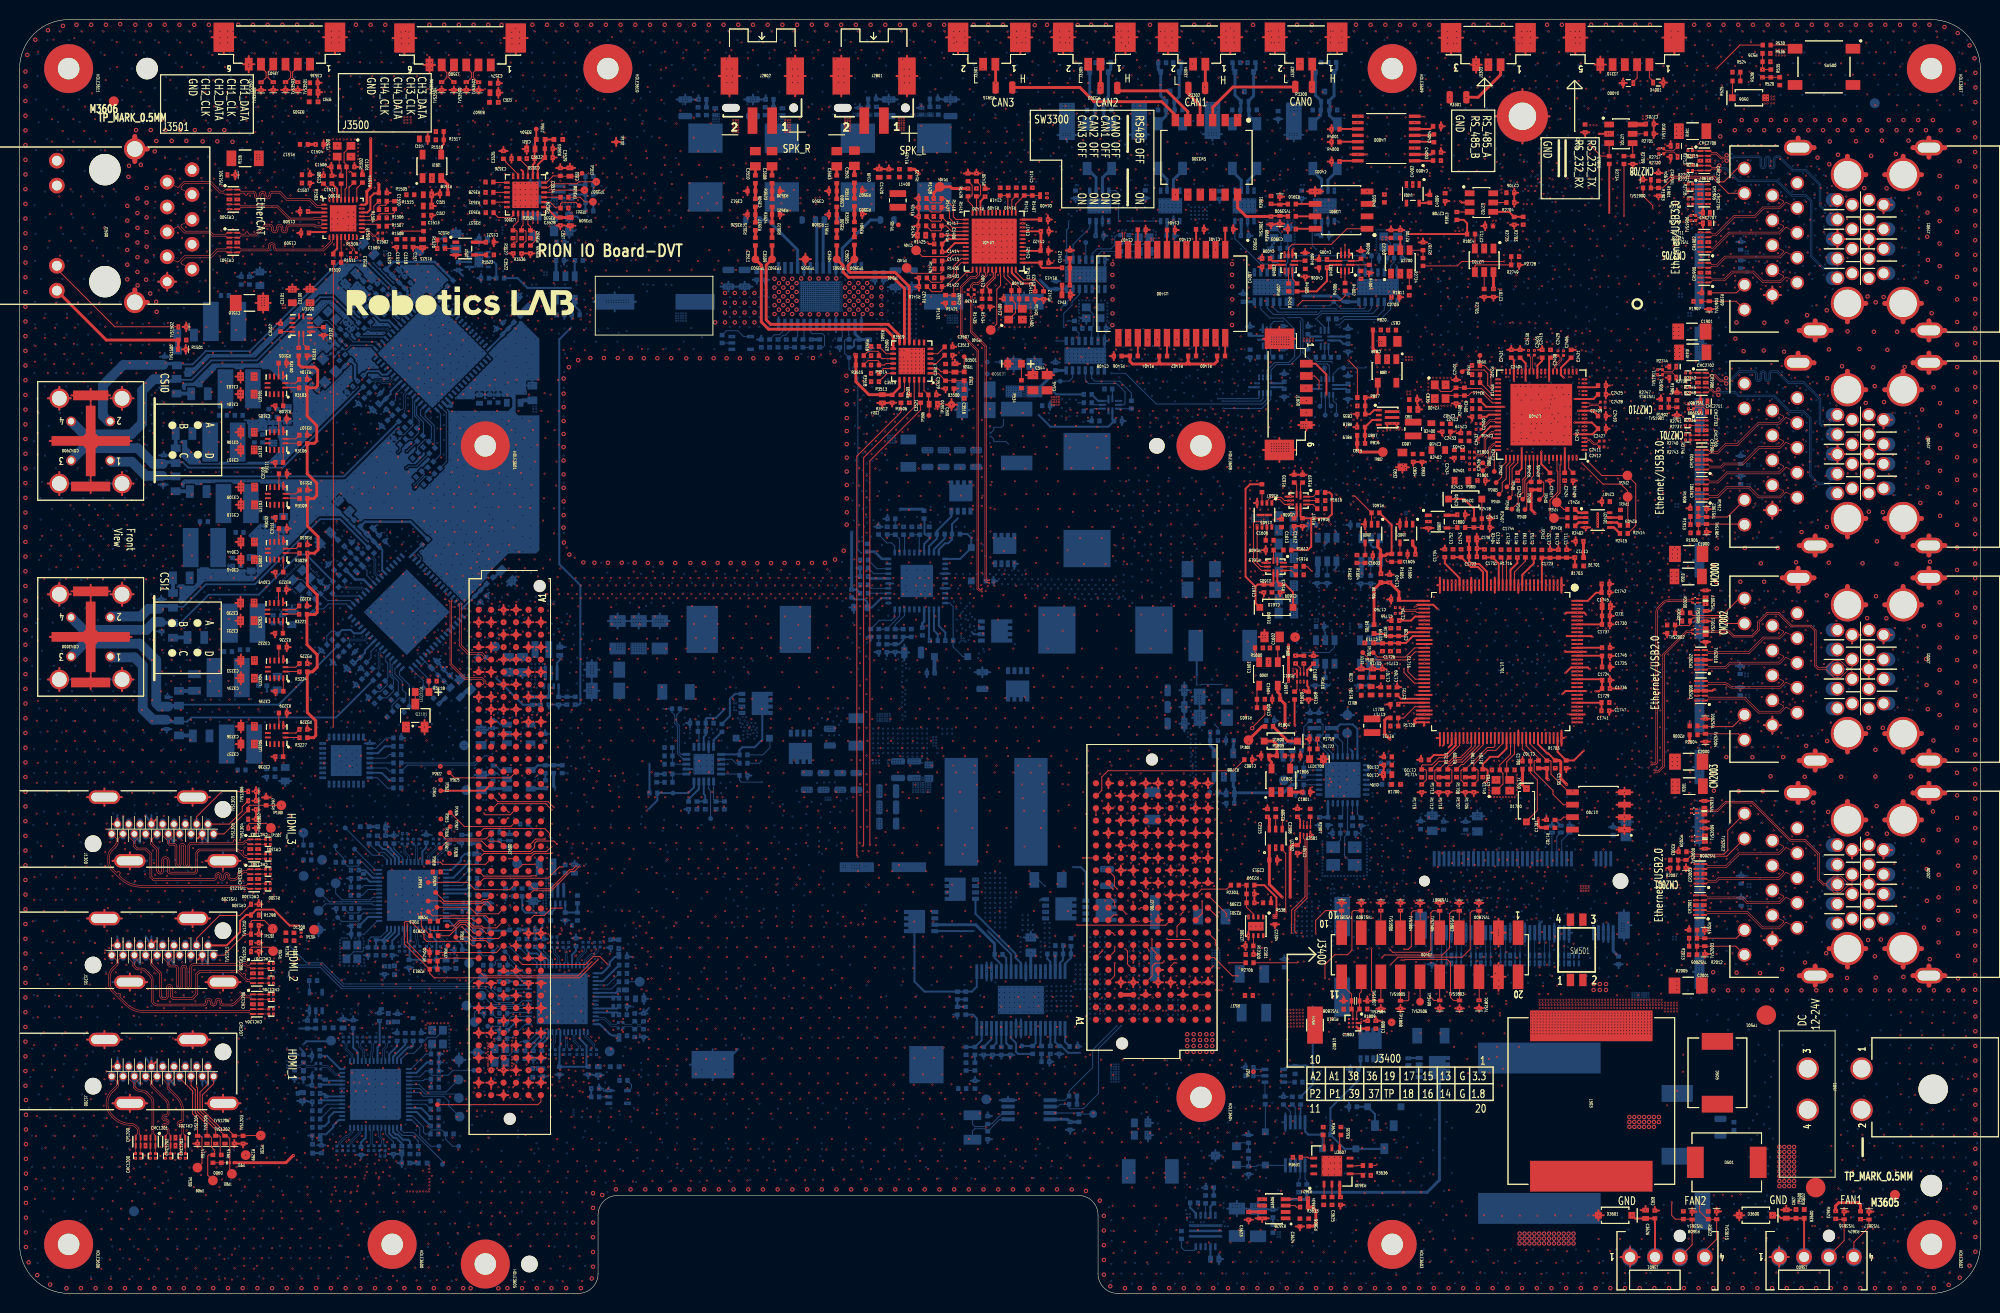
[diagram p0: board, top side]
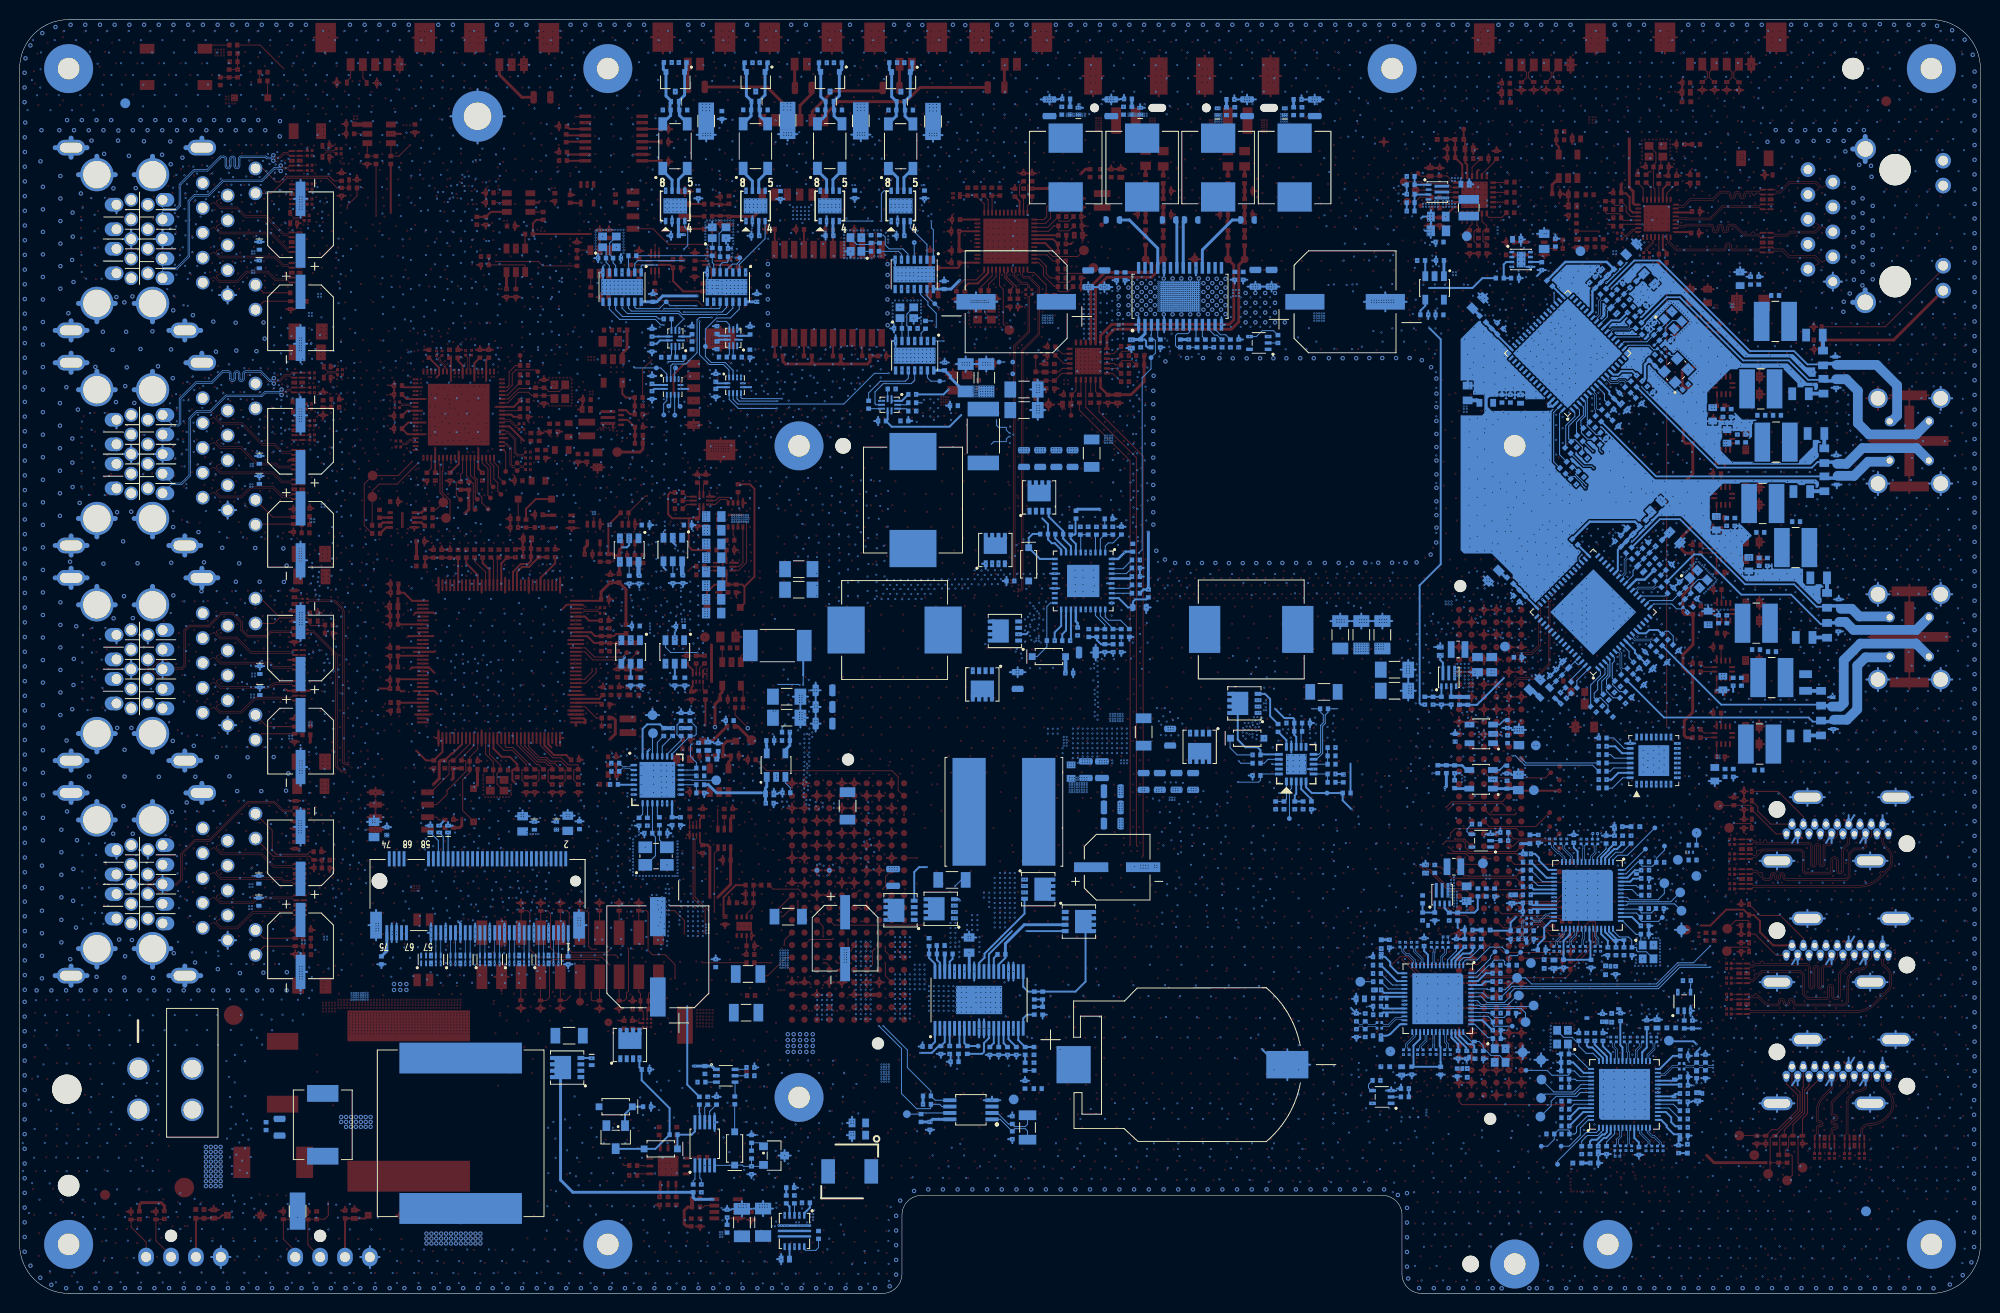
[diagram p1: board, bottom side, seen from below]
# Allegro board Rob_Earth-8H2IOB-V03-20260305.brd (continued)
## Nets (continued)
GND: C501.2 C503.1 C504.1 C505.1 C507.1 C509.1 C510.2 C511.2 C512.2 C513.2 C514.2 C515.2 C516.2 C517.2 C518.1 C519.1 C520.1 C521.1 C522.1 C523.1 C524.2 C525.2 C526.2 C527.2 C528.2 C529.2 C530.2 C531.2 C532.2 C533.2 C534.2 C535.2 C536.2 C537.2 C538.2 C539.2 C540.2 C541.1 C542.1 C543.2 C544.2 C545.2 C546.2 C547.1 C548.2 C549.1 C550.1 C551.1 C608.2 C609.2 C610.2 C611.2 C612.2 C614.2 C616.2 C617.2 C618.2 C619.2 C620.2 C622.2 C623.2 C700.2 C702.2 C703.2 C704.2 C705.2 C706.2 C711.2 C712.2 C713.2 C801.2 C802.2 C803.2 C804.2 C805.1 C806.1 C808.2 C809.2 C810.2 C811.2 C813.2 C814.2 C820.2 C821.2 C822.2 C823.2 C824.2 C825.2 C826.2 C827.2 C828.2 C829.2 C830.2 C831.2 C832.2 C833.2 C834.2 C835.2 C836.2 C837.2 C838.2 C840.2 C902.2 C903.2 C905.2 C906.2 C907.2 C908.2 C909.2 C910.2 C911.2 C912.2 C913.2 C914.2 C915.2 C916.2 C917.2 C918.2 C919.2 C920.2 C921.2 C922.2 C923.2 C924.2 C925.2 C926.2 C927.2 C928.2 C1003.2 C1004.2 C1005.2 C1006.2 C1007.2 C1008.2 C1009.2 C1010.2 C1011.2 C1012.2 C1013.2 C1014.2 C1015.2 C1016.2 C1017.2 C1018.2 C1019.2 C1020.2 C1021.2 C1022.2 C1023.2 C1024.2 C1025.2 C1026.2 C1027.2 C1028.2 C1103.2 C1104.2 C1105.2 C1106.2 C1107.2 C1108.2 C1109.2 C1110.2 C1111.2 C1112.2 C1113.2 C1114.2 C1115.2 C1116.2 C1117.2 C1118.2 C1119.2 C1120.2 C1121.2 C1122.2 C1123.2 C1124.2 C1125.2 C1126.2 C1127.2 C1128.2 C1401.1 C1403.1 C1404.1 C1405.2 C1406.1 C1407.1 C1408.2 C1409.2 C1410.2 C1411.2 C1412.2 C1413.2 C1414.1 C1415.1 C1416.1 C1417.1 C1418.1 C1419.2 C1420.1 C1421.1 C1422.1 C1423.1 C1500.2 C1501.2 C1504.2 C1506.2 C1507.2 C1508.2 C1509.2 C1510.2 C1511.2 C1512.2 C1513.2 C1514.2 C1515.2 C1516.1 C1517.2 C1518.2 C1519.2 C1520.2 C1521.1 C1600.2 C1601.2 C1602.2 C1603.1 C1604.2 C1605.1 C1606.2 C1607.1 C1608.1 C1609.2 C1610.2 C1611.1 C1612.2 C1613.2 C1700.2 C1701.2 C1702.2 C1703.2 C1704.2 C1705.2 C1706.2 C1707.2 C1708.2 C1709.2 C1710.2 C1711.2 C1712.2 C1713.2 C1714.2 C1715.2 C1716.2 C1717.2 C1718.2 C1719.2 C1720.2 C1721.2 C1722.2 C1723.2 C1724.2 C1725.2 C1726.2 C1727.2 C1728.2 C1729.2 C1730.2 C1731.2 C1732.2 C1733.2 C1734.2 C1735.2 C1736.2 C1737.2 C1738.2 C1739.2 C1740.2 C1741.2 C1742.2 C1743.2 C1744.2 C1745.2 C1746.2 C1747.2 C1748.2 C1749.2 C1750.2 C1751.2 C1752.2 C1753.2 C1800.2 C1801.2 C1802.2 C1803.2 C1808.2 C1900.1 C1901.1 C2000.1 C2001.1 C2300.1 C2301.1 C2302.1 C2303.1 C2304.2 C2305.2 C2306.1 C2307.1 C2308.1 C2309.2 C2313.1 C2314.1 C2315.1 C2399.1 C2401.2 C2402.2 C2407.2 C2413.2 C2414.1 C2415.2 C2416.2 C2417.2 C2418.2 C2419.2 C2420.1 C2421.2 C2422.2 C2423.2 C2424.2 C2425.2 C2426.1 C2427.2 C2428.2 C2429.2 C2430.2 C2431.2 C2432.2 C2433.2 C2434.2 C2500.1 C2501.1 C2502.2 C2503.1 C2505.2 C2506.2 C2507.2 C2508.2 C2509.1 C2511.2 C2512.2 C2513.1 C2515.2 C2516.2 C2517.2 C2518.2 C2519.1 C2521.2 C2522.2 C2696.2 C2697.2 C2698.2 C2699.2 C2700.1 C2701.1 C2703.2 C2705.2 C2706.1 C2707.1 C2708.2 C2711.2 C2800.2 C2801.2 C2802.2 C2803.2 C2804.2 C2805.2 C2806.1 C2807.2 C2808.2 C2809.2 C2810.2 C2812.2 C2813.2 C2814.2 C2815.2 C2818.1 C2819.1 C2821.2 C2822.2 C2823.2 C2824.2 C2825.2 C2826.2 C2827.2 C2828.2 C2829.1 C2830.1 C2831.1 C2838.2 C2900.2 C2901.2 C2902.2 C2903.2 C2904.2 C2905.2 C2906.2 C2907.2 C2910.2 C2911.2 C2912.2 C2913.2 C2914.2 C2915.2 C2916.2 C2917.2 C2918.2 C2919.2 C2920.2 C2921.2 C2922.2 C2923.2 C2924.2 C2927.2 C2928.2 C2929.2 C2932.2 C2933.2 C2934.2 C2935.2 C2936.2 C2939.2 C2940.2 C2941.2 C2942.2 C3000.2 C3001.2 C3002.2 C3003.2 C3004.2 C3005.2 C3006.2 C3007.2 C3010.2 C3011.2 C3012.2 C3013.2 C3014.2 C3015.2 C3016.2 C3017.2 C3018.2 C3019.2 C3020.2 C3021.2 C3024.2 C3025.2 C3026.2 C3027.2 C3028.2 C3029.2 C3032.2 C3033.2 C3034.2 C3035.2 C3036.2 C3039.2 C3040.2 C3044.2 C3045.2 C3049.2 C3100.2 C3101.2 C3102.2 C3103.2 C3104.2 C3105.2 C3106.2 C3107.2 C3108.2 C3109.2 C3110.2 C3111.2 C3112.2 C3113.2 C3200.2 C3201.2 C3202.2 C3203.2 C3204.2 C3205.1 C3206.2 C3207.2 C3208.2 C3209.2 C3221.2 C3229.2 C3230.2 C3231.2 C3232.2 C3233.2 C3234.2 C3235.2 C3236.2 C3237.2 C3238.2 C3400.1 C3401.1 C3406.1 C3407.1 C3408.1 C3413.1 C3414.1 C3415.1 C3418.1 C3419.1 C3420.1 C3423.1 C3424.1 C3425.2 C3426.2 C3427.2 C3428.2 C3429.2 C3430.2 C3431.1 C3432.2 C3433.2 C3434.1 C3435.2 C3436.2 C3437.1 C3438.2 C3439.2 C3498.2 C3499.2 C3500.1 C3505.2 C3506.1 C3507.2 C3512.2 C3513.2 C3514.2 C3515.1 C3516.2 C3517.1 C3518.2 C3519.1 C3520.2 C3521.1 C3522.2 C3523.2 C3524.1 C3525.2 C3526.2 C3527.2 C3528.1 C3529.2 C3530.1 C3531.2 C3532.1 C3533.2 C3534.1 C3535.2 C3536.1 C3623.2 C3624.2 C3625.2 C3626.1 C3627.2 C3628.2 C3903.2 C4001.2 C4002.1 C4004.1 C4005.2 C4006.2 C4007.2 C4008.2 C4009.2 CN2300.3 CN2300.9 CN2300.15 CN2300.21 CN2300.27 CN2300.33 CN2300.39 CN2300.45 CN2300.51 CN2300.57 CN2300.71 CN2300.73 CN2300.G1 CN2300.G2 CON2900.5 CON2900.6 CON2900.7 CON2900.8 CON2900.G1 CON2900.G2 CON2900.G3(\G3\) CON3000.5 CON3000.6 CON3000.7 CON3000.8 CON3000.G1 CON3000.G2 CON3000.G3(\G3\) CR1200.3 CR1200.8 CR1201.3 CR1201.8 CR1207.3 CR1207.8 CR1208.3 CR1208.8 CR1300.3 CR1300.8 CR1301.3 CR1301.8 CR1500.3 CR1500.8 CR1501.3 CR1501.8 CR1900.3 CR1900.8 CR1901.3 CR1901.8 CR1902.3 CR1902.8 CR1903.3 CR1903.8 CR1904.3 CR1904.8 CR1905.3 CR1905.8 CR1906.3 CR1906.8 CR1907.3 CR1907.8 CR2000.3 CR2000.8 CR2001.3 CR2001.8 CR2002.3 CR2002.8 CR2003.3 CR2003.8 CR2300.3 CR2300.8 CR2304.3 CR2304.8 CR2305.3 CR2305.8 CR2307.3 CR2307.8 CR2308.3 CR2308.8 CT501.2 CT700.2 CT701.2 CT1900.2 CT1901.2 CT1902.2 CT1903.2 CT2500.2 CT2501.2 CT2502.2 CT2503.2 CT2700.2 CT2701.2 D2800.1 D2801.1 D2802.1 D2803.1 D2900.2 D2901.2 D2902.2 D2903.2 D3000.2 D3001.2 D3002.2 D3003.2 D3600.1 D3601.1 D4000.2 D4001.2 HOLE3600.1(\TP\) HOLE3601.1(\TP\) HOLE3602.1(\TP\) HOLE3603.1(\TP\) HOLE3604.1(\TP\) HOLE3605.1(\TP\) HOLE3606.1(\TP\) HOLE3607.1(\TP\) HOLE3608.1(\TP\) HOLE3609.1(\TP\) HOLE3610.1(\TP\) HOLE3611.1(\TP\) J1200.2 J1200.5 J1200.8 J1200.11 J1200.17 J1200.G1 J1200.G2 J1200.G3 J1200.G4(\G4\) J1201.2 J1201.5 J1201.8 J1201.11 J1201.17 J1201.G1 J1201.G2 J1201.G3 J1201.G4(\G4\) J1300.2 J1300.5 J1300.8 J1300.11 J1300.17 J1300.G1 J1300.G2 J1300.G3 J1300.G4(\G4\) J1500.10 J1600.6 J1600.G1 J1600.G2(\G2\) J1900.10 J1900.U4 J1900.U7 J1900.U13 J1900.U16 J1901.10 J1901.U4 J1901.U7 J1901.U13 J1901.U16 J2000.10 J2000.U4 J2000.U7 J2000.U13 J2000.U16 J2001.10 J2001.U4 J2001.U7 J2001.U13 J2001.U16 J2600.A2 J2600.A4 J2600.A6 J2600.A8 J2600.A10 J2600.A27 J2600.A29 J2600.A31 J2600.A33 J2600.A35 J2600.A37 J2600.A39 J2600.B2 J2600.B4 J2600.B6 J2600.B8 J2600.B10 J2600.B27 J2600.B29 J2600.B31 J2600.B33 J2600.B35 J2600.B37 J2600.B39 J2600.C1 J2600.C3 J2600.C5 J2600.C7 J2600.C9 J2600.C11 J2600.C28 J2600.C30 J2600.C32 J2600.C34 J2600.C36 J2600.C38 J2600.D1 J2600.D3 J2600.D5 J2600.D7 J2600.D9 J2600.D11 J2600.D30 J2600.D32 J2600.D34 J2600.D36 J2600.D38 J2600.D40 J2600.E2 J2600.E4 J2600.E6 J2600.E8 J2600.E9 J2600.E10 J2600.E31 J2600.E33 J2600.E35 J2600.E37 J2600.E39 J2600.F2 J2600.F4 J2600.F6 J2600.F8 J2600.F31 J2600.F33 J2600.F35 J2600.F37 J2600.F39 J2700.B14 J2700.B16 J2700.B18 J2700.B20 J2700.C4 J2700.C13 J2700.C15 J2700.C17 J2700.C19 J2700.D4 J2700.D13 J2700.D15 J2700.D17 J2700.D19 J2700.E3 J2700.E12 J2700.E14 J2700.E16 J2700.E18 J2700.E20 J2700.F4 J2700.F5 J2700.F9 J2700.F12 J2700.F14 J2700.F16 J2700.F18 J2700.F20 J2700.G4 J2700.G11 J2700.G13 J2700.G15 J2700.G17 J2700.G19 J2700.H3 J2700.H11 J2700.H13 J2700.H15 J2700.H17 J2700.H19 J2700.I4 J2700.I12 J2700.I14 J2700.I16 J2700.I18 J2700.I20 J2700.J4 J2700.J12 J2700.J14 J2700.J16 J2700.J18 J2700.J20 J2800.2(-) J2801.G1 J2801.G2(\G2\) J2802.G1 J2802.G2(\G2\) J3301.G1 J3301.G2(\G2\) J3302.G1 J3302.G2(\G2\) J3303.3 J3303.G1 J3303.G2(\G2\) J3304.G1 J3304.G2(\G2\) J3305.G1 J3305.G2(\G2\) J3310.5 J3310.G1 J3310.G2(\G2\) J3400.2 J3400.19 J3500.6 J3500.G1 J3500.G2(\G2\) J3501.6 J3501.G1 J3501.G2(\G2\) J3600.1 J3601.1 LED500.2(\C\) LED1700.2(\C\) NUT2301.1 Q502.1 Q502.2 Q502.3(\S3\) Q503.1 Q503.2 Q503.3(\S3\) Q601.1 Q601.2 Q601.3(\S3\) Q701.1 Q701.2 Q701.3(\S3\) Q703.1 Q703.2 Q703.3(\S3\) Q3101.2(\SOURCE\) R507.1 R510.1 R513.2 R516.2 R530.2 R531.2 R536.2 R543.2 R544.2 R600.2 R608.2 R610.2 R611.2 R612.2 R613.2 R704.2 R709.2 R710.2 R711.2 R712.2 R714.2 R801.2 R802.2 R804.2 R808.2 R810.2 R811.2 R815.2 R818.2 R819.2 R820.2 R911.1 R922.2 R926.2 R927.1 R931.1 R934.1 R1018.2 R1021.2 R1022.1 R1027.1 R1030.1 R1032.1 R1120.2 R1123.2 R1124.1 R1129.1 R1132.1 R1134.1 R1297.2 R1298.2 R1299.2 R1401.2 R1424.1 R1425.1 R1426.1 R1427.1 R1428.1 R1429.1 R1430.2 R1431.2 R1432.2 R1434.2 R1435.2 R1503.1 R1516.1 R1518.2 R1519.1 R1600.2 R1615.2 R1619.2 R1620.2 R1705.2 R1707.2 R1708.2 R1710.2 R1712.2 R1713.2 R1715.2 R1716.2 R1717.2 R1718.2 R1721.2 R1722.1 R1806.2 R1900.1 R1901.1 R1904.1 R1905.1 R1909.1 R1910.2 R1911.2 R1913.1 R2000.1 R2001.1 R2007.1 R2009.1 R2010.2 R2011.2 R2015.1 R2300.1 R2301.1 R2308.1 R2407.2 R2408.2 R2409.2 R2411.2 R2419.2 R2501.2 R2502.2 R2503.2 R2504.2 R2507.2 R2509.2 R2510.2 R2518.2 R2519.2 R2700.2 R2701.2 R2704.2 R2705.2 R2707.2 R2708.1 R2709.2 R2725.2 R2749.2 R2902.1 R2905.1 R2908.1 R2912.2 R2914.1 R2921.1 R2922.1 R3002.1 R3006.1 R3007.1 R3011.1 R3016.1 R3017.1 R3018.2 R3023.1 R3030.1 R3032.1 R3101.1 R3102.1 R3104.1 R3105.1 R3107.1 R3108.1 R3110.1 R3111.1 R3116.1 R3202.2 R3203.2 R3205.1 R3222.1 R3223.1 R3225.1 R3226.1 R3228.1 R3229.1 R3403.2 R3411.2 R3414.2 R3415.1 R3416.2 R3500.1 R3508.2 R3517.1 R3518.1 R3519.1 R3526.2 R3535.1 R3536.1 R3903.2 R4000.1 R4001.1 R4004.2 R4005.2 R4008.2 R4009.2 RT2300.2 RT2400.2 TP907.1(\TP\) TP1006.1(\TP\) TP1107.1(\TP\) TP2500.1(\TP\) TP2702.1(\TP\) TP3505.1(\TP\) TP3510.1(\TP\) TVS1202.1 TVS1203.1 TVS1204.1 TVS1205.1 TVS1206.1 TVS1209.1 TVS1210.1 TVS1211.1 TVS1212.1 TVS1213.1 TVS1302.1 TVS1303.1 TVS1304.1 TVS1305.1 TVS1306.1 TVS1500.1 TVS1501.1 TVS1502.1 TVS1800.1 TVS1801.1 TVS1802.1 TVS1803.1 TVS1804.1 TVS1805.1 TVS1806.1 TVS1807.2 TVS1808.2 TVS1809.1 TVS1810.1 TVS1900.1 TVS1901.1 TVS1902.1 TVS1903.1 TVS1904.1 TVS1906.2 TVS1907.2 TVS1908.2 TVS1909.2 TVS1910.2 TVS1911.2 TVS1912.2 TVS1913.2 TVS1914.1 TVS1915.1 TVS1916.1 TVS1917.1 TVS2000.1 TVS2001.1 TVS2002.1 TVS2003.1 TVS2004.1 TVS2005.1 TVS2006.2 TVS2007.2 TVS2008.2 TVS2009.2 TVS2010.2 TVS2011.2 TVS2012.2 TVS2013.2 TVS2301.2 TVS2302.2 TVS2303.2 TVS2306.1 TVS2309.1 TVS2500.1 TVS2501.1 TVS2502.1 TVS2503.1 TVS2504.1 TVS2505.1 TVS2506.1 TVS2507.1 TVS3500.1 TVS3501.1 TVS3502.1 TVS3503.1 TVS3504.1 TVS3505.1 TVS3506.1 TVS3507.1 TVS3614.1 TVS3615.1 TVS3616.1 TVS3617.1 TVS3900.1 TVS3901.1 U500.14 U500.17 U500.35 U500.41 U501.6 U504.2 U506.3 U600.7 U600.14 U600.21 U700.10 U700.11(\SYNC\) U700.17 U700.22 U700.23 U700.30 U700.39 U800.2 U800.6 U802.5 U804.2 U805.2 U806.5 U807.5 U808.2 U900.57 U902.3 U1000.57 U1001.3 U1100.57 U1101.3 U1401.49 U1500.33 U1501.2 U1502.3 U1600.2 U1601.3 U1602.3 U1603.4 U1603.9 U1604.4 U1605.3 U1606.3 U1700.1 U1700.2 U1700.3 U1700.4 U1701.1 U1701.12 U1701.18 U1701.24 U1701.32 U1701.34 U1701.40 U1701.43 U1701.44 U1701.57 U1701.61 U1701.62 U1701.68 U1701.85 U1701.89 U1701.96 U1701.99 U1701.105 U1701.111 U1701.115 U1701.119 U1701.125 U1800.3 U1801.2 U1802.A2 U2300.5 U2300.9 U2301.4 U2302.2 U2400.77 U2401.4 U2401.9 U2500.2 U2501.2 U2502.2 U2503.29 U2504.2 U2505.2 U2700.2 U2701.2 U2702.2 U2703.2 U2800.1 U2800.5 U2800.14 U2800.19 U2800.24 U2800.29 U2803.4 U2805.3 U2900.65 U3000.65 U3002.3 U3100.3 U3101.3 U3102.3 U3103.3 U3104.25 U3104.33 U3200.5 U3201.5 U3201.9 U3202.2 U3203.3 U3204.3 U3205.3 U3400.2 U3400.9(\VSS_EP\) U3402.2 U3402.9(\VSS_EP\) U3404.2 U3404.9(\VSS_EP\) U3405.2 U3405.9(\VSS_EP\) U3406.3 U3407.7 U3407.15 U3408.3 U3409.7 U3409.15 U3410.3 U3411.7 U3411.15 U3412.7 U3413.7 U3413.15 U3414.7 U3500.4 U3500.25 U3501.4 U3501.25 U3606.8 U3607.13 U3901.5 U4000.15 U4001.3 U4002.3 U4003.3 Y900.2 Y900.4(\GND2\) Y1000.2 Y1000.4(\GND2\) Y1100.2 Y1100.4(\GND2\) Y1400.2 Y1400.4(\GND2\) Y1500.2 Y1500.4(\GND2\) Y1700.2 Y1700.4(\GND2\) Y2300.2 Y2300.4(\GND2\) Y2400.2 Y2400.4(\GND2\) Y2500.2 Y2500.4(\GND2\) Y2900.2 Y2900.4(\GND2\) Y2901.2 Y3000.2 Y3000.4(\GND2\) Y3400.2 Y3400.4(\GND2\) Y3401.2 Y3401.4(\GND2\) Y3402.2 Y3402.4(\GND2\)
GND_EARTH: C1900.2 C1901.2 C2000.2 C2001.2 J1900.G1 J1900.G2 J1900.G3 J1900.G4 J1900.G5 J1900.G6 J1900.G7 J1900.G8 J1901.G1 J1901.G2 J1901.G3 J1901.G4 J1901.G5 J1901.G6 J1901.G7 J1901.G8 J2000.G1 J2000.G2 J2000.G3 J2000.G4 J2000.G5 J2000.G6 J2000.G7 J2000.G8 J2001.G1 J2001.G2 J2001.G3 J2001.G4 J2001.G5 J2001.G6 J2001.G7 J2001.G8 R1910.1 R1911.1 R2010.1 R2011.1
GND_EARTH1: C3404.2 C3405.2 C3406.2 C3411.2 C3412.2 C3413.2 C3416.2 C3417.2 C3418.2 C3421.2 C3422.2 C3423.2 D3400.3 D3401.3 D3402.3 D3403.3 R3403.1
GND_EARTH2: C1516.2 J1500.G1 J1500.G2 R1516.2
GND_TOP: J2700.A2 J2700.B2 J2700.C2 J2700.D2 J2700.E2 J2700.F2 J2700.G2 J2700.H2 J2700.I2 J2700.J2 R514.2
VBUSDET: R2410.2 R2411.1 U2400.43
VCC_+6V7_GMSL_1: C2900.1 C2901.1 C2902.1 C3101.1 L2900.2 R2901.1 U3100.8 U3100.9 U3100.10
VCC_+6V7_GMSL_2: C2919.1 C2920.1 C2921.1 C3104.1 L2902.2 R2904.1 U3101.8 U3101.9 U3101.10
VCC_+6V7_GMSL_3: C2927.1 C2928.1 C2929.1 C3107.1 L2904.2 R2907.1 U3102.8 U3102.9 U3102.10
VCC_+6V7_GMSL_4: C2932.1 C2933.1 C2936.1 C3110.1 L2906.2 R2910.1 U3103.8 U3103.9 U3103.10
VCC_+6V7_GMSL_5: C3000.1 C3001.1 C3002.1 C3045.1 L3000.2 R3001.1 U3002.8 U3002.9 U3002.10
VCC_+6V7_GMSL_6: C3013.1 C3014.1 C3021.1 C3231.1 L3002.2 R3004.1 U3203.8 U3203.9 U3203.10
VCC_+6V7_GMSL_7: C3027.1 C3028.1 C3029.1 C3234.1 L3004.2 R3010.1 U3204.8 U3204.9 U3204.10
VCC_+6V7_GMSL_8: C3034.1 C3035.1 C3036.1 C3237.1 L3006.2 R3020.1 U3205.8 U3205.9 U3205.10
VCC_CAM_GMSL1_EN: R3101.2 U3100.2 U3104.1
VCC_CAM_GMSL1_FLAG: R3100.1 U3100.1 U3104.9
VCC_CAM_GMSL2_EN: R3104.2 U3101.2 U3104.2
VCC_CAM_GMSL2_FLAG: R3103.1 U3101.1 U3104.10
VCC_CAM_GMSL3_EN: R3107.2 U3102.2 U3104.3
VCC_CAM_GMSL3_FLAG: R3106.1 U3102.1 U3104.11
VCC_CAM_GMSL4_EN: R3110.2 U3103.2 U3104.4
VCC_CAM_GMSL4_FLAG: R3109.1 U3103.1 U3104.12
VCC_CAM_GMSL5_EN: R3030.2 U3002.2 U3104.5
VCC_CAM_GMSL5_FLAG: R3029.1 U3002.1 U3104.13
VCC_CAM_GMSL6_EN: R3222.2 U3104.6 U3203.2
VCC_CAM_GMSL6_FLAG: R3221.1 U3104.14 U3203.1
VCC_CAM_GMSL7_EN: R3225.2 U3104.7 U3204.2
VCC_CAM_GMSL7_FLAG: R3224.1 U3104.15 U3204.1
VCC_CAM_GMSL8_EN: R3228.2 U3104.8 U3205.2
VCC_CAM_GMSL8_FLAG: R3227.1 U3104.16 U3205.1
VDD10: C1506.1 C1507.1 C1508.1 C1509.1 C1510.1 C1511.1 R1512.2 U1500.3 U1500.8 U1500.22 U1500.30
VDD33: C1517.1 C1518.1 C1519.1 C1520.1 R1509.1 R1520.2 U1500.11 U1500.32
VDD33_USB: B2500.1 C2506.1 C2512.1 R2512.1 R2513.1 R2514.1 R2515.1 R2516.1 R2517.1 U2503.21 U2503.28
VDDREG_VDD33: C1512.1 C1513.1 C1515.1 R1501.2 R1515.2 R1520.1 U1500.23(\VDDREG_DVDD33\) U1501.1(\VOUT\)
VIN+: D501.2 J501.3 J501.4 L500.1 TP500.1(\TP\)
VIN-: D505.1 J501.1 J501.2(\COM#2\) L503.1 TP501.1(\TP\)
VIN_HOLD_A: R501.2 R2706.2
VIN_HOLD_A_1P8: J2600.C21 R2706.1
VIN_HOLD_B: R500.1 TP502.1(\TP\) U504.5
VIN_HV: C500.1 C502.1 D500.2 D506.1 L500.2 Q505.5 Q505.6 Q505.7 Q505.8 R519.1 R520.1 R521.1 R522.1 SW500.3 SW500.4 SW501.1 SW501.2
VIN_P5V: C533.1 C534.1 C535.1 C536.1 Q501.5 Q501.6 Q501.7 Q501.8 R518.1
VIN_SUB_9TO30V: F500.2 R517.1 R518.2 R609.1 R700.1
3P3_PER_COMP1: C519.2 R512.1 U500.29
3P3_PER_COMP2: C549.2 R540.1 U500.2
3P3_PER_FB2: R508.2 U500.3
3P3_PER_SS1: C520.2 U500.30
3P3_PER_SS2: C550.2 U500.1
5P0_FB1: R507.2 R542.2 U500.28
5P0_PWM1_L: Q502.4 U500.18 U500.19
7P0_POC_BST: C613.2 D600.2(\C\) U600.18
7P0_POC_COMP: C623.1 R614.1 U600.6
7P0_POC_CS: C621.1 JP600.2 U600.10
7P0_POC_ENBK: R602.2 R608.1 U600.12
7P0_POC_FB: C615.1 R607.2 R612.1 U600.8
7P0_POC_FOSC: R613.1 U600.4
7P0_POC_FSYNC: R604.2 R611.1 U600.3
7P0_POC_OUT: C621.2 JP601.2 U600.9
7P0_POC_SPS: R603.2 R610.1 U600.1
8211_1_AVCC_+1V: C1421.2 C1422.2 C1423.2 R1433.2 U1401.4 U1401.9 U1401.47
8211_1_AVCC_+3V3: C1416.2 C1417.2 R1413.2 U1401.1 U1401.12
8211_1_DVCC_+1V: C1418.2 R1423.2 U1401.22
8211_1_DVDDRG: C1405.1 C1406.2 R1403.1 R1409.1 R1414.2 R1415.2 R1417.1 R1418.1 R1419.1 R1420.1 TP1404.1(\TP\) U1401.29
8211_1_LED0_PHYAD0: R1416.1 R1426.2 U1401.35
8211_1_LED1_CFGL0: R1422.2 R1432.1 U1401.36
8211_1_LED2_CFGL1: R1421.2 R1431.1 U1401.37
8211_1_REGOUT: L1400.1 TP1403.1(\TP\) U1401.32
8211_1_RST_N: C1410.1 Q1400.3 R1407.2 U1401.13
8211_1_RXC_PHYAD1: R1415.1 R1425.2 U1401.28
8211_1_RXCTL_PHYAD2: R1414.1 R1424.2 U1401.27
8211_1_RXD0_RXDLY: R1417.2 R1427.2 U1401.26
8211_1_RXD1_CFG_MODE0: R1418.2 R1428.2 U1401.25
8211_1_RXD2_CFG_MODE1: R1419.2 R1429.2 U1401.24
8211_1_RXD3_CFG_MODE2: R1420.2 R1430.1 U1401.23
8211_1_SGMII_CLK_M: R1434.1 R1436.1 U1401.43
8211_1_SGMII_CLK_P: R1435.1 R1436.2 U1401.42
8211_DVCC_+3V3: C1413.1 C1414.2 C1415.2 R1407.1 R1412.2 R1416.2 R1421.1 R1422.1 U1401.30 U1401.31
8211_TRXN0: U1400.3 U1401.3
8211_TRXN1: U1400.6 U1401.6
8211_TRXN2: U1400.9 U1401.8
8211_TRXN3: U1400.12(\TD4-\) U1401.11
8211_TRXP0: U1400.2 U1401.2
8211_TRXP1: U1400.5 U1401.5
8211_TRXP2: U1400.8 U1401.7
8211_TRXP3: U1400.11 U1401.10
8211_XTAL_IN: C1409.1 R1408.2 U1401.45 Y1400.1
8211_XTAL_OUT: C1411.1 R1408.1 U1401.46(\XTAL_OUT/EXT_CLK\) Y1400.3
AMP_FAULT_1P8: J2700.B5 R2818.1 TP2800.1(\TP\) U2800.3
AMP_I2C_SCL_1P8: J2600.B18 R2809.1 R2817.2 R3514.1
AMP_I2C_SDA_1P8: J2600.B19 R2806.1 R2816.2 R3513.1
AMP_I2S_LPCLK_1P8: J2600.F26 R2810.1
AMP_I2S_SCLK_1P8: J2600.F27 R2811.1
AMP_I2S_SDIN_1P8: J2600.F29 R2812.1 R2813.1
AMP_I2S_SDOUT_1P8: J2600.F28 R2800.1 R2812.2 U2800.9
AMP_PA_PDN: J2600.C22 R2820.1 U2805.2
CAN0_H: J3302.1 R3300.2 R3401.2
CAN0_H_R: R3300.1 SW3300.3
CAN0_L: J3302.2 R3402.2 SW3300.10
CAN1_H: J3304.1 R3302.2 R3404.2
CAN1_H_R: R3302.1 SW3300.4
CAN1_L: J3304.2 R3405.2 SW3300.9
CAN2_H: J3305.1 R3303.2 R3406.2
CAN2_H_R: R3303.1 SW3300.5
CAN2_L: J3305.2 R3407.2 SW3300.8
CAN3_H: J3301.1 R3408.2 R3915.2
CAN3_H_R: R3915.1 SW3300.6
CAN3_L: J3301.2 R3409.2 SW3300.7(\B6\)
CAN_INT0_1P8: J2600.E22 TP2619.1(\TP\) U3412.3
CAN_INT1_1P8: J2600.E16 TP2613.1(\TP\) U3412.4
CAN_INT2_1P8: J2600.E23 TP2620.1(\TP\) U3412.5
CAN_INT3_1P8: J2600.E17 TP2614.1(\TP\) U3412.6
CAN_INT_0: TP3403.1(\TP\) U3407.4 U3412.12
CAN_INT_1: TP3402.1(\TP\) U3409.4 U3412.11
CAN_INT_2: TP3401.1(\TP\) U3411.4 U3412.10
CAN_INT_3: TP3400.1(\TP\) U3412.9 U3413.4
CAN_MCLK1: R3412.1 R3498.1 U3409.6
CAN_MCLK2: R2302.1 R3496.1 U3413.6
CAN_MCLKO: R3412.2 U3407.3
CAN_SPI1_CLK: R3425.2 U3407.10 U3409.10
CAN_SPI1_CLK_1P8: J2700.D8 R3417.1
CAN_SPI1_CS0: TP3407.1(\TP\) U3407.13 U3414.12
CAN_SPI1_CS0_1P8: J2700.D9 U3414.3
CAN_SPI1_CS1: TP3406.1(\TP\) U3409.13 U3414.11
CAN_SPI1_CS1_1P8: J2600.B14 U3414.4
CAN_SPI1_MISO: U3407.12 U3409.12 U3410.5
CAN_SPI1_MISO_1P8: J2700.D6 R3421.1
CAN_SPI1_MOSI: U3406.4 U3407.11 U3409.11
CAN_SPI1_MOSI_1P8: J2700.D7 R3418.1
CAN_SPI2_CLK: R3426.2 U3411.10 U3413.10
CAN_SPI2_CLK_1P8: J2600.F30 R3419.1
CAN_SPI2_CS0: TP3405.1(\TP\) U3411.13 U3414.10
CAN_SPI2_CS0_1P8: J2700.B12 U3414.5
CAN_SPI2_CS1: TP3404.1(\TP\) U3413.13 U3414.9
CAN_SPI2_CS1_1P8: J2700.B13 U3414.6
CAN_SPI2_MISO: U3410.4 U3411.12 U3413.12
CAN_SPI2_MISO_1P8: J2600.B26 R3422.1
CAN_SPI2_MOSI: U3408.4 U3411.11 U3413.11
CAN_SPI2_MOSI_1P8: J2600.F25 R3420.1
CAN_STB_0: U3400.8 U3407.9
CAN_STB_1: U3402.8 U3409.9
CAN_STB_2: U3404.8 U3411.9
CAN_STB_3: U3405.8 U3413.9
CH334_XI: C2517.1 U2503.10 Y2500.1
CH334_XO: R2505.2 U2503.11(\XO\)
CHANNEL1_INM: J3501.3 R3528.2 TVS3503.2
CHANNEL1_INP: J3501.2 TVS3501.2 U3501.6
CHANNEL2_INM: J3501.5 R3531.2 TVS3507.2
CHANNEL2_INP: J3501.4 TVS3505.2 U3501.8
CHANNEL3_INM: J3500.3 R3533.2 TVS3502.2
CHANNEL3_INP: J3500.2 TVS3500.2 U3501.10
CHANNEL4_INM: J3500.5 R3537.2 TVS3506.2
CHANNEL4_INP: J3500.4 TVS3504.2 U3501.12
CHANNEL7_INM: C3504.2 TP3501.1(\TP\) U3500.11
CHANNEL7_INP: C3502.2 TP3500.1(\TP\) U3500.10
CHANNEL8_INM: C3511.2 TP3503.1(\TP\) U3500.13
CHANNEL8_INP: C3509.2 TP3502.1(\TP\) U3500.12
CLKREQ: R1509.2 R1510.2 U1500.12
CSI0_A0_CLK_M: J2600.D10 U2900.45
CSI0_A1_LN1_P: J2600.C6 U2900.40
CSI0_A2_LN2_M: J2600.D4 U2900.43
CSI0_B0_LN0_P: J2600.C8 U2900.36
CSI0_B1_LN1_M: J2600.D6 U2900.41
CSI0_B2_LN3_P: J2600.C2 U2900.46
CSI0_C0_LN0_M: J2600.D8 U2900.37
CSI0_C1_LN2_P: J2600.C4 U2900.42
CSI0_C2_LN3_M: J2600.D2 U2900.47
CSI0_NC_CLK_P: J2600.C10 U2900.44
CSI1_A0_CLK_M: J2600.B9 U3000.45
CSI1_A1_LN1_P: J2600.A5 U3000.40
CSI1_A2_LN2_M: J2600.B3 U3000.43
CSI1_B0_LN0_P: J2600.A7 U3000.36
CSI1_B1_LN1_M: J2600.B5 U3000.41
CSI1_B2_LN3_P: J2600.A1 U3000.46
CSI1_C0_LN0_M: J2600.B7 U3000.37
CSI1_C1_LN2_P: J2600.A3 U3000.42
CSI1_C2_LN3_M: J2600.B1 U3000.47
CSI1_NC_CLK_P: J2600.A9 U3000.44
DES0_CAP_VDD_1P0: C2916.1 C2917.1 C2918.1 U2900.9 U2900.23
DES0_CCI_SCL_1P8: J2700.A18 R2913.1 R2931.1
DES0_CCI_SDA_1P8: J2700.A17 R2911.1 R2918.1
DES0_CFG0_1P8: R2917.1 R2922.2 U2900.5
DES0_CFG1_1P8: R2916.1 R2921.2 U2900.12
DES0_ENABLE_1P8: J2700.A6 U2900.35
DES0_ERRB_1P8: J2600.D22 R2927.2
DES0_FRAME_SYNC_1P8: J2600.D23 R2928.2
DES0_I2CSEL_1P8: R2929.1 U2900.33
DES0_LOCK_1P8: J2600.D21 R2926.2
DES0_SIOA: C2908.2 CON2900.2 D2900.1 R2900.2
DES0_SIOA_M: C2909.1 U2900.25
DES0_SIOA_P: C2908.1 U2900.26
DES0_SIOB: C2925.2 CON2900.4 D2901.1 R2903.2
DES0_SIOB_M: C2926.1 U2900.22
DES0_SIOB_P: C2925.1 U2900.21
DES0_SIOC: C2930.2 CON2900.3 D2902.1 R2906.2
DES0_SIOC_M: C2931.1 U2900.10
DES0_SIOC_P: C2930.1 U2900.11
DES0_SIOD: C2937.2 CON2900.1 D2903.1 R2909.2
DES0_SIOD_M: C2938.1 U2900.7
DES0_SIOD_P: C2937.1 U2900.6
DES0_SPARE_GPIO_1P8: J2600.D24 R2930.2
DES0_VDDIO_1P8: B2901.1 C2910.1 C2911.1 C2934.1 C2935.1 C2942.1 R2916.2 R2917.2 R2918.2 R2923.2 R2925.2 R2929.2 R2931.2 R2932.1 U2900.27 Y2901.4(\VDD\)
DES0_X1: R2919.1 R2920.2 R2924.2 U2900.17
DES0_X2: C2940.1 R2915.1 U2900.18 Y2900.1
DES1_CAP_VDD_1P0: C3018.1 C3019.1 C3020.1 U3000.9 U3000.23
DES1_CFG0_1P8: R3013.1 R3016.2 U3000.5
DES1_CFG1_1P8: R3012.1 R3017.2 U3000.12
DES1_CLK_25MHZ_1P8: R2919.2 R3005.2 R3007.2 U3000.17
DES1_ENABLE_1P8: J2600.D20 U3000.35
DES1_ERRB_1P8: J2600.D17 R3027.2
DES1_FRAME_SYNC_1P8: J2600.D19 R3028.2
DES1_I2C_SCL_1P8: J2600.C40 R3021.2 R3031.1
DES1_I2C_SDA_1P8: J2600.C39 R3014.1 R3019.2
DES1_I2CSEL_1P8: R3008.1 U3000.33
DES1_LOCK_1P8: J2600.D16 R3026.2
DES1_SIOA: C3008.2 CON3000.2 D3000.1 R3000.2
DES1_SIOA_M: C3009.1 U3000.25
DES1_SIOA_P: C3008.1 U3000.26
DES1_SIOB: C3022.2 CON3000.4 D3001.1 R3003.2
DES1_SIOB_M: C3023.1 U3000.22
DES1_SIOB_P: C3022.1 U3000.21
DES1_SIOC: C3030.2 CON3000.3 D3002.1 R3009.2
DES1_SIOC_M: C3031.1 U3000.10
DES1_SIOC_P: C3030.1 U3000.11
DES1_SIOD: C3037.2 CON3000.1 D3003.1 R3022.2
DES1_SIOD_M: C3038.1 U3000.7
DES1_SIOD_P: C3037.1 U3000.6
DES1_SPARE_GPIO_1P8: J2600.D18 R3033.2
DES1_VDDIO_1P8: B3002.1 C3016.1 C3017.1 C3040.1 R3008.2 R3012.2 R3013.2 R3014.2 R3024.2 R3025.2 R3031.2 U3000.27
DES1_X2: C3032.1 R3015.1 U3000.18 Y3000.1
DES_EN_1P8: J2600.E15 R3200.1 R3204.1 TP2612.1(\TP\)
DISAUTOLOAD/GPO45: R1708.1 U1701.76
EDP1_AUX_M: C900.1 J2600.E32 R931.2 R933.1
EDP1_AUX_P: C901.1 J2600.F32 R932.1 R934.2
EDP1_HPD_1P8: J2600.C17 R925.2 U902.4(\Y\)
EDP1_HPD_3P3: R910.2 R911.2 U900.22
EDP1_LN0_M: J2600.E40 R904.1
EDP1_LN0_P: J2600.F40 R902.1
EDP1_LN1_M: J2600.E38 R909.1
EDP1_LN1_P: J2600.F38 R907.1
EDP1_LN2_M: J2600.E36 R916.1
EDP1_LN2_P: J2600.F36 R912.1
EDP1_LN3_M: J2600.E34 R921.1
EDP1_LN3_P: J2600.F34 R919.1
EDP2_AUX_M: C1000.1 J2600.A34 R1030.2 R1031.1
EDP2_AUX_P: C1001.1 J2600.B34 R1029.1 R1032.2
EDP2_HPD_1P8: J2600.C15 R1028.2 U1001.4(\Y\)
EDP2_HPD_3P3: R1026.2 R1027.2 U1000.22
EDP2_LN0_M: J2600.A38 R1003.1
EDP2_LN0_P: J2600.B38 R1002.1
EDP2_LN1_M: J2600.C37 R1009.1
EDP2_LN1_P: J2600.D37 R1007.1
EDP2_LN2_M: J2600.A36 R1012.1
EDP2_LN2_P: J2600.B36 R1010.1
EDP2_LN3_M: J2600.C35 R1017.1
EDP2_LN3_P: J2600.D35 R1015.1
EDP3_AUX_M: C1100.1 J2600.A28 R1132.2 R1133.1
EDP3_AUX_P: C1101.1 J2600.B28 R1131.1 R1134.2
EDP3_HPD_1P8: J2600.C16 R1130.2 U1101.4(\Y\)
EDP3_HPD_3P3: R1128.2 R1129.2 U1100.22
EDP3_LN0_M: J2600.A32 R1104.1
EDP3_LN0_P: J2600.B32 R1102.1
EDP3_LN1_M: J2600.C33 R1109.1
EDP3_LN1_P: J2600.D33 R1106.1
EDP3_LN2_M: J2600.A30 R1112.1
EDP3_LN2_P: J2600.B30 R1110.1
EDP3_LN3_M: J2600.C31 R1119.1
EDP3_LN3_P: J2600.D31 R1117.1
EDP_HDMI_PON: C814.1 R806.2 R896.2 U802.1
EDP_PWR_EN: J2700.D5 R806.1 R821.1
EN_PWRLIGHT/GPO42: R1713.1 U1701.73
EN_VREG_3P3: R533.2 R538.2 U500.40
EN_VREG_5P0: R539.1 U500.31
ENSWR: R1720.2 R1721.1 U1701.60
ETHCAT_WAKE_N: R1504.1 R1523.1 U1500.21 U1502.2
EXPANDER_INT_N_1P8: J2700.A14 R3114.1
EXT_ADC1: J2600.D27 J3400.9 TVS1809.2
EXT_ADC2: J2700.C10 J3400.10 TVS1810.2
EXT_PWM1: J3400.12 R1809.1 TVS1807.1 U1802.A1
EXT_PWM2: J3400.11 R1810.1 TVS1808.1 U1802.B1
EXTPWRON: TP2407.1(\TP\) U2400.63
FAN_ALERT_1P8_N: J2600.C24 R3631.2 U3607.10
FAN_I2C_CLK1_3V3: R3628.2 R3633.1 U3606.3
FAN_I2C_DAT1_3V3: R3627.2 R3634.1 U3606.4
FAN_PWM1: J3600.4 R3624.2 R3636.2 TVS3617.2
FAN_PWM2: J3601.4 R3622.2 R3635.2 TVS3615.2
FAN_PWR_SW: B3600.1 B3602.1 C3626.2 C3627.1 C3628.1 D3600.2(\C\) D3601.2(\C\) J3600.2 J3601.2
FAN_TACH1: J3600.3 R3623.2 TVS3616.2 U3607.6
FAN_TACH2: J3601.3 R3608.2 TVS3614.2 U3607.8
FPGA_DES0_ERRB_1P8: R2925.1 R2927.1 U2900.4
FPGA_DES0_FRAME_SYNC_1P8: R2928.1 U2900.3
FPGA_DES0_LOCK_1P8: R2923.1 R2926.1 U2900.2
FPGA_DES0_SPARE_GPIO_1P8: R2930.1 U2900.1
FPGA_DES1_ERRB_1P8: R3025.1 R3027.1 U3000.4
FPGA_DES1_FRAME_SYNC_1P8: R3028.1 U3000.3
FPGA_DES1_LOCK_1P8: R3024.1 R3026.1 U3000.2
FPGA_DES1_SPARE_GPIO_1P8: R3033.1 U3000.1
GPIO0: TP2402.1(\TP\) U2400.57
GPIO1: TP2403.1(\TP\) U2400.58
GPIO2: TP2404.1(\TP\) U2400.59
GPIO3: TP2405.1(\TP\) U2400.60
GPIO4: TP2406.1(\TP\) U2400.61
GPIO_107_1P8: J2600.C23 TP2629.1(\TP\)
HDMI1_5V_CONN: D900.2(-) J1200.18 R914.1 R915.1 TP901.1(\TP\) TVS1202.2
HDMI1_CEC: J1200.13 TP1200.1(\TP\) TVS1204.2
HDMI1_CLK_N: C904.2 CMC1203.4 R920.2 R1216.1
HDMI1_CLK_N_CONN: CMC1203.3 CR1201.1 CR1201.10 J1200.12 R1216.2
HDMI1_CLK_P: C904.1 CMC1203.1 R918.2 R1215.1
HDMI1_CLK_P_CONN: CMC1203.2 CR1201.2 CR1201.9 J1200.10 R1215.2
HDMI1_HPD: J1200.19 R1299.1 TP1201.1(\TP\) TVS1203.2 U900.50
HDMI1_SCL_CONN: J1200.15 R901.2 R914.2 R928.2 TP909.1(\TP\) TVS1205.2
HDMI1_SDA_CONN: J1200.16 R900.2 R915.2 R929.2 TP911.1(\TP\) TVS1206.2
HDMI1_TX0_N: CMC1202.4 R917.2 R1214.1
HDMI1_TX0_N_CONN: CMC1202.3 CR1201.4 CR1201.7 J1200.9 R1214.2
HDMI1_TX0_P: CMC1202.1 R913.2 R1212.1
HDMI1_TX0_P_CONN: CMC1202.2 CR1201.5 CR1201.6 J1200.7 R1212.2
HDMI1_TX1_N: CMC1201.4 R908.2 R1211.1
HDMI1_TX1_N_CONN: CMC1201.3 CR1200.1 CR1200.10 J1200.6 R1211.2
HDMI1_TX1_P: CMC1201.1 R906.2 R1210.1
HDMI1_TX1_P_CONN: CMC1201.2 CR1200.2 CR1200.9 J1200.4 R1210.2
HDMI1_TX2_N: CMC1200.4 R905.2 R1209.1
HDMI1_TX2_N_CONN: CMC1200.3 CR1200.4 CR1200.7 J1200.3 R1209.2
HDMI1_TX2_P: CMC1200.1 R903.2 R1200.1
HDMI1_TX2_P_CONN: CMC1200.2 CR1200.5 CR1200.6 J1200.1 R1200.2
HDMI2_5V_CONN: D1200.2(-) J1201.18 R1201.1 R1202.1 TP1204.1(\TP\) TVS1209.2
HDMI2_CEC: J1201.13 TP1203.1(\TP\) TVS1211.2
HDMI2_CLK_N: C1002.2 CMC1207.4 R1016.2 R1233.1
HDMI2_CLK_N_CONN: CMC1207.3 CR1208.1 CR1208.10 J1201.12 R1233.2
HDMI2_CLK_P: C1002.1 CMC1207.1 R1014.2 R1232.1
HDMI2_CLK_P_CONN: CMC1207.2 CR1208.2 CR1208.9 J1201.10 R1232.2
HDMI2_HPD: J1201.19 R1298.1 TP1202.1(\TP\) TVS1210.2 U1000.50
HDMI2_SCL_CONN: J1201.15 R1001.2 R1023.2 R1201.2 TP1205.1(\TP\) TVS1212.2
HDMI2_SDA_CONN: J1201.16 R1000.2 R1024.2 R1202.2 TP1206.1(\TP\) TVS1213.2
HDMI2_TX0_N: CMC1206.4 R1013.2 R1231.1
HDMI2_TX0_N_CONN: CMC1206.3 CR1208.4 CR1208.7 J1201.9 R1231.2
HDMI2_TX0_P: CMC1206.1 R1011.2 R1229.1
HDMI2_TX0_P_CONN: CMC1206.2 CR1208.5 CR1208.6 J1201.7 R1229.2
HDMI2_TX1_N: CMC1205.4 R1008.2 R1228.1
HDMI2_TX1_N_CONN: CMC1205.3 CR1207.1 CR1207.10 J1201.6 R1228.2
HDMI2_TX1_P: CMC1205.1 R1006.2 R1227.1
HDMI2_TX1_P_CONN: CMC1205.2 CR1207.2 CR1207.9 J1201.4 R1227.2
HDMI2_TX2_N: CMC1204.4 R1005.2 R1226.1
HDMI2_TX2_N_CONN: CMC1204.3 CR1207.4 CR1207.7 J1201.3 R1226.2
HDMI2_TX2_P: CMC1204.1 R1004.2 R1217.1
HDMI2_TX2_P_CONN: CMC1204.2 CR1207.5 CR1207.6 J1201.1 R1217.2
HDMI3_5V_CONN: D1100.2(-) J1300.18 R1114.1 R1115.1 TP1101.1(\TP\) TVS1302.2
HDMI3_CEC: J1300.13 TP1301.1(\TP\) TVS1304.2
HDMI3_CLK_N: C1102.2 CMC1303.4 R1118.2 R1316.1
HDMI3_CLK_N_CONN: CMC1303.3 CR1301.1 CR1301.10 J1300.12 R1316.2
HDMI3_CLK_P: C1102.1 CMC1303.1 R1116.2 R1315.1
HDMI3_CLK_P_CONN: CMC1303.2 CR1301.2 CR1301.9 J1300.10 R1315.2
HDMI3_HPD: J1300.19 R1297.1 TP1300.1(\TP\) TVS1303.2 U1100.50
HDMI3_SCL_CONN: J1300.15 R1101.2 R1114.2 R1125.2 TP1108.1(\TP\) TVS1305.2
HDMI3_SDA_CONN: J1300.16 R1100.2 R1115.2 R1126.2 TP1111.1(\TP\) TVS1306.2
HDMI3_TX0_N: CMC1302.4 R1113.2 R1314.1
HDMI3_TX0_N_CONN: CMC1302.3 CR1301.4 CR1301.7 J1300.9 R1314.2
HDMI3_TX0_P: CMC1302.1 R1111.2 R1312.1
HDMI3_TX0_P_CONN: CMC1302.2 CR1301.5 CR1301.6 J1300.7 R1312.2
HDMI3_TX1_N: CMC1301.4 R1108.2 R1311.1
HDMI3_TX1_N_CONN: CMC1301.3 CR1300.1 CR1300.10 J1300.6 R1311.2
HDMI3_TX1_P: CMC1301.1 R1107.2 R1310.1
HDMI3_TX1_P_CONN: CMC1301.2 CR1300.2 CR1300.9 J1300.4 R1310.2
HDMI3_TX2_N: CMC1300.4 R1105.2 R1309.1
HDMI3_TX2_N_CONN: CMC1300.3 CR1300.4 CR1300.7 J1300.3 R1309.2
HDMI3_TX2_P: CMC1300.1 R1103.2 R1300.1
HDMI3_TX2_P_CONN: CMC1300.2 CR1300.5 CR1300.6 J1300.1 R1300.2
HDMI_5V: C821.1 C822.1 D900.1 D1100.1 D1200.1 TP804.1(\TP\) U804.1(\VOUT\)
HDRV1: Q700.4 U700.34
HDRV2: Q702.4 U700.27
HSIN_C: R1513.2 U1500.14
HSIP_C: R1511.2 U1500.13
HSON_C: C1502.1 U1500.18
HSOP_C: C1503.1 U1500.17
HSPK_PA_PDN_3V3: R2805.1 R2820.2 U2800.12 U2805.4(\Y\)
HUB1_AVDD: B2500.2 C2507.1 C2508.1 C2516.1 R2506.1 R2508.2 U2503.14
HUB_USB1_DM: CM2701.1 R2741.1 U2400.10
HUB_USB1_DM_CON: CM2701.4 J1900.U2 R2741.2 TVS1907.1
HUB_USB1_DP: CM2701.2 R2737.1 U2400.9
HUB_USB1_DP_CON: CM2701.3 J1900.U3 R2737.2 TVS1909.1
HUB_USB1_RX_M: CMC2700.1 R2736.1 U2400.7
HUB_USB1_RX_M_CON: CMC2700.2 CR1904.1 CR1904.10 J1900.U5 R2736.2
HUB_USB1_RX_P: CMC2700.4 R2740.1 U2400.6
HUB_USB1_RX_P_CON: CMC2700.3 CR1904.2 CR1904.9 J1900.U6 R2740.2
HUB_USB1_TX_M: C2411.2 CMC2703.1 R2743.1
HUB_USB1_TX_M_CON: CMC2703.2 CR1904.4 CR1904.7 J1900.U8 R2743.2
HUB_USB1_TX_P: C2412.2 CMC2703.4 R2746.1
HUB_USB1_TX_P_CON: CMC2703.3 CR1904.5 CR1904.6 J1900.U9 R2746.2
HUB_USB2_DM: CM2710.1 R2744.1 U2400.19
HUB_USB2_DM_CON: CM2710.4 J1900.U11 R2744.2 TVS1911.1
HUB_USB2_DP: CM2710.2 R2747.1 U2400.18
HUB_USB2_DP_CON: CM2710.3 J1900.U12 R2747.2 TVS1913.1
HUB_USB2_RX_M: CMC2702.1 R2738.1 U2400.16
HUB_USB2_RX_M_CON: CMC2702.2 CR1906.1 CR1906.10 J1900.U14 R2738.2
HUB_USB2_RX_P: CMC2702.4 R2742.1 U2400.15
HUB_USB2_RX_P_CON: CMC2702.3 CR1906.2 CR1906.9 J1900.U15 R2742.2
HUB_USB2_TX_M: C2409.2 CMC2711.1 R2745.1
HUB_USB2_TX_M_CON: CMC2711.2 CR1906.4 CR1906.7 J1900.U17 R2745.2
HUB_USB2_TX_P: C2410.2 CMC2711.4 R2748.1
HUB_USB2_TX_P_CON: CMC2711.3 CR1906.5 CR1906.6 J1900.U18 R2748.2
HUB_USB3_DM: CM2705.1 R2711.1 U2400.23
HUB_USB3_DM_CON: CM2705.4 J1901.U2 R2711.2 TVS1906.1
HUB_USB3_DP: CM2705.2 R2714.1 U2400.22
HUB_USB3_DP_CON: CM2705.3 J1901.U3 R2714.2 TVS1908.1
HUB_USB3_RX_M: CMC2704.1 R2710.1 U2400.29
HUB_USB3_RX_M_CON: CMC2704.2 CR1905.1 CR1905.10 J1901.U5 R2710.2
HUB_USB3_RX_P: CMC2704.4 R2713.1 U2400.28
HUB_USB3_RX_P_CON: CMC2704.3 CR1905.2 CR1905.9 J1901.U6 R2713.2
HUB_USB3_TX_M: C2406.2 CMC2707.1 R2716.1
HUB_USB3_TX_M_CON: CMC2707.2 CR1905.4 CR1905.7 J1901.U8 R2716.2
HUB_USB3_TX_P: C2408.2 CMC2707.4 R2719.1
HUB_USB3_TX_P_CON: CMC2707.3 CR1905.5 CR1905.6 J1901.U9 R2719.2
HUB_USB4_DM: CM2708.1 R2717.1 U2400.38
HUB_USB4_DM_CON: CM2708.4 J1901.U11 R2717.2 TVS1910.1
HUB_USB4_DP: CM2708.2 R2720.1 U2400.37
HUB_USB4_DP_CON: CM2708.3 J1901.U12 R2720.2 TVS1912.1
HUB_USB4_RX_M: CMC2706.1 R2712.1 U2400.35
HUB_USB4_RX_M_CON: CMC2706.2 CR1907.1 CR1907.10 J1901.U14 R2712.2
HUB_USB4_RX_P: CMC2706.4 R2715.1 U2400.34
HUB_USB4_RX_P_CON: CMC2706.3 CR1907.2 CR1907.9 J1901.U15 R2715.2
HUB_USB4_TX_M: C2405.2 CMC2709.1 R2718.1
HUB_USB4_TX_M_CON: CMC2709.2 CR1907.4 CR1907.7 J1901.U17 R2718.2
HUB_USB4_TX_P: C2404.2 CMC2709.4 R2721.1
HUB_USB4_TX_P_CON: CMC2709.3 CR1907.5 CR1907.6 J1901.U18 R2721.2
HUBPCIE14_CLKEQN: J2700.F6 R1510.1
HUBPCIE14_REFCLKN: J2700.F15 U1500.16
HUBPCIE14_REFCLKP: J2700.E15 U1500.15
HUBPCIE14_RX_N: C1502.2 J2700.F17
HUBPCIE14_RX_P: C1503.2 J2700.E17
HUBPCIE14_TX_N: J2700.F19 R1513.1
HUBPCIE14_TX_P: J2700.E19 R1511.1
HV_POWEREN: R533.1
HWTRAPN: TP1104.1(\TP\) U1100.49
HWTRAPN_30751790: TP904.1(\TP\) U900.49
HWTRAPN_30794186: TP1003.1(\TP\) U1000.49
I2C18_SCL_1P8: J2700.G7 R1803.1 R3113.1 U1802.B3 U2803.6 U3606.6
I2C18_SDA_1P8: J2700.A13 R1802.1 R3112.1 U1802.C3 U2803.5 U3606.5
IO_EXP_LED0: Q3101.1 U3104.17
IO_EXT_13_1P8: J2700.J5 J3400.3 TVS1800.2
IO_EXT_14_1P8: J2700.J6 J3400.18 TVS1801.2
IO_EXT_15_1P8: J2700.J7 J3400.4 TVS1802.2
IO_EXT_16_1P8: J2700.J8 J3400.17 TVS1803.2
IO_EXT_17_1P8: J2700.J9(\J9\) J3400.5 TVS2505.2
IO_EXT_18_1P8: J2700.J10 J3400.16 TVS2506.2
IO_EXT_19_1P8: J2700.J11 J3400.6 TVS2507.2
IO_EXT_36_1P8: J2700.G10 J3400.7 TVS1804.2
IO_EXT_37_1P8: J2700.E7 J3400.14 TVS1805.2
IO_EXT_38_1P8: J2700.D10 J3400.8 TVS1806.2
IO_EXT_39_1P8: J2700.G8 J3400.13 TVS2504.2
IPC_EC_ADDR_SEL: R3630.2 U3607.4
ISOLATEB: R1505.1 R1507.1 U1500.20
IT6563_ASPVCC10_1: C909.1 JP900.2 U900.41
IT6563_ASPVCC10_2: C1009.1 JP1000.2 U1000.41
IT6563_ASPVCC10_3: C1109.1 JP1100.2 U1100.41
IT6563_ASPVCC33_1: C924.1 JP907.2 U900.40
IT6563_ASPVCC33_2: C1024.1 JP1007.2 U1000.40
IT6563_ASPVCC33_3: C1124.1 JP1107.2 U1100.40
IT6563_DDI2C_CLK: R1125.1 U1100.52
IT6563_DDI2C_CLK_30751790: R928.1 U900.52
IT6563_DDI2C_CLK_30794192: R1023.1 U1000.52
IT6563_DDI2C_SDA: R1126.1 U1100.51
IT6563_DDI2C_SDA_30751790: R929.1 U900.51
IT6563_DDI2C_SDA_30794190: R1024.1 U1000.51
IT6563_I2S_DATA0: R1122.2 R1123.1 TP1103.1(\TP\) U1100.55
IT6563_I2S_DATA0_30751790: R924.2 R926.1 TP903.1(\TP\) U900.55
IT6563_I2S_DATA0_30794157: R1020.2 R1021.1 TP1002.1(\TP\) U1000.55
IT6563_I2S_SCK: TP1100.1(\TP\) U1100.1
IT6563_I2S_SCK_30751790: TP900.1(\TP\) U900.1
IT6563_I2S_SCK_30794096: TP1000.1(\TP\) U1000.1
IT6563_I2S_WS: TP1102.1(\TP\) U1100.56
IT6563_I2S_WS_30751790: TP902.1(\TP\) U900.56
IT6563_I2S_WS_30794200: TP1001.1(\TP\) U1000.56
IT6563_IVDD10_1: C913.1 C914.1 C915.1 C916.1 C917.1 JP902.2 U900.17 U900.21 U900.44 U900.54
IT6563_IVDD10_2: C1013.1 C1014.1 C1015.1 C1016.1 C1017.1 JP1002.2 U1000.17 U1000.21 U1000.44 U1000.54
IT6563_IVDD10_3: C1113.1 C1114.1 C1115.1 C1116.1 C1117.1 JP1102.2 U1100.17 U1100.21 U1100.44 U1100.54
IT6563_OVDD33_1: C918.1 C919.1 JP903.2 R923.2 R924.1 R930.2 U900.20 U900.23 U900.53
IT6563_OVDD33_2: C1018.1 C1019.1 JP1003.2 R1019.2 R1020.1 R1025.2 U1000.20 U1000.23 U1000.53
IT6563_OVDD33_3: C1118.1 C1119.1 JP1103.2 R1121.2 R1122.1 R1127.2 U1100.20 U1100.23 U1100.53
IT6563_PCI2C_SCL: TP1105.1(\TP\) U1100.48
IT6563_PCI2C_SCL_30751790: TP905.1(\TP\) U900.48
IT6563_PCI2C_SCL_30794184: TP1004.1(\TP\) U1000.48
IT6563_PCI2C_SDA: TP1106.1(\TP\) U1100.47
IT6563_PCI2C_SDA_30751790: TP906.1(\TP\) U900.47
IT6563_PCI2C_SDA_30794182: TP1005.1(\TP\) U1000.47
IT6563_REXT: R1120.1 U1100.5
IT6563_REXT_30751790: R922.1 U900.5
IT6563_REXT_30794050: R1018.1 U1000.5
IT6563_RXAVDD10_1: B900.2 C906.1 C907.1 C908.1 JP900.1 JP901.1 TP908.1(\TP\) U900.31 U900.36
IT6563_RXAVDD10_2: B1000.2 C1006.1 C1007.1 C1008.1 JP1000.1 JP1001.1 TP1007.1(\TP\) U1000.31 U1000.36
IT6563_RXAVDD10_3: B1100.2 C1106.1 C1107.1 C1108.1 JP1100.1 JP1101.1 TP1109.1(\TP\) U1100.31 U1100.36
IT6563_RXAVDD33_1: C922.1 C923.1 JP906.2 U900.39
IT6563_RXAVDD33_2: C1022.1 C1023.1 JP1006.2 U1000.39
IT6563_RXAVDD33_3: C1122.1 C1123.1 JP1106.2 U1100.39
IT6563_RXDVDD10_1: C920.1 JP905.2 U900.28
IT6563_RXDVDD10_2: C1020.1 JP1005.2 U1000.28
IT6563_RXDVDD10_3: C1120.1 JP1105.2 U1100.28
IT6563_RXPVCC10_1: C910.1 JP901.2 U900.25
IT6563_RXPVCC10_2: C1010.1 JP1001.2 U1000.25
IT6563_RXPVCC10_3: C1110.1 JP1101.2 U1100.25
IT6563_RXPVCC33_1: C925.1 JP908.2 U900.24
IT6563_RXPVCC33_2: C1025.1 JP1008.2 U1000.24
IT6563_RXPVCC33_3: C1125.1 JP1108.2 U1100.24
IT6563_TAVCC10_1: B903.2 C926.1 C927.1 JP909.1 U900.10
IT6563_TAVCC10_2: B1003.2 C1026.1 C1027.1 JP1009.1 U1000.10
IT6563_TAVCC10_3: B1103.2 C1126.1 C1127.1 JP1109.1 U1100.10
IT6563_TDVDD10_1: C921.1 JP904.2 U900.15
IT6563_TDVDD10_2: C1021.1 JP1004.2 U1000.15
IT6563_TDVDD10_3: C1121.1 JP1104.2 U1100.15
IT6563_TPVCC10_1: C928.1 JP909.2 U900.4
IT6563_TPVCC10_2: C1028.1 JP1009.2 U1000.4
IT6563_TPVCC10_3: C1128.1 JP1109.2 U1100.4
IT6563_TPVCC33_1: B901.2 C911.1 C912.1 U900.3
IT6563_TPVCC33_2: B1001.2 C1011.1 C1012.1 U1000.3
IT6563_TPVCC33_3: B1101.2 C1111.1 C1112.1 U1100.3
IT6563_XI_1: C902.1 U900.43 Y900.1
IT6563_XI_2: C1003.1 U1000.43 Y1000.1
IT6563_XI_3: C1103.1 U1100.43 Y1100.1
IT6563_XO_1: C903.1 U900.42(\XTALOUT\) Y900.3
IT6563_XO_2: C1004.1 U1000.42(\XTALOUT\) Y1000.3
IT6563_XO_3: C1104.1 U1100.42(\XTALOUT\) Y1100.3
LAN0_MDI0+: CR1500.1 CR1500.10 J1500.2 U1500.1
LAN0_MDI0-: CR1500.2 CR1500.9 J1500.3 U1500.2
LAN0_MDI1+: CR1500.4 CR1500.7 J1500.4 U1500.4
LAN0_MDI1-: CR1500.5 CR1500.6 J1500.7 U1500.5
LAN0_MDI2+: CR1501.1 CR1501.10 J1500.5 U1500.6
LAN0_MDI2-: CR1501.2 CR1501.9 J1500.6 U1500.7
LAN0_MDI3+: CR1501.4 CR1501.7 J1500.8 U1500.9
LAN0_MDI3-: CR1501.5 CR1501.6 J1500.9 U1500.10
LAN0LED0: R1704.2 R1705.1 U1701.81
LAN0LED1: R1719.2 R1722.2 U1701.80
LAN1LED0: R1706.2 R1707.1 R2012.1 R2013.1 U1701.79
LAN1LED1: R2003.1 U1701.78
LAN1LED_G+: J2000.D3 R2003.2 R2007.2 TVS2000.2
LAN1LED_Y+: J2000.D1 R2005.2 R2012.2 TVS2003.2
LAN1LED_Y-: J2000.D2(\Y_LED2-\) R2013.2 R2015.2 TVS2005.2
LAN2LED0: R1709.2 R1710.1 R2006.2 U1701.75
LAN2LED1: R2002.1 U1701.77
LAN2LED_G+: J2001.D3 R2001.2 R2002.2 TVS2002.2
LAN2LED_Y+: J2001.D1 R2004.2 TVS2001.2
LAN2LED_Y-: J2001.D2(\Y_LED2-\) R2006.1 TVS2004.2
LAN3LED0: R1711.2 R1712.1 R1908.1 R1912.1 U1701.74
LAN3LED1: R1902.1 U1701.72
LAN4LED0: R1714.2 R1715.1 R1907.1 U1701.70
LAN4LED1: R1903.1 U1701.71
LDRV1: Q701.4 U700.32
LDRV2: Q703.4 U700.29
LM5177_VCC: C705.1 R705.1 U700.12 U700.31
LM5177_VIN: C700.1 C703.1 CT700.1 Q700.5 Q700.6 Q700.7 Q700.8 R700.2 U700.3
LNE3LED_G+: J1900.D3 R1902.2 R1905.2 TVS1901.2
LNE3LED_Y+: J1900.D1 R1906.2 R1912.2 TVS1902.2
LNE3LED_Y-: J1900.D2(\Y_LED2-\) R1908.2 R1913.2 TVS1904.2
LNE4LED_G+: J1901.D3 R1903.2 R1904.2 TVS1900.2
LNE4LED_Y+: J1901.D1 R1907.2 TVS1903.2
LX: L1700.1 U1701.63 U1701.64
M25207_BIAS_5VOUT: C614.1 D600.1 R602.1 R603.1 R604.1 U600.13
MCU_BOOT1: J2600.A14 TP2622.1(\TP\)
MCU_RESERVED_BUTTON: J2600.A15 TP2623.1(\TP\)
MD_GPIO_51_1P8: J2600.C14 TP2625.1(\TP\)
MD_GPIO_64_1P8: J2600.E29
MD_GPIO_65_1P8: J2600.E30
MD_GPIO_66_1P8: J2600.A12
MD_GPIO_67_1P8: J2600.A13
MD_GPIO_111_1P8: J2600.E28 TP2631.1(\TP\)
MD_GPIO_115_1P8: J2700.B15
MD_GPIO_116_1P8: J2700.B17
MD_GPIO_117_1P8: J2700.B19
MD_GPIO_123_1P8: J2600.B15 TP2603.1(\TP\)
MD_GPIO_124_1P8: J2600.B16 TP2604.1(\TP\)
MD_GPIO_125_1P8: J2600.B17 TP2605.1(\TP\)
MD_GPIO_128_1P8: J2600.C20 TP2628.1(\TP\)
MD_GPIO_130_1P8: J2600.C19 TP2627.1(\TP\)
MD_GPIO_132_1P8: J2600.E24 TP2608.1(\TP\)
MD_GPIO_133_1P8: J2600.E25 TP2609.1(\TP\)
MD_GPIO_134_1P8: J2600.E20 TP2617.1(\TP\)
MD_GPIO_135_1P8: J2600.E21 TP2618.1(\TP\)
MD_GPIO_136_1P8: J2600.C18 TP2626.1(\TP\)
MD_GPIO_138_1P8: J2600.E26 TP2610.1(\TP\)
MD_GPIO_139_1P8: J2600.E18 TP2615.1(\TP\)
MD_GPIO_140_1P8: J2600.E19 TP2616.1(\TP\)
MD_GPIO_144_1P8: TP2632.1(\TP\)
MD_GPIO_146_1P8: J2700.H4
MD_GPIO_147_1P8: J2700.H5
MD_GPIO_148_1P8: J2700.H6
MD_RESOUT_1P8: J2700.G9 R3115.1
MDIREF: R1716.1 U1701.13
MIC_I2C_SCL_1P8: R3514.2 U3500.17 U3501.17
MIC_I2C_SDA_1P8: R3513.2 U3500.18 U3501.18
MIC_MI2S_MCLK_1P8: J2600.B24 R3512.1
MIC_MI2S_MCLK_1P8_1: R3512.2 R3530.1 U3500.20
MIC_MI2S_SCK_1P8: J2600.B22 R3507.1
MIC_MI2S_SCK_1P8_1: R3507.2 TP3508.1(\TP\) U3500.22 U3501.22
MIC_MI2S_SDOUT_1P8: J2600.B23 R3509.1 R3529.1 TP3509.1(\TP\)
MIC_MI2S_WS_1P8: J2600.B21 R3506.1
MIC_MI2S_WS_1P8_1: R3506.2 TP3507.1(\TP\) U3500.23 U3501.23
MIC_RST_1P8_N: J2600.B20 R3501.1
MICBIAS1: C3507.1 U3500.5
MICBIAS3: C3525.1 U3501.5
NVME_PCIE1_CLKREQ_1P8: J2700.B10 U2301.3
NVME_PCIE1_RST_1P8: J2700.B11 U2302.3
NVME_PCIE1_WAKE_1P8: J2700.B9 U2301.2
NVME_PWR_EN_1P8: J2700.I11 R2303.1
NVME_THERM: J2700.B8 RT2300.1
OVCUR0: R2401.2 TP2401.1(\TP\) U2400.41
OVCUR1: R1811.2 U2400.1 U2700.3
OVCUR2: R1812.2 U2400.75 U2701.3
OVCUR3: R1813.2 U2400.20 U2702.3
OVCUR4: R1814.2 U2400.40 U2703.3
P0MDIAN: U1400.22 U1701.92
P0MDIAP: U1400.23 U1701.91
P0MDIBN: U1400.19 U1701.94
P0MDIBP: U1400.20 U1701.93
P0MDICN: U1400.16 U1701.98
P0MDICP: U1400.17 U1701.97
P0MDIDN: U1400.13 U1701.101
P0MDIDP: U1400.14 U1701.100
P1_MDI_AN: CR2003.4 CR2003.7 J2000.3 U1701.104
P1_MDI_AP: CR2003.5 CR2003.6 J2000.2 U1701.103
P1_MDI_BN: CR2003.1 CR2003.10 J2000.5 U1701.107
P1_MDI_BP: CR2003.2 CR2003.9 J2000.4 U1701.106
P1_MDI_CN: CR2001.4 CR2001.7 J2000.7 U1701.110
P1_MDI_CP: CR2001.5 CR2001.6 J2000.6 U1701.109
P1_MDI_DN: CR2001.1 CR2001.10 J2000.9 U1701.113
P1_MDI_DP: CR2001.2 CR2001.9 J2000.8 U1701.112
P2_MDI_AN: CR2002.4 CR2002.7 J2001.3 U1701.118
P2_MDI_AP: CR2002.5 CR2002.6 J2001.2 U1701.117
P2_MDI_BN: CR2002.1 CR2002.10 J2001.5 U1701.121
P2_MDI_BP: CR2002.2 CR2002.9 J2001.4 U1701.120
P2_MDI_CN: CR2000.4 CR2000.7 J2001.7 U1701.124
P2_MDI_CP: CR2000.5 CR2000.6 J2001.6 U1701.123
P2_MDI_DN: CR2000.1 CR2000.10 J2001.9 U1701.127
P2_MDI_DP: CR2000.2 CR2000.9 J2001.8 U1701.126
P3_MDI_AN: CR1903.4 CR1903.7 J1900.3 U1701.3
P3_MDI_AP: CR1903.5 CR1903.6 J1900.2 U1701.2
P3_MDI_BN: CR1903.1 CR1903.10 J1900.5 U1701.5
P3_MDI_BP: CR1903.2 CR1903.9 J1900.4 U1701.4
P3_MDI_CN: CR1901.4 CR1901.7 J1900.7 U1701.8
P3_MDI_CP: CR1901.5 CR1901.6 J1900.6 U1701.7
P3_MDI_DN: CR1901.1 CR1901.10 J1900.9 U1701.10
P3_MDI_DP: CR1901.2 CR1901.9 J1900.8 U1701.9
P4_MDI_AN: CR1902.4 CR1902.7 J1901.3 U1701.23
P4_MDI_AP: CR1902.5 CR1902.6 J1901.2 U1701.22
P4_MDI_BN: CR1902.1 CR1902.10 J1901.5 U1701.26
P4_MDI_BP: CR1902.2 CR1902.9 J1901.4 U1701.25
P4_MDI_CN: CR1900.4 CR1900.7 J1901.7 U1701.29
P4_MDI_CP: CR1900.5 CR1900.6 J1901.6 U1701.28
P4_MDI_DN: CR1900.1 CR1900.10 J1901.9 U1701.31
P4_MDI_DP: CR1900.2 CR1900.9 J1901.8 U1701.30
PCIE1_CLK_REQ_N_3P3: CN2300.52 TVS2302.1 U2301.6
PCIE1_REFCLK_M: CN2300.53 CR2304.5 CR2304.6 J2700.E13
PCIE1_REFCLK_P: CN2300.55 CR2304.4 CR2304.7 J2700.F13
PCIE1_RESET_N_3P3: CN2300.50 TVS2301.1 U2302.4
PCIE1_RX0_M: CN2300.41 CR2305.5 CR2305.6 J2700.G20
PCIE1_RX0_P: CN2300.43 CR2305.4 CR2305.7 J2700.H20
PCIE1_RX1_M: CN2300.29 CR2300.5 CR2300.6 J2700.G18
PCIE1_RX1_P: CN2300.31 CR2300.4 CR2300.7 J2700.H18
PCIE1_RX2_M: CN2300.17 CR2308.5 CR2308.6 J2700.G16
PCIE1_RX2_P: CN2300.19 CR2308.4 CR2308.7 J2700.H16
PCIE1_RX3_M: CN2300.5 CR2307.5 CR2307.6 J2700.G14
PCIE1_RX3_P: CN2300.7 CR2307.4 CR2307.7 J2700.H14
PCIE1_TX0_M: CN2300.47 CR2305.2 CR2305.9 J2700.I13
PCIE1_TX0_P: CN2300.49 CR2305.1 CR2305.10 J2700.J13
PCIE1_TX1_M: CN2300.35 CR2300.2 CR2300.9 J2700.I15
PCIE1_TX1_P: CN2300.37 CR2300.1 CR2300.10 J2700.J15
PCIE1_TX2_M: CN2300.23 CR2308.2 CR2308.9 J2700.I17
PCIE1_TX2_P: CN2300.25 CR2308.1 CR2308.10 J2700.J17
PCIE1_TX3_M: CN2300.11 CR2307.2 CR2307.9 J2700.I19
PCIE1_TX3_P: CN2300.13 CR2307.1 CR2307.10 J2700.J19
PCIE1_WAKE_N_3P3: CN2300.54 TVS2303.1 U2301.7
PCIE_ETH_LEDG: J1500.12 R1502.2 TVS1501.2
PCIE_ETH_LEDY: J1500.13 R1514.2 TVS1502.2
PG_VREG_3P3: R515.2 R539.2 U500.7
PG_VREG_3P3_SIP: J2700.F8
PG_VREG_5P0: R532.2 R704.1 R813.1 U500.24 U700.4
PG_VREG_CAM_6P7: R899.2 TP602.1(\TP\) U600.5 U800.11
PMA_GPIO_9_MV: J2700.A3
PMA_GPIO_10_MV: J2700.A16
PMA_GPIO_11_MV: J2700.B3
PMC_GPIO_6_MV: J2700.A7
PMC_GPIO_10_MV: J2700.A8
PME_GPIO_6_MV: J2700.I8
PME_GPIO_11_MV: J2700.I10
PMG_AMUX_6: J2600.D29
PMG_GPIO_3_MV: J2700.C7
PMG_GPIO_4_MV: J2700.C8
PMG_GPIO_5_MV: J2700.C9
PMS_GPIO_8_MV: J2700.A15
POWER_DISABLE_TO_IOB: J2700.A19 R2708.2
POWER_EN_1P8: J2700.I9 R538.1
PWREN0: TP2400.1(\TP\) U2400.42
PWREN1: R2724.2 U2400.2
PWREN2: R2734.2 U2400.76
PWREN3: R2703.2 U2400.21
PWREN4: R2728.2 U2400.39
REGOUT: C1504.1 R1512.1 U1500.24
RS232_RX: U4000.9 U4001.4
RS232_RX_1P8: J2700.G6 R4006.1
RS232_RX_RIN: D4000.1 J3310.2 U4000.8
RS232_TX: U4000.10 U4001.5
RS232_TX_1P8: J2700.G5 U4001.8
RS232_TX_DOUT: D4001.1 J3310.1 U4000.7
RS485_A0: J3303.1 R3301.2 R3901.1 R3910.2 TVS3900.2
RS485_A0_R: R3301.1 SW3300.1
RS485_B0: J3303.2 R3903.1 R3909.2 SW3300.12 TVS3901.2
RS485_RTS_1P8: J2700.B6 U4003.2
RS485_RX: U3901.1 U4002.4
RS485_RX_1P8: J2700.E9 R4007.1
RS485_TX: U3901.4 U4002.5
RS485_TX_1P8: J2700.B7 U4002.8
RST_OUT: C2413.1 D2400.1 R2404.2 R2407.1 R2418.2 U2400.68
RTL8111_ISOLATEB_1P8: J2600.E27 R1507.2
RTL8111_PWR_EN_1P8: J2700.I7 R1517.1
RTL8111_RSTN: J2700.E10 R1508.2
RTL8111_WAKE_1P8: J2700.E11 R1521.2 R1522.2 R1523.2
RTL8211_INT_1P8: J2600.F19 R1405.1
RTL8211_MDC_1P8: J2700.H9 R1411.1
RTL8211_MDIO_1P8: J2700.H10 R1410.1
RTL8211_RST_1P8: J2600.F24 Q1400.2(\SOURCE\)
RTL8367_AVDDH: B1705.1 B1706.2 C1740.1 C1741.1 C1742.1 C1743.1 C1744.1 C1745.1 C1746.1 C1747.1 C1748.1 C1749.1 C1750.1 C1751.1 C1752.1 C1753.1 U1701.11 U1701.17 U1701.21 U1701.33 U1701.82 U1701.90 U1701.102 U1701.116 U1701.128
RTL8367_AVDDL: B1701.1 B1703.1 B1704.2 C1710.1 C1711.1 C1723.1 C1726.1 C1727.1 C1728.1 C1729.1 C1730.1 C1731.1 C1732.1 C1733.1 C1734.1 C1735.1 C1736.1 C1737.1 U1701.6 U1701.14 U1701.27 U1701.95 U1701.108 U1701.122
RTL8367_DVDDIO: B1700.2 B1702.1 B1706.1 C1412.1 C1601.1 C1602.1 C1603.2 C1608.2 C1609.1 C1612.1 C1701.1 D1600.1 D1700.2(\C\) R1412.1 R1413.1 R1601.1 R1605.1 R1612.2 R1616.2 R1700.1 R1701.1 R1702.2 R1703.1 R1704.1 R1706.1 R1709.1 R1711.1 R1714.1 R1720.1 R1906.1 R2004.1 R2005.1 TP1600.1(\TP\) U1600.1(\VOUT\) U1601.5 U1604.8(\VCCB\) U1605.7 U1606.7 U1700.8 U1701.67
RTL8367_DVDDIO2: B1702.2 C1714.1 C1715.1 C1716.1 C1717.1 U1701.42 U1701.59
RTL8367_DVDDIO_F: C1606.1 C1610.1 C1611.2 C1613.1 D1600.2(\C\) J1600.1 R1607.1 R1608.1 U1603.8 U1605.6(\VCCB\) U1606.6(\VCCB\)
RTL8367_DVDDL: B1704.1 C1707.1 C1708.1 C1709.1 C1718.1 C1719.1 C1720.1 C1721.1 C1722.1 L1700.2 U1701.20 U1701.58 U1701.69
RTL8367_INT: R1601.2 U1601.2 U1701.19
RTL8367_INT_1P8: J2600.F20 R1602.2 R1604.2
RTL8367_PLLVDDL0: B1703.2 C1724.1 C1725.1 U1701.114
RTL8367_PWR_EN_1P8: J2700.E4 R1603.1
RTL8367_RST: C1702.1 D1700.1 R1605.2 R1606.2 R1700.2 U1701.86
RTL8367_RST_1P8: J2600.F23 U1602.2
RTL8367_SCK: R1701.2 U1604.7 U1700.6 U1701.87
RTL8367_SCK_1P8: J2600.F21 R1610.2 U1604.2
RTL8367_SDA: R1703.2 U1604.6 U1700.5 U1701.88
RTL8367_SDA_1P8: J2600.F22 R1611.2 U1604.3
RTL8367_SVDDH: B1705.2 C1738.1 C1739.1 U1701.41
RTL8367_SVDDL: B1701.2 C1712.1 C1713.1 U1701.37
RTL_SPI_CK: R1613.1 U1701.48
RTL_SPI_CK_S: J1600.4 U1603.6 U1605.5
RTL_SPI_CZ: R1617.1 U1701.54
RTL_SPI_CZ_S: J1600.2 U1603.1 U1606.5
RTL_SPI_DI: R1614.1 U1701.53
RTL_SPI_DI_S: J1600.5 U1603.5 U1605.4
RTL_SPI_DO: R1618.1 U1701.49
RTL_SPI_DO_S: J1600.3 U1603.2 U1606.4
RTL_XTAL1: C1501.1 U1500.28 Y1500.1
RTL_XTAL2: R1500.2 U1500.29
RTL_XTALI: C1700.1 U1701.84 Y1700.3
RTL_XTALO: C1703.1 U1701.83(\XTALO\) Y1700.1
RTT1: R1718.1 U1701.15
RTT2: R1717.1 U1701.16
RXCAN0: U3400.4 U3407.2
RXCAN1: U3402.4 U3409.2
RXCAN2: U3404.4 U3411.2
RXCAN3: U3405.4 U3413.2
SAIL_CAN_0_M: CM3400.2 U3400.6
SAIL_CAN_0_P: CM3400.1 U3400.7
SAIL_CAN_1_M: CM3401.2 U3402.6
SAIL_CAN_1_P: CM3401.1 U3402.7
SAIL_IO_0_1P8: J2700.C11
SAIL_IO_1_1P8: J2700.C12
SAIL_IO_2_1P8: J2700.A4
SAIL_IO_3_1P8: J2700.A5
SAIL_IO_4_1P8: J2700.D12
SAIL_IO_8_1P8: J2600.D25 TP2600.1(\TP\)
SAIL_IO_9_1P8: J2600.D26 TP2601.1(\TP\)
SAIL_IO_10_1P8: J2600.D15
SAIL_IO_11_1P8: J2600.A17
SAIL_IO_12_1P8: J2600.A18
SAIL_IO_13_1P8: J2600.A16
SAIL_IO_14_1P8: J2600.B11
SAIL_IO_19_1P8: J2600.C26
SAIL_IO_20_1P8: J2600.C27
SAIL_IO_21_1P8: J2600.F15
SAIL_IO_22_1P8: J2600.F16
SAIL_IO_23_1P8: J2600.F17
SAIL_IO_24_1P8: J2600.F18
SAIL_IO_25_1P8: J2600.D12
SAIL_IO_26_1P8: J2600.E11
SAIL_IO_27_1P8: J2600.E12
SAIL_IO_28_1P8: J2600.E13
SAIL_IO_29_1P8: J2600.E14
SAIL_IO_30_1P8: J2600.D13
SAIL_IO_31_1P8: J2600.C13
SAIL_IO_32_1P8: J2600.F11
SAIL_IO_33_1P8: J2600.F12
SAIL_IO_34_1P8: J2600.F13
SAIL_IO_35_1P8: J2600.F14
SAIL_IO_36_1P8: J2600.C12
SAIL_IO_37_1P8: J2600.A20
SAIL_IO_38_1P8: J2600.A19
SAIL_IO_39_1P8: J2600.A24
SAIL_IO_40_1P8: J2600.A23
SAIL_IO_41_1P8: J2600.A25
SAIL_IO_42_1P8: J2600.A21
SAIL_IO_43_1P8: J2600.A26
SAIL_IO_44_1P8: J2600.A22
SAIL_IO_45_1P8: J2700.C6
SAIL_IO_46_1P8: J2700.C5
SAIL_IO_47_1P8: J2600.A11
SAIL_IO_48_1P8: J2700.E8
SAIL_IO_49_1P8: J2600.D39
SAIL_IO_50_1P8: J2700.A9
SAIL_IO_51_1P8: J2600.F9(\F9\)
SAIL_IO_52_1P8: J2600.B25
SAIL_IO_53_1P8: J2600.C25
SAIL_IO_54_1P8: J2600.D14
SAIL_IO_55_1P8: J2600.B12
SAIL_IO_56_1P8: J2600.B13
SAIL_IO_57_1P8: J2700.A10
SAIL_IO_58_1P8: J2700.A11
SAIL_IO_59_1P8: J2700.E5
SAIL_IO_60_1P8: J2700.I5
SAIL_IO_61_1P8: J2700.I6
SAIL_IO_64_1P8: J2700.A12
SAIL_IO_66_1P8: J2600.F10
SAIL_IO_69_1P8: J2700.D11
SENSOR_I2C_SCL_1P8: J2700.F10
SENSOR_I2C_SDA_1P8: J2700.F11
SENSOR_INT_1P8: J2700.H7
SENSOR_SLP_CLK_1P8: J2700.H8
SGMII0_RX_M: C1755.2 J2600.F3
SGMII0_RX_P: C1754.2 J2600.E3
SGMII0_TX_M: J2600.F1 U1701.39
SGMII0_TX_P: J2600.E1 U1701.38
SGMII1_RX_M: C1400.1 J2600.F7
SGMII1_RX_P: C1402.1 J2600.E7
SGMII1_TX_M: J2600.F5 U1401.39
SGMII1_TX_P: J2600.E5 U1401.38
SHDNZ_ADC3: C3522.1 R3501.2 R3527.1 U3500.14 U3501.14
SMCLK: R2406.2 TP2410.1(\TP\) U2400.66
SMDAT: R2405.2 TP2409.1(\TP\) U2400.65
SPI_CS: R2417.2 TP2414.1(\TP\) U2400.72
SPICLK: R2414.2 TP2411.1(\TP\) U2400.70
SPISI: R2415.2 TP2412.1(\TP\) U2400.69
SPISO: R2416.2 TP2413.1(\TP\) U2400.71
SPK_L_N: C2812.1 C2814.1 C3503.1 D2801.2 J2801.2 L2801.2 R2801.1
SPK_L_P: C2813.1 C2815.1 C3501.1 D2800.2 J2801.1 L2800.2 R2802.1
SPK_R_N: C2821.1 C2823.1 C3510.1 D2803.2 J2802.2 L2803.2 R2803.1
SPK_R_P: C2822.1 C2824.1 C3508.1 D2802.2 J2802.1 L2802.2 R2804.1
SSREXT: R2408.1 U2400.47
SSRX0+: R1801.2 U2400.53
SSRX0-: R1800.2 U2400.52
SSTX0+: C2403.1 U2400.50
SSTX0-: C2400.1 U2400.49
SSTX1+: C2412.1 U2400.3
SSTX1-: C2411.1 U2400.4
SSTX2+: C2410.1 U2400.12
SSTX2-: C2409.1 U2400.13
SSTX3+: C2408.1 U2400.25
SSTX3-: C2406.1 U2400.26
SSTX4+: C2404.1 U2400.31
SSTX4-: C2405.1 U2400.32
SSXI: C2402.1 R2400.2 U2400.45 Y2400.3
SSXO: C2401.1 R2400.1 U2400.44 Y2400.1
SW1: C707.1 Q700.1 Q700.2 Q700.3(\S3\) Q701.5 Q701.6 Q701.7 Q701.8 R701.2 R703.1 U700.36
SW2: C708.1 L700.2 Q702.1 Q702.2 Q702.3(\S3\) Q703.5 Q703.6 Q703.7 Q703.8 U700.25
TESTEN: R2409.1 U2400.74
TXCAN0: U3400.1 U3407.1
TXCAN1: U3402.1 U3409.1
TXCAN2: U3404.1 U3411.1
TXCAN3: U3405.1 U3413.1
USB1_HS_D_M: J2700.C20 R2413.1
USB1_HS_D_P: J2700.D20 R2412.1
USB1_SS_RX_M: C2400.2 J2700.D16
USB1_SS_RX_P: C2403.2 J2700.C16
USB1_SS_TX_M: J2700.D18 R1800.1
USB1_SS_TX_P: J2700.C18 R1801.1
USB2_EN: R2500.2 R2501.1 U2500.4 U2501.4 U2502.4 U2504.4 U2505.4
USB2_HUB2_DM1: CM2000.4 U2503.3
USB2_HUB2_DM2: CM2002.4 U2503.6
USB2_HUB2_DM3: CM2001.2 U2503.12
USB2_HUB2_DM4: CM2003.4 U2503.15
USB2_HUB2_DP1: CM2000.3 U2503.4
USB2_HUB2_DP2: CM2002.3 U2503.7
USB2_HUB2_DP3: CM2001.1 U2503.13
USB2_HUB2_DP4: CM2003.3 U2503.16
USB2_HUB_DM1: J2700.D14 R2520.1
USB2_HUB_DM4: J2700.H12 TP2700.1(\TP\)
USB2_HUB_DP1: J2700.C14 R2521.1
USB2_HUB_DP4: J2700.G12 TP2701.1(\TP\)
USB2_HUB_PGANG: R2517.2 R2519.1 U2503.23
USB2_HUB_PSELF: R2516.2 R2518.1 U2503.22
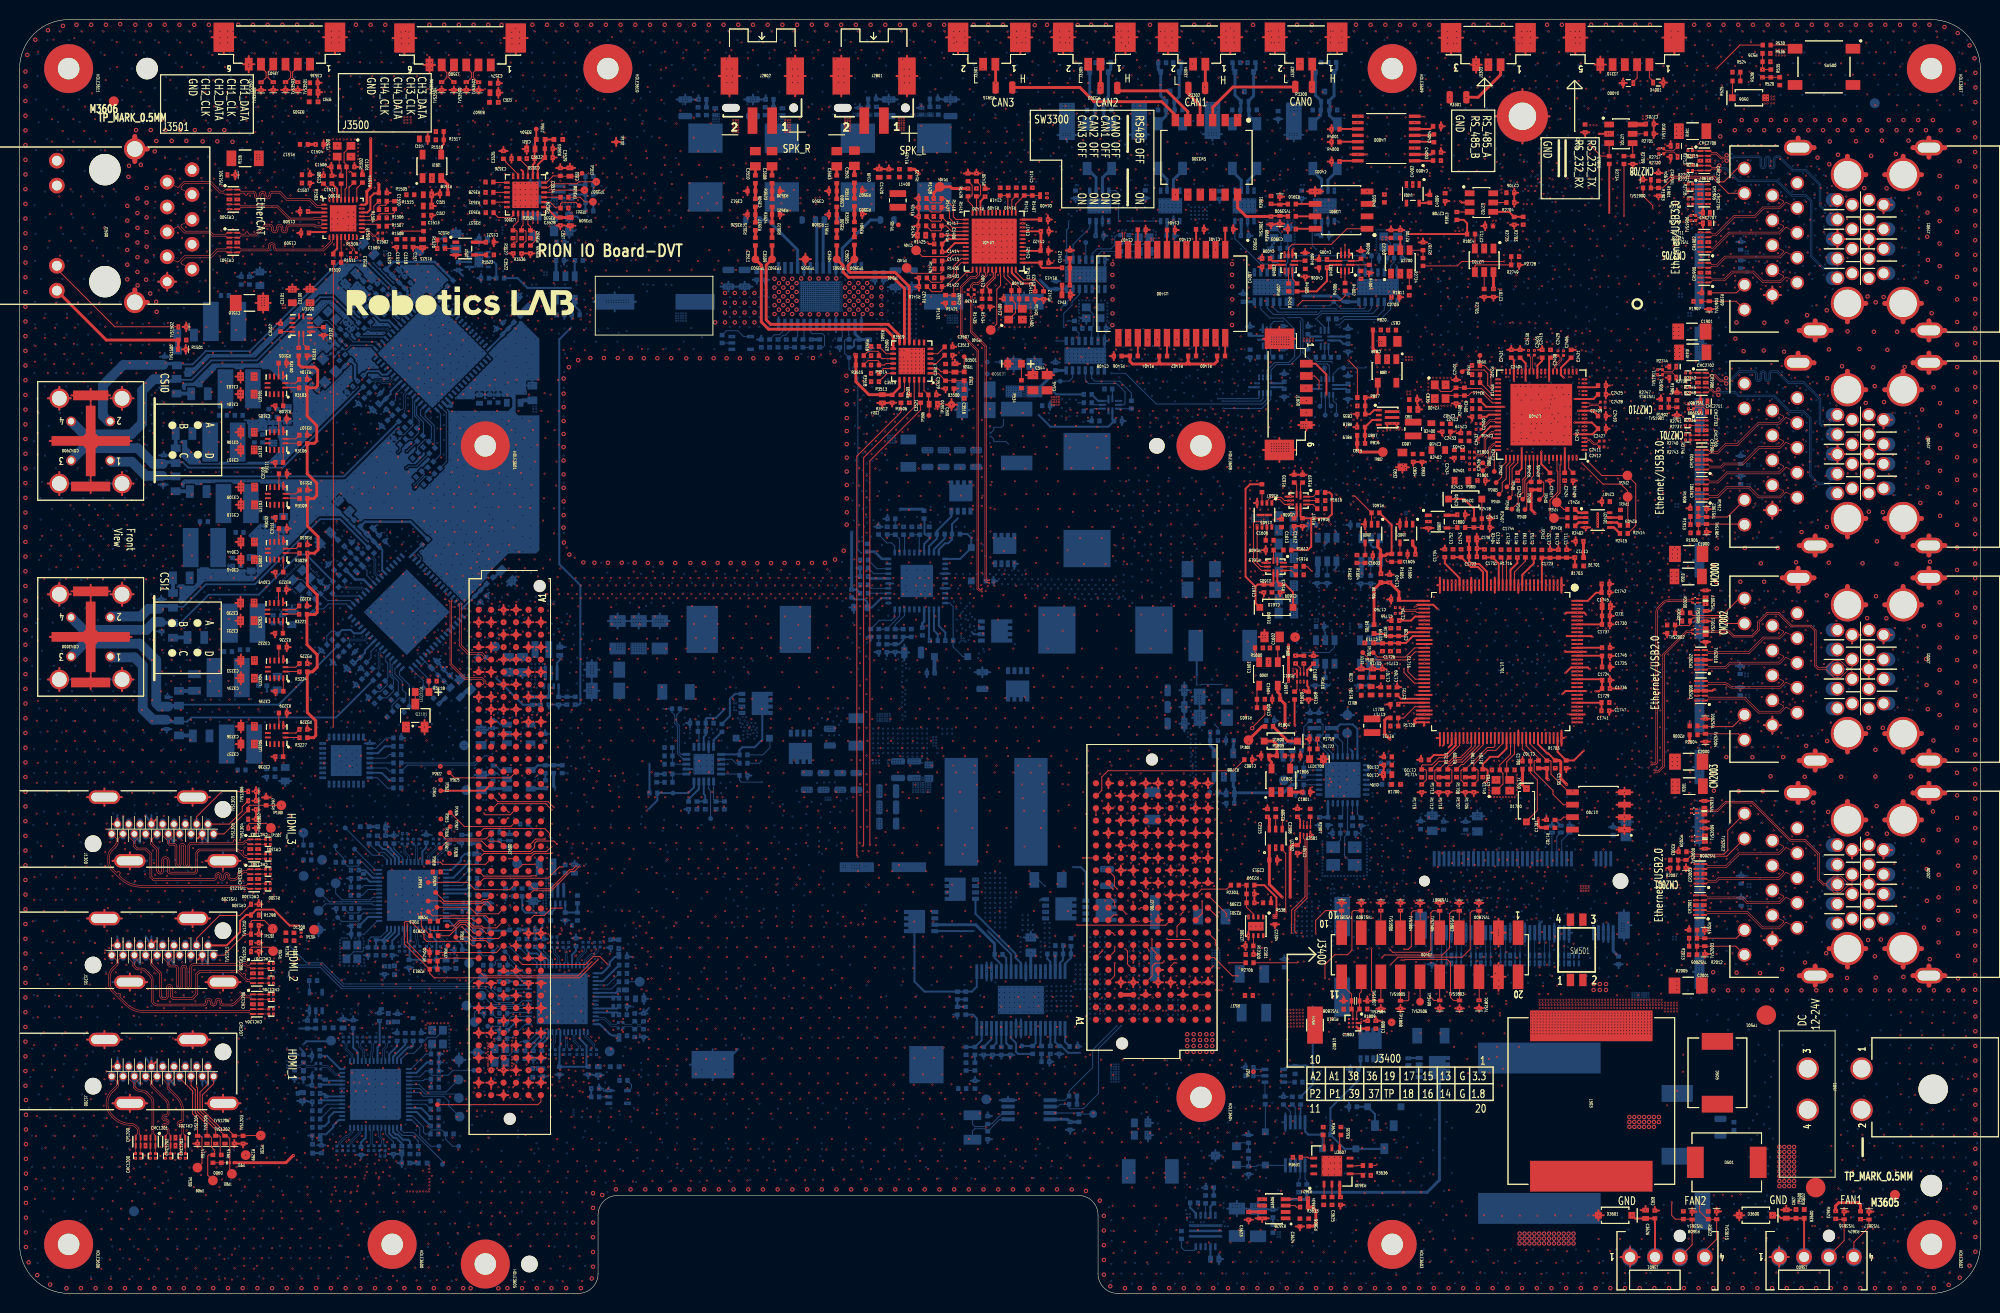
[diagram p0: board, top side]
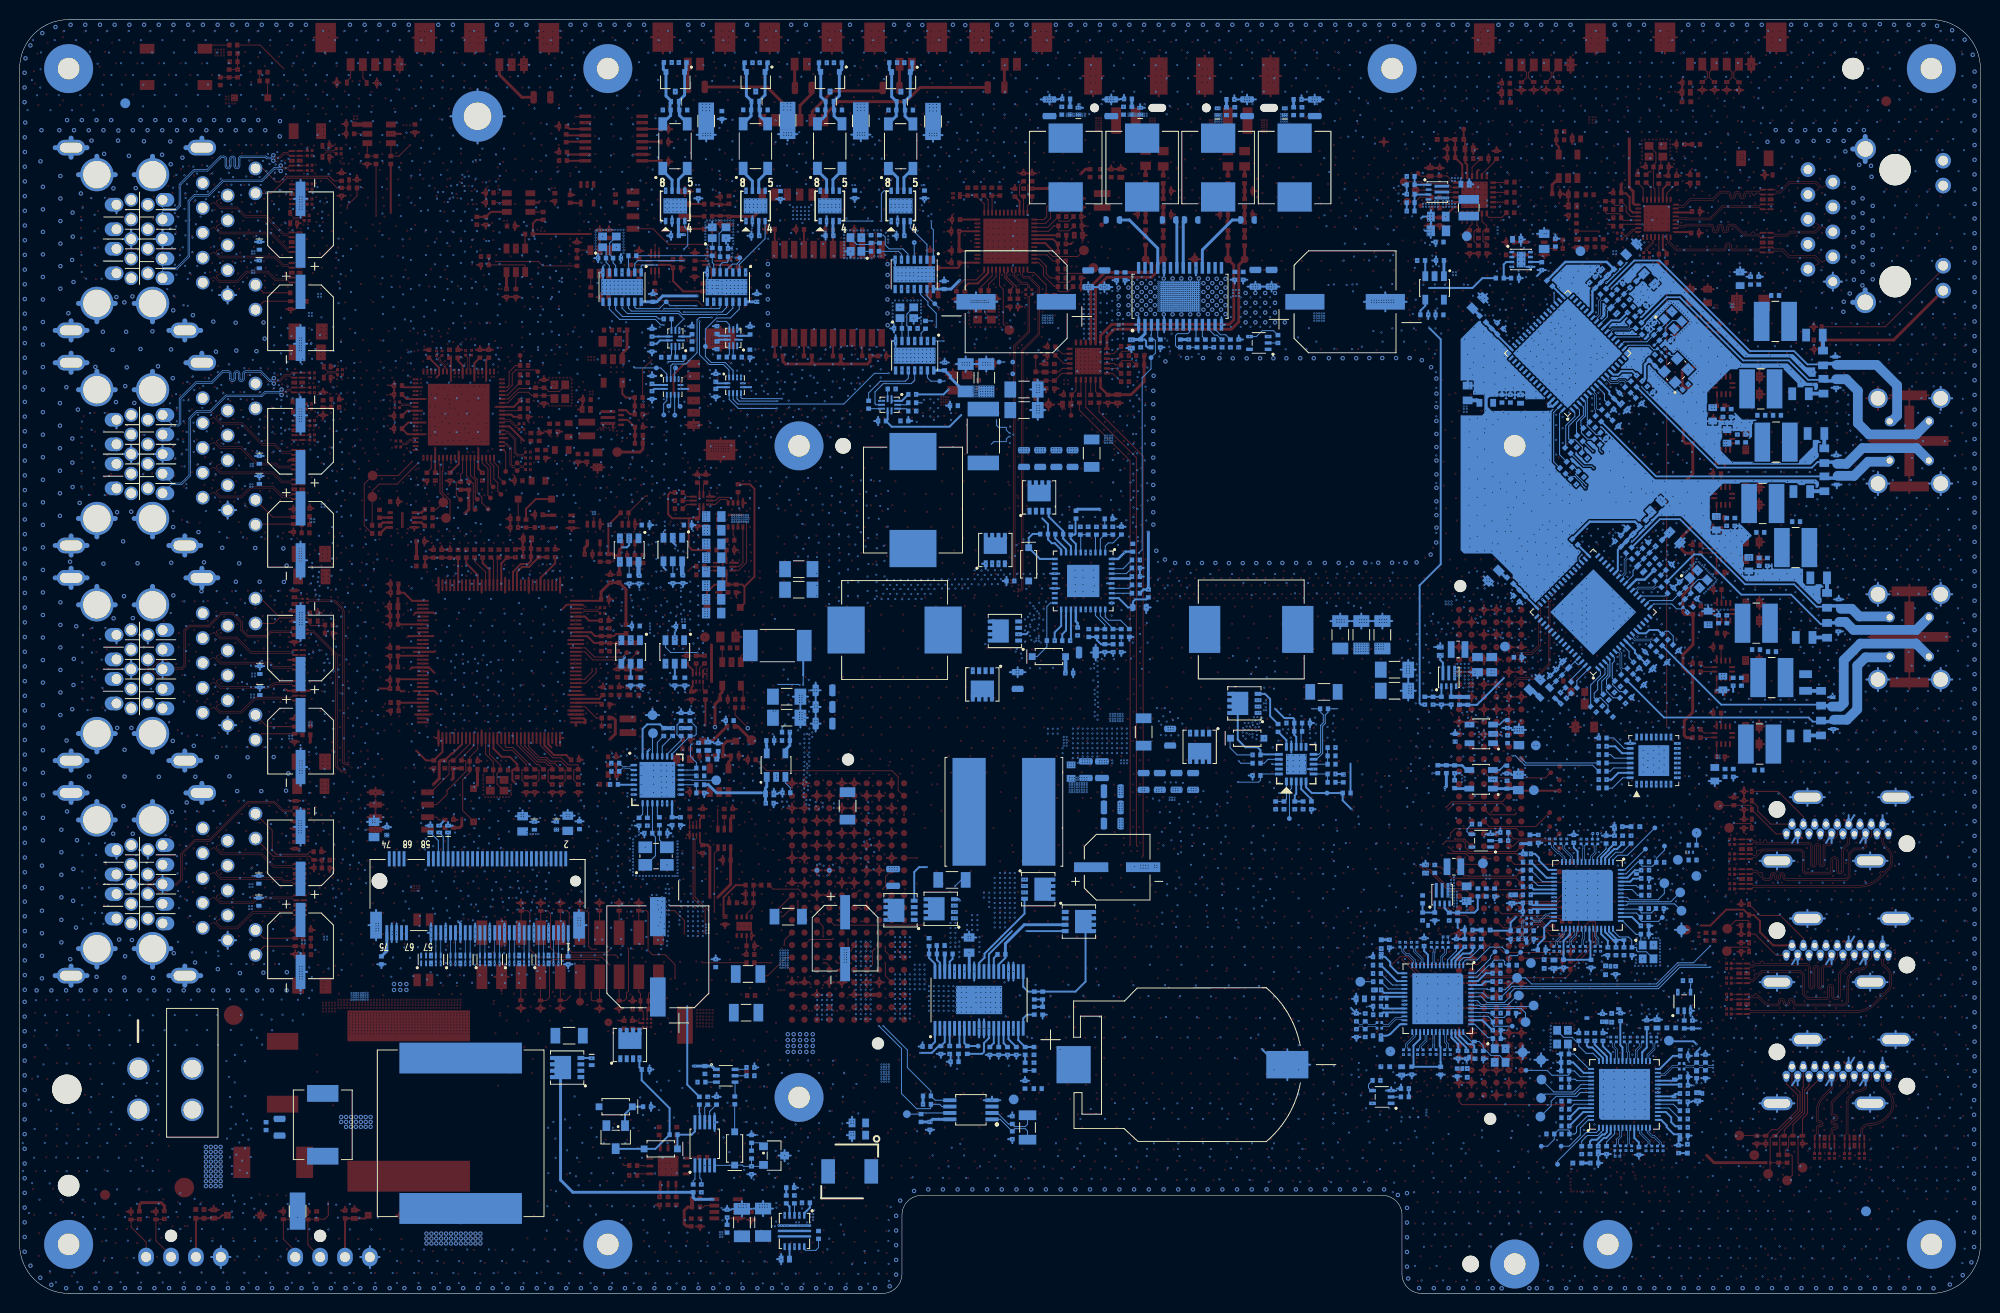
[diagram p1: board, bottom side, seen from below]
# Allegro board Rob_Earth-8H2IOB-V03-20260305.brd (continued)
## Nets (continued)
USB2_HUB_RESET: C2522.1 R2511.2 U2503.17
USB2_HUB_SCL: TP2502.1(\TP\) U2503.18
USB2_HUB_SDA: TP2501.1(\TP\) U2503.26
USB2_HUB_V5: C2501.2 C2502.1 R2511.1 U2500.1(\VOUT\) U2503.27
USB2_OVCUR1#: R2515.2 U2501.3 U2503.25
USB2_OVCUR2#: R2514.2 U2502.3 U2503.24
USB2_OVCUR3#: R2513.2 U2503.20 U2504.3
USB2_OVCUR4#: R2512.2 U2503.19 U2505.3
USB2_PWR_EN_1P8: J2600.B40 R2500.1
USB2_VBUS1: C2505.1 CT2500.1 J2001.U1 TVS2500.2 U2501.1(\OUT\)
USB2_VBUS2: C2511.1 CT2501.1 J2001.U10 TVS2501.2 U2502.1(\OUT\)
USB2_VBUS3: C2515.1 CT2502.1 J2000.U1 TVS2502.2 U2504.1(\OUT\)
USB2_VBUS4: C2521.1 CT2503.1 J2000.U10 TVS2503.2 U2505.1(\OUT\)
USB3_HUB_EN_1P8: J2700.B4 R817.1
USB3_PON: C835.1 R817.2 R818.1 U807.1 U808.4
USB3_VBUS1: C2703.1 CT1901.1 J1900.U1 TVS1914.2 U2700.1(\OUT\)
USB3_VBUS2: C2705.1 CT1903.1 J1900.U10 TVS1917.2 U2701.1(\OUT\)
USB3_VBUS3: C2708.1 CT1900.1 J1901.U1 TVS1915.2 U2702.1(\OUT\)
USB3_VBUS4: C2711.1 CT1902.1 J1901.U10 TVS1916.2 U2703.1(\OUT\)
USB_3_PORT1_EN: R2707.1 R2724.1 U2700.4
USB_3_PORT2_EN: R2709.1 R2734.1 U2701.4
USB_3_PORT3_EN: R2703.1 R2725.1 U2702.4
USB_3_PORT4_EN: R2728.1 R2749.1 U2703.4
USB_HUB_THERM: J2600.D28 RT2400.1
USB_RESET_1P8: J2600.C29 U1800.2
USBDP0+: R2412.2 TP1802.1(\TP\) U2400.55
USBDP0-: R2413.2 TP1803.1(\TP\) U2400.56
USBSUS: TP2408.1(\TP\) U2400.64
V_3P3_PER_VCC: C505.2 C507.2 D503.1 D504.1 U500.15 U500.16
V_3P3_PER_VDDA: C503.2 R508.1 R509.1 R511.1 U500.36
V_5P0_SW1: C508.2 L501.2 Q502.5 Q502.6 Q502.7 Q502.8 Q504.1 Q504.2 Q504.3(\S3\) U500.21
V_SW_CAM_7P0: C613.1 L600.1 Q600.1 Q600.2 Q600.3(\S3\) Q601.5 Q601.6 Q601.7 Q601.8 U600.16
VDCIN_9_30V: F501.2 J2700.A1 J2700.B1 J2700.C1 J2700.D1 J2700.E1 J2700.F1 J2700.G1 J2700.H1 J2700.I1 J2700.J1
VL_VCC10I: B2400.1 B2402.1 C815.1 C832.1 C833.1 C834.1 L803.2 R816.1 TP802.1(\TP\)
VL_VCC10I_F: B2402.2 C2426.2 C2427.1 C2428.1 C2429.1 C2430.1 C2431.1 C2432.1 C2433.1 C2434.1 U2400.5 U2400.8 U2400.14 U2400.27 U2400.33 U2400.36 U2400.51 U2400.54
VL_VCC33I: B2401.1 C837.1 C838.1 C2407.1 D2400.2(\C\) R1811.1 R1812.1 R1813.1 R1814.1 R2401.1 R2402.1 R2403.1 R2404.1 R2405.1 R2406.1 R2410.1 U808.1(\VOUT\) U2401.8
VL_VCC33I_F: B2401.2 C2420.2 C2421.1 C2422.1 C2423.1 C2424.1 C2425.1 U2400.17 U2400.24 U2400.46 U2400.62 U2400.73
VL_VDD: B2400.2 C2414.2 C2415.1 C2416.1 C2417.1 C2418.1 C2419.1 U2400.11 U2400.30 U2400.48(\VDD_C\) U2400.67
VREG_1P0: B2902.2 B3001.2 C2915.1 C3010.1 C3201.1 C3202.1 C3203.1 C3210.1 L3200.2 R3201.1 TP3200.1(\TP\)
VREG_1P2: B2903.1 B3003.1 C2924.1 C3024.1 C3209.1 U3202.5(\OUT\)
VREG_5P0_EN_9_30V: J2600.A40 TP2630.1(\TP\)
VREG_5P0_PGOOD: J2700.F7
VREG_AMP_24P0: C702.1 C704.1 C710.2 C2696.1 C2697.1 C2698.1 C2699.1 C2802.1 C2803.1 C2804.1 C2805.1 C2825.1 C2826.1 C2827.1 C2828.1 CT701.1 CT2700.1 CT2701.1 Q702.5 Q702.6 Q702.7 Q702.8 R707.1 U700.20 U2800.15 U2800.16 U2800.27 U2800.28
VREG_CAM_EN: R600.1 U600.20 U3104.20
VREG_CAM_POC_6P7: C615.2 C616.1 C617.1 C618.1 C619.1 C620.1 C801.1 C802.1 C3044.1 C3100.1 C3103.1 C3106.1 C3109.1 C3230.1 C3233.1 C3236.1 JP601.1 L800.1 R605.2 R607.1 R899.1 U800.12 U3002.5 U3002.6 U3002.7 U3100.5 U3100.6 U3100.7 U3101.5 U3101.6 U3101.7 U3102.5 U3102.6 U3102.7 U3103.5 U3103.6 U3103.7 U3203.5 U3203.6 U3203.7 U3204.5 U3204.6 U3204.7 U3205.5 U3205.6 U3205.7
VREG_EDP_1P0: B900.1 B903.1 B1000.1 B1003.1 B1100.1 B1103.1 C810.1 C811.1 C812.1 C813.1 JP902.1 JP904.1 JP905.1 JP1002.1 JP1004.1 JP1005.1 JP1102.1 JP1104.1 JP1105.1 L801.2 R805.1 TP805.1(\TP\)
VREG_EDP_3P3: B901.1 B902.1 B1001.1 B1002.1 B1101.1 B1102.1 C824.1 C825.1 JP903.1 JP1003.1 JP1103.1 R932.2 R933.2 R1029.2 R1031.2 R1131.2 R1133.2 TP806.1(\TP\) U804.4 U805.1(\VOUT\) U902.5 U1001.5 U1101.5
VREG_FAN_12V: B3600.2 C803.1 C804.1 R800.1 U800.8(\VOUT\)
VREG_MDPX3_1P8: C546.1 C1521.2 C1605.2 C1607.2 C1800.1 C2307.2 C2313.2 C2808.1 C3112.1 C3113.1 C3425.1 C3429.1 C3432.1 C3435.1 C3438.1 C3623.1 C4006.1 C4007.1 C4009.1 J2700.I3 J2700.J3 J3400.20 Q1400.1 R500.2 R925.1 R1028.1 R1130.1 R1506.2 R1521.1 R1602.1 R1609.1 R1610.1 R1611.1 R1802.2 R1803.2 R2307.1 R2309.2 R2807.1 R3410.2 R3413.2 R3631.1 R4002.2 R4010.2 U504.1 U1502.5 U1602.5 U1604.1 U1800.5 U2301.1 U2302.1 U2803.8 U3104.27(\VCCP\) U3104.31 U3406.7 U3408.7 U3410.7 U3412.2 U3412.8 U3414.2 U3414.8 U3606.7 U4001.7 U4002.7 U4003.5
VREG_NVME_3P3: C2300.2 C2302.2 C2303.2 C2306.2 C2308.2 C2314.2 C2315.2 CN2300.2 CN2300.4 CN2300.12 CN2300.14 CN2300.16 CN2300.18 CN2300.70 CN2300.72 CN2300.74 TVS2306.2 TVS2309.2 U2300.7(\VOUT_2\) U2300.8 U2301.8(\VCCB\) U2302.6(\VCCB\)
VREG_SIP_3P3: J2700.F3 J2700.G3 R537.2
VREG_SPX3_1P8: J2700.C3 J2700.D3
VREG_SUB_1P8: B3502.1 B3505.1 C807.1 C827.1 C828.1 C829.1 C2800.1 C2801.1 C2838.1 C3204.1 C3208.1 C3514.1 C3515.2 C3527.1 C3528.2 L802.2 R812.1 R2800.2 R2805.2 R2816.1 R2817.1 R2818.2 R3515.1 R3516.1 R3527.2 R3532.1 R3534.1 TP801.1(\TP\) U2800.2 U2805.5 U3201.1 U3201.2 U3202.1 U3500.19 U3501.19
VREG_SUB_3P3: B3500.1 B3503.1 C509.2 C510.1 C511.1 C512.1 C513.1 C544.1 C545.1 C808.1 C809.1 C823.1 C826.1 C831.1 C836.1 C1514.1 C1600.1 C1803.1 C1808.1 C2304.1 C3200.1 C3400.2 C3407.2 C3414.2 C3419.2 C3424.2 C3426.1 C3430.1 C3431.2 C3433.1 C3434.2 C3436.1 C3437.2 C3439.1 C3625.1 C3903.1 C4001.1 C4005.1 C4008.1 J3400.1 JP505.1 R506.2 R515.1 R532.1 R534.2 R896.1 R898.1 R1515.1 R1809.2 R1810.2 R2399.1 R3606.1 R3608.1 R3622.1 R3623.1 R3624.1 R3627.1 R3628.1 R3629.1 R3630.1 R3901.2 R4003.2 U802.7(\VIN\) U805.5 U806.7(\VIN\) U807.7(\VIN\) U808.5 U1501.5 U1600.5 U1802.A3(\VCC\) U2300.1 U2300.2 U2300.4 U3200.7(\VIN\) U3201.4 U3400.5 U3402.5 U3404.5 U3405.5 U3406.6(\VCCB\) U3407.14 U3408.6(\VCCB\) U3409.14 U3410.6(\VCCB\) U3411.14 U3412.1(\VCCB\) U3413.14 U3414.1(\VCCB\) U3607.3(\VDD\) U3901.8(\VCC\) U4000.16(\VCC\) U4001.6(\VCCB\) U4002.6(\VCCB\)
VREG_SUB_5P0: B3602.2 C514.1 C515.1 C516.1 C517.1 C518.2 C524.1 C525.1 C526.1 C527.1 C537.1 C538.1 C539.1 C540.1 C820.1 C1801.1 C2500.2 C2503.2 C2509.2 C2513.2 C2519.2 C2700.2 C2701.2 C2706.2 C2707.2 C3401.2 C3408.2 C3415.2 C3420.2 JP502.1 R502.2 R504.1 R541.1 R3118.2 U804.5 U1801.1 U1801.3 U2500.5 U2501.6 U2502.6 U2504.6 U2505.6 U2700.6 U2701.6 U2702.6 U2703.6 U3400.3 U3402.3 U3404.3 U3405.3
VREG_SW_A_1P8: B2900.1 B2901.2 B3000.1 B3002.2 C2903.1 C2912.1 C3003.1 C3015.1 C3206.1 C3207.1 R3029.2 R3100.2 R3103.2 R3106.2 R3109.2 R3208.1 R3221.2 R3224.2 R3227.2 TP3201.1(\TP\) U3201.7(\VOUT_2\) U3201.8
N3044471: R2506.2 U2503.5
N3044743: R2509.1 U2503.8
N3044747: R2508.1 U2503.9
N3044805: C2518.1 R2505.1 Y2500.3
N22882278: B3000.2 C3004.1 C3005.1 C3006.1 C3007.1 U3000.8 U3000.24
N22883057: B3003.2 C3025.1 C3026.1 U3000.48
N22883753: L3006.1 L3007.2 R3020.2
N22883763: R3019.1 U3000.63
N22883931: C3038.2 R3023.2
N23918883: C501.1 CT501.1 F500.1 F501.1 Q506.5 Q506.6 Q506.7 Q506.8 R519.2 R523.1
N23919030: C500.2 C502.2 D500.1 L503.2 R514.1 R516.1
N23919032: D501.1 D505.2
N23963220: CN2300.1 R2300.2
N23963553: R2307.2 U2301.5
N23964057: CN2300.75 R2308.2
N23964138: R2309.1 U2302.5
N25168509: R3018.1 U3000.20(\XRES\)
N25169488: R3021.1 U3000.64
N25172249: L3007.1 R3022.1
N25173690: L3004.1 L3005.2 R3010.2
N25173784: C3031.2 R3011.2
N25174282: L3000.1 L3001.2 R3001.2
N25174288: L3001.1 R3000.1
N25174376: C3009.2 R3002.2
N25174453: L3002.1 L3003.2 R3004.2
N25174459: L3003.1 R3003.1
N25174547: C3023.2 R3006.2
N25176689: B3001.1 C3011.1 C3012.1 C3039.1 U3000.61 U3000.62
N25187975: L3200.1 U3200.6
N25188010: C3229.1 R3200.2 R3202.1 U3200.1
N25188016: C3210.2 R3201.2 R3203.1 U3200.3
N25188197: R3204.2 R3205.2 U3201.3
N25190337: C3033.1 R3005.1 R3015.2 Y3000.3
N25191057: R3208.2 U3202.3
N25264597: L2900.1 L2901.2 R2901.2
N25264603: L2901.1 R2900.1
N25264626: B2900.2 C2904.1 C2905.1 C2906.1 C2907.1 U2900.8 U2900.24
N25264845: C2909.2 R2902.2
N25264985: B2902.1 C2913.1 C2914.1 C2939.1 U2900.61 U2900.62
N25265127: L2902.1 L2903.2 R2904.2
N25265133: L2903.1 R2903.1
N25265238: B2903.2 C2922.1 C2923.1 U2900.48
N25265360: C2926.2 R2905.2
N25265700: C2931.2 R2908.2
N25265806: L2906.1 L2907.2 R2910.2
N25265812: L2907.1 R2909.1
N25265948: R2911.2 U2900.63
N25265950: R2912.1 U2900.20(\XRES\)
N25265958: C2938.2 R2914.2
N25265985: R2913.2 U2900.64
N25266143: C2941.1 R2915.2 R2920.1 Y2900.3
N25532487: C504.2 R502.1 U500.6
N25532507: C528.1 C529.1 C530.1 C531.1 C532.1 Q504.5 Q504.6 Q504.7 Q504.8 R517.2 U500.25
N25532654: C508.1 D503.2(\C\) U500.20
N25532696: C506.2 D504.2(\C\) U500.11
N25532700: C506.1 L502.1 Q501.1 Q501.2 Q501.3(\S3\) Q503.5 Q503.6 Q503.7 Q503.8 U500.10
N25532746: Q504.4 R503.2 U500.23
N25532752: R503.1 U500.22
N25532754: R505.1 U500.9
N25532756: Q501.4 R505.2 U500.8
N25532835: JP503.1 L501.1 R504.2
N25532881: JP504.1 L502.2 R506.1
N25533068: Q503.4 U500.12 U500.13
N25533142: JP503.2 U500.27
N25533144: JP504.2 U500.4
N25533146: JP502.2 U500.26
N25533148: JP505.2 U500.5(\VOUT2\)
N25533161: R509.2 U500.33
N25533188: R510.2 U500.34
N25533212: C522.2 R511.2 U500.32
N25533238: C523.2 U500.38
N25533248: R513.1 U500.37
N25533252: C521.2 R512.2
N25562945: C2399.2 R2301.2 R2303.2 R2399.2 U2300.3
N25563127: C2301.2 U2300.6
N25637659: C2811.2 L2800.1 U2800.26
N25637707: C2810.1 U2800.4(\VR_DIG\)
N25637709: C2811.1 U2800.25
N25637825: C2816.2 L2801.1 U2800.23
N25637856: C2816.1 U2800.22
N25637860: C2818.2 R2801.2
N25637862: C2819.2 R2802.2
N25637887: C2817.1 U2800.21
N25637889: C2817.2 L2802.1 U2800.20
N25638044: C2829.2 U2800.13
N25640522: C3405.1 CM3400.4 D3400.2 R3401.1 TVS3400.2
N25640641: C3404.1 CM3400.3 D3400.1 R3402.1 TVS3400.1
N25640986: C3412.1 CM3401.4 D3401.2 R3404.1 TVS3401.2
N25641163: C3411.1 CM3401.3 D3401.1 R3405.1 TVS3401.1
N25641540: C3417.1 CM3402.4 D3402.2 R3406.1 TVS3402.2
N25641678: C3416.1 CM3402.3 D3402.1 R3407.1 TVS3402.1
N25641706: CM3402.1 U3404.7
N25641715: CM3402.2 U3404.6
N25641918: C3422.1 CM3403.4 D3403.2 R3408.1 TVS3403.2
N25642005: C3421.1 CM3403.3 D3403.1 R3409.1 TVS3403.1
N25650762: R2502.1 U2500.3
N25684206: R3102.2 U3100.4
N25684210: C3102.1 U3100.12(\SST\)
N25684394: R3105.2 U3101.4
N25684398: C3105.1 U3101.12(\SST\)
N25684585: R3108.2 U3102.4
N25684589: C3108.1 U3102.12(\SST\)
N25684764: R3111.2 U3103.4
N25684768: C3111.1 U3103.12(\SST\)
N26057360: R4003.1 U3901.2 U3901.3 U4003.4(\Y\)
N26057362: R3909.1 U3901.7
N26057367: R3910.1 U3901.6
N26072794: L3005.1 R3009.1
N26101041: C608.1 C609.1 C610.1 C611.1 C612.1 Q600.5 Q600.6 Q600.7 Q600.8 R609.2 U600.19
N26101223: R601.1 U600.17
N26101225: Q600.4 R601.2
N26101344: JP600.1 L600.2 R605.1
N26101394: R606.1 U600.15
N26101396: Q601.4 R606.2
N26222143: R3509.2 U3500.21
N26222279: R3515.2 R3518.2 U3500.16
N26222312: R3516.2 R3519.2 U3500.15
N26222402: B3500.2 B3501.1 C3516.1 C3517.2 U3500.1
N26222404: B3501.2 C3518.1 C3519.2 TP3504.1(\TP\) U3500.2
N26222408: C3520.1 C3521.2 TP3506.1(\TP\) U3500.24
N26226644: C3513.1 U3500.3(\VREF\)
N26230034: R3528.1 U3501.7
N26230040: R3529.2 U3501.21
N26230064: R3530.2 TP3511.1(\TP\) U3501.20
N26230092: R3531.1 U3501.9
N26230149: R3532.2 R3535.2 U3501.16
N26230155: R3533.1 U3501.11
N26230181: R3534.2 R3536.2 U3501.15
N26230210: R3537.1 U3501.13
N26230251: B3503.2 B3504.1 C3529.1 C3530.2 U3501.1
N26230253: B3504.2 C3531.1 C3532.2 TP3512.1(\TP\) U3501.2
N26230259: C3533.1 C3534.2 TP3513.1(\TP\) U3501.24
N26233322: R3633.2 U3607.2
N26233345: R3634.2 U3607.1
N26766233: C3526.1 U3501.3(\VREF\)
N26865506: C3624.1 R3606.2 U3606.1 U3606.2(\VREF2\)
N26877401: B3505.2 C3535.1 C3536.2 J3501.1
N26878490: B3502.2 C3523.1 C3524.2 J3500.1
N26905827: C4000.2 U4000.1
N26905839: C4000.1 U4000.3
N26905984: C4002.2 U4000.2
N26906021: C4003.1 U4000.5
N26906023: C4003.2 U4000.4
N26906050: C4004.2 U4000.6
N26907161: R4002.1 U4001.10
N26907165: R4005.1 U4002.1
N26907248: R4007.2 U4002.9
N26907250: R4008.1 U4001.2
N26907266: R4009.1 U4002.2
N26908132: R4000.2 U4000.13
N26908161: R4001.2 U4000.11
N26911241: R2924.1 Y2901.3
N26968575: TP603.1(\TP\) U600.2(\SYNCOUT\)
N26969087: C622.1 R614.2
N27485617: C3221.1 U3202.4
N27611972: C3500.2 R3502.2 R3503.1
N27612003: R3500.2 R3503.2 R3504.2
N27612020: C3501.2 R3502.1
N27612030: C3502.1 R3504.1
N27612076: C3503.2 R3510.1
N27612078: C3505.1 R3505.1 R3510.2
N27612084: R3505.2 R3508.1 R3511.2
N27612090: C3504.1 R3511.1
N27617228: C3506.2 R3520.2 R3521.1
N27617259: R3517.2 R3521.2 R3522.2
N27617284: C3508.2 R3520.1
N27617294: C3509.1 R3522.1
N27617350: C3510.2 R3523.1
N27617352: C3512.1 R3523.2 R3524.1
N27617358: R3524.2 R3525.2 R3526.1
N27617364: C3511.1 R3525.1
N28164996: R3635.1 U3607.7
N28165018: R3636.1 U3607.5
N28259089: R3629.2 U3607.9
N28338469: L2904.1 L2905.2 R2907.2
N28338475: L2905.1 R2906.1
N28382907: C3205.2 U3201.6
N28694569: L801.1 U802.6
N28694641: C812.2 R805.2 R808.1 U802.3
N28935623: C1500.1 R1500.1 Y1500.3
N28935651: R1502.1 U1500.27
N28935686: R1514.1 U1500.25
N28935712: R1503.2 U1500.31
N28935736: R1504.2 R1505.2 R1506.1
N28935906: R1508.1 U1500.19
N28936678: R1517.2 R1519.2 U1501.4
N29048756: R810.1 U804.3
N29049508: C840.1 R821.2 R898.2 U805.4
N29049512: R811.1 U805.3
N29090177: R1518.1 U1501.3
N29092622: J1500.11 J1500.14 R1501.1 TVS1500.2
N29156376: D507.2 D509.1 Q505.1 Q505.2 Q505.3(\S3\) Q506.1 Q506.2 Q506.3(\S3\) Q507.2(\E\)
N29156483: R520.2 R528.1 R535.1 U501.4
N29156485: D506.2(\C\) R525.2
N29156487: R521.2 U501.8
N29156489: R522.2 U501.1
N29156491: R523.2 U501.9
N29156499: C548.1 D507.1 D508.1 Q505.4 Q506.4 Q507.3 R527.1
N29156545: D508.2(\C\) R527.2 U501.10
N29156638: C547.2 D502.2(\C\) R526.2 R713.1 U501.5 U506.2
N29156646: R528.2 R530.1 R535.2 R536.1 U501.3
N29156650: C541.2 U501.7
N29156654: D509.2(\C\) Q507.1 R531.1
N29299108: J1901.D2(\Y_LED2-\) R1909.2
N29318380: J2000.D4 R2009.2
N29318624: CM2001.4 J2000.U3 TVS2009.1
N29318627: CM2000.2 J2001.U3 TVS2007.1
N29318651: CM2001.3 J2000.U2 TVS2008.1
N29318675: CM2000.1 J2001.U2 TVS2006.1
N29318885: CM2002.2 J2001.U12 TVS2011.1
N29318891: CM2002.1 J2001.U11 TVS2010.1
N29328245: CM2003.2 J2000.U12 TVS2013.1
N29328252: CM2003.1 J2000.U11 TVS2012.1
N29438820: R526.1 SW500.1 SW500.2 SW501.3(\OUT2\) SW501.4
N29439271: D502.1 R529.1
N29439293: C543.1 R537.1 U504.6(\VCCB\)
N29453895: L802.1 U806.6
N29453921: C830.1 R813.2 U806.1
N29453925: C807.2 R812.2 R815.1 U806.3
N29475764: R529.2 U504.4
N29476525: R501.1 U504.3
N29490921: R2503.1 U2501.5
N29491037: R2504.1 U2502.5
N29491543: R2507.1 U2504.5
N29491659: R2510.1 U2505.5
N29503648: C2806.2 U2803.2(\XO\) Y2800.1
N29503654: C2807.1 U2803.1 Y2800.2
N29503692: R2807.2 TP2804.1(\TP\) U2803.7
N29503777: C2809.1 R2808.2 TP1801.1(\TP\) U2803.3
N29658683: LED500.1 R534.1
N29666807: R910.1 U902.2
N29726494: R2700.1 U2700.5
N29726501: R2701.1 U2701.5
N29727370: R2704.1 U2702.5
N29727381: R2705.1 U2703.5
N29750648: C542.2 R524.1 U501.2(\VIN\)
N29750654: R524.2 R525.1
N29949460: J2800.1 R1804.1 R2808.1 TP1800.1(\TP\)
N30025351: C1802.1 D1800.1 R1805.1 U1801.5(\OUT\)
N30026226: D1800.2(\C\) R1804.2
N30026266: R1805.2 R1806.1 U1801.4
N30153252: C551.2 R540.2
N30232657: C2820.2 L2803.1 U2800.17
N30232771: C2830.2 R2803.2
N30232773: C2831.2 R2804.2
N30232946: C2820.1 U2800.18
N30298891: R2811.2 U2800.7
N30298894: R2810.2 U2800.6
N30298956: R2813.2 U2800.8
N30299980: R2806.2 U2800.10
N30300002: R2809.2 U2800.11
N30393381: R1604.1 U1601.4(\Y\)
N30393629: R1606.1 U1602.4(\Y\)
N30452220: R1522.1 U1502.4(\Y\)
N30564062: R1702.1 U1700.7(\WP\)
N30564201: B1700.1 C1704.1 C1705.1 C1706.1 U1701.65 U1701.66
N30564853: C1754.1 U1701.36
N30564873: C1755.1 U1701.35
N30636806: R1609.2 U1604.5
N30639808: C1604.1 R1603.2 U1600.4
N30639812: R1600.1 U1600.3
N30640189: R1607.2 U1603.3(\WP#(IO2)\)
N30640191: R1608.2 U1603.7
N30676950: R1612.1 U1605.1 U1605.10
N30676977: R1613.2 U1605.8
N30676990: R1614.2 U1605.9
N30676992: R1615.1 U1605.2
N30678249: R1619.1 U1606.1
N30678261: R1616.1 U1606.10
N30678276: R1617.2 U1606.8
N30678289: R1618.2 U1606.9
N30678291: R1620.1 U1606.2
N30707263: R2402.2 U2401.3(\WP#(IO2)\)
N30707265: R2403.2 U2401.7
N30707303: R2415.1 U2401.5
N30717755: TP1700.1(\TP\) U1701.46
N30717758: TP1701.1(\TP\) U1701.45
N30726073: J1901.D4 R1901.2
N30726377: J1900.D4 R1900.2
N30729205: J2001.D4 R2000.2
N30751641: R900.1 U900.19
N30751669: R901.1 U900.18
N30751690: C900.2 U900.26
N30751718: C901.2 U900.27
N30751823: R902.2 U900.29
N30751825: R903.1 U900.14
N30751857: R904.2 U900.30
N30751859: R905.1 U900.13
N30751883: R906.1 U900.12
N30751915: R907.2 U900.32
N30751917: R908.1 U900.11
N30751941: R909.2 U900.33
N30751973: R912.2 U900.34
N30751975: R913.1 U900.9
N30752007: R916.2 U900.35
N30752009: R917.1 U900.8
N30752033: R918.1 U900.7
N30752065: R919.2 U900.37
N30752067: R920.1 U900.6
N30752096: R921.2 U900.38
N30752151: R923.1 U900.2
N30752212: R927.2 TP910.1(\TP\) U900.45
N30752214: C905.1 R930.1 U900.46
N30754322: B902.2 JP906.1 JP907.1 JP908.1
N30793598: R1000.1 U1000.19
N30793622: R1001.1 U1000.18
N30793642: C1000.2 U1000.26
N30793665: C1001.2 U1000.27
N30793799: R1002.2 U1000.29
N30793801: R1004.1 U1000.14
N30793832: R1003.2 U1000.30
N30793834: R1005.1 U1000.13
N30793858: R1006.1 U1000.12
N30793890: R1007.2 U1000.32
N30793892: R1008.1 U1000.11
N30793910: R1009.2 U1000.33
N30793943: R1010.2 U1000.34
N30793945: R1011.1 U1000.9
N30793976: R1012.2 U1000.35
N30793978: R1013.1 U1000.8
N30793996: R1014.1 U1000.7
N30794028: R1015.2 U1000.37
N30794030: R1016.1 U1000.6
N30794058: R1017.2 U1000.38
N30794088: R1019.1 U1000.2
N30794178: R1022.2 TP1008.1(\TP\) U1000.45
N30794180: C1005.1 R1025.1 U1000.46
N30794558: R1026.1 U1001.2
N30794934: B1002.2 JP1006.1 JP1007.1 JP1008.1
N30797093: R1100.1 U1100.19
N30797117: R1101.1 U1100.18
N30797137: C1100.2 U1100.26
N30797160: C1101.2 U1100.27
N30797294: R1102.2 U1100.29
N30797296: R1103.1 U1100.14
N30797327: R1104.2 U1100.30
N30797329: R1105.1 U1100.13
N30797353: R1107.1 U1100.12
N30797385: R1106.2 U1100.32
N30797387: R1108.1 U1100.11
N30797405: R1109.2 U1100.33
N30797438: R1110.2 U1100.34
N30797440: R1111.1 U1100.9
N30797471: R1112.2 U1100.35
N30797473: R1113.1 U1100.8
N30797491: R1116.1 U1100.7
N30797523: R1117.2 U1100.37
N30797525: R1118.1 U1100.6
N30797553: R1119.2 U1100.38
N30797583: R1121.1 U1100.2
N30797673: R1124.2 TP1110.1(\TP\) U1100.45
N30797675: C1105.1 R1127.1 U1100.46
N30798053: R1128.1 U1101.2
N30798429: B1102.2 JP1106.1 JP1107.1 JP1108.1
N30852150: C1400.2 U1401.41
N30852159: TP1400.1(\TP\) U1401.44
N30852169: C1402.2 U1401.40
N30852210: R1401.1 U1401.48
N30852304: R1403.2 R1405.2 TP1401.1(\TP\) U1401.34
N30852386: TP1402.1(\TP\) U1401.33
N30852519: R1409.2 R1410.2 U1401.15
N30852521: R1411.2 U1401.14
N30853432: C1419.1 C1420.2 L1400.2 R1423.1 R1433.1
N30857169: C1401.2 U1400.1
N30857171: R1400.1 U1400.24
N30857173: C1408.1 R1400.2 R1402.2 R1404.2 R1406.2
N30857225: C1403.2 U1400.4
N30857227: R1402.1 U1400.21
N30857281: C1404.2 U1400.7
N30857283: R1404.1 U1400.18
N30857337: C1407.2 U1400.10
N30857339: R1406.1 U1400.15
N31095396: R2932.2 Y2901.1
N31099799: TP1808.1(\TP\) U1802.B2
N31105694: R2520.2 U2503.1
N31105696: R2521.2 U2503.2
N31106810: R2414.1 U2401.6
N31107614: R2416.1 U2401.2
N31107623: R2417.1 U2401.1
N31159283: R541.2 R542.1 R543.1 R544.1
N31296332: C3428.1 U3407.5 Y3400.3
N31296338: C3427.1 U3407.6 Y3400.1
N31297683: R3410.1 U3406.1 U3406.10
N31297702: R3425.1 U3406.5
N31297725: R3411.1 U3406.2
N31298259: R3413.1 U3408.1 U3408.10
N31298276: R3426.1 U3408.5
N31298299: R3414.1 U3408.2
N31300206: R3415.2 U3410.1 U3410.10
N31300246: R3416.1 U3410.2
N31358356: C2305.1 U3411.6 Y2300.1
N31395223: CM3403.1 U3405.7
N31395227: CM3403.2 U3405.6
N31485203: R3417.2 U3406.8
N31485229: R3418.2 U3406.9
N31485280: R3419.2 U3408.8
N31485283: R3420.2 U3408.9
N31485344: R3421.2 U3410.8
N31485347: R3422.2 U3410.9
N31548918: LED1700.1 R1719.1
N31982573: C707.2 U700.35
N31982835: L700.1 R702.2 R703.2
N31984442: C708.2 U700.26
N31997478: C701.1 R701.1 U700.37
N31997490: C701.2 R702.1 U700.38
N32076436: C706.1 U700.1
N32076870: R706.1 U700.6
N32076881: C711.1 R706.2
N32077864: C709.1 C712.1 U700.18
N32077889: C709.2 R708.1
N32077903: R708.2 R2419.1
N32079044: C713.1 U700.16
N32079330: R709.1 U700.13
N32079511: R710.1 U700.14
N32079780: R711.1 U700.15
N32084044: C710.1 R707.2 R712.1 R2420.2
N32084048: R2420.1 U700.19
N32108396: R705.2 TP700.1(\TP\) U700.7
N32127800: C2309.1 U3411.5 Y2300.3
N32128039: R2302.2 U3411.3
N32228912: R2418.1 U1800.4(\Y\)
N32250526: C800.1 L800.2 U800.7
N32250530: C800.2 U800.13
N32250665: R800.2 R801.1 U800.5
N32250673: C805.2 U800.10
N32250693: R802.1 U800.1
N32250715: R804.1 U800.3
N32250719: R803.1 U800.4
N32250721: C806.2 R803.2
N32254929: L803.1 U807.6
N32254961: C815.2 R816.2 R819.1 U807.3
N32255823: R820.1 U808.3
N32292952: R3112.2 U3104.30
N32292976: R3113.2 U3104.29
N32293000: R3114.2 U3104.32
N32293024: R3115.2 U3104.28
N32293045: R3116.2 U3104.26
N32293152: LED3101.1 R3118.1
N32293162: LED3101.2(\C\) Q3101.3
N32294356: R3032.2 U3002.4
N32294360: C3049.1 U3002.12(\SST\)
N32294535: R3223.2 U3203.4
N32294539: C3232.1 U3203.12(\SST\)
N32294714: R3226.2 U3204.4
N32294718: C3235.1 U3204.12(\SST\)
N32294893: R3229.2 U3205.4
N32294897: C3238.1 U3205.12(\SST\)
N32410234: R713.2 R714.1 U506.1(\REF\)
N32517931: R4006.2 U4001.9
N32518810: R4004.1 U4001.1
N32518952: R4010.1 U4002.10
N32565853: J3400.15 TP3499.1(\TP\)
N33124736: C3498.1 R3499.2 Y3401.3
N33124752: R3498.2 Y3401.1
N33124868: R3499.1 U3409.5
N33124937: C3499.1 R3497.2 Y3402.3
N33124961: R3496.2 Y3402.1
N33125058: R3497.1 U3413.5

Pads without a net: CN2300 6 8 10 20 22 24 26 28 30 32 34 36 38 40 42 44 46 48 56 58 67 68 69; CR2304 1 2 9 10; J1200 14; J1201 14; J1300 14; J1500 1; J1900 1; J1901 1; J2000 1 U5 U6 U8 U9 U14 U15 U17 U18; J2001 1 U5 U6 U8 U9 U14 U15 U17 U18; J2700 A20 E6; J3310 3 4; M3602 1; M3603 1; M3605 1; M3606 1; SW3300 2 11; U500 39; U600 11; U700 2 5 8 9 21 24 28 33; U800 9; U802 2 4; U806 2 4; U807 2 4; U900 16; U902 1; U1000 16; U1001 1; U1100 16; U1101 1; U1401 16 17 18 19 20 21; U1500 26; U1502 1; U1601 1; U1602 1; U1701 47 50 51 52 55 56; U1800 1; U1802 C1 C2; U2805 1; U2900 13 14 15 16 19 28 29 30 31 32 34 38 39 49 50 51 52 53 54 55 56 57 58 59 60; U3000 13 14 15 16 19 28 29 30 31 32 34 38 39 49 50 51 52 53 54 55 56 57 58 59 60; U3002 11; U3100 11; U3101 11; U3102 11; U3103 11; U3104 18 19 21 22 23 24; U3200 2 4; U3203 11; U3204 11; U3205 11; U3407 8; U3409 3 8; U3411 8; U3413 3 8; U3500 6 7 8 9; U3607 11 12; U4000 12 14; U4003 1

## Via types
v1: diameter 0.2, hole 0.1, TOP to L3, 10075 vias
v2: diameter 0.4, hole 0.2, L3 to L6, 6783 vias
v3: diameter 0.2, hole 0.1, L6 to BOTTOM, 8825 vias
v4: diameter 0.2, hole 0.1, TOP to L2, 1068 vias
v5: diameter 0.2, hole 0.1, L2 to L3, 17 vias
v6: diameter 0.45, hole 0.25, TOP to BOTTOM, 976 vias
v7: diameter 0.2, hole 0.1, L7 to BOTTOM, 1684 vias
v8: diameter 0.2, hole 0.1, L6 to L7, 53 vias

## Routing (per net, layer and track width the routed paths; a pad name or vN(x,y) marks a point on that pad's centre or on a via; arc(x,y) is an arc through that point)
GND: length 3022.9
  TOP w0.072: 164.16,101.4 164.16,101.35
  TOP w0.1: 171.17,56.23 171.17,56.24 ; v1(105.84,100.38) 105.83,100.38
  TOP w0.2: 48.87,20.24 J2600.D40 ; J2600.D40 49.36,19.74 ; J2600.D40 49.86,20.24 ; J2600.D40 49.36,20.73 ; 114.37,44.44 J2700.E14 ; J2700.E14 115.36,44.44 ; J2700.E14 114.86,44.94 ; J2700.E14 114.86,43.95 ; 46.33,26.59 J2600.F35 ; J2600.F35 46.82,26.09 ; J2600.F35 46.82,27.08 ; J2600.F35 47.32,26.59 ; 48.87,59.61 J2600.D9 ; J2600.D9 49.86,59.61 ; J2600.D9 49.36,59.11 ; J2600.D9 49.36,60.1 ; 131.04,60.62 C1608.1 ; C1608.1 131.89,60.62 ; C1608.1 131.47,60.22 ; 153.29,117.35 NUT2301.1 ; NUT2301.1 150.51,120.13 ; NUT2301.1 153.29,122.91 ; NUT2301.1 156.07,120.13 ; 30,114.17 v4(29.6,114.17) 29.6,114.59 ; 187.74,85.66 J1900.U7 ; J1900.U7 189.5,85.66 ; J1900.U7 188.62,86.53 ; J1900.U7 188.62,84.78 ; 48.87,67.23 J2600.D3 ; J2600.D3 49.86,67.23 ; J2600.D3 49.36,67.72 ; J2600.D3 49.36,66.73 ; 6.87,38.27 J1201.G2 ; J1201.G2 10.42,38.27 ; J1201.G2 8.65,37.39 ; J1201.G2 8.65,39.14 ; J2700.I20 120.44,52.06 ; J2700.I20 119.94,51.57 ; J2700.I20 119.45,52.06 ; J2700.I20 119.94,52.56 ; 162.2,67.85 v1(162.2,68.28) ; v1(162.2,68.28) 162.6,68.28 ; v1(162.2,68.28) 162.2,68.7 ; 144.4,29.1 v4(144.85,29.1) ; v4(144.85,29.1) 144.85,28.72 ; v4(144.85,29.1) 145.3,29.1 ; v4(144.85,29.1) 144.85,29.48 ; 113.59,31.25 v1(113.59,31.74) ; v1(113.59,31.74) 113.1,31.74 ; v1(113.59,31.74) 114.09,31.74 ; v1(113.59,31.74) 113.59,32.24 ; 128.5,96.2 J1600.G1 ; J1600.G1 130.17,97.43 ; J1600.G1 126.82,97.43 ; J1600.G1 128.5,98.66 ; 142.55,90.79 v1(142.55,91.22) ; v1(142.55,91.22) 142.95,91.22 ; v1(142.55,91.22) 142.55,91.64 ; J2600.E8 48.09,61.37 ; J2600.E8 48.09,60.38 ; J2600.E8 47.6,60.88 ; J2600.E8 48.59,60.88 ; 143.84,112.57 143.84,112.12 C4009.2 ; 115.64,44.44 J2700.F14 ; J2700.F14 116.13,43.95 ; J2700.F14 116.63,44.44 ; J2700.F14 116.13,44.94 ; 118.18,45.71 J2700.H15 ; J2700.H15 118.67,46.21 ; J2700.H15 118.67,45.22 ; J2700.H15 119.17,45.71 ; 40.57,106.73 v1(41.1,106.73) ; v1(41.1,106.73) 41.1,106.31 ; v1(41.1,106.73) 41.62,106.73 ; 153.29,54.75 C1702.2 152.89,54.33 ; C1406.1 93.24,107.58 93.29,107.52 ; 128.29,79.01 v4(128.72,79.01) 128.72,79.41 ; J2700.C15 112.82,45.71 ; J2700.C15 111.83,45.71 ; J2700.C15 112.32,45.22 ; J2700.C15 112.32,46.21 ; 119.45,31.74 J2700.I4 ; J2700.I4 119.94,32.24 ; J2700.I4 120.44,31.74 ; 130.44,83.55 R1619.2 ; R1619.2 130.86,83.95 ; R1619.2 131.29,83.55 ; 161.8,89.12 v1(161.8,89.55) ; v1(161.8,89.55) 161.8,89.98 ; v1(161.8,89.55) 162.2,89.55 ; 27.25,58.81 v1(27.25,59.24) ; v1(27.25,59.24) 27.25,59.66 ; v1(27.25,59.24) 27.65,59.24 ; J2700.D19 114.09,50.79 ; J2700.D19 113.59,50.3 ; J2700.D19 113.59,51.29 ; J2700.D19 113.1,50.79 ; v1(167.66,123.57) 168.03,123.57 ; v1(167.66,123.57) 167.66,123.1 ; v1(167.66,123.57) 167.66,124.05 ; v1(167.66,123.57) 167.28,123.57 ; v1(27.12,122.82) 27.57,122.82 ; v1(27.12,122.82) 27.12,122.45 ; v1(27.12,122.82) 26.67,122.82 ; v1(27.12,122.82) 27.12,123.2 ; 142.5,66.28 U1701.44 144.05,66.28 ; 123.78,108.18 v1(123.78,108.61) ; v1(123.78,108.61) 124.18,108.61 ; v1(123.78,108.61) 123.78,109.03 ; 82.55,112.07 v1(82.55,112.5) ; v1(82.55,112.5) 82.15,112.5 ; v1(82.55,112.5) 82.55,112.93 ; C3512.2 74.25,112.93 ; C3512.2 74.25,112.07 ; C3512.2 73.85,112.5 ; 178.5,3.71 J3600.1 ; J3600.1 179.48,4.69 ; J3600.1 179.48,2.74 ; J3600.1 180.45,3.71 ; J2700.E3 114.86,30.97 ; J2700.E3 114.37,30.47 ; J2700.E3 115.36,30.47 ; 22.03,87.89 C3106.2 ; C3106.2 22.56,87.26 ; C3106.2 22.56,88.51 ; 53.17,36.25 J2600.A27 ; J2600.A27 53.17,37.24 ; J2600.A27 53.67,36.75 ; J2600.A27 52.68,36.75 ; 172.07,79.66 v1(172.07,80.04) ; v1(172.07,80.04) 172.52,80.04 ; v1(172.07,80.04) 172.07,80.41 ; v1(91.74,102.75) 91.74,103.18 ; v1(91.74,102.75) 91.74,102.32 ; v1(91.74,102.75) 91.34,102.75 ; 114.37,49.52 J2700.E18 ; J2700.E18 115.36,49.52 ; J2700.E18 114.86,49.03 ; J2700.E18 114.86,50.02 ; J3304.G2 118.37,128.2 ; J3304.G2 115.92,128.2 ; J3304.G2 117.14,126.53 ; CON2900.5 11.63,82.65 ; CON2900.5 10.45,81.47 ; CON2900.5 10.45,83.83 ; 42.45,110.98 v1(42.03,110.98) 42.03,111.5 ; 132.15,104.68 C4006.2 132.55,104.25 ; 51.9,36.25 J2600.B27 ; J2600.B27 51.41,36.75 ; J2600.B27 52.4,36.75 ; J2600.B27 51.9,37.24 ; 125.05,35.04 v4(125.05,35.47) ; v4(125.05,35.47) 124.65,35.47 ; v4(125.05,35.47) 125.05,35.89 ; 190.12,88.28 J1900.U4 191,89.16 ; TVS3501.1 28.37,123.2 ; TVS3501.1 27.92,122.82 ; TVS3501.1 28.82,122.82 ; TVS3501.1 28.37,122.45 ; v4(146.85,39.85) 147.3,39.85 ; v4(146.85,39.85) 146.85,39.47 ; v4(146.85,39.85) 146.85,40.23 ; v4(146.85,39.85) 146.4,39.85 ; v1(160.43,66.99) 160.34,67.08 U1701.119 157.82,67.08 157.8,67.1 ; 48.87,62.15 v1(49.36,62.15) ; v1(49.36,62.15) 49.36,62.64 ; v1(49.36,62.15) 49.36,61.65 ; v1(49.36,62.15) 49.86,62.15 ; 143.01,50.75 R1715.2 ; R1715.2 142.59,51.15 ; R1715.2 143.44,51.15 ; v1(23.37,125.45) 23.95,125.45 ; v1(23.37,125.45) 22.8,125.45 ; v1(23.37,125.45) 23.37,126.27 ; v1(23.37,125.45) 23.37,124.62 ; 9.27,91.35 CON2900.7 ; CON2900.7 10.45,90.17 ; CON2900.7 11.63,91.35 ; CON2900.7 10.45,92.53 ; 136.85,39.49 v4(136.85,39.87) ; v4(136.85,39.87) 136.4,39.87 ; v4(136.85,39.87) 136.85,40.24 ; v4(136.85,39.87) 137.3,39.87 ; TVS2004.1 171.95,59.02 ; TVS2004.1 171.5,58.64 ; TVS2004.1 172.4,58.64 ; R4009.2 131.54,106.19 ; R4009.2 130.69,106.19 ; R4009.2 131.12,106.59 ; R2701.2 166.68,118.77 ; R2701.2 166.68,117.92 ; R2701.2 167.08,118.34 ; 131.32,112.46 U3901.5 ; U3901.5 132.97,112.46 ; U3901.5 132.14,111.99 ; U3901.5 132.14,112.94 ; 52.68,58.34 J2600.A10 ; J2600.A10 53.67,58.34 ; J2600.A10 53.17,58.83 ; J2600.A10 53.17,57.84 ; J1300.G3 17.65,51.52 ; J1300.G3 15.87,50.65 ; J1300.G3 17.65,49.77 ; J1300.G3 19.42,50.65 ; 168.28,92.99 TVS1913.2 167.9,93.46 ; 25.42,122.82 v1(25.87,122.82) ; v1(25.87,122.82) 25.87,123.2 ; v1(25.87,122.82) 25.87,122.45 ; v1(25.87,122.82) 26.32,122.82 ; 26.88,88.36 v4(26.88,87.89) 27.16,87.89 ; v4(27.23,89.26) 27.63,89.26 ; v4(27.23,89.26) 27.23,88.83 ; v4(27.23,89.26) 27.23,89.68 ; 152.95,104.54 v1(152.95,104.97) 153.35,104.97 ; 51.9,60.38 J2600.B8 ; J2600.B8 51.41,60.88 ; J2600.B8 51.9,61.37 ; J2600.B8 52.4,60.88 ; 136.32,63.73 C1728.2 ; C1728.2 137.38,63.73 ; C1728.2 136.85,64.15 ; 128.5,84.86 J1600.G2 ; J1600.G2 128.5,87.31 ; J1600.G2 126.82,86.08 ; J1600.G2 130.17,86.08 ; 50.63,34.98 J2600.C28 ; J2600.C28 50.14,35.48 ; J2600.C28 50.63,35.97 ; J2600.C28 51.13,35.48 ; C1408.2 111.6,96.09 ; C1408.2 111.6,95.24 ; C1408.2 111.2,95.66 ; 27.25,65.53 v4(27.25,65.96) ; v4(27.25,65.96) 27.25,66.38 ; v4(27.25,65.96) 27.65,65.96 ; 22.01,93.57 C3103.2 ; C3103.2 22.54,92.95 ; C3103.2 22.54,94.2 ; LED500.2 101.31,94.88 ; LED500.2 100.78,95.46 ; LED500.2 100.26,94.88 ; LED500.2 100.78,94.31 ; v4(27.26,83.65) 27.66,83.65 ; v4(27.26,83.65) 27.26,84.08 ; v4(27.26,83.65) 27.26,83.23 ; J2600.D34 49.36,28.35 ; J2600.D34 49.36,27.36 ; J2600.D34 48.87,27.86 ; J2600.D34 49.86,27.86 ; 24.63,122.43 v1(24.63,122.8) ; v1(24.63,122.8) 24.17,122.8 ; v1(24.63,122.8) 24.63,123.18 ; v1(24.63,122.8) 25.08,122.8 ; v4(162.16,72.4) 162.56,72.4 ; v4(162.16,72.4) 162.16,72.83 ; v4(162.16,72.4) 162.16,71.98 ; 171.43,47.45 TVS2009.2 172.38,47.45 ; J1200.G1 11.25,20.28 ; J1200.G1 9.47,19.4 ; J1200.G1 13.03,19.4 ; J1200.G1 11.25,18.52 ; v1(97.6,114.3) 97.6,114.7 ; v1(97.6,114.3) 98.03,114.3 ; v1(97.6,114.3) 97.17,114.3 ; 13.9,23.61 J1200.8 13.44,23.73 ; 117.4,47.76 J2700.G17 ; J2700.G17 117.9,48.25 ; J2700.G17 117.4,48.75 ; J2700.G17 116.91,48.25 ; C2711.2 149.49,109.36 ; C2711.2 149.49,108.51 ; C2711.2 149.08,108.94 ; 49.92,106.14 v1(50.35,106.14) 50.35,105.74 ; J2700.F18 116.63,49.52 ; J2700.F18 116.13,50.02 ; J2700.F18 115.64,49.52 ; J2700.F18 116.13,49.03 ; 115.64,41.9 v1(116.13,41.9) ; v1(116.13,41.9) 116.13,42.4 ; v1(116.13,41.9) 116.63,41.9 ; v1(116.13,41.9) 116.13,41.41 ; 169.22,45.5 R2009.1 168.81,45.07 ; 78.03,124.24 J2802.G1 ; J2802.G1 79.11,126.32 ; J2802.G1 80.18,124.24 ; J2802.G1 79.11,122.17 ; 155.75,48.73 v4(155.75,48.33) 155.32,48.33 ; C4009.2 143.84,112.51 ; C4009.2 143.42,112.11 ; J2600.F2 46.82,68.99 ; J2600.F2 46.82,68 ; J2600.F2 46.33,68.5 ; J2600.F2 47.32,68.5 ; 49.36,69.27 J2600.D1 ; J2600.D1 49.86,69.77 ; J2600.D1 49.36,70.26 ; J2600.D1 48.87,69.77 ; J3310.G2 159.91,128.16 ; J3310.G2 157.46,128.16 ; J3310.G2 158.68,126.49 ; 126.82,128.21 J3302.G2 ; J3302.G2 128.04,126.53 ; J3302.G2 129.27,128.21 ; 119.45,49.52 J2700.I18 ; J2700.I18 119.94,50.02 ; J2700.I18 120.44,49.52 ; J2700.I18 119.94,49.03 ; 48.87,25.32 J2600.D36 ; J2600.D36 49.36,25.81 ; J2600.D36 49.36,24.82 ; J2600.D36 49.86,25.32 ; 7.25,90.97 CON2900.G2 ; CON2900.G2 5.27,91.65 ; CON2900.G2 9.23,91.65 ; CON2900.G2 7.25,92.33 ; v1(172.93,61.64) 172.87,61.64 arc(172.79,61.62) 172.73,61.58 172.65,61.5 CR2000.3 CR2000.8 ; v1(46.82,122.81) 47.27,122.81 ; v1(46.82,122.81) 46.82,122.43 ; v1(46.82,122.81) 46.82,123.18 ; v1(46.82,122.81) 46.37,122.81 ; 158.71,76.33 v1(158.71,76.76) ; v1(158.71,76.76) 158.71,77.18 ; v1(158.71,76.76) 158.31,76.76 ; v1(144.65,69.83) 144.2,70.28 U1701.34 142.58,70.28 v1(142.5,70.2) ; 18.64,46.32 J1300.17 18.18,46.44 ; 7.25,70.97 CON3000.G2 ; CON3000.G2 5.27,71.65 ; CON3000.G2 9.23,71.65 ; CON3000.G2 7.25,72.33 ; v4(117.4,31.74) 117.4,32.24 ; v4(117.4,31.74) 116.91,31.74 ; v4(117.4,31.74) 117.9,31.74 ; v4(117.4,31.74) 117.4,31.25 ; 139.49,70.83 C1750.2 ; C1750.2 139.89,71.25 ; C1750.2 139.89,70.4 ; 161.23,124.59 J3310.5 ; J3310.5 161.23,126.24 ; J3310.5 160.66,125.41 ; J3310.5 161.81,125.41 ; 51.9,68 J2600.B2 ; J2600.B2 52.4,68.5 ; J2600.B2 51.9,68.99 ; J2600.B2 51.41,68.5 ; J3601.1 165.25,3.71 ; J3601.1 164.27,2.73 ; J3601.1 163.29,3.71 ; J3601.1 164.27,4.68 ; v1(139.88,108.52) 140.31,108.52 ; v1(139.88,108.52) 139.45,108.52 ; v1(139.88,108.52) 139.88,108.92 ; J2600.B6 51.9,63.91 ; J2600.B6 51.9,62.92 ; J2600.B6 52.4,63.42 ; J2600.B6 51.41,63.42 ; 118.18,30.47 J2700.H3 ; J2700.H3 119.17,30.47 ; J2700.H3 118.67,30.97 ; 117.4,45.22 J2700.G15 ; J2700.G15 116.91,45.71 ; J2700.G15 117.4,46.21 ; J2700.G15 117.9,45.71 ; 172.44,71.75 TVS2007.2 171.49,71.75 ; 149.95,77.74 v4(149.95,78.17) ; v4(149.95,78.17) 149.95,78.59 ; v4(149.95,78.17) 150.35,78.17 ; D4000.2 163.56,124 ; D4000.2 163.18,123.52 ; D4000.2 163.93,123.52 ; D4000.2 163.56,123.05 ; 170.01,80.12 v1(170.41,80.12) 170.41,80.55 ; 133.83,117.09 v4(133.83,117.51) ; v4(133.83,117.51) 133.83,117.94 ; v4(133.83,117.51) 133.43,117.51 ; 171.37,50.27 TVS2013.2 172.32,50.27 ; 121.21,43.95 v1(121.21,44.44) ; v1(121.21,44.44) 121.22,44.25 121.22,43.93 ; v1(121.21,44.44) 121.71,44.44 ; v1(121.21,44.44) 120.72,44.44 ; v1(121.21,44.44) 121.21,44.94 ; J1200.G3 17.65,26.78 ; J1200.G3 19.43,25.9 ; J1200.G3 15.87,25.9 ; J1200.G3 17.65,25.02 ; 126.74,106.04 v1(126.74,105.62) 126.34,105.62 ; C1730.2 162.21,69.56 ; C1730.2 162.21,68.71 ; C1730.2 162.61,69.14 ; 87.47,90.88 v1(88,90.88) ; v1(88,90.88) 88,90.45 ; v1(88,90.88) 88.53,90.88 ; 148.07,73.06 U1701.24 148.07,71.51 ; v1(117.4,43.17) 117.4,43.67 ; v1(117.4,43.17) 117.4,42.68 ; v1(117.4,43.17) 116.91,43.17 ; v1(117.4,43.17) 117.9,43.17 ; v4(54.38,116.82) 54.78,116.82 ; v4(54.38,116.82) 54.38,117.24 ; v4(54.38,116.82) 54.38,116.39 ; 171.89,100.46 v1(172.34,100.46) ; v1(172.34,100.46) 172.34,100.08 ; v1(172.34,100.46) 172.79,100.46 ; v1(131.65,51.17) 132.05,51.17 ; v1(131.65,51.17) 131.65,51.59 ; v1(131.65,51.17) 131.65,50.74 ; 51.41,65.96 J2600.B4 ; J2600.B4 52.4,65.96 ; J2600.B4 51.9,66.45 ; J2600.B4 51.9,65.46 ; TVS1213.1 24.77,39.72 ; TVS1213.1 24.02,39.72 ; TVS1213.1 24.4,40.17 ; 54.37,115.49 v1(54.37,115.92) ; v1(54.37,115.92) 54.77,115.92 ; v1(54.37,115.92) 54.37,116.34 ; CON3000.7 10.45,72.53 ; CON3000.7 10.45,70.17 ; CON3000.7 9.27,71.35 ; CON3000.7 11.63,71.35 ; R1427.1 91.7,111.26 ; R1427.1 91.7,110.41 ; R1427.1 91.3,110.83 ; 118.67,50.3 J2700.H19 ; J2700.H19 118.18,50.79 ; J2700.H19 119.17,50.79 ; J2700.H19 118.67,51.29 ; 142.57,84.87 v4(142.15,84.87) 142.15,84.47 ; 29.35,64.71 v4(29.35,64.29) 29.75,64.29 ; 167.97,43.41 v4(168.37,43.41) 168.37,42.98 ; v1(24.4,36.67) 24.77,36.67 ; v1(24.4,36.67) 24.02,36.67 ; v1(24.4,36.67) 24.4,37.12 ; 50.63,69.27 J2600.C1 ; J2600.C1 50.14,69.77 ; J2600.C1 51.13,69.77 ; J2600.C1 50.63,70.26 ; v4(131.58,56.57) 131.58,57 ; v4(131.58,56.57) 131.58,56.14 ; v4(131.58,56.57) 131.18,56.57 ; v4(42.88,112.23) 42.88,112.65 ; v4(42.88,112.23) 42.88,111.8 ; v4(42.88,112.23) 42.48,112.23 ; 179.67,8.53 v4(180.2,8.53) ; v4(180.2,8.53) 180.2,8.95 ; v4(180.2,8.53) 180.73,8.53 ; 25.7,79.2 C3111.2 26.1,78.77 ; 110.56,46.98 J2700.B16 ; J2700.B16 111.55,46.98 ; J2700.B16 111.05,47.48 ; J2700.B16 111.05,46.49 ; 43.05,122.45 v1(43.05,122.82) ; v1(43.05,122.82) 42.6,122.82 ; v1(43.05,122.82) 43.05,123.2 ; v1(43.05,122.82) 43.5,122.82 ; 95.55,96.6 v1(95.15,96.6) 95.15,97.03 ; v1(121.21,49.52) 121.71,49.52 ; v1(121.21,49.52) 121.21,49.03 ; v1(121.21,49.52) 121.21,50.02 ; v1(121.21,49.52) 120.72,49.52 ; C3101.2 27.82,103 ; C3101.2 27.2,102.48 ; C3101.2 28.45,102.48 ; 94.5,128.19 J3301.G2 ; J3301.G2 95.72,126.52 ; J3301.G2 96.95,128.19 ; 20.75,30.89 J1201.G4 ; J1201.G4 18.97,31.77 ; J1201.G4 22.52,31.77 ; v1(112.32,31.74) 112.82,31.74 ; v1(112.32,31.74) 112.32,31.25 ; v1(112.32,31.74) 112.32,32.24 ; v1(112.32,31.74) 111.83,31.74 ; 51.41,58.34 J2600.B10 ; J2600.B10 52.4,58.34 ; J2600.B10 51.9,57.84 ; J2600.B10 51.9,58.83 ; 30.4,123.12 C3536.1 ; C3536.1 30.4,123.98 ; C3536.1 30.8,123.55 ; 28.62,109.99 C1508.2 ; C1508.2 28.22,110.42 ; C1508.2 28.62,110.84 ; 118.67,47.76 J2700.H17 ; J2700.H17 119.17,48.25 ; J2700.H17 118.18,48.25 ; J2700.H17 118.67,48.75 ; 51.41,21.51 J2600.B39 ; J2600.B39 51.9,21.01 ; J2600.B39 52.4,21.51 ; J2600.B39 51.9,22 ; 139.16,55.18 v4(139.16,54.76) 138.76,54.76 ; 139.43,60.12 C1717.2 139.83,59.69 ; v4(125.35,36.52) 125.35,36.94 ; v4(125.35,36.52) 125.35,36.09 ; v4(125.35,36.52) 125.05,36.52 ; J2600.C9 51.13,59.61 ; J2600.C9 50.63,60.1 ; J2600.C9 50.63,59.11 ; J2600.C9 50.14,59.61 ; C2425.2 161.8,93.08 ; C2425.2 162.2,92.65 ; C2425.2 161.8,92.22 ; 17.65,37.39 J1201.G3 ; J1201.G3 17.65,39.14 ; J1201.G3 15.87,38.27 ; J1201.G3 19.42,38.27 ; 138.03,74.87 C1603.1 138.03,75.72 ; 100.85,128.19 J3301.G1 ; J3301.G1 102.07,126.52 ; J3301.G1 103.3,128.19 ; 91.15,107.99 C1405.2 ; C1405.2 91.57,108.52 ; C1405.2 91.57,107.47 ; 53.17,28.63 J2600.A33 ; J2600.A33 53.67,29.13 ; J2600.A33 53.17,29.62 ; J2600.A33 52.68,29.13 ; 22.58,79.86 C3110.2 ; C3110.2 22.06,80.48 ; C3110.2 22.58,81.11 ; v4(175.4,7.97) 175.4,8.5 ; v4(175.4,7.97) 175.4,7.45 ; v4(175.4,7.97) 174.87,7.97 ; v4(175.4,7.97) 175.92,7.97 ; 148.4,39.85 v4(148.85,39.85) ; v4(148.85,39.85) 148.85,39.47 ; v4(148.85,39.85) 148.85,40.23 ; v4(148.85,39.85) 149.3,39.85 ; 130.72,103.77 v1(131.15,103.77) ; v1(131.15,103.77) 131.15,103.37 ; v1(131.15,103.77) 131.57,103.77 ; 138.4,39.87 TVS1806.1 ; TVS1806.1 139.3,39.87 ; TVS1806.1 138.85,40.24 ; TVS1806.1 138.85,39.49 ; 190.12,110.23 J1901.U4 191,111.11 ; 153.61,126.48 J3303.G1 ; J3303.G1 154.84,128.15 ; J3303.G1 152.39,128.15 ; 50.17,116.24 v1(50.17,115.82) 50.17,115.39 ; J2000.U7 188.62,42.63 ; J2000.U7 189.5,41.76 ; J2000.U7 188.62,40.88 ; J2000.U7 187.74,41.76 ; 168.05,66.95 R2001.1 167.65,67.38 ; J2600.C32 50.63,30.89 ; J2600.C32 50.14,30.4 ; J2600.C32 51.13,30.4 ; J2600.C32 50.63,29.9 ; v1(30.44,122.59) 30.86,122.59 ; v1(30.44,122.59) 30.44,122.06 ; v1(30.44,122.59) 30.44,123.11 ; 162.55,59.46 v4(162.15,59.46) 162.15,59.04 ; 132.14,105.52 C4005.2 132.54,105.94 ; 22.05,64.59 C3233.2 ; C3233.2 22.57,65.21 ; C3233.2 22.57,63.96 ; v1(87.68,114.75) 87.68,115.18 ; v1(87.68,114.75) 87.16,114.75 ; v1(87.68,114.75) 88.21,114.75 ; J2700.E20 115.36,52.06 ; J2700.E20 114.86,51.57 ; J2700.E20 114.86,52.56 ; J2700.E20 114.37,52.06 ; 52.68,65.96 J2600.A4 ; J2600.A4 53.17,66.45 ; J2600.A4 53.67,65.96 ; J2600.A4 53.17,65.46 ; CON2900.8 5.23,91.35 ; CON2900.8 4.05,90.17 ; CON2900.8 4.05,92.53 ; CON2900.8 2.87,91.35 ; v4(133.83,118.81) 133.83,119.24 ; v4(133.83,118.81) 133.43,118.81 ; v4(133.83,118.81) 133.83,118.39 ; 128.54,108.8 v1(128.54,109.17) ; v1(128.54,109.17) 128.09,109.17 ; v1(128.54,109.17) 128.54,109.55 ; v1(128.54,109.17) 128.99,109.17 ; 130.65,54.44 R1806.2 130.65,55.29 ; 47.6,29.13 J2600.E33 ; J2600.E33 48.09,28.63 ; J2600.E33 48.09,29.62 ; J2600.E33 48.59,29.13 ; 52.68,26.59 J2600.A35 ; J2600.A35 53.17,27.08 ; J2600.A35 53.17,26.09 ; J2600.A35 53.67,26.59 ; 158.18,53.59 C1735.2 157.75,53.19 ; J2700.B20 111.05,52.56 ; J2700.B20 111.55,52.06 ; J2700.B20 111.05,51.57 ; J1200.G2 10.43,25.9 ; J1200.G2 8.65,25.02 ; J1200.G2 8.65,26.78 ; J1200.G2 6.87,25.9 ; 98.98,100.3 R1434.2 99.4,100.7 ; J2600.B35 51.9,27.08 ; J2600.B35 52.4,26.59 ; J2600.B35 51.9,26.09 ; J2600.B35 51.41,26.59 ; 171.88,36.67 v1(171.88,37.05) ; v1(171.88,37.05) 171.88,37.42 ; v1(171.88,37.05) 172.33,37.05 ; J2700.I14 119.94,44.94 ; J2700.I14 119.94,43.95 ; J2700.I14 119.45,44.44 ; J2700.I14 120.44,44.44 ; 148.56,124.58 v1(148.56,125.4) ; v1(148.56,125.4) 148.56,126.23 ; v1(148.56,125.4) 149.14,125.4 ; v1(148.56,125.4) 147.99,125.4 ; 29.76,81.98 R3110.1 29.36,82.41 ; 144.76,50.74 v1(144.76,51.14) ; v1(144.76,51.14) 145.19,51.14 ; v1(144.76,51.14) 144.34,51.14 ; 10.45,61.47 CON3000.5 ; CON3000.5 11.63,62.65 ; CON3000.5 10.45,63.83 ; C2401.2 146.94,93.23 ; C2401.2 146.52,93.63 ; C2401.2 146.09,93.23 ; 29.32,95.3 R3101.1 29.75,95.7 ; TVS1306.1 24.11,51.68 ; TVS1306.1 23.74,51.23 ; TVS1306.1 24.49,51.23 ; TVS1306.1 24.11,50.78 ; v1(140.83,108.52) 140.83,108.92 ; v1(140.83,108.52) 140.4,108.52 ; v1(140.83,108.52) 141.26,108.52 ; U1802.A2 136.77,27.59 v1(136.85,27.67) ; 142.62,84.87 C834.2 ; C834.2 143.47,84.87 ; C834.2 143.05,84.47 ; v1(48.81,123.49) 48.8,123.5 C3524.1 ; J2700.C17 112.32,48.75 ; J2700.C17 112.32,47.76 ; J2700.C17 112.82,48.25 ; J2700.C17 111.83,48.25 ; 149.51,82.52 C2420.1 ; C2420.1 149.91,82.94 ; C2420.1 149.51,83.37 ; C3100.2 29.62,103 ; C3100.2 29,102.48 ; C3100.2 30.25,102.48 ; TVS1900.1 165.97,113.65 ; TVS1900.1 165.22,113.65 ; TVS1900.1 165.59,114.1 ; v1(163.7,48.61) 164.52,48.61 ; v1(163.7,48.61) 162.87,48.61 ; v1(163.7,48.61) 163.7,49.08 ; v1(163.7,48.61) 163.7,48.13 ; 111.83,43.17 J2700.C13 ; J2700.C13 112.32,43.67 ; J2700.C13 112.32,42.68 ; J2700.C13 112.82,43.17 ; 126.74,104.34 v1(126.74,104.77) 126.34,104.77 ; 191,67.2 J2001.U4 190.12,66.33 ; 142.85,39.47 v4(142.85,39.85) ; v4(142.85,39.85) 142.4,39.85 ; v4(142.85,39.85) 142.85,40.23 ; v4(142.85,39.85) 143.3,39.85 ; U1700.4 164.52,51.15 ; U1700.4 162.87,51.15 ; U1700.4 163.7,51.62 ; U1700.4 163.7,50.67 ; v4(128.27,44.23) 128.67,44.23 ; v4(128.27,44.23) 128.27,44.66 ; v4(128.27,44.23) 128.27,43.81 ; R1620.2 130.44,83.55 ; R1620.2 129.58,83.55 ; R1620.2 130.01,83.95 ; 166.74,114.34 R1901.1 ; R1901.1 167.59,114.34 ; R1901.1 167.17,114.74 ; J2600.B31 52.4,31.67 ; J2600.B31 51.41,31.67 ; J2600.B31 51.9,31.17 ; 52.68,34.21 J2600.A29 ; J2600.A29 53.17,34.7 ; J2600.A29 53.67,34.21 ; 22.01,68.66 C3231.2 ; C3231.2 22.54,68.03 ; C3231.2 22.54,69.28 ; v1(55.15,114.85) 55.58,114.85 ; v1(55.15,114.85) 54.72,114.85 ; v1(55.15,114.85) 55.15,115.25 ; v1(157.27,72.28) 157.27,73.06 ; v1(157.27,72.28) 157.55,72.28 ; v1(157.27,72.28) 157.27,71.51 ; 130.29,62.86 v1(130.29,63.23) ; v1(130.29,63.23) 130.29,63.61 ; v1(130.29,63.23) 130.02,63.23 ; 156.53,75.88 v4(156.1,75.88) 156.1,76.28 ; 159.25,118.49 C2705.2 ; C2705.2 160.11,118.49 ; C2705.2 159.68,118.09 ; J1500.10 15.98,103.25 ; J1500.10 15.05,104.18 ; J1500.10 15.05,102.33 ; J1500.10 14.12,103.25 ; v1(24.4,34.88) 24.77,34.88 ; v1(24.4,34.88) 24.02,34.88 ; v1(24.4,34.88) 24.4,34.43 ; v1(140.8,78.5) 140.8,79.03 ; v1(140.8,78.5) 140.45,78.5 ; v1(140.8,78.5) 140.8,77.98 ; v1(18.15,15.29) 18.15,15.66 ; v1(18.15,15.29) 18.15,14.91 ; v1(18.15,15.29) 17.7,15.29 ; 138.69,52.95 v1(139.11,52.95) ; v1(139.11,52.95) 139.11,53.48 ; v1(139.11,52.95) 139.11,52.42 ; J2600.C7 50.63,62.64 ; J2600.C7 50.63,61.65 ; J2600.C7 51.13,62.15 ; J2600.C7 50.14,62.15 ; 20.75,43.27 J1300.G4 ; J1300.G4 18.97,44.15 ; J1300.G4 22.52,44.15 ; 127.64,108.7 v1(127.64,109.1) ; v1(127.64,109.1) 128.07,109.1 ; v1(127.64,109.1) 127.22,109.1 ; 143.7,77.77 v1(143.7,78.12) ; v1(143.7,78.12) 144.22,78.12 ; v1(143.7,78.12) 143.17,78.12 ; 152.02,109.07 v4(152.45,109.07) ; v4(152.45,109.07) 152.87,109.07 ; v4(152.45,109.07) 152.45,108.67 ; v4(169.04,89.63) 169.04,90 ; v4(169.04,89.63) 168.59,89.63 ; v4(169.04,89.63) 169.49,89.63 ; v4(169.04,89.63) 169.04,89.25 ; J2600.E37 48.09,24.54 ; J2600.E37 48.09,23.55 ; J2600.E37 47.6,24.05 ; J2600.E37 48.59,24.05 ; J2600.E37 v1(48.09,24.64) ; 120.72,41.9 J2700.J12 ; J2700.J12 121.21,42.4 ; J2700.J12 121.71,41.9 ; 125.95,40.29 v4(125.95,39.87) 126.35,39.87 ; J2700.D13 113.59,43.67 ; J2700.D13 113.59,42.68 ; J2700.D13 113.1,43.17 ; J2700.D13 114.09,43.17 ; 154.87,96.3 v1(155.3,96.3) 155.3,96.7 ; 161.1,118.35 161.11,118.34 U2701.2 ; 177.9,101.89 J1901.10 ; J1901.10 179.66,101.89 ; J1901.10 178.78,102.77 ; J1901.10 178.78,101.01 ; 48.87,64.69 J2600.D5 ; J2600.D5 49.86,64.69 ; J2600.D5 49.36,65.18 ; J2600.D5 49.36,64.19 ; 191,45.26 J2000.U4 190.12,44.38 ; 41.63,118.35 v4(41.63,117.83) 41.63,117.3 ; 47.6,26.59 J2600.E35 ; J2600.E35 48.59,26.59 ; J2600.E35 48.09,27.08 ; J2600.E35 48.09,26.09 ; 117.83,108.1 v1(117.83,108.52) ; v1(117.83,108.52) 118.23,108.52 ; v1(117.83,108.52) 117.83,108.95 ; v1(95.05,90.7) 95.63,90.7 ; v1(95.05,90.7) 94.47,90.7 ; v1(95.05,90.7) 95.05,90.12 ; v1(95.05,90.7) 95.05,91.28 ; J2700.B18 111.55,49.52 ; J2700.B18 111.05,49.03 ; J2700.B18 110.56,49.52 ; J2700.B18 111.05,50.02 ; R2704.2 152.85,111.33 ; R2704.2 152.45,111.75 ; R2704.2 152.45,110.9 ; 158.88,82.95 v4(158.45,82.95) 158.45,82.55 ; 30.95,128.2 J3501.G1 ; J3501.G1 33.4,128.2 ; J3501.G1 32.17,126.52 ; 23.74,48.39 TVS1305.1 ; TVS1305.1 24.49,48.39 ; TVS1305.1 24.12,48.84 ; 141.57,75 C1605.1 141.57,75.85 ; 77.55,112.07 C3506.1 ; C3506.1 77.55,112.93 ; C3506.1 77.95,112.5 ; 165.85,8.92 v4(165.85,8.5) 165.32,8.5 ; 139.92,69.09 C1713.2 139.52,68.67 ; 131.66,46.43 v4(131.66,46.8) ; v4(131.66,46.8) 131.93,46.8 ; v4(131.66,46.8) 131.66,47.18 ; J2600.F4 47.32,65.96 ; J2600.F4 46.33,65.96 ; J2600.F4 46.82,66.45 ; C1414.1 92.76,107.1 v1(92.6,107.26) ; v4(27.25,78.06) 27.25,78.49 ; v4(27.25,78.06) 27.65,78.06 ; v4(27.25,78.06) 27.25,77.64 ; 116.91,40.63 J2700.G11 ; J2700.G11 117.4,40.14 ; J2700.G11 117.9,40.63 ; J2700.G11 117.4,41.13 ; 50.63,27.36 J2600.C34 ; J2600.C34 50.63,28.35 ; J2600.C34 51.13,27.86 ; J2600.C34 50.14,27.86 ; 13.9,48.35 J1300.8 13.44,48.47 ; 162.87,49.88 U1700.3 ; U1700.3 164.52,49.88 ; U1700.3 163.7,50.35 ; U1700.3 163.7,49.4 ; 9.4,35.52 J1201.2 9.97,36.09 ; 9.98,23.73 J1200.2 9.4,23.15 ; J2700.E12 115.36,41.9 ; J2700.E12 114.86,41.41 ; J2700.E12 114.86,42.4 ; J2700.E12 114.37,41.9 ; 26.06,66.95 v1(26.06,67.38) 25.66,67.38 ; v1(150.85,36.82) 151.57,36.82 ; v1(150.85,36.82) 150.85,38.24 ; v1(150.85,36.82) 150.85,35.39 ; v1(150.85,36.82) 150.12,36.82 ; J2700.J16 121.71,46.98 ; J2700.J16 120.72,46.98 ; J2700.J16 121.21,46.49 ; J2700.J16 121.21,47.48 ; 147.45,79.04 v1(147.45,79.47) ; v1(147.45,79.47) 147.45,79.89 ; v1(147.45,79.47) 147.85,79.47 ; 131.55,65.07 v1(131.97,65.07) ; v1(131.97,65.07) 131.97,65.47 ; v1(131.97,65.07) 132.4,65.07 ; 113.1,48.25 J2700.D17 ; J2700.D17 113.59,48.75 ; J2700.D17 113.59,47.76 ; J2700.D17 114.09,48.25 ; 93.5,92.13 v1(93.5,91.7) 93.9,91.7 ; 187.74,107.61 J1901.U7 ; J1901.U7 188.62,108.48 ; J1901.U7 189.5,107.61 ; J1901.U7 188.62,106.73 ; U1701.32 144.87,73.06 ; U1701.32 144.6,72.28 ; U1701.32 144.87,71.51 ; J2700.I16 120.44,46.98 ; J2700.I16 119.94,46.49 ; J2700.I16 119.94,47.48 ; J2700.I16 119.45,46.98 ; 172.12,69.65 v1(172.12,69.65) ; 142.5,66.68 U1701.43 144.05,66.68 ; 136.39,106.39 v1(136.82,106.39) ; v1(136.82,106.39) 136.82,106.79 ; v1(136.82,106.39) 137.24,106.39 ; 48.09,57.84 J2600.E10 ; J2600.E10 47.6,58.34 ; J2600.E10 48.59,58.34 ; J2600.E10 48.09,58.83 ; 29.62,97.88 v4(29.62,98.15) 30.1,98.15 ; 51.41,29.13 J2600.B33 ; J2600.B33 52.4,29.13 ; J2600.B33 51.9,29.62 ; J2600.B33 51.9,28.63 ; J2600.A2 53.17,68.99 ; J2600.A2 53.67,68.5 ; J2600.A2 53.17,68 ; J2600.A2 52.68,68.5 ; 83.81,122.17 J2801.G2 ; J2801.G2 82.73,124.24 ; J2801.G2 84.88,124.24 ; J2801.G2 83.81,126.32 ; 104.93,105.99 C1421.1 ; C1421.1 105.33,106.42 ; C1421.1 104.93,106.84 ; 129.1,81.31 v1(129.63,81.31) 129.63,81.59 ; 44.3,122.45 v1(44.3,122.82) ; v1(44.3,122.82) 43.85,122.82 ; v1(44.3,122.82) 44.3,123.2 ; v1(44.3,122.82) 44.75,122.82 ; v1(135.06,29.85) 135.06,30.3 ; v1(135.06,29.85) 134.68,29.85 ; v1(135.06,29.85) 135.43,29.85 ; 104.97,107.97 v4(104.97,108.39) ; v4(104.97,108.39) 104.97,108.82 ; v4(104.97,108.39) 105.37,108.39 ; 94.45,91.95 v1(94.45,92.35) 94.02,92.35 ; 100.37,101.93 C1409.2 99.97,101.5 ; v4(27.21,71.83) 27.21,72.25 ; v4(27.21,71.83) 27.61,71.83 ; v4(27.21,71.83) 27.21,71.4 ; 119.45,41.9 J2700.I12 ; J2700.I12 120.44,41.9 ; J2700.I12 119.94,42.4 ; J2700.I12 119.94,41.41 ; v4(173.1,8.37) 173.1,8.75 ; v4(173.1,8.37) 173.1,7.99 ; v4(173.1,8.37) 173.55,8.37 ; v4(138.85,29.07) 138.85,29.44 ; v4(138.85,29.07) 138.4,29.07 ; v4(138.85,29.07) 138.85,28.69 ; v4(138.85,29.07) 139.3,29.07 ; J2000.10 178.78,36.92 ; J2000.10 177.9,36.04 ; J2000.10 178.78,35.16 ; J2000.10 179.66,36.04 ; C1521.1 48.77,107.29 ; C1521.1 48.37,107.71 ; C1521.1 48.37,106.86 ; 7.25,81.67 CON2900.G1 7.25,83.03 ; 116.13,51.57 J2700.F20 ; J2700.F20 115.64,52.06 ; J2700.F20 116.63,52.06 ; J2700.F20 116.13,52.56 ; 126.74,7.29 v1(126.74,7.66) ; v1(126.74,7.66) 126.06,7.66 ; v1(126.74,7.66) 127.41,7.66 ; 116.13,46.49 J2700.F16 ; J2700.F16 116.63,46.98 ; J2700.F16 115.64,46.98 ; J2700.F16 116.13,47.48 ; U1601.3 137.24,79.02 ; U1601.3 136.89,78.5 ; U1601.3 137.24,77.97 ; 128.05,37.27 C2304.2 ; C2304.2 128.47,37.67 ; C2304.2 127.62,37.67 ; 136.05,89.73 v1(136.45,89.73) 136.45,89.3 ; 22.57,57.24 C3236.2 ; C3236.2 22.05,57.86 ; C3236.2 22.57,58.49 ; 107.17,101.37 v1(107.17,101.9) ; v1(107.17,101.9) 107.59,101.9 ; v1(107.17,101.9) 107.17,102.42 ; v1(159.81,65.45) 159.77,65.48 U1701.115 157.67,65.48 v1(157.6,65.55) ; 27.17,64.59 v4(26.9,64.59) 26.9,65.06 ; 22.01,91.77 C3104.2 ; C3104.2 22.54,92.4 ; C3104.2 22.54,91.15 ; 162.61,65.9 v1(162.21,65.9) 162.21,66.32 ; 135.86,106 v1(135.59,106) 135.59,106.53 ; v1(56.13,114.87) 56.66,114.87 ; v1(56.13,114.87) 55.6,114.87 ; v1(56.13,114.87) 56.13,115.29 ; 60.85,117.09 TP2702.1 ; TP2702.1 60.85,117.94 ; TP2702.1 61.27,117.52 ; TP2702.1 60.42,117.52 ; J3303.G2 147.24,128.15 ; J3303.G2 144.79,128.15 ; J3303.G2 146.01,126.48 ; v4(162.26,70.1) 162.69,70.1 ; v4(162.26,70.1) 162.26,70.62 ; v4(162.26,70.1) 162.26,69.57 ; v1(22,114.15) 22.38,114.15 ; v1(22,114.15) 22,114.6 ; v1(22,114.15) 21.62,114.15 ; v1(22,114.15) 22,113.7 ; 158.1,59.08 U1701.99 159.65,59.08 ; 20.82,126.52 J3501.G2 ; J3501.G2 22.05,128.2 ; J3501.G2 19.6,128.2 ; 138.76,53.93 v4(139.16,53.93) 139.16,53.5 ; 46.82,23.55 J2600.F37 ; J2600.F37 47.32,24.05 ; J2600.F37 46.33,24.05 ; J2600.F37 46.82,24.54 ; 30.57,97.8 v4(30.99,97.8) ; v4(30.99,97.8) 30.99,97.4 ; v4(30.99,97.8) 31.42,97.8 ; 91.71,109.47 R1424.1 ; R1424.1 91.31,109.9 ; R1424.1 91.71,110.32 ; 94.44,100.68 v1(94.44,101.08) 94.02,101.08 ; 167.22,8.45 v4(166.79,8.45) 166.79,8.85 ; CON3000.G3 11.43,67 ; CON3000.G3 7.25,70.78 ; CON3000.G3 7.25,63.22 ; CON3000.G3 3.07,67 ; 56.17,108.54 v1(56.17,108.97) ; v1(56.17,108.97) 55.64,108.97 ; v1(56.17,108.97) 56.7,108.97 ; 95.73,92.35 C3516.2 95.3,91.95 ; 22.05,56.06 C3237.2 ; C3237.2 22.57,56.69 ; C3237.2 22.57,55.44 ; 162.21,63.51 C1724.2 ; C1724.2 162.21,64.36 ; C1724.2 162.61,63.93 ; 127.77,61.06 C1600.2 127.77,60.21 ; 22.05,62.79 C3234.2 ; C3234.2 22.57,63.41 ; C3234.2 22.57,62.16 ; J2802.G2 72.41,126.32 ; J2802.G2 72.41,122.17 ; J2802.G2 71.33,124.24 ; J2802.G2 73.48,124.24 ; 140.5,62.27 C1721.2 140.93,61.87 ; 120.72,31.74 J2700.J4 ; J2700.J4 121.71,31.74 ; J2700.J4 121.21,32.24 ; 29.73,87.59 v4(29.33,87.59) 29.33,88.01 ; v4(128.54,111.92) 128.54,112.3 ; v4(128.54,111.92) 128.54,111.55 ; v4(128.54,111.92) 128.99,111.92 ; v1(82.55,110.1) 82.55,110.53 ; v1(82.55,110.1) 82.55,109.67 ; v1(82.55,110.1) 82.15,110.1 ; 26.86,94.05 v4(26.86,93.57) 27.14,93.57 ; J2600.A31 53.67,31.67 ; J2600.A31 52.68,31.67 ; J2600.A31 53.17,31.17 ; 145.95,87.55 C2419.2 146.38,87.95 ; 148.16,89.04 v4(148.16,89.47) 147.76,89.47 ; 48.87,32.94 J2600.D30 ; J2600.D30 49.86,32.94 ; J2600.D30 49.36,33.43 ; 137.27,116.24 v1(136.5,116.24) 135.72,116.24 ; 168.62,91.95 R1900.1 ; R1900.1 169.47,91.95 ; R1900.1 169.04,92.35 ; 105.22,128.2 J3305.G2 ; J3305.G2 106.44,126.52 ; J3305.G2 107.67,128.2 ; 27.14,70.46 v4(26.86,70.46) 26.86,70.93 ; 148.87,28.74 v4(148.87,29.11) ; v4(148.87,29.11) 148.87,29.49 ; v4(148.87,29.11) 148.42,29.11 ; v4(148.87,29.11) 149.32,29.11 ; J1300.G2 10.42,50.65 ; J1300.G2 6.87,50.65 ; J1300.G2 8.65,51.52 ; J1300.G2 8.65,49.77 ; 129.37,108.2 v1(129.37,108.62) ; v1(129.37,108.62) 129.37,109.05 ; v1(129.37,108.62) 128.97,108.62 ; 152.87,71.51 U1701.12 ; 171.59,102.54 v1(171.59,102.11) 171.19,102.11 ; v1(157.35,61.15) 157.68,61.48 v1(158.87,61.48) 159.77,61.48 v1(159.8,61.45) ; v1(171.89,34.63) 171.89,35.01 ; v1(171.89,34.63) 172.34,34.63 ; v1(171.89,34.63) 171.89,34.26 ; 125.86,35.01 v4(125.86,34.59) 126.26,34.59 ; 130.34,44.55 v4(130.34,44.95) 130.76,44.95 ; 25.68,90.59 C3105.2 26.08,90.16 ; 148.96,101.7 v4(149.39,101.7) ; v4(149.39,101.7) 149.81,101.7 ; v4(149.39,101.7) 149.39,101.3 ; 111.05,43.95 v1(111.05,44.44) ; v1(111.05,44.44) 110.56,44.44 ; v1(111.05,44.44) 111.05,44.94 ; v1(111.05,44.44) 111.55,44.44 ; 45.11,122.82 v1(45.56,122.82) ; v1(45.56,122.82) 45.56,122.45 ; v1(45.56,122.82) 46.01,122.82 ; v1(45.56,122.82) 45.56,123.2 ; 142.72,107.27 v1(143.15,107.27) ; v1(143.15,107.27) 143.57,107.27 ; v1(143.15,107.27) 143.15,107.67 ; J1201.G1 11.25,32.64 ; J1201.G1 11.25,30.89 ; J1201.G1 13.02,31.77 ; v4(42.03,112.13) 42.03,112.65 ; v4(42.03,112.13) 42.45,112.13 ; v4(42.03,112.13) 42.03,111.6 ; J2801.G1 90.51,126.32 ; J2801.G1 91.58,124.24 ; J2801.G1 90.51,122.17 ; J2801.G1 89.43,124.24 ; J2600.A37 53.67,24.05 ; J2600.A37 52.68,24.05 ; J2600.A37 53.17,24.54 ; J2600.A37 53.17,23.55 ; R1425.1 91.67,109.38 ; R1425.1 91.27,108.95 ; R1425.1 91.67,108.53 ; 140.85,39.49 v4(140.85,39.87) ; v4(140.85,39.87) 140.85,40.24 ; v4(140.85,39.87) 140.4,39.87 ; v4(140.85,39.87) 141.3,39.87 ; C2701.1 167.08,119.34 ; C2701.1 166.68,119.77 ; C2701.1 166.68,118.92 ; 156.96,76.29 v4(156.96,75.89) 156.53,75.89 ; C1412.2 107.13,106.84 ; C1412.2 106.71,106.44 ; C1412.2 107.56,106.44 ; 50.14,32.94 J2600.C30 ; J2600.C30 50.63,33.43 ; J2600.C30 51.13,32.94 ; v1(21.9,15.29) 22.35,15.29 ; v1(21.9,15.29) 21.9,14.91 ; v1(21.9,15.29) 21.9,15.66 ; 22.37,15.29 v1(22.8,15.29) ; v1(22.8,15.29) 23.22,15.29 ; v1(22.8,15.29) 22.8,14.88 ; J3500.G2 40.48,128.12 ; J3500.G2 39.26,126.45 ; J3500.G2 38.03,128.12 ; 140.4,29.07 v4(140.85,29.07) ; v4(140.85,29.07) 141.3,29.07 ; v4(140.85,29.07) 140.85,28.69 ; v4(140.85,29.07) 140.85,29.44 ; CON3000.8 5.23,71.35 ; CON3000.8 4.05,72.53 ; CON3000.8 4.05,70.17 ; CON3000.8 2.87,71.35 ; 161.8,87.82 v1(161.8,88.25) ; v1(161.8,88.25) 162.2,88.25 ; v1(161.8,88.25) 161.8,88.68 ; 144.95,75.94 v4(145.37,75.94) 145.37,76.34 ; v1(159.8,69.27) 159.58,69.48 v1(158.87,69.48) 157.78,69.48 157.65,69.35 ; J2600.D11 49.86,57.07 ; J2600.D11 49.36,56.57 ; J2600.D11 49.36,57.56 ; J2600.D11 48.87,57.07 ; C1612.2 131.28,78.3 ; C1612.2 130.43,78.3 ; C1612.2 130.86,77.9 ; v1(104.45,101.47) 104.87,101.47 ; v1(104.45,101.47) 104.02,101.47 ; v1(104.45,101.47) 104.45,101.07 ; 177.9,57.99 J2001.10 ; J2001.10 179.66,57.99 ; J2001.10 178.78,58.87 ; J2001.10 178.78,57.11 ; v4(149.42,75.92) 149.33,76.02 C1719.2 ; J2700.H13 119.17,43.17 ; J2700.H13 118.67,42.68 ; J2700.H13 118.67,43.67 ; J2700.H13 118.18,43.17 ; 22.05,74.89 C3045.2 ; C3045.2 22.57,75.52 ; C3045.2 22.57,74.27 ; CR1903.3 172.44,85.08 v1(172.6,84.92) ; 168.04,117.12 TVS1910.2 168.41,117.6 ; 118.18,40.63 J2700.H11 ; J2700.H11 118.67,41.13 ; J2700.H11 118.67,40.14 ; J2700.H11 119.17,40.63 ; J2600.E2 48.59,68.5 ; J2600.E2 48.09,68 ; J2600.E2 48.09,68.99 ; J2600.E2 47.6,68.5 ; 157.27,55.91 v1(157.27,56.68) ; v1(157.27,56.68) 157.55,56.68 ; v1(157.27,56.68) 157.27,57.46 ; v1(27.22,94.94) 27.22,95.37 ; v1(27.22,94.94) 27.62,94.94 ; v1(27.22,94.94) 27.22,94.52 ; v1(140.45,88.82) 140.45,88.42 v1(140.5,88.37) ; J1600.6 131.25,89.21 ; J1600.6 132.07,88.63 ; J1600.6 131.25,88.06 ; J1600.6 130.42,88.63 ; 161.04,7.44 v1(161.04,7.97) ; v1(161.04,7.97) 160.52,7.97 ; v1(161.04,7.97) 161.04,8.5 ; v1(161.04,7.97) 161.57,7.97 ; 125.95,40.34 C2399.1 ; C2399.1 125.95,41.19 ; C2399.1 126.35,40.77 ; 46.33,63.42 J2600.F6 ; J2600.F6 46.82,63.91 ; J2600.F6 47.32,63.42 ; 150.47,71.51 U1701.18 150.47,73.06 ; J2600.A6 53.67,63.42 ; J2600.A6 53.17,63.91 ; J2600.A6 53.17,62.92 ; J2600.A6 52.68,63.42 ; v1(85.95,110.15) 85.95,110.58 ; v1(85.95,110.15) 86.35,110.15 ; v1(85.95,110.15) 85.95,109.72 ; 46.33,21.51 J2600.F39 ; J2600.F39 47.32,21.51 ; J2600.F39 46.82,22 ; J2600.F39 46.82,21.01 ; 124.94,7.52 v1(125.36,7.52) ; v1(125.36,7.52) 125.36,7.12 ; v1(125.36,7.52) 125.79,7.52 ; U2702.2 147.08,111.33 v1(146.95,111.47) ; U1701.68 146.07,56.04 145.75,55.72 ; 40.56,106.78 v1(40.14,106.78) 40.14,106.38 ; 42,109.6 v1(42,110.03) 42.4,110.03 ; 49.36,29.9 J2600.D32 ; J2600.D32 49.36,30.89 ; J2600.D32 49.86,30.4 ; J2600.D32 48.87,30.4 ; 112.79,126.52 J3305.G1 ; J3305.G1 114.02,128.2 ; J3305.G1 111.57,128.2 ; 170.3,37.51 R2015.1 169.9,37.09 ; 133.42,115.51 v4(133.82,115.51) ; v4(133.82,115.51) 133.82,115.09 ; v4(133.82,115.51) 133.82,115.94 ; J3400.19 150.85,33.74 ; J3400.19 151.57,32.32 ; J3400.19 150.12,32.32 ; J3400.19 150.85,30.89 ; J2700.C19 112.82,50.79 ; J2700.C19 112.32,50.3 ; J2700.C19 112.32,51.29 ; J2700.C19 111.83,50.79 ; 136.03,88.41 R819.2 136.43,88.83 ; 149.91,101.7 v4(150.34,101.7) ; v4(150.34,101.7) 150.76,101.7 ; v4(150.34,101.7) 150.34,101.3 ; 126.74,74.57 v1(127.27,74.57) 127.27,74.85 ; 95.55,95.75 v1(95.15,95.75) 95.15,95.32 ; C1516.1 25.62,101.09 ; C1516.1 24.84,102.09 ; C1516.1 24.84,100.09 ; C1516.1 24.07,101.09 ; 167.41,91.68 R1905.1 167,91.25 ; 146.52,90.43 C2402.2 ; C2402.2 146.09,90.83 ; C2402.2 146.94,90.83 ; J2700.D15 114.09,45.71 ; J2700.D15 113.59,45.22 ; J2700.D15 113.59,46.21 ; J2700.D15 113.1,45.71 ; 24.4,37.14 v1(24.4,37.57) 24.8,37.57 ; 11.25,43.27 J1300.G1 ; J1300.G1 11.25,45.02 ; J1300.G1 9.47,44.15 ; v1(153.05,96.3) 153.05,96.7 ; v1(153.05,96.3) 153.48,96.3 ; v1(153.05,96.3) 152.62,96.3 ; J2600.A8 53.67,60.88 ; J2600.A8 52.68,60.88 ; J2600.A8 53.17,60.38 ; J2600.A8 53.17,61.37 ; v4(31.8,114.97) 31.8,115.39 ; v4(31.8,114.97) 31.8,114.54 ; v4(31.8,114.97) 31.4,114.97 ; C1504.2 31.4,117.27 ; C1504.2 31,117.69 ; C1504.2 31,116.84 ; J2600.E39 48.09,22 ; J2600.E39 47.6,21.51 ; J2600.E39 48.09,21.01 ; J2600.E39 48.59,21.51 ; R3517.1 77.95,110.1 ; R3517.1 77.55,109.67 ; R3517.1 77.55,110.53 ; 16.95,95.9 v1(16.95,96.35) ; v1(16.95,96.35) 17.33,96.35 ; v1(16.95,96.35) 16.57,96.35 ; v1(16.95,96.35) 16.95,96.8 ; J3500.G1 51.83,128.12 ; J3500.G1 50.61,126.45 ; J3500.G1 49.38,128.12 ; 41.81,124.55 J3500.6 ; J3500.6 42.38,125.37 ; J3500.6 41.23,125.37 ; J3500.6 41.81,126.2 ; 169.97,43.06 v4(169.97,43.44) ; v4(169.97,43.44) 170.42,43.44 ; v4(169.97,43.44) 169.97,43.81 ; 104,101.46 v1(103.58,101.46) 103.58,101.06 ; 94.05,90.75 v1(93.62,90.75) 93.62,90.22 ; v1(145.66,51.14) 146.09,51.14 ; v1(145.66,51.14) 145.24,51.14 ; v1(145.66,51.14) 145.66,50.74 ; 34.15,115.39 v4(34.15,114.97) 34.55,114.97 ; 130.16,6.84 C3624.2 ; C3624.2 130.59,6.44 ; C3624.2 131.01,6.84 ; C3230.2 22.54,71.08 ; C3230.2 22.54,69.83 ; C3230.2 22.01,70.46 ; 26.19,98.97 v1(26.62,98.97) 26.62,99.37 ; 162.21,64.63 C1725.2 162.61,65.06 ; 155.67,82.95 C2417.2 ; C2417.2 156.53,82.95 ; C2417.2 156.1,82.55 ; 51.9,23.55 J2600.B37 ; J2600.B37 51.9,24.54 ; J2600.B37 51.41,24.05 ; J2600.B37 52.4,24.05 ; v1(16.99,98.64) 17.37,98.64 ; v1(16.99,98.64) 16.99,99.09 ; v1(16.99,98.64) 16.62,98.64 ; v1(16.99,98.64) 16.99,98.19 ; 164.12,115.27 v4(164.55,115.27) ; v4(164.55,115.27) 164.97,115.27 ; v4(164.55,115.27) 164.55,114.87 ; J2700.E16 114.86,47.48 ; J2700.E16 115.36,46.98 ; J2700.E16 114.37,46.98 ; J2700.E16 114.86,46.49 ; 25.7,61.45 v1(26.1,61.45) 26.1,61.03 ; J2600.F8 46.82,61.37 ; J2600.F8 47.32,60.88 ; J2600.F8 46.82,60.38 ; J2600.F8 46.33,60.88 ; 142.5,67.88 U1701.40 144.05,67.88 ; J2600.B29 51.9,34.7 ; J2600.B29 51.41,34.21 ; J2600.B29 52.4,34.21 ; 125.9,80.67 v4(126.23,80.67) ; v4(126.23,80.67) 126.23,81.12 ; v4(126.23,80.67) 126.23,80.22 ; 116.13,32.52 J2700.F5 116.63,33.01 ; 172.06,77.34 v1(172.06,77.71) ; v1(172.06,77.71) 172.06,78.09 ; v1(172.06,77.71) 172.51,77.71 ; 120.72,52.06 J2700.J20 ; J2700.J20 121.21,51.57 ; J2700.J20 121.21,52.56 ; J2700.J20 121.71,52.06 ; 146.42,29.09 v4(146.87,29.09) ; v4(146.87,29.09) 146.87,29.47 ; v4(146.87,29.09) 147.32,29.09 ; v4(146.87,29.09) 146.87,28.72 ; TP3505.1 80.73,105.55 ; TP3505.1 80.15,106.13 ; TP3505.1 79.57,105.55 ; TP3505.1 80.15,104.97 ; 96.31,114.3 v1(96.74,114.3) ; v1(96.74,114.3) 96.74,114.7 ; v1(96.74,114.3) 97.16,114.3 ; 9.97,48.47 J1300.2 9.4,47.9 ; v1(41.31,57.8) 41.88,57.8 ; v1(41.31,57.8) 41.31,57.08 ; v1(41.31,57.8) 41.31,58.53 ; v1(41.31,57.8) 40.73,57.8 ; TVS2505.1 144.85,40.23 ; TVS2505.1 144.85,39.47 ; TVS2505.1 145.3,39.85 ; TVS2505.1 144.4,39.85 ; 171.97,66.12 171.97,66.49 ; 171.97,66.49 172.45,66.49 ; 171.97,66.49 171.5,66.49 ; v1(144.97,119.11) 145.37,119.11 ; v1(144.97,119.11) 144.97,119.54 ; v1(144.97,119.11) 144.97,118.69 ; TVS3614.1 171.05,8.35 ; TVS3614.1 170.6,7.97 ; TVS3614.1 170.6,8.72 ; J2600.A39 53.17,22 ; J2600.A39 52.68,21.51 ; J2600.A39 53.17,21.01 ; J2600.A39 53.67,21.51 ; 31.85,114.47 v4(31.85,114.07) 32.27,114.07 ; R1297.2 25.57,50.62 ; R1297.2 24.72,50.62 ; R1297.2 25.15,51.02 ; 46.33,31.67 J2600.F31 ; J2600.F31 46.82,31.17 ; J2600.F31 47.32,31.67 ; TVS1807.2 137.85,29.85 ; TVS1807.2 137.47,30.3 ; TVS1807.2 137.09,29.85 ; J2600.C36 51.13,25.32 ; J2600.C36 50.14,25.32 ; J2600.C36 50.63,24.82 ; J2600.C36 50.63,25.81 ; v1(114.86,108.55) 114.86,108.97 ; v1(114.86,108.55) 114.86,108.12 ; v1(114.86,108.55) 115.26,108.55 ; C1727.2 138.53,63.73 ; C1727.2 138,64.15 ; C1727.2 137.47,63.73 ; 125.72,54.05 v1(125.72,54.47) ; v1(125.72,54.47) 126.12,54.47 ; v1(125.72,54.47) 125.72,54.9 ; v1(51.35,114.02) 51.35,114.49 51.17,114.67 ; 129.91,49.45 v4(130.34,49.45) ; v4(130.34,49.45) 130.34,49.85 ; v4(130.34,49.45) 130.76,49.45 ; C1802.2 126.65,55.29 ; C1802.2 126.65,54.44 ; C1802.2 126.25,54.87 ; CON2900.G3 11.43,87 ; CON2900.G3 7.25,83.22 ; CON2900.G3 3.07,87 ; CON2900.G3 7.25,90.78 ; 50.63,64.19 J2600.C5 ; J2600.C5 51.13,64.69 ; J2600.C5 50.14,64.69 ; J2600.C5 50.63,65.18 ; 48.09,65.46 J2600.E4 ; J2600.E4 48.59,65.96 ; J2600.E4 48.09,66.45 ; J2600.E4 47.6,65.96 ; 187.74,63.7 J2001.U7 ; J2001.U7 188.62,62.83 ; J2001.U7 189.5,63.7 ; J2001.U7 188.62,64.58 ; 161,80.8 C2407.2 ; C2407.2 161.4,80.38 ; C2407.2 161.4,81.23 ; 13.44,36.09 J1201.8 13.9,35.97 ; 171.37,48.17 TVS2012.2 172.32,48.17 ; 146.57,87.8 C2433.2 147,88.2 ; C1719.2 v4(148.64,75.18) ; C1719.2 v4(148.69,76.07) v1(148.69,76.94) ; 126.49,71.55 v1(126.91,71.55) 126.91,71.15 ; v1(163.7,47.34) 163.7,47.81 ; v1(163.7,47.34) 164.52,47.34 ; v1(163.7,47.34) 162.87,47.34 ; v1(163.7,47.34) 163.7,46.86 ; 48.92,116.59 C3525.2 ; C3525.2 49.35,116.99 ; C3525.2 49.78,116.59 ; v1(147.46,51.16) 147.88,51.16 ; v1(147.46,51.16) 147.03,51.16 ; v1(147.46,51.16) 147.46,50.76 ; 188.64,7.97 v1(188.64,8.34) ; v1(188.64,8.34) 188.64,8.72 ; v1(188.64,8.34) 189.09,8.34 ; C2706.1 152.85,112.33 ; C2706.1 152.45,111.9 ; C2706.1 152.45,112.75 ; 144.05,59.48 U1701.61 142.5,59.48 ; 91.71,111.32 v1(91.71,111.74) ; v1(91.71,111.74) 91.31,111.74 ; v1(91.71,111.74) 91.71,112.17 ; 29.71,70.16 v1(29.31,70.16) 29.31,70.58 ; 26.08,84.38 C3108.2 25.68,84.8 ; C3524.1 49.2,123.51 ; C3524.1 48.8,123.93 ; 138.76,27.82 v1(138.33,27.82) 138.33,28.22 ; C2421.2 158.68,96.3 ; 25.69,73.61 v1(26.09,73.61) 26.09,73.18 ; 43.97,105.98 U1502.3 ; U1502.3 44.49,105.63 ; U1502.3 45.02,105.98 ; 138.57,63.7 v1(139,63.7) ; v1(139,63.7) 139.43,63.7 ; v1(139,63.7) 139,64.1 ; CON3000.6 4.05,63.83 ; CON3000.6 2.87,62.65 ; CON3000.6 4.05,61.47 ; 38.04,106.78 v1(38.47,106.78) 38.47,106.38 ; 28.71,107.8 C1509.2 ; C1509.2 28.31,108.22 ; C1509.2 28.71,108.65 ; J2600.E9 48.09,60.1 ; J2600.E9 47.6,59.61 ; J2600.E9 48.59,59.61 ; J2600.E9 48.09,59.11 ; TVS1302.1 24.11,50.73 ; TVS1302.1 23.74,50.28 ; TVS1302.1 24.49,50.28 ; 47.6,31.67 J2600.E31 ; J2600.E31 48.09,31.17 ; J2600.E31 48.59,31.67 ; 104.8,94.32 C545.2 105.53,93.72 ; 144.05,59.08 U1701.62 142.5,59.08 ; 137.08,27.82 v1(137.5,27.82) 137.5,28.22 ; 48.87,22.78 J2600.D38 ; J2600.D38 49.36,23.27 ; J2600.D38 49.86,22.78 ; J2600.D38 49.36,22.28 ; C3107.2 22.56,86.71 ; C3107.2 22.03,86.09 ; C3107.2 22.56,85.46 ; v4(104.89,109.59) 104.89,110.02 ; v4(104.89,109.59) 104.89,109.17 ; v4(104.89,109.59) 105.29,109.59 ; RT2400.2 41.82,35.21 ; RT2400.2 41.78,34.79 v1(41.33,35.25) ; RT2400.2 41.82,34.36 ; v4(159.74,78.18) 160.19,78.18 ; v4(159.74,78.18) 159.29,78.18 ; v4(159.74,78.18) 159.74,77.85 ; 24.77,35.79 TVS1212.1 24.02,35.79 ; J1200.G4 22.53,19.4 ; J1200.G4 20.75,20.28 ; J1200.G4 20.75,18.52 ; J1200.G4 18.97,19.4 ; 134.85,39.49 v4(134.85,39.87) ; v4(134.85,39.87) 134.85,40.24 ; v4(134.85,39.87) 135.3,39.87 ; v4(134.85,39.87) 134.4,39.87 ; 37.45,112.74 C1510.2 37.85,112.32 ; 186.92,44.38 J2000.U13 187.8,45.26 ; C1736.2 162.21,63.01 ; C1736.2 v1(162.21,62.58) v1(162.21,61.73) v1(163.35,61.73) ; C1736.2 162.61,62.58 ; 25.68,54.78 v1(26.08,54.78) 26.08,54.35 ; 168.04,116 v1(168.41,116) 168.41,115.52 ; 46.33,29.13 J2600.F33 ; J2600.F33 46.82,29.62 ; J2600.F33 47.32,29.13 ; J2600.F33 46.82,28.63 ; 148.33,50.75 v1(148.33,51.15) ; v1(148.33,51.15) 147.9,51.15 ; v1(148.33,51.15) 148.75,51.15 ; J3310.G1 170.01,128.16 ; J3310.G1 168.78,126.49 ; J3310.G1 167.56,128.16 ; 146.34,84.87 C2434.2 145.92,85.27 ; 29.75,57.57 v1(29.35,57.57) 29.35,57.99 ; v4(127.1,75.86) 127.1,76.29 ; v4(127.1,75.86) 127.1,75.44 ; v4(127.1,75.86) 126.7,75.86 ; 29.72,93.27 R3104.1 29.32,93.7 ; 116.13,38.59 v4(116.13,38.09) 116.63,38.09 ; v1(167.95,94.55) 167.98,94.58 TVS1911.2 ; 95.4,95.3 v1(95.4,94.88) 95.93,94.88 ; 171.43,45.39 TVS2008.2 172.38,45.39 ; v4(48.83,122.54) 49.25,122.54 ; v4(48.83,122.54) 48.83,122.01 ; v4(48.83,122.54) 48.83,123.06 ; 130.11,106 U4002.3 129.83,106.53 ; 141.05,83.74 C832.2 ; C832.2 140.37,84.31 ; C832.2 141.72,84.31 ; 104.95,105.6 C1416.1 105.35,105.18 ; 140.73,101.24 C2703.2 ; C2703.2 141.13,101.67 ; C2703.2 140.73,102.09 ; 22.57,76.07 C3044.2 ; C3044.2 22.57,77.32 ; C3044.2 22.05,76.69 ; 31,114.47 v4(31,114.07) 30.57,114.07 ; 123.49,126.53 J3304.G1 ; J3304.G1 124.72,128.2 ; J3304.G1 122.27,128.2 ; 117.4,50.3 J2700.G19 ; J2700.G19 117.4,51.29 ; J2700.G19 116.91,50.79 ; J2700.G19 117.9,50.79 ; 134.39,126.53 J3302.G1 ; J3302.G1 133.17,128.21 ; J3302.G1 135.62,128.21 ; 98.91,112.73 C1418.1 98.48,113.13 ; 18.18,34.06 J1201.17 18.64,33.94 ; 115.64,31.74 v4(116.13,31.74) ; v4(116.13,31.74) 116.13,32.24 ; v4(116.13,31.74) 116.63,31.74 ; v4(116.13,31.74) 116.13,31.25 ; 186.92,66.33 J2001.U13 187.8,67.2 ; v1(152.15,96.3) 152.58,96.3 ; v1(152.15,96.3) 152.15,96.7 ; v1(152.15,96.3) 151.72,96.3 ; 126.38,67 C1602.2 126.98,67.72 ; 178.78,79.06 J1900.10 ; J1900.10 179.66,79.94 ; J1900.10 177.9,79.94 ; J1900.10 178.78,80.82 ; 157.79,76.29 v4(157.79,75.89) 158.22,75.89 ; 50.14,22.78 J2600.C38 ; J2600.C38 50.63,22.28 ; J2600.C38 51.13,22.78 ; J2600.C38 50.63,23.27 ; 29.75,76.39 v4(29.35,76.39) 29.35,76.82 ; 73.85,110.1 R3526.2 ; R3526.2 74.25,109.67 ; R3526.2 74.25,110.53 ; v1(170.39,61.57) 170.46,61.5 v1(171.07,61.5) 171.07,61.5 ; 145.4,111.08 v1(145.4,111.48) 145.83,111.48 ; 54.72,109 v1(55.15,109) ; v1(55.15,109) 55.58,109 ; v1(55.15,109) 55.15,108.6 ; 171.96,55.94 TVS2001.1 ; TVS2001.1 172.41,56.31 ; TVS2001.1 171.51,56.31 ; CON2900.6 4.05,83.83 ; CON2900.6 2.87,82.65 ; CON2900.6 4.05,81.47 ; 138.41,61.87 C1707.2 138.84,62.27 ; 89,90.5 v1(89,90.9) ; v1(89,90.9) 89.43,90.9 ; v1(89,90.9) 88.57,90.9 ; v1(172.59,64.65) CR2002.3 CR2002.8 ; 171.7,110.76 v1(171.7,110.28) 171.33,110.28 ; 48.09,62.92 J2600.E6 ; J2600.E6 48.59,63.42 ; J2600.E6 48.09,63.91 ; J2600.E6 47.6,63.42 ; 103.35,94.32 C544.2 102.63,93.72 ; 145.37,116.46 v1(144.97,116.46) 144.97,116.89 ; J1900.U16 186.3,85.66 ; J1900.U16 185.42,86.53 ; J1900.U16 185.42,84.78 ; J1900.U16 184.54,85.66 ; v4(162.15,71.53) 162.55,71.53 ; v4(162.15,71.53) 162.15,71.11 ; v4(162.15,71.53) 162.15,71.96 ; 152.87,55.91 v1(152.87,56.68) 152.87,57.46 ; v1(186.1,8.36) 186.55,8.36 ; v1(186.1,8.36) 186.1,7.98 ; v1(186.1,8.36) 186.1,8.73 ; v1(139.75,73.35) 139.75,73.75 ; v1(139.75,73.35) 139.32,73.35 ; v1(139.75,73.35) 140.18,73.35 ; 120.79,108.16 v1(120.79,108.59) ; v1(120.79,108.59) 120.79,109.01 ; v1(120.79,108.59) 121.19,108.59 ; 171.5,68.59 TVS2011.2 172.45,68.59 ; J2600.C11 50.63,57.56 ; J2600.C11 50.14,57.07 ; J2600.C11 50.63,56.57 ; J2600.C11 51.13,57.07 ; 52.1,105.74 v1(52.1,106.14) ; v1(52.1,106.14) 52.53,106.14 ; v1(52.1,106.14) 51.67,106.14 ; v1(88.66,114.72) 89.09,114.72 ; v1(88.66,114.72) 88.66,115.12 ; v1(88.66,114.72) 88.24,114.72 ; 85.95,112.12 v1(85.95,112.55) ; v1(85.95,112.55) 86.35,112.55 ; v1(85.95,112.55) 85.95,112.98 ; 184.54,107.61 J1901.U16 ; J1901.U16 185.42,108.48 ; J1901.U16 185.42,106.73 ; J1901.U16 186.3,107.61 ; LED1700.2 132.98,55.11 ; LED1700.2 132.98,53.96 ; LED1700.2 133.51,54.53 ; LED1700.2 132.46,54.53 ; 27.18,82.28 v4(26.91,82.28) 26.91,82.76 ; 22.06,82.28 C3109.2 ; C3109.2 22.58,81.66 ; C3109.2 22.58,82.91 ; v1(157.67,63.31) 158.24,63.88 v1(158.87,63.88) 159.97,63.88 v1(160.15,63.7) ; 51.73,116.27 C3531.2 ; C3531.2 51.73,117.33 ; C3531.2 51.3,116.8 ; 169.59,69.88 R2000.1 169.19,69.45 ; 142.5,61.08 U1701.57 144.05,61.08 ; 7.25,63.03 CON3000.G1 7.25,61.67 ; 148.62,76.47 C1718.2 ; C1718.2 149.05,77 ; C1718.2 148.62,77.53 ; 171.08,91.04 TVS1907.2 171.46,91.52 ; 166.74,112.02 R1904.1 ; R1904.1 167.17,111.62 ; R1904.1 167.59,112.02 ; 142.62,90.74 v1(142.62,90.22) 143.05,90.22 ; 23.74,49.36 TVS1303.1 ; TVS1303.1 24.49,49.36 ; TVS1303.1 24.11,48.91 ; 127.27,49.83 v4(127.27,49.43) 126.85,49.43 ; v1(24.13,47.49) 24.5,47.49 ; v1(24.13,47.49) 24.13,47.04 ; v1(24.13,47.49) 23.75,47.49 ; 26.9,58.34 v4(26.9,57.87) 27.17,57.87 ; 50.14,67.23 J2600.C3 ; J2600.C3 50.63,67.72 ; J2600.C3 51.13,67.23 ; J2600.C3 50.63,66.73 ; 91.34,103.64 v1(91.74,103.64) 91.74,103.21 ; 128.99,71.55 v1(128.57,71.55) 128.57,71.15 ; 137.65,103.77 R4004.2 138.07,104.17 ; 149.95,78.64 v4(149.95,79.07) ; v4(149.95,79.07) 150.35,79.07 ; v4(149.95,79.07) 149.95,79.49 ; 171.33,109.22 v1(171.7,109.22) 171.7,108.74 ; 135.14,9.04 v1(134.72,9.04) 134.72,8.64 ; v1(139.5,88.82) v1(139.5,88.27) ; 29.6,112.89 v4(29.6,113.32) 30,113.32 ; 130.41,78.3 C1613.2 129.99,77.9 ; C2428.2 161.8,92.18 ; C2428.2 161.8,91.32 ; C2428.2 162.2,91.75 ; 142.95,54.88 v1(142.95,54.45) 142.55,54.45 ; 27.17,76.69 v4(26.9,76.69) 26.9,77.17 ; 98.17,100.3 R1435.2 97.75,100.7 ; 145.1,87.55 v1(145.1,87.95) 144.67,87.95 ; 51.63,106.14 v1(51.2,106.14) 51.2,105.74
  TOP w0.25: 172.47,69.65 172.12,69.65 ; 171.07,61.5 CR2000.8
  L2 w0.2: J1901.10 178.78,102.77 ; J1901.10 178.78,101.01 ; J1901.10 179.66,101.89 ; J1901.10 177.9,101.89 ; 190.12,44.38 J2000.U4 191,45.26 ; 18.18,46.44 J1300.17 18.64,46.32 ; 177.9,57.99 J2001.10 ; J2001.10 178.78,58.87 ; J2001.10 179.66,57.99 ; J2001.10 178.78,57.11 ; 10.45,90.17 CON2900.7 ; CON2900.7 9.27,91.35 ; CON2900.7 10.45,92.53 ; CON2900.7 11.63,91.35 ; 20.75,30.89 J1201.G4 ; J1201.G4 22.52,31.77 ; J1201.G4 18.97,31.77 ; J1201.G4 20.75,32.64 ; 9.97,48.47 J1300.2 9.4,47.9 ; 17.65,25.02 J1200.G3 ; J1200.G3 17.65,26.78 ; J1200.G3 19.43,25.9 ; J1200.G3 15.87,25.9 ; 188.62,106.73 J1901.U7 ; J1901.U7 188.62,108.48 ; J1901.U7 187.74,107.61 ; J1901.U7 189.5,107.61 ; 11.25,43.27 J1300.G1 ; J1300.G1 9.47,44.15 ; J1300.G1 11.25,45.02 ; J1300.G1 13.02,44.15 ; 186.92,66.33 J2001.U13 187.8,67.2 ; 18.97,44.15 J1300.G4 ; J1300.G4 22.52,44.15 ; J1300.G4 20.75,45.02 ; J1300.G4 20.75,43.27 ; 191,111.11 J1901.U4 190.12,110.23 ; J2001.U7 188.62,64.58 ; J2001.U7 189.5,63.7 ; J2001.U7 188.62,62.83 ; J2001.U7 187.74,63.7 ; 188.62,40.88 J2000.U7 ; J2000.U7 189.5,41.76 ; J2000.U7 188.62,42.63 ; J2000.U7 187.74,41.76 ; 9.27,82.65 CON2900.5 ; CON2900.5 11.63,82.65 ; CON2900.5 10.45,83.83 ; CON2900.5 10.45,81.47 ; J2000.U16 185.42,42.63 ; J2000.U16 185.42,40.88 ; J2000.U16 186.3,41.76 ; J2000.U16 184.54,41.76 ; 163.29,3.71 J3601.1 ; J3601.1 164.27,4.68 ; J3601.1 165.25,3.71 ; J3601.1 164.27,2.73 ; 9.4,23.15 J1200.2 9.98,23.73 ; J1201.G2 10.42,38.27 ; J1201.G2 6.87,38.27 ; J1201.G2 8.65,39.14 ; J1201.G2 8.65,37.39 ; 11.25,30.89 J1201.G1 ; J1201.G1 13.02,31.77 ; J1201.G1 11.25,32.64 ; J1201.G1 9.47,31.77 ; 9.4,35.52 J1201.2 9.97,36.09 ; 18.64,21.57 J1200.17 18.18,21.69 ; 18.97,19.4 J1200.G4 ; J1200.G4 22.53,19.4 ; J1200.G4 20.75,18.52 ; J1200.G4 20.75,20.28 ; CON2900.6 4.05,83.83 ; CON2900.6 5.23,82.65 ; CON2900.6 2.87,82.65 ; CON2900.6 4.05,81.47 ; 187.8,45.26 J2000.U13 186.92,44.38 ; 15.87,38.27 J1201.G3 ; J1201.G3 17.65,37.39 ; J1201.G3 17.65,39.14 ; J1201.G3 19.42,38.27 ; 14.12,103.25 J1500.10 ; J1500.10 15.98,103.25 ; J1500.10 15.05,104.18 ; J1500.10 15.05,102.33 ; 188.62,84.78 J1900.U7 ; J1900.U7 188.62,86.53 ; J1900.U7 189.5,85.66 ; J1900.U7 187.74,85.66 ; 178.5,3.71 J3600.1 ; J3600.1 179.48,2.74 ; J3600.1 179.48,4.69 ; J3600.1 180.45,3.71 ; CON3000.6 4.05,63.83 ; CON3000.6 5.23,62.65 ; CON3000.6 2.87,62.65 ; CON3000.6 4.05,61.47 ; 178.78,35.16 J2000.10 ; J2000.10 178.78,36.92 ; J2000.10 179.66,36.04 ; J2000.10 177.9,36.04 ; J2001.U16 186.3,63.7 ; J2001.U16 184.54,63.7 ; J2001.U16 185.42,64.58 ; J2001.U16 185.42,62.83 ; 190.12,88.28 J1900.U4 191,89.16 ; 185.42,84.78 J1900.U16 ; J1900.U16 186.3,85.66 ; J1900.U16 184.54,85.66 ; J1900.U16 185.42,86.53 ; CON2900.8 4.05,92.53 ; CON2900.8 2.87,91.35 ; CON2900.8 5.23,91.35 ; CON2900.8 4.05,90.17 ; CON3000.8 5.23,71.35 ; CON3000.8 4.05,72.53 ; CON3000.8 4.05,70.17 ; CON3000.8 2.87,71.35 ; J1300.G2 10.42,50.65 ; J1300.G2 8.65,51.52 ; J1300.G2 8.65,49.77 ; J1300.G2 6.87,50.65 ; 153.29,118.25 NUT2301.1 ; NUT2301.1 151.41,120.13 ; NUT2301.1 153.29,122.01 ; NUT2301.1 155.17,120.13 ; 6.87,25.9 J1200.G2 ; J1200.G2 10.43,25.9 ; J1200.G2 8.65,26.78 ; J1200.G2 8.65,25.02 ; J1900.10 179.66,79.94 ; J1900.10 178.78,80.82 ; J1900.10 177.9,79.94 ; J1900.10 178.78,79.06 ; 9.47,19.4 J1200.G1 ; J1200.G1 11.25,20.28 ; J1200.G1 11.25,18.52 ; J1200.G1 13.03,19.4 ; 17.65,49.77 J1300.G3 ; J1300.G3 19.42,50.65 ; J1300.G3 17.65,51.52 ; J1300.G3 15.87,50.65 ; J1901.U16 186.3,107.61 ; J1901.U16 185.42,106.73 ; J1901.U16 185.42,108.48 ; J1901.U16 184.54,107.61 ; 191,67.2 J2001.U4 190.12,66.33 ; 9.27,62.65 CON3000.5 ; CON3000.5 10.45,63.83 ; CON3000.5 11.63,62.65 ; CON3000.5 10.45,61.47 ; 18.18,34.06 J1201.17 18.64,33.94 ; CON3000.7 10.45,72.53 ; CON3000.7 11.63,71.35 ; CON3000.7 10.45,70.17 ; CON3000.7 9.27,71.35
  L2 w0.3: 92.88,113.86 92.9,113.84 92.9,112.07
  L3 w0.075: 49.29,30.53 48.59,31.23 v1(48.51,31.23) ; 146.09,72.21 145.83,72.47 145.83,72.83 ; v1(155.58,57.53) 155.81,57.3 155.81,56.88 156.13,56.56 ; v2(35.77,25.02) 35.77,25.73 v1(35.39,26.11) ; 102.05,107.17 102.33,107.45 102.91,107.45 v1(102.96,107.4) ; v1(166.98,53.71) 166.62,53.71 166.52,53.61 166.2,53.61 v1(166.15,53.67) ; v1(43,30.14) 43.13,30.02 44.07,30.02 ; v1(43.28,47.35) 42.88,46.78 ; v1(50.57,101.25) 50.57,100.69 51,100.26 ; v1(37.23,107.25) 37.11,107.36 36.36,107.36 ; v1(53.93,23.09) 53.92,23.07 v1(52.53,23.07) ; v2(168.48,93.48) 168.79,93.17 169.17,93.17 169.26,93.26 169.26,94.18 v2(169.48,94.39) ; 46.69,28.19 46.57,28.31 v1(45.79,28.31) ; v1(118.61,58.84) 118.67,58.9 119.52,58.9 v1(119.69,59.08) ; v1(119.66,43.92) 119.66,43.11 119.9,42.87 121.76,42.87 v1(121.91,43.02) ; 161.2,87.24 162.01,87.24 v1(162.15,87.1) ; v1(156.18,84.32) 156.41,84.55 v2(157.62,84.55) ; 170.28,91.71 169.58,91.71 v1(169.55,91.74) ; 46.83,26.8 46.68,26.95 v1(45.68,26.95) 44.03,26.95 v1(44,26.92) ; v1(49.46,100.75) 49.46,100.15 49.82,99.79 ; 147.64,32.76 147.83,32.57 150.48,32.57 v1(150.56,32.65) 150.61,32.6 152,32.6 ; v2(53.61,35.57) 53.46,35.42 52.58,35.42 v1(52.53,35.47) 52.46,35.4 50.73,35.4 v1(50.64,35.49) ; 46.6,27.72 46.46,27.58 45.91,27.58 ; v1(160.31,61.37) 160.54,61.14 162.89,61.14 163.02,61.01
  L3 w0.1: v2(42.2,21.16) 42.13,21.09 42.05,21.09 42.05,21.09 v1(41.8,21.09) ; 58.15,61.04 58.14,61.04 ; 57.96,61.5 57.94,61.5
  L3 w0.2: v2(170.81,102.91) v1(170.35,103) ; 190.12,44.38 J2000.U4 191,45.26 ; 13.9,23.61 J1200.8 13.44,23.73 ; v2(122.5,27.61) v1(122.85,27.61) ; 18.64,21.57 J1200.17 18.18,21.69 ; v2(70.42,11.31) v1(70.1,11.51) ; 15.17,46.32 J1300.11 14.71,46.44 ; CON2900.7 10.45,92.53 ; CON2900.7 11.63,91.35 ; CON2900.7 9.27,91.35 ; CON2900.7 10.45,90.17 ; v2(4.44,99.55) v1(4.83,99.54) ; v1(171.7,110.28) v2(171.4,110.25) ; 18.97,31.77 J1201.G4 ; J1201.G4 20.75,30.89 ; J1201.G4 22.52,31.77 ; J1201.G4 20.75,32.64 ; CON3000.8 4.05,72.53 ; CON3000.8 5.23,71.35 ; CON3000.8 2.87,71.35 ; CON3000.8 4.05,70.17 ; 11.25,30.89 J1201.G1 ; J1201.G1 11.25,32.64 ; J1201.G1 9.47,31.77 ; J1201.G1 13.02,31.77 ; 11.25,43.27 J1300.G1 ; J1300.G1 13.02,44.15 ; J1300.G1 11.25,45.02 ; J1300.G1 9.47,44.15 ; 191,111.11 J1901.U4 190.12,110.23 ; NUT2301.1 155.17,120.13 ; NUT2301.1 153.29,122.01 ; NUT2301.1 151.41,120.13 ; NUT2301.1 153.29,118.25 ; 177.9,101.89 J1901.10 178.78,101.01 ; 9.97,48.47 J1300.2 9.4,47.9 ; v2(110.97,53.87) v1(111.37,53.88) ; 13.44,36.09 J1201.8 13.9,35.97 ; J1201.G3 17.65,39.14 ; J1201.G3 15.87,38.27 ; J1201.G3 17.65,37.39 ; J1201.G3 19.42,38.27 ; 186.92,44.38 J2000.U13 187.8,45.26 ; v1(71.92,42.85) 72.05,42.85 72.25,42.93 v2(72.25,42.95) ; 11.71,46.32 J1300.5 11.25,46.44 ; 11.25,21.69 J1200.5 11.71,21.57 ; 9.27,62.65 CON3000.5 ; CON3000.5 10.45,63.83 ; CON3000.5 11.63,62.65 ; CON3000.5 10.45,61.47 ; CON3000.6 5.23,62.65 ; CON3000.6 4.05,63.83 ; CON3000.6 2.87,62.65 ; CON3000.6 4.05,61.47 ; v2(12.22,8.82) v1(12.51,8.63) ; 14.71,34.06 J1201.11 15.17,33.94 ; 17.65,25.02 J1200.G3 ; J1200.G3 17.65,26.78 ; J1200.G3 15.87,25.9 ; J1200.G3 19.43,25.9 ; 191,89.16 J1900.U4 190.12,88.28 ; J1200.G2 10.43,25.9 ; J1200.G2 8.65,25.02 ; J1200.G2 6.87,25.9 ; J1200.G2 8.65,26.78 ; v2(147.9,88.05) 147.87,87.82 147.86,87.81 v1(147.85,87.7) ; v1(136.37,88.41) v2(136.4,88.87) ; 178.5,3.71 J3600.1 ; J3600.1 179.48,2.74 ; J3600.1 180.45,3.71 ; J3600.1 179.48,4.69 ; 2.87,82.65 CON2900.6 ; CON2900.6 5.23,82.65 ; CON2900.6 4.05,81.47 ; CON2900.6 4.05,83.83 ; v2(41.61,12.07) v1(42.05,12) ; 8.65,49.77 J1300.G2 ; J1300.G2 8.65,51.52 ; J1300.G2 6.87,50.65 ; J1300.G2 10.42,50.65 ; v1(171.7,109.22) v2(171.4,109.2) ; v2(18.97,7.77) v1(19.27,7.56) ; CON2900.8 4.05,92.53 ; CON2900.8 2.87,91.35 ; CON2900.8 4.05,90.17 ; CON2900.8 5.23,91.35 ; 18.97,19.4 J1200.G4 ; J1200.G4 20.75,18.52 ; J1200.G4 22.53,19.4 ; J1200.G4 20.75,20.28 ; 9.4,23.15 J1200.2 9.98,23.73 ; 190.12,66.33 J2001.U4 191,67.2 ; 178.78,57.11 J2001.10 177.9,57.99 ; J1300.G3 19.42,50.65 ; J1300.G3 17.65,49.77 ; J1300.G3 15.87,50.65 ; J1300.G3 17.65,51.52 ; J3601.1 165.25,3.71 ; J3601.1 163.29,3.71 ; J3601.1 164.27,4.68 ; J3601.1 164.27,2.73 ; J1300.G4 20.75,45.02 ; J1300.G4 20.75,43.27 ; J1300.G4 18.97,44.15 ; J1300.G4 22.52,44.15 ; v2(153.58,44.17) 153.58,44.21 153.86,43.93 v1(154.24,43.93) ; CON3000.7 11.63,71.35 ; CON3000.7 10.45,70.17 ; CON3000.7 10.45,72.53 ; CON3000.7 9.27,71.35 ; 11.71,33.94 J1201.5 11.25,34.06 ; 11.25,18.52 J1200.G1 ; J1200.G1 13.03,19.4 ; J1200.G1 11.25,20.28 ; J1200.G1 9.47,19.4 ; J1901.U7 188.62,108.48 ; J1901.U7 188.62,106.73 ; J1901.U7 187.74,107.61 ; J1901.U7 189.5,107.61 ; 178.78,79.06 J1900.10 177.9,79.94 ; 6.87,38.27 J1201.G2 ; J1201.G2 10.42,38.27 ; J1201.G2 8.65,39.14 ; J1201.G2 8.65,37.39 ; 186.92,66.33 J2001.U13 187.8,67.2 ; 9.97,36.09 J1201.2 9.4,35.52 ; 15.18,21.57 J1200.11 14.72,21.69 ; v2(83.88,71.01) 83.88,71.07 ; 9.27,82.65 CON2900.5 ; CON2900.5 10.45,81.47 ; CON2900.5 10.45,83.83 ; CON2900.5 11.63,82.65 ; v2(116.55,110.6) v1(116.1,110.6) ; J1500.10 15.05,104.18 ; J1500.10 14.12,103.25 ; J1500.10 15.05,102.33 ; J1500.10 15.98,103.25 ; v2(22.41,59.4) v1(22.4,59.79) ; 13.44,48.47 J1300.8 13.9,48.35 ; J1900.U7 189.5,85.66 ; J1900.U7 187.74,85.66 ; J1900.U7 188.62,84.78 ; J1900.U7 188.62,86.53 ; v1(139.33,17.33) 139.17,17.33 v2(138.96,17.53) ; 177.9,36.04 J2000.10 178.78,35.16 ; v1(3.61,98.54) v2(3.96,98.55) ; v1(25.92,40.69) v2(25.94,40.01) ; v2(113.09,13.93) v1(112.74,13.8) ; v1(24.35,59.6) v2(24.12,59.37) ; v2(24.97,7.77) v1(24.67,7.66) ; v1(4.56,97.53) v2(4.93,97.54) ; v2(133.31,13.31) v1(133.7,13.3) ; v2(70.24,13.41) v1(70.57,13.54)
  L4 w0.2: 18.18,21.69 J1200.17 18.64,21.57 ; 13.44,23.73 J1200.8 13.9,23.61 ; 187.8,67.2 J2001.U13 186.92,66.33 ; 184.54,85.66 J1900.U16 ; J1900.U16 185.42,86.53 ; J1900.U16 186.3,85.66 ; J1900.U16 185.42,84.78 ; 9.98,23.73 J1200.2 9.4,23.15 ; 4.05,81.47 CON2900.6 ; CON2900.6 4.05,83.83 ; CON2900.6 2.87,82.65 ; CON2900.6 5.23,82.65 ; CON3000.5 11.63,62.65 ; CON3000.5 9.27,62.65 ; CON3000.5 10.45,61.47 ; CON3000.5 10.45,63.83 ; J1201.G4 22.52,31.77 ; J1201.G4 18.97,31.77 ; J1201.G4 20.75,32.64 ; J1201.G4 20.75,30.89 ; J1500.10 15.05,104.18 ; J1500.10 15.05,102.33 ; J1500.10 15.98,103.25 ; J1500.10 14.12,103.25 ; 178.78,35.16 J2000.10 ; J2000.10 178.78,36.92 ; J2000.10 179.66,36.04 ; J2000.10 177.9,36.04 ; 9.27,71.35 CON3000.7 ; CON3000.7 10.45,72.53 ; CON3000.7 10.45,70.17 ; CON3000.7 11.63,71.35 ; 14.72,21.69 J1200.11 15.18,21.57 ; J1200.G1 13.03,19.4 ; J1200.G1 11.25,20.28 ; J1200.G1 11.25,18.52 ; J1200.G1 9.47,19.4 ; 17.65,25.02 J1200.G3 ; J1200.G3 17.65,26.78 ; J1200.G3 19.43,25.9 ; J1200.G3 15.87,25.9 ; 191,67.2 J2001.U4 190.12,66.33 ; 18.97,19.4 J1200.G4 ; J1200.G4 22.53,19.4 ; J1200.G4 20.75,18.52 ; J1200.G4 20.75,20.28 ; 18.18,34.06 J1201.17 18.64,33.94 ; 9.97,48.47 J1300.2 9.4,47.9 ; J2001.U16 186.3,63.7 ; J2001.U16 185.42,64.58 ; J2001.U16 184.54,63.7 ; J2001.U16 185.42,62.83 ; J2001.10 178.78,58.87 ; J2001.10 178.78,57.11 ; J2001.10 177.9,57.99 ; J2001.10 179.66,57.99 ; J1300.G2 8.65,51.52 ; J1300.G2 10.42,50.65 ; J1300.G2 8.65,49.77 ; J1300.G2 6.87,50.65 ; 191,89.16 J1900.U4 190.12,88.28 ; J3601.1 165.25,3.71 ; J3601.1 164.27,4.68 ; J3601.1 163.29,3.71 ; J3601.1 164.27,2.73 ; 187.74,41.76 J2000.U7 ; J2000.U7 188.62,40.88 ; J2000.U7 188.62,42.63 ; J2000.U7 189.5,41.76 ; 13.44,48.47 J1300.8 13.9,48.35 ; J1201.G3 17.65,39.14 ; J1201.G3 19.42,38.27 ; J1201.G3 17.65,37.39 ; J1201.G3 15.87,38.27 ; 2.87,71.35 CON3000.8 ; CON3000.8 4.05,70.17 ; CON3000.8 4.05,72.53 ; CON3000.8 5.23,71.35 ; J3600.1 179.48,4.69 ; J3600.1 179.48,2.74 ; J3600.1 180.45,3.71 ; J3600.1 178.5,3.71 ; J2000.U16 185.42,42.63 ; J2000.U16 184.54,41.76 ; J2000.U16 186.3,41.76 ; J2000.U16 185.42,40.88 ; 13.9,35.97 J1201.8 13.44,36.09 ; J1200.G2 10.43,25.9 ; J1200.G2 6.87,25.9 ; J1200.G2 8.65,25.02 ; J1200.G2 8.65,26.78 ; J1300.G3 19.42,50.65 ; J1300.G3 15.87,50.65 ; J1300.G3 17.65,49.77 ; J1300.G3 17.65,51.52 ; J1900.U7 189.5,85.66 ; J1900.U7 187.74,85.66 ; J1900.U7 188.62,86.53 ; J1900.U7 188.62,84.78 ; CON3000.6 4.05,63.83 ; CON3000.6 4.05,61.47 ; CON3000.6 5.23,62.65 ; CON3000.6 2.87,62.65 ; J1901.U7 189.5,107.61 ; J1901.U7 187.74,107.61 ; J1901.U7 188.62,108.48 ; J1901.U7 188.62,106.73 ; 8.65,37.39 J1201.G2 ; J1201.G2 8.65,39.14 ; J1201.G2 6.87,38.27 ; J1201.G2 10.42,38.27 ; J1300.G4 22.52,44.15 ; J1300.G4 20.75,45.02 ; J1300.G4 20.75,43.27 ; J1300.G4 18.97,44.15 ; 177.9,101.89 J1901.10 178.78,101.01 ; 9.47,44.15 J1300.G1 ; J1300.G1 11.25,43.27 ; J1300.G1 13.02,44.15 ; J1300.G1 11.25,45.02 ; 11.71,21.57 J1200.5 11.25,21.69 ; 188.62,62.83 J2001.U7 ; J2001.U7 187.74,63.7 ; J2001.U7 189.5,63.7 ; J2001.U7 188.62,64.58 ; 15.17,33.94 J1201.11 14.71,34.06 ; CON2900.5 11.63,82.65 ; CON2900.5 10.45,83.83 ; CON2900.5 10.45,81.47 ; CON2900.5 9.27,82.65 ; 9.97,36.09 J1201.2 9.4,35.52 ; 190.12,44.38 J2000.U4 191,45.26 ; 151.41,120.13 NUT2301.1 ; NUT2301.1 153.29,118.25 ; NUT2301.1 153.29,122.01 ; NUT2301.1 155.17,120.13 ; CON2900.8 4.05,92.53 ; CON2900.8 2.87,91.35 ; CON2900.8 5.23,91.35 ; CON2900.8 4.05,90.17 ; 18.18,46.44 J1300.17 18.64,46.32 ; 14.71,46.44 J1300.11 15.17,46.32 ; 186.92,44.38 J2000.U13 187.8,45.26 ; 10.45,90.17 CON2900.7 ; CON2900.7 11.63,91.35 ; CON2900.7 9.27,91.35 ; CON2900.7 10.45,92.53 ; 11.71,33.94 J1201.5 11.25,34.06 ; 191,111.11 J1901.U4 190.12,110.23 ; 185.42,106.73 J1901.U16 ; J1901.U16 186.3,107.61 ; J1901.U16 184.54,107.61 ; J1901.U16 185.42,108.48 ; 11.25,46.44 J1300.5 11.71,46.32 ; J1201.G1 11.25,32.64 ; J1201.G1 9.47,31.77 ; J1201.G1 13.02,31.77 ; J1201.G1 11.25,30.89 ; 178.78,79.06 J1900.10 177.9,79.94
  L5 w0.2: 6.87,50.65 J1300.G2 ; J1300.G2 10.42,50.65 ; J1300.G2 8.65,49.77 ; J1300.G2 8.65,51.52 ; 177.9,57.99 J2001.10 ; J2001.10 179.66,57.99 ; J2001.10 178.78,57.11 ; J2001.10 178.78,58.87 ; J1901.U16 186.3,107.61 ; J1901.U16 184.54,107.61 ; J1901.U16 185.42,106.73 ; J1901.U16 185.42,108.48 ; 9.27,71.35 CON3000.7 ; CON3000.7 10.45,72.53 ; CON3000.7 10.45,70.17 ; CON3000.7 11.63,71.35 ; 188.62,62.83 J2001.U7 ; J2001.U7 189.5,63.7 ; J2001.U7 188.62,64.58 ; J2001.U7 187.74,63.7 ; 4.05,61.47 CON3000.6 ; CON3000.6 2.87,62.65 ; CON3000.6 5.23,62.65 ; CON3000.6 4.05,63.83 ; J1201.G3 17.65,39.14 ; J1201.G3 19.42,38.27 ; J1201.G3 17.65,37.39 ; J1201.G3 15.87,38.27 ; J1900.10 178.78,80.82 ; J1900.10 178.78,79.06 ; J1900.10 179.66,79.94 ; J1900.10 177.9,79.94 ; 153.29,118.25 NUT2301.1 ; NUT2301.1 151.41,120.13 ; NUT2301.1 155.17,120.13 ; NUT2301.1 153.29,122.01 ; 9.27,82.65 CON2900.5 ; CON2900.5 10.45,81.47 ; CON2900.5 10.45,83.83 ; CON2900.5 11.63,82.65 ; J3601.1 164.27,4.68 ; J3601.1 164.27,2.73 ; J3601.1 165.25,3.71 ; J3601.1 163.29,3.71 ; 177.9,36.04 J2000.10 ; J2000.10 178.78,35.16 ; J2000.10 178.78,36.92 ; J2000.10 179.66,36.04 ; J1201.G1 11.25,32.64 ; J1201.G1 9.47,31.77 ; J1201.G1 11.25,30.89 ; J1201.G1 13.02,31.77 ; J1300.G4 20.75,45.02 ; J1300.G4 18.97,44.15 ; J1300.G4 20.75,43.27 ; J1300.G4 22.52,44.15 ; 186.92,66.33 J2001.U13 187.8,67.2 ; 13.9,35.97 J1201.8 13.44,36.09 ; 186.92,44.38 J2000.U13 187.8,45.26 ; J1901.U7 188.62,108.48 ; J1901.U7 188.62,106.73 ; J1901.U7 187.74,107.61 ; J1901.U7 189.5,107.61 ; J1201.G4 20.75,32.64 ; J1201.G4 22.52,31.77 ; J1201.G4 20.75,30.89 ; J1201.G4 18.97,31.77 ; J1500.10 15.98,103.25 ; J1500.10 15.05,104.18 ; J1500.10 14.12,103.25 ; J1500.10 15.05,102.33 ; J1200.G3 17.65,26.78 ; J1200.G3 17.65,25.02 ; J1200.G3 19.43,25.9 ; J1200.G3 15.87,25.9 ; 2.87,82.65 CON2900.6 ; CON2900.6 4.05,83.83 ; CON2900.6 4.05,81.47 ; CON2900.6 5.23,82.65 ; J1200.G2 10.43,25.9 ; J1200.G2 6.87,25.9 ; J1200.G2 8.65,25.02 ; J1200.G2 8.65,26.78 ; J1300.G1 11.25,45.02 ; J1300.G1 11.25,43.27 ; J1300.G1 9.47,44.15 ; J1300.G1 13.02,44.15 ; 11.25,46.44 J1300.5 11.71,46.32 ; 178.78,101.01 J1901.10 ; J1901.10 177.9,101.89 ; J1901.10 178.78,102.77 ; J1901.10 179.66,101.89 ; J1300.G3 19.42,50.65 ; J1300.G3 17.65,49.77 ; J1300.G3 15.87,50.65 ; J1300.G3 17.65,51.52 ; 18.18,21.69 J1200.17 18.64,21.57 ; 191,67.2 J2001.U4 190.12,66.33 ; 18.97,19.4 J1200.G4 ; J1200.G4 20.75,18.52 ; J1200.G4 20.75,20.28 ; J1200.G4 22.53,19.4 ; J2000.U16 186.3,41.76 ; J2000.U16 184.54,41.76 ; J2000.U16 185.42,42.63 ; J2000.U16 185.42,40.88 ; 10.45,61.47 CON3000.5 ; CON3000.5 11.63,62.65 ; CON3000.5 10.45,63.83 ; CON3000.5 9.27,62.65 ; 15.18,21.57 J1200.11 14.72,21.69 ; 6.87,38.27 J1201.G2 ; J1201.G2 8.65,37.39 ; J1201.G2 10.42,38.27 ; J1201.G2 8.65,39.14 ; 18.64,46.32 J1300.17 18.18,46.44 ; J3600.1 180.45,3.71 ; J3600.1 178.5,3.71 ; J3600.1 179.48,2.74 ; J3600.1 179.48,4.69 ; 18.64,33.94 J1201.17 18.18,34.06 ; 9.4,47.9 J1300.2 9.97,48.47 ; J2000.U7 188.62,42.63 ; J2000.U7 189.5,41.76 ; J2000.U7 187.74,41.76 ; J2000.U7 188.62,40.88 ; 4.05,90.17 CON2900.8 ; CON2900.8 4.05,92.53 ; CON2900.8 2.87,91.35 ; CON2900.8 5.23,91.35 ; 9.98,23.73 J1200.2 9.4,23.15 ; 188.62,84.78 J1900.U7 ; J1900.U7 189.5,85.66 ; J1900.U7 187.74,85.66 ; J1900.U7 188.62,86.53 ; 190.12,44.38 J2000.U4 191,45.26 ; 190.12,110.23 J1901.U4 191,111.11 ; 11.25,34.06 J1201.5 11.71,33.94 ; 15.17,33.94 J1201.11 14.71,34.06 ; 9.97,36.09 J1201.2 9.4,35.52 ; 11.25,21.69 J1200.5 11.71,21.57 ; 13.44,48.47 J1300.8 13.9,48.35 ; 11.25,18.52 J1200.G1 ; J1200.G1 9.47,19.4 ; J1200.G1 13.03,19.4 ; J1200.G1 11.25,20.28 ; 2.87,71.35 CON3000.8 ; CON3000.8 4.05,70.17 ; CON3000.8 5.23,71.35 ; CON3000.8 4.05,72.53 ; 184.54,85.66 J1900.U16 ; J1900.U16 186.3,85.66 ; J1900.U16 185.42,84.78 ; J1900.U16 185.42,86.53 ; 185.42,62.83 J2001.U16 ; J2001.U16 186.3,63.7 ; J2001.U16 184.54,63.7 ; J2001.U16 185.42,64.58 ; 191,89.16 J1900.U4 190.12,88.28 ; 13.44,23.73 J1200.8 13.9,23.61 ; 14.71,46.44 J1300.11 15.17,46.32
  L6 w0.075: 42.48,66.84 42.48,67.53 v3(42.68,67.73) ; v1(33.35,15.5) 33.21,15.36 v1(33.21,14.1) ; v2(46.52,98.2) 46.48,98.2 v2(45.99,97.71) ; v3(47.68,97.52) 47.23,97.52 v2(46.68,96.97) ; 43.44,71.51 43.53,71.6 v3(44.5,71.6) ; v2(43.05,72.69) 43.05,72.49 42.92,72.18 v2(42.66,71.92) ; v2(55,35.95) 55.08,36.03 55.08,36.61 v1(55.16,36.7) ; v1(58.42,36.75) 58.34,36.67 58.17,36.25 v1(58.15,36.24) ; v3(49.01,100.4) 49.22,100.4 49.72,99.9 v3(49.72,99.81) ; v1(59.15,24.09) 59.15,23.12 v2(59.02,22.98) ; v3(46.14,98.97) 45.83,98.97 v2(45.32,98.46) ; v3(38.61,34.45) 38.46,34.6 38.46,35.06 38.62,35.22 v3(38.62,35.84) ; 44.38,70.65 44.38,71 44.61,71.23 v3(44.79,71.23) ; v3(50.12,100.87) 50.18,100.93 50.38,100.93 50.86,100.45 v3(50.86,100.39)
  L6 w0.1: v3(129.6,91.77) 129.65,91.82 129.65,93.37 v3(129.6,93.42) ; v3(147.98,73.37) 148.19,73.01 v2(148.15,72.69) ; v3(144.68,103.62) 144.65,103.65 144.65,104.28 v2(144.81,104.45) ; 112.59,54.37 112.74,54.22 112.74,53.26 ; 148.09,106.53 148.09,107.49 v3(148.02,107.56) ; 112.72,75.23 112.72,75.89 v3(112.56,76.05) ; v3(156.34,73.26) 156.34,73.26 156.34,73.73 156.42,73.81 v3(156.42,74.14) ; v3(156.56,83.68) 156.65,83.58 156.65,82.77
  L6 w0.2: CON3000.6 5.23,62.65 ; CON3000.6 4.05,63.83 ; CON3000.6 2.87,62.65 ; CON3000.6 4.05,61.47 ; 9.97,48.47 J1300.2 9.4,47.9 ; 191,89.16 J1900.U4 190.12,88.28 ; J1300.G1 11.25,45.02 ; J1300.G1 9.47,44.15 ; J1300.G1 11.25,43.27 ; J1300.G1 13.02,44.15 ; J1901.10 178.78,102.77 ; J1901.10 177.9,101.89 ; J1901.10 179.66,101.89 ; J1901.10 178.78,101.01 ; v2(57.19,16.71) v3(57.7,16.57) ; 179.48,2.74 J3600.1 ; J3600.1 180.45,3.71 ; J3600.1 179.48,4.69 ; J3600.1 178.5,3.71 ; 17.65,25.02 J1200.G3 ; J1200.G3 19.43,25.9 ; J1200.G3 15.87,25.9 ; J1200.G3 17.65,26.78 ; J1300.G3 19.42,50.65 ; J1300.G3 17.65,51.52 ; J1300.G3 17.65,49.77 ; J1300.G3 15.87,50.65 ; J2000.U7 188.62,42.63 ; J2000.U7 189.5,41.76 ; J2000.U7 188.62,40.88 ; J2000.U7 187.74,41.76 ; v2(54.19,16.71) v3(54.25,16.27) ; v2(147.17,40.83) 147.19,40.83 147.19,40.85 v3(147.49,40.54) ; J1200.G2 10.43,25.9 ; J1200.G2 6.87,25.9 ; J1200.G2 8.65,25.02 ; J1200.G2 8.65,26.78 ; 178.78,35.16 J2000.10 177.9,36.04 ; 10.45,61.47 CON3000.5 ; CON3000.5 11.63,62.65 ; CON3000.5 9.27,62.65 ; CON3000.5 10.45,63.83 ; 6.87,38.27 J1201.G2 ; J1201.G2 8.65,39.14 ; J1201.G2 10.42,38.27 ; J1201.G2 8.65,37.39 ; 18.64,33.94 J1201.17 18.18,34.06 ; 11.71,33.94 J1201.5 11.25,34.06 ; CON2900.6 5.23,82.65 ; CON2900.6 4.05,83.83 ; CON2900.6 2.87,82.65 ; CON2900.6 4.05,81.47 ; 15.17,33.94 J1201.11 14.71,34.06 ; 163.29,3.71 J3601.1 ; J3601.1 164.27,2.73 ; J3601.1 164.27,4.68 ; J3601.1 165.25,3.71 ; CON3000.8 4.05,72.53 ; CON3000.8 5.23,71.35 ; CON3000.8 4.05,70.17 ; CON3000.8 2.87,71.35 ; 187.8,67.2 J2001.U13 186.92,66.33 ; 13.9,35.97 J1201.8 13.44,36.09 ; 178.78,57.11 J2001.10 177.9,57.99 ; v2(44.51,72.54) 44.51,72.54 44.51,72.53 v3(43.95,72.07) ; 9.4,35.52 J1201.2 9.97,36.09 ; 18.97,19.4 J1200.G4 ; J1200.G4 20.75,18.52 ; J1200.G4 20.75,20.28 ; J1200.G4 22.53,19.4 ; 11.25,21.69 J1200.5 11.71,21.57 ; 15.17,46.32 J1300.11 14.71,46.44 ; 97.24,107.04 v2(96.92,107.04) ; v2(25.94,40.01) v3(26,40.5) ; J1201.G1 11.25,32.64 ; J1201.G1 9.47,31.77 ; J1201.G1 11.25,30.89 ; J1201.G1 13.02,31.77 ; v2(6.66,105.4) v3(7.05,105.38) ; J1200.G1 13.03,19.4 ; J1200.G1 9.47,19.4 ; J1200.G1 11.25,20.28 ; J1200.G1 11.25,18.52 ; 18.64,21.57 J1200.17 18.18,21.69 ; 2.87,91.35 CON2900.8 ; CON2900.8 5.23,91.35 ; CON2900.8 4.05,92.53 ; CON2900.8 4.05,90.17 ; 11.25,46.44 J1300.5 11.71,46.32 ; 190.12,44.38 J2000.U4 191,45.26 ; v2(177.25,114.01) v3(176.88,113.99) ; 188.62,62.83 J2001.U7 ; J2001.U7 189.5,63.7 ; J2001.U7 188.62,64.58 ; J2001.U7 187.74,63.7 ; v3(106.03,24.45) v2(105.75,24.6) ; v2(126.1,102.3) 126.1,102.25 v3(125.9,102.05) ; J1500.10 15.98,103.25 ; J1500.10 15.05,104.18 ; J1500.10 15.05,102.33 ; J1500.10 14.12,103.25 ; 20.75,43.27 J1300.G4 ; J1300.G4 22.52,44.15 ; J1300.G4 20.75,45.02 ; J1300.G4 18.97,44.15 ; J1300.G2 8.65,51.52 ; J1300.G2 10.42,50.65 ; J1300.G2 8.65,49.77 ; J1300.G2 6.87,50.65 ; v3(24.47,59.37) v2(24.12,59.37) ; CON2900.5 10.45,83.83 ; CON2900.5 10.45,81.47 ; CON2900.5 9.27,82.65 ; CON2900.5 11.63,82.65 ; v3(147.95,97.9) 147.95,97.71 147.95,97.16 147.94,97.16 v2(147.92,97.14) ; 185.42,40.88 J2000.U16 ; J2000.U16 184.54,41.76 ; J2000.U16 186.3,41.76 ; J2000.U16 185.42,42.63 ; NUT2301.1 153.29,122.01 ; NUT2301.1 153.29,118.25 ; NUT2301.1 155.17,120.13 ; NUT2301.1 151.41,120.13 ; J1900.10 179.66,79.94 ; J1900.10 178.78,79.06 ; J1900.10 178.78,80.82 ; J1900.10 177.9,79.94 ; v3(125.9,103.35) 126.1,103.15 v2(126.1,103.1) ; v2(144.58,38.51) v3(144.58,38.88) ; v3(132.6,47.65) 132.59,47.66 v2(132.6,47.95) ; 13.9,23.61 J1200.8 13.44,23.73 ; 13.44,48.47 J1300.8 13.9,48.35 ; 18.97,31.77 J1201.G4 ; J1201.G4 22.52,31.77 ; J1201.G4 20.75,30.89 ; J1201.G4 20.75,32.64 ; J2001.U16 186.3,63.7 ; J2001.U16 185.42,62.83 ; J2001.U16 185.42,64.58 ; J2001.U16 184.54,63.7 ; 10.45,70.17 CON3000.7 ; CON3000.7 10.45,72.53 ; CON3000.7 9.27,71.35 ; CON3000.7 11.63,71.35 ; 18.18,46.44 J1300.17 18.64,46.32 ; 191,67.2 J2001.U4 190.12,66.33 ; v3(121.97,14.07) v2(121.6,14) ; 191,111.11 J1901.U4 190.12,110.23 ; 64.85,112.75 v3(64.85,112.69) ; 9.4,23.15 J1200.2 9.98,23.73 ; 186.92,44.38 J2000.U13 187.8,45.26 ; J1201.G3 17.65,39.14 ; J1201.G3 17.65,37.39 ; J1201.G3 15.87,38.27 ; J1201.G3 19.42,38.27 ; v3(61.94,28.44) v2(61.95,28.05) ; v3(101.45,28.7) v2(101.2,28.95) ; v3(100.45,29.7) v2(100.2,29.95) ; v2(23.2,28.18) v3(23.68,28.16) ; 14.72,21.69 J1200.11 15.18,21.57 ; v3(99.95,28.7) v2(100.2,28.95)
  L6 w0.25: 138.42,115.05 138.43,115.06
  L6 w0.3: 123.78,124.7 123.75,124.73
  L6 w0.4: v3(45.77,79.84) v2(46.25,79.84)
  L7 w0.2: J1901.U7 189.5,107.61 ; J1901.U7 188.62,108.48 ; J1901.U7 187.74,107.61 ; J1901.U7 188.62,106.73 ; J1300.G4 20.75,45.02 ; J1300.G4 20.75,43.27 ; J1300.G4 22.52,44.15 ; J1300.G4 18.97,44.15 ; 190.12,110.23 J1901.U4 191,111.11 ; 188.62,84.78 J1900.U7 ; J1900.U7 189.5,85.66 ; J1900.U7 188.62,86.53 ; J1900.U7 187.74,85.66 ; J1201.G3 19.42,38.27 ; J1201.G3 17.65,37.39 ; J1201.G3 17.65,39.14 ; J1201.G3 15.87,38.27 ; 4.05,90.17 CON2900.8 ; CON2900.8 2.87,91.35 ; CON2900.8 5.23,91.35 ; CON2900.8 4.05,92.53 ; 10.45,81.47 CON2900.5 ; CON2900.5 9.27,82.65 ; CON2900.5 11.63,82.65 ; CON2900.5 10.45,83.83 ; 184.54,63.7 J2001.U16 ; J2001.U16 186.3,63.7 ; J2001.U16 185.42,62.83 ; J2001.U16 185.42,64.58 ; J1900.10 179.66,79.94 ; J1900.10 178.78,79.06 ; J1900.10 177.9,79.94 ; J1900.10 178.78,80.82 ; 14.72,21.69 J1200.11 15.18,21.57 ; 2.87,82.65 CON2900.6 ; CON2900.6 4.05,81.47 ; CON2900.6 5.23,82.65 ; CON2900.6 4.05,83.83 ; 6.87,25.9 J1200.G2 ; J1200.G2 10.43,25.9 ; J1200.G2 8.65,26.78 ; J1200.G2 8.65,25.02 ; J1200.G1 13.03,19.4 ; J1200.G1 11.25,20.28 ; J1200.G1 11.25,18.52 ; J1200.G1 9.47,19.4 ; 184.54,85.66 J1900.U16 ; J1900.U16 185.42,84.78 ; J1900.U16 185.42,86.53 ; J1900.U16 186.3,85.66 ; J1201.G1 11.25,32.64 ; J1201.G1 9.47,31.77 ; J1201.G1 11.25,30.89 ; J1201.G1 13.02,31.77 ; 2.87,62.65 CON3000.6 ; CON3000.6 5.23,62.65 ; CON3000.6 4.05,61.47 ; CON3000.6 4.05,63.83 ; J1201.G2 10.42,38.27 ; J1201.G2 6.87,38.27 ; J1201.G2 8.65,37.39 ; J1201.G2 8.65,39.14 ; J1901.10 178.78,102.77 ; J1901.10 177.9,101.89 ; J1901.10 179.66,101.89 ; J1901.10 178.78,101.01 ; 15.17,33.94 J1201.11 14.71,34.06 ; 18.18,21.69 J1200.17 18.64,21.57 ; J1500.10 15.98,103.25 ; J1500.10 15.05,104.18 ; J1500.10 15.05,102.33 ; J1500.10 14.12,103.25 ; 11.71,46.32 J1300.5 11.25,46.44 ; 6.87,50.65 J1300.G2 ; J1300.G2 8.65,49.77 ; J1300.G2 8.65,51.52 ; J1300.G2 10.42,50.65 ; 14.71,46.44 J1300.11 15.17,46.32 ; J1901.U16 185.42,108.48 ; J1901.U16 186.3,107.61 ; J1901.U16 184.54,107.61 ; J1901.U16 185.42,106.73 ; 178.5,3.71 J3600.1 ; J3600.1 179.48,2.74 ; J3600.1 180.45,3.71 ; J3600.1 179.48,4.69 ; 184.54,41.76 J2000.U16 ; J2000.U16 186.3,41.76 ; J2000.U16 185.42,40.88 ; J2000.U16 185.42,42.63 ; 11.25,34.06 J1201.5 11.71,33.94 ; CON3000.8 4.05,72.53 ; CON3000.8 2.87,71.35 ; CON3000.8 5.23,71.35 ; CON3000.8 4.05,70.17 ; 11.25,43.27 J1300.G1 ; J1300.G1 13.02,44.15 ; J1300.G1 11.25,45.02 ; J1300.G1 9.47,44.15 ; 13.44,36.09 J1201.8 13.9,35.97 ; CON3000.5 11.63,62.65 ; CON3000.5 10.45,61.47 ; CON3000.5 10.45,63.83 ; CON3000.5 9.27,62.65 ; 11.71,21.57 J1200.5 11.25,21.69 ; J1300.G3 19.42,50.65 ; J1300.G3 17.65,51.52 ; J1300.G3 15.87,50.65 ; J1300.G3 17.65,49.77 ; 191,89.16 J1900.U4 190.12,88.28 ; J2001.10 178.78,58.87 ; J2001.10 178.78,57.11 ; J2001.10 179.66,57.99 ; J2001.10 177.9,57.99 ; J1200.G3 19.43,25.9 ; J1200.G3 15.87,25.9 ; J1200.G3 17.65,25.02 ; J1200.G3 17.65,26.78 ; NUT2301.1 153.29,122.01 ; NUT2301.1 153.29,118.25 ; NUT2301.1 155.17,120.13 ; NUT2301.1 151.41,120.13 ; 163.29,3.71 J3601.1 ; J3601.1 164.27,4.68 ; J3601.1 165.25,3.71 ; J3601.1 164.27,2.73 ; J2000.U7 188.62,42.63 ; J2000.U7 187.74,41.76 ; J2000.U7 189.5,41.76 ; J2000.U7 188.62,40.88 ; J2001.U7 189.5,63.7 ; J2001.U7 188.62,62.83 ; J2001.U7 188.62,64.58 ; J2001.U7 187.74,63.7 ; 18.18,34.06 J1201.17 18.64,33.94 ; 9.97,36.09 J1201.2 9.4,35.52 ; 187.8,45.26 J2000.U13 186.92,44.38 ; 190.12,44.38 J2000.U4 191,45.26 ; 9.98,23.73 J1200.2 9.4,23.15 ; J2000.10 178.78,36.92 ; J2000.10 179.66,36.04 ; J2000.10 178.78,35.16 ; J2000.10 177.9,36.04 ; J1201.G4 22.52,31.77 ; J1201.G4 20.75,32.64 ; J1201.G4 18.97,31.77 ; J1201.G4 20.75,30.89 ; 18.64,46.32 J1300.17 18.18,46.44 ; 13.44,23.73 J1200.8 13.9,23.61 ; 186.92,66.33 J2001.U13 187.8,67.2 ; 13.44,48.47 J1300.8 13.9,48.35 ; 191,67.2 J2001.U4 190.12,66.33 ; 9.27,71.35 CON3000.7 ; CON3000.7 11.63,71.35 ; CON3000.7 10.45,70.17 ; CON3000.7 10.45,72.53 ; J1200.G4 22.53,19.4 ; J1200.G4 20.75,18.52 ; J1200.G4 20.75,20.28 ; J1200.G4 18.97,19.4 ; 9.4,47.9 J1300.2 9.97,48.47
  BOTTOM w0.1: 60.87,70.32 60.85,70.34
  BOTTOM w0.2: 33.12,63.48 v3(33.42,63.78) ; v3(33.42,63.78) 33.05,64.15 ; v3(33.42,63.78) 33.8,63.41 ; 42.23,64.82 C3039.2 ; C3039.2 42.97,64.08 ; C3039.2 42.9,64.75 ; 114.2,117.58 C3418.1 ; C3418.1 113.22,118.26 ; C3418.1 115.17,118.26 ; 177.9,57.99 J2001.10 ; J2001.10 178.78,57.11 ; J2001.10 178.78,58.87 ; J2001.10 179.66,57.99 ; 32.77,103.48 C2903.2 ; C2903.2 33.73,102.52 ; C2903.2 32.85,102.6 ; 30.36,72.89 v7(30.66,72.58) ; v7(30.66,72.58) 30.96,72.28 ; v7(30.66,72.58) 30.95,72.87 ; 132.6,47.39 C2508.2 132.17,47.79 ; C2306.1 148.69,49.3 ; C2306.1 147.97,48.7 ; C2306.1 149.42,48.7 ; 115.09,18.03 C802.2 115.62,17.4 ; 67,121.85 C2821.2 ; C2821.2 68.8,121.85 ; C2821.2 67.9,122.35 ; C2821.2 67.9,121.35 ; 118.8,59.05 C531.2 ; C531.2 119.3,59.85 ; C531.2 118.8,60.65 ; C531.2 118.3,59.85 ; 18.97,31.77 J1201.G4 ; J1201.G4 20.75,30.89 ; J1201.G4 20.75,32.64 ; J1201.G4 22.52,31.77 ; 70.29,55.2 U600.14 70.29,56.35 ; J1201.G3 19.42,38.27 ; J1201.G3 17.65,37.39 ; J1201.G3 15.87,38.27 ; J1201.G3 17.65,39.14 ; 37.89,87.59 v3(38.19,87.29) ; v3(38.19,87.29) 37.91,87.01 ; v3(38.19,87.29) 38.49,86.99 ; R2308.1 163.52,33.59 ; R2308.1 162.67,33.59 ; R2308.1 163.1,33.19 ; 52.6,36.66 v1(52.6,37.09) ; v1(52.6,37.09) 52.6,37.51 ; v1(52.6,37.09) 53,37.09 ; 156.54,37.76 CN2300.51 156.54,35.86 ; v3(63.67,30.07) 64.1,30.07 ; v3(63.67,30.07) 63.67,29.54 ; v3(63.67,30.07) 63.67,30.59 ; 36.78,32.58 C1122.2 ; C1122.2 37.2,32.18 ; C1122.2 37.63,32.58 ; 4.05,70.17 CON3000.8 ; CON3000.8 2.87,71.35 ; CON3000.8 4.05,72.53 ; CON3000.8 5.23,71.35 ; C3427.2 140.99,106.09 ; C3427.2 140.99,105.23 ; C3427.2 141.39,105.66 ; 191,45.26 J2000.U4 190.12,44.38 ; v7(129,34.1) 129,34.5 ; v7(129,34.1) 128.57,34.1 ; v7(129,34.1) 129.43,34.1 ; 64.3,68.62 C618.2 ; C618.2 65.3,67.84 ; C618.2 66.3,68.62 ; C618.2 65.3,69.39 ; 129.85,103.6 v3(129.85,104.2) ; v3(129.85,104.2) 130.2,104.2 ; v3(129.85,104.2) 129.85,104.8 ; 48.93,26.44 C1016.2 48.53,26.86 ; 140.5,103.6 v3(140.5,104.2) ; v3(140.5,104.2) 140.5,104.8 ; v3(140.5,104.2) 140.85,104.2 ; 136.22,62.04 v3(136.65,62.04) ; v3(136.65,62.04) 137.07,62.04 ; v3(136.65,62.04) 136.65,61.64 ; v3(46.91,91.7) 46.91,92.12 ; v3(46.91,91.7) 46.38,91.7 ; v3(46.91,91.7) 47.43,91.7 ; C2303.1 142.89,48.58 ; C2303.1 143.32,48.18 ; C2303.1 142.47,48.18 ; 25.64,61.6 v3(26.27,61.6) ; v3(26.27,61.6) 26.89,61.6 ; v3(26.27,61.6) 26.27,61.07 ; J1900.U7 188.62,86.53 ; J1900.U7 189.5,85.66 ; J1900.U7 187.74,85.66 ; J1900.U7 188.62,84.78 ; 15.01,57.22 v3(15.01,57.6) ; v3(15.01,57.6) 15.48,57.6 ; v3(15.01,57.6) 14.53,57.6 ; v7(133.56,107.95) 133.96,107.95 ; v7(133.56,107.95) 133.56,108.37 ; v7(133.56,107.95) 133.56,107.52 ; v3(14.45,70.83) 14.92,70.83 ; v3(14.45,70.83) 13.97,70.83 ; v3(14.45,70.83) 14.45,71.2 ; 144.05,33.19 v3(144.05,33.59) ; v3(144.05,33.59) 143.62,33.59 ; v3(144.05,33.59) 144.47,33.59 ; 47.92,35.74 v7(47.92,36.17) 48.32,36.17 ; 22.61,104.16 v3(22.61,103.76) 22.18,103.76 ; CT2503.2 171.35,34.74 ; CT2503.2 171.35,30.89 ; CT2503.2 170.67,32.82 ; v1(55.65,38.07) 56.08,38.07 ; v1(55.65,38.07) 55.23,38.07 ; v1(55.65,38.07) 55.65,37.67 ; 8.65,25.02 J1200.G2 ; J1200.G2 6.87,25.9 ; J1200.G2 10.43,25.9 ; J1200.G2 8.65,26.78 ; 2.87,82.65 CON2900.6 ; CON2900.6 5.23,82.65 ; CON2900.6 4.05,81.47 ; CON2900.6 4.05,83.83 ; v3(110.65,97.2) 111,97.2 ; v3(110.65,97.2) 110.65,97.8 ; v3(110.65,97.2) 110.65,96.6 ; 185.42,62.83 J2001.U16 ; J2001.U16 184.54,63.7 ; J2001.U16 186.3,63.7 ; J2001.U16 185.42,64.58 ; 38.98,104.04 v3(39.28,103.74) 39.56,104.02 ; 121.97,111.69 v3(122.4,111.69) ; v3(122.4,111.69) 122.82,111.69 ; v3(122.4,111.69) 122.4,111.29 ; 171.35,87.69 CT1903.2 ; CT1903.2 172.02,89.62 ; CT1903.2 170.67,89.62 ; CT1903.2 171.35,91.54 ; 18.64,45.97 J1300.17 19.21,45.97 ; 114.82,111.37 v3(114.82,111.77) ; v3(114.82,111.77) 115.24,111.77 ; v3(114.82,111.77) 114.39,111.77 ; v7(147.49,48.12) 147.49,48.5 ; v7(147.49,48.12) 147.04,48.12 ; v7(147.49,48.12) 147.94,48.12 ; 87.25,103 v7(87.25,103.4) 86.82,103.4 ; v3(127.83,8.55) 128.26,8.55 ; v3(127.83,8.55) 127.83,8.95 ; v3(127.83,8.55) 127.41,8.55 ; 153.29,117.35 NUT2301.1 ; NUT2301.1 150.51,120.13 ; NUT2301.1 156.07,120.13 ; NUT2301.1 153.29,122.91 ; 96.15,89.15 C510.2 ; C510.2 96.93,90.15 ; C510.2 95.37,90.15 ; C510.2 96.15,91.15 ; C3419.1 108.13,111.75 ; C3419.1 107.71,111.35 ; C3419.1 107.28,111.75 ; v3(112.43,89.04) 112.43,89.46 ; v3(112.43,89.04) 112.43,88.61 ; v3(112.43,89.04) 112.83,89.04 ; 46.67,39.43 C1125.2 47.07,39.85 ; 102.42,36.33 C705.2 ; C705.2 103.15,36.93 ; C705.2 103.88,36.33 ; 33.84,101.08 v3(34.12,100.8) ; v3(34.12,100.8) 33.82,100.5 ; v3(34.12,100.8) 34.42,101.1 ; v3(46.87,107.57) 46.87,108.09 ; v3(46.87,107.57) 46.87,107.04 ; v3(46.87,107.57) 46.45,107.57 ; R3403.2 128.79,119.86 ; R3403.2 128.37,119.46 ; R3403.2 127.94,119.86 ; C2827.2 74.75,102.75 ; C2827.2 73.15,102.75 ; C2827.2 73.95,102.25 ; C2827.2 73.95,103.25 ; 54.55,60.09 R3202.2 54.98,59.69 ; v7(105.03,23.65) 105.03,24.3 v3(105.13,24.4) ; v7(105.03,23.65) 105.43,23.65 ; v7(105.03,23.65) 105.03,23.22 ; 9.4,23.15 J1200.2 9.98,24.07 ; 132.1,59.24 v7(132.53,59.24) ; v7(132.53,59.24) 132.53,59.64 ; v7(132.53,59.24) 132.95,59.24 ; 117.69,108.93 v3(117.69,109.44) 117.69,109.94 ; 15.05,102.33 J1500.10 ; J1500.10 15.05,104.18 ; J1500.10 15.98,103.25 ; J1500.10 14.12,103.25 ; 36.21,103.31 v3(36.49,103.02) 36.79,103.32 ; v3(175.55,85.47) 176,85.47 ; v3(175.55,85.47) 175.1,85.47 ; v3(175.55,85.47) 175.55,85.84 ; J1200.G1 13.03,19.4 ; J1200.G1 9.47,19.4 ; J1200.G1 11.25,18.52 ; J1200.G1 11.25,20.28 ; U500.35 89.09,72.46 ; CON3000.7 11.63,71.35 ; CON3000.7 10.45,72.53 ; CON3000.7 9.27,71.35 ; CON3000.7 10.45,70.17 ; 123.07,51.51 v7(123.07,50.98) 122.64,50.98 ; v7(128.99,93.84) 128.99,94.24 ; v7(128.99,93.84) 129.41,93.84 ; v7(128.99,93.84) 128.56,93.84 ; 55.56,106.87 v3(55.56,107.3) 55.96,107.3 ; v1(53.3,37.3) 53.32,37.32 R808.2 ; 170.67,68.52 CT2500.2 ; CT2500.2 171.35,66.59 ; CT2500.2 172.02,68.52 ; CT2500.2 171.35,70.44 ; 38.5,26.97 v7(38.5,26.57) 38.08,26.57 ; 136.82,47.34 v3(136.82,47.74) 137.24,47.74 ; D2900.2 14.8,95.97 ; D2900.2 15.27,95.59 ; D2900.2 14.32,95.59 ; 106.83,117.53 C3423.1 ; C3423.1 107.81,118.21 ; C3423.1 105.86,118.21 ; 41.39,26.57 v7(40.96,26.57) 40.96,26.98 ; 115.25,105.72 v3(115.25,106.35) 115.83,106.35 ; 15.75,21.23 J1200.11 15.18,21.23 ; v3(43.25,63.66) 43.55,63.35 ; v3(43.25,63.66) 43.53,63.94 ; v3(43.25,63.66) 42.95,63.96 ; 58.91,112.18 R815.2 58.51,112.6 ; 87.35,122.33 v3(87.35,121.9) 87.75,121.9 ; 21.73,73.86 v3(21.73,74.26) 21.3,74.26 ; 35.12,34.51 C1104.2 35.54,34.11 ; C927.2 35.26,14.15 ; C927.2 34.83,13.75 ; C927.2 34.41,14.15 ; C617.2 58.36,62.5 ; C617.2 58.36,60.5 ; C617.2 59.13,61.5 ; C617.2 57.58,61.5 ; 86.6,96.05 v3(86.6,96.47) 87.13,96.47 ; 42.52,32.86 C1107.2 ; C1107.2 42.94,33.26 ; C1107.2 42.09,33.26 ; C910.2 29.83,22.52 ; C910.2 29.83,21.67 ; C910.2 29.43,22.1 ; 14.24,92.43 D2901.2 ; D2901.2 15.19,92.43 ; D2901.2 14.72,92.05 ; 35.35,60.54 v3(35.63,60.83) 35.33,61.13 ; 80.01,103.89 v3(80.01,104.66) ; CN2300.G2 163.64,39.13 ; CN2300.G2 163.64,36.03 ; CN2300.G2 164.42,37.58 ; 43.5,32.75 C1106.2 ; C1106.2 42.97,33.17 ; C1106.2 44.03,33.17 ; v3(175.55,105.42) 176,105.42 ; C3003.2 33.02,81.36 ; C3003.2 32.11,81.32 v3(31.36,81.32) ; C3003.2 32.07,80.4 ; J1300.G1 13.02,44.15 ; J1300.G1 11.25,45.02 ; J1300.G1 11.25,43.27 ; J1300.G1 9.47,44.15 ; J2001.U7 188.62,64.58 ; J2001.U7 187.74,63.7 ; J2001.U7 188.62,62.83 ; J2001.U7 189.5,63.7 ; 136.67,46.97 v3(136.27,46.97) 136.27,46.54 ; J2000.U7 189.5,41.76 ; J2000.U7 187.74,41.76 ; J2000.U7 188.62,40.88 ; J2000.U7 188.62,42.63 ; 136.37,72.44 v3(136.8,72.44) ; v3(136.8,72.44) 136.8,72.04 ; v3(136.8,72.44) 137.22,72.44 ; 29.83,21.66 C925.2 29.43,21.23 ; 52.84,23.97 v7(53.27,23.97) ; v7(53.27,23.97) 53.69,23.97 ; v7(53.27,23.97) 53.27,23.57 ; 83.26,103.89 v3(83.26,104.66) ; C827.2 56.04,110.57 ; C827.2 56.86,109.9 v3(57.05,109.72) ; C827.2 56.04,109.22 ; 95.65,28.05 R712.2 95.22,28.45 ; 11.71,45.97 J1300.5 12.28,45.97 ; C512.2 102.4,94.85 ; C512.2 101.4,94.07 ; C512.2 101.4,95.63 ; 144.54,35.86 CN2300.3 144.54,37.76 ; 187.8,45.26 J2000.U13 186.92,44.38 ; C2812.2 88.65,122.35 ; C2812.2 87.75,121.85 ; C2812.2 88.65,121.35 ; C2812.2 89.55,121.85 ; 39.85,103.16 v3(39.85,103.16) ; 39.85,103.16 40.17,102.85 ; 39.85,103.16 C2910.2 ; CON3000.6 4.05,63.83 ; CON3000.6 2.87,62.65 ; CON3000.6 5.23,62.65 ; CON3000.6 4.05,61.47 ; v3(175.6,40.37) 176.05,40.37 ; v3(175.6,40.37) 175.6,40.74 ; v3(175.6,40.37) 175.15,40.37 ; 71.5,102.75 C2828.2 ; C2828.2 72.3,102.25 ; C2828.2 73.1,102.75 ; C2828.2 72.3,103.25 ; 39.02,104.09 C2942.2 38.95,104.77 ; 110.7,104.9 v3(110.7,105.5) 111.05,105.5 ; v3(64.9,53.1) v3(64.9,52.85) ; 102.13,26.12 v3(102.13,27.05) 102.13,27.97 ; C3437.1 106.13,103.3 ; C3437.1 105.7,103.7 ; C3437.1 105.27,103.3 ; 43.17,24.43 C902.2 42.77,24 ; 55.57,99.44 v3(55.57,99.87) 55.57,100.29 ; v3(53.63,52.37) 53.63,52.37 v3(53.63,53.09) 53.08,53.09 53.07,53.1 ; 171.35,55.95 171.35,55.95 ; 90.24,64.61 C528.2 ; C528.2 89.74,65.41 ; C528.2 90.74,65.41 ; C528.2 90.24,66.21 ; 100.27,101.2 CT2700.2 ; CT2700.2 102.45,102.18 ; CT2700.2 102.45,100.22 ; CT2700.2 104.63,101.2 ; C2505.2 135.75,78.84 ; C2505.2 135.75,77.99 ; C2505.2 135.35,78.42 ; 38.93,57.11 v7(38.93,56.69) 39.33,56.69 ; TP1006.1 46.69,25.28 ; TP1006.1 47.36,24.6 ; TP1006.1 46.69,23.93 ; TP1006.1 46.01,24.6 ; C2822.2 75.7,121.85 v3(76.1,121.85) 76.1,122.28 ; C2822.2 74.8,122.35 ; C2822.2 73.9,121.85 ; C2822.2 74.8,121.35 ; 138.67,105.23 C3428.2 138.67,106.08 ; 49.01,99.31 C2923.2 49.59,99.33 ; 120.36,57.75 C516.2 ; C516.2 119.58,58.75 ; C516.2 120.36,59.75 ; C516.2 121.13,58.75 ; 179.48,2.59 J3600.1 ; J3600.1 180.45,3.71 ; J3600.1 178.5,3.71 ; J3600.1 179.48,4.84 ; 47.26,39.82 v7(47.79,39.82) ; v7(47.79,39.82) 48.31,39.82 ; v7(47.79,39.82) 47.79,39.4 ; 52.94,22.15 v1(53.36,22.15) ; v1(53.36,22.15) 53.79,22.15 ; v1(53.36,22.15) 53.36,21.75 ; v7(122.19,51.1) 122.59,51.1 ; v7(122.19,51.1) 122.19,51.53 ; v7(122.19,51.1) 122.19,50.68 ; 30.35,15.12 v7(30.78,15.12) ; v7(30.78,15.12) 30.78,15.52 ; v7(30.78,15.12) 31.21,15.12 ; 51.62,92.65 C2915.2 52.3,93.22 ; v3(98.33,24.35) 98.76,24.35 ; v3(98.33,24.35) 98.33,23.95 ; v3(98.33,24.35) 97.91,24.35 ; 12.29,21.23 J1200.5 11.71,21.23 ; 156.3,48.11 v7(156.3,47.74) 155.82,47.74 ; 63.15,67.84 C619.2 ; C619.2 62.15,68.62 ; C619.2 64.15,68.62 ; C619.2 63.15,69.39 ; 88.88,65.46 v7(89.31,65.46) ; v7(89.31,65.46) 89.74,65.46 ; v7(89.31,65.46) 89.31,65.06 ; v7(38.13,14.22) 38.55,14.22 ; v7(38.13,14.22) 37.7,14.22 ; v7(38.13,14.22) 38.13,13.82 ; J1901.10 179.66,101.89 ; J1901.10 178.78,102.77 ; J1901.10 178.78,101.01 ; J1901.10 177.9,101.89 ; 48.41,98.73 48.7,98.44 48.39,98.14 ; 44.14,23.83 TP907.1 ; TP907.1 44.81,24.51 ; TP907.1 44.81,23.16 ; TP907.1 45.49,23.83 ; 147.54,35.86 CN2300.15 147.54,37.76 ; v7(135.5,91.28) 135.92,91.28 ; v7(135.5,91.28) 135.5,90.88 ; v7(135.5,91.28) 135.07,91.28 ; 131.41,99.09 v7(131.41,98.69) 131.84,98.69 ; 58,21.94 v3(58,22.34) ; v3(58,22.34) 58.43,22.34 ; v3(58,22.34) 57.58,22.34 ; 98.63,33.77 v3(98.63,32.85) 98.63,31.92 ; v3(35.72,56.13) 35.72,56.44 ; v3(35.72,56.13) 36.25,56.13 ; v3(35.72,56.13) 35.2,56.13 ; 93.94,73.46 v7(94.41,73.46) 94.89,73.46 ; C2804.2 90.15,102.7 ; C2804.2 89.35,102.2 ; C2804.2 89.35,103.2 ; C2804.2 88.55,102.7 ; 47.82,57.7 v3(48.25,57.7) 48.67,57.7 ; v3(32.99,27.93) 32.99,28.36 ; v3(32.99,27.93) 33.52,27.93 ; v3(32.99,27.93) 32.47,27.93 ; 175.15,42.62 v3(175.6,42.62) ; v3(175.6,42.62) 176.05,42.62 ; v3(175.6,42.62) 175.6,42.99 ; v7(157.2,47.74) v3(156.76,48.19) ; R3011.1 32.27,64.12 ; R3011.1 31.97,64.58 v3(31.95,64.6) ; R3011.1 31.67,64.72 ; R3011.1 31.69,64.13 ; v3(63.65,26.17) 64.07,26.17 ; v3(63.65,26.17) 63.22,26.17 ; v3(63.65,26.17) 63.65,25.77 ; v3(132.35,72.49) 132.77,72.49 ; v3(132.35,72.49) 132.35,72.09 ; v3(132.35,72.49) 131.92,72.49 ; v7(130.77,111.76) 131.2,111.76 ; v7(130.77,111.76) 130.35,111.76 ; v7(130.77,111.76) 130.77,111.36 ; 122.32,2.97 C805.1 ; C805.1 122.32,4.02 ; C805.1 122.75,3.5 ; C3000.2 24.24,73.73 ; C3000.2 22.99,73.73 ; C3000.2 23.62,73.21 ; C517.2 121.13,60.9 ; C517.2 120.36,59.9 ; C517.2 119.58,60.9 ; 60.7,100.22 CT2701.2 ; CT2701.2 62.88,101.2 ; CT2701.2 60.7,102.18 ; CT2701.2 58.52,101.2 ; C2913.2 49.22,91.72 ; C2913.2 48.8,92.12 ; C2913.2 48.37,91.72 ; 54.63,22.33 C1008.2 ; C1008.2 55.48,22.33 ; C1008.2 55.05,21.93 ; 118.3,61.55 C532.2 ; C532.2 118.8,60.75 ; C532.2 119.3,61.55 ; C532.2 118.8,62.35 ; 25.21,88.16 C2927.2 ; C2927.2 26.46,88.16 ; C2927.2 25.84,88.68 ; 27.31,88.5 C2919.2 ; C2919.2 26.69,89.02 ; C2919.2 27.94,89.02 ; 186.92,66.33 J2001.U13 187.8,67.2 ; C3434.1 106.08,95 ; C3434.1 105.22,95 ; C3434.1 105.65,95.4 ; 88.46,65.05 v7(88.46,65.45) 88.88,65.45 ; C917.2 43.16,23.58 ; C917.2 42.76,23.15 ; C917.2 42.76,24 ; 23.88,104.23 v3(24.51,104.23) ; v3(24.51,104.23) 24.51,104.76 ; v3(24.51,104.23) 25.13,104.23 ; 93.94,71.96 v7(94.41,71.96) 94.89,71.96 ; 125.51,95.11 v7(125.51,95.51) 125.09,95.51 ; 39.72,32.85 C1108.2 ; C1108.2 40.14,33.25 ; C1108.2 39.29,33.25 ; 83.65,96.15 v7(83.65,96.55) 83.22,96.55 ; 60,68.62 C616.2 ; C616.2 61,69.39 ; C616.2 61,67.84 ; C616.2 62,68.62 ; 28.32,19.64 v7(28.85,19.64) ; v7(28.85,19.64) 28.85,19.22 ; v7(28.85,19.64) 29.37,19.64 ; C3013.2 27.77,70.15 ; C3013.2 27.14,69.63 ; C3013.2 28.39,69.63 ; 149.04,35.86 CN2300.21 149.04,37.76 ; v3(175.5,64.02) 175.95,64.02 ; v3(175.5,64.02) 175.5,64.39 ; v3(175.5,64.02) 175.05,64.02 ; v3(175.5,64.02) 175.5,63.64 ; C2521.2 133.45,68.07 ; C2521.2 133.05,67.64 ; C2521.2 133.05,68.49 ; 99.13,31.92 v3(99.13,32.85) 99.13,33.77 ; 29.45,19.55 C918.2 29.85,19.12 ; v7(68.02,53.51) 68.6,53.51 ; 110.55,107.52 C3420.1 ; C3420.1 110.55,108.37 ; C3420.1 110.95,107.94 ; 98.74,15.34 v3(98.74,15.74) 99.17,15.74 ; 29.56,28.32 v3(29.56,28.84) ; v3(29.56,28.84) 29.56,29.37 ; v3(29.56,28.84) 29.21,28.84 ; CT1901.2 171.35,76.74 ; CT1901.2 170.67,74.82 ; CT1901.2 171.35,72.89 ; 11.25,30.89 J1201.G1 ; J1201.G1 9.47,31.77 ; J1201.G1 13.02,31.77 ; J1201.G1 11.25,32.64 ; 34.04,62.42 v3(34.34,62.12) ; v3(34.34,62.12) 34.64,61.82 ; v3(34.34,62.12) 34.06,61.84 ; 178.78,79.06 J1900.10 ; J1900.10 178.78,80.82 ; J1900.10 179.66,79.94 ; J1900.10 177.9,79.94 ; v7(97.1,67.5) 97.33,67.28 98.1,67.28 ; 45.57,35.74 R1134.1 45.17,36.17 ; 100.13,23.95 v3(100.13,24.35) ; v3(100.13,24.35) 99.71,24.35 ; v3(100.13,24.35) 100.56,24.35 ; 24.78,52.72 v3(25.2,52.72) 25.2,52.32 ; 124.17,7.88 C803.2 ; C803.2 123.17,8.66 ; C803.2 124.17,9.43 ; C803.2 125.17,8.66 ; 38.18,46.72 38.6,46.72 ; 38.18,46.72 38.18,47.12 ; 38.18,46.72 37.75,46.72 ; 23.45,104.16 v3(23.45,103.76) 23.87,103.76 ; v7(36.7,28.6) 36.7,29 ; v7(36.7,28.6) 36.27,28.6 ; v7(36.7,28.6) 37.13,28.6 ; 46.65,45.28 v7(46.65,44.86) 47.05,44.86 ; 185.42,84.78 J1900.U16 ; J1900.U16 184.54,85.66 ; J1900.U16 186.3,85.66 ; J1900.U16 185.42,86.53 ; 145.69,48.13 v7(145.24,48.13) 145.24,48.51 ; 129.97,117.57 C3406.1 ; C3406.1 128.99,118.24 ; C3406.1 130.94,118.24 ; 33.83,36.24 C1103.2 ; C1103.2 33.43,36.66 ; C1103.2 33.83,37.09 ; CT2502.2 171.35,49.54 ; CT2502.2 172.02,47.62 ; CT2502.2 171.35,45.69 ; CT2502.2 170.67,47.62 ; 34.66,107.5 C2912.2 ; C2912.2 34.58,106.62 ; C2912.2 35.54,107.58 ; 28.67,71.19 v3(28.97,70.89) 28.68,70.6 ; 37.54,76.46 37.24,76.76 37.52,77.04 ; 108.95,89.04 C3429.2 109.35,89.47 ; 44.68,45.99 C1126.2 45.1,45.59 ; 150.54,35.86 CN2300.27 150.54,37.76 ; 142.94,36.03 CN2300.G1 ; CN2300.G1 142.17,37.58 ; CN2300.G1 142.94,39.13 ; 124.37,102 v7(124.8,102) ; v7(124.8,102) 125.23,102 ; v7(124.8,102) 124.8,102.4 ; 133.92,46.54 v3(133.92,46.97) ; v3(133.92,46.97) 133.92,47.39 ; v3(133.92,46.97) 133.52,46.97 ; 83.26,98.09 v3(83.26,98.86) 83.26,99.64 ; v7(125.49,98.67) 125.49,99.07 ; v7(125.49,98.67) 125.92,98.67 ; v7(125.49,98.67) 125.07,98.67 ; 26.31,77.91 C2932.2 ; C2932.2 26.93,77.39 ; C2932.2 27.56,77.91 ; 44.32,104.44 v3(44.75,104.44) ; v3(44.75,104.44) 44.75,104.32 v3(45.25,103.82) ; v3(44.75,104.44) 45.17,104.44 ; C1111.2 37.73,47.63 ; C1111.2 37.33,47.21 ; C1111.2 37.33,48.06 ; 175.05,61.87 v3(175.5,61.87) ; v3(175.5,61.87) 175.5,61.49 ; v3(175.5,61.87) 175.95,61.87 ; 23.52,87.65 v3(23.95,87.65) 23.95,88.05 ; C3035.2 26.18,52.72 v3(26.18,52.72) ; CON2900.5 11.63,82.65 ; CON2900.5 9.27,82.65 ; CON2900.5 10.45,81.47 ; CON2900.5 10.45,83.83 ; 170.67,53.72 CT2501.2 ; CT2501.2 171.35,55.64 ; CT2501.2 171.35,51.79 ; 164.27,2.58 J3601.1 ; J3601.1 164.27,4.83 ; J3601.1 165.25,3.71 ; J3601.1 163.29,3.71 ; 52.83,23.95 v7(52.4,23.95) 52.4,23.55 ; C1120.2 44.35,35.49 ; C1120.2 43.95,35.07 ; C1120.2 44.35,34.64 ; 129.35,109.38 v3(129.35,108.8) 129.98,108.8 ; 47.07,103.19 v7(47.07,103.62) ; v7(47.07,103.62) 46.67,103.62 ; v7(47.07,103.62) 47.07,104.04 ; 137.39,72.44 v7(137.82,72.44) ; v7(137.82,72.44) 137.82,72.04 ; v7(137.82,72.44) 138.24,72.44 ; 191,89.16 J1900.U4 190.12,88.28 ; 9.4,35.52 J1201.2 9.97,36.44 ; TP1107.1 31.16,37.1 ; TP1107.1 29.81,37.1 ; TP1107.1 30.49,36.43 ; TP1107.1 30.49,37.78 ; 76.05,103.05 v3(76.05,103.45) 76.48,103.45 ; 68.24,49.01 v7(68.24,49.41) 67.81,49.41 ; 161.54,37.76 CN2300.71 161.54,35.86 ; 29.85,15.67 v1(29.85,16.1) 29.45,16.1 ; 127.75,107.08 v3(127.75,106.65) 127.35,106.65 ; 58.36,62.65 C620.2 ; C620.2 58.36,64.65 ; C620.2 57.58,63.65 ; C620.2 59.13,63.65 ; 31.03,71.72 v7(31.34,72.02) ; v7(31.34,72.02) 31.64,72.32 ; v7(31.34,72.02) 31.05,72.3 ; 9.97,48.82 J1300.2 9.4,47.9 ; 129.8,56.69 v7(129.8,56.27) 129.27,56.27 ; 34.52,63.56 v3(34.81,63.84) 35.11,63.54 ; C822.2 47.8,57.5 ; C822.2 47.08,58.1 ; C822.2 46.35,57.5 ; 45.4,63.13 v3(44.92,62.65) 44.52,63.06 ; 105.1,90.17 C509.1 ; C509.1 105.5,90.6 ; C509.1 105.1,91.03 ; 125.35,11.77 v3(125.35,12.17) ; v3(125.35,12.17) 124.92,12.17 ; v3(125.35,12.17) 125.77,12.17 ; 31.28,97.6 C2941.2 ; C2941.2 31.29,97.01 ; C2941.2 31.88,96.99 ; C3415.1 117.79,108.37 ; C3415.1 117.79,107.52 ; C3415.1 118.19,107.95 ; 85.34,74.04 R513.2 85.74,73.61 ; 26.71,69.6 v3(26.71,69.2) 27.13,69.2 ; 47.87,53.07 v3(48.3,53.07) 48.73,53.07 ; 118.8,57.35 C530.2 ; C530.2 118.8,58.95 ; C530.2 119.3,58.15 ; C530.2 118.3,58.15 ; v7(28.05,24.37) 28.05,24.77 ; v7(28.05,24.37) 28.47,24.37 ; v7(28.05,24.37) 27.62,24.37 ; 36.95,77.61 v3(36.67,77.33) 36.37,77.63 ; 178.78,35.16 J2000.10 ; J2000.10 178.78,36.92 ; J2000.10 177.9,36.04 ; J2000.10 179.66,36.04 ; 87.21,65.45 v7(87.63,65.45) 87.63,65.05 ; 110.45,108.93 v3(110.45,109.43) 110.45,109.94 ; 33.44,37.52 C1117.2 33.84,37.09 ; 53.98,59.69 v3(53.98,60.09) 54.4,60.09 ; 171.35,94.99 CT1900.2 ; CT1900.2 172.02,96.92 ; CT1900.2 170.67,96.92 ; CT1900.2 171.35,98.84 ; 49.44,46.85 v3(49.96,46.85) ; v3(49.96,46.85) 49.96,47.2 ; v3(49.96,46.85) 50.49,46.85 ; 14.64,82.17 D2903.2 ; D2903.2 14.17,82.54 ; D2903.2 15.12,82.54 ; 47.28,70.33 C3026.2 46.7,70.31 ; 135.6,18.62 v3(135.6,19.05) ; v3(135.6,19.05) 135.6,19.48 ; v3(135.6,19.05) 135.2,19.05 ; CON2900.8 4.05,92.53 ; CON2900.8 5.23,91.35 ; CON2900.8 4.05,90.17 ; CON2900.8 2.87,91.35 ; 25,89.45 v3(25.42,89.45) 25.42,89.05 ; 121.35,14.07 v3(121.97,14.07) ; v3(121.97,14.07) 121.97,13.49 ; v3(121.97,14.07) 121.97,14.64 ; v3(121.97,14.07) 122.6,14.07 ; C507.1 99.34,73.13 ; C507.1 99.34,72.28 ; C507.1 99.74,72.71 ; 155.04,35.86 CN2300.45 ; CN2300.45 155.04,37.76 ; CN2300.45 155.02,37.14 155.02,37.71 v3(155.27,37.96) ; 15.17,33.59 J1201.11 15.75,33.59 ; C825.2 47.86,52.92 ; C825.2 46.4,52.92 ; C825.2 47.13,53.52 ; 86.81,66.6 C520.1 86.38,67 ; C513.2 104.5,94.85 ; C513.2 103.5,95.63 ; C513.2 103.5,94.07 ; C513.2 102.5,94.85 ; 12.86,36.44 J1201.8 13.44,36.44 ; 95.37,92.25 C511.2 ; C511.2 96.15,93.25 ; C511.2 96.93,92.25 ; C511.2 96.15,91.25 ; 152.04,37.76 CN2300.33 152.04,35.86 ; v7(128.92,20.07) 129.34,20.07 ; v7(128.92,20.07) 128.49,20.07 ; v7(128.92,20.07) 128.92,20.47 ; v7(56.74,36.25) 56.74,36.65 ; v7(56.74,36.25) 57.17,36.25 ; v7(56.74,36.25) 56.32,36.25 ; 120.6,10.79 C806.1 121,11.22 ; 171.35,30.6 171.35,30.6 ; v3(36.03,90.19) 36.41,89.81 ; v3(36.03,90.19) 35.66,90.56 ; v3(36.03,90.19) 35.73,89.88 ; 6.87,50.65 J1300.G2 ; J1300.G2 8.65,51.52 ; J1300.G2 10.42,50.65 ; J1300.G2 8.65,49.77 ; v3(133.17,62.04) 133.59,62.04 ; v3(133.17,62.04) 132.74,62.04 ; v3(133.17,62.04) 133.17,61.64 ; C2813.2 94.95,122.35 ; C2813.2 94.95,121.35 ; C2813.2 94.05,121.85 ; C2813.2 95.85,121.85 ; 34.18,76.92 R3002.1 33.6,76.9 ; 53.15,57.11 C820.2 ; C820.2 53.58,57.51 ; C820.2 54,57.11 ; 135.07,93.63 v7(135.5,93.63) ; v7(135.5,93.63) 135.92,93.63 ; v7(135.5,93.63) 135.5,94.03 ; C828.2 56.06,109.17 ; C828.2 56.06,107.72 ; C828.2 56.66,108.45 ; 28.05,21.57 R931.1 ; R931.1 27.62,21.97 ; R931.1 28.47,21.97 ; 97.4,63.4 C529.2 ; C529.2 98.2,62.9 ; C529.2 98.2,63.9 ; C529.2 99,63.4 ; v3(110.8,98.48) 110.8,98.91 ; v3(110.8,98.48) 110.8,98.06 ; v3(110.8,98.48) 111.2,98.48 ; 99.97,19.72 v3(100.82,19.72) ; v3(100.82,19.72) 101.67,19.72 ; v3(100.82,19.72) 100.82,20.09 ; 102.63,33.77 v3(102.63,32.85) 102.63,31.92 ; 36.35,78.37 C3040.2 36.42,77.69 ; 123.09,49.61 v7(123.09,50.03) 122.69,50.03 ; 46.8,64.49 v7(46.8,64.92) ; v7(46.8,64.92) 46.4,64.92 ; v7(46.8,64.92) 46.8,65.34 ; v7(137.67,62.04) 138.09,62.04 ; v7(137.67,62.04) 137.24,62.04 ; v7(137.67,62.04) 137.67,61.64 ; U2501.2 137.82,76.37 138.05,76.14 v3(138.54,76.14) ; 98.81,24.35 v3(99.23,24.35) ; v3(99.23,24.35) 99.23,23.95 ; v3(99.23,24.35) 99.66,24.35 ; 74.77,103.45 v3(75.2,103.45) 75.2,103.05 ; 75.22,97.35 v3(75.65,97.35) 75.65,97.75 ; 8.65,37.39 J1201.G2 ; J1201.G2 6.87,38.27 ; J1201.G2 10.42,38.27 ; J1201.G2 8.65,39.14 ; 108.8,98.96 v3(108.8,99.53) 108.18,99.53 ; 128.56,91.51 v7(128.99,91.51) ; v7(128.99,91.51) 128.99,91.11 ; v7(128.99,91.51) 129.41,91.51 ; 29.82,23.81 v3(29.82,24.24) ; v3(29.82,24.24) 29.42,24.24 ; v3(29.82,24.24) 29.82,24.66 ; v3(38.55,28.52) 38.55,28.92 ; v3(38.55,28.52) 38.97,28.52 ; v3(38.55,28.52) 38.12,28.52 ; 106.72,16.7 v3(107.15,16.7) ; v3(107.15,16.7) 107.15,16.3 ; v3(107.15,16.7) 107.58,16.7 ; 32.3,38.85 v3(32.3,39.28) 31.9,39.28 ; 50.33,102 C2924.2 ; C2924.2 51.21,102.08 ; C2924.2 50.26,101.12 ; C2511.2 131.45,78.84 ; C2511.2 131.05,78.42 ; C2511.2 131.45,77.99 ; 20.75,18.52 J1200.G4 ; J1200.G4 18.97,19.4 ; J1200.G4 22.53,19.4 ; J1200.G4 20.75,20.28 ; 59.58,20.7 U1001.3 ; U1001.3 60.1,21.05 ; U1001.3 60.63,20.7 ; 99.17,18.09 v3(98.74,18.09) 98.74,18.49 ; 101.63,27.97 v3(101.63,27.05) 101.63,26.12 ; 191,67.2 J2001.U4 190.12,66.33 ; 49.72,72.23 C3024.2 ; C3024.2 50.67,73.18 ; C3024.2 50.6,72.3 ; 38.58,13.3 38.98,13.3 ; 38.98,13.3 38.98,13.73 ; 38.98,13.3 38.98,12.88 ; 69.25,122.28 v3(69.25,121.85) 68.85,121.85 ; TP2500.1 136.12,59.02 ; TP2500.1 134.77,59.02 ; TP2500.1 135.45,59.69 ; 59.03,21.86 v7(59.03,22.28) ; v7(59.03,22.28) 58.51,22.28 ; v7(59.03,22.28) 59.56,22.28 ; 85.09,69.43 C522.1 84.64,70.01 ; 9.27,62.65 CON3000.5 ; CON3000.5 10.45,63.83 ; CON3000.5 11.63,62.65 ; CON3000.5 10.45,61.47 ; 77.06,98.86 v3(77.41,98.86) 77.41,99.64 ; 101.03,23.95 v3(101.03,24.35) ; v3(101.03,24.35) 100.61,24.35 ; v3(101.03,24.35) 101.46,24.35 ; 47.88,70.92 C3025.2 47.89,71.51 ; v3(30.79,65.62) 31.09,65.32 ; v3(30.79,65.62) 30.51,65.34 ; v3(30.79,65.62) 30.49,65.92 ; D2902.2 15.18,85.52 ; D2902.2 14.7,85.9 ; D2902.2 14.23,85.52 ; 52.6,36.57 C1028.2 53.02,36.17 ; v7(97.45,21.7) 97.45,22.1 ; v7(97.45,21.7) 97.88,21.7 ; v7(97.45,21.7) 97.02,21.7 ; C1110.2 47.07,38.99 ; C1110.2 46.67,38.56 ; C1110.2 46.67,39.42 ; 34.96,101.15 v3(34.95,101.15) ; 62.35,34.35 v3(61.95,34.35) 61.95,34.78 ; C804.2 126.32,9.4 ; C804.2 127.32,8.63 ; C804.2 126.32,7.85 ; C804.2 125.32,8.63 ; 64.99,52.96 65.04,53.01 v7(65.79,53.01) ; 88.1,103 C2803.2 88.53,103.4 ; 91,102.2 C2805.2 ; C2805.2 90.2,102.7 ; C2805.2 91,103.2 ; J1901.U7 189.5,107.61 ; J1901.U7 188.62,108.48 ; J1901.U7 187.74,107.61 ; J1901.U7 188.62,106.73 ; 175.55,83.04 v3(175.55,83.42) ; v3(175.55,83.42) 176,83.42 ; v3(175.55,83.42) 175.1,83.42 ; 38,34.12 v7(38,34.52) 38.42,34.52 ; 55.1,66.39 C3200.2 55.62,65.97 ; 125.4,92.5 125.42,92.48 v7(126.22,92.48) ; 101.45,73.94 v7(101.45,74.47) 101.84,74.47 ; v7(132.15,62.04) 132.57,62.04 ; v7(132.15,62.04) 131.72,62.04 ; v7(132.15,62.04) 132.15,61.64 ; v3(31.51,74.39) 31.81,74.69 ; v3(31.51,74.39) 31.23,74.67 ; v3(31.51,74.39) 31.21,74.09 ; J1901.U16 185.42,108.48 ; J1901.U16 185.42,106.73 ; J1901.U16 184.54,107.61 ; J1901.U16 186.3,107.61 ; 37.75,46.72 v7(37.33,46.72) 37.33,47.12 ; 46.97,28.6 v1(47.37,28.6) 47.37,28.17 ; 13.44,48.82 J1300.8 12.86,48.82 ; 41.05,46.79 v7(41.47,46.79) ; v7(41.47,46.79) 41.9,46.79 ; v7(41.47,46.79) 41.47,47.19 ; 127.95,107.12 v3(127.95,107.7) 127.32,107.7 ; 123.04,56.85 C2500.1 123.04,56 ; 191,111.11 J1901.U4 190.12,110.23 ; v3(63.65,28.57) 63.65,28.97 ; v3(63.65,28.57) 64.07,28.57 ; v3(63.65,28.57) v7(64.2,29.12) ; v3(63.65,28.57) 63.22,28.57 ; CT1902.2 171.35,113.64 ; CT1902.2 170.67,111.72 ; CT1902.2 172.02,111.72 ; CT1902.2 171.35,109.79 ; C3015.2 31.12,76.12 ; C3015.2 30.16,77.07 ; C3015.2 30.24,76.19 ; 42.92,107.64 v3(43.35,107.64) 43.35,108.04 ; 88.52,79.47 C551.1 88.12,79.05 ; 129.77,51.07 v7(130.17,51.07) 130.17,50.64 ; 158.57,47.74 v7(158.1,47.74) 158.1,48.11 ; v3(55.83,60.09) 55.01,60.09 v7(55,60.1) ; 129.12,16.57 v7(129.12,17.47) ; v7(129.12,17.47) 128.79,17.47 ; v7(129.12,17.47) 129.12,18.37 ; 33.11,92.29 R2921.1 ; R2921.1 33.72,91.69 ; R2921.1 33.13,91.71 ; 85.22,121 D2801.1 85.7,121.38 ; C3034.2 27.72,52.29 ; C3034.2 27.09,51.77 ; C3034.2 26.47,52.29 ; J2000.U16 186.3,41.76 ; J2000.U16 184.54,41.76 ; J2000.U16 185.42,42.63 ; J2000.U16 185.42,40.88 ; v7(128.75,56.14) 128.75,56.54 ; v7(128.75,56.14) 128.32,56.14 ; v7(128.75,56.14) 129.17,56.14 ; C3424.1 135.4,102.4 ; C3424.1 134.97,102 ; C3424.1 135.83,102 ; 126.81,98.88 v7(126.81,98.35) 126.53,98.35 ; C2515.2 137.95,68.12 ; C2515.2 137.55,68.54 ; C2515.2 137.55,67.69 ; v3(34.03,27.88) 34.45,27.88 ; v3(34.03,27.88) 34.03,28.28 ; v3(34.03,27.88) 33.6,27.88 ; 25.04,77.94 v3(25.04,78.34) 24.62,78.34 ; v3(43.85,63.05) 44.14,63.33 ; v3(43.85,63.05) 44.16,62.75 ; v3(43.85,63.05) 43.55,63.35 ; 135.07,98.45 v3(135.5,98.45) ; v3(135.5,98.45) 135.92,98.45 ; v3(135.5,98.45) 135.5,98.85 ; v7(128.86,96.36) 129.29,96.36 ; 125.05,23.49 v7(125.05,23.06) 124.65,23.06 ; 125.26,109.94 v3(125.26,109.43) 125.26,108.93 ; 91.52,121 D2800.1 92,121.38 ; 45.47,104.77 v7(45.9,104.77) ; v7(45.9,104.77) 46.32,104.77 ; v7(45.9,104.77) 45.9,104.47 ; 48.52,26.01 C1003.2 48.92,26.44 ; 133.37,72.09 v7(133.37,72.49) ; v7(133.37,72.49) 133.79,72.49 ; v7(133.37,72.49) 132.94,72.49 ; v7(127.97,58.46) 128.37,58.46 ; v7(127.97,58.46) 127.97,58.03 ; v7(127.97,58.46) 127.97,58.88 ; C550.1 88.04,78.24 ; C550.1 87.19,78.24 ; C550.1 87.61,78.64 ; 25.2,61.4 25.22,61.42 v7(25.22,62.02) ; 15.55,60.85 D3002.2 15.07,61.22 ; 49.36,47.05 v7(48.96,47.05) 48.96,47.48 ; 135.5,95.72 v3(135.5,96.12) ; v3(135.5,96.12) 135.93,96.12 ; v3(135.5,96.12) 135.08,96.12 ; 33.64,98.13 R2912.2 ; R2912.2 33.66,98.71 ; R2912.2 34.25,98.73 ; 19.22,21.23 J1200.17 18.64,21.23 ; 133.45,109.94 v7(133.45,109.44) 133.45,108.93 ; 60.29,34.89 C1026.2 59.86,35.29 ; C3433.2 129.29,98.71 ; 94.05,121.9 v3(93.65,121.9) 93.65,122.33 ; 38.56,14.22 C928.2 38.98,13.82 ; 133.45,47.39 v7(133.45,47.79) 133.87,47.79 ; 107.9,25.63 v3(107.9,25.2) 108.3,25.2 ; 92.54,63.73 v7(92.54,63.31) 92.54,62.88 ; 17.65,25.02 J1200.G3 ; J1200.G3 15.87,25.9 ; J1200.G3 19.43,25.9 ; J1200.G3 17.65,26.78 ; v3(85.86,98.86) 85.86,99.64 ; v3(85.86,98.86) 86.21,98.86 ; v3(85.86,98.86) 85.86,98.09 ; C2314.1 144.09,49.36 ; C2314.1 143.37,48.76 ; C2314.1 144.82,48.76 ; 115.62,16.15 C801.2 115.09,15.52 ; 18.64,33.59 J1201.17 19.21,33.59 ; v3(133.05,76.32) 133.37,76.64 U2502.2 ; v7(162.54,47.58) 162.54,47.98 ; v7(162.54,47.58) 162.12,47.58 ; v7(162.54,47.58) 162.97,47.58 ; 135.35,22.85 v3(135.75,22.85) ; v3(135.75,22.85) v2(135.75,23.28) ; v3(135.75,22.85) 135.75,22.42 ; v3(73.3,24.95) 71.69,23.34 J2800.2 ; 29.36,28.24 v3(29.36,27.84) 28.94,27.84 ; v3(34.58,90.83) 34.88,90.53 ; v3(34.58,90.83) 34.28,91.13 ; v3(34.58,90.83) 34.3,90.54 ; 43.16,22.71 R927.1 42.76,23.13 ; C2302.1 163.85,48.73 ; C2302.1 164.58,48.12 ; C2302.1 163.12,48.12 ; 146.04,35.86 CN2300.9 146.04,37.76 ; 85.34,73.16 C503.1 85.74,73.58 ; J1300.G4 22.52,44.15 ; J1300.G4 20.75,45.02 ; J1300.G4 18.97,44.15 ; J1300.G4 20.75,43.27 ; 52.02,63.39 C3201.2 51.3,62.79 ; 13.44,24.07 J1200.8 12.87,24.07 ; 33.27,98.99 33.56,99.28 ; 33.27,98.99 32.97,99.29 ; 33.27,98.99 33.57,98.69 ; 14.02,67.57 D3001.2 14.5,67.19 ; 51.71,113.2 v3(52.14,113.2) 52.14,113.72 ; 120.69,118.31 C3413.1 ; C3413.1 122.64,118.31 ; C3413.1 121.66,117.64 ; 15.17,45.97 J1300.11 15.75,45.97 ; 56.6,44.17 v7(56.6,43.74) 57.13,43.74 ; C3408.1 125.76,107.94 ; C3408.1 125.36,107.52 ; C3408.1 125.36,108.37 ; v3(36.95,88.53) 37.25,88.23 ; v3(36.95,88.53) 36.67,88.24 ; v3(36.95,88.53) 36.65,88.83 ; C813.2 53.08,40.04 ; C813.2 51.73,40.04 ; C813.2 52.4,39.47 ; 33.4,42.35 C1118.2 33.8,41.92 ; 37.13,89.97 v3(37.42,90.25) 37.72,89.95 ; 58.91,113.15 C830.2 58.51,112.72 ; C3208.2 55.92,105.42 ; C3208.2 55.52,104.99 ; C3208.2 55.52,105.84 ; 106.03,24.05 v3(106.03,24.45) ; v3(106.03,24.45) 106.46,24.45 ; v3(106.03,24.45) 105.61,24.45 ; v7(131.63,59.24) 132.05,59.24 ; v7(131.63,59.24) 131.63,59.64 ; v7(131.63,59.24) 131.2,59.24 ; 68.39,57.78 v7(68.39,58.21) ; v7(68.39,58.21) 68.39,58.63 ; v7(68.39,58.21) 67.98,58.21 ; 70.69,21.77 J2800.2 ; J2800.2 68.37,23.34 ; J2800.2 70.69,24.92 ; R1018.2 53.45,36.57 ; R1018.2 53.87,36.17 ; R1018.2 53.02,36.17 ; 162.04,37.76 CN2300.73 162.04,35.86 ; 59.1,21.32 v1(59.1,20.9) 59.5,20.9 ; 50.73,20.13 50.73,20.13 ; C2914.2 48.36,91.72 ; C2914.2 47.94,92.12 ; C2914.2 47.51,91.72 ; 57.33,17.98 57.34,17.99 ; 12.28,33.59 J1201.5 11.71,33.59 ; 124.92,16.17 R714.2 ; R714.2 125.35,16.57 ; R714.2 125.77,16.17 ; 37.11,92.19 v7(36.81,91.89) 36.51,91.59 ; 56.32,99.44 C3221.2 56.32,100.29 ; U2505.2 v7(133.17,67.54) ; 45.22,108.14 v3(44.5,108.14) 44.5,108.74 ; 158.04,35.86 CN2300.57 ; CN2300.57 158.37,36.81 ; CN2300.57 158.04,37.76 ; 170.28,96.92 v3(170.25,96.95) ; v3(175.55,107.32) 176,107.32 ; v3(175.55,107.32) 175.1,107.32 ; v3(175.55,107.32) 175.55,107.69 ; 50.7,23.55 v3(50.7,23.95) 50.27,23.95 ; 153.54,37.76 CN2300.39 153.54,35.86 ; 74.24,52.43 v3(74.24,52.86) 74.64,52.86 ; 34.5,65.78 v3(34.2,65.48) 33.9,65.18 ; 49.13,40.52 v7(49.55,40.52) 49.55,40.12 ; v3(132.58,92.31) 131.81,92.31 131.8,92.3 ; J1300.G3 17.65,51.52 ; J1300.G3 17.65,49.77 ; J1300.G3 15.87,50.65 ; J1300.G3 19.42,50.65 ; 62.34,29.3 v3(61.94,29.3) 61.94,28.88
  BOTTOM w0.25: 45.85,78.69 45.87,78.72
  vias: v1(1.35,37.97) v1(1.41,22.79) v1(1.51,42.47) v1(1.48,40.16) v1(1.47,25.33) v1(1.62,98.49) v1(1.62,96.68) v1(1.56,95.08) v1(1.55,9.66) v1(1.74,48.96) v1(1.66,16.06) v1(1.66,11.7) v1(1.84,90.01) v1(1.84,87.81) v1(1.84,85.61) v1(1.76,58.44) v1(1.76,52.12) v1(1.83,32.51) v1(1.83,30.36) v1(1.76,18.1) v1(1.9,126.73) v1(1.87,71.02) v1(1.87,68.82) v1(1.87,66.62) v1(1.86,60.48) v1(1.86,54.16) v1(1.86,28.18) v1(2.2,75.28) v1(2.21,45.67) v1(2.15,34.75) v1(2.23,21.13) v1(2.3,77.32) v1(2.36,36.97) v1(2.45,24.27) v1(2.54,99.55) v1(2.53,72.92) v1(2.46,39.05) v1(2.46,26.65) v1(2.54,12.83) v1(2.57,97.51) v1(2.57,95.83) v1(2.64,14.87) v1(2.59,10.69) v1(2.74,55.32) v1(2.74,41.25) v1(2.69,17.09) v1(2.79,59.48) v1(2.85,57.36) v1(2.79,53.15) v1(2.84,51.22) v1(2.81,47.95) v1(2.88,93.92) v1(2.86,31.56) v1(2.85,19.81) v1(3.04,107.42) v1(3,29.27) v1(3.09,110.15) v1(3.05,33.73) v1(3.23,76.31) v1(3.29,119.83) v1(3.29,117.55) v1(3.32,44.62) v1(3.36,35.82) v1(3.46,127.96) v1(3.53,94.85) v1(3.55,37.97) v1(3.54,9.68) v1(3.63,96.89) v1(3.61,22.79) v1(3.65,16.08) v1(3.57,13.86) v1(3.57,11.72) v1(3.73,101.08) v1(3.75,74.11) v1(3.75,58.47) v1(3.75,52.14) v1(3.71,42.47) v1(3.68,40.16) v1(3.67,25.33) v1(3.67,18.12) v1(3.77,60.51) v1(3.77,56.35) v1(3.77,54.18) v1(3.94,48.96) v1(3.85,46.81) v1(4.03,32.51) v1(4.03,30.36) v1(4.06,111.94) v1(4.12,105.91) v1(4.06,28.18) v1(4.16,128.78) v1(4.2,108.76) v1(4.21,77.34) v1(4.19,75.3) v1(4.31,116.65) v1(4.4,118.63) v1(4.41,45.67) v1(4.35,34.75) v1(4.43,21.13) v1(4.45,10.71) v1(4.48,121.11) v1(4.55,17.12) v1(4.55,14.9) v1(4.52,12.86) v1(4.56,95.88) v1(4.62,43.56) v1(4.56,36.97) v1(4.65,24.27) v1(4.73,72.92) v1(4.65,59.5) v1(4.73,55.34) v1(4.65,53.18) v1(4.66,39.05) v1(4.66,26.65) v1(4.76,57.38) v1(4.87,93.94) v1(4.94,41.25) v1(5.04,51.22) v1(5.01,47.95) v1(5.09,78.38) v1(5.09,76.34) v1(5.06,31.56) v1(5.05,19.81) v1(5.21,112.68) v1(5.24,107.42) v1(5.19,80.41) v1(5.2,29.27) v1(5.29,110.15) v1(5.25,33.73) v1(5.42,48.89) v1(5.43,13.89) v1(5.49,119.83) v1(5.49,117.55) v1(5.54,96.91) v1(5.52,94.87) v1(5.52,44.62) v1(5.48,11.72) v1(5.45,9.63) v1(5.59,128.1) v1(5.64,98.57) v1(5.63,56.38) v1(5.56,35.82) v1(5.58,18.12) v1(5.56,16.03) v1(5.69,60.51) v1(5.66,58.42) v1(5.69,54.18) v1(5.68,52.11) v1(5.65,42.44) v1(5.72,40.19) v1(5.81,22.79) v1(5.93,101.08) v1(5.95,74.11) v1(5.87,25.33) v1(6.12,79.41) v1(6.12,77.34) v1(6.1,75.25) v1(6.05,46.81) v1(6.23,30.36) v1(6.26,111.94) v1(6.32,105.91) v1(6.26,28.18) v1(6.36,128.78) v1(6.4,108.76) v1(6.42,95.91) v1(6.43,12.81) v1(6.51,116.65) v1(6.47,93.89) v1(6.53,92.98) v1(6.5,34.76) v1(6.46,14.9) v1(6.51,10.69) v1(6.6,118.63) v1(6.64,55.29) v1(6.62,17.09) v1(6.68,121.11) v1(6.72,59.48) v1(6.67,57.38) v1(6.72,53.15) v1(6.68,47.96) v1(6.73,37.02) v1(6.82,43.56) v1(6.85,24.27) v1(6.93,72.92) v1(6.87,41.26) v1(6.86,26.65) v1(7.11,80.44) v1(7.08,78.4) v1(7.14,31.52) v1(7.16,76.31) v1(7.3,100.11) v1(7.25,19.81) v1(7.31,1.47) v1(7.38,122.48) v1(7.41,112.68) v1(7.44,107.42) v1(7.36,96.85) v1(7.38,94.9) v1(7.4,29.27) v1(7.44,9.68) v1(7.49,110.15) v1(7.54,16.09) v1(7.49,13.86) v1(7.47,11.75) v1(7.58,127.67) v1(7.65,58.47) v1(7.65,52.14) v1(7.62,48.89) v1(7.57,18.15) v1(7.69,119.83) v1(7.69,117.55) v1(7.67,60.53) v1(7.7,56.35) v1(7.67,54.21) v1(7.69,35.76) v1(7.85,42.44) v1(7.92,40.19) v1(7.98,79.43) v1(8.13,101.08) v1(8.09,75.3) v1(8.15,74.11) v1(8.33,93.92) v1(8.29,77.28) v1(8.34,6.58) v1(8.34,2.5) v1(8.44,95.96) v1(8.45,14.92) v1(8.42,12.86) v1(8.42,10.71) v1(8.45,8.62) v1(8.46,111.94) v1(8.52,105.91) v1(8.5,72.9) v1(8.53,17.12) v1(8.56,128.78) v1(8.6,108.76) v1(8.63,59.5) v1(8.63,55.34) v1(8.63,53.18) v1(8.59,19.16) v1(8.66,126.4) v1(8.71,116.65) v1(8.74,98.65) v1(8.73,92.98) v1(8.65,57.41) v1(8.74,45.03) v1(8.73,43.63) v1(8.73,35.03) v1(8.7,34.76) v1(8.72,34.11) v1(8.65,21.86) v1(8.78,123.82) v1(8.8,118.63) v1(8.79,47.38) v1(8.84,32.62) v1(8.83,31.15) v1(8.78,20.37) v1(8.88,47.96) v1(8.93,37.02) v1(8.87,22.66) v1(8.89,17.91) v1(8.99,78.35) v1(9.01,39.32) v1(9.07,76.34) v1(9.07,41.26) v1(9.19,80.42) v1(9.24,46.04) v1(9.15,35.25) v1(9.22,3.46) v1(9.27,96.88) v1(9.31,21.37) v1(9.33,5.5) v1(9.3,1.5) v1(9.36,94.95) v1(9.43,33.73) v1(9.4,13.89) v1(9.42,11.83) v1(9.38,7.62) v1(9.53,52.17) v1(9.47,42.58) v1(9.49,9.44) v1(9.61,112.68) v1(9.58,58.47) v1(9.61,56.38) v1(9.64,54.21) v1(9.6,30.09) v1(9.69,60.51) v1(9.83,32.76) v1(9.91,127.71) v1(9.94,125.16) v1(9.92,99.07) v1(9.93,16.99) v1(10.05,79.41) v1(10.02,40.19) v1(10.12,27.45) v1(10.11,24.72) v1(10.2,119.7) v1(10.23,41.8) v1(10.21,12.94) v1(10.2,2.53) v1(10.35,95.98) v1(10.32,93.94) v1(10.3,10.75) v1(10.33,6.61) v1(10.26,4.49) v1(10.45,29.2) v1(10.36,8.65) v1(10.47,97.99) v1(10.54,35.9) v1(10.5,18.09) v1(10.62,59.5) v1(10.57,55.42) v1(10.57,53.2) v1(10.58,48.74) v1(10.72,74.24) v1(10.7,72.9) v1(10.67,57.46) v1(10.75,45.96) v1(10.74,45.35) v1(10.66,30.25) v1(10.82,76.28) v1(10.93,92.98) v1(10.9,33.54) v1(10.98,123.82) v1(11,80.47) v1(10.98,78.4) v1(11,37.02) v1(11.08,42.8) v1(11.22,94.98) v1(11.21,39.32) v1(11.23,26.02) v1(11.21,16.89) v1(11.21,13.6) v1(11.15,12.63) v1(11.15,7.62) v1(11.24,5.52) v1(11.21,3.48) v1(11.21,1.45) v1(11.3,96.82) v1(11.29,15.68) v1(11.26,14.67) v1(11.28,11.84) v1(11.45,121.14) v1(11.37,41.1) v1(11.51,99.02) v1(11.55,54.23) v1(11.52,52.19) v1(11.47,51.08) v1(11.48,9.44) v1(11.6,60.53) v1(11.57,58.49) v1(11.6,56.45) v1(11.65,28.32) v1(11.65,12.75) v1(11.7,29.83) v1(11.79,128.79) v1(11.75,75.28) v1(11.78,42.08) v1(11.75,36) v1(11.78,30.52) v1(11.78,11.17) v1(11.88,126.4) v1(11.92,93.89) v1(11.96,79.43) v1(11.98,17.96) v1(12.11,4.52) v1(12.22,40.19) v1(12.24,6.56) v1(12.28,127.67) v1(12.34,122.62) v1(12.32,27.45) v1(12.31,24.72) v1(12.27,2.5) v1(12.4,119.7) v1(12.39,98.01) v1(12.39,95.98) v1(12.42,53.23) v1(12.37,38.47) v1(12.4,32.78) v1(12.45,21.42) v1(12.48,59.53) v1(12.54,33.73) v1(12.62,80.51) v1(12.59,69.61) v1(12.59,67.41) v1(12.59,65.21) v1(12.58,57.49) v1(12.55,55.45) v1(12.75,90.87) v1(12.72,82.55) v1(12.73,76.31) v1(12.71,74.27) v1(12.66,46) v1(12.73,11.86) v1(12.73,10.2) v1(12.75,88.88) v1(12.75,86.68) v1(12.75,84.48) v1(12.78,48.74) v1(12.8,42.78) v1(12.85,35.9) v1(12.82,15.9) v1(12.84,15.11) v1(12.8,14.08) v1(12.88,92.91) v1(12.9,72.9) v1(12.92,49.92) v1(12.92,17.87) v1(12.91,16.63) v1(12.87,13.22) v1(12.96,128.78) v1(12.98,94.95) v1(13.04,41.08) v1(13.05,29.21) v1(13.09,31.05) v1(13.15,5.52) v1(13.12,3.43) v1(13.25,121.14) v1(13.21,99.02) v1(13.21,96.85) v1(13.2,37.02) v1(13.2,1.5) v1(13.3,7.62) v1(13.43,77.39) v1(13.43,52.14) v1(13.43,26.02) v1(13.53,79.43) v1(13.51,64.64) v1(13.51,60.53) v1(13.48,58.44) v1(13.46,56.48) v1(13.46,54.23) v1(13.52,20.5) v1(13.64,87.8) v1(13.61,75.3) v1(13.59,70.97) v1(13.61,66.68) v1(13.58,45.2) v1(13.7,89.89) v1(13.65,81.54) v1(13.69,73) v1(13.67,51.08) v1(13.72,43.93) v1(13.81,91.93) v1(13.84,42.73) v1(13.77,32.67) v1(13.8,10.75) v1(13.77,9.16) v1(13.91,93.94) v1(13.86,28.33) v1(14.02,35.9) v1(13.96,31.04) v1(14.01,4.48) v1(14.1,33.69) v1(14.12,29.84) v1(14.15,17.55) v1(14.18,127.67) v1(14.24,98.01) v1(14.17,39.92) v1(14.23,19.04) v1(14.23,6.61) v1(14.18,2.53) v1(14.3,96.01) v1(14.29,46.1) v1(14.32,21.21) v1(14.44,61.44) v1(14.39,16.11) v1(14.37,14.92) v1(14.36,14.03) v1(14.52,84.77) v1(14.46,78.43) v1(14.52,67.76) v1(14.54,65.67) v1(14.54,63.48) v1(14.54,59.5) v1(14.49,57.49) v1(14.46,55.4) v1(14.49,53.2) v1(14.52,27.45) v1(14.51,24.72) v1(14.6,119.7) v1(14.59,86.82) v1(14.63,82.57) v1(14.61,80.53) v1(14.64,76.31) v1(14.62,74.22) v1(14.62,72) v1(14.62,69.8) v1(14.57,38.47) v1(14.59,11.25) v1(14.74,90.92) v1(14.7,88.86) v1(14.7,48.73) v1(14.72,29.1) v1(14.84,41.06) v1(14.82,32) v1(14.89,94.98) v1(14.86,92.94) v1(14.91,12.42) v1(15.05,45.24) v1(15.05,42.61) v1(15.12,99.04) v1(15.12,49.92) v1(15.06,41.88) v1(15.07,33) v1(15.14,5.55) v1(15.11,3.48) v1(15.06,1.5) v1(15.16,128.78) v1(15.2,36) v1(15.21,7.64) v1(15.26,126.4) v1(15.33,96.84) v1(15.32,29.77) v1(15.38,123.82) v1(15.44,109.5) v1(15.45,79.46) v1(15.42,77.42) v1(15.45,54.26) v1(15.42,52.19) v1(15.4,9.74) v1(15.47,83.78) v1(15.51,81.56) v1(15.55,68.8) v1(15.52,66.7) v1(15.5,64.66) v1(15.47,62.47) v1(15.5,60.56) v1(15.47,58.49) v1(15.52,56.45) v1(15.51,37.02) v1(15.63,87.85) v1(15.57,85.82) v1(15.6,73.03) v1(15.57,70.99) v1(15.62,43.34) v1(15.58,32.02) v1(15.63,26.02) v1(15.65,19.75) v1(15.57,8.3) v1(15.72,91.96) v1(15.69,89.92) v1(15.68,75.28) v1(15.72,33.82) v1(15.77,93.97) v1(15.82,21.27) v1(15.75,17.81) v1(15.89,110.17) v1(15.94,46.25) v1(15.9,30.72) v1(15.93,28.33) v1(15.94,18.86) v1(15.92,16.67) v1(15.9,15.88) v1(15.9,15.1) v1(15.87,14.29) v1(15.88,13.63) v1(16.01,6.56) v1(16.14,112.29) v1(16.11,104.78) v1(16.09,4.52) v1(16.09,2.53) v1(16.16,108.23) v1(16.16,98.04) v1(16.38,127.67) v1(16.36,113.76) v1(16.45,106.22) v1(16.4,78.35) v1(16.4,65.7) v1(16.43,61.46) v1(16.4,53.23) v1(16.37,39.92) v1(16.54,125.16) v1(16.5,84.82) v1(16.54,82.57) v1(16.52,80.48) v1(16.48,72.02) v1(16.53,69.83) v1(16.5,67.79) v1(16.45,63.5) v1(16.45,59.53) v1(16.48,57.51) v1(16.45,55.45) v1(16.53,46.24) v1(16.52,12.14) v1(16.58,107.71) v1(16.59,90.95) v1(16.61,88.88) v1(16.58,86.84) v1(16.63,76.34) v1(16.61,74.27) v1(16.62,41.1) v1(16.59,33.78) v1(16.67,111.21) v1(16.67,94.96) v1(16.67,92.94) v1(16.73,30.47) v1(16.75,24.67) v1(16.8,119.7) v1(16.79,29.09) v1(16.82,9.58) v1(16.9,48.73) v1(16.93,19.81) v1(16.96,108.81) v1(17.03,16.64) v1(17.05,7.59) v1(16.99,3.54) v1(17.05,1.52) v1(17.1,18.05) v1(17.1,5.58) v1(17.23,52.22) v1(17.33,77.37) v1(17.33,62.5) v1(17.33,54.26) v1(17.26,41.88) v1(17.3,36.25) v1(17.33,12.85) v1(17.36,128.78) v1(17.36,79.46) v1(17.41,68.82) v1(17.43,66.7) v1(17.41,64.61) v1(17.43,56.48) v1(17.42,33.87) v1(17.46,126.4) v1(17.49,87.88) v1(17.49,85.85) v1(17.46,83.81) v1(17.51,73.03) v1(17.49,70.94) v1(17.49,58.55) v1(17.58,123.82) v1(17.63,91.96) v1(17.6,89.86) v1(17.58,81.54) v1(17.59,75.3) v1(17.59,60.59) v1(17.56,43.32) v1(17.63,30.78) v1(17.58,14.57) v1(17.56,8.33) v1(17.74,95.93) v1(17.73,94) v1(17.7,45.45) v1(17.71,37.02) v1(17.84,33.03) v1(17.76,10.86) v1(17.94,29.8) v1(17.95,2.56) v1(18.02,28.34) v1(18,6.58) v1(18.03,4.57) v1(18.31,98.16) v1(18.31,86.83) v1(18.34,61.41) v1(18.26,53.25) v1(18.34,41.08) v1(18.36,84.84) v1(18.39,78.43) v1(18.45,72.06) v1(18.44,69.83) v1(18.41,67.74) v1(18.36,63.5) v1(18.41,59.63) v1(18.44,42.62) v1(18.54,113.82) v1(18.53,82.6) v1(18.51,80.53) v1(18.47,65.67) v1(18.48,12.08) v1(18.58,127.67) v1(18.64,112.84) v1(18.59,105.31) v1(18.56,88.88) v1(18.63,44.01) v1(18.63,32.31) v1(18.74,125.16) v1(18.7,94.95) v1(18.66,92.99) v1(18.66,90.92) v1(18.74,39.98) v1(18.75,107.89) v1(18.8,96.99) v1(18.77,30.72) v1(18.94,122.62) v1(18.86,111.28) v1(18.86,110.49) v1(19,119.7) v1(19.03,29.12) v1(18.99,14.47) v1(18.99,10.02) v1(19.01,5.6) v1(18.98,3.56) v1(18.96,1.47) v1(19.07,108.73) v1(19.12,106.33) v1(19.05,98.6) v1(19.12,24.66) v1(19.12,15.29) v1(19.14,8.38) v1(19.2,75.17) v1(19.24,54.29) v1(19.22,52.25) v1(19.24,34.02) v1(19.27,85.85) v1(19.34,79.49) v1(19.32,77.42) v1(19.3,36.35) v1(19.37,87.89) v1(19.42,66.73) v1(19.4,64.67) v1(19.4,62.47) v1(19.49,128.79) v1(19.55,112.56) v1(19.49,81.56) v1(19.5,73.06) v1(19.47,70.99) v1(19.47,68.8) v1(19.5,60.61) v1(19.47,58.57) v1(19.64,94.02) v1(19.62,91.98) v1(19.59,89.92) v1(19.66,126.4) v1(19.73,95.98) v1(19.78,123.82) v1(19.85,121.14) v1(19.8,113.77) v1(19.91,6.53) v1(19.89,4.59) v1(20.03,83.8) v1(19.96,41.13) v1(20.03,28.38) v1(20.01,15.33) v1(20.02,2.53) v1(20.07,111.88) v1(20.12,53.28) v1(20.09,12.85) v1(20.15,12.12) v1(20.11,9.35) v1(20.34,110.47) v1(20.3,86.88) v1(20.3,78.45) v1(20.33,61.46) v1(20.26,41.92) v1(20.42,128.81) v1(20.44,128.18) v1(20.41,107.17) v1(20.41,105.84) v1(20.41,98.13) v1(20.43,69.85) v1(20.4,67.79) v1(20.38,65.7) v1(20.35,63.53) v1(20.38,59.6) v1(20.43,34) v1(20.45,29.13) v1(20.38,10.86) v1(20.38,3.95) v1(20.38,1.41) v1(20.45,127.61) v1(20.52,93.01) v1(20.55,88.91) v1(20.45,72.02) v1(20.46,30.7) v1(20.6,113) v1(20.58,108.47) v1(20.57,90.95) v1(20.71,97.02) v1(20.69,94.98) v1(20.72,43.06) v1(20.65,11.63) v1(20.77,20.89) v1(20.94,125.16) v1(20.94,39.98) v1(20.95,15.34) v1(20.92,5.6) v1(20.89,3.51) v1(20.95,1.52) v1(20.99,22.54) v1(20.97,7.59) v1(21.14,122.62) v1(21.13,52.19) v1(21.14,41.92) v1(21.07,27) v1(21.12,8.4) v1(21.22,128.82) v1(21.21,128.2) v1(21.22,127.64) v1(21.2,119.7) v1(21.15,54.29) v1(21.27,99) v1(21.28,87.92) v1(21.25,85.88) v1(21.31,62.5) v1(21.29,34.04) v1(21.38,111.65) v1(21.42,107.24) v1(21.45,89.94) v1(21.4,75.17) v1(21.38,68.82) v1(21.41,60.61) v1(21.38,58.52) v1(21.46,17.83) v1(21.59,96.01) v1(21.62,41.08) v1(21.61,30.67) v1(21.61,29.91) v1(21.57,10) v1(21.73,105.78) v1(21.66,3.95) v1(21.66,1.41) v1(21.76,128.78) v1(21.82,110.27) v1(21.76,108.64) v1(21.84,73.01) v1(21.86,126.4) v1(21.9,6.58) v1(21.93,2.56) v1(21.98,123.82) v1(22.04,98.33) v1(21.95,4.57) v1(22.09,28.37) v1(22.13,12.87) v1(22.09,9.37) v1(22.15,121.11) v1(22.18,111.66) v1(22.21,107.23) v1(22.16,86.91) v1(22.23,83.8) v1(22.18,53.25) v1(22.28,34.96) v1(22.28,23.59) v1(22.39,93.69) v1(22.39,93.42) v1(22.4,91.93) v1(22.4,91.66) v1(22.4,88.08) v1(22.4,87.81) v1(22.4,86.23) v1(22.4,85.96) v1(22.4,76.88) v1(22.4,76.61) v1(22.4,70.63) v1(22.4,70.36) v1(22.4,68.78) v1(22.4,68.51) v1(22.4,64.93) v1(22.4,64.66) v1(22.36,26) v1(22.44,11.63) v1(22.45,82.43) v1(22.45,82.16) v1(22.45,80.63) v1(22.45,80.36) v1(22.45,75.03) v1(22.45,74.76) v1(22.45,62.93) v1(22.45,62.66) v1(22.47,61.3) v1(22.47,46.29) v1(22.53,30.71) v1(22.52,16.86) v1(22.71,95.03) v1(22.65,93.69) v1(22.65,93.42) v1(22.66,91.93) v1(22.66,91.66) v1(22.66,88.08) v1(22.66,87.81) v1(22.66,86.23) v1(22.66,85.96) v1(22.71,82.43) v1(22.71,82.16) v1(22.71,80.63) v1(22.71,80.36) v1(22.66,76.88) v1(22.66,76.61) v1(22.71,75.03) v1(22.71,74.76) v1(22.66,70.63) v1(22.66,70.36) v1(22.66,68.78) v1(22.66,68.51) v1(22.66,64.93) v1(22.66,64.66) v1(22.71,62.93) v1(22.71,62.66) v1(22.82,108.54) v1(22.79,105.83) v1(22.82,42.11) v1(22.76,20.91) v1(22.95,127.67) v1(22.87,43.84) v1(22.95,41.03) v1(22.95,40.12) v1(22.93,29.49) v1(22.89,8.42) v1(22.88,7.62) v1(22.91,5.63) v1(22.88,3.56) v1(22.92,2.81) v1(22.88,1.5) v1(22.98,111.24) v1(23,97.35) v1(22.97,72.11) v1(23.03,46.71) v1(22.96,45.51) v1(23.01,35.88) v1(22.98,27.03) v1(22.98,10.89) v1(23.05,112.86) v1(23.06,110.27) v1(23.1,99.39) v1(23.14,54.31) v1(23.11,52.25) v1(23.11,32.95) v1(23.21,107.57) v1(23.18,33.87) v1(23.22,19.85) v1(23.3,90.25) v1(23.28,22.25) v1(23.35,125.2) v1(23.4,60.64) v1(23.37,58.57) v1(23.43,31.07) v1(23.45,17.85) v1(23.49,112.02) v1(23.51,96.04) v1(23.54,45.35) v1(23.52,42.29) v1(23.47,24.87) v1(23.59,78.5) v1(23.59,28.08) v1(23.66,109.29) v1(23.71,106.03) v1(23.75,89.26) v1(23.83,43.81) v1(23.84,40.85) v1(23.82,32.68) v1(23.82,29.51) v1(23.83,9.36) v1(23.94,108.34) v1(23.89,46.88) v1(23.9,12.87) v1(23.89,6.61) v1(23.86,4.6) v1(23.91,2.53) v1(23.96,128.78) v1(23.96,126.55) v1(23.95,106.86) v1(24.03,98.39) v1(24,97.32) v1(24.04,73.01) v1(24.1,53.28) v1(24.06,49.36) v1(24.2,116.2) v1(24.2,115.95) v1(24.2,115.7) v1(24.22,34.1) v1(24.19,23.61) v1(24.2,2.81) v1(24.32,111.31) v1(24.34,45.34) v1(24.28,42.29) v1(24.28,26.03) v1(24.27,9.99) v1(24.35,121.11) v1(24.42,112.83) v1(24.43,110.27) v1(24.4,39.77) v1(24.39,38.52) v1(24.39,35.73) v1(24.38,20.95) v1(24.5,116.2) v1(24.5,115.95) v1(24.5,115.7) v1(24.52,84.21) v1(24.51,31.1) v1(24.51,16.88) v1(24.46,11.94) v1(24.61,32.68) v1(24.6,29.52) v1(24.7,101.64) v1(24.7,101.37) v1(24.7,101.09) v1(24.7,100.82) v1(24.7,95.08) v1(24.67,61.3) v1(24.71,54.16) v1(24.71,3.59) v1(24.8,46.93) v1(24.82,5.63) v1(24.86,106.86) v1(24.89,43.8) v1(24.94,40.83) v1(24.89,27.03) v1(24.88,8.45) v1(24.87,1.52) v1(24.96,101.64) v1(24.96,101.37) v1(24.96,101.09) v1(24.96,100.82) v1(25.01,99.42) v1(24.99,97.38) v1(25,28.06) v1(25.15,127.67) v1(25.11,107.54) v1(25.1,98.82) v1(25.09,42.29) v1(25.12,34.1) v1(25.13,19.87) v1(25.17,72.11) v1(25.19,22.27) v1(25.21,13.84) v1(25.28,108.63) v1(25.41,48.71) v1(25.35,45.35) v1(25.4,40) v1(25.38,24.89) v1(25.5,96.09) v1(25.46,46.77) v1(25.71,109.35) v1(25.75,97.02) v1(25.69,50.71) v1(25.66,43.84) v1(25.72,42.3) v1(25.66,32.68) v1(25.66,31.1) v1(25.75,4.62) v1(25.79,89.87) v1(25.79,78.5) v1(25.82,9.39) v1(25.77,2.56) v1(25.89,98.41) v1(25.88,10.89) v1(25.88,6.63) v1(25.97,34.19) v1(26.08,110.27) v1(26.07,90.59) v1(26.08,84.81) v1(26.11,79.16) v1(26.1,23.61) v1(26.16,128.78) v1(26.16,126.55) v1(26.16,72.98) v1(26.2,49.12) v1(26.19,26.03) v1(26.28,27.87) v1(26.29,20.98) v1(26.43,47.62) v1(26.51,31.37) v1(26.46,29.21) v1(26.45,12.86) v1(26.58,97.27) v1(26.64,33.86) v1(26.63,18.58) v1(26.75,111.45) v1(26.75,96.47) v1(26.71,84.21) v1(26.67,46.99) v1(26.69,8.36) v1(26.73,5.65) v1(26.7,3.61) v1(26.83,41.1) v1(26.77,32.75) v1(26.78,7.67) v1(26.78,1.47) v1(26.91,54.16) v1(26.88,51.57) v1(26.88,27.05) v1(26.88,10.06) v1(27.05,106.87) v1(27.04,19.87) v1(27.1,22.27) v1(27.09,14.34) v1(27.21,45.64) v1(27.35,127.67) v1(27.26,43.46) v1(27.34,38.88) v1(27.3,34.62) v1(27.29,24.89) v1(27.36,96.11) v1(27.41,28.08) v1(27.5,60.58) v1(27.47,30.09) v1(27.63,112.05) v1(27.58,80.24) v1(27.61,48.71) v1(27.56,47.92) v1(27.61,4.65) v1(27.7,102.59) v1(27.7,102.32) v1(27.71,92.02) v1(27.71,89.82) v1(27.67,55.69) v1(27.7,9.29) v1(27.79,110.26) v1(27.79,39.98) v1(27.8,27.61) v1(27.75,11.89) v1(27.79,6.58) v1(27.84,2.53) v1(27.9,108.48) v1(27.9,106.84) v1(27.94,52.82) v1(27.89,50.71) v1(27.87,44.84) v1(27.95,32.28) v1(27.93,29.14) v1(27.96,102.59) v1(27.96,102.32) v1(28.05,78.76) v1(28.04,33.77) v1(28.04,24.08) v1(28.17,85.04) v1(28.2,61.87) v1(28.21,43.22) v1(28.17,26.05) v1(28.2,20.98) v1(28.28,59.38) v1(28.35,31.11) v1(28.27,13.63) v1(28.36,128.78) v1(28.36,126.55) v1(28.37,122.87) v1(28.36,72.98) v1(28.42,45.63) v1(28.53,34.07) v1(28.62,110.42) v1(28.63,91.42) v1(28.63,89.22) v1(28.59,82.94) v1(28.57,35.65) v1(28.6,21.94) v1(28.62,18.6) v1(28.64,5.65) v1(28.61,3.56) v1(28.72,108.32) v1(28.75,93.98) v1(28.67,47.17) v1(28.68,8.39) v1(28.83,66.9) v1(28.81,54.1) v1(28.85,7.64) v1(28.77,1.52) v1(28.86,64.99) v1(28.92,49.4) v1(28.88,44.05) v1(28.93,28.41) v1(29.03,41.1) v1(29.01,38.7) v1(28.97,23.54) v1(29.03,19.9) v1(29.08,51.57) v1(29.1,14.34) v1(29.14,12.86) v1(29.22,112.07) v1(29.15,58.31) v1(29.33,95.69) v1(29.33,93.27) v1(29.34,29.41) v1(29.28,24.92) v1(29.38,81.89) v1(29.4,35.17) v1(29.36,10.88) v1(29.37,10.09) v1(29.55,127.67) v1(29.48,102.62) v1(29.48,102.35) v1(29.52,35.95) v1(29.55,33.68) v1(29.57,106.86) v1(29.74,102.62) v1(29.74,102.35) v1(29.7,97.27) v1(29.7,60.58) v1(29.69,32.42) v1(29.69,9.31) v1(29.67,4.62) v1(29.75,2.56) v1(29.78,80.24) v1(29.76,47.92) v1(29.83,44.82) v1(29.79,30.62) v1(29.78,6.63) v1(29.86,93.96) v1(29.9,92.89) v1(29.87,55.69) v1(30,104.27) v1(30.02,94.97) v1(29.98,43.24) v1(29.99,39.98) v1(30.1,96.92) v1(30.14,52.82) v1(30.25,78.76) v1(30.19,21) v1(30.26,68.36) v1(30.41,123.51) v1(30.37,85.04) v1(30.4,61.87) v1(30.41,13.61) v1(30.51,109.27) v1(30.55,91.97) v1(30.48,59.38) v1(30.47,42.41) v1(30.46,30.17) v1(30.54,28.45) v1(30.5,26.03) v1(30.51,8.38) v1(30.47,1.52) v1(30.56,128.78) v1(30.56,126.55) v1(30.57,22.26) v1(30.63,5.68) v1(30.6,3.61) v1(30.7,111.57) v1(30.69,47.17) v1(30.67,7.63) v1(30.78,95.61) v1(30.79,82.94) v1(30.78,33.6) v1(30.75,19.89) v1(30.8,11.86) v1(30.92,106.89) v1(30.93,80.15) v1(31.02,74.86) v1(31.03,66.9) v1(31.01,54.1) v1(30.97,14.63) v1(31.12,122.64) v1(31.14,94.01) v1(31.13,92.65) v1(31.14,72.07) v1(31.08,69.58) v1(31.06,64.99) v1(31.07,45.6) v1(31.1,44.07) v1(31.13,35.23) v1(31.1,27.69) v1(31.13,24.1) v1(31.17,91.35) v1(31.18,77.73) v1(31.21,38.7) v1(31.16,25.11) v1(31.27,115.65) v1(31.26,115.27) v1(31.3,97.27) v1(31.3,90.21) v1(31.3,88.01) v1(31.33,60.62) v1(31.33,56.43) v1(31.37,85.9) v1(31.37,83.7) v1(31.35,58.31) v1(31.37,41.09) v1(31.39,29.39) v1(31.45,15.05) v1(31.42,12.86) v1(31.51,2.56) v1(31.57,124.22) v1(31.64,117.29) v1(31.64,116.93) v1(31.62,116.55) v1(31.62,116.17) v1(31.61,115.79) v1(31.55,94.88) v1(31.62,93.32) v1(31.58,21.54) v1(31.65,15.7) v1(31.58,4.65) v1(31.66,117.67) v1(31.71,91.98) v1(31.69,49.61) v1(31.73,27.8) v1(31.79,128.82) v1(31.82,128.19) v1(31.82,127.62) v1(31.78,122.62) v1(31.84,109.67) v1(31.85,109.12) v1(31.79,47.93) v1(31.84,23.17) v1(31.77,9.38) v1(31.85,108.63) v1(31.87,32.8) v1(31.91,30.38) v1(31.94,20.65) v1(31.88,10.09) v1(31.97,117.79) v1(32.05,37.64) v1(31.97,14.79) v1(32.06,107.05) v1(32.1,39.94) v1(32.15,10.85) v1(32.19,43.24) v1(32.25,10.48) v1(32.33,78.79) v1(32.32,73.42) v1(32.32,70.8) v1(32.31,44.82) v1(32.28,15.45) v1(32.29,14.14) v1(32.28,12.84) v1(32.28,11.76) v1(32.36,117.77) v1(32.4,117.12) v1(32.44,109.68) v1(32.44,109.15) v1(32.42,91.78) v1(32.44,61.92) v1(32.36,47.2) v1(32.35,28.68) v1(32.53,125.65) v1(32.45,110.31) v1(32.46,68.36) v1(32.52,64.99) v1(32.54,59.38) v1(32.49,26.05) v1(32.45,24.48) v1(32.47,13.6) v1(32.5,8.4) v1(32.46,1.55) v1(32.59,128.83) v1(32.58,128.21) v1(32.59,127.64) v1(32.59,95.71) v1(32.64,54.88) v1(32.62,33.55) v1(32.56,22.28) v1(32.65,4.89) v1(32.68,122.94) v1(32.68,117.77) v1(32.74,81.62) v1(32.67,42.41) v1(32.67,26.53) v1(32.72,16.03) v1(32.7,9.46) v1(32.67,9.43) v1(32.81,25.31) v1(32.8,23.73) v1(32.9,97.17) v1(32.85,35.24) v1(32.85,32.01) v1(32.86,20.66) v1(32.87,7.11) v1(33,109.69) v1(32.96,83.74) v1(33.05,34.51) v1(32.96,14.66) v1(33.06,117.76) v1(33.09,107) v1(33.13,80.15) v1(33.06,27.77) v1(33.12,24.12) v1(33.24,86.77) v1(33.22,74.86) v1(33.25,44.05) v1(33.21,38.78) v1(33.15,23.08) v1(33.24,11.89) v1(33.16,10.41) v1(33.34,89.91) v1(33.34,72.07) v1(33.28,69.58) v1(33.26,46.42) v1(33.29,16.45) v1(33.28,13.03) v1(33.29,11.89) v1(33.41,117.77) v1(33.36,106.59) v1(33.41,105.22) v1(33.39,96.72) v1(33.38,77.73) v1(33.38,49.7) v1(33.37,30.36) v1(33.4,20.65) v1(33.36,2.58) v1(33.51,110.32) v1(33.52,109.88) v1(33.54,109.01) v1(33.52,108.55) v1(33.53,94.82) v1(33.53,92.62) v1(33.49,66.88) v1(33.53,60.62) v1(33.51,58.28) v1(33.53,56.43) v1(33.48,32.75) v1(33.51,21.53) v1(33.53,5.98) v1(33.52,3.71) v1(33.58,128.77) v1(33.57,41.09) v1(33.59,27.39) v1(33.75,93.52) v1(33.69,63.42) v1(33.67,53.81) v1(33.74,12.87) v1(33.77,124.22) v1(33.79,117.76) v1(33.8,116.02) v1(33.84,10.35) v1(33.76,10.25) v1(33.75,9.4) v1(33.85,107.29) v1(33.95,82.25) v1(33.93,26.49) v1(33.85,23.42) v1(33.91,22.54) v1(34.05,96.52) v1(33.99,47.93) v1(34.02,44.82) v1(34,40.76) v1(34.06,110.35) v1(34.07,109.87) v1(34.08,109.01) v1(34.08,108.55) v1(34.12,47.2) v1(34.09,21.53) v1(34.2,117.77) v1(34.24,88.25) v1(34.21,85.35) v1(34.2,43.27) v1(34.25,37.64) v1(34.2,28.68) v1(34.23,14.14) v1(34.22,13.21) v1(34.22,11.87) v1(34.35,95.74) v1(34.3,39.94) v1(34.29,20.64) v1(34.41,24.52) v1(34.42,10.43) v1(34.45,8.32) v1(34.37,1.5) v1(34.54,117.67) v1(34.53,117.28) v1(34.53,116.92) v1(34.52,116.53) v1(34.52,116.12) v1(34.51,115.74) v1(34.54,104.38) v1(34.53,78.79) v1(34.52,73.42) v1(34.52,70.8) v1(34.51,35.24) v1(34.45,15.48) v1(34.53,10.95) v1(34.6,97.27) v1(34.62,91.78) v1(34.58,76.45) v1(34.64,68.37) v1(34.64,61.92) v1(34.6,33.63) v1(34.57,29.58) v1(34.64,4.91) v1(34.73,125.65) v1(34.67,115.39) v1(34.66,115.01) v1(34.74,107.21) v1(34.72,64.99) v1(34.74,59.38) v1(34.67,21.53) v1(34.73,13.59) v1(34.78,106.02) v1(34.75,105.38) v1(34.84,54.88) v1(34.8,44.03) v1(34.84,31.94) v1(34.88,122.94) v1(34.87,107.9) v1(34.93,93.27) v1(34.94,81.62) v1(34.86,42.43) v1(34.94,27.08) v1(34.92,16.05) v1(34.93,14.63) v1(34.86,7.14) v1(34.96,128.78) v1(35,46.44) v1(35.01,22.25) v1(35.12,6.28) v1(35.14,3.55) v1(35.16,83.74) v1(35.17,11.72) v1(35.28,56.45) v1(35.31,44.84) v1(35.26,12.04) v1(35.34,9.11) v1(35.38,96.77) v1(35.44,86.77) v1(35.36,47.95) v1(35.41,38.78) v1(35.39,24.87) v1(35.45,21.92) v1(35.36,20.67) v1(35.4,15.46) v1(35.4,12.95) v1(35.41,12.39) v1(35.43,2.56) v1(35.49,107.88) v1(35.52,103.35) v1(35.54,89.91) v1(35.48,34.53) v1(35.53,23.3) v1(35.47,14.14) v1(35.58,77.67) v1(35.64,75.07) v1(35.64,60.5) v1(35.56,52.32) v1(35.62,45.59) v1(35.6,32.75) v1(35.67,105.1) v1(35.69,66.88) v1(35.71,58.28) v1(35.66,30.39) v1(35.66,21.4) v1(35.79,106.14) v1(35.81,104.19) v1(35.79,80.16) v1(35.82,72.1) v1(35.82,69.5) v1(35.76,35.97) v1(35.95,97.12) v1(35.89,63.42) v1(35.87,53.81) v1(35.86,47.17) v1(35.9,28.68) v1(35.97,124.22) v1(36.12,107.48) v1(36.15,82.25) v1(36.09,10.2) v1(36.24,113.63) v1(36.22,112.85) v1(36.2,57.43) v1(36.18,43.22) v1(36.2,40.76) v1(36.22,37.45) v1(36.22,13.24) v1(36.33,114.36) v1(36.33,95.77) v1(36.31,91.84) v1(36.26,33.81) v1(36.33,27.53) v1(36.31,16.19) v1(36.33,14.17) v1(36.44,88.25) v1(36.41,85.35) v1(36.42,15.46) v1(36.35,12.26) v1(36.36,1.55) v1(36.53,35.24) v1(36.49,9.32) v1(36.64,103.47) v1(36.6,44.04) v1(36.65,13.59) v1(36.62,11.71) v1(36.7,96.92) v1(36.69,44.82) v1(36.69,25.37) v1(36.67,11.86) v1(36.68,11.07) v1(36.79,78.79) v1(36.78,76.45) v1(36.84,68.37) v1(36.81,46.43) v1(36.79,24.52) v1(36.93,125.65) v1(36.91,73.41) v1(36.88,70.83) v1(36.9,65.09) v1(36.87,62.11) v1(36.93,32.02) v1(36.92,14.66) v1(37.01,104.93) v1(37.04,33.35) v1(37.01,31.51) v1(36.98,29.62) v1(37.04,27.06) v1(36.98,21.41) v1(37.04,16.28) v1(37.08,122.94) v1(37.13,93.27) v1(37.06,42.43) v1(37.07,22.98) v1(37.08,12.38) v1(37.16,128.78) v1(37.21,105.92) v1(37.24,96.8) v1(37.15,8.33) v1(37.3,95.57) v1(37.33,40) v1(37.42,113.58) v1(37.43,108.29) v1(37.36,83.74) v1(37.37,58.77) v1(37.43,13.57) v1(37.55,112.3) v1(37.48,56.45) v1(37.52,47.14) v1(37.45,34.55) v1(37.49,15.44) v1(37.65,102.67) v1(37.64,86.77) v1(37.59,81.59) v1(37.56,47.95) v1(37.56,45.55) v1(37.62,38.94) v1(37.56,35.97) v1(37.61,14.24) v1(37.74,89.91) v1(37.65,14.73) v1(37.73,12) v1(37.8,92.77) v1(37.78,77.67) v1(37.84,75.07) v1(37.79,63.46) v1(37.84,60.5) v1(37.76,52.32) v1(37.8,27.63) v1(37.83,26.18) v1(37.79,12.86) v1(37.94,114.36) v1(37.91,112.9) v1(37.99,107.23) v1(38.01,105.64) v1(38.05,96.47) v1(37.99,80.16) v1(38.02,72.1) v1(38.02,69.5) v1(38,66.93) v1(37.96,43.26) v1(38.1,95.75) v1(38.08,10.23) v1(38.07,1.79) v1(38.17,124.22) v1(38.24,104.29) v1(38.23,46.42) v1(38.16,44.82) v1(38.3,94.92) v1(38.35,82.25) v1(38.26,30.34) v1(38.3,24.55) v1(38.4,57.43) v1(38.42,40.7) v1(38.39,33.05) v1(38.42,32.41) v1(38.39,31.58) v1(38.43,13.47) v1(38.51,103.47) v1(38.49,91.78) v1(38.53,33.83) v1(38.5,25.24) v1(38.48,9.34) v1(38.51,1.3) v1(38.6,121.22) v1(38.64,88.25) v1(38.61,85.35) v1(38.62,21.46) v1(38.71,105.04) v1(38.67,47.16) v1(38.67,22.95) v1(38.67,11.1) v1(38.79,53.78) v1(38.76,45.54) v1(38.76,14.63) v1(38.9,128.72) v1(38.92,128.1) v1(38.93,127.53) v1(38.89,96.75) v1(38.92,44.04) v1(38.99,78.79) v1(38.99,76.44) v1(39.02,51.32) v1(38.99,13.29) v1(39.13,125.65) v1(39.11,73.41) v1(39.08,70.83) v1(39.13,68.37) v1(39.1,65.09) v1(39.07,62.11) v1(39.14,32.53) v1(39.14,8.36) v1(39.24,42.41) v1(39.22,28.74) v1(39.28,122.94) v1(39.31,106.79) v1(39.33,93.27) v1(39.31,56.43) v1(39.27,47.87) v1(39.36,128.78) v1(39.49,104.26) v1(39.55,45.6) v1(39.53,40) v1(39.53,29.61) v1(39.49,24.47) v1(39.5,10.41) v1(39.56,102.68) v1(39.57,58.77) v1(39.57,34.55) v1(39.65,28.22) v1(39.7,128.74) v1(39.69,128.11) v1(39.7,127.55) v1(39.7,112.93) v1(39.7,90.03) v1(39.67,83.8) v1(39.72,46.85) v1(39.72,12.02) v1(39.85,114.37) v1(39.85,95.77) v1(39.79,81.59) v1(39.83,43.26) v1(39.82,38.94) v1(39.84,31.18) v1(39.8,10.41) v1(39.94,86.7) v1(39.9,35.95) v1(39.86,33.08) v1(39.99,63.46) v1(40,46.08) v1(40.05,44.82) v1(39.96,25.24) v1(40.03,11.12) v1(40.1,105.62) v1(40.09,80.18) v1(40.12,69.64) v1(40.14,10.4) v1(40.25,96.72) v1(40.19,77.72) v1(40.2,66.93) v1(40.23,20.66) v1(40.23,9.35) v1(40.28,75.3) v1(40.3,72.23) v1(40.27,52.27) v1(40.36,103.45) v1(40.44,82.28) v1(40.38,66.47) v1(40.39,63.2) v1(40.44,47.3) v1(40.36,22.93) v1(40.44,21.4) v1(40.42,13.5) v1(40.36,2.63) v1(40.51,124.21) v1(40.5,33.85) v1(40.49,23.78) v1(40.5,10.4) v1(40.5,1.32) v1(40.59,105.02) v1(40.6,94.92) v1(40.6,92.47) v1(40.6,65.65) v1(40.62,40.7) v1(40.63,38.71) v1(40.75,121.22) v1(40.7,93.37) v1(40.69,91.78) v1(40.75,88.22) v1(40.66,30.39) v1(40.75,14.66) v1(40.81,85.32) v1(40.85,44.4) v1(40.83,10.4) v1(40.88,96.8) v1(40.95,46.3) v1(40.91,20.44) v1(40.98,64.05) v1(40.99,53.78) v1(40.98,23.79) v1(41.11,62.86) v1(41.06,39.23) v1(41.08,31.93) v1(41.1,27.77) v1(41.13,12.52) v1(41.19,76.44) v1(41.21,70.84) v1(41.22,51.32) v1(41.23,43.57) v1(41.17,10.4) v1(41.27,78.82) v1(41.33,68.37) v1(41.34,38.56) v1(41.32,33.06) v1(41.35,8.33) v1(41.45,96.37) v1(41.37,73.43) v1(41.37,66.91) v1(41.44,42.41) v1(41.42,28.69) v1(41.42,27.37) v1(41.41,27.04) v1(41.4,25.4) v1(41.4,25.3) v1(41.41,25.01) v1(41.52,102.67) v1(41.46,65.26) v1(41.51,56.43) v1(41.51,24.74) v1(41.49,10.4) v1(41.56,128.78) v1(41.57,126.4) v1(41.57,125.62) v1(41.58,125.05) v1(41.65,122.93) v1(41.62,27.57) v1(41.68,104.26) v1(41.7,45.29) v1(41.74,10.4) v1(41.7,5.08) v1(41.72,2.65) v1(41.83,95.79) v1(41.76,64.54) v1(41.8,31.11) v1(41.77,29.61) v1(41.83,26.63) v1(41.79,13.03) v1(41.8,12.73) v1(41.79,12.38) v1(41.79,11.7) v1(41.8,11.37) v1(41.8,11.03) v1(41.81,10.68) v1(41.88,112.92) v1(41.9,90.03) v1(41.87,83.8) v1(41.89,64.08) v1(41.91,63.05) v1(41.93,27.58) v1(41.86,27.53) v1(41.94,23.8) v1(42.02,125.63) v1(42.03,125.06) v1(42.01,93.25) v1(42.03,65.49) v1(41.95,30.69) v1(42.04,22.92) v1(42.01,21.47) v1(42.14,86.7) v1(42.14,81.59) v1(42.09,18.6) v1(42.17,39.13) v1(42.22,9.37) v1(42.29,80.18) v1(42.32,69.64) v1(42.32,67.45) v1(42.26,27.57) v1(42.39,77.72) v1(42.36,26.93) v1(42.37,25.32) v1(42.42,7.11) v1(42.48,75.3) v1(42.5,72.23) v1(42.52,66.88) v1(42.54,63.94) v1(42.47,52.27) v1(42.46,28.99) v1(42.64,82.28) v1(42.59,27.57) v1(42.56,1.38) v1(42.73,127.62) v1(42.71,105.03) v1(42.66,103.49) v1(42.71,65.46) v1(42.68,63) v1(42.65,44.88) v1(42.74,23.58) v1(42.74,21.87) v1(42.72,17.82) v1(42.74,17.08) v1(42.69,6.15) v1(42.69,3.9) v1(42.78,46.31) v1(42.76,42.41) v1(42.83,24.53) v1(42.79,24.41) v1(42.77,22.7) v1(42.77,16.38) v1(42.76,14.65) v1(42.9,121.17) v1(42.95,88.22) v1(43,124.3) v1(43.03,112.93) v1(43.01,85.32) v1(43.05,35.25) v1(42.96,27.57) v1(43.07,94.74) v1(43.06,91.76) v1(43.12,67.63) v1(43.08,22.15) v1(43.2,92.77) v1(43.19,63.94) v1(43.22,62.42) v1(43.17,44.13) v1(43.22,39.08) v1(43.19,34.53) v1(43.2,11.35) v1(43.29,40.75) v1(43.31,32.83) v1(43.33,31.93) v1(43.32,27.58) v1(43.29,24.71) v1(43.27,23.77) v1(43.31,13.39) v1(43.34,8.36) v1(43.41,70.84) v1(43.45,65.29) v1(43.47,78.82) v1(43.49,71.41) v1(43.51,69.07) v1(43.52,68.3) v1(43.46,66.4) v1(43.64,104.26) v1(43.57,73.43) v1(43.55,70.25) v1(43.56,67.65) v1(43.59,63.94) v1(43.61,24.72) v1(43.74,102.69) v1(43.68,51.83) v1(43.72,27.57) v1(43.69,5.1) v1(43.71,2.68) v1(43.76,128.78) v1(43.77,126.4) v1(43.75,76.42) v1(43.82,45.83) v1(43.9,63.01) v1(43.94,43.25) v1(44.05,114.36) v1(43.97,22.95) v1(44.1,90.03) v1(44.07,83.8) v1(44.13,72.17) v1(44.09,28.31) v1(44.21,93.25) v1(44.2,90.92) v1(44.24,80.25) v1(44.23,12.38) v1(44.34,86.7) v1(44.34,81.59) v1(44.34,47.12) v1(44.3,35.25) v1(44.28,33.76) v1(44.33,23.75) v1(44.36,110.97) v1(44.36,77.7) v1(44.37,70.06) v1(44.41,69.05) v1(44.38,67.35) v1(44.39,66.39) v1(44.37,22.2) v1(44.37,21.69) v1(44.41,7.14) v1(44.5,45) v1(44.51,4.07) v1(44.54,1.41) v1(44.63,112.91) v1(44.62,75.45) v1(44.56,70.68) v1(44.6,34.49) v1(44.58,31.28) v1(44.65,18.02) v1(44.71,85.07) v1(44.73,62.32) v1(44.68,6.18) v1(44.78,111.75) v1(44.84,82.28) v1(44.75,65.64) v1(44.75,14.67) v1(44.93,127.62) v1(44.87,124.3) v1(44.94,123) v1(44.9,105.01) v1(44.94,103.47) v1(44.9,88.29) v1(44.9,71.57) v1(44.94,63.73) v1(44.9,31.95) v1(44.95,30.12) v1(44.94,25.57) v1(45.15,121.17) v1(45.11,64.49) v1(45.14,39.13) v1(45.14,29.02) v1(45.14,24.47) v1(45.21,73.24) v1(45.16,65.31) v1(45.22,13.41) v1(45.19,11.37) v1(45.26,91.76) v1(45.29,78.82) v1(45.33,42.77) v1(45.32,32.83) v1(45.36,111.04) v1(45.39,70.77) v1(45.44,69.89) v1(45.45,69.07) v1(45.39,67.82) v1(45.37,44.13) v1(45.4,21.69) v1(45.49,40.75) v1(45.51,31.93) v1(45.62,38.85) v1(45.56,19.82) v1(45.62,18.62) v1(45.68,114.37) v1(45.69,110.15) v1(45.68,30.57) v1(45.72,25.55) v1(45.66,9.29) v1(45.8,72.47) v1(45.78,63.14) v1(45.77,51.85) v1(45.79,22.91) v1(45.8,6.79) v1(45.88,111.57) v1(45.94,68.47) v1(45.9,23.88) v1(45.96,128.78) v1(45.97,126.4) v1(46.02,102.65) v1(46,92.42) v1(45.95,76.42) v1(46.04,74.01) v1(45.97,69.62) v1(46,63.71) v1(46.04,62.2) v1(46.11,112.92) v1(46.08,81.59) v1(46.14,70.73) v1(46.07,67.01) v1(46.14,43.25) v1(46.09,12.41) v1(46.21,104.27) v1(46.21,71.59) v1(46.16,65.65) v1(46.21,64.5) v1(46.33,63.08) v1(46.29,31.28) v1(46.31,20.5) v1(46.37,109.56) v1(46.41,93.25) v1(46.44,80.25) v1(46.5,101.87) v1(46.49,90.07) v1(46.46,24.59) v1(46.45,20.96) v1(46.56,77.7) v1(46.62,74.65) v1(46.63,18.04) v1(46.72,83.43) v1(46.7,45) v1(46.66,18.62) v1(46.81,124.31) v1(46.82,75.45) v1(46.82,73.46) v1(46.83,68.5) v1(46.83,63.42) v1(46.82,60.88) v1(46.83,26.59) v1(46.78,14.69) v1(46.76,6.94) v1(46.89,112.04) v1(46.94,111.04) v1(46.92,110.18) v1(46.95,9.29) v1(46.87,6.12) v1(46.98,113.59) v1(47.02,103.44) v1(46.98,72.31) v1(46.96,70.55) v1(47.03,8.2) v1(47.13,127.62) v1(47.13,13.41) v1(47.1,11.32) v1(47.27,120.92) v1(47.44,64.54) v1(47.44,63.76) v1(47.45,62.96) v1(47.43,32.95) v1(47.44,20.24) v1(47.44,18.62) v1(47.47,122.9) v1(47.53,105.04) v1(47.5,101.56) v1(47.46,91.76) v1(47.49,78.82) v1(47.46,69.1) v1(47.46,66.96) v1(47.5,61.89) v1(47.54,49.33) v1(47.46,35.46) v1(47.54,31.28) v1(47.48,26.61) v1(47.46,25.03) v1(47.51,22.51) v1(47.6,71.2) v1(47.58,65.42) v1(47.61,56.44) v1(47.56,24.52) v1(47.74,76.41) v1(47.66,26.15) v1(47.73,25.57) v1(47.74,25.27) v1(47.8,100.57) v1(47.81,82.52) v1(47.82,73.03) v1(47.76,24.98) v1(47.76,24.67) v1(47.78,24.35) v1(47.78,24.06) v1(47.78,23.77) v1(47.78,23.47) v1(47.82,23.38) v1(47.77,23.18) v1(47.79,22.88) v1(47.95,92.67) v1(47.87,74.96) v1(47.99,109.77) v1(48.09,114.2) v1(48.08,63.42) v1(48.1,60.86) v1(48.1,59.61) v1(48.1,26.59) v1(48.12,22.86) v1(48.1,21.5) v1(48.1,20.84) v1(48.11,9.24) v1(48.06,7.04) v1(48.16,128.78) v1(48.17,126.4) v1(48.22,99.6) v1(48.17,78.16) v1(48.17,73.99) v1(48.23,71.37) v1(48.16,70.37) v1(48.25,68.35) v1(48.25,27.23) v1(48.19,25.69) v1(48.2,18.49) v1(48.16,12.38) v1(48.2,10.43) v1(48.2,7.89) v1(48.3,102.14) v1(48.28,81.59) v1(48.38,59.02) v1(48.39,25.98) v1(48.44,25.76) v1(48.41,22.86) v1(48.5,107.15) v1(48.45,103.47) v1(48.46,100.4) v1(48.5,93.26) v1(48.48,66.42) v1(48.52,37.62) v1(48.5,24.88) v1(48.57,65.44) v1(48.63,55.35) v1(48.6,53.92) v1(48.63,22.34) v1(48.69,90.07) v1(48.69,64.52) v1(48.73,62.96) v1(48.71,62.2) v1(48.72,40.68) v1(48.67,39.61) v1(48.74,35.48) v1(48.74,31.87) v1(48.71,23) v1(48.71,20.26) v1(48.76,75.67) v1(48.79,72.25) v1(48.77,67.85) v1(48.78,61.25) v1(48.78,60.42) v1(48.77,24.03) v1(48.76,22.86) v1(48.84,21.04) v1(48.93,110.36) v1(48.92,109.52) v1(48.92,83.73) v1(48.86,80.27) v1(48.89,66.83) v1(48.86,58.71) v1(48.93,29.57) v1(48.92,27.7) v1(48.94,26.86) v1(48.94,26.02) v1(48.89,6) v1(48.98,113.09) v1(48.98,111.98) v1(48.95,111.04) v1(49.01,106.05) v1(49,99.32) v1(49,70.59) v1(49,27.12) v1(49.02,8.22) v1(49.07,127.63) v1(49.14,124.31) v1(49.08,73.11) v1(49.14,22.86) v1(49.11,13.44) v1(49.09,11.37) v1(49.36,69.76) v1(49.37,64.56) v1(49.37,59.62) v1(49.37,27.87) v1(49.37,25.31) v1(49.37,24.65) v1(49.37,22.78) v1(49.47,120.92) v1(49.52,114.25) v1(49.49,103.79) v1(49.49,74.9) v1(49.49,22.86) v1(49.49,10.43) v1(49.49,7.89) v1(49.59,32.96) v1(49.57,26.01) v1(49.65,23.29) v1(49.78,110.36) v1(49.77,102.17) v1(49.8,92.97) v1(49.76,91.73) v1(49.75,71.34) v1(49.8,52.91) v1(49.87,109.52) v1(49.88,89.03) v1(49.94,76.41) v1(49.88,73.98) v1(49.86,22.85) v1(49.89,21.04) v1(50.01,82.52) v1(49.98,69.19) v1(49.98,67.9) v1(50,66.31) v1(49.99,65.52) v1(50,64.52) v1(50.01,63.76) v1(49.97,63.01) v1(50.01,62.13) v1(50.01,61.29) v1(49.97,60.4) v1(49.99,58.73) v1(49.98,57.8) v1(50,40.55) v1(49.99,39.61) v1(49.96,37.54) v1(50,35.67) v1(49.97,31.9) v1(49.96,26.9) v1(50.01,19.99) v1(50.05,7.06) v1(50.09,125.62) v1(50.09,99.79) v1(50.11,53.93) v1(50.11,22.15) v1(50.07,12.41) v1(50.09,9.27) v1(50.12,4.83) v1(50.19,128.72) v1(50.21,128.09) v1(50.22,127.52) v1(50.17,105.28) v1(50.17,88.1) v1(50.24,25.79) v1(50.24,25.49) v1(50.24,25.17) v1(50.21,24.93) v1(50.19,24.71) v1(50.22,24.16) v1(50.22,23.84) v1(50.24,23.49) v1(50.22,23.18) v1(50.2,22.86) v1(50.26,122.75) v1(50.3,103.87) v1(50.35,26.09) v1(50.36,84.89) v1(50.37,78.16) v1(50.36,31.1) v1(50.37,29.65) v1(50.35,28.5) v1(50.42,23.41) v1(50.54,112.67) v1(50.54,112.12) v1(50.55,111.55) v1(50.55,110.96) v1(50.48,81.59) v1(50.6,129.11) v1(50.64,121.7) v1(50.55,113.28) v1(50.61,86.61) v1(50.64,69.77) v1(50.64,64.57) v1(50.64,62.15) v1(50.63,59.62) v1(50.64,58.95) v1(50.64,27.16) v1(50.61,26.08) v1(50.7,93.26) v1(50.69,70.58) v1(50.66,32.94) v1(50.76,72.22) v1(50.76,8.21) v1(50.83,5.99) v1(50.89,90.07) v1(50.88,73.13) v1(50.99,128.73) v1(50.98,128.11) v1(50.99,127.54) v1(50.95,102.36) v1(50.96,75.67) v1(50.97,74.91) v1(51.04,28.49) v1(50.98,22.3) v1(50.97,11.4) v1(51.08,113.29) v1(51.06,112.68) v1(51.07,112.13) v1(51.07,111.56) v1(51.07,110.97) v1(51.12,83.73) v1(51.06,80.27) v1(51.13,62.98) v1(51.13,56.37) v1(51.1,53.93) v1(51.09,19.82) v1(51.08,13.44) v1(51.22,60.4) v1(51.19,58.69) v1(51.25,58.28) v1(51.24,32.99) v1(51.24,31.88) v1(51.24,18.55) v1(51.34,124.31) v1(51.29,100.31) v1(51.33,69.22) v1(51.33,67.55) v1(51.26,64.48) v1(51.31,61.7) v1(51.26,52.84) v1(51.33,39.61) v1(51.27,37.55) v1(51.3,37.12) v1(51.35,29.55) v1(51.33,24.88) v1(51.35,20.9) v1(51.26,9.26) v1(51.4,64.98) v1(51.43,30.75) v1(51.38,26.94) v1(51.49,104.43) v1(51.48,103.15) v1(51.49,87.29) v1(51.54,74) v1(51.51,1.18) v1(51.61,113.28) v1(51.6,112.67) v1(51.6,112.12) v1(51.61,111.55) v1(51.61,110.96) v1(51.67,120.92) v1(51.73,115.82) v1(51.69,71.35) v1(51.71,23.36) v1(51.88,60.88) v1(51.91,58.34) v1(51.93,36.75) v1(51.89,31.69) v1(51.9,29.32) v1(51.92,26.02) v1(51.92,7.1) v1(52.03,101.19) v1(51.95,91.73) v1(52.02,89.06) v1(52.01,12.43) v1(52.09,80.18) v1(52.13,24.62) v1(52.08,10.3) v1(52.11,4.85) v1(52.18,113.29) v1(52.17,112.68) v1(52.17,112.13) v1(52.18,111.56) v1(52.18,110.97) v1(52.21,82.52) v1(52.16,69.2) v1(52.2,17.99) v1(52.18,14.69) v1(52.29,125.62) v1(52.28,59.05) v1(52.25,27.25) v1(52.45,105.33) v1(52.37,88.1) v1(52.43,39.04) v1(52.35,20.95) v1(52.46,122.75) v1(52.52,74.91) v1(52.53,67.56) v1(52.53,64.95) v1(52.5,61.86) v1(52.51,55.72) v1(52.5,37.41) v1(52.52,32.98) v1(52.51,30.76) v1(52.5,28.18) v1(52.54,25.52) v1(52.5,22.01) v1(52.56,128.78) v1(52.56,84.89) v1(52.58,70.58) v1(52.61,62.92) v1(52.58,57.73) v1(52.55,44.48) v1(52.65,36.2) v1(52.72,113.28) v1(52.7,112.67) v1(52.7,112.12) v1(52.71,111.55) v1(52.71,110.96) v1(52.66,65.69) v1(52.65,60.11) v1(52.72,47.69) v1(52.7,38.83) v1(52.74,8.24) v1(52.84,121.7) v1(52.81,102.35) v1(52.8,100.27) v1(52.81,86.61) v1(52.76,59.03) v1(52.76,52.83) v1(52.78,43.49) v1(52.82,6.02) v1(52.9,99.27) v1(52.9,93.26) v1(52.87,73.18) v1(52.91,29.84) v1(52.97,108.08) v1(53.03,31.79) v1(52.98,28.46) v1(52.99,13.46) v1(52.96,11.42) v1(53.23,104.4) v1(53.22,100.74) v1(53.21,90.08) v1(53.17,63.37) v1(53.22,60.75) v1(53.2,60.18) v1(53.18,36.75) v1(53.23,18.57) v1(53.24,9.29) v1(53.3,106.2) v1(53.38,78.87) v1(53.39,73.99) v1(53.54,124.31) v1(53.52,114.13) v1(53.49,110.35) v1(53.55,91.87) v1(53.55,83.66) v1(53.49,81.14) v1(53.46,22.06) v1(53.49,1.2) v1(53.63,87.29) v1(53.57,64.23) v1(53.56,62.68) v1(53.61,30.82) v1(53.74,127.65) v1(53.71,56.42) v1(53.73,28.13) v1(53.74,25.23) v1(53.71,24.41) v1(53.82,71.37) v1(53.82,65.53) v1(53.82,59.04) v1(53.83,45.52) v1(53.81,44.43) v1(53.82,43.3) v1(53.76,39.24) v1(53.83,37.35) v1(53.8,28.25) v1(53.81,26.98) v1(53.8,26.05) v1(53.87,120.92) v1(53.89,88.97) v1(53.9,69.68) v1(53.86,51.7) v1(53.94,36.66) v1(53.88,35.76) v1(53.95,22.23) v1(53.92,20.94) v1(53.87,12.46) v1(53.91,7.12) v1(54.03,108.9) v1(54.03,72.67) v1(53.97,67.41) v1(53.97,59.23) v1(54.05,54.71) v1(54.03,34.92) v1(53.97,23.94) v1(53.95,23.17) v1(53.99,4.83) v1(54.08,112.64) v1(54.1,111) v1(54.09,74.89) v1(54.09,36.5) v1(54.07,35.83) v1(54.12,31.76) v1(54.07,10.33) v1(54.23,113.48) v1(54.16,91.73) v1(54.2,34.87) v1(54.2,25.89) v1(54.22,20.2) v1(54.19,18.01) v1(54.16,2.53) v1(54.33,112.15) v1(54.27,99.48) v1(54.35,64.64) v1(54.31,61.81) v1(54.32,61.23) v1(54.33,47.94) v1(54.31,43.88) v1(54.32,21.31) v1(54.4,114.35) v1(54.43,105.33) v1(54.44,70.38) v1(54.36,63.29) v1(54.35,60.11) v1(54.36,22.09) v1(54.49,125.62) v1(54.47,103.14) v1(54.54,101.51) v1(54.52,80.11) v1(54.5,77.56) v1(54.45,28.67) v1(54.45,14.69) v1(54.57,88.1) v1(54.55,37.42) v1(54.6,34.11) v1(54.6,20.17) v1(54.55,8.23) v1(54.66,122.75) v1(54.72,107.38) v1(54.74,82.45) v1(54.73,23.98) v1(54.76,128.78) v1(54.83,110.33) v1(54.76,84.89) v1(54.8,68.92) v1(54.78,57.73) v1(54.79,50.77) v1(54.85,35.25) v1(54.79,30.3) v1(54.82,6.02) v1(54.95,99.82) v1(54.92,93.21) v1(54.88,73.1) v1(54.88,71.85) v1(54.91,55.74) v1(54.91,27.75) v1(54.9,13.46) v1(54.87,11.37) v1(55.04,121.7) v1(54.99,90.06) v1(55.01,86.61) v1(55.03,71.36) v1(54.95,53.55) v1(54.96,44.71) v1(55.05,36.63) v1(54.99,26.97) v1(55.05,67.54) v1(55.11,46.81) v1(55.09,34.95) v1(55.07,32.96) v1(55.13,22.82) v1(55.08,22.35) v1(55.07,21.63) v1(55.11,3.77) v1(55.17,113.57) v1(55.15,73.98) v1(55.25,37.26) v1(55.23,25.49) v1(55.23,18.56) v1(55.3,107.4) v1(55.28,64.72) v1(55.28,58.52) v1(55.31,37.05) v1(55.34,34.02) v1(55.38,66.76) v1(55.38,60.56) v1(55.36,24.36) v1(55.37,21.01) v1(55.42,9.29) v1(55.39,1.24) v1(55.54,112.89) v1(55.52,106.2) v1(55.48,96.28) v1(55.63,104.36) v1(55.6,43.95) v1(55.74,124.31) v1(55.67,108.11) v1(55.7,102.23) v1(55.69,100.36) v1(55.66,7.11) v1(55.85,95.47) v1(55.8,76.11) v1(55.79,52.43) v1(55.8,49.71) v1(55.81,46.09) v1(55.78,34.86) v1(55.79,26.07) v1(55.77,23.47) v1(55.82,10.26) v1(55.94,127.65) v1(55.93,71.36) v1(55.86,68.31) v1(55.91,56.42) v1(55.86,54.7) v1(55.86,20.22) v1(55.93,12.43) v1(55.95,47.45) v1(56,22.82) v1(56.04,21.97) v1(55.98,4.85) v1(56.14,43.81) v1(56.12,34.94) v1(56.06,32.95) v1(56.14,25.98) v1(56.14,2.56) v1(56.25,96.42) v1(56.16,69.09) v1(56.17,36.76) v1(56.3,110.3) v1(56.35,72.25) v1(56.31,65.75) v1(56.31,59.55) v1(56.26,36.7) v1(56.3,25.29) v1(56.34,25) v1(56.29,18) v1(56.38,120.94) v1(56.39,70.94) v1(56.36,44.89) v1(56.44,36.23) v1(56.45,21.25) v1(56.4,20.07) v1(56.44,14.72) v1(56.5,105.36) v1(56.45,99.48) v1(56.53,24.09) v1(56.5,23.71) v1(56.53,23.47) v1(56.54,8.25) v1(56.58,112.26) v1(56.63,75.08) v1(56.69,125.62) v1(56.72,73.02) v1(56.73,53.57) v1(56.66,35.62) v1(56.7,34.45) v1(56.72,30.29) v1(56.69,27.78) v1(56.7,22.68) v1(56.71,21.64) v1(56.76,113.58) v1(56.78,112.9) v1(56.78,103.25) v1(56.78,101.5) v1(56.83,71.36) v1(56.78,34.49) v1(56.81,6.05) v1(56.86,122.75) v1(56.95,111.56) v1(56.89,13.49) v1(56.86,11.42) v1(56.96,128.78) v1(57.02,107.47) v1(57,70.12) v1(56.98,57.73) v1(56.96,44.47) v1(57.09,37.02) v1(57.1,34.86) v1(57.1,26.06) v1(57.12,20.66) v1(57.1,3.79) v1(57.24,121.7) v1(57.23,99.4) v1(57.25,72.25) v1(57.18,36.28) v1(57.29,70.94) v1(57.29,66.78) v1(57.27,64.74) v1(57.29,60.59) v1(57.27,58.55) v1(57.3,36.25) v1(57.29,28.78) v1(57.39,55.7) v1(57.39,34.97) v1(57.35,33.99) v1(57.43,20.56) v1(57.42,18.58) v1(57.41,9.31) v1(57.38,1.26) v1(57.49,68.34) v1(57.47,45.94) v1(57.48,24) v1(57.49,23.59) v1(57.51,22.74) v1(57.53,21.57) v1(57.65,96.26) v1(57.62,73.02) v1(57.6,54.72) v1(57.56,52.51) v1(57.61,50.9) v1(57.58,43.65) v1(57.55,26.95) v1(57.65,7.14) v1(57.73,107.25) v1(57.74,105.5) v1(57.7,103.07) v1(57.72,100.64) v1(57.73,71.36) v1(57.67,37.22) v1(57.75,108.8) v1(57.78,104.38) v1(57.84,45.33) v1(57.84,12.46) v1(57.81,10.29) v1(57.85,110.45) v1(58.02,114.3) v1(57.95,111.99) v1(57.96,24.17) v1(58,20.07) v1(58.14,127.65) v1(58.14,99.17) v1(58.15,72.25) v1(58.11,56.42) v1(58.05,32.38) v1(58.13,23.29) v1(58.06,21.45) v1(58.2,102.32) v1(58.23,100.39) v1(58.19,99.84) v1(58.19,70.94) v1(58.17,65.78) v1(58.17,59.58) v1(58.18,36.2) v1(58.16,22.38) v1(58.33,34.99) v1(58.33,26.2) v1(58.32,25.03) v1(58.28,18.03) v1(58.36,105.33) v1(58.36,53.62) v1(58.41,49.68) v1(58.44,36.86) v1(58.45,101.55) v1(58.52,73.02) v1(58.53,51.58) v1(58.54,30.33) v1(58.53,27.78) v1(58.58,120.94) v1(58.58,112.84) v1(58.63,71.36) v1(58.6,34.67) v1(58.73,109.77) v1(58.75,25.78) v1(58.67,11.45) v1(58.76,35.11) v1(58.77,13.49) v1(58.94,107.45) v1(58.85,52.25) v1(58.94,44.32) v1(59.05,72.25) v1(59.01,23.32) v1(59.15,112.6) v1(59.06,111.15) v1(59.09,70.94) v1(59.1,53.31) v1(59.11,45.98) v1(59.09,26.09) v1(59.08,14.64) v1(59.16,128.78) v1(59.2,66.78) v1(59.18,64.69) v1(59.2,60.59) v1(59.18,58.49) v1(59.18,57.73) v1(59.24,55.73) v1(59.18,18.56) v1(59.25,22.18) v1(59.42,73.02) v1(59.47,114.3) v1(59.55,108.85) v1(59.53,71.36) v1(59.47,36.86) v1(59.55,35.97) v1(59.64,121.86) v1(59.64,112.6) v1(59.57,54.52) v1(59.62,36.38) v1(59.61,35.82) v1(59.63,35.23) v1(59.65,23.25) v1(59.69,96.26) v1(59.7,45.36) v1(59.73,26.93) v1(59.7,12.48) v1(59.77,106.22) v1(59.79,104.4) v1(59.85,20.12) v1(59.95,72.25) v1(59.91,28.83) v1(59.95,113.9) v1(59.99,70.94) v1(60.02,20.91) v1(60.11,110.55) v1(60.08,54.48) v1(60.12,51.89) v1(60.24,65.75) v1(60.24,59.55) v1(60.25,51.29) v1(60.2,34.67) v1(60.32,73.02) v1(60.34,70.03) v1(60.31,56.42) v1(60.29,47.55) v1(60.34,24.96) v1(60.3,18) v1(60.42,128.2) v1(60.39,111.86) v1(60.43,71.36) v1(60.4,68.32) v1(60.42,43.35) v1(60.5,36.97) v1(60.6,36.3) v1(60.63,32.38) v1(60.59,27.82) v1(60.56,26.9) v1(60.74,52.82) v1(60.68,13.52) v1(60.66,11.48) v1(60.78,120.94) v1(60.85,72.25) v1(60.79,69.04) v1(60.92,114.3) v1(60.89,70.94) v1(60.95,66.82) v1(60.88,26.06) v1(60.95,111.2) v1(60.98,109.78) v1(60.95,105.45) v1(61.04,30.56) v1(61.13,112.59) v1(61.14,49.68) v1(61.07,14.66) v1(61.22,73.02) v1(61.17,64.74) v1(61.19,60.61) v1(61.17,58.55) v1(61.15,50.64) v1(61.24,22.2) v1(61.17,18.59) v1(61.33,71.36) v1(61.36,128.78) v1(61.38,57.73) v1(61.39,27.73) v1(61.43,26.87) v1(61.45,113.9) v1(61.54,53.08) v1(61.52,45.97) v1(61.6,96.28) v1(61.59,35.22) v1(61.56,28.01) v1(61.55,26.69) v1(61.64,23.28) v1(61.56,12.51) v1(61.7,108.8) v1(61.75,72.25) v1(61.67,52.33) v1(61.84,111.84) v1(61.83,106.22) v1(61.79,70.94) v1(61.93,104.36) v1(62,20.94) v1(62.03,19.82) v1(62.12,110.52) v1(62.12,73.02) v1(62.15,65.78) v1(62.15,59.58) v1(62.23,71.36) v1(62.22,44.32) v1(62.2,39.01) v1(62.33,24.99) v1(62.29,18.02) v1(62.46,114.28) v1(62.51,56.42) v1(62.52,34.33) v1(62.46,32.12) v1(62.64,121.74) v1(62.57,112.57) v1(62.63,73.67) v1(62.65,72.25) v1(62.64,69.07) v1(62.62,45.38) v1(62.62,37.84) v1(62.59,36.33) v1(62.59,13.52) v1(62.57,11.42) v1(62.65,127.65) v1(62.69,70.94) v1(62.9,113.9) v1(62.85,105.5) v1(62.87,26.09) v1(63.02,73.02) v1(63.02,51.87) v1(63.03,18.72) v1(62.98,14.61) v1(63.1,111.25) v1(63.13,71.36) v1(63.05,64.77) v1(63.05,58.57) v1(63.15,25.62) v1(63.06,20.48) v1(63.2,70.03) v1(63.25,68.28) v1(63.15,60.61) v1(63.17,50.64) v1(63.25,26.42) v1(63.16,22.32) v1(63.26,109.78) v1(63.32,29.01) v1(63.4,111.83) v1(63.44,31.03) v1(63.48,96.38) v1(63.55,72.25) v1(63.52,54.31) v1(63.5,35.24) v1(63.56,128.78) v1(63.61,126.74) v1(63.59,70.94) v1(63.58,57.73) v1(63.57,38.45) v1(63.63,12.48) v1(63.68,114.28) v1(63.7,112.55) v1(63.83,47.55) v1(63.9,108.8) v1(63.92,73.02) v1(63.92,49.66) v1(63.92,36.8) v1(63.94,30.89) v1(64.03,71.36) v1(64,66.82) v1(64,43.29) v1(63.98,33.57) v1(64.06,123.12) v1(64.08,65.8) v1(64.08,59.6) v1(64.15,50.64) v1(64.07,34.89) v1(64.09,32.09) v1(64.11,27.78) v1(64.12,26.92) v1(64.12,23.9) v1(64.09,21.31) v1(64.18,110.48) v1(64.18,104.41) v1(64.15,51.16) v1(64.19,37.85) v1(64.25,28) v1(64.22,25.93) v1(64.2,25.07) v1(64.31,45.99) v1(64.45,72.25) v1(64.37,34.33) v1(64.37,30.03) v1(64.49,70.94) v1(64.45,53.18) v1(64.5,36.28) v1(64.45,32.15) v1(64.59,73.68) v1(64.58,13.54) v1(64.56,11.48) v1(64.71,56.42) v1(64.82,73.02) v1(64.81,69.09) v1(64.8,50.64) v1(64.85,127.65) v1(64.93,71.36) v1(65.04,64.79) v1(65.04,58.6) v1(65.05,20.48) v1(65.02,18.74) v1(64.99,18.32) v1(64.97,14.66) v1(65.07,105.36) v1(65.06,66.83) v1(65.07,60.64) v1(65.15,24.93) v1(65.11,23.22) v1(65.07,22.35) v1(65.15,111.25) v1(65.23,29.03) v1(65.2,26.99) v1(65.35,72.25) v1(65.38,111.83) v1(65.38,109.8) v1(65.39,70.94) v1(65.43,54.34) v1(65.36,45.35) v1(65.41,35.24) v1(65.36,31.06) v1(65.48,51.16) v1(65.54,12.51) v1(65.65,96.36) v1(65.72,73.02) v1(65.69,70.13) v1(65.67,38.44) v1(65.76,128.78) v1(65.81,126.74) v1(65.85,108.85) v1(65.83,71.36) v1(65.78,57.73) v1(65.93,125.09) v1(65.94,65.83) v1(65.94,59.63) v1(65.85,50.64) v1(65.95,21.34) v1(65.98,19.79) v1(66.08,68.32) v1(66.08,44.29) v1(66.1,28.03) v1(66.13,25.96) v1(66.1,23.92) v1(66.25,72.25) v1(66.23,30.05) v1(66.26,110.52) v1(66.32,104.45) v1(66.29,70.94) v1(66.31,53.18) v1(66.44,34.33) v1(66.36,32.09) v1(66.49,36.33) v1(66.47,11.48) v1(66.62,73.02) v1(66.73,71.36) v1(66.67,49.69) v1(66.77,73.67) v1(66.91,56.42) v1(66.91,37.85) v1(66.85,14.69) v1(66.98,66.83) v1(66.95,64.74) v1(66.98,60.64) v1(66.95,58.55) v1(66.98,45.98) v1(66.98,22.35) v1(66.96,20.48) v1(66.98,18.34) v1(67.05,127.65) v1(67.15,72.25) v1(67.14,29.03) v1(67.11,26.94) v1(67.14,24.92) v1(67.1,23.25) v1(67.1,13.22) v1(67.21,105.38) v1(67.19,70.94) v1(67.3,111.25) v1(67.3,96.35) v1(67.34,54.34) v1(67.34,43.39) v1(67.27,31.06) v1(67.39,35.27) v1(67.47,109.78) v1(67.52,73.02) v1(67.47,47.55) v1(67.5,12.51) v1(67.63,71.36) v1(67.56,69.1) v1(67.6,19.82) v1(67.69,126.06) v1(67.96,128.78) v1(68.01,126.88) v1(68.05,72.25) v1(68.01,65.8) v1(68.01,59.6) v1(67.98,57.73) v1(68.04,25.96) v1(68.02,23.87) v1(68.02,21.31) v1(68.09,70.94) v1(68.22,110.51) v1(68.22,51.16) v1(68.22,50.64) v1(68.25,44.32) v1(68.22,42.85) v1(68.17,38.45) v1(68.17,28) v1(68.33,45.39) v1(68.27,36.28) v1(68.3,30.03) v1(68.42,73.02) v1(68.38,53.18) v1(68.35,34.33) v1(68.35,32.15) v1(68.54,104.48) v1(68.53,71.36) v1(68.48,13.54) v1(68.45,11.5) v1(68.58,70.15) v1(68.78,68.32) v1(68.84,14.72) v1(68.95,72.25) v1(68.94,64.79) v1(68.94,58.6) v1(68.95,42.32) v1(68.94,20.48) v1(68.89,18.29) v1(68.95,73.7) v1(68.99,70.94) v1(68.96,66.86) v1(68.96,60.66) v1(68.97,22.37) v1(69.11,56.42) v1(69.13,29.06) v1(69.1,26.99) v1(69.07,24.93) v1(69.2,111.25) v1(69.2,105.36) v1(69.2,49.69) v1(69.25,127.65) v1(69.32,73.02) v1(69.33,54.36) v1(69.25,43.39) v1(69.25,31.09) v1(69.42,109.8) v1(69.43,71.36) v1(69.36,35.29) v1(69.36,12.53) v1(69.47,45.99) v1(69.55,50.64) v1(69.63,37.83) v1(69.7,108.85) v1(69.85,72.25) v1(69.88,126.08) v1(69.89,70.94) v1(69.92,69.1) v1(69.92,65.83) v1(69.92,59.63) v1(69.93,21.34) v1(70.03,25.99) v1(70,23.92) v1(70.13,32.09) v1(70.08,28.03) v1(70.16,128.78) v1(70.21,126.88) v1(70.17,110.53) v1(70.22,73.02) v1(70.18,57.73) v1(70.24,44.35) v1(70.21,30.05) v1(70.35,106.47) v1(70.33,71.36) v1(70.29,53.18) v1(70.29,42.85) v1(70.26,36.3) v1(70.29,34.33) v1(70.45,19.82) v1(70.75,72.25) v1(70.75,64.82) v1(70.75,58.62) v1(70.66,51.16) v1(70.69,45.38) v1(70.79,70.94) v1(70.85,66.86) v1(70.85,60.66) v1(70.81,47.55) v1(70.83,20.48) v1(70.75,14.66) v1(70.87,104.48) v1(70.93,22.37) v1(70.88,18.34) v1(71,42.32) v1(70.98,38.46) v1(70.98,27.02) v1(70.98,24.95) v1(71.1,111.25) v1(71.07,73.72) v1(71.12,73.02) v1(71.08,70.07) v1(71.09,29.06) v1(71.24,109.78) v1(71.23,71.36) v1(71.21,68.32) v1(71.16,50.64) v1(71.24,43.42) v1(71.22,31.11) v1(71.28,105.38) v1(71.31,56.42) v1(71.29,54.36) v1(71.27,35.32) v1(71.44,127.67) v1(71.42,12.51) v1(71.65,72.25) v1(71.65,108.85) v1(71.69,70.94) v1(71.69,50.64) v1(71.78,65.85) v1(71.78,59.66) v1(71.85,49.7) v1(71.88,45.98) v1(71.89,23.95) v1(71.86,21.37) v1(71.86,19.81) v1(72.02,73.02) v1(72.02,28.05) v1(71.99,25.99) v1(72.1,125.96) v1(72.13,71.36) v1(72.15,34.33) v1(72.12,32.12) v1(72.15,30.11) v1(72.21,57.73) v1(72.22,53.18) v1(72.22,44.35) v1(72.17,36.25) v1(72.35,106.47) v1(72.36,128.78) v1(72.44,110.53) v1(72.43,69.1) v1(72.38,13.57) v1(72.35,11.5) v1(72.55,72.25) v1(72.6,126.88) v1(72.59,70.94) v1(72.73,64.85) v1(72.73,58.65) v1(72.66,37.85) v1(72.74,14.72) v1(72.76,66.89) v1(72.76,60.69) v1(72.84,22.4) v1(72.82,20.48) v1(72.77,18.37) v1(72.92,73.02) v1(73.05,108.85) v1(73.03,71.36) v1(73,29.09) v1(72.97,27.05) v1(73.08,104.45) v1(73.13,45.37) v1(73.13,31.14) v1(73.08,24.95) v1(73.15,111.25) v1(73.23,109.8) v1(73.19,73.77) v1(73.2,54.39) v1(73.18,51.78) v1(73.18,50.64) v1(73.15,43.42) v1(73.18,35.32) v1(73.27,105.41) v1(73.3,42.32) v1(73.33,12.53) v1(73.45,72.25) v1(73.49,70.94) v1(73.49,56.39) v1(73.64,127.67) v1(73.64,65.88) v1(73.64,59.68) v1(73.72,21.39) v1(73.75,19.84) v1(73.82,73.02) v1(73.93,71.36) v1(73.89,32.11) v1(73.88,28.08) v1(73.9,26.01) v1(73.88,23.97) v1(74.01,30.13) v1(74.12,68.35) v1(74.08,53.18) v1(74.08,42.85) v1(74.25,109.95) v1(74.17,106.44) v1(74.21,44.35) v1(74.17,38.45) v1(74.16,36.3) v1(74.21,34.33) v1(74.24,11.53) v1(74.3,126.04) v1(74.35,72.25) v1(74.28,70.1) v1(74.28,47.55) v1(74.32,45.98) v1(74.34,13.57) v1(74.39,70.94) v1(74.41,57.73) v1(74.45,108.85) v1(74.55,14.74) v1(74.56,128.78) v1(74.64,64.79) v1(74.64,58.6) v1(74.56,49.69) v1(74.72,73.02) v1(74.67,66.89) v1(74.67,60.69) v1(74.73,20.48) v1(74.8,126.88) v1(74.83,71.36) v1(74.79,50.64) v1(74.78,25.01) v1(74.75,22.4) v1(74.75,18.4) v1(74.91,29.09) v1(74.88,26.99) v1(75.04,31.14) v1(75.12,69.1) v1(75.12,54.39) v1(75.06,43.44) v1(75.25,72.25) v1(75.22,45.37) v1(75.25,42.32) v1(75.17,35.35) v1(75.25,19.87) v1(75.3,73.77) v1(75.29,70.94) v1(75.27,12.56) v1(75.62,73.02) v1(75.73,71.36) v1(75.7,65.85) v1(75.7,59.66) v1(75.69,56.39) v1(75.68,37.83) v1(75.84,127.67) v1(75.81,26.01) v1(75.79,23.92) v1(75.79,21.37) v1(75.94,42.85) v1(75.94,28.05) v1(76.04,70.11) v1(76.02,32.12) v1(76.15,72.25) v1(76.12,44.35) v1(76.12,34.33) v1(76.07,30.11) v1(76.19,70.94) v1(76.23,11.55) v1(76.33,68.34) v1(76.34,36.3) v1(76.36,53.14) v1(76.44,51.78) v1(76.5,126.04) v1(76.52,73.02) v1(76.45,50.64) v1(76.47,14.69) v1(76.63,71.36) v1(76.63,64.85) v1(76.63,58.65) v1(76.61,57.73) v1(76.66,66.91) v1(76.66,60.71) v1(76.68,45.98) v1(76.74,22.42) v1(76.72,20.48) v1(76.66,18.34) v1(76.76,128.78) v1(76.85,24.98) v1(76.9,32.92) v1(76.9,29.11) v1(76.87,27.05) v1(76.9,13.47) v1(77,126.88) v1(77.05,72.25) v1(76.97,43.44) v1(77.03,31.16) v1(77.09,70.94) v1(77.1,54.41) v1(77.13,38.47) v1(77.08,35.35) v1(77.07,12.62) v1(77.2,41.72) v1(77.3,42.32) v1(77.42,73.02) v1(77.52,115.75) v1(77.53,113.83) v1(77.55,109.95) v1(77.53,71.36) v1(77.55,49.7) v1(77.56,110.53) v1(77.61,65.88) v1(77.61,59.68) v1(77.65,19.81) v1(77.7,111.25) v1(77.68,73.84) v1(77.7,21.39) v1(77.75,47.54) v1(77.8,26.04) v1(77.78,23.97) v1(77.95,72.25) v1(77.89,56.39) v1(77.92,53.13) v1(77.85,28.08) v1(78.04,127.67) v1(77.99,70.94) v1(78.01,32.15) v1(77.98,30.13) v1(78.06,69.1) v1(78.11,44.35) v1(78.19,36.23) v1(78.18,13.55) v1(78.23,11.53) v1(78.32,73.02) v1(78.31,34.37) v1(78.41,114.8) v1(78.43,71.36) v1(78.4,45.37) v1(78.45,14.72) v1(78.45,108.85) v1(78.54,64.85) v1(78.54,58.65) v1(78.52,20.48) v1(78.6,110.5) v1(78.65,66.89) v1(78.65,60.69) v1(78.63,22.42) v1(78.7,125.96) v1(78.68,27.07) v1(78.65,18.4) v1(78.85,72.25) v1(78.81,57.73) v1(78.79,37.85) v1(78.78,29.11) v1(78.76,25.01) v1(78.89,70.94) v1(78.9,32.92) v1(78.94,31.16) v1(78.96,128.78) v1(79.04,54.39) v1(78.96,43.47) v1(78.99,35.37) v1(79.2,126.88) v1(79.22,73.02) v1(79.25,41.72) v1(79.2,12.56) v1(79.26,115.74) v1(79.27,113.83) v1(79.33,71.36) v1(79.42,68.22) v1(79.63,70.07) v1(79.58,65.88) v1(79.58,59.68) v1(79.6,42.32) v1(79.58,24) v1(79.56,21.42) v1(79.63,19.86) v1(79.65,111.25) v1(79.75,72.25) v1(79.71,28.1) v1(79.69,26.04) v1(79.79,70.94) v1(79.77,34.38) v1(79.87,30.16) v1(80.01,110.5) v1(79.97,73.87) v1(79.97,53.18) v1(79.99,51.16) v1(80.04,50.64) v1(80.05,36.3) v1(80,32.17) v1(80.12,114.83) v1(80.12,73.02) v1(80.09,56.39) v1(80.12,11.55) v1(80.23,71.36) v1(80.24,45.98) v1(80.16,13.58) v1(80.37,127.72) v1(80.36,49.68) v1(80.44,14.69) v1(80.47,121.06) v1(80.47,119.56) v1(80.47,118.18) v1(80.49,116.77) v1(80.53,64.87) v1(80.53,58.67) v1(80.54,22.45) v1(80.51,20.48) v1(80.46,18.42) v1(80.65,72.25) v1(80.63,69.1) v1(80.56,66.91) v1(80.56,60.71) v1(80.61,25.03) v1(80.69,70.94) v1(80.65,38.46) v1(80.69,29.14) v1(80.67,27.1) v1(80.85,31.19) v1(80.9,35.37) v1(81,126.05) v1(81.05,113.82) v1(81.05,109.9) v1(81.02,73.02) v1(81.01,57.73) v1(80.95,54.41) v1(81.14,115.73) v1(81.13,71.36) v1(81.11,12.59) v1(81.16,128.78) v1(81.25,111.15) v1(81.43,65.9) v1(81.44,59.71) v1(81.43,47.55) v1(81.42,21.44) v1(81.44,19.89) v1(81.46,126.88) v1(81.55,72.25) v1(81.55,41.72) v1(81.6,111.85) v1(81.6,108.8) v1(81.59,70.94) v1(81.57,28.13) v1(81.6,26.06) v1(81.57,24.02) v1(81.73,30.18) v1(81.75,95.81) v1(81.83,53.18) v1(81.92,73.02) v1(81.93,34.34) v1(81.91,32.12) v1(81.93,13.53) v1(81.93,11.58) v1(81.98,114.81) v1(82.03,71.36) v1(82.04,36.35) v1(82.23,45.38) v1(82.32,70.1) v1(82.32,68.18) v1(82.29,56.39) v1(82.29,37.83) v1(82.28,14.69) v1(82.4,73.88) v1(82.45,72.25) v1(82.44,64.82) v1(82.44,58.62) v1(82.45,22.45) v1(82.42,20.48) v1(82.45,18.45) v1(82.55,115.45) v1(82.49,70.94) v1(82.47,66.91) v1(82.47,60.71) v1(82.47,25.06) v1(82.57,127.72) v1(82.6,29.14) v1(82.58,27.05) v1(82.65,111.2) v1(82.71,95.9) v1(82.84,113.82) v1(82.82,73.02) v1(82.76,31.19) v1(82.93,71.36) v1(82.86,54.41) v1(82.89,35.4) v1(82.9,33.02) v1(82.96,12.61) v1(83.09,49.67) v1(83.21,125.94) v1(83.21,57.73) v1(83.35,72.25) v1(83.27,51.16) v1(83.36,128.78) v1(83.39,70.94) v1(83.37,50.64) v1(83.5,65.88) v1(83.5,59.68) v1(83.51,26.06) v1(83.48,23.97) v1(83.48,21.42) v1(83.64,28.1) v1(83.66,126.88) v1(83.72,73.02) v1(83.8,71.4) v1(83.84,69.11) v1(83.84,45.96) v1(83.84,34.37) v1(83.79,30.16) v1(83.8,19.82) v1(83.89,53.18) v1(83.87,45.36) v1(83.89,32.17) v1(83.95,13.64) v1(84,38.43) v1(84.05,11.61) v1(84.13,36.42) v1(84.25,72.25) v1(84.16,47.55) v1(84.25,14.69) v1(84.29,70.94) v1(84.43,64.87) v1(84.43,58.67) v1(84.44,22.48) v1(84.41,20.48) v1(84.36,18.4) v1(84.46,66.94) v1(84.46,60.74) v1(84.49,56.39) v1(84.55,41.72) v1(84.54,25.03) v1(84.62,73.02) v1(84.59,29.16) v1(84.57,27.1) v1(84.73,71.36) v1(84.75,31.22) v1(84.77,127.72) v1(84.85,54.44) v1(84.79,37.83) v1(84.82,12.64) v1(85.03,50.64) v1(85.1,92.2) v1(85.15,90.87) v1(85.15,74.91) v1(85.15,72.25) v1(85.15,70.94) v1(85.15,70.05) v1(85.15,68.2) v1(85.06,35.41) v1(85.34,19.86) v1(85.39,21.44) v1(85.51,126.04) v1(85.55,28.13) v1(85.49,26.09) v1(85.47,24.02) v1(85.56,128.78) v1(85.65,88.36) v1(85.65,86.28) v1(85.65,84.22) v1(85.65,82.45) v1(85.65,80.42) v1(85.65,78.45) v1(85.65,76.74) v1(85.65,73.02) v1(85.65,71.36) v1(85.65,65.9) v1(85.65,59.71) v1(85.65,57.73) v1(85.55,37.64) v1(85.72,91.19) v1(85.74,74.61) v1(85.74,72.19) v1(85.74,70.12) v1(85.73,64.31) v1(85.74,62.05) v1(85.74,54.42) v1(85.74,52.99) v1(85.73,51.97) v1(85.68,45.99) v1(85.7,30.18) v1(85.76,67.89) v1(85.75,56.36) v1(85.76,50.85) v1(85.78,47.61) v1(85.8,11.66) v1(85.86,126.88) v1(85.9,13.47) v1(86,108.85) v1(86,93.1) v1(85.99,45.15) v1(86.05,37.68) v1(86.25,85.9) v1(86.24,38.3) v1(86.24,34.33) v1(86.24,20.48) v1(86.16,14.68) v1(86.3,86.9) v1(86.35,79.49) v1(86.35,36.37) v1(86.35,22.29) v1(86.35,18.45) v1(86.39,89.63) v1(86.41,87.74) v1(86.39,83.46) v1(86.39,81.25) v1(86.39,77.64) v1(86.42,75.65) v1(86.37,73.71) v1(86.38,72.19) v1(86.39,70.97) v1(86.38,70.12) v1(86.39,69.15) v1(86.39,66.78) v1(86.37,65.01) v1(86.39,62.67) v1(86.38,61.15) v1(86.37,59.36) v1(86.38,57.74) v1(86.38,54.89) v1(86.38,52.99) v1(86.41,51.94) v1(86.39,49.31) v1(86.47,56.39) v1(86.47,51.16) v1(86.45,27.12) v1(86.45,25.06) v1(86.6,45.15) v1(86.6,41.72) v1(86.55,29.16) v1(86.85,95.7) v1(86.85,94.75) v1(86.84,12.69) v1(86.9,111.2) v1(86.9,108.8) v1(86.9,106.57) v1(86.9,85.65) v1(86.97,127.72) v1(87.01,89.58) v1(86.97,72.25) v1(86.99,70.94) v1(87.02,69.1) v1(87.01,67.04) v1(86.97,60.66) v1(86.97,58.62) v1(86.97,54.44) v1(87.18,64.61) v1(87.35,87) v1(87.29,84.19) v1(87.32,73.02) v1(87.35,37.92) v1(87.28,35.36) v1(87.25,33.22) v1(87.28,21.29) v1(87.33,19.92) v1(87.4,85.15) v1(87.43,71.36) v1(87.35,45.74) v1(87.38,24.02) v1(87.5,88.05) v1(87.5,81.38) v1(87.53,78.48) v1(87.5,75.78) v1(87.48,28.16) v1(87.48,26.06) v1(87.55,13.47) v1(87.61,57.73) v1(87.63,54.83) v1(87.65,43.72) v1(87.65,42.42) v1(87.71,126.04) v1(87.74,53.18) v1(87.76,128.78) v1(87.85,72.25) v1(87.81,55.67) v1(87.79,11.68) v1(87.9,111.85) v1(87.89,70.94) v1(87.94,61.84) v1(87.89,59.66) v1(88,70.15) v1(88.06,126.88) v1(88.06,68.29) v1(88.06,65.77) v1(88.25,108.85) v1(88.25,86.95) v1(88.22,73.02) v1(88.23,38.25) v1(88.23,34.35) v1(88.23,20.48) v1(88.18,18.29) v1(88.15,14.64) v1(88.3,87.95) v1(88.35,86.2) v1(88.28,85.59) v1(88.33,71.36) v1(88.29,50.9) v1(88.26,36.39) v1(88.26,22.32) v1(88.4,88.95) v1(88.43,82.76) v1(88.39,51.93) v1(88.44,27.15) v1(88.41,25.06) v1(88.51,79.96) v1(88.49,77.11) v1(88.5,74.59) v1(88.55,41.72) v1(88.46,29.19) v1(88.64,53.87) v1(88.6,19.82) v1(88.75,72.25) v1(88.72,54.47) v1(88.7,12.72) v1(88.77,106.57) v1(88.79,70.94) v1(88.85,58.65) v1(88.87,60.69) v1(88.89,56.39) v1(88.99,127.74) v1(89.02,105.7) v1(89.12,73.02) v1(89.14,35.39) v1(89.14,21.31) v1(89.2,89.75) v1(89.23,71.36) v1(89.23,69.11) v1(89.21,67.04) v1(89.22,45.75) v1(89.24,33.24) v1(89.3,88.95) v1(89.26,37.92) v1(89.34,28.18) v1(89.4,88.15) v1(89.43,86.93) v1(89.38,64.61) v1(89.39,26.09) v1(89.37,24.05) v1(89.49,84.19) v1(89.65,72.25) v1(89.6,53.18) v1(89.7,81.38) v1(89.73,78.48) v1(89.7,75.78) v1(89.69,70.94) v1(89.75,59.68) v1(89.7,43.72) v1(89.7,42.42) v1(89.7,11.63) v1(89.8,96.25) v1(89.8,95.55) v1(89.8,95.15) v1(89.8,94.75) v1(89.8,94.35) v1(89.8,93.95) v1(89.81,57.73) v1(89.83,54.83) v1(89.96,128.78) v1(90.05,125.96) v1(90.05,87.9) v1(90.02,73.02) v1(90.01,55.67) v1(90.04,14.66) v1(90.13,71.36) v1(90.14,61.84) v1(90.06,51.16) v1(90.14,34.3) v1(90.14,20.48) v1(90.1,19.87) v1(90.2,96.25) v1(90.15,95.55) v1(90.2,95.15) v1(90.2,94.75) v1(90.2,94.35) v1(90.2,93.95) v1(90.2,70.1) v1(90.2,68.24) v1(90.17,36.39) v1(90.17,22.32) v1(90.17,18.32) v1(90.27,105.71) v1(90.26,65.77) v1(90.35,27.1) v1(90.27,25.08) v1(90.35,13.47) v1(90.37,29.19) v1(90.55,89.3) v1(90.48,85.59) v1(90.6,95.15) v1(90.6,94.75) v1(90.6,94.35) v1(90.6,93.95) v1(90.61,88.17) v1(90.63,82.76) v1(90.6,41.72) v1(90.71,79.96) v1(90.69,77.11) v1(90.7,74.59) v1(90.72,50.56) v1(90.85,110.2) v1(90.84,53.87) v1(90.76,12.69) v1(91.05,108.9) v1(91,107.3) v1(91,96.35) v1(91,95.95) v1(91,95.55) v1(91,95.15) v1(91,94.75) v1(91,94.35) v1(91,93.95) v1(91.09,56.39) v1(91.15,33.19) v1(91.19,127.74) v1(91.25,37.95) v1(91.2,35.36) v1(91.2,21.29) v1(91.3,26.09) v1(91.28,24) v1(91.4,96.35) v1(91.4,95.95) v1(91.4,95.55) v1(91.4,95.15) v1(91.4,94.75) v1(91.4,94.35) v1(91.4,93.95) v1(91.45,72.25) v1(91.45,68.77) v1(91.41,67.04) v1(91.41,58.68) v1(91.36,51.93) v1(91.41,28.16) v1(91.49,70.98) v1(91.52,45.74) v1(91.58,107.99) v1(91.61,107.26) v1(91.58,64.61) v1(91.57,50.56) v1(91.7,110.83) v1(91.72,109.91) v1(91.65,108.9) v1(91.71,89.57) v1(91.69,84.19) v1(91.67,53.18) v1(91.69,11.68) v1(91.8,96.35) v1(91.8,95.95) v1(91.8,95.55) v1(91.8,95.15) v1(91.8,94.75) v1(91.8,94.35) v1(91.8,93.95) v1(91.82,73.02) v1(91.81,59.66) v1(91.85,13.52) v1(91.9,100.95) v1(91.9,81.38) v1(91.93,78.48) v1(91.9,75.78) v1(91.93,71.36) v1(91.93,57.78) v1(92.03,54.83) v1(92.03,14.69) v1(92.13,34.35) v1(92.13,20.48) v1(92.08,18.27) v1(92.16,128.78) v1(92.2,104.8) v1(92.2,96.35) v1(92.2,95.95) v1(92.2,95.55) v1(92.2,95.15) v1(92.2,94.75) v1(92.2,94.35) v1(92.2,93.95) v1(92.21,55.67) v1(92.16,36.42) v1(92.16,22.35) v1(92.34,126.08) v1(92.3,106.42) v1(92.35,72.25) v1(92.34,61.84) v1(92.34,27.15) v1(92.34,25.06) v1(92.39,70.94) v1(92.36,29.21) v1(92.47,70.09) v1(92.51,68.15) v1(92.46,65.77) v1(92.62,54.49) v1(92.64,51.16) v1(92.7,104.8) v1(92.68,85.59) v1(92.72,73.02) v1(92.74,58.65) v1(92.67,12.72) v1(92.81,88.17) v1(92.83,82.76) v1(92.83,71.36) v1(92.77,60.71) v1(92.85,19.87) v1(92.9,95.4) v1(92.91,79.96) v1(92.89,77.11) v1(92.9,74.59) v1(93.05,93.2) v1(93.05,92.8) v1(92.98,66.57) v1(92.98,56.39) v1(93.04,53.87) v1(93.05,41.72) v1(93.11,35.39) v1(93.14,33.24) v1(93.11,21.31) v1(93.25,72.25) v1(93.21,37.95) v1(93.3,107.2) v1(93.29,106.3) v1(93.29,70.94) v1(93.32,28.18) v1(93.29,26.12) v1(93.27,24.05) v1(93.39,127.74) v1(93.37,90.28) v1(93.41,69.1) v1(93.45,93.2) v1(93.45,92.8) v1(93.58,116.39) v1(93.62,73.02) v1(93.62,64.58) v1(93.61,58.68) v1(93.58,53.18) v1(93.65,13.52) v1(93.58,11.71) v1(93.73,71.36) v1(93.73,59.68) v1(93.7,57.76) v1(93.77,84.2) v1(93.81,81.42) v1(93.91,89.57) v1(93.88,87.47) v1(93.86,67.35) v1(93.94,14.64) v1(94.05,51.93) v1(94.03,45.74) v1(94.02,34.38) v1(94.02,20.48) v1(94.15,72.25) v1(94.13,70.09) v1(94.1,55.67) v1(94.12,36.42) v1(94.12,22.35) v1(94.07,18.32) v1(94.19,70.94) v1(94.23,54.83) v1(94.17,50.55) v1(94.22,27.17) v1(94.25,25.08) v1(94.29,126.06) v1(94.31,61.81) v1(94.33,29.21) v1(94.36,128.78) v1(94.39,68.09) v1(94.4,19.84) v1(94.51,115.45) v1(94.45,94.85) v1(94.52,73.02) v1(94.52,65.73) v1(94.57,117.39) v1(94.63,71.36) v1(94.63,58.67) v1(94.61,12.74) v1(94.73,60.71) v1(94.76,82.82) v1(94.9,85.62) v1(94.92,77.12) v1(94.86,74.52) v1(95.01,88.17) v1(95.05,72.25) v1(95.05,35.41) v1(95.02,33.27) v1(95.05,21.34) v1(95.05,80.02) v1(95.09,70.94) v1(95.1,41.72) v1(95.12,37.97) v1(95.18,66.57) v1(95.18,56.39) v1(95.24,53.87) v1(95.15,24.08) v1(95.28,128.79) v1(95.3,128.17) v1(95.31,127.6) v1(95.25,28.21) v1(95.25,26.12) v1(95.42,73.02) v1(95.52,116.42) v1(95.5,57.77) v1(95.53,53.16) v1(95.59,127.74) v1(95.57,90.28) v1(95.55,70.1) v1(95.56,11.73) v1(95.65,102.5) v1(95.68,100.19) v1(95.66,98.66) v1(95.75,97.64) v1(95.66,59.71) v1(95.78,71.38) v1(95.82,64.58) v1(95.86,128.78) v1(95.95,72.25) v1(95.93,69.16) v1(95.93,51.16) v1(95.93,14.69) v1(96.01,114.4) v1(95.97,84.2) v1(96.01,81.42) v1(95.98,75.8) v1(95.99,70.94) v1(96.03,36.44) v1(96,34.4) v1(96.03,22.37) v1(96,20.48) v1(95.95,18.34) v1(96.1,89.25) v1(96.06,67.35) v1(96.16,87.48) v1(96.24,29.24) v1(96.21,27.2) v1(96.18,25.11) v1(96.32,73.02) v1(96.3,55.67) v1(96.28,19.86) v1(96.39,128.83) v1(96.42,128.2) v1(96.42,127.63) v1(96.44,115.47) v1(96.39,102.19) v1(96.44,101.15) v1(96.44,99.44) v1(96.43,54.83) v1(96.42,45.74) v1(96.45,13.52) v1(96.5,117.42) v1(96.51,61.81) v1(96.47,12.77) v1(96.65,125.96) v1(96.64,103.89) v1(96.64,60.74) v1(96.62,58.7) v1(96.72,65.73) v1(96.88,118.55) v1(96.91,35.44) v1(96.91,21.36) v1(96.96,82.82) v1(97.01,72.14) v1(96.96,71.38) v1(97.03,37.97) v1(97.01,33.29) v1(97.1,85.62) v1(97.12,77.12) v1(97.06,74.52) v1(97.11,28.23) v1(97.14,24.1) v1(97.24,93.37) v1(97.23,80.38) v1(97.2,75.15) v1(97.18,26.1) v1(97.27,95.82) v1(97.29,90.29) v1(97.29,88.34) v1(97.26,86.34) v1(97.27,84.49) v1(97.29,82.47) v1(97.25,80.02) v1(97.31,77.8) v1(97.27,73.04) v1(97.32,70.98) v1(97.28,70.11) v1(97.4,116.42) v1(97.43,101.58) v1(97.38,66.57) v1(97.38,56.39) v1(97.44,53.87) v1(97.39,53.16) v1(97.55,107.4) v1(97.48,100.64) v1(97.49,98.99) v1(97.52,59.73) v1(97.51,57.79) v1(97.55,19.87) v1(97.48,11.68) v1(97.56,109.32) v1(97.56,108.7) v1(97.57,108.05) v1(97.56,106.79) v1(97.56,106.22) v1(97.73,102.17) v1(97.66,51.93) v1(97.73,14.72) v1(97.85,127.65) v1(97.76,96.8) v1(97.83,68.18) v1(97.77,44.1) v1(97.8,41.87) v1(97.85,13.47) v1(97.94,36.44) v1(97.91,34.35) v1(97.94,22.37) v1(97.91,20.48) v1(97.94,18.37) v1(98.05,97.73) v1(98.02,64.58) v1(98.04,25.13) v1(98.1,102.87) v1(98.15,96.5) v1(98.14,94.68) v1(98.15,83.31) v1(98.14,81.19) v1(98.15,80.37) v1(98.1,76.52) v1(98.15,73.54) v1(98.1,72.29) v1(98.15,29.24) v1(98.12,27.15) v1(98.21,114.4) v1(98.24,109.33) v1(98.24,108.71) v1(98.25,108.06) v1(98.23,107.41) v1(98.24,106.79) v1(98.24,106.23) v1(98.24,105.58) v1(98.2,103.96) v1(98.17,100.72) v1(98.16,89.15) v1(98.16,85.41) v1(98.17,84.2) v1(98.21,81.42) v1(98.18,75.8) v1(98.16,71.19) v1(98.33,115.47) v1(98.26,67.35) v1(98.39,117.42) v1(98.45,99.75) v1(98.39,50.58) v1(98.54,71.68) v1(98.53,58.65) v1(98.5,55.67) v1(98.53,12.74) v1(98.55,60.74) v1(98.63,54.83) v1(98.75,72.18) v1(98.71,61.81) v1(98.76,128.78) v1(98.81,118.58) v1(98.78,45.73) v1(98.91,124.37) v1(98.9,109.33) v1(98.9,108.71) v1(98.91,108.06) v1(98.9,107.41) v1(98.9,106.79) v1(98.91,106.23) v1(98.91,105.58) v1(98.92,65.73) v1(98.92,33.24) v1(99.02,103.96) v1(98.99,100.69) v1(98.98,95.82) v1(99.03,93.37) v1(98.98,90.27) v1(99,88.5) v1(99.03,84.45) v1(99.04,82.52) v1(99.03,80.18) v1(99.03,77.76) v1(99.02,75.12) v1(99.02,38) v1(98.97,35.41) v1(98.97,21.34) v1(99.05,19.82) v1(99.08,116.41) v1(99.09,86.37) v1(99.09,26.1) v1(99.05,24.05) v1(99.16,93.84) v1(99.16,82.82) v1(99.18,28.21) v1(99.33,99.02) v1(99.3,85.62) v1(99.32,77.12) v1(99.26,74.52) v1(99.35,72.56) v1(99.44,72.22) v1(99.45,13.52) v1(99.52,109.32) v1(99.52,108.7) v1(99.53,108.05) v1(99.51,107.4) v1(99.52,106.79) v1(99.53,106.2) v1(99.55,105.61) v1(99.45,80.02) v1(99.45,53.16) v1(99.46,11.73) v1(99.55,102.87) v1(99.59,59.71) v1(99.58,56.39) v1(99.64,53.87) v1(99.7,113.72) v1(99.67,57.75) v1(99.72,14.74) v1(99.79,103.93) v1(99.82,68.77) v1(99.93,98.58) v1(99.85,70.13) v1(99.94,51.16) v1(99.93,36.47) v1(99.9,34.4) v1(99.93,22.4) v1(99.9,20.48) v1(99.85,18.32) v1(100.05,127.65) v1(99.97,87.53) v1(99.97,44.1) v1(100.15,107.39) v1(100.11,100.76) v1(100.13,100.45) v1(100.11,100.13) v1(100.1,99.8) v1(100.1,99.37) v1(100.09,98.96) v1(100.08,89.87) v1(100.13,29.27) v1(100.11,27.2) v1(100.11,25.11) v1(100.18,115.46) v1(100.15,109.31) v1(100.15,108.69) v1(100.16,108.05) v1(100.15,106.78) v1(100.17,106.19) v1(100.19,105.6) v1(100.35,96.5) v1(100.41,114.4) v1(100.42,102.67) v1(100.38,101.51) v1(100.39,84.19) v1(100.38,75.8) v1(100.44,73.43) v1(100.35,71.28) v1(100.44,12.77) v1(100.47,98.63) v1(100.5,81.57) v1(100.54,60.77) v1(100.52,58.7) v1(100.64,103) v1(100.6,94.9) v1(100.7,118.58) v1(100.72,109.33) v1(100.72,108.71) v1(100.72,108.06) v1(100.71,107.41) v1(100.72,106.79) v1(100.73,106.21) v1(100.75,105.62) v1(100.7,55.67) v1(100.76,128.75) v1(100.83,54.83) v1(100.89,100.48) v1(100.88,35.44) v1(100.88,21.37) v1(101.01,116.44) v1(100.97,98.62) v1(101,94.9) v1(101.04,24.1) v1(101.12,125.72) v1(101.11,124.37) v1(101.12,70.12) v1(101.09,28.23) v1(101.08,26.13) v1(101.1,13.42) v1(101.2,88.59) v1(101.26,109.33) v1(101.26,108.71) v1(101.27,108.06) v1(101.25,107.41) v1(101.26,106.79) v1(101.28,106.21) v1(101.29,105.62) v1(101.27,11.76) v1(101.39,97.53) v1(101.35,95.41) v1(101.36,93.84) v1(101.4,85.65) v1(101.36,53.16) v1(101.48,98.62) v1(101.51,82.88) v1(101.47,74.56) v1(101.5,59.73) v1(101.63,113.74) v1(101.56,77.12) v1(101.64,72.22) v1(101.63,57.76) v1(101.63,14.69) v1(101.68,128.81) v1(101.71,128.18) v1(101.71,127.61) v1(101.69,80.07) v1(101.71,34.43) v1(101.71,20.48) v1(101.78,56.39) v1(101.84,53.87) v1(101.81,36.47) v1(101.81,22.4) v1(101.84,18.37) v1(101.92,27.23) v1(101.95,19.87) v1(102,98.61) v1(102.02,29.27) v1(102.02,25.13) v1(102.12,115.48) v1(102.25,127.65) v1(102.25,104.37) v1(102.29,99.38) v1(102.32,89.86) v1(102.32,87.49) v1(102.27,51.93) v1(102.31,50.52) v1(102.3,12.79) v1(102.43,86.38) v1(102.45,112.85) v1(102.53,98.61) v1(102.55,96.5) v1(102.48,75.83) v1(102.61,128.82) v1(102.64,128.2) v1(102.64,127.63) v1(102.61,114.4) v1(102.59,84.19) v1(102.6,78.24) v1(102.64,73.43) v1(102.55,71.28) v1(102.64,70.97) v1(102.62,69.28) v1(102.57,60.82) v1(102.6,58.75) v1(102.6,13.47) v1(102.7,81.57) v1(102.74,35.46) v1(102.74,21.39) v1(102.77,101.52) v1(102.85,24.13) v1(102.9,116.44) v1(102.9,55.67) v1(102.95,28.26) v1(102.98,98.61) v1(103.03,54.83) v1(103.03,41.75) v1(102.96,26.13) v1(103.08,123.5) v1(103.11,100.94) v1(103.12,100.63) v1(103.13,100.31) v1(103.12,100.02) v1(103.11,99.72) v1(103.12,99.31) v1(103.13,98.93) v1(103.12,53.15) v1(103.32,125.72) v1(103.31,124.37) v1(103.29,108.75) v1(103.26,104.8) v1(103.26,11.79) v1(103.41,128.81) v1(103.4,88.59) v1(103.36,59.76) v1(103.36,57.84) v1(103.52,113.74) v1(103.49,61.89) v1(103.61,108.03) v1(103.63,99.92) v1(103.63,99.1) v1(103.59,97.53) v1(103.55,95.41) v1(103.6,85.65) v1(103.59,70.14) v1(103.65,18.4) v1(103.62,14.74) v1(103.71,82.88) v1(103.67,74.56) v1(103.72,36.5) v1(103.7,34.46) v1(103.72,22.42) v1(103.7,20.48) v1(103.76,77.12) v1(103.84,72.22) v1(103.89,80.07) v1(103.93,29.29) v1(103.9,27.25) v1(103.88,25.16) v1(104,115.48) v1(103.98,56.39) v1(104.04,53.87) v1(104.03,20.21) v1(104.1,103.9) v1(104.14,99.69) v1(104.16,12.82) v1(104.34,60.79) v1(104.31,58.75) v1(104.33,51.98) v1(104.45,127.65) v1(104.39,63.04) v1(104.52,89.86) v1(104.52,87.49) v1(104.53,70.99) v1(104.45,69.26) v1(104.52,51.16) v1(104.45,49.26) v1(104.6,35.49) v1(104.6,21.42) v1(104.73,100.66) v1(104.67,96.5) v1(104.65,94.75) v1(104.74,86.38) v1(104.68,75.83) v1(104.79,84.19) v1(104.8,78.24) v1(104.84,73.43) v1(104.75,71.28) v1(104.81,28.28) v1(104.83,24.15) v1(104.91,98.77) v1(104.9,81.57) v1(104.86,26.19) v1(105.02,123.53) v1(104.99,107.27) v1(104.96,105.17) v1(104.98,53.15) v1(105.11,128.76) v1(105.23,54.83) v1(105.17,11.73) v1(105.28,111.39) v1(105.29,101.2) v1(105.3,13.52) v1(105.39,113.78) v1(105.52,125.72) v1(105.51,122.56) v1(105.49,105.39) v1(105.46,96.1) v1(105.47,61.89) v1(105.55,57.78) v1(105.49,23.29) v1(105.63,109.35) v1(105.62,88.62) v1(105.63,36.5) v1(105.61,34.4) v1(105.63,22.42) v1(105.61,20.48) v1(105.63,18.42) v1(105.71,108.34) v1(105.69,106.25) v1(105.7,89.55) v1(105.74,25.19) v1(105.81,124.79) v1(105.79,99.75) v1(105.79,97.53) v1(105.8,85.65) v1(105.84,29.29) v1(105.82,27.2) v1(105.86,96.1) v1(105.91,82.88) v1(105.87,74.56) v1(105.85,41.79) v1(105.96,77.12) v1(106.03,70.97) v1(105.95,69.23) v1(106.08,128.83) v1(106.1,128.21) v1(106.11,127.64) v1(106.12,110.59) v1(106.09,95.4) v1(106.09,80.07) v1(106.23,100.38) v1(106.25,60.79) v1(106.22,58.7) v1(106.24,53.87) v1(106.25,17.85) v1(106.23,12.79) v1(106.28,114.66) v1(106.26,112.73) v1(106.43,103.88) v1(106.43,62.95) v1(106.38,51.98) v1(106.52,107.38) v1(106.52,105.42) v1(106.55,70.15) v1(106.62,19.39) v1(106.64,15.35) v1(106.7,127.65) v1(106.69,121.19) v1(106.72,98.82) v1(106.73,87.48) v1(106.67,35.46) v1(106.74,24.1) v1(106.67,21.39) v1(106.77,89.38) v1(106.8,55.39) v1(106.77,26.19) v1(106.9,123.53) v1(106.87,96.5) v1(106.88,75.83) v1(106.87,28.26) v1(107.05,94.9) v1(107,78.24) v1(107.05,53.15) v1(106.96,51.93) v1(107.01,49.82) v1(107.05,128.81) v1(107.07,128.18) v1(107.08,127.61) v1(107.14,106.44) v1(107.1,86.32) v1(107.22,111.41) v1(107.2,90.17) v1(107.18,13.85) v1(107.16,11.79) v1(107.33,113.8) v1(107.31,108.35) v1(107.34,99.72) v1(107.29,84.25) v1(107.28,59.76) v1(107.27,57.75) v1(107.45,122.58) v1(107.45,79.77) v1(107.38,61.92) v1(107.54,124.78) v1(107.5,93.05) v1(107.55,81.6) v1(107.55,18.37) v1(107.64,71.03) v1(107.58,69.27) v1(107.62,36.52) v1(107.6,34.46) v1(107.63,27.23) v1(107.62,22.45) v1(107.6,20.48) v1(107.62,16.32) v1(107.72,125.72) v1(107.75,88.53) v1(107.69,23.29) v1(107.76,128.78) v1(107.82,120.41) v1(107.77,100.72) v1(107.82,97.56) v1(107.82,54.55) v1(107.83,29.32) v1(107.8,25.16) v1(107.89,89.86) v1(108.15,107.41) v1(108.21,114.69) v1(108.2,112.76) v1(108.18,110.59) v1(108.25,105.41) v1(108.15,103.65) v1(108.18,77.08) v1(108.24,60.82) v1(108.21,58.75) v1(108.25,27.67) v1(108.29,98.78) v1(108.3,95.55) v1(108.42,62.92) v1(108.4,18.5) v1(108.49,51.16) v1(108.47,41.83) v1(108.53,19.34) v1(108.55,13.07) v1(108.63,121.21) v1(108.55,106.13) v1(108.56,74.43) v1(108.58,35.49) v1(108.58,21.42) v1(108.63,15.4) v1(108.68,70.15) v1(108.73,24.15) v1(108.7,16.75) v1(108.8,99.67) v1(108.8,93.05) v1(108.85,90.27) v1(108.8,48.93) v1(108.78,28.28) v1(108.9,127.65) v1(108.87,108.34) v1(108.9,101.61) v1(108.93,87.48) v1(108.94,53.85) v1(108.98,123.53) v1(108.95,94.85) v1(108.97,89.38) v1(109,55.39) v1(108.96,53.15) v1(109.07,96.5) v1(109.07,11.79) v1(109.21,113.8) v1(109.19,59.79) v1(109.2,24.35) v1(109.17,13.83) v1(109.33,122.58) v1(109.35,61.92) v1(109.26,57.8) v1(109.42,105.36) v1(109.42,78.23) v1(109.49,84.25) v1(109.53,18.42) v1(109.64,102.57) v1(109.61,99.65) v1(109.61,16.37) v1(109.7,111.65) v1(109.65,101.57) v1(109.65,100.62) v1(109.75,81.6) v1(109.7,79.87) v1(109.68,41.26) v1(109.76,128.78) v1(109.76,120.43) v1(109.8,104.6) v1(109.8,103.4) v1(109.85,90.27) v1(109.93,88.41) v1(109.91,86.32) v1(109.88,69.28) v1(109.87,62.94) v1(109.99,97.34) v1(109.96,71.02) v1(110.02,54.55) v1(110.1,114.69) v1(110.08,112.76) v1(110.1,106.87) v1(110.09,89.86) v1(110.12,58.75) v1(110.05,13.02) v1(110.22,60.79) v1(110.22,53.04) v1(110.35,93.07) v1(110.32,23.85) v1(110.38,77.08) v1(110.42,50.28) v1(110.44,15.43) v1(110.51,121.21) v1(110.5,111.65) v1(110.5,110.35) v1(110.53,48.99) v1(110.54,20.99) v1(110.51,19.39) v1(110.61,106.16) v1(110.65,108.05) v1(110.67,82.88) v1(110.7,40.09) v1(110.65,18.45) v1(110.84,87.49) v1(110.76,74.43) v1(110.88,85.29) v1(111.02,113.78) v1(111.04,109.44) v1(111.05,90.22) v1(110.98,80.43) v1(111.01,52.06) v1(111.1,127.65) v1(111.12,97.34) v1(111.08,70.15) v1(111.06,46.99) v1(111.1,16.8) v1(111.06,11.81) v1(111.19,108.62) v1(111.21,61.94) v1(111.15,59.79) v1(111.17,57.8) v1(111.2,55.39) v1(111.2,54.25) v1(111.17,49.62) v1(111.32,52.93) v1(111.32,23.29) v1(111.42,16.39) v1(111.47,124.28) v1(111.48,107.57) v1(111.52,105.42) v1(111.52,75.23) v1(111.53,22.31) v1(111.49,8.94) v1(111.55,2.01) v1(111.64,120.43) v1(111.6,95.65) v1(111.62,78.23) v1(111.59,6.35) v1(111.58,4.13) v1(111.67,92.9) v1(111.68,76.37) v1(111.71,51.06) v1(111.69,49.69) v1(111.68,46.97) v1(111.7,40.62) v1(111.76,125.88) v1(111.83,96.35) v1(111.78,44.81) v1(111.76,43.86) v1(111.9,114.68) v1(111.93,112.81) v1(111.86,110.63) v1(111.85,89.36) v1(111.92,48.98) v1(111.91,13.04) v1(111.96,128.78) v1(112.04,88.42) v1(112,79.87) v1(112.07,108.42) v1(112.11,86.32) v1(112.06,84.21) v1(112.11,81.6) v1(112.11,69.27) v1(112.13,60.82) v1(112.11,58.78) v1(112.23,109.44) v1(112.18,71.03) v1(112.24,62.95) v1(112.22,54.55) v1(112.34,128.83) v1(112.33,121.2) v1(112.3,90.17) v1(112.3,48.19) v1(112.33,45.7) v1(112.34,43.18) v1(112.36,128.21) v1(112.37,127.64) v1(112.43,15.45) v1(112.51,125.06) v1(112.47,92.71) v1(112.51,43.83) v1(112.52,23.85) v1(112.53,7.68) v1(112.58,77.08) v1(112.57,76.04) v1(112.63,74.69) v1(112.64,5.25) v1(112.74,20.99) v1(112.8,127.28) v1(112.78,3.16) v1(112.93,94.65) v1(112.87,82.88) v1(112.92,53.04) v1(112.92,46.49) v1(112.9,18.55) v1(112.96,122.06) v1(112.95,113.8) v1(113.01,111.44) v1(113.04,87.49) v1(112.96,74.43) v1(113.01,59.81) v1(112.96,51.8) v1(113.05,50.18) v1(113,48.98) v1(112.96,44.64) v1(112.97,11.76) v1(113.07,128.82) v1(113.1,128.19) v1(113.1,127.62) v1(113.08,85.29) v1(113.08,61.88) v1(113.09,55.39) v1(113.18,80.43) v1(113.22,70.15) v1(113.15,57.82) v1(113.33,120.39) v1(113.34,53.85) v1(113.33,52.62) v1(113.41,124.31) v1(113.41,96.32) v1(113.35,43.94) v1(113.41,16.42) v1(113.54,109.43) v1(113.52,108.1) v1(113.5,90.32) v1(113.47,48.11) v1(113.52,23.29) v1(113.48,10.81) v1(113.6,45.7) v1(113.74,76.83) v1(113.73,42.48) v1(113.73,22.31) v1(113.69,12.29) v1(113.69,8.94) v1(113.75,2.01) v1(113.84,114.71) v1(113.82,84.21) v1(113.82,78.23) v1(113.83,19.54) v1(113.79,6.35) v1(113.78,4.13) v1(113.87,112.83) v1(113.96,125.88) v1(113.97,110.61) v1(114,93.05) v1(114.03,62.94) v1(114.05,60.82) v1(114.02,58.73) v1(114.05,89.36) v1(114.13,75.57) v1(114.11,54.55) v1(114.15,48.96) v1(114.1,16.8) v1(114.16,128.78) v1(114.23,125.11) v1(114.2,90.06) v1(114.24,88.42) v1(114.25,77.69) v1(114.24,51.93) v1(114.23,51.01) v1(114.22,49.54) v1(114.23,46.97) v1(114.18,45) v1(114.2,43.81) v1(114.26,121.23) v1(114.31,81.6) v1(114.34,53.06) v1(114.34,15.4) v1(114.43,123.31) v1(114.42,69.28) v1(114.49,71.02) v1(114.6,92.92) v1(114.6,79.87) v1(114.59,23.8) v1(114.75,107.87) v1(114.73,7.68) v1(114.84,113.8) v1(114.79,109.43) v1(114.75,96.4) v1(114.8,95.82) v1(114.76,46.84) v1(114.84,5.25) v1(114.9,122.08) v1(114.89,111.44) v1(114.87,52.08) v1(114.86,44.44) v1(114.94,20.99) v1(114.98,82.88) v1(115.03,80.43) v1(114.99,61.9) v1(114.95,18.5) v1(114.98,13.88) v1(114.96,11.81) v1(114.98,3.16) v1(115.06,85.3) v1(115.09,74.8) v1(115.08,59.79) v1(115.07,57.77) v1(115.06,41.27) v1(115.22,55.42) v1(115.16,47.67) v1(115.31,127.58) v1(115.29,124.31) v1(115.26,120.42) v1(115.35,88.87) v1(115.33,78.49) v1(115.32,16.37) v1(115.39,87.55) v1(115.36,76.43) v1(115.36,42.43) v1(115.55,60.83) v1(115.5,51.67) v1(115.5,50.45) v1(115.5,45.34) v1(115.58,90.06) v1(115.6,70.15) v1(115.59,43.88) v1(115.6,12.32) v1(115.72,114.71) v1(115.68,10.81) v1(115.75,112.83) v1(115.9,109.42) v1(115.89,89.36) v1(115.87,59.93) v1(115.86,22.43) v1(115.89,8.94) v1(115.95,2.01) v1(116.02,62.91) v1(116.01,58.78) v1(116.03,19.54) v1(115.99,6.35) v1(115.98,4.13) v1(116.15,121.23) v1(116.14,84.25) v1(116.08,52.05) v1(116.13,46.99) v1(116.11,44.45) v1(116.16,125.88) v1(116.19,107.7) v1(116.16,81.61) v1(116.2,79.87) v1(116.18,49.51) v1(116.25,16.75) v1(116.34,75.59) v1(116.36,128.78) v1(116.37,123.33) v1(116.45,113.68) v1(116.37,96.4) v1(116.45,88.44) v1(116.4,77.35) v1(116.45,61.33) v1(116.43,15.35) v1(116.5,54.53) v1(116.54,53.06) v1(116.65,93.07) v1(116.63,69.27) v1(116.63,60.51) v1(116.69,71.03) v1(116.82,128.83) v1(116.84,128.2) v1(116.85,127.63) v1(116.78,122.08) v1(116.82,59.04) v1(116.82,51.42) v1(116.79,48.86) v1(116.75,43.89) v1(116.75,42.55) v1(116.81,41.52) v1(116.76,40.74) v1(116.79,23.8) v1(116.79,12.29) v1(116.84,11.84) v1(116.94,13.88) v1(116.93,7.68) v1(117.03,90.12) v1(116.95,61.9) v1(116.97,57.76) v1(117.04,5.25) v1(117.15,120.42) v1(117.06,23.29) v1(117.15,127.3) v1(117.2,88.87) v1(117.18,82.88) v1(117.23,80.43) v1(117.22,20.92) v1(117.15,18.65) v1(117.18,3.16) v1(117.32,124.39) v1(117.27,114.76) v1(117.26,85.3) v1(117.35,45.7) v1(117.44,76.47) v1(117.41,74.78) v1(117.43,53.86) v1(117.41,50.79) v1(117.41,48.24) v1(117.41,16.32) v1(117.53,128.82) v1(117.45,78.49) v1(117.46,59.77) v1(117.49,55.39) v1(117.56,128.2) v1(117.56,127.63) v1(117.59,87.55) v1(117.64,51.53) v1(117.65,46.41) v1(117.69,109.55) v1(117.68,107.62) v1(117.73,70.15) v1(117.76,96.38) v1(117.87,95.82) v1(117.93,62.94) v1(117.91,60.55) v1(117.94,58.35) v1(117.88,10.81) v1(118.05,113.63) v1(118.03,52.37) v1(118.02,49.77) v1(118,42.57) v1(118.03,40.74) v1(118.05,31.45) v1(118.04,22.44) v1(118,6.45) v1(118.09,89.36) v1(118.1,79.92) v1(118.05,48.43) v1(118.08,8.99) v1(118.05,4.19) v1(118.2,90.12) v1(118.16,88.81) v1(118.25,43.77) v1(118.25,123.33) v1(118.34,84.25) v1(118.27,50.17) v1(118.29,2.04) v1(118.36,125.88) v1(118.36,81.61) v1(118.45,23.82) v1(118.42,15.4) v1(118.52,107.62) v1(118.51,95.29) v1(118.54,57.76) v1(118.51,54.55) v1(118.45,16.75) v1(118.56,128.78) v1(118.65,75.6) v1(118.65,45.68) v1(118.72,77.34) v1(118.74,53.06) v1(118.69,48.26) v1(118.81,61.93) v1(118.75,43.21) v1(118.83,12.26) v1(118.83,11.86) v1(118.93,69.28) v1(118.87,13.86) v1(119.05,124.43) v1(118.96,110.59) v1(119.01,71.02) v1(118.98,59.79) v1(119.13,90.1) v1(119.12,80.43) v1(119.07,7.68) v1(119.11,5.19) v1(119.17,121.56) v1(119.2,114.78) v1(119.32,96.4) v1(119.31,51.73) v1(119.3,46.95) v1(119.32,45.73) v1(119.35,42.62) v1(119.26,41.5) v1(119.29,40.74) v1(119.3,31.55) v1(119.26,23.29) v1(119.35,3.19) v1(119.45,61.33) v1(119.4,16.37) v1(119.39,10.83) v1(119.64,107.62) v1(119.63,74.8) v1(119.56,60.55) v1(119.63,53.86) v1(119.71,127.58) v1(119.72,57.9) v1(119.69,55.39) v1(119.83,113.63) v1(119.85,76.47) v1(119.84,62.9) v1(119.95,109.57) v1(119.92,78.46) v1(119.9,70.14) v1(120,82.86) v1(119.96,52.05) v1(119.96,50.19) v1(119.96,49.52) v1(119.98,47.63) v1(119.96,44.42) v1(120.18,89.64) v1(120.22,51.33) v1(120.22,15.43) v1(120.2,6.45) v1(120.3,90.22) v1(120.3,79.87) v1(120.27,72.94) v1(120.29,16.82) v1(120.28,8.99) v1(120.25,4.19) v1(120.39,107.62) v1(120.42,44.07) v1(120.53,81.6) v1(120.49,2.04) v1(120.55,59.79) v1(120.62,51.73) v1(120.57,48.45) v1(120.57,45.1) v1(120.59,41.56) v1(120.57,40.74) v1(120.6,31.57) v1(120.65,23.82) v1(120.73,96.35) v1(120.71,95.29) v1(120.71,54.55) v1(120.74,11.81) v1(120.76,128.78) v1(120.81,95.85) v1(120.84,61.36) v1(120.85,53.02) v1(120.78,13.86) v1(120.9,110.62) v1(120.9,92.92) v1(120.89,90.12) v1(120.94,77.35) v1(120.88,75.59) v1(120.93,69.26) v1(120.87,58.23) v1(120.99,71.02) v1(120.99,50.2) v1(121.11,121.58) v1(121.09,114.78) v1(121.21,62.01) v1(121.23,52.03) v1(121.24,45.16) v1(121.2,16.39) v1(121.32,80.43) v1(121.32,60.55) v1(121.27,7.68) v1(121.31,5.19) v1(121.42,23.29) v1(121.49,107.62) v1(121.54,59.04) v1(121.46,12.74) v1(121.55,3.19) v1(121.59,10.83) v1(121.7,90.27) v1(121.83,53.86) v1(121.83,50.91) v1(121.83,41.58) v1(121.8,31.62) v1(121.91,127.58) v1(121.95,109.57) v1(121.9,79.92) v1(121.94,74.78) v1(121.89,55.39) v1(121.9,48.36) v1(121.98,89.72) v1(121.98,76.47) v1(122.03,70.14) v1(122.07,46.33) v1(122.15,40.74) v1(122.2,82.86) v1(122.18,71.76) v1(122.17,63.06) v1(122.2,61.34) v1(122.22,54.55) v1(122.19,50.19) v1(122.25,49.42) v1(122.2,16.85) v1(122.21,15.45) v1(122.29,124.07) v1(122.32,96.36) v1(122.35,93.15) v1(122.32,59.79) v1(122.43,42.29) v1(122.45,23.82) v1(122.4,6.45) v1(122.55,125.68) v1(122.5,89.33) v1(122.54,58.23) v1(122.45,51.31) v1(122.53,44.23) v1(122.48,8.99) v1(122.45,4.19) v1(122.56,107.62) v1(122.62,94.7) v1(122.63,77.24) v1(122.58,48.03) v1(122.6,46.91) v1(122.73,81.6) v1(122.74,75.59) v1(122.73,11.86) v1(122.69,2.04) v1(122.78,110.62) v1(122.85,90.07) v1(122.77,80.44) v1(122.76,73.69) v1(122.77,13.89) v1(122.91,54.55) v1(122.86,25.81) v1(123.04,128.83) v1(122.99,121.58) v1(123.05,53.02) v1(123.06,128.21) v1(123.07,127.64) v1(123.07,114.71) v1(123.14,88.41) v1(123.12,62.03) v1(123.14,45.25) v1(123.15,84.34) v1(123.23,69.27) v1(123.23,60.52) v1(123.19,16.42) v1(123.3,89.62) v1(123.31,71) v1(123.37,59.04) v1(123.43,49.35) v1(123.52,129.14) v1(123.46,85.3) v1(123.51,51.07) v1(123.53,22.44) v1(123.47,7.68) v1(123.51,5.19) v1(123.55,48.24) v1(123.64,43.08) v1(123.62,23.29) v1(123.72,105.48) v1(123.75,3.19) v1(123.84,95.3) v1(123.85,53.91) v1(123.79,46.81) v1(123.79,26.71) v1(123.76,21.06) v1(123.81,12.94) v1(123.79,10.83) v1(123.86,128.83) v1(123.89,128.21) v1(123.89,127.64) v1(123.93,92.89) v1(123.9,90.37) v1(123.93,49.84) v1(124,87.58) v1(123.99,45.41) v1(123.98,24.77) v1(124.15,70.12) v1(124.14,68.27) v1(124.11,61.35) v1(124.12,15.4) v1(124.23,124.1) v1(124.15,63.04) v1(124.22,59.78) v1(124.17,17.41) v1(124.3,109.58) v1(124.31,84.27) v1(124.32,71.55) v1(124.28,58.2) v1(124.26,57.31) v1(124.31,40.77) v1(124.37,6.45) v1(124.44,4.19) v1(124.54,97.66) v1(124.51,73.68) v1(124.5,73.02) v1(124.45,21.1) v1(124.63,96.38) v1(124.65,89.48) v1(124.61,43.81) v1(124.75,125.68) v1(124.71,88.23) v1(124.73,45.89) v1(124.7,23.82) v1(124.65,13.89) v1(124.78,122.57) v1(124.83,86.67) v1(124.77,11.98) v1(124.83,2.04) v1(124.87,105.47) v1(124.91,84.24) v1(124.93,82.89) v1(124.94,47.87) v1(125,114.74) v1(125.03,85.58) v1(125.02,60.53) v1(125,46.65) v1(125.08,106.3) v1(125.13,70.99) v1(125.07,69.23) v1(125.08,62.03) v1(125.08,59.01) v1(125.06,25.81) v1(125.1,18.85) v1(125.1,16.37) v1(125.16,128.78) v1(125.16,125.02) v1(125.25,53.02) v1(125.2,42.29) v1(125.29,108.4) v1(125.35,90.32) v1(125.34,48.42) v1(125.4,104.98) v1(125.4,103.84) v1(125.39,102.66) v1(125.39,101.56) v1(125.4,75.62) v1(125.4,74.77) v1(125.44,5.23) v1(125.52,85.33) v1(125.55,82.92) v1(125.5,76.42) v1(125.63,92.9) v1(125.6,73.67) v1(125.57,21.08) v1(125.57,12.92) v1(125.56,3.22) v1(125.69,59.79) v1(125.71,51.07) v1(125.7,19.09) v1(125.76,89.5) v1(125.77,61.32) v1(125.76,58.22) v1(125.89,86.85) v1(125.91,84.6) v1(125.87,40.75) v1(125.97,113.61) v1(126.05,100.65) v1(126.04,95.3) v1(126,73.7) v1(126.04,48.08) v1(126.01,15.3) v1(126.11,124.1) v1(126.08,88.04) v1(126.06,63.06) v1(126.07,17.49) v1(126.17,110.52) v1(126.17,97.91) v1(126.23,82.94) v1(126.2,56.07) v1(126.18,24.77) v1(126.34,68.27) v1(126.3,42.99) v1(126.39,109.37) v1(126.44,90.06) v1(126.41,45.16) v1(126.41,21.72) v1(126.53,18.86) v1(126.55,13.95) v1(126.52,11.91) v1(126.46,10.47) v1(126.6,75.62) v1(126.6,74.82) v1(126.62,54.74) v1(126.58,47.83) v1(126.59,43.79) v1(126.6,42.27) v1(126.6,22.65) v1(126.57,6.45) v1(126.64,4.19) v1(126.72,122.6) v1(126.82,111.51) v1(126.85,70.97) v1(126.95,125.68) v1(126.89,114.74) v1(126.87,73.32) v1(127.03,101.3) v1(127.01,60.55) v1(126.99,16.27) v1(127.03,2.04) v1(127.1,125.04) v1(127.06,112.5) v1(127.15,90.22) v1(127.1,25.89) v1(127.3,103.45) v1(127.31,84.24) v1(127.33,40.72) v1(127.29,12.93) v1(127.36,128.78) v1(127.43,108.34) v1(127.44,88.42) v1(127.45,70.98) v1(127.37,69.24) v1(127.39,61.33) v1(127.35,23.78) v1(127.5,19.12) v1(127.61,95.04) v1(127.64,76.4) v1(127.62,59.79) v1(127.65,58.97) v1(127.65,52.37) v1(127.56,21.11) v1(127.64,5.23) v1(127.65,128.83) v1(127.67,128.21) v1(127.68,127.64) v1(127.7,124.08) v1(127.7,97.6) v1(127.7,97.35) v1(127.7,97.1) v1(127.7,96.85) v1(127.7,92.98) v1(127.67,89.29) v1(127.7,86.7) v1(127.7,86.45) v1(127.7,86.2) v1(127.7,85.95) v1(127.81,106.34) v1(127.77,100.69) v1(127.75,71.6) v1(127.77,60.56) v1(127.76,3.22) v1(127.9,113.63) v1(127.86,42.29) v1(127.98,127.62) v1(128,101.87) v1(127.95,97.6) v1(127.95,97.35) v1(127.95,97.1) v1(127.95,96.85) v1(127.95,86.7) v1(127.95,86.45) v1(127.95,86.2) v1(127.95,85.95) v1(127.98,63.06) v1(127.96,31.96) v1(127.99,15.35) v1(128.11,110.54) v1(128.15,71.02) v1(128.1,69.22) v1(128.06,17.54) v1(128.09,6.48) v1(128.2,97.6) v1(128.2,97.35) v1(128.2,97.1) v1(128.2,96.85) v1(128.2,86.7) v1(128.2,86.45) v1(128.2,86.2) v1(128.2,85.95) v1(128.35,90.27) v1(128.27,43.73) v1(128.34,18.89) v1(128.42,128.85) v1(128.44,128.22) v1(128.45,127.65) v1(128.45,97.6) v1(128.45,97.35) v1(128.45,97.1) v1(128.45,96.85) v1(128.45,86.7) v1(128.45,86.45) v1(128.45,86.2) v1(128.45,85.95) v1(128.42,43.04) v1(128.5,70.1) v1(128.54,68.27) v1(128.53,59.76) v1(128.47,24.73) v1(128.6,122.6) v1(128.55,114.15) v1(128.55,58.24) v1(128.65,51.97) v1(128.65,51.17) v1(128.61,21.72) v1(128.7,97.6) v1(128.7,97.35) v1(128.7,97.1) v1(128.7,96.85) v1(128.7,86.7) v1(128.7,86.45) v1(128.7,86.2) v1(128.7,85.95) v1(128.69,22.62) v1(128.66,10.47) v1(128.76,108.35) v1(128.76,93.46) v1(128.85,82.22) v1(128.85,81.67) v1(128.85,56.12) v1(128.79,49.72) v1(128.81,41.46) v1(128.84,4.19) v1(128.95,97.6) v1(128.95,97.35) v1(128.95,97.1) v1(128.95,96.85) v1(128.95,86.7) v1(128.95,86.45) v1(128.95,86.2) v1(128.95,85.95) v1(128.93,84.24) v1(128.95,79.57) v1(128.9,70.97) v1(128.98,125.04) v1(128.99,112.53) v1(128.98,16.32) v1(129.15,125.68) v1(129.12,124.24) v1(129.2,97.6) v1(129.2,97.35) v1(129.2,97.1) v1(129.2,96.85) v1(129.2,86.7) v1(129.2,86.45) v1(129.2,86.2) v1(129.2,85.95) v1(129.22,45.8) v1(129.23,2.04) v1(129.29,61.33) v1(129.3,25.89) v1(129.45,97.6) v1(129.45,97.35) v1(129.45,97.1) v1(129.45,96.85) v1(129.45,86.7) v1(129.45,86.45) v1(129.45,86.2) v1(129.45,85.95) v1(129.41,31.97) v1(129.46,100.68) v1(129.47,21.06) v1(129.49,19.14) v1(129.56,128.78) v1(129.64,88.42) v1(129.56,59) v1(129.59,58.21) v1(129.65,52.17) v1(129.55,23.78) v1(129.74,109.25) v1(129.7,89.05) v1(129.7,79.67) v1(129.85,94.87) v1(129.76,90.57) v1(129.8,15.37) v1(129.84,5.23) v1(129.9,77.42) v1(129.9,63.5) v1(129.9,63.25) v1(129.9,63) v1(129.87,17.57) v1(129.99,110.54) v1(129.99,106.63) v1(130,78.35) v1(130.03,42.29) v1(129.96,3.22) v1(130.15,91.47) v1(130.1,84.42) v1(130.12,43.02) v1(130.18,127.62) v1(130.15,63.75) v1(130.3,77.67) v1(130.32,40.76) v1(130.44,43.74) v1(130.42,38.51) v1(130.5,18.85) v1(130.71,109.23) v1(130.7,88.65) v1(130.7,88.4) v1(130.71,84.25) v1(130.74,77.19) v1(130.68,65.9) v1(130.65,54.75) v1(130.75,53.37) v1(130.75,36.77) v1(130.85,78.35) v1(130.78,16.34) v1(130.8,4.19) v1(130.88,112.53) v1(130.95,88.65) v1(130.95,88.4) v1(130.86,45.16) v1(130.9,36.42) v1(130.93,31.97) v1(130.86,10.47) v1(131,97.45) v1(131,97.2) v1(130.96,59.79) v1(131.04,59.01) v1(131.05,124.26) v1(131.15,102.62) v1(131.1,56.07) v1(131.18,100.72) v1(131.2,88.65) v1(131.2,88.4) v1(131.23,2.07) v1(131.29,114.62) v1(131.3,97.45) v1(131.3,97.2) v1(131.35,77.37) v1(131.39,78.59) v1(131.45,60.55) v1(131.4,19.09) v1(131.6,97.45) v1(131.6,97.2) v1(131.65,84.22) v1(131.65,65.62) v1(131.56,43.08) v1(131.56,41.55) v1(131.69,113.61) v1(131.71,106.67) v1(131.7,67.34) v1(131.76,128.78) v1(131.85,112.47) v1(131.83,84.81) v1(131.85,79.52) v1(131.84,69.23) v1(131.85,51.67) v1(131.79,15.4) v1(131.93,103.21) v1(131.9,97.45) v1(131.9,97.2) v1(131.93,53.37) v1(131.85,17.6) v1(131.92,5.32) v1(131.86,3.19) v1(131.99,101.67) v1(132.04,96.08) v1(132,75.59) v1(132.04,61.28) v1(132.03,46.48) v1(132.12,60.53) v1(132.22,110.53) v1(132.25,78.23) v1(132.2,77.57) v1(132.17,65.93) v1(132.23,62.66) v1(132.24,61.79) v1(132.15,58.2) v1(132.19,40.76) v1(132.16,31.61) v1(132.35,85.22) v1(132.32,43.81) v1(132.3,42.29) v1(132.38,127.62) v1(132.39,112.47) v1(132.39,45.16) v1(132.55,78.67) v1(132.51,64.09) v1(132.6,78.02) v1(132.75,66.07) v1(132.68,59.78) v1(132.78,68.31) v1(132.85,49.6) v1(132.78,47.15) v1(132.94,124.26) v1(132.89,122.63) v1(132.9,78.47) v1(132.95,69.27) v1(132.89,45.81) v1(132.9,13.9) v1(132.9,13.3) v1(132.9,12.7) v1(132.9,12.1) v1(133.01,100.72) v1(133,70.12) v1(132.99,54.53) v1(132.97,44.49) v1(132.97,31.07) v1(133,4.19) v1(133.1,102.42) v1(133.1,79.52) v1(133.09,76.62) v1(133.08,71.79) v1(133.05,52.44) v1(133.15,50.27) v1(133.16,106.63) v1(133.21,97.02) v1(133.39,109.77) v1(133.39,61.29) v1(133.38,60.54) v1(133.52,111.6) v1(133.45,59.01) v1(133.55,51.87) v1(133.5,13.9) v1(133.5,12.7) v1(133.5,12.1) v1(133.6,78.77) v1(133.55,58.19) v1(133.65,52.52) v1(133.59,32.07) v1(133.61,27.65) v1(133.55,26.71) v1(133.57,2.02) v1(133.69,128.83) v1(133.71,128.21) v1(133.72,127.64) v1(133.7,103.26) v1(133.73,78.48) v1(133.68,15.64) v1(133.76,101.71) v1(133.8,52.22) v1(133.81,45.16) v1(133.83,28.06) v1(133.9,67.34) v1(133.92,53.37) v1(133.95,50.77) v1(133.94,43.08) v1(133.88,17.62) v1(133.96,128.78) v1(134.02,62.63) v1(134.04,46.47) v1(133.96,30.12) v1(134.15,109.11) v1(134.1,64.11) v1(134.08,59.79) v1(134.1,13.9) v1(134.1,13.3) v1(134.1,12.7) v1(134.1,12.1) v1(134.12,5.32) v1(134.06,3.19) v1(134.15,113.28) v1(134.16,110.56) v1(134.24,96.08) v1(134.25,87.62) v1(134.2,77.74) v1(134.17,76.52) v1(134.24,73.69) v1(134.19,70.97) v1(134.18,69.2) v1(134.33,81.5) v1(134.3,71.79) v1(134.35,68.31) v1(134.42,75.33) v1(134.44,61.79) v1(134.44,57.36) v1(134.58,127.62) v1(134.57,102.49) v1(134.62,27.5) v1(134.73,100.77) v1(134.7,81.22) v1(134.71,61.28) v1(134.7,51.72) v1(134.7,13.9) v1(134.7,13.3) v1(134.7,12.7) v1(134.82,122.66) v1(134.84,79.63) v1(134.79,60.49) v1(134.8,12.1) v1(134.86,128.83) v1(134.89,128.21) v1(134.89,127.64) v1(134.92,111.63) v1(134.9,67.37) v1(134.9,43.81) v1(134.93,30.49) v1(134.98,68.31) v1(135.11,70.14) v1(135.1,50.77) v1(135.14,47.15) v1(135.17,45.81) v1(135.24,44.47) v1(135.23,42.25) v1(135.18,26.49) v1(135.2,4.19) v1(135.26,109.71) v1(135.27,88.44) v1(135.34,78.91) v1(135.35,75.32) v1(135.44,82.58) v1(135.4,77.62) v1(135.44,58.62) v1(135.43,54.61) v1(135.42,52.44) v1(135.49,76.47) v1(135.51,73.23) v1(135.46,59.85) v1(135.46,57.66) v1(135.47,56.88) v1(135.52,38.37) v1(135.59,101.72) v1(135.65,64.24) v1(135.63,62.66) v1(135.6,61.6) v1(135.73,60.82) v1(135.73,40.47) v1(135.85,103.12) v1(135.8,90.62) v1(135.85,89.82) v1(135.78,80.5) v1(135.77,2.02) v1(135.93,114.9) v1(135.95,109.06) v1(135.95,85.52) v1(135.95,70.99) v1(135.94,49.02) v1(135.87,17.67) v1(135.86,15.64) v1(136.04,110.56) v1(136.05,89.17) v1(136.05,80.8) v1(136.09,113.31) v1(136.08,83.9) v1(136.12,69.22) v1(136.1,67.34) v1(136.12,53.37) v1(136.16,128.78) v1(136.25,71.83) v1(136.25,8.99) v1(136.29,111.6) v1(136.35,61.75) v1(136.3,60.25) v1(136.35,59.22) v1(136.31,6.46) v1(136.32,5.32) v1(136.26,3.19) v1(136.39,102.5) v1(136.37,43.08) v1(136.44,11.45) v1(136.45,90.58) v1(136.53,80.03) v1(136.5,73.92) v1(136.55,68.31) v1(136.53,46.48) v1(136.5,45.16) v1(136.53,35.21) v1(136.5,34.27) v1(136.64,82.49) v1(136.63,58.44) v1(136.63,41.5) v1(136.71,122.66) v1(136.72,100.71) v1(136.71,78.94) v1(136.75,77.73) v1(136.7,63.75) v1(136.67,57.66) v1(136.73,56.84) v1(136.67,47.79) v1(136.69,26.54) v1(136.85,89.12) v1(136.85,27.97) v1(136.9,73.47) v1(136.88,70.13) v1(136.9,63.75) v1(136.86,16.6) v1(136.94,14.87) v1(137,81.81) v1(137.25,78.3) v1(137.16,42.27) v1(137.19,10.23) v1(137.25,83.15) v1(137.35,77.72) v1(137.35,73.92) v1(137.43,127.58) v1(137.45,116.26) v1(137.44,105.7) v1(137.36,64.25) v1(137.45,50.27) v1(137.45,38.52) v1(137.45,35.17) v1(137.4,34.27) v1(137.47,121.28) v1(137.48,118.07) v1(137.5,104.15) v1(137.47,85.12) v1(137.5,80.99) v1(137.46,38.98) v1(137.55,120) v1(137.64,41.53) v1(137.56,29.9) v1(137.75,73.47) v1(137.7,72.05) v1(137.7,70.97) v1(137.69,69.25) v1(137.71,30.5) v1(137.68,17.7) v1(137.85,84.27) v1(137.8,74.65) v1(137.8,63.75) v1(137.75,7.15) v1(137.87,114.93) v1(137.9,62) v1(137.93,47.15) v1(137.88,44.49) v1(137.97,113.31) v1(137.98,102.53) v1(138.05,87.32) v1(138,75.25) v1(138.05,38.97) v1(138.04,38.31) v1(138.01,15.68) v1(137.97,2.02) v1(138.05,63.75) v1(138.05,9.02) v1(138.25,106.49) v1(138.21,83.03) v1(138.2,79.18) v1(138.22,77.56) v1(138.25,11.48) v1(138.31,104.93) v1(138.35,103.44) v1(138.32,53.37) v1(138.28,45.81) v1(138.27,13.81) v1(138.36,128.78) v1(138.36,101.78) v1(138.44,100.75) v1(138.5,94.52) v1(138.5,94.02) v1(138.55,88.02) v1(138.55,86.97) v1(138.49,51.08) v1(138.55,43.81) v1(138.6,70.15) v1(138.6,64.2) v1(138.7,97.15) v1(138.7,96.9) v1(138.75,68.31) v1(138.69,35.21) v1(138.83,109.07) v1(138.85,96.32) v1(138.85,62) v1(138.81,16.66) v1(138.95,97.15) v1(138.95,96.9) v1(138.88,82.54) v1(138.89,39.92) v1(139.05,87.62) v1(139.02,65.54) v1(139,27.87) v1(139,10.25) v1(139.1,94.52) v1(139.1,94.02) v1(139.1,88) v1(139.11,81.29) v1(139.14,69.26) v1(139.1,45.16) v1(139.07,43.06) v1(139.25,88.37) v1(139.24,80.28) v1(139.18,70.95) v1(139.21,59.15) v1(139.2,14.85) v1(139.3,96.32) v1(139.3,77.72) v1(139.29,64.25) v1(139.34,47.82) v1(139.41,121.3) v1(139.41,118.09) v1(139.39,116.28) v1(139.45,112.74) v1(139.45,95.5) v1(139.45,95.25) v1(139.45,88.05) v1(139.4,50.22) v1(139.43,41.91) v1(139.43,40.52) v1(139.52,128.16) v1(139.49,120.02) v1(139.53,46.47) v1(139.46,26.54) v1(139.61,44.51) v1(139.75,96.32) v1(139.7,94.52) v1(139.7,94.02) v1(139.65,62) v1(139.75,114.93) v1(139.8,88.1) v1(139.81,70.12) v1(139.85,67.92) v1(139.84,65.53) v1(139.86,109.42) v1(139.9,105.32) v1(139.9,88.37) v1(139.85,83.52) v1(139.89,70.93) v1(139.95,26.77) v1(139.99,88.79) v1(140,63.34) v1(140.03,43.22) v1(140.02,35.39) v1(140.06,82.25) v1(140.06,11.45) v1(140.06,9.04) v1(140.15,88.35) v1(140.21,81.17) v1(140.24,41.1) v1(140.22,15.71) v1(140.3,110.16) v1(140.28,100.77) v1(140.45,88.15) v1(140.44,1.86) v1(140.45,77.78) v1(140.5,62) v1(140.49,41.82) v1(140.54,13.86) v1(140.56,128.78) v1(140.7,88.15) v1(140.65,72.7) v1(140.66,67.91) v1(140.67,65.56) v1(140.7,63.8) v1(140.8,112.15) v1(140.83,104.07) v1(140.8,88.35) v1(140.81,64.21) v1(140.85,62.5) v1(140.76,47.15) v1(140.95,84.4) v1(140.95,79.52) v1(140.9,51.09) v1(140.9,50.22) v1(141.02,45.81) v1(141.1,109.44) v1(141.05,88.15) v1(141.15,83.37) v1(141.11,59.14) v1(141.15,10.32) v1(141.15,84.6) v1(141.23,82.22) v1(141.25,77.72) v1(141.19,70.07) v1(141.21,59.97) v1(141.18,43.2) v1(141.29,121.3) v1(141.3,118.09) v1(141.27,116.28) v1(141.34,114.92) v1(141.26,69.19) v1(141.37,120.02) v1(141.45,112.95) v1(141.38,65.73) v1(141.37,57.66) v1(141.46,105.32) v1(141.47,41.79) v1(141.51,14.91) v1(141.55,75.35) v1(141.58,71.12) v1(141.65,58.42) v1(141.6,44.51) v1(141.75,79.82) v1(141.72,71.82) v1(141.83,127.58) v1(141.77,110.16) v1(141.82,108.64) v1(141.81,45.16) v1(141.87,11.48) v1(141.87,9.06) v1(142,100.81) v1(142,77.77) v1(141.95,68.02) v1(142,39.3) v1(142.09,122.79) v1(142.15,79.42) v1(142.07,69.32) v1(142.08,66.35) v1(142.07,46.48) v1(142.11,29.45) v1(142.24,112.13) v1(142.21,64.69) v1(142.35,92.22) v1(142.34,83.34) v1(142.28,70.07) v1(142.35,41.91) v1(142.27,40.04) v1(142.29,30.59) v1(142.42,109.4) v1(142.41,49.54) v1(142.45,33.82) v1(142.54,93.03) v1(142.65,107.72) v1(142.65,106.02) v1(142.63,73.12) v1(142.6,47.82) v1(142.6,2.02) v1(142.71,7.15) v1(142.76,128.78) v1(142.8,104.22) v1(142.85,102.77) v1(142.81,82.53) v1(142.8,43.43) v1(142.89,110.23) v1(142.91,108.48) v1(142.9,97.64) v1(142.95,92.52) v1(142.89,80.18) v1(142.95,78.12) v1(142.89,26.55) v1(142.9,13.41) v1(143.05,121.29) v1(143.05,91.02) v1(143.02,51.15) v1(142.97,50.22) v1(142.96,10.34) v1(143.05,84.95) v1(143.25,90.62) v1(143.22,84.22) v1(143.21,5.44) v1(143.27,114.94) v1(143.27,103.54) v1(143.33,101.99) v1(143.28,59.09) v1(143.43,123.91) v1(143.46,119.38) v1(143.49,47.15) v1(143.47,45.59) v1(143.6,71.17) v1(143.6,46.44) v1(143.66,126.07) v1(143.67,93.24) v1(143.69,92.88) v1(143.69,92.51) v1(143.69,92.16) v1(143.68,91.81) v1(143.69,91.49) v1(143.69,91.18) v1(143.68,90.86) v1(143.75,74.17) v1(143.66,71.82) v1(143.72,41.15) v1(143.69,39.47) v1(143.69,38.39) v1(143.72,27.84) v1(143.84,122.78) v1(143.85,106.92) v1(143.82,93.45) v1(143.78,90.58) v1(143.85,6.3) v1(143.82,3.2) v1(143.86,107.64) v1(143.95,106.07) v1(143.9,105.12) v1(143.9,84.97) v1(143.95,33.77) v1(144.03,127.58) v1(144.01,104.52) v1(144.14,95.91) v1(144.06,90.58) v1(144.07,40.78) v1(144.16,93.46) v1(144.18,82.53) v1(144.2,12.15) v1(144.24,9.26) v1(144.19,5.59) v1(144.26,96.83) v1(144.27,71.07) v1(144.36,91.33) v1(144.37,90.59) v1(144.42,58.4) v1(144.53,93.45) v1(144.48,73.06) v1(144.54,59.93) v1(144.52,30.59) v1(144.57,125.03) v1(144.65,84.97) v1(144.65,84.17) v1(144.64,67.46) v1(144.7,128.8) v1(144.71,103.54) v1(144.7,90.58) v1(144.7,79.27) v1(144.65,75.19) v1(144.69,62.11) v1(144.73,47.4) v1(144.79,105.3) v1(144.85,50.22) v1(144.8,2.02) v1(144.95,106.82) v1(144.9,93.45) v1(144.88,74.43) v1(144.87,72.28) v1(144.86,39.84) v1(144.87,26.53) v1(144.99,121.32) v1(145.02,117.2) v1(145.02,114.55) v1(145.02,90.59) v1(145.11,44.92) v1(145.18,123.9) v1(145.16,114.94) v1(145.24,104.36) v1(145.17,96.83) v1(145.2,87.47) v1(145.25,60.5) v1(145.19,49.54) v1(145.26,93.44) v1(145.33,90.59) v1(145.3,77) v1(145.42,126.06) v1(145.35,105.73) v1(145.41,95.85) v1(145.4,84.97) v1(145.37,45.63) v1(145.4,30.32) v1(145.38,4.41) v1(145.48,92.74) v1(145.5,73.8) v1(145.47,59.16) v1(145.54,8) v1(145.62,128.76) v1(145.64,128.14) v1(145.65,127.57) v1(145.64,102.59) v1(145.64,93.44) v1(145.65,90.6) v1(145.58,82.52) v1(145.59,68.68) v1(145.63,61.1) v1(145.61,57.64) v1(145.58,40.8) v1(145.55,39.23) v1(145.65,33.67) v1(145.6,30.77) v1(145.69,66.09) v1(145.76,118.38) v1(145.83,113.74) v1(145.79,107.63) v1(145.84,103.55) v1(145.75,87.45) v1(145.76,63.26) v1(145.8,10.55) v1(145.94,39.96) v1(145.92,27.84) v1(145.97,93.44) v1(145.98,90.61) v1(146.02,3.2) v1(146.07,56.68) v1(146.11,43.92) v1(146.22,74.37) v1(146.21,38.39) v1(146.27,127.58) v1(146.33,125.02) v1(146.28,105.82) v1(146.32,95.73) v1(146.35,85.15) v1(146.26,59.9) v1(146.33,58.37) v1(146.29,45.68) v1(146.32,25.16) v1(146.36,111.46) v1(146.45,108.42) v1(146.39,5.59) v1(146.51,93.24) v1(146.52,90.84) v1(146.5,88.05) v1(146.51,51.11) v1(146.57,128.78) v1(146.6,128.15) v1(146.6,127.58) v1(146.55,52.79) v1(146.75,108.77) v1(146.73,107.17) v1(146.69,69.81) v1(146.68,67.43) v1(146.73,62.14) v1(146.84,119.45) v1(146.77,117.19) v1(146.85,115.59) v1(146.77,114.54) v1(146.85,108.42) v1(146.85,77.01) v1(146.82,64.63) v1(146.8,50.22) v1(146.79,2.14) v1(146.94,123.08) v1(146.9,73.5) v1(147.01,74.28) v1(147.01,42.97) v1(147.09,104.7) v1(147.09,96.45) v1(147.07,92.96) v1(147.11,90.53) v1(147.05,87.8) v1(147.1,60.5) v1(147.08,44.89) v1(147.1,43.91) v1(147.07,26.53) v1(147.1,9.38) v1(147.2,108.57) v1(147.15,91.07) v1(147.2,85.15) v1(147.17,59.16) v1(147.3,106.37) v1(147.26,57.64) v1(147.35,128.77) v1(147.42,92.96) v1(147.45,78.97) v1(147.55,91.08) v1(147.54,88.87) v1(147.5,84.82) v1(147.48,30.53) v1(147.63,68.66) v1(147.6,63.3) v1(147.64,40.17) v1(147.55,7.95) v1(147.58,4.41) v1(147.68,115.8) v1(147.73,66.06) v1(147.67,61.13) v1(147.67,23.94) v1(147.73,22.47) v1(147.8,118.37) v1(147.79,113.75) v1(147.78,103.54) v1(147.75,102.72) v1(147.77,44.31) v1(147.89,73.74) v1(147.92,42.12) v1(147.88,34.4) v1(148.05,121.28) v1(148.03,88.88) v1(148.02,59.93) v1(148.03,49.54) v1(148.1,107.62) v1(148.15,92.95) v1(148.05,91.1) v1(148.05,90.25) v1(148.07,72.28) v1(148.09,58.4) v1(148.12,27.84) v1(148.2,5.62) v1(148.22,3.2) v1(148.4,87.75) v1(148.38,45.29) v1(148.43,43.74) v1(148.42,30.53) v1(148.47,127.58) v1(148.5,86.25) v1(148.54,42.57) v1(148.52,25.16) v1(148.55,125.8) v1(148.6,119.44) v1(148.58,117.14) v1(148.62,114.59) v1(148.58,96.14) v1(148.6,69.83) v1(148.59,67.46) v1(148.64,62.11) v1(148.6,50.22) v1(148.62,41.38) v1(148.7,123.07) v1(148.73,105.83) v1(148.73,64.65) v1(148.7,35.28) v1(148.7,33.95) v1(148.92,59.15) v1(148.86,57.64) v1(149,60.5) v1(148.99,2.14) v1(149.18,42.99) v1(149.32,52.69) v1(149.32,34.34) v1(149.27,26.53) v1(149.36,128.78) v1(149.44,115.79) v1(149.45,111.17) v1(149.39,106.79) v1(149.36,7.98) v1(149.51,113.61) v1(149.49,108.88) v1(149.54,85.37) v1(149.54,68.68) v1(149.56,118.36) v1(149.64,83.56) v1(149.64,74.27) v1(149.64,66.09) v1(149.58,61.1) v1(149.58,59.93) v1(149.57,45.3) v1(149.57,30.6) v1(149.67,76.61) v1(149.71,63.26) v1(149.65,58.4) v1(149.72,41.41) v1(149.71,40.36) v1(149.77,126.43) v1(149.85,50.87) v1(149.78,4.41) v1(149.93,105.83) v1(149.88,51.91) v1(149.88,51.64) v1(149.88,51.37) v1(149.88,51.1) v1(149.87,23.94) v1(149.93,22.47) v1(149.95,124.15) v1(150.03,77.36) v1(150.08,73.58) v1(150.12,34.34) v1(150.15,95.55) v1(150.32,27.84) v1(150.38,114.58) v1(150.37,81.95) v1(150.41,59.15) v1(150.4,54.37) v1(150.35,3.11) v1(150.5,74.35) v1(150.47,72.29) v1(150.54,57.65) v1(150.55,50.22) v1(150.49,43.57) v1(150.5,38.39) v1(150.53,35.18) v1(150.61,69.86) v1(150.6,67.48) v1(150.59,52.4) v1(150.65,39.41) v1(150.67,127.58) v1(150.67,115.48) v1(150.67,76.61) v1(150.74,64.68) v1(150.65,62.14) v1(150.7,60.5) v1(150.66,45.3) v1(150.72,25.16) v1(150.68,24.15) v1(150.83,40.34) v1(150.84,37.09) v1(150.84,36.57) v1(150.83,30.6) v1(150.91,96.5) v1(150.95,84.7) v1(150.9,54.37) v1(150.93,49.54) v1(150.92,44.27) v1(150.89,34.47) v1(150.88,33.44) v1(150.88,31.94) v1(150.87,31.3) v1(150.98,95.24) v1(150.98,41.34) v1(151.24,114.91) v1(151.16,113.75) v1(151.18,94.59) v1(151.21,93.99) v1(151.22,77.33) v1(151.17,59.9) v1(151.2,21.2) v1(151.22,7.91) v1(151.19,2.14) v1(151.28,58.4) v1(151.31,22.94) v1(151.38,116.21) v1(151.38,105.97) v1(151.5,97.2) v1(151.53,38.49) v1(151.47,26.53) v1(151.47,4.44) v1(151.56,128.78) v1(151.62,93.54) v1(151.65,76.61) v1(151.56,68.71) v1(151.59,61.12) v1(151.67,108.42) v1(151.68,107.5) v1(151.66,66.11) v1(151.72,63.29) v1(151.74,44.27) v1(151.71,39.45) v1(151.66,34.85) v1(151.8,109.27) v1(151.77,86.17) v1(151.82,81.74) v1(151.87,93.54) v1(152.04,126.45) v1(152.03,99.04) v1(151.96,59.16) v1(152.02,57.65) v1(151.98,51.3) v1(152.05,50.22) v1(152.08,113.54) v1(152.23,122.91) v1(152.2,85.99) v1(152.27,112.96) v1(152.3,54.37) v1(152.32,42.26) v1(152.42,123.75) v1(152.45,112.45) v1(152.43,88.78) v1(152.43,88.36) v1(152.5,111.3) v1(152.64,125.53) v1(152.63,107.59) v1(152.58,102.77) v1(152.59,81.46) v1(152.59,76.6) v1(152.56,58.4) v1(152.55,3.11) v1(152.67,103.91) v1(152.7,69.84) v1(152.69,67.47) v1(152.74,62.12) v1(152.68,59.93) v1(152.71,52.92) v1(152.7,52.65) v1(152.71,52.36) v1(152.7,52.02) v1(152.7,51.68) v1(152.7,51.36) v1(152.72,45.3) v1(152.7,44.2) v1(152.71,38.44) v1(152.76,113.41) v1(152.79,91.7) v1(152.85,82.05) v1(152.83,64.67) v1(152.87,127.58) v1(152.89,72.29) v1(152.92,25.16) v1(153,106.47) v1(152.97,77.77) v1(152.96,43.49) v1(153.03,7.93) v1(153.03,1.99) v1(153.09,116.18) v1(153.08,99) v1(153.14,87.83) v1(153.05,60.5) v1(153.22,128.79) v1(153.24,128.16) v1(153.25,127.59) v1(153.16,91.16) v1(153.22,89.71) v1(153.19,88.73) v1(153.25,54.37) v1(153.18,41.34) v1(153.32,108.38) v1(153.34,42.56) v1(153.44,115.49) v1(153.41,111.17) v1(153.38,76.59) v1(153.43,57.65) v1(153.54,113.6) v1(153.54,77.32) v1(153.47,59.17) v1(153.57,112.69) v1(153.56,97.44) v1(153.62,91.69) v1(153.65,68.7) v1(153.75,111.17) v1(153.7,107.62) v1(153.72,85.86) v1(153.68,61.11) v1(153.67,4.44) v1(153.76,128.78) v1(153.85,105.02) v1(153.85,65.95) v1(153.81,63.27) v1(153.82,49.54) v1(153.9,112.51) v1(153.91,103.56) v1(153.93,97.37) v1(153.95,50.22) v1(154.02,122.97) v1(153.96,106.8) v1(154,77.77) v1(153.97,73.53) v1(154.09,128.79) v1(154.12,128.16) v1(154.12,127.59) v1(154.13,89.67) v1(154.09,43.49) v1(154.2,113.02) v1(154.19,91.17) v1(154.21,88.74) v1(154.16,87.84) v1(154.24,76.6) v1(154.15,58.4) v1(154.22,38.17) v1(154.32,114.52) v1(154.26,111.17) v1(154.3,85.87) v1(154.25,59.95) v1(154.39,90.06) v1(154.42,73.24) v1(154.49,97.37) v1(154.47,56.68) v1(154.62,123.75) v1(154.56,112.51) v1(154.62,99.01) v1(154.56,94.89) v1(154.63,88.27) v1(154.61,77.32) v1(154.73,113) v1(154.71,88.75) v1(154.71,69.87) v1(154.74,62.15) v1(154.71,38.27) v1(154.84,125.53) v1(154.85,95.47) v1(154.83,64.69) v1(154.8,57.67) v1(154.83,44.13) v1(154.84,43.05) v1(154.82,7.94) v1(154.75,3.11) v1(154.86,113.75) v1(154.86,97.06) v1(154.94,91.76) v1(154.88,74.22) v1(154.92,45.3) v1(154.98,116.32) v1(154.98,115.39) v1(155.01,107.65) v1(155.01,59.12) v1(155.01,35.76) v1(155.03,34.67) v1(155.04,33.28) v1(155.01,30.55) v1(155.08,113.4) v1(155.06,77.77) v1(155.13,76.62) v1(155.05,67.15) v1(155.07,50.89) v1(155.07,32.48) v1(155.2,91.19) v1(155.23,89.68) v1(155.22,88.77) v1(155.17,87.86) v1(155.17,44.18) v1(155.23,1.99) v1(155.33,111.78) v1(155.3,102.81) v1(155.34,83.67) v1(155.29,36.88) v1(155.42,126.61) v1(155.44,112.21) v1(155.4,68.85) v1(155.38,41.34) v1(155.4,31.36) v1(155.54,42.56) v1(155.6,90.35) v1(155.58,43.02) v1(155.73,77.29) v1(155.66,74.34) v1(155.7,73.22) v1(155.73,58.41) v1(155.68,35.81) v1(155.81,99.02) v1(155.78,97.09) v1(155.75,66.13) v1(155.81,33.56) v1(155.94,108.43) v1(155.9,61.05) v1(155.93,59.95) v1(155.88,43.49) v1(155.9,30.56) v1(155.87,4.44) v1(155.96,128.78) v1(155.97,122.93) v1(156.03,90.36) v1(155.97,63.27) v1(156.06,118.97) v1(156.06,113.81) v1(156.09,111.8) v1(156.15,106.88) v1(156.15,77.77) v1(156.06,76.6) v1(156.2,120.91) v1(156.2,98.45) v1(156.15,96.3) v1(156.2,91.19) v1(156.15,90.76) v1(156.22,88.77) v1(156.17,87.86) v1(156.2,82.45) v1(156.35,98) v1(156.35,96.89) v1(156.33,91.68) v1(156.31,89.7) v1(156.29,81.57) v1(156.32,32.39) v1(156.35,114.65) v1(156.35,113.69) v1(156.44,112.95) v1(156.38,103.55) v1(156.36,94.88) v1(156.45,73.15) v1(156.41,44.17) v1(156.36,35.49) v1(156.51,57.79) v1(156.52,49.54) v1(156.6,104.48) v1(156.6,95.15) v1(156.6,91.32) v1(156.55,89.3) v1(156.56,69.88) v1(156.55,67.51) v1(156.56,60.61) v1(156.61,59.15) v1(156.62,53.67) v1(156.61,36.42) v1(156.57,33.33) v1(156.63,7.96) v1(156.66,111.37) v1(156.68,110.39) v1(156.69,64.71) v1(156.73,3.13) v1(156.82,123.75) v1(156.78,115.36) v1(156.77,62.56) v1(156.83,31.41) v1(156.93,121.94) v1(156.94,89.81) v1(156.91,88.93) v1(156.87,77.31) v1(156.9,74.32) v1(157.01,126.68) v1(157.04,125.53) v1(157.05,97.65) v1(157.02,45.3) v1(157.1,76.6) v1(157.16,119.88) v1(157.23,98.22) v1(157.21,30.53) v1(157.27,77.77) v1(157.26,36.71) v1(157.39,58.2) v1(157.43,1.99) v1(157.47,112) v1(157.46,107.65) v1(157.51,68.73) v1(157.52,60.06) v1(157.61,66.14) v1(157.55,35.43) v1(157.66,112.77) v1(157.65,82.5) v1(157.7,56.78) v1(157.74,53.66) v1(157.74,42.56) v1(157.75,116.32) v1(157.83,4.3) v1(157.91,122.95) v1(157.88,113.81) v1(157.87,97.11) v1(157.88,72.73) v1(157.9,59.12) v1(157.94,44.21) v1(158.05,104.52) v1(157.95,97.68) v1(158.02,93.52) v1(158.04,77.25) v1(157.97,76.6) v1(158.13,120.94) v1(158.16,128.78) v1(158.22,102.77) v1(158.25,96.4) v1(158.22,80.84) v1(158.21,7.94) v1(158.32,106.88) v1(158.27,93.52) v1(158.38,94.58) v1(158.42,73.65) v1(158.45,81.56) v1(158.51,57.88) v1(158.51,35.68) v1(158.63,108.38) v1(158.66,128.8) v1(158.69,128.17) v1(158.69,127.6) v1(158.7,115.36) v1(158.73,98.22) v1(158.72,96.62) v1(158.68,53.67) v1(158.82,113.75) v1(158.79,96.25) v1(158.75,82.45) v1(158.87,121.97) v1(158.87,117.65) v1(158.86,95.11) v1(158.87,67.09) v1(158.95,65.5) v1(158.87,59.08) v1(158.93,3.13) v1(159.02,123.75) v1(159.12,128.8) v1(159.14,128.17) v1(159.15,127.6) v1(159.06,93.3) v1(159.06,92.91) v1(159.09,92.08) v1(159.09,91.75) v1(159.1,77.5) v1(159.24,125.53) v1(159.17,114.65) v1(159.22,45.3) v1(159.34,96.25) v1(159.3,84.2) v1(159.33,2.08) v1(159.38,98) v1(159.38,49.36) v1(159.4,43.72) v1(159.5,96.94) v1(159.51,83.26) v1(159.54,82.46) v1(159.56,84.08) v1(159.58,80.82) v1(159.68,118.49) v1(159.7,111.05) v1(159.65,109.05) v1(159.68,57.43) v1(159.72,53.64) v1(159.67,51.15) v1(159.8,122.95) v1(159.75,96.15) v1(159.78,94.3) v1(159.87,48.64) v1(160.02,120.94) v1(160.04,112.8) v1(160,59.9) v1(160.02,7.96) v1(160.03,4.3) v1(160.11,113.81) v1(160.18,116.32) v1(160.22,107.64) v1(160.17,98.22) v1(160.15,93.55) v1(160.23,85.93) v1(160.25,83.4) v1(160.17,81.63) v1(160.35,103.59) v1(160.3,72.19) v1(160.36,128.78) v1(160.35,111.85) v1(160.44,96.31) v1(160.4,94.96) v1(160.4,78) v1(160.37,76.37) v1(160.36,69.7) v1(160.46,108.47) v1(160.5,86.25) v1(160.5,80.6) v1(160.5,77.6) v1(160.47,70.41) v1(160.45,58.1) v1(160.52,44.26) v1(160.64,104.46) v1(160.62,74.86) v1(160.62,53.64) v1(160.75,117.97) v1(160.68,49.54) v1(160.71,35.68) v1(160.75,121.97) v1(160.77,85.61) v1(160.77,84.95) v1(160.85,69.28) v1(160.84,65.47) v1(160.81,63.84) v1(160.8,59.8) v1(160.76,36.65) v1(160.87,106.89) v1(160.87,94.21) v1(160.9,82.75) v1(161.01,97.25) v1(160.98,77.16) v1(160.95,67.94) v1(161,50.22) v1(161.05,125.15) v1(161.1,115.36) v1(161.15,114.65) v1(161.12,95.5) v1(161.05,5.56) v1(161.13,3.13) v1(161.25,111.05) v1(161.21,102.74) v1(161.28,58.88) v1(161.27,57.43) v1(161.4,125.15) v1(161.37,113.69) v1(161.44,105.89) v1(161.41,80.8) v1(161.4,77.6) v1(161.5,123.78) v1(161.53,81.86) v1(161.5,78) v1(161.53,2.08) v1(161.55,122.94) v1(161.56,116.4) v1(161.62,108.91) v1(161.62,94.48) v1(161.55,45.31) v1(161.71,84.13) v1(161.75,43.49) v1(161.7,41.8) v1(161.77,120.92) v1(161.8,92.7) v1(161.85,91.75) v1(161.8,83.15) v1(161.79,67.86) v1(161.79,39.82) v1(161.86,37.86) v1(161.99,93.46) v1(162.01,86.3) v1(162.04,76.4) v1(161.99,74.77) v1(162.01,51.13) v1(162.08,103.82) v1(162.1,77.3) v1(162.08,58.07) v1(162.07,48.64) v1(162.17,94.19) v1(162.2,91.1) v1(162.25,90.3) v1(162.18,73.3) v1(162.21,69.23) v1(162.17,65.03) v1(162.15,60.3) v1(162.23,4.3) v1(162.29,107.65) v1(162.3,89.6) v1(162.28,66.97) v1(162.37,98.22) v1(162.36,96.16) v1(162.45,92.7) v1(162.44,84.96) v1(162.55,113.77) v1(162.52,112.68) v1(162.5,91.7) v1(162.48,88.56) v1(162.51,49.46) v1(162.56,128.78) v1(162.55,75) v1(162.72,60.18) v1(162.85,111) v1(162.77,109.9) v1(162.85,89.26) v1(162.78,57.45) v1(162.84,34.61) v1(162.95,115.37) v1(162.95,111.83) v1(162.87,93.43) v1(162.89,70.42) v1(162.94,59.86) v1(162.85,58.9) v1(162.91,52.87) v1(162.92,40.85) v1(162.91,38.83) v1(162.9,32.41) v1(162.91,30.43) v1(163,116.27) v1(162.96,68.49) v1(163.02,54.55) v1(162.99,44.27) v1(162.96,36.65) v1(163.05,83.15) v1(163.24,109.2) v1(163.16,103.05) v1(163.21,97.25) v1(163.19,95.06) v1(163.17,91.11) v1(163.19,62.87) v1(163.27,117.49) v1(163.27,114.65) v1(163.3,108.4) v1(163.26,81.13) v1(163.3,76.97) v1(163.25,5.56) v1(163.37,94.19) v1(163.44,85.64) v1(163.39,81.88) v1(163.5,92.7) v1(163.53,87.93) v1(163.51,84.1) v1(163.54,75.43) v1(163.46,69.7) v1(163.55,123.7) v1(163.73,106.93) v1(163.68,90.33) v1(163.7,86.25) v1(163.74,66.83) v1(163.7,51.14) v1(163.72,49.28) v1(163.73,2.08) v1(163.78,103.78) v1(163.75,91.98) v1(163.85,87.15) v1(163.75,70.5) v1(163.79,53.71) v1(163.75,45.31) v1(163.93,93.39) v1(163.91,89.27) v1(163.9,74.59) v1(163.89,73.7) v1(163.92,72.11) v1(163.92,67.9) v1(163.92,63.65) v1(163.88,35.7) v1(164,109.07) v1(164.05,59.45) v1(163.97,57.54) v1(164.02,43.49) v1(163.99,39.82) v1(163.96,33.56) v1(163.97,31.35) v1(164.08,98.42) v1(164.06,37.86) v1(164.34,96.24) v1(164.3,82.3) v1(164.32,65.11) v1(164.35,91.05) v1(164.36,84.95) v1(164.43,75.42) v1(164.48,111.84) v1(164.48,72.92) v1(164.5,55.4) v1(164.47,54.55) v1(164.52,46.17) v1(164.52,44.18) v1(164.58,107.64) v1(164.61,94.18) v1(164.55,88.2) v1(164.7,111.05) v1(164.74,85.78) v1(164.68,77.85) v1(164.72,52.88) v1(164.76,128.78) v1(164.76,77.17) v1(164.94,76.13) v1(164.92,68.5) v1(164.92,64.09) v1(164.99,112.82) v1(164.98,97.33) v1(165,86.25) v1(164.99,72.25) v1(164.97,62.47) v1(164.99,61.72) v1(165.04,34.61) v1(165.1,92.7) v1(165.07,89.29) v1(165.1,80.92) v1(165.11,74.6) v1(165.05,70.45) v1(165.06,59.4) v1(165.14,57.79) v1(165.13,43.75) v1(165.11,38.83) v1(165.1,32.41) v1(165.11,30.43) v1(165.25,115.37) v1(165.17,103.02) v1(165.25,95.05) v1(165.21,93.4) v1(165.25,87.1) v1(165.17,69.72) v1(165.23,66.86) v1(165.2,55.32) v1(165.23,53.72) v1(165.21,50.86) v1(165.24,49.51) v1(165.2,48.14) v1(165.16,36.65) v1(165.32,123.71) v1(165.26,90.34) v1(165.26,78) v1(165.27,73.73) v1(165.33,42.32) v1(165.39,116.32) v1(165.37,84.16) v1(165.5,43.3) v1(165.45,5.56) v1(165.6,113.7) v1(165.63,106.93) v1(165.55,88.25) v1(165.75,108.43) v1(165.73,91.12) v1(165.76,116.99) v1(165.8,65.1) v1(165.86,94.16) v1(165.89,70.47) v1(165.9,56.87) v1(165.93,2.07) v1(166.04,123.71) v1(165.98,96.28) v1(166.03,86.37) v1(165.99,85) v1(165.98,44.67) v1(166.06,115.74) v1(166.15,50.22) v1(166.08,35.7) v1(166.24,112.06) v1(166.24,83.24) v1(166.19,39.82) v1(166.16,33.56) v1(166.17,31.35) v1(166.28,98.42) v1(166.3,81.71) v1(166.3,74.7) v1(166.35,52.77) v1(166.26,46.87) v1(166.3,43.35) v1(166.26,37.86) v1(166.43,115.3) v1(166.37,85.71) v1(166.37,72.96) v1(166.41,69.57) v1(166.38,64.22) v1(166.43,61.73) v1(166.45,55.32) v1(166.44,54.67) v1(166.4,41.23) v1(166.53,93.42) v1(166.51,71.52) v1(166.5,67.95) v1(166.53,62.47) v1(166.53,59.71) v1(166.5,58.72) v1(166.48,42.31) v1(166.58,91.94) v1(166.59,88.22) v1(166.56,72.11) v1(166.57,66.87) v1(166.58,51.11) v1(166.68,119.34) v1(166.69,118.33) v1(166.72,117.24) v1(166.73,109.27) v1(166.74,103.81) v1(166.68,94.42) v1(166.7,90.82) v1(166.69,76.1) v1(166.81,90.2) v1(166.82,80.96) v1(166.81,45.38) v1(166.91,115.31) v1(166.96,128.78) v1(166.99,107.63) v1(167,34.61) v1(167.08,115.85) v1(167.13,93.29) v1(167.1,87.19) v1(167.08,84.59) v1(167.06,70.49) v1(167.14,42.1) v1(167.1,36.67) v1(167.15,120.33) v1(167.16,115.32) v1(167.15,114.45) v1(167.15,111.95) v1(167.18,97.33) v1(167.21,75.59) v1(167.18,43.93) v1(167.3,115.54) v1(167.26,111.02) v1(167.31,103.02) v1(167.3,89.26) v1(167.32,77.61) v1(167.33,73.8) v1(167.32,72.86) v1(167.33,64.17) v1(167.33,61.3) v1(167.31,57.78) v1(167.33,55.71) v1(167.31,54.42) v1(167.26,49.48) v1(167.26,38.86) v1(167.36,65.12) v1(167.35,59.49) v1(167.4,50.22) v1(167.4,48.14) v1(167.44,41.29) v1(167.4,5.59) v1(167.5,106.73) v1(167.5,95.02) v1(167.54,94.67) v1(167.46,69.7) v1(167.61,93.3) v1(167.61,92.57) v1(167.64,83.89) v1(167.62,81.71) v1(167.57,76.32) v1(167.55,71.04) v1(167.57,68.07) v1(167.67,125.26) v1(167.74,104.64) v1(167.68,91.8) v1(167.68,75.02) v1(167.82,118.8) v1(167.83,117.27) v1(167.82,66.81) v1(167.88,77.22) v1(167.88,68.73) v1(167.87,53.03) v1(167.86,45.72) v1(167.88,44.33) v1(167.91,43.19) v1(167.99,87.95) v1(168.04,42.43) v1(168.01,40.34) v1(168.14,92.54) v1(168.11,74.46) v1(168.11,62.24) v1(168.06,60.47) v1(168.15,58.77) v1(168.11,56.26) v1(168.11,41.7) v1(168.15,37.87) v1(168.05,19.19) v1(168.13,2.07) v1(168.2,114.59) v1(168.17,108.42) v1(168.15,103.82) v1(168.15,93.45) v1(168.25,89.85) v1(168.22,71.78) v1(168.24,71.07) v1(168.22,69.48) v1(168.16,65.22) v1(168.15,55.41) v1(168.35,117.1) v1(168.31,115.36) v1(168.29,96.19) v1(168.33,91.79) v1(168.33,85.73) v1(168.28,62.84) v1(168.25,48.72) v1(168.36,88.26) v1(168.37,86.37) v1(168.43,77.59) v1(168.39,46.84) v1(168.45,128.83) v1(168.47,128.2) v1(168.49,110.05) v1(168.5,80.92) v1(168.51,73.58) v1(168.52,73.17) v1(168.52,72.74) v1(168.64,83.23) v1(168.57,75.89) v1(168.58,75.47) v1(168.58,75.05) v1(168.56,54.68) v1(168.57,54.27) v1(168.57,53.84) v1(168.62,52.18) v1(168.63,51.76) v1(168.63,51.34) v1(168.74,120.36) v1(168.68,106.92) v1(168.72,98.58) v1(168.72,98.16) v1(168.72,97.74) v1(168.83,123.71) v1(168.76,111.77) v1(168.8,96.45) v1(168.81,96.03) v1(168.81,95.61) v1(168.78,76.13) v1(168.79,50.6) v1(168.84,41.38) v1(168.81,39.71) v1(168.9,111.23) v1(168.85,87.47) v1(168.89,63.48) v1(168.89,42.64) v1(168.99,119.03) v1(169,118.61) v1(169,118.19) v1(169.04,73.58) v1(169.03,73.17) v1(169.03,72.75) v1(168.98,69.68) v1(169.01,68.72) v1(169.01,64.34) v1(168.99,32.82) v1(169.04,31.84) v1(169.03,31.42) v1(169.03,31) v1(169.05,91.85) v1(169.14,89.1) v1(169.1,75.89) v1(169.1,75.48) v1(169.1,75.05) v1(169.09,54.68) v1(169.08,54.27) v1(169.08,53.85) v1(169.15,52.18) v1(169.14,51.77) v1(169.14,51.34) v1(169.07,47.97) v1(169.11,38.65) v1(169.07,36.69) v1(169.07,20.67) v1(169.16,128.78) v1(169.18,104.69) v1(169.24,98.58) v1(169.24,98.17) v1(169.24,97.74) v1(169.18,84.76) v1(169.22,74.28) v1(169.19,65.65) v1(169.15,61.46) v1(169.21,48.85) v1(169.22,45.07) v1(169.22,41.7) v1(169.24,40.75) v1(169.28,113.51) v1(169.26,102.56) v1(169.33,96.45) v1(169.32,96.04) v1(169.32,95.61) v1(169.33,59.45) v1(169.36,106.13) v1(169.44,81.7) v1(169.39,41.38) v1(169.52,119.03) v1(169.52,118.62) v1(169.52,118.2) v1(169.52,92.55) v1(169.49,88.36) v1(169.5,86.94) v1(169.48,42.82) v1(169.52,34.82) v1(169.53,33.51) v1(169.56,110.19) v1(169.6,69.45) v1(169.59,68.63) v1(169.57,66.15) v1(169.57,46.76) v1(169.65,22.62) v1(169.75,123.27) v1(169.74,111.88) v1(169.72,109.35) v1(169.68,89.46) v1(169.66,63.53) v1(169.69,24.37) v1(169.8,115.2) v1(169.84,114.3) v1(169.79,113.32) v1(169.83,90.9) v1(169.81,71.74) v1(169.78,49.62) v1(169.76,39.94) v1(169.86,89.97) v1(169.88,86.55) v1(169.89,75.84) v1(169.86,71.12) v1(169.99,117.14) v1(169.99,108.43) v1(169.96,106.93) v1(170.03,92.89) v1(170.01,88.11) v1(169.98,48.15) v1(170.01,38.07) v1(170.1,125.27) v1(170.1,104.13) v1(170.1,73.18) v1(170.07,65.6) v1(170.16,112.29) v1(170.15,110.62) v1(170.23,83.3) v1(170.2,74.21) v1(170.21,64.87) v1(170.2,60.66) v1(170.24,5.59) v1(170.3,51.09) v1(170.32,48.53) v1(170.3,37.09) v1(170.33,2.07) v1(170.43,86.66) v1(170.36,76.46) v1(170.38,75.41) v1(170.43,72.37) v1(170.41,62.36) v1(170.45,54.92) v1(170.45,54.27) v1(170.38,53.19) v1(170.37,52.21) v1(170.36,42.85) v1(170.45,41.6) v1(170.54,120.36) v1(170.45,98.5) v1(170.45,97.29) v1(170.46,95.89) v1(170.48,92.89) v1(170.45,89.88) v1(170.47,88.1) v1(170.46,66.89) v1(170.52,49.97) v1(170.53,47.24) v1(170.48,43.92) v1(170.46,40.86) v1(170.59,117) v1(170.59,109.1) v1(170.6,105.69) v1(170.61,81.7) v1(170.63,63.35) v1(170.64,44.31) v1(170.75,123.71) v1(170.67,110.44) v1(170.67,107.61) v1(170.7,89.46) v1(170.7,71.39) v1(170.74,68.12) v1(170.76,112.17) v1(170.89,106.99) v1(170.9,89.84) v1(170.9,68.59) v1(170.93,66.92) v1(170.85,66.14) v1(170.94,60.12) v1(170.86,50.31) v1(170.9,45.75) v1(171,114.3) v1(171.05,109.07) v1(170.96,95.08) v1(170.98,69.55) v1(171.03,42.8) v1(170.99,39.62) v1(171.1,86.69) v1(171.11,64.63) v1(171.09,63.07) v1(171.11,48.5) v1(171.14,38.17) v1(171.2,92.95) v1(171.17,88.09) v1(171.19,85.07) v1(171.19,83.65) v1(171.19,82.06) v1(171.18,55.7) v1(171.24,47.17) v1(171.25,117.28) v1(171.26,113.56) v1(171.35,110.83) v1(171.34,108.66) v1(171.31,71.25) v1(171.36,128.78) v1(171.44,115.6) v1(171.4,91.05) v1(171.39,68.12) v1(171.39,59.48) v1(171.36,44.33) v1(171.41,41.21) v1(171.45,112.17) v1(171.46,107.28) v1(171.52,105.76) v1(171.51,104.16) v1(171.47,90.07) v1(171.63,102.69) v1(171.62,86.61) v1(171.68,123.27) v1(171.67,77.05) v1(171.74,33.62) v1(171.8,50.24) v1(171.83,42.8) v1(171.79,39.62) v1(171.8,5.59) v1(171.94,117.19) v1(171.89,94.34) v1(171.9,89.48) v1(171.88,83.65) v1(171.93,71.8) v1(171.87,60.13) v1(171.93,58.6) v1(171.9,47.48) v1(171.91,45.39) v1(171.99,92.95) v1(171.95,88.06) v1(171.97,85.08) v1(171.98,82.06) v1(171.98,68.59) v1(171.98,56.3) v1(172.21,125.27) v1(172.23,113.55) v1(172.2,112.2) v1(172.24,107.29) v1(172.19,104.15) v1(172.24,86.7) v1(172.15,38.2) v1(172.27,115.62) v1(172.3,105.76) v1(172.43,110.83) v1(172.4,39.36) v1(172.52,55.72) v1(172.47,46) v1(172.54,39.84) v1(172.58,108.69) v1(172.64,94.11) v1(172.64,83.54) v1(172.55,66.99) v1(172.64,65.96) v1(172.62,63.49) v1(172.57,50.34) v1(172.56,49.65) v1(172.64,2.07) v1(172.68,123.74) v1(172.67,102.69) v1(172.68,92.66) v1(172.71,91.64) v1(172.71,86.35) v1(172.73,71.17) v1(172.71,48.76) v1(172.68,40.84) v1(172.73,4.51) v1(172.81,93.3) v1(172.8,88.19) v1(172.84,70.32) v1(172.8,58.21) v1(172.75,42.59) v1(172.8,10) v1(172.86,112.09) v1(172.88,104.16) v1(172.88,82.08) v1(172.85,67.97) v1(172.88,43.99) v1(172.96,115.61) v1(172.97,109.34) v1(173.05,107.36) v1(173.1,77.61) v1(173.06,59.38) v1(173.1,37.45) v1(173.21,105.97) v1(173.23,92.78) v1(173.25,89.21) v1(173.23,86.98) v1(173.22,77.04) v1(173.23,69.52) v1(173.21,62.67) v1(173.22,42.97) v1(173.29,112.56) v1(173.28,109.04) v1(173.34,68.55) v1(173.25,46.92) v1(173.31,41.42) v1(173.3,38.48) v1(173.39,94.38) v1(173.42,80.97) v1(173.43,71.73) v1(173.44,67.21) v1(173.4,60.35) v1(173.51,111.98) v1(173.53,107.91) v1(173.48,85.08) v1(173.45,65.93) v1(173.5,64.35) v1(173.51,39.98) v1(173.56,128.78) v1(173.62,123.28) v1(173.6,46.03) v1(173.74,117.21) v1(173.71,115.51) v1(173.7,104.84) v1(173.7,93.71) v1(173.66,50.32) v1(173.73,10.07) v1(173.65,3.42) v1(173.81,83.98) v1(173.78,49.12) v1(173.82,5.63) v1(173.85,55.72) v1(173.93,37.98) v1(173.94,33.62) v1(173.99,114.28) v1(173.96,87.71) v1(174.01,70.24) v1(174.15,109.78) v1(174.09,102.97) v1(174.13,92.28) v1(174.12,88.46) v1(174.07,61.84) v1(174.13,61.21) v1(174.12,44.34) v1(174.15,107.27) v1(174.23,85.78) v1(174.2,82.68) v1(174.2,42) v1(174.26,111.49) v1(174.31,108.62) v1(174.26,90.46) v1(174.26,68.89) v1(174.33,66.4) v1(174.27,63.43) v1(174.26,40.84) v1(174.4,81.22) v1(174.41,71.16) v1(174.36,58.25) v1(174.54,106.09) v1(174.5,81.87) v1(174.49,62.68) v1(174.55,59.37) v1(174.52,49.75) v1(174.51,48.24) v1(174.45,39.28) v1(174.61,83.19) v1(174.61,64.78) v1(174.74,113.87) v1(174.67,94.38) v1(174.7,93.12) v1(174.71,47.04) v1(174.65,9.95) v1(174.85,109.23) v1(174.79,107.89) v1(174.84,2.07) v1(174.93,89.49) v1(174.94,87.05) v1(174.91,85.06) v1(174.85,67.76) v1(174.86,42.98) v1(174.93,4.51) v1(174.99,125.26) v1(175.03,112.53) v1(175.04,111.72) v1(174.98,103.83) v1(175,103.35) v1(174.97,102.66) v1(175.03,88.34) v1(174.96,77.65) v1(174.99,77.03) v1(174.97,41.43) v1(175.01,38.48) v1(175.08,71.72) v1(175.11,65.83) v1(175.07,60.3) v1(175.13,55.73) v1(175.14,39.96) v1(175.2,69.14) v1(175.22,45.31) v1(175.23,37.96) v1(175.28,117.2) v1(175.3,84.17) v1(175.35,83.22) v1(175.41,110.4) v1(175.39,107.3) v1(175.41,93.69) v1(175.45,81.92) v1(175.46,82.66) v1(175.55,61.52) v1(175.51,58.18) v1(175.53,48.03) v1(175.53,10.1) v1(175.58,91.95) v1(175.61,87.78) v1(175.64,39.29) v1(175.69,66.61) v1(175.76,128.78) v1(175.81,116.37) v1(175.77,62.26) v1(175.78,41.97) v1(175.87,63.86) v1(175.85,3.42) v1(175.99,111.29) v1(175.95,69.95) v1(176.02,5.63) v1(176.1,107.85) v1(176.1,106.8) v1(176.2,40.55) v1(176.2,33.59) v1(176.28,115.67) v1(176.34,113.98) v1(176.27,85.99) v1(176.26,43.52) v1(176.36,123.64) v1(176.39,117.18) v1(176.39,88.44) v1(176.45,38.07) v1(176.53,110.36) v1(176.48,86.93) v1(176.46,39.22) v1(176.61,108.54) v1(176.61,94.38) v1(176.58,49.75) v1(176.74,93.73) v1(176.67,89.24) v1(176.73,71.73) v1(176.66,55.72) v1(176.81,91.16) v1(176.85,80.22) v1(176.82,77.05) v1(176.76,67.66) v1(176.85,107.59) v1(176.93,85.24) v1(176.89,47.21) v1(177.05,80.62) v1(176.98,66.65) v1(176.98,64.76) v1(176.97,45.3) v1(177.04,2.07) v1(177.07,113.12) v1(177.08,87.61) v1(177.11,42.86) v1(177.13,4.51) v1(177.15,125.24) v1(177.2,109.48) v1(177.23,69.05) v1(177.22,44.41) v1(177.3,116.36) v1(177.33,111.38) v1(177.35,58.37) v1(177.4,105.32) v1(177.38,90.16) v1(177.42,77.66) v1(177.35,48.93) v1(177.53,123.36) v1(177.54,108.66) v1(177.5,106.22) v1(177.47,91.99) v1(177.46,70.81) v1(177.65,117.18) v1(177.64,107.7) v1(177.6,102.52) v1(177.65,78.72) v1(177.65,36.47) v1(177.7,88.34) v1(177.75,62.27) v1(177.7,60.87) v1(177.65,57.39) v1(177.66,50.23) v1(177.78,68.3) v1(177.77,48.04) v1(177.9,84.17) v1(177.9,82.87) v1(177.96,128.78) v1(177.98,86.77) v1(177.99,70) v1(177.98,66.39) v1(177.97,63.89) v1(177.96,55.74) v1(178.12,85.89) v1(178.05,3.42) v1(178.21,113.91) v1(178.25,105.32) v1(178.19,89.24) v1(178.25,40.27) v1(178.25,39.42) v1(178.22,5.63) v1(178.3,110.38) v1(178.31,83.32) v1(178.33,71.66) v1(178.37,92.87) v1(178.4,33.59) v1(178.52,116.66) v1(178.52,91.1) v1(178.58,115.07) v1(178.68,115.54) v1(178.7,94.85) v1(178.69,77.07) v1(178.73,48.82) v1(178.87,113.15) v1(178.91,47.26) v1(178.97,49.81) v1(179.09,117.19) v1(179.12,70.84) v1(179.13,69.09) v1(179.06,50.27) v1(179.19,2.13) v1(179.3,105.37) v1(179.27,91.97) v1(179.26,45.29) v1(179.43,108.7) v1(179.37,106.18) v1(179.41,86.78) v1(179.43,84.24) v1(179.44,64.88) v1(179.41,62.32) v1(179.36,55.76) v1(179.47,111.28) v1(179.46,89.38) v1(179.45,88.34) v1(179.45,85.85) v1(179.46,67.41) v1(179.48,42.85) v1(179.49,40.37) v1(179.56,115.77) v1(179.57,107.68) v1(179.75,94.66) v1(179.72,93.7) v1(179.7,57.22) v1(179.68,46.6) v1(179.78,112.01) v1(179.8,61.42) v1(179.88,109.42) v1(179.9,104.25) v1(179.94,71.63) v1(179.92,69.58) v1(179.9,60.37) v1(179.9,47.53) v1(179.95,38.42) v1(180.01,83.47) v1(180.13,113.16) v1(180.1,110.58) v1(180.1,92.5) v1(180.15,86.27) v1(180.1,66.62) v1(180.13,64.13) v1(180.13,41.54) v1(180.16,128.78) v1(180.25,103.35) v1(180.25,83.02) v1(180.21,68) v1(180.22,62.72) v1(180.25,61.17) v1(180.24,49.24) v1(180.34,115.9) v1(180.35,105.17) v1(180.31,89.82) v1(180.27,88.82) v1(180.34,56.65) v1(180.31,5.63) v1(180.39,124.37) v1(180.37,87.24) v1(180.42,84.81) v1(180.38,82.21) v1(180.36,65.4) v1(180.49,106.76) v1(180.49,93.74) v1(180.49,90.87) v1(180.55,60.12) v1(180.58,114.21) v1(180.58,104.21) v1(180.62,38.54) v1(180.81,70.68) v1(180.82,68.61) v1(180.85,60.65) v1(180.77,46.64) v1(180.87,45.84) v1(181.1,93.45) v1(181.09,85.34) v1(181.15,82.52) v1(181.1,60.32) v1(181.06,41.37) v1(181.39,125.53) v1(181.38,115.14) v1(181.37,56.88) v1(181.45,9.3) v1(181.39,2.13) v1(181.62,92.37) v1(181.65,78.67) v1(181.68,49.14) v1(181.93,87.14) v1(181.89,84.52) v1(181.91,60.44) v1(182.03,65.5) v1(182.15,70.63) v1(182.21,114.07) v1(182.24,111.4) v1(182.18,67.68) v1(182.21,62.92) v1(182.22,45.41) v1(182.25,37.92) v1(182.29,88.08) v1(182.33,40.94) v1(182.36,128.78) v1(182.44,107.94) v1(182.38,106.22) v1(182.44,93.51) v1(182.43,90.21) v1(182.4,83.81) v1(182.37,68.64) v1(182.37,46.64) v1(182.51,5.63) v1(182.59,124.37) v1(182.63,109.58) v1(182.62,92.85) v1(182.58,84.9) v1(182.75,115.03) v1(182.74,91.27) v1(182.74,66.22) v1(182.73,64.57) v1(182.7,61.02) v1(182.76,78.67) v1(182.79,56.88) v1(182.77,41.48) v1(182.8,38.37) v1(183.09,112.11) v1(183.12,88.79) v1(183.12,83) v1(183.05,49.16) v1(183.07,48.43) v1(183.09,47.12) v1(183.14,44.71) v1(183.14,40.24) v1(183.25,82.37) v1(183.25,61.36) v1(183.15,43.36) v1(183.28,100.85) v1(183.33,92.87) v1(183.34,87.99) v1(183.33,87.16) v1(183.41,85.76) v1(183.42,78.93) v1(183.42,70.62) v1(183.4,63.11) v1(183.54,114.74) v1(183.48,84.4) v1(183.59,125.53) v1(183.63,106.53) v1(183.62,104.87) v1(183.62,91.69) v1(183.59,2.13) v1(183.71,112.82) v1(183.71,111.23) v1(183.74,67.38) v1(183.68,45.74) v1(183.78,65.93) v1(183.85,9.3) v1(183.87,57.48) v1(183.87,7.79) v1(183.98,109.94) v1(184.02,108.32) v1(183.96,90.13) v1(184.04,64.24) v1(183.99,47.67) v1(184.22,114.03) v1(184.16,101.68) v1(184.16,88.54) v1(184.16,85.13) v1(184.2,83.42) v1(184.26,105.72) v1(184.4,112.32) v1(184.45,91.61) v1(184.43,87.7) v1(184.4,86.4) v1(184.36,79.83) v1(184.43,47.8) v1(184.4,6.85) v1(184.56,128.78) v1(184.62,89.17) v1(184.58,69.45) v1(184.59,46.57) v1(184.72,110.99) v1(184.7,110.25) v1(184.75,58.22) v1(184.79,124.37) v1(184.84,113.02) v1(184.8,15.05) v1(184.78,12.52) v1(185.33,90.62) v1(185.31,68.63) v1(185.33,9.6) v1(185.52,10.71) v1(185.53,5.69) v1(185.65,7.13) v1(185.79,125.53) v1(185.77,16.2) v1(185.84,2.13) v1(185.92,13.62) v1(185.97,108.66) v1(185.99,3.72) v1(186.32,111.94) v1(186.39,109.63) v1(186.45,105.7) v1(186.47,83.69) v1(186.65,5.53) v1(186.76,128.78) v1(186.79,7.75) v1(186.99,124.37) v1(187,15.05) v1(186.98,12.52) v1(187.05,10.4) v1(187.31,83.68) v1(187.5,87.59) v1(187.66,109.67) v1(187.72,10.71) v1(187.99,125.53) v1(187.95,106.52) v1(187.96,84.5) v1(187.97,16.2) v1(187.97,6.81) v1(188.01,5.16) v1(188.04,2.13) v1(188.12,13.62) v1(188.36,127.65) v1(188.46,122.37) v1(188.96,128.78) v1(189.13,106.49) v1(189.12,88.57) v1(189.05,6.59) v1(189.08,3.63) v1(189.19,124.37) v1(189.15,110.61) v1(189.2,15.05) v1(189.28,121.26) v1(189.36,126.67) v1(189.94,8.01) v1(190.19,125.53) v1(190.17,16.2) v1(190.21,5.16) v1(190.24,2.13) v1(190.56,127.65) v1(190.66,122.37) v1(190.66,83.63) v1(190.69,29.96) v1(190.81,109.81) v1(190.78,105.42) v1(190.9,111.81) v1(190.89,87.93) v1(190.95,63.69) v1(190.98,107.6) v1(191.03,89.87) v1(190.96,41.77) v1(191.08,85.56) v1(191.13,81.46) v1(191.1,65.72) v1(191.16,128.78) v1(191.22,43.8) v1(191.27,126.7) v1(191.33,83.32) v1(191.3,67.91) v1(191.33,12.6) v1(191.25,6.59) v1(191.28,3.63) v1(191.39,124.37) v1(191.39,39.61) v1(191.48,121.26) v1(191.46,61.66) v1(191.55,59.8) v1(191.57,5.3) v1(191.84,125.21) v1(191.83,26.34) v1(191.78,23.49) v1(191.82,17.26) v1(191.81,15.02) v1(191.89,28.7) v1(191.88,20.32) v1(192.01,110.47) v1(192,108.67) v1(192.02,106.74) v1(192.11,104.86) v1(192.15,65.47) v1(192.11,63.7) v1(192.08,41.78) v1(192.14,8.01) v1(192.22,103.5) v1(192.23,40.45) v1(192.33,87.94) v1(192.32,86.11) v1(192.25,43.2) v1(192.35,89.87) v1(192.37,84.25) v1(192.38,82.56) v1(192.4,66.66) v1(192.36,62.62) v1(192.43,60.76) v1(192.47,2.08) v1(192.69,111.79) v1(192.75,59.56) v1(192.75,25.02) v1(192.76,127.65) v1(192.75,81.48) v1(192.8,67.81) v1(192.78,21.9) v1(192.86,122.37) v1(192.89,29.96) v1(192.86,27.61) v1(192.92,18.76) v1(192.91,16.11) v1(192.88,13.89) v1(193.34,20.27) v1(193.36,128.78) v1(193.41,103.68) v1(193.37,9.32) v1(193.47,89.53) v1(193.52,60.51) v1(193.57,110.95) v1(193.63,82.1) v1(193.57,67.11) v1(193.62,65.93) v1(193.62,64.47) v1(193.61,63.06) v1(193.59,61.75) v1(193.68,121.26) v1(193.74,109.88) v1(193.73,108.75) v1(193.74,107.61) v1(193.72,106.26) v1(193.74,104.91) v1(193.72,88.29) v1(193.69,86.78) v1(193.67,85.24) v1(193.67,83.67) v1(193.94,12.46) v1(194.03,26.34) v1(193.98,23.49) v1(194.02,17.26) v1(194.01,15.02) v1(194.09,28.7) v1(194.34,8.01) v1(194.68,1.76) v1(194.95,25.02) v1(195.09,29.96) v1(195.06,27.61) v1(195.12,18.76) v1(195.11,16.11) v1(195.08,13.89) v1(195.56,128.78) v1(195.6,128.21) v1(195.55,121.75) v1(195.57,9.32) v1(195.88,121.26) v1(196.14,12.46) v1(196.23,26.34) v1(196.18,23.49) v1(196.22,17.26) v1(196.21,15.02) v1(196.29,28.7) v1(196.31,8.03) v1(196.59,10.69) v1(196.87,2.08) v1(197.15,25.02) v1(197.16,127.65) v1(197.18,21.9) v1(197.26,122.37) v1(197.32,29.95) v1(197.26,27.61) v1(197.32,18.76) v1(197.31,16.11) v1(197.28,13.89) v1(198.04,6.13) v1(198.04,3.82) v1(198.08,121.26) v1(198.17,126.54) v1(198.26,20.27) v1(198.34,12.46) v1(198.42,123.46) v1(198.4,28.65) v1(198.45,24.1) v1(198.53,124.74) v1(198.52,26.24) v1(198.51,8.03) v1(198.63,10.65) v1(198.73,21.91) v2(1.24,49.62) v2(1.43,80.71) v2(1.38,74.59) v2(1.46,43.08) v2(1.58,95.56) v2(1.55,93.21) v2(1.55,36.54) v2(1.58,29.99) v2(1.6,27.79) v2(1.62,23.87) v2(1.61,5.23) v2(1.74,56.89) v2(1.67,21.67) v2(1.68,19.57) v2(1.72,8.82) v2(1.69,6.99) v2(1.78,54.97) v2(1.77,52.66) v2(1.75,17.5) v2(1.8,13.44) v2(1.75,11.16) v2(1.86,122.47) v2(1.91,120.38) v2(1.91,61.11) v2(1.85,15.42) v2(1.96,118.18) v2(1.98,59.05) v2(2.01,50.69) v2(2.08,77.61) v2(2.13,75.61) v2(2.07,48.5) v2(2.1,46.34) v2(2.18,116.12) v2(2.24,100.54) v2(2.19,98.52) v2(2.18,81.73) v2(2.21,79.69) v2(2.16,73.57) v2(2.23,44.15) v2(2.24,39.77) v2(2.3,94.4) v2(2.29,41.95) v2(2.32,37.61) v2(2.28,33.3) v2(2.34,31.06) v2(2.37,96.5) v2(2.38,35.42) v2(2.41,28.87) v2(2.38,24.95) v2(2.44,22.75) v2(2.54,55.94) v2(2.46,27.11) v2(2.47,20.67) v2(2.5,18.58) v2(2.51,16.53) v2(2.53,12.2) v2(2.46,10.04) v2(2.47,7.77) v2(2.51,6.11) v2(2.63,53.78) v2(2.55,51.82) v2(2.59,14.4) v2(2.69,121.44) v2(2.74,119.34) v2(2.72,60.07) v2(2.74,49.62) v2(2.79,117.15) v2(2.83,78.63) v2(2.75,58.03) v2(2.94,127.31) v2(2.94,99.55) v2(2.93,80.71) v2(2.85,76.59) v2(2.88,74.59) v2(2.86,47.42) v2(2.92,45.22) v2(2.98,110.95) v2(2.96,43.08) v2(3,40.84) v2(3.04,34.37) v2(3.05,108.11) v2(3.07,97.53) v2(3.08,95.56) v2(3.05,93.21) v2(3.06,38.65) v2(3.05,36.54) v2(3.1,32.17) v2(3.08,29.99) v2(3.1,27.79) v2(3.12,23.87) v2(3.11,5.23) v2(3.1,3.13) v2(3.24,56.89) v2(3.17,21.67) v2(3.18,19.57) v2(3.22,8.82) v2(3.19,6.99) v2(3.28,54.97) v2(3.27,52.66) v2(3.25,17.5) v2(3.3,13.44) v2(3.25,11.16) v2(3.36,122.47) v2(3.41,120.38) v2(3.44,103.67) v2(3.41,61.11) v2(3.35,15.42) v2(3.46,118.18) v2(3.48,59.05) v2(3.51,50.69) v2(3.58,77.61) v2(3.63,75.61) v2(3.57,48.5) v2(3.6,46.34) v2(3.74,100.54) v2(3.71,79.69) v2(3.66,73.57) v2(3.73,44.15) v2(3.74,39.77) v2(3.8,94.4) v2(3.79,41.95) v2(3.82,37.61) v2(3.78,33.3) v2(3.84,31.06) v2(3.84,2.11) v2(3.87,96.5) v2(3.88,35.42) v2(3.91,28.87) v2(3.88,24.95) v2(3.94,22.75) v2(4.04,55.94) v2(3.96,27.11) v2(3.97,20.67) v2(4,18.58) v2(4.01,16.53) v2(4.03,12.2) v2(3.96,10.04) v2(3.97,7.77) v2(4.13,53.78) v2(4.05,51.82) v2(4.09,14.4) v2(4.19,121.44) v2(4.24,119.34) v2(4.22,60.07) v2(4.24,49.62) v2(4.29,117.15) v2(4.27,106.51) v2(4.33,78.63) v2(4.25,58.03) v2(4.44,127.31) v2(4.42,109.28) v2(4.43,80.71) v2(4.35,76.59) v2(4.38,74.59) v2(4.36,47.42) v2(4.42,45.22) v2(4.46,43.08) v2(4.5,40.84) v2(4.54,34.37) v2(4.58,95.56) v2(4.55,93.21) v2(4.56,38.65) v2(4.55,36.54) v2(4.6,32.17) v2(4.58,29.99) v2(4.6,27.79) v2(4.62,23.87) v2(4.6,3.13) v2(4.65,111.83) v2(4.74,56.89) v2(4.67,21.67) v2(4.68,19.57) v2(4.72,8.82) v2(4.69,6.99) v2(4.84,114.13) v2(4.78,54.97) v2(4.77,52.66) v2(4.75,17.5) v2(4.8,13.44) v2(4.75,11.16) v2(4.86,122.47) v2(4.91,120.38) v2(4.91,61.11) v2(4.85,15.42) v2(4.96,118.18) v2(4.98,59.05) v2(5.01,50.69) v2(5.11,128.35) v2(5.08,77.61) v2(5.13,75.61) v2(5.07,48.5) v2(5.1,46.34) v2(5.24,100.54) v2(5.19,98.52) v2(5.18,81.73) v2(5.21,79.69) v2(5.16,73.57) v2(5.23,44.15) v2(5.24,39.77) v2(5.3,94.4) v2(5.29,41.95) v2(5.32,37.61) v2(5.28,33.3) v2(5.34,31.06) v2(5.34,2.11) v2(5.37,96.5) v2(5.38,35.42) v2(5.41,28.87) v2(5.38,24.95) v2(5.44,22.75) v2(5.54,55.94) v2(5.46,27.11) v2(5.47,20.67) v2(5.5,18.58) v2(5.51,16.53) v2(5.53,12.2) v2(5.46,10.04) v2(5.47,7.77) v2(5.63,53.78) v2(5.55,51.82) v2(5.59,14.4) v2(5.69,121.44) v2(5.74,119.34) v2(5.72,60.07) v2(5.74,49.62) v2(5.79,117.15) v2(5.82,104.06) v2(5.84,102.18) v2(5.83,78.63) v2(5.75,58.03) v2(5.94,127.31) v2(5.86,106.43) v2(5.94,99.55) v2(5.93,80.71) v2(5.85,76.59) v2(5.88,74.59) v2(5.86,47.42) v2(5.92,45.22) v2(6.01,110.61) v2(5.96,108.55) v2(5.96,43.08) v2(6,40.84) v2(6.04,34.37) v2(6.07,97.53) v2(6.08,95.56) v2(6.05,93.21) v2(6.06,38.65) v2(6.05,36.54) v2(6.1,32.17) v2(6.08,29.99) v2(6.1,27.79) v2(6.12,23.87) v2(6.1,3.13) v2(6.24,56.89) v2(6.17,21.67) v2(6.18,19.57) v2(6.22,8.82) v2(6.19,6.99) v2(6.28,54.97) v2(6.27,52.66) v2(6.25,17.5) v2(6.3,13.44) v2(6.25,11.16) v2(6.36,122.47) v2(6.41,120.38) v2(6.38,115.5) v2(6.41,61.11) v2(6.35,15.42) v2(6.46,118.18) v2(6.48,59.05) v2(6.51,50.69) v2(6.61,128.35) v2(6.65,109.57) v2(6.65,107.54) v2(6.61,98.5) v2(6.58,77.61) v2(6.63,75.61) v2(6.57,48.5) v2(6.67,111.66) v2(6.74,100.54) v2(6.68,81.73) v2(6.71,79.69) v2(6.66,73.57) v2(6.73,44.15) v2(6.74,39.77) v2(6.79,96.49) v2(6.8,94.4) v2(6.79,41.95) v2(6.82,37.61) v2(6.84,31.06) v2(6.84,2.11) v2(6.93,113.02) v2(6.88,35.42) v2(6.91,28.87) v2(6.88,24.95) v2(6.94,22.75) v2(6.85,4.26) v2(7.04,55.94) v2(6.96,27.11) v2(7,18.58) v2(7.01,16.53) v2(7.03,12.2) v2(6.96,10.04) v2(6.97,7.77) v2(7.01,6.11) v2(7.13,53.78) v2(7.05,51.82) v2(7.09,14.4) v2(7.19,121.44) v2(7.24,119.34) v2(7.22,60.07) v2(7.29,117.15) v2(7.28,106.42) v2(7.33,78.63) v2(7.25,58.03) v2(7.44,127.31) v2(7.42,125.68) v2(7.38,108.53) v2(7.44,99.55) v2(7.43,80.71) v2(7.35,76.59) v2(7.38,74.59) v2(7.36,47.42) v2(7.51,110.61) v2(7.49,97.52) v2(7.5,95.55) v2(7.47,93.2) v2(7.5,40.84) v2(7.63,49.3) v2(7.6,32.17) v2(7.6,27.79) v2(7.62,23.87) v2(7.61,5.23) v2(7.6,3.13) v2(7.74,56.89) v2(7.67,36.55) v2(7.68,19.57) v2(7.72,8.82) v2(7.69,6.99) v2(7.78,54.97) v2(7.77,52.66) v2(7.78,30) v2(7.75,17.5) v2(7.8,13.44) v2(7.75,11.16) v2(7.86,122.47) v2(7.91,120.38) v2(7.91,61.11) v2(7.92,43.08) v2(7.85,15.42) v2(7.96,118.18) v2(7.98,59.05) v2(8.11,128.35) v2(8.12,124.21) v2(8.09,111.64) v2(8.07,109.55) v2(8.07,107.53) v2(8.08,105.38) v2(8.06,98.5) v2(8.08,77.61) v2(8.13,75.61) v2(8.16,100.53) v2(8.24,96.49) v2(8.22,94.38) v2(8.18,81.73) v2(8.21,79.69) v2(8.16,73.57) v2(8.34,2.11) v2(8.41,48.45) v2(8.44,42.02) v2(8.38,39.72) v2(8.41,24.78) v2(8.44,22.75) v2(8.35,4.26) v2(8.54,55.94) v2(8.46,35.38) v2(8.46,27.11) v2(8.51,16.53) v2(8.53,12.2) v2(8.46,10.04) v2(8.47,7.77) v2(8.51,6.11) v2(8.63,53.78) v2(8.55,51.82) v2(8.58,44.28) v2(8.59,31.62) v2(8.64,28.98) v2(8.56,19.91) v2(8.56,18.62) v2(8.59,14.4) v2(8.72,60.07) v2(8.8,106.4) v2(8.83,78.63) v2(8.75,58.03) v2(8.94,127.31) v2(8.93,110.6) v2(8.91,108.52) v2(8.86,99.54) v2(8.94,97.52) v2(8.93,80.71) v2(8.85,76.59) v2(8.88,74.59) v2(8.89,45.9) v2(9.15,95.67) v2(9.13,49.3) v2(9.14,40.79) v2(9.06,33.39) v2(9.1,27.79) v2(9.07,21.05) v2(9.11,5.23) v2(9.1,3.13) v2(9.24,56.89) v2(9.17,36.55) v2(9.19,30.4) v2(9.21,24.22) v2(9.22,8.82) v2(9.19,6.99) v2(9.25,125.68) v2(9.28,121.42) v2(9.28,119.15) v2(9.3,116.98) v2(9.28,54.97) v2(9.27,52.66) v2(9.25,17.5) v2(9.3,13.44) v2(9.25,11.16) v2(9.41,61.11) v2(9.35,15.42) v2(9.48,59.05) v2(9.61,128.35) v2(9.62,111.63) v2(9.59,109.54) v2(9.59,107.51) v2(9.6,105.37) v2(9.56,98.5) v2(9.58,77.61) v2(9.63,75.61) v2(9.69,100.55) v2(9.74,96.49) v2(9.71,79.69) v2(9.66,73.57) v2(9.84,2.11) v2(9.88,42.02) v2(9.88,39.72) v2(9.85,4.26) v2(10.04,55.94) v2(10.03,29.61) v2(9.96,27.11) v2(9.95,20.42) v2(10.04,18.3) v2(10.01,16.53) v2(10.03,12.2) v2(9.96,10.04) v2(9.97,7.77) v2(10.01,6.11) v2(10.13,53.78) v2(10.05,51.82) v2(10.05,45.19) v2(10.09,14.4) v2(10.15,124.32) v2(10.22,60.07) v2(10.33,78.63) v2(10.25,58.03) v2(10.33,33.11) v2(10.44,127.31) v2(10.44,97.52) v2(10.43,80.71) v2(10.35,76.59) v2(10.38,74.59) v2(10.65,95.67) v2(10.63,49.3) v2(10.64,40.79) v2(10.6,27.79) v2(10.61,5.23) v2(10.6,3.13) v2(10.74,56.89) v2(10.7,42.76) v2(10.67,36.55) v2(10.71,28.83) v2(10.71,24.22) v2(10.72,8.82) v2(10.69,6.99) v2(10.78,54.97) v2(10.77,52.66) v2(10.75,15.44) v2(10.91,61.11) v2(10.98,59.05) v2(11,20.99) v2(11.11,128.35) v2(11.06,98.5) v2(11.08,77.61) v2(11.05,75.6) v2(11.14,29.96) v2(11.19,125.68) v2(11.24,96.49) v2(11.21,79.69) v2(11.16,73.57) v2(11.27,45.4) v2(11.34,33) v2(11.34,2.11) v2(11.38,39.72) v2(11.45,16.47) v2(11.35,4.26) v2(11.54,55.94) v2(11.46,27.11) v2(11.46,25.66) v2(11.46,10.04) v2(11.47,7.77) v2(11.51,6.11) v2(11.64,60.06) v2(11.63,53.78) v2(11.55,51.82) v2(11.59,13.35) v2(11.75,78.62) v2(11.75,58.03) v2(11.94,127.31) v2(11.94,97.52) v2(11.86,80.87) v2(11.85,76.59) v2(11.86,74.62) v2(11.94,50.45) v2(11.85,38) v2(12.15,95.67) v2(12.13,49.3) v2(12.14,40.79) v2(12.1,27.79) v2(12.11,5.23) v2(12.1,3.13) v2(12.24,56.89) v2(12.17,36.55) v2(12.22,33.61) v2(12.21,24.22) v2(12.21,21.2) v2(12.19,6.99) v2(12.28,54.97) v2(12.27,52.66) v2(12.26,45.89) v2(12.26,29.32) v2(12.28,17.4) v2(12.32,10.62) v2(12.38,12.17) v2(12.61,128.35) v2(12.56,98.5) v2(12.61,81.89) v2(12.64,79.85) v2(12.61,75.64) v2(12.64,73.6) v2(12.6,41.03) v2(12.63,28.27) v2(12.74,96.49) v2(12.69,77.67) v2(12.72,71.82) v2(12.84,14.48) v2(12.84,2.11) v2(12.88,39.72) v2(12.94,30.76) v2(12.88,13.64) v2(12.85,4.26) v2(13.04,55.94) v2(12.96,27.11) v2(12.96,25.66) v2(12.97,7.77) v2(13.01,6.11) v2(13.13,53.78) v2(13.05,51.82) v2(13.14,42.03) v2(13.06,29.7) v2(13.05,18.58) v2(13.33,11.12) v2(13.31,9.6) v2(13.44,127.31) v2(13.44,97.52) v2(13.36,80.87) v2(13.44,78.69) v2(13.36,74.62) v2(13.44,72.7) v2(13.47,76.65) v2(13.54,12.42) v2(13.65,95.67) v2(13.57,88.41) v2(13.64,40.79) v2(13.6,27.79) v2(13.61,5.23) v2(13.6,3.13) v2(13.68,86.35) v2(13.74,56.89) v2(13.71,24.22) v2(13.72,8.82) v2(13.69,6.99) v2(13.81,90.51) v2(13.78,54.97) v2(13.77,52.66) v2(13.78,49.25) v2(13.75,36.52) v2(13.91,32.36) v2(13.98,98.49) v2(13.98,30.13) v2(14.11,128.35) v2(14.05,112.07) v2(14.08,109.66) v2(14.11,81.89) v2(14.14,79.85) v2(14.11,75.64) v2(14.14,73.6) v2(14.11,37.99) v2(14.23,114.88) v2(14.16,96.48) v2(14.19,77.67) v2(14.22,71.82) v2(14.16,19.73) v2(14.26,107.08) v2(14.34,50.42) v2(14.34,18.23) v2(14.34,16.83) v2(14.34,2.11) v2(14.36,91.54) v2(14.36,89.52) v2(14.37,87.37) v2(14.37,14.51) v2(14.37,13.28) v2(14.35,4.26) v2(14.54,55.94) v2(14.5,42.83) v2(14.5,39.72) v2(14.54,33.31) v2(14.46,27.11) v2(14.46,25.66) v2(14.47,7.77) v2(14.51,6.11) v2(14.63,53.78) v2(14.55,51.82) v2(14.65,45.9) v2(14.6,44.96) v2(14.62,20.93) v2(14.65,9.97) v2(14.94,127.31) v2(14.86,97.51) v2(14.86,80.87) v2(14.94,78.69) v2(14.86,74.62) v2(14.94,72.7) v2(14.97,76.65) v2(15.03,28.23) v2(15.07,95.66) v2(15.07,88.41) v2(15.1,27.79) v2(15.11,5.23) v2(15.1,3.13) v2(15.18,90.52) v2(15.18,86.35) v2(15.24,56.89) v2(15.2,31.93) v2(15.21,24.22) v2(15.22,8.82) v2(15.19,6.99) v2(15.28,54.97) v2(15.27,52.66) v2(15.28,49.25) v2(15.26,40.79) v2(15.48,44.71) v2(15.61,128.35) v2(15.61,81.89) v2(15.64,79.85) v2(15.61,75.64) v2(15.64,73.6) v2(15.61,32.87) v2(15.69,77.67) v2(15.72,71.82) v2(15.8,29.31) v2(15.75,18.33) v2(15.77,17.12) v2(15.81,11.8) v2(15.84,2.11) v2(15.86,91.54) v2(15.86,89.52) v2(15.87,87.37) v2(15.85,4.26) v2(16.04,64.35) v2(16.01,61.74) v2(16.04,55.94) v2(16,39.72) v2(15.96,36.49) v2(15.96,27.11) v2(15.97,7.77) v2(16.01,6.11) v2(16.09,115.55) v2(16.05,107.16) v2(16.12,101.53) v2(16.14,99.49) v2(16.14,67.04) v2(16.13,53.78) v2(16.05,51.82) v2(16.17,41.03) v2(16.17,13.26) v2(16.3,110.83) v2(16.3,20.53) v2(16.44,127.31) v2(16.36,80.87) v2(16.44,78.69) v2(16.36,74.62) v2(16.44,72.7) v2(16.47,105.44) v2(16.47,76.65) v2(16.57,88.41) v2(16.6,27.79) v2(16.57,9.95) v2(16.61,5.23) v2(16.6,3.13) v2(16.74,103.26) v2(16.68,90.52) v2(16.68,86.35) v2(16.74,56.89) v2(16.72,8.82) v2(16.69,6.99) v2(16.78,54.97) v2(16.77,52.66) v2(16.78,49.25) v2(16.76,40.79) v2(16.9,32.14) v2(17,45.51) v2(17.11,128.35) v2(17.14,121.34) v2(17.11,81.89) v2(17.14,79.85) v2(17.11,75.64) v2(17.14,73.6) v2(17.07,65.77) v2(17.07,62.98) v2(17.13,42.73) v2(17.19,77.67) v2(17.22,71.82) v2(17.2,18.97) v2(17.24,17.25) v2(17.34,85.37) v2(17.25,30.59) v2(17.29,28.3) v2(17.34,2.11) v2(17.37,95.56) v2(17.39,93.64) v2(17.36,91.54) v2(17.36,89.52) v2(17.37,87.37) v2(17.35,4.26) v2(17.54,55.94) v2(17.5,39.72) v2(17.46,27.11) v2(17.47,7.77) v2(17.51,6.11) v2(17.63,53.78) v2(17.55,51.82) v2(17.68,12.93) v2(17.8,68.08) v2(17.86,80.87) v2(17.94,78.69) v2(17.86,74.62) v2(17.94,72.7) v2(17.97,120.31) v2(17.98,94.4) v2(17.97,76.65) v2(18.05,127.31) v2(18.07,88.41) v2(18.1,27.79) v2(18.06,14.55) v2(18.11,5.23) v2(18.1,3.13) v2(18.18,102.92) v2(18.23,92.59) v2(18.18,90.52) v2(18.18,86.35) v2(18.24,64.35) v2(18.21,61.74) v2(18.24,56.89) v2(18.21,40.74) v2(18.22,9.95) v2(18.22,8.82) v2(18.19,6.99) v2(18.28,110.45) v2(18.34,67.04) v2(18.28,54.97) v2(18.27,52.66) v2(18.28,49.25) v2(18.4,111.37) v2(18.38,83.83) v2(18.42,60.66) v2(18.38,36.49) v2(18.36,29.95) v2(18.61,128.35) v2(18.64,121.34) v2(18.61,81.89) v2(18.64,79.85) v2(18.61,75.64) v2(18.64,73.6) v2(18.64,69.28) v2(18.64,59.37) v2(18.58,44.72) v2(18.61,31.86) v2(18.69,77.67) v2(18.72,16.36) v2(18.84,85.37) v2(18.84,2.11) v2(18.91,115.29) v2(18.89,93.64) v2(18.86,91.54) v2(18.86,89.52) v2(18.87,87.37) v2(18.93,11.75) v2(18.85,4.26) v2(19.05,105.98) v2(19.01,95.45) v2(19.04,55.94) v2(19,39.72) v2(18.96,27.11) v2(18.99,20.77) v2(19.01,6.11) v2(19.1,108.13) v2(19.06,104.09) v2(19.13,53.78) v2(19.05,51.82) v2(19.27,65.77) v2(19.27,62.98) v2(19.25,58.03) v2(19.32,41) v2(19.32,12.94) v2(19.36,80.87) v2(19.44,78.69) v2(19.36,74.62) v2(19.42,29.36) v2(19.42,28.3) v2(19.47,120.31) v2(19.49,88.39) v2(19.47,76.65) v2(19.55,42.74) v2(19.64,127.31) v2(19.6,90.51) v2(19.6,86.34) v2(19.6,27.79) v2(19.61,5.23) v2(19.6,3.13) v2(19.75,94.59) v2(19.73,92.59) v2(19.74,56.89) v2(19.72,8.82) v2(19.69,6.99) v2(19.79,110.42) v2(19.85,70.48) v2(19.78,54.97) v2(19.77,52.66) v2(19.76,40.79) v2(19.78,30.44) v2(19.89,32.93) v2(19.86,17.87) v2(20.02,114) v2(19.99,13.74) v2(20.13,128.39) v2(20.14,121.34) v2(20.06,111.39) v2(20.11,109.02) v2(20.09,107.06) v2(20.09,105.22) v2(20.09,103.11) v2(20.11,81.89) v2(20.14,79.85) v2(20.11,75.64) v2(20.14,73.6) v2(20.19,77.67) v2(20.25,76.95) v2(20.22,71.82) v2(20.23,45.44) v2(20.31,93.62) v2(20.28,91.53) v2(20.28,89.5) v2(20.29,87.36) v2(20.34,85.37) v2(20.34,2.11) v2(20.44,64.35) v2(20.4,9.88) v2(20.35,4.26) v2(20.54,67.04) v2(20.53,61.79) v2(20.54,55.94) v2(20.47,39.62) v2(20.46,27.11) v2(20.47,7.77) v2(20.51,6.11) v2(20.63,95.68) v2(20.63,59.4) v2(20.63,53.78) v2(20.55,51.82) v2(20.74,60.66) v2(20.75,58.03) v2(20.84,35.43) v2(20.87,83.83) v2(20.86,80.87) v2(20.94,78.69) v2(20.86,74.62) v2(20.93,47.19) v2(20.87,34.1) v2(20.97,120.31) v2(20.97,94.69) v2(21.02,88.38) v2(20.97,76.65) v2(21.02,16.65) v2(21.14,127.31) v2(21.15,92.58) v2(21.12,90.5) v2(21.12,86.33) v2(21.1,27.79) v2(21.08,22) v2(21.11,5.23) v2(21.1,3.13) v2(21.24,56.89) v2(21.23,40.69) v2(21.17,29.96) v2(21.22,8.82) v2(21.19,6.99) v2(21.33,113.67) v2(21.28,54.97) v2(21.27,52.66) v2(21.53,81.87) v2(21.53,75.63) v2(21.48,70.75) v2(21.47,65.77) v2(21.47,62.98) v2(21.55,50.81) v2(21.46,28.28) v2(21.64,121.34) v2(21.64,79.85) v2(21.64,73.6) v2(21.61,13.72) v2(21.57,12.81) v2(21.69,77.67) v2(21.72,71.82) v2(21.81,128.35) v2(21.8,111.68) v2(21.77,109.24) v2(21.84,107.26) v2(21.79,105.33) v2(21.78,103.61) v2(21.83,93.61) v2(21.8,91.52) v2(21.8,89.49) v2(21.82,87.35) v2(21.84,85.37) v2(21.83,42.78) v2(21.84,2.11) v2(21.85,4.26) v2(22.04,55.94) v2(21.97,39.62) v2(21.96,27.11) v2(21.98,11.72) v2(21.97,7.77) v2(22.01,6.11) v2(22.13,53.78) v2(22.05,51.82) v2(22.24,38.61) v2(22.25,58.03) v2(22.32,46.58) v2(22.34,23.12) v2(22.3,20.97) v2(22.36,78.67) v2(22.4,48.69) v2(22.38,41.03) v2(22.4,29.24) v2(22.39,17.8) v2(22.36,15.65) v2(22.47,120.31) v2(22.5,64.37) v2(22.48,61.76) v2(22.5,42.02) v2(22.49,35.31) v2(22.64,127.31) v2(22.56,118.86) v2(22.62,113.56) v2(22.61,67.05) v2(22.6,27.79) v2(22.61,5.23) v2(22.6,3.13) v2(22.68,95.69) v2(22.74,56.89) v2(22.72,43.55) v2(22.73,40.69) v2(22.75,39.62) v2(22.72,8.82) v2(22.69,6.99) v2(22.78,54.97) v2(22.77,52.66) v2(22.84,37.15) v2(22.76,33.06) v2(22.94,60.66) v2(22.9,34.12) v2(22.89,9.96) v2(22.99,70.78) v2(22.98,31.37) v2(23.14,121.34) v2(23.31,128.35) v2(23.26,85.36) v2(23.26,83.82) v2(23.35,63.43) v2(23.34,2.11) v2(23.35,4.26) v2(23.54,65.79) v2(23.51,46.79) v2(23.46,27.11) v2(23.47,7.77) v2(23.51,6.11) v2(23.64,108.17) v2(23.63,53.78) v2(23.55,51.82) v2(23.95,100.62) v2(23.94,26.07) v2(23.91,23.91) v2(23.91,21.65) v2(23.88,19.5) v2(23.86,16.87) v2(24.09,127.26) v2(24.1,15.67) v2(24.11,5.23) v2(24.1,3.13) v2(24.23,40.69) v2(24.15,13.71) v2(24.22,8.82) v2(24.19,6.99) v2(24.27,52.66) v2(24.34,43.79) v2(24.43,114.21) v2(24.39,102.13) v2(24.51,116.87) v2(24.47,115.36) v2(24.5,112.35) v2(24.54,110.73) v2(24.56,27.95) v2(24.66,109.25) v2(24.75,81.37) v2(24.81,128.35) v2(24.8,35.42) v2(24.84,2.11) v2(24.91,11.77) v2(24.85,4.26) v2(24.96,48.9) v2(24.97,39.62) v2(24.99,37.2) v2(25.01,6.11) v2(25.05,60.63) v2(25.13,53.78) v2(25.05,51.82) v2(25.44,111.59) v2(25.43,66.42) v2(25.4,42.3) v2(25.36,31.6) v2(25.44,27.44) v2(25.4,25.28) v2(25.44,22.71) v2(25.4,20.55) v2(25.36,18.08) v2(25.59,127.26) v2(25.63,63.81) v2(25.58,34.22) v2(25.58,29.48) v2(25.61,5.23) v2(25.6,3.13) v2(25.67,99.53) v2(25.69,95.24) v2(25.68,47.86) v2(25.69,9.96) v2(25.72,8.82) v2(25.69,6.99) v2(25.77,52.66) v2(25.91,116.94) v2(25.91,107.61) v2(25.94,102.99) v2(25.88,38.99) v2(25.96,105.42) v2(26.02,45.32) v2(25.99,44.01) v2(26,42.52) v2(26,41) v2(26.1,81.37) v2(26.1,46.63) v2(26.2,114.21) v2(26.26,128.3) v2(26.3,98.13) v2(26.29,56.33) v2(26.34,2.11) v2(26.4,115.51) v2(26.35,4.26) v2(26.47,7.77) v2(26.51,6.11) v2(26.63,53.78) v2(26.55,51.82) v2(26.67,59.35) v2(26.68,48.9) v2(27.09,127.26) v2(27.08,111.59) v2(27.1,107.25) v2(27.11,5.23) v2(27.1,3.13) v2(27.17,116.85) v2(27.18,113.12) v2(27.2,104.2) v2(27.22,8.82) v2(27.19,6.99) v2(27.45,13.74) v2(27.47,109.22) v2(27.75,28.37) v2(27.76,128.3) v2(27.85,99.59) v2(27.84,2.11) v2(27.85,4.26) v2(27.97,7.77) v2(28.01,6.11) v2(28.25,116.26) v2(28.31,9.93) v2(28.42,105.39) v2(28.44,103.27) v2(28.59,127.26) v2(28.61,5.23) v2(28.6,3.13) v2(28.75,11.86) v2(28.72,8.82) v2(28.69,6.99) v2(28.82,107.24) v2(28.92,34.57) v2(28.97,110.37) v2(29.1,29.77) v2(29.22,95.39) v2(29.2,27.37) v2(29.26,128.3) v2(29.33,109.2) v2(29.32,25.88) v2(29.34,24.22) v2(29.29,13.73) v2(29.34,2.11) v2(29.36,91.09) v2(29.35,4.26) v2(29.52,111.55) v2(29.5,20.57) v2(29.54,14.11) v2(29.47,7.77) v2(29.51,6.11) v2(29.6,22.78) v2(29.94,3.18) v2(30.09,127.26) v2(30.14,116.57) v2(30.09,34.36) v2(30.09,32.73) v2(30.13,31.37) v2(30.11,5.23) v2(30.22,94.21) v2(30.22,8.82) v2(30.19,6.99) v2(30.3,29.37) v2(30.27,27.4) v2(30.4,86.19) v2(30.42,83.93) v2(30.41,45.66) v2(30.45,43.04) v2(30.36,41.11) v2(30.41,38.13) v2(30.4,36.09) v2(30.54,111.9) v2(30.53,100.77) v2(30.51,89.81) v2(30.53,55.38) v2(30.54,52.85) v2(30.51,48.15) v2(30.49,4.32) v2(30.64,106.71) v2(30.6,104.34) v2(30.7,9.94) v2(30.7,2.11) v2(30.76,128.3) v2(30.76,115.37) v2(30.78,97.22) v2(30.84,56.55) v2(30.77,23.07) v2(30.88,108.19) v2(30.89,51.23) v2(30.99,49.57) v2(31.02,20.81) v2(30.97,7.77) v2(31.01,6.11) v2(31.2,13.75) v2(31.28,116.62) v2(31.32,99.89) v2(31.45,47.23) v2(31.42,31.9) v2(31.44,3.18) v2(31.59,127.26) v2(31.59,105.51) v2(31.58,98.43) v2(31.64,42.25) v2(31.57,39.63) v2(31.61,5.23) v2(31.66,103.09) v2(31.71,45.68) v2(31.72,8.82) v2(31.69,6.99) v2(31.84,110.08) v2(31.83,11.99) v2(31.95,36.69) v2(32.04,33.7) v2(31.99,4.32) v2(32.21,92.39) v2(32.2,2.11) v2(32.26,128.3) v2(32.28,48.19) v2(32.38,35.27) v2(32.49,30.51) v2(32.55,27.03) v2(32.47,7.77) v2(32.51,6.11) v2(32.58,51.23) v2(32.6,24.85) v2(32.64,21.29) v2(32.65,106.75) v2(32.75,44.9) v2(32.84,104.33) v2(32.8,89.23) v2(32.77,86.68) v2(32.78,84.45) v2(32.76,41.46) v2(32.8,38.08) v2(32.88,105.94) v2(32.94,3.18) v2(32.96,110.1) v2(33,102.72) v2(32.96,22.63) v2(33.09,127.26) v2(33.11,111.82) v2(33.22,8.82) v2(33.27,47.26) v2(33.29,42.7) v2(33.34,29.53) v2(33.29,21.94) v2(33.39,10.19) v2(33.53,107.62) v2(33.51,40.47) v2(33.5,34.4) v2(33.49,4.32) v2(33.6,23.71) v2(33.74,69.56) v2(33.71,36.66) v2(33.7,2.11) v2(33.76,128.3) v2(33.84,65.6) v2(33.83,48.23) v2(33.8,25.72) v2(33.93,62.1) v2(33.9,32.85) v2(33.96,59.79) v2(34.03,7.77) v2(34.1,106.55) v2(34.08,49.57) v2(34.06,31.96) v2(34.12,27.04) v2(34.09,9.85) v2(34.24,5.57) v2(34.33,11.31) v2(34.39,110.1) v2(34.44,47.26) v2(34.43,30.48) v2(34.44,3.18) v2(34.45,44.89) v2(34.59,127.26) v2(34.55,46.37) v2(34.63,24.23) v2(34.7,104.1) v2(34.66,64.58) v2(34.71,22.55) v2(34.71,11.98) v2(34.78,20.7) v2(34.76,8.84) v2(34.92,107.55) v2(34.92,102.77) v2(34.9,96.92) v2(34.86,94.82) v2(34.86,85.99) v2(34.91,80.03) v2(34.9,63.32) v2(34.86,58.48) v2(34.93,56.06) v2(35.02,117.51) v2(34.95,111.78) v2(35,100.82) v2(35,96.16) v2(35.01,54.02) v2(34.97,6.64) v2(34.99,4.32) v2(35.06,115.25) v2(35.15,104.87) v2(35.1,90.06) v2(35.1,87.76) v2(35.1,83.16) v2(35.07,60.84) v2(35.05,10.82) v2(35.15,106.91) v2(35.2,2.11) v2(35.26,128.3) v2(35.3,40.4) v2(35.32,38.21) v2(35.28,27.09) v2(35.51,57.42) v2(35.5,36.44) v2(35.53,7.77) v2(35.56,92.35) v2(35.6,78.33) v2(35.6,76.03) v2(35.59,73.89) v2(35.6,71.43) v2(35.6,69.13) v2(35.58,33.69) v2(35.6,29.55) v2(35.59,9.85) v2(35.7,116.47) v2(35.65,59.68) v2(35.73,46.37) v2(35.74,5.57) v2(35.76,21.77) v2(35.88,108.22) v2(35.93,97.94) v2(35.91,47.96) v2(35.92,44.12) v2(35.9,23.05) v2(35.94,3.18) v2(35.96,66.71) v2(36.02,64.65) v2(35.97,34.41) v2(36.09,127.26) v2(36.11,103.9) v2(36.12,95.2) v2(36.12,61.95) v2(36.13,42.51) v2(36.2,107.14) v2(36.24,93.81) v2(36.24,51.42) v2(36.17,31.95) v2(36.31,117.46) v2(36.28,91.49) v2(36.35,54.75) v2(36.32,53.09) v2(36.31,12.57) v2(36.3,10.87) v2(36.26,8.84) v2(36.36,102.67) v2(36.41,32.84) v2(36.42,30.48) v2(36.5,24.01) v2(36.47,6.64) v2(36.62,56.23) v2(36.66,60.76) v2(36.75,27.41) v2(36.72,26.33) v2(36.76,128.3) v2(36.75,58.95) v2(36.77,57.41) v2(36.9,77) v2(36.89,74.84) v2(36.89,72.54) v2(36.89,70.24) v2(36.89,67.94) v2(36.92,66.71) v2(36.97,63.07) v2(37,20.64) v2(37.03,7.77) v2(37.12,39.25) v2(37.09,9.85) v2(37.17,89.03) v2(37.17,86.73) v2(37.17,84.43) v2(37.17,82.13) v2(37.17,79.83) v2(37.28,45.17) v2(37.26,40.7) v2(37.32,25.39) v2(37.29,12.04) v2(37.51,22.97) v2(37.47,3.13) v2(37.47,1.63) v2(37.59,127.26) v2(37.65,13.28) v2(37.8,21.26) v2(37.8,10.87) v2(37.76,8.84) v2(38.03,51.89) v2(38.03,38.46) v2(37.97,6.64) v2(38.14,106.06) v2(38.1,31.89) v2(38.18,110.27) v2(38.26,128.3) v2(38.3,107.25) v2(38.41,53.74) v2(38.53,7.77) v2(38.57,45.21) v2(38.65,42.54) v2(38.61,12.07) v2(38.59,9.85) v2(38.68,39.48) v2(38.76,112.76) v2(38.79,47.95) v2(38.78,30.49) v2(38.93,102.67) v2(39.05,97.17) v2(39.14,88.79) v2(39.1,37.74) v2(39.08,3.24) v2(39.2,127.25) v2(39.21,99.64) v2(39.21,95.04) v2(39.21,92.74) v2(39.18,90.37) v2(39.2,52.8) v2(39.2,20.81) v2(39.3,31.08) v2(39.3,10.87) v2(39.26,8.84) v2(39.36,13.09) v2(39.55,105.34) v2(39.48,32.64) v2(39.5,21.29) v2(39.47,6.64) v2(39.58,106.28) v2(39.6,45.97) v2(39.58,40.78) v2(39.64,4.38) v2(39.77,108.37) v2(39.83,87.19) v2(39.85,2.17) v2(39.91,83.37) v2(39.91,22.96) v2(40.04,128.31) v2(39.98,110.23) v2(40.03,7.77) v2(40.13,51.6) v2(40.11,12.07) v2(40.09,9.85) v2(40.24,5.57) v2(40.37,24.46) v2(40.38,14.15) v2(40.54,44.15) v2(40.62,73.92) v2(40.64,72.92) v2(40.65,63.83) v2(40.61,39.5) v2(40.58,3.24) v2(40.69,67.36) v2(40.66,64.95) v2(40.74,47.51) v2(40.78,127.26) v2(40.79,42.51) v2(40.8,10.87) v2(40.76,8.84) v2(40.94,52.82) v2(40.86,13.09) v2(40.98,45.93) v2(40.99,31.13) v2(40.97,29.43) v2(40.97,6.64) v2(41.07,109.59) v2(41.1,37.7) v2(41.08,30.49) v2(41.14,4.38) v2(41.33,32.72) v2(41.35,2.17) v2(41.37,128.29) v2(41.39,106.66) v2(41.4,61.2) v2(41.38,55.9) v2(41.48,105.1) v2(41.48,74.37) v2(41.46,58.1) v2(41.53,7.77) v2(41.64,71.88) v2(41.59,9.85) v2(41.68,72.93) v2(41.68,70.86) v2(41.66,69.92) v2(41.68,69.02) v2(41.67,68.13) v2(41.71,67.05) v2(41.69,65.52) v2(41.68,62.82) v2(41.75,14.19) v2(41.74,5.57) v2(41.81,98.04) v2(41.81,95) v2(41.8,93.01) v2(41.82,90.94) v2(41.84,88.75) v2(41.82,86.46) v2(41.83,84.37) v2(41.81,82.15) v2(41.81,80.14) v2(41.81,78.71) v2(41.8,76.8) v2(41.85,75.5) v2(41.76,40.67) v2(41.9,73.66) v2(41.95,53.61) v2(42.1,110.65) v2(42.15,51.68) v2(42.08,3.24) v2(42.18,108.36) v2(42.19,63.95) v2(42.21,44.26) v2(42.28,127.26) v2(42.28,45.84) v2(42.3,32.75) v2(42.3,10.87) v2(42.26,8.84) v2(42.41,105.92) v2(42.38,47.76) v2(42.36,13.09) v2(42.53,102.67) v2(42.55,29.38) v2(42.5,24.15) v2(42.48,22.91) v2(42.47,6.64) v2(42.65,70.82) v2(42.65,69.81) v2(42.65,68.93) v2(42.65,68.12) v2(42.59,31.15) v2(42.64,4.38) v2(42.7,39.42) v2(42.77,98.08) v2(42.85,2.17) v2(42.87,62.72) v2(42.88,52.81) v2(42.95,128.3) v2(43.04,14.11) v2(43.03,7.77) v2(43.09,100.74) v2(43.07,65.51) v2(43.13,60.76) v2(43.13,42.5) v2(43.11,12.07) v2(43.09,9.85) v2(43.24,108.89) v2(43.24,21.66) v2(43.24,5.57) v2(43.27,20.91) v2(43.3,18.12) v2(43.45,105.1) v2(43.38,73.97) v2(43.44,45.25) v2(43.45,64.84) v2(43.53,63.42) v2(43.63,66.75) v2(43.58,3.24) v2(43.69,47.5) v2(43.78,127.26) v2(43.79,73.11) v2(43.8,53.58) v2(43.84,32.73) v2(43.78,18.52) v2(43.8,10.87) v2(43.76,8.84) v2(43.87,76.95) v2(43.87,55.91) v2(43.88,31.14) v2(43.86,13.09) v2(43.97,6.64) v2(44.08,51.61) v2(44.15,40.69) v2(44.14,4.38) v2(44.21,68.63) v2(44.24,58.19) v2(44.23,30.17) v2(44.33,96.06) v2(44.32,22.97) v2(44.35,2.17) v2(44.43,100.13) v2(44.45,128.3) v2(44.5,99.04) v2(44.49,97.65) v2(44.49,63.66) v2(44.52,29.13) v2(44.54,14.11) v2(44.53,7.77) v2(44.64,61.14) v2(44.6,52.84) v2(44.65,46.89) v2(44.65,43.76) v2(44.57,26.5) v2(44.62,21.97) v2(44.61,12.07) v2(44.59,9.85) v2(44.71,74.85) v2(44.74,5.57) v2(44.78,108.42) v2(44.78,45.77) v2(44.84,23.91) v2(44.99,95.28) v2(45.07,102.64) v2(45.11,18.52) v2(45.08,3.24) v2(45.19,71.77) v2(45.24,15.01) v2(45.34,68.73) v2(45.27,63.19) v2(45.33,62.15) v2(45.27,36.55) v2(45.28,30.48) v2(45.3,10.87) v2(45.26,8.84) v2(45.45,127.25) v2(45.42,90.86) v2(45.41,88.58) v2(45.42,86.26) v2(45.39,84.05) v2(45.44,83.09) v2(45.42,79.27) v2(45.43,67.48) v2(45.4,16.82) v2(45.36,13.09) v2(45.48,99.26) v2(45.45,93.08) v2(45.47,69.52) v2(45.48,65.48) v2(45.47,6.64) v2(45.59,109.81) v2(45.58,76.34) v2(45.58,70.5) v2(45.62,68.2) v2(45.62,58.4) v2(45.74,18.09) v2(45.88,56.76) v2(45.95,128.3) v2(46.05,94.86) v2(46.03,23.36) v2(45.95,21) v2(45.99,15.86) v2(46.04,14.11) v2(46.03,7.77) v2(46.15,105.08) v2(46.05,77.06) v2(46.1,37.32) v2(46.11,12.07) v2(46.09,9.85) v2(46.21,41.16) v2(46.22,25.57) v2(46.24,5.57) v2(46.26,61.24) v2(46.3,18.52) v2(46.43,102.6) v2(46.38,32.75) v2(46.45,22.59) v2(46.51,73.14) v2(46.51,61.68) v2(46.69,16.71) v2(46.74,15.01) v2(46.85,93.12) v2(46.85,75.07) v2(46.82,63.1) v2(46.8,10.87) v2(46.76,8.84) v2(46.94,127.26) v2(46.86,13.09) v2(46.98,108.42) v2(46.97,6.64) v2(47.06,92.05) v2(47.19,89.59) v2(47.21,65.52) v2(47.22,56.9) v2(47.2,37.42) v2(47.2,29.12) v2(47.41,60.78) v2(47.37,60.14) v2(47.4,55.25) v2(47.45,30.49) v2(47.42,28.14) v2(47.48,18.12) v2(47.49,15.86) v2(47.54,14.11) v2(47.53,7.77) v2(47.61,128.3) v2(47.58,109.82) v2(47.57,97.2) v2(47.59,84.11) v2(47.59,81.94) v2(47.61,75.49) v2(47.61,12.07) v2(47.59,9.85) v2(47.72,104.14) v2(47.68,96.27) v2(47.67,63.54) v2(47.74,5.57) v2(47.76,102.7) v2(47.75,101.27) v2(47.95,93.12) v2(47.89,78.93) v2(47.92,67.84) v2(47.91,27.24) v2(47.92,25.91) v2(47.91,21.14) v2(47.99,62.15) v2(47.98,22.27) v2(48.1,99.99) v2(48.08,77.39) v2(48.19,16.71) v2(48.24,15.01) v2(48.3,10.87) v2(48.26,8.84) v2(48.44,127.26) v2(48.36,67.46) v2(48.39,24.21) v2(48.36,23.2) v2(48.36,13.09) v2(48.5,104.91) v2(48.49,97.35) v2(48.53,91.18) v2(48.51,30) v2(48.47,6.64) v2(48.62,70.28) v2(48.57,20.63) v2(48.74,18.52) v2(48.76,63.62) v2(48.83,59.9) v2(48.91,102.9) v2(48.89,89.44) v2(49.01,55.07) v2(48.96,24.72) v2(48.99,15.86) v2(49.04,14.11) v2(49.03,7.77) v2(49.11,128.3) v2(49.15,81.57) v2(49.14,75.23) v2(49.11,12.07) v2(49.09,9.85) v2(49.2,80.47) v2(49.17,23.62) v2(49.24,5.57) v2(49.32,101.1) v2(49.31,59.18) v2(49.44,68.04) v2(49.4,21.42) v2(49.44,3.22) v2(49.55,97.22) v2(49.55,95.52) v2(49.55,93.47) v2(49.53,90.38) v2(49.49,69) v2(49.6,99.38) v2(49.56,92.32) v2(49.7,87.6) v2(49.7,85.8) v2(49.71,83.75) v2(49.71,82.13) v2(49.74,79.3) v2(49.7,78.33) v2(49.67,76.88) v2(49.72,61.43) v2(49.68,22.4) v2(49.69,16.71) v2(49.74,15.01) v2(49.78,112.34) v2(49.81,111.31) v2(49.78,108.47) v2(49.77,105.73) v2(49.79,59.05) v2(49.8,10.87) v2(49.76,8.84) v2(49.94,127.26) v2(49.86,13.09) v2(50,115.32) v2(49.97,6.64) v2(50,4.35) v2(50.17,103.17) v2(50.21,101.63) v2(50.21,2.14) v2(50.32,62.14) v2(50.26,56.34) v2(50.3,30.49) v2(50.35,110.35) v2(50.44,65.43) v2(50.35,60.13) v2(50.49,24.57) v2(50.49,15.86) v2(50.54,14.11) v2(50.53,7.77) v2(50.61,128.3) v2(50.64,99.22) v2(50.65,95.27) v2(50.62,23) v2(50.61,12.07) v2(50.59,9.85) v2(50.65,3.18) v2(50.67,97.33) v2(50.7,93.62) v2(50.72,92.37) v2(50.67,90.51) v2(50.74,5.57) v2(50.8,113.63) v2(50.8,112.42) v2(50.82,111.27) v2(50.83,104.41) v2(51.02,67.19) v2(51.01,21.05) v2(51.25,115.22) v2(51.19,16.71) v2(51.24,15.01) v2(51.25,109.2) v2(51.3,10.87) v2(51.26,8.84) v2(51.44,127.26) v2(51.45,110.38) v2(51.38,101.97) v2(51.36,13.09) v2(51.51,61.11) v2(51.51,58.65) v2(51.49,56.35) v2(51.53,53.89) v2(51.47,6.64) v2(51.5,4.35) v2(51.56,19.89) v2(51.71,100.28) v2(51.74,99.24) v2(51.73,97.13) v2(51.75,95.52) v2(51.72,92.63) v2(51.71,90.55) v2(51.85,17.37) v2(51.9,112.43) v2(51.89,111.28) v2(51.98,108.47) v2(51.97,105.73) v2(51.99,15.86) v2(52.04,14.11) v2(52.03,7.77) v2(52.11,128.3) v2(52.11,103.27) v2(52.11,88.46) v2(52.15,85.95) v2(52.15,83.7) v2(52.15,81.69) v2(52.15,76.57) v2(52.13,73.11) v2(52.13,71.69) v2(52.11,12.07) v2(52.09,9.85) v2(52.2,101.82) v2(52.16,79.69) v2(52.19,74) v2(52.24,5.57) v2(52.4,18.29) v2(52.65,60.55) v2(52.74,26.92) v2(52.69,16.71) v2(52.74,15.01) v2(52.83,104.43) v2(52.8,10.87) v2(52.76,8.84) v2(52.94,127.26) v2(52.93,110.37) v2(52.89,58.12) v2(52.91,20.14) v2(52.86,13.09) v2(53.03,21.73) v2(52.97,6.64) v2(53,4.35) v2(53.09,62.65) v2(53.19,108.86) v2(53.21,2.14) v2(53.25,45.95) v2(53.4,66.64) v2(53.38,61.63) v2(53.36,58.85) v2(53.48,43.88) v2(53.49,15.86) v2(53.54,14.11) v2(53.53,7.77) v2(53.61,128.3) v2(53.59,97.36) v2(53.55,25.71) v2(53.65,17.42) v2(53.61,12.07) v2(53.59,9.85) v2(53.66,73.08) v2(53.72,37.01) v2(53.74,30.34) v2(53.74,5.57) v2(53.78,55.74) v2(53.78,32.85) v2(53.94,3.22) v2(54.09,65.31) v2(54.2,107.4) v2(54.17,105.73) v2(54.16,58.97) v2(54.24,15.01) v2(54.29,110.34) v2(54.3,10.87) v2(54.26,8.84) v2(54.44,127.26) v2(54.4,100.47) v2(54.36,13.09) v2(54.53,35.02) v2(54.54,26.91) v2(54.47,6.64) v2(54.5,4.35) v2(54.62,28.01) v2(54.71,69.24) v2(54.71,2.14) v2(54.8,70.22) v2(54.83,22.98) v2(54.8,21.17) v2(54.85,108.85) v2(54.89,102.28) v2(54.86,18.29) v2(54.97,126.01) v2(55.05,31.91) v2(55.04,20.12) v2(54.99,15.86) v2(55.04,14.11) v2(55.03,7.77) v2(55.11,128.3) v2(55.07,111.35) v2(55.11,12.07) v2(55.09,9.85) v2(55.23,104.41) v2(55.16,25.83) v2(55.24,5.57) v2(55.35,99.26) v2(55.33,34.45) v2(55.44,3.22) v2(55.46,71.34) v2(55.48,24.95) v2(55.73,36.81) v2(55.69,16.71) v2(55.74,15.01) v2(55.77,30.36) v2(55.8,10.87) v2(55.76,8.84) v2(55.94,127.26) v2(55.92,64.64) v2(55.91,62.6) v2(55.91,59.18) v2(55.86,13.09) v2(56,107.45) v2(55.96,28.66) v2(55.97,6.64) v2(56,4.35) v2(56.14,103.45) v2(56.19,67.69) v2(56.21,58.45) v2(56.24,26.91) v2(56.2,17.42) v2(56.21,2.14) v2(56.31,61.69) v2(56.26,35.44) v2(56.29,34.01) v2(56.44,124.46) v2(56.37,105.73) v2(56.36,47.26) v2(56.55,108.85) v2(56.54,60.86) v2(56.52,32.91) v2(56.49,24.66) v2(56.5,21.96) v2(56.49,15.86) v2(56.54,14.11) v2(56.53,7.77) v2(56.61,128.3) v2(56.59,62.59) v2(56.61,12.07) v2(56.59,9.85) v2(56.7,100.52) v2(56.73,95.87) v2(56.74,5.57) v2(56.94,3.22) v2(57.05,96.62) v2(56.98,50.74) v2(57.06,104.43) v2(57.09,102.28) v2(57.1,68.37) v2(57.14,56.02) v2(57.11,53.41) v2(57.15,27.85) v2(57.16,31.9) v2(57.16,20.13) v2(57.24,18.29) v2(57.24,15.01) v2(57.26,51.96) v2(57.3,10.87) v2(57.26,8.84) v2(57.44,127.26) v2(57.38,59.57) v2(57.36,13.09) v2(57.45,109.9) v2(57.46,70.13) v2(57.55,66.57) v2(57.46,25.94) v2(57.47,6.64) v2(57.6,61.83) v2(57.68,125.93) v2(57.7,72.22) v2(57.72,35.41) v2(57.78,30.42) v2(57.83,24.57) v2(57.77,23.84) v2(57.83,20.8) v2(57.89,96.85) v2(57.95,34.21) v2(58.04,37.29) v2(58.05,17.37) v2(57.99,15.86) v2(58.04,14.11) v2(58.11,128.3) v2(58.11,59.18) v2(58.11,12.07) v2(58.28,58.48) v2(58.32,28.64) v2(58.45,43.52) v2(58.36,26.92) v2(58.48,54.74) v2(58.48,52.31) v2(58.48,33.06) v2(58.65,103.17) v2(58.65,71.02) v2(58.64,61.18) v2(58.68,123.48) v2(58.69,16.71) v2(58.74,15.01) v2(58.8,20.17) v2(58.8,10.87) v2(58.94,127.26) v2(58.93,95.87) v2(58.95,36.92) v2(58.86,13.09) v2(59.1,54.78) v2(59.08,35.38) v2(59.17,61.12) v2(59.17,59.25) v2(59.16,56.12) v2(59.19,31.96) v2(59.16,21.55) v2(59.3,100.17) v2(59.27,99.3) v2(59.26,68.29) v2(59.3,65.44) v2(59.25,30.39) v2(59.4,110.45) v2(59.5,72.22) v2(59.5,51.08) v2(59.49,18.26) v2(59.49,15.86) v2(59.54,14.11) v2(59.61,128.3) v2(59.61,12.07) v2(59.66,66.76) v2(59.95,107.47) v2(59.88,44.25) v2(59.95,113.35) v2(60.05,112.5) v2(60.01,23.58) v2(60.09,96.85) v2(60.14,60.99) v2(60.1,54.79) v2(60.19,64.46) v2(60.17,56.12) v2(60.19,16.71) v2(60.29,102.54) v2(60.31,59.18) v2(60.42,113.9) v2(60.4,108.85) v2(60.4,100.15) v2(60.36,13.09) v2(60.55,65.22) v2(60.49,20.16) v2(60.55,127.25) v2(60.6,105.67) v2(60.6,35.5) v2(60.61,32.98) v2(60.6,22.1) v2(60.65,51.06) v2(60.9,74.02) v2(60.9,71.3) v2(61.04,14.11) v2(61.11,128.3) v2(61.11,12.07) v2(61.22,43.52) v2(61.2,37.12) v2(61.23,23.9) v2(61.33,95.92) v2(61.35,17.42) v2(61.4,110.45) v2(61.36,99.3) v2(61.38,60.91) v2(61.38,59.17) v2(61.37,54.33) v2(61.45,113.35) v2(61.55,112.5) v2(61.69,123.84) v2(61.71,62.14) v2(61.72,31.86) v2(61.8,73.57) v2(61.78,18.28) v2(61.92,113.9) v2(61.91,25.75) v2(61.86,13.09) v2(61.96,51.93) v2(62.14,127.26) v2(62.24,72.21) v2(62.22,70.12) v2(62.2,29) v2(62.31,126.07) v2(62.27,103.7) v2(62.29,96.85) v2(62.43,99.9) v2(62.44,54.45) v2(62.52,60.55) v2(62.51,59.18) v2(62.46,58.59) v2(62.54,14.11) v2(62.6,73.13) v2(62.64,15.81) v2(62.61,12.07) v2(62.72,128.29) v2(62.75,55.88) v2(62.73,35.22) v2(62.73,23.41) v2(62.75,108.85) v2(62.84,44.25) v2(62.77,32.56) v2(62.88,62.6) v2(62.9,53.9) v2(62.95,113.35) v2(63,112.5) v2(63.11,71.03) v2(63.12,21.13) v2(63.12,19.73) v2(63.23,125) v2(63.33,103.36) v2(63.33,95.87) v2(63.42,113.9) v2(63.44,14.96) v2(63.36,13.09) v2(63.48,100.5) v2(63.48,99.3) v2(63.55,73.89) v2(63.54,69.21) v2(63.5,51) v2(63.47,28.3) v2(63.5,24.25) v2(63.54,16.56) v2(63.64,127.26) v2(63.67,105.5) v2(63.7,26.52) v2(63.9,68.28) v2(63.95,61.52) v2(64.04,72.2) v2(64.04,14.11) v2(64.1,58.37) v2(64.08,18.08) v2(64.11,12.07) v2(64.25,126.1) v2(64.18,101.4) v2(64.25,52.05) v2(64.31,128.3) v2(64.35,112.5) v2(64.34,73.16) v2(64.34,15.71) v2(64.41,102.19) v2(64.45,54.42) v2(64.45,113.35) v2(64.47,103.7) v2(64.5,99.87) v2(64.49,96.85) v2(64.56,71.31) v2(64.7,108.85) v2(64.73,106.7) v2(64.9,70.12) v2(64.9,59.57) v2(64.86,13.09) v2(65.14,127.26) v2(65.55,100.47) v2(65.55,99.27) v2(65.53,95.87) v2(65.54,14.11) v2(65.56,124.82) v2(65.65,68.02) v2(65.65,33.02) v2(65.61,12.07) v2(65.65,110.5) v2(65.75,73.89) v2(65.81,128.3) v2(65.82,72.2) v2(66.05,112.5) v2(66.02,67.11) v2(65.98,35.92) v2(65.99,30.36) v2(65.98,27.3) v2(65.98,24.28) v2(65.98,20.58) v2(66.06,69.22) v2(66.25,101.37) v2(66.17,73.13) v2(66.17,64.48) v2(66.35,108.85) v2(66.34,54.03) v2(66.33,50.74) v2(66.4,66.42) v2(66.36,61.16) v2(66.36,13.09) v2(66.54,59.07) v2(66.59,127.21) v2(66.58,125.81) v2(66.61,102.19) v2(66.6,55.84) v2(66.6,52.97) v2(66.67,103.7) v2(66.69,96.85) v2(66.72,71.03) v2(66.67,70.12) v2(66.71,68.29) v2(66.79,43.88) v2(66.79,32.98) v2(66.83,28.77) v2(66.78,19.85) v2(66.92,34.43) v2(66.89,26.71) v2(66.86,24.69) v2(66.89,21.96) v2(67.04,118.54) v2(66.96,116.76) v2(66.98,65.64) v2(67.11,12.07) v2(67.31,128.3) v2(67.26,106.69) v2(67.3,67.52) v2(67.26,36.58) v2(67.45,60.2) v2(67.55,104.45) v2(67.53,31.84) v2(67.58,29.78) v2(67.61,27.61) v2(67.56,25.65) v2(67.61,23.48) v2(67.61,21) v2(67.61,18.88) v2(67.66,102.8) v2(67.73,95.87) v2(67.95,73.89) v2(67.86,13.09) v2(67.97,73.11) v2(68.09,127.21) v2(68.07,105.5) v2(68.22,67.11) v2(68.37,64.48) v2(68.5,72.21) v2(68.61,12.07) v2(68.7,120.26) v2(68.74,69.21) v2(68.74,59.07) v2(68.76,128.24) v2(68.76,103.7) v2(68.76,101.9) v2(68.8,55.84) v2(68.89,96.85) v2(68.94,71.3) v2(68.99,50.74) v2(69.12,34.43) v2(69.08,29.78) v2(69.11,27.61) v2(69.11,23.48) v2(69.11,21) v2(69.11,18.88) v2(69.18,65.64) v2(69.22,62.38) v2(69.29,70.13) v2(69.42,68.28) v2(69.4,36.58) v2(69.36,13.09) v2(69.46,106.69) v2(69.59,127.21) v2(69.75,65.12) v2(69.73,31.84) v2(69.81,104.45) v2(69.78,102.8) v2(69.81,73.12) v2(69.93,95.87) v2(70.15,73.89) v2(70.11,12.07) v2(70.21,14.75) v2(70.26,128.24) v2(70.27,105.5) v2(70.38,121.04) v2(70.42,67.11) v2(70.45,54.12) v2(70.55,52.97) v2(70.57,64.48) v2(70.58,29.78) v2(70.61,27.61) v2(70.56,25.65) v2(70.61,23.48) v2(70.61,21) v2(70.61,18.88) v2(70.7,110.5) v2(70.7,108.85) v2(70.65,52) v2(70.76,61.16) v2(70.88,103.7) v2(70.88,101.9) v2(70.9,100.45) v2(71,55.84) v2(71.09,127.21) v2(71.16,72.21) v2(71.24,71.03) v2(71.17,12.29) v2(71.32,34.43) v2(71.38,65.64) v2(71.42,62.38) v2(71.5,69.25) v2(71.6,36.58) v2(71.66,106.69) v2(71.74,13.41) v2(71.76,128.24) v2(71.81,70.12) v2(71.85,60.2) v2(71.8,53.02) v2(71.93,31.84) v2(71.92,11.31) v2(71.96,104.48) v2(72.13,95.87) v2(72.12,73.89) v2(72.07,50.74) v2(72.08,29.78) v2(72.11,27.61) v2(72.06,25.65) v2(72.11,23.48) v2(72.11,21) v2(72.11,18.88) v2(72.15,68.28) v2(72.47,105.5) v2(72.47,73.11) v2(72.49,67.13) v2(72.59,127.21) v2(72.6,108.85) v2(72.71,35.9) v2(72.67,12.29) v2(72.77,64.48) v2(72.8,54.02) v2(72.85,51.95) v2(72.83,28.77) v2(72.78,19.85) v2(72.9,110.5) v2(72.91,61.16) v2(72.89,26.71) v2(72.86,24.69) v2(72.95,103.67) v2(72.99,32.98) v2(73.14,59.07) v2(73.06,30.78) v2(73.2,55.84) v2(73.24,13.41) v2(73.26,128.24) v2(73.44,71.3) v2(73.36,65.67) v2(73.39,43.88) v2(73.42,11.31) v2(73.46,120.26) v2(73.54,70.13) v2(73.52,34.43) v2(73.62,62.38) v2(73.58,29.78) v2(73.61,27.61) v2(73.56,25.65) v2(73.61,18.88) v2(73.85,108.85) v2(73.81,52.91) v2(73.8,36.58) v2(73.86,106.69) v2(73.87,72.21) v2(74.05,60.2) v2(74.09,127.21) v2(74.05,114.29) v2(74.12,104.48) v2(74.13,31.84) v2(74.18,116.21) v2(74.17,12.29) v2(74.32,73.89) v2(74.32,69.21) v2(74.27,67.08) v2(74.33,28.77) v2(74.28,19.85) v2(74.39,26.71) v2(74.36,24.69) v2(74.45,42.95) v2(74.65,65.47) v2(74.7,120.26) v2(74.67,105.5) v2(74.74,13.41) v2(74.76,128.24) v2(74.85,67.72) v2(74.9,110.5) v2(74.91,35.9) v2(74.92,11.31) v2(75.08,29.78) v2(75.11,27.61) v2(75.06,25.65) v2(75.11,18.88) v2(75.16,73.11) v2(75.16,61.16) v2(75.2,53.9) v2(75.19,32.98) v2(75.33,50.74) v2(75.26,30.78) v2(75.44,121.08) v2(75.4,55.84) v2(75.53,59.07) v2(75.59,127.21) v2(75.6,103) v2(75.62,64.49) v2(75.59,43.88) v2(75.7,108.85) v2(75.72,104.2) v2(75.72,71.01) v2(75.72,34.43) v2(75.67,12.29) v2(75.83,28.77) v2(75.78,19.85) v2(75.89,26.71) v2(75.86,24.69) v2(75.95,102.1) v2(75.95,101.1) v2(75.95,100.1) v2(75.95,99.1) v2(76.01,52.91) v2(76,36.58) v2(76.06,106.69) v2(76.06,68.19) v2(76.08,65.64) v2(76.21,62.46) v2(76.25,60.2) v2(76.24,13.41) v2(76.26,128.24) v2(76.25,114.29) v2(76.33,31.84) v2(76.42,11.31) v2(76.52,73.89) v2(76.59,72.21) v2(76.58,29.78) v2(76.61,27.61) v2(76.56,25.65) v2(76.61,18.88) v2(76.65,42.95) v2(76.81,116.25) v2(76.9,110.5) v2(76.87,105.5) v2(77.05,69.2) v2(77.02,67.11) v2(77.09,127.21) v2(77.09,121.08) v2(77.11,54.09) v2(77.11,35.9) v2(77.15,70.13) v2(77.17,64.48) v2(77.17,12.29) v2(77.33,28.77) v2(77.28,19.85) v2(77.36,61.16) v2(77.4,57.82) v2(77.39,32.98) v2(77.39,26.71) v2(77.36,24.69) v2(77.5,108.85) v2(77.54,59.07) v2(77.46,30.78) v2(77.7,52) v2(77.74,13.41) v2(77.76,128.24) v2(77.85,55.87) v2(77.79,43.88) v2(77.92,104.2) v2(77.86,73.13) v2(77.92,34.43) v2(77.92,11.31) v2(77.98,71.3) v2(77.98,65.64) v2(78.08,29.78) v2(78.11,27.61) v2(78.06,25.65) v2(78.11,18.88) v2(78.21,62.42) v2(78.21,52.91) v2(78.2,36.58) v2(78.26,106.69) v2(78.26,68.19) v2(78.35,50.74) v2(78.38,114.26) v2(78.45,60.2) v2(78.53,31.84) v2(78.59,127.21) v2(78.72,73.89) v2(78.67,12.29) v2(78.83,28.77) v2(78.78,19.85) v2(78.94,116.31) v2(78.85,42.95) v2(78.89,26.71) v2(78.86,24.69) v2(78.99,70.13) v2(79.07,105.5) v2(79.22,67.11) v2(79.24,13.41) v2(79.26,128.24) v2(79.3,110.5) v2(79.35,108.85) v2(79.3,72.21) v2(79.31,54.09) v2(79.31,35.9) v2(79.37,64.48) v2(79.42,11.31) v2(79.56,120.29) v2(79.56,61.16) v2(79.59,32.98) v2(79.58,29.78) v2(79.61,27.61) v2(79.56,25.65) v2(79.61,18.88) v2(79.74,59.07) v2(79.66,30.78) v2(79.8,55.84) v2(79.95,102.95) v2(79.95,102.35) v2(79.95,101.75) v2(79.95,101.15) v2(79.95,100.55) v2(80.02,69.22) v2(80.09,127.21) v2(80.09,117.32) v2(80.15,106.67) v2(80.12,104.2) v2(80.12,34.43) v2(80.18,65.64) v2(80.22,62.38) v2(80.17,12.29) v2(80.26,71.01) v2(80.33,28.77) v2(80.28,19.85) v2(80.41,52.91) v2(80.4,36.58) v2(80.39,26.71) v2(80.36,24.69) v2(80.55,102.95) v2(80.55,102.35) v2(80.55,101.75) v2(80.55,101.15) v2(80.55,100.55) v2(80.46,68.19) v2(80.55,42.97) v2(80.58,114.26) v2(80.6,73.16) v2(80.65,60.2) v2(80.74,120.31) v2(80.73,31.84) v2(80.74,13.41) v2(80.76,128.24) v2(80.85,52) v2(80.92,116.28) v2(80.9,43.92) v2(80.92,11.31) v2(81.1,108.85) v2(81.08,29.78) v2(81.11,27.61) v2(81.06,25.65) v2(81.11,18.88) v2(81.16,105.5) v2(81.15,102.95) v2(81.15,102.35) v2(81.15,101.75) v2(81.15,101.15) v2(81.15,100.55) v2(81.35,110.5) v2(81.26,73.83) v2(81.42,121.09) v2(81.42,67.11) v2(81.51,54.09) v2(81.51,35.9) v2(81.59,117.32) v2(81.57,64.48) v2(81.7,127.2) v2(81.65,50.74) v2(81.67,12.29) v2(81.75,102.95) v2(81.75,102.35) v2(81.75,101.75) v2(81.75,101.15) v2(81.75,100.55) v2(81.76,61.16) v2(81.79,32.98) v2(81.83,28.77) v2(81.78,19.85) v2(81.94,59.07) v2(81.86,30.78) v2(81.89,26.71) v2(81.86,24.69) v2(81.95,112.55) v2(81.96,72.21) v2(82.08,55.89) v2(82.24,120.31) v2(82.21,104.2) v2(82.25,73.32) v2(82.24,13.41) v2(82.26,128.24) v2(82.35,102.95) v2(82.35,102.35) v2(82.35,101.75) v2(82.35,101.15) v2(82.35,100.55) v2(82.3,42.92) v2(82.32,34.43) v2(82.42,116.28) v2(82.38,65.64) v2(82.42,62.38) v2(82.42,11.31) v2(82.48,71.3) v2(82.61,52.91) v2(82.6,36.58) v2(82.58,29.78) v2(82.61,27.61) v2(82.56,25.65) v2(82.61,18.88) v2(82.73,106.7) v2(82.68,69.24) v2(82.66,68.19) v2(82.77,114.26) v2(82.81,70.13) v2(82.85,60.2) v2(82.9,43.87) v2(82.93,31.84) v2(82.95,108.85) v2(82.95,102.95) v2(82.95,102.35) v2(82.95,101.75) v2(82.95,101.15) v2(82.95,100.55) v2(83.09,117.32) v2(83.15,110.1) v2(83.17,12.29) v2(83.28,127.21) v2(83.28,105.5) v2(83.33,28.77) v2(83.28,19.85) v2(83.39,26.71) v2(83.36,24.69) v2(83.55,102.95) v2(83.55,102.35) v2(83.55,101.75) v2(83.55,101.15) v2(83.55,100.55) v2(83.62,67.11) v2(83.71,73.88) v2(83.73,72.2) v2(83.71,54.09) v2(83.71,35.9) v2(83.74,13.41) v2(83.77,64.48) v2(83.87,128.23) v2(83.92,116.28) v2(83.89,70.12) v2(83.89,68.38) v2(83.89,62.4) v2(83.89,61.16) v2(83.89,59.07) v2(83.89,55.84) v2(83.89,50.74) v2(83.92,11.31) v2(83.99,32.98) v2(84.1,112.55) v2(84.06,30.78) v2(84.08,29.78) v2(84.11,27.61) v2(84.06,25.65) v2(84.11,18.88) v2(84.2,110.5) v2(84.33,104.2) v2(84.52,34.48) v2(84.59,117.32) v2(84.6,108.85) v2(84.59,106.67) v2(84.67,12.29) v2(84.78,127.21) v2(84.83,28.77) v2(84.78,19.85) v2(84.89,26.71) v2(84.86,24.69) v2(84.97,114.26) v2(85.13,31.84) v2(85.24,13.41) v2(85.35,105.47) v2(85.42,116.28) v2(85.42,11.31) v2(85.45,128.24) v2(85.58,29.78) v2(85.61,27.61) v2(85.56,25.65) v2(85.61,18.88) v2(86.09,117.32) v2(86.17,12.29) v2(86.28,127.21) v2(86.33,35.26) v2(86.26,30.78) v2(86.33,28.77) v2(86.28,19.85) v2(86.4,110.5) v2(86.4,104.17) v2(86.39,26.71) v2(86.36,24.69) v2(86.6,33.3) v2(86.74,13.41) v2(86.91,36.63) v2(86.92,11.31) v2(86.95,128.24) v2(86.99,121.03) v2(87.08,29.78) v2(87.11,27.61) v2(87.06,25.65) v2(87.11,18.88) v2(87.54,116.23) v2(87.6,113.99) v2(87.67,12.29) v2(87.83,28.77) v2(87.78,19.85) v2(87.92,127.21) v2(87.9,108.85) v2(87.89,26.71) v2(87.86,24.69) v2(87.96,117.29) v2(87.95,107.35) v2(87.95,105.5) v2(88.24,13.41) v2(88.42,11.31) v2(88.59,128.24) v2(88.58,29.78) v2(88.61,27.61) v2(88.56,25.65) v2(88.61,18.88) v2(88.8,126.53) v2(89.17,12.29) v2(89.33,28.77) v2(89.28,19.85) v2(89.42,127.21) v2(89.43,120.42) v2(89.39,26.71) v2(89.36,24.69) v2(89.74,13.41) v2(89.8,113.99) v2(89.75,108.05) v2(89.75,105.75) v2(89.77,33.13) v2(89.85,35.85) v2(89.92,11.31) v2(90.03,51.88) v2(90.09,128.24) v2(90.15,126.26) v2(90.08,29.78) v2(90.11,27.61) v2(90.06,25.65) v2(90.11,18.88) v2(90.2,54.05) v2(90.25,50.85) v2(90.3,53) v2(90.5,110.5) v2(90.5,84.92) v2(90.65,71.12) v2(90.65,70.12) v2(90.75,73.32) v2(90.75,72.22) v2(90.67,12.29) v2(90.78,19.85) v2(90.92,127.21) v2(90.86,24.69) v2(91.05,68.97) v2(91.14,88.85) v2(91.15,75.02) v2(91.24,13.41) v2(91.42,11.31) v2(91.5,82.35) v2(91.55,79.42) v2(91.55,47.22) v2(91.59,128.24) v2(91.65,126.26) v2(91.6,42.67) v2(91.58,29.78) v2(91.6,28.8) v2(91.61,27.61) v2(91.6,26.7) v2(91.56,25.65) v2(91.61,18.88) v2(91.85,44.82) v2(91.8,36.6) v2(91.97,33.13) v2(92.05,35.85) v2(92.1,34.8) v2(92.17,12.29) v2(92.33,28.77) v2(92.28,19.85) v2(92.42,127.21) v2(92.39,26.71) v2(92.36,24.69) v2(92.47,121) v2(92.65,110) v2(92.74,13.41) v2(92.85,43.72) v2(92.92,11.31) v2(93.01,34.79) v2(93.09,128.24) v2(93.15,126.26) v2(93.08,29.78) v2(93.11,27.61) v2(93.06,25.65) v2(93.11,18.88) v2(93.29,35.86) v2(93.4,24.7) v2(93.55,47.17) v2(93.6,42.62) v2(93.6,28.8) v2(93.72,108.51) v2(93.67,12.29) v2(93.81,113.81) v2(93.85,44.77) v2(93.78,19.85) v2(93.92,127.21) v2(94.17,33.13) v2(94.24,13.41) v2(94.25,35.85) v2(94.42,11.31) v2(94.45,51.95) v2(94.59,128.24) v2(94.65,126.26) v2(94.6,41.92) v2(94.58,29.78) v2(94.56,25.65) v2(94.61,18.88) v2(94.65,28.8) v2(94.85,50.87) v2(94.85,43.67) v2(95.06,119.37) v2(95.12,114.3) v2(95.12,105.44) v2(95.18,109.71) v2(95.16,108.7) v2(95.18,107.36) v2(95.21,34.79) v2(95.2,27.6) v2(95.17,12.29) v2(95.3,104.41) v2(95.28,19.85) v2(95.42,127.21) v2(95.39,26.71) v2(95.36,24.69) v2(95.52,118.21) v2(95.5,47.17) v2(95.49,35.86) v2(95.74,13.41) v2(95.92,101.17) v2(95.92,42.92) v2(95.92,11.31) v2(96.09,128.24) v2(96.15,126.26) v2(96.1,53) v2(96.11,27.61) v2(96.06,25.65) v2(96.11,18.88) v2(96.16,109.32) v2(96.2,108.1) v2(96.17,106.12) v2(96.25,113.33) v2(96.37,33.13) v2(96.49,102.9) v2(96.45,35.85) v2(96.6,41.87) v2(96.74,116.72) v2(96.67,12.29) v2(96.83,28.77) v2(96.78,19.85) v2(96.92,127.21) v2(96.92,43.56) v2(96.89,26.71) v2(96.86,24.69) v2(97.17,114.3) v2(97.18,109.02) v2(97.18,108.38) v2(97.17,107.71) v2(97.18,106.47) v2(97.18,105.85) v2(97.24,13.41) v2(97.36,111.47) v2(97.41,34.79) v2(97.42,11.31) v2(97.51,104.52) v2(97.5,50.87) v2(97.5,47.12) v2(97.59,128.24) v2(97.62,101.17) v2(97.58,29.78) v2(97.61,27.61) v2(97.56,25.65) v2(97.61,18.88) v2(97.72,125.15) v2(97.72,118.21) v2(97.76,126.25) v2(97.84,107.74) v2(97.83,107.1) v2(97.85,106.49) v2(97.85,109.05) v2(97.85,108.4) v2(97.85,105.87) v2(98.03,112.39) v2(97.95,110.2) v2(98.12,95.59) v2(98.2,33.2) v2(98.17,12.29) v2(98.35,54.15) v2(98.35,53) v2(98.3,51.97) v2(98.33,28.77) v2(98.28,19.85) v2(98.45,80.17) v2(98.36,24.69) v2(98.53,127.2) v2(98.55,102.92) v2(98.55,97.05) v2(98.48,93.49) v2(98.54,90.11) v2(98.45,88.55) v2(98.45,86.7) v2(98.52,85.01) v2(98.52,82.4) v2(98.55,76.02) v2(98.58,113.42) v2(98.59,73.32) v2(98.74,13.41) v2(98.85,35.87) v2(98.94,116.72) v2(98.92,11.31) v2(99.09,128.24) v2(99.05,123.88) v2(99.08,29.78) v2(99.11,27.61) v2(99.06,25.65) v2(99.11,18.88) v2(99.21,44.8) v2(99.34,126.26) v2(99.27,43.27) v2(99.42,114.3) v2(99.61,34.79) v2(99.67,12.29) v2(99.78,19.85) v2(99.89,36.81) v2(99.89,26.71) v2(99.86,24.69) v2(100.12,127.21) v2(100.1,118.12) v2(100.24,13.41) v2(100.35,124.51) v2(100.29,123.51) v2(100.42,11.31) v2(100.61,27.61) v2(100.56,25.65) v2(100.61,18.88) v2(100.7,128.23) v2(100.66,113.45) v2(100.84,126.26) v2(100.77,33.13) v2(100.85,35.85) v2(101.2,51.88) v2(101.17,12.29) v2(101.25,44.7) v2(101.28,19.85) v2(101.43,60.56) v2(101.36,58.55) v2(101.36,55.74) v2(101.41,54.33) v2(101.39,26.71) v2(101.36,24.69) v2(101.5,50.82) v2(101.62,127.21) v2(101.74,13.41) v2(101.77,49.16) v2(101.9,43.02) v2(101.92,11.31) v2(101.98,38.05) v2(102,33.1) v2(102.15,48.02) v2(102.15,46.52) v2(102.09,36.81) v2(102.06,25.65) v2(102.11,18.88) v2(102.15,53) v2(102.29,128.24) v2(102.34,126.26) v2(102.41,53.9) v2(102.5,26.15) v2(102.65,34.87) v2(102.67,12.29) v2(102.85,61.83) v2(102.85,59.47) v2(102.78,19.85) v2(102.93,124.5) v2(102.93,44.71) v2(102.86,24.69) v2(103.12,127.21) v2(103.13,49.16) v2(103.24,13.41) v2(103.4,54.3) v2(103.42,11.31) v2(103.5,51.88) v2(103.56,25.65) v2(103.61,18.88) v2(103.79,128.24) v2(103.79,126.2) v2(103.81,55.74) v2(104.15,50.82) v2(104.15,47.97) v2(104.15,46.47) v2(104.17,12.29) v2(104.32,43.02) v2(104.35,24.7) v2(104.5,60.35) v2(104.51,58.23) v2(104.55,53.93) v2(104.57,127.16) v2(104.57,125.13) v2(104.57,123.47) v2(104.58,62.49) v2(104.74,13.41) v2(104.92,11.31) v2(105.1,19.97) v2(105.25,42.12) v2(105.29,128.24) v2(105.29,126.2) v2(105.39,71.08) v2(105.44,70.13) v2(105.36,69.05) v2(105.44,44.14) v2(105.75,35.52) v2(105.67,12.29) v2(106,26.45) v2(106.07,127.16) v2(106.13,106.35) v2(106.12,105.31) v2(106.24,13.41) v2(106.27,113.32) v2(106.33,43.11) v2(106.42,11.31) v2(106.55,14.77) v2(106.74,128.19) v2(106.67,125.15) v2(106.79,126.2) v2(107,25.35) v2(107.17,12.29) v2(107.57,127.16) v2(107.61,108.53) v2(107.63,80.95) v2(107.63,78.32) v2(107.63,76.25) v2(107.63,74.49) v2(107.63,73.05) v2(107.63,63.03) v2(107.63,61.54) v2(107.63,59.61) v2(107.63,57.88) v2(107.64,55.28) v2(107.65,52.92) v2(107.65,51.97) v2(107.6,50.87) v2(107.74,111.97) v2(107.8,91.6) v2(107.8,89) v2(107.8,88) v2(107.81,85.73) v2(107.82,54.06) v2(107.82,44.9) v2(107.99,84.68) v2(108.03,11.33) v2(108.24,128.19) v2(108.29,126.2) v2(108.3,30.2) v2(108.4,28.9) v2(108.57,125.11) v2(108.6,103.6) v2(108.56,82.38) v2(108.56,80.68) v2(108.56,77.85) v2(108.57,75.8) v2(108.61,26.52) v2(108.69,13.93) v2(108.85,19.65) v2(108.75,12.29) v2(108.98,74.85) v2(108.98,62.48) v2(108.98,60.78) v2(108.98,58.71) v2(109,48.27) v2(109,44.15) v2(109.07,127.16) v2(109.19,113.1) v2(109.15,108.52) v2(109.3,111.4) v2(109.3,110.6) v2(109.4,104.4) v2(109.4,103.6) v2(109.47,34.05) v2(109.55,19.27) v2(109.5,15.2) v2(109.53,11.33) v2(109.55,104.97) v2(109.59,27.45) v2(109.74,128.19) v2(109.68,33.06) v2(109.79,126.2) v2(109.9,93) v2(110,91.32) v2(110.1,111.4) v2(110.1,110.6) v2(110.09,51.87) v2(110.09,49.42) v2(110.2,104.4) v2(110.2,103.6) v2(110.2,84.42) v2(110.25,82.67) v2(110.18,78.35) v2(110.25,25.87) v2(110.31,108.24) v2(110.35,86.77) v2(110.3,81.82) v2(110.35,79.87) v2(110.35,75.92) v2(110.27,59.64) v2(110.32,47.57) v2(110.25,12.29) v2(110.41,71.05) v2(110.4,70.12) v2(110.36,63.03) v2(110.39,61.59) v2(110.36,57.92) v2(110.43,33.79) v2(110.35,10.45) v2(110.5,73.37) v2(110.5,45.82) v2(110.57,127.16) v2(110.58,44.37) v2(110.66,114.3) v2(110.71,72.32) v2(110.73,55.15) v2(110.65,16.45) v2(110.9,111.4) v2(110.9,110.6) v2(110.9,92.8) v2(110.92,69.25) v2(110.92,26.46) v2(111.05,113.08) v2(110.95,24.65) v2(110.98,13.94) v2(111.03,11.33) v2(111.1,14.77) v2(111.24,128.19) v2(111.21,89.49) v2(111.15,9.5) v2(111.29,126.2) v2(111.29,88.16) v2(111.29,85.78) v2(111.3,82.82) v2(111.33,77.23) v2(111.29,48.21) v2(111.32,45.04) v2(111.39,50.2) v2(111.49,74.91) v2(111.51,73.58) v2(111.48,49.29) v2(111.53,15.73) v2(111.58,80.85) v2(111.64,62.48) v2(111.64,58.85) v2(111.63,52.72) v2(111.65,72.7) v2(111.66,60.67) v2(111.75,19.67) v2(111.75,12.29) v2(111.85,8.47) v2(111.85,51.9) v2(111.9,43.01) v2(111.88,18.43) v2(111.85,10.45) v2(111.96,114.22) v2(112.05,93.05) v2(111.95,6.01) v2(111.98,3.77) v2(112.07,127.16) v2(112.08,94.65) v2(112.06,1.55) v2(112.23,47.76) v2(112.19,43.97) v2(112.27,89.55) v2(112.28,86.89) v2(112.28,84.46) v2(112.28,82.1) v2(112.26,76.19) v2(112.41,44.89) v2(112.54,109.02) v2(112.55,79.87) v2(112.53,49.01) v2(112.47,46.47) v2(112.53,11.33) v2(112.61,70.13) v2(112.61,63.03) v2(112.61,61.49) v2(112.61,59.77) v2(112.62,57.86) v2(112.58,50.14) v2(112.6,16.3) v2(112.65,7.21) v2(112.74,128.19) v2(112.7,78.29) v2(112.69,14.79) v2(112.65,9.5) v2(112.79,126.2) v2(112.75,4.85) v2(112.75,2.66) v2(112.9,81.07) v2(112.87,26.5) v2(112.96,33.07) v2(112.97,19.82) v2(113.1,93) v2(113.08,77.15) v2(113.15,42.97) v2(113.22,108.34) v2(113.19,88.43) v2(113.2,85.69) v2(113.19,82.59) v2(113.32,89.45) v2(113.25,12.29) v2(113.35,8.47) v2(113.45,114.22) v2(113.43,47.63) v2(113.38,44.85) v2(113.35,10.45) v2(113.48,94.65) v2(113.45,6.01) v2(113.48,3.77) v2(113.57,127.16) v2(113.57,73.57) v2(113.56,71.05) v2(113.6,69.22) v2(113.61,62.2) v2(113.6,60.23) v2(113.59,58.08) v2(113.56,1.55) v2(113.72,91.34) v2(113.74,77.81) v2(113.66,74.74) v2(113.81,46.55) v2(113.75,27.6) v2(113.98,81.55) v2(114.03,11.33) v2(114.07,86.85) v2(114.07,84.43) v2(114.15,79.88) v2(114.14,78.41) v2(114.1,43.4) v2(114.15,7.21) v2(114.24,128.19) v2(114.2,47.32) v2(114.15,9.5) v2(114.29,126.2) v2(114.28,113.19) v2(114.27,109.43) v2(114.31,48.54) v2(114.26,41.87) v2(114.25,4.85) v2(114.25,2.66) v2(114.38,90.43) v2(114.4,45.51) v2(114.55,55.13) v2(114.55,52.29) v2(114.54,26.6) v2(114.59,82.53) v2(114.62,71.93) v2(114.58,63.03) v2(114.58,61.4) v2(114.58,60.11) v2(114.57,58.81) v2(114.58,57.81) v2(114.65,27.58) v2(114.62,24.66) v2(114.69,73.56) v2(114.67,70.13) v2(114.85,94.65) v2(114.75,12.29) v2(114.85,8.47) v2(114.87,89.51) v2(114.88,53.06) v2(114.85,16.91) v2(114.86,14.8) v2(114.85,10.45) v2(114.99,87.77) v2(115,77.31) v2(114.98,46.21) v2(114.95,6.01) v2(114.98,3.77) v2(115.07,127.16) v2(115.06,108.01) v2(115.05,84.41) v2(115.12,45.23) v2(115.1,43.63) v2(115.14,33.06) v2(115.06,1.55) v2(115.18,71.03) v2(115.16,50.32) v2(115.17,22.32) v2(115.17,19.82) v2(115.29,13.93) v2(115.44,74.73) v2(115.39,69.23) v2(115.43,62.22) v2(115.48,42.01) v2(115.53,11.33) v2(115.65,79.92) v2(115.58,47.28) v2(115.57,25.7) v2(115.59,23.4) v2(115.65,7.21) v2(115.74,128.19) v2(115.65,9.5) v2(115.79,126.2) v2(115.78,113.19) v2(115.77,91.87) v2(115.79,82.85) v2(115.78,59.21) v2(115.75,4.85) v2(115.75,2.66) v2(115.9,90.42) v2(115.93,15.73) v2(116.03,92.86) v2(116.05,81.05) v2(116.04,78.02) v2(116,51.29) v2(116.07,94.65) v2(116.05,57.85) v2(116.07,48.83) v2(116.12,45.24) v2(116.34,108.94) v2(116.28,21.1) v2(116.28,18.43) v2(116.25,12.29) v2(116.35,8.47) v2(116.45,114.22) v2(116.37,76.42) v2(116.36,73.04) v2(116.35,71.1) v2(116.36,70.13) v2(116.38,63.03) v2(116.4,61.7) v2(116.38,50.39) v2(116.36,46.28) v2(116.43,42.8) v2(116.45,41.97) v2(116.35,10.45) v2(116.55,111.4) v2(116.46,107.29) v2(116.54,89.61) v2(116.55,47.98) v2(116.48,24.65) v2(116.45,6.01) v2(116.48,3.77) v2(116.57,127.16) v2(116.56,26.59) v2(116.56,1.55) v2(116.98,27.59) v2(117.03,11.33) v2(117.1,79.97) v2(117.05,16.91) v2(117.06,14.8) v2(117.15,7.21) v2(117.24,128.19) v2(117.19,58.89) v2(117.18,41.53) v2(117.15,9.5) v2(117.29,126.2) v2(117.35,111.4) v2(117.35,110.6) v2(117.33,84.38) v2(117.34,51.38) v2(117.29,46.54) v2(117.25,4.85) v2(117.25,2.66) v2(117.44,113.18) v2(117.44,81.18) v2(117.37,77.61) v2(117.41,73.63) v2(117.42,72.19) v2(117.4,71.03) v2(117.42,69.23) v2(117.39,62.27) v2(117.37,22.32) v2(117.37,19.82) v2(117.46,52.72) v2(117.47,49.97) v2(117.54,47.46) v2(117.49,13.93) v2(117.64,48.81) v2(117.75,43.97) v2(117.8,88.23) v2(117.8,86.45) v2(117.77,57.87) v2(117.75,12.29) v2(117.85,8.47) v2(117.95,114.22) v2(117.93,92.57) v2(117.89,23.4) v2(117.85,10.45) v2(117.95,6.01) v2(117.98,3.77) v2(118.07,127.16) v2(118.13,15.73) v2(118.06,1.55) v2(118.15,111.4) v2(118.15,110.6) v2(118.31,91.36) v2(118.27,82.84) v2(118.4,77.57) v2(118.44,61.85) v2(118.47,74.57) v2(118.48,72.99) v2(118.52,71.5) v2(118.51,70.13) v2(118.47,63.03) v2(118.48,21.1) v2(118.48,18.43) v2(118.53,11.33) v2(118.61,89.47) v2(118.59,52.73) v2(118.65,7.21) v2(118.74,128.19) v2(118.7,80.07) v2(118.65,9.5) v2(118.78,113.19) v2(118.75,4.85) v2(118.75,2.66) v2(118.91,126.19) v2(118.94,106.28) v2(118.9,41.57) v2(118.99,81.62) v2(118.95,45.88) v2(119.12,49.38) v2(119.32,52.43) v2(119.25,16.91) v2(119.26,14.8) v2(119.25,12.29) v2(119.35,8.47) v2(119.45,114.22) v2(119.41,84.41) v2(119.4,48.3) v2(119.38,45.05) v2(119.43,27.57) v2(119.35,10.45) v2(119.46,50.79) v2(119.45,6.01) v2(119.48,3.77) v2(119.63,94.65) v2(119.59,73.66) v2(119.59,72.37) v2(119.64,69.23) v2(119.6,62.27) v2(119.56,1.55) v2(119.68,127.15) v2(119.65,71.02) v2(119.69,13.93) v2(119.85,90.47) v2(119.8,77.99) v2(119.9,106.65) v2(119.91,92.94) v2(120,92.07) v2(119.97,80.3) v2(120.03,57.66) v2(120,45.19) v2(120.05,41.51) v2(120.03,11.33) v2(120.24,128.19) v2(120.25,113.18) v2(120.23,61.4) v2(120.21,23.37) v2(120.15,9.5) v2(120.15,7.35) v2(120.31,31.24) v2(120.33,15.73) v2(120.25,4.85) v2(120.25,2.66) v2(120.39,88.39) v2(120.44,76.42) v2(120.49,126.2) v2(120.54,82.82) v2(120.5,10.45) v2(120.5,8.47) v2(120.55,6.02) v2(120.95,80.02) v2(120.93,72.29) v2(120.9,70.15) v2(120.95,31.27) v2(120.95,12.57) v2(121.03,62.55) v2(120.98,3.77) v2(121.12,114.22) v2(121.07,81.65) v2(121.1,64.49) v2(121.06,1.55) v2(121.2,74.71) v2(121.16,61.4) v2(121.27,127.16) v2(121.32,123.54) v2(121.5,106.82) v2(121.45,89.51) v2(121.47,84.4) v2(121.47,77.35) v2(121.48,73.63) v2(121.51,50.34) v2(121.54,44.89) v2(121.5,31.27) v2(121.45,16.91) v2(121.46,14.8) v2(121.56,113.08) v2(121.57,91.94) v2(121.6,53.12) v2(121.64,51.77) v2(121.72,105.57) v2(121.75,80.37) v2(121.75,78.47) v2(121.7,49.43) v2(121.65,9.5) v2(121.7,7.4) v2(121.76,82.87) v2(121.8,71.02) v2(121.8,11.4) v2(121.75,4.85) v2(121.75,2.66) v2(121.85,128.18) v2(121.99,126.2) v2(122.05,94.65) v2(122.2,23.35) v2(122.25,12.29) v2(122.35,8.47) v2(122.35,10.45) v2(122.5,62.32) v2(122.53,15.73) v2(122.45,6.01) v2(122.48,3.77) v2(122.62,96.28) v2(122.56,1.55) v2(122.77,127.16) v2(122.88,21.1) v2(123.03,63.87) v2(123.11,61.44) v2(123.09,22.34) v2(123.15,7.21) v2(123.19,105.59) v2(123.2,73.02) v2(123.25,71.47) v2(123.21,62.55) v2(123.15,9.5) v2(123.27,123.54) v2(123.25,4.85) v2(123.25,2.66) v2(123.43,128.19) v2(123.45,78.17) v2(123.49,126.2) v2(123.53,69.1) v2(123.53,24.62) v2(123.62,74.42) v2(123.7,76.42) v2(123.65,16.91) v2(123.66,14.8) v2(123.85,77.31) v2(123.83,73.65) v2(123.76,72.28) v2(123.76,70.13) v2(123.75,20.5) v2(123.85,8.47) v2(123.9,58.17) v2(123.85,10.45) v2(123.97,22.32) v2(123.95,6.01) v2(123.98,3.77) v2(124.08,114.19) v2(124.12,74.77) v2(124.15,71.12) v2(124.15,68.67) v2(124.09,13.93) v2(124.06,1.55) v2(124.15,111.4) v2(124.15,110.6) v2(124.27,127.16) v2(124.28,23.48) v2(124.45,78.12) v2(124.41,25.65) v2(124.43,12.52) v2(124.65,7.21) v2(124.73,15.73) v2(124.65,9.5) v2(124.77,76.42) v2(124.75,4.85) v2(124.75,2.66) v2(124.93,128.19) v2(124.95,111.4) v2(124.95,110.6) v2(125.1,106.64) v2(125.15,126.23) v2(125.45,6.01) v2(125.48,3.77) v2(125.62,114.22) v2(125.58,71.03) v2(125.58,69.21) v2(125.6,63.82) v2(125.6,62.57) v2(125.6,61.67) v2(125.56,1.55) v2(125.71,11.28) v2(125.75,111.4) v2(125.75,110.6) v2(125.84,16.95) v2(125.93,127.19) v2(125.93,101.43) v2(125.95,74.52) v2(125.9,20.95) v2(125.86,14.8) v2(125.99,13.47) v2(126.05,73.25) v2(126.15,7.21) v2(126.35,77.27) v2(126.25,4.85) v2(126.25,2.66) v2(126.6,128.22) v2(126.65,126.23) v2(126.73,12.52) v2(126.9,103.1) v2(126.9,102.3) v2(126.9,10.09) v2(127.05,3.78) v2(127.2,111.5) v2(127.17,1.54) v2(127.43,127.19) v2(127.44,114.32) v2(127.44,8.85) v2(127.7,103.1) v2(127.7,102.3) v2(127.65,74.59) v2(127.74,73.67) v2(127.66,11.24) v2(127.95,4.85) v2(127.95,2.66) v2(128.1,128.22) v2(128.15,126.23) v2(128.27,9.59) v2(128.7,106.6) v2(128.71,69.13) v2(128.72,11.79) v2(128.68,3.77) v2(128.75,1.55) v2(128.93,127.19) v2(129.11,7.7) v2(129.15,103.1) v2(129.15,102.3) v2(129.24,66.99) v2(129.32,70.13) v2(129.45,81.6) v2(129.45,76.42) v2(129.45,74.67) v2(129.45,73.32) v2(129.42,71.39) v2(129.45,4.85) v2(129.45,2.66) v2(129.5,91.27) v2(129.5,89.62) v2(129.5,88.12) v2(129.5,87.37) v2(129.5,85.47) v2(129.5,82.77) v2(129.5,79.02) v2(129.5,77.32) v2(129.6,128.22) v2(129.65,126.23) v2(129.66,22.73) v2(129.75,12.62) v2(129.88,11.06) v2(129.87,9.33) v2(130.18,3.77) v2(130.25,1.55) v2(130.43,127.19) v2(130.94,7.64) v2(130.95,4.85) v2(130.95,2.66) v2(131.1,128.22) v2(131.15,126.23) v2(131.68,3.77) v2(131.75,1.55) v2(131.93,127.19) v2(132.2,103.57) v2(132.21,19.38) v2(132.24,14.63) v2(132.24,12.12) v2(132.35,80.57) v2(132.35,71.37) v2(132.31,24.49) v2(132.28,21.88) v2(132.35,30.97) v2(132.36,17.53) v2(132.45,4.85) v2(132.45,2.66) v2(132.6,128.22) v2(132.63,77.43) v2(132.63,76.42) v2(132.59,41.53) v2(132.6,40.62) v2(132.65,126.23) v2(132.72,36.44) v2(132.68,7.7) v2(132.8,51.92) v2(132.8,50.47) v2(132.8,37.07) v2(132.95,92.12) v2(133.15,78.07) v2(133.08,61.55) v2(133.25,49.62) v2(133.18,3.77) v2(133.31,28.59) v2(133.34,11) v2(133.25,1.55) v2(133.43,127.19) v2(133.45,20.69) v2(133.45,17.3) v2(133.52,62.83) v2(133.49,57.75) v2(133.47,18.6) v2(133.5,16.4) v2(133.55,23.28) v2(133.77,104.92) v2(133.8,92.17) v2(133.86,26.92) v2(133.95,4.85) v2(133.95,2.66) v2(134.03,96.57) v2(134.1,128.22) v2(134.11,125.02) v2(134.14,88.4) v2(134.15,126.23) v2(134.2,38.27) v2(134.3,93.95) v2(134.3,53.72) v2(134.3,53.02) v2(134.3,52.37) v2(134.4,32.8) v2(134.41,19.38) v2(134.44,14.63) v2(134.44,12.12) v2(134.51,24.49) v2(134.48,21.88) v2(134.56,17.53) v2(134.69,26.05) v2(134.68,8.45) v2(134.68,3.77) v2(134.8,41.53) v2(134.75,1.55) v2(134.93,127.19) v2(135,27.82) v2(135.12,123.44) v2(135.39,113.21) v2(135.45,49.42) v2(135.45,17.55) v2(135.45,4.85) v2(135.45,2.66) v2(135.53,94.37) v2(135.47,91.66) v2(135.5,89.58) v2(135.49,87.51) v2(135.5,84.22) v2(135.51,13.31) v2(135.54,11) v2(135.6,128.22) v2(135.6,86.05) v2(135.65,20.69) v2(135.65,104.15) v2(135.75,30.72) v2(135.7,26.02) v2(135.67,18.6) v2(135.7,16.4) v2(135.77,126.22) v2(135.85,78.07) v2(135.85,76.82) v2(135.85,36.97) v2(135.79,26.76) v2(135.9,82.17) v2(135.9,79.41) v2(135.99,95.91) v2(136.15,90.35) v2(136.2,81.77) v2(136.2,41.52) v2(136.15,40.61) v2(136.18,3.77) v2(136.3,97.62) v2(136.3,83.57) v2(136.35,32.82) v2(136.25,1.55) v2(136.45,85.77) v2(136.54,127.18) v2(136.46,38.48) v2(136.61,19.38) v2(136.64,14.63) v2(136.64,12.12) v2(136.65,125.02) v2(136.7,36.97) v2(136.71,24.49) v2(136.68,21.88) v2(136.66,9.74) v2(136.8,118.92) v2(136.82,67.33) v2(136.76,17.53) v2(136.91,117.27) v2(136.93,115.08) v2(136.95,76.77) v2(136.89,6.06) v2(136.95,4.85) v2(136.95,2.66) v2(137.1,128.22) v2(137.15,74.47) v2(137.05,69.1) v2(137.1,31.27) v2(137.2,26.77) v2(137.51,102.86) v2(137.54,100.83) v2(137.5,90.52) v2(137.65,91.72) v2(137.64,86.39) v2(137.65,54.82) v2(137.65,13.95) v2(137.73,95.74) v2(137.68,82.58) v2(137.75,81.22) v2(137.7,79.93) v2(137.69,40.63) v2(137.74,11) v2(137.68,3.77) v2(137.82,97.55) v2(137.75,94.05) v2(137.8,53.27) v2(137.85,20.69) v2(137.75,1.55) v2(137.92,126.13) v2(137.9,37.95) v2(137.95,23.28) v2(137.87,18.6) v2(137.9,16.4) v2(138.01,31.76) v2(138.13,127.19) v2(138.13,123.76) v2(138.34,6.92) v2(138.4,25.97) v2(138.45,24.57) v2(138.45,21.9) v2(138.45,2.66) v2(138.52,89.52) v2(138.49,81.99) v2(138.5,80.7) v2(138.6,103.25) v2(138.55,79.48) v2(138.71,128.21) v2(138.68,112.63) v2(138.67,91.58) v2(138.7,53.47) v2(138.75,52.77) v2(138.76,77.61) v2(138.8,51.37) v2(138.8,30.72) v2(138.81,19.38) v2(138.84,14.63) v2(138.89,114.98) v2(138.91,32.88) v2(138.92,12.53) v2(138.86,9.74) v2(138.99,101.14) v2(139.02,26.74) v2(139.06,105.34) v2(139.1,54.75) v2(139.2,109.6) v2(139.25,102.45) v2(139.34,97.49) v2(139.25,1.55) v2(139.55,111.57) v2(139.5,36.95) v2(139.55,23.25) v2(139.63,127.19) v2(139.62,117.61) v2(139.75,39.07) v2(139.81,119.7) v2(139.8,76.57) v2(139.8,25.9) v2(139.85,13.95) v2(139.9,77.37) v2(139.94,11) v2(139.95,2.66) v2(139.96,44.41) v2(139.96,31.87) v2(140.05,20.69) v2(140.14,112.78) v2(140.1,67.05) v2(140.07,18.6) v2(140.1,16.4) v2(140.14,6.99) v2(140.15,63.75) v2(140.15,47.93) v2(140.19,39.91) v2(140.29,128.22) v2(140.29,118.64) v2(140.35,115.08) v2(140.53,21.93) v2(140.58,85.47) v2(140.64,84.14) v2(140.62,82.86) v2(140.59,81.55) v2(140.55,24.49) v2(140.7,109.15) v2(140.71,104.65) v2(140.85,30.92) v2(140.85,29.52) v2(140.8,25.3) v2(140.92,1.55) v2(141.01,19.38) v2(141.04,14.63) v2(141.04,12.53) v2(141.13,127.19) v2(141.15,123.55) v2(141.12,117.61) v2(141.15,111.57) v2(141.09,52.72) v2(141.1,44.02) v2(141.06,37.94) v2(141.1,26.9) v2(141.06,9.74) v2(141.25,119.72) v2(141.31,36.99) v2(141.55,78.12) v2(141.62,23.27) v2(141.62,2.66) v2(141.79,128.22) v2(141.79,118.64) v2(141.86,115.06) v2(142.01,112.73) v2(142,76.27) v2(142,72.72) v2(142,69.82) v2(142,68.42) v2(142,65.72) v2(142.05,62.37) v2(142.05,59.97) v2(142.05,13.95) v2(141.95,6.97) v2(142.15,48.02) v2(142.14,11) v2(142.25,20.69) v2(142.27,32.83) v2(142.27,18.6) v2(142.26,5.01) v2(142.42,1.55) v2(142.53,125.41) v2(142.55,51.22) v2(142.55,43.97) v2(142.5,43.02) v2(142.57,127.13) v2(142.62,117.61) v2(142.6,54.47) v2(142.6,31) v2(142.81,27.04) v2(142.79,24.49) v2(142.84,16.8) v2(143.05,93.47) v2(143.05,91.72) v2(143.05,90.07) v2(142.97,37.1) v2(142.96,6.12) v2(143.01,3.87) v2(143.1,88.72) v2(143.12,2.66) v2(143.2,96.92) v2(143.2,96.02) v2(143.21,43.18) v2(143.21,19.38) v2(143.29,128.22) v2(143.29,118.64) v2(143.26,34.52) v2(143.26,9.74) v2(143.45,12.88) v2(143.55,80.05) v2(143.49,31.58) v2(143.61,87.12) v2(143.58,82.81) v2(143.65,73.68) v2(143.65,66.82) v2(143.7,86.07) v2(143.7,77.82) v2(143.7,67.86) v2(143.8,72.37) v2(143.8,65.17) v2(143.75,63.4) v2(143.83,51.22) v2(143.76,5.01) v2(143.95,111.57) v2(143.95,32.46) v2(143.9,29.49) v2(143.88,25.83) v2(143.9,23.2) v2(143.87,20.64) v2(143.92,1.55) v2(144.02,48.04) v2(144.07,127.13) v2(144.12,117.61) v2(144.09,40.3) v2(144.07,15.37) v2(144.26,84.19) v2(144.25,42.47) v2(144.29,41.17) v2(144.47,18.6) v2(144.46,6.12) v2(144.51,3.87) v2(144.6,116.65) v2(144.62,2.66) v2(144.74,128.17) v2(144.67,114.13) v2(144.75,111.57) v2(144.7,96.04) v2(144.73,72.75) v2(144.75,54.47) v2(144.7,34.6) v2(144.79,118.64) v2(144.8,106.05) v2(144.83,102.94) v2(144.85,92.2) v2(144.84,74.9) v2(144.79,74.09) v2(144.87,107.75) v2(144.88,71.94) v2(144.91,36.79) v2(144.89,27.07) v2(144.86,24.51) v2(145.02,126.34) v2(145.03,85.13) v2(145,84.22) v2(145.01,79.73) v2(144.98,77.27) v2(145.03,42.96) v2(144.99,32.45) v2(144.97,21.98) v2(144.98,19.32) v2(144.95,16.77) v2(145.13,88.93) v2(145.13,87.02) v2(145.06,82.38) v2(145.1,70.57) v2(145.15,66.67) v2(145.11,41.68) v2(145.11,31.04) v2(145.11,8.51) v2(145.2,68.92) v2(145.25,65.27) v2(145.2,63.67) v2(145.16,11.19) v2(145.26,5.01) v2(145.42,1.55) v2(145.46,105.1) v2(145.57,127.13) v2(145.58,119.42) v2(145.62,117.61) v2(145.71,115.14) v2(145.7,106.91) v2(145.69,71.13) v2(145.65,39.69) v2(145.75,38.49) v2(145.8,105.98) v2(145.8,104.39) v2(145.79,102.01) v2(145.77,95.27) v2(145.78,94.05) v2(145.83,52.85) v2(145.76,34.81) v2(145.75,13.9) v2(145.94,33.33) v2(145.86,29.49) v2(145.95,20.66) v2(146.05,108.86) v2(146.03,90) v2(146.02,88.02) v2(146.03,85.11) v2(146,84.22) v2(146.04,78.48) v2(145.99,51.15) v2(146,46.07) v2(145.96,25.85) v2(145.97,23.22) v2(145.96,6.12) v2(146.01,3.87) v2(146.08,40.51) v2(146.05,18.11) v2(146.12,2.66) v2(146.24,128.17) v2(146.31,37.02) v2(146.33,34.81) v2(146.27,15.37) v2(146.54,107.75) v2(146.45,31.59) v2(146.59,105.99) v2(146.63,66.13) v2(146.65,9.86) v2(146.7,118.54) v2(146.7,116.53) v2(146.71,114.08) v2(146.72,73.23) v2(146.66,68.69) v2(146.85,121.38) v2(146.77,111.91) v2(146.84,103.72) v2(146.76,96.37) v2(146.84,94.01) v2(146.75,63.45) v2(146.76,5.01) v2(146.91,102.56) v2(146.87,71.96) v2(146.9,54.47) v2(146.86,39.54) v2(146.92,1.55) v2(146.97,105.15) v2(146.96,92.06) v2(146.99,88.92) v2(146.98,87.01) v2(147.03,86.04) v2(147,84.22) v2(147,82.42) v2(146.98,79.77) v2(146.98,77.33) v2(147.02,73.83) v2(147.05,27.12) v2(147.02,24.56) v2(147.05,22.01) v2(147.03,16.79) v2(147.07,127.13) v2(147.07,122.75) v2(147.06,19.35) v2(147.17,12.41) v2(147.52,34.09) v2(147.52,33.1) v2(147.46,6.12) v2(147.51,3.87) v2(147.63,115.14) v2(147.57,44.7) v2(147.61,38.49) v2(147.62,2.66) v2(147.74,128.17) v2(147.68,69.83) v2(147.73,67.48) v2(147.85,119.38) v2(147.82,117.55) v2(147.8,113.11) v2(147.83,108.89) v2(147.81,64.51) v2(147.79,37.01) v2(147.79,34.81) v2(147.84,29.51) v2(147.87,126.34) v2(147.87,107.98) v2(147.92,105.87) v2(147.91,104.78) v2(147.94,103.81) v2(147.91,102.04) v2(147.91,95.51) v2(147.94,92.05) v2(147.95,82.96) v2(147.94,78.78) v2(147.9,70.65) v2(147.88,50.98) v2(147.98,74.19) v2(147.95,13.9) v2(148.09,71.91) v2(148.13,39.87) v2(148.12,25.91) v2(148.13,20.64) v2(148.13,18.13) v2(148.21,42.94) v2(148.16,23.2) v2(148.33,116.52) v2(148.29,111.67) v2(148.33,52.85) v2(148.26,5.01) v2(148.42,1.55) v2(148.47,15.37) v2(148.57,127.13) v2(148.62,10.88) v2(148.74,68.72) v2(148.83,104.71) v2(148.83,102.49) v2(148.85,95.85) v2(148.85,94.3) v2(148.83,85.58) v2(148.85,66.1) v2(148.85,63.45) v2(148.84,38.49) v2(148.78,37.01) v2(148.89,107.58) v2(148.87,106.83) v2(148.91,79.77) v2(148.92,77.34) v2(149.04,108.86) v2(149,91.85) v2(148.95,84.27) v2(149.05,54.47) v2(149.04,34.14) v2(149.04,33.11) v2(148.96,6.12) v2(149.01,3.87) v2(149.12,27.15) v2(149.1,24.59) v2(149.12,2.66) v2(149.24,128.17) v2(149.15,88.65) v2(149.15,87.75) v2(149.18,74.26) v2(149.24,34.81) v2(149.23,21.98) v2(149.24,19.32) v2(149.21,16.77) v2(149.29,122.68) v2(149.35,72.88) v2(149.35,29.52) v2(149.39,90.61) v2(149.37,12.41) v2(149.5,119.39) v2(149.5,73.7) v2(149.58,43.57) v2(149.76,69.85) v2(149.81,67.5) v2(149.76,5.01) v2(149.92,1.55) v2(150.07,127.13) v2(150.13,85.57) v2(150.19,38.49) v2(150.21,37) v2(150.22,34.81) v2(150.2,25.93) v2(150.23,23.22) v2(150.21,20.66) v2(150.25,15.32) v2(150.15,13.9) v2(150.32,84.3) v2(150.31,18.11) v2(150.54,68.69) v2(150.52,66.13) v2(150.51,44.17) v2(150.51,40.63) v2(150.54,34.08) v2(150.54,33.15) v2(150.51,3.87) v2(150.62,120.32) v2(150.55,64.1) v2(150.62,2.66) v2(150.74,128.17) v2(150.75,124.52) v2(150.66,118.69) v2(150.71,116.22) v2(150.75,114.81) v2(150.72,52.88) v2(150.75,29.52) v2(150.78,113.47) v2(150.76,111.49) v2(150.77,90.62) v2(150.82,42.2) v2(150.82,10.88) v2(150.93,103.69) v2(150.91,81.51) v2(150.96,126.29) v2(150.97,104.7) v2(150.96,73.14) v2(151.01,43.67) v2(151.14,96.92) v2(151.09,74.43) v2(151.12,60.33) v2(151.19,114.39) v2(151.25,108.87) v2(151.18,91.83) v2(151.22,85.62) v2(151.17,62.86) v2(151.22,12.4) v2(151.26,106.98) v2(151.33,99.09) v2(151.29,94.91) v2(151.29,88.62) v2(151.28,27.12) v2(151.25,24.56) v2(151.31,22.01) v2(151.32,19.35) v2(151.29,16.79) v2(151.26,5.01) v2(151.42,1.55) v2(151.52,122.01) v2(151.53,87.92) v2(151.5,65.15) v2(151.57,127.13) v2(151.56,69.83) v2(151.62,67.48) v2(151.7,56.72) v2(151.74,38.07) v2(151.82,84.38) v2(151.85,71.77) v2(151.85,54.47) v2(151.95,45.32) v2(151.86,42.46) v2(151.92,34.19) v2(152.05,33.13) v2(152.01,3.87) v2(152.12,2.66) v2(152.24,128.17) v2(152.22,108.64) v2(152.22,107.03) v2(152.22,105.99) v2(152.22,103.7) v2(152.23,73.5) v2(152.16,63.44) v2(152.19,60.41) v2(152.19,52.88) v2(152.2,40.82) v2(152.17,40.14) v2(152.3,112.08) v2(152.28,104.78) v2(152.27,94.58) v2(152.25,62.29) v2(152.33,37.04) v2(152.3,34.81) v2(152.41,116.22) v2(152.45,110.67) v2(152.4,97.45) v2(152.39,43.38) v2(152.35,25.91) v2(152.39,18.13) v2(152.52,113.75) v2(152.51,95.65) v2(152.55,20.64) v2(152.55,66.25) v2(152.59,41.86) v2(152.63,28.83) v2(152.57,23.2) v2(152.78,90.04) v2(152.79,81.74) v2(152.8,68.69) v2(152.85,51.02) v2(152.92,1.55) v2(153.07,127.13) v2(153.11,90.66) v2(153.05,76.61) v2(153.14,65.2) v2(153.15,74.53) v2(153.19,71.96) v2(153.24,63.93) v2(153.17,36.81) v2(153.26,62.67) v2(153.28,34.83) v2(153.33,24.59) v2(153.36,81.01) v2(153.37,73.66) v2(153.4,60.13) v2(153.36,27.15) v2(153.54,122.64) v2(153.45,113.09) v2(153.45,111.85) v2(153.46,106.73) v2(153.49,104.79) v2(153.5,103.68) v2(153.47,97.14) v2(153.5,96.42) v2(153.46,40.54) v2(153.45,34.19) v2(153.55,32.78) v2(153.51,3.87) v2(153.56,38.75) v2(153.64,21.98) v2(153.62,2.66) v2(153.74,128.17) v2(153.7,114.06) v2(153.75,110.67) v2(153.73,89.32) v2(153.72,84.33) v2(153.69,43.39) v2(153.7,29.42) v2(153.66,19.32) v2(153.73,17.47) v2(153.76,108.53) v2(153.83,95.13) v2(153.82,69.83) v2(153.8,56.72) v2(153.88,82.19) v2(153.88,67.48) v2(153.97,126.29) v2(154.05,91.68) v2(154,88.22) v2(154,51.02) v2(154.09,64.81) v2(154.15,116.22) v2(154.33,41.44) v2(154.4,80.44) v2(154.37,77.09) v2(154.42,1.55) v2(154.57,127.13) v2(154.62,85.6) v2(154.62,62.88) v2(154.6,60.4) v2(154.65,54.47) v2(154.64,51.19) v2(154.62,20.66) v2(154.75,104.54) v2(154.71,94.24) v2(154.73,68.68) v2(154.7,66.12) v2(154.65,23.22) v2(154.73,18.11) v2(154.75,111.4) v2(154.85,110.67) v2(154.83,108.65) v2(154.78,106.73) v2(154.84,96.56) v2(154.78,95.15) v2(154.85,34.19) v2(154.94,112.16) v2(154.85,103.62) v2(154.94,90.67) v2(154.86,89.3) v2(155.01,3.87) v2(155.08,122.67) v2(155.13,65.31) v2(155.14,37.17) v2(155.07,32.83) v2(155.12,2.66) v2(155.24,128.17) v2(155.2,118.5) v2(155.21,42.95) v2(155.17,39.83) v2(155.29,83.12) v2(155.28,72) v2(155.33,34.83) v2(155.38,113.71) v2(155.42,81.64) v2(155.41,74.53) v2(155.37,73.18) v2(155.42,38.4) v2(155.52,84.15) v2(155.5,80.49) v2(155.51,76.62) v2(155.63,114.55) v2(155.65,62.3) v2(155.74,89.28) v2(155.75,69.81) v2(155.66,63.48) v2(155.72,22.01) v2(155.73,19.35) v2(155.83,88.23) v2(155.8,67.46) v2(155.76,60.37) v2(155.81,17.49) v2(155.92,121.63) v2(155.92,119.43) v2(155.95,106.45) v2(155.88,91.69) v2(155.9,51.02) v2(155.96,111.34) v2(156.05,110.67) v2(156.04,103.61) v2(155.96,64.95) v2(155.97,64.13) v2(156.04,1.54) v2(156.07,127.13) v2(156.08,104.54) v2(156.14,95.16) v2(156.14,41.29) v2(156.25,108.62) v2(156.19,94.28) v2(156.24,36.8) v2(156.17,34.26) v2(156.27,112.53) v2(156.27,83.9) v2(156.35,39.56) v2(156.35,66.12) v2(156.47,116.22) v2(156.51,77.27) v2(156.49,74.58) v2(156.52,32.79) v2(156.48,31.12) v2(156.51,3.87) v2(156.58,122.67) v2(156.58,120.46) v2(156.55,68.55) v2(156.74,128.17) v2(156.72,119.05) v2(156.72,97.51) v2(156.74,88.3) v2(156.85,90.69) v2(156.85,70.4) v2(156.84,42.62) v2(156.83,38.06) v2(156.81,23.22) v2(156.78,20.66) v2(156.81,18.13) v2(156.82,2.66) v2(156.89,65.62) v2(156.86,58.29) v2(156.89,57.59) v2(157.04,126.32) v2(157.01,95.13) v2(157.01,49.44) v2(157.14,52.88) v2(157.21,111.41) v2(157.15,94.36) v2(157.16,63.89) v2(157.31,71.96) v2(157.42,121.63) v2(157.44,114.55) v2(157.42,108.49) v2(157.41,106.36) v2(157.36,104.54) v2(157.45,103.61) v2(157.43,81.64) v2(157.47,110.46) v2(157.5,90.1) v2(157.51,76.61) v2(157.48,74.32) v2(157.48,73.04) v2(157.45,67.46) v2(157.57,77.67) v2(157.64,31.32) v2(157.62,1.55) v2(157.69,127.12) v2(157.74,40.36) v2(157.73,38.08) v2(157.83,98.05) v2(157.79,93.82) v2(157.76,83.29) v2(157.95,54.47) v2(157.9,33.88) v2(157.88,22.01) v2(157.89,19.37) v2(157.96,17.52) v2(158.08,122.67) v2(158.08,120.46) v2(158.13,43.33) v2(158.05,33.22) v2(158.13,3.86) v2(158.24,128.17) v2(158.32,111.92) v2(158.32,37.82) v2(158.32,2.66) v2(158.44,96.14) v2(158.45,67.07) v2(158.39,41.65) v2(158.37,34.83) v2(158.51,95.15) v2(158.54,80.68) v2(158.49,69.48) v2(158.52,63.91) v2(158.48,62.68) v2(158.47,61.49) v2(158.52,60.24) v2(158.51,59.02) v2(158.52,36.84) v2(158.57,116.42) v2(158.65,110.47) v2(158.63,65.49) v2(158.64,31.56) v2(158.73,111.01) v2(158.66,106.35) v2(158.66,103.61) v2(158.7,97.16) v2(158.73,93.43) v2(158.81,84.24) v2(158.85,57.58) v2(158.92,121.63) v2(158.91,72.26) v2(158.88,23.25) v2(158.86,20.69) v2(158.96,39.28) v2(158.96,33.85) v2(158.96,32.53) v2(158.96,18.16) v2(159.06,83.31) v2(159.12,1.55) v2(159.25,52.84) v2(159.27,127.13) v2(159.27,118.63) v2(159.38,59.1) v2(159.53,81.64) v2(159.58,122.67) v2(159.57,120.85) v2(159.65,30.97) v2(159.68,76.17) v2(159.71,75.02) v2(159.67,73.49) v2(159.71,3.87) v2(159.8,80.59) v2(159.84,58.51) v2(159.85,54.47) v2(159.82,2.66) v2(159.86,128.16) v2(159.92,86.87) v2(159.92,77.47) v2(159.89,65.01) v2(159.87,63.9) v2(159.91,62.72) v2(159.85,60.35) v2(159.98,66.93) v2(159.97,40.41) v2(159.96,22.03) v2(159.97,19.4) v2(160.04,17.54) v2(160.08,61.63) v2(160.06,34.8) v2(160.11,33.27) v2(160.18,38.26) v2(160.21,36.48) v2(160.46,5.01) v2(160.62,1.55) v2(160.89,39.25) v2(161.04,20.66) v2(161.04,18.19) v2(161.07,23.22) v2(161.16,6.12) v2(161.21,3.87) v2(161.35,32.32) v2(161.32,2.66) v2(161.44,128.17) v2(161.36,33.84) v2(161.96,5.01) v2(162.08,34.8) v2(162.14,22.01) v2(162.1,17.45) v2(162.12,1.55) v2(162.15,19.37) v2(162.66,6.12) v2(162.71,3.87) v2(162.82,2.66) v2(162.94,128.17) v2(163.14,23.25) v2(163.12,20.69) v2(163.25,18.4) v2(163.46,5.01) v2(163.62,1.55) v2(163.85,54.52) v2(164.22,22.03) v2(164.23,19.4) v2(164.16,6.12) v2(164.35,52.87) v2(164.32,2.66) v2(164.54,128.28) v2(164.6,55) v2(164.96,5.01) v2(165.1,111.91) v2(165.12,1.55) v2(165.3,21.6) v2(165.48,23.22) v2(165.46,20.66) v2(165.65,109.22) v2(165.66,6.12) v2(165.84,114.55) v2(165.84,105.61) v2(165.85,68.37) v2(165.85,55.47) v2(165.84,43.69) v2(165.82,2.66) v2(165.92,117.71) v2(165.89,97.29) v2(165.89,95.43) v2(165.91,59.7) v2(165.91,52.83) v2(165.91,51.37) v2(165.87,49.4) v2(165.89,47.61) v2(165.94,45.4) v2(166.04,128.28) v2(165.99,54.56) v2(165.99,42.82) v2(166.07,94.51) v2(166.2,91.73) v2(166.3,93.2) v2(166.3,89.39) v2(166.35,87.13) v2(166.43,102.93) v2(166.37,90.29) v2(166.35,85.27) v2(166.43,82.35) v2(166.42,80.88) v2(166.37,77.48) v2(166.43,76.79) v2(166.39,72.49) v2(166.37,62.76) v2(166.46,5.01) v2(166.65,115.78) v2(166.65,84.21) v2(166.61,83.27) v2(166.55,22.01) v2(166.57,19.37) v2(166.62,1.55) v2(166.69,74.75) v2(166.71,64.25) v2(166.7,43.07) v2(166.83,94.76) v2(166.95,109.98) v2(166.92,60.39) v2(166.95,57.92) v2(166.95,54.87) v2(166.91,51.4) v2(166.92,49.36) v2(166.91,47.15) v2(166.89,45.75) v2(166.85,44.58) v2(167.04,106.73) v2(167,104.74) v2(167.02,98.29) v2(166.99,96.23) v2(166.98,65.2) v2(167.16,108.47) v2(167.24,91.31) v2(167.17,70.9) v2(167.16,6.12) v2(167.31,38.53) v2(167.29,36.98) v2(167.31,32.53) v2(167.27,30.91) v2(167.32,2.66) v2(167.41,88.27) v2(167.4,86.17) v2(167.45,75.85) v2(167.41,73.4) v2(167.41,41.7) v2(167.45,34.17) v2(167.54,128.28) v2(167.53,20.69) v2(167.55,94.02) v2(167.56,23.25) v2(167.68,64.27) v2(167.82,114.57) v2(167.79,89.44) v2(167.77,69.59) v2(167.83,30.56) v2(167.86,119.39) v2(167.86,117.71) v2(167.9,111.88) v2(167.87,80.88) v2(167.88,71.11) v2(167.9,61.83) v2(167.89,59.65) v2(167.95,57.97) v2(167.91,55.93) v2(167.93,53.77) v2(167.93,51.28) v2(167.9,48.62) v2(167.88,46.63) v2(167.93,45.27) v2(167.92,44.01) v2(167.97,84.76) v2(167.96,5.01) v2(168.06,83.52) v2(168.1,18.3) v2(168.12,1.55) v2(168.16,110.23) v2(168.24,87.13) v2(168.23,40.01) v2(168.26,102.68) v2(168.41,109.3) v2(168.37,107.58) v2(168.43,97.05) v2(168.39,95.42) v2(168.41,81.8) v2(168.44,76.83) v2(168.42,72.42) v2(168.37,37.65) v2(168.52,103.87) v2(168.45,74.74) v2(168.63,88.72) v2(168.63,22.03) v2(168.64,19.4) v2(168.6,17) v2(168.66,106.04) v2(168.66,90.19) v2(168.66,30.57) v2(168.77,115.47) v2(168.82,85.73) v2(168.83,55.28) v2(168.83,44.04) v2(168.82,2.66) v2(168.92,66.02) v2(168.9,62.87) v2(168.88,60.83) v2(168.9,57.97) v2(168.86,51.02) v2(168.93,50.25) v2(168.93,47.69) v2(168.93,44.89) v2(168.9,43.07) v2(168.92,33.71) v2(168.86,32.27) v2(169.04,128.28) v2(169.05,34.72) v2(169.25,120.29) v2(169.34,87.78) v2(169.46,105.07) v2(169.51,82.39) v2(169.56,112.3) v2(169.56,110.99) v2(169.59,98.4) v2(169.56,30.51) v2(169.67,74.38) v2(169.69,38.35) v2(169.69,23.2) v2(169.66,20.64) v2(169.72,18.19) v2(169.77,70.56) v2(169.84,61.47) v2(169.85,56.12) v2(169.78,36.35) v2(169.76,1.55) v2(169.93,110.26) v2(169.87,59.04) v2(169.92,49.98) v2(169.93,48.71) v2(169.9,45.37) v2(169.89,44.07) v2(169.9,41.58) v2(169.94,32.93) v2(169.94,31.47) v2(170.02,107.57) v2(170.04,89.51) v2(169.96,42.66) v2(170,39.71) v2(169.99,5.01) v2(170.09,109.25) v2(170.11,71.52) v2(170.08,63.4) v2(170.24,106.08) v2(170.17,68.14) v2(170.15,66) v2(170.3,97.75) v2(170.34,72.82) v2(170.32,61.89) v2(170.44,92.16) v2(170.41,88.49) v2(170.4,87.06) v2(170.4,72.03) v2(170.37,64.5) v2(170.37,61.11) v2(170.44,6.16) v2(170.54,128.28) v2(170.51,83.84) v2(170.46,2.66) v2(170.65,104.4) v2(170.58,95.35) v2(170.63,93.23) v2(170.63,85.25) v2(170.68,119.04) v2(170.71,113.56) v2(170.75,94.02) v2(170.71,87.85) v2(170.78,117.94) v2(170.75,86.33) v2(170.76,21.98) v2(170.87,90.82) v2(170.88,77.01) v2(170.88,75.87) v2(170.89,19.42) v2(170.91,16.96) v2(170.9,4.93) v2(171.01,49.29) v2(170.98,47.57) v2(170.97,45.15) v2(170.98,37.27) v2(171.1,112.35) v2(171.12,46.26) v2(171.19,73.18) v2(171.27,33.77) v2(171.26,1.55) v2(171.48,70.76) v2(171.5,49.95) v2(171.54,39.32) v2(171.57,87.39) v2(171.6,82.06) v2(171.61,81.36) v2(171.63,74.41) v2(171.62,67.82) v2(171.6,63.02) v2(171.6,59.92) v2(171.65,57.62) v2(171.61,42.52) v2(171.6,6.04) v2(171.72,91.07) v2(171.67,85.82) v2(171.65,84.27) v2(171.65,82.83) v2(171.7,55.8) v2(171.74,20.67) v2(171.82,107.28) v2(171.75,59.29) v2(171.77,23.22) v2(171.95,115.47) v2(171.86,41.17) v2(172.04,128.28) v2(171.97,113.95) v2(172,18.23) v2(172.06,48.32) v2(172.2,106.22) v2(172.17,63.14) v2(172.29,98.46) v2(172.33,87.91) v2(172.32,86.39) v2(172.31,44.6) v2(172.44,89.58) v2(172.37,68.31) v2(172.45,36.35) v2(172.4,4.93) v2(172.5,70.18) v2(172.61,66.55) v2(172.61,65.49) v2(172.64,64.17) v2(172.63,60.52) v2(172.62,46.98) v2(172.73,69.23) v2(172.77,77.17) v2(172.84,22.01) v2(172.76,1.55) v2(172.89,123.45) v2(172.95,80.91) v2(172.94,62.13) v2(172.9,55.81) v2(172.88,33.76) v2(173.02,49.83) v2(173.09,57.27) v2(173.12,46) v2(173.06,35.29) v2(173.09,19.42) v2(173.11,16.96) v2(173.1,6.04) v2(173.22,48.51) v2(173.35,104.81) v2(173.35,101.77) v2(173.35,100.77) v2(173.3,58.35) v2(173.38,71.26) v2(173.54,128.28) v2(173.49,107.32) v2(173.49,97.08) v2(173.51,82.83) v2(173.49,66.72) v2(173.49,64.86) v2(173.48,63.08) v2(173.48,39.13) v2(173.46,2.66) v2(173.58,113.95) v2(173.61,86.92) v2(173.71,109.19) v2(173.75,99.52) v2(173.68,47.48) v2(173.68,41.31) v2(173.7,36.87) v2(173.79,111.58) v2(173.83,110.23) v2(173.83,89.37) v2(173.92,20.64) v2(173.9,4.93) v2(174,125.06) v2(174.01,112.38) v2(174.04,106.12) v2(174.03,81.32) v2(174.02,67.96) v2(173.95,23.2) v2(174.05,95.87) v2(174.08,91.56) v2(174.11,84.56) v2(174.06,59.57) v2(174.25,44.87) v2(174.16,43.18) v2(174.2,18.23) v2(174.26,103.62) v2(174.32,77.17) v2(174.33,69.85) v2(174.32,62.22) v2(174.26,1.55) v2(174.4,65.65) v2(174.41,55.81) v2(174.4,46.7) v2(174.55,86.17) v2(174.5,3.65) v2(174.64,114.94) v2(174.58,63.66) v2(174.6,6.04) v2(174.7,93.54) v2(174.7,71.63) v2(174.65,33.78) v2(174.78,92.44) v2(174.77,90.06) v2(174.77,88.04) v2(174.85,80.44) v2(174.79,36.4) v2(174.92,91.18) v2(174.95,66.97) v2(174.88,61.34) v2(174.85,58.36) v2(175.04,128.28) v2(175.03,110.28) v2(175.04,107.3) v2(175,83.45) v2(175.02,21.98) v2(174.96,2.66) v2(175.12,123.45) v2(175.1,113.99) v2(175.14,57.29) v2(175.16,94.04) v2(175.19,67.56) v2(175.17,48.15) v2(175.22,40.7) v2(175.16,35.29) v2(175.28,50.12) v2(175.29,19.42) v2(175.31,16.96) v2(175.36,111.27) v2(175.42,95.19) v2(175.4,4.93) v2(175.5,64.88) v2(175.65,60.32) v2(175.6,38.77) v2(175.76,1.55) v2(176.01,86.87) v2(176.01,44.52) v2(176.03,23.22) v2(176,20.67) v2(176.11,77.15) v2(176.12,65.9) v2(176.1,6.04) v2(176.23,109.09) v2(176.21,89.3) v2(176.2,79.82) v2(176.4,18.23) v2(176.46,2.66) v2(176.65,101.67) v2(176.61,70.03) v2(176.6,66.87) v2(176.65,128.27) v2(176.73,125.09) v2(176.68,92.07) v2(176.7,57.22) v2(176.82,69.06) v2(176.84,63.86) v2(176.88,123.45) v2(176.88,111.33) v2(176.88,88.13) v2(176.9,58.24) v2(176.9,42.38) v2(176.9,4.93) v2(177.01,115.3) v2(177.05,102.52) v2(176.96,95.17) v2(177.05,79.32) v2(176.97,48.12) v2(177.09,107.26) v2(177.15,93.36) v2(177.15,55.8) v2(177.1,22.01) v2(177.18,117.09) v2(177.22,36.17) v2(177.32,33.78) v2(177.26,1.55) v2(177.4,71.66) v2(177.42,65.73) v2(177.55,85.57) v2(177.52,45.7) v2(177.49,19.42) v2(177.51,16.96) v2(177.6,109.46) v2(177.6,6.04) v2(177.67,80.41) v2(177.69,47.22) v2(177.79,113.03) v2(177.8,89.3) v2(177.95,100.27) v2(177.9,91.15) v2(177.87,67.42) v2(177.98,115.94) v2(178.05,83.67) v2(178.02,77.12) v2(177.98,64.81) v2(178,57.24) v2(177.96,2.66) v2(178.12,108.71) v2(178.08,93.5) v2(178.1,61.77) v2(178.24,128.28) v2(178.2,35.15) v2(178.3,55.8) v2(178.28,49.74) v2(178.34,20.64) v2(178.37,23.2) v2(178.4,4.93) v2(178.49,70.03) v2(178.6,18.23) v2(178.69,117.08) v2(178.73,92.09) v2(178.7,56.77) v2(178.79,123.44) v2(178.85,95.2) v2(178.76,1.55) v2(178.91,48.2) v2(178.86,33.77) v2(179.03,71.65) v2(179.12,113.97) v2(179.1,6.04) v2(179.21,77.4) v2(179.35,100.27) v2(179.4,94.36) v2(179.44,21.98) v2(179.45,125.18) v2(179.5,78.67) v2(179.46,2.66) v2(179.74,128.28) v2(179.74,116.25) v2(179.69,115.14) v2(179.72,66.4) v2(179.65,56.01) v2(179.7,42.37) v2(179.69,19.42) v2(179.71,16.96) v2(179.82,68.37) v2(179.79,63.91) v2(179.81,44.75) v2(179.81,39.66) v2(179.93,111.16) v2(179.91,89.12) v2(179.93,87.74) v2(179.9,86.69) v2(179.92,46.17) v2(179.9,4.93) v2(180.01,85.2) v2(180.03,84.2) v2(179.98,82.44) v2(180.11,106.45) v2(180.1,35.02) v2(180.19,109.01) v2(180.23,16.02) v2(180.31,69.23) v2(180.32,60.63) v2(180.29,47.23) v2(180.26,1.55) v2(180.37,100.82) v2(180.44,23.22) v2(180.42,20.67) v2(180.54,112.64) v2(180.65,78.72) v2(180.58,70.98) v2(180.6,6.04) v2(180.7,122.91) v2(180.7,120.82) v2(180.74,115.4) v2(180.67,90.51) v2(180.75,92.48) v2(180.8,18.23) v2(180.94,56.98) v2(180.85,49.09) v2(180.96,2.66) v2(181.24,128.28) v2(181.37,123.95) v2(181.37,121.85) v2(181.4,41.12) v2(181.4,4.93) v2(181.48,63.03) v2(181.64,38.59) v2(181.72,70.58) v2(181.65,10.05) v2(181.8,93.46) v2(181.76,34.88) v2(181.76,1.55) v2(181.89,107.35) v2(181.87,104.1) v2(181.91,82.42) v2(181.9,11.07) v2(182.02,127.2) v2(182.09,125.06) v2(182.13,85.49) v2(182.1,6.04) v2(182.2,122.91) v2(182.2,120.82) v2(182.23,110) v2(182.2,83.11) v2(182.23,44.15) v2(182.23,16.02) v2(182.22,13.28) v2(182.31,108.52) v2(182.29,89.44) v2(182.4,113.64) v2(182.44,81.55) v2(182.37,48.99) v2(182.45,42.07) v2(182.54,112.45) v2(182.53,59.89) v2(182.55,40.57) v2(182.46,2.66) v2(182.59,111.1) v2(182.58,105.29) v2(182.57,91.7) v2(182.57,67.47) v2(182.6,12.18) v2(182.69,128.23) v2(182.65,9.94) v2(182.76,126.09) v2(182.84,70.18) v2(182.79,65.12) v2(182.8,46.25) v2(182.76,34.94) v2(182.87,123.95) v2(182.87,121.85) v2(182.9,4.93) v2(182.95,114.67) v2(183,63.57) v2(182.98,61.9) v2(183.13,88.3) v2(183.1,69.32) v2(183.15,56.96) v2(183.25,106.07) v2(183.16,90.36) v2(183.16,86.43) v2(183.24,39.74) v2(183.25,14.65) v2(183.26,1.55) v2(183.44,48.09) v2(183.37,46.59) v2(183.4,11.07) v2(183.52,127.2) v2(183.49,92.36) v2(183.46,5.98) v2(183.59,125.06) v2(183.56,68.11) v2(183.57,45.04) v2(183.57,43.37) v2(183.55,35.61) v2(183.7,122.91) v2(183.7,120.82) v2(183.66,101.33) v2(183.85,66.77) v2(183.77,4.92) v2(183.91,109.39) v2(183.93,84.91) v2(183.9,83.81) v2(183.9,79.43) v2(183.87,70.16) v2(183.87,64.88) v2(183.96,112.01) v2(183.95,105.29) v2(184,42.23) v2(183.96,2.66) v2(184.13,113.57) v2(184.13,89.69) v2(184.09,63.01) v2(184.1,12.18) v2(184.19,128.23) v2(184.22,87.19) v2(184.17,86.14) v2(184.16,69.34) v2(184.17,57.76) v2(184.2,41.19) v2(184.23,16.02) v2(184.22,13.28) v2(184.15,9.94) v2(184.26,126.09) v2(184.32,61.29) v2(184.28,47.28) v2(184.3,36.32) v2(184.37,123.95) v2(184.37,121.85) v2(184.39,108.37) v2(184.62,106.44) v2(184.65,102.27) v2(184.7,80.23) v2(184.8,84.52) v2(184.9,11.07) v2(184.88,1.54) v2(185.02,127.2) v2(184.98,90.77) v2(185.09,125.06) v2(185.2,122.91) v2(185.2,120.82) v2(185.54,14.71) v2(185.6,12.18) v2(185.69,128.23) v2(185.65,9.94) v2(185.66,2.66) v2(185.76,126.09) v2(185.87,123.95) v2(185.87,121.85) v2(185.9,66.69) v2(186.01,4.92) v2(186.24,15.82) v2(186.29,13.58) v2(186.4,11.07) v2(186.52,127.2) v2(186.49,87.59) v2(186.46,1.55) v2(186.59,125.06) v2(186.7,122.91) v2(186.7,120.82) v2(186.84,65.96) v2(186.79,6.04) v2(187.04,14.71) v2(187.1,12.18) v2(187.19,128.23) v2(187.15,9.94) v2(187.26,126.09) v2(187.37,123.95) v2(187.37,121.85) v2(187.54,61.79) v2(187.56,105.7) v2(187.6,4.93) v2(187.74,15.82) v2(187.79,13.58) v2(187.9,11.07) v2(188.02,127.2) v2(187.97,108.73) v2(188,86.75) v2(187.97,8.8) v2(187.96,1.55) v2(188.09,125.06) v2(188.2,122.91) v2(188.2,120.82) v2(188.29,6.04) v2(188.54,14.71) v2(188.6,12.18) v2(188.69,128.23) v2(188.65,9.94) v2(188.66,2.66) v2(188.76,126.09) v2(188.77,7.51) v2(188.87,123.95) v2(188.87,121.85) v2(189.1,4.93) v2(189.24,15.82) v2(189.29,13.58) v2(189.38,110.36) v2(189.4,11.07) v2(189.52,127.2) v2(189.5,88.29) v2(189.47,8.8) v2(189.46,1.55) v2(189.59,125.06) v2(189.7,122.91) v2(189.7,120.82) v2(189.79,6.04) v2(189.89,39.41) v2(190.04,14.71) v2(190.12,109.78) v2(190.1,12.18) v2(190.19,128.23) v2(190.19,105.34) v2(190.15,9.94) v2(190.16,2.66) v2(190.26,126.09) v2(190.27,7.51) v2(190.37,123.95) v2(190.37,121.85) v2(190.48,87.89) v2(190.63,107.58) v2(190.6,41.78) v2(190.6,4.93) v2(190.74,15.82) v2(190.79,13.58) v2(190.95,61.59) v2(190.88,43.8) v2(190.9,11.07) v2(191.02,127.2) v2(190.97,45.88) v2(190.97,8.8) v2(190.96,1.55) v2(191.09,125.06) v2(191.2,122.91) v2(191.2,120.82) v2(191.29,6.04) v2(191.36,103.91) v2(191.41,84.59) v2(191.54,14.71) v2(191.61,82.55) v2(191.58,65.78) v2(191.6,12.18) v2(191.69,128.23) v2(191.68,63.71) v2(191.65,9.94) v2(191.66,2.66) v2(191.76,126.09) v2(191.76,41.74) v2(191.81,39.74) v2(191.81,27.69) v2(191.83,24.17) v2(191.77,7.51) v2(191.87,123.95) v2(191.87,121.85) v2(191.87,89.79) v2(191.94,59.57) v2(191.85,18.85) v2(191.96,111.72) v2(191.97,67.8) v2(192.05,109.49) v2(192.12,107.52) v2(192.12,105.78) v2(192.14,61.62) v2(192.11,43.68) v2(192.08,37.8) v2(192.1,4.93) v2(192.2,85.49) v2(192.23,83.71) v2(192.24,15.82) v2(192.27,88.87) v2(192.29,87.4) v2(192.26,81.71) v2(192.34,29.19) v2(192.29,13.58) v2(192.4,11.07) v2(192.52,127.2) v2(192.46,45.84) v2(192.47,8.8) v2(192.46,1.55) v2(192.59,125.06) v2(192.77,122.94) v2(192.77,120.85) v2(192.84,103.63) v2(192.83,26.14) v2(192.81,22.81) v2(192.79,6.04) v2(192.91,17.56) v2(193.04,14.71) v2(193.14,111.19) v2(193.13,89.6) v2(193.15,38.02) v2(193.1,12.18) v2(193.19,128.23) v2(193.19,67.46) v2(193.15,9.94) v2(193.16,2.66) v2(193.26,126.09) v2(193.33,81.69) v2(193.27,7.51) v2(193.43,121.88) v2(193.47,85.53) v2(193.47,84.25) v2(193.54,82.79) v2(193.54,66.45) v2(193.51,65.16) v2(193.54,63.79) v2(193.54,62.09) v2(193.54,60.18) v2(193.47,45.27) v2(193.5,43.96) v2(193.52,42.21) v2(193.5,40.4) v2(193.5,38.97) v2(193.62,110.29) v2(193.6,109.15) v2(193.64,108.17) v2(193.62,106.83) v2(193.63,105.54) v2(193.61,104.59) v2(193.57,88.61) v2(193.61,87.09) v2(193.74,15.82) v2(193.83,24.17) v2(193.79,13.58) v2(193.89,27.63) v2(193.85,18.85) v2(194.02,127.2) v2(193.97,8.8) v2(193.96,1.55) v2(194.27,122.94) v2(194.27,120.85) v2(194.54,14.71) v2(194.69,128.23) v2(194.66,2.66) v2(194.83,29.19) v2(194.81,22.81) v2(194.77,7.51) v2(194.93,121.88) v2(194.91,17.56) v2(195.16,26.15) v2(195.24,15.82) v2(195.29,13.58) v2(195.47,8.8) v2(195.46,1.55) v2(195.63,127.19) v2(195.77,122.94) v2(195.77,120.85) v2(195.83,24.17) v2(195.85,18.85) v2(196.04,14.71) v2(196.19,128.23) v2(196.24,27.68) v2(196.16,2.66) v2(196.27,7.51) v2(196.43,121.88) v2(196.74,15.82) v2(196.81,22.81) v2(196.79,13.58) v2(196.91,17.56) v2(196.97,8.8) v2(196.96,1.55) v2(197.21,127.2) v2(197.19,125.35) v2(197.27,122.94) v2(197.27,120.85) v2(197.32,29.19) v2(197.29,6.04) v2(197.52,26.21) v2(197.54,14.71) v2(197.66,2.66) v2(197.83,24.17) v2(197.77,7.51) v2(197.86,124.29) v2(197.93,121.88) v2(197.85,18.85) v2(197.9,10.6) v2(198.1,4.93) v2(198.24,15.82) v2(198.16,11.8) v2(198.29,13.58) v2(198.47,8.8) v2(198.69,125.35) v2(198.67,27.68) v2(198.77,122.94) v2(198.77,120.85) v2(198.81,22.81) v2(198.79,6.04) v2(198.91,17.56) v3(0.93,18.96) v3(1.12,44.5) v3(1.09,22.07) v3(1.24,16.12) v3(1.27,67.01) v3(1.29,64.06) v3(1.3,24.95) v3(1.26,12.92) v3(1.45,55.53) v3(1.4,47.82) v3(1.37,34) v3(1.44,30.45) v3(1.39,28.11) v3(1.52,111.05) v3(1.49,96.82) v3(1.52,93.93) v3(1.45,86.96) v3(1.52,84.2) v3(1.5,53.12) v3(1.62,108.14) v3(1.58,105.36) v3(1.58,101.21) v3(1.56,98.89) v3(1.57,50.89) v3(1.61,38.04) v3(1.58,6.28) v3(1.6,4.56) v3(1.65,121.84) v3(1.67,116.68) v3(1.68,68.42) v3(1.83,126.46) v3(1.83,124.26) v3(1.8,91.31) v3(1.82,46.03) v3(1.84,3.1) v3(1.95,119.52) v3(1.94,89.87) v3(1.89,72.82) v3(1.95,20.31) v3(1.99,74.87) v3(2.01,59.69) v3(2.04,17.88) v3(2.1,81.18) v3(2.15,78.98) v3(2.08,76.93) v3(2.11,62.7) v3(2.13,57.25) v3(2.15,42.74) v3(2.12,40.18) v3(2.07,32.12) v3(2.23,114.53) v3(2.17,103.53) v3(2.16,26.42) v3(2.24,11.53) v3(2.28,82.8) v3(2.29,69.92) v3(2.28,65.59) v3(2.3,23.42) v3(2.31,14.78) v3(2.38,8.37) v3(2.47,49.17) v3(2.61,112.45) v3(2.64,99.95) v3(2.59,97.86) v3(2.64,95.3) v3(2.57,92.56) v3(2.59,85.5) v3(2.59,52.14) v3(2.58,29.3) v3(2.73,120.81) v3(2.65,109.82) v3(2.66,54.28) v3(2.83,127.9) v3(2.77,117.81) v3(2.76,35.98) v3(2.87,106.73) v3(2.95,61.46) v3(2.87,1.7) v3(2.96,88.51) v3(3.03,73.89) v3(3.08,75.91) v3(3.13,18.96) v3(3.22,77.91) v3(3.21,7.54) v3(3.31,80.05) v3(3.27,58.44) v3(3.32,44.5) v3(3.29,22.07) v3(3.37,68.47) v3(3.42,41.32) v3(3.44,16.12) v3(3.35,10.41) v3(3.47,67.01) v3(3.49,64.06) v3(3.5,24.95) v3(3.46,12.92) v3(3.65,55.53) v3(3.6,47.82) v3(3.57,34) v3(3.64,30.45) v3(3.59,28.11) v3(3.69,96.82) v3(3.72,93.93) v3(3.65,86.96) v3(3.72,84.2) v3(3.7,53.12) v3(3.78,101.21) v3(3.76,98.89) v3(3.77,50.89) v3(3.81,38.04) v3(3.85,121.84) v3(3.92,119.55) v3(3.87,116.68) v3(4.05,128.85) v3(4.02,46.03) v3(4.14,89.87) v3(4.09,72.82) v3(4.15,20.31) v3(4.19,74.87) v3(4.21,59.69) v3(4.24,17.88) v3(4.32,111.04) v3(4.3,81.18) v3(4.35,78.98) v3(4.28,76.93) v3(4.32,65.59) v3(4.33,57.25) v3(4.35,42.74) v3(4.32,40.18) v3(4.27,32.12) v3(4.43,114.53) v3(4.42,108.12) v3(4.37,103.53) v3(4.36,26.42) v3(4.44,11.53) v3(4.49,69.92) v3(4.5,23.42) v3(4.51,14.78) v3(4.58,8.37) v3(4.67,49.17) v3(4.84,99.95) v3(4.79,97.86) v3(4.84,95.3) v3(4.77,92.56) v3(4.79,52.14) v3(4.78,29.3) v3(4.93,120.81) v3(4.92,105.38) v3(4.86,54.28) v3(5.03,127.9) v3(4.97,117.81) v3(4.96,35.98) v3(5.07,1.7) v3(5.23,73.89) v3(5.28,75.91) v3(5.34,61.49) v3(5.33,18.96) v3(5.41,112.44) v3(5.42,77.91) v3(5.45,109.8) v3(5.51,80.05) v3(5.47,58.44) v3(5.52,44.5) v3(5.49,22.07) v3(5.62,41.32) v3(5.64,16.12) v3(5.55,10.41) v3(5.67,106.71) v3(5.67,67.01) v3(5.69,64.06) v3(5.7,24.95) v3(5.66,12.92) v3(5.85,55.53) v3(5.8,47.82) v3(5.77,34) v3(5.84,30.45) v3(5.79,28.11) v3(5.89,96.82) v3(5.92,93.93) v3(5.85,86.96) v3(5.92,84.2) v3(5.9,53.12) v3(5.98,101.21) v3(5.96,98.89) v3(6.02,91.36) v3(5.97,50.89) v3(6.01,38.04) v3(6.05,121.84) v3(6.12,119.55) v3(6.07,116.68) v3(6.25,128.85) v3(6.22,46.03) v3(6.2,7.49) v3(6.34,89.87) v3(6.29,72.82) v3(6.31,71.4) v3(6.27,62.79) v3(6.35,20.31) v3(6.39,74.87) v3(6.41,59.69) v3(6.44,17.88) v3(6.52,111.04) v3(6.5,81.18) v3(6.55,78.98) v3(6.48,76.93) v3(6.53,57.25) v3(6.55,42.74) v3(6.52,40.18) v3(6.47,32.12) v3(6.63,114.53) v3(6.62,108.12) v3(6.57,103.53) v3(6.56,26.42) v3(6.64,11.53) v3(6.69,69.92) v3(6.7,23.42) v3(6.71,14.78) v3(6.78,8.37) v3(6.87,49.17) v3(7.04,99.95) v3(6.99,97.86) v3(7.04,95.3) v3(6.97,92.56) v3(6.99,85.25) v3(7,64.06) v3(6.99,52.14) v3(6.98,29.3) v3(7.13,120.81) v3(7.08,83.01) v3(7.06,54.28) v3(7.23,127.9) v3(7.17,117.81) v3(7.16,35.98) v3(7.32,65.45) v3(7.27,1.7) v3(7.43,73.89) v3(7.41,61.46) v3(7.48,75.91) v3(7.45,24.68) v3(7.61,112.44) v3(7.62,77.91) v3(7.65,109.8) v3(7.7,88.56) v3(7.71,80.05) v3(7.67,58.44) v3(7.82,41.32) v3(7.75,10.41) v3(7.87,106.71) v3(7.94,28.18) v3(7.86,16.12) v3(7.88,12.92) v3(7.97,68.7) v3(8.05,55.53) v3(7.99,30.39) v3(8.1,53.12) v3(8.24,123.21) v3(8.24,101.2) v3(8.23,98.89) v3(8.15,96.82) v3(8.18,93.93) v3(8.27,126.64) v3(8.25,121.84) v3(8.32,119.55) v3(8.27,116.68) v3(8.35,6.54) v3(8.45,128.85) v3(8.39,84.26) v3(8.42,71.4) v3(8.37,3.59) v3(8.54,81.21) v3(8.54,79.05) v3(8.49,74.84) v3(8.51,72.82) v3(8.5,62.81) v3(8.56,76.98) v3(8.61,59.69) v3(8.72,111.04) v3(8.69,69.91) v3(8.73,57.25) v3(8.66,17.88) v3(8.82,108.12) v3(8.79,40.18) v3(8.8,32.79) v3(8.94,82.99) v3(8.93,14.78) v3(8.86,11.53) v3(9.01,105.37) v3(9.03,29.35) v3(9,8.37) v3(9.23,125) v3(9.2,64.06) v3(9.19,52.14) v3(9.32,120.73) v3(9.3,99.95) v3(9.26,97.86) v3(9.3,95.3) v3(9.26,54.28) v3(9.3,1.73) v3(9.43,127.9) v3(9.37,117.81) v3(9.49,80.09) v3(9.51,77.98) v3(9.51,76) v3(9.46,4.79) v3(9.63,73.94) v3(9.57,61.44) v3(9.56,48.98) v3(9.65,24.68) v3(9.81,112.44) v3(9.79,45.48) v3(9.85,109.8) v3(9.87,58.44) v3(9.97,10.41) v3(10.07,106.71) v3(10.14,28.18) v3(10.06,16.12) v3(10.08,12.92) v3(10.23,101.22) v3(10.25,55.53) v3(10.19,30.39) v3(10.34,96.8) v3(10.3,53.12) v3(10.44,123.21) v3(10.35,98.95) v3(10.47,126.64) v3(10.46,121.8) v3(10.52,119.55) v3(10.55,6.54) v3(10.65,128.85) v3(10.57,3.59) v3(10.74,81.21) v3(10.74,79.05) v3(10.69,74.84) v3(10.71,72.82) v3(10.76,76.98) v3(10.81,59.69) v3(10.83,20.51) v3(10.92,83.94) v3(10.93,57.25) v3(10.92,26.19) v3(10.86,17.88) v3(11,51.12) v3(10.99,40.18) v3(11,32.79) v3(11.13,14.78) v3(11.06,11.53) v3(11.23,29.35) v3(11.29,38.72) v3(11.43,125) v3(11.4,64.06) v3(11.39,52.14) v3(11.52,120.73) v3(11.46,54.28) v3(11.5,1.73) v3(11.63,127.9) v3(11.6,123.02) v3(11.69,80.09) v3(11.71,77.98) v3(11.71,76) v3(11.69,69.94) v3(11.71,61.42) v3(11.72,49.82) v3(11.69,41.92) v3(11.66,4.79) v3(11.83,73.94) v3(11.76,48.98) v3(11.83,27.37) v3(11.92,83.08) v3(11.92,72.08) v3(11.85,24.68) v3(11.99,45.48) v3(12.07,58.44) v3(12.13,10.32) v3(12.2,87.11) v3(12.17,28.18) v3(12.26,16.12) v3(12.28,12.92) v3(12.45,55.53) v3(12.43,37.16) v3(12.39,30.39) v3(12.54,96.8) v3(12.5,53.12) v3(12.63,119.44) v3(12.55,98.95) v3(12.62,87.42) v3(12.67,126.64) v3(12.66,121.8) v3(12.71,57.24) v3(12.74,43.11) v3(12.75,6.54) v3(12.85,128.85) v3(12.77,3.59) v3(12.94,81.21) v3(12.94,79.05) v3(12.89,74.84) v3(12.91,72.82) v3(13,86.56) v3(12.96,76.98) v3(13.03,20.51) v3(13.12,26.19) v3(13.06,17.88) v3(13.2,51.12) v3(13.19,40.18) v3(13.2,32.79) v3(13.26,88.05) v3(13.3,66.75) v3(13.33,14.78) v3(13.26,11.53) v3(13.42,89.66) v3(13.36,82.55) v3(13.43,71.32) v3(13.43,29.35) v3(13.48,91.7) v3(13.48,90.71) v3(13.5,88.76) v3(13.49,38.72) v3(13.59,52.14) v3(13.72,120.73) v3(13.73,107.9) v3(13.73,105.76) v3(13.66,103.4) v3(13.75,85.8) v3(13.66,54.28) v3(13.67,44.22) v3(13.7,1.73) v3(13.83,127.9) v3(13.8,123.02) v3(13.83,113.35) v3(13.75,110.77) v3(13.81,67.26) v3(13.89,80.09) v3(13.91,77.98) v3(13.91,76) v3(13.86,66.11) v3(13.92,49.82) v3(13.89,41.92) v3(13.89,31.32) v3(13.86,4.79) v3(13.97,92.17) v3(14.03,73.94) v3(13.96,48.98) v3(13.97,27.37) v3(13.98,24.65) v3(14.19,45.48) v3(14.16,16.12) v3(14.18,12.92) v3(14.35,57.21) v3(14.37,10.41) v3(14.51,79.39) v3(14.51,72.11) v3(14.5,67.57) v3(14.54,30.3) v3(14.56,91.04) v3(14.6,89.8) v3(14.6,88.5) v3(14.6,87.12) v3(14.65,55.53) v3(14.63,37.16) v3(14.61,28.07) v3(14.74,96.8) v3(14.71,92.42) v3(14.7,85.54) v3(14.7,66.71) v3(14.67,65.37) v3(14.7,53.12) v3(14.83,119.44) v3(14.8,116.02) v3(14.75,98.95) v3(14.87,126.64) v3(14.92,124.16) v3(14.86,121.8) v3(14.92,63.84) v3(14.93,62.16) v3(14.94,43.11) v3(15.05,128.85) v3(14.96,17.88) v3(14.97,6.54) v3(14.99,3.59) v3(15.13,100.55) v3(15.07,61.02) v3(15.05,32.77) v3(15.18,40.2) v3(15.23,20.51) v3(15.22,14.78) v3(15.15,11.53) v3(15.32,26.19) v3(15.29,8.37) v3(15.4,51.12) v3(15.4,29.39) v3(15.48,66.08) v3(15.53,64.64) v3(15.58,78.44) v3(15.58,76.24) v3(15.58,74.04) v3(15.71,90.53) v3(15.71,89.12) v3(15.72,63.02) v3(15.69,38.72) v3(15.84,112.13) v3(15.79,52.14) v3(15.92,125.59) v3(15.92,120.73) v3(15.85,114.64) v3(15.86,54.28) v3(15.87,44.22) v3(15.92,1.73) v3(16.03,127.9) v3(16,123.02) v3(16.12,49.82) v3(16.09,41.92) v3(16.09,31.32) v3(16.08,4.79) v3(16.17,109.02) v3(16.24,106.51) v3(16.21,104.42) v3(16.17,102.09) v3(16.16,27.39) v3(16.18,24.65) v3(16.27,10.41) v3(16.45,70.67) v3(16.38,65.39) v3(16.38,63.89) v3(16.36,16.12) v3(16.38,12.92) v3(16.5,69.19) v3(16.47,62.14) v3(16.75,100.6) v3(16.71,79.39) v3(16.74,30.3) v3(16.77,89.88) v3(16.85,84.03) v3(16.79,67.89) v3(16.85,55.53) v3(16.83,37.16) v3(16.81,28.07) v3(16.93,85.37) v3(16.92,82.88) v3(16.9,53.12) v3(17.03,119.44) v3(17,116.02) v3(17.02,98.95) v3(17,96.8) v3(17.04,71.36) v3(17.07,126.64) v3(17.12,124.16) v3(17.06,121.8) v3(17.09,94.04) v3(17.1,92.82) v3(17.06,64.62) v3(17.08,59.24) v3(17.13,57.92) v3(17.14,43.11) v3(17.25,128.85) v3(17.19,95.3) v3(17.23,69.91) v3(17.16,17.88) v3(17.17,6.54) v3(17.19,3.59) v3(17.34,68.64) v3(17.25,32.77) v3(17.38,83.83) v3(17.38,40.2) v3(17.42,14.78) v3(17.35,11.53) v3(17.49,8.37) v3(17.58,90.57) v3(17.6,29.39) v3(17.75,60.58) v3(17.69,20.45) v3(17.81,58.22) v3(17.88,84.86) v3(17.92,71.99) v3(17.98,65.33) v3(17.99,52.14) v3(18.12,125.59) v3(18.12,120.73) v3(18.05,70.73) v3(18.06,54.28) v3(18.07,44.22) v3(18.12,1.73) v3(18.23,127.9) v3(18.2,123.02) v3(18.19,96.37) v3(18.21,82.83) v3(18.24,69.52) v3(18.33,93.11) v3(18.3,73.42) v3(18.27,68.65) v3(18.25,59.35) v3(18.29,31.32) v3(18.28,4.79) v3(18.4,105.65) v3(18.4,103.3) v3(18.4,94.79) v3(18.41,27.32) v3(18.38,24.65) v3(18.35,12.98) v3(18.51,108.3) v3(18.45,41.92) v3(18.47,10.41) v3(18.61,113.5) v3(18.61,15.99) v3(18.74,83.81) v3(18.93,110.85) v3(18.92,90.22) v3(18.91,79.39) v3(18.86,71.56) v3(18.94,60.58) v3(18.94,30.3) v3(18.95,72.86) v3(18.98,67.92) v3(19.02,58.33) v3(19.01,28.07) v3(19.23,119.44) v3(19.2,116.02) v3(19.27,126.64) v3(19.32,124.16) v3(19.26,121.8) v3(19.31,96.65) v3(19.31,94.3) v3(19.25,70.48) v3(19.32,69.55) v3(19.33,11.59) v3(19.45,128.85) v3(19.36,17.88) v3(19.37,6.54) v3(19.39,3.59) v3(19.45,95.68) v3(19.45,32.77) v3(19.47,8.43) v3(19.58,40.2) v3(19.67,106.93) v3(19.72,104.49) v3(19.68,82.86) v3(19.72,73.44) v3(19.67,59.35) v3(19.65,14.61) v3(19.82,71.81) v3(19.8,29.39) v3(19.87,109.56) v3(19.86,102.63) v3(19.87,52.19) v3(19.89,20.45) v3(20.32,125.59) v3(20.32,120.73) v3(20.31,114.82) v3(20.26,112.81) v3(20.33,83.86) v3(20.27,27.43) v3(20.32,1.73) v3(20.43,127.9) v3(20.4,123.02) v3(20.42,70.86) v3(20.39,60.58) v3(20.37,58.34) v3(20.44,10.47) v3(20.49,94.7) v3(20.48,84.71) v3(20.5,72.87) v3(20.46,38.69) v3(20.48,4.79) v3(20.59,51.01) v3(20.55,12.98) v3(20.65,41.92) v3(20.69,34.62) v3(20.72,26.09) v3(20.75,48.03) v3(20.83,16.07) v3(20.97,96.67) v3(21.04,28.09) v3(21,17.79) v3(21.25,84.71) v3(21.19,73.43) v3(21.22,59.37) v3(21.33,110.93) v3(21.26,82.9) v3(21.34,71.79) v3(21.26,46.2) v3(21.26,6.54) v3(21.29,3.59) v3(21.43,119.44) v3(21.44,95.68) v3(21.41,30.25) v3(21.47,126.64) v3(21.52,124.16) v3(21.53,106.48) v3(21.53,11.59) v3(21.65,128.85) v3(21.59,40.2) v3(21.65,35.99) v3(21.67,32.81) v3(21.67,29.32) v3(21.67,8.43) v3(21.94,83.85) v3(21.9,58.34) v3(21.85,14.61) v3(21.97,60.6) v3(22.07,109.56) v3(22.11,72.79) v3(22.07,52.19) v3(22.12,49.7) v3(22.09,20.45) v3(22.16,114.6) v3(22.17,107.89) v3(22.15,70.86) v3(22.22,1.73) v3(22.39,119.42) v3(22.35,105.12) v3(22.45,12.98) v3(22.38,4.79) v3(22.52,125.59) v3(22.46,112.81) v3(22.47,94.7) v3(22.63,127.9) v3(22.6,123.02) v3(22.64,121.96) v3(22.57,74.26) v3(22.64,10.47) v3(22.69,96.65) v3(22.7,73.42) v3(22.66,38.69) v3(22.73,16.07) v3(22.79,51.01) v3(22.88,59.37) v3(22.85,41.92) v3(22.89,34.62) v3(22.91,27.32) v3(22.92,26.09) v3(22.97,71.82) v3(22.95,48.03) v3(22.96,24.63) v3(22.98,21.72) v3(23.13,82.95) v3(23.09,18.85) v3(23.19,58.31) v3(23.2,17.79) v3(23.28,84.75) v3(23.44,106.47) v3(23.42,11.59) v3(23.53,110.93) v3(23.54,88.87) v3(23.46,46.2) v3(23.46,6.54) v3(23.49,3.59) v3(23.56,113.9) v3(23.64,72.81) v3(23.62,60.67) v3(23.61,30.25) v3(23.56,8.43) v3(23.67,126.64) v3(23.72,124.16) v3(23.71,97.24) v3(23.72,70.84) v3(23.75,14.61) v3(23.85,128.85) v3(23.76,83.86) v3(23.77,77.35) v3(23.79,40.2) v3(23.85,35.99) v3(23.9,95.7) v3(23.87,32.81) v3(23.87,29.32) v3(23.97,88.33) v3(24.18,71.89) v3(24.25,61.9) v3(24.22,20.35) v3(24.2,15) v3(24.27,109.56) v3(24.27,52.19) v3(24.32,49.7) v3(24.33,23.29) v3(24.28,17.58) v3(24.37,107.89) v3(24.38,88.86) v3(24.37,78.06) v3(24.35,76.75) v3(24.38,73.4) v3(24.35,26.03) v3(24.42,1.73) v3(24.47,94.72) v3(24.54,10.47) v3(24.63,112.86) v3(24.55,105.12) v3(24.61,98.06) v3(24.65,12.98) v3(24.58,4.79) v3(24.72,125.59) v3(24.83,127.9) v3(24.8,96.77) v3(24.84,88.34) v3(24.79,87.65) v3(24.81,71.03) v3(24.86,77.33) v3(24.86,76.16) v3(24.86,38.69) v3(24.93,16.07) v3(25.02,82.9) v3(25.04,72.72) v3(25.01,58.29) v3(24.99,51.01) v3(25.09,34.62) v3(25.12,26.09) v3(25.24,88.86) v3(25.15,48.03) v3(25.28,84.8) v3(25.39,95.54) v3(25.44,28.09) v3(25.42,17.6) v3(25.44,6.59) v3(25.47,77.8) v3(25.53,76.77) v3(25.45,75.53) v3(25.49,71.7) v3(25.46,60.59) v3(25.46,3.64) v3(25.64,106.47) v3(25.58,103.82) v3(25.58,98.98) v3(25.62,11.59) v3(25.73,110.93) v3(25.68,83.81) v3(25.66,46.2) v3(25.76,113.9) v3(25.79,73.42) v3(25.78,69.79) v3(25.81,30.25) v3(25.77,24.74) v3(25.76,8.43) v3(25.87,126.64) v3(25.92,124.16) v3(25.87,97.7) v3(25.89,94.73) v3(25.88,78.34) v3(25.92,75.07) v3(25.87,69.2) v3(25.9,21.66) v3(25.9,18.8) v3(25.95,14.61) v3(26.05,128.85) v3(26,77.33) v3(26.05,76.13) v3(26.02,59.34) v3(26.05,35.99) v3(25.98,16.24) v3(25.98,13.89) v3(26.11,88.84) v3(26.13,69.79) v3(26.11,60.67) v3(26.07,32.81) v3(26.07,29.32) v3(26.2,71.02) v3(26.26,89.45) v3(26.28,85.56) v3(26.44,109.37) v3(26.44,96.61) v3(26.39,72.55) v3(26.39,1.79) v3(26.48,93.81) v3(26.5,69.78) v3(26.52,49.7) v3(26.57,107.89) v3(26.6,76.78) v3(26.65,74.29) v3(26.55,58.33) v3(26.55,4.85) v3(26.66,98.51) v3(26.69,87.78) v3(26.73,82.92) v3(26.74,10.47) v3(26.83,112.86) v3(26.75,105.12) v3(26.84,102.61) v3(26.82,95.61) v3(26.92,125.59) v3(26.85,76.01) v3(26.91,72.83) v3(26.91,71.69) v3(26.85,69.78) v3(26.85,59.8) v3(27.03,127.9) v3(27.01,123.15) v3(27.01,72.59) v3(27.01,61.44) v3(27.13,120.71) v3(27.1,86.68) v3(27.11,85.31) v3(27.09,73.03) v3(27.23,100.6) v3(27.25,73.42) v3(27.19,72.42) v3(27.24,48.47) v3(27.19,46.52) v3(27.2,44.21) v3(27.19,41.66) v3(27.17,38.8) v3(27.22,36.12) v3(27.25,23.72) v3(27.25,22.62) v3(27.3,73.2) v3(27.3,34.77) v3(27.3,26.42) v3(27.3,25.07) v3(27.27,14.91) v3(27.31,12) v3(27.39,110.88) v3(27.44,99.34) v3(27.38,72.23) v3(27.43,70.27) v3(27.35,32.32) v3(27.38,29.17) v3(27.4,27.82) v3(27.36,20.34) v3(27.49,97.65) v3(27.55,92.82) v3(27.51,84.12) v3(27.51,75.15) v3(27.49,73.38) v3(27.48,64.43) v3(27.5,63.27) v3(27.51,59.39) v3(27.45,17.82) v3(27.58,72.04) v3(27.64,6.59) v3(27.72,96.5) v3(27.74,95.05) v3(27.7,81.76) v3(27.7,76.78) v3(27.66,73.57) v3(27.71,62.38) v3(27.68,60.65) v3(27.66,3.64) v3(27.79,107.86) v3(27.84,106.47) v3(27.78,103.82) v3(27.84,73.77) v3(27.78,71.85) v3(27.77,70.28) v3(27.91,87.71) v3(27.94,54.74) v3(27.94,52.88) v3(27.96,113.9) v3(28.02,73.95) v3(27.99,71.63) v3(28.04,70.27) v3(27.96,56.59) v3(27.97,47.44) v3(27.98,45.33) v3(28.02,43.11) v3(28.07,126.64) v3(28.12,124.16) v3(28.13,101.51) v3(28.12,74.36) v3(28.08,40.49) v3(28.15,36.12) v3(28.25,128.85) v3(28.2,91.98) v3(28.23,90.01) v3(28.2,86.38) v3(28.21,74.13) v3(28.17,71.45) v3(28.24,58.34) v3(28.2,8.41) v3(28.3,100.2) v3(28.28,79.37) v3(28.32,76.02) v3(28.44,80.65) v3(28.39,74.29) v3(28.45,21.45) v3(28.37,16.46) v3(28.55,97.19) v3(28.48,95.67) v3(28.46,77.53) v3(28.47,70.51) v3(28.5,64.01) v3(28.52,30.73) v3(28.5,27.67) v3(28.53,10.4) v3(28.64,109.37) v3(28.6,85.18) v3(28.57,74.49) v3(28.64,72.03) v3(28.58,63.22) v3(28.59,1.79) v3(28.75,74.65) v3(28.72,69.23) v3(28.71,67.51) v3(28.72,65.92) v3(28.7,61.5) v3(28.71,60.21) v3(28.71,55.71) v3(28.67,53.66) v3(28.71,52) v3(28.7,29.07) v3(28.67,13.33) v3(28.83,94.47) v3(28.77,94.11) v3(28.8,92.76) v3(28.8,82.88) v3(28.85,73.8) v3(28.8,57.74) v3(28.75,4.85) v3(28.91,99.05) v3(28.95,74.94) v3(28.86,37.66) v3(29.03,112.86) v3(29.04,94.71) v3(28.96,93.87) v3(28.95,90.95) v3(29.02,88.76) v3(29.04,74.64) v3(29.01,59.41) v3(29.12,125.59) v3(29.06,102.51) v3(29.11,76.82) v3(29.06,35.16) v3(29.23,127.9) v3(29.22,93.63) v3(29.22,74.47) v3(29.25,21.22) v3(29.33,120.71) v3(29.29,94.96) v3(29.27,87.47) v3(29.32,70.07) v3(29.35,64.92) v3(29.29,35.94) v3(29.35,123.15) v3(29.4,105.26) v3(29.42,104.14) v3(29.4,91.97) v3(29.41,85.88) v3(29.35,78.52) v3(29.4,75.89) v3(29.38,74.27) v3(29.36,25.23) v3(29.46,99.13) v3(29.47,96.47) v3(29.52,95.19) v3(29.51,93.39) v3(29.51,83.81) v3(29.53,64.03) v3(29.47,62.34) v3(29.47,58.37) v3(29.47,56.62) v3(29.53,6.59) v3(29.59,110.88) v3(29.59,74.36) v3(29.57,74.1) v3(29.64,68.26) v3(29.64,66.7) v3(29.65,60.78) v3(29.59,54.73) v3(29.56,3.64) v3(29.68,101.47) v3(29.65,99.42) v3(29.68,98.88) v3(29.74,73.93) v3(29.71,52.76) v3(29.66,50.93) v3(29.7,23.65) v3(29.8,97.23) v3(29.76,95.42) v3(29.81,94.27) v3(29.75,24.9) v3(29.84,21.24) v3(29.89,100.13) v3(29.85,99.61) v3(29.94,98.64) v3(29.9,89.96) v3(29.9,81.76) v3(29.9,73.75) v3(29.9,22.6) v3(29.85,20.4) v3(29.86,19.58) v3(29.88,11.85) v3(29.99,107.86) v3(29.99,95.65) v3(29.95,84.75) v3(29.98,77.68) v3(30.11,103.67) v3(30.07,99.81) v3(30.12,75.36) v3(30.08,73.58) v3(30.15,65.92) v3(30.14,61.67) v3(30.2,106.49) v3(30.17,102.13) v3(30.16,98.43) v3(30.23,95.87) v3(30.2,79.38) v3(30.19,30.64) v3(30.18,26.22) v3(30.27,126.64) v3(30.32,124.16) v3(30.35,117.28) v3(30.28,100.05) v3(30.3,90.99) v3(30.3,88.49) v3(30.32,73.61) v3(30.31,73.37) v3(30.29,64.84) v3(30.25,63.19) v3(30.3,43.36) v3(30.27,41.8) v3(30.32,40.05) v3(30.45,128.85) v3(30.4,121.95) v3(30.37,119.59) v3(30.38,98.21) v3(30.42,86.99) v3(30.44,82.88) v3(30.35,76.65) v3(30.37,67.53) v3(30.37,57.77) v3(30.38,34.08) v3(30.43,32.69) v3(30.4,8.41) v3(30.49,114.35) v3(30.49,100.26) v3(30.46,96.07) v3(30.5,73.18) v3(30.49,48.57) v3(30.49,1.79) v3(30.61,97.97) v3(30.63,91.76) v3(30.64,80.65) v3(30.55,76.85) v3(30.65,59.39) v3(30.57,47.03) v3(30.61,45.98) v3(30.65,4.85) v3(30.69,100.45) v3(30.68,96.28) v3(30.73,10.4) v3(30.84,109.37) v3(30.84,101.07) v3(30.81,74.52) v3(30.88,100.68) v3(30.87,97.73) v3(30.94,96.46) v3(30.94,92.12) v3(30.86,85.61) v3(30.91,42.69) v3(30.85,27.87) v3(31,78.59) v3(31.04,72.97) v3(30.98,66.72) v3(31.02,61.09) v3(30.97,60.05) v3(31.04,40.02) v3(31.01,13.3) v3(31.11,100.87) v3(31.1,97.54) v3(31.14,96.24) v3(31.08,75.36) v3(31.08,68.26) v3(31.1,47.91) v3(31.22,98.45) v3(31.17,91.92) v3(31.2,63.04) v3(31.19,62.08) v3(31.32,125.59) v3(31.34,103.2) v3(31.3,101.03) v3(31.27,89.52) v3(31.3,87.99) v3(31.32,79.49) v3(31.27,64.08) v3(31.27,58.32) v3(31.3,38.19) v3(31.43,127.9) v3(31.44,112.91) v3(31.37,104.74) v3(31.43,92.07) v3(31.36,83.85) v3(31.43,41.8) v3(31.53,120.71) v3(31.46,115.84) v3(31.55,101.14) v3(31.45,100.2) v3(31.5,97.4) v3(31.55,123.15) v3(31.55,118.54) v3(31.58,102.26) v3(31.65,92.31) v3(31.57,46.52) v3(31.61,43.4) v3(31.6,41.18) v3(31.69,80.36) v3(31.69,69.94) v3(31.69,44.91) v3(31.67,35.13) v3(31.73,6.59) v3(31.79,110.88) v3(31.82,101.21) v3(31.77,100.93) v3(31.81,91.82) v3(31.83,84.75) v3(31.79,57.74) v3(31.8,48.61) v3(31.85,40.3) v3(31.75,30.26) v3(31.76,3.64) v3(31.87,92.54) v3(31.88,86.62) v3(31.9,76.36) v3(31.9,75.4) v3(31.88,33.38) v3(31.98,100.72) v3(31.96,75.71) v3(31.99,73.24) v3(31.96,60.27) v3(32.02,37.23) v3(31.95,16.23) v3(32.07,92.75) v3(32.08,90.39) v3(32.1,81.76) v3(32.07,74.89) v3(32.13,59.39) v3(32.25,121.24) v3(32.19,107.86) v3(32.17,105.71) v3(32.19,100.5) v3(32.2,82.88) v3(32.24,63.29) v3(32.16,62.14) v3(32.18,61.29) v3(32.29,104.21) v3(32.31,92.95) v3(32.34,78.57) v3(32.27,55.43) v3(32.26,54.65) v3(32.26,53.93) v3(32.28,53.22) v3(32.31,30.88) v3(32.3,8.41) v3(32.4,106.49) v3(32.4,100.31) v3(32.36,88.88) v3(32.42,77.93) v3(32.4,74.75) v3(32.4,47.77) v3(32.47,126.64) v3(32.52,124.16) v3(32.55,117.28) v3(32.48,93.14) v3(32.45,80.85) v3(32.49,79.46) v3(32.52,68.28) v3(32.65,128.85) v3(32.6,121.95) v3(32.57,119.59) v3(32.62,103.65) v3(32.6,101.81) v3(32.61,100.1) v3(32.61,95.22) v3(32.65,81.05) v3(32.56,75.71) v3(32.59,25.89) v3(32.69,114.35) v3(32.71,100.34) v3(32.69,93.33) v3(32.72,74.38) v3(32.69,69.94) v3(32.75,46.26) v3(32.67,36.04) v3(32.67,35.74) v3(32.67,35.43) v3(32.67,35.13) v3(32.67,34.81) v3(32.67,34.47) v3(32.67,34.16) v3(32.67,33.83) v3(32.68,33.47) v3(32.71,17.09) v3(32.69,1.79) v3(32.82,99.9) v3(32.8,92.75) v3(32.77,83.85) v3(32.82,58.41) v3(32.79,55.78) v3(32.76,55.05) v3(32.76,54.33) v3(32.78,53.62) v3(32.81,42.29) v3(32.85,36.26) v3(32.85,4.85) v3(32.9,93.53) v3(32.93,85.63) v3(32.91,77.28) v3(32.9,71.59) v3(32.89,60.36) v3(32.89,43.21) v3(32.85,28.55) v3(32.9,26.53) v3(32.89,25.27) v3(33.04,99.67) v3(32.96,91.2) v3(33,87.69) v3(32.99,68.79) v3(32.99,41.18) v3(33.05,36.85) v3(33.15,103.1) v3(33.1,93.74) v3(33.11,77.86) v3(33.1,61.4) v3(33.14,45.49) v3(33.09,38.53) v3(33.13,36.26) v3(33.13,33.43) v3(33.14,32.07) v3(33.1,29.05) v3(33.2,95.8) v3(33.17,75.02) v3(33.23,44.59) v3(33.17,41.79) v3(33.3,102.95) v3(33.27,98.99) v3(33.27,89.76) v3(33.26,67.24) v3(33.26,62.48) v3(33.33,55.42) v3(33.32,54.64) v3(33.32,53.93) v3(33.34,53.21) v3(33.25,48.63) v3(33.34,35.56) v3(33.31,3.74) v3(33.41,105.88) v3(33.36,104.91) v3(33.42,99.54) v3(33.4,94.1) v3(33.41,91.99) v3(33.44,82.9) v3(33.41,81.76) v3(33.39,57.79) v3(33.4,36.25) v3(33.37,24.23) v3(33.52,125.59) v3(33.46,109.53) v3(33.49,100.94) v3(33.55,84.64) v3(33.53,78.76) v3(33.53,71.55) v3(33.45,6.64) v3(33.63,127.9) v3(33.64,112.91) v3(33.59,33.43) v3(33.73,120.71) v3(33.66,115.84) v3(33.72,99.32) v3(33.67,94.34) v3(33.69,93.61) v3(33.67,26.54) v3(33.75,123.15) v3(33.75,118.54) v3(33.79,77.22) v3(33.77,74.42) v3(33.8,72.47) v3(33.84,61.32) v3(33.79,44.01) v3(33.76,43.2) v3(33.81,42.33) v3(33.75,28.5) v3(33.94,102.41) v3(33.87,101.66) v3(33.9,99.06) v3(33.9,95.93) v3(33.93,86.71) v3(33.86,68.07) v3(33.86,59.32) v3(33.91,55.1) v3(33.91,54.38) v3(33.93,53.67) v3(33.95,50.79) v3(33.95,46.25) v3(33.86,38.41) v3(33.85,29) v3(33.95,98.43) v3(34.03,33.43) v3(34.08,90.45) v3(34.07,88.69) v3(34.12,81.61) v3(34.12,67.03) v3(34.12,66.27) v3(34.11,58.27) v3(34.19,83.67) v3(34.25,78.05) v3(34.22,22.63) v3(34.21,21.86) v3(34.22,21.06) v3(34.22,20.31) v3(34.22,19.57) v3(34.22,18.76) v3(34.22,18.02) v3(34.34,110.95) v3(34.28,107.26) v3(34.32,95.6) v3(34.35,73.85) v3(34.29,63.25) v3(34.27,44.56) v3(34.25,36.24) v3(34.33,32.63) v3(34.43,107.91) v3(34.4,101.85) v3(34.44,85.55) v3(34.41,71.54) v3(34.39,55.43) v3(34.39,54.65) v3(34.39,53.93) v3(34.41,53.22) v3(34.36,48.54) v3(34.45,34.15) v3(34.44,33.43) v3(34.47,109.1) v3(34.47,102.93) v3(34.48,95.17) v3(34.49,76.61) v3(34.5,29.4) v3(34.55,28.55) v3(34.52,8.31) v3(34.6,106.49) v3(34.62,104.96) v3(34.63,102.22) v3(34.59,96.29) v3(34.57,91.45) v3(34.57,82.11) v3(34.61,1.76) v3(34.67,126.64) v3(34.72,124.16) v3(34.75,117.28) v3(34.74,105.91) v3(34.67,101.4) v3(34.7,87.75) v3(34.85,128.85) v3(34.8,121.95) v3(34.77,119.59) v3(34.8,107.05) v3(34.83,89.72) v3(34.76,66.22) v3(34.84,60.44) v3(34.75,27.06) v3(34.89,114.35) v3(34.85,72.47) v3(34.87,33.42) v3(34.95,107.2) v3(35.01,76.11) v3(34.97,67.04) v3(34.96,57.71) v3(35.03,36.23) v3(35.02,32.64) v3(35.08,59.44) v3(35.11,35.91) v3(35.09,35.62) v3(35.12,34.07) v3(35.2,86.33) v3(35.24,84.62) v3(35.15,33.74) v3(35.23,33.43) v3(35.21,31.95) v3(35.24,21.86) v3(35.32,101.98) v3(35.33,95.29) v3(35.32,90.6) v3(35.34,25.25) v3(35.25,22.63) v3(35.25,21.07) v3(35.25,20.32) v3(35.25,19.57) v3(35.25,18.76) v3(35.25,18.02) v3(35.42,100.68) v3(35.36,69.5) v3(35.46,104.53) v3(35.53,98) v3(35.51,76.79) v3(35.47,66.38) v3(35.53,44.65) v3(35.55,34.55) v3(35.46,26.6) v3(35.49,24.36) v3(35.51,3.74) v3(35.57,94.58) v3(35.61,81.76) v3(35.6,28.4) v3(35.72,125.59) v3(35.66,109.53) v3(35.66,96.32) v3(35.74,80.82) v3(35.7,74.28) v3(35.72,69.89) v3(35.7,50.83) v3(35.65,6.64) v3(35.83,127.9) v3(35.84,112.91) v3(35.78,101.43) v3(35.83,93.63) v3(35.79,91.08) v3(35.82,88.76) v3(35.77,73.58) v3(35.77,58.28) v3(35.75,28.85) v3(35.93,120.71) v3(35.86,115.84) v3(35.86,86.94) v3(35.93,85.47) v3(35.9,68.95) v3(35.95,123.15) v3(35.95,118.54) v3(36.05,107.67) v3(36,73.13) v3(36.03,48.62) v3(36.14,105.15) v3(36.1,94.56) v3(36.05,27.43) v3(36.1,10.31) v3(36.25,70.42) v3(36.17,69.48) v3(36.24,68.64) v3(36.23,43.96) v3(36.34,98.91) v3(36.28,82.33) v3(36.27,65.09) v3(36.25,64.26) v3(36.26,50.22) v3(36.32,33.94) v3(36.31,22.62) v3(36.3,21.85) v3(36.31,21.06) v3(36.31,20.31) v3(36.31,19.56) v3(36.31,18.75) v3(36.31,18.01) v3(36.4,108.57) v3(36.36,103.59) v3(36.41,97.99) v3(36.4,83.29) v3(36.38,65.6) v3(36.36,34.52) v3(36.4,26.58) v3(36.54,110.95) v3(36.54,93.55) v3(36.49,84.84) v3(36.51,78.4) v3(36.63,107.91) v3(36.63,92.76) v3(36.62,87.69) v3(36.61,75.17) v3(36.62,74.37) v3(36.58,59.75) v3(36.58,51.95) v3(36.74,86.28) v3(36.69,73.71) v3(36.65,68.22) v3(36.66,58.17) v3(36.73,56.53) v3(36.72,8.31) v3(36.84,89.73) v3(36.78,69.88) v3(36.83,69.13) v3(36.81,1.76) v3(36.87,126.64) v3(36.92,124.16) v3(36.95,117.28) v3(36.86,71.04) v3(37.05,128.85) v3(37,121.95) v3(36.97,119.59) v3(37,100.1) v3(37.02,64.94) v3(37.02,64.22) v3(36.99,43.66) v3(37.15,99.95) v3(37.09,98.88) v3(37.06,97.99) v3(37.07,63.56) v3(37.06,31.92) v3(37.06,30.64) v3(37.16,92.35) v3(37.17,80.75) v3(37.22,77.65) v3(37.21,76.78) v3(37.21,50.81) v3(37.24,49.68) v3(37.21,32.58) v3(37.39,103.94) v3(37.45,68.7) v3(37.43,67.86) v3(37.38,27.06) v3(37.38,22.63) v3(37.36,21.86) v3(37.38,21.07) v3(37.38,20.32) v3(37.38,19.57) v3(37.38,18.76) v3(37.38,18.02) v3(37.55,87.18) v3(37.47,77.97) v3(37.47,77.35) v3(37.47,74.72) v3(37.5,71.78) v3(37.48,71.14) v3(37.46,70.41) v3(37.46,69.63) v3(37.49,48.66) v3(37.46,24.62) v3(37.59,93.4) v3(37.72,92.51) v3(37.72,83.96) v3(37.73,76.27) v3(37.79,98.66) v3(37.84,85.91) v3(37.81,81.76) v3(37.92,125.59) v3(37.86,109.53) v3(37.85,77.56) v3(37.94,25.26) v3(38.03,127.9) v3(38.04,112.91) v3(38,108.17) v3(38.01,27) v3(38.13,120.71) v3(38.06,115.84) v3(38.13,103.17) v3(38.07,95.93) v3(38.14,92.85) v3(38.05,26.15) v3(38.15,123.15) v3(38.15,118.54) v3(38.22,11.72) v3(38.34,100.85) v3(38.34,100.26) v3(38.3,46.7) v3(38.3,10.31) v3(38.44,48.66) v3(38.55,104.6) v3(38.51,47.53) v3(38.47,22.62) v3(38.45,21.85) v3(38.47,21.06) v3(38.47,20.31) v3(38.47,19.56) v3(38.47,18.75) v3(38.47,18.01) v3(38.57,99.62) v3(38.55,95.5) v3(38.65,50.81) v3(38.63,33.87) v3(38.65,32.96) v3(38.62,8.31) v3(38.74,110.95) v3(38.7,104.45) v3(38.73,96.64) v3(38.68,46.94) v3(38.66,46.07) v3(38.83,107.91) v3(38.83,91.31) v3(38.82,90.77) v3(38.92,45.05) v3(38.96,91.92) v3(39.02,42.83) v3(39.02,42.05) v3(39.02,41.34) v3(39.04,40.63) v3(39.01,39.87) v3(39.01,39.05) v3(39.01,38.35) v3(39.07,126.64) v3(39.12,124.16) v3(39.15,117.28) v3(39.15,104.88) v3(39.12,101.54) v3(39.1,95.92) v3(39.09,95.35) v3(39.25,128.85) v3(39.2,121.95) v3(39.17,119.59) v3(39.17,100.82) v3(39.21,100.12) v3(39.17,1.76) v3(39.29,114.35) v3(39.29,47.84) v3(39.35,12.73) v3(39.42,97.4) v3(39.44,35.87) v3(39.41,34.53) v3(39.37,17.24) v3(39.61,91.36) v3(39.6,90.71) v3(39.58,90.05) v3(39.61,49.85) v3(39.69,96.71) v3(39.73,95.51) v3(39.73,94.78) v3(39.72,94.13) v3(39.68,51.87) v3(39.73,33.24) v3(39.73,31.97) v3(39.8,104.77) v3(39.81,104.23) v3(39.79,48.66) v3(39.84,32.57) v3(39.9,45.36) v3(40.01,44.83) v3(40.12,125.59) v3(40.06,47.3) v3(40.08,42.83) v3(40.08,42.05) v3(40.08,41.33) v3(40.1,40.62) v3(40.07,39.86) v3(40.07,39.05) v3(40.07,38.34) v3(40.23,127.9) v3(40.15,115.87) v3(40.17,112.89) v3(40.19,72.97) v3(40.17,71.9) v3(40.18,70.97) v3(40.18,70.21) v3(40.18,69.52) v3(40.18,68.84) v3(40.17,68.09) v3(40.17,67.32) v3(40.17,66.46) v3(40.18,35.88) v3(40.2,33.66) v3(40.33,120.71) v3(40.3,62.86) v3(40.35,123.15) v3(40.35,118.54) v3(40.45,51.17) v3(40.45,16.68) v3(40.39,11.69) v3(40.52,52.71) v3(40.63,77.27) v3(40.59,76.72) v3(40.64,71.48) v3(40.63,70.67) v3(40.63,69.93) v3(40.62,69.22) v3(40.62,68.5) v3(40.64,67.81) v3(40.64,67) v3(40.59,32.33) v3(40.58,10.31) v3(40.68,80.95) v3(40.7,78.67) v3(40.67,73.38) v3(40.65,72.31) v3(40.71,65.94) v3(40.65,65.29) v3(40.8,62.42) v3(40.83,47.89) v3(40.75,8.3) v3(40.95,107.42) v3(40.92,45.45) v3(40.94,36.47) v3(40.95,33.71) v3(41.03,104.32) v3(41.03,102.08) v3(40.99,75.66) v3(41,47.22) v3(40.99,33.22) v3(41.14,110.93) v3(41.13,60.96) v3(41.11,48.66) v3(41.14,42.05) v3(41.14,41.34) v3(41.14,39.87) v3(41.14,39.05) v3(41.14,38.35) v3(41.13,28.96) v3(41.25,108.13) v3(41.23,77.99) v3(41.16,51.87) v3(41.19,50.52) v3(41.15,42.83) v3(41.16,40.63) v3(41.18,35.86) v3(41.27,126.64) v3(41.32,124.16) v3(41.35,117.28) v3(41.28,98.79) v3(41.29,97.89) v3(41.28,96.89) v3(41.26,95.85) v3(41.26,94.76) v3(41.28,93.87) v3(41.3,92.85) v3(41.26,74.84) v3(41.34,58.81) v3(41.31,56.99) v3(41.26,55.29) v3(41.33,53.58) v3(41.3,31.9) v3(41.32,30.75) v3(41.28,29.79) v3(41.45,128.85) v3(41.4,121.95) v3(41.37,119.59) v3(41.37,33.39) v3(41.42,5.99) v3(41.37,1.76) v3(41.49,114.35) v3(41.5,103.69) v3(41.5,44.95) v3(41.64,71.3) v3(41.63,70.35) v3(41.65,69.43) v3(41.6,67.65) v3(41.59,66.6) v3(41.67,103.1) v3(41.68,72.42) v3(41.68,68.53) v3(41.74,15.76) v3(41.7,12.7) v3(41.7,7.09) v3(41.66,4.72) v3(41.81,99.43) v3(41.85,98.52) v3(41.85,76.27) v3(41.78,28.77) v3(41.87,97.51) v3(41.88,96.33) v3(41.9,95.35) v3(41.91,94.39) v3(41.91,93.37) v3(41.89,92.44) v3(41.94,89.89) v3(41.93,89.37) v3(41.89,82.49) v3(41.9,81.51) v3(41.9,80.6) v3(41.91,78.33) v3(41.89,77.45) v3(41.94,74.23) v3(41.95,51.17) v3(41.87,47.8) v3(41.93,45.45) v3(41.89,1.29) v3(42,59.57) v3(41.99,52.73) v3(42.05,46.78) v3(42.14,75.16) v3(42.05,58.12) v3(42.09,55.95) v3(42.15,35.83) v3(42.07,26.85) v3(42.17,109.52) v3(42.17,54.51) v3(42.16,29.66) v3(42.32,125.59) v3(42.32,42.83) v3(42.32,42.05) v3(42.32,41.33) v3(42.33,40.62) v3(42.31,39.86) v3(42.31,39.05) v3(42.31,38.34) v3(42.35,32.17) v3(42.43,127.9) v3(42.44,112.91) v3(42.45,107.47) v3(42.35,99.71) v3(42.45,49.77) v3(42.53,120.71) v3(42.46,115.84) v3(42.53,73.59) v3(42.5,53.44) v3(42.52,33.26) v3(42.46,30.67) v3(42.55,123.15) v3(42.55,118.54) v3(42.56,100.32) v3(42.61,96.07) v3(42.61,94.88) v3(42.61,93.83) v3(42.6,92.83) v3(42.62,91.64) v3(42.62,90.99) v3(42.62,89.45) v3(42.61,88.29) v3(42.61,86.79) v3(42.61,82.29) v3(42.61,80.91) v3(42.62,78.82) v3(42.62,77.77) v3(42.62,76.49) v3(42.65,71.35) v3(42.61,70.3) v3(42.64,69.35) v3(42.65,64.4) v3(42.56,48.64) v3(42.56,2.77) v3(42.71,104.32) v3(42.73,97.17) v3(42.66,68.54) v3(42.66,65.57) v3(42.74,5.98) v3(42.85,103.62) v3(42.78,98.55) v3(42.76,97.71) v3(42.77,51.87) v3(42.81,32.64) v3(42.8,31.89) v3(42.78,10.31) v3(42.94,102.62) v3(42.9,74.38) v3(42.88,59.2) v3(42.91,46.78) v3(42.85,35.83) v3(42.99,100.37) v3(43.04,99) v3(42.99,75.46) v3(42.99,73.15) v3(42.99,65.05) v3(43,45.46) v3(42.98,36.7) v3(42.97,11.7) v3(42.95,8.3) v3(43.2,66.2) v3(43.18,52.64) v3(43.18,47.27) v3(43.18,44.22) v3(43.17,25.45) v3(43.25,19.45) v3(43.18,15.65) v3(43.34,110.93) v3(43.3,97.88) v3(43.26,95.44) v3(43.28,94.38) v3(43.27,93.3) v3(43.27,92.24) v3(43.27,89.67) v3(43.26,88.61) v3(43.26,87.11) v3(43.26,85.61) v3(43.28,83.84) v3(43.26,82.61) v3(43.27,81.49) v3(43.27,78.36) v3(43.27,77.13) v3(43.32,76.12) v3(43.29,64.4) v3(43.32,47.82) v3(43.25,30.3) v3(43.27,17.45) v3(43.45,108.13) v3(43.4,98.47) v3(43.37,96.48) v3(43.45,70.86) v3(43.44,69.59) v3(43.45,68.45) v3(43.35,51.21) v3(43.42,44.7) v3(43.47,126.64) v3(43.52,124.16) v3(43.5,55.32) v3(43.65,128.85) v3(43.57,119.59) v3(43.57,72.6) v3(43.59,58.61) v3(43.56,36.19) v3(43.62,33.2) v3(43.61,32.26) v3(43.56,23.54) v3(43.71,99.76) v3(43.69,96.88) v3(43.69,73.65) v3(43.66,50.51) v3(43.85,105.17) v3(43.79,99.08) v3(43.81,98.24) v3(43.77,65.86) v3(43.81,56.77) v3(43.83,51.85) v3(43.84,28.62) v3(43.83,27.31) v3(43.83,26.96) v3(43.83,26.6) v3(43.83,26.22) v3(43.84,25.86) v3(43.84,25.49) v3(43.85,25.15) v3(43.8,23.02) v3(43.76,21.53) v3(43.93,94.94) v3(43.94,93.86) v3(43.93,92.82) v3(43.93,89.93) v3(43.94,89.12) v3(43.93,87.83) v3(43.94,86.56) v3(43.94,85.06) v3(43.94,83.56) v3(43.94,82.06) v3(43.91,80.59) v3(43.93,78.81) v3(43.93,64.69) v3(43.94,57.9) v3(43.95,45.26) v3(43.86,35.82) v3(43.92,34.63) v3(43.91,30.66) v3(43.86,24.82) v3(43.9,7.09) v3(43.86,4.72) v3(44.05,104.37) v3(44.05,60.48) v3(44.11,95.78) v3(44.11,77.94) v3(44.11,74.36) v3(44.14,70.03) v3(44.13,68.97) v3(44.06,63.78) v3(44.14,53.48) v3(44.09,48.64) v3(44.11,47.27) v3(44.14,19.24) v3(44.09,1.29) v3(44.24,114.38) v3(44.25,108.15) v3(44.19,100.94) v3(44.18,97.33) v3(44.17,75.26) v3(44.21,55.95) v3(44.24,54.58) v3(44.19,2.85) v3(44.34,101.45) v3(44.3,35.05) v3(44.37,109.52) v3(44.45,57.47) v3(44.38,46.45) v3(44.38,45.77) v3(44.52,125.59) v3(44.5,72.88) v3(44.54,24.91) v3(44.63,127.9) v3(44.58,96.32) v3(44.6,94.35) v3(44.61,93.2) v3(44.59,91.38) v3(44.6,89.92) v3(44.6,88.61) v3(44.6,87.4) v3(44.61,85.77) v3(44.61,84.27) v3(44.61,82.77) v3(44.63,81.47) v3(44.65,78.42) v3(44.59,32.07) v3(44.56,26.84) v3(44.57,12.85) v3(44.73,120.71) v3(44.71,59.39) v3(44.74,47.86) v3(44.72,6.04) v3(44.75,123.15) v3(44.8,95.03) v3(44.78,66.67) v3(44.8,64.69) v3(44.79,52.5) v3(44.84,10.3) v3(44.91,97.97) v3(44.86,67.49) v3(44.91,30.36) v3(44.93,8.36) v3(44.98,77.98) v3(45.03,74.41) v3(44.96,65.6) v3(44.96,16.04) v3(45.06,98.2) v3(45.06,96.8) v3(45.08,56.78) v3(45.11,49.69) v3(45.11,45.98) v3(45.15,37.42) v3(45.2,73.26) v3(45.18,58.52) v3(45.23,48.64) v3(45.2,38.47) v3(45.28,95.63) v3(45.33,92.03) v3(45.33,91.39) v3(45.31,89.49) v3(45.3,88.21) v3(45.32,84.54) v3(45.3,83.45) v3(45.28,72.1) v3(45.39,76.66) v3(45.54,110.93) v3(45.52,99.64) v3(45.54,97.21) v3(45.52,77.46) v3(45.5,59.77) v3(45.5,32.27) v3(45.65,108.13) v3(45.63,94.59) v3(45.59,70.88) v3(45.64,57.49) v3(45.67,126.64) v3(45.72,124.16) v3(45.75,117.28) v3(45.75,109.07) v3(45.66,102.94) v3(45.67,69.86) v3(45.67,69.22) v3(45.71,67.63) v3(45.66,66.1) v3(45.67,64.9) v3(45.68,63.8) v3(45.85,128.85) v3(45.77,119.59) v3(45.75,114.41) v3(45.75,97.46) v3(45.76,63.01) v3(45.88,96.14) v3(45.92,25.97) v3(45.92,23.89) v3(45.95,21.96) v3(45.88,7.15) v3(46,107.3) v3(46.02,62.57) v3(46.02,19.2) v3(46.07,34.71) v3(46.11,14.48) v3(46.06,11.75) v3(46.21,76.76) v3(46.21,75.74) v3(46.18,73.29) v3(46.19,59.36) v3(46.15,17.18) v3(46.35,103.72) v3(46.34,100.35) v3(46.25,91.32) v3(46.3,72.17) v3(46.35,54.79) v3(46.28,52.71) v3(46.37,96.7) v3(46.4,89.45) v3(46.41,82.9) v3(46.42,70.48) v3(46.41,68.54) v3(46.41,66.77) v3(46.44,53.61) v3(46.55,106.72) v3(46.54,101.45) v3(46.45,95.4) v3(46.55,83.64) v3(46.45,64.4) v3(46.5,63.42) v3(46.53,44.06) v3(46.55,41.37) v3(46.57,109.52) v3(46.6,106.17) v3(46.6,105.77) v3(46.6,105.32) v3(46.6,104.87) v3(46.58,92.78) v3(46.56,81.92) v3(46.58,80.64) v3(46.65,35.27) v3(46.72,125.59) v3(46.66,98.5) v3(46.66,39.83) v3(46.7,39) v3(46.83,127.9) v3(46.84,112.91) v3(46.78,76.27) v3(46.75,57.65) v3(46.75,57.4) v3(46.85,38.42) v3(46.93,120.71) v3(46.86,115.84) v3(46.85,106.9) v3(46.88,89.96) v3(46.88,74.12) v3(46.86,58.45) v3(46.92,6.04) v3(46.95,123.15) v3(46.95,118.54) v3(46.96,72.57) v3(47.05,70.6) v3(47.03,60.24) v3(47,57.65) v3(47,57.4) v3(46.95,53) v3(47.04,10.3) v3(47.1,106.17) v3(47.1,105.77) v3(47.1,105.32) v3(47.1,104.87) v3(47.11,104.32) v3(47.13,98.05) v3(47.06,69.97) v3(47.06,67.81) v3(47.08,66.68) v3(47.15,65.92) v3(47.1,63.87) v3(47.13,18.15) v3(47.13,8.36) v3(47.24,96.12) v3(47.25,57.65) v3(47.25,57.4) v3(47.2,53) v3(47.3,81.27) v3(47.25,75.71) v3(47.35,39.17) v3(47.26,27.02) v3(47.42,82.76) v3(47.4,41.55) v3(47.4,35.32) v3(47.4,25.09) v3(47.37,22.98) v3(47.41,20.61) v3(47.49,98.96) v3(47.53,93.69) v3(47.45,58.35) v3(47.5,57.65) v3(47.5,57.4) v3(47.63,92.4) v3(47.62,80.22) v3(47.57,59.3) v3(47.65,42.7) v3(47.57,12.92) v3(47.68,74.23) v3(47.74,71.24) v3(47.65,53.66) v3(47.76,71.81) v3(47.75,70.63) v3(47.75,69.6) v3(47.78,68.37) v3(47.81,66.88) v3(47.75,16.58) v3(47.87,126.64) v3(47.92,124.16) v3(47.95,117.28) v3(47.93,103) v3(47.95,91.71) v3(47.95,79.51) v3(47.87,77.74) v3(47.9,60.97) v3(47.9,44.5) v3(47.9,15.87) v3(48.05,128.85) v3(48,121.95) v3(47.97,119.59) v3(48.04,97.17) v3(47.96,78.38) v3(48.15,89.75) v3(48.07,60.01) v3(48.15,41.95) v3(48.08,7.15) v3(48.19,80.22) v3(48.23,56.95) v3(48.22,55.08) v3(48.2,45.45) v3(48.2,43.6) v3(48.2,39.17) v3(48.2,38.37) v3(48.25,35.6) v3(48.15,31.8) v3(48.33,97.78) v3(48.26,83.65) v3(48.3,81.79) v3(48.27,78.96) v3(48.27,60.46) v3(48.28,52.32) v3(48.39,100.38) v3(48.42,99.21) v3(48.45,94.47) v3(48.45,77.75) v3(48.43,74.75) v3(48.4,61.67) v3(48.44,24.98) v3(48.52,98.38) v3(48.46,93.43) v3(48.48,92.31) v3(48.46,72.39) v3(48.45,70.96) v3(48.53,69.39) v3(48.45,21.88) v3(48.45,19.3) v3(48.65,109.57) v3(48.58,96.6) v3(48.58,95.61) v3(48.62,89.89) v3(48.68,115.94) v3(48.74,101.45) v3(48.7,66.87) v3(48.82,68.6) v3(48.76,67.43) v3(48.79,59.25) v3(48.79,57.68) v3(48.8,56.89) v3(48.81,6.04) v3(48.92,125.59) v3(48.86,112.9) v3(48.95,82.12) v3(48.91,70.11) v3(48.9,57.3) v3(48.89,52.92) v3(48.88,52.29) v3(48.89,48.53) v3(48.95,32.63) v3(49.03,127.9) v3(49.01,82.73) v3(48.95,67) v3(49,57) v3(49.02,10.36) v3(49.02,8.36) v3(49.1,61.87) v3(49.06,54.28) v3(49.15,123.15) v3(49.22,89.2) v3(49.22,76.49) v3(49.21,72.47) v3(49.22,71.02) v3(49.16,14.54) v3(49.31,104.32) v3(49.33,77.78) v3(49.27,60.73) v3(49.31,58.81) v3(49.32,49.84) v3(49.4,99.09) v3(49.39,61.35) v3(49.41,11.75) v3(49.54,95.12) v3(49.5,93.93) v3(49.52,92.79) v3(49.53,91.58) v3(49.5,66.87) v3(49.55,57.1) v3(49.55,52.45) v3(49.48,47.44) v3(49.54,23.58) v3(49.6,105.07) v3(49.57,96.36) v3(49.56,69.36) v3(49.6,67.74) v3(49.64,59.65) v3(49.7,97.62) v3(49.68,89.95) v3(49.72,88.65) v3(49.72,83.36) v3(49.78,84.78) v3(49.76,81.75) v3(49.81,78.84) v3(49.78,76.59) v3(49.84,75.76) v3(49.84,72.55) v3(49.82,71.28) v3(49.8,57.1) v3(49.8,52.45) v3(49.82,20.61) v3(49.89,70.13) v3(49.86,55.07) v3(49.93,4.78) v3(50.03,102.87) v3(49.97,7.15) v3(50.07,126.64) v3(50.12,124.16) v3(50.15,117.28) v3(50.25,128.85) v3(50.2,121.95) v3(50.17,119.59) v3(50.2,67.62) v3(50.2,62.47) v3(50.25,58.8) v3(50.16,1.34) v3(50.29,114.35) v3(50.31,111.54) v3(50.3,111.02) v3(50.39,89.18) v3(50.42,48.52) v3(50.49,99.81) v3(50.5,90.12) v3(50.55,88.25) v3(50.53,80.42) v3(50.5,57.1) v3(50.51,56.79) v3(50.53,54.31) v3(50.52,49.83) v3(50.58,101.54) v3(50.64,96.93) v3(50.64,95.67) v3(50.59,91.71) v3(50.58,87.83) v3(50.58,86.17) v3(50.56,84.15) v3(50.55,82.14) v3(50.56,78.34) v3(50.57,75.79) v3(50.6,73.62) v3(50.57,71.95) v3(50.65,62.72) v3(50.65,61.32) v3(50.65,57.44) v3(50.62,52.99) v3(50.59,51.82) v3(50.6,46.55) v3(50.66,98.14) v3(50.71,94.48) v3(50.66,92.98) v3(50.75,69.92) v3(50.7,58.46) v3(50.8,56.5) v3(50.81,55.96) v3(50.84,16.63) v3(50.82,15.92) v3(50.95,101.45) v3(50.89,70.82) v3(50.9,57.05) v3(50.88,21.89) v3(50.89,13.04) v3(50.97,101.83) v3(50.98,69.05) v3(51.01,6.04) v3(51.12,125.59) v3(51.15,57.3) v3(51.1,56.2) v3(51.23,127.9) v3(51.24,112.91) v3(51.25,68.42) v3(51.17,56.79) v3(51.22,10.36) v3(51.22,8.36) v3(51.33,120.71) v3(51.26,115.84) v3(51.3,89.32) v3(51.32,87.19) v3(51.31,85.36) v3(51.29,83.11) v3(51.33,81.24) v3(51.34,79.39) v3(51.32,77.27) v3(51.33,75.7) v3(51.32,73.69) v3(51.3,71.97) v3(51.31,57.72) v3(51.35,123.15) v3(51.35,118.54) v3(51.42,60.7) v3(51.4,23.95) v3(51.55,91.92) v3(51.5,68.87) v3(51.55,63.5) v3(51.55,63.25) v3(51.46,59.01) v3(51.55,57.1) v3(51.52,52.6) v3(51.6,116.67) v3(51.63,98.56) v3(51.64,97.55) v3(51.64,96.45) v3(51.61,54.95) v3(51.62,54.35) v3(51.55,50.76) v3(51.71,94.98) v3(51.7,27) v3(51.77,101.82) v3(51.78,93.72) v3(51.8,62.65) v3(51.8,62.25) v3(51.8,61.85) v3(51.8,61.45) v3(51.85,59.37) v3(52.05,94.42) v3(52,37.65) v3(52.09,92.81) v3(52.1,92.4) v3(52.1,89.17) v3(52.13,87.93) v3(52.13,84.13) v3(52.14,82.18) v3(52.14,78.33) v3(52.07,77.06) v3(52.08,76.18) v3(52.15,73.57) v3(52.1,70.67) v3(52.07,69.62) v3(52.12,49.86) v3(52.09,48.54) v3(52.13,4.78) v3(52.16,86.31) v3(52.17,80.42) v3(52.2,64.25) v3(52.2,63.85) v3(52.2,63.45) v3(52.2,63.05) v3(52.2,62.65) v3(52.2,62.25) v3(52.2,61.85) v3(52.2,61.45) v3(52.25,58.75) v3(52.17,7.15) v3(52.27,126.64) v3(52.32,124.16) v3(52.35,117.28) v3(52.27,102.94) v3(52.3,95.82) v3(52.32,39.16) v3(52.32,33.68) v3(52.45,128.85) v3(52.4,121.95) v3(52.37,119.59) v3(52.35,59.35) v3(52.4,40.33) v3(52.4,40.03) v3(52.4,23.45) v3(52.36,1.34) v3(52.49,114.35) v3(52.5,14.28) v3(52.61,97.38) v3(52.6,64.25) v3(52.6,63.85) v3(52.6,63.45) v3(52.6,63.05) v3(52.6,62.65) v3(52.6,62.25) v3(52.6,52.7) v3(52.6,52.35) v3(52.55,11.78) v3(52.7,102.97) v3(52.67,71.07) v3(52.7,70.02) v3(52.75,61.82) v3(52.74,54.8) v3(52.71,40.32) v3(52.71,40.02) v3(52.72,15.33) v3(52.85,59.27) v3(52.75,57.1) v3(52.8,23.5) v3(52.9,52.9) v3(52.89,52.54) v3(52.9,52.2) v3(52.87,21.26) v3(53.05,118.97) v3(53,64.25) v3(53,63.85) v3(53,63.45) v3(53,63.05) v3(53.15,58.45) v3(53.09,57.55) v3(53.13,47.38) v3(53.1,45.32) v3(53.11,10.36) v3(53.25,57.9) v3(53.25,29.35) v3(53.32,125.59) v3(53.26,32.33) v3(53.26,31.59) v3(53.26,30.07) v3(53.26,28.58) v3(53.26,27.79) v3(53.43,127.9) v3(53.45,70.77) v3(53.41,67.16) v3(53.35,64.25) v3(53.35,63.85) v3(53.35,63.45) v3(53.35,63.05) v3(53.4,41) v3(53.4,40.7) v3(53.4,40.4) v3(53.4,40.1) v3(53.4,39.8) v3(53.4,39.5) v3(53.53,120.71) v3(53.48,48.5) v3(53.45,36.16) v3(53.45,6.01) v3(53.55,123.15) v3(53.6,111.2) v3(53.6,110.9) v3(53.6,71.17) v3(53.6,63.6) v3(53.6,63.35) v3(53.6,63.1) v3(53.6,62.85) v3(53.7,42.5) v3(53.7,42.2) v3(53.7,41.9) v3(53.7,41.6) v3(53.7,41.3) v3(53.7,41) v3(53.7,40.7) v3(53.7,40.4) v3(53.7,40.1) v3(53.7,39.8) v3(53.7,39.5) v3(53.66,8.34) v3(53.8,67.87) v3(53.79,49.91) v3(53.9,111.5) v3(53.9,111.2) v3(53.9,110.9) v3(53.95,54.81) v3(54,42.2) v3(54,41.9) v3(54,41.6) v3(54,41.3) v3(54,41) v3(54,40.7) v3(54,40.4) v3(54.01,13.03) v3(54.2,111.5) v3(54.2,111.2) v3(54.2,110.9) v3(54.31,68.37) v3(54.26,46.46) v3(54.3,41.45) v3(54.3,41.15) v3(54.3,40.85) v3(54.3,40.55) v3(54.29,32.33) v3(54.29,31.59) v3(54.28,30.07) v3(54.28,29.35) v3(54.29,28.58) v3(54.29,27.79) v3(54.35,111.8) v3(54.47,126.64) v3(54.52,124.16) v3(54.5,111.5) v3(54.5,111.2) v3(54.5,110.9) v3(54.47,67.25) v3(54.65,128.85) v3(54.6,121.95) v3(54.57,119.59) v3(54.6,111.8) v3(54.62,102.95) v3(54.61,7.13) v3(54.57,4.76) v3(54.8,111.5) v3(54.8,111.2) v3(54.8,110.9) v3(54.8,1.32) v3(54.85,111.8) v3(54.95,67.82) v3(55,97.97) v3(55.1,111.8) v3(55.25,114.32) v3(55.25,104.82) v3(55.28,68.47) v3(55.34,30.06) v3(55.34,29.35) v3(55.31,10.36) v3(55.35,111.8) v3(55.35,111.5) v3(55.35,111.2) v3(55.35,110.9) v3(55.4,100.52) v3(55.35,32.32) v3(55.35,31.58) v3(55.35,28.58) v3(55.35,27.78) v3(55.52,125.59) v3(55.5,105.5) v3(55.49,101.46) v3(55.55,94.02) v3(55.5,92.42) v3(55.5,90.97) v3(55.5,89.52) v3(55.5,85.52) v3(55.5,82.72) v3(55.5,80.12) v3(55.5,77.62) v3(55.53,67.16) v3(55.47,2.81) v3(55.63,127.9) v3(55.65,111.5) v3(55.65,111.2) v3(55.65,110.9) v3(55.65,102.97) v3(55.58,98.48) v3(55.64,95.89) v3(55.74,123.18) v3(55.73,120.71) v3(55.66,115.84) v3(55.74,65.96) v3(55.65,6.01) v3(55.75,118.54) v3(55.85,104.82) v3(55.84,69.36) v3(55.81,15.38) v3(55.85,14.28) v3(55.77,11.78) v3(55.9,105.92) v3(55.91,61.54) v3(55.86,8.34) v3(55.95,111.2) v3(55.95,110.9) v3(56,110.1) v3(56,109.8) v3(56,109.5) v3(56.05,108.6) v3(56.05,108.3) v3(56.05,108) v3(56,68.62) v3(56.15,116.82) v3(56.15,107) v3(56.12,63.31) v3(56.12,55.81) v3(56.25,111.2) v3(56.25,110.9) v3(56.22,64.4) v3(56.23,59.34) v3(56.21,57.69) v3(56.3,110.1) v3(56.3,109.8) v3(56.3,109.5) v3(56.3,99.9) v3(56.25,53.82) v3(56.29,51.06) v3(56.3,45.45) v3(56.35,108.6) v3(56.35,108.3) v3(56.35,108) v3(56.42,32.33) v3(56.42,31.59) v3(56.41,30.07) v3(56.4,29.35) v3(56.42,28.58) v3(56.42,27.79) v3(56.55,111.2) v3(56.55,110.9) v3(56.47,67.28) v3(56.54,66.19) v3(56.5,18.75) v3(56.51,18.47) v3(56.52,18.17) v3(56.65,107.22) v3(56.58,97.13) v3(56.65,68.17) v3(56.67,126.64) v3(56.75,117.28) v3(56.74,108.57) v3(56.85,128.85) v3(56.82,124.15) v3(56.8,121.95) v3(56.77,119.59) v3(56.82,102.95) v3(56.83,64.88) v3(56.82,62.24) v3(56.81,7.13) v3(56.77,4.76) v3(56.89,114.35) v3(56.85,111.2) v3(56.85,110.9) v3(57.02,47.85) v3(57,1.32) v3(57.06,122.91) v3(57.2,54.62) v3(57.4,58.64) v3(57.37,57.15) v3(57.41,31.6) v3(57.5,67.27) v3(57.5,64.21) v3(57.5,63.07) v3(57.5,62.57) v3(57.54,55.83) v3(57.52,37.15) v3(57.51,32.32) v3(57.5,30.06) v3(57.5,29.35) v3(57.51,28.58) v3(57.51,27.78) v3(57.51,15.92) v3(57.6,101.42) v3(57.57,66.23) v3(57.6,60.22) v3(57.7,104.67) v3(57.75,10.33) v3(57.67,2.81) v3(57.83,127.9) v3(57.78,98.48) v3(57.83,50.15) v3(57.75,43.81) v3(57.77,13.02) v3(57.86,115.84) v3(57.9,99.97) v3(57.9,64.84) v3(57.86,41.89) v3(57.87,18.88) v3(57.96,121.02) v3(57.95,118.54) v3(57.95,109.92) v3(58.05,62) v3(58.05,61.75) v3(58.05,61.5) v3(58.05,61.25) v3(58.1,54.02) v3(58.1,53.32) v3(58.18,17.98) v3(58.3,62) v3(58.3,61.75) v3(58.3,61.5) v3(58.3,61.25) v3(58.35,38.92) v3(58.4,66.62) v3(58.37,45.9) v3(58.45,112.2) v3(58.48,51.57) v3(58.6,113.1) v3(58.65,117.26) v3(58.74,42.83) v3(58.71,34.14) v3(58.78,97.13) v3(59.05,128.85) v3(59,121.95) v3(58.97,119.59) v3(59.05,98.27) v3(58.99,64.86) v3(59.03,40.57) v3(59.03,17.98) v3(59.07,17.56) v3(59.16,15.38) v3(59.3,74.57) v3(59.35,113) v3(59.35,112.25) v3(59.35,111.5) v3(59.36,34.68) v3(59.38,33.77) v3(59.6,39.42) v3(59.72,21.5) v3(59.82,112.82) v3(59.85,108.52) v3(59.85,101.37) v3(59.85,101.12) v3(59.79,15.32) v3(59.79,11.31) v3(59.9,105.97) v3(59.89,22.57) v3(59.95,10.33) v3(60.03,127.9) v3(60,103.02) v3(59.98,98.48) v3(59.95,73.56) v3(60.08,120.66) v3(60.1,101.37) v3(60.1,101.12) v3(60.11,20.7) v3(60.15,109.92) v3(60.2,105.42) v3(60.19,72.73) v3(60.26,118.84) v3(60.35,101.37) v3(60.35,101.12) v3(60.3,52.82) v3(60.3,47.85) v3(60.27,41.6) v3(60.3,18.89) v3(60.39,107.06) v3(60.35,35.3) v3(60.6,101.37) v3(60.6,101.12) v3(60.56,16.66) v3(60.85,101.37) v3(60.85,101.12) v3(60.79,39.1) v3(60.98,97.13) v3(61.15,102.67) v3(61.1,101.37) v3(61.1,101.12) v3(61.1,98.07) v3(61.1,51.72) v3(61.25,128.85) v3(61.19,121.97) v3(61.25,12.68) v3(61.35,101.37) v3(61.35,101.12) v3(61.32,39.18) v3(61.26,18.25) v3(61.51,111.6) v3(61.49,108.65) v3(61.6,101.37) v3(61.6,101.12) v3(61.65,45.9) v3(61.55,24.22) v3(61.68,105.82) v3(61.69,43.32) v3(61.77,117.34) v3(61.85,101.37) v3(61.85,101.12) v3(61.75,37.55) v3(61.8,25.17) v3(61.91,98.21) v3(61.95,26.3) v3(61.95,33.5) v3(62.1,101.37) v3(62.1,101.12) v3(62.1,74.52) v3(62.07,35.64) v3(62.23,127.9) v3(62.15,72.51) v3(62.35,105.42) v3(62.25,70.49) v3(62.31,15.4) v3(62.42,17.56) v3(62.46,121.45) v3(62.56,109.97) v3(62.62,34.28) v3(62.6,29.27) v3(62.63,22.76) v3(62.67,18.89) v3(62.79,107.12) v3(62.77,33.49) v3(62.9,41.21) v3(62.88,37.26) v3(62.88,36.48) v3(62.89,35.63) v3(62.87,11.36) v3(63,118.02) v3(63.05,52.97) v3(63.01,13.82) v3(63.1,96.62) v3(63.2,124.01) v3(63.25,120.26) v3(63.2,69.97) v3(63.17,38.95) v3(63.2,20.21) v3(63.27,126.64) v3(63.3,71.45) v3(63.45,128.85) v3(63.39,121.97) v3(63.39,73.44) v3(63.45,48.67) v3(63.39,47.9) v3(63.4,23.52) v3(63.44,22.83) v3(63.4,22.07) v3(63.58,119.65) v3(63.61,102.99) v3(63.71,118.66) v3(63.71,111.6) v3(63.69,108.65) v3(63.88,105.82) v3(63.9,70.17) v3(64.05,102.97) v3(64,102.27) v3(64.1,96.37) v3(64.15,22.32) v3(64.32,125.36) v3(64.29,122.64) v3(64.34,12.73) v3(64.43,127.9) v3(64.35,72.51) v3(64.4,16.42) v3(64.47,118.06) v3(64.45,70.49) v3(64.5,43.52) v3(64.5,39.32) v3(64.55,18.42) v3(64.65,102.92) v3(64.65,74.17) v3(64.73,45.95) v3(64.72,20.31) v3(64.76,109.97) v3(64.83,107.14) v3(64.95,105.42) v3(64.9,68.75) v3(64.9,68.5) v3(65.15,68.75) v3(65.15,68.5) v3(65.4,124.01) v3(65.4,68.75) v3(65.4,68.5) v3(65.47,126.64) v3(65.5,71.45) v3(65.55,33.42) v3(65.53,15.4) v3(65.65,128.85) v3(65.59,73.44) v3(65.6,47.22) v3(65.59,35.28) v3(65.7,70.17) v3(65.65,68.75) v3(65.65,68.5) v3(65.75,48.32) v3(65.69,30.22) v3(65.76,121.44) v3(65.8,42.62) v3(65.8,18.42) v3(65.86,119.67) v3(65.9,96.42) v3(65.95,45.77) v3(65.95,44.12) v3(65.94,23.22) v3(65.99,41.25) v3(65.96,37.31) v3(65.97,21.6) v3(65.97,19.21) v3(65.99,17.35) v3(66.1,45.07) v3(66.1,13.87) v3(66.22,11.36) v3(66.42,114.45) v3(66.52,125.36) v3(66.49,122.64) v3(66.5,102.92) v3(66.63,127.9) v3(66.55,72.51) v3(66.7,108.91) v3(66.65,70.49) v3(66.92,115.87) v3(66.9,110.03) v3(67.6,124.01) v3(67.65,121.36) v3(67.67,126.64) v3(67.65,122) v3(67.65,121.75) v3(67.73,97.14) v3(67.7,71.45) v3(67.69,12.73) v3(67.85,128.85) v3(67.79,73.44) v3(67.9,122) v3(67.9,121.75) v3(68.15,122) v3(68.15,121.75) v3(68.5,98.51) v3(68.57,72.51) v3(68.72,125.36) v3(68.69,122.64) v3(68.74,96.36) v3(68.83,127.9) v3(69.14,14.75) v3(69.2,121.05) v3(69.37,11.38) v3(69.45,13.87) v3(69.6,97.57) v3(69.8,124.01) v3(69.87,126.64) v3(69.9,71.45) v3(70.05,128.85) v3(69.99,73.44) v3(70.65,54.92) v3(70.65,54.37) v3(70.65,53.82) v3(70.65,53.27) v3(70.8,120.95) v3(70.77,72.51) v3(70.83,12.75) v3(70.92,125.36) v3(70.89,122.64) v3(70.86,96.35) v3(71.03,127.9) v3(71.05,120.95) v3(71.5,52.12) v3(71.55,51.07) v3(71.94,73.42) v3(71.95,63.47) v3(72,124.01) v3(72.05,102.87) v3(72.05,102.62) v3(71.99,71.37) v3(72,64.52) v3(72.05,61.72) v3(72.05,51.57) v3(72.07,126.64) v3(72.25,128.85) v3(72.19,19.35) v3(72.23,14.8) v3(72.3,102.87) v3(72.3,102.62) v3(72.45,41.27) v3(72.55,102.87) v3(72.55,102.62) v3(72.45,101.65) v3(72.45,100.65) v3(72.45,99.65) v3(72.45,98.65) v3(72.5,52.17) v3(72.6,13.89) v3(72.59,11.38) v3(72.65,97.65) v3(72.8,62.87) v3(72.85,60.22) v3(72.85,59.52) v3(72.85,40.12) v3(72.9,60.52) v3(72.9,59.82) v3(72.95,45.22) v3(72.9,37.37) v3(72.97,72.51) v3(73.05,61.82) v3(73.12,125.36) v3(73.09,122.64) v3(73.1,60.22) v3(73.1,59.52) v3(73.15,46.72) v3(73.23,127.9) v3(73.25,58.75) v3(73.25,39.52) v3(73.25,38.37) v3(73.45,58.57) v3(73.45,42.27) v3(73.45,101.65) v3(73.45,100.65) v3(73.45,99.65) v3(73.45,98.65) v3(73.55,60.55) v3(73.55,59.9) v3(73.5,59.25) v3(73.5,58.25) v3(73.49,28.13) v3(73.6,64.82) v3(73.6,57.82) v3(73.58,31.38) v3(73.65,26.42) v3(73.7,102.87) v3(73.7,102.62) v3(73.75,58.82) v3(73.75,58.12) v3(73.8,60.55) v3(73.8,59.9) v3(73.75,59.25) v3(73.85,57.4) v3(73.8,57) v3(73.85,56.57) v3(73.95,102.87) v3(73.95,102.62) v3(73.9,63.92) v3(73.95,58.47) v3(73.95,57.77) v3(74.14,73.42) v3(74.1,58.8) v3(74.15,47.72) v3(74.15,41.57) v3(74.15,40.42) v3(74.12,39.28) v3(74.06,12.75) v3(74.2,124.01) v3(74.25,121.36) v3(74.2,102.87) v3(74.2,102.62) v3(74.25,58.27) v3(74.2,58) v3(74.25,57.45) v3(74.25,57.07) v3(74.25,56.75) v3(74.27,126.64) v3(74.33,71.28) v3(74.35,46.02) v3(74.35,44.87) v3(74.45,128.85) v3(74.4,63.22) v3(74.42,26.08) v3(74.4,18.82) v3(74.55,122) v3(74.55,121.75) v3(74.45,101.65) v3(74.45,100.65) v3(74.45,99.65) v3(74.45,98.65) v3(74.5,57.85) v3(74.55,57.05) v3(74.55,43.39) v3(74.54,11.59) v3(74.65,58.22) v3(74.65,57.52) v3(74.8,122) v3(74.8,121.75) v3(74.8,64.57) v3(74.85,57.87) v3(74.85,57.17) v3(74.95,56.62) v3(75.05,122) v3(75.05,121.75) v3(75.05,58.22) v3(75.05,57.52) v3(75.05,35.38) v3(75,33.52) v3(75.14,30.31) v3(75.17,72.51) v3(75.2,57.72) v3(75.25,57.25) v3(75.2,56.9) v3(75.32,125.36) v3(75.29,122.64) v3(75.43,127.9) v3(75.4,14.77) v3(75.45,101.65) v3(75.45,100.65) v3(75.45,99.65) v3(75.45,98.65) v3(75.47,19.35) v3(75.65,102.4) v3(75.65,102.1) v3(75.65,101.8) v3(75.7,41.3) v3(75.68,37.35) v3(75.82,13.89) v3(75.9,39.27) v3(75.9,38.12) v3(76.05,121.05) v3(75.95,102.4) v3(75.95,101.8) v3(76.05,24.02) v3(76.25,102.4) v3(76.25,102.1) v3(76.25,101.8) v3(76.25,65.07) v3(76.34,73.42) 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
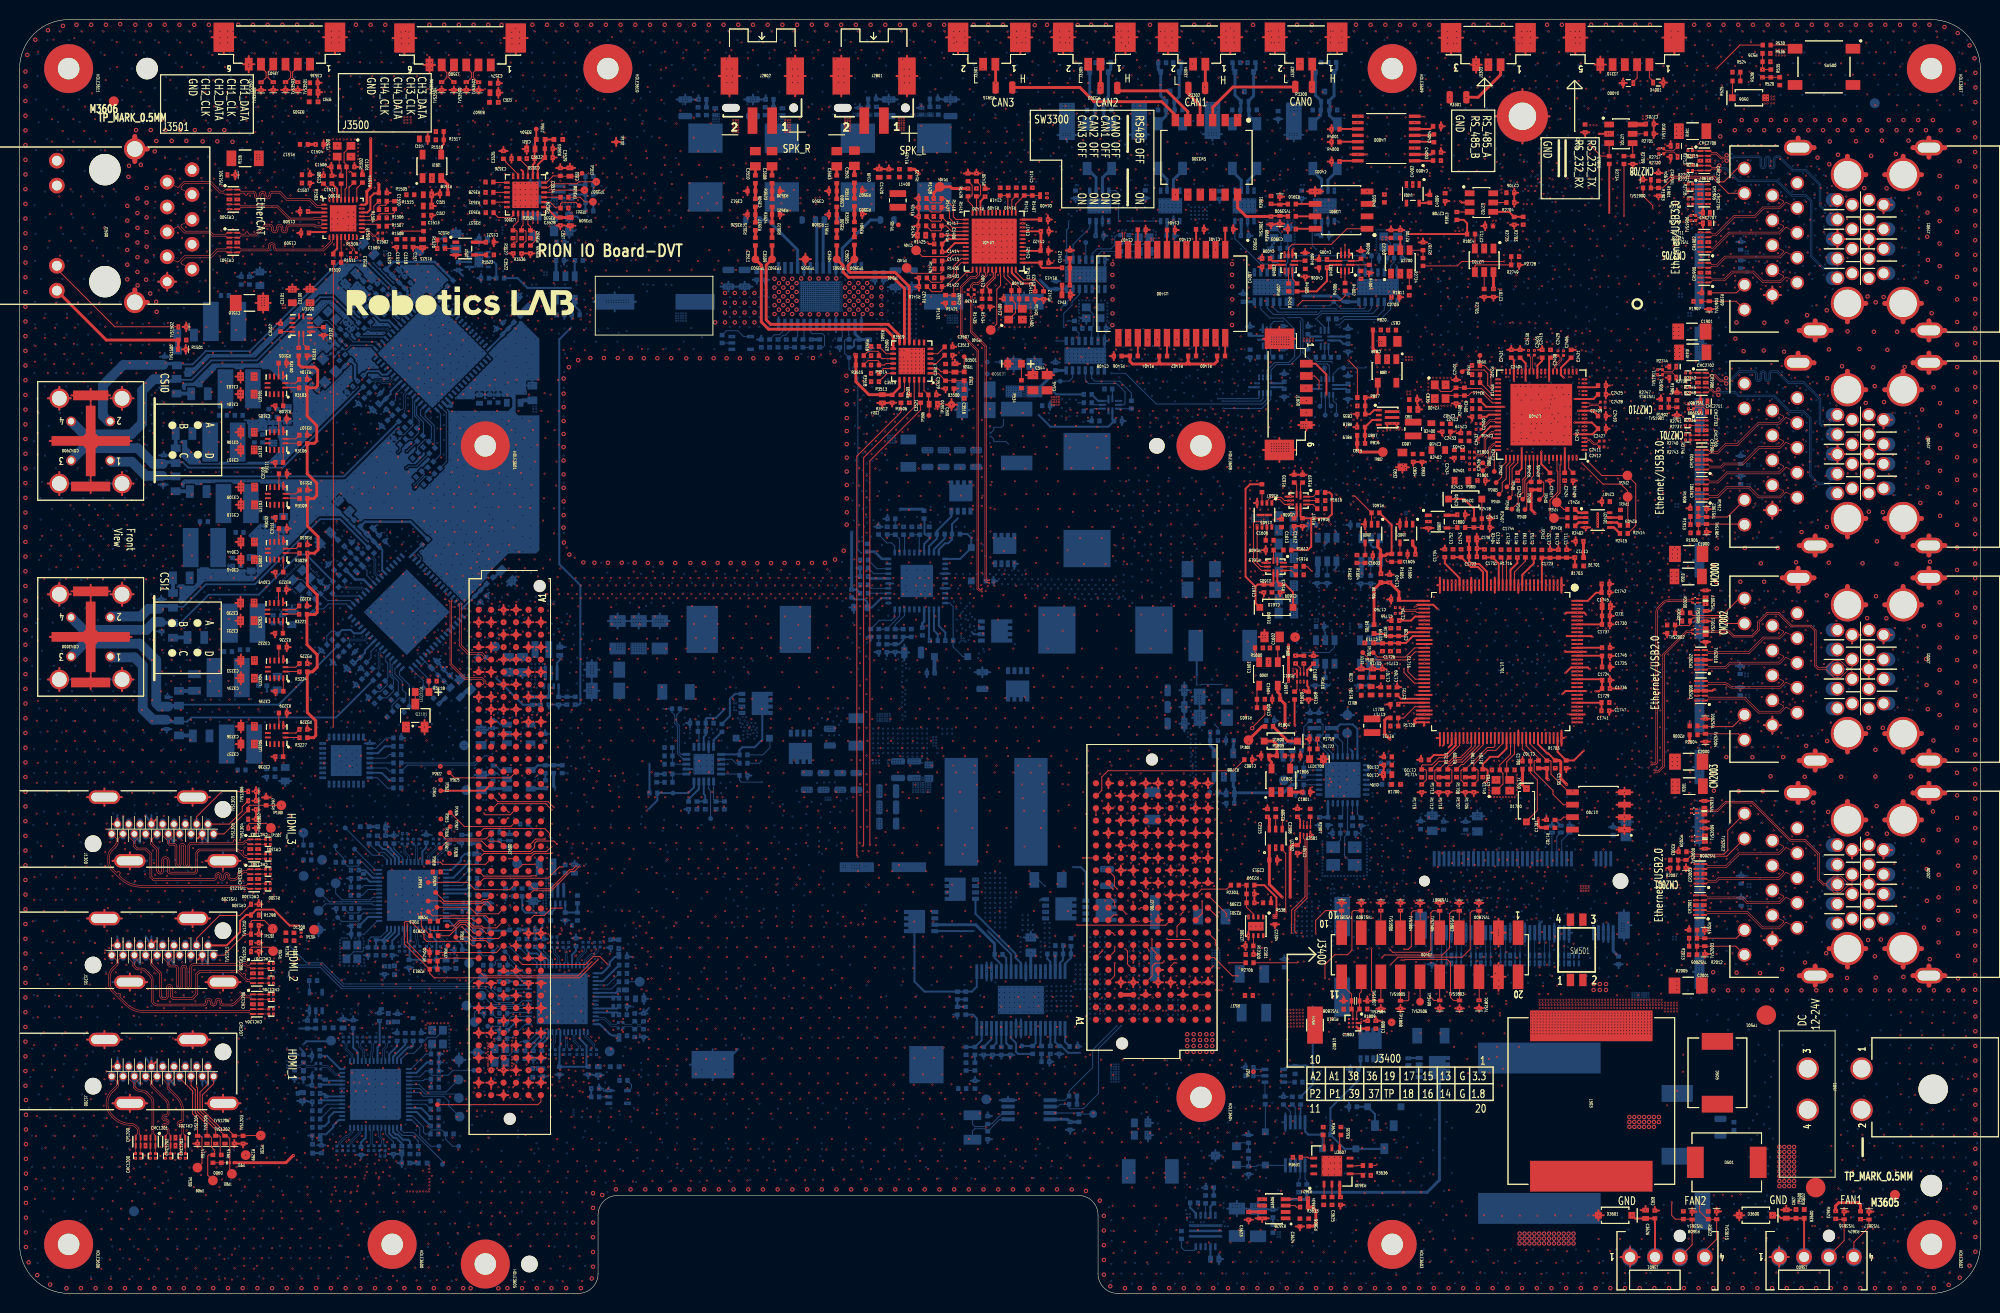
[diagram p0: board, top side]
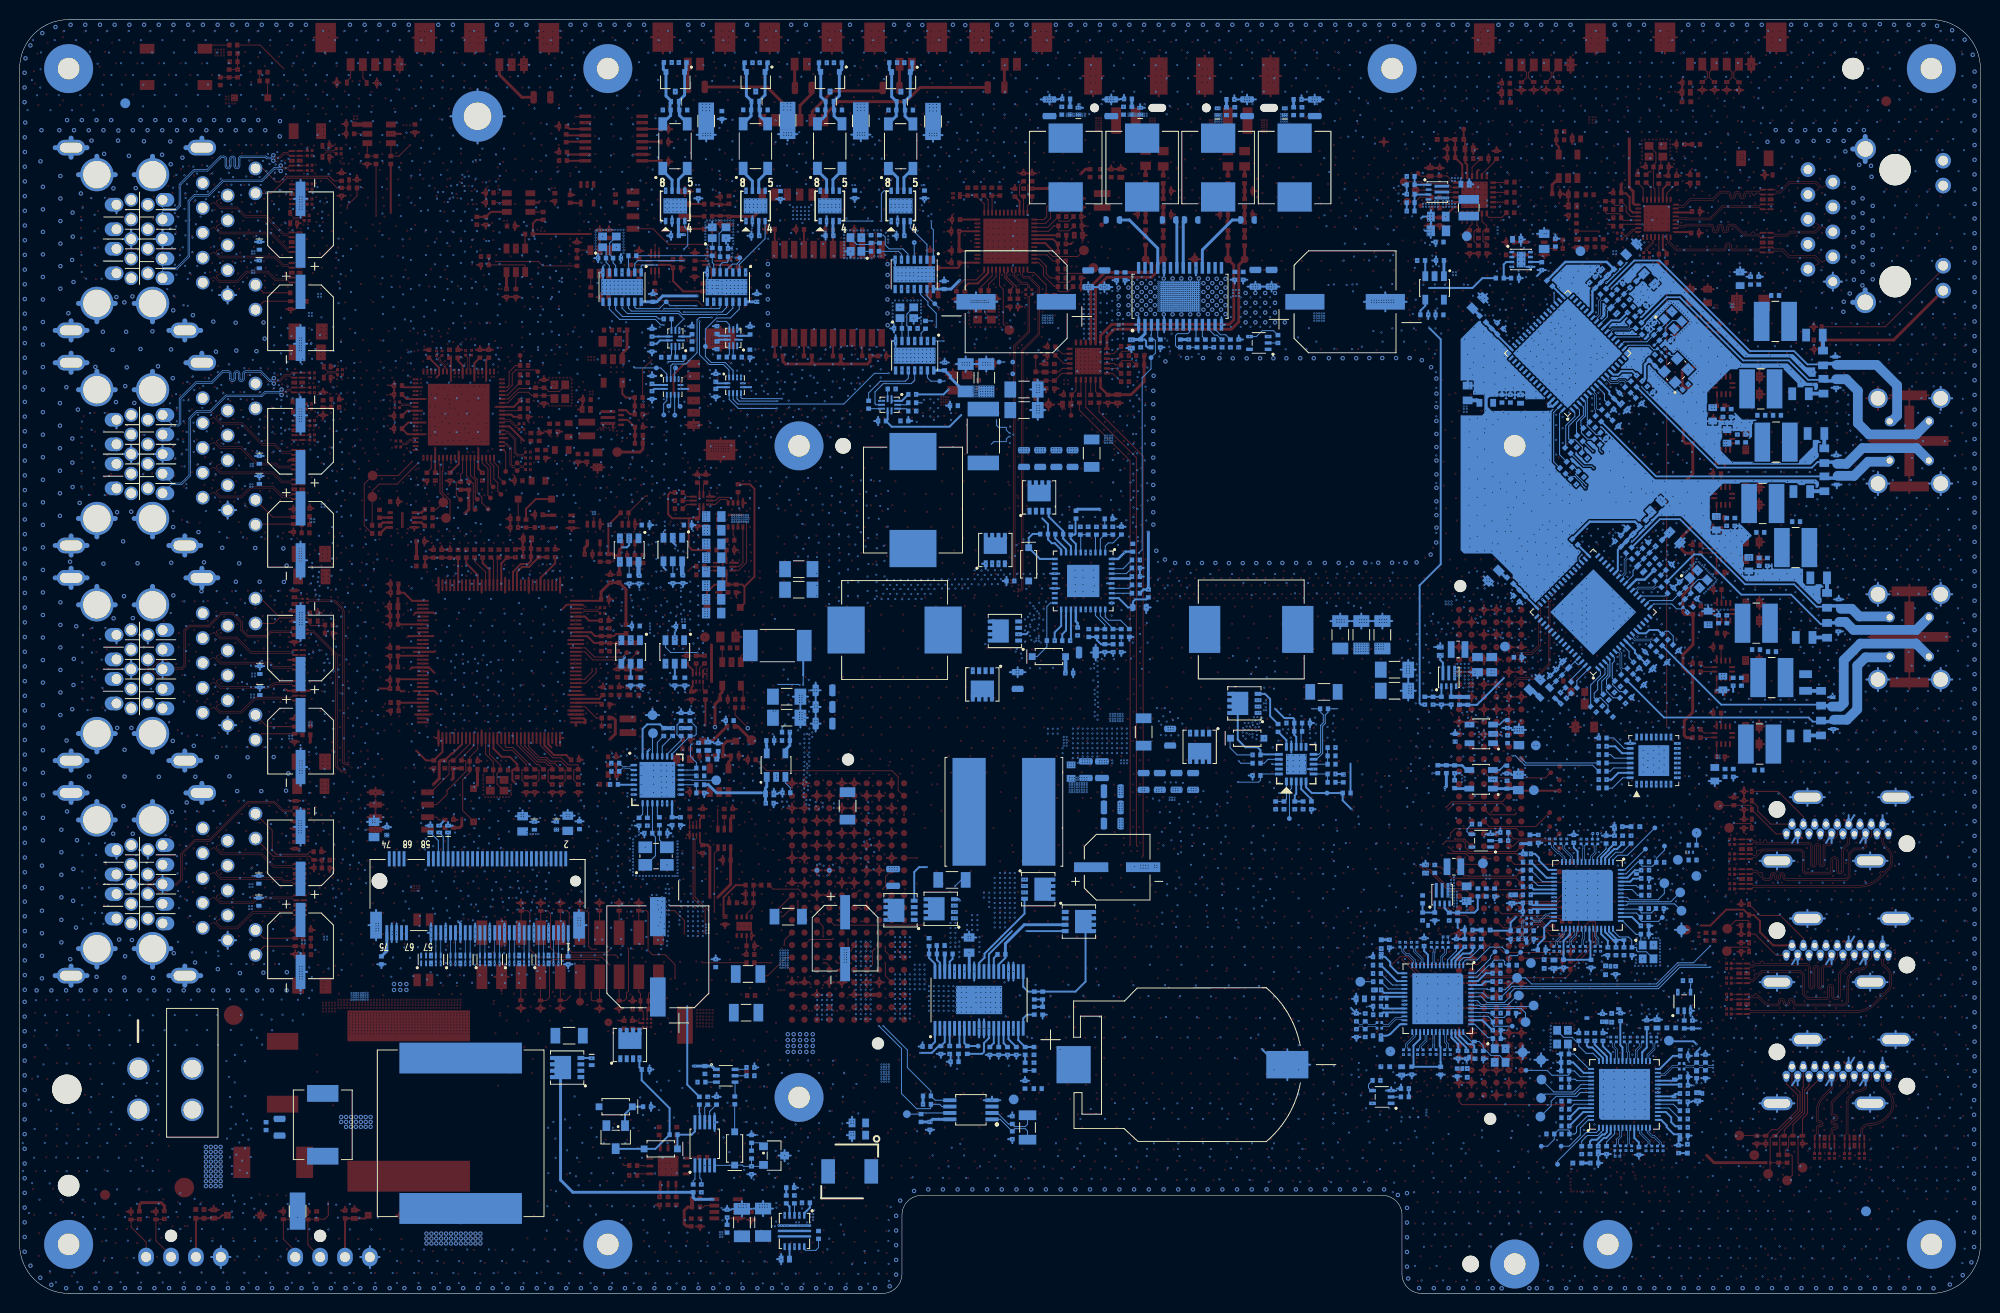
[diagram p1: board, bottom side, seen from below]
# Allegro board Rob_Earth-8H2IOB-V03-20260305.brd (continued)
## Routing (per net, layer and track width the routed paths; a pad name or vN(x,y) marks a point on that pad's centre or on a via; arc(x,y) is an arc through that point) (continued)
GND_EARTH: length 1227.8
  TOP w0.5: 183.15,97.3 J1901.G5 ; J1901.G5 184.78,98.28 ; J1901.G5 183.15,99.26 ; J1901.G5 181.52,98.28 ; J2000.G3 194,48.33 ; J2000.G3 192.12,50.2 ; J2000.G3 190.24,48.33 ; J2000.G8 196.38,32.43 ; J2000.G8 194.75,31.45 ; J2000.G8 194.75,33.41 ; J2000.G8 193.12,32.43 ; J1901.G7 196.38,116.93 ; J1901.G7 194.75,117.91 ; J1901.G7 194.75,115.95 ; J1901.G7 193.12,116.93 ; J2001.G8 194.75,55.36 ; J2001.G8 196.38,54.38 ; J2001.G8 193.12,54.38 ; J2001.G8 194.75,53.4 ; 181.41,50.1 J2000.G6 ; J2000.G6 181.41,52.06 ; J2000.G6 183.04,51.08 ; 186.44,33.31 J2000.G1 ; J2000.G1 184.56,35.19 ; J2000.G1 188.32,35.19 ; J1901.G3 194,114.17 ; J1901.G3 190.24,114.17 ; J1901.G3 192.12,116.05 ; 192.12,33.31 J2000.G4 ; J2000.G4 190.24,35.19 ; J2000.G4 194,35.19 ; J1901.G8 196.38,98.28 ; J1901.G8 193.12,98.28 ; J1901.G8 194.75,97.3 ; J1901.G8 194.75,99.26 ; 186.44,77.21 186.44,79.08 188.32,79.08 ; J2000.G5 184.78,32.43 ; J2000.G5 181.52,32.43 ; J2000.G5 183.15,33.41 ; J2000.G5 183.15,31.45 ; 186.44,55.26 J2001.G1 188.32,57.13 ; J2001.G7 196.38,73.03 ; J2001.G7 193.12,73.03 ; J2001.G7 194.75,74.01 ; J2001.G7 194.75,72.05 ; 179.78,73.03 J2001.G6 ; J2001.G6 181.41,72.05 ; J2001.G6 181.41,74.01 ; J2001.G6 183.04,73.03 ; 193.12,94.98 J1900.G7 ; J1900.G7 194.75,94 ; J1900.G7 196.38,94.98 ; J1900.G7 194.75,95.96 ; 190.24,101.03 J1901.G4 ; J1901.G4 194,101.03 ; J1901.G4 192.12,99.16 ; J2001.G4 194,57.13 ; J2001.G4 192.12,55.26 ; J2001.G4 190.24,57.13 ; 183.04,116.93 J1901.G6 181.41,117.91 ; J1900.G3 194,92.22 ; J1900.G3 190.24,92.22 ; J1900.G3 192.12,94.1 ; J1900.G8 196.38,76.33 ; J1900.G8 194.75,75.35 ; J1900.G8 194.75,77.31 ; J1900.G8 193.12,76.33 ; 183.15,75.35 J1900.G5 ; J1900.G5 183.15,77.31 ; J1900.G5 184.78,76.33 ; J1900.G5 181.52,76.33 ; J2001.G5 184.78,54.38 ; J2001.G5 181.52,54.38 ; J2001.G5 183.15,53.4 ; J2001.G5 183.15,55.36 ; 186.44,50.2 J2000.G2 188.32,48.33 ; J2000.G7 194.75,52.06 ; J2000.G7 194.75,50.1 ; J2000.G7 193.12,51.08 ; J2000.G7 196.38,51.08 ; 186.44,116.05 J1901.G2 188.32,114.17 ; 183.04,94.98 J1900.G6 181.41,95.96 ; 188.32,101.03 J1901.G1 186.44,99.16 ; 186.44,94.1 J1900.G2 188.32,92.22 ; 190.24,70.28 J2001.G3 ; J2001.G3 194,70.28 ; J2001.G3 192.12,72.15 ; 192.12,79.08 194,79.08 ; 192.12,79.08 192.12,77.21 ; 192.12,79.08 190.24,79.08 ; 186.44,72.15 J2001.G2 188.32,70.28
  L2 w0.5: J2000.G1 188.32,35.19 ; J2000.G1 184.56,35.19 ; J2000.G1 186.44,33.31 ; J1900.G8 196.38,76.33 ; J1900.G8 194.75,75.35 ; J1900.G8 193.12,76.33 ; J1900.G8 194.75,77.31 ; 181.52,32.43 J2000.G5 ; J2000.G5 183.15,31.45 ; J2000.G5 184.78,32.43 ; J2000.G5 183.15,33.41 ; J2001.G3 194,70.28 ; J2001.G3 192.12,72.15 ; J2001.G3 190.24,70.28 ; 190.24,92.22 J1900.G3 ; J1900.G3 192.12,94.1 ; J1900.G3 194,92.22 ; 194.75,94 J1900.G7 ; J1900.G7 194.75,95.96 ; J1900.G7 193.12,94.98 ; J1900.G7 196.38,94.98 ; 194.75,97.3 J1901.G8 ; J1901.G8 196.38,98.28 ; J1901.G8 193.12,98.28 ; J1901.G8 194.75,99.26 ; J2000.G8 196.38,32.43 ; J2000.G8 194.75,31.45 ; J2000.G8 194.75,33.41 ; J2000.G8 193.12,32.43 ; 186.44,55.26 J2001.G1 188.32,57.13 ; 190.24,57.13 J2001.G4 ; J2001.G4 194,57.13 ; J2001.G4 192.12,55.26 ; 188.32,79.08 186.44,79.08 186.44,77.21 ; 186.44,116.05 J1901.G2 188.32,114.17 ; 186.44,50.2 J2000.G2 188.32,48.33 ; 181.52,54.38 J2001.G5 ; J2001.G5 183.15,55.36 ; J2001.G5 184.78,54.38 ; J2001.G5 183.15,53.4 ; 194.75,53.4 J2001.G8 ; J2001.G8 194.75,55.36 ; J2001.G8 196.38,54.38 ; J2001.G8 193.12,54.38 ; 186.44,72.15 J2001.G2 188.32,70.28 ; 194.75,72.05 J2001.G7 ; J2001.G7 193.12,73.03 ; J2001.G7 196.38,73.03 ; J2001.G7 194.75,74.01 ; J2001.G6 183.04,73.03 ; J2001.G6 181.41,74.01 ; J2001.G6 179.78,73.03 ; J2001.G6 181.41,72.05 ; J1901.G7 196.38,116.93 ; J1901.G7 194.75,117.91 ; J1901.G7 194.75,115.95 ; J1901.G7 193.12,116.93 ; 186.44,99.16 J1901.G1 188.32,101.03 ; 183.04,116.93 J1901.G6 181.41,117.91 ; 193.12,51.08 J2000.G7 ; J2000.G7 194.75,50.1 ; J2000.G7 196.38,51.08 ; J2000.G7 194.75,52.06 ; 190.24,79.08 192.12,79.08 ; 192.12,79.08 192.12,77.21 ; 192.12,79.08 194,79.08 ; 190.24,101.03 J1901.G4 ; J1901.G4 192.12,99.16 ; J1901.G4 194,101.03 ; 181.41,50.1 J2000.G6 ; J2000.G6 181.41,52.06 ; J2000.G6 183.04,51.08 ; J2000.G4 194,35.19 ; J2000.G4 190.24,35.19 ; J2000.G4 192.12,33.31 ; J2000.G3 194,48.33 ; J2000.G3 192.12,50.2 ; J2000.G3 190.24,48.33 ; 183.04,94.98 J1900.G6 181.41,95.96 ; J1901.G5 184.78,98.28 ; J1901.G5 183.15,97.3 ; J1901.G5 181.52,98.28 ; J1901.G5 183.15,99.26 ; J1901.G3 192.12,116.05 ; J1901.G3 190.24,114.17 ; J1901.G3 194,114.17 ; J1900.G5 184.78,76.33 ; J1900.G5 183.15,75.35 ; J1900.G5 183.15,77.31 ; J1900.G5 181.52,76.33 ; 188.32,92.22 J1900.G2 186.44,94.1
  L3 w0.5: 194.75,97.3 J1901.G8 ; J1901.G8 196.38,98.28 ; J1901.G8 193.12,98.28 ; J1901.G8 194.75,99.26 ; 179.78,73.03 J2001.G6 ; J2001.G6 181.41,72.05 ; J2001.G6 181.41,74.01 ; J2001.G6 183.04,73.03 ; 181.41,117.91 J1901.G6 183.04,116.93 ; J1901.G3 194,114.17 ; J1901.G3 190.24,114.17 ; J1901.G3 192.12,116.05 ; 186.44,77.21 186.44,79.08 188.32,79.08 ; 190.24,101.03 J1901.G4 ; J1901.G4 192.12,99.16 ; J1901.G4 194,101.03 ; J2001.G3 194,70.28 ; J2001.G3 192.12,72.15 ; J2001.G3 190.24,70.28 ; 192.12,77.21 192.12,79.08 ; 192.12,79.08 190.24,79.08 ; 192.12,79.08 194,79.08 ; J2000.G8 194.75,33.41 ; J2000.G8 196.38,32.43 ; J2000.G8 193.12,32.43 ; J2000.G8 194.75,31.45 ; 193.12,73.03 J2001.G7 ; J2001.G7 194.75,74.01 ; J2001.G7 196.38,73.03 ; J2001.G7 194.75,72.05 ; J1900.G5 183.15,77.31 ; J1900.G5 183.15,75.35 ; J1900.G5 181.52,76.33 ; J1900.G5 184.78,76.33 ; 181.41,50.1 J2000.G6 ; J2000.G6 181.41,52.06 ; J2000.G6 183.04,51.08 ; J2000.G6 179.78,51.08 ; J2000.G3 192.12,50.2 ; J2000.G3 190.24,48.33 ; J2000.G3 194,48.33 ; 186.44,72.15 J2001.G2 188.32,70.28 ; J1901.G7 196.38,116.93 ; J1901.G7 194.75,117.91 ; J1901.G7 194.75,115.95 ; J1901.G7 193.12,116.93 ; 183.04,94.98 J1900.G6 181.41,95.96 ; 193.12,94.98 J1900.G7 ; J1900.G7 194.75,94 ; J1900.G7 196.38,94.98 ; J1900.G7 194.75,95.96 ; J2001.G5 183.15,55.36 ; J2001.G5 183.15,53.4 ; J2001.G5 184.78,54.38 ; J2001.G5 181.52,54.38 ; 188.32,101.03 J1901.G1 186.44,99.16 ; 183.15,31.45 J2000.G5 ; J2000.G5 184.78,32.43 ; J2000.G5 183.15,33.41 ; J2000.G5 181.52,32.43 ; J2000.G1 188.32,35.19 ; J2000.G1 186.44,33.31 ; J2000.G1 184.56,35.19 ; 188.32,48.33 J2000.G2 186.44,50.2 ; 190.24,57.13 J2001.G4 ; J2001.G4 192.12,55.26 ; J2001.G4 194,57.13 ; J1900.G8 196.38,76.33 ; J1900.G8 194.75,77.31 ; J1900.G8 194.75,75.35 ; J1900.G8 193.12,76.33 ; 186.44,55.26 J2001.G1 188.32,57.13 ; J2001.G8 194.75,55.36 ; J2001.G8 194.75,53.4 ; J2001.G8 196.38,54.38 ; J2001.G8 193.12,54.38 ; 190.24,92.22 J1900.G3 ; J1900.G3 192.12,94.1 ; J1900.G3 194,92.22 ; 181.52,98.28 J1901.G5 ; J1901.G5 184.78,98.28 ; J1901.G5 183.15,99.26 ; J1901.G5 183.15,97.3 ; 190.24,35.19 J2000.G4 ; J2000.G4 192.12,33.31 ; J2000.G4 194,35.19 ; 186.44,116.05 J1901.G2 188.32,114.17 ; 188.32,92.22 J1900.G2 186.44,94.1 ; 194.75,50.1 J2000.G7 ; J2000.G7 194.75,52.06 ; J2000.G7 193.12,51.08 ; J2000.G7 196.38,51.08
  L4 w0.5: 194.75,97.3 J1901.G8 ; J1901.G8 194.75,99.26 ; J1901.G8 193.12,98.28 ; J1901.G8 196.38,98.28 ; 193.12,51.08 J2000.G7 ; J2000.G7 194.75,50.1 ; J2000.G7 196.38,51.08 ; J2000.G7 194.75,52.06 ; J2000.G8 194.75,33.41 ; J2000.G8 196.38,32.43 ; J2000.G8 193.12,32.43 ; J2000.G8 194.75,31.45 ; 183.04,116.93 J1901.G6 181.41,117.91 ; 181.52,32.43 J2000.G5 ; J2000.G5 183.15,33.41 ; J2000.G5 183.15,31.45 ; J2000.G5 184.78,32.43 ; 194.75,53.4 J2001.G8 ; J2001.G8 194.75,55.36 ; J2001.G8 193.12,54.38 ; J2001.G8 196.38,54.38 ; 190.24,92.22 J1900.G3 ; J1900.G3 194,92.22 ; J1900.G3 192.12,94.1 ; 186.44,55.26 J2001.G1 188.32,57.13 ; 194.75,72.05 J2001.G7 ; J2001.G7 196.38,73.03 ; J2001.G7 194.75,74.01 ; J2001.G7 193.12,73.03 ; 181.52,76.33 J1900.G5 ; J1900.G5 184.78,76.33 ; J1900.G5 183.15,75.35 ; J1900.G5 183.15,77.31 ; 192.12,77.21 192.12,79.08 ; 192.12,79.08 194,79.08 ; 192.12,79.08 190.24,79.08 ; 181.41,50.1 J2000.G6 ; J2000.G6 183.04,51.08 ; J2000.G6 181.41,52.06 ; 192.12,33.31 J2000.G4 ; J2000.G4 190.24,35.19 ; J2000.G4 194,35.19 ; J2001.G5 183.15,55.36 ; J2001.G5 184.78,54.38 ; J2001.G5 181.52,54.38 ; J2001.G5 183.15,53.4 ; J2000.G1 188.32,35.19 ; J2000.G1 186.44,33.31 ; J2000.G1 184.56,35.19 ; J1901.G3 192.12,116.05 ; J1901.G3 194,114.17 ; J1901.G3 190.24,114.17 ; 186.44,72.15 J2001.G2 188.32,70.28 ; 188.32,114.17 J1901.G2 186.44,116.05 ; 181.52,98.28 J1901.G5 ; J1901.G5 183.15,99.26 ; J1901.G5 184.78,98.28 ; J1901.G5 183.15,97.3 ; 194.75,94 J1900.G7 ; J1900.G7 193.12,94.98 ; J1900.G7 196.38,94.98 ; J1900.G7 194.75,95.96 ; 188.32,101.03 J1901.G1 186.44,99.16 ; 194.75,75.35 J1900.G8 ; J1900.G8 196.38,76.33 ; J1900.G8 193.12,76.33 ; J1900.G8 194.75,77.31 ; 186.44,50.2 J2000.G2 188.32,48.33 ; J1901.G4 194,101.03 ; J1901.G4 190.24,101.03 ; J1901.G4 192.12,99.16 ; 181.41,72.05 J2001.G6 ; J2001.G6 183.04,73.03 ; J2001.G6 179.78,73.03 ; J2001.G6 181.41,74.01 ; J2000.G3 192.12,50.2 ; J2000.G3 190.24,48.33 ; J2000.G3 194,48.33 ; 186.44,94.1 J1900.G2 188.32,92.22 ; J2001.G4 194,57.13 ; J2001.G4 192.12,55.26 ; J2001.G4 190.24,57.13 ; 188.32,79.08 186.44,79.08 186.44,77.21 ; J2001.G3 194,70.28 ; J2001.G3 192.12,72.15 ; J2001.G3 190.24,70.28 ; 193.12,116.93 J1901.G7 ; J1901.G7 194.75,117.91 ; J1901.G7 194.75,115.95 ; J1901.G7 196.38,116.93 ; 183.04,94.98 J1900.G6 181.41,95.96
  L5 w0.5: 190.24,70.28 J2001.G3 ; J2001.G3 192.12,72.15 ; J2001.G3 194,70.28 ; 184.56,35.19 J2000.G1 ; J2000.G1 188.32,35.19 ; J2000.G1 186.44,33.31 ; J2000.G8 194.75,33.41 ; J2000.G8 194.75,31.45 ; J2000.G8 193.12,32.43 ; J2000.G8 196.38,32.43 ; 194.75,97.3 J1901.G8 ; J1901.G8 193.12,98.28 ; J1901.G8 196.38,98.28 ; J1901.G8 194.75,99.26 ; 188.32,79.08 186.44,79.08 186.44,77.21 ; 186.44,94.1 J1900.G2 188.32,92.22 ; 193.12,51.08 J2000.G7 ; J2000.G7 194.75,50.1 ; J2000.G7 196.38,51.08 ; J2000.G7 194.75,52.06 ; J1901.G3 194,114.17 ; J1901.G3 190.24,114.17 ; J1901.G3 192.12,116.05 ; J1900.G3 194,92.22 ; J1900.G3 190.24,92.22 ; J1900.G3 192.12,94.1 ; 188.32,48.33 J2000.G2 186.44,50.2 ; J1901.G4 194,101.03 ; J1901.G4 190.24,101.03 ; J1901.G4 192.12,99.16 ; J2000.G5 183.15,33.41 ; J2000.G5 184.78,32.43 ; J2000.G5 183.15,31.45 ; J2000.G5 181.52,32.43 ; 194.75,115.95 J1901.G7 ; J1901.G7 194.75,117.91 ; J1901.G7 196.38,116.93 ; J1901.G7 193.12,116.93 ; J2001.G8 196.38,54.38 ; J2001.G8 194.75,53.4 ; J2001.G8 194.75,55.36 ; J2001.G8 193.12,54.38 ; 186.44,72.15 J2001.G2 188.32,70.28 ; J1900.G7 194.75,95.96 ; J1900.G7 193.12,94.98 ; J1900.G7 194.75,94 ; J1900.G7 196.38,94.98 ; 190.24,35.19 J2000.G4 ; J2000.G4 194,35.19 ; J2000.G4 192.12,33.31 ; 183.04,116.93 J1901.G6 181.41,117.91 ; 194.75,75.35 J1900.G8 ; J1900.G8 193.12,76.33 ; J1900.G8 194.75,77.31 ; J1900.G8 196.38,76.33 ; 183.15,97.3 J1901.G5 ; J1901.G5 184.78,98.28 ; J1901.G5 181.52,98.28 ; J1901.G5 183.15,99.26 ; 193.12,73.03 J2001.G7 ; J2001.G7 194.75,72.05 ; J2001.G7 194.75,74.01 ; J2001.G7 196.38,73.03 ; J2001.G6 181.41,74.01 ; J2001.G6 181.41,72.05 ; J2001.G6 179.78,73.03 ; J2001.G6 183.04,73.03 ; 192.12,55.26 J2001.G4 ; J2001.G4 194,57.13 ; J2001.G4 190.24,57.13 ; 181.41,95.96 J1900.G6 183.04,94.98 ; 181.52,76.33 J1900.G5 ; J1900.G5 184.78,76.33 ; J1900.G5 183.15,75.35 ; J1900.G5 183.15,77.31 ; J2001.G5 184.78,54.38 ; J2001.G5 183.15,53.4 ; J2001.G5 183.15,55.36 ; J2001.G5 181.52,54.38 ; 188.32,57.13 J2001.G1 186.44,55.26 ; J2000.G6 183.04,51.08 ; J2000.G6 181.41,50.1 ; J2000.G6 181.41,52.06 ; 192.12,79.08 194,79.08 ; 192.12,79.08 190.24,79.08 ; 192.12,79.08 192.12,77.21 ; 188.32,101.03 J1901.G1 186.44,99.16 ; 186.44,116.05 J1901.G2 188.32,114.17 ; 190.24,48.33 J2000.G3 ; J2000.G3 192.12,50.2 ; J2000.G3 194,48.33
  L6 w0.5: 186.44,116.05 J1901.G2 188.32,114.17 ; J2000.G4 194,35.19 ; J2000.G4 190.24,35.19 ; J2000.G4 192.12,33.31 ; J2001.G4 194,57.13 ; J2001.G4 190.24,57.13 ; J2001.G4 192.12,55.26 ; 188.32,92.22 J1900.G2 186.44,94.1 ; J2000.G3 194,48.33 ; J2000.G3 190.24,48.33 ; J2000.G3 192.12,50.2 ; 192.12,99.16 J1901.G4 ; J1901.G4 190.24,101.03 ; J1901.G4 194,101.03 ; 190.24,114.17 J1901.G3 ; J1901.G3 194,114.17 ; J1901.G3 192.12,116.05 ; 194.75,31.45 J2000.G8 ; J2000.G8 193.12,32.43 ; J2000.G8 194.75,33.41 ; J2000.G8 196.38,32.43 ; J1901.G5 183.15,99.26 ; J1901.G5 181.52,98.28 ; J1901.G5 183.15,97.3 ; J1901.G5 184.78,98.28 ; 181.41,72.05 J2001.G6 ; J2001.G6 181.41,74.01 ; J2001.G6 179.78,73.03 ; J2001.G6 183.04,73.03 ; J1900.G3 192.12,94.1 ; J1900.G3 194,92.22 ; J1900.G3 190.24,92.22 ; 181.41,95.96 J1900.G6 183.04,94.98 ; 184.56,35.19 J2000.G1 ; J2000.G1 186.44,33.31 ; J2000.G1 188.32,35.19 ; 190.24,70.28 J2001.G3 ; J2001.G3 194,70.28 ; J2001.G3 192.12,72.15 ; 194.75,72.05 J2001.G7 ; J2001.G7 196.38,73.03 ; J2001.G7 193.12,73.03 ; J2001.G7 194.75,74.01 ; 183.15,75.35 J1900.G5 ; J1900.G5 184.78,76.33 ; J1900.G5 181.52,76.33 ; J1900.G5 183.15,77.31 ; J1900.G8 196.38,76.33 ; J1900.G8 194.75,75.35 ; J1900.G8 194.75,77.31 ; J1900.G8 193.12,76.33 ; 181.41,117.91 J1901.G6 183.04,116.93 ; 190.24,79.08 192.12,79.08 ; 192.12,79.08 192.12,77.21 ; 192.12,79.08 194,79.08 ; J1900.G7 196.38,94.98 ; J1900.G7 194.75,94 ; J1900.G7 194.75,95.96 ; J1900.G7 193.12,94.98 ; 181.41,50.1 J2000.G6 ; J2000.G6 181.41,52.06 ; J2000.G6 183.04,51.08 ; 186.44,77.21 186.44,79.08 188.32,79.08 ; J2000.G7 196.38,51.08 ; J2000.G7 194.75,52.06 ; J2000.G7 193.12,51.08 ; J2000.G7 194.75,50.1 ; J2000.G5 184.78,32.43 ; J2000.G5 183.15,31.45 ; J2000.G5 183.15,33.41 ; J2000.G5 181.52,32.43 ; J1901.G8 194.75,99.26 ; J1901.G8 193.12,98.28 ; J1901.G8 194.75,97.3 ; J1901.G8 196.38,98.28 ; 188.32,57.13 J2001.G1 186.44,55.26 ; 186.44,50.2 J2000.G2 188.32,48.33 ; J2001.G5 184.78,54.38 ; J2001.G5 181.52,54.38 ; J2001.G5 183.15,55.36 ; J2001.G5 183.15,53.4 ; 193.12,116.93 J1901.G7 ; J1901.G7 194.75,117.91 ; J1901.G7 194.75,115.95 ; J1901.G7 196.38,116.93 ; 186.44,72.15 J2001.G2 188.32,70.28 ; 186.44,99.16 J1901.G1 188.32,101.03 ; J2001.G8 194.75,55.36 ; J2001.G8 193.12,54.38 ; J2001.G8 194.75,53.4 ; J2001.G8 196.38,54.38
  L7 w0.5: 186.44,99.16 J1901.G1 188.32,101.03 ; 194.75,72.05 J2001.G7 ; J2001.G7 194.75,74.01 ; J2001.G7 193.12,73.03 ; J2001.G7 196.38,73.03 ; 194.75,115.95 J1901.G7 ; J1901.G7 196.38,116.93 ; J1901.G7 193.12,116.93 ; J1901.G7 194.75,117.91 ; 183.15,97.3 J1901.G5 ; J1901.G5 183.15,99.26 ; J1901.G5 181.52,98.28 ; J1901.G5 184.78,98.28 ; 190.24,48.33 J2000.G3 ; J2000.G3 194,48.33 ; J2000.G3 192.12,50.2 ; 193.12,32.43 J2000.G8 ; J2000.G8 194.75,33.41 ; J2000.G8 194.75,31.45 ; J2000.G8 196.38,32.43 ; 193.12,51.08 J2000.G7 ; J2000.G7 196.38,51.08 ; J2000.G7 194.75,50.1 ; J2000.G7 194.75,52.06 ; J2000.G6 181.41,52.06 ; J2000.G6 183.04,51.08 ; J2000.G6 181.41,50.1 ; 188.32,48.33 J2000.G2 186.44,50.2 ; 186.44,94.1 J1900.G2 188.32,92.22 ; 181.52,32.43 J2000.G5 ; J2000.G5 183.15,31.45 ; J2000.G5 183.15,33.41 ; J2000.G5 184.78,32.43 ; J1901.G8 196.38,98.28 ; J1901.G8 194.75,97.3 ; J1901.G8 193.12,98.28 ; J1901.G8 194.75,99.26 ; 183.04,94.98 J1900.G6 181.41,95.96 ; 190.24,35.19 J2000.G4 ; J2000.G4 194,35.19 ; J2000.G4 192.12,33.31 ; 184.56,35.19 J2000.G1 ; J2000.G1 186.44,33.31 ; J2000.G1 188.32,35.19 ; J2001.G5 184.78,54.38 ; J2001.G5 183.15,53.4 ; J2001.G5 183.15,55.36 ; J2001.G5 181.52,54.38 ; 193.12,54.38 J2001.G8 ; J2001.G8 196.38,54.38 ; J2001.G8 194.75,55.36 ; J2001.G8 194.75,53.4 ; 192.12,77.21 192.12,79.08 ; 192.12,79.08 194,79.08 ; 192.12,79.08 190.24,79.08 ; 186.44,77.21 186.44,79.08 188.32,79.08 ; J1901.G4 194,101.03 ; J1901.G4 190.24,101.03 ; J1901.G4 192.12,99.16 ; 193.12,94.98 J1900.G7 ; J1900.G7 194.75,94 ; J1900.G7 194.75,95.96 ; J1900.G7 196.38,94.98 ; J2001.G4 194,57.13 ; J2001.G4 192.12,55.26 ; J2001.G4 190.24,57.13 ; 179.78,73.03 J2001.G6 ; J2001.G6 181.41,74.01 ; J2001.G6 181.41,72.05 ; J2001.G6 183.04,73.03 ; 190.24,70.28 J2001.G3 ; J2001.G3 192.12,72.15 ; J2001.G3 194,70.28 ; 186.44,116.05 J1901.G2 188.32,114.17 ; J1901.G3 194,114.17 ; J1901.G3 190.24,114.17 ; J1901.G3 192.12,116.05 ; J1900.G3 192.12,94.1 ; J1900.G3 194,92.22 ; J1900.G3 190.24,92.22 ; J1900.G5 184.78,76.33 ; J1900.G5 183.15,77.31 ; J1900.G5 181.52,76.33 ; J1900.G5 183.15,75.35 ; 186.44,55.26 J2001.G1 188.32,57.13 ; J1900.G8 196.38,76.33 ; J1900.G8 193.12,76.33 ; J1900.G8 194.75,75.35 ; J1900.G8 194.75,77.31 ; 188.32,70.28 J2001.G2 186.44,72.15 ; 181.41,117.91 J1901.G6 183.04,116.93
  BOTTOM w0.5: 193.12,51.08 J2000.G7 ; J2000.G7 196.38,51.08 ; J2000.G7 194.75,52.06 ; J2000.G7 194.75,50.1 ; J1901.G3 192.12,116.05 ; J1901.G3 190.24,114.17 ; J1901.G3 194,114.17 ; 181.52,98.28 J1901.G5 ; J1901.G5 183.15,99.26 ; J1901.G5 183.15,97.3 ; J1901.G5 184.78,98.28 ; J1900.G3 192.12,94.1 ; J1900.G3 194,92.22 ; J1900.G3 190.24,92.22 ; 188.32,48.33 J2000.G2 186.44,50.2 ; 192.12,77.21 192.12,79.08 ; 192.12,79.08 190.24,79.08 ; 192.12,79.08 194,79.08 ; J2001.G3 194,70.28 ; J2001.G3 190.24,70.28 ; J2001.G3 192.12,72.15 ; J2001.G4 194,57.13 ; J2001.G4 190.24,57.13 ; J2001.G4 192.12,55.26 ; 190.24,48.33 J2000.G3 ; J2000.G3 194,48.33 ; J2000.G3 192.12,50.2 ; 193.12,94.98 J1900.G7 ; J1900.G7 194.75,94 ; J1900.G7 194.75,95.96 ; J1900.G7 196.38,94.98 ; J1900.G5 183.15,77.31 ; J1900.G5 183.15,75.35 ; J1900.G5 181.52,76.33 ; J1900.G5 184.78,76.33 ; 190.24,35.19 J2000.G4 ; J2000.G4 192.12,33.31 ; J2000.G4 194,35.19 ; J1901.G8 196.38,98.28 ; J1901.G8 194.75,99.26 ; J1901.G8 194.75,97.3 ; J1901.G8 193.12,98.28 ; J1901.G7 196.38,116.93 ; J1901.G7 194.75,117.91 ; J1901.G7 194.75,115.95 ; J1901.G7 193.12,116.93 ; J2001.G7 196.38,73.03 ; J2001.G7 193.12,73.03 ; J2001.G7 194.75,72.05 ; J2001.G7 194.75,74.01 ; J2001.G5 184.78,54.38 ; J2001.G5 183.15,55.36 ; J2001.G5 181.52,54.38 ; J2001.G5 183.15,53.4 ; 188.32,70.28 J2001.G2 186.44,72.15 ; J2000.G5 183.15,33.41 ; J2000.G5 184.78,32.43 ; J2000.G5 181.52,32.43 ; J2000.G5 183.15,31.45 ; 179.78,73.03 J2001.G6 ; J2001.G6 181.41,72.05 ; J2001.G6 183.04,73.03 ; J2001.G6 181.41,74.01 ; 193.12,32.43 J2000.G8 ; J2000.G8 196.38,32.43 ; J2000.G8 194.75,33.41 ; J2000.G8 194.75,31.45 ; 181.41,117.91 J1901.G6 183.04,116.93 ; 193.12,76.33 J1900.G8 ; J1900.G8 194.75,77.31 ; J1900.G8 196.38,76.33 ; J1900.G8 194.75,75.35 ; 186.44,99.16 J1901.G1 188.32,101.03 ; 188.32,92.22 J1900.G2 186.44,94.1 ; J2000.G6 181.41,52.06 ; J2000.G6 183.04,51.08 ; J2000.G6 181.41,50.1 ; 186.44,33.31 J2000.G1 ; J2000.G1 188.32,35.19 ; J2000.G1 184.56,35.19 ; 194.75,53.4 J2001.G8 ; J2001.G8 193.12,54.38 ; J2001.G8 194.75,55.36 ; J2001.G8 196.38,54.38 ; 183.04,94.98 J1900.G6 181.41,95.96 ; 186.44,55.26 J2001.G1 188.32,57.13 ; 190.24,101.03 J1901.G4 ; J1901.G4 192.12,99.16 ; J1901.G4 194,101.03 ; 188.32,79.08 186.44,79.08 186.44,77.21 ; 186.44,116.05 J1901.G2 188.32,114.17
  vias: v1(188.95,47.6) v6(172.6,53.07) v6(172.74,32.78) v6(172.76,74.28) v6(172.82,51.31) v6(172.76,30.93) v6(173.05,72.61) v6(173.1,76.03) v6(173.44,119.64) v6(173.46,118.08) v6(174.08,54.74) v6(174.26,30.93) v6(174.95,118.71) v6(175.01,97.44) v6(175.12,99.09) v6(175.13,32.73) v6(175.35,51.26) v6(175.52,72.63) v6(175.66,119.74) v6(175.84,96.16) v6(175.76,30.93) v6(175.97,76.07) v6(176.45,118.71) v6(176.75,54.71) v6(177.16,119.74) v6(177.26,30.93) v6(177.53,32.69) v6(177.6,74.5) v6(177.81,51.26) v6(177.95,118.71) v6(177.9,96.22) v6(177.94,72.63) v6(177.97,99.07) v6(178.6,52.77) v6(178.66,119.74) v6(178.76,30.93) v6(179.33,76.09) v6(179.45,118.71) v6(179.78,33.09) v6(179.88,54.74) v6(179.97,96.11) v6(180.16,119.74) v6(180.24,99.18) v6(180.26,30.93) v6(180.95,118.71) v6(181.19,74.62) v6(181.45,71.66) v6(181.66,119.74) v6(181.76,77.7) v6(181.76,30.93) v6(182.07,52.73) v6(182.11,33.77) v6(182.23,55.89) v6(182.32,99.83) v6(182.45,118.71) v6(182.95,50.1) v6(183.16,119.74) v6(183.26,30.93) v6(183.39,115.91) v6(183.95,118.71) v6(184.33,100.33) v6(184.34,78.22) v6(184.32,71.23) v6(184.27,34.72) v6(184.37,93.4) v6(184.38,56.38) v6(184.53,74.57) v6(184.48,49.14) v6(184.63,117.56) v6(184.59,115.24) v6(184.56,96.34) v6(184.66,119.74) v6(184.76,30.93) v6(185.45,118.71) v6(185.47,116.21) v6(185.8,52.73) v6(185.89,94.62) v6(186.16,119.74) v6(186.26,30.93) v6(186.4,32.19) v6(186.45,98.19) v6(186.95,118.71) v6(187.32,117.58) v6(187.66,119.74) v6(187.67,96.38) v6(187.76,30.93) v6(187.97,74.51) v6(188.15,112.8) v6(188.3,90.88) v6(188.45,118.71) v6(188.45,68.92) v6(188.5,101.75) v6(188.46,46.91) v6(188.55,36.07) v6(188.62,79.78) v6(188.6,57.72) v6(188.85,116.09) v6(189.14,98.14) v6(189.07,94.51) v6(189.23,92.59) v6(189.24,34.4) v6(189.32,101.14) v6(189.29,55.48) v6(189.29,52.75) v6(189.33,32.24) v6(189.26,30.93) v6(189.44,76.75) v6(189.35,71.15) v6(189.41,49.73) v6(189.85,36.12) v6(189.93,118.68) v6(189.96,117.65) v6(190.05,57.72) v6(190.13,101.68) v6(190.05,79.73) v6(190.17,90.97) v6(190.43,112.78) v6(190.41,68.9) v6(190.51,96.29) v6(190.46,46.92) v6(190.66,119.74) v6(190.76,30.93) v6(191.45,118.71) v6(191.38,116.3) v6(191.45,74.47) v6(191.51,98.14) v6(192.15,32.3) v6(192.16,119.74) v6(192.27,94.55) v6(192.26,30.93) v6(192.67,117.65) v6(192.95,118.71) v6(192.91,52.75) v6(193.66,119.74) v6(193.75,112.26) v6(193.76,30.93) v6(193.88,80.68) v6(194.06,90.2) v6(194.15,46.25) v6(194.23,68.08) v6(194.25,37.34) v6(194.45,118.71) v6(194.51,103.22) v6(194.47,64.76) v6(194.51,62.09) v6(194.52,43.32) v6(194.54,40.07) v6(194.6,110.3) v6(194.57,107.85) v6(194.64,105.48) v6(194.62,87.24) v6(194.62,84.78) v6(194.6,82.3) v6(194.63,59.62) v6(194.83,34.11) v6(194.86,74.67) v6(195.03,100.04) v6(195.16,119.74) v6(195.23,92.48) v6(195.21,56.43) v6(195.16,49.18) v6(195.26,30.93) v6(195.74,47.32) v6(195.74,45.02) v6(195.74,42.72) v6(195.74,40.42) v6(195.74,38.12) v6(195.74,35.82) v6(195.84,114.04) v6(195.84,111.74) v6(195.84,109.44) v6(195.84,107.14) v6(195.84,104.84) v6(195.84,102.54) v6(195.84,70.53) v6(195.84,68.23) v6(195.84,65.93) v6(195.84,63.63) v6(195.84,61.33) v6(195.84,59.03) v6(195.95,118.71) v6(195.89,90.86) v6(195.89,88.56) v6(195.89,86.26) v6(195.89,83.96) v6(195.89,81.66) v6(195.89,79.36) v6(196.76,30.93) v6(197.62,112.93) v6(197.62,110.63) v6(197.62,108.33) v6(197.62,106.03) v6(197.62,103.73) v6(197.62,101.43) v6(197.62,99.13) v6(197.62,96.83) v6(197.62,94.53) v6(197.62,92.23) v6(197.62,89.93) v6(197.62,87.63) v6(197.62,85.33) v6(197.62,83.03) v6(197.62,80.73) v6(197.62,78.43) v6(197.62,76.13) v6(197.62,73.83) v6(197.62,71.53) v6(197.62,69.23) v6(197.62,66.93) v6(197.62,64.63) v6(197.62,62.33) v6(197.62,60.03) v6(197.62,57.73) v6(197.62,55.43) v6(197.62,53.13) v6(197.62,50.83) v6(197.62,48.53) v6(197.62,46.23) v6(197.72,43.65) v6(197.72,41.35) v6(197.72,39.05) v6(197.72,36.75) v6(197.72,34.45) v6(197.72,32.15) v6(197.77,118.71) v6(197.87,115.54) v6(198.26,30.93) v6(199.43,119.49) v6(199.47,117.99) v6(199.47,116.49) v6(199.47,114.99) v6(199.47,113.49) v6(199.47,111.99) v6(199.47,110.49) v6(199.47,108.99) v6(199.47,107.49) v6(199.47,105.99) v6(199.47,104.49) v6(199.47,102.99) v6(199.47,101.49) v6(199.47,99.99) v6(199.47,98.49) v6(199.47,96.99) v6(199.47,95.49) v6(199.47,93.99) v6(199.47,92.49) v6(199.47,90.99) v6(199.47,89.49) v6(199.47,87.99) v6(199.47,86.49) v6(199.47,84.99) v6(199.47,83.49) v6(199.47,81.99) v6(199.47,80.49) v6(199.47,78.99) v6(199.47,77.49) v6(199.47,75.99) v6(199.47,74.49) v6(199.47,72.99) v6(199.47,71.49) v6(199.47,69.99) v6(199.47,68.49) v6(199.47,66.99) v6(199.47,65.49) v6(199.47,63.99) v6(199.47,62.49) v6(199.47,60.99) v6(199.47,59.49) v6(199.47,57.99) v6(199.47,56.49) v6(199.47,54.99) v6(199.47,53.49) v6(199.47,51.99) v6(199.47,50.49) v6(199.47,48.99) v6(199.47,47.49) v6(199.47,45.99) v6(199.47,44.49) v6(199.47,42.99) v6(199.47,41.49) v6(199.47,39.99) v6(199.47,38.49) v6(199.47,36.99) v6(199.47,35.49) v6(199.47,33.99) v6(199.47,32.49) v6(199.47,30.99)
GND_EARTH1:
  vias: v3(106.34,122.08) v3(106.49,121.33) v3(106.48,121.01) v3(106.48,120.67) v3(106.84,121.33) v3(106.83,121.01) v3(106.83,120.67) v3(107.19,121.33) v3(107.18,121.01) v3(107.18,120.68) v3(110.18,122.67) v3(111.38,120.77) v3(113.85,120.71) v3(113.86,121.37) v3(113.85,121.05) v3(114.21,121.37) v3(114.2,121.05) v3(114.2,120.71) v3(114.56,121.37) v3(114.55,121.05) v3(114.55,120.71) v3(121.34,121.1) v3(121.34,120.77) v3(121.35,121.43) v3(121.71,121.43) v3(121.7,121.1) v3(121.7,120.77) v3(122.05,121.11) v3(122.05,120.77) v3(122.06,121.43) v3(129.64,121.35) v3(129.63,121.03) v3(129.63,120.7) v3(129.99,121.35) v3(129.98,121.03) v3(129.98,120.7) v3(130.34,121.36) v3(130.33,121.03) v3(130.33,120.7) v7(117.34,122.66) v7(124.92,122.66) v7(133.12,122.65) v7(134.39,120.78)
GND_EARTH2: length 51
  TOP w0.5: J1500.G1 11.75,118.07 ; J1500.G1 13.03,116.8 ; J1500.G1 11.75,115.52 ; 13.03,101.14 J1500.G2 11.75,102.42
  L2 w0.5: 11.75,115.52 J1500.G1 ; J1500.G1 13.03,116.8 ; J1500.G1 11.75,118.07 ; 11.75,102.42 J1500.G2 13.03,101.14
  L3 w0.5: J1500.G1 11.75,118.07 ; J1500.G1 13.03,116.8 ; J1500.G1 11.75,115.52 ; 13.03,101.14 J1500.G2 11.75,102.42
  L4 w0.5: 13.03,101.14 J1500.G2 11.75,102.42 ; 11.75,115.52 J1500.G1 ; J1500.G1 13.03,116.8 ; J1500.G1 11.75,118.07
  L5 w0.5: J1500.G1 11.75,118.07 ; J1500.G1 13.03,116.8 ; J1500.G1 11.75,115.52 ; 13.03,101.14 J1500.G2 11.75,102.42
  L6 w0.5: 13.03,101.14 J1500.G2 11.75,102.42 ; J1500.G1 13.03,116.8 ; J1500.G1 11.75,115.52 ; J1500.G1 11.75,118.07
  L7 w0.5: 11.75,102.42 J1500.G2 13.03,101.14 ; J1500.G1 13.03,116.8 ; J1500.G1 11.75,118.07 ; J1500.G1 11.75,115.52
  BOTTOM w0.5: J1500.G1 11.75,118.07 ; J1500.G1 13.03,116.8 ; J1500.G1 11.75,115.52 ; 13.03,101.14 J1500.G2 11.75,102.42
  vias: v6(10.98,110.99) v6(10.98,109.49) v6(10.98,107.99) v6(10.98,106.49) v6(10.98,104.99) v6(10.98,103.49) v6(11.1,113.96) v6(11.16,115.08) v6(11.88,118.73) v6(12.02,111.75) v6(12.02,110.25) v6(12.02,108.75) v6(12.02,107.25) v6(12.02,105.75) v6(12.02,104.25) v6(12.04,102.88) v6(12.36,115.18) v6(12.9,103.45) v6(12.95,112.82) v6(12.95,111.32) v6(12.95,109.82) v6(12.95,108.32) v6(12.95,106.82) v6(12.95,105.32) v6(13.33,102.05) v6(13.38,118.73) v6(13.78,116.55) v6(13.93,101.2) v6(13.95,117.62) v6(13.98,100.18) v6(14.88,118.73) v6(15.51,117.62) v6(16.38,118.73) v6(17.01,117.62) v6(17.88,118.73) v6(18.67,117.57) v6(19.38,118.73) v6(20.17,117.57) v6(20.88,118.73) v6(21.72,117.53)
GND_TOP:
  vias: v1(109.78,29.2) v1(110.22,28.85) v1(110.55,28.85) v1(111.05,29.21) v1(111.49,28.86) v1(111.81,28.86) v1(112.32,29.2) v1(112.81,28.85) v1(113.13,28.85) v1(113.59,29.22) v1(114.08,28.87) v1(114.41,28.87) v1(114.85,29.21) v1(115.33,28.86) v1(115.66,28.86) v1(116.12,29.2) v1(116.61,28.85) v1(116.94,28.85) v1(117.39,29.21) v1(117.88,28.86) v1(118.2,28.86) v1(118.66,29.2) v1(119.15,28.85) v1(119.48,28.85) v1(119.93,29.21) v1(120.42,28.86) v1(120.74,28.86) v1(129.3,28.94) v1(129.31,28.61) v1(129.32,28.25) v1(129.33,27.92) v1(129.34,27.55) v1(129.34,27.23) v1(129.62,28.94) v1(129.63,28.61) v1(129.64,28.25) v1(129.65,27.92) v1(129.66,27.55) v1(129.66,27.23) v1(129.92,28.95) v1(129.93,28.62) v1(129.94,28.26) v1(129.95,27.93) v1(129.96,27.56) v1(129.96,27.24) v1(130.25,28.95) v1(130.25,28.62) v1(130.27,28.26) v1(130.27,27.93) v1(130.28,27.56) v1(130.29,27.24) v1(130.55,28.96) v1(130.56,28.63) v1(130.57,28.27) v1(130.58,27.94) v1(130.59,27.57) v1(130.59,27.25) v1(130.88,28.96) v1(130.88,28.63) v1(130.9,28.27) v1(130.9,27.94) v1(130.91,27.57) v1(130.92,27.25)
VBUSDET: length 3.2
  TOP w0.1: U2400.43 150.24,91.68 R2411.1 148.97,93.76 R2410.2
VCC_+6V7_GMSL_1:
  vias: v1(26.83,100.84) v1(26.83,100.57) v1(27.09,100.84) v1(27.09,100.57) v2(25.84,100.89) v2(25.83,100.42) v2(26.28,100.88) v2(26.26,100.41) v3(25.2,100.93) v3(25.2,100.66) v3(25.47,100.92) v3(25.47,100.66)
VCC_+6V7_GMSL_2:
  vias: v1(23.82,91.8) v1(23.82,91.53) v1(24.08,91.8) v1(24.08,91.53) v2(23.83,90.97) v2(23.83,90.53) v2(24.3,90.95) v2(24.3,90.52) v3(27.13,90.57) v3(27.13,90.31) v3(27.39,90.57) v3(27.39,90.31)
VCC_+6V7_GMSL_3: length 0
  TOP w0.1: 23.92,86.08 23.92,86.09 C3107.1
  vias: v1(23.79,86.33) v1(23.79,86.08) v1(24.09,86.34) v1(24.1,86.09) v2(25,86.94) v2(24.99,86.48) v2(25.44,86.94) v2(25.42,86.47) v3(25.88,86.92) v3(25.88,86.65) v3(26.14,86.92) v3(26.14,86.65)
VCC_+6V7_GMSL_4:
  vias: v1(23.83,80.48) v1(23.83,80.22) v1(24.11,80.47) v1(24.12,80.22) v2(24.49,79.95) v2(24.5,79.47) v2(25.02,79.94) v2(25.01,79.45) v3(26.72,79.35) v3(26.72,79.08) v3(26.99,79.35) v3(26.99,79.08)
VCC_+6V7_GMSL_5:
  vias: v1(23.8,74.84) v1(23.79,74.57) v1(24.09,74.85) v1(24.08,74.57) v2(24.46,74.71) v2(24.48,74.23) v2(24.99,74.7) v2(24.98,74.22) v3(23.43,75.23) v3(23.43,74.96) v3(23.69,75.23) v3(23.69,74.96)
VCC_+6V7_GMSL_6:
  vias: v1(23.78,68.81) v1(23.79,68.54) v1(24.06,68.8) v1(24.07,68.54) v2(24.45,68.26) v2(24.46,67.78) v2(24.98,68.25) v2(24.96,67.77) v3(27.57,68.41) v3(27.57,68.14) v3(27.83,68.41) v3(27.83,68.14)
VCC_+6V7_GMSL_7:
  vias: v1(23.82,62.9) v1(23.82,62.64) v1(24.1,62.89) v1(24.11,62.64) v2(24.69,62.51) v2(24.7,62.03) v2(25.22,62.5) v2(25.2,62.02) v3(26.15,63.14) v3(26.15,62.88) v3(26.41,63.14) v3(26.41,62.88)
VCC_+6V7_GMSL_8: length 0
  BOTTOM w0.1: 27.12,53.67 27.12,53.67 C3034.1
  vias: v1(23.82,56.18) v1(23.83,55.91) v1(24.1,56.16) v1(24.11,55.91) v2(24.49,55.65) v2(24.5,55.17) v2(25.01,55.64) v2(25,55.16) v3(26.6,54.89) v3(26.6,54.62) v3(26.86,54.89) v3(26.86,54.62)
VCC_CAM_GMSL1_EN: length 52.4
  TOP w0.1: v1(29.32,96.5) 28.95,96.88 U3100.2
  L3 w0.1: v1(29.32,96.5) 31.08,96.5 31.59,97.01 v2(31.74,97.01)
  L5 w0.1: v2(31.74,97.01) 31.96,96.79 31.96,96.51 33.11,95.36 33.11,92.11 32.28,91.28 32.28,77.8 33.1,76.99 33.1,70.06 33.36,69.8 33.36,59.3 34.41,58.25 34.41,56.75 34.25,56.59 34.25,53.35 35.05,52.55 v2(35.05,51.47)
  L6 w0.1: v2(35.05,51.47) v3(35.05,51.95)
VCC_CAM_GMSL1_FLAG: length 52.5
  TOP w0.1: U3100.1 28.5,96.53 v1(28.47,96.5)
  L3 w0.1: v1(28.47,96.5) 28.76,96.22 31.42,96.22 v2(31.61,96.41)
  L5 w0.1: v2(31.38,52.64) 31.38,52.63 31.8,52.63 32.85,53.68 32.85,56.73 31.87,57.72 31.87,63.78 31.66,64 31.66,66.4 32.16,66.9 32.16,67.68 31.86,67.98 31.86,69.07 32.05,69.26 32.05,75.97 31.23,76.79 31.23,82.04 31.18,82.09 31.18,82.38 31.23,82.43 31.23,90.63 32.91,92.3 32.91,95.28 31.78,96.41 v2(31.61,96.41)
  L6 w0.1: v3(30.92,52.62) 31.36,52.62 v2(31.38,52.64)
  BOTTOM w0.1: U3104.9 30.91,52.63 v3(30.92,52.62)
VCC_CAM_GMSL2_EN: length 45.7
  TOP w0.1: R3104.2 28.14,92.9 U3101.2
  L3 w0.1: v2(31.63,90.53) 31.21,90.95 30.84,90.95 v1(28.51,93.28)
  L5 w0.1: v2(34.57,52.49) 34.05,53 34.05,56.67 34.21,56.83 34.21,58.17 33.16,59.22 33.16,69.72 32.9,69.98 32.9,76.9 32.08,77.72 32.08,90.08 v2(31.63,90.53)
  L6 w0.1: v3(34.57,51.97) v2(34.57,52.49)
VCC_CAM_GMSL2_FLAG: length 44.6
  TOP w0.1: R3103.1 28.49,92.45 U3101.1
  L3 w0.1: v2(30.88,90.53) 30.88,90.53 28.99,92.43 v1(28.53,92.43)
  L5 w0.1: v2(30.88,90.53) 31.03,90.38 31.03,82.51 30.98,82.46 30.98,82.01 31.03,81.96 31.03,79.87 30.98,79.83 30.98,76.76 31.85,75.88 31.85,69.35 31.66,69.15 31.66,67.9 31.96,67.6 31.96,66.98 31.46,66.48 31.46,63.91 31.67,63.7 31.67,57.63 32.65,56.65 32.65,54.07 31.74,53.15 v2(31.74,53.12)
  L6 w0.1: v3(30.89,53.12) v2(31.74,53.12)
  BOTTOM w0.1: U3104.10 30.9,53.13 v3(30.89,53.12)
VCC_CAM_GMSL3_EN: length 42.3
  TOP w0.1: v1(28.55,87.55) 28.53,87.57 R3107.2 28.16,87.21 U3102.2
  L3 w0.1: v1(28.55,87.55) v2(31.66,87.55)
  L5 w0.1: v2(31.66,87.55) 31.88,87.33 31.88,77.64 32.68,76.84 32.68,69.87 32.96,69.59 32.96,59.14 34.01,58.08 34.01,56.91 33.85,56.76 33.85,52.87 34.09,52.63 v2(34.09,51.53)
  L6 w0.1: v2(34.09,51.53) v3(34.09,51.97)
VCC_CAM_GMSL3_FLAG: length 39
  TOP w0.1: R3106.1 28.51,86.76 U3102.1
  L3 w0.1: v1(28.53,86.76) 28.6,86.68 v2(30.68,86.68)
  L5 w0.1: v2(31.36,53.63) 31.85,53.63 32.45,54.23 32.45,56.57 31.47,57.55 31.47,63.62 31.26,63.83 31.26,67.47 31.46,67.67 31.46,69.23 31.65,69.43 31.65,75.8 30.72,76.74 30.72,79.84 30.81,79.93 30.81,81.9 30.78,81.93 30.78,82.55 30.81,82.57 30.81,86.56 30.69,86.68 v2(30.68,86.68)
  L6 w0.1: v3(30.91,53.63) v2(31.36,53.63)
  BOTTOM w0.1: U3104.11 v3(30.91,53.63)
VCC_CAM_GMSL4_EN: length 35.9
  TOP w0.1: R3110.2 28.18,81.61 U3103.2
  L3 w0.1: v2(31.53,82.24) 28.67,82.24 v1(28.57,82.13)
  L5 w0.1: v2(33.57,52.49) 33.57,53.02 33.65,53.1 33.65,56.84 33.81,57 33.81,58 32.76,59.06 32.76,69.51 32.48,69.78 32.48,76.6 31.53,77.55 v2(31.53,82.24)
  L6 w0.1: v3(33.57,51.98) v2(33.57,52.49)
  BOTTOM w0.1: U3104.4 v3(33.57,51.98)
VCC_CAM_GMSL4_FLAG: length 31.8
  TOP w0.1: R3109.1 28.53,81.16 U3103.1
  L3 w0.1: v2(30.46,80.08) 29.54,81 v1(28.56,81)
  L5 w0.1: v2(30.46,80.08) 30.46,76.72 31.45,75.72 31.45,69.51 31.26,69.31 31.26,67.76 31.06,67.56 31.06,63.75 31.25,63.55 31.25,57.49 32.25,56.48 32.25,54.79 31.74,54.27 v2(31.74,54.13)
  L6 w0.1: v3(30.91,54.13) v2(31.74,54.13)
  BOTTOM w0.1: v3(30.91,54.13) U3104.12
VCC_CAM_GMSL5_EN: length 31.7
  TOP w0.1: U3002.2 28.17,76.02 R3030.2
  L3 w0.1: v2(31.63,76.91) 31.16,76.44 28.6,76.44 v1(28.55,76.39)
  L5 w0.1: v2(31.63,76.91) 32.27,76.27 32.27,69.66 32.56,69.37 32.56,58.97 33.61,57.92 33.61,57.08 33.45,56.92 33.45,53.18 33.1,52.83 33.1,51.6 v2(33.06,51.55)
  L6 w0.1: v3(33.06,51.97) v2(33.06,51.55)
  BOTTOM w0.1: U3104.5 v3(33.06,51.97)
VCC_CAM_GMSL5_FLAG: length 27.1
  TOP w0.1: U3002.1 28.52,75.57 R3029.1
  L3 w0.1: v1(28.55,75.56) 28.55,75.56 29.06,76.06 v2(30.61,76.06)
  L5 w0.1: v2(31.37,54.63) 31.8,54.63 32.05,54.88 32.05,56.4 31.04,57.41 31.04,63.48 30.86,63.67 30.86,67.64 31.06,67.84 31.06,69.4 31.25,69.6 31.25,75.42 v2(30.61,76.06)
  L6 w0.1: v3(30.91,54.63) v2(31.37,54.63)
  BOTTOM w0.1: 30.91,54.62 v3(30.91,54.63) 30.91,54.62 30.91,54.62
VCC_CAM_GMSL6_EN: length 23.7
  TOP w0.1: R3222.2 28.14,69.78 U3203.2
  L3 w0.1: v2(32.21,68.92) 31.87,69.25 29.42,69.25 v1(28.51,70.16)
  L5 w0.1: v2(32.21,68.92) 32.36,68.92 32.36,58.89 33.41,57.83 33.41,57.16 33.25,57 33.25,53.27 32.73,52.74 v2(32.73,52.51)
  L6 w0.1: v2(32.73,52.51) 32.56,52.34 v3(32.56,51.98)
  BOTTOM w0.1: U3104.6 v3(32.56,51.98)
VCC_CAM_GMSL6_FLAG: length 18.7
  TOP w0.1: U3203.1 28.49,69.33 R3221.1
  L3 w0.1: v2(30.57,68.9) 28.92,68.9 28.51,69.31 v1(28.51,69.32)
  L5 w0.1: v2(31.7,55.13) 31.71,55.13 31.71,56.47 30.83,57.34 30.83,63.41 30.66,63.58 30.66,68.82 v2(30.57,68.9)
  L6 w0.1: v3(30.91,55.13) v2(31.7,55.13)
VCC_CAM_GMSL7_EN: length 19.3
  TOP w0.1: U3204.2 28.17,63.91 R3225.2
  L3 w0.1: v2(32.01,64.14) 28.68,64.14 28.54,64.28 v1(28.54,64.29)
  L5 w0.1: v2(32.01,64.14) 32.08,64.07 32.08,57.79 33.05,56.82 33.05,53.43 32.07,52.45 v2(32.07,51.41)
  L6 w0.1: v3(32.07,51.96) v2(32.07,51.41)
  BOTTOM w0.1: U3104.7 v3(32.07,51.96)
VCC_CAM_GMSL7_FLAG: length 11.5
  TOP w0.1: R3224.1 28.52,63.46 U3204.1
  L3 w0.1: v1(28.53,63.45) 29.32,62.66 v2(30.48,62.66)
  L5 w0.1: v2(31.33,55.63) 31.37,55.67 31.37,56.52 30.48,57.41 v2(30.48,62.66)
  L6 w0.1: v3(30.91,55.63) v2(31.33,55.63)
VCC_CAM_GMSL8_EN: length 9.8
  TOP w0.1: U3205.2 28.17,57.19 R3228.2
  L3 w0.1: v2(30.43,56.84) 30.3,56.97 29.14,56.97 v1(28.54,57.56)
  L6 w0.1: v3(31.56,51.98) 30.78,51.98 30.15,52.61 30.15,56.56 v2(30.43,56.84)
  BOTTOM w0.1: U3104.8 31.57,51.97 v3(31.56,51.98)
VCC_CAM_GMSL8_FLAG: length 4
  TOP w0.1: v1(28.55,56.72) 28.52,56.74 U3205.1
  L3 w0.1: v1(28.55,56.72) 29.67,56.72 30.25,56.14 v2(30.5,56.14)
  L6 w0.1: v2(30.5,56.14) v3(30.91,56.14)
VDD10: length 23.4
  TOP w0.2: U1500.3 29.52,110.32 v1(29.43,110.4) ; U1500.30 32.4,112.72 C1511.1 ; U1500.8 v1(29.5,108.32) ; C1510.1 36.6,112.27 36.15,112.27 35.78,111.9 35.78,110.63 35.47,110.32 U1500.22
  TOP w0.3: C1511.1 31.85,113.27 v1(31.86,113.25) ; C1510.1 36.65,113.19 v1(36.56,113.27)
  L3 w0.3: 30.02,113.25 v1(31.86,113.25) 36.55,113.25 v1(36.56,113.27) ; 30.02,113.25 v2(30.02,113.25) ; 30.02,113.25 28.84,113.25 v1(28.79,113.31) ; v1(29.43,110.4) 29.51,110.32 v2(30.02,110.32) ; v1(29.5,108.32) v2(30.03,108.32)
  L6 w0.3: v2(30.02,113.25) v2(30.02,110.32) 30.03,110.32 v2(30.03,108.32)
VDD33: length 16.8
  TOP w0.1: v1(38.9,108.35) 38.96,108.41 R1520.2 ; v1(32.4,108.03) U1500.11
  TOP w0.2: U1500.11 32.4,106.65 32,106.25 R1509.1
  L3 w0.2: v1(31.6,111.62) 32.07,111.62 32.07,111.62 32.22,111.62 32.25,111.65 v2(32.4,111.65) ; v1(32.4,108.03) 32.4,108.42 v2(32.41,108.43)
  L3 w0.3: v1(38.9,108.35) 38.9,109.17 38.61,109.46 33.44,109.46 v2(32.41,108.43)
  L6 w0.2: v2(32.4,111.65) 32.38,111.63 32.38,111.5 32.4,111.49 32.4,108.75 32.41,108.74 v2(32.41,108.43)
VDD33_USB: length 15.8
  L3 w0.3: v2(132.25,56.67) 129.68,56.67 129.5,56.49 v2(129.42,56.49)
  L6 w0.3: v3(132.52,57.67) 132.52,56.94 v2(132.25,56.67) ; v3(129.39,54.94) 129.42,54.97 v2(129.42,56.49)
  L7 w0.3: v3(132.52,57.67) 132.54,57.69 v7(133.4,57.69) ; v7(132.55,53.91) 130.87,53.91 v7(130.51,54.27)
  BOTTOM w0.2: U2503.28 136.45,57.61 135.98,58.07 134.68,58.07 R2515.1
  BOTTOM w0.3: R2517.1 v3(132.52,57.67)
  BOTTOM w0.4: R2516.1 R2517.1 ; v7(133.4,57.69) R2515.1
VDDREG_VDD33: length 35.9
  L3 w0.3: v1(40.31,111.03) 36.88,111.03 36.56,110.71 v1(34.9,110.71) 34.86,110.75 31.66,110.75 30.78,109.87 21.29,109.87 v2(21.18,109.75) ; v2(20.75,97.64) 17.35,97.64 v1(17,97.3)
  L6 w0.3: v2(20.75,97.64) 21.06,97.95 21.06,109.64 v2(21.18,109.75)
VIN+: length 1.6
  BOTTOM w0.1: L500.1 155.02,7.08
  vias: v6(153,6.1) v6(153,5.6) v6(153,5.1) v6(153.5,6.1) v6(153.5,5.6) v6(153.5,5.1) v6(154,6.1) v6(154,5.6) v6(154,5.1) v6(154.5,6.1) v6(154.5,5.6) v6(154.5,5.1) v6(155,6.1) v6(155,5.6) v6(155,5.1) v6(155.5,6.1) v6(155.5,5.6) v6(155.5,5.1) v6(156,6.1) v6(156,5.6) v6(156,5.1) v6(156.5,6.1) v6(156.5,5.6) v6(156.5,5.1) v6(157,6.1) v6(157,5.6) v6(157,5.1) v6(157.5,6.1) v6(157.5,5.6) v6(157.5,5.1) v6(158,6.1) v6(158,5.6) v6(158,5.1) v6(158.5,6.1) v6(158.5,5.6) v6(158.5,5.1) v6(179.5,14.95) v6(179.5,14.45) v6(179.5,13.95) v6(179.5,13.45) v6(179.5,12.95) v6(179.5,12.45) v6(179.5,11.95) v6(179.5,11.45) v6(179.5,10.95) v6(180,14.95) v6(180,14.45) v6(180,13.95) v6(180,13.45) v6(180,12.95) v6(180,12.45) v6(180,11.95) v6(180,11.45) v6(180,10.95) v6(180.5,14.95) v6(180.5,14.45) v6(180.5,13.95) v6(180.5,13.45) v6(180.5,12.95) v6(180.5,12.45) v6(180.5,11.95) v6(180.5,11.45) v6(180.5,10.95) v6(181,14.95) v6(181,14.45) v6(181,13.95) v6(181,13.45) v6(181,12.95) v6(181,12.45) v6(181,11.95) v6(181,11.45) v6(181,10.95)
VIN-:
  vias: v1(154.19,28.61) v1(154.19,28.32) v1(154.19,28.01) v1(154.19,27.7) v1(154.18,27.4) v1(154.18,27.12) v1(154.17,26.8) v1(154.18,26.5) v1(154.5,28.61) v1(154.5,28.32) v1(154.49,28.01) v1(154.5,27.7) v1(154.48,27.4) v1(154.48,27.12) v1(154.48,26.8) v1(154.48,26.5) v1(154.8,28.61) v1(154.8,28.32) v1(154.79,28.01) v1(154.8,27.7) v1(154.79,27.4) v1(154.79,27.12) v1(154.78,26.8) v1(154.79,26.5) v1(155.03,29.97) v1(155.03,29.69) v1(155.04,29.44) v1(155.05,29.13) v1(155.1,28.61) v1(155.1,28.32) v1(155.1,28.01) v1(155.1,27.7) v1(155.09,27.4) v1(155.09,27.12) v1(155.09,26.8) v1(155.09,26.5) v1(155.33,29.97) v1(155.33,29.69) v1(155.35,29.44) v1(155.35,29.13) v1(155.4,28.61) v1(155.4,28.32) v1(155.4,28.01) v1(155.4,27.7) v1(155.39,27.4) v1(155.39,27.12) v1(155.39,26.8) v1(155.39,26.5) v1(155.64,29.97) v1(155.64,29.69) v1(155.65,29.44) v1(155.66,29.13) v1(155.72,28.61) v1(155.72,28.32) v1(155.71,28.01) v1(155.72,27.7) v1(155.71,27.4) v1(155.71,27.12) v1(155.7,26.8) v1(155.71,26.5) v1(155.94,29.97) v1(155.94,29.69) v1(155.96,29.44) v1(155.96,29.13) v1(156.02,28.61) v1(156.02,28.32) v1(156.02,28.01) v1(156.02,27.7) v1(156.01,27.4) v1(156.01,27.12) v1(156.01,26.8) v1(156.01,26.5) v1(156.24,29.97) v1(156.24,29.69) v1(156.26,29.44) v1(156.26,29.13) v1(156.33,28.61) v1(156.33,28.32) v1(156.32,28.01) v1(156.33,27.7) v1(156.31,27.4) v1(156.31,27.12) v1(156.31,26.8) v1(156.31,26.5) v1(156.56,29.97) v1(156.56,29.69) v1(156.57,29.44) v1(156.58,29.13) v1(156.63,28.61) v1(156.63,28.32) v1(156.62,28.01) v1(156.63,27.7) v1(156.62,27.4) v1(156.62,27.12) v1(156.61,26.8) v1(156.62,26.5) v1(156.86,29.97) v1(156.86,29.69) v1(156.88,29.44) v1(156.88,29.13) v1(156.93,28.61) v1(156.93,28.32) v1(156.93,28.01) v1(156.93,27.7) v1(156.92,27.4) v1(156.92,27.12) v1(156.91,26.8) v1(156.92,26.5) v1(157.16,29.97) v1(157.16,29.69) v1(157.18,29.44) v1(157.18,29.13) v1(157.22,28.61) v1(157.22,28.32) v1(157.22,28.01) v1(157.22,27.7) v1(157.21,27.4) v1(157.21,27.12) v1(157.21,26.8) v1(157.21,26.5) v1(157.47,29.97) v1(157.47,29.69) v1(157.48,29.44) v1(157.49,29.13) v1(157.53,28.61) v1(157.53,28.32) v1(157.52,28.01) v1(157.53,27.7) v1(157.52,27.4) v1(157.52,27.12) v1(157.51,26.8) v1(157.52,26.5) v1(157.77,29.97) v1(157.77,29.69) v1(157.78,29.44) v1(157.79,29.13) v1(157.85,28.01) v1(157.84,27.4) v1(157.84,27.12) v1(157.84,26.8) v1(157.84,26.5) v1(157.85,28.61) v1(157.85,28.32) v1(157.85,27.7) v1(158.06,29.97) v1(158.06,29.69) v1(158.08,29.44) v1(158.08,29.13) v1(158.15,27.4) v1(158.15,27.12) v1(158.14,26.8) v1(158.15,26.5) v1(158.16,28.61) v1(158.16,28.32) v1(158.15,28.01) v1(158.16,27.7) v1(158.37,29.97) v1(158.37,29.69) v1(158.38,29.44) v1(158.39,29.13) v1(158.45,26.8) v1(158.46,28.61) v1(158.46,28.32) v1(158.46,28.01) v1(158.46,27.7) v1(158.45,27.4) v1(158.45,27.12) v1(158.45,26.5) v1(158.69,29.97) v1(158.69,29.69) v1(158.71,29.44) v1(158.71,29.13) v1(158.75,26.8) v1(158.76,28.61) v1(158.76,28.32) v1(158.76,28.01) v1(158.76,27.7) v1(158.75,27.4) v1(158.75,27.12) v1(158.75,26.5) v1(159,29.97) v1(159,29.69) v1(159.01,29.44) v1(159.02,29.13) v1(159.05,26.8) v1(159.07,28.61) v1(159.07,28.32) v1(159.06,28.01) v1(159.07,27.7) v1(159.05,27.4) v1(159.05,27.12) v1(159.05,26.5) v1(159.3,29.97) v1(159.3,29.69) v1(159.31,29.44) v1(159.32,29.13) v1(159.38,28.61) v1(159.38,28.32) v1(159.38,28.01) v1(159.38,27.7) v1(159.37,27.4) v1(159.37,27.12) v1(159.36,26.8) v1(159.37,26.5) v1(159.6,29.97) v1(159.6,29.69) v1(159.62,29.44) v1(159.62,29.13) v1(159.69,28.61) v1(159.69,28.32) v1(159.68,28.01) v1(159.69,27.7) v1(159.67,27.4) v1(159.67,27.12) v1(159.67,26.8) v1(159.67,26.5) v1(159.9,29.97) v1(159.9,29.69) v1(159.92,29.44) v1(159.92,29.13) v1(159.99,28.61) v1(159.99,28.32) v1(159.98,28.01) v1(159.99,27.7) v1(159.98,27.4) v1(159.98,27.12) v1(159.97,26.8) v1(159.98,26.5) v1(160.22,29.97) v1(160.22,29.69) v1(160.23,29.44) v1(160.24,29.13) v1(160.29,28.61) v1(160.29,28.32) v1(160.29,28.01) v1(160.29,27.7) v1(160.28,27.4) v1(160.28,27.12) v1(160.28,26.8) v1(160.28,26.5) v1(160.52,29.97) v1(160.52,29.69) v1(160.54,29.44) v1(160.54,29.13) v1(160.59,28.61) v1(160.59,28.32) v1(160.59,28.01) v1(160.59,27.7) v1(160.58,27.4) v1(160.58,27.12) v1(160.58,26.8) v1(160.58,26.5) v1(160.83,29.97) v1(160.83,29.69) v1(160.84,29.44) v1(160.85,29.13) v1(160.88,28.61) v1(160.88,28.32) v1(160.88,28.01) v1(160.88,27.7) v1(160.87,27.4) v1(160.87,27.12) v1(160.87,26.8) v1(160.87,26.5) v1(161.13,29.97) v1(161.13,29.69) v1(161.15,29.44) v1(161.15,29.13) v1(161.19,28.61) v1(161.19,28.32) v1(161.19,28.01) v1(161.19,27.7) v1(161.18,27.4) v1(161.18,27.12) v1(161.17,26.8) v1(161.18,26.5) v1(161.43,29.97) v1(161.43,29.69) v1(161.45,29.44) v1(161.45,29.13) v1(161.49,28.61) v1(161.49,28.32) v1(161.49,28.01) v1(161.49,27.7) v1(161.48,27.4) v1(161.48,27.12) v1(161.48,26.8) v1(161.48,26.5) v1(161.72,29.97) v1(161.72,29.69) v1(161.74,29.44) v1(161.74,29.13) v1(161.8,28.61) v1(161.8,28.32) v1(161.79,28.01) v1(161.8,27.7) v1(161.78,27.4) v1(161.78,27.12) v1(161.78,26.8) v1(161.78,26.5) v1(162.03,29.97) v1(162.03,29.69) v1(162.04,29.44) v1(162.05,29.13) v1(162.1,28.61) v1(162.1,28.32) v1(162.09,28.01) v1(162.1,27.7) v1(162.09,27.4) v1(162.09,27.12) v1(162.08,26.8) v1(162.09,26.5) v1(162.33,29.97) v1(162.33,29.69) v1(162.35,29.44) v1(162.35,29.13) v1(162.41,28.61) v1(162.41,28.32) v1(162.41,28.01) v1(162.41,27.7) v1(162.4,27.4) v1(162.4,27.12) v1(162.4,26.8) v1(162.4,26.5) v1(162.63,29.97) v1(162.63,29.69) v1(162.65,29.44) v1(162.65,29.13) v1(162.72,28.61) v1(162.72,28.32) v1(162.71,28.01) v1(162.72,27.7) v1(162.71,27.4) v1(162.71,27.12) v1(162.7,26.8) v1(162.71,26.5) v1(162.94,29.97) v1(162.94,29.69) v1(162.95,29.44) v1(162.96,29.13) v1(163.02,28.61) v1(163.02,28.32) v1(163.02,28.01) v1(163.02,27.7) v1(163.01,27.4) v1(163.01,27.12) v1(163,26.8) v1(163.01,26.5) v1(163.25,29.97) v1(163.25,29.69) v1(163.27,29.44) v1(163.27,29.13) v1(163.32,28.61) v1(163.32,28.32) v1(163.32,28.01) v1(163.32,27.7) v1(163.31,27.4) v1(163.31,27.12) v1(163.31,26.8) v1(163.31,26.5) v1(163.56,29.97) v1(163.56,29.69) v1(163.57,29.44) v1(163.58,29.13) v1(163.62,28.61) v1(163.62,28.32) v1(163.62,28.01) v1(163.62,27.7) v1(163.61,27.4) v1(163.61,27.12) v1(163.61,26.8) v1(163.61,26.5) v1(163.86,29.97) v1(163.86,29.69) v1(163.87,29.44) v1(163.88,29.13) v1(163.9,28.61) v1(163.9,28.32) v1(163.9,28.01) v1(163.9,27.7) v1(163.89,27.4) v1(163.89,27.12) v1(163.89,26.8) v1(163.89,26.5) v1(164.16,29.97) v1(164.16,29.69) v1(164.18,29.44) v1(164.18,29.13) v1(164.21,28.61) v1(164.21,28.32) v1(164.2,28.01) v1(164.21,27.7) v1(164.2,27.4) v1(164.2,27.12) v1(164.19,26.8) v1(164.2,26.5) v1(164.46,29.97) v1(164.46,29.69) v1(164.48,29.44) v1(164.48,29.13) v1(164.51,28.61) v1(164.51,28.32) v1(164.51,28.01) v1(164.51,27.7) v1(164.5,27.4) v1(164.5,27.12) v1(164.5,26.8) v1(164.5,26.5) v1(164.74,29.97) v1(164.74,29.69) v1(164.76,29.44) v1(164.76,29.13) v1(164.82,28.61) v1(164.82,28.32) v1(164.81,28.01) v1(164.82,27.7) v1(164.8,27.4) v1(164.8,27.12) v1(164.8,26.8) v1(164.8,26.5) v1(165.05,29.97) v1(165.05,29.69) v1(165.06,29.44) v1(165.07,29.13) v1(165.12,28.61) v1(165.12,28.32) v1(165.11,28.01) v1(165.12,27.7) v1(165.11,27.4) v1(165.11,27.12) v1(165.1,26.8) v1(165.11,26.5) v1(165.35,29.97) v1(165.35,29.69) v1(165.37,29.44) v1(165.37,29.13) v1(165.43,28.61) v1(165.43,28.32) v1(165.43,28.01) v1(165.43,27.7) v1(165.42,27.4) v1(165.42,27.12) v1(165.42,26.8) v1(165.42,26.5) v1(165.65,29.97) v1(165.65,29.69) v1(165.67,29.44) v1(165.67,29.13) v1(165.74,28.61) v1(165.74,28.32) v1(165.73,28.01) v1(165.74,27.7) v1(165.73,27.4) v1(165.73,27.12) v1(165.72,26.8) v1(165.73,26.5) v1(165.96,29.97) v1(165.96,29.69) v1(165.97,29.44) v1(165.97,29.13) v1(166.04,28.61) v1(166.04,28.32) v1(166.03,28.01) v1(166.04,27.7) v1(166.03,27.4) v1(166.03,27.12) v1(166.02,26.8) v1(166.03,26.5) v1(166.27,29.97) v1(166.27,29.69) v1(166.29,29.44) v1(166.29,29.13) v1(166.34,28.61) v1(166.34,28.32) v1(166.34,28.01) v1(166.34,27.7) v1(166.33,27.4) v1(166.33,27.12) v1(166.33,26.8) v1(166.33,26.5) v1(166.58,29.97) v1(166.58,29.69) v1(166.59,29.44) v1(166.6,29.13) v1(166.88,29.97) v1(166.88,29.69) v1(166.89,29.44) v1(166.9,29.13) v1(167.18,29.97) v1(167.18,29.69) v1(167.2,29.44) v1(167.2,29.13) v1(167.48,29.97) v1(167.48,29.69) v1(167.5,29.44) v1(167.5,29.13) v1(167.84,29.67) v1(167.84,29.39) v1(167.84,29.08) v1(167.84,28.77) v1(168.15,29.67) v1(168.15,29.39) v1(168.14,29.08) v1(168.15,28.77) v1(168.45,29.08) v1(168.45,29.67) v1(168.45,29.39) v1(168.45,28.77) v1(168.75,29.08) v1(168.75,29.67) v1(168.75,29.39) v1(168.75,28.77) v1(169.06,29.67) v1(169.06,29.39) v1(169.05,29.08) v1(169.06,28.77)
VIN_HOLD_A: length 17.4
  TOP w0.1: R2706.2 130.33,33.75 v1(130.4,33.82)
  L3 w0.1: v1(130.4,33.82) 130.72,33.82 v2(130.74,33.83)
  L6 w0.1: v2(130.74,33.83) 130.74,33.83 130.78,33.83 130.78,33.36 130.66,33.25 130.66,23.35 130.75,23.26 130.75,21.66 v3(130.85,21.56)
VIN_HOLD_A_1P8: length 83.4
  TOP w0.1: R2706.1 v1(123.35,33.75) ; J2600.C21 v1(49.93,44.37)
  L3 w0.1: v1(49.93,44.37) 49.93,42.46 51.23,41.16 56.52,41.16 56.82,40.86 63.65,40.86 64.05,40.45 66.79,40.45 67.51,39.73 76.21,39.73 76.45,39.97 108.32,39.97 110.15,38.15 110.15,34.93 110.45,34.63 115.58,34.63 115.85,34.37 118.1,34.37 118.46,34 123.09,34 v1(123.35,33.75)
VIN_HOLD_B: length 1.9
  L3 w0.1: v2(126.15,22.5) 126.03,22.62 v1(125.85,22.62)
  L6 w0.1: v2(126.15,22.5) 125.86,22.21 v3(125.85,22.21)
  BOTTOM w0.1: U504.5 v3(125.85,22.21)
VIN_HV: length 38.8
  L6 w0.3: v3(129.25,9.6) 129.23,9.62 129.23,13.28 129.7,13.75 v3(129.7,20)
  BOTTOM w0.3: 144.82,23.05 144.82,11.57 143.57,10.32 R522.1 131.3,9.8 131.1,9.6 v3(129.25,9.6)
  vias: v1(178.01,122.14) v1(178.01,121.84) v1(178,121.44) v1(178.3,122.14) v1(178.3,121.85) v1(178.29,121.44) v1(178.69,122.14) v1(178.69,121.85) v1(178.68,121.44) v1(178.97,122.15) v1(178.97,121.85) v1(178.96,121.45) v2(162.92,122.43) v2(162.92,121.95) v2(162.92,121.44) v2(162.91,120.91) v2(163.49,122.43) v2(163.48,121.94) v2(163.49,121.44) v2(163.47,120.9) v2(164.65,40.93) v2(164.65,40.48) v2(165.11,40.91) v2(165.09,40.48) v2(165.58,40.93) v2(165.58,40.48) v2(166.04,40.91) v2(166.03,40.48) v3(164.51,30.68) v3(164.5,30.45) v3(164.5,30.23) v3(164.5,29.99) v3(164.74,30.68) v3(164.74,30.45) v3(164.73,30.23) v3(164.74,29.99) v3(164.97,30.67) v3(164.97,30.44) v3(164.96,30.22) v3(164.97,29.98) v3(165.2,30.67) v3(165.2,30.44) v3(165.19,30.21) v3(165.2,29.98) v3(165.45,30.44) v3(165.45,30.21) v3(165.45,30.67) v3(165.45,29.98) v3(165.69,30.67) v3(165.68,30.44) v3(165.68,30.21) v3(165.69,29.98) v3(165.92,30.66) v3(165.91,30.43) v3(165.91,30.2) v3(165.92,29.97) v3(166.15,30.66) v3(166.14,30.43) v3(166.14,30.2) v3(166.15,29.96) v6(160.55,31.57) v6(160.54,30.97) v6(161.18,31.57) v6(161.17,30.97) v6(161.82,31.57) v6(161.81,30.97)
VIN_SUB_9TO30V:
  vias: v2(87.76,32.43) v2(87.76,31.89) v2(88.28,32.43) v2(88.28,31.89) v2(88.8,32.44) v2(88.81,31.9) v2(116.45,32.35) v2(116.45,31.8) v2(116.45,31.25) v2(117,32.35) v2(117,31.8) v2(117,31.25) v3(87.5,59.15) v3(87.5,58.9) v3(87.5,58.65) v3(87.5,58.4) v3(87.75,59.15) v3(87.75,58.9) v3(87.75,58.65) v3(87.75,58.4) v3(88,59.15) v3(88,58.9) v3(88,58.65) v3(88,58.4) v3(88.25,59.15) v3(88.25,58.9) v3(88.25,58.65) v3(88.25,58.4) v3(88.55,87.55) v3(88.55,87.3) v3(88.55,87.05) v3(88.55,86.8) v3(88.5,59.15) v3(88.5,58.9) v3(88.5,58.65) v3(88.5,58.4) v3(88.8,87.55) v3(88.8,87.3) v3(88.8,87.05) v3(88.8,86.8) v3(88.75,59.15) v3(88.75,58.9) v3(88.75,58.65) v3(88.75,58.4) v3(89.05,87.55) v3(89.05,87.3) v3(89.05,87.05) v3(89.05,86.8) v3(89.3,87.55) v3(89.3,87.3) v3(89.3,87.05) v3(89.3,86.8) v3(121.65,35) v3(121.65,34.75) v3(121.65,34.5) v3(121.65,34.25) v3(121.65,34) v3(121.65,33.75) v3(121.65,33.5) v3(121.65,33.25) v3(121.9,35) v3(121.9,34.75) v3(121.9,34.5) v3(121.9,34.25) v3(121.9,34) v3(121.9,33.75) v3(121.9,33.5) v3(121.9,33.25) v3(122.15,35) v3(122.15,34.75) v3(122.15,34.5) v3(122.15,34.25) v3(122.15,34) v3(122.15,33.75) v3(122.15,33.5) v3(122.15,33.25) v3(122.4,35) v3(122.4,34.75) v3(122.4,34.5) v3(122.4,34.25) v3(122.4,34) v3(122.4,33.75) v3(122.4,33.5) v3(122.4,33.25)
3P3_PER_COMP1: length 3.4
  BOTTOM w0.1: R512.1 88.07,67.8 88.08,67.8 C519.2 88.48,67.84 89.76,69.13 U500.29
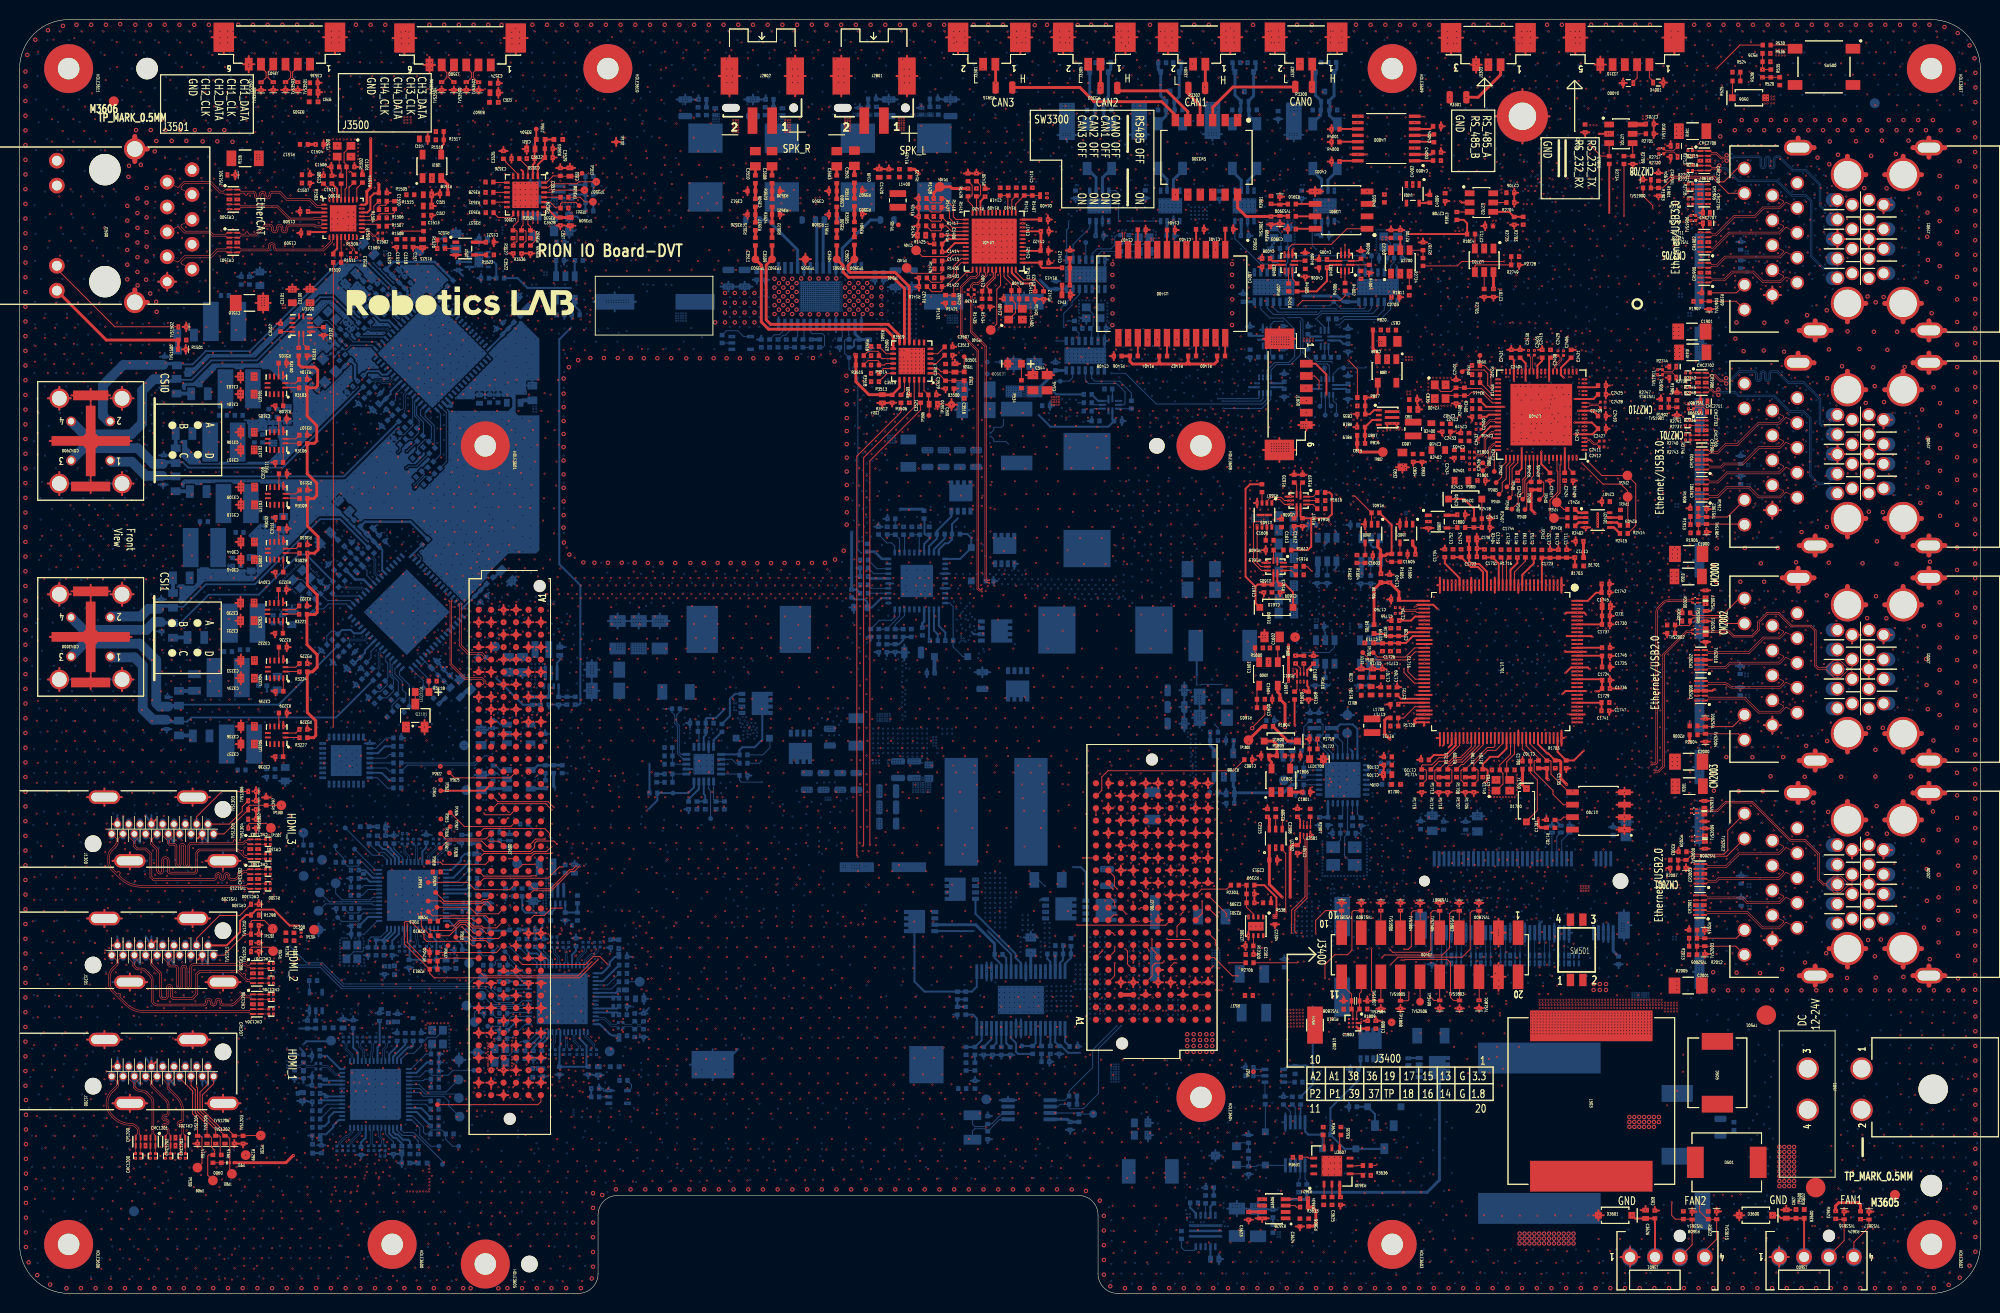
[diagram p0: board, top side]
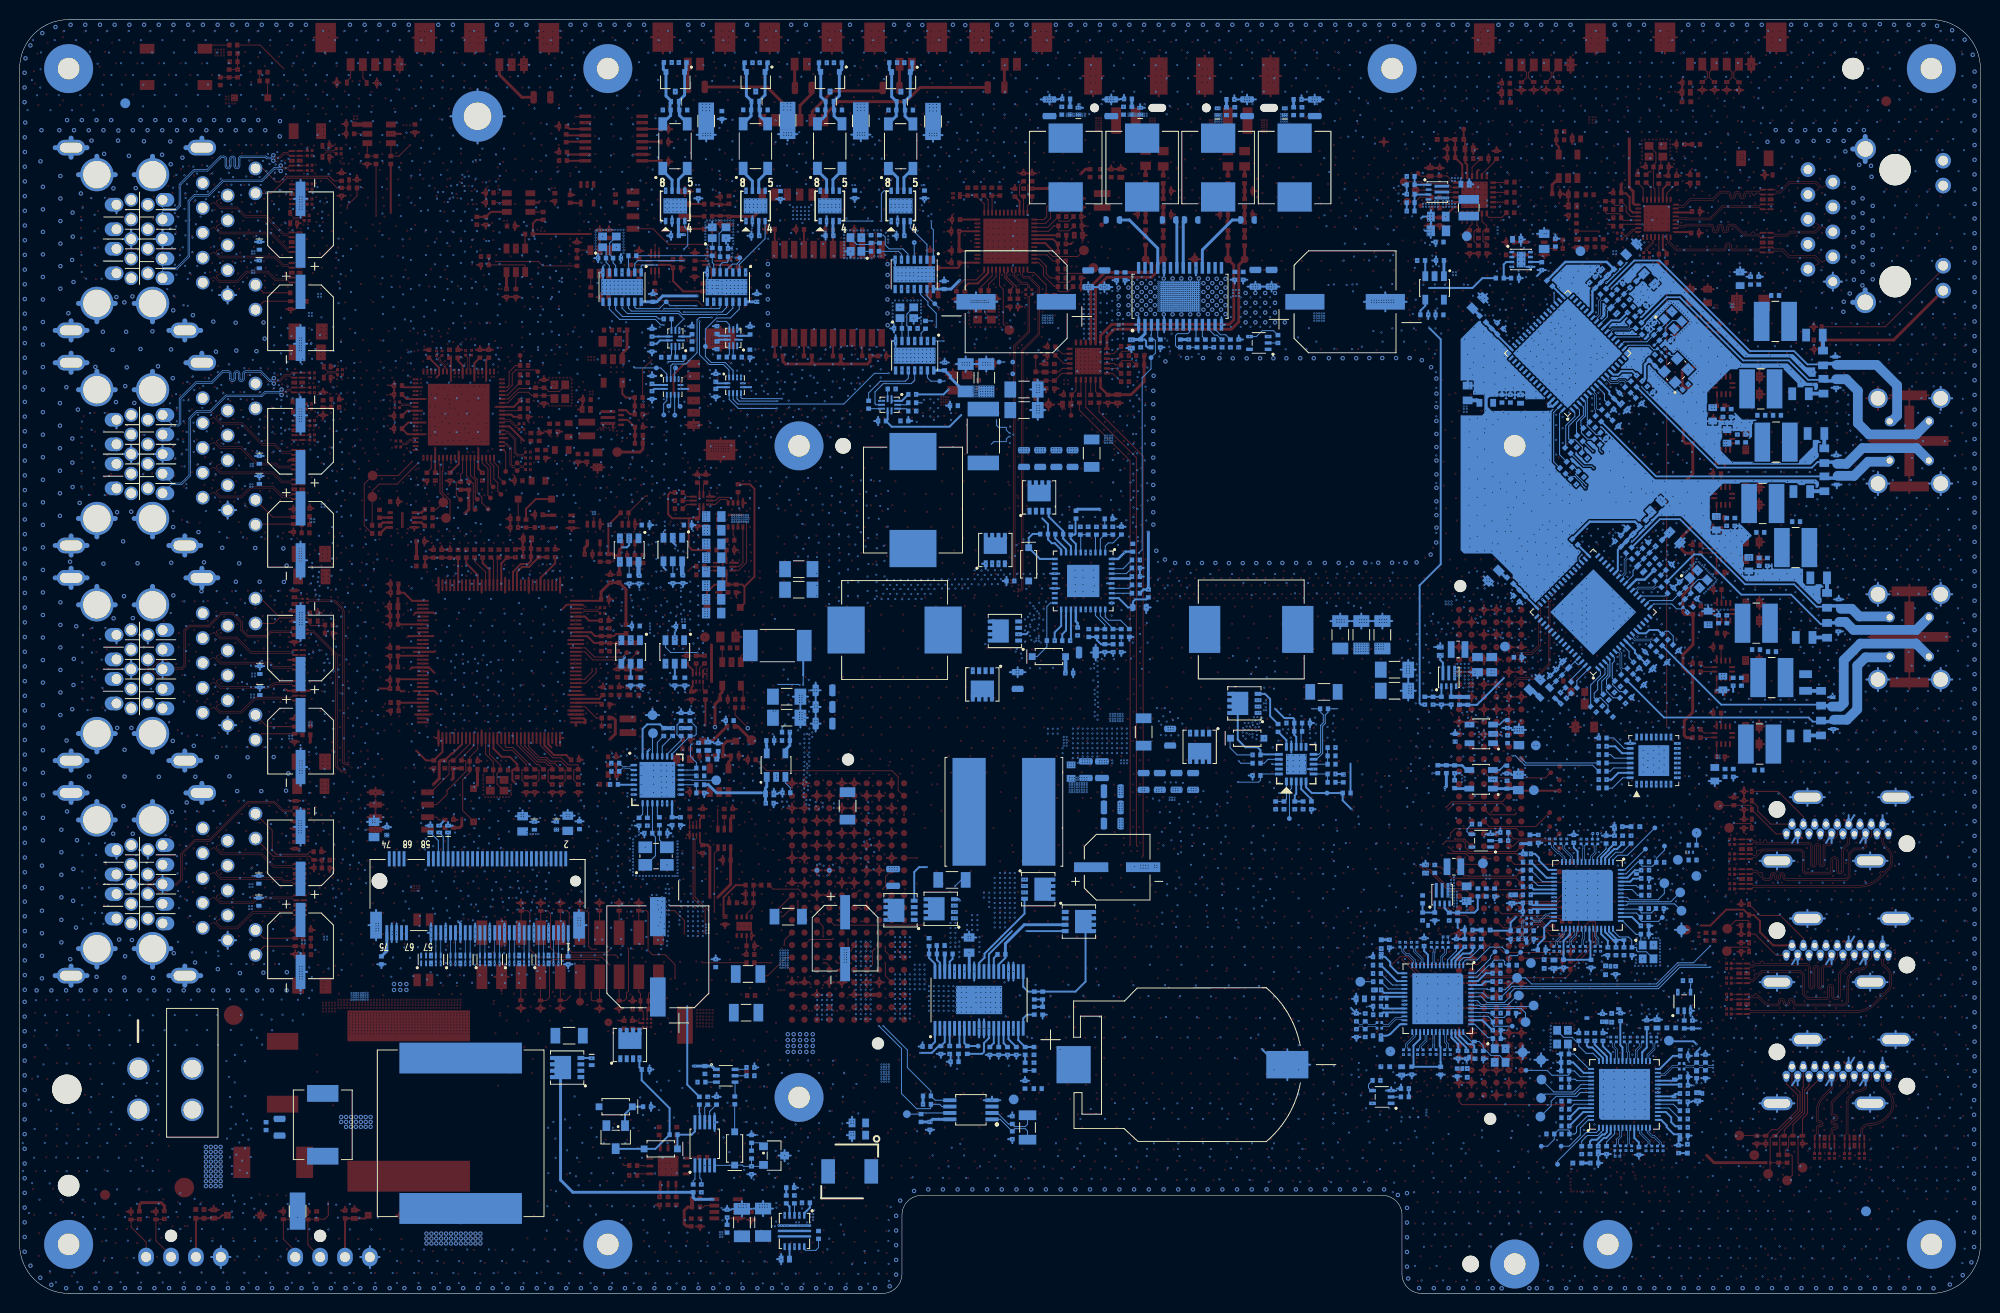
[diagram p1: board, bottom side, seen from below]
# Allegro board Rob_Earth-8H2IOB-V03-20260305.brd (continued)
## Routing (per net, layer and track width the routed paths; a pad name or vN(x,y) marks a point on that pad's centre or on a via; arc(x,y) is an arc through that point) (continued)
3P3_PER_COMP2: length 2.8
  BOTTOM w0.1: C549.2 88.5,77.44 R540.1 89.76,76.99 U500.2
3P3_PER_FB2: length 1.9
  BOTTOM w0.1: R508.2 90.26,77.33 U500.3
3P3_PER_SS1: length 3.7
  BOTTOM w0.1: U500.30 89.26,69.03 88.94,68.7 87.71,68.7 C520.2
3P3_PER_SS2: length 2.8
  BOTTOM w0.1: U500.1 89.26,76.27 88.94,76.59 88.46,76.59 C550.2
5P0_FB1: length 3.2
  BOTTOM w0.1: R542.2 R507.2 89.3,68.22 90.26,69.18 U500.28
7P0_POC_BST: length 6.7
  L6 w0.1: v3(72.25,54.05) 72.77,54.57 73.84,54.57 v3(74.24,54.96)
  BOTTOM w0.1: v3(72.25,54.05) 72.23,54.05 72.19,54.01 U600.18 ; v3(74.24,54.96) 75.81,54.96 76.53,55.68 76.53,56.61 D600.2
7P0_POC_COMP: length 2.3
  BOTTOM w0.1: U600.6 C623.1 R614.1
7P0_POC_CS: length 6
  BOTTOM w0.1: JP600.2 C621.1 67.35,59.37 67.03,59.05 67.03,58.24 67.29,57.98 67.29,55.21 67.49,55.01 U600.10
7P0_POC_ENBK: length 2.5
  BOTTOM w0.1: U600.12 69.29,57.26 R602.2 R608.1
7P0_POC_FB: length 3.1
  BOTTOM w0.1: U600.8 R607.2 C615.1 66.59,55.7 R612.1
7P0_POC_FOSC: length 2.5
  BOTTOM w0.2: U600.4 69.29,51.48 68.24,50.43 R613.1
7P0_POC_FSYNC: length 2.9
  BOTTOM w0.2: U600.3 69.79,50.97 69.94,50.82 R604.2 R611.1
7P0_POC_OUT: length 6.4
  BOTTOM w0.1: JP601.2 C621.2 66.55,59.3 66.83,59.02 66.83,58.16 67.09,57.9 67.09,55.12 67.7,54.51 U600.9
7P0_POC_SPS: length 3
  BOTTOM w0.1: U600.1 70.79,50.46 R610.1 R603.2
8211_1_AVCC_+1V: length 38.6
  TOP w0.2: U1401.4 104.11,106.39 C1421.2 ; U1401.47 101.21,104.14 102.28,103.07 103.23,103.07 103.58,102.72 v1(103.58,102.26) ; U1401.9 104.17,108.39 C1422.2
  TOP w0.3: C1421.2 104.17,106.46 C1422.2
  L3 w0.3: v1(89.75,114.75) 103.57,114.75 103.9,114.42 v2(104.92,114.42) ; v1(103.58,102.26) 104.21,102.26 v2(104.9,102.95) ; v2(104.92,108.36) 104.44,108.36 104.42,108.37 v1(104.14,108.37)
  L6 w0.3: v2(104.9,102.95) 104.9,108.34 v2(104.92,108.36) v2(104.92,114.42)
8211_1_AVCC_+3V3: length 14
  TOP w0.1: C1417.2 v1(104.09,109.74)
  TOP w0.2: U1401.1 104.13,105.19 C1416.2 104.15,104.79 104.28,104.66 R1413.2 ; C1417.2 104.09,109.59 U1401.12
  L3 w0.3: v1(104.09,109.74) v2(106.1,109.74) ; v2(106.65,104.68) v1(106.33,104.68)
  L6 w0.3: v2(106.65,104.68) 106.65,107.1 106.1,107.65 v2(106.1,109.74)
8211_1_DVCC_+1V: length 10.7
  TOP w0.2: C1418.2 98.01,111.46 U1401.22
  TOP w0.3: v1(91.77,114.26) 91.3,114.73 R1423.2
  L3 w0.3: v1(98.49,111.93) 96.83,111.93 94.51,114.26 v1(91.77,114.26)
8211_1_DVDDRG: length 19.8
  TOP w0.2: v1(94.04,107.99) U1401.29
  TOP w0.3: v1(97.61,112.77) 97.6,112.76 R1420.1 ; v1(93.24,111.74) 93.24,112.32 TP1404.1 94.96,112.93 95.12,112.76 R1419.1
  L3 w0.3: 93.24,108.24 v1(93.24,108.95) 93.24,109.9 v1(93.24,109.9) v1(93.24,110.83) 93.24,110.83 v1(93.24,111.74) ; 93.24,108.24 93.24,108.24 93.48,107.99 ; 93.24,108.24 92.99,107.99 ; v2(93.69,104.57) v1(93.31,104.57) ; 93.48,107.99 92.99,107.99 ; 93.48,107.99 v2(93.5,107.99) v1(94.04,107.99) ; 92.99,107.99 92.43,107.99 v1(92.43,108) ; v1(96.73,112.77) v1(97.61,112.77) 97.68,112.84 v1(99.9,112.84)
  L6 w0.3: v2(93.5,107.99) 93.5,104.79 93.69,104.6 v2(93.69,104.57)
8211_1_LED0_PHYAD0: length 5.8
  TOP w0.1: U1401.35 96.03,105.59 95.29,104.85 95.29,104.07 94.86,103.64 R1416.1 94.1,103.27 94.03,103.2 92.98,103.2 R1426.2
8211_1_LED1_CFGL0: length 6.1
  TOP w0.1: U1401.36 96.05,105.19 95.57,104.71 95.57,103.88 94.45,102.76 94.09,102.76 R1422.2 94.09,102.34 93.98,102.24 93.05,102.24 R1432.1
8211_1_LED2_CFGL1: length 4.6
  TOP w0.1: R1431.1 94.46,101.87 R1421.2 95.29,102.94 96.55,104.2 96.55,104.2 97.11,104.2 97.21,104.3 U1401.37
8211_1_REGOUT: length 6.9
  L3 w0.3: v1(89.64,106.82) 89.66,106.79 v1(96.51,106.79)
8211_1_RST_N: length 3.7
  TOP w0.1: Q1400.3 104.09,112.04 R1407.2 103.3,112.05 C1410.1 101.61,111.18 U1401.13
8211_1_RXC_PHYAD1: length 4.9
  TOP w0.1: R1425.2 92.97,108.44 93.94,108.44 94.04,108.54 R1415.1 94.04,108.95 94.51,108.95 95.06,108.39 U1401.28
8211_1_RXCTL_PHYAD2: length 5.1
  TOP w0.1: R1424.2 92.98,109.43 93.93,109.43 94.04,109.54 R1414.1 95.14,108.79 U1401.27
8211_1_RXD0_RXDLY: length 5.7
  TOP w0.1: R1427.2 92.97,110.37 93.9,110.37 94.03,110.5 R1417.2 94.03,110.84 94.49,110.84 94.84,110.48 94.84,109.73 95.37,109.19 U1401.26
8211_1_RXD1_CFG_MODE0: length 6.1
  TOP w0.1: U1401.25 95.53,109.59 95.24,109.88 95.24,110.88 94.37,111.74 R1418.2 94.04,111.39 93.94,111.29 92.96,111.29 R1428.2
8211_1_RXD2_CFG_MODE1: length 3.9
  TOP w0.1: U1401.24 97.21,111 96.74,111.47 R1419.2 97.05,111.96 97.16,112.07 97.16,113.08 R1429.2
8211_1_RXD3_CFG_MODE2: length 3.7
  TOP w0.1: U1401.23 97.61,111.95 R1420.2 97.86,111.96 98.01,112.12 98.01,113.09 R1430.1
8211_1_SGMII_CLK_M: length 3.5
  TOP w0.1: U1401.43 99.61,104.25 99.51,104.15 99.51,103.65 98.67,102.81 98.67,102.7 98.75,102.62 98.75,102.62 98.97,102.39 R1436.1 98.94,102.26 98.94,101.54 R1434.1
8211_1_SGMII_CLK_P: length 3.5
  TOP w0.1: R1435.1 98.17,101.51 R1436.2 98.35,102.46 98.35,102.77 99.31,103.73 99.31,104.15 99.21,104.25 U1401.42
8211_DVCC_+3V3: length 39.2
  TOP w0.2: U1401.30 94.58,107.59 C1414.2 94.09,106.3 C1415.2 94.5,106.3 95.39,107.19 U1401.31
  TOP w0.3: R1416.2 93.3,103.66 v1(93.31,103.67) ; v1(103.31,112.87) 103.3,112.86 R1407.1 ; R1412.2 106.33,101.91 C1413.1
  L3 w0.3: v2(95.29,101.45) v1(95.29,101.08) ; v2(94.6,106.28) v1(94.15,106.28) ; v2(100.65,111.65) 100.66,111.64 102.07,111.64 v1(103.31,112.87) ; v1(93.3,102.75) 93.3,103.65 v1(93.31,103.67) 94.12,103.67 v2(94.14,103.69) 96.01,103.69 96.2,103.49 100.64,103.49 v2(100.65,103.5) 103.53,103.5 103.54,103.49 105.26,103.49 105.84,102.91 v1(106.35,102.91)
  L6 w0.3: v2(100.65,103.5) v2(100.65,111.65) ; v2(94.6,106.28) 94.14,105.81 v2(94.14,103.69) 95.29,102.54 v2(95.29,101.45)
8211_TRXN0: length 20.2
  L3 w0.05: v1(121.01,106.5) 121.25,106.5 121.41,106.35 121.41,106.17 121.12,105.88 120.87,105.88 arc(120.78,105.92) 120.74,106 120.74,106.02 arc(120.62,106.14) 120.49,106.02 120.49,106 arc(120.45,105.92) 120.37,105.88 102.42,105.88 v1(102.31,105.99)
8211_TRXN1: length 19.5
  L3 w0.05: v1(118.03,107.1) 118.34,107.1 118.41,107.04 118.41,106.72 118.31,106.62 117.79,106.62 arc(117.7,106.66) 117.67,106.75 117.67,106.77 arc(117.54,106.9) 117.42,106.77 117.42,106.75 arc(117.38,106.66) 117.29,106.62 108.38,106.62 107.93,107.07 105.5,107.07 arc(105.29,106.98) 105.2,106.77 105.2,106.65 arc(105.07,106.53) 104.95,106.65 104.95,106.8 arc(104.87,106.99) 104.68,107.07 104.65,107.07 arc(104.44,106.98) 104.35,106.77 104.35,106.65 arc(104.22,106.53) 104.1,106.65 104.1,106.8 arc(104.02,106.99) 103.83,107.07 103.8,107.07 arc(103.59,106.98) 103.5,106.77 103.5,106.65 arc(103.37,106.53) 103.25,106.65 103.25,106.8 arc(103.17,106.99) 102.98,107.07 102.62,107.07 v1(102.49,107.2)
8211_TRXN2: length 20.1
  TOP w0.062: U1400.9 115.05,107.07 115.45,107.47 115.45,107.61 v1(115.39,107.67)
  L3 w0.05: v1(102.11,107.99) 102.22,107.88 103.29,107.88 103.4,107.77 arc(103.42,107.75) 103.45,107.75 105.3,107.75 arc(105.32,107.75) 105.34,107.77 105.45,107.88 108.2,107.88 arc(108.44,107.83) 108.65,107.69 109,107.34 arc(109.02,107.33) 109.04,107.32 109.3,107.32 arc(109.34,107.34) 109.36,107.39 109.36,108.02 arc(109.66,108.32) 109.96,108.02 109.96,107.45 arc(110,107.36) 110.09,107.32 110.11,107.32 arc(110.18,107.35) 110.21,107.42 110.21,107.5 arc(110.51,107.8) 110.81,107.5 110.81,107.45 arc(110.85,107.36) 110.94,107.32 112.82,107.32 arc(112.91,107.36) 112.95,107.45 112.95,107.56 arc(113.25,107.86) 113.55,107.56 113.55,107.41 arc(113.58,107.35) 113.64,107.32 113.67,107.32 arc(113.76,107.36) 113.8,107.45 113.8,107.92 arc(114.1,108.22) 114.4,107.92 114.4,107.41 arc(114.43,107.35) 114.49,107.32 114.7,107.32 arc(114.78,107.36) 114.82,107.44 arc(114.85,107.53) 114.94,107.56 114.95,107.56 arc(115.03,107.53) 115.07,107.44 arc(115.1,107.36) 115.19,107.32 115.34,107.32 115.46,107.44 115.46,107.6 v1(115.39,107.67)
8211_TRXN3: length 20.2
  TOP w0.062: U1400.12 112.08,107.1 112.48,107.5 112.48,108.22 v1(112.43,108.26)
  L3 w0.05: v1(112.43,108.26) 112.48,108.21 112.48,108.1 112.41,108.03 111.97,108.03 arc(111.89,108.06) 111.85,108.14 111.85,108.14 arc(111.82,108.23) 111.74,108.26 111.72,108.26 arc(111.64,108.23) 111.6,108.14 111.6,108.14 arc(111.57,108.06) 111.49,108.03 111.35,108.03 arc(111.33,108.03) 111.31,108.04 110.31,109.05 arc(110.29,109.06) 110.26,109.07 109.68,109.07 arc(109.61,109.1) 109.58,109.17 109.58,109.84 arc(109.31,110.12) 109.03,109.84 109.03,109.17 arc(108.93,109.07) 108.83,109.17 108.83,109.83 arc(108.56,110.11) 108.28,109.83 108.28,109.17 arc(108.18,109.07) 108.08,109.17 108.08,109.83 arc(107.81,110.11) 107.53,109.83 107.53,109.17 arc(107.43,109.07) 107.33,109.17 107.33,109.83 arc(107.06,110.11) 106.78,109.83 106.78,109.17 arc(106.75,109.1) 106.68,109.07 105.47,109.07 105.35,109.19 103.08,109.19 102.95,109.07 102.43,109.07 v1(102.31,109.19)
8211_TRXP0: length 20.2
  L3 w0.05: v1(122,106.5) 121.75,106.5 121.59,106.34 121.59,106.1 121.19,105.7 102.42,105.7 v1(102.31,105.59)
8211_TRXP1: length 19.5
  L3 w0.05: v1(119.02,107.1) 118.65,107.1 118.59,107.04 118.59,106.65 118.38,106.45 108.31,106.45 107.86,106.9 105.5,106.9 arc(105.41,106.86) 105.37,106.77 105.37,106.65 arc(105.07,106.35) 104.77,106.65 104.77,106.8 arc(104.75,106.87) 104.68,106.9 104.65,106.9 arc(104.56,106.86) 104.52,106.77 104.52,106.65 arc(104.22,106.35) 103.92,106.65 103.92,106.8 arc(103.9,106.87) 103.83,106.9 103.8,106.9 arc(103.71,106.86) 103.67,106.77 103.67,106.65 arc(103.37,106.35) 103.07,106.65 103.07,106.8 arc(103.05,106.87) 102.98,106.9 102.59,106.9 v1(102.49,106.8)
8211_TRXP2: length 20.1
  TOP w0.062: U1400.8 116.04,107.08 115.64,107.48 115.64,107.62 v1(115.69,107.67)
  L3 w0.05: v1(115.69,107.67) 115.64,107.61 115.64,107.37 115.41,107.15 114.49,107.15 arc(114.3,107.23) 114.22,107.41 114.22,107.92 arc(114.1,108.05) 113.97,107.92 113.97,107.45 arc(113.89,107.23) 113.67,107.15 113.64,107.15 arc(113.45,107.23) 113.37,107.41 113.37,107.56 arc(113.25,107.68) 113.12,107.56 113.12,107.45 arc(113.04,107.23) 112.82,107.15 110.94,107.15 arc(110.73,107.23) 110.64,107.45 110.64,107.5 arc(110.51,107.63) 110.39,107.5 110.39,107.42 arc(110.31,107.23) 110.11,107.15 110.09,107.15 arc(109.88,107.23) 109.79,107.45 109.79,108.02 arc(109.66,108.15) 109.54,108.02 109.54,107.39 arc(109.47,107.22) 109.3,107.15 109.04,107.15 arc(108.95,107.16) 108.87,107.22 108.52,107.57 arc(108.37,107.67) 108.2,107.7 105.52,107.7 105.46,107.64 arc(105.39,107.59) 105.3,107.57 103.45,107.57 arc(103.35,107.59) 103.28,107.64 103.22,107.7 102.22,107.7 v1(102.11,107.59)
8211_TRXP3: length 20.3
  TOP w0.062: v1(112.73,108.26) 112.67,108.2 112.67,107.49 113.07,107.08 U1400.11
  L3 w0.05: v1(112.73,108.26) 112.66,108.2 112.66,108.04 112.47,107.84 111.26,107.84 110.21,108.89 109.68,108.89 arc(109.49,108.97) 109.41,109.17 109.41,109.84 arc(109.31,109.94) 109.21,109.84 109.21,109.17 arc(108.93,108.89) 108.66,109.17 108.66,109.83 arc(108.56,109.93) 108.46,109.83 108.46,109.17 arc(108.18,108.89) 107.91,109.17 107.91,109.83 arc(107.81,109.93) 107.71,109.83 107.71,109.17 arc(107.43,108.89) 107.16,109.17 107.16,109.83 arc(107.06,109.93) 106.96,109.83 106.96,109.17 arc(106.88,108.97) 106.68,108.89 105.4,108.89 105.28,109.01 103.15,109.01 103.02,108.88 102.4,108.88 v1(102.31,108.79)
8211_XTAL_IN: length 5.9
  TOP w0.1: U1401.45 100.41,103.75 101.16,102.99 101.16,102.34 R1408.2 101.16,101.51 C1409.1 101.17,101.43 101.58,101.02 101.58,100.08 Y1400.1
8211_XTAL_OUT: length 4.6
  TOP w0.1: Y1400.3 101.96,100.8 C1411.1 R1408.1 101.97,102.34 101.97,102.68 100.81,103.84 U1401.46
AMP_FAULT_1P8: length 93.4
  L3 w0.1: v2(85.85,32.8) 89.25,32.8 89.6,32.45 110.49,32.45 v1(111.05,33.01)
  L6 w0.1: v3(85.85,75.55) 85.85,72.15 85.3,71.6 85.3,48.85 85.65,48.5 85.65,47.45 85.4,47.2 85.4,37.8 85.85,37.35 v2(85.85,32.8)
  BOTTOM w0.1: U2800.3 84.56,97.85 84.6,97.81 R2818.1 84.25,97.35 84.15,97.25 84.15,95.95 TP2800.1 84.6,94.35 85.5,93.45 85.5,75.9 v3(85.85,75.55)
AMP_I2C_SCL_1P8: length 96
  TOP w0.1: J2600.B18 52.04,48.18 v1(52.09,48.23)
  L3 w0.1: v2(84.37,48.16) 84.22,48.02 55.21,48.02 54.32,48.91 52.83,48.91 52.15,48.23 v1(52.09,48.23) ; v2(80.31,96.53) 80.56,96.53 80.94,96.91 83.59,96.91 86.6,93.9 v1(86.85,93.9)
  L6 w0.1: v3(78.2,96.55) 80.29,96.55 v2(80.31,96.53) 80.72,96.12 81.96,96.12 82.37,95.71 83.39,95.71 84.95,94.15 84.95,75.62 84.44,75.11 84.44,48.24 84.38,48.17 84.38,48.16 v2(84.37,48.16)
  BOTTOM w0.1: R2809.1 R2817.2
AMP_I2C_SDA_1P8: length 94.6
  TOP w0.1: J2600.B19 v1(52.11,46.91)
  L3 w0.1: v1(86.85,93.05) 83.35,96.55 v2(81.09,96.55) ; v1(52.11,46.91) 52.11,47.84 52.96,48.7 54.24,48.7 55.12,47.81 84.59,47.81 v2(84.89,48.12)
  L6 w0.1: v2(84.89,48.12) 84.9,48.12 84.9,48.12 84.64,48.38 84.64,75.03 85.15,75.53 85.15,94.25 83.49,95.91 82.45,95.91 82,96.37 81.27,96.37 v2(81.09,96.55) v3(80.75,96.55)
  BOTTOM w0.1: R2806.1 v3(80.75,96.55)
AMP_I2S_LPCLK_1P8: length 4.4
  TOP w0.1: J2600.F26 46.34,38.02 46.07,38.28 42.95,38.28 R2810.1
AMP_I2S_SCLK_1P8: length 5
  TOP w0.1: J2600.F27 46.36,36.75 45.45,37.66 44.98,37.66 43.82,36.5 R2811.1
AMP_I2S_SDIN_1P8: length 5.2
  TOP w0.1: R2812.1 42.63,33.08 R2813.1 42.92,34.21 J2600.F29
AMP_I2S_SDOUT_1P8: length 129.2
  TOP w0.1: J2600.F28 46.17,35.48 45.72,35.93 41.52,35.93 41.25,36.2 41.25,36.6 39.9,37.95 39.35,37.95 39.25,37.85 39.25,35.66 R2812.2 41.83,32.67 42.29,32.21 57.13,32.21 v1(59,34.08)
  L3 w0.1: v1(59,34.08) 85.17,34.08 v2(85.31,34.21)
  L6 w0.1: v3(81.6,96.62) 82.03,96.62 82.53,96.11 83.59,96.11 85.35,94.35 85.35,75.45 84.85,74.95 84.85,48.66 84.93,48.58 84.93,48.57 85.04,48.47 85.24,48.26 85.24,48.26 85.25,48.25 85.25,47.68 84.93,47.37 84.93,37.89 84.77,37.73 84.77,37.3 85.31,36.76 v2(85.31,34.21)
  BOTTOM w0.1: U2800.9 80.66,98.14 80.85,97.95 81.9,97.95 82.1,97.75 82.1,96.72 81.93,96.55 R2800.1
AMP_PA_PDN: length 103.2
  TOP w0.1: J2600.C22 51.32,43.79 v1(52.56,43.79)
  L3 w0.1: v1(52.56,43.79) 52.89,43.79 53.71,42.97 56.46,42.97 56.66,43.16 57.94,43.16 58.24,42.86 62.57,42.86 62.87,43.16 63.49,43.16 63.99,42.66 64.39,42.66 64.8,42.25 67.59,42.25 67.88,41.97 84.2,41.97 v2(84.4,42.17)
  L6 w0.1: v2(84.4,42.17) 84.73,42.5 84.73,47.02 84.01,47.75 84.01,49.34 84.24,49.58 84.24,75.2 84.75,75.7 84.75,94.05 83.29,95.51 82.28,95.51 81.94,95.86 72.79,95.86 v3(71.65,97)
  BOTTOM w0.1: U2805.2 v3(71.65,97)
CAN0_H: length 6.4
  TOP w0.3: R3300.2 131.84,123.16 J3302.1
  L3 w0.3: v2(133.35,123.12) 132.99,123.12 132.99,123.12 v1(131.8,123.12)
  L6 w0.3: v3(133.48,125.6) 133.48,125.34 133.35,125.21 v2(133.35,123.12)
CAN0_H_R: length 10.6
  TOP w0.3: SW3300.3 121.7,121.05 123.76,123.12 130.1,123.12 R3300.1
CAN0_L: length 24.1
  TOP w0.3: J3302.2 130.6,125.46 v1(130.62,125.48)
  L3 w0.3: v2(132.84,125.04) 131.06,125.04 v1(130.62,125.48) ; v1(121.73,112.58) 122.24,113.09 v2(129.05,113.09)
  L6 w0.3: v2(129.05,113.09) 129.05,117.92 132.84,121.71 v2(132.84,125.04) 132.84,125.54 v3(132.78,125.6)
CAN1_H: length 9.4
  TOP w0.3: J3304.1 120.94,123.05 R3302.2
  L3 w0.3: v2(125.29,123.09) v1(120.88,123.09)
  L6 w0.3: v2(125.29,123.09) 125.25,123.14 v3(125.25,125.6)
CAN1_H_R: length 3.8
  TOP w0.3: SW3300.4 120.4,119.76 120.4,121.23 119.22,122.41 R3302.1
CAN1_L: length 21.7
  TOP w0.3: v1(119.65,125.47) 119.67,125.45 J3304.2
  L3 w0.3: v1(120.43,112.61) 121.4,113.58 v2(124.57,113.58) ; v1(119.65,125.47) 120.02,125.1 v2(124.57,125.1)
  L6 w0.3: v3(124.51,125.6) 124.57,125.54 v2(124.57,125.1) v2(124.57,113.58)
CAN2_H: length 13
  TOP w0.3: R3303.2 110.26,125.43 J3305.1
  L3 w0.3: v2(117.67,122.61) 117.11,122.61 117.11,122.61 110.69,122.61 v1(110.26,123.03)
  L6 w0.3: v2(117.67,122.61) 117.69,122.63 v3(117.69,125.58)
  BOTTOM w0.3: R3406.2 117.68,125.58 v3(117.69,125.58)
CAN2_H_R: length 9.1
  TOP w0.3: SW3300.5 119.16,120.6 117.03,122.73 112.26,122.73 R3303.1
CAN2_L: length 23.5
  L3 w0.3: v2(116.92,125.07) 116.5,125.49 v1(109.02,125.49) ; v1(119.17,112.18) 118.66,112.68 v2(116.92,112.68)
  L6 w0.3: v3(116.94,125.6) 116.92,125.58 v2(116.92,125.07) 116.92,112.69 v2(116.92,112.68)
CAN3_H: length 15.2
  TOP w0.3: J3301.1 99.55,125.41 R3915.2
  L3 w0.3: v2(110.49,123.96) 109.84,123.96 109.84,123.96 103.68,123.96 103.67,123.97 99.96,123.97 v1(99.52,123.53)
  L6 w0.3: v3(110.49,125.61) v2(110.49,123.96)
CAN3_H_R: length 18.3
  TOP w0.3: R3915.1 108.15,123.07 109.6,121.63 116.5,121.63 117.89,120.24 SW3300.6
CAN3_L: length 33.6
  L3 w0.3: v2(109.77,124.86) 109.77,124.83 109.3,124.36 103.84,124.36 103.2,125.01 v1(98.26,125.01) ; v1(117.89,112.13) v2(109.86,112.13)
  L6 w0.3: v2(109.86,112.13) 109.77,112.22 v2(109.77,124.86) v3(109.77,125.61)
  BOTTOM w0.3: R3409.2 v3(109.77,125.61)
CAN_INT0_1P8: length 137.2
  TOP w0.1: J2600.E22 48.1,43.1 v1(48.11,43.09)
  L3 w0.1: v2(106.92,82.87) 107.16,83.1 108.39,83.1 108.51,83.22 132.93,83.22 v2(133.36,83.65) ; v2(103.21,39.62) 102.77,39.62 102.68,39.53 67.43,39.53 66.74,40.21 64.01,40.21 63.56,40.66 56.71,40.66 56.41,40.96 51.09,40.96 50.8,41.24 49.55,41.24 49.16,41.63 49.16,41.64 48.11,42.69 v1(48.11,43.09)
  L6 w0.1: v2(133.36,83.65) 133.71,84 133.71,89.45 133.92,89.66 v3(134.29,89.66) ; v2(103.21,39.62) 103.21,42.74 106.93,46.47 106.93,82.57 106.92,82.58 v2(106.92,82.87)
  BOTTOM w0.1: U3412.3 133.98,91.11 134.31,90.79 134.31,89.67 v3(134.29,89.66)
CAN_INT1_1P8: length 131.2
  TOP w0.1: v1(54.48,49.61) 53.91,50.18 48.78,50.18 48.24,50.72 J2600.E16
  L3 w0.1: v1(54.48,49.61) 54.59,49.51 55.37,48.72 83.45,48.72 83.67,48.94 85.48,48.94 86.1,48.32 97.64,48.32 98.23,47.73 98.81,47.73 99.04,47.51 101.13,47.51 101.5,47.13 106.5,47.13 v2(106.55,47.18) ; v2(133.36,84.18) 132.66,83.47 108.38,83.47 108.28,83.37 107.19,83.37 107.14,83.42 v2(106.96,83.42)
  L6 w0.1: v2(133.36,84.18) 133.43,84.24 133.43,90.21 133.78,90.56 v3(133.79,90.56) ; v2(106.96,83.42) 106.82,83.27 106.78,83.27 106.57,83.07 106.57,82.5 106.67,82.4 106.67,54.97 106.55,54.84 v2(106.55,47.18)
  BOTTOM w0.1: U3412.4 133.58,90.76 v3(133.79,90.56)
CAN_INT2_1P8: length 138.4
  L3 w0.1: v2(108.07,83.72) 108.09,83.7 132.6,83.7 132.99,84.09 v2(132.99,84.56) ; v2(108.08,39.36) 108.11,39.36 108,39.25 102.91,39.25 102.83,39.33 67.34,39.33 66.66,40.01 63.92,40.01 63.48,40.46 56.62,40.46 56.32,40.76 51,40.76 50.72,41.04 49.46,41.04 48.96,41.55 48.96,41.55 48.68,41.83 v1(48.09,41.83)
  L6 w0.1: v2(132.99,84.56) 133.17,84.74 v3(133.17,89.63) ; v2(108.08,39.36) 108.12,39.36 108.2,39.44 108.2,83.58 v2(108.07,83.72)
  BOTTOM w0.1: v3(133.17,89.63) 133.18,89.64 U3412.5
CAN_INT3_1P8: length 131.3
  TOP w0.1: v1(54.28,49.36) 54.28,49.35 53.66,49.98 48.74,49.98 48.21,49.45 J2600.E17
  L3 w0.1: v2(106.78,83.91) 107.71,83.91 107.88,84.09 108.27,84.09 108.42,83.93 132.34,83.93 v2(132.6,84.19) ; v1(54.28,49.36) 54.28,49.35 54.44,49.35 55.28,48.51 83.53,48.51 83.75,48.74 85.4,48.74 86.02,48.12 97.56,48.12 98.14,47.53 98.73,47.53 98.96,47.31 101.04,47.31 101.42,46.93 106.08,46.93 v2(106.28,46.73)
  L6 w0.1: v2(106.28,46.73) 106.28,46.85 106.2,46.93 106.2,54.82 106.37,55 106.37,83.51 v2(106.78,83.91) ; v3(132.64,90.5) 132.9,90.23 132.9,85.02 132.6,84.72 v2(132.6,84.19)
  BOTTOM w0.1: U3412.6 132.78,90.68 TP2614.1 132.63,90.51 v3(132.64,90.5)
CAN_INT_0: length 14.3
  L6 w0.1: v3(137.35,94.55) 137.35,99.35 138.2,100.2 138.2,103.85 v3(138.55,104.2)
  BOTTOM w0.1: v3(137.35,94.55) 137.25,94.45 TP3403.1 134.6,94.45 133.98,93.83 U3412.12
CAN_INT_1: length 19.5
  L6 w0.1: v3(127,105.7) 127,104.95 128.35,103.6 128.35,102.5 129.45,101.4 129.45,99.65 v3(129.4,99.6)
  BOTTOM w0.1: U3409.4 127.9,104.45 127.3,105.05 126.85,105.05 126.55,105.35 TP3402.1 v3(127,105.7) ; U3412.11 133.58,94.67 133.4,94.85 132.05,94.85 130.9,96 130.9,99.35 130.65,99.6 v3(129.4,99.6)
CAN_INT_2: length 28.7
  L3 w0.1: v2(133.28,94.01) 133.01,93.74 132.55,93.74 132.4,93.88 126.77,93.88 126.52,94.13 125.74,94.13 125.49,93.89 110.76,93.89 v2(110.55,94.1)
  L6 w0.1: v2(110.55,94.1) 110.55,95.35 v3(108.7,97.2) ; v2(133.28,94.01) 133.28,94.14 133.2,94.22 v3(133.2,94.45)
  BOTTOM w0.1: U3412.10 133.18,94.43 v3(133.2,94.45)
CAN_INT_3: length 43.6
  L3 w0.1: v2(106,94.5) 111.55,94.5 111.96,94.09 125.41,94.09 125.65,94.33 126.61,94.33 126.85,94.08 132.78,94.08 v2(132.79,94.09)
  L6 w0.1: v3(108.75,107.25) U3413.4 106.8,103.55 106.8,102.25 106,101.45 v2(106,94.5) ; v2(132.79,94.09) v3(132.79,93.34)
  BOTTOM w0.1: U3413.4 v3(108.75,107.25)
CAN_MCLK1: length 9.5
  BOTTOM w0.1: U3409.6 129.2,105.05 129.35,105.2 R3498.1 R3412.1
CAN_MCLK2: length 11.6
  L6 w0.1: v3(106.9,99.25) 106.9,101.6 107.3,102 107.3,103.46 109.34,105.5 v3(110.05,105.5)
  BOTTOM w0.1: v3(110.05,105.5) 110.05,106.05 110.35,106.35 R3496.1 ; R2302.1 v3(106.9,99.25)
CAN_MCLKO: length 1.7
  BOTTOM w0.1: U3407.3 R3412.2
CAN_SPI1_CLK: length 13.5
  L6 w0.1: v3(134.3,100.5) v3(134.3,99.45)
  BOTTOM w0.1: U3407.10 139.2,100.4 138.5,99.7 135.05,99.7 134.8,99.45 v3(134.3,99.45) ; v3(134.3,100.5) 128.65,100.5 128.55,100.6 U3409.10
CAN_SPI1_CLK_1P8: length 81.9
  L3 w0.1: v1(113.6,36.92) 115.85,36.92 116.85,35.92 128.65,35.92 128.95,35.62 v2(133.4,35.62)
  L6 w0.1: v2(133.4,35.62) 133.4,41.62 132.6,42.42 132.6,46.67 135.1,49.17 135.1,54.07 134.75,54.42 134.75,95.35 v3(134.55,95.54)
CAN_SPI1_CS0: length 16.9
  L6 w0.1: v3(130.96,100.8) 130.96,99.51 v3(130.65,99.2)
  BOTTOM w0.1: v3(130.65,99.2) 130.65,95.8 129.65,94.8 128.21,94.8 127.65,94.24 127.65,93.51 U3414.12 ; U3407.13 137.25,100.65 137.1,100.5 134.75,100.5 TP3407.1 133.65,100.8 v3(130.96,100.8)
CAN_SPI1_CS0_1P8: length 69.7
  TOP w0.1: v1(114.15,37.97) 113.72,37.97 J2700.D9
  L3 w0.1: v2(121.15,36.37) 120.85,36.67 117.85,36.67 117.75,36.57 117.35,36.57 116.2,37.72 114.4,37.72 v1(114.15,37.97)
  L6 w0.1: v2(121.15,36.37) 123,38.22 123,56.27 122.2,57.07 122.2,58.22 122,58.42 122,68.97 122.75,69.72 v3(122.75,90.32)
  BOTTOM w0.1: U3414.3 127.62,91.24 126.7,90.32 v3(122.75,90.32)
CAN_SPI1_CS1: length 12
  BOTTOM w0.1: U3409.13 126.6,100.45 127.5,99.55 128.9,99.55 130.05,98.4 TP3406.1 130.05,95.6 129.45,95 128.02,95 127.22,94.2 U3414.11
CAN_SPI1_CS1_1P8: length 127.9
  TOP w0.1: v1(51.9,53.06) 51.9,53.07 J2600.B14
  L3 w0.1: v2(109.05,45.57) 105.9,48.71 98.1,48.71 97.89,48.92 86.35,48.92 85.73,49.54 83.42,49.54 83.23,49.34 55.73,49.34 55.1,49.97 55.1,49.97 52.01,53.06 v1(51.9,53.06)
  L6 w0.1: v3(111.35,93.9) 110.4,92.95 110.4,88.65 109.7,87.95 109.7,47.27 109.05,46.62 v2(109.05,45.57)
  BOTTOM w0.1: v3(111.35,93.9) 112.8,93.9 115.93,90.77 126.75,90.77 127.22,91.24 U3414.4
CAN_SPI1_MISO: length 15.1
  L6 w0.1: v3(128.85,99.9) v3(128.85,99.2)
  BOTTOM w0.1: U3409.12 127.25,100.55 127.9,99.9 v3(128.85,99.9) 132.4,99.9 132.75,100.25 137.6,100.25 137.9,100.55 U3407.12 ; U3410.5 127.61,98.36 127.61,98.88 127.93,99.2 v3(128.85,99.2)
CAN_SPI1_MISO_1P8: length 75.5
  TOP w0.1: J2700.D6 v1(113.6,33.72)
  L3 w0.1: v2(120.35,32.32) 118.05,32.32 117.15,33.22 115.95,33.22 115.45,33.72 v1(113.6,33.72)
  L6 w0.1: v3(128.55,95.47) 128.55,78.79 124.6,74.84 124.6,57.27 123.25,55.92 123.25,33.45 122.5,32.7 120.73,32.7 v2(120.35,32.32)
CAN_SPI1_MOSI: length 14.8
  L6 w0.1: v3(132.25,100.15) v3(132.25,99.45)
  BOTTOM w0.1: U3407.11 138.55,100.55 138,100 132.8,100 v3(132.25,99.45) 133.11,98.59 U3406.4 ; U3409.11 127.9,100.6 128.35,100.15 v3(132.25,100.15)
CAN_SPI1_MOSI_1P8: length 86.3
  TOP w0.1: J2700.D7 v1(113.6,34.97)
  L3 w0.1: v2(133.4,34.07) 133.25,34.22 129.43,34.22 129.13,33.92 124.15,33.92 123.58,34.48 118.88,34.48 118.6,34.77 116.35,34.77 115.9,35.22 113.85,35.22 v1(113.6,34.97)
  L6 w0.1: v2(133.4,34.07) 133.4,35.02 133,35.42 133,36.12 133.15,36.27 133.15,41.51 132.4,42.26 132.4,46.75 134.9,49.25 134.9,53.97 134.55,54.32 134.55,92.77 133.9,93.41 v3(133.9,95)
  BOTTOM w0.1: v3(133.9,95) 133.8,95.1 132.31,95.1 132.21,95.2 R3418.1
CAN_SPI2_CLK: length 16.2
  L6 w0.1: v3(109.35,94.2) 109.35,95.55 108.2,96.7 108.2,97.55 107.8,97.95 107.8,101.45 108.55,102.2 109.1,102.2 v3(109.4,102.5)
  BOTTOM w0.1: v3(109.35,94.2) 109.35,93.4 109.65,93.1 112.2,93.1 113.4,91.9 R3426.2
CAN_SPI2_CLK_1P8: length 119.2
  TOP w0.1: v1(58.35,33.83) 56.93,32.41 47.35,32.41 J2600.F30
  L3 w0.1: v1(58.35,33.83) 108.27,33.83 v2(108.61,34.16)
  L6 w0.1: v3(108.4,90.05) 109.13,89.32 109.13,75.45 108.87,75.2 108.83,75.2 108.63,74.99 108.63,34.16 v2(108.61,34.16)
CAN_SPI2_CS0: length 24.4
  L3 w0.1: v2(105.65,93.4) 126,93.4 v2(126.35,93.05)
  L6 w0.1: v3(105.65,93.1) v2(105.65,93.4) ; v3(126.82,93.48) 126.39,93.05 v2(126.35,93.05)
  BOTTOM w0.1: v3(105.65,93.1) TP3405.1 107.05,93.1 107.4,93.45 U3411.13
CAN_SPI2_CS0_1P8: length 67.6
  TOP w0.1: J2700.B12 111.05,41.73 v1(111.54,41.25)
  L3 w0.1: v1(111.54,41.25) 112.57,40.22 114.61,40.22 114.95,39.88 118.63,39.88 119.2,39.32 119.61,39.32 v2(119.97,39.67)
  L6 w0.1: v2(119.97,39.67) 119.97,40.01 120.63,40.67 120.63,57.52 121.71,58.6 121.71,69.03 122.5,69.82 122.5,90.87 v3(122.7,91.07)
  BOTTOM w0.1: v3(122.7,91.07) 126.6,91.07 126.82,91.29 U3414.5
CAN_SPI2_CS1: length 29.4
  L3 w0.1: v2(126.34,93.78) 125.67,93.78 125.54,93.65 107.85,93.65 107.7,93.8 v2(106.85,93.8)
  L6 w0.1: v2(106.85,93.8) 106.85,94.25 106.25,94.85 v3(106.25,100.6) ; v2(126.34,93.78) 126.34,93.79 126.41,93.72 v3(126.41,93.47)
  BOTTOM w0.1: U3413.13 107.45,101.8 TP3404.1 v3(106.25,100.6)
CAN_SPI2_CS1_1P8: length 67.8
  TOP w0.1: v1(111.96,41.27) 111.67,41.56 111.67,42.53 111.05,43.15 J2700.B13
  L3 w0.1: v2(119.41,39.76) 119.09,40.08 115.09,40.08 114.71,40.47 112.77,40.47 v1(111.96,41.27)
  L6 w0.1: v3(122.25,91.32) 122.25,69.87 121.51,69.13 121.51,58.68 120.42,57.6 120.42,40.77 119.6,39.94 v2(119.41,39.76)
  BOTTOM w0.1: U3414.6 126.42,91.42 126.32,91.32 v3(122.25,91.32)
CAN_SPI2_MISO: length 31.2
  L3 w0.1: v2(106.6,98.2) 106.74,98.34 124.21,98.34 124.89,97.66 v2(127.19,97.66)
  L6 w0.1: v2(127.19,97.66) 127.19,98.36 v3(127.21,98.37) ; v3(106.5,98.6) 106.6,98.5 v2(106.6,98.2) 106.6,97.15 108.05,95.7 v3(108.05,94.2)
  BOTTOM w0.1: U3413.12 108.1,101.95 107.35,101.2 107.35,100.87 106.5,100.02 v3(106.5,98.6)
CAN_SPI2_MISO_1P8: length 131.9
  TOP w0.1: J2600.B26 52.47,38.58 53.53,38.58 54.27,39.32 v1(55.29,39.32)
  L3 w0.1: v1(55.29,39.32) 63.48,39.32 64.07,38.73 102.58,38.73 102.96,38.35 103.35,38.35 v2(103.59,38.11) ; v2(126.33,95) 109.35,95 109.05,95.3 v2(106.85,95.3)
  L6 w0.1: v2(103.59,38.11) 103.59,38.11 103.59,42.78 107.18,46.37 107.18,82.62 107.38,82.83 107.38,94.77 v2(106.85,95.3) ; v3(126.34,95.55) 126.34,95.01 v2(126.33,95)
CAN_SPI2_MOSI: length 16.9
  L6 w0.1: v3(108.75,102.5) 108.5,102.5 107.55,101.55 107.55,97.8 107.95,97.4 107.95,96.55 108.7,95.8 v3(108.7,94.2)
  BOTTOM w0.1: U3408.4 112.64,90.69 112.75,90.8 112.75,92 111.9,92.85 109.05,92.85 108.7,93.2 v3(108.7,94.2)
CAN_SPI2_MOSI_1P8: length 115.6
  TOP w0.1: v1(47.5,39.7) 47.34,39.7 46.92,39.29 J2600.F25
  L3 w0.1: v2(108.21,38.78) 103.56,38.78 103.34,38.55 103.05,38.55 102.67,38.93 64.15,38.93 63.23,39.86 56.38,39.86 56.37,39.86 47.66,39.86 v1(47.5,39.7)
  L6 w0.1: v2(108.21,38.78) 108.43,39 108.43,75.07 108.75,75.4 108.79,75.4 108.93,75.53 108.93,89.12 108,90.05 v3(108,90.9)
  BOTTOM w0.1: R3420.1 v3(108,90.9)
CAN_STB_0: length 21
  L6 w0.1: v3(134.1,112.54) 134.1,111.91 134.25,111.77 134.25,104.45 133.9,104.1 133.9,99.25 v3(134.3,98.85)
  BOTTOM w0.1: U3407.9 139.85,100.45 138.8,99.4 135.15,99.4 134.6,98.85 v3(134.3,98.85)
CAN_STB_1: length 12.7
  L6 w0.1: v3(129.2,101.2) 128.15,102.25 128.15,103.5 126.2,105.45 126.2,112.24 v3(125.91,112.53)
CAN_STB_2: length 36
  L6 w0.1: v8(105.3,110.32) 105.3,102.8 104.6,102.1 104.6,94.65 v8(104.55,94.6)
  L7 w0.1: v7(118.34,112.54) 117.83,112.02 107.62,112.02 105.91,110.32 v8(105.3,110.32) ; v8(104.55,94.6) 105.4,93.75 109.55,93.75 v7(110,94.2)
CAN_STB_3: length 11.7
  L6 w0.1: v3(110.05,102.5) 111.05,103.5 111.05,108.4 v3(112.1,109.45)
  BOTTOM w0.1: v3(112.1,109.45) 112.1,112.25 111.82,112.53 U3405.8
CH334_XI: length 6.9
  BOTTOM w0.1: U2503.10 135.45,46.99 C2517.1 135.47,46.91 135.15,46.59 135.15,44.67 136.08,43.73 Y2500.1
CH334_XO: length 1.5
  BOTTOM w0.1: U2503.11 134.95,48.8 R2505.2
CHANNEL1_INM: length 33.4
  TOP w0.1: v1(27.13,123.55) 27.65,124.09 27.65,124.64 27.12,125.17 J3501.3
  L3 w0.1: v1(47.52,113.42) 47.52,113.43 47.05,113.9 27.88,113.9 27.64,114.14 27.64,114.44 v2(27.48,114.61) ; v1(27.13,123.55) 27.13,123.55 27.46,123.22 v2(27.46,123.22)
  L6 w0.1: v2(27.48,114.61) 27.65,114.78 27.65,120.95 arc(27.59,121.09) 27.45,121.15 27.39,121.15 arc(27.19,121.35) 27.39,121.55 27.45,121.55 arc(27.65,121.75) 27.45,121.95 27.4,121.95 arc(27.2,122.15) 27.4,122.35 27.45,122.35 arc(27.59,122.41) 27.65,122.55 27.65,123.03 v2(27.46,123.22)
CHANNEL1_INP: length 34.9
  TOP w0.1: U3501.6 v1(50.35,114) ; v1(28.37,123.57) 27.85,124.08 27.85,124.65 28.37,125.17 J3501.2
  L3 w0.1: v2(28.02,114.61) 27.84,114.43 27.84,114.22 27.96,114.1 47.13,114.1 47.51,113.73 50.08,113.73 v1(50.35,114) ; v2(28.02,123.22) v1(28.37,123.57)
  L6 w0.1: v2(28.02,123.22) 27.85,123.05 27.85,114.78 v2(28.02,114.61)
CHANNEL2_INM: length 37.1
  TOP w0.1: J3501.5 24.62,125.15 25.15,124.63 25.15,124.09 v1(24.63,123.55) ; R3531.2 v1(47.52,112.36)
  L3 w0.1: v1(24.63,123.55) 24.63,123.55 24.96,123.22 v2(24.96,123.22) ; v1(47.52,112.36) 46.67,113.22 37.75,113.22 36.88,112.35 25.77,112.35 25.17,112.94 25.17,113.3 v2(24.98,113.48)
  L6 w0.1: v2(24.98,113.48) 25.15,113.64 25.15,121.32 arc(25.09,121.46) 24.95,121.52 arc(24.8,121.58) 24.75,121.72 24.75,121.72 arc(24.8,121.86) 24.95,121.92 arc(25.09,121.98) 25.15,122.12 25.15,123.04 v2(24.96,123.22)
CHANNEL2_INP: length 38.4
  TOP w0.1: J3501.4 25.87,125.19 25.35,124.66 25.35,124.08 v1(25.87,123.57)
  L3 w0.1: v2(25.52,123.22) v1(25.87,123.57) ; v2(25.54,113.48) 25.37,113.32 25.37,113.02 25.85,112.55 36.79,112.55 37.66,113.42 46.75,113.42 47.14,113.03 47.14,113.03 47.37,112.8 49.64,112.8 v1(49.7,112.87)
  L6 w0.1: v2(25.52,123.22) 25.35,123.05 25.35,122.61 25.35,122.41 25.35,122.41 25.35,113.67 v2(25.54,113.48)
CHANNEL3_INM: length 16.4
  TOP w0.1: v1(45.57,123.54) 46.08,124.07 46.08,124.61 45.56,125.13 J3500.3
  L3 w0.1: v1(45.57,123.54) 45.57,123.54 v2(45.91,123.2) ; v2(45.84,112.59) 46.01,112.42 46.01,112.06 46.6,111.48 47.41,111.48 v1(47.52,111.37)
  L6 w0.1: v2(45.91,123.2) 46.07,123.05 46.07,122.49 arc(46.01,122.35) 45.87,122.29 45.84,122.29 arc(45.64,122.09) 45.84,121.89 45.87,121.89 arc(46.01,121.83) 46.07,121.69 46.07,114.35 46.03,114.31 46.03,112.78 v2(45.84,112.59)
CHANNEL3_INP: length 17.8
  TOP w0.1: v1(46.82,123.56) 46.28,124.08 46.28,124.6 46.81,125.13 J3500.2 ; U3501.10 v1(49.7,111.87)
  L3 w0.1: v2(46.47,123.21) v1(46.82,123.56) ; v2(46.39,112.59) 46.39,112.59 46.21,112.41 46.21,112.15 46.68,111.68 49.52,111.68 v1(49.7,111.87)
  L6 w0.1: v2(46.47,123.21) 46.27,123.01 46.27,114.26 46.23,114.23 46.23,112.74 v2(46.39,112.59)
CHANNEL4_INM: length 18.9
  TOP w0.1: R3537.2 47.54,110.31 v1(47.54,110.39) ; J3500.5 43.06,125.12 43.58,124.59 43.58,124.1 v1(43.05,123.55)
  L3 w0.1: v2(44.48,111.41) 44.68,111.21 44.68,110.88 45.06,110.5 47.42,110.5 v1(47.54,110.39) ; v2(43.39,123.22) 43.39,123.22 43.05,123.55 v1(43.05,123.55)
  L6 w0.1: v2(43.39,123.22) 43.56,123.05 43.56,121.21 44.67,120.1 44.67,111.6 v2(44.48,111.41)
CHANNEL4_INP: length 21.4
  TOP w0.1: v1(44.3,123.57) 43.78,124.07 43.78,124.58 44.31,125.11 J3500.4
  L3 w0.1: v2(43.95,123.22) v1(44.3,123.57) ; v2(45.06,111.41) 44.88,111.22 44.88,110.96 45.11,110.73 49.57,110.73 v1(49.7,110.87)
  L6 w0.1: v2(45.06,111.41) 44.87,111.6 44.87,120.18 43.76,121.29 43.76,121.71 arc(43.81,121.86) 43.96,121.91 44.11,121.91 arc(44.31,122.11) 44.11,122.31 43.96,122.31 arc(43.81,122.37) 43.76,122.51 43.76,123.03 v2(43.95,123.22)
CHANNEL7_INM: length 15.4
  TOP w0.3: C3504.2 TP3501.1 84,104.9 84,104.24 84.54,103.7 89.09,103.7 90.25,102.54 U3500.11
CHANNEL7_INP: length 15.5
  TOP w0.3: C3502.2 TP3500.1 84.5,104.9 84.5,104.45 84.75,104.2 89.3,104.2 90.75,102.75 U3500.10
CHANNEL8_INM: length 23.4
  TOP w0.3: U3500.13 89.1,97.65 88.35,98.4 76.4,98.4 75.65,99.15 75.65,104.95 TP3503.1 C3511.2
CHANNEL8_INP: length 22.8
  TOP w0.3: C3509.2 TP3502.1 76.15,104.95 76.15,99.36 76.61,98.9 88.6,98.9 89.75,97.75 U3500.12
CLKREQ: length 2.6
  TOP w0.1: U1500.12 R1509.2 R1510.2
CSI0_A0_CLK_M: length 45.7
  L3 w0.057: v1(49.36,58.34) v2(49.71,58.34)
  L6 w0.057: v3(46.8,97.45) 46.56,97.45 44.37,95.26 arc(44.35,95.24) 44.35,95.21 44.35,78.32 arc(44.35,78.3) 44.37,78.27 47.81,74.83 arc(48.1,74.4) 48.2,73.89 48.2,69.04 arc(48.28,68.64) 48.51,68.3 49.09,67.71 arc(49.38,67.52) 49.71,67.45 arc(50.01,67.39) 50.26,67.22 50.96,66.52 arc(51.09,66.32) 51.14,66.07 51.14,58.4 arc(50.96,57.96) 50.53,57.78 50.18,57.78 arc(50.09,57.8) 50.01,57.85 49.93,57.92 arc(49.92,57.95) 49.91,57.97 49.91,58.14 v2(49.71,58.34)
CSI0_A1_LN1_P: length 45.7
  L3 w0.057: v1(50.63,63.42) v2(50.28,63.42)
  L6 w0.057: v3(45.03,99.22) 45.03,98.99 42.86,96.82 42.86,75.94 46.65,72.15 46.65,64.92 arc(46.74,64.7) 46.96,64.61 48.21,64.61 arc(48.35,64.47) 48.21,64.33 46.96,64.33 arc(46.74,64.24) 46.65,64.02 46.65,63.75 47.6,62.8 49.88,62.8 50.08,63 50.08,63.22 v2(50.28,63.42)
CSI0_A2_LN2_M: length 45.7
  L3 w0.057: v1(49.36,65.96) v2(49.71,65.96)
  L6 w0.057: v3(46.09,98.16) 45.85,98.16 43.68,95.99 43.68,78.25 arc(43.73,78) 43.87,77.8 44.49,77.17 arc(44.58,76.96) 44.49,76.74 44.03,76.27 arc(44.03,76.07) 44.23,76.07 44.69,76.53 arc(44.91,76.63) 45.13,76.53 45.13,76.53 arc(45.22,76.32) 45.13,76.1 44.67,75.64 arc(44.67,75.43) 44.87,75.43 45.33,75.9 arc(45.55,75.99) 45.77,75.9 45.77,75.89 arc(45.86,75.68) 45.77,75.46 45.31,75 arc(45.31,74.79) 45.51,74.79 45.97,75.26 arc(46.19,75.35) 46.41,75.26 arc(46.5,75.04) 46.41,74.82 45.95,74.36 arc(45.95,74.15) 46.15,74.15 46.61,74.62 arc(46.83,74.71) 47.05,74.62 47.28,74.38 arc(47.43,74.16) 47.48,73.91 47.48,66.95 arc(47.53,66.71) 47.67,66.5 48.43,65.73 arc(48.64,65.6) 48.88,65.55 48.9,65.55 arc(48.98,65.58) 49.01,65.66 49.01,65.88 arc(49.13,65.99) 49.24,65.88 49.24,65.66 arc(49.27,65.58) 49.35,65.55 49.8,65.55 arc(49.83,65.55) 49.85,65.57 49.91,65.63 49.91,65.76 v2(49.71,65.96)
CSI0_B0_LN0_P: length 45.7
  L3 w0.057: v1(50.63,60.88) v2(50.28,60.88)
  L6 w0.057: v2(50.28,60.88) 50.08,60.68 50.08,60.47 49.9,60.29 arc(49.88,60.28) 49.85,60.27 49.27,60.27 arc(48.97,60.33) 48.71,60.51 46.23,62.98 arc(46.06,63.24) 46,63.55 46,71.89 42.21,75.68 42.21,99 43.61,100.41 v3(43.61,100.64)
CSI0_B1_LN1_M: length 45.7
  L3 w0.057: v1(49.36,63.42) v2(49.71,63.42)
  L6 w0.057: v2(49.71,63.42) 49.91,63.22 49.91,63.07 49.81,62.97 49.36,62.97 arc(49.28,63) 49.24,63.08 49.24,63.3 arc(49.13,63.41) 49.02,63.3 49.02,63.08 arc(48.98,63) 48.9,62.97 47.67,62.97 46.82,63.82 46.82,64.02 arc(46.86,64.12) 46.96,64.16 48.21,64.16 arc(48.52,64.47) 48.21,64.78 46.96,64.78 arc(46.86,64.82) 46.82,64.92 46.82,72.22 43.02,76.01 43.02,96.75 45.15,98.87 v3(45.38,98.87)
CSI0_B2_LN3_P: length 45.8
  L3 w0.057: v2(50.28,68.5) v1(50.63,68.5)
  L6 w0.057: v2(50.28,68.5) 50.08,68.3 50.08,68.19 50.14,68.13 50.56,68.13 50.78,68.35 50.78,68.65 50.3,69.13 arc(50.22,69.17) 50.14,69.13 50.07,69.06 arc(49.9,69.06) 49.9,69.22 49.98,69.29 arc(50.01,69.37) 49.98,69.45 48.73,70.7 48.73,74.73 arc(48.69,74.92) 48.58,75.09 48.44,75.22 arc(48.35,75.44) 48.44,75.66 48.73,75.95 arc(48.73,76.15) 48.53,76.15 48.24,75.86 arc(48.02,75.77) 47.8,75.86 47.8,75.86 arc(47.71,76.08) 47.8,76.3 48.09,76.58 arc(48.09,76.79) 47.89,76.79 47.6,76.5 arc(47.38,76.41) 47.16,76.5 arc(47.07,76.72) 47.16,76.94 47.45,77.22 arc(47.45,77.43) 47.25,77.43 46.96,77.14 arc(46.74,77.05) 46.52,77.14 arc(46.43,77.36) 46.52,77.58 46.81,77.86 arc(46.81,78.07) 46.61,78.07 46.32,77.78 arc(46.1,77.69) 45.88,77.78 arc(45.79,78) 45.88,78.22 46.17,78.5 arc(46.17,78.71) 45.97,78.71 45.68,78.42 arc(45.58,78.35) 45.46,78.33 45.36,78.33 arc(45.27,78.35) 45.19,78.4 44.91,78.68 arc(44.86,78.76) 44.84,78.85 44.84,80.9 arc(44.97,81.2) 45.27,81.32 46.15,81.32 arc(46.29,81.47) 46.15,81.61 45.15,81.61 arc(44.84,81.92) 45.15,82.23 46.15,82.23 arc(46.29,82.37) 46.15,82.51 45.15,82.51 arc(44.93,82.6) 44.84,82.82 44.84,94.56 47.15,96.87 v3(47.15,97.1)
CSI0_C0_LN0_M: length 45.7
  L3 w0.057: v1(49.36,60.88) v2(49.71,60.88)
  L6 w0.057: v3(43.97,100.28) 43.72,100.28 42.37,98.94 42.37,75.75 46.16,71.96 46.16,63.55 arc(46.21,63.31) 46.35,63.1 48.26,61.19 arc(48.36,61.15) 48.46,61.19 48.59,61.32 arc(48.79,61.32) 48.79,61.11 48.67,60.99 arc(48.62,60.89) 48.67,60.79 48.82,60.63 arc(49.03,60.49) 49.27,60.44 49.81,60.44 49.91,60.54 49.91,60.68 v2(49.71,60.88)
CSI0_C1_LN2_P: length 45.7
  L3 w0.057: v1(50.63,65.96) v2(50.28,65.96)
  L6 w0.057: v3(45.74,98.52) 45.74,98.28 43.52,96.06 43.52,78.25 arc(43.58,77.94) 43.75,77.68 44.37,77.06 arc(44.41,76.96) 44.37,76.85 43.91,76.39 arc(43.91,75.96) 44.35,75.96 44.81,76.42 arc(44.91,76.46) 45.01,76.42 45.01,76.42 arc(45.05,76.32) 45.01,76.22 44.55,75.75 arc(44.55,75.32) 44.99,75.32 45.45,75.78 arc(45.55,75.82) 45.65,75.78 45.65,75.78 arc(45.69,75.68) 45.65,75.58 45.19,75.11 arc(45.19,74.68) 45.63,74.68 46.09,75.14 arc(46.19,75.18) 46.29,75.14 arc(46.33,75.04) 46.29,74.94 45.83,74.47 arc(45.83,74.04) 46.27,74.04 46.73,74.5 arc(46.83,74.54) 46.93,74.5 47.17,74.26 arc(47.28,74.1) 47.31,73.91 47.31,66.95 arc(47.37,66.64) 47.55,66.38 48.31,65.62 arc(48.58,65.44) 48.88,65.38 49.87,65.38 arc(49.9,65.39) 49.92,65.4 50.08,65.56 50.08,65.76 v2(50.28,65.96)
CSI0_C2_LN3_M: length 45.7
  L3 w0.057: v1(49.36,68.5) v2(49.71,68.5)
  L6 w0.057: v2(49.71,68.5) 49.92,68.3 49.92,68.12 50.07,67.96 50.63,67.96 50.94,68.28 50.94,68.72 48.89,70.77 48.89,74.73 arc(48.84,74.99) 48.7,75.2 48.56,75.34 arc(48.52,75.44) 48.56,75.54 48.84,75.83 arc(48.84,76.27) 48.41,76.27 48.12,75.98 arc(48.02,75.94) 47.92,75.98 47.92,75.98 arc(47.88,76.08) 47.92,76.18 48.21,76.47 arc(48.21,76.9) 47.77,76.9 47.48,76.62 arc(47.38,76.58) 47.28,76.62 arc(47.24,76.72) 47.28,76.82 47.57,77.11 arc(47.57,77.54) 47.13,77.54 46.84,77.26 arc(46.74,77.22) 46.64,77.26 arc(46.6,77.36) 46.64,77.46 46.93,77.75 arc(46.93,78.18) 46.49,78.18 46.2,77.9 arc(46.1,77.86) 46,77.9 arc(45.96,78) 46,78.1 46.29,78.39 arc(46.29,78.82) 45.85,78.82 45.56,78.54 arc(45.52,78.51) 45.46,78.5 45.36,78.5 arc(45.33,78.5) 45.31,78.52 45.03,78.8 arc(45.01,78.82) 45.01,78.85 45.01,80.9 arc(45.08,81.08) 45.27,81.16 46.15,81.16 arc(46.45,81.47) 46.15,81.78 45.15,81.78 arc(45.01,81.92) 45.15,82.06 46.15,82.06 arc(46.46,82.37) 46.15,82.68 45.15,82.68 arc(45.05,82.72) 45.01,82.82 45.01,94.25 arc(45.05,94.47) 45.18,94.66 47.27,96.75 v3(47.5,96.75)
CSI0_NC_CLK_P: length 45.7
  L3 w0.057: v1(50.63,58.34) v2(50.28,58.34)
  L6 w0.057: v3(46.44,97.81) 46.44,97.57 44.25,95.38 arc(44.2,95.3) 44.18,95.21 44.18,78.32 arc(44.2,78.23) 44.25,78.16 47.69,74.72 arc(47.94,74.34) 48.03,73.89 48.03,69.04 arc(48.13,68.57) 48.39,68.18 48.98,67.59 arc(49.31,67.37) 49.71,67.28 arc(49.94,67.24) 50.14,67.1 50.84,66.4 arc(50.94,66.25) 50.98,66.07 50.98,59.15 arc(50.94,59.07) 50.86,59.04 50.77,59.04 arc(50.66,58.93) 50.77,58.81 50.86,58.81 arc(50.94,58.78) 50.98,58.7 50.98,58.4 arc(50.94,58.22) 50.84,58.08 arc(50.7,57.98) 50.53,57.95 50.18,57.95 arc(50.15,57.95) 50.13,57.97 50.1,57.99 arc(50.09,58.02) 50.08,58.04 50.08,58.14 v2(50.28,58.34)
CSI1_A0_CLK_M: length 24.5
  L3 w0.057: v1(51.9,59.82) 52.37,59.82 52.46,59.73 52.46,59.63 arc(52.56,59.37) 52.81,59.27 53.42,59.27 arc(53.61,59.3) 53.76,59.41 53.96,59.61 arc(54.01,59.68) 54.03,59.77 54.03,64.47 arc(53.75,65.13) 53.09,65.41 51.08,65.41 50.71,65.05 45.07,65.05 44.88,64.86 44.42,64.86 44.31,64.98 44.31,65.08 v2(44.51,65.28)
  L6 w0.057: v2(44.51,65.28) 44.31,65.49 44.31,67.57 43.85,68.02 43.85,70.93 43.9,70.98 v3(44.13,70.98)
CSI1_A1_LN1_P: length 24.7
  L3 w0.057: v2(41.9,65.03) 42.09,64.84 42.09,64.64 42.51,64.23 43.67,64.23 arc(43.7,64.22) 43.72,64.21 43.8,64.13 arc(43.88,64.08) 43.97,64.06 51.13,64.06 arc(51.21,64.02) 51.25,63.94 51.25,63.43 arc(51.53,63.15) 51.81,63.43 51.81,64.16 arc(51.92,64.27) 52.03,64.16 52.03,63.45 arc(52.33,63.15) 52.62,63.45 52.62,63.61 arc(52.66,63.69) 52.74,63.72 53.03,63.72 arc(53.31,64) 53.03,64.28 52.71,64.28 arc(52.65,64.31) 52.62,64.37 52.62,64.63 52.68,64.69 v1(53.17,64.69)
  L6 w0.057: v3(42.35,72.75) 42.35,72.52 42.09,72.27 42.09,65.23 v2(41.9,65.03)
CSI1_A2_LN2_M: length 24.7
  L3 w0.057: v2(43.42,67.23) 43.21,67.03 43.21,66.67 42.99,66.44 41.04,66.44 arc(40.85,66.25) 41.04,66.06 43.74,66.06 arc(43.82,66.09) 43.86,66.17 43.86,66.39 arc(43.97,66.51) 44.08,66.39 44.08,66.17 arc(44.12,66.09) 44.2,66.06 48.48,66.06 49.18,66.76 51.06,66.76 arc(51.26,66.68) 51.35,66.48 51.35,66.11 arc(51.46,66) 51.57,66.11 51.57,66.64 arc(51.87,66.94) 52.17,66.64 52.17,66.12 arc(52.17,66.09) 52.18,66.07 arc(52.35,66) 52.46,66.15 52.46,67.17 52.4,67.23 v1(51.9,67.23)
  L6 w0.057: v3(43.58,71.89) 43.38,71.89 43.2,71.71 43.2,67.45 v2(43.42,67.23)
CSI1_B0_LN0_P: length 24.7
  L3 w0.057: v2(40.88,63.29) 41.08,63.49 41.08,63.57 arc(41.16,63.76) 41.35,63.84 41.65,63.84 arc(41.75,63.83) 41.82,63.77 42.01,63.58 arc(42.07,63.53) 42.14,63.5 arc(42.15,63.49) 42.16,63.49 arc(42.23,63.47) 42.31,63.46 42.65,63.46 arc(42.89,63.41) 43.1,63.27 43.51,62.86 arc(43.71,62.73) 43.96,62.68 44.41,62.68 arc(44.42,62.68) 44.43,62.69 44.43,62.76 arc(44.71,63.04) 44.99,62.76 arc(45.01,62.7) 45.07,62.68 52.34,62.68 arc(52.4,62.66) 52.46,62.63 52.62,62.46 52.62,62.2 52.68,62.15 v1(52.96,62.15)
  L6 w0.057: v3(41,74.23) 41,73.99 41.07,73.93 41.07,63.48 v2(40.88,63.29)
CSI1_B1_LN1_M: length 24.7
  L3 w0.057: v2(42.45,65.03) 42.26,64.84 42.26,64.71 42.57,64.4 42.75,64.4 arc(42.83,64.43) 42.86,64.51 42.86,64.72 arc(42.97,64.84) 43.09,64.72 43.09,64.51 arc(43.12,64.43) 43.2,64.4 43.67,64.4 arc(43.76,64.38) 43.84,64.33 43.92,64.25 arc(43.95,64.23) 43.97,64.22 51.13,64.22 arc(51.33,64.14) 51.41,63.94 51.41,63.43 arc(51.53,63.32) 51.64,63.43 51.64,64.16 arc(51.92,64.43) 52.2,64.16 52.2,63.45 arc(52.33,63.32) 52.46,63.45 52.46,63.61 arc(52.54,63.8) 52.74,63.89 53.03,63.89 arc(53.14,64) 53.03,64.12 52.71,64.12 arc(52.53,64.19) 52.46,64.37 52.46,64.63 52.4,64.69 v1(51.9,64.69)
  L6 w0.057: v3(42.7,72.4) 42.46,72.4 42.26,72.2 42.26,65.22 v2(42.45,65.03)
CSI1_B2_LN3_P: length 24.5
  L3 w0.057: v2(44.56,68.22) 44.75,68.03 44.75,68.03 arc(44.75,68.02) 44.75,68 44.75,66.9 arc(44.77,66.79) 44.83,66.7 44.94,66.59 arc(45.02,66.54) 45.11,66.52 48.21,66.52 49.1,67.41 50.69,67.41 51.15,67.88 54.86,67.88 arc(55.15,68.18) 54.86,68.48 54.53,68.48 arc(54.45,68.51) 54.41,68.59 54.41,68.95 arc(54.13,69.23) 53.85,68.95 53.85,68.59 arc(53.74,68.48) 53.62,68.59 53.62,68.96 arc(53.34,69.25) 53.06,68.96 53.06,68.59 arc(53.03,68.51) 52.95,68.48 51.57,68.48 arc(51.46,68.59) 51.57,68.7 52.34,68.7 arc(52.54,68.79) 52.62,68.98 52.62,69.56 52.68,69.62 53.12,69.62 v1(53.18,69.56)
  L6 w0.057: v2(44.56,68.22) 44.72,68.38 44.73,68.4 44.74,68.42 44.74,68.43 44.74,68.62 44.42,68.94 44.42,70.3 44.67,70.56 v3(44.67,70.82)
CSI1_C0_LN0_M: length 24.6
  L3 w0.057: v2(41.44,63.29) 41.24,63.49 41.24,63.57 arc(41.27,63.65) 41.35,63.68 41.65,63.68 arc(41.68,63.67) 41.71,63.66 41.95,63.41 arc(42.01,63.37) 42.07,63.35 arc(42.08,63.34) 42.1,63.33 arc(42.2,63.3) 42.31,63.29 42.65,63.29 arc(42.83,63.26) 42.98,63.16 43.39,62.75 arc(43.65,62.57) 43.96,62.51 44.41,62.51 arc(44.54,62.56) 44.59,62.69 44.59,62.76 arc(44.71,62.87) 44.82,62.76 arc(44.89,62.58) 45.07,62.51 51.14,62.51 arc(51.23,62.48) 51.26,62.4 51.26,62.14 arc(51.37,62.03) 51.49,62.14 51.49,62.4 arc(51.52,62.48) 51.6,62.51 52.34,62.51 52.46,62.39 52.46,62.2 52.4,62.15 v1(52.12,62.15)
  L6 w0.057: v2(41.44,63.29) 41.23,63.5 41.23,73.75 v3(41.36,73.88)
CSI1_C1_LN2_P: length 24.7
  L3 w0.057: v2(42.84,67.23) 43.05,67.03 43.05,66.74 42.92,66.61 41.04,66.61 arc(40.69,66.25) 41.04,65.89 48.55,65.89 49.25,66.59 51.06,66.59 arc(51.15,66.56) 51.18,66.48 51.18,66.11 arc(51.46,65.83) 51.74,66.11 51.74,66.64 arc(51.87,66.77) 52,66.64 52,66.12 arc(52.01,66.05) 52.04,65.98 arc(52.39,65.84) 52.62,66.15 52.62,67.17 52.68,67.23 v1(53.17,67.23)
  L6 w0.057: v3(43.23,72.25) 43.23,71.98 43.04,71.78 43.04,67.43 v2(42.84,67.23)
CSI1_C2_LN3_M: length 24.5
  L3 w0.057: v1(51.91,69.56) 51.97,69.62 52.39,69.62 52.46,69.55 52.46,68.98 arc(52.42,68.9) 52.34,68.87 51.57,68.87 arc(51.29,68.59) 51.57,68.31 52.95,68.31 arc(53.15,68.39) 53.23,68.59 53.23,68.96 arc(53.34,69.08) 53.46,68.96 53.46,68.59 arc(53.74,68.31) 54.02,68.59 54.02,68.95 arc(54.13,69.06) 54.25,68.95 54.25,68.59 arc(54.33,68.39) 54.53,68.31 54.86,68.31 arc(54.99,68.18) 54.86,68.04 51.08,68.04 50.62,67.58 49.03,67.58 48.14,66.69 45.8,66.69 arc(45.72,66.72) 45.69,66.8 45.69,67.02 arc(45.57,67.14) 45.46,67.02 45.46,66.8 arc(45.43,66.72) 45.34,66.69 45.11,66.69 arc(45.08,66.69) 45.06,66.71 44.95,66.82 arc(44.92,66.86) 44.91,66.9 44.91,66.9 44.91,68 44.92,68.04 arc(44.93,68.04) 44.93,68.05 v2(45.1,68.22)
  L6 w0.057: v2(45.1,68.22) 44.91,68.41 44.91,68.69 44.58,69.01 44.58,70.23 44.82,70.47 v3(45.03,70.47)
CSI1_NC_CLK_P: length 24.6
  L3 w0.057: v1(53.17,59.82) 52.73,59.82 52.62,59.71 52.62,59.63 arc(52.68,59.49) 52.81,59.43 53.42,59.43 arc(53.54,59.46) 53.65,59.53 53.84,59.72 arc(53.86,59.75) 53.86,59.77 53.86,59.97 arc(53.83,60.05) 53.75,60.09 53.66,60.09 arc(53.55,60.2) 53.66,60.31 53.75,60.31 arc(53.83,60.35) 53.86,60.43 53.86,64.47 arc(53.64,65.02) 53.09,65.24 51.14,65.24 50.78,64.88 45.14,64.88 44.95,64.7 44.35,64.7 44.14,64.91 44.14,65 44.14,65.08 v2(43.94,65.28)
  L6 w0.057: v3(43.77,71.33) 43.77,71.1 43.69,71.02 43.69,67.95 44.14,67.5 44.14,65.48 v2(43.94,65.28)
DES0_CAP_VDD_1P0: length 17.6
  L5 w0.3: v2(36.97,91.55) 36.99,91.57 36.99,100.19 v2(36.42,100.77)
  L6 w0.3: v3(36.59,90.78) 36.97,91.16 v2(36.97,91.55) ; v2(36.42,100.77) 36.42,100.62 v3(35.95,100.15)
  BOTTOM w0.2: U2900.9 38.78,93 37.85,92.07 37.85,91.79 C2917.1 ; 38.45,98.52 38.45,98.52 37.66,99.3 36.81,99.3 v3(35.95,100.15)
  BOTTOM w0.3: C2917.1 36.84,90.79 C2916.1
DES0_CCI_SCL_1P8: length 101.1
  TOP w0.1: J2700.A18 109.78,48.83 v1(109.8,48.83)
  L3 w0.1: v2(39.9,60.27) 39.92,60.24 41.04,60.24 41.52,59.76 45.21,59.76 49.86,55.11 51.56,55.11 56.29,50.39 86.6,50.39 86.62,50.41 87.07,50.41 87.21,50.27 108.33,50.27 109.78,48.82 109.78,48.83 v1(109.8,48.83)
  L6 w0.1: v2(39.9,60.27) 39.9,61.72 39.19,62.42 39.19,75.09 39.2,75.09 39.54,75.44 39.54,81.82 v3(40.21,82.49)
  BOTTOM w0.1: R2913.1 41.42,84.31 R2931.1 41.28,83.62 41.28,83.56 41.1,83.38 v3(40.21,82.49)
DES0_CCI_SDA_1P8: length 100.5
  TOP w0.1: J2700.A17 v1(109.78,48.24)
  L3 w0.1: v1(109.78,48.24) 109.74,48.28 109.74,48.54 108.2,50.07 87.13,50.07 86.99,50.21 86.7,50.21 86.68,50.19 56.2,50.19 51.51,54.88 49.81,54.88 45.13,59.56 41.35,59.56 41.05,59.86 v2(40.28,59.86)
  L6 w0.1: v2(40.28,59.86) 40.28,61.63 39.39,62.52 39.39,75.01 39.42,75.03 39.42,75.03 39.74,75.36 39.74,81.62 v3(40.28,82.16)
  BOTTOM w0.1: R2911.1 42.32,83.66 R2918.1 41.78,83.14 41.55,83.38 41.38,83.38 41.3,83.3 41.3,83.3 40.61,82.6 40.61,82.49 v3(40.28,82.16)
DES0_CFG0_1P8: length 5.1
  BOTTOM w0.1: U2900.5 40.22,91.59 40.1,91.47 40.1,89.17 39.87,88.94 R2917.1 40.11,88.69 40.11,88.56 39.19,87.64 38.97,87.64 R2922.2
DES0_CFG1_1P8: length 5
  L7 w0.25: v7(33.96,92.54) 33.96,93.05 34.6,93.69 v7(35.05,93.69)
  BOTTOM w0.2: U2900.12 37.74,94.06 37.45,93.77 36.96,93.77 36.62,94.12 35.5,94.12 R2916.1
  BOTTOM w0.25: v7(35.05,93.69) 35.06,93.69 R2916.1
DES0_ENABLE_1P8: length 134.3
  TOP w0.1: J2700.A6 110.44,34.94 v1(110.44,35.03)
  L3 w0.1: v1(110.44,35.03) 110.44,38.15 108.42,40.17 76.52,40.17 76.21,40.48 67.38,40.48 67.01,40.85 64.22,40.85 63.81,41.26 57.04,41.26 56.74,41.56 51.4,41.56 50.38,42.57 50.38,49.97 49.4,50.95 49.4,51.53 44.26,56.66 v2(42.45,56.66)
  L6 w0.1: v2(42.45,56.66) 42.45,58.32 40.5,60.27 40.5,61.72 39.73,62.49 39.7,62.52 39.7,62.53 39.62,62.6 39.62,74.88 40,75.25 40,81.14 40.59,81.74 40.59,87.97 40.98,88.35 40.98,100.26 42.85,102.13 v3(43.48,102.13)
  BOTTOM w0.1: v3(43.48,102.13) 43.48,101.21 U2900.35
DES0_ERRB_1P8: length 52.6
  L3 w0.1: v2(38.38,54.37) 38.64,54.37 38.71,54.44 40.22,54.44 40.28,54.51 44.44,54.51 47.85,51.1 47.85,50.55 48.98,49.42 48.98,43.48 v1(49.36,43.1)
  L6 w0.1: v3(38.61,85.83) 38.54,85.76 38.54,75.85 38.19,75.51 38.19,61.92 38.7,61.42 38.7,60.07 38.49,59.86 38.49,59.17 38.76,58.9 38.76,55.18 38.52,54.94 38.52,54.5 v2(38.38,54.37)
  BOTTOM w0.1: R2927.2 38.81,86.03 v3(38.61,85.83)
DES0_FRAME_SYNC_1P8: length 54.1
  TOP w0.1: v1(49.38,41.99) 49.38,41.84 J2600.D23
  L3 w0.1: v2(39.27,54.06) 39.29,54.06 39.47,54.24 40.3,54.24 40.37,54.31 44.36,54.31 47.65,51.02 47.65,50.46 48.78,49.33 48.78,42.59 v1(49.38,41.99)
  L6 w0.1: v2(39.27,54.06) 39.27,54.86 38.96,55.17 38.96,55.83 38.96,58.98 38.69,59.25 38.69,59.76 38.9,59.97 38.9,61.52 38.39,62.02 38.39,75.42 38.74,75.77 38.74,85.19 v3(39.49,85.94)
  BOTTOM w0.1: v3(39.49,85.94) 39.52,85.94 R2928.2
DES0_I2CSEL_1P8: length 1.6
  BOTTOM w0.2: U2900.33 43.07,102.21 43.07,102.22 R2929.1
DES0_LOCK_1P8: length 49
  L3 w0.1: v1(49.36,44.37) 49.18,44.55 49.18,49.5 48.05,50.63 48.05,51.18 44.52,54.71 39.73,54.71 v2(39.64,54.8)
  L6 w0.1: v2(39.64,54.8) 39.66,54.82 39.66,58.56 38.89,59.33 38.89,59.61 39.1,59.82 39.1,61.62 38.59,62.12 38.59,75.34 38.94,75.69 38.94,84.07 v3(40.1,85.23)
  BOTTOM w0.1: v3(40.1,85.23) 40.1,85.24 R2926.2
DES0_SIOA: length 40.1
  BOTTOM w0.185: C2908.2 35.3,105.42 32.75,105.42 23.5,96.17 19,96.17 17.64,94.81 16.05,94.81
  BOTTOM w0.358: D2900.1 15.98,94.89 16.05,94.81
  BOTTOM w1: 14.67,94.76 10.58,94.76 8.5,92.67 8.5,89.57 9.06,89 CON2900.2
DES0_SIOA_M: length 2.8
  BOTTOM w0.062: C2909.1 38.62,101.36 38.75,101.24 38.75,99.86 39.02,99.59 39.02,99.37 U2900.25
DES0_SIOA_P: length 2.8
  BOTTOM w0.062: U2900.26 39.38,99.71 39.16,99.71 38.93,99.94 38.93,101.32 38.75,101.49 C2908.1
DES0_SIOB: length 38.8
  BOTTOM w0.185: 16.01,93.24 17.57,93.24 19.55,95.22 24.2,95.22 30.65,101.67 31.98,101.67 C2925.2
  BOTTOM w0.358: D2901.1 15.9,93.13 16.01,93.24
  BOTTOM w1: 14.72,93.3 13.68,93.3 12.5,92.12 12.5,88.8 11.36,87.67 6.58,87.67 CON2900.4
DES0_SIOB_M: length 3
  BOTTOM w0.062: C2926.1 35.78,98.63 35.89,98.52 37.52,98.52 37.73,98.31 37.96,98.31 U2900.22
DES0_SIOB_P: length 3
  BOTTOM w0.062: U2900.21 37.61,97.94 37.61,98.16 37.44,98.33 35.82,98.33 35.65,98.5 C2925.1
DES0_SIOC: length 34.6
  BOTTOM w0.185: 15.93,84.84 16.62,84.84 17.19,84.28 26.83,84.28 C2930.2
  BOTTOM w0.358: 15.93,84.84 14.72,84.84 D2902.1
  BOTTOM w1: CON2900.3 6.52,86.27 12.04,86.27 13.65,84.66 14.61,84.66
DES0_SIOC_M: length 3
  BOTTOM w0.062: C2931.1 36.24,92.96 36.33,93.04 36.79,93.04 36.98,92.86 37.73,92.86 38.1,93.23 38.33,93.23 38.45,93.35
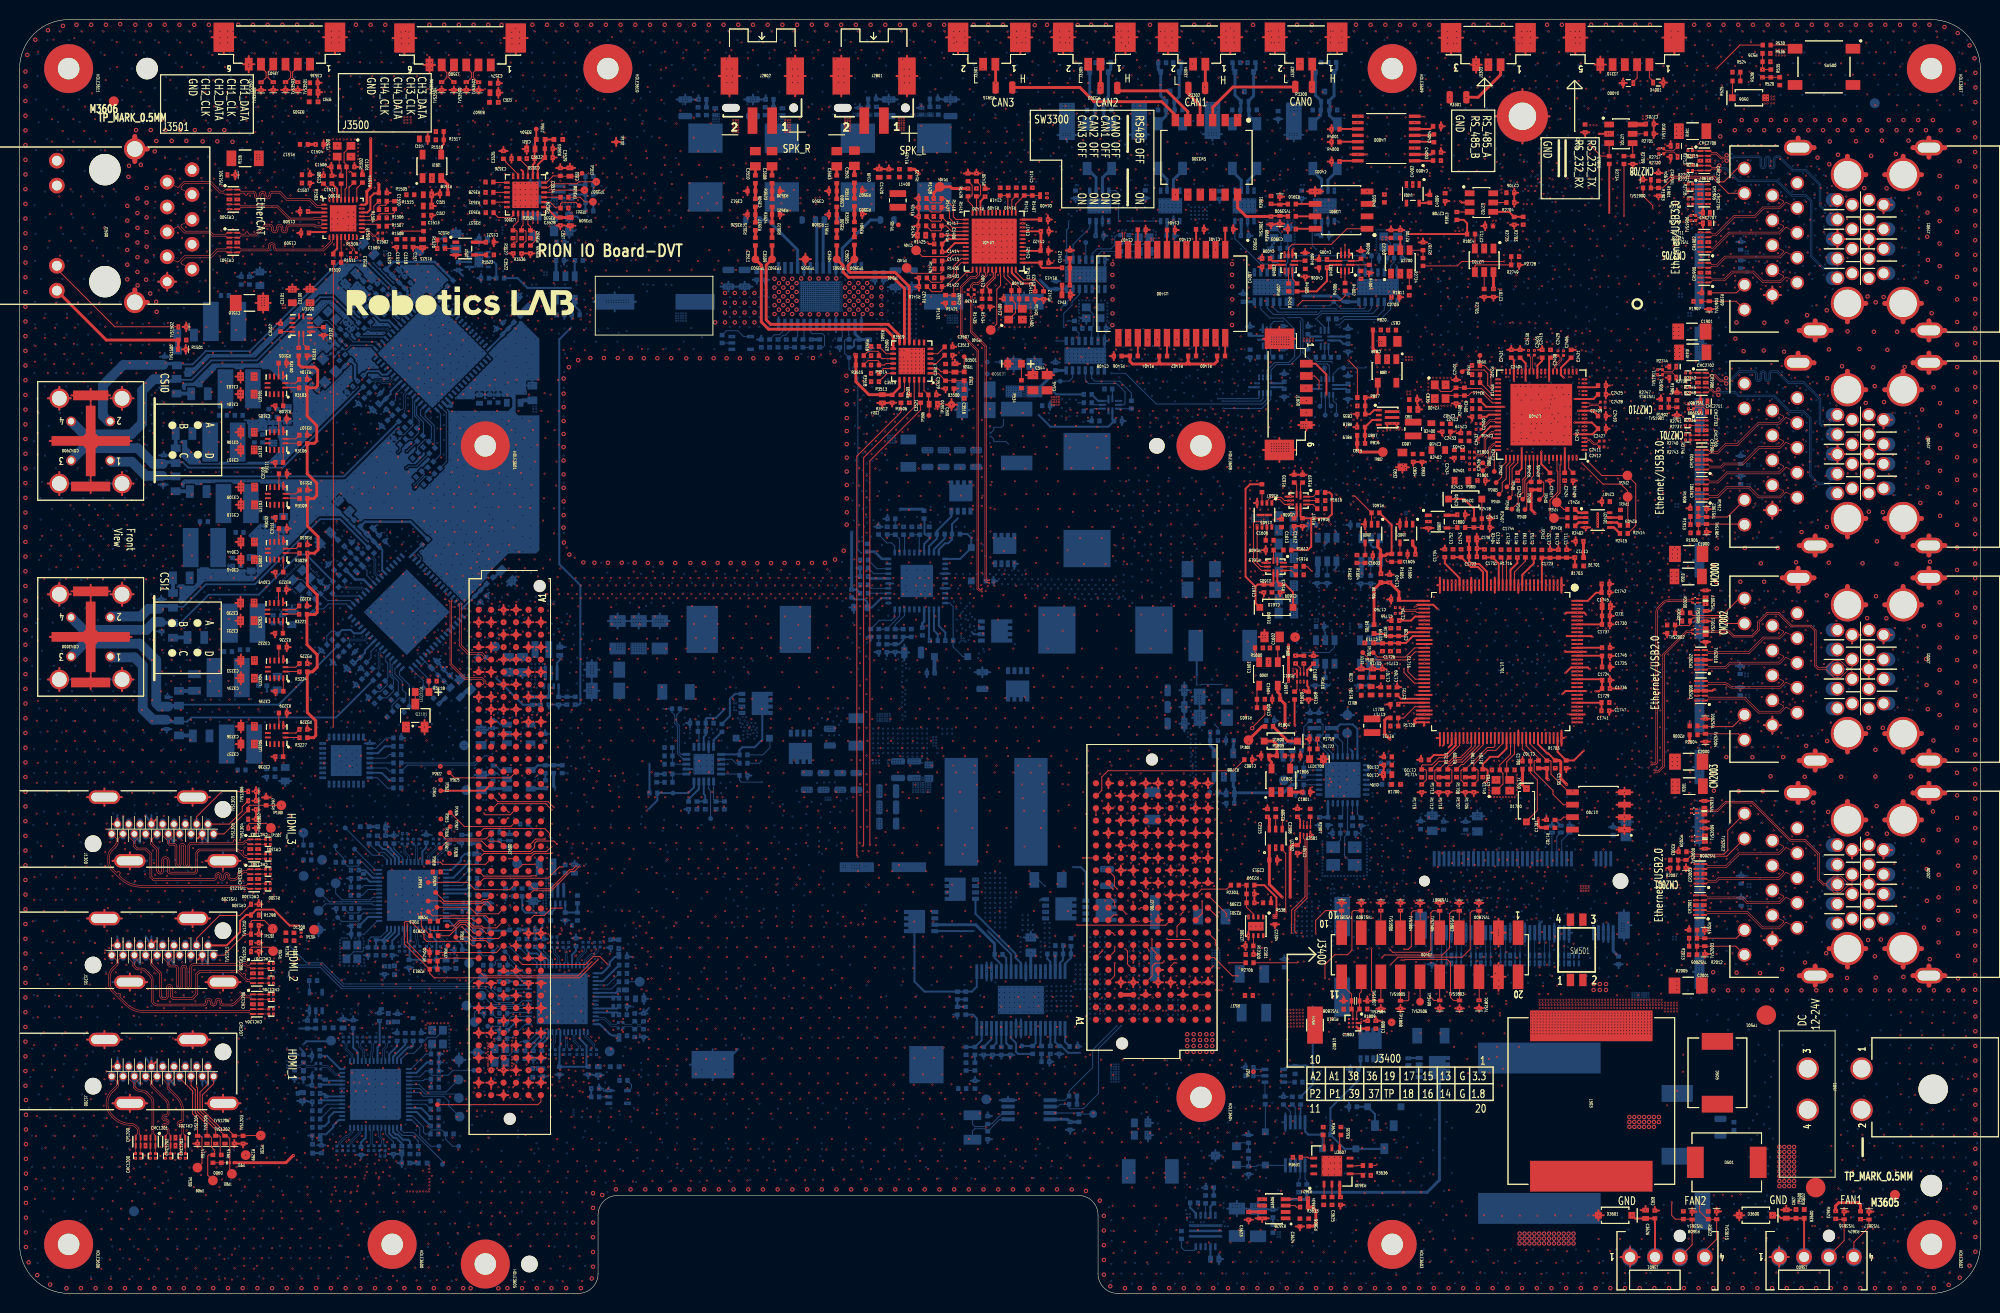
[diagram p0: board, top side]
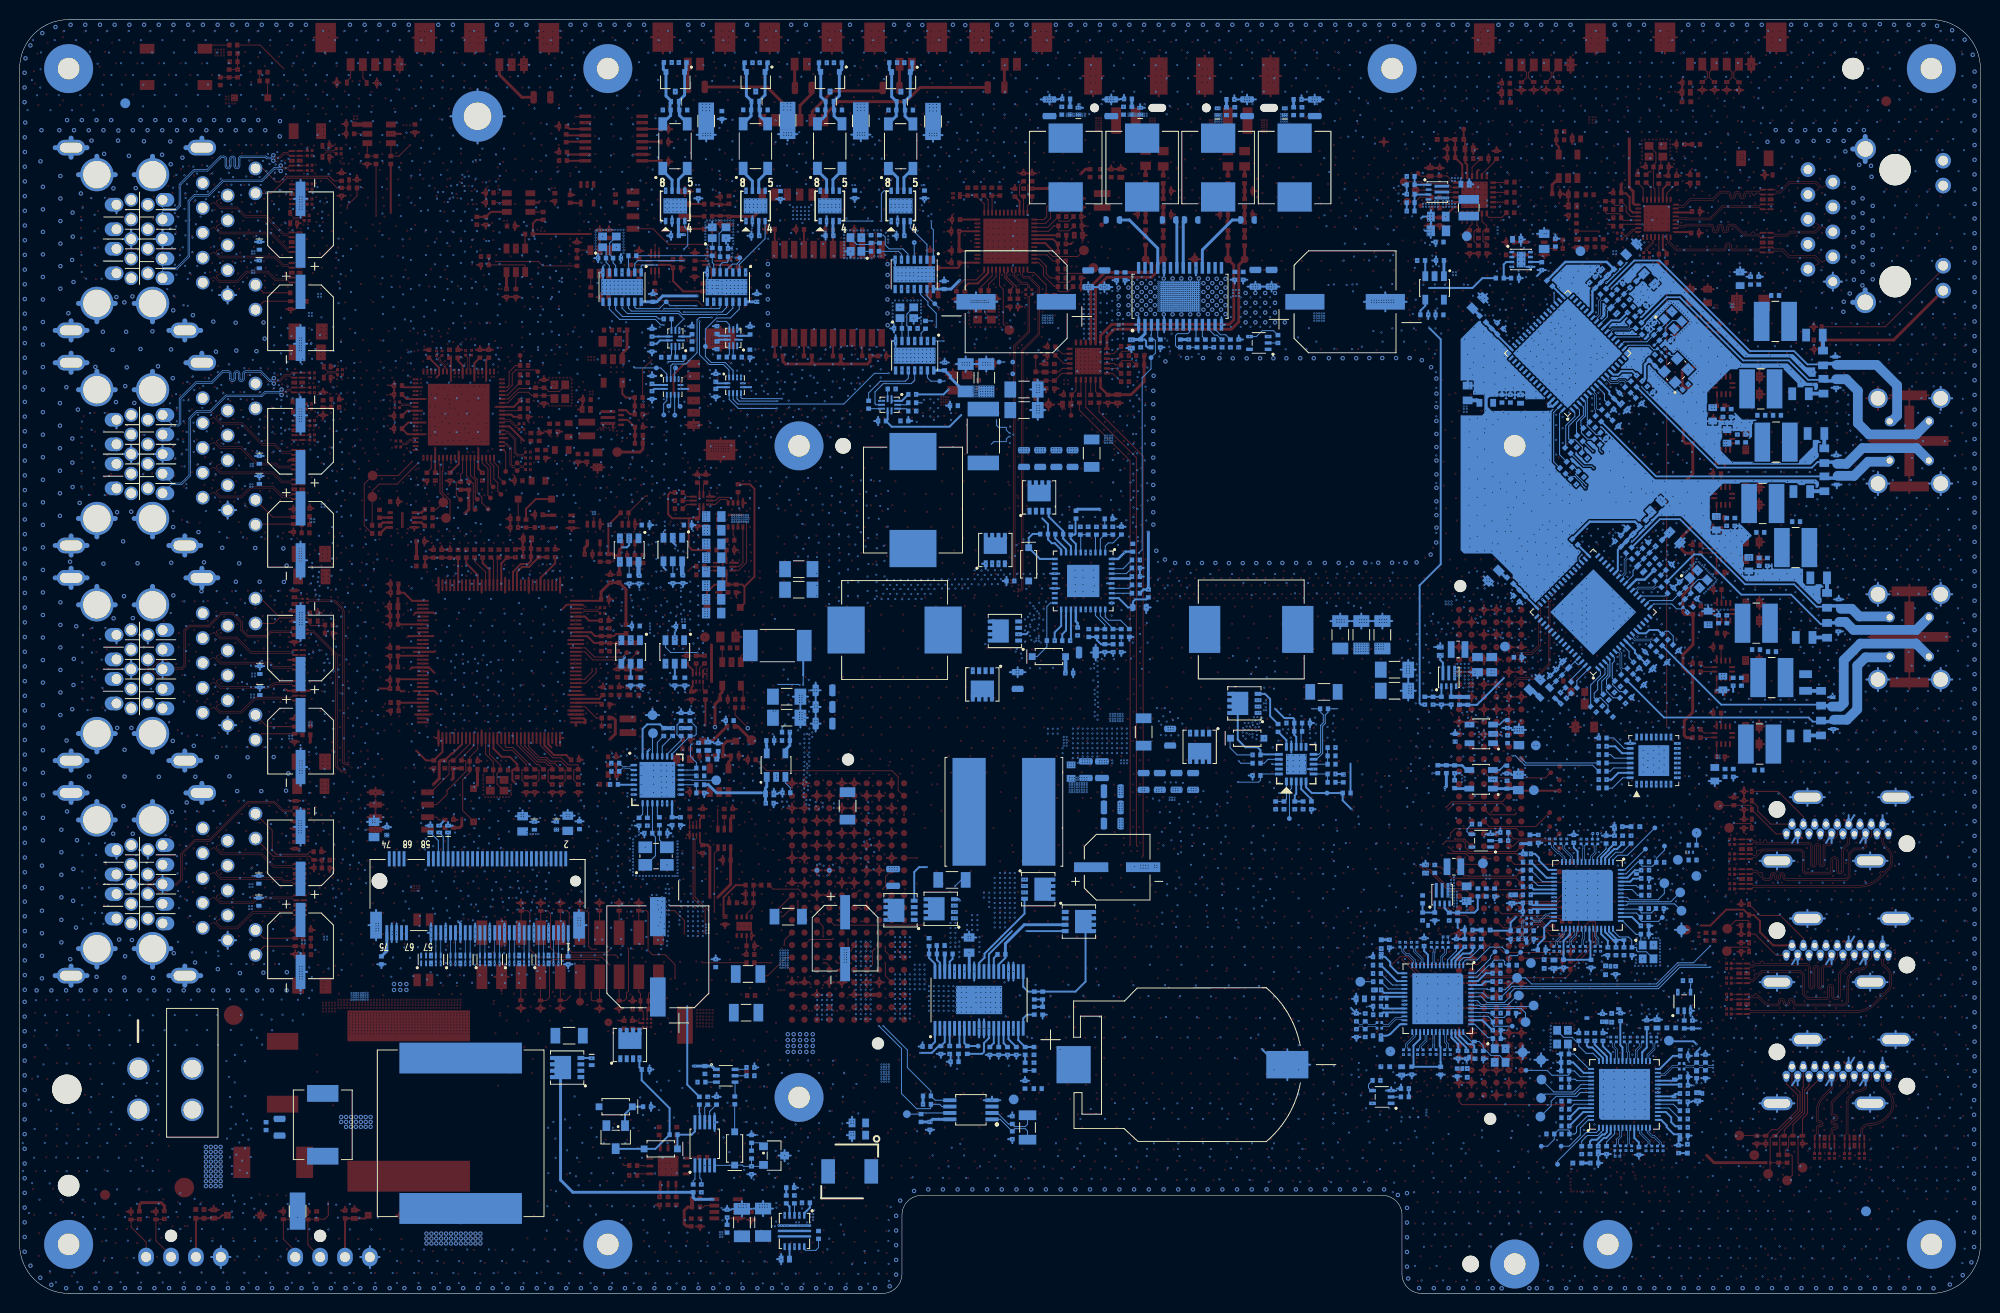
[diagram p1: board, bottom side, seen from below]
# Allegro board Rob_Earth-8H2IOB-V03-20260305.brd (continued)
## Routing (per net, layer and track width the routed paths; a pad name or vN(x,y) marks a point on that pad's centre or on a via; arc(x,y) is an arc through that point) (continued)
DES0_SIOC_P: length 3
  BOTTOM w0.062: U2900.11 37.97,93.58 37.97,93.36 37.66,93.05 37.06,93.05 36.87,93.23 36.25,93.23 36.11,93.09 C2930.1
DES0_SIOD: length 32.4
  BOTTOM w0.185: 15.91,83.28 16.02,83.38 33.08,83.38 38.68,88.99
  BOTTOM w0.358: 15.91,83.28 15.84,83.21 14.83,83.21 14.8,83.24 D2903.1
  BOTTOM w1: CON2900.1 9.37,84.88 11.45,84.88 12.89,83.44 14.56,83.44
DES0_SIOD_M: length 2.7
  BOTTOM w0.062: U2900.7 39.37,92.15 39.37,91.93 39.17,91.73 39.17,90.34 39.02,90.19 38.61,90.19
DES0_SIOD_P: length 2.8
  BOTTOM w0.062: U2900.6 39.73,91.8 39.51,91.8 39.36,91.65 39.36,90.26 39.24,90.14 39.24,89.56 C2937.1
DES0_SPARE_GPIO_1P8: length 55.4
  TOP w0.1: v1(49.37,40.56) J2600.D24
  L3 w0.1: v1(49.37,40.56) 49.35,40.56 48.48,41.43 48.05,41.43 47.69,41.79 47.69,43.49 48.58,44.38 48.58,49.25 47.45,50.38 47.45,50.93 44.27,54.11 40.45,54.11 40.19,53.85 v2(40.19,53.84)
  L6 w0.1: v2(40.19,53.84) 40.19,54.5 40.58,54.88 40.58,55.42 40.06,55.94 40.06,59.01 39.32,59.74 39.32,61.69 38.79,62.22 38.79,75.26 39.14,75.61 39.14,83.92 v3(39.45,84.22)
  BOTTOM w0.1: v3(39.45,84.22) 39.66,84.43 40.47,84.43 41.78,85.73 R2930.2
DES0_VDDIO_1P8: length 56.5
  L3 w0.25: v2(34.96,94.26) 35.01,94.3 v2(37.92,94.3)
  L5 w0.25: v2(39.71,88.78) 39.75,88.78 37.92,90.61 v2(37.92,94.3) 37.92,104.04 38.53,104.64 v2(38.53,105.59)
  L6 w0.25: v2(34.96,94.26) 34.47,93.76 v3(34.47,93.09) 33.7,93.09 31.95,91.34 30.43,91.34 29.81,91.97 v3(29.81,92.79) ; v3(38.02,103.91) 38.02,105.08 v2(38.53,105.59) ; v3(39.33,88.34) 39.33,88.37 39.57,88.61 39.57,88.63 39.72,88.78 v2(39.71,88.78)
  L7 w0.25: v7(41.2,82.56) 41.19,82.56 v7(40.43,83.32) 41.19,84.08 v7(41.19,86.37) 41.19,86.48 v7(39.93,87.75) v3(39.33,88.34)
  BOTTOM w0.25: R2918.2 41.2,82.56 v7(41.2,82.56) ; U2900.27 39.57,100.23 39.57,102.31 C2910.1 C2911.1 ; R2923.2 41.18,86.36 v7(41.19,86.37) ; 37.36,104.52 38.11,105.27 42.34,105.27 43.24,104.36 44.22,103.38 R2929.2 ; R2925.2 39.93,87.74 v7(39.93,87.75) ; R2916.2 34.21,93.39 34.21,94.78 C2934.1 33.76,95.23 C2935.1 32.6,94.08 32.23,94.08
  BOTTOM w0.3: C2911.1 38.16,103.72 38.16,103.76 v3(38.02,103.91) ; 37.36,104.52 37.39,104.52 C2942.1
DES0_X1: length 5
  BOTTOM w0.1: U2900.17 36.32,96.39 35.95,96.77 33.78,96.77 33.31,96.3 33.07,96.3 R2920.2 R2919.1 32.52,96.02 R2924.2
DES0_X2: length 5.9
  BOTTOM w0.1: Y2900.1 32.24,98.9 C2940.1 R2915.1 34.02,97.12 36.35,97.12 36.69,96.78 U2900.18
DES1_CAP_VDD_1P0: length 16.8
  L5 w0.25: v2(34.13,72.88) 34.19,72.83 34.19,66.26 34.79,65.67 v2(34.79,65.47)
  L6 w0.25: v3(33.29,73.79) 34.13,72.95 v2(34.13,72.88) ; v2(34.79,65.47) 34.02,64.7 v3(34.02,64.38)
  BOTTOM w0.2: U3000.9 35.24,65.63 35.24,65.38 C3019.1 34.23,64.38 C3018.1
  BOTTOM w0.25: v3(33.29,73.79) 34.24,72.85 35.09,72.85 35.84,72.11 U3000.23
DES1_CFG0_1P8: length 5.1
  BOTTOM w0.1: U3000.5 37.61,65.18 37.35,64.92 37.35,64.5 37.55,64.3 37.55,62.78 R3013.1 37.5,62.28 37.5,62.12 36.79,61.41 36.22,61.41 R3016.2
DES1_CFG1_1P8: length 5.5
  BOTTOM w0.1: R3012.1 32.45,67.28 32.14,67.58 31.81,67.58 31.33,67.09 31.33,66.22 R3017.2
  BOTTOM w0.2: R3012.1 32.65,67.47 32.89,67.71 33.77,67.71 34.11,67.37 34.85,67.37 35.13,67.65 U3000.12
DES1_CLK_25MHZ_1P8: length 36.1
  L5 w0.1: v2(32.38,96.79) 32.38,96.38 33.31,95.45 33.31,70.38 v2(33.54,70.14)
  L6 w0.1: v3(29.89,69.51) 32.91,69.51 v2(33.54,70.14) ; v3(32.18,96.38) 32.18,96.59 v2(32.38,96.79)
  BOTTOM w0.1: v3(29.89,69.51) 29.89,69.6 R3005.2 30.5,69.86 30.99,69.86 31.49,70.36 33.34,70.36 33.71,69.99 U3000.17
DES1_ENABLE_1P8: length 35.7
  TOP w0.1: v1(47.82,46.24) 47.91,46.15 48.88,46.15 49.36,45.67 J2600.D20
  L3 w0.1: v1(47.82,46.24) 47.55,46.51 v2(47.55,46.69)
  L6 w0.1: v3(40.64,75.39) 40.65,75.39 39.82,74.57 39.82,62.68 40.7,61.81 40.7,60.35 42.81,58.24 42.81,53.37 44.82,51.37 44.82,51.18 47.4,48.61 47.4,46.84 v2(47.55,46.69)
  BOTTOM w0.1: U3000.35 40.93,74.86 40.93,75.11 v3(40.64,75.39)
DES1_ERRB_1P8: length 22.2
  TOP w0.1: J2600.D17 49.55,49.45 v1(49.9,49.1)
  L3 w0.1: v2(36.23,55.91) 36.56,55.58 37.54,55.58 37.7,55.74 40.68,55.74 41.12,55.31 44.77,55.31 48.65,51.43 48.65,50.88 49.9,49.63 v1(49.9,49.1)
  L6 w0.1: v2(36.23,55.91) 36.2,55.94 v3(36.2,60.21)
  BOTTOM w0.1: R3027.2 v3(36.2,60.21)
DES1_FRAME_SYNC_1P8: length 23.1
  TOP w0.1: J2600.D19 49.53,46.91 v1(49.55,46.88)
  L3 w0.1: v1(49.55,46.88) 49.38,47.06 49.38,49.58 48.25,50.71 48.25,51.26 44.6,54.91 40.05,54.91 39.41,55.54 37.95,55.54 v2(37.62,55.21)
  L6 w0.1: v2(37.62,55.21) 37.62,55.47 37.76,55.61 37.76,60.42 v3(37.9,60.56)
  BOTTOM w0.1: R3028.2 37.9,60.57 v3(37.9,60.56)
DES1_I2C_SCL_1P8: length 51.1
  L3 w0.1: v2(44.94,20.92) 46.2,19.67 49.31,19.67 49.87,20.24 v1(50.66,20.24)
  L6 w0.1: v2(44.94,20.92) 44.94,21.23 45.24,21.52 45.24,27.88 45.98,28.62 45.98,31.23 48.53,33.78 48.53,46.21 47.6,47.14 47.6,48.69 45.02,51.27 45.02,51.45 43.01,53.46 43.01,58.41 42.31,59.1 42.31,60.66 v3(42.23,60.75)
  BOTTOM w0.1: v3(42.23,60.75) 41.73,61.24 R3021.2
DES1_I2C_SDA_1P8: length 51.7
  TOP w0.1: J2600.C39 50.63,21.33 v1(50.33,21.02)
  L3 w0.1: v2(45.45,21.12) 45.45,20.71 46.28,19.87 49.17,19.87 v1(50.33,21.02)
  L6 w0.1: v3(42.83,61.33) 42.51,61.01 42.51,59.19 43.21,58.49 43.21,53.54 45.22,51.53 45.22,51.35 47.8,48.77 47.8,47.22 48.73,46.29 48.73,33.65 46.2,31.12 46.2,28.56 45.45,27.81 v2(45.45,21.12)
  BOTTOM w0.1: R3019.2 42.31,61.83 R3014.1
DES1_I2CSEL_1P8: length 1.6
  BOTTOM w0.2: U3000.33 40.53,75.88 40.54,75.88 R3008.1
DES1_LOCK_1P8: length 17.4
  TOP w0.1: J2600.D16 49.17,50.72 48.9,50.99 v1(48.9,51.03)
  L3 w0.1: v2(37.4,55.94) 40.8,55.94 41.23,55.51 44.85,55.51 48.9,51.46 v1(48.9,51.03)
  L6 w0.1: v2(37.4,55.94) 37.38,55.94 37.38,56.1 37.48,56.19 37.48,58.62 37.48,58.63 v3(37.48,58.79)
  BOTTOM w0.1: v3(37.48,58.79) 37.49,58.8 R3026.2
DES1_SIOA: length 31.4
  BOTTOM w0.185: 15.65,70.08 16.71,70.08 19,72.37 24,72.37 30.65,79.02 32.68,79.02 C3008.2
  BOTTOM w0.358: 15.65,70.08 15.56,70.17 14.48,70.17 D3000.1
  BOTTOM w1: 14.24,69.87 13.12,69.87 12.34,69.09 9.34,69.09 CON3000.2
DES1_SIOA_M: length 2.8
  BOTTOM w0.062: C3009.1 36.01,74.95 36.15,74.82 36.15,73.44 36.41,73.18 36.41,72.96 U3000.25
DES1_SIOA_P: length 2.8
  BOTTOM w0.062: U3000.26 36.77,73.3 36.55,73.3 36.34,73.51 36.34,74.89 36.14,75.09 36.14,75.56
DES1_SIOB: length 31.6
  BOTTOM w0.185: C3022.2 29.21,75.42 28.5,75.42 24.4,71.32 19.3,71.32 16.3,68.32 15.64,68.32
  BOTTOM w0.358: 14.5,68.44 15.52,68.44 15.64,68.32
  BOTTOM w1: CON3000.4 6.53,67.72 12.95,67.72 13.76,68.53 14.4,68.53
DES1_SIOB_M: length 3
  BOTTOM w0.062: U3000.22 35.34,71.9 35.12,71.9 34.94,72.08 33.34,72.08 33.17,72.24 C3023.1
DES1_SIOB_P: length 3
  BOTTOM w0.062: C3022.1 33.06,72.09 33.26,71.89 34.87,71.89 35,71.76 35,71.54 U3000.21
DES1_SIOC: length 35.7
  BOTTOM w0.185: 16.25,60.09 26.44,60.09 C3030.2
  BOTTOM w0.358: D3002.1 15.24,59.98 16.15,59.98 16.25,60.09
  BOTTOM w1: CON3000.3 6.57,66.32 12.25,66.32 13.94,64.62 13.94,60.24 14.28,59.89 15.16,59.89
DES1_SIOC_M: length 2.9
  BOTTOM w0.062: C3031.1 33.63,66.56 33.66,66.59 35.25,66.59 35.49,66.83 35.73,66.83 U3000.10
DES1_SIOC_P: length 2.8
  BOTTOM w0.062: U3000.11 35.38,67.19 35.38,66.98 35.18,66.78 33.58,66.78 33.49,66.68 33.03,66.68 C3030.1
DES1_SIOD: length 33.8
  BOTTOM w0.185: 36.07,62.58 32.27,58.77 17.52,58.77 17.1,58.35 16.26,58.35
  BOTTOM w0.358: 16.26,58.35 15.06,58.35 D3003.1
  BOTTOM w1: CON3000.1 9.34,64.91 11.72,64.91 12.56,64.07 12.56,59.6 13.61,58.55 14.93,58.55
DES1_SIOD_M: length 2.8
  BOTTOM w0.062: 36,63.78 36.48,63.78 36.57,63.87 36.57,65.35 36.77,65.55 36.77,65.75 36.9,65.89
DES1_SIOD_P: length 2.8
  BOTTOM w0.062: U3000.6 37.14,65.42 36.9,65.42 36.76,65.27 36.76,63.79 36.64,63.67 C3037.1
DES1_SPARE_GPIO_1P8: length 18.5
  TOP w0.1: v1(49.86,48.53) 49.83,48.5 49.78,48.5 49.46,48.18 49.36,48.18 J2600.D18
  L3 w0.1: v1(49.86,48.53) 49.58,48.81 49.58,49.66 48.45,50.79 48.45,51.35 44.69,55.11 40.97,55.11 40.79,55.28 v2(40.18,55.28)
  L6 w0.1: v2(40.18,55.28) 39.86,55.61 39.86,58.72 v3(39.22,59.35)
  BOTTOM w0.1: v3(39.22,59.35) 39.2,59.33 R3033.2
DES1_VDDIO_1P8: length 47.9
  L3 w0.3: v2(31.61,67.33) v2(37.27,67.33)
  L5 w0.25: v2(37.09,78.21) 37.53,77.77 37.53,67.39 37.47,67.33 v2(37.27,67.33)
  L6 w0.25: v3(36.71,61.93) 36.71,61.92 v3(37.32,61.32) 37.5,61.51 37.5,67.09 v2(37.27,67.33) ; v3(35.45,77.47) 36.09,77.47 36.83,78.21 v2(37.09,78.21)
  L6 w0.3: v2(31.61,67.33) 31.86,67.33 v3(31.86,66.7)
  L7 w0.25: v3(37.32,61.32) 37.89,61.32 38.56,60.65 v7(38.56,59.95) 42.56,59.95 v7(42.79,60.18)
  BOTTOM w0.1: R3013.2 36.71,61.94 v3(36.71,61.93)
  BOTTOM w0.2: U3000.27 36.98,73.8 36.98,75.88 C3016.1
  BOTTOM w0.25: R3025.2 37.32,61.33 v3(37.32,61.32) ; R3008.2 39.85,78.76 35.23,78.76 B3002.1
  BOTTOM w0.3: R3014.2 43.36,60.74 v7(42.79,60.18) ; R3012.2 v3(31.86,66.7) ; B3002.1 34.75,78.16 C3040.1 36.1,76.81 C3017.1 36.35,76.52 C3016.1
DES1_X2: length 5.9
  BOTTOM w0.1: Y3000.1 29.63,72.49 C3032.1 30.18,71.93 30.7,71.42 R3015.1 31.29,70.83 31.41,70.71 33.74,70.71 34.08,70.37 U3000.18
DES_EN_1P8: length 80
  TOP w0.1: v4(42.91,51.29) 42.92,51.3 TP2612.1
  TOP w0.2: J2600.E15 47.41,51.3 TP2612.1
  L2 w0.2: v5(56.31,51.29) 56.25,51.35 42.97,51.35 v4(42.91,51.29)
  L3 w0.2: v5(56.31,51.29) v2(56.75,51.29)
  L6 w0.2: v3(56.67,60.08) 56.67,51.36 v2(56.75,51.29) ; v3(56.25,102.62) 55.95,102.32 55.95,98.86 v3(56.25,98.57)
  BOTTOM w0.2: R3200.1 57.07,60.09 57.2,60.22 57.2,72.27 55.05,74.42 55.05,97.37 v3(56.25,98.57) ; v3(56.25,102.62) 51.8,102.62 50.8,103.62 R3204.1
DISAUTOLOAD/GPO45: length 4.4
  TOP w0.1: U1701.76 149.27,55.98 147.25,53.97 147.05,53.97 R1708.1
EDP1_AUX_M: length 31.8
  L3 w0.05: v1(48.04,30.19) 47.69,30.19 47.55,30.06 47.55,29.82 47.32,29.59 42.9,29.59 42.58,29.91 30.81,29.91 30.59,29.69 29.84,29.69 29.68,29.85 29.68,30.05 v2(29.51,30.22)
  L6 w0.05: v3(27.26,23.02) 27.2,23.08 27.02,23.08 26.82,23.28 26.82,26.69 29.68,29.55 29.68,30.05 v2(29.51,30.22)
  BOTTOM w0.062: v3(27.26,23.02) 27.32,23.07 27.74,23.07 R931.2 28.05,22.77 28.35,23.07 28.64,23.07 R933.1 29.27,23.09 30.04,23.09 C900.1
EDP1_AUX_P: length 31.8
  L3 w0.05: v1(46.87,30.19) 47.23,30.19 47.38,30.05 47.38,29.9 47.24,29.76 46.57,29.76 arc(46.49,29.8) 46.45,29.89 46.45,29.96 arc(46.32,30.09) 46.2,29.96 46.2,29.89 arc(46.07,29.76) 45.95,29.89 45.95,29.96 arc(45.82,30.09) 45.7,29.96 45.7,29.89 arc(45.66,29.8) 45.57,29.76 42.97,29.76 42.65,30.08 30.73,30.08 30.52,29.87 29.91,29.87 29.86,29.92 29.86,30.07 v2(30.01,30.22)
  L6 w0.05: v3(27.26,23.32) 27.2,23.25 27.1,23.25 27,23.35 27,26.62 29.86,29.48 29.86,30.07 v2(30.01,30.22)
  BOTTOM w0.062: C901.1 30.04,23.27 29.24,23.27 R932.1 28.64,23.26 28.35,23.26 28.05,23.56 R934.2 27.74,23.26 27.32,23.26 v3(27.26,23.32)
EDP1_HPD_1P8: length 39.3
  TOP w0.1: J2600.C17 50.04,48.85 47.49,48.85 v1(47.34,49)
  L3 w0.1: v1(47.34,49) 47.17,49.17 30.63,49.17 v2(30.52,49.06)
  L6 w0.1: v3(29.54,31.93) 29.54,35.36 29.93,35.75 29.93,48.47 v2(30.52,49.06)
  BOTTOM w0.1: v3(29.54,31.93) 29.54,31.53 29.56,31.5 U902.4
EDP1_HPD_3P3: length 13.7
  L6 w0.2: v3(28.53,27.04) 27.63,26.14 v8(27.63,20.86)
  L7 w0.2: v8(27.63,20.86) 27.67,20.86 27.77,20.76 28.2,20.76 28.22,20.77 30.8,20.77 31.05,20.52 v7(32.91,20.52)
  BOTTOM w0.2: R910.2 29.37,27.05 R911.2 29.36,27.04 v3(28.53,27.04) ; U900.22 32.91,20.51 v7(32.91,20.52)
EDP1_LN0_M: length 29.2
  L3 w0.05: v2(33.58,26.98) 33.4,26.8 33.4,25.59 arc(33.44,25.25) 33.54,24.92 arc(33.9,24.27) 34.38,23.7 35.29,22.79 arc(35.5,22.65) 35.74,22.6 36.11,22.6 arc(36.32,22.51) 36.41,22.3 36.41,21.94 arc(36.53,21.82) 36.66,21.94 36.66,22.3 arc(36.96,22.6) 37.26,22.3 37.26,21.94 arc(37.38,21.82) 37.51,21.94 37.51,22.3 arc(37.81,22.6) 38.11,22.3 38.11,21.94 arc(38.23,21.82) 38.36,21.94 38.36,22.3 arc(38.66,22.6) 38.96,22.3 38.96,21.94 arc(39.08,21.82) 39.21,21.94 39.21,22.3 arc(39.51,22.6) 39.81,22.3 39.81,21.94 arc(39.93,21.82) 40.06,21.94 40.06,22.3 arc(40.36,22.6) 40.66,22.3 40.66,21.96 arc(40.78,21.84) 40.91,21.96 40.91,22.3 arc(41.21,22.6) 41.51,22.3 41.51,21.96 arc(41.63,21.84) 41.76,21.96 41.76,22.3 arc(42.06,22.6) 42.36,22.3 42.36,21.96 arc(42.48,21.84) 42.61,21.96 42.61,22.3 arc(42.69,22.51) 42.91,22.6 44.57,22.6 arc(45.73,22.37) 46.73,21.71 47.53,20.91 arc(47.54,20.88) 47.55,20.86 47.55,20.57 arc(47.55,20.55) 47.56,20.53 47.64,20.45 v1(48.09,20.45)
  L6 w0.05: v2(33.58,26.98) 33.41,26.81 33.41,26.34 v3(33.59,26.16)
EDP1_LN0_P: length 29.2
  L3 w0.05: v1(46.83,20.44) 47.26,20.44 47.37,20.56 arc(47.37,20.56) 47.37,20.57 47.37,20.79 arc(47.37,20.81) 47.35,20.83 46.6,21.58 arc(45.67,22.21) 44.57,22.43 42.91,22.43 arc(42.82,22.39) 42.78,22.3 42.78,21.96 arc(42.48,21.66) 42.18,21.96 42.18,22.3 arc(42.06,22.43) 41.93,22.3 41.93,21.96 arc(41.63,21.66) 41.33,21.96 41.33,22.3 arc(41.21,22.43) 41.08,22.3 41.08,21.96 arc(40.78,21.66) 40.48,21.96 40.48,22.3 arc(40.36,22.43) 40.23,22.3 40.23,21.94 arc(39.93,21.64) 39.63,21.94 39.63,22.3 arc(39.51,22.43) 39.38,22.3 39.38,21.94 arc(39.08,21.64) 38.78,21.94 38.78,22.3 arc(38.66,22.43) 38.53,22.3 38.53,21.94 arc(38.23,21.64) 37.93,21.94 37.93,22.3 arc(37.81,22.43) 37.68,22.3 37.68,21.94 arc(37.38,21.64) 37.08,21.94 37.08,22.3 arc(36.96,22.43) 36.83,22.3 36.83,21.94 arc(36.53,21.64) 36.23,21.94 36.23,22.3 arc(36.19,22.39) 36.11,22.43 35.74,22.43 arc(35.43,22.49) 35.17,22.66 34.25,23.58 arc(33.76,24.17) 33.38,24.85 arc(33.26,25.21) 33.22,25.59 33.22,26.83 v2(33.08,26.98)
  L6 w0.05: v2(33.08,26.98) 33.23,26.82 33.23,26.38 v3(33.01,26.16)
  BOTTOM w0.062: R902.1 v3(33.01,26.16)
EDP1_LN1_M: length 29.3
  L3 w0.05: v2(34.98,26.62) 34.81,26.46 34.81,26.22 arc(34.93,25.93) 35.22,25.81 35.27,25.81 arc(35.57,25.51) 35.27,25.21 35.16,25.21 arc(35.08,25.18) 35.05,25.1 35.05,24.8 arc(35.08,24.68) 35.15,24.58 35.28,24.45 arc(35.36,24.41) 35.44,24.45 35.6,24.6 arc(36.02,24.6) 36.02,24.18 35.86,24.02 arc(35.83,23.94) 35.86,23.87 36.1,23.63 arc(36.42,23.41) 36.8,23.34 arc(37,23.42) 37.08,23.62 37.08,24.01 arc(37.38,24.31) 37.68,24.01 37.68,23.62 arc(37.81,23.49) 37.93,23.62 37.93,23.99 arc(38.23,24.29) 38.53,23.99 38.53,23.62 arc(38.66,23.49) 38.78,23.62 38.78,23.99 arc(39.08,24.29) 39.38,23.99 39.38,23.62 arc(39.51,23.49) 39.63,23.62 39.63,23.99 arc(39.93,24.29) 40.23,23.99 40.23,23.62 arc(40.27,23.53) 40.36,23.49 45.28,23.49 arc(45.43,23.56) 45.5,23.71 45.5,24.95 arc(45.8,25.25) 46.1,24.95 46.1,24.41 arc(46.13,24.32) 46.22,24.29 47.78,24.29 arc(48,24.19) 48.1,23.97 arc(48,23.73) 47.77,23.64 46.66,23.64 arc(46.52,23.5) 46.66,23.36 47.3,23.36 arc(47.51,23.27) 47.6,23.06 47.6,22.87 47.68,22.78 v1(48.09,22.78)
  L6 w0.05: v2(34.98,26.62) 34.82,26.46 34.82,26.37 35,26.19 v3(35,26.16)
EDP1_LN1_P: length 29.4
  L3 w0.05: v2(34.48,26.62) 34.64,26.46 34.64,26.22 arc(34.81,25.8) 35.22,25.63 35.27,25.63 arc(35.4,25.51) 35.27,25.38 35.16,25.38 arc(34.96,25.3) 34.88,25.1 34.88,24.8 arc(34.92,24.62) 35.02,24.46 35.15,24.32 arc(35.36,24.24) 35.57,24.32 35.72,24.48 arc(35.9,24.48) 35.9,24.3 35.74,24.14 arc(35.65,23.94) 35.74,23.74 35.97,23.51 arc(36.35,23.25) 36.8,23.16 arc(37.13,23.3) 37.26,23.62 37.26,24.01 arc(37.38,24.13) 37.51,24.01 37.51,23.62 arc(37.81,23.32) 38.11,23.62 38.11,23.99 arc(38.23,24.12) 38.36,23.99 38.36,23.62 arc(38.66,23.32) 38.96,23.62 38.96,23.99 arc(39.08,24.12) 39.21,23.99 39.21,23.62 arc(39.51,23.32) 39.81,23.62 39.81,23.99 arc(39.93,24.12) 40.06,23.99 40.06,23.62 arc(40.15,23.41) 40.36,23.32 45.28,23.32 arc(45.56,23.43) 45.67,23.71 45.67,24.95 arc(45.8,25.08) 45.92,24.95 45.92,24.41 arc(46.01,24.2) 46.22,24.11 47.78,24.11 arc(47.88,24.07) 47.92,23.97 arc(47.88,23.86) 47.77,23.81 46.66,23.81 arc(46.34,23.5) 46.66,23.18 47.3,23.18 arc(47.38,23.15) 47.42,23.06 47.42,22.91 47.29,22.78 v1(46.82,22.78)
  L6 w0.05: v3(34.44,26.16) 34.64,26.36 34.64,26.46 v2(34.48,26.62)
EDP1_LN2_M: length 29.1
  L3 w0.05: v2(36.31,27.09) 36.15,26.92 36.15,25.79 arc(36.21,25.49) 36.38,25.23 36.52,25.09 arc(36.63,25.01) 36.76,24.99 40.6,24.99 arc(40.81,24.9) 40.9,24.69 40.9,24.47 arc(41.02,24.34) 41.15,24.47 41.15,24.69 arc(41.45,24.99) 41.75,24.69 41.75,24.45 arc(41.87,24.33) 42,24.45 42,24.69 arc(42.09,24.9) 42.3,24.99 42.54,24.99 arc(42.66,25.04) 42.72,25.16 42.72,26.28 arc(43.02,26.58) 43.32,26.28 43.32,24.3 arc(43.44,24.18) 43.57,24.3 43.57,26.33 arc(43.87,26.63) 44.17,26.33 44.17,24.3 arc(44.3,24.17) 44.44,24.3 44.44,25.71 arc(44.53,25.92) 44.74,26.01 44.89,26.01 arc(44.98,26.05) 45.02,26.14 45.02,26.47 arc(45.32,26.77) 45.62,26.47 45.62,26.14 arc(45.74,26.01) 45.87,26.14 45.87,26.47 arc(46.17,26.77) 46.47,26.47 46.47,26.14 arc(46.5,26.05) 46.59,26.01 47.19,26.01 arc(47.47,25.9) 47.58,25.63 47.58,25.44 47.7,25.32 v1(47.89,25.32)
  L6 w0.05: v2(36.31,27.09) 36.15,26.92 36.15,26.34 v3(36.32,26.16)
EDP1_LN2_P: length 29.2
  L3 w0.05: v2(35.81,27.09) 35.97,26.93 35.97,25.79 arc(36.04,25.42) 36.25,25.11 36.4,24.96 arc(36.56,24.85) 36.76,24.81 40.6,24.81 arc(40.69,24.77) 40.72,24.69 40.72,24.47 arc(41.02,24.17) 41.32,24.47 41.32,24.69 arc(41.45,24.81) 41.57,24.69 41.57,24.45 arc(41.87,24.15) 42.17,24.45 42.17,24.69 arc(42.21,24.77) 42.3,24.81 42.54,24.81 arc(42.79,24.91) 42.89,25.16 42.89,26.28 arc(43.02,26.41) 43.14,26.28 43.14,24.3 arc(43.44,24) 43.74,24.3 43.74,26.33 arc(43.87,26.46) 43.99,26.33 43.99,24.3 arc(44.3,23.99) 44.61,24.3 44.61,25.71 arc(44.65,25.8) 44.74,25.84 44.89,25.84 arc(45.1,25.92) 45.19,26.14 45.19,26.47 arc(45.32,26.6) 45.44,26.47 45.44,26.14 arc(45.74,25.84) 46.04,26.14 46.04,26.47 arc(46.17,26.6) 46.29,26.47 46.29,26.14 arc(46.38,25.92) 46.59,25.84 47.19,25.84 arc(47.34,25.77) 47.4,25.63 47.4,25.44 47.28,25.32 v1(47.04,25.32)
  L6 w0.05: v3(35.72,26.16) 35.97,26.4 35.97,26.93 v2(35.81,27.09)
EDP1_LN3_M: length 29.2
  L3 w0.05: v2(37.65,26.63) 37.51,26.78 37.51,26.91 37.59,27 37.98,27 arc(38.07,26.96) 38.1,26.87 38.1,25.79 arc(38.4,25.49) 38.7,25.79 38.7,27.45 arc(38.83,27.57) 38.95,27.45 38.95,25.79 arc(39.25,25.49) 39.55,25.79 39.55,27.44 arc(39.68,27.57) 39.8,27.44 39.8,25.79 arc(40.1,25.49) 40.4,25.79 40.4,27.49 arc(40.53,27.62) 40.65,27.49 40.65,25.79 arc(40.95,25.49) 41.25,25.79 41.25,27.09 arc(41.38,27.22) 41.5,27.09 41.5,25.79 arc(41.8,25.49) 42.1,25.79 42.1,27.07 arc(42.14,27.16) 42.23,27.2 47.29,27.2 47.55,27.45 47.55,27.63 47.62,27.7 v1(47.94,27.7)
  L6 w0.05: v2(37.65,26.63) 37.49,26.47 37.49,26.37 v3(37.7,26.16)
EDP1_LN3_P: length 29.2
  L3 w0.05: v1(46.96,27.69) 47.32,27.69 47.37,27.64 47.37,27.52 47.22,27.37 42.23,27.37 arc(42.02,27.28) 41.93,27.07 41.93,25.79 arc(41.8,25.67) 41.68,25.79 41.68,27.09 arc(41.38,27.39) 41.08,27.09 41.08,25.79 arc(40.95,25.67) 40.83,25.79 40.83,27.49 arc(40.53,27.79) 40.23,27.49 40.23,25.79 arc(40.1,25.67) 39.98,25.79 39.98,27.44 arc(39.68,27.74) 39.38,27.44 39.38,25.79 arc(39.25,25.67) 39.13,25.79 39.13,27.45 arc(38.83,27.75) 38.53,27.45 38.53,25.79 arc(38.4,25.67) 38.28,25.79 38.28,26.87 arc(38.19,27.08) 37.98,27.17 37.52,27.17 37.33,26.99 37.33,26.81 v2(37.15,26.63)
  L6 w0.05: v3(37.14,26.16) 37.32,26.34 37.32,26.47 v2(37.15,26.63)
EDP2_AUX_M: length 16.5
  TOP w0.062: J2600.A34 53.17,27.86 v1(53.01,27.86)
  L3 w0.05: v1(53.01,27.86) 52.73,27.86 52.63,27.76 52.63,27.66 arc(52.63,27.63) 52.65,27.61 52.79,27.47 arc(52.81,27.46) 52.83,27.45 53.43,27.45 arc(53.5,27.48) 53.53,27.55 53.53,27.58 arc(53.63,27.68) 53.73,27.58 53.73,27.55 arc(53.76,27.48) 53.83,27.45 59.24,27.45 arc(59.31,27.48) 59.34,27.55 59.34,27.69 arc(59.61,27.96) 59.89,27.69 59.89,27.55 arc(59.99,27.45) 60.09,27.55 60.09,27.7 arc(60.36,27.97) 60.64,27.7 60.64,27.55 arc(60.67,27.48) 60.74,27.45 63.05,27.45 v2(63.21,27.61)
  L6 w0.05: v3(63.65,27.77) 63.65,27.5 63.6,27.45 63.36,27.45 v2(63.21,27.61)
  BOTTOM w0.062: v3(63.65,27.77) 63.34,27.46 63.05,27.46 R1031.1 62.42,27.44 61.74,27.44 C1000.1
EDP2_AUX_P: length 16.3
  L3 w0.05: v1(52.08,27.87) 52.34,27.87 52.45,27.76 52.45,27.66 arc(52.47,27.56) 52.52,27.49 52.66,27.35 arc(52.74,27.3) 52.83,27.28 59.24,27.28 arc(59.43,27.36) 59.51,27.55 59.51,27.69 arc(59.61,27.79) 59.71,27.69 59.71,27.55 arc(59.99,27.28) 60.26,27.55 60.26,27.7 arc(60.36,27.8) 60.46,27.7 60.46,27.55 arc(60.54,27.36) 60.74,27.28 63.04,27.28 v2(63.21,27.11)
  L6 w0.05: v3(63.65,26.97) 63.65,27.23 63.6,27.28 63.38,27.28 v2(63.21,27.11)
  BOTTOM w0.062: C1001.1 61.73,27.26 62.46,27.26 R1029.1 63.05,27.27 63.34,27.27 v3(63.65,26.97)
EDP2_HPD_1P8: length 45
  TOP w0.1: v1(50.63,51.99) J2600.C15
  L3 w0.1: v1(50.63,51.99) 51.38,51.23 51.38,43.53 52.55,42.36 56.71,42.36 56.9,42.56 57.69,42.56 57.99,42.26 63.03,42.26 v2(63.18,42.41)
  L6 w0.1: v2(63.18,42.41) 63.18,42.01 63.2,41.99 63.2,40.11 64.4,38.91 64.4,25.8 62.16,23.57 v3(62.16,21.75)
  BOTTOM w0.1: U1001.4 62.14,20.7 62.41,20.97 62.41,21.32 R1028.2 62,21.75 v3(62.16,21.75)
EDP2_HPD_3P3: length 10.6
  L6 w0.3: v3(58.91,29.88) 59.19,29.6 59.19,25.31 59.53,24.96 59.53,22.8 58.31,21.59 v3(58.31,20.92)
  BOTTOM w0.2: R1027.2 58.3,20.06 R1026.2
  BOTTOM w0.3: v3(58.31,20.92) 58.3,20.91 R1027.2
EDP2_LN0_M: length 13.9
  L3 w0.05: v1(53.17,22.78) 52.73,22.78 arc(52.71,22.77) 52.69,22.76 52.64,22.71 arc(52.63,22.69) 52.62,22.67 52.62,22.59 arc(52.64,22.54) 52.69,22.52 53.6,22.52 arc(53.69,22.56) 53.72,22.65 arc(53.85,22.78) 53.97,22.65 arc(54.1,22.52) 54.22,22.65 arc(54.35,22.78) 54.47,22.65 arc(54.51,22.56) 54.6,22.52 55.86,22.52 55.86,22.53 56.31,22.53 56.38,22.6 56.38,23.14 arc(56.68,23.44) 56.98,23.14 56.98,22.26 arc(57.11,22.14) 57.23,22.26 57.23,23.17 arc(57.53,23.47) 57.83,23.17 57.83,22.26 arc(58.15,21.94) 58.47,22.26 58.47,23.66 v2(58.3,23.83)
  L6 w0.05: v3(58.27,24.38) 58.47,24.18 58.47,23.99 v2(58.3,23.83)
EDP2_LN0_P: length 13.9
  L3 w0.05: v2(58.8,23.83) 58.64,23.66 58.64,22.26 arc(58.15,21.77) 57.66,22.26 57.66,23.17 arc(57.53,23.3) 57.41,23.17 57.41,22.26 arc(57.11,21.96) 56.81,22.26 56.81,23.14 arc(56.68,23.26) 56.56,23.14 56.56,22.53 56.38,22.35 56.01,22.35 56.01,22.35 52.69,22.35 arc(52.58,22.37) 52.49,22.43 52.45,22.48 52.45,22.7 52.37,22.78 v1(51.9,22.78)
  L6 w0.05: v3(58.85,24.38) 58.85,24.35 58.64,24.15 58.64,23.99 v2(58.8,23.83)
EDP2_LN1_M: length 14
  L3 w0.05: v2(56.87,21.09) 57.03,20.93 57.03,20.81 56.91,20.68 56.42,20.68 arc(56.33,20.72) 56.3,20.81 56.3,20.94 arc(56.17,21.06) 56.05,20.94 56.05,20.81 arc(56.01,20.72) 55.92,20.68 52.24,20.68 50.09,22.84 50.09,24 50.14,24.05 v1(50.63,24.05)
  L6 w0.05: v3(56.85,24.38) 57.04,24.2 57.04,21.26 v2(56.87,21.09)
  BOTTOM w0.062: R1009.1 56.85,24.38 v3(56.85,24.38)
EDP2_LN1_P: length 14
  L3 w0.05: v2(57.37,21.09) 57.21,20.93 57.21,20.74 56.98,20.51 52.17,20.51 49.91,22.76 49.91,24 49.86,24.05 v1(49.36,24.05)
  L6 w0.05: v3(57.4,24.38) 57.21,24.18 57.21,21.25 v2(57.37,21.09)
EDP2_LN2_M: length 13.7
  L3 w0.05: v2(55.53,23.83) 55.69,23.67 55.69,23.56 55.6,23.47 arc(55.58,23.45) 55.55,23.45 55.22,23.45 arc(55.13,23.48) 55.09,23.57 55.09,25.07 arc(54.79,25.37) 54.49,25.07 54.49,23.56 arc(54.37,23.44) 54.24,23.56 54.24,25.08 arc(53.94,25.38) 53.64,25.08 53.64,23.61 arc(53.59,23.49) 53.48,23.45 53.09,23.45 arc(53.01,23.46) 52.95,23.51 52.69,23.76 arc(52.65,23.83) 52.63,23.91 52.63,24.6 arc(52.67,24.69) 52.76,24.72 52.9,24.72 arc(53.03,24.85) 52.9,24.97 52.76,24.97 arc(52.67,25.01) 52.63,25.1 52.63,25.27 52.68,25.32 v1(52.97,25.32)
  L6 w0.05: v2(55.53,23.83) 55.71,24 55.71,24.2 v3(55.52,24.39)
EDP2_LN2_P: length 13.7
  L3 w0.05: v2(56.03,23.83) 55.87,23.66 55.87,23.49 55.72,23.34 arc(55.64,23.29) 55.55,23.27 55.22,23.27 arc(55,23.36) 54.92,23.57 54.92,25.07 arc(54.79,25.2) 54.67,25.07 54.67,23.56 arc(54.37,23.26) 54.07,23.56 54.07,25.08 arc(53.94,25.21) 53.82,25.08 53.82,23.61 arc(53.72,23.37) 53.48,23.27 53.09,23.27 arc(52.95,23.3) 52.82,23.38 52.57,23.64 arc(52.49,23.76) 52.46,23.91 52.46,25.27 52.41,25.32 v1(52.12,25.32)
  L6 w0.05: v2(56.03,23.83) 55.88,23.98 55.88,24.16 v3(56.12,24.39)
EDP2_LN3_M: length 13.7
  L3 w0.05: v2(54.11,21.72) 54.25,21.57 54.25,21.44 arc(54.25,21.43) 54.25,21.42 54.25,21.42 arc(54.23,21.38) 54.18,21.37 53.82,21.37 arc(53.73,21.41) 53.69,21.49 53.69,21.64 arc(53.57,21.77) 53.44,21.64 53.44,21.49 arc(53.4,21.41) 53.32,21.37 52.51,21.37 51.35,22.52 51.35,24.36 arc(51.34,24.45) 51.28,24.53 50.86,24.96 arc(50.82,25.05) 50.86,25.14 51.27,25.55 arc(51.27,25.97) 50.84,25.97 50.42,25.55 arc(50.33,25.51) 50.24,25.55 50.11,25.68 arc(50.09,25.72) 50.08,25.77 50.08,26.4 50.08,26.53 50.14,26.59 v1(50.42,26.59)
  L6 w0.05: v2(54.11,21.72) 54.27,21.88 54.27,24.18 v3(54.07,24.38)
EDP2_LN3_P: length 13.7
  L3 w0.05: v1(49.58,26.59) 49.83,26.59 49.9,26.52 49.9,26.47 49.9,25.77 arc(49.92,25.65) 49.99,25.55 50.12,25.42 arc(50.33,25.34) 50.54,25.42 50.96,25.85 arc(51.14,25.85) 51.14,25.67 50.73,25.26 arc(50.64,25.05) 50.73,24.84 51.16,24.41 arc(51.17,24.39) 51.18,24.36 51.18,22.47 arc(51.18,22.45) 51.2,22.43 51.81,21.82 52.41,21.21 arc(52.44,21.2) 52.46,21.19 54.18,21.19 arc(54.33,21.24) 54.42,21.38 arc(54.43,21.41) 54.43,21.44 54.43,21.54 v2(54.61,21.72)
  L6 w0.05: v3(54.64,24.38) 54.45,24.19 54.45,21.88 v2(54.61,21.72)
EDP3_AUX_M: length 15.8
  TOP w0.062: J2600.A28 53.18,35.48 v1(53.18,35.69)
  L3 w0.05: v1(53.18,35.69) 52.81,35.69 52.61,35.89 52.61,36.16 52.45,36.32 50.74,36.32 arc(50.65,36.36) 50.62,36.45 50.62,36.77 arc(50.32,37.07) 50.02,36.77 50.02,36.45 arc(49.89,36.32) 49.77,36.45 49.77,36.77 arc(49.47,37.07) 49.17,36.77 49.17,36.45 arc(49.04,36.32) 48.92,36.45 48.92,36.77 arc(48.62,37.07) 48.32,36.77 48.32,36.45 arc(48.19,36.32) 48.07,36.45 48.07,36.77 arc(47.77,37.07) 47.47,36.77 47.47,36.45 arc(47.43,36.36) 47.34,36.32 46.96,36.32 arc(46.94,36.33) 46.91,36.34 46.84,36.41 arc(46.83,36.43) 46.82,36.46 46.82,36.74 v2(46.99,36.9)
  L6 w0.05: v3(47.12,36.32) 46.88,36.32 46.82,36.37 46.82,36.74 v2(46.99,36.9)
  BOTTOM w0.062: R1132.2 46.83,36.45 46.83,36.73 R1133.1 46.83,37.3 46.83,37.9 46.63,38.1 46.47,38.1 C1100.1
EDP3_AUX_P: length 15.8
  TOP w0.062: J2600.B28 v1(51.9,35.69)
  L3 w0.05: v2(46.49,36.9) 46.65,36.74 46.65,36.46 arc(46.67,36.37) 46.72,36.29 46.79,36.22 arc(46.87,36.16) 46.96,36.15 47.34,36.15 arc(47.56,36.23) 47.64,36.45 47.64,36.77 arc(47.77,36.89) 47.89,36.77 47.89,36.45 arc(48.19,36.15) 48.49,36.45 48.49,36.77 arc(48.62,36.89) 48.74,36.77 48.74,36.45 arc(49.04,36.15) 49.34,36.45 49.34,36.77 arc(49.47,36.89) 49.59,36.77 49.59,36.45 arc(49.89,36.15) 50.19,36.45 50.19,36.77 arc(50.32,36.89) 50.44,36.77 50.44,36.45 arc(50.53,36.23) 50.74,36.15 51.14,36.15 arc(51.21,36.12) 51.24,36.05 51.24,36 arc(51.34,35.9) 51.44,36 51.44,36.05 arc(51.47,36.12) 51.54,36.15 52.38,36.15 52.44,36.09 52.44,35.89 52.24,35.69 v1(51.9,35.69)
  L6 w0.05: v2(46.49,36.9) 46.65,36.74 46.65,36.36 46.6,36.32 v3(46.37,36.32)
  BOTTOM w0.062: C1101.1 46.47,37.91 46.56,37.91 46.65,37.82 46.65,37.3 R1131.1 46.65,36.73 46.65,36.45 R1134.2
EDP3_HPD_1P8: length 15.7
  TOP w0.1: v1(50.74,50.84) 50.74,50.83 J2600.C16
  L3 w0.1: v1(50.74,50.84) 51.18,50.4 51.18,43.21 v2(51.78,42.61)
  L6 w0.1: v3(51.86,47.9) 51.78,47.82 v2(51.78,42.61)
  BOTTOM w0.1: U1101.4 52.09,46.85 52.36,47.12 52.36,47.39 R1130.2
EDP3_HPD_3P3: length 9.9
  L6 w0.1: v8(45.22,45.55) 43.48,43.8 v3(43.48,40.42)
  L7 w0.1: v7(48.17,46.2) 47.51,45.55 v8(45.22,45.55)
  BOTTOM w0.1: R1129.2 48.16,46.21 v7(48.17,46.2) ; U1100.22 v3(43.48,40.42)
EDP3_LN0_M: length 16
  L3 w0.05: v1(53.17,30.4) 52.67,30.4 52.62,30.35 52.62,30.14 arc(52.5,29.86) 52.22,29.74 51.8,29.74 arc(51.67,29.76) 51.54,29.83 arc(51.42,29.89) 51.28,29.91 49.31,29.91 arc(49.25,29.91) 49.2,29.93 49.13,29.95 arc(48.95,30.09) 48.84,30.3 arc(48.8,30.42) 48.72,30.52 48.53,30.72 arc(48.37,30.83) 48.18,30.86 44.82,30.86 arc(44.41,30.78) 44.06,30.55 43.79,30.28 arc(43.72,30.23) 43.62,30.21 43.41,30.21 arc(43.32,30.23) 43.25,30.28 43.2,30.33 arc(43.15,30.41) 43.13,30.5 43.13,30.6 v2(42.97,30.76)
  L6 w0.05: v2(42.97,30.76) 43.13,30.92 43.13,34.71 v3(42.92,34.92)
EDP3_LN0_P: length 15.9
  L3 w0.05: v2(43.47,30.76) 43.3,30.59 43.3,30.5 arc(43.31,30.48) 43.32,30.46 43.37,30.41 arc(43.39,30.39) 43.41,30.39 43.63,30.39 arc(43.65,30.39) 43.67,30.41 43.94,30.67 arc(44.34,30.94) 44.82,31.04 48.18,31.04 arc(48.44,30.99) 48.65,30.84 48.85,30.65 arc(48.95,30.51) 49.01,30.34 arc(49.08,30.21) 49.2,30.12 49.26,30.09 arc(49.29,30.08) 49.31,30.08 50.63,30.08 arc(50.72,30.12) 50.75,30.21 50.75,30.32 arc(50.88,30.44) 51,30.32 51,30.21 arc(51.04,30.12) 51.13,30.08 51.28,30.08 arc(51.47,30.05) 51.64,29.97 arc(51.72,29.93) 51.8,29.92 52.22,29.92 arc(52.38,29.98) 52.45,30.14 52.45,30.35 52.4,30.4 v1(51.89,30.4)
  L6 w0.05: v2(43.47,30.76) 43.31,30.92 43.31,34.73 v3(43.5,34.92)
EDP3_LN1_M: length 15.8
  L3 w0.05: v2(41.52,29.19) 41.68,29.02 41.68,28.73 arc(41.69,28.71) 41.7,28.69 41.83,28.56 arc(41.85,28.55) 41.87,28.54 49.77,28.54 arc(49.86,28.56) 49.94,28.61 50,28.68 arc(50.06,28.75) 50.07,28.84 50.07,29.07 50.13,29.13 v1(50.52,29.13)
  L6 w0.05: v2(41.52,29.19) 41.68,29.35 41.68,34.73 v3(41.49,34.92)
EDP3_LN1_P: length 15.7
  L3 w0.05: v1(49.53,29.13) 49.85,29.13 49.9,29.08 49.9,28.84 arc(49.89,28.82) 49.88,28.8 49.82,28.73 arc(49.8,28.72) 49.77,28.72 48.89,28.72 arc(48.8,28.75) 48.76,28.84 48.76,29 arc(48.64,29.13) 48.51,29 48.51,28.84 arc(48.47,28.75) 48.39,28.72 41.92,28.72 41.86,28.78 41.86,29.02 v2(42.02,29.19)
  L6 w0.05: v3(42.07,34.92) 41.86,34.71 41.86,29.35 v2(42.02,29.19)
EDP3_LN2_M: length 15.7
  L3 w0.05: v2(40.3,32.74) 40.47,32.57 40.47,32.52 arc(40.49,32.43) 40.54,32.35 40.56,32.33 arc(40.71,32.23) 40.88,32.2 52.06,32.2 arc(52.23,32.23) 52.38,32.33 52.76,32.71 arc(52.78,32.72) 52.8,32.73 v1(53.18,32.73)
  L6 w0.05: v3(40.27,34.93) 40.47,34.74 40.47,33.78 40.47,33.26 40.47,32.91 v2(40.3,32.74)
EDP3_LN2_P: length 15.7
  L3 w0.05: v1(51.9,32.73) 52.37,32.73 52.41,32.69 arc(52.43,32.65) 52.41,32.61 52.26,32.45 arc(52.17,32.4) 52.06,32.37 51.68,32.37 arc(51.6,32.4) 51.58,32.47 51.58,32.62 arc(51.48,32.72) 51.38,32.62 51.38,32.47 arc(51.35,32.4) 51.28,32.37 40.88,32.37 arc(40.77,32.4) 40.68,32.46 40.67,32.47 arc(40.65,32.49) 40.65,32.52 40.65,32.59 v2(40.81,32.75)
  L6 w0.05: v2(40.81,32.75) 40.64,32.91 40.64,33.26 40.64,33.78 40.64,34.76 v3(40.82,34.93)
EDP3_LN3_M: length 15.9
  L3 w0.05: v1(50.62,31.67) 50.4,31.67 50.39,31.66 50.16,31.66 arc(50.1,31.64) 50.08,31.58 50.08,31.28 arc(50.06,31.19) 50.01,31.12 49.94,31.04 arc(49.84,30.98) 49.71,30.95 49.24,30.95 arc(49.15,30.97) 49.07,31.02 48.75,31.35 arc(48.55,31.48) 48.32,31.53 39.23,31.53 arc(39.14,31.54) 39.06,31.6 38.95,31.71 arc(38.93,31.73) 38.93,31.76 38.93,31.93 v2(38.77,32.09)
  L6 w0.05: v3(38.73,34.93) 38.93,34.73 38.93,32.25 v2(38.77,32.09)
EDP3_LN3_P: length 15.9
  L3 w0.05: v2(39.27,32.09) 39.11,31.93 39.11,31.8 39.19,31.72 arc(39.21,31.71) 39.23,31.7 39.67,31.7 arc(39.76,31.74) 39.8,31.83 39.8,31.96 arc(39.92,32.08) 40.05,31.96 40.05,31.83 arc(40.08,31.74) 40.17,31.7 48.32,31.7 arc(48.62,31.64) 48.87,31.47 49.19,31.15 arc(49.22,31.13) 49.24,31.13 49.71,31.13 arc(49.77,31.14) 49.81,31.17 49.88,31.24 arc(49.9,31.26) 49.9,31.28 49.9,31.58 arc(49.88,31.64) 49.81,31.66 v1(49.36,31.66)
  L6 w0.05: v3(39.31,34.93) 39.1,34.71 39.1,32.26 v2(39.27,32.09)
EDP_HDMI_PON: length 3.1
  BOTTOM w0.2: R896.2 R806.2 56.89,38.87 C814.1 55.65,39.72 55.65,39.72 U802.1
EDP_PWR_EN: length 78.7
  TOP w0.1: J2700.D5 113,33.61 113,34.95 v1(112.78,35.16)
  L3 w0.1: v2(57.3,41.61) 57.45,41.46 63.9,41.46 64.3,41.05 67.09,41.05 67.46,40.68 76.29,40.68 76.61,40.37 108.51,40.37 110.8,38.08 110.8,35.43 111.26,34.97 112.58,34.97 v1(112.78,35.16)
  L6 w0.1: v3(56.9,38.07) 56.9,38.47 57.3,38.87 v2(57.3,41.61) 57.3,43.72 55.91,45.11 v3(55.91,53.06)
  BOTTOM w0.1: v3(55.91,53.06) 55.87,53.1 R821.1
EN_PWRLIGHT/GPO42: length 6
  TOP w0.1: U1701.73 148.07,55.8 146.96,54.68 146.23,54.68 145.85,54.31 145.32,54.31 145.32,54.31 144.78,54.31 R1713.1
EN_VREG_3P3: length 75.6
  TOP w0.25: R538.2 v1(127.63,40.44)
  L3 w0.25: v2(86.85,49.86) 86.85,49.8 106.13,49.8 109.85,46.08 109.85,43.96 113.04,40.77 115,40.77 115.38,40.39 127.58,40.39 v1(127.63,40.44)
  L6 w0.25: v3(87.32,75.59) 87.32,71 86.75,70.42 86.75,62.37 87.26,61.85 87.26,61.5 86.76,61 86.76,49.88 86.85,49.8 v2(86.85,49.86)
  BOTTOM w0.25: R533.2 87.21,75.7 v3(87.32,75.59) 87.95,74.96 U500.40
EN_VREG_5P0: length 13.3
  L6 w0.3: v3(89.8,79.97) v8(89.8,70.41)
  L7 w0.3: v7(88.6,70.45) 89.75,70.45 v8(89.8,70.41)
  BOTTOM w0.3: U500.31 88.6,70.46 v7(88.6,70.45) ; R539.1 92.09,80.03 89.86,80.03 v3(89.8,79.97)
ENSWR: length 4
  TOP w0.1: R1721.1 140.62,57.9 R1720.2 140.62,58.73 141.17,58.73 142.33,59.88 U1701.60
ETHCAT_WAKE_N: length 15.2
  TOP w0.1: v1(43.41,106.5) 43.54,106.63 U1502.2 ; U1500.21 35.69,109.92 36.13,110.36 36.13,110.96 36.51,111.34 v1(36.67,111.34)
  L3 w0.1: v2(42.8,111.14) 42.59,111.35 36.68,111.35 v1(36.67,111.34) ; v2(43.02,106.52) 43.05,106.5 v1(43.41,106.5)
  L6 w0.1: v2(43.02,106.52) 42.81,106.73 42.81,111.13 v2(42.8,111.14)
EXPANDER_INT_N_1P8: length 87.2
  TOP w0.1: v1(108.45,44.44) 108.46,44.44 J2700.A14
  L3 w0.1: v2(40.79,59.11) 40.98,58.93 44.49,58.93 51.78,51.64 51.78,46.8 53.34,45.25 55.97,45.25 57.2,46.48 86.22,46.48 86.67,46.03 105.87,46.03 107.46,44.44 v1(108.45,44.44)
  L6 w0.1: v2(40.79,59.11) 40.79,53.74 38.93,51.88 v3(38.93,51.59)
EXT_ADC1: length 109.9
  TOP w0.1: v1(45.11,37.41) 46.3,36.22 48.84,36.22 J2600.D27 ; v1(133.15,32.17) 133.15,33.57 134.15,34.57 135.45,34.57 135.9,35.02 135.9,38.92 136.05,39.07 TVS1809.2 J3400.9
  L3 w0.1: v1(45.11,37.41) 45.24,37.41 46.33,38.5 52.01,38.5 52.57,37.94 61.52,37.94 62.31,37.15 84.73,37.15 84.9,36.97 85.36,36.97 85.52,37.13 86.65,37.13 86.99,37.47 107.25,37.47 107.67,37.89 108.52,37.89 109.9,36.52 109.9,34.82 110.3,34.42 115.45,34.42 116.25,33.62 117.4,33.62 118,33.02 120.57,33.02 120.92,32.67 125.1,32.67 125.4,32.37 126.15,32.37 126.35,32.57 131.05,32.57 131.45,32.17 v1(133.15,32.17)
EXT_ADC2: length 27.9
  TOP w0.1: v1(132.2,36.72) 132.2,38.07 133.2,39.07 TVS1810.2 J3400.10 ; v1(112.9,38.72) 112.32,39.29 J2700.C10
  L3 w0.1: v1(132.2,36.72) 131.25,36.72 130.7,37.27 129.3,37.27 129,36.97 123.55,36.97 122.8,37.72 117.45,37.72 116.45,38.72 v1(112.9,38.72)
EXT_PWM1: length 4.5
  TOP w0.1: U1802.A1 136.39,28.74 R1809.1 136.67,29.85 TVS1807.1 136.67,30.59 136.85,30.77 J3400.12
EXT_PWM2: length 4.8
  TOP w0.1: J3400.11 134.85,31.57 135.86,30.56 TVS1808.1 135.86,29.85 R1810.1 135.99,28.88 U1802.B1
EXTPWRON: length 5.8
  TOP w0.1: U2400.63 153.61,83.36 153.33,83.09 153.33,81.74 152.85,81.26 152.85,80.69 TP2407.1
FAN_ALERT_1P8_N: length 106.9
  TOP w0.1: J2600.C24 v1(50.63,40.55) ; R3631.2 v1(130.69,13.9) 131.4,13.9 131.5,13.8 U3607.10
  L3 w0.1: v1(130.69,13.9) 130.22,14.38 67.3,14.38 67.29,14.37 v2(66.37,14.37) ; v2(65.75,39.66) 63.99,39.66 63.4,40.26 56.54,40.26 56.25,40.55 v1(50.63,40.55)
  L6 w0.1: v2(65.75,39.66) 66.34,39.07 66.34,14.4 v2(66.37,14.37)
FAN_I2C_CLK1_3V3: length 4.9
  TOP w0.1: U3606.3 130.09,8.96 130.24,8.81 R3628.2
  L3 w0.1: v1(130.64,8.79) 133.61,8.79 133.86,9.04 v1(133.87,9.04)
FAN_I2C_DAT1_3V3: length 4.2
  TOP w0.1: R3627.2 129.84,9.66 129.79,9.61 U3606.4
  L3 w0.1: v1(133.02,9.04) 131.22,9.04 v1(130.59,9.66)
FAN_PWM1: length 58.3
  TOP w0.1: R3636.2 138.33,13.05 v1(138.45,13.17) ; v1(187.79,7.57) 187.82,7.54 TVS3617.2 188.63,7.53 188.63,6.76 187.1,5.23 J3600.4
  L3 w0.1: v1(187.79,7.57) 186.44,8.92 182,8.92 181.3,8.22 180.86,8.22 180.05,9.03 146.62,9.03 142.6,13.06 142.49,13.17 v1(138.45,13.17)
FAN_PWM2: length 47.2
  TOP w0.1: R3635.2 v1(134.77,17.03) ; TVS3615.2 173.1,7.57 ; 173.1,7.57 173.1,5.54 171.89,4.33 J3601.4 ; 173.1,7.57 R3622.2 172.14,7.57 171.36,8.35 v1(171.36,9.32)
  L3 w0.1: v1(171.36,9.32) 171.11,9.57 147.85,9.57 140.38,17.03 v1(134.77,17.03)
FAN_PWR_SW: length 28.2
  TOP w0.2: v1(178.8,7.97) 179.35,7.97 179.65,7.67 C3627.1 180.21,7.66 B3602.1 B3600.1 182.02,7.65 J3600.2 ; J3601.2 166.81,7.21 166.79,7.23 C3626.2 165.86,7.65 C3628.1 164.77,7.65 D3601.2
  L3 w0.2: v1(164.47,7.97) 164.58,8.08 171.99,8.08 172.08,7.99 178.78,7.99 v1(178.8,7.97)
FAN_TACH1: length 59.4
  TOP w0.1: v1(185.24,7.58) 185.27,7.56 TVS3616.2 186.1,5.39 184.56,3.84 J3600.3
  L3 w0.1: v1(135.7,13.8) 136.64,13.8 137.57,12.88 142.49,12.88 145.3,10.07 146.54,8.83 179.97,8.83 180.79,8.01 181.42,8.01 182.14,8.72 185.64,8.72 185.75,8.61 185.75,8.1 v1(185.24,7.58)
FAN_TACH2: length 45.4
  TOP w0.1: U3607.8 133.85,14.92 133.85,15.01 v1(133.84,15.02) ; v1(168.51,9.32) 168.51,7.95 168.89,7.58 R3608.2 170.57,7.58 TVS3614.2 170.6,4.96 J3601.3
  L3 w0.1: v1(168.51,9.32) 147.69,9.32 141.71,15.3 134.1,15.3 134.02,15.22 134.02,15.2 v1(133.84,15.02)
FPGA_DES0_ERRB_1P8: length 5.5
  BOTTOM w0.1: U2900.4 40.56,91.23 40.3,90.97 40.3,89.54 40.75,89.09 40.75,88.55 40.5,88.31 40.5,88.31 40.7,88.12 40.7,87.82 40.07,87.19 R2927.1
FPGA_DES0_FRAME_SYNC_1P8: length 3.8
  BOTTOM w0.1: R2928.1 41.2,87.61 41.2,88.92 40.95,89.17 40.95,89.17 40.5,89.62 40.5,90.47 40.91,90.88 U2900.3
FPGA_DES0_LOCK_1P8: length 6.5
  BOTTOM w0.1: U2900.2 41.26,90.53 40.9,90.17 40.9,89.62 42,88.52 42,87.22 41.74,86.96 R2923.1 41.69,86.92 41.49,87.12 41.33,87.12 40.6,86.39 40.6,85.87 40.66,85.81
FPGA_DES0_SPARE_GPIO_1P8: length 4.4
  BOTTOM w0.1: R2930.1 42.3,86.36 42.3,88.57 41.37,89.5 41.37,89.89 41.63,90.15 41.63,90.17
FPGA_DES1_ERRB_1P8: length 5.4
  BOTTOM w0.1: U3000.4 37.95,64.82 37.79,64.66 37.79,63.02 38.14,62.67 38.14,62.15 R3025.1 37.89,61.87 38.15,61.61 38.15,61.47 37.46,60.78 R3027.1
FPGA_DES1_FRAME_SYNC_1P8: length 3.8
  BOTTOM w0.1: U3000.3 38.3,64.47 37.99,64.16 37.99,63.1 38.63,62.47 38.63,61.29 R3028.1
FPGA_DES1_LOCK_1P8: length 6.6
  BOTTOM w0.1: R3026.1 37.98,59.47 37.98,60.03 38.73,60.77 38.87,60.77 R3024.1 39.4,60.78 39.4,61.25 39.04,61.61 39.04,62.46 38.29,63.21 38.29,63.76 38.65,64.12 U3000.2
FPGA_DES1_SPARE_GPIO_1P8: length 4.4
  BOTTOM w0.1: U3000.1 39.02,63.75 38.76,63.48 38.76,63.09 39.75,62.09 R3033.1
GPIO0: length 2.5
  TOP w0.1: U2400.57 150.66,86.08 150.42,85.84 TP2402.1
GPIO1: length 3
  TOP w0.1: U2400.58 151.61,84.81 151.17,84.37 151.17,83.3 TP2403.1
GPIO2: length 4.2
  TOP w0.1: TP2404.1 151.23,81.87 151.23,82.73 151.63,83.13 151.63,84.43 152.01,84.81 U2400.59
GPIO3: length 3.3
  TOP w0.1: U2400.60 152.41,84.81 151.96,84.36 151.96,82.57 TP2405.1
GPIO4: length 4.4
  TOP w0.1: TP2406.1 152.23,81.44 152.23,84.18 152.81,84.76 U2400.61
GPIO_107_1P8: length 9.5
  TOP w0.1: TP2629.1 45.71,41.95 46.46,41.2 49.98,41.2 50.61,41.83 J2600.C23
HDMI1_5V_CONN: length 14.5
  TOP w0.1: D900.2 21.44,15.81 21.16,16.09 TVS1202.2 18.4,18.63 18.4,20.53 19.22,21.35 J1200.18 ; D900.2 21.43,13.34 R915.1 20.57,13.33 R914.1 ; D900.2 21.44,12.42 TP901.1
HDMI1_CEC: length 10.6
  TOP w0.1: J1200.13 16.33,21.98 17.46,20.85 17.47,20.85 17.64,20.68 17.64,18.34 18.15,17.83 TVS1204.2 18.42,16.09 18.6,15.91 18.6,13.29 TP1200.1
HDMI1_CLK_N: length 27.7
  L3 w0.05: v1(16.92,13.8) 16.73,13.61 16.73,13.47 16.86,13.34 17.19,13.34 arc(17.28,13.38) 17.31,13.47 17.31,13.97 arc(17.61,14.27) 17.91,13.97 17.91,13.47 arc(18.04,13.34) 18.16,13.47 18.16,13.97 arc(18.46,14.27) 18.76,13.97 18.76,13.47 arc(18.89,13.34) 19.01,13.47 19.01,13.97 arc(19.31,14.27) 19.61,13.97 19.61,13.47 arc(19.65,13.38) 19.74,13.34 36.77,13.34 arc(36.86,13.32) 36.94,13.27 37.1,13.1 37.1,12.95 37.15,12.9 37.22,12.9 37.27,12.85 v2(37.27,12.82)
  L6 w0.05: v3(37.26,14.01) 37.1,13.86 37.1,12.99 v2(37.27,12.82)
  BOTTOM w0.062: v3(37.26,14.01) 37.29,14.04 R920.2
HDMI1_CLK_N_CONN: length 10.3
  TOP w0.062: R1216.2 16.9,14.3 CR1201.10 CR1201.1 16.9,16.12 16.74,16.27 16.74,16.92 arc(16.66,17.11) 16.47,17.19 16.36,17.19 arc(16.24,17.31) 16.36,17.43 16.43,17.43 arc(16.65,17.53) 16.74,17.75 16.74,18.54 arc(16.57,19.41) 16.07,20.16 15.26,20.97 arc(15.24,21) 15.23,21.03 15.23,21.4 15.75,21.92 J1200.12
HDMI1_CLK_P: length 27.7
  L3 w0.05: v1(16.37,13.8) 16.46,13.7 16.46,13.7 16.55,13.61 16.55,13.4 16.78,13.17 17.19,13.17 arc(17.4,13.25) 17.49,13.47 17.49,13.97 arc(17.61,14.1) 17.74,13.97 17.74,13.47 arc(18.04,13.17) 18.34,13.47 18.34,13.97 arc(18.46,14.1) 18.59,13.97 18.59,13.47 arc(18.89,13.17) 19.19,13.47 19.19,13.97 arc(19.31,14.1) 19.44,13.97 19.44,13.47 arc(19.53,13.25) 19.74,13.17 36.77,13.17 arc(36.79,13.16) 36.81,13.15 36.93,13.03 36.93,12.98 v2(36.77,12.82)
  L6 w0.05: v3(36.78,14.01) 36.93,13.86 36.93,12.99 v2(36.77,12.82)
  BOTTOM w0.062: v3(36.78,14.01) 36.72,14.06 R918.2
HDMI1_CLK_P_CONN: length 10.4
  TOP w0.062: J1200.10 14.6,21.86 15.05,21.42 15.05,21.03 arc(15.07,20.92) 15.12,20.84 15.94,20.03 arc(16.39,19.34) 16.55,18.54 16.55,17.75 arc(16.52,17.66) 16.43,17.62 16.36,17.62 arc(16.05,17.31) 16.36,17 16.47,17 arc(16.53,16.98) 16.55,16.92 16.55,16.27 16.4,16.12 CR1201.2 CR1201.9 16.4,14.3 R1215.2 16.39,14.28 CMC1203.2
HDMI1_HPD: length 28.8
  TOP w0.1: J1200.19 19.8,21.4 18.65,20.25 18.65,18.74 20.69,16.7 21.28,16.7 TVS1203.2 R1299.1 23.18,16.09 23.21,16.12 v1(24.59,16.12)
  L3 w0.1: v1(24.59,16.12) 26.68,18.21 39.36,18.21 v2(39.47,18.11)
  L6 w0.1: v3(39.72,20.11) 39.72,20.1 39.47,19.85 v2(39.47,18.11)
HDMI1_SCL_CONN: length 38.1
  TOP w0.1: J1200.15 17.48,21.21 17.92,20.77 17.92,18.43 19.12,17.23 TVS1205.2 19.4,16.09 19.56,15.93 19.56,15.09 19.56,15.09 19.56,14.94 v1(19.87,14.63) 19.87,14.29 R914.2 19.3,14.13 19.19,14.02 19.19,12.05 TP909.1
  L3 w0.1: v1(19.87,14.63) 20.05,14.45 23.48,14.45 26.9,17.86 v2(30.35,17.86) 39.22,17.86 39.32,17.76 39.71,17.76 40.17,18.22 42.67,18.22 v2(42.74,18.28)
  L6 w0.1: v2(30.35,17.86) 30.35,17.86 30.36,17.86 30.36,17.87 v3(29.88,17.87) ; v3(42.74,18.78) v2(42.74,18.28)
  BOTTOM w0.1: R928.2 42.73,18.78 v3(42.74,18.78)
HDMI1_SDA_CONN: length 38.9
  TOP w0.1: v1(20.57,14.14) 20.46,14.24 20.46,16 20.38,16.08 TVS1206.2 20.01,16.68 18.15,18.53 18.15,20.95 18.06,21.04 J1200.16
  L3 w0.1: v2(30.3,19.05) 30.53,18.82 31.46,18.82 31.59,18.95 42.24,18.95 v2(42.51,19.21) ; v1(20.57,14.14) 23.03,14.14 v1(23.07,14.1) 26.35,14.1 26.87,14.62 v2(30.32,14.62)
  L6 w0.1: v2(30.32,14.62) 31.15,15.45 31.15,18.2 v2(30.3,19.05) 29.98,18.73 v3(29.85,18.73) ; v2(42.51,19.21) 42.75,19.45 v3(42.75,19.61)
HDMI1_TX0_N: length 27.8
  L3 w0.05: v2(36.11,11.81) 35.95,11.97 35.95,12.21 35.84,12.33 arc(35.57,12.51) 35.25,12.57 23.67,12.57 arc(23.46,12.48) 23.37,12.27 23.37,12.2 arc(23.25,12.08) 23.12,12.2 23.12,12.32 arc(23.05,12.5) 22.88,12.57 22.82,12.57 arc(22.61,12.48) 22.52,12.27 22.52,12.2 arc(22.4,12.08) 22.27,12.2 22.27,12.32 arc(22.2,12.5) 22.03,12.57 21.97,12.57 arc(21.76,12.48) 21.67,12.27 21.67,12.2 arc(21.55,12.08) 21.42,12.2 21.42,12.32 arc(21.35,12.5) 21.18,12.57 21.12,12.57 arc(20.91,12.48) 20.82,12.27 20.82,12.2 arc(20.7,12.08) 20.57,12.2 20.57,12.32 arc(20.5,12.5) 20.33,12.57 16.04,12.57 arc(15.77,12.62) 15.54,12.77 15.23,13.08 15.23,13.61 v1(15.42,13.79)
  L6 w0.05: v2(36.11,11.81) 35.95,11.97 35.95,14.37 36.15,14.57 v3(36.15,14.58)
HDMI1_TX0_N_CONN: length 10.3
  TOP w0.062: J1200.9 13.54,21.67 13.54,21.29 arc(13.54,21.26) 13.56,21.24 15.05,19.74 arc(15.19,19.54) 15.24,19.29 15.24,18.36 arc(15.15,18.14) 14.93,18.05 14.82,18.05 arc(14.7,17.92) 14.82,17.8 14.97,17.8 arc(15.16,17.72) 15.24,17.53 15.24,17.49 arc(15.15,17.27) 14.93,17.18 14.82,17.18 arc(14.7,17.05) 14.82,16.93 14.97,16.93 arc(15.16,16.85) 15.24,16.66 15.24,16.27 15.4,16.12 CR1201.4 CR1201.7 15.4,14.3 R1214.2
HDMI1_TX0_P: length 27.8
  L3 w0.05: v2(35.61,11.81) 35.78,11.97 35.78,12.14 35.71,12.2 arc(35.5,12.34) 35.25,12.39 23.67,12.39 arc(23.58,12.36) 23.55,12.27 23.55,12.2 arc(23.25,11.9) 22.95,12.2 22.95,12.32 arc(22.93,12.37) 22.88,12.39 22.82,12.39 arc(22.73,12.36) 22.7,12.27 22.7,12.2 arc(22.4,11.9) 22.1,12.2 22.1,12.32 arc(22.08,12.37) 22.03,12.39 21.97,12.39 arc(21.88,12.36) 21.85,12.27 21.85,12.2 arc(21.55,11.9) 21.25,12.2 21.25,12.32 arc(21.23,12.37) 21.18,12.39 21.12,12.39 arc(21.03,12.36) 21,12.27 21,12.2 arc(20.7,11.9) 20.4,12.2 20.4,12.32 arc(20.38,12.37) 20.33,12.39 16.01,12.39 arc(15.7,12.46) 15.44,12.63 15.06,13.01 15.06,13.61 v1(14.87,13.79)
  L6 w0.05: v3(35.57,14.57) 35.77,14.37 35.77,11.97 v2(35.61,11.81)
HDMI1_TX0_P_CONN: length 10.3
  TOP w0.062: J1200.7 13.35,21.67 13.35,21.29 arc(13.37,21.19) 13.43,21.1 14.92,19.61 arc(15.02,19.46) 15.05,19.29 15.05,18.36 arc(15.02,18.27) 14.93,18.23 14.82,18.23 arc(14.51,17.92) 14.82,17.61 14.97,17.61 arc(15.03,17.59) 15.05,17.53 15.05,17.49 arc(15.02,17.4) 14.93,17.36 14.82,17.36 arc(14.51,17.05) 14.82,16.74 14.97,16.74 arc(15.03,16.72) 15.05,16.66 15.05,16.27 14.9,16.12 CR1201.5 CR1201.6 14.9,14.3 R1212.2
HDMI1_TX1_N: length 27.9
  L3 w0.05: v1(13.87,13.79) 13.78,13.7 13.75,13.7 13.68,13.63 13.68,13.04 15.18,11.55 arc(15.38,11.41) 15.63,11.36 16.18,11.36 arc(16.21,11.38) 16.23,11.42 16.23,11.52 arc(16.53,11.82) 16.83,11.52 16.83,11.49 arc(16.86,11.4) 16.95,11.36 17.02,11.36 arc(17.06,11.38) 17.08,11.42 17.08,11.52 arc(17.38,11.82) 17.68,11.52 17.68,11.49 arc(17.71,11.4) 17.8,11.36 17.88,11.36 arc(17.91,11.38) 17.93,11.42 17.93,11.52 arc(18.23,11.82) 18.53,11.52 18.53,11.49 arc(18.56,11.4) 18.65,11.36 33.61,11.36 arc(33.7,11.35) 33.78,11.29 33.82,11.25 arc(33.87,11.17) 33.89,11.08 33.89,10.97 arc(33.9,10.95) 33.91,10.93 v2(34.06,10.79)
  L6 w0.05: v2(34.06,10.79) 33.89,10.95 33.89,14.34 v3(34.11,14.56)
HDMI1_TX1_N_CONN: length 10.2
  TOP w0.062: R1211.2 13.85,14.3 CR1200.10 CR1200.1 13.85,16.12 13.69,16.27 13.69,19.52 arc(13.63,19.84) 13.45,20.1 13.04,20.51 arc(12.77,20.69) 12.46,20.75 arc(12.15,20.82) 11.88,20.99 11.78,21.09 11.78,21.45 12.29,21.96 J1200.6
HDMI1_TX1_P: length 27.9
  L3 w0.05: v2(33.56,10.79) 33.72,10.95 arc(33.72,10.95) 33.72,10.95 arc(33.72,10.96) 33.72,10.97 33.72,11.08 arc(33.71,11.1) 33.7,11.12 33.65,11.17 arc(33.63,11.18) 33.61,11.19 18.65,11.19 arc(18.44,11.28) 18.35,11.49 18.35,11.52 arc(18.23,11.64) 18.1,11.52 18.1,11.42 arc(18.04,11.26) 17.88,11.19 17.8,11.19 arc(17.59,11.28) 17.5,11.49 17.5,11.52 arc(17.38,11.64) 17.25,11.52 17.25,11.42 arc(17.19,11.26) 17.02,11.19 16.95,11.19 arc(16.74,11.28) 16.65,11.49 16.65,11.52 arc(16.53,11.64) 16.4,11.52 16.4,11.42 arc(16.34,11.26) 16.18,11.19 15.63,11.19 arc(15.32,11.25) 15.05,11.43 13.53,12.95 arc(13.51,12.97) 13.51,13 13.51,13.61 v1(13.32,13.8)
  L6 w0.05: v3(33.51,14.56) 33.72,14.36 33.72,10.95 v2(33.56,10.79)
HDMI1_TX1_P_CONN: length 10.3
  TOP w0.062: J1200.4 11.13,21.88 11.6,21.5 11.6,21.02 11.75,20.86 arc(12.08,20.64) 12.46,20.57 arc(12.7,20.52) 12.91,20.38 13.32,19.97 arc(13.45,19.76) 13.5,19.52 13.5,16.27 13.35,16.12 CR1200.2 CR1200.9 13.35,14.3 R1210.2
HDMI1_TX2_N: length 27.7
  L3 w0.05: v2(32.9,9.89) 32.74,10.06 32.74,10.34 32.55,10.53 arc(32.53,10.54) 32.5,10.55 15.14,10.55 arc(14.89,10.59) 14.69,10.73 12.2,13.22 arc(12.19,13.24) 12.18,13.26 12.18,13.61 arc(12.19,13.63) 12.2,13.65 12.35,13.8 v1(12.37,13.8)
  L6 w0.05: v2(32.9,9.89) 32.74,10.06 32.74,14.35 v3(32.94,14.56)
HDMI1_TX2_N_CONN: length 10.4
  TOP w0.062: J1200.3 10.07,21.67 10.07,21.24 arc(10.05,21.14) 9.99,21.05 9.49,20.54 arc(9.01,19.38) 9.48,18.2 9.6,18.08 arc(10.4,17.53) 11.35,17.34 arc(11.66,17.28) 11.93,17.1 12.11,16.91 arc(12.17,16.83) 12.19,16.73 12.19,16.27 12.35,16.12 CR1200.4 CR1200.7 12.35,14.3 R1209.2
HDMI1_TX2_P: length 27.7
  L3 w0.05: v2(32.4,9.89) 32.56,10.05 32.56,10.27 32.46,10.37 15.06,10.37 arc(14.82,10.42) 14.61,10.56 12.03,13.14 arc(12.01,13.16) 12.01,13.19 12.01,13.61 v1(11.82,13.79)
  L6 w0.05: v2(32.4,9.89) 32.56,10.06 32.56,14.36 v3(32.36,14.55)
HDMI1_TX2_P_CONN: length 10.4
  TOP w0.062: R1200.2 11.85,14.3 CR1200.6 CR1200.5 11.85,16.12 12,16.27 12,16.73 arc(12,16.76) 11.98,16.78 11.8,16.97 arc(11.59,17.1) 11.35,17.15 arc(10.32,17.36) 9.46,17.95 9.34,18.07 arc(8.82,19.38) 9.35,20.68 9.86,21.18 arc(9.88,21.21) 9.88,21.24 9.88,21.67 J1200.1
HDMI2_5V_CONN: length 12.2
  TOP w0.2: J1201.18 21.12,35.52 22.48,36.88 22.48,38 23.1,38.62 TVS1209.2 24.15,39.17 25.92,39.17 27.55,37.54 28.54,37.54
HDMI2_CEC: length 11.1
  TOP w0.1: TP1203.1 25.45,35.34 23.7,35.34 23.59,35.23 v1(23.59,34.88)
  L3 w0.1: v1(23.59,34.88) 23.03,34.88 21.57,33.43 17.41,33.43 16.33,34.51 J1201.13
HDMI2_CLK_N: length 38
  TOP w0.062: v1(25.89,33.69) 25.89,33.67 CMC1207.4
  L3 w0.05: v1(25.89,33.69) 26.08,33.51 26.63,33.51 arc(26.88,33.55) 27.08,33.69 27.22,33.83 arc(27.25,33.91) 27.22,34 27.21,34.01 arc(27.21,34.19) 27.39,34.19 27.39,34.18 arc(27.48,34.14) 27.57,34.18 28.86,35.47 arc(29.08,35.62) 29.34,35.67 31.1,35.67 arc(31.19,35.71) 31.22,35.8 31.22,36.06 arc(31.52,36.36) 31.82,36.06 31.82,35.8 arc(31.95,35.67) 32.07,35.8 32.07,36.06 arc(32.37,36.36) 32.67,36.06 32.67,35.8 arc(32.8,35.67) 32.92,35.8 32.92,36.06 arc(33.22,36.36) 33.52,36.06 33.52,35.8 arc(33.65,35.67) 33.77,35.8 33.77,36.06 arc(34.07,36.36) 34.37,36.06 34.37,35.8 arc(34.5,35.67) 34.62,35.8 34.62,36.06 arc(34.92,36.36) 35.22,36.06 35.22,35.8 arc(35.26,35.71) 35.35,35.67 44.77,35.67 arc(45.09,35.61) 45.35,35.43 45.44,35.34 arc(45.6,35.23) 45.79,35.2 53.93,35.2 54.46,35.73 54.46,36.92 v2(54.3,37.07)
  L6 w0.05: v3(54.32,36.38) 54.47,36.53 54.47,36.91 v2(54.3,37.07)
  BOTTOM w0.062: C1002.2 54.27,36.34 R1016.2
HDMI2_CLK_N_CONN: length 21.2
  TOP w0.062: R1233.2 25.41,33.67 25.41,33.67 CR1208.10 CR1208.1 23.6,33.67 23.42,33.49 23.22,33.49 23.07,33.65 22.56,33.65 arc(22.47,33.69) 22.43,33.79 arc(22.39,33.88) 22.29,33.92 22.25,33.92 arc(22.16,33.88) 22.12,33.79 arc(22.08,33.69) 21.98,33.65 17.78,33.65 arc(17.46,33.52) 17.32,33.19 17.32,31.36 arc(17.2,31.23) 17.07,31.36 17.07,33.19 arc(16.76,33.5) 16.45,33.19 16.45,31.36 arc(16.33,31.23) 16.2,31.36 16.2,33.19 arc(16.11,33.41) 15.89,33.5 15.36,33.5 15.25,33.62 15.25,33.82 15.75,34.32 J1201.12
HDMI2_CLK_P: length 38
  TOP w0.062: v1(25.89,33.14) 25.89,33.16 CMC1207.1
  L3 w0.05: v2(54.8,37.07) 54.63,36.91 54.63,35.65 54,35.02 45.79,35.02 arc(45.54,35.07) 45.32,35.22 45.23,35.31 45.22,35.31 arc(45.02,35.45) 44.77,35.5 35.35,35.5 arc(35.13,35.58) 35.05,35.8 35.05,36.06 arc(34.92,36.18) 34.8,36.06 34.8,35.8 arc(34.5,35.5) 34.2,35.8 34.2,36.06 arc(34.07,36.18) 33.95,36.06 33.95,35.8 arc(33.65,35.5) 33.35,35.8 33.35,36.06 arc(33.22,36.18) 33.1,36.06 33.1,35.8 arc(32.8,35.5) 32.5,35.8 32.5,36.06 arc(32.37,36.18) 32.25,36.06 32.25,35.8 arc(31.95,35.5) 31.65,35.8 31.65,36.06 arc(31.52,36.18) 31.4,36.06 31.4,35.8 arc(31.31,35.58) 31.1,35.5 29.34,35.5 arc(29.15,35.46) 28.99,35.35 27.21,33.57 arc(26.94,33.39) 26.63,33.33 26.08,33.33 v1(25.89,33.14)
  L6 w0.05: v2(54.8,37.07) 54.64,36.91 54.64,36.54 v3(54.8,36.38)
  BOTTOM w0.062: R1014.2 54.84,35.81 54.84,36.31 arc(54.84,36.34) 54.82,36.36 v3(54.8,36.38)
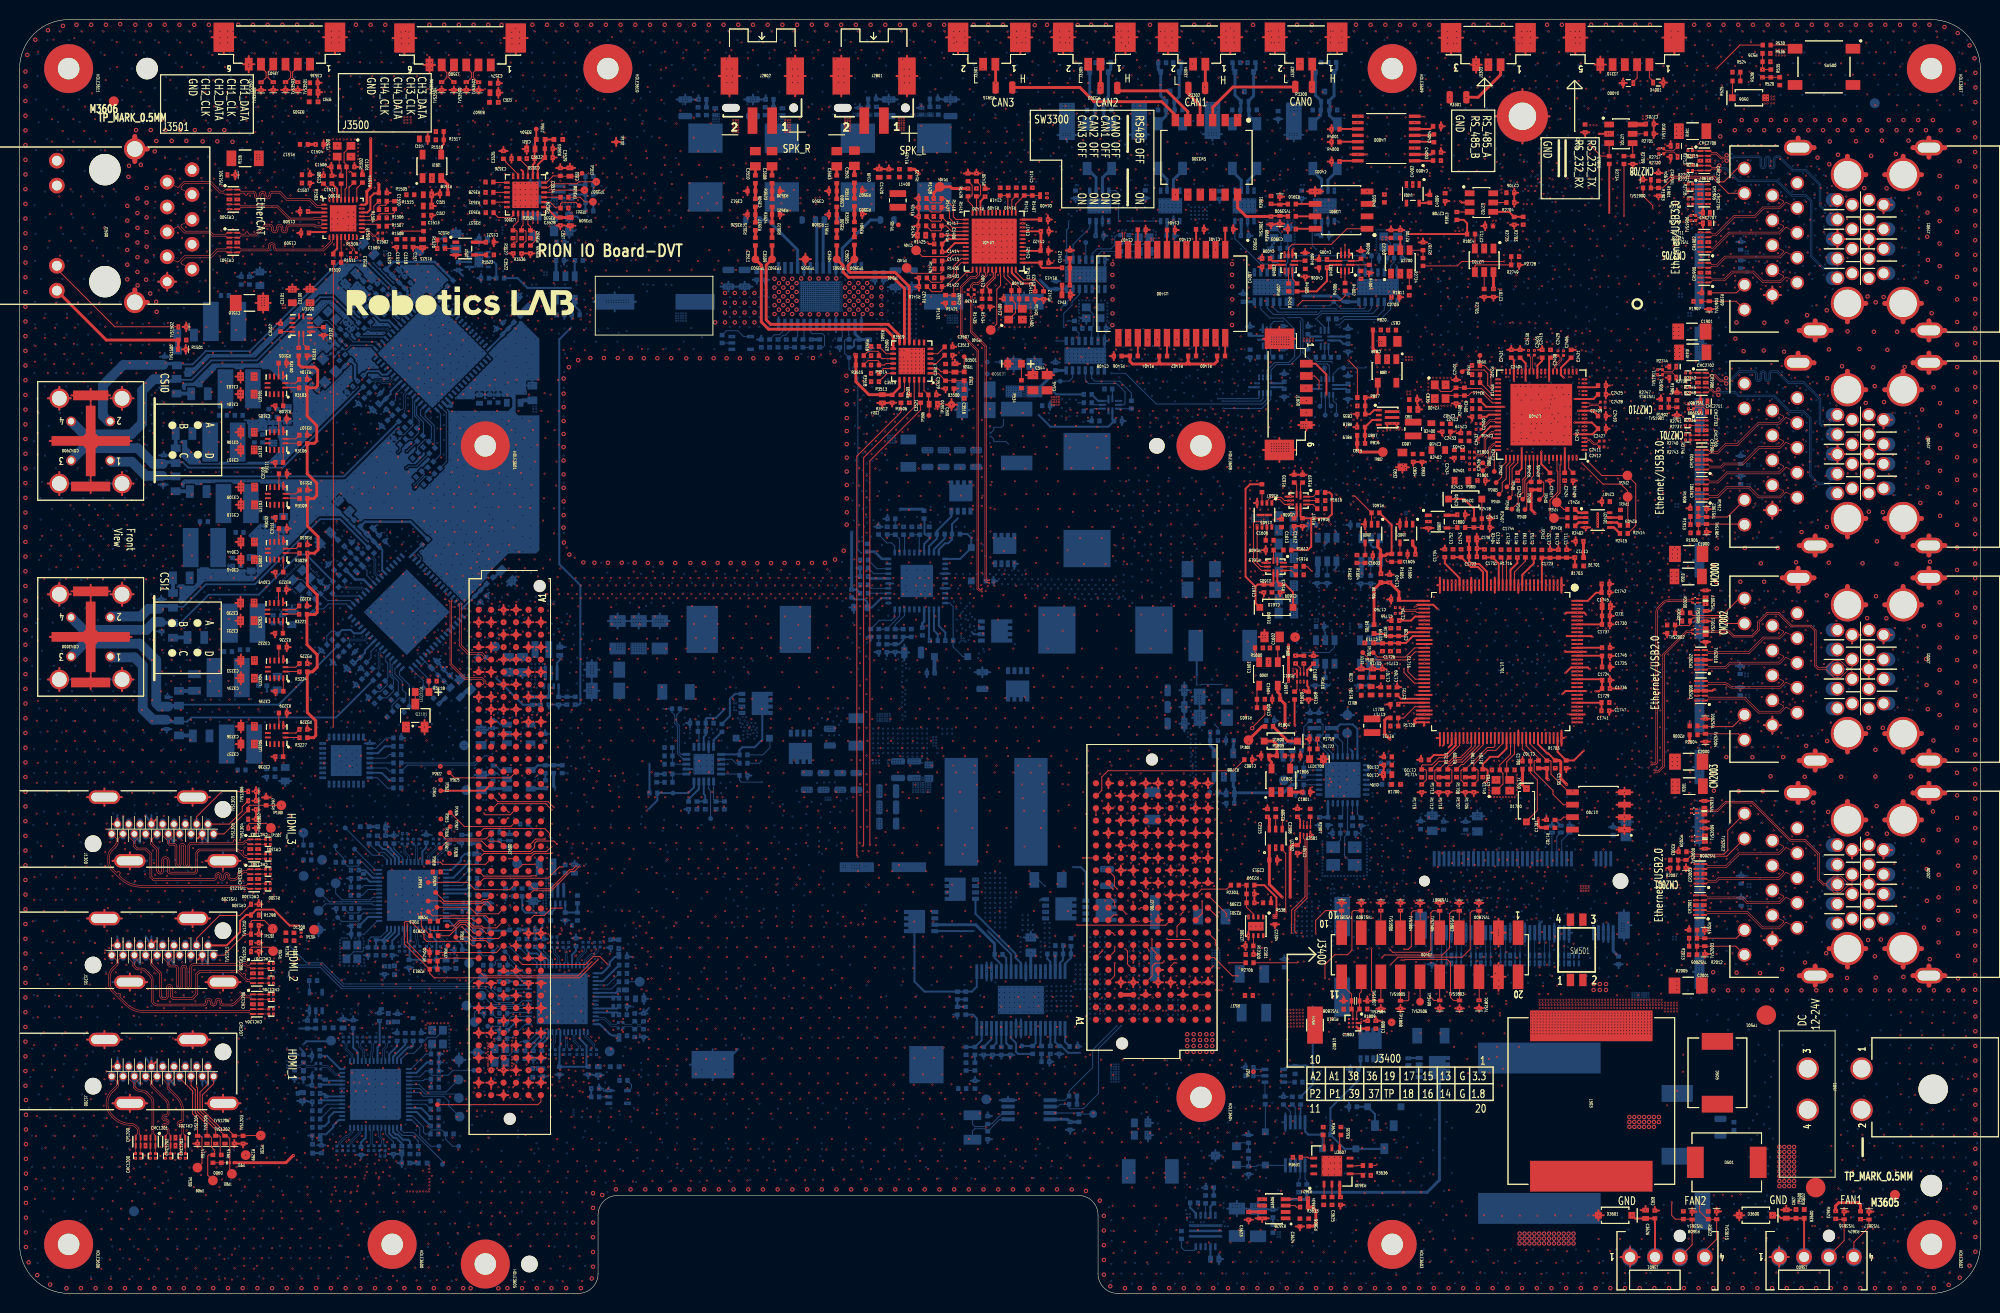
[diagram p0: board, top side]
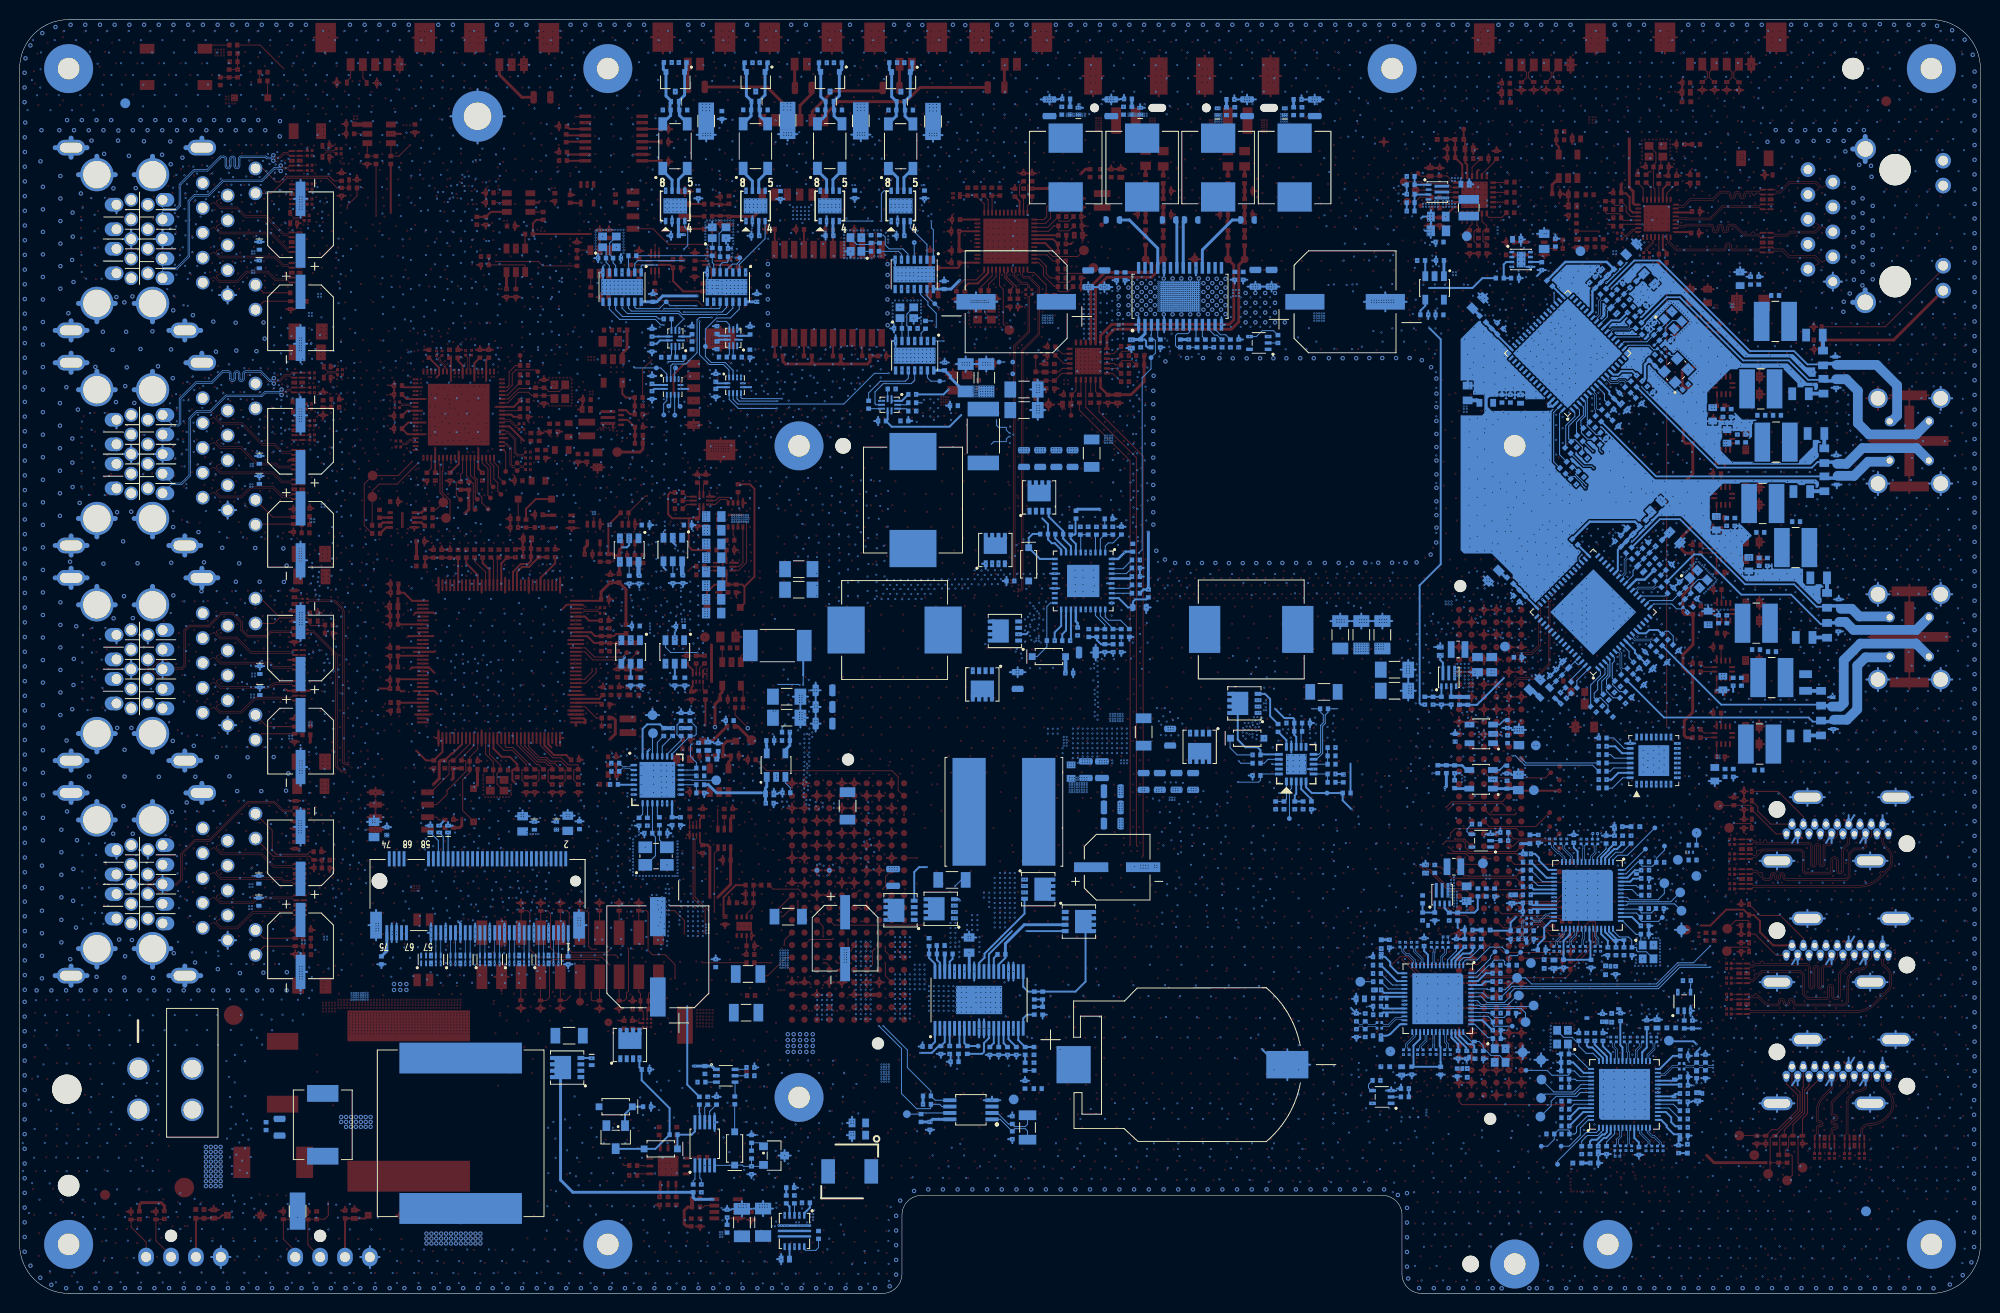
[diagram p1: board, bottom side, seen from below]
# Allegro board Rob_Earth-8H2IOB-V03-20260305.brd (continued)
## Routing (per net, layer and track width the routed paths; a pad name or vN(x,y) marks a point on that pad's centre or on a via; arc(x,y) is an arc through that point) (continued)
HDMI2_CLK_P_CONN: length 21.2
  TOP w0.062: R1232.2 25.39,33.17 25.03,33.17 25.03,33.17 CR1208.9 CR1208.2 23.6,33.17 23.45,33.31 23.15,33.31 22.99,33.47 17.78,33.47 arc(17.59,33.39) 17.51,33.19 17.51,31.36 arc(17.2,31.05) 16.89,31.36 16.89,33.19 arc(16.76,33.32) 16.64,33.19 16.64,31.36 arc(16.33,31.05) 16.02,31.36 16.02,33.19 arc(15.98,33.28) 15.89,33.32 15.28,33.32 15.06,33.54 15.06,33.8 14.59,34.27 J1201.10
HDMI2_HPD: length 40.1
  TOP w0.1: J1201.19 20.84,34.52 22.99,36.67 TVS1210.2 R1298.1 23.6,37.97 23.7,38.07 24.96,38.07 TP1202.1
  L3 w0.1: v2(26.78,37.17) v1(25.88,37.17)
  L6 w0.1: v2(26.78,37.17) 26.78,34.6 27.54,33.85 v3(27.54,33.32)
  BOTTOM w0.1: v3(27.54,33.32) 27.58,33.28 30.66,33.28 32.84,31.1 47.53,31.1 47.98,30.65 47.98,30.26 48.57,29.68 50.32,29.68 50.91,30.27 U1000.50
HDMI2_SCL_CONN: length 49.3
  L3 w0.1: v2(27.17,35.47) 27.17,36 v1(27.16,36.01) 23.82,36.01 v1(23.6,35.79) 21.51,33.71 18.29,33.71 J1201.15
  L6 w0.1: v3(27.55,35.47) v2(27.17,35.47)
  L7 w0.1: v7(48.94,31) 57.68,31 58.24,31.57 60.82,31.57 v7(61.91,32.66)
  BOTTOM w0.1: v7(48.94,31) 48.94,31 48.47,31 TP1205.1 46.4,32.21 45.78,31.58 33.75,31.58 33.04,31.58 30.88,33.74 29.27,33.74 v3(27.55,35.47)
HDMI2_SDA_CONN: length 54.5
  TOP w0.1: v1(23.6,39.72) 22.45,38.57 20.39,38.57 18.06,36.24 J1201.16
  L3 w0.1: v1(23.6,39.72) 24.75,38.57 27.2,38.57 27.98,37.78 v1(27.98,36) 27.98,35.5 v2(28.02,35.46)
  L6 w0.1: v2(28.02,35.46) v3(28.02,33.53)
  L7 w0.1: v7(61.94,31.84) 61.38,31.84 60.9,31.37 60.9,31.37 60.89,31.35 58.37,31.35 57.77,30.75 49.52,30.75 v7(48.94,30.17)
  BOTTOM w0.1: v3(28.02,33.53) 28.02,33.52 30.79,33.52 32.97,31.34 47.78,31.34 R1024.2 ; v7(61.94,31.84) 61.93,31.83 R1000.2 TP1206.1
HDMI2_TX0_N: length 37.5
  TOP w0.062: CMC1206.4 25.89,32.17 v1(25.89,32.2)
  L3 w0.05: v2(55.46,36.32) 55.64,36.15 55.64,35.56 54.69,34.62 45.26,34.62 arc(45.18,34.63) 45.11,34.68 44.83,34.97 arc(44.8,34.98) 44.78,34.98 32.88,34.98 arc(32.67,34.9) 32.58,34.68 32.58,34.24 arc(32.45,34.11) 32.33,34.24 32.33,34.68 arc(32.03,34.98) 31.73,34.68 31.73,34.24 arc(31.6,34.12) 31.48,34.24 31.48,34.68 arc(31.18,34.98) 30.88,34.68 30.88,34.26 arc(30.75,34.14) 30.63,34.26 30.63,34.68 arc(30.54,34.9) 30.33,34.98 29.95,34.98 arc(29.85,34.97) 29.78,34.91 27.63,32.76 arc(27.54,32.73) 27.45,32.76 27.45,32.77 arc(27.27,32.77) 27.27,32.59 27.27,32.59 arc(27.31,32.5) 27.27,32.41 27.06,32.19 arc(26.85,32.05) 26.61,32.01 26.09,32.01 v1(25.89,32.2)
  L6 w0.05: v2(55.46,36.32) 55.63,36.16 55.63,36.01 v3(55.42,35.81)
HDMI2_TX0_N_CONN: length 21.2
  TOP w0.062: J1201.9 13.53,34.03 13.53,33.63 14.38,32.78 arc(14.44,32.7) 14.46,32.59 14.46,30.37 arc(14.46,30.33) 14.48,30.31 14.57,30.23 arc(14.61,30.2) 14.65,30.19 14.84,30.19 arc(14.93,30.22) 14.97,30.31 14.97,31.22 arc(15.28,31.53) 15.59,31.22 15.59,30.31 arc(15.63,30.22) 15.71,30.19 17.53,30.19 arc(17.56,30.19) 17.58,30.21 17.97,30.6 17.97,32.6 18.32,32.95 22.32,32.95 22.67,32.61 arc(22.76,32.57) 22.85,32.61 22.85,32.62 arc(23.03,32.62) 23.03,32.44 23.02,32.43 arc(22.98,32.34) 23.02,32.26 23.26,32.02 23.45,32.02 23.6,32.17 CR1208.4 CR1208.7 25.41,32.17 25.41,32.17 R1231.2
HDMI2_TX0_P: length 37.4
  TOP w0.062: v1(25.89,31.65) 25.89,31.66 CMC1206.1
  L3 w0.05: v2(55.96,36.32) 55.81,36.16 55.81,35.49 54.77,34.44 45.26,34.44 arc(45.11,34.47) 44.99,34.55 44.73,34.81 32.88,34.81 arc(32.79,34.77) 32.75,34.68 32.75,34.24 arc(32.45,33.94) 32.15,34.24 32.15,34.68 arc(32.03,34.81) 31.9,34.68 31.9,34.24 arc(31.6,33.94) 31.3,34.24 31.3,34.68 arc(31.18,34.81) 31.05,34.68 31.05,34.26 arc(30.75,33.96) 30.45,34.26 30.45,34.68 arc(30.42,34.77) 30.33,34.81 29.95,34.81 arc(29.92,34.8) 29.9,34.79 27.18,32.07 arc(26.92,31.89) 26.61,31.83 26.07,31.83 v1(25.89,31.65)
  L6 w0.05: v2(55.96,36.32) 55.8,36.16 55.8,36.02 v3(56,35.82)
HDMI2_TX0_P_CONN: length 21.1
  TOP w0.062: R1229.2 25.4,31.67 CR1208.6 CR1208.5 23.6,31.67 23.45,31.82 23.2,31.82 22.25,32.77 18.4,32.77 18.16,32.52 18.16,30.52 17.71,30.08 arc(17.63,30.02) 17.53,30 15.71,30 arc(15.49,30.09) 15.4,30.31 15.4,31.22 arc(15.28,31.34) 15.15,31.22 15.15,30.31 arc(15.06,30.09) 14.84,30 14.65,30 arc(14.53,30.02) 14.43,30.09 14.35,30.18 arc(14.29,30.26) 14.27,30.37 14.27,32.59 arc(14.26,32.62) 14.25,32.65 13.35,33.55 13.35,34.03 J1201.7
HDMI2_TX1_N: length 37.5
  TOP w0.062: v1(25.89,30.55) 25.89,30.52 CMC1205.4
  L3 w0.05: v1(25.89,30.55) 26.08,30.36 26.35,30.36 arc(26.58,30.4) 26.77,30.53 26.95,30.7 arc(26.98,30.79) 26.95,30.88 26.93,30.89 arc(26.93,31.07) 27.11,31.07 27.12,31.06 arc(27.21,31.02) 27.3,31.06 29.22,32.98 arc(29.57,33.21) 29.99,33.3 33.42,33.3 arc(33.51,33.33) 33.54,33.42 33.54,33.77 arc(33.84,34.07) 34.14,33.77 34.14,33.42 arc(34.18,33.33) 34.27,33.3 35.96,33.3 arc(36.21,33.35) 36.41,33.48 36.93,34 arc(37.25,34.21) 37.61,34.29 44.25,34.29 arc(44.46,34.24) 44.65,34.12 44.72,34.04 arc(44.74,34.03) 44.77,34.02 55.23,34.02 arc(55.48,34.07) 55.68,34.21 57.62,36.15 arc(57.64,36.17) 57.64,36.2 57.64,36.56 arc(57.64,36.58) 57.62,36.6 v2(57.48,36.75)
  L6 w0.05: v2(57.48,36.75) 57.64,36.58 57.64,36.01 v3(57.46,35.83)
HDMI2_TX1_N_CONN: length 21.2
  TOP w0.062: J1201.6 12.28,34.3 11.73,33.75 11.73,33.48 11.99,33.23 arc(12.01,33.21) 12.04,33.2 12.44,33.2 arc(12.68,33.15) 12.89,33.02 13.38,32.53 arc(13.56,32.26) 13.62,31.95 13.62,29.95 arc(13.74,29.65) 14.04,29.53 18.78,29.53 arc(18.89,29.57) 18.94,29.68 18.94,29.78 arc(19.28,30.12) 19.62,29.78 19.62,29.64 arc(19.66,29.56) 19.73,29.53 19.78,29.53 arc(19.89,29.57) 19.93,29.68 19.93,29.78 arc(20.28,30.12) 20.62,29.78 20.62,29.64 arc(20.65,29.56) 20.73,29.53 21.5,29.53 arc(21.74,29.58) 21.95,29.71 22.57,30.34 arc(22.59,30.35) 22.62,30.36 22.69,30.36 arc(22.77,30.39) 22.8,30.47 arc(22.84,30.55) 22.92,30.59 22.94,30.59 arc(23.02,30.55) 23.05,30.47 arc(23.08,30.39) 23.16,30.36 23.44,30.36 23.6,30.52 CR1207.1 CR1207.10 25.38,30.52 R1228.2
HDMI2_TX1_P: length 37.5
  TOP w0.062: CMC1205.1 25.89,30.01 v1(25.89,30)
  L3 w0.05: v1(25.89,30) 25.89,30.02 26.03,30.16 arc(26.05,30.17) 26.07,30.18 arc(26.08,30.18) 26.08,30.18 26.35,30.18 arc(26.65,30.24) 26.9,30.41 27.42,30.93 29.34,32.85 arc(29.64,33.05) 29.99,33.12 33.42,33.12 arc(33.63,33.21) 33.72,33.42 33.72,33.77 arc(33.84,33.9) 33.97,33.77 33.97,33.42 arc(34.06,33.21) 34.27,33.12 35.96,33.12 arc(36.27,33.18) 36.54,33.36 37.06,33.88 arc(37.31,34.05) 37.61,34.11 44.25,34.11 arc(44.4,34.08) 44.52,34 44.6,33.92 arc(44.68,33.87) 44.77,33.85 55.23,33.85 arc(55.54,33.91) 55.81,34.09 57.75,36.03 arc(57.8,36.11) 57.82,36.2 57.82,36.56 arc(57.82,36.58) 57.84,36.6 v2(57.98,36.75)
  L6 w0.05: v2(57.98,36.75) 57.82,36.58 57.82,36.05 v3(58.04,35.83)
HDMI2_TX1_P_CONN: length 21.1
  TOP w0.062: J1201.4 11.13,34.18 11.55,33.77 11.55,33.43 arc(11.55,33.4) 11.57,33.38 11.85,33.09 arc(11.94,33.04) 12.04,33.02 12.44,33.02 arc(12.61,32.98) 12.76,32.88 13.24,32.4 arc(13.38,32.19) 13.43,31.95 13.43,29.95 arc(13.61,29.52) 14.04,29.34 18.78,29.34 arc(19.03,29.44) 19.13,29.68 19.13,29.78 arc(19.28,29.94) 19.44,29.78 19.44,29.64 arc(19.52,29.43) 19.73,29.34 19.78,29.34 arc(20.02,29.44) 20.12,29.68 20.12,29.78 arc(20.28,29.94) 20.43,29.78 20.43,29.64 arc(20.52,29.43) 20.73,29.34 21.5,29.34 arc(21.81,29.4) 22.08,29.58 22.67,30.17 23.44,30.17 23.6,30.02 CR1207.2 CR1207.9 25.39,30.02 R1227.2
HDMI2_TX2_N: length 37.5
  TOP w0.062: CMC1204.4 25.89,29.02 v1(25.89,29.05)
  L3 w0.05: v1(25.89,29.05) 26.08,28.86 26.72,28.86 27.07,29.2 arc(27.11,29.29) 27.07,29.38 27.07,29.38 arc(27.07,29.56) 27.24,29.56 27.25,29.56 arc(27.34,29.52) 27.42,29.56 30.18,32.31 arc(30.35,32.42) 30.55,32.47 36.44,32.47 arc(36.68,32.51) 36.89,32.65 37.65,33.41 arc(37.77,33.51) 37.92,33.57 arc(37.94,33.58) 37.97,33.58 43.93,33.58 arc(44.07,33.56) 44.2,33.51 arc(44.35,33.46) 44.51,33.44 55.95,33.44 arc(56.26,33.5) 56.53,33.68 58.82,35.97 arc(58.84,35.99) 58.84,36.01 58.84,36.21 arc(58.84,36.23) 58.82,36.25 v2(58.68,36.4)
  L6 w0.05: v3(58.64,35.83) 58.84,36.04 58.84,36.11 58.84,36.23 v2(58.68,36.4)
HDMI2_TX2_N_CONN: length 21.1
  TOP w0.062: J1201.3 10.07,34.03 10.07,33.68 arc(10.05,33.58) 9.99,33.49 9.57,33.07 arc(9.32,32.71) 9.24,32.27 9.24,31.65 arc(9.31,31.29) 9.51,30.98 9.91,30.58 arc(10,30.54) 10.09,30.58 10.1,30.59 arc(10.27,30.59) 10.27,30.41 10.26,30.41 arc(10.23,30.32) 10.26,30.23 10.89,29.6 arc(11.71,29.05) 12.68,28.86 23.41,28.86 arc(23.44,28.87) 23.46,28.88 23.6,29.02 CR1207.4 CR1207.7 25.42,29.02 CMC1204.3
HDMI2_TX2_P: length 37.4
  TOP w0.062: v1(25.89,28.5) 25.89,28.51 CMC1204.1
  L3 w0.05: v1(25.89,28.5) 26.08,28.68 26.8,28.68 27.55,29.43 30.3,32.19 arc(30.42,32.26) 30.55,32.29 36.44,32.29 arc(36.75,32.35) 37.01,32.53 37.7,33.22 arc(37.91,33.35) 38.15,33.4 43.93,33.4 arc(44.03,33.39) 44.12,33.36 arc(44.31,33.29) 44.51,33.26 55.95,33.26 arc(56.33,33.34) 56.65,33.55 58.95,35.84 arc(59,35.92) 59.02,36.01 59.02,36.21 arc(59.02,36.24) 59.03,36.26 v2(59.18,36.4)
  L6 w0.05: v3(59.21,35.84) 59.01,36.04 59.01,36.11 59.01,36.23 v2(59.18,36.4)
HDMI2_TX2_P_CONN: length 21.1
  TOP w0.062: CMC1204.2 25.41,28.52 CR1207.6 CR1207.5 23.6,28.52 23.44,28.67 12.68,28.67 arc(11.64,28.88) 10.76,29.47 9.38,30.85 arc(9.14,31.21) 9.05,31.65 9.05,32.27 arc(9.15,32.78) 9.44,33.2 9.86,33.62 arc(9.87,33.65) 9.88,33.68 9.88,34.03 J1201.1
HDMI3_5V_CONN: length 15.9
  TOP w0.1: J1300.18 21.38,47.9 22.7,49.22 22.7,49.67 TVS1302.2
  L3 w0.1: v2(29.18,50.27) 23.38,50.27 v1(23.37,50.27)
  L6 w0.1: v2(29.18,50.27) 29.68,49.78 v3(29.68,45.76)
HDMI3_CEC: length 10.9
  TOP w0.1: TP1301.1 25.19,47.95 23.43,47.95 23.32,47.84 v1(23.32,47.5)
  L3 w0.1: J1300.13 17.26,45.96 21.11,45.96 22.66,47.52 23.3,47.52 v1(23.32,47.5)
HDMI3_CLK_N: length 21.9
  L3 w0.05: v1(25.57,46.37) 25.76,46.18 26.01,46.18 26.08,46.11 arc(26.09,46.1) 26.11,46.1 26.27,46.1 arc(26.36,46.13) 26.39,46.22 26.39,46.24 arc(26.52,46.36) 26.64,46.24 26.64,46.22 arc(26.68,46.13) 26.77,46.1 26.99,46.1 arc(27.02,46.1) 27.04,46.11 27.24,46.32 arc(27.26,46.34) 27.26,46.36 27.26,46.62 arc(27.28,46.73) 27.34,46.82 arc(27.71,46.9) 27.91,46.59 27.91,46.27 arc(28.04,46.14) 28.16,46.27 28.16,46.59 arc(28.46,46.89) 28.76,46.59 28.76,46.27 arc(28.89,46.14) 29.01,46.27 29.01,46.59 arc(29.31,46.89) 29.61,46.59 29.61,46.27 arc(29.74,46.14) 29.86,46.27 29.86,46.59 arc(30.16,46.89) 30.46,46.59 30.46,46.28 arc(30.59,46.15) 30.71,46.28 30.71,46.59 arc(31.01,46.89) 31.31,46.59 31.31,46.32 arc(31.44,46.19) 31.56,46.32 31.56,46.59 arc(31.65,46.8) 31.86,46.89 39.08,46.89 39.19,47 39.19,47.27 v2(39.03,47.43)
  L6 w0.05: v3(39.05,46.93) 39.19,47.07 39.19,47.27 v2(39.03,47.43)
  BOTTOM w0.062: R1118.2 39.02,46.9 v3(39.05,46.93)
HDMI3_CLK_N_CONN: length 20.7
  TOP w0.062: R1316.2 25.05,46.34 CR1301.10 CR1301.1 23.32,46.34 23.16,46.18 22.94,46.18 22.79,46.04 22.19,46.04 arc(22.1,46.07) 22.07,46.16 22.07,46.19 arc(21.94,46.31) 21.82,46.19 21.82,46.16 arc(21.78,46.07) 21.7,46.04 17.58,46.04 arc(17.28,45.91) 17.16,45.62 17.16,43.81 arc(17.04,43.69) 16.91,43.81 16.91,45.62 arc(16.6,45.93) 16.29,45.62 16.29,43.83 arc(16.17,43.7) 16.04,43.83 16.04,45.62 arc(15.95,45.84) 15.73,45.93 15.35,45.93 15.28,45.99 15.28,46.25 15.75,46.72 J1300.12
HDMI3_CLK_P: length 21.9
  L3 w0.05: v1(25.57,45.82) 25.75,46 25.93,46 26,45.94 arc(26.02,45.92) 26.04,45.92 26.99,45.92 arc(27.09,45.94) 27.16,45.99 27.37,46.19 arc(27.42,46.27) 27.44,46.36 27.44,46.62 arc(27.44,46.66) 27.47,46.7 arc(27.64,46.73) 27.74,46.59 27.74,46.27 arc(28.04,45.97) 28.34,46.27 28.34,46.59 arc(28.46,46.71) 28.59,46.59 28.59,46.27 arc(28.89,45.97) 29.19,46.27 29.19,46.59 arc(29.31,46.71) 29.44,46.59 29.44,46.27 arc(29.74,45.97) 30.04,46.27 30.04,46.59 arc(30.16,46.71) 30.29,46.59 30.29,46.28 arc(30.59,45.98) 30.89,46.28 30.89,46.59 arc(31.01,46.71) 31.14,46.59 31.14,46.32 arc(31.44,46.02) 31.74,46.32 31.74,46.59 arc(31.78,46.68) 31.86,46.71 39.15,46.71 39.37,46.93 39.37,47.27 v2(39.53,47.43)
  L6 w0.05: v2(39.53,47.43) 39.37,47.27 39.37,47.09 v3(39.53,46.93)
  BOTTOM w0.062: R1116.2 39.59,46.88 v3(39.53,46.93)
HDMI3_CLK_P_CONN: length 20.6
  TOP w0.062: J1300.10 14.59,46.72 15.1,46.22 15.1,45.92 15.27,45.74 15.73,45.74 arc(15.82,45.71) 15.86,45.62 15.86,43.83 arc(16.17,43.51) 16.48,43.83 16.48,45.62 arc(16.6,45.74) 16.73,45.62 16.73,43.81 arc(17.04,43.5) 17.35,43.81 17.35,45.62 arc(17.42,45.78) 17.58,45.85 22.87,45.85 23.02,46 23.16,46 23.32,45.84 CR1301.2 CR1301.9 25.07,45.84 R1315.2
HDMI3_HPD: length 27.1
  TOP w0.1: J1300.19 20.85,46.9 TVS1303.2 23.31,49.67 23.46,49.82 25.14,49.82 R1297.1 TP1300.1
  L3 w0.1: v1(26.7,49.82) v2(28.16,49.82)
  L6 w0.1: v8(28.33,40.91) 28.33,49.66 v2(28.16,49.82)
  L7 w0.1: v8(28.33,40.91) 33.91,40.91 33.99,40.83 v7(36.66,40.83)
  BOTTOM w0.1: U1100.50 36.67,40.82 v7(36.66,40.83)
HDMI3_SCL_CONN: length 50.3
  TOP w0.1: v1(23.31,48.4) 23.31,48.39 TVS1305.2
  L3 w0.1: v2(46.7,48.8) 31.04,48.8 30.9,48.66 29.22,48.66 v2(28.95,48.4) v1(23.31,48.4) 23.12,48.4 20.94,46.21 18.16,46.21 J1300.15
  L6 w0.1: v2(28.95,48.4) v3(28.95,47) 28.95,44.56 29.13,44.38 29.13,43.1 29.08,43.05 29.08,41.59 v8(28.95,41.46) ; v3(47.38,43.32) 47.38,46.28 47.13,46.53 47.13,48.37 v2(46.7,48.8)
  L7 w0.1: v8(28.95,41.46) v7(33.79,41.46)
  BOTTOM w0.1: v3(47.38,43.32) 47.26,43.2 R1101.2 ; R1114.2 28.95,46.99 TP1108.1
HDMI3_SDA_CONN: length 54.2
  TOP w0.1: TVS1306.2 20.63,51.23 18.06,48.66 J1300.16
  L3 w0.1: v2(44.43,51.07) 34.55,51.07 34.32,50.84 28.94,50.84 v2(28.55,51.23) v1(23.33,51.23)
  L6 w0.1: v2(28.55,51.23) 28.55,44.61 28.83,44.33 v3(28.83,44.24) 28.83,43.9 28.66,43.73 v3(28.66,42.58) v8(28.66,40.64) ; v2(44.43,51.07) 45.54,49.96 45.54,44.82 46.2,44.17 46.2,42.79 46.55,42.44 v3(46.55,42.36)
  L7 w0.1: v7(33.77,40.64) v8(28.66,40.64)
  BOTTOM w0.1: v7(33.77,40.64) 33.77,40.63 R1126.2 ; v3(28.83,44.24) 28.84,44.23 R1115.2 ; v3(46.55,42.36) 46.55,42.35 R1100.2
HDMI3_TX0_N: length 21.5
  L3 w0.05: v1(25.57,44.87) 25.76,44.67 26.39,44.67 26.49,44.78 arc(26.53,44.87) 26.49,44.96 arc(26.46,45.05) 26.49,45.13 arc(26.58,45.17) 26.67,45.13 arc(26.76,45.1) 26.84,45.13 26.94,45.23 arc(27.02,45.28) 27.11,45.3 31.92,45.3 arc(32.26,45.43) 32.42,45.76 arc(32.74,46.03) 33.03,45.73 33.03,45.42 arc(33.15,45.3) 33.28,45.42 33.28,45.78 arc(33.58,46.08) 33.88,45.78 33.88,45.42 arc(34,45.3) 34.13,45.42 34.13,45.73 arc(34.43,46.03) 34.73,45.73 34.73,45.42 arc(34.85,45.3) 34.98,45.42 34.98,45.73 arc(35.06,45.94) 35.28,46.03 38.83,46.03 arc(39,46) 39.14,45.91 arc(39.23,45.76) 39.26,45.6 39.26,45.53 arc(39.33,45.38) 39.48,45.32 39.7,45.32 arc(39.72,45.33) 39.74,45.34 40.36,45.95 40.36,46.67 v2(40.19,46.83)
  L6 w0.05: v2(40.19,46.83) 40.36,46.67 40.36,46.56 v3(40.15,46.36)
HDMI3_TX0_N_CONN: length 20.7
  TOP w0.062: J1300.9 13.53,46.41 13.53,45.97 14.16,45.34 14.16,43.15 arc(14.17,43.12) 14.19,43.09 14.27,43.01 arc(14.29,42.99) 14.32,42.99 14.37,42.99 arc(14.45,43.02) 14.49,43.11 14.49,44.2 arc(14.87,44.58) 15.26,44.2 15.26,43.11 arc(15.29,43.02) 15.38,42.99 17.82,42.99 arc(17.85,42.99) 17.88,43.01 17.95,43.08 arc(17.97,43.11) 17.97,43.14 17.97,44.95 arc(17.99,45.05) 18.05,45.14 18.19,45.27 arc(18.28,45.33) 18.38,45.35 22.29,45.35 arc(22.32,45.35) 22.35,45.33 22.47,45.21 arc(22.56,45.17) 22.64,45.21 arc(22.82,45.21) 22.82,45.03 arc(22.78,44.95) 22.82,44.86 22.99,44.68 23.16,44.68 23.32,44.84 CR1301.4 CR1301.7 25.06,44.84 R1314.2
HDMI3_TX0_P: length 21.5
  L3 w0.05: v1(25.57,44.32) 25.75,44.5 26.46,44.5 27.06,45.1 arc(27.08,45.12) 27.11,45.12 31.92,45.12 arc(32.38,45.3) 32.6,45.74 arc(32.73,45.86) 32.85,45.73 32.85,45.42 arc(33.15,45.12) 33.45,45.42 33.45,45.78 arc(33.58,45.91) 33.7,45.78 33.7,45.42 arc(34,45.12) 34.3,45.42 34.3,45.73 arc(34.43,45.86) 34.55,45.73 34.55,45.42 arc(34.85,45.12) 35.15,45.42 35.15,45.73 arc(35.19,45.82) 35.28,45.86 38.83,45.86 arc(38.93,45.84) 39.01,45.78 arc(39.07,45.7) 39.09,45.6 39.09,45.53 arc(39.2,45.26) 39.48,45.15 39.7,45.15 arc(39.79,45.16) 39.87,45.22 40.53,45.88 40.53,46.67 v2(40.69,46.83)
  L6 w0.05: v2(40.69,46.83) 40.53,46.67 40.53,46.57 v3(40.73,46.37)
HDMI3_TX0_P_CONN: length 20.7
  TOP w0.062: J1300.7 13.35,46.41 13.35,45.89 13.98,45.26 13.98,43.15 arc(14,43.05) 14.05,42.96 14.14,42.88 arc(14.22,42.82) 14.32,42.8 14.37,42.8 arc(14.59,42.89) 14.68,43.11 14.68,44.2 arc(14.87,44.39) 15.07,44.2 15.07,43.11 arc(15.16,42.89) 15.38,42.8 17.82,42.8 arc(17.92,42.82) 18.01,42.88 18.08,42.95 arc(18.14,43.04) 18.16,43.14 18.16,44.95 arc(18.17,44.98) 18.18,45 18.32,45.14 arc(18.35,45.16) 18.38,45.17 22.21,45.17 arc(22.24,45.16) 22.27,45.14 22.91,44.5 23.16,44.5 23.32,44.34 CR1301.5 CR1301.6 25.07,44.34 R1312.2
HDMI3_TX1_N: length 21.4
  L3 w0.05: v1(25.57,43.32) 25.57,43.3 25.74,43.12 26.18,43.12 26.29,43.23 arc(26.33,43.31) 26.29,43.4 arc(26.26,43.48) 26.29,43.57 26.3,43.57 arc(26.38,43.61) 26.47,43.57 arc(26.55,43.54) 26.64,43.57 27.61,44.55 35.54,44.55 arc(35.63,44.58) 35.66,44.67 35.66,45.01 arc(35.96,45.31) 36.26,45.01 36.26,44.67 arc(36.3,44.58) 36.39,44.55 40.16,44.55 42.41,46.79 42.41,47.08 v2(42.24,47.24)
  L6 w0.05: v3(42.19,46.38) 42.41,46.59 42.41,47.08 v2(42.24,47.24)
HDMI3_TX1_N_CONN: length 20.8
  TOP w0.062: J1300.6 12.28,46.67 11.78,46.17 11.78,45.68 12.02,45.45 12.92,45.45 13.48,44.89 13.48,42.56 13.69,42.35 19.82,42.35 arc(19.91,42.38) 19.95,42.47 19.95,42.64 arc(20.04,42.85) 20.25,42.94 20.26,42.94 arc(20.48,42.85) 20.57,42.63 20.57,42.47 arc(20.69,42.35) 20.82,42.47 20.82,42.64 arc(20.91,42.85) 21.12,42.94 21.13,42.94 arc(21.35,42.85) 21.44,42.63 21.44,42.47 arc(21.48,42.38) 21.56,42.35 21.97,42.35 arc(22,42.35) 22.02,42.37 22.23,42.58 arc(22.27,42.67) 22.23,42.75 arc(22.23,42.93) 22.41,42.93 arc(22.49,42.89) 22.58,42.93 22.79,43.13 23.16,43.13 23.32,43.29 CR1300.1 CR1300.10 25.06,43.29 R1311.2
HDMI3_TX1_P: length 21.4
  L3 w0.05: v1(25.57,42.76) 25.75,42.95 26.26,42.95 27.68,44.37 35.54,44.37 arc(35.75,44.46) 35.84,44.67 35.84,45.01 arc(35.96,45.14) 36.09,45.01 36.09,44.67 arc(36.18,44.46) 36.39,44.37 40.23,44.37 42.58,46.72 42.58,47.08 v2(42.74,47.24)
  L6 w0.05: v2(42.74,47.24) 42.58,47.08 42.58,46.59 v3(42.79,46.38)
HDMI3_TX1_P_CONN: length 20.8
  TOP w0.062: J1300.4 11.13,46.63 11.6,46.17 11.6,45.61 11.94,45.26 12.84,45.26 13.29,44.81 13.29,42.48 13.62,42.16 19.82,42.16 arc(20.04,42.25) 20.14,42.47 20.14,42.64 arc(20.17,42.72) 20.25,42.75 20.26,42.75 arc(20.35,42.72) 20.38,42.63 20.38,42.47 arc(20.69,42.16) 21.01,42.47 21.01,42.64 arc(21.04,42.72) 21.12,42.75 21.13,42.75 arc(21.22,42.72) 21.25,42.63 21.25,42.47 arc(21.34,42.25) 21.56,42.16 21.97,42.16 arc(22.07,42.18) 22.15,42.24 22.86,42.95 23.16,42.95 23.32,42.79 CR1300.2 CR1300.9 25.06,42.79 R1310.2
HDMI3_TX2_N: length 21.4
  L3 w0.05: v1(25.57,41.82) 25.76,41.63 25.87,41.63 26.01,41.77 arc(26.05,41.86) 26.01,41.95 26.01,41.95 arc(26.01,42.13) 26.18,42.13 26.19,42.12 arc(26.28,42.09) 26.37,42.12 27.98,43.74 40.73,43.74 43.57,46.57 43.57,46.7 v2(43.41,46.86)
  L6 w0.05: v3(43.37,46.38) 43.57,46.58 43.57,46.7 v2(43.41,46.86)
  BOTTOM w0.062: R1105.2 v3(43.37,46.38)
HDMI3_TX2_N_CONN: length 20.7
  TOP w0.062: J1300.3 10.07,46.41 10.07,46.16 arc(10.05,45.99) 10,45.82 arc(9.92,45.69) 9.83,45.58 9.43,45.18 arc(9.25,44.91) 9.19,44.59 9.19,43.99 arc(9.25,43.68) 9.43,43.41 9.81,43.02 arc(9.91,42.98) 10.01,43.02 arc(10.1,43.06) 10.2,43.02 10.22,43 arc(10.26,42.9) 10.22,42.8 arc(10.18,42.71) 10.22,42.61 10.34,42.5 arc(11.29,41.86) 12.42,41.63 23.1,41.63 23.26,41.79 CR1300.4 CR1300.7 25.06,41.79 R1309.2
HDMI3_TX2_P: length 21.4
  L3 w0.05: v2(43.91,46.86) 43.75,46.7 43.75,46.5 40.81,43.56 28.05,43.56 25.95,41.45 25.75,41.45 v1(25.57,41.27)
  L6 w0.05: v2(43.91,46.86) 43.75,46.7 43.75,46.59 v3(43.95,46.38)
  BOTTOM w0.062: R1103.2 v3(43.95,46.38)
HDMI3_TX2_P_CONN: length 20.7
  TOP w0.062: R1300.2 25.06,41.29 CR1300.6 CR1300.5 23.32,41.29 23.16,41.45 12.42,41.45 arc(11.22,41.69) 10.21,42.36 9.3,43.27 arc(9.08,43.6) 9,43.99 9,44.59 arc(9.08,44.98) 9.3,45.31 9.69,45.71 arc(9.77,45.8) 9.82,45.9 arc(9.87,46.03) 9.88,46.16 9.88,46.41 J1300.1
HDMI_5V: length 48.9
  TOP w0.25: D1200.1 v1(28.72,36.4)
  TOP w0.3: v1(27.93,14.08) 27.9,14.08 27.17,13.34 D900.1
  L3 w0.25: v1(28.72,36.4) 29.47,36.4 v2(29.48,36.39)
  L3 w0.3: v1(27.93,14.08) 28.71,14.08 v2(28.72,14.07)
  L5 w0.5: v2(29.48,42.89) 29.83,43.24 v2(29.83,50.17) ; v2(29.48,36.39) 29.48,31.55 26.1,28.16 26.1,16.69 v2(28.72,14.07)
  L6 w0.25: v2(29.48,42.89) 29.41,42.96 29.41,44.94 v3(29.32,45.02)
  L6 w0.5: v2(29.48,42.89) v2(29.48,36.39)
  vias: v2(46.74,50.73) v3(45.22,55.92) v3(45.54,55.92)
HDRV1: length 16.3
  L6 w0.2: v3(104.63,32.85) 107.45,35.66 v3(107.45,43.5)
  BOTTOM w0.2: Q700.4 108.75,43 108.25,43.5 v3(107.45,43.5)
HDRV2: length 10.5
  L6 w0.2: v3(97.3,36.98) v3(98.78,36.98)
  BOTTOM w0.2: v3(98.78,36.98) 101.13,34.62 U700.27 ; Q702.4 v3(97.3,36.98)
HSIN_C: length 2
  TOP w0.072: U1500.14 33.6,107.59 33.48,107.47 33.48,107.28 34.12,106.64 34.12,106.43 R1513.2
HSIP_C: length 2
  TOP w0.072: R1511.2 33.96,106.42 33.96,106.57 33.32,107.21 33.32,107.48 33.2,107.6 U1500.13
HSON_C: length 2
  TOP w0.072: C1502.1 36.34,108 36.1,108 35.5,108.6 35.24,108.6 35.12,108.72 U1500.18
HSOP_C: length 2
  TOP w0.072: C1503.1 36.33,107.84 36.03,107.84 35.43,108.43 35.24,108.43 35.12,108.32 U1500.17
HSPK_PA_PDN_3V3: length 8.5
  L6 w0.1: v3(74.55,97.65) 77.09,97.65 v3(77.39,97.35)
  BOTTOM w0.1: U2800.12 78.71,98.39 78.11,97.8 77.87,97.8 77.42,97.35 v3(77.39,97.35) ; R2820.2 72.1,98.25 73.25,98.25 73.85,97.65 v3(74.55,97.65)
HUB1_AVDD: length 24
  L3 w0.3: v2(139.54,48.77) 136.54,48.77 v2(136.39,48.62) ; v2(133.26,48.62) 133.26,48.65 132.99,48.92 131.4,48.92 131.4,48.92 130.83,48.92 130.44,49.32 v2(129.37,49.32)
  L5 w0.3: v2(136.39,48.62) 136.36,48.65 133.29,48.65 v2(133.26,48.62)
  L6 w0.3: v3(128.96,54.55) 129.37,54.15 v2(129.37,49.32) ; v3(135.97,47.72) 135.97,47.77 136.39,48.19 v2(136.39,48.62) ; v3(139.72,51.91) 139.72,48.95 v2(139.54,48.77) ; v3(132.7,48.6) 133.24,48.6 v2(133.26,48.62)
  BOTTOM w0.25: C2508.1 C2516.1 133.45,48.6 U2503.14
  BOTTOM w0.3: B2500.2 128.75,54.67 C2507.1 ; R2508.2 v3(135.97,47.72)
HUB_USB1_DM: length 11.7
  L3 w0.057: v1(170.24,90.74) 170.11,90.6 170.04,90.6 169.81,90.6 168.18,88.98 160.81,88.98 160.22,89.57 159.73,89.57 v1(159.61,89.68)
HUB_USB1_DM_CON: length 26.9
  TOP w0.072: R2741.2 170.74,90.79 170.94,90.58 171.81,90.58 172.16,90.93 TVS1907.1
  L3 w0.057: v1(172.15,90.85) 172.42,90.58 172.44,90.56 172.53,90.56 173.15,89.93 173.35,89.93 arc(173.43,89.97) 173.46,90.05 173.46,90.16 arc(173.58,90.27) 173.69,90.16 173.69,90.05 arc(173.72,89.97) 173.8,89.93 174.05,89.93 177.67,86.31 179.68,86.31 180.94,85.05 182,85.05 182.47,84.58 183.03,84.58 183.35,84.9 183.35,85.15 183.29,85.22 183.18,85.22 v2(183.02,85.05)
  L6 w0.057: v2(183.02,85.05) 183.18,85.22 183.2,85.22 183.69,85.22 184.05,85.57 184.33,85.57 185.08,84.83 185.76,84.83 186.51,85.57 187.53,85.57 188.28,84.83 188.96,84.83 189.71,85.57 190.06,85.57 190.12,85.51 J1900.U2
  BOTTOM w0.072: 190.7,84.66 190.69,84.66 J1900.U2
HUB_USB1_DP: length 11.6
  L3 w0.057: v1(170.24,90.31) 170.11,90.44 169.88,90.44 168.25,88.81 160.74,88.81 160.64,88.91 160.15,89.4 159.73,89.4 v1(159.61,89.28)
HUB_USB1_DP_CON: length 26.9
  TOP w0.072: TVS1909.1 172.12,90.07 171.76,90.42 170.92,90.42 170.73,90.24 R2737.2
  L3 w0.057: v1(172.11,90.17) 172.36,90.39 172.46,90.39 173.09,89.77 173.22,89.77 173.98,89.77 177.61,86.14 177.74,86.14 179.61,86.14 180.87,84.88 181.93,84.88 182.4,84.41 183.1,84.41 183.52,84.83 183.52,85.22 183.36,85.38 183.19,85.38 v2(183.02,85.55)
  L6 w0.057: v2(183.02,85.55) 183.19,85.38 183.49,85.38 183.49,85.38 183.62,85.38 183.98,85.74 184.33,85.74 185.08,86.48 185.76,86.48 186.51,85.74 187.53,85.74 188.28,86.48 188.96,86.48 189.71,85.74 190.06,85.74 190.12,85.8 J1900.U3
  BOTTOM w0.072: 190.73,86.68 190.71,86.66 J1900.U3
HUB_USB1_RX_M: length 11.2
  L3 w0.057: v1(169.93,89.06) 169.76,88.89 169.31,88.89 168.08,87.65 160.86,87.65 160.14,88.37 159.73,88.37 v1(159.61,88.48)
HUB_USB1_RX_M_CON: length 21.8
  TOP w0.072: v1(171.98,89.09) CR1904.10 CR1904.1 170.4,89.09 CMC2700.2
  L3 w0.057: v2(172.84,89.09) 172.67,88.92 172.15,88.92 v1(171.98,89.09)
  L6 w0.057: v2(172.84,89.09) 173,88.92 173.47,88.92 arc(173.67,88.84) 173.75,88.64 173.75,88.38 arc(173.86,88.27) 173.98,88.38 173.98,88.64 arc(174.06,88.84) 174.26,88.92 179.55,88.92 180.79,87.69 183.74,87.69 184.87,88.81 185.97,88.81 186.64,88.14 187.61,88.14 188.21,88.74 188.56,88.74 188.62,88.8 J1900.U5
HUB_USB1_RX_P: length 11.2
  L3 w0.057: v1(159.61,88.08) 159.73,88.2 160.07,88.2 160.79,87.48 168.15,87.48 169.38,88.72 169.79,88.72 v1(169.93,88.58)
HUB_USB1_RX_P_CON: length 21.8
  TOP w0.072: CMC2700.3 170.38,88.59 CR1904.2 v1(171.98,88.59)
  L3 w0.057: v1(171.98,88.59) 172.14,88.75 172.67,88.75 v2(172.84,88.59)
  L6 w0.057: J1900.U6 188.62,88.51 188.56,88.57 188.28,88.57 187.68,87.97 186.58,87.97 185.9,88.64 184.94,88.64 183.81,87.52 180.72,87.52 179.48,88.75 174.26,88.75 arc(174.18,88.72) 174.15,88.64 174.15,88.38 arc(173.86,88.1) 173.58,88.38 173.58,88.64 arc(173.55,88.72) 173.47,88.76 173,88.76 v2(172.84,88.59)
HUB_USB1_TX_M: length 9.3
  L3 w0.057: v1(169.94,87.6) 169.79,87.46 169.29,87.46 168.61,86.77 163.17,86.77 arc(162.97,86.69) 162.89,86.49 162.89,86.44 arc(162.77,86.32) 162.66,86.44 162.66,86.55 arc(162.59,86.7) 162.44,86.77 161.83,86.77 v1(161.61,86.99)
HUB_USB1_TX_M_CON: length 21.7
  TOP w0.072: v1(171.98,87.59) CR1904.4 170.39,87.59 CMC2703.2
  L3 w0.057: v1(171.98,87.59) 172.14,87.42 172.62,87.42 v2(172.79,87.6)
  L6 w0.057: v2(172.79,87.6) 172.95,87.44 176.69,87.44 177.73,86.4 179.6,86.4 180.91,85.1 181.96,85.1 184.26,82.8 185.99,82.8 186.5,83.31 187.57,83.31 188.14,82.74 188.56,82.74 188.62,82.8 J1900.U8
HUB_USB1_TX_P: length 9.3
  TOP w0.072: C2412.2 v1(161.61,86.39)
  L3 w0.057: v1(161.61,86.39) 161.83,86.6 162.44,86.6 arc(162.48,86.59) 162.49,86.55 162.49,86.44 arc(162.77,86.16) 163.05,86.44 163.05,86.49 arc(163.09,86.57) 163.17,86.6 168.68,86.6 169.36,87.29 169.77,87.29 v1(169.94,87.12)
HUB_USB1_TX_P_CON: length 21.7
  TOP w0.072: v1(171.98,87.09) CR1904.5 170.41,87.09 CMC2703.3
  L3 w0.057: v2(172.79,87.1) 172.63,87.26 172.14,87.26 v1(171.98,87.09)
  L6 w0.057: v2(172.79,87.1) 172.97,87.27 176.62,87.27 177.66,86.23 179.54,86.23 180.84,84.93 181.9,84.93 184.19,82.64 186.06,82.64 186.57,83.14 187.5,83.14 188.07,82.57 188.56,82.57 188.62,82.51 J1900.U9
HUB_USB2_DM: length 8
  L3 w0.057: v1(167.07,94.23) 166.93,94.09 166.28,94.09 165.35,93.16 159.72,93.16 v1(159.6,93.28)
HUB_USB2_DM_CON: length 30.6
  TOP w0.072: R2744.2 167.57,94.28 167.57,94.25 167.71,94.1 168.59,94.1 168.98,94.48 TVS1911.1
  L3 w0.057: v1(168.98,94.58) 168.98,94.19 168.89,94.1 168.6,94.1 168.52,94.17 168.52,94.6 168.81,94.89 169.54,94.89 169.78,94.65 171.14,94.65 arc(171.22,94.61) 171.25,94.53 171.25,94.41 arc(171.37,94.29) 171.48,94.41 171.48,94.53 arc(171.52,94.61) 171.6,94.65 178.22,94.65 180.03,92.84 181.92,92.84 183.57,91.18 183.57,85.93 183.94,85.56 184.34,85.56 185.08,84.83 185.76,84.83 186.52,85.59 186.85,85.59 186.92,85.51 J1900.U11
HUB_USB2_DP: length 8
  L3 w0.057: v1(167.09,93.79) 166.96,93.92 166.34,93.92 165.42,93 165.28,93 159.72,93 v1(159.6,92.88)
HUB_USB2_DP_CON: length 30.6
  TOP w0.072: R2747.2 167.56,93.77 167.73,93.94 168.6,93.94 168.98,93.56 TVS1913.1
  L3 w0.057: v1(168.98,93.46) 168.98,93.85 168.9,93.93 168.53,93.93 168.36,94.11 168.36,94.67 168.74,95.05 169.61,95.05 169.85,94.81 178.29,94.81 180.1,93 181.99,93 183.74,91.25 183.74,86 184,85.73 184.32,85.73 185.08,86.48 185.76,86.48 186.49,85.75 186.84,85.75 186.92,85.84 J1900.U12
HUB_USB2_RX_M: length 11.5
  L3 w0.057: v1(169.94,93.93) 169.77,93.75 169.67,93.75 169.5,93.58 169.5,93.09 169.38,92.97 166.63,92.97 166.09,92.43 160.81,92.43 160.35,91.97 159.73,91.97 v1(159.61,92.09)
HUB_USB2_RX_M_CON: length 23.1
  TOP w0.072: R2738.2 171.18,93.96 CR1906.1 CR1906.10 172.23,93.95 172.39,93.79 172.95,93.79 173.52,93.21 173.88,93.21 v6(174.08,93.41)
  BOTTOM w0.072: J1900.U14 184.45,88.69 183.83,88.69 183.72,88.8 183.72,91.34 182.02,93.04 180.44,93.04 179.3,94.17 178.74,94.17 arc(178.52,94.08) 178.43,93.87 178.43,93.36 arc(178.29,93.21) 178.14,93.36 178.14,93.87 arc(177.84,94.17) 177.53,93.87 177.53,93.36 arc(177.39,93.21) 177.24,93.36 177.24,93.87 arc(177.15,94.08) 176.94,94.17 175.38,94.17 174.42,93.21 174.27,93.21 v6(174.08,93.41)
HUB_USB2_RX_P: length 11.5
  L3 w0.057: v1(169.94,93.45) 169.81,93.59 169.74,93.59 169.67,93.51 169.67,93.02 169.45,92.8 166.69,92.8 166.15,92.26 160.88,92.26 160.42,91.8 159.73,91.8 v1(159.61,91.69)
HUB_USB2_RX_P_CON: length 23.1
  TOP w0.072: v6(174.08,92.86) 173.88,93.05 173.46,93.05 172.88,93.63 172.39,93.63 172.22,93.45 CR1906.9 CR1906.2 170.41,93.45 CMC2702.3
  BOTTOM w0.072: v6(174.08,92.86) 174.27,93.05 174.49,93.05 175.45,94.01 176.94,94.01 arc(177.04,93.97) 177.08,93.87 177.08,93.36 arc(177.39,93.05) 177.69,93.36 177.69,93.87 arc(177.84,94.01) 177.98,93.87 177.98,93.36 arc(178.29,93.05) 178.59,93.36 178.59,93.87 arc(178.63,93.97) 178.74,94.01 179.24,94.01 180.37,92.88 181.96,92.88 183.56,91.27 183.56,88.73 183.76,88.52 184.55,88.52 J1900.U15
HUB_USB2_TX_M: length 9.1
  TOP w0.072: C2409.2 v1(161.72,90.96)
  L3 w0.057: v1(169.93,92.43) 169.93,92.33 169.88,92.27 169.73,92.27 169.72,92.26 167.39,92.26 165.89,90.76 161.92,90.76 v1(161.72,90.96)
HUB_USB2_TX_M_CON: length 23.1
  TOP w0.072: CMC2711.2 170.41,92.45 CR1906.4 CR1906.7 172.2,92.45 172.37,92.28 172.63,92.28 172.86,92.05 173.08,92.05 v6(173.28,92.25)
  BOTTOM w0.072: J1900.U17 184.47,82.7 183.52,82.7 182.72,83.5 182.72,89.33 181.97,90.08 180.58,90.08 178.98,91.68 175.35,91.68 174.98,92.05 173.48,92.05 v6(173.28,92.25)
HUB_USB2_TX_P: length 9
  L3 w0.057: v1(161.72,90.39) 161.92,90.59 165.96,90.59 167.46,92.1 169.79,92.1 169.79,92.1 169.88,92.1 169.93,92.05 v1(169.93,91.95)
HUB_USB2_TX_P_CON: length 23
  TOP w0.072: CMC2711.3 170.39,91.95 CR1906.5 CR1906.6 172.21,91.95 172.38,92.12 172.56,92.12 172.79,91.89 173.08,91.89 v6(173.28,91.7)
  BOTTOM w0.072: J1900.U18 184.53,82.54 183.46,82.54 182.56,83.44 182.56,89.27 181.91,89.92 180.51,89.92 178.92,91.52 175.42,91.52 175.28,91.52 174.91,91.88 173.46,91.88 v6(173.28,91.7)
HUB_USB3_DM: length 31.2
  L3 w0.057: v2(157.55,94.81) 157.56,94.81 157.73,94.64 157.73,94.36 v1(157.61,94.24) ; v2(157.67,111) 157.84,111.17 157.84,111.33 158.07,111.56 167.72,111.56 169.45,109.83 170.32,109.83 v1(170.48,109.99)
  L6 w0.057: v2(157.55,94.81) 157.56,94.81 157.72,94.97 157.72,96.07 arc(157.74,96.16) 157.79,96.23 158.02,96.46 arc(158.12,96.62) 158.16,96.8 158.16,107.62 arc(158.16,107.65) 158.14,107.67 157.86,107.95 arc(157.84,107.98) 157.84,108.01 157.84,110.81 arc(157.83,110.84) 157.81,110.86 v2(157.67,111)
HUB_USB3_DM_CON: length 25.6
  TOP w0.072: v1(172.4,110.09) 172.4,110.09 172.4,110.18 172.04,109.82 171.15,109.82 170.96,110.02 R2711.2
  L3 w0.057: v1(172.4,110.09) 172.66,109.83 172.88,109.83 arc(172.96,109.86) 173,109.94 173,110.2 arc(173.11,110.31) 173.23,110.2 173.23,109.94 arc(173.26,109.86) 173.34,109.83 173.77,109.83 175.33,108.27 179.53,108.27 180.83,106.98 182.34,106.98 182.59,106.73 182.91,106.73 183.19,107.01 183.19,107.15 183.09,107.25 182.89,107.25 182.78,107.14 v2(182.78,107.11)
  L6 w0.057: J1901.U2 190.12,107.38 190.06,107.43 189.62,107.43 188.96,106.78 188.28,106.78 187.53,107.52 186.51,107.52 185.76,106.78 185.08,106.78 184.34,107.51 183.8,107.51 183.79,107.52 183.51,107.52 183.27,107.28 182.94,107.28 v2(182.78,107.11)
  BOTTOM w0.072: 190.71,106.6 190.7,106.61 J1901.U2
HUB_USB3_DP: length 31.2
  L3 w0.057: v2(158.05,94.81) 158.06,94.81 158.06,94.81 157.89,94.64 157.89,94.36 158.01,94.25 v1(158.01,94.24) ; v1(170.48,109.52) 170.33,109.66 169.38,109.66 167.65,111.4 158.13,111.4 158,111.26 158,111.17 v2(158.17,111)
  L6 w0.057: v2(158.17,111) 158,110.84 158,108.04 158.33,107.72 158.33,96.8 arc(158.28,96.55) 158.14,96.35 157.91,96.12 arc(157.9,96.09) 157.89,96.07 157.89,95.69 arc(157.92,95.61) 158,95.58 158.02,95.58 arc(158.14,95.46) 158.02,95.35 158,95.35 arc(157.92,95.31) 157.89,95.23 157.89,94.97 158.05,94.81 v2(158.05,94.81)
HUB_USB3_DP_CON: length 25.7
  TOP w0.072: v1(172.4,109.4) 172.4,109.4 172.4,109.31 172.06,109.66 171.13,109.66 170.96,109.48 R2714.2
  L3 w0.057: v2(182.78,107.61) 182.97,107.42 183.16,107.42 183.36,107.22 183.36,106.94 182.98,106.56 182.52,106.56 182.27,106.81 180.76,106.81 179.46,108.1 175.26,108.1 173.7,109.66 172.66,109.66 v1(172.4,109.4)
  L6 w0.057: J1901.U3 190.12,107.7 190.02,107.6 189.8,107.6 188.96,108.43 188.28,108.43 187.53,107.69 186.51,107.69 185.76,108.43 185.08,108.43 184.33,107.69 183.8,107.69 183.79,107.68 183.44,107.68 183.2,107.45 182.94,107.45 v2(182.78,107.61)
  BOTTOM w0.072: 190.76,108.59 190.74,108.61 J1901.U3
HUB_USB3_RX_M: length 34.5
  L3 w0.057: v1(155.21,94.08) 155.33,94.2 155.33,94.55 v2(155.16,94.71) ; v2(155.16,112.69) 155.33,112.86 155.33,113.1 155.57,113.34 168.88,113.34 169.19,113.04 170.03,113.04 v1(170.19,113.2)
  L6 w0.057: v2(155.16,94.71) 155.36,94.91 155.36,94.91 155.33,94.94 155.33,112.52 v2(155.16,112.69)
HUB_USB3_RX_M_CON: length 23.2
  TOP w0.072: CMC2704.2 170.65,113.19 CR1905.1 CR1905.10 v1(172.23,113.19)
  L3 w0.057: v1(172.23,113.19) 172.4,113.02 172.74,113.02 v2(172.91,113.19)
  L6 w0.057: J1901.U5 188.62,110.75 188.56,110.69 188.08,110.69 187.95,110.69 187.25,109.99 186.71,109.99 185.98,110.71 185.85,110.71 183.65,110.71 182.61,109.67 180.73,109.67 179.52,110.88 176.85,110.88 arc(176.65,110.8) 176.57,110.6 176.57,110.32 arc(176.46,110.21) 176.34,110.32 176.34,110.6 arc(176.26,110.8) 176.06,110.88 175.26,110.88 174.55,111.6 174.55,112.76 174.28,113.02 173.07,113.02 v2(172.91,113.19)
HUB_USB3_RX_P: length 34.5
  L3 w0.057: v2(155.66,94.71) 155.49,94.55 155.49,94.2 v1(155.61,94.08) ; v2(155.66,112.69) 155.49,112.86 155.49,113.03 155.64,113.18 168.82,113.18 169.12,112.87 170.04,112.87 v1(170.19,112.72)
  L6 w0.057: v2(155.66,112.69) 155.5,112.53 155.5,95.65 arc(155.53,95.57) 155.61,95.54 155.63,95.54 arc(155.75,95.42) 155.63,95.31 155.61,95.31 arc(155.53,95.28) 155.5,95.2 155.5,95.01 155.66,94.84 v2(155.66,94.71)
HUB_USB3_RX_P_CON: length 23.2
  TOP w0.072: CMC2704.3 170.67,112.69 CR1905.2 v1(172.23,112.69)
  L3 w0.057: v2(172.91,112.69) 172.75,112.85 172.4,112.85 v1(172.23,112.69)
  L6 w0.057: v2(172.91,112.69) 173.07,112.86 174.21,112.86 174.38,112.69 174.38,111.53 175.19,110.71 176.06,110.71 arc(176.14,110.68) 176.17,110.6 176.17,110.32 arc(176.46,110.04) 176.74,110.32 176.74,110.6 arc(176.77,110.68) 176.85,110.71 179.45,110.71 180.67,109.5 182.68,109.5 183.72,110.54 185.92,110.54 186.64,109.82 187.32,109.82 188.02,110.52 188.56,110.52 188.62,110.46 J1901.U6
HUB_USB3_TX_M: length 32.5
  L3 w0.057: v1(156.91,96.2) 157.06,96.2 157.11,96.26 157.11,96.34 157.11,96.82 v2(156.95,96.98) ; v2(156.5,111.98) 156.67,112.15 156.67,112.3 156.82,112.46 168.64,112.46 169.59,111.5 170.03,111.5 v1(170.2,111.67)
  L6 w0.057: v2(156.5,111.98) 156.67,111.82 156.67,103.19 157.11,102.74 157.11,100.44 arc(157.08,100.36) 157,100.32 156.95,100.32 arc(156.67,100.04) 156.95,99.76 157.06,99.76 arc(157.1,99.75) 157.11,99.71 157.11,99.65 arc(157.08,99.57) 157,99.53 156.95,99.53 arc(156.67,99.25) 156.95,98.97 157.06,98.97 arc(157.1,98.96) 157.11,98.92 157.11,98.86 arc(157.08,98.78) 157,98.74 156.95,98.74 arc(156.67,98.46) 156.95,98.18 157.06,98.18 arc(157.1,98.17) 157.11,98.13 157.11,97.15 v2(156.95,96.98)
HUB_USB3_TX_M_CON: length 23.2
  TOP w0.072: CMC2707.2 170.67,111.69 CR1905.4 v1(172.23,111.69)
  L3 w0.057: v1(172.23,111.69) 172.39,111.52 172.76,111.52 v2(172.92,111.69)
  L6 w0.057: v2(172.92,111.69) 173.09,111.52 173.31,111.52 176.58,108.26 176.58,106.92 177.81,105.68 179.79,105.68 180.87,104.6 185,104.6 185.01,104.6 185.83,104.6 185.84,104.6 185.89,104.6 186.48,105.19 187.65,105.19 188.15,104.69 188.56,104.69 188.62,104.75 J1901.U8
HUB_USB3_TX_P: length 32.5
  L3 w0.057: v1(157.48,96.2) 157.34,96.2 157.28,96.26 157.28,96.34 157.28,96.82 v2(157.45,96.98) ; v2(157,111.98) 156.83,112.15 156.83,112.23 156.89,112.29 168.57,112.29 169.52,111.33 170.06,111.33 v1(170.2,111.19)
  L6 w0.057: v2(157.45,96.98) 157.28,97.15 157.28,97.35 arc(157.31,97.43) 157.39,97.47 157.41,97.47 arc(157.53,97.58) 157.41,97.69 157.39,97.69 arc(157.31,97.73) 157.28,97.81 157.28,98.13 arc(157.21,98.28) 157.06,98.35 156.95,98.35 arc(156.83,98.46) 156.95,98.58 157,98.58 arc(157.2,98.66) 157.28,98.86 157.28,98.92 arc(157.21,99.07) 157.06,99.14 156.95,99.14 arc(156.83,99.25) 156.95,99.37 157,99.37 arc(157.2,99.45) 157.28,99.65 157.28,99.71 arc(157.21,99.86) 157.06,99.93 156.95,99.93 arc(156.83,100.04) 156.95,100.16 157,100.16 arc(157.2,100.24) 157.28,100.44 157.28,102.81 156.83,103.26 156.83,111.82 v2(157,111.98)
HUB_USB3_TX_P_CON: length 23.2
  TOP w0.072: v1(172.23,111.19) CR1905.5 CMC2707.3
  L3 w0.057: v1(172.23,111.19) 172.39,111.35 172.76,111.35 v2(172.92,111.19)
  L6 w0.057: J1901.U9 188.62,104.46 188.56,104.52 188.08,104.52 187.58,105.02 186.55,105.02 185.96,104.43 185.77,104.43 185.76,104.43 185.08,104.43 185.07,104.43 180.8,104.43 179.72,105.52 177.74,105.52 176.41,106.85 176.41,108.19 173.24,111.35 173.09,111.35 v2(172.92,111.19)
HUB_USB4_DM: length 37.8
  L3 w0.057: v2(151.57,115.26) 151.73,115.43 151.73,115.58 152.04,115.89 152.18,115.89 165.61,115.89 166.37,116.65 167.09,116.65 v1(167.21,116.76) ; v2(151.57,95.32) 151.56,95.32 151.56,95.3 151.73,95.14 151.73,94.2 v1(151.61,94.08)
  L6 w0.057: v2(151.57,115.26) 151.73,115.1 151.73,95.47 151.56,95.3 151.56,95.32 v2(151.57,95.32)
HUB_USB4_DM_CON: length 30.7
  TOP w0.072: v1(169.11,117.12) 169.11,117.03 168.73,116.65 167.91,116.65 167.72,116.84 R2717.2
  L3 w0.057: v1(169.11,117.12) 169.11,116.7 169.06,116.64 168.85,116.64 168.75,116.74 168.75,117.33 168.98,117.56 169.27,117.56 arc(169.35,117.53) 169.38,117.45 169.38,117.26 arc(169.5,117.15) 169.61,117.26 169.61,117.45 arc(169.64,117.53) 169.72,117.56 170.35,117.56 171.12,116.79 176.18,116.79 178.38,114.6 182.01,114.6 183.32,113.29 183.32,108.21 184.04,107.48 184.33,107.48 185.03,106.78 185.76,106.78 186.49,107.51 186.88,107.51 186.92,107.46 J1901.U11
HUB_USB4_DP: length 37.9
  L3 w0.057: v1(152.01,94.08) 151.89,94.2 151.89,95.14 152.06,95.3 152.06,95.3 v2(152.07,95.3) ; v2(152.07,115.26) 151.9,115.43 151.9,115.51 152.11,115.72 165.68,115.72 166.44,116.48 167.09,116.48 v1(167.22,116.36)
  L6 w0.057: v2(152.07,95.3) 152.06,95.3 152.06,95.3 151.89,95.47 151.89,95.82 arc(151.93,95.9) 152.01,95.94 152.05,95.94 arc(152.17,96.05) 152.05,96.16 152.01,96.16 arc(151.93,96.2) 151.89,96.28 151.89,115.09 v2(152.07,115.26)
HUB_USB4_DP_CON: length 30.7
  TOP w0.072: v1(169.11,116) 169.11,116.1 168.73,116.48 167.92,116.48 167.72,116.28 R2720.2
  L3 w0.057: v1(169.11,116) 169.11,116.42 169.06,116.48 168.78,116.48 168.59,116.67 168.59,117.4 168.91,117.73 170.42,117.73 171.19,116.96 176.25,116.96 178.45,114.76 182.08,114.76 183.48,113.35 183.48,108.28 184.11,107.65 184.29,107.65 185.08,108.43 185.76,108.43 186.52,107.67 186.85,107.67 186.92,107.75 J1901.U12
HUB_USB4_RX_M: length 39.3
  L3 w0.057: v2(152.76,94.85) 152.93,94.68 152.93,94.2 v1(152.81,94.08) ; v2(152.78,114.38) 152.96,114.57 152.96,114.85 153.19,115.07 168.99,115.07 169.71,115.8 169.71,116.27 169.88,116.43 169.99,116.43 v1(170.18,116.62)
  L6 w0.057: v2(152.78,114.38) 152.79,114.38 152.96,114.21 152.96,95.29 152.93,95.26 152.93,95.01 v2(152.76,94.85)
HUB_USB4_RX_M_CON: length 23.4
  TOP w0.072: v6(174.12,116.15) 173.93,115.96 173.57,115.96 173.09,116.44 172.63,116.44 172.47,116.6 CR1907.10 CR1907.1 170.7,116.6 R2712.2
  BOTTOM w0.072: v6(174.12,116.15) 174.32,115.96 174.74,115.96 174.87,116.08 177.38,116.08 arc(177.6,115.99) 177.69,115.77 177.69,115.08 arc(177.83,114.94) 177.98,115.08 177.98,115.77 arc(178.28,116.08) 178.59,115.77 178.59,115.07 arc(178.73,114.92) 178.88,115.07 178.88,115.77 arc(178.97,115.99) 179.18,116.08 179.51,116.08 180.89,114.7 182.22,114.7 183.73,113.19 183.73,111.05 184.08,110.7 185.31,110.7 185.42,110.81 J1901.U14
HUB_USB4_RX_P: length 39.3
  L3 w0.057: v2(153.26,94.85) 153.09,94.68 153.09,94.2 v1(153.21,94.08) ; v1(170.18,116.14) 170.05,116.26 169.94,116.26 169.88,116.2 169.88,115.73 169.06,114.9 153.26,114.9 153.13,114.78 153.13,114.54 v2(153.29,114.37)
  L6 w0.057: v2(153.26,94.85) 153.09,95.01 153.09,95.19 153.12,95.22 153.12,95.45 arc(153.16,95.53) 153.24,95.57 153.27,95.57 arc(153.38,95.68) 153.27,95.8 153.24,95.8 arc(153.16,95.83) 153.12,95.91 153.12,114.2 v2(153.29,114.37)
HUB_USB4_RX_P_CON: length 23.5
  TOP w0.072: R2715.2 170.64,116.1 CR1907.2 CR1907.9 172.44,116.1 172.62,116.27 173.03,116.27 173.51,115.79 173.93,115.79 v6(174.12,115.6)
  BOTTOM w0.072: J1901.U15 185.42,110.45 185.33,110.54 184.01,110.54 183.56,110.99 183.56,113.13 182.15,114.54 180.82,114.54 179.44,115.92 179.18,115.92 arc(179.08,115.88) 179.04,115.77 179.04,115.07 arc(178.73,114.76) 178.43,115.07 178.43,115.77 arc(178.28,115.92) 178.14,115.77 178.14,115.08 arc(177.83,114.78) 177.53,115.08 177.53,115.77 arc(177.49,115.88) 177.38,115.92 174.93,115.92 174.81,115.79 174.32,115.79 v6(174.12,115.6)
HUB_USB4_TX_M: length 37.7
  L3 w0.057: v2(153.96,96.94) 154.12,96.77 154.12,96.29 154.07,96.23 v1(153.91,96.23) ; v2(153.99,113.5) 154.15,113.65 154.15,113.84 arc(154.15,113.87) 154.17,113.89 154.46,114.18 arc(154.48,114.2) 154.51,114.2 169.11,114.2 arc(169.14,114.21) 169.16,114.22 169.87,114.93 170.01,114.93 v1(170.18,115.11)
  L6 w0.057: v2(153.99,113.5) 154.14,113.35 154.14,101.2 arc(154.11,101.12) 154.03,101.09 153.87,101.09 arc(153.59,100.81) 153.87,100.52 154.03,100.52 arc(154.11,100.49) 154.14,100.42 154.14,100.41 arc(154.11,100.33) 154.03,100.3 153.87,100.3 arc(153.59,100.02) 153.87,99.73 154.03,99.73 arc(154.11,99.7) 154.14,99.63 154.14,99.62 arc(154.11,99.54) 154.03,99.51 153.87,99.51 arc(153.59,99.23) 153.87,98.94 154.03,98.94 arc(154.11,98.91) 154.14,98.84 154.14,98.83 arc(154.11,98.75) 154.03,98.72 153.87,98.72 arc(153.59,98.44) 153.87,98.15 154.03,98.15 arc(154.11,98.12) 154.14,98.05 154.14,97.12 v2(153.96,96.94)
HUB_USB4_TX_M_CON: length 23.4
  TOP w0.072: CMC2709.2 170.64,115.1 CR1907.4 CR1907.7 172.44,115.1 172.63,114.91 173.17,114.91 v6(173.37,115.1)
  BOTTOM w0.072: v6(173.37,115.1) 173.56,114.91 174.05,114.91 175.33,113.63 179.28,113.63 180.77,112.14 182.19,112.14 182.82,111.52 182.82,105.89 184.02,104.69 185.35,104.69 185.42,104.76 J1901.U17
HUB_USB4_TX_P: length 37.7
  L3 w0.057: v2(154.46,96.94) 154.29,96.77 154.29,96.29 154.35,96.23 v1(154.51,96.23) ; v2(154.49,113.48) 154.31,113.65 154.31,113.8 154.52,114.01 arc(154.55,114.03) 154.58,114.03 169.11,114.03 arc(169.2,114.05) 169.28,114.1 169.94,114.77 170.04,114.77 v1(170.18,114.63)
  L6 w0.057: v2(154.49,113.48) 154.33,113.32 arc(154.31,113.29) 154.31,113.27 154.31,101.2 arc(154.22,101) 154.03,100.92 153.87,100.92 arc(153.76,100.81) 153.87,100.69 154.03,100.69 arc(154.23,100.61) 154.31,100.42 154.31,100.41 arc(154.22,100.21) 154.03,100.13 153.87,100.13 arc(153.76,100.02) 153.87,99.9 154.03,99.9 arc(154.23,99.82) 154.31,99.63 154.31,99.62 arc(154.22,99.42) 154.03,99.34 153.87,99.34 arc(153.76,99.23) 153.87,99.11 154.03,99.11 arc(154.23,99.03) 154.31,98.84 154.31,98.83 arc(154.22,98.63) 154.03,98.55 153.87,98.55 arc(153.76,98.44) 153.87,98.32 154.03,98.32 arc(154.23,98.24) 154.31,98.05 154.31,97.82 arc(154.34,97.74) 154.42,97.71 154.44,97.71 arc(154.55,97.59) 154.44,97.48 154.42,97.48 arc(154.34,97.45) 154.31,97.37 154.31,97.09 v2(154.46,96.94)
HUB_USB4_TX_P_CON: length 23.4
  TOP w0.072: CMC2709.3 170.66,114.6 CR1907.5 CR1907.6 172.44,114.6 172.59,114.75 173.17,114.75 v6(173.37,114.55)
  BOTTOM w0.072: v6(173.37,114.55) 173.56,114.75 173.98,114.75 175.26,113.47 179.22,113.47 180.7,111.98 182.13,111.98 182.65,111.45 182.65,105.82 183.95,104.52 185.35,104.52 185.42,104.45 J1901.U18
HUBPCIE14_CLKEQN: length 147.6
  TOP w0.1: J2700.F6 116.13,34.51 115.5,35.15 115.5,36.15 115.48,36.15 115.48,36.15 v1(115.48,36.15) ; v1(32,57.83) R1510.1
  L3 w0.1: v1(115.48,36.15) 115.48,36.15 115.48,36.15 111.76,36.15 111.4,36.52 111.4,37.76 108.59,40.57 76.69,40.57 76.37,40.88 67.55,40.88 67.18,41.25 64.38,41.25 63.98,41.66 57.74,41.66 57.44,41.96 57.15,41.96 56.95,41.76 51.48,41.76 50.58,42.66 50.58,50.05 49.6,51.04 49.6,51.61 44.17,57.04 35.19,57.04 34.56,57.67 32.16,57.67 v1(32,57.83)
HUBPCIE14_REFCLKN: length 131.3
  L3 w0.057: v2(50.39,100.32) 50.19,100.53 50.19,101.07 47.27,103.99 37.48,103.99 34.28,107.18 34.28,107.7 v1(34.4,107.82) ; v2(61.23,52.31) 61.03,52.11 61.03,51.94 61.42,51.56 108.68,51.56 111.61,48.63 113.68,48.63 115.58,46.72 115.58,45.79 115.66,45.71 v1(116.13,45.71)
  L6 w0.057: v2(50.39,100.32) 50.2,100.14 50.2,90 51.02,89.18 51.02,71.3 61.03,61.3 61.03,52.58 61.03,52.52 v2(61.23,52.31)
HUBPCIE14_REFCLKP: length 131.3
  L3 w0.057: v1(114.86,45.71) 115.36,45.71 115.42,45.77 115.42,46.65 113.61,48.46 111.54,48.46 108.61,51.39 61.35,51.39 60.87,51.87 60.87,52.11 v2(60.66,52.31) ; v2(49.84,100.32) 50.02,100.5 50.02,101 47.2,103.82 37.41,103.82 34.11,107.11 34.11,107.7 v1(34,107.82)
  L6 w0.057: v2(49.84,100.32) 50.04,100.13 50.04,89.93 50.86,89.11 50.86,71.37 50.86,71.37 50.86,71.23 50.86,71.23 60.86,61.23 60.86,52.65 60.86,52.65 60.86,52.51 v2(60.66,52.31)
HUBPCIE14_RX_N: length 128.7
  L3 w0.057: v2(51.5,100.87) 51.32,101.05 51.32,101.48 48.09,104.71 38.5,104.71 37.7,105.51 37.7,107.74 37.44,108 37.09,108 37.04,108.06 v1(37.04,108.22) ; v1(116.13,48.25) 115.64,48.25 115.58,48.31 115.58,49.08 113.88,50.79 110.49,50.79 108.7,52.58 63.36,52.58 63.04,52.26 62.38,52.26 62.3,52.34 62.3,52.57 v2(62.47,52.74)
  L6 w0.057: v2(62.47,52.74) 62.31,52.9 62.31,54.11 61.9,54.52 61.9,61.47 52,71.37 52,71.37 51.78,71.59 51.78,89.54 51.31,90.01 51.31,100.67 51.31,100.68 v2(51.5,100.87)
HUBPCIE14_RX_P: length 128.7
  L3 w0.057: v1(37.04,107.62) 37.04,107.78 37.09,107.83 37.37,107.83 37.53,107.67 37.53,105.44 38.43,104.54 48.02,104.54 51.15,101.41 51.15,101.07 v2(50.95,100.87) ; v2(61.97,52.74) 62.14,52.57 62.14,52.27 62.31,52.09 63.11,52.09 63.43,52.42 108.63,52.42 110.42,50.63 113.81,50.63 114.89,49.54 arc(114.92,49.46) 114.89,49.38 114.89,49.37 arc(114.89,49.21) 115.05,49.21 115.05,49.22 arc(115.13,49.25) 115.21,49.22 115.42,49.02 115.42,48.31 115.36,48.25 v1(114.86,48.25)
  L6 w0.057: v2(61.97,52.74) 62.14,52.91 62.14,54.04 61.73,54.45 61.73,61.4 51.93,71.2 51.61,71.52 51.61,89.47 51.14,89.94 51.14,100.6 51.14,100.68 v2(50.95,100.87)
HUBPCIE14_TX_N: length 127
  L3 w0.057: v2(59.86,54.02) 59.67,53.83 59.67,53.64 59.74,53.57 109.14,53.57 111.22,51.49 115.19,51.49 115.58,51.1 115.58,50.85 115.64,50.79 v1(116.13,50.79) ; v1(34.35,105.73) 34.19,105.73 34.13,105.67 34.13,105.42 35.78,103.77 36.37,103.18 46.66,103.18 49.08,100.77 49.08,100.01 v2(49.26,99.83)
  L6 w0.057: v2(59.86,54.02) 59.66,54.22 59.66,61.66 50.26,71.06 50.26,88.9 49.08,90.08 49.08,99.65 v2(49.26,99.83)
HUBPCIE14_TX_P: length 127
  L3 w0.057: v1(33.75,105.73) 33.91,105.73 33.96,105.67 33.96,105.35 35.62,103.7 35.91,103.41 35.91,103.41 36.3,103.01 46.59,103.01 48.91,100.7 48.91,100.01 v2(48.73,99.83) ; v1(114.86,50.79) 115.36,50.79 115.42,50.85 115.42,51.03 115.12,51.32 111.15,51.32 109.08,53.4 59.67,53.4 59.5,53.57 59.5,53.83 v2(59.31,54.02)
  L6 w0.057: v2(48.73,99.83) 48.92,99.64 48.92,90.01 50.09,88.83 50.09,70.99 59.5,61.59 59.5,54.21 v2(59.31,54.02)
HWTRAPN: length 5.9
  BOTTOM w0.1: TP1104.1 32.24,40.81 32.88,40.17 35.77,40.17 36.02,40.42 U1100.49
HWTRAPN_30751790: length 6.5
  BOTTOM w0.1: TP904.1 43.78,19.14 43.78,19.61 43.27,20.12 41.18,20.12 40.79,20.51 U900.49
HWTRAPN_30794186: length 5.4
  BOTTOM w0.1: TP1003.1 47.24,30.4 48.17,29.47 50.9,29.47 51.3,29.87 U1000.49
I2C18_SCL_1P8: length 169.4
  TOP w0.1: v1(117.28,35.65) 117.3,35.65 J2700.G7
  L3 w0.1: v1(135.99,27.19) 135.71,27.47 135.13,27.47 134.04,26.37 123.65,26.37 122.84,27.19 112.92,27.19 v2(112.81,27.31) ; v1(126.67,8.96) 122.52,13.12 v2(114.25,13.12) ; v1(117.28,35.65) 116.79,35.65 115.82,36.62 113.36,36.62 v2(113.04,36.94) 112.51,36.94 108.67,40.77 76.77,40.77 76.46,41.08 67.63,41.08 67.26,41.45 64.46,41.45 64.06,41.86 57.83,41.86 57.53,42.16 57.07,42.16 56.87,41.96 51.57,41.96 50.78,42.74 50.78,50.13 49.85,51.07 49.85,51.86 47.52,54.19 v2(47.52,54.19)
  L6 w0.1: v2(113.04,36.94) 113.04,36.92 112.3,36.17 112.3,28.4 112.76,27.94 112.76,27.35 v2(112.81,27.31) ; v2(112.81,27.31) 112.8,27.3 v3(112.35,27.3) ; v2(112.81,27.31) 113.19,27.31 113.9,26.6 113.9,13.47 v2(114.25,13.12) ; v2(47.52,54.19) 47.52,54.19 47.12,54.58 47.03,54.58 46.91,54.7 46.91,54.7 v3(46.91,54.7)
  BOTTOM w0.1: R3113.1 46.35,54.14 46.91,54.7 46.91,54.7 v3(46.91,54.7) ; U2803.6 105.92,19.07 106.15,19.3 R1803.1 107.05,18.95 107.15,18.85 108.5,18.85 110.05,20.4 110.05,25 v3(112.35,27.3)
I2C18_SDA_1P8: length 160.9
  TOP w0.1: U3606.5 126.72,9.61 v1(126.72,9.61) ; v1(109.8,43.18) 109.8,43.18 J2700.A13
  L3 w0.1: v2(111.9,26.95) 111.9,26.95 122.79,26.95 123.58,26.17 134.13,26.17 135.16,27.19 v1(135.59,27.19) ; v2(49.53,54.63) 51.44,54.63 56.08,49.99 86.13,49.99 86.61,49.51 105.99,49.51 109.43,46.07 109.43,43.56 v1(109.8,43.18) v2(110.54,42.44) ; v1(126.72,9.61) 126.4,9.61 122.51,13.5 113.85,13.5 v2(113.5,13.15)
  L6 w0.1: v2(110.54,42.44) 111.9,41.08 v3(111.9,27.3) v2(111.9,26.95) 113.15,26.95 113.6,26.5 113.6,13.25 v2(113.5,13.15) ; v2(49.53,54.63) 47.97,54.63 v3(47.73,54.87)
  BOTTOM w0.1: U2803.5 106.62,19.72 R1802.1 107.05,20.65 109.45,23.05 109.45,24.85 v3(111.9,27.3) ; v3(47.73,54.87) 47.43,54.87 46.47,53.91 39.55,53.91 R3112.1
IO_EXP_LED0: length 8.6
  TOP w0.2: v1(39.41,57.8) Q3101.1
  L3 w0.1: v2(32.6,58.02) 34.74,58.02 34.96,57.8 v1(39.41,57.8)
  L6 w0.1: v3(31.56,56.8) 31.56,56.98 v2(32.6,58.02)
IO_EXT_13_1P8: length 35
  TOP w0.1: v1(121.76,33.42) 121.35,33.01 J2700.J5 ; J3400.3 148.85,39.05 TVS1800.2 148.16,39.05 147.96,38.85 147.96,35.13 147.15,34.32 140.6,34.32 v1(139.83,33.55)
  L3 w0.1: v1(139.83,33.55) 139.7,33.42 132.55,33.42 132.3,33.67 131.55,33.67 131,33.12 126.55,33.12 126.37,33.29 121.89,33.29 v1(121.76,33.42)
IO_EXT_14_1P8: length 32
  TOP w0.1: v1(148.87,29.91) 148.88,29.92 148.88,32.29 J3400.18 ; v1(124.25,32.42) 123.7,32.42 121.83,34.28 J2700.J6
  L3 w0.1: v1(124.25,32.42) 124.95,32.42 125.25,32.11 126.17,32.11 126.33,32.27 131,32.27 131.4,31.87 132.67,31.87 134.37,30.17 137.7,30.17 137.95,29.91 v1(148.87,29.91)
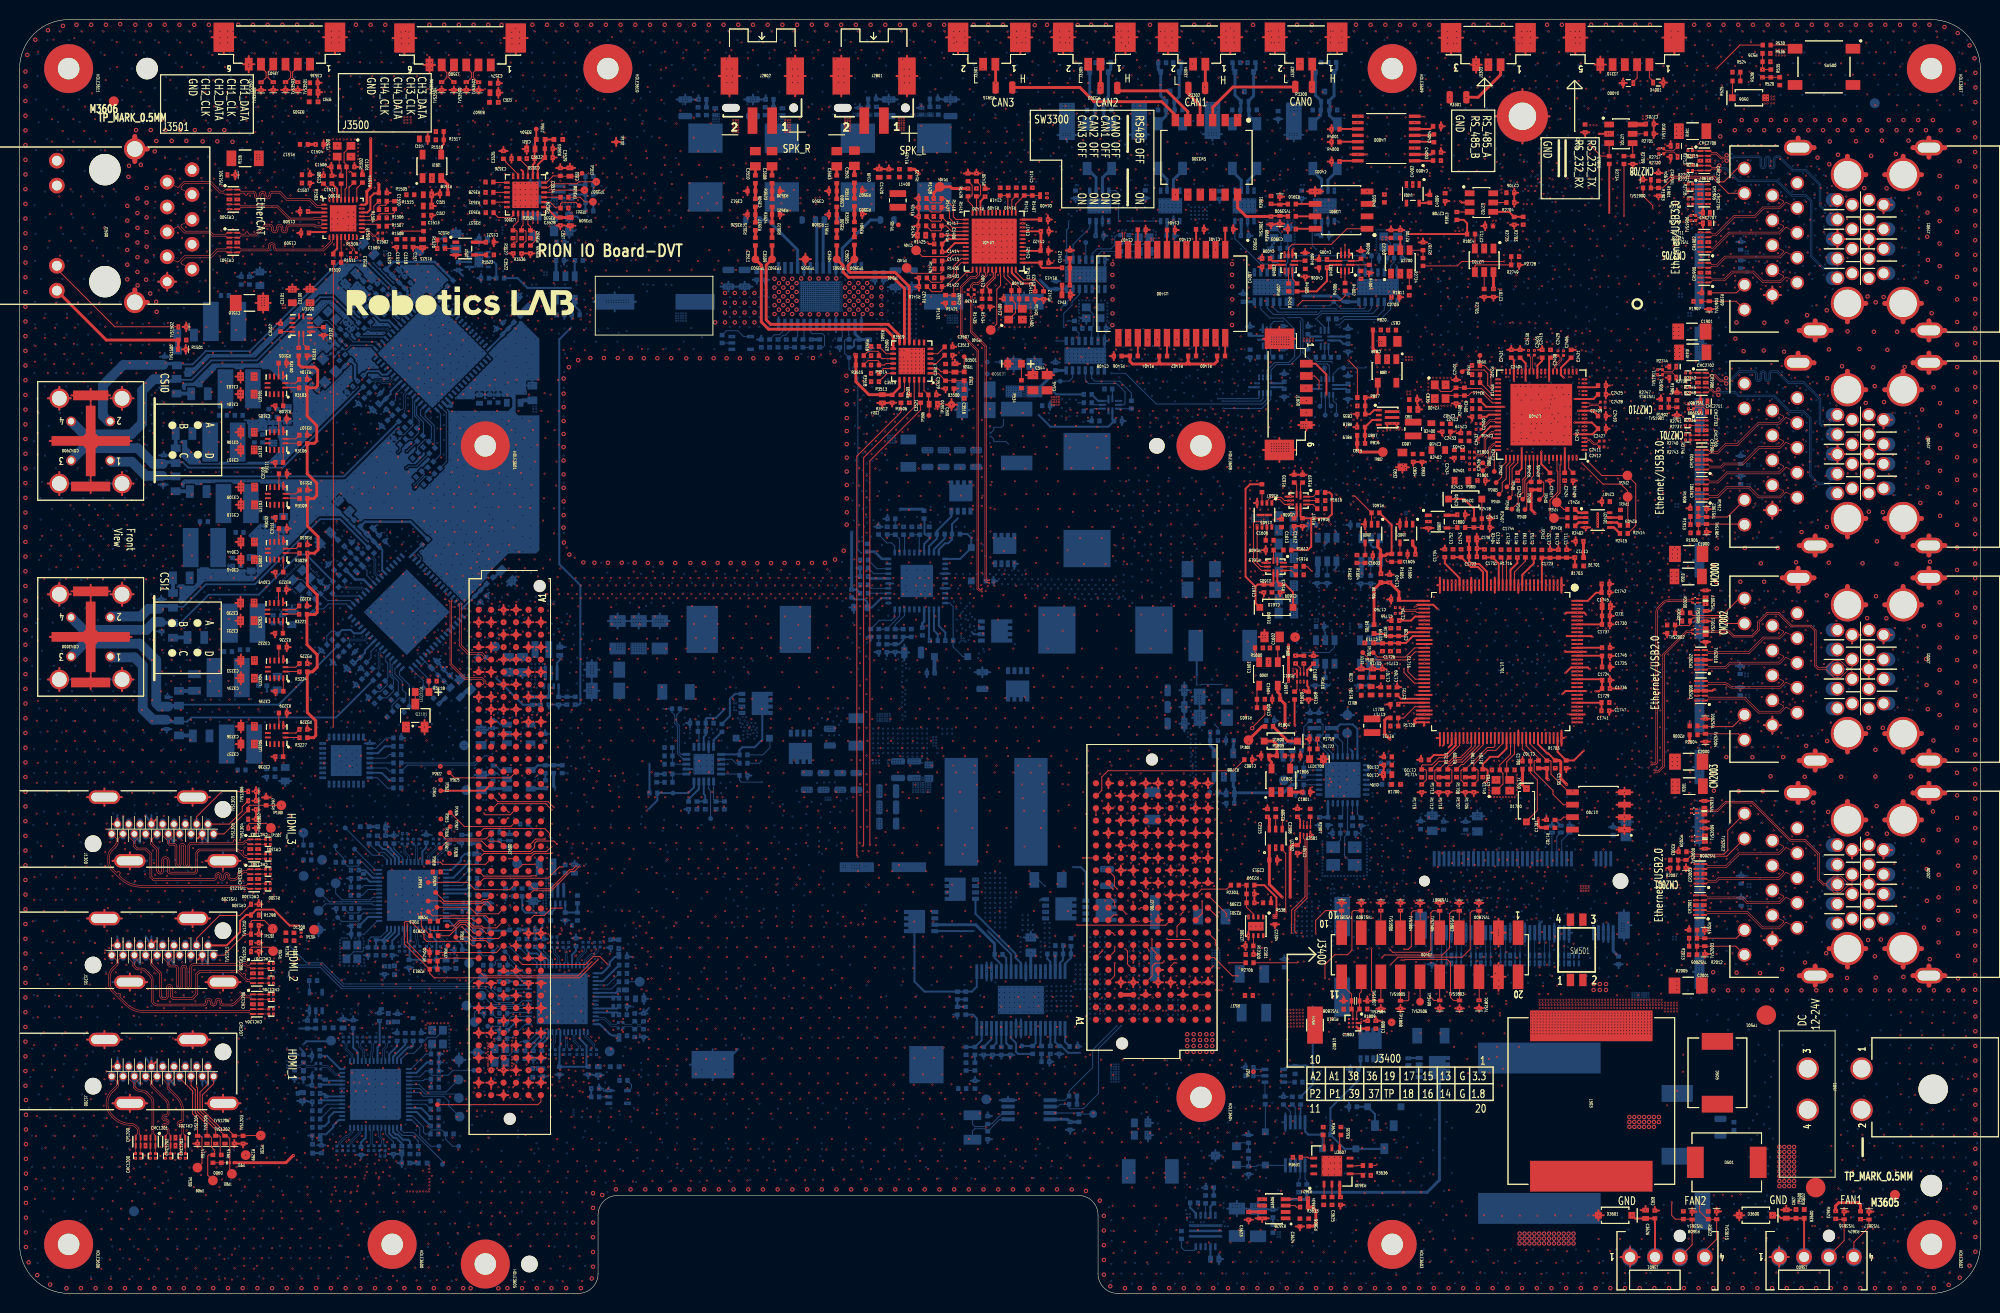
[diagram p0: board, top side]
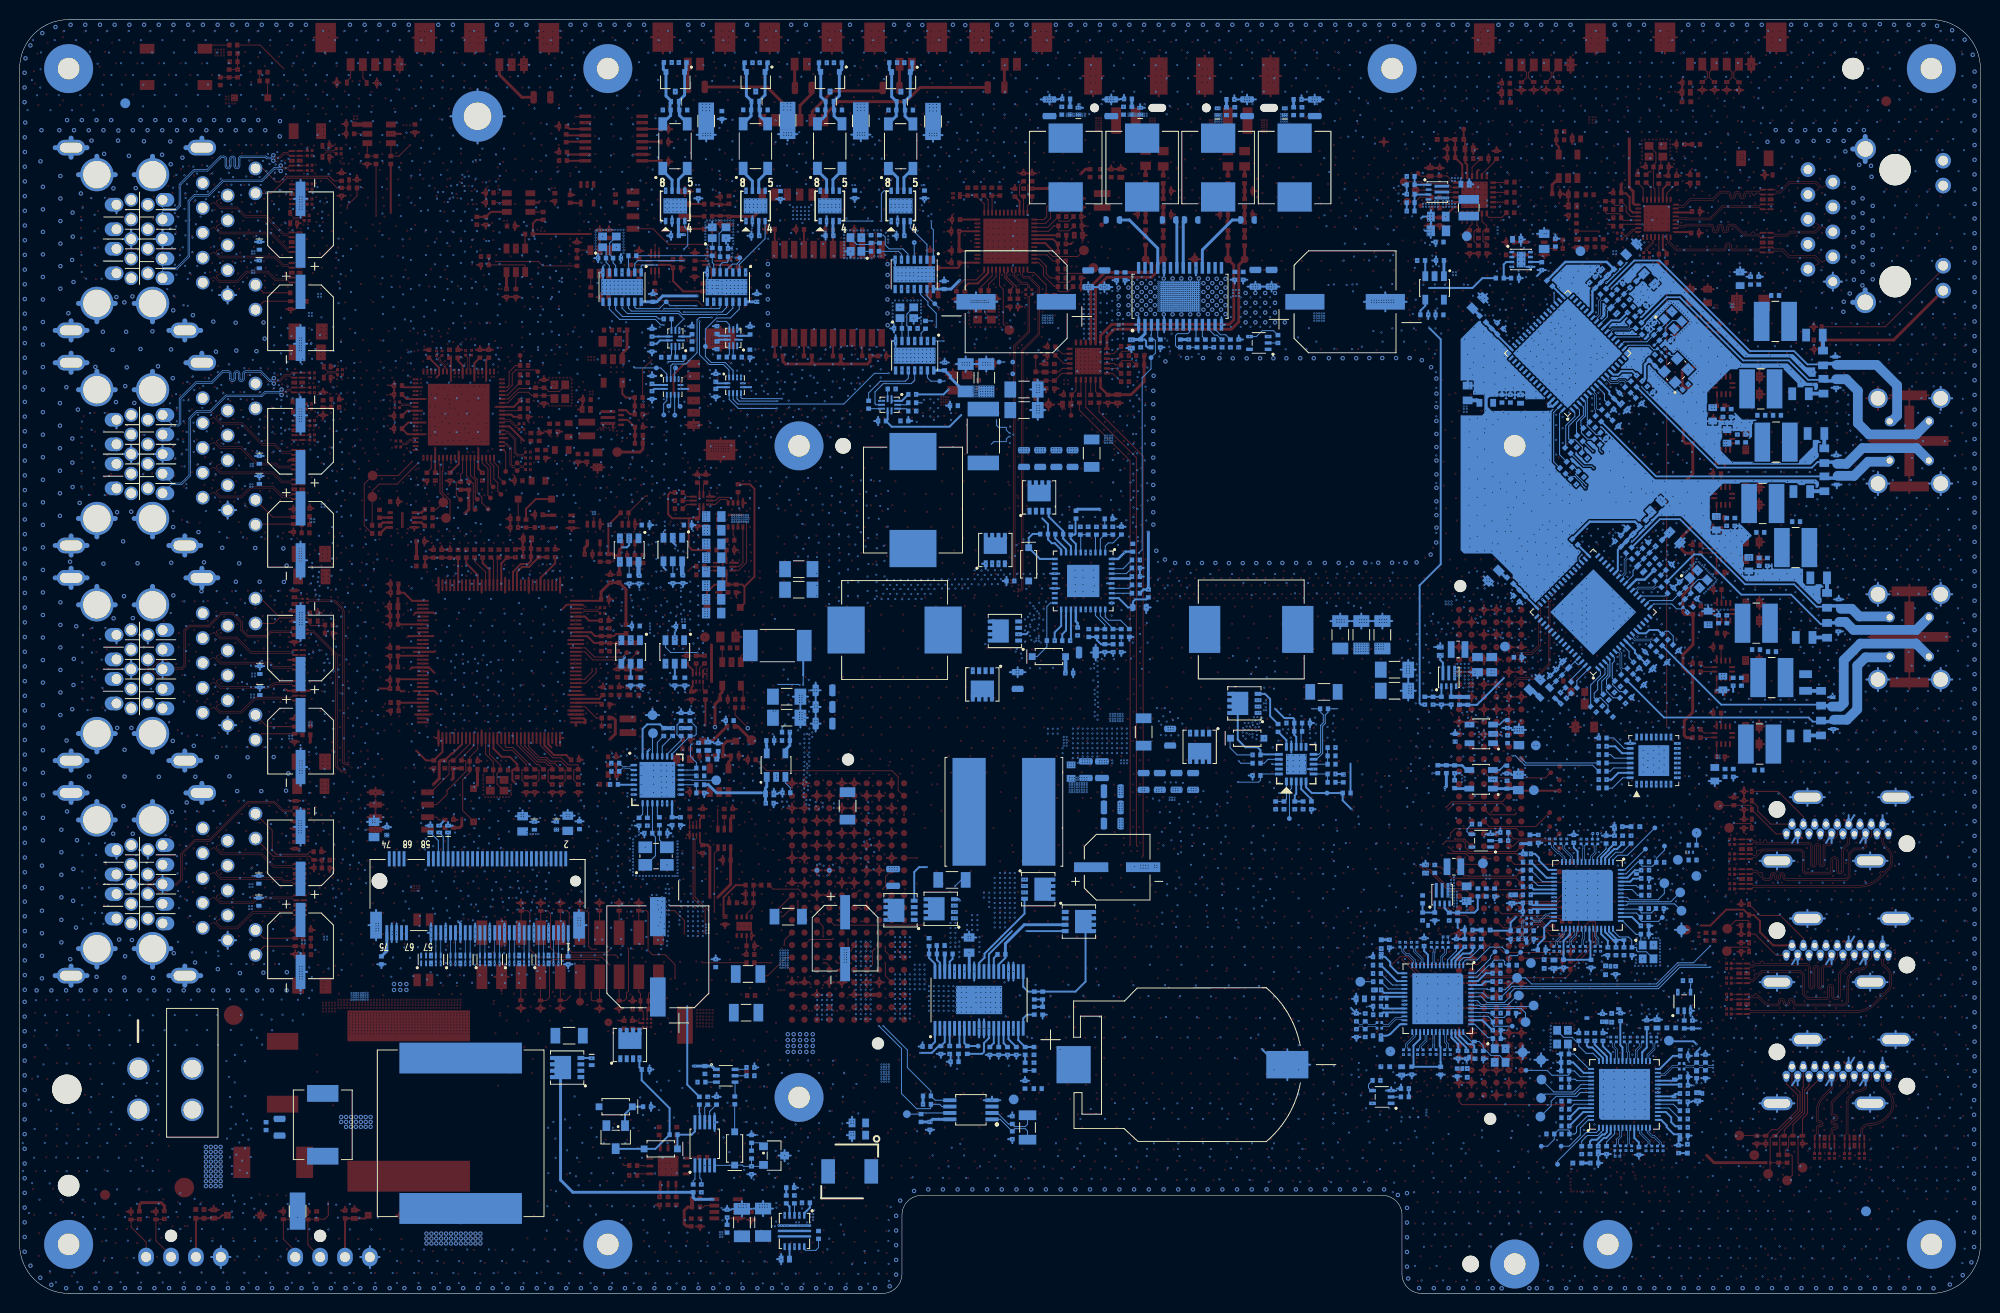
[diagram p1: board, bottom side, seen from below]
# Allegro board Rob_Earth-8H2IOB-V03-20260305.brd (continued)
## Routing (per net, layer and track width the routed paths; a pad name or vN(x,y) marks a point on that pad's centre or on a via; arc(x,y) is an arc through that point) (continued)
IO_EXT_15_1P8: length 32.7
  TOP w0.1: J2700.J7 121.22,35.55 v1(121.22,35.55) ; v1(138.95,34.27) 139.22,34.54 145.12,34.54 145.85,35.27 145.85,38.75 146.15,39.05 TVS1802.2 146.85,39.05 J3400.4
  L3 w0.1: v1(121.22,35.55) 121.46,35.32 124.86,35.32 125.56,34.62 127.95,34.62 128.3,34.97 136,34.97 136.43,34.54 137.53,34.54 137.8,34.27 v1(138.95,34.27)
IO_EXT_16_1P8: length 33.7
  TOP w0.1: v1(140.95,34.02) 141.25,34.02 141.3,34.07 145.63,34.07 145.95,33.74 145.95,30.2 146.26,29.89 146.87,29.89 TVS1803.2 146.88,29.9 146.88,32.29 J3400.17 ; J2700.J8 122,36.04 v1(122,35.57)
  L3 w0.1: v1(140.95,34.02) 140.45,34.52 137.87,34.52 137.6,34.79 136.52,34.79 136.1,35.22 128.05,35.22 127.65,34.82 125.7,34.82 124.95,35.57 v1(122,35.57)
IO_EXT_17_1P8: length 31.8
  TOP w0.1: J3400.5 144.85,39.05 TVS2505.2 144.15,39.05 143.95,38.85 143.95,35.07 143.7,34.82 140.05,34.82 v1(139.8,35.07) ; J2700.J9 121.21,38.26 v1(121.21,38.27)
  L3 w0.1: v1(121.21,38.27) 121.36,38.12 122.74,38.12 123.7,37.17 128.8,37.17 129.18,37.55 132.86,37.55 134.4,36.02 138.85,36.02 v1(139.8,35.07)
IO_EXT_18_1P8: length 31.3
  TOP w0.1: J3400.16 144.85,29.9 TVS2506.2 144.26,29.9 v1(143.85,30.32) ; J2700.J10 122.11,38.47 v1(122.25,38.47)
  L3 w0.1: v1(122.25,38.47) 122.7,38.47 123.8,37.37 128.7,37.37 129.1,37.77 132.95,37.77 134.45,36.27 139.6,36.27 141.2,34.67 141.2,32.97 v1(143.85,30.32)
IO_EXT_19_1P8: length 30.3
  TOP w0.1: v1(141.2,35.12) 141.65,35.12 141.95,35.42 141.95,38.85 142.15,39.05 TVS2507.2 142.85,39.05 J3400.6 ; J2700.J11 123.1,38.75 v1(123.1,38.47)
  L3 w0.1: v1(123.1,38.47) 124,37.57 128.45,37.57 128.9,38.02 133.05,38.02 134.55,36.52 139.8,36.52 v1(141.2,35.12)
IO_EXT_36_1P8: length 26.4
  TOP w0.1: J2700.G10 117.45,39.4 v1(117.49,39.4) ; J3400.7 v1(140.85,39.07)
  L3 w0.1: v1(117.49,39.4) 118.76,39.4 119.1,39.07 120.05,39.07 120.71,39.73 138.58,39.73 138.85,39.47 140.45,39.47 v1(140.85,39.07)
IO_EXT_37_1P8: length 34.6
  TOP w0.1: J2700.E7 v1(115.25,34.92) ; v1(141.7,30.72) 141.7,29.97 141.6,29.87 TVS1805.2 J3400.14
  L3 w0.1: v1(141.7,30.72) 140.2,32.22 140.2,33.67 140,33.87 139.7,33.87 139.55,33.72 132.6,33.72 132.4,33.92 131.35,33.92 130.85,33.42 130.25,33.42 129.75,33.92 129.45,33.92 129.25,33.72 123.9,33.72 123.35,34.27 118.6,34.27 118.3,34.57 116.25,34.57 115.9,34.92 v1(115.25,34.92)
IO_EXT_38_1P8: length 29.1
  TOP w0.1: J3400.8 v1(138.85,39.07) ; v1(113.59,39.97) J2700.D10
  L3 w0.1: v1(138.85,39.07) 138.4,39.51 120.84,39.51 120.15,38.82 119,38.82 118.7,39.12 117.35,39.12 116.78,39.68 114.86,39.68 114.58,39.97 v1(113.59,39.97)
IO_EXT_39_1P8: length 29.6
  TOP w0.1: J3400.13 TVS2504.2 138.35,29.87 138.1,30.12 138.1,30.67 137.9,30.87 v1(137.9,35.22)
  L3 w0.1: v1(137.9,35.22) 137.35,35.77 134.3,35.77 134.1,35.97 129.55,35.97 129.35,36.17 122.85,36.17 122.15,36.87 117.75,36.87 117.75,36.86 v1(117.45,36.86)
IPC_EC_ADDR_SEL: length 1.4
  TOP w0.1: R3630.2 136.86,12.2 U3607.4
ISOLATEB: length 4.2
  TOP w0.1: R1505.1 38.25,110.34 38.09,110.19 36.78,110.19 36.65,110.06 R1507.1 36.4,109.52 U1500.20
IT6563_ASPVCC10_1: length 5.2
  L6 w0.2: JP900.2 40.14,27.67
  L6 w0.3: 40.14,27.67 40.14,25.79 v3(40.15,25.78)
  BOTTOM w0.2: U900.41 38.5,24.03 39.58,25.11 39.98,25.11 40.14,25.27 40.14,25.77 v3(40.15,25.78)
IT6563_ASPVCC10_2: length 3.6
  L6 w0.2: JP1000.2 51.63,25.55 v3(51.63,24.76)
  BOTTOM w0.2: U1000.41 53.15,26.33 52.43,25.6 52.42,25.6 52.25,25.43 51.78,25.43 51.63,25.28 v3(51.63,24.76)
IT6563_ASPVCC10_3: length 3.4
  L6 w0.2: JP1100.2 36.37,35.69 36.36,35.68 v3(36.36,35.31)
  BOTTOM w0.2: v3(36.36,35.31) 36.35,35.31 36.35,35.87 36.56,36.08 37.03,36.08 37.88,36.92 U1100.41
IT6563_ASPVCC33_1: length 9.4
  L6 w0.2: JP907.2 36.9,29.65 v8(36.92,29.68)
  L6 w0.3: v8(39.34,29.68) 39.34,29.43 39.33,29.43 v3(39.33,25.78)
  L7 w0.3: v8(39.34,29.68) v8(36.92,29.68)
  BOTTOM w0.2: U900.40 38.1,24.16 39.34,25.4 39.34,25.77 v3(39.33,25.78)
IT6563_ASPVCC33_2: length 3.3
  L6 w0.2: v3(52.44,24.76) 52.52,24.68 52.52,24.14 52.48,24.09 JP1007.2
  BOTTOM w0.2: v3(52.44,24.76) 52.44,25.08 53.55,26.19 U1000.40
IT6563_ASPVCC33_3: length 2.9
  L6 w0.2: v3(37.17,35.31) 37.17,35.43 37.17,35.43 JP1107.2
  BOTTOM w0.2: U1100.40 38.28,36.89 37.18,35.79 37.18,35.32 v3(37.17,35.31)
IT6563_DDI2C_CLK: length 2.2
  BOTTOM w0.1: R1125.1 34.96,41.46 35.12,41.62 U1100.52
IT6563_DDI2C_CLK_30751790: length 2.4
  BOTTOM w0.1: R928.1 41.42,19.31 U900.52
IT6563_DDI2C_CLK_30794192: length 2.2
  BOTTOM w0.1: U1000.52 50.32,31.07 50.24,31 R1023.1
IT6563_DDI2C_SDA: length 2.3
  BOTTOM w0.1: U1100.51 35.55,41.22 34.96,40.63 R1126.1
IT6563_DDI2C_SDA_30751790: length 2.3
  BOTTOM w0.1: U900.51 41.85,19.71 R929.1
IT6563_DDI2C_SDA_30794190: length 2.4
  BOTTOM w0.1: R1024.1 50.24,30.16 50.75,30.67 U1000.51
IT6563_I2S_DATA0: length 6.7
  BOTTOM w0.1: TP1103.1 32.23,45.22 33.05,44.4 R1122.2 33.45,43.6 34.5,43.6 34.6,43.7 R1123.1 34.92,44.05 36.15,42.82 U1100.55
IT6563_I2S_DATA0_30751790: length 7.6
  BOTTOM w0.1: U900.55 40.07,18.11 41.19,16.99 41.19,16.45 41.38,16.26 R926.1 41.92,16.61 42,16.68 43.05,16.68 R924.2 43.46,15.72 44.16,15.02 TP903.1
IT6563_I2S_DATA0_30794157: length 7.4
  BOTTOM w0.1: U1000.55 51.37,32.27 50.14,33.5 R1021.1 49.77,33.84 49.59,34.02 48.67,34.02 48.52,33.87 48.52,33.56 48.45,33.49 R1020.2 48.1,34.32 47.95,34.47 47.25,34.47 TP1002.1
IT6563_I2S_SCK: length 5.8
  BOTTOM w0.1: TP1100.1 36,44.72 36.99,44.72 37.48,44.23 U1100.1
IT6563_I2S_SCK_30751790: length 6.1
  BOTTOM w0.1: U900.1 38.9,16.71 39.18,16.43 40.2,16.43 43.13,13.49 TP900.1
IT6563_I2S_SCK_30794096: length 5.6
  BOTTOM w0.1: U1000.1 52.75,33.79 52.5,34.04 51.33,34.04 50.02,35.34 48.77,35.34 TP1000.1
IT6563_I2S_WS: length 3.4
  BOTTOM w0.1: U1100.56 36.29,43.22 TP1102.1
IT6563_I2S_WS_30751790: length 4.6
  BOTTOM w0.1: TP902.1 41.94,15.02 40.81,16.16 40.81,16.89 39.99,17.71 U900.56
IT6563_I2S_WS_30794200: length 3.5
  BOTTOM w0.1: TP1001.1 49.97,34.41 49.97,34.17 51.47,32.67 U1000.56
IT6563_IVDD10_1: length 37.5
  L3 w0.3: v2(41.55,18.6) 41.55,18.6 31.67,18.6 31.59,18.52 29.74,18.52 29.27,18.99 v2(29.27,19.01)
  L6 w0.2: v3(28.83,20.42) 28.83,20.41 JP902.2
  L6 w0.3: v3(41.96,23.59) 41.54,23.17 41.54,18.6 v2(41.55,18.6) 41.55,17.66 41.91,17.29 v3(41.91,17.1) ; v3(30.66,17.06) 29.75,17.06 29.27,17.54 v2(29.27,19.01) 28.83,19.45 v3(28.83,20.42)
  L7 w0.2: v3(28.83,20.42) 29.19,20.05 30.28,20.05 v7(30.64,20.41)
  BOTTOM w0.2: U900.21 31.38,20.11 31.13,20.36 30.69,20.36 v7(30.64,20.41) ; U900.54 40.51,18.51 C916.1 ; v3(30.66,17.06) 30.66,17.06 31.11,17.06 31.54,17.48 31.54,17.97 32.07,18.51 U900.17 ; C917.1 41.54,23.58 40.47,22.51 U900.44
  BOTTOM w0.3: v3(41.91,17.1) 41.93,17.09 C916.1
IT6563_IVDD10_2: length 36.7
  L3 w0.3: v2(61.49,30.13) 61.09,29.72 53.38,29.72 52.92,29.26 52.51,29.26 50.84,27.59 v2(49.74,27.59)
  L6 w0.2: v3(61.13,30.13) 61.13,30.14 JP1002.2
  L6 w0.3: 61.5,30.13 62.61,30.13 62.61,30.13 v3(62.87,30.13) 62.87,31.75 v3(61.14,33.48) ; 61.5,30.13 v2(61.49,30.13) ; 61.5,30.13 v3(61.13,30.13) ; v3(49.74,32.69) 49.74,32.54 49.29,32.08 49.29,29.64 48.55,28.9 48.55,28.43 48.77,28.21 48.78,28.21 48.78,28.21 49.12,28.21 49.12,28.21 v2(49.74,27.59) 49.74,27.43 49.74,27.43 v3(49.74,26.86)
  BOTTOM w0.2: v3(61.13,30.13) 60.99,30.27 U1000.21 ; U1000.44 50.79,27.87 49.78,26.86 C1016.1 ; U1000.54 51.24,31.87 50.44,32.68 C1015.1 49.75,32.68 v3(49.74,32.69) ; C1017.1 60.45,32.8 60.45,32.8 59.52,31.87 U1000.17
IT6563_IVDD10_3: length 33.8
  L3 w0.3: v2(45.27,41.28) v2(34.21,41.28)
  L6 w0.2: v3(47.79,40.67) 47.78,40.68 JP1102.2
  L6 w0.3: v3(45.85,44.02) 45.27,43.44 v2(45.27,41.28) v3(45.87,40.68) ; v3(34.63,37.54) 34.47,37.7 34.47,39.4 34.2,39.67 34.2,41.28 v2(34.21,41.28) 34.21,41.63 34.2,41.63 34.2,42.89 34.5,43.18 v3(34.59,43.18)
  L7 w0.3: v3(45.87,40.68) 46.3,40.25 47.37,40.25 v3(47.79,40.67)
  BOTTOM w0.2: C1117.1 35.54,38.42 U1100.44 ; v3(45.85,44.02) 44.25,42.42 U1100.17 ; C1115.1 45.72,40.82 U1100.21 ; U1100.54 36.01,42.42 35.25,43.18 v3(34.59,43.18)
IT6563_OVDD33_1: length 29.9
  L3 w0.3: v2(42.04,20.17) 42.04,20.19 42.03,20.19 41.49,19.66 33.42,19.66 ; v2(31.15,19.57) 31.24,19.66 33.42,19.66 ; 33.42,19.66 v2(33.42,19.71)
  L6 w0.2: 42.33,16.26 42.33,16.26 ; 42.33,16.26 42.33,14.19 v8(42.33,14.18) ; 42.33,16.26 v8(42.33,16.27) ; 42.33,16.26 v8(42.33,16.27) ; 42.33,16.26 42.33,16.28 ; 42.33,16.28 42.33,17.61 v3(42,17.93) ; 42.33,16.28 v8(42.33,16.27) ; v2(33.42,19.71) 33.42,20.72 33.24,20.91 v3(32.9,20.91) ; v3(30.65,19.57) v2(31.15,19.57) 31.26,19.67 JP903.2
  L6 w0.3: 42.04,20.19 42.75,20.9 v3(42.75,21.04) ; 42.04,20.19 42,20.16 v3(42,17.93) ; 42.04,20.19 v2(42.04,20.17)
  L7 w0.2: v7(44.26,16.27) 43.97,15.98 42.62,15.98 v8(42.33,16.27) ; v8(42.33,14.18) 42.29,14.22 v7(40.67,14.22)
  BOTTOM w0.2: U900.53 40.96,18.91 C919.1 ; U900.20 30.79,19.71 v3(30.65,19.57)
IT6563_OVDD33_2: length 31.3
  L3 w0.3: 58.73,30.97 58.77,30.97 ; 58.73,30.97 v2(58.75,30.96) 58.77,30.97 ; 58.73,30.97 54.23,30.97 arc(54.09,31) 53.96,31.09 arc(53.7,31.26) 53.38,31.33 51.33,31.33 v2(51.13,31.12) ; 58.77,30.97 v2(60.68,30.97)
  L6 w0.2: v3(61.12,30.97) 61.13,30.97 JP1003.2
  L6 w0.3: v8(49.57,36.16) 49.5,36.09 v8(49.5,33.5) 49.91,33.09 50.19,32.8 50.19,32.29 v3(49.75,31.85) 49.75,31.14 ; 49.75,30.87 49.88,31 49.88,31.01 ; 49.75,30.87 49.75,29.41 v3(48.95,28.61) ; 49.75,30.87 49.75,31.14 ; 49.88,31.01 49.75,31.14 ; 49.88,31.01 51.02,31.01 v2(51.13,31.12) ; v3(58.74,29.48) 58.55,29.48 58.44,29.59 58.44,30.65 v2(58.75,30.96) ; v2(60.68,30.97) 60.69,30.97 v3(61.12,30.97)
  L7 w0.3: v8(49.5,33.5) 49.07,33.07 47.72,33.07 v7(47.29,33.5) ; v7(50.89,36.18) 49.59,36.18 v8(49.57,36.16)
  BOTTOM w0.2: C1019.1 50.52,31.83 50.87,31.47 U1000.53 ; v3(58.74,29.48) 58.74,29.47 U1000.23 ; v3(61.12,30.97) 60.83,30.67 U1000.20
  BOTTOM w0.3: v3(48.95,28.61) R1025.2 ; R1020.1 v7(47.29,33.5) ; R1019.2 50.9,36.17 v7(50.89,36.18)
IT6563_OVDD33_3: length 35.6
  L3 w0.3: 42.96,41.94 32.36,41.94 v2(32.25,42.06) ; 42.96,41.94 42.97,41.94 ; 42.96,41.94 v2(42.96,41.94) 42.97,41.94 ; 42.97,41.94 v2(45.81,41.94)
  L6 w0.2: JP1103.2 35.08,42.47 34.94,42.33 v3(34.59,42.33)
  L6 w0.3: v3(33.83,39.27) 32.25,40.86 v2(32.25,42.06) v8(32.25,42.79) v3(32.25,44) v8(32.25,46.68) ; v2(42.96,41.94) 42.96,40.35 43.3,40.02 v3(43.48,40.02) ; v2(45.81,41.94) v3(45.81,41.57)
  L7 w0.3: v7(35.58,46.68) 32.25,46.68 v8(32.25,46.68) ; v8(32.25,42.79) 34.13,42.79 v3(34.59,42.33)
  BOTTOM w0.2: U1100.20 45.56,41.22 C1119.1 ; U1100.53 35.72,42.02 35.41,42.33 v3(34.59,42.33)
  BOTTOM w0.3: R1122.1 32.25,44 v3(32.25,44)
IT6563_PCI2C_SCL: length 6.5
  BOTTOM w0.1: TP1105.1 31.58,39.97 32.8,39.97 32.8,39.97 36.05,39.97 36.1,40.02 U1100.48
IT6563_PCI2C_SCL_30751790: length 5.5
  BOTTOM w0.1: TP905.1 44.41,20.34 41.37,20.34 40.8,20.91 U900.48
IT6563_PCI2C_SCL_30794184: length 6.5
  BOTTOM w0.1: U1000.48 51.88,29.4 51.11,29.4 50.98,29.27 48.08,29.27 48.07,29.28 45.67,29.28 TP1004.1
IT6563_PCI2C_SDA: length 6.5
  BOTTOM w0.1: TP1106.1 31.19,39.75 35.95,39.75 36.08,39.62 U1100.47
IT6563_PCI2C_SDA_30751790: length 5.9
  BOTTOM w0.1: TP906.1 43.51,20.56 41.51,20.56 40.76,21.31 U900.47
IT6563_PCI2C_SDA_30794182: length 6.7
  BOTTOM w0.1: U1000.47 51.07,29.07 51.06,29.07 48,29.07 48,29.07 46.84,29.07 46.4,28.64 TP1005.1
IT6563_REXT: length 2.3
  BOTTOM w0.1: U1100.5 39.08,44.47 38.18,45.37 38.18,45.91 R1120.1
IT6563_REXT_30751790: length 2.2
  BOTTOM w0.1: R922.1 38.13,15.46 37.3,16.28 U900.5
IT6563_REXT_30794050: length 2.3
  BOTTOM w0.1: R1018.1 53.45,34.95 54.34,34.05 54.34,33.48 U1000.5
IT6563_RXAVDD10_1: length 22.5
  L6 w0.2: JP901.1 v3(28.94,25.42) ; JP900.1 v8(40.14,28.56)
  L7 w0.2: v7(36.77,27.82) 37.06,28.11 39.33,28.11 39.78,28.56 v8(40.14,28.56)
  L7 w0.3: v7(36.77,27.82) 34.7,27.82 34.41,27.52 32.33,27.52 31.96,27.16 v7(31.96,27.12)
  BOTTOM w0.2: U900.31 34.5,24.61 34.03,25.09 C907.1 ; C908.1 36.73,27.77 36.73,25.34 36.5,25.11 U900.36 ; TP908.1 31.7,25.73 29.26,25.73 v3(28.94,25.42)
IT6563_RXAVDD10_2: length 23.4
  L3 w0.2: v2(51.68,26.45) 60.09,26.45 v2(60.1,26.44)
  L6 w0.2: JP1000.1 51.63,26.4 v2(51.68,26.45) ; JP1001.1 60.23,28.44 60.11,28.33 60.11,26.46 v2(60.1,26.44) 60.1,25.39 60.19,25.3 v3(60.19,24.71)
  BOTTOM w0.2: U1000.31 57.15,25.97 57.83,25.29 57.83,23.31 C1007.1 57.99,23.13 C1008.1 55.05,23.57 55.07,23.58 55.07,25.16 55.15,25.24 U1000.36
IT6563_RXAVDD10_3: length 23.6
  L3 w0.3: v2(36.37,36.67) 36.54,36.84 37.84,36.84 37.85,36.83 41.91,36.83 41.92,36.84 44.69,36.84 v2(44.72,36.81) 44.72,36.81 ; 44.72,36.81 44.7,36.84 44.72,36.84 44.72,36.81
  L6 w0.2: 44.74,38.85 44.88,38.99 JP1101.1 ; JP1100.1 v2(36.37,36.67)
  L6 w0.3: v3(44.55,34.12) 44.72,34.29 v2(44.72,36.81) 44.72,38.83 44.74,38.85
  BOTTOM w0.2: U1100.36 39.88,36.04 39.78,35.94 39.78,34.11 C1108.1 42.51,34.05 C1107.1 42.52,35.98 41.88,36.62 U1100.31
IT6563_RXAVDD33_1: length 4.7
  L6 w0.2: 38.55,27.72 38.55,25.81 v3(38.51,25.77) ; 38.55,27.72 JP906.2 ; 38.55,27.72 v3(38.55,27.72)
  BOTTOM w0.2: 38.5,25.77 38.51,25.77 38.51,25.23 37.7,24.43 U900.39
IT6563_RXAVDD33_2: length 4.3
  L6 w0.2: v3(53.27,24.77) 53.27,24.16 53.27,24.16 v3(53.27,22.96) 53.26,22.95 JP1006.2
  BOTTOM w0.2: U1000.39 53.95,26.1 53.27,25.42 53.27,24.77 v3(53.27,24.77)
IT6563_RXAVDD33_3: length 4.8
  L6 w0.2: v3(37.2,33.38) 37.21,33.38 JP1106.2
  L6 w0.3: v3(37.89,35.31) 37.21,34.62 37.21,33.38 v3(37.2,33.38)
  BOTTOM w0.2: U1100.39 38.68,36.67 38,35.99 38,35.32 C1123.1
IT6563_RXDVDD10_1: length 3.3
  L6 w0.2: 30.62,24.45 30.62,24.46 JP905.2
  L6 w0.3: v3(30.65,24.24) 30.65,24.42 30.62,24.45
  BOTTOM w0.2: C920.1 v3(30.65,24.24) 31.36,24.24 32.7,22.91 U900.28
IT6563_RXDVDD10_2: length 3.1
  L6 w0.2: v3(61.15,26.3) 61.15,26.05 JP1005.2
  BOTTOM w0.2: U1000.28 59.1,27.47 arc(59.18,27.46) 59.24,27.42 60.15,26.51 arc(60.38,26.36) 60.66,26.3 61.15,26.3 v3(61.15,26.3)
IT6563_RXDVDD10_3: length 5.4
  L6 w0.2: JP1105.2 45.91,35.83 45.7,35.62 v3(45.7,35.07)
  BOTTOM w0.2: U1100.28 43.8,38.02 44.5,37.32 44.5,36.22 45.15,35.57 C1120.1 v3(45.7,35.07)
IT6563_RXPVCC10_1: length 4.5
  L6 w0.2: JP901.2 28.94,22.1 v8(28.95,22.1)
  L7 w0.2: v7(30.63,22.1) v8(28.95,22.1)
  BOTTOM w0.2: v7(30.63,22.1) 31.02,21.71 U900.25
IT6563_RXPVCC10_2: length 2.9
  L6 w0.2: JP1001.2 61.14,28.44 v3(61.14,28.44)
  BOTTOM w0.2: v3(61.14,28.44) 60.91,28.67 U1000.25
IT6563_RXPVCC10_3: length 3
  L6 w0.2: v3(45.87,38.99) 45.87,38.99 JP1101.2
  BOTTOM w0.2: U1100.25 45.64,39.22 v3(45.87,38.99)
IT6563_RXPVCC33_1: length 3.2
  L6 w0.2: JP908.2 31.2,21.43 31,21.23 v3(30.63,21.23)
  BOTTOM w0.2: v3(30.63,21.23) 30.71,21.31 U900.24
IT6563_RXPVCC33_2: length 2.9
  L6 w0.2: JP1008.2 61.14,29.29 v3(61.15,29.29)
  BOTTOM w0.2: v3(61.15,29.29) 61.14,29.29 C1025.1 60.91,29.07 U1000.24
IT6563_RXPVCC33_3: length 2.9
  L6 w0.2: JP1108.2 45.85,39.83 v3(45.87,39.85)
  BOTTOM w0.2: U1100.24 45.64,39.62 v3(45.87,39.85)
IT6563_TAVCC10_1: length 12.4
  L3 w0.3: v2(38.37,14.09) 38.36,14.09 v2(34.81,14.09) 31.61,14.09 v2(31.38,14.32)
  L6 w0.2: JP909.1 38.97,14.2 38.86,14.09 v2(38.37,14.09)
  L6 w0.3: v2(31.38,14.32) v3(30.79,14.32) ; v2(34.81,14.09) 34.83,14.11 v3(34.83,14.95)
  BOTTOM w0.2: B903.2 30.78,14.32 C926.1 ; U900.10 35.3,15.88 34.84,15.41 34.84,14.95 v3(34.83,14.95)
IT6563_TAVCC10_2: length 10.3
  L6 w0.2: JP1009.1 v8(56.77,37.56) 56.77,35.47 v3(56.74,35.45)
  L6 w0.3: v8(60.26,37.52) v3(60.26,36.13)
  L7 w0.3: v8(56.77,37.56) 60.23,37.56 v8(60.26,37.52)
  BOTTOM w0.2: U1000.10 56.35,34.56 56.74,34.95 56.74,35.44 v3(56.74,35.45)
  BOTTOM w0.3: B1003.2 61.11,36.09 C1026.1
IT6563_TAVCC10_3: length 15.1
  L6 w0.2: JP1109.1 v8(37.32,48.25) ; v3(45.1,46.79) v8(45.1,48.22) ; v8(41.5,48.21) v3(41.5,46.03)
  L7 w0.2: 41.49,48.22 v8(41.5,48.21)
  L7 w0.3: v8(45.1,48.22) 41.49,48.22 41.46,48.25 v8(37.32,48.25)
  BOTTOM w0.2: v3(45.1,46.79) C1126.1 45.94,46.79 B1103.2 ; U1100.10 41.08,45.11 41.47,45.5 C1127.1
IT6563_TDVDD10_1: length 3.3
  L6 w0.2: v3(30.66,16.24) 30.65,16.24 JP904.2
  BOTTOM w0.2: U900.15 32.57,17.71 32,17.14 32,16.97 31.27,16.24 v3(30.66,16.24)
IT6563_TDVDD10_2: length 3.6
  L6 w0.2: JP1004.2 v3(61.11,34.2)
  BOTTOM w0.2: C1021.1 60.73,34.35 60.19,33.81 60.19,33.45 59.42,32.67 U1000.15
IT6563_TDVDD10_3: length 3.6
  L6 w0.2: JP1104.2 45.87,44.85 v3(45.87,44.85)
  BOTTOM w0.2: v3(45.87,44.85) 45.85,44.85 C1121.1 45.42,44.86 45.01,44.44 45.01,44.16 44.06,43.22 U1100.15
IT6563_TPVCC10_1: length 2.9
  L6 w0.2: v3(38.98,15.02) 38.97,15.02 JP909.2
  BOTTOM w0.2: U900.4 37.7,16.32 38.15,15.87 38.41,15.87 38.99,15.29 38.99,15.03 v3(38.98,15.02)
IT6563_TPVCC10_2: length 8.7
  L6 w0.2: v8(55.79,37.68) 55.91,37.56 JP1009.2 ; v8(52.59,37.68) 52.3,37.39 52.3,35.68 v3(52.59,35.39)
  L7 w0.2: v8(55.79,37.68) v8(52.59,37.68)
  BOTTOM w0.2: v3(52.59,35.39) 52.6,35.39 C1028.1 53.95,34.02 U1000.4
IT6563_TPVCC10_3: length 3.8
  L6 w0.2: v3(37.31,45.92) 37.32,45.94 JP1109.2
  BOTTOM w0.2: U1100.4 38.68,44.48 37.91,45.25 37.91,45.33 C1128.1 37.31,45.92 v3(37.31,45.92)
IT6563_TPVCC33_1: length 5.7
  L6 w0.3: v3(39.82,15.02) 39.82,13.31 v3(39.8,13.29)
  BOTTOM w0.2: U900.3 38.1,16.46 38.35,16.22 38.57,16.22 39.11,15.68 39.64,15.68 39.82,15.51 v3(39.82,15.02)
  BOTTOM w0.3: C911.1 39.78,13.3 B901.2
IT6563_TPVCC33_2: length 5.7
  L6 w0.3: v3(51.75,35.38) 51.8,35.43 v3(51.8,37.09)
  BOTTOM w0.2: C1012.1 51.77,35.36 51.77,34.98 52.07,34.69 52.78,34.69 53.55,33.92 U1000.3
  BOTTOM w0.3: v3(51.8,37.09) 51.8,37.09 B1001.2
IT6563_TPVCC33_3: length 5.4
  L6 w0.3: v3(36.52,47.62) 36.49,47.59 v3(36.49,45.91)
  BOTTOM w0.2: v3(36.49,45.91) 37.06,45.34 37.37,45.34 38.28,44.43 U1100.3
  BOTTOM w0.3: B1101.2 36.5,47.64 v3(36.52,47.62)
IT6563_XI_1: length 4
  BOTTOM w0.1: Y900.1 41.97,25.35 C902.1 41.44,24.43 39.91,22.91 U900.43
IT6563_XI_2: length 4
  BOTTOM w0.1: U1000.43 51.58,27.47 50.21,26.1 49.73,26.1 49.72,26.09 C1003.1 49.72,25.16 Y1000.1
IT6563_XI_3: length 3.8
  BOTTOM w0.1: U1100.43 36.51,38.02 35.13,36.65 34.64,36.65 C1103.1 34.63,35.73 Y1100.1
IT6563_XO_1: length 6
  BOTTOM w0.1: U900.42 38.9,23.9 39.51,24.5 40.22,24.5 40.97,25.26 40.97,25.77 C903.1 41.28,25.77 41.65,26.14 42.51,26.14 43.17,26.8 Y900.3
IT6563_XO_2: length 6
  BOTTOM w0.1: Y1000.3 48.44,23.69 49.04,24.29 49.94,24.29 50.4,24.75 C1004.1 50.7,25.28 51.13,25.71 51.92,25.71 52.75,26.54 U1000.42
IT6563_XO_3: length 6.1
  BOTTOM w0.1: Y1100.3 34.06,34.86 34.94,34.86 35.06,34.99 35.06,35.25 35.12,35.31 C1104.1 35.56,35.33 35.56,36.06 35.88,36.38 36.83,36.38 37.48,37.03 U1100.42
LAN0_MDI0+: length 19.2
  TOP w0.062: 15.05,113.42 16.14,112.87 16.28,112.91 16.35,113.07 16.74,113.46 19.54,113.46 20.5,112.5 20.8,112.5 20.95,112.65 CR1500.1 CR1500.10 22.41,112.65 22.57,112.48 23.83,112.48 arc(24.04,112.39) 24.13,112.18 24.13,112.03 arc(24.29,111.88) 24.44,112.03 24.44,112.14 arc(24.54,112.38) 24.78,112.48 24.82,112.48 arc(25.04,112.39) 25.13,112.18 25.13,112.03 arc(25.28,111.88) 25.44,112.03 25.44,112.14 arc(25.54,112.38) 25.78,112.48 26.56,112.48 27.3,111.75 29.62,111.75 30.36,111.01 30.76,111.01 30.86,111.12 U1500.1
LAN0_MDI0-: length 19.2
  TOP w0.062: U1500.2 30.88,110.72 30.77,110.82 30.28,110.82 29.55,111.56 27.22,111.56 26.49,112.29 25.78,112.29 arc(25.67,112.25) 25.62,112.14 25.62,112.03 arc(25.28,111.69) 24.94,112.03 24.94,112.18 arc(24.9,112.26) 24.82,112.29 24.78,112.29 arc(24.67,112.25) 24.63,112.14 24.63,112.03 arc(24.29,111.69) 23.94,112.03 23.94,112.18 arc(23.91,112.26) 23.83,112.29 23.34,112.29 arc(23.26,112.26) 23.22,112.18 arc(23.19,112.1) 23.11,112.07 23.09,112.07 arc(23.01,112.1) 22.97,112.18 arc(22.94,112.26) 22.86,112.29 22.58,112.29 22.43,112.15 CR1500.9 CR1500.2 20.95,112.15 20.8,112.3 20.42,112.3 19.45,113.27 16.83,113.27 16.52,112.95 16.45,112.82 16.5,112.69 J1500.3
LAN0_MDI1+: length 19.2
  TOP w0.062: v1(21.39,111.15) 21.4,111.15 CR1500.4 CR1500.7 22.39,111.15 22.55,110.99 26.36,110.99 27.48,109.86 27.6,109.74 29.97,109.74 30.03,109.81 30.75,109.81 30.86,109.92 U1500.4
  L3 w0.05: v1(21.39,111.15) 21.23,110.99 17,110.99 16.36,110.35 16.36,109.13 16.31,109.07 16.24,109.08 J1500.4
LAN0_MDI1-: length 19.3
  TOP w0.062: U1500.5 30.86,109.52 30.75,109.62 30.11,109.62 30.05,109.56 27.53,109.56 27.41,109.68 26.28,110.8 22.54,110.8 22.38,110.65 CR1500.6 v1(21.4,110.65)
  L3 w0.05: J1500.7 16.4,108.86 16.41,108.92 16.54,109.05 16.54,110.28 17.07,110.82 20.76,110.82 arc(20.8,110.8) 20.82,110.76 arc(20.84,110.72) 20.88,110.7 20.96,110.7 arc(21,110.72) 21.02,110.76 arc(21.04,110.8) 21.08,110.82 21.23,110.82 v1(21.4,110.65)
LAN0_MDI2+: length 19.2
  TOP w0.062: U1500.6 30.87,109.12 30.77,109.01 30.21,109.01 30.1,109.12 27.51,109.12 arc(27.27,109.02) 27.17,108.78 27.17,108.57 arc(27.01,108.42) 26.86,108.57 26.86,108.78 arc(26.52,109.12) 26.18,108.78 26.18,108.57 arc(26.02,108.42) 25.87,108.57 25.87,108.78 arc(25.77,109.02) 25.52,109.12 25.06,109.12 24.04,108.1 23.43,108.1 arc(23.34,108.14) 23.31,108.23 arc(23.27,108.31) 23.19,108.35 23.18,108.35 arc(23.1,108.31) 23.06,108.23 arc(23.03,108.14) 22.94,108.1 22.57,108.1 22.43,108.25 CR1501.10 CR1501.1 21.17,108.25 21.02,108.1 19.75,108.1 19.44,108.41 16.9,108.41 16.52,108.79 16.45,108.93 16.5,109.06 J1500.5
LAN0_MDI2-: length 19.2
  TOP w0.062: J1500.6 16.14,108.88 16.25,108.84 16.25,108.8 16.34,108.71 16.35,108.68 16.81,108.22 19.36,108.22 19.68,107.9 21.03,107.9 21.18,107.75 CR1501.2 CR1501.9 22.4,107.75 22.58,107.92 24.12,107.92 25.14,108.94 25.52,108.94 arc(25.63,108.89) 25.68,108.78 25.68,108.57 arc(26.02,108.23) 26.36,108.57 26.36,108.78 arc(26.52,108.94) 26.67,108.78 26.67,108.57 arc(27.01,108.23) 27.36,108.57 27.36,108.78 arc(27.4,108.89) 27.51,108.94 30.02,108.94 30.14,108.82 30.78,108.82 30.88,108.72 U1500.7
LAN0_MDI3+: length 19.2
  TOP w0.062: J1500.8 16.12,105.26 16.2,105.29 16.83,105.91 19.44,105.91 20.13,106.59 21.03,106.59 21.18,106.75 CR1501.4 CR1501.7 22.4,106.75 22.57,106.58 25.28,106.58 arc(25.35,106.61) 25.37,106.68 25.37,106.9 arc(25.72,107.24) 26.06,106.9 26.06,106.74 arc(26.1,106.63) 26.21,106.58 30.94,106.58 31.7,107.35 31.7,107.49 31.6,107.6 U1500.9
LAN0_MDI3-: length 19.3
  TOP w0.062: U1500.10 32,107.6 31.89,107.49 31.89,107.27 31.01,106.4 26.21,106.4 arc(25.97,106.5) 25.87,106.74 25.87,106.9 arc(25.72,107.05) 25.56,106.9 25.56,106.68 arc(25.48,106.48) 25.28,106.4 22.56,106.4 22.41,106.25 CR1501.6 CR1501.5 21.18,106.25 21.05,106.37 20.22,106.37 19.53,105.68 16.92,105.68 16.45,105.21 16.5,105.07 J1500.9
LAN0LED0: length 7
  TOP w0.1: U1701.81 151.27,56.11 150.58,55.42 149.75,55.42 148.33,54.01 R1704.2 148.66,53.48 148.77,53.38 148.77,52.39 R1705.1
LAN0LED1: length 20.4
  TOP w0.1: R1719.2 132.39,55.58 v4(132.39,56.56) ; U1701.80 v4(150.87,56.68)
  L2 w0.1: v4(150.87,56.68) 150.87,56.06 150.71,55.89 144.79,55.89 144.46,56.22 132.73,56.22 v4(132.39,56.56)
LAN1LED0: length 41.9
  TOP w0.1: R1707.1 147.02,52.4 147.02,53.35 147.15,53.48 R1706.2 149.7,55.71 150.34,55.71 150.47,55.85 U1701.79 ; v1(170.29,36.25) 170.3,36.24 R2012.1
  L3 w0.1: v2(149.34,44.52) 163.53,44.52 167.02,41.02 167.02,39.68 170.29,36.41 v1(170.29,36.25) ; v1(147.46,51.94) 147.97,51.43 149.29,51.43 v2(149.34,51.38)
  L6 w0.1: v2(149.34,51.38) v2(149.34,44.52)
LAN1LED1: length 30.8
  TOP w0.1: U1701.78 v1(150.07,56.58)
  L3 w0.1: v1(150.07,56.58) 150.17,56.58 v2(150.33,56.41) ; v1(168.38,44.24) 168.38,44.24 167.69,44.92 167,44.92 167,44.93 166.71,44.93 166.71,44.92 150.24,44.92 v2(150.09,45.07)
  L6 w0.1: v2(150.09,45.07) 149.9,45.27 149.76,45.41 149.76,55.84 v2(150.33,56.41)
LAN1LED_G+: length 8.5
  TOP w0.1: R2007.2 169.17,44.22 R2003.2 169.96,44.22 TVS2000.2 170.04,44.24 170.42,44.62 174.14,44.62 J2000.D3
LAN1LED_Y+: length 6.1
  TOP w0.1: J2000.D1 175.06,35.43 TVS2003.2 171.88,35.43 R2012.2 171.08,35.42 R2005.2
LAN1LED_Y-: length 6
  TOP w0.1: R2015.2 171.1,36.25 R2013.2 TVS2005.2 175.1,36.25 J2000.D2
LAN2LED0: length 51.8
  TOP w0.1: U1701.75 148.87,55.93 147.17,54.23 146.41,54.23 146.09,53.9 145.8,53.9 145.66,53.76 R1709.2 145.99,53.48 146.09,53.37 146.09,52.23 145.8,51.94 R1710.1 145.66,51.94 v1(145.64,51.92) ; R2006.2 v1(170.35,58.42)
  L3 w0.1: v2(165.57,57.53) 166.45,58.42 v1(170.35,58.42) ; v2(165.12,44.57) 164.97,44.72 149.67,44.72 149.5,44.9 148.11,44.9 v2(148.05,44.83) ; v1(145.64,51.92) v2(146.24,51.92)
  L6 w0.1: v2(146.24,51.92) 146.51,51.64 146.51,46.37 v2(148.05,44.83) ; v2(165.12,44.57) 165.12,45.57 165.11,45.58 165.11,56.3 165.57,56.76 v2(165.57,57.53)
LAN2LED1: length 38.3
  TOP w0.1: R2002.1 168.05,68.35 v1(168.06,68.35) ; v1(149.67,56.42) 149.67,56.42 U1701.77
  L3 w0.1: v2(168.52,71.49) 167.04,71.49 166.4,70.85 165.53,70.85 165.04,71.35 158.06,71.35 157.57,70.85 149.89,70.85 v2(149.68,70.64) ; v1(168.06,68.35) 168.45,68.35 168.5,68.41 v2(168.52,68.41) ; v2(149.34,56.42) v1(149.67,56.42)
  L6 w0.1: v2(149.34,56.42) 149.34,70.3 v2(149.68,70.64) ; v2(168.52,71.49) 168.52,71.49 v2(168.52,68.41)
LAN2LED_G+: length 8.7
  TOP w0.1: J2001.D3 174.08,68.37 173.51,68.94 170.71,68.94 TVS2002.2 170.39,68.26 170.28,68.15 168.92,68.15 R2002.2 168.84,68.21 168.84,67.39 R2001.2
LAN2LED_Y+: length 5.1
  TOP w0.1: J2001.D1 175.33,57.11 TVS2001.2 171.24,57.11 R2004.2
LAN2LED_Y-: length 5.3
  TOP w0.1: J2001.D2 174.74,57.84 TVS2004.2 171.22,57.84 R2006.1
LAN3LED0: length 60
  TOP w0.1: R1908.1 170.43,78.47 R1912.1 ; U1701.74 148.47,55.88 147.05,54.46 146.29,54.46 145.95,54.11 145.41,54.11 R1711.2 144.45,53.47 144.35,53.37 144.35,52.35 R1712.1
  L3 w0.1: v1(170.42,78.34) 170.02,77.94 v2(165.84,77.94) ; v2(146.24,70.58) 146.72,71.06 157.49,71.06 158.01,71.58 165.12,71.58 165.39,71.31 v2(165.76,71.31) ; v2(144.26,51.93) v1(144.77,51.93)
  L6 w0.1: v2(165.84,77.94) 165.69,77.79 165.69,72.2 165.75,72.14 165.75,72.14 165.96,71.93 165.96,71.93 165.97,71.92 165.97,71.52 v2(165.76,71.31) ; v2(146.24,70.58) 146.24,70.54 146.04,70.35 146.04,61.77 144.26,59.99 v2(144.26,51.93)
LAN3LED1: length 53
  L3 w0.1: v1(167.38,90.42) 166.81,89.85 v2(165.05,89.85) ; v2(164.77,57.4) 164.47,57.1 158.47,57.1 157.39,56.02 147.9,56.02 v1(147.67,56.25)
  L6 w0.1: v2(164.77,57.4) 165,57.63 165,84.83 164.86,84.97 164.86,89.67 v2(165.05,89.85)
LAN4LED0: length 83.6
  TOP w0.1: v1(143.01,51.95) 143.48,52.42 143.48,53.37 143.38,53.47 R1714.2 143.01,53.84 143.11,53.94 144.04,53.94 144.77,54.67 145.61,54.67 146.87,55.93 U1701.70 ; R1907.1 170.74,101.25 v1(170.76,101.23)
  L3 w0.1: v2(165.68,100.79) 169.21,100.79 169.66,101.23 v1(170.76,101.23) ; v2(146.21,71.12) 146.35,71.26 157.4,71.26 157.92,71.78 165.2,71.78 165.21,71.78 165.62,71.78 165.62,71.79 165.61,71.79 165.61,71.79 165.61,71.79 v2(165.61,71.79) ; v1(143.01,51.95) v2(143.7,51.95)
  L6 w0.1: v2(165.68,100.79) 165.43,100.54 165.43,90.56 165.82,90.17 165.82,89.56 165.48,89.21 165.48,85.94 165.78,85.64 165.78,85.18 165.48,84.88 165.48,71.92 165.61,71.79 v2(165.61,71.79) ; v2(146.21,71.12) 145.81,70.73 145.81,61.89 143.95,60.02 143.95,52.19 v2(143.7,51.95)
LAN4LED1: length 76.1
  TOP w0.1: v1(166.57,110.72) 166.57,111.02 165.59,112 R1903.1
  L3 w0.1: v1(147.28,56.24) 147.7,55.82 157.52,55.82 158.6,56.89 164.97,56.89 v2(165.2,57.13) ; v2(165.81,110.34) 166.2,110.34 v1(166.57,110.72)
  L6 w0.1: v2(165.2,57.13) 165.2,84.89 165.58,85.27 165.58,85.56 165.28,85.86 165.28,89.3 165.62,89.64 165.62,90.09 165.23,90.48 165.23,109.76 v2(165.81,110.34)
LDRV1: length 8
  L6 w0.2: v3(103.63,32.85) 103.63,36.03 104.1,36.5 v3(104.1,40.1)
  BOTTOM w0.2: v3(104.1,40.1) 104.22,40.23 Q701.4
LDRV2: length 9.3
  BOTTOM w0.2: Q703.4 97.5,38.75 101.58,34.67 101.58,34.27 102.13,33.72 U700.29
LM5177_VCC: length 14.9
  L6 w0.2: v3(103.15,34.77) 103.15,29.85 101.13,27.83 v3(101.13,27.05)
  BOTTOM w0.2: v3(101.13,27.05) 101.13,26.05 101.63,25.55 101.63,24.65 101.83,24.45 R705.1
  BOTTOM w0.3: v3(103.15,34.77) 103.13,34.76 U700.31
LM5177_VIN: length 19.3
  L6 w0.2: v3(108.15,24.55) 111.4,27.8 v3(111.4,38.15)
  BOTTOM w0.2: U700.3 105.63,25.65 C703.1 106.25,25.25 106.95,24.55 v3(108.15,24.55)
LNE3LED_G+: length 9.5
  TOP w0.1: R1902.2 168.21,90.43 ; 168.21,90.43 168.87,90.43 v1(168.92,90.49) ; 168.21,90.43 R1905.2
  L3 w0.1: J1900.D3 175.51,90.75 172.96,90.75 172.24,91.47 171.15,91.47 170.92,91.24 169.65,91.24 168.92,90.52 v1(168.92,90.49)
LNE3LED_Y+: length 5.6
  TOP w0.1: R1906.2 171.23,77.63 R1912.2 171.27,78.51 TVS1902.2 175.88,78.51 J1900.D1
LNE3LED_Y-: length 6.3
  TOP w0.1: J1900.D2 174.19,79.24 TVS1904.2 172.01,79.29 R1908.2 171.21,79.3 R1913.2
LNE4LED_G+: length 11.4
  TOP w0.1: J1901.D3 174.29,112.27 172.74,113.82 168.61,113.82 167.61,112.81 167.17,112.81 R1904.2 R1903.2 TVS1900.2
LNE4LED_Y+: length 4.8
  TOP w0.1: J1901.D1 175.08,101.26 TVS1903.2 172.33,101.25 R1907.2
LX: length 2.7
  TOP w0.18: 142.47,58.68 U1701.63 ; 143.27,57.99 U1701.64 142.44,58.28
  TOP w0.25: 143.24,57.95 143.27,57.99 ; 142.47,58.68 142.29,58.51 142.29,58.28 142.37,58.21 142.44,58.28
M25207_BIAS_5VOUT: length 20.1
  L6 w0.2: v3(71.95,59.67) 71.95,59.32 73.05,58.22 v3(73.05,56.67) 74.65,55.06 74.65,52.17 v3(71.89,49.41)
  L7 w0.2: v3(71.89,49.41) 71.54,49.07 70.28,49.07 v7(69.94,49.41)
  BOTTOM w0.2: v3(71.95,59.67) 71,58.72 70.1,58.72 69.99,58.6 C614.1 R602.1 69.99,57 69.79,56.8 U600.13
MCU_BOOT1: length 10.6
  TOP w0.1: TP2622.1 42.9,53.8 v4(42.9,53.8) ; v4(53.14,53.41) 53.17,53.38 J2600.A14
  L2 w0.1: v4(42.9,53.8) 43.13,53.57 52.98,53.57 v4(53.14,53.41)
MCU_RESERVED_BUTTON: length 10.5
  TOP w0.1: TP2623.1 42.96,52.41 v4(42.97,52.4)
  L2 w0.1: v4(53.17,51.99) 52.7,52.47 43.03,52.47 v4(42.97,52.4)
MD_GPIO_51_1P8: length 7.3
  TOP w0.1: TP2625.1 44.35,52.61 50.03,52.61 50.63,53.22 J2600.C14
MD_GPIO_111_1P8: length 4
  TOP w0.1: TP2631.1 44.49,36.38 45.73,36.38 46.08,36.02 47.54,36.02 48.09,35.48 J2600.E28
MD_GPIO_123_1P8: length 94.8
  TOP w0.1: v1(52.08,51.98) 52.08,51.99 J2600.B15
  L3 w0.1: v2(98.47,48.35) 98.18,48.35 97.81,48.72 86.27,48.72 85.65,49.34 83.5,49.34 83.3,49.13 55.59,49.13 54.93,49.79 54.93,49.8 52.75,51.98 v1(52.08,51.98)
  L6 w0.1: v3(98.7,93.85) 99.3,93.25 99.3,75 98.8,74.5 98.8,73.61 99.04,73.36 99.04,63.37 98.8,63.13 98.8,61.67 99.1,61.37 99.1,48.98 v2(98.47,48.35)
MD_GPIO_124_1P8: length 96.9
  TOP w0.1: v1(52.09,50.72) 52.09,50.72 J2600.B16
  L3 w0.1: v1(52.09,50.72) 53.71,50.72 54.57,49.86 54.58,49.86 54.73,49.72 54.73,49.7 55.51,48.93 83.38,48.93 83.59,49.14 85.57,49.14 86.19,48.52 97.73,48.52 98.29,47.95 99.11,47.95 v2(99.12,47.94)
  L6 w0.1: v3(99.55,95.05) 99.8,94.8 99.8,74.93 99.29,74.43 99.29,73.68 99.44,73.53 99.44,63.21 99.3,63.06 99.3,61.77 99.55,61.52 99.55,48.37 v2(99.12,47.94)
  BOTTOM w0.1: TP2604.1 v3(99.55,95.05)
MD_GPIO_125_1P8: length 96.8
  TOP w0.1: J2600.B17 52.09,49.45 v1(52.1,49.45)
  L3 w0.1: v1(52.1,49.45) 52.11,49.45 52.45,49.11 54.4,49.11 55.24,48.27 83.56,48.27 83.83,48.54 85.32,48.54 85.94,47.92 97.48,47.92 98.21,47.18 v2(98.59,47.18)
  L6 w0.1: v3(98.7,95.05) 99.55,94.2 99.55,74.97 99.05,74.47 99.05,73.64 99.24,73.44 99.24,63.29 99.05,63.09 99.05,61.72 99.3,61.47 99.3,48.62 98.59,47.91 v2(98.59,47.18)
MD_GPIO_128_1P8: length 7.1
  L2 w0.1: v4(43.87,44.9) 44.61,45.64 v4(50.63,45.64)
MD_GPIO_130_1P8: length 7
  TOP w0.1: TP2627.1 44,47.64 v4(44.01,47.65)
  L2 w0.1: v4(50.66,46.91) 49.91,47.65 v4(44.01,47.65)
MD_GPIO_132_1P8: length 6.3
  TOP w0.1: J2600.E24 47.75,40.21 47.28,40.21 47.08,40.01 43.34,40.01 TP2608.1
MD_GPIO_133_1P8: length 7.1
  TOP w0.1: J2600.E25 48.09,39.62 47.74,39.97 47.32,39.97 47.16,39.81 43.19,39.81 42.95,40.05 TP2609.1
MD_GPIO_134_1P8: length 5.7
  TOP w0.1: TP2617.1 43.65,46.18 47.13,46.18 47.67,45.64 J2600.E20
MD_GPIO_135_1P8: length 6.8
  TOP w0.1: J2600.E21 47.52,43.79 43.14,43.79 42.92,44.01 TP2618.1
MD_GPIO_136_1P8: length 7.5
  TOP w0.1: J2600.C18 50.63,48.17 50.11,47.64 45.36,47.64 TP2626.1
MD_GPIO_138_1P8: length 6.8
  TOP w0.1: J2600.E26 48.08,38.02 47.56,38.54 42.11,38.54 TP2610.1
MD_GPIO_139_1P8: length 5.1
  L3 w0.1: v1(48.02,48.19) 47.8,48.41 43.23,48.41 43.19,48.45 v1(43.03,48.45)
MD_GPIO_140_1P8: length 5.6
  TOP w0.1: J2600.E19 47.57,46.38 43.47,46.38 TP2616.1
MD_RESOUT_1P8: length 99.6
  TOP w0.1: v1(107.86,37.63) 107.91,37.58 116.89,37.58 117.4,38.09 J2700.G9
  L3 w0.1: v1(107.86,37.63) 107.5,37.27 87.07,37.27 86.73,36.93 85.6,36.93 85.44,36.77 84.82,36.77 84.64,36.95 62.23,36.95 61.44,37.74 52.49,37.74 51.93,38.3 46.42,38.3 45.28,37.16 42.65,37.16 42.29,37.52 41.57,37.52 41.38,37.33 38.23,37.33 v2(37.63,37.93)
  L6 w0.1: v3(38.87,54.87) 38.87,54.87 38.81,54.81 38.81,52.06 37.98,51.23 37.98,39.15 37.59,38.76 37.59,37.97 v2(37.63,37.93)
  BOTTOM w0.1: v3(38.87,54.87) 38.91,54.91 R3115.1
MDIREF: length 3.3
  TOP w0.1: U1701.13 152.47,73.61 153.59,74.73 153.59,75.11 R1716.1
MIC_I2C_SCL_1P8: length 53.8
  TOP w0.1: U3500.17 88.15,94.4 v1(87.65,93.9) ; U3501.17 v1(52.35,109.25)
  L3 w0.1: v1(52.35,109.25) 52.6,109.5 86.63,109.5 v2(86.88,109.75) ; v1(87.65,93.9) v2(87.35,93.9)
  L6 w0.1: v2(86.88,109.75) 87.28,109.35 87.28,99.17 87.48,98.97 87.48,94.03 v2(87.35,93.9)
MIC_I2C_SDA_1P8: length 54.9
  TOP w0.1: v1(87.65,93.05) 88.5,93.9 U3500.18 ; U3501.18 v1(52.85,109.25)
  L3 w0.1: v1(87.65,93.05) v2(87.35,93.05) ; v2(87.52,109.74) 87.03,109.25 v1(52.85,109.25)
  L6 w0.1: v2(87.52,109.74) 87.52,99.28 87.73,99.07 87.73,93.43 v2(87.35,93.05)
MIC_MI2S_MCLK_1P8: length 83.7
  TOP w0.1: J2600.B24 51.9,40.63 52.37,41.1 54.23,41.1 55.68,42.54 55.68,42.55 56.17,43.04 56.54,43.04 57.06,43.56 v1(57.14,43.56) ; R3512.1 89.9,89.95 85.4,85.45 85.4,44.71 85.48,44.63 v1(85.48,44.55)
  L3 w0.1: v1(57.14,43.56) 57.14,43.62 58.23,44.71 59.43,44.71 59.43,44.71 59.97,44.71 59.97,44.71 65.07,44.71 65.09,44.7 65.63,44.7 65.64,44.71 85.32,44.71 v1(85.48,44.55)
MIC_MI2S_MCLK_1P8_1: length 54.4
  TOP w0.1: v1(89.9,91.7) 90.25,92.05 U3500.20
  L3 w0.1: v1(55.97,110.77) 56.11,110.9 v2(88.3,110.9) ; v2(89.4,91.8) 89.5,91.7 v1(89.9,91.7)
  L6 w0.1: v2(88.3,110.9) 88.3,92.53 89.03,91.8 v2(89.4,91.8)
MIC_MI2S_SCK_1P8: length 9.7
  TOP w0.1: v4(51.9,43.31) 51.9,43.3 J2600.B22
  L2 w0.1: v4(51.9,43.31) 50.65,43.31 49.81,42.47 43.49,42.47 v4(42.94,43.01)
MIC_MI2S_SCK_1P8_1: length 152.6
  TOP w0.1: v1(57.62,112.59) 57.62,112.59 54.4,112.59 54.17,112.37 U3501.22 ; v1(85.99,45.65) 85.99,45.66 86.09,45.77 86.09,85.29 91.25,90.45 v1(91.25,93.25) ; v4(42.11,42.99) 42.14,43.02 R3507.2
  L2 w0.1: v4(42.11,42.99) 42.11,43.1 42.66,43.65 50.22,43.65 50.75,44.18 54.91,44.18 v5(55.07,44.34)
  L3 w0.1: v1(85.99,45.65) 57.64,45.65 56.33,44.34 v5(55.07,44.34) ; v2(90.1,112.15) 59.09,112.15 58.65,112.59 v1(57.62,112.59) ; v2(89.4,93.65) 89.8,93.25 v1(91.25,93.25)
  L6 w0.1: v2(90.1,112.15) 89.4,111.45 v2(89.4,93.65)
MIC_MI2S_SDOUT_1P8: length 141.2
  TOP w0.1: J2600.B23 52.44,41.3 54.14,41.3 56.09,43.24 56.37,43.24 v1(56.74,43.61) ; R3529.1 57.18,111.87 57.65,111.39 v1(58.47,111.39)
  L3 w0.1: v1(90.75,90.9) v2(89.4,90.9) ; v1(56.74,43.61) 56.84,43.61 57.14,43.92 57.15,43.92 58.14,44.91 59.51,44.91 59.51,44.91 59.89,44.91 59.89,44.91 65.16,44.91 65.17,44.9 65.55,44.9 65.56,44.91 85.55,44.91 85.73,44.73 85.73,44.73 85.96,44.49 v2(86.66,44.49) ; v1(58.47,111.39) 58.62,111.55 89.45,111.55 v2(90.1,110.9)
  L6 w0.1: v2(86.66,44.49) 86.51,44.64 86.51,47.05 86.66,47.2 86.66,49.05 86.19,49.52 86.19,71.03 86.78,71.62 86.78,75.86 86.92,76 86.92,87.97 89.4,90.45 v2(89.4,90.9) 89.7,90.9 90.1,91.3 v2(90.1,110.9)
MIC_MI2S_WS_1P8: length 83.1
  TOP w0.1: v1(54.34,44.94) 54.31,44.91 52.51,44.91 51.97,44.37 J2600.B21 ; R3506.1 91.9,90.15 86.72,84.97 v1(86.72,45.77)
  L3 w0.1: v1(54.34,44.94) 54.45,45.05 56.05,45.05 57.29,46.28 86.12,46.28 86.63,45.77 v1(86.72,45.77)
MIC_MI2S_WS_1P8_1: length 60.4
  TOP w0.1: TP3507.1 58.27,113.45 58.26,113.45 57.05,113.45 56.85,113.24 54.33,113.24 53.95,112.87 U3501.23 ; v1(91.9,91.7) 91.75,91.85 U3500.23
  L3 w0.1: v1(91.9,91.7) 90.9,92.7 v2(89.4,92.7) ; v1(58.84,113.44) 59.12,113.44 59.65,112.9 v2(88.31,112.9)
  L6 w0.1: v2(89.4,92.7) 88.83,93.27 88.83,112.38 v2(88.31,112.9)
MIC_RST_1P8_N: length 90.6
  TOP w0.1: J2600.B20 52.63,46.37 53.57,46.37 v1(53.62,46.42)
  L3 w0.1: v1(53.62,46.42) 53.62,46.36 56.23,46.36 56.95,47.08 86.53,47.08 86.71,46.91 v2(86.86,46.91) ; v2(90.55,95.8) 87.7,95.8 v1(86.85,96.65)
  L6 w0.1: v2(86.86,46.91) 86.86,49.13 86.39,49.6 86.39,70.95 86.98,71.54 86.98,75.77 87.12,75.92 87.12,87.82 90.45,91.15 90.45,95.7 v2(90.55,95.8)
MICBIAS1: length 1.7
  TOP w0.1: U3500.5 93.65,95.9 C3507.1
MICBIAS3: length 2.4
  TOP w0.1: C3525.1 49.6,115.54 49.6,115.45 50.85,114.2 U3501.5
Net_555: length 0.7
  BOTTOM w0.3: 185.42,43.76 184.69,43.76 184.68,43.75
Net_556: length 0.7
  BOTTOM w0.3: 185.42,45.76 184.73,45.76 184.71,45.78
Net_557: length 0.7
  BOTTOM w0.1: 184.77,37.78 184.79,37.76 185.42,37.76
Net_558: length 0.7
  BOTTOM w0.1: 185.42,39.76 184.82,39.76 184.78,39.72
Net_564: length 0.6
  BOTTOM w0.1: 184.79,65.67 184.82,65.7 185.42,65.7
Net_565: length 0.6
  BOTTOM w0.1: 184.79,67.68 184.81,67.7 185.42,67.7
Net_566: length 0.6
  BOTTOM w0.1: 185.42,59.7 184.82,59.7 184.81,59.69
Net_567: length 0.7
  BOTTOM w0.1: 184.76,61.67 184.79,61.7 185.42,61.7
NVME_PCIE1_CLKREQ_1P8: length 31.1
  TOP w0.1: U2301.3 131.31,40.32 130.07,39.08 130.07,38.12 130.07,38.12 130.07,36.94 v1(130.25,36.77) ; v1(111.05,39.37) J2700.B10
  L3 w0.1: v1(130.25,36.77) 130,37.02 129.4,37.02 129.15,36.77 123.44,36.77 122.69,37.52 117.35,37.52 116.4,38.47 112.45,38.47 111.69,39.22 111.2,39.22 v1(111.05,39.37)
NVME_PCIE1_RST_1P8: length 26.3
  TOP w0.1: U2302.3 128.77,45.28 129.14,44.91 129.14,38.97 129.13,38.95 v1(129.13,38.92) ; J2700.B11 111.7,39.99 v1(111.7,39.49)
  L3 w0.1: v1(111.7,39.49) 111.7,39.49 111.85,39.49 112.38,38.97 116.5,38.97 117.15,38.32 120.35,38.32 120.98,38.95 129.13,38.95 v1(129.13,38.92)
NVME_PCIE1_WAKE_1P8: length 30.5
  TOP w0.1: v1(129.75,36.77) 129.75,39.1 131.11,40.47 131.11,46.3 130.96,46.45 U2301.2 ; v1(111.9,38.62) 111.58,38.62 J2700.B9
  L3 w0.1: v1(111.9,38.62) 112.25,38.27 116.3,38.27 117.25,37.32 122.55,37.32 123.3,36.57 129.35,36.57 129.55,36.77 v1(129.75,36.77)
NVME_PWR_EN_1P8: length 4
  TOP w0.1: R2303.1 123.14,41.26 120.57,41.26 J2700.I11
NVME_THERM: length 15
  TOP w0.1: J2700.B8 111.46,36.82 v1(111.7,36.59) ; v1(125.09,34.67) 125.06,34.64 RT2300.1
  L3 w0.1: v1(111.7,36.59) 111.87,36.42 115.68,36.42 116.73,35.37 119.25,35.37 119.5,35.12 124.64,35.12 v1(125.09,34.67)
OVCUR0: length 4.6
  TOP w0.1: TP2401.1 148.94,95.72 R2401.2 149.41,94.71 150.07,94.04 150.07,92.69 150.28,92.48 U2400.41
OVCUR1: length 48.9
  TOP w0.1: v1(141.78,104.07) 141.75,104.03 R1811.2
  L3 w0.1: v2(140.04,80.58) 140.21,80.58 142.93,83.3 146.81,83.3 147.79,82.32 153.05,82.32 155.87,85.14 155.87,85.3 156.2,85.63 158.15,85.63 158.6,86.08 v1(159.61,86.08) ; v1(141.78,104.07) v2(141.38,104.07)
  L6 w0.1: v2(140.04,80.58) 139.73,80.89 139.73,90.05 140.28,90.6 140.28,96.23 141.38,97.33 v2(141.38,104.07)
OVCUR2: length 36.9
  TOP w0.1: v1(160.16,117.21) 161.31,116.07 R1812.2 162.13,116.08 U2701.3 ; v1(158.4,85.34) 158.41,85.34 U2400.75
  L3 w0.1: v1(158.4,85.34) 158.52,85.46 158.52,85.46 v2(158.77,85.71) ; v1(160.16,117.21) v2(159.77,117.21)
  L6 w0.1: v2(159.77,117.21) 159.54,116.98 159.54,108.88 159.41,108.74 159.41,105.67 159.63,105.45 159.63,87.97 158.77,87.12 v2(158.77,85.71)
OVCUR3: length 29.5
  TOP w0.1: U2702.3 147.89,110.37 v1(146.6,110.37) ; U2400.20 v1(158.81,94.21)
  L3 w0.1: v1(146.6,110.37) 151.15,110.37 152.73,108.79 153.43,108.79 153.69,109.04 158.66,109.04 v2(158.84,108.85) ; v2(159.07,94.63) 159.07,94.47 v1(158.81,94.21)
  L6 w0.1: v2(158.84,108.85) 159.01,108.69 159.01,105.51 159.22,105.29 159.22,94.78 v2(159.07,94.63)
OVCUR4: length 19
  TOP w0.1: R1814.2 v1(148.45,107.37) 148.44,107.35 U2703.3
  L3 w0.1: v1(150.81,92.88) 150.45,92.88 150.23,93.11 v2(150.23,93.12) ; v1(148.45,107.37) 148.62,107.19 v2(150.68,107.19)
  L6 w0.1: v2(150.23,93.12) 150.23,93.17 149.93,93.47 149.93,96.98 150.24,97.29 150.24,105.51 150.37,105.63 150.37,106.75 150.68,107.06 v2(150.68,107.19)
P0MDIAN: length 84.4
  L3 w0.05: v2(118.84,58.15) 119,58.31 119,58.52 119.17,58.69 133.78,58.69 135.08,57.39 155.19,57.39 155.56,57.02 155.56,56.79 v1(155.67,56.68) ; v2(121.24,96.3) 121.41,96.46 121.41,96.96 v1(121.01,97.37)
  L6 w0.05: v2(121.24,96.3) 121.41,96.14 121.41,95.31 121.17,95.08 arc(121.08,94.86) 121.17,94.65 121.33,94.49 arc(121.37,94.4) 121.33,94.31 arc(121.24,94.27) 121.16,94.31 120.99,94.47 arc(120.57,94.47) 120.57,94.05 120.73,93.89 arc(120.77,93.8) 120.73,93.71 arc(120.64,93.67) 120.55,93.71 120.39,93.87 arc(120.18,93.96) 119.97,93.87 114.42,88.33 114.42,83.31 119,78.73 119,58.31 v2(118.84,58.15)
P0MDIAP: length 84.4
  L3 w0.05: v2(121.74,96.3) 121.58,96.46 121.58,96.95 v1(122,97.37) ; v2(119.34,58.15) 119.18,58.31 119.18,58.45 119.25,58.51 119.7,58.51 arc(119.77,58.48) 119.8,58.41 119.8,58.23 arc(119.9,58.13) 120,58.23 120,58.41 arc(120.03,58.48) 120.1,58.51 133.71,58.51 135.01,57.21 155.12,57.21 155.38,56.95 155.38,56.79 v1(155.27,56.68)
  L6 w0.05: v2(121.74,96.3) 121.58,96.14 121.58,95.24 121.29,94.95 arc(121.26,94.86) 121.29,94.78 121.46,94.61 arc(121.54,94.4) 121.46,94.19 arc(121.24,94.1) 121.03,94.19 120.87,94.35 arc(120.69,94.35) 120.69,94.17 120.85,94.01 arc(120.94,93.8) 120.85,93.59 arc(120.64,93.5) 120.43,93.59 120.27,93.75 arc(120.18,93.79) 120.09,93.75 114.6,88.26 114.6,83.38 119.18,78.81 119.18,58.31 v2(119.34,58.15)
P0MDIBN: length 84.1
  L3 w0.05: v1(118.04,97.37) 118.44,96.96 118.44,96.48 v2(118.27,96.31) ; v1(156.47,56.98) 156.36,57.09 156.36,57.4 155.66,58.1 135.6,58.1 arc(135.57,58.11) 135.55,58.12 134.4,59.28 arc(134.13,59.45) 133.82,59.51 118.35,59.51 arc(118.26,59.5) 118.18,59.44 117.87,59.13 arc(117.85,59.11) 117.85,59.09 117.85,58.93 v2(117.69,58.76)
  L6 w0.05: v2(118.27,96.31) 118.43,96.15 118.43,95.8 arc(118.52,95.59) 118.73,95.5 118.98,95.5 arc(119.11,95.37) 118.98,95.25 118.73,95.25 arc(118.52,95.16) 118.43,94.95 118.43,93.91 113.57,89.05 113.57,82.6 117.85,78.32 117.85,58.93 v2(117.69,58.76)
P0MDIBP: length 84.1
  L3 w0.05: v2(118.77,96.31) 118.61,96.47 118.61,96.95 v1(119.03,97.37) ; v2(118.19,58.76) 118.02,58.93 118.02,59.02 arc(118.03,59.04) 118.04,59.06 118.3,59.32 arc(118.32,59.33) 118.35,59.34 118.5,59.34 arc(118.59,59.3) 118.62,59.21 arc(118.66,59.13) 118.75,59.09 arc(118.84,59.13) 118.87,59.21 arc(118.91,59.3) 119,59.34 arc(119.09,59.3) 119.12,59.21 arc(119.16,59.13) 119.25,59.09 arc(119.34,59.13) 119.37,59.21 arc(119.41,59.3) 119.5,59.34 133.82,59.34 arc(134.07,59.29) 134.27,59.15 135.43,58 arc(135.51,57.95) 135.6,57.93 155.58,57.93 156.18,57.33 156.18,57.09 v1(156.07,56.98)
  L6 w0.05: v2(118.19,58.76) 118.02,58.93 118.02,78.39 113.74,82.67 113.74,88.98 118.61,93.84 118.61,94.95 arc(118.65,95.04) 118.73,95.07 118.98,95.07 arc(119.28,95.37) 118.98,95.67 118.73,95.67 arc(118.65,95.71) 118.61,95.8 118.61,96.15 v2(118.77,96.31)
P0MDICN: length 84.5
  L3 w0.05: v1(115.06,97.37) 115.46,96.96 115.46,96.44 v2(115.3,96.28) ; v1(158.87,58.68) 158.76,58.57 157.75,58.57 157.47,58.85 arc(157.45,58.86) 157.42,58.87 136.02,58.87 arc(136,58.87) 135.98,58.89 134.88,59.99 arc(134.61,60.16) 134.3,60.23 117.29,60.23 arc(117.2,60.21) 117.12,60.16 116.81,59.84 arc(116.79,59.82) 116.79,59.79 116.79,59.63 v2(116.63,59.47)
  L6 w0.05: v2(116.63,59.47) 116.79,59.63 116.79,77.84 112.66,81.96 112.66,89.64 115.46,92.45 115.46,96.11 v2(115.3,96.28)
P0MDICP: length 84.5
  L3 w0.05: v1(158.87,58.28) 158.76,58.39 158.48,58.39 arc(158.4,58.36) 158.36,58.27 158.36,58.26 arc(158.23,58.13) 158.11,58.26 158.11,58.27 arc(158.07,58.36) 157.98,58.39 157.68,58.39 157.38,58.69 136.02,58.69 arc(135.93,58.71) 135.85,58.76 134.75,59.86 arc(134.55,60) 134.3,60.05 117.29,60.05 arc(117.27,60.05) 117.25,60.03 116.98,59.77 arc(116.97,59.75) 116.96,59.72 116.96,59.63 v2(117.13,59.47) ; v1(116.05,97.37) 115.64,96.95 115.64,96.44 v2(115.8,96.28)
  L6 w0.05: v2(115.8,96.28) 115.64,96.11 115.64,92.37 112.84,89.57 112.84,82.03 116.96,77.91 116.96,59.63 v2(117.13,59.47)
P0MDIDN: length 84.5
  L3 w0.05: v2(115.64,60.34) 115.79,60.49 115.79,60.74 arc(115.79,60.77) 115.81,60.79 115.97,60.96 arc(116,60.97) 116.02,60.97 116.12,60.97 134.86,60.97 arc(135.12,60.92) 135.34,60.77 135.83,60.28 136.36,59.75 arc(136.53,59.64) 136.72,59.6 157.56,59.6 arc(157.58,59.61) 157.6,59.62 157.67,59.69 arc(157.74,59.74) 157.83,59.76 158.75,59.76 v1(158.87,59.88) ; v2(112.33,96.19) 112.5,96.35 112.5,96.95 112.08,97.37 v1(112.08,97.37)
  L6 w0.05: v2(115.64,60.34) 115.8,60.5 115.8,77.34 111.7,81.44 111.7,90.29 112.5,91.08 112.5,94.44 arc(112.65,94.87) 113.04,95.1 arc(113.14,95.24) 113.02,95.35 112.8,95.35 arc(112.58,95.44) 112.5,95.65 112.5,96.03 v2(112.33,96.19)
P0MDIDP: length 84.5
  L3 w0.05: v2(116.14,60.34) 115.96,60.51 115.96,60.67 arc(115.97,60.69) 115.98,60.72 116.05,60.78 arc(116.07,60.79) 116.09,60.8 134.86,60.8 arc(135.05,60.76) 135.22,60.65 135.71,60.16 arc(135.71,60.16) 135.71,60.16 136.24,59.63 arc(136.46,59.48) 136.72,59.43 157.63,59.43 arc(157.65,59.43) 157.67,59.45 157.79,59.56 arc(157.81,59.58) 157.83,59.58 158.04,59.58 arc(158.12,59.55) 158.16,59.47 arc(158.28,59.34) 158.41,59.47 arc(158.44,59.55) 158.53,59.58 158.77,59.58 v1(158.87,59.48) ; v2(112.83,96.19) 112.67,96.35 112.67,96.95 v1(113.08,97.37)
  L6 w0.05: v2(112.83,96.19) 112.67,96.03 112.67,95.65 arc(112.71,95.56) 112.8,95.53 113.02,95.53 arc(113.32,95.25) 113.08,94.93 arc(112.79,94.76) 112.67,94.44 112.67,91.01 111.88,90.22 111.88,81.51 115.98,77.41 115.98,60.5 v2(116.14,60.34)
P1_MDI_AN: length 42.3
  TOP w0.062: v1(171.03,43.32) CR2003.4 172.05,43.32 172.19,43.47 174.1,43.47 175.4,44.77 179.46,44.77 180.05,45.36 180.11,45.47 180.19,45.5 J2000.3
  L3 w0.05: v2(166.18,61.35) 166.32,61.21 arc(166.33,61.2) 166.34,61.19 166.34,61.17 arc(166.34,61.16) 166.34,61.16 166.34,60.81 166.23,60.69 162.81,60.69 162.53,60.97 159.01,60.97 arc(158.99,60.97) 158.97,60.99 v1(158.87,61.08) ; v2(166.13,44.13) 166.3,43.96 166.3,43.76 166.59,43.48 170.88,43.48 v1(171.03,43.32)
  L6 w0.05: v2(166.18,61.35) 166.34,61.19 166.34,44.59 166.3,44.55 166.3,44.3 v2(166.13,44.13)
P1_MDI_AP: length 42.3
  TOP w0.062: J2000.2 179.91,45.63 179.94,45.55 179.9,45.47 179.38,44.96 175.32,44.96 174.02,43.65 172.21,43.65 172.04,43.82 CR2003.5 v1(171.03,43.82)
  L3 w0.05: v1(171.03,43.82) 170.86,43.65 166.66,43.65 166.48,43.83 166.48,43.97 v2(166.64,44.13) ; v2(166.68,61.35) 166.54,61.21 arc(166.52,61.19) 166.52,61.16 166.52,60.74 166.3,60.52 162.73,60.52 162.46,60.79 159.6,60.79 arc(159.56,60.78) 159.53,60.76 arc(159.52,60.73) 159.52,60.7 arc(159.49,60.64) 159.43,60.61 159.35,60.61 arc(159.29,60.64) 159.27,60.7 arc(159.26,60.73) 159.25,60.76 arc(159.22,60.78) 159.18,60.79 158.98,60.79 v1(158.87,60.68)
  L6 w0.05: v2(166.68,61.35) 166.52,61.19 166.52,44.52 166.48,44.48 166.48,44.28 v2(166.64,44.13)
P1_MDI_BN: length 44.1
  TOP w0.062: v1(171.03,41.82) CR2003.1 172.05,41.82 172.2,41.97 173.08,41.97 173.37,42.26 179.49,42.26 180.05,42.82 180.11,42.93 180.19,42.96 J2000.5
  L3 w0.05: v2(167.16,42.73) 167.32,42.56 167.32,42.31 167.65,41.99 170.87,41.99 v1(171.03,41.82) ; v2(167.16,62.5) 167.32,62.34 167.32,62.24 167.25,62.17 158.98,62.17 v1(158.87,62.28)
  L6 w0.05: v2(167.16,62.5) 167.32,62.34 167.32,42.89 v2(167.16,42.73)
P1_MDI_BP: length 44.1
  TOP w0.062: v1(171.03,42.32) CR2003.2 172.07,42.32 172.23,42.16 173,42.16 173.29,42.45 179.41,42.45 179.9,42.93 179.94,43.01 179.91,43.09 J2000.4
  L3 w0.05: v1(158.87,61.88) 158.98,61.99 159.13,61.99 arc(159.2,61.96) 159.23,61.9 arc(159.26,61.83) 159.33,61.8 159.38,61.8 arc(159.45,61.83) 159.48,61.9 arc(159.51,61.96) 159.58,61.99 167.32,61.99 167.5,62.17 167.5,62.34 v2(167.66,62.5) ; v2(167.66,42.73) 167.5,42.56 167.5,42.38 167.72,42.16 170.87,42.16 v1(171.03,42.32)
  L6 w0.05: v2(167.66,62.5) 167.5,62.34 167.5,42.89 v2(167.66,42.73)
P1_MDI_CN: length 47.6
  TOP w0.062: v1(170.98,40.12) CR2001.4 172.01,40.12 172.15,40.27 175.7,40.27 176.2,39.77 179.53,39.77 180.07,40.31 180.11,40.39 180.19,40.42 J2000.7
  L3 w0.05: v1(170.98,40.12) 170.83,40.28 168.52,40.28 168.31,40.49 168.31,40.67 v2(168.15,40.83) ; v1(158.87,63.48) 158.98,63.37 168.19,63.37 arc(168.22,63.37) 168.24,63.39 168.3,63.44 arc(168.31,63.46) 168.31,63.49 168.31,63.78 v2(168.15,63.94)
  L6 w0.05: v2(168.15,63.94) 168.31,63.78 168.31,40.99 v2(168.15,40.83)
P1_MDI_CP: length 47.5
  TOP w0.062: v1(170.98,40.62) CR2001.5 172,40.62 172.17,40.46 175.78,40.46 176.28,39.96 179.45,39.96 179.91,40.42 179.94,40.47 179.91,40.55 J2000.6
  L3 w0.05: v2(168.65,40.83) 168.48,40.66 168.48,40.56 168.59,40.46 170.82,40.46 170.98,40.62 v1(170.98,40.62) ; v2(168.65,63.94) 168.49,63.78 168.49,63.49 arc(168.47,63.4) 168.42,63.32 168.36,63.26 arc(168.28,63.21) 168.19,63.19 159.57,63.19 arc(159.5,63.17) 159.48,63.1 arc(159.45,63.04) 159.38,63.01 159.32,63.01 arc(159.25,63.04) 159.23,63.1 arc(159.2,63.17) 159.13,63.19 158.98,63.19 v1(158.87,63.08)
  L6 w0.05: v2(168.65,40.83) 168.49,40.99 168.49,63.78 v2(168.65,63.94)
P1_MDI_DN: length 50.7
  TOP w0.062: J2000.9 180.19,37.88 180.11,37.85 180.05,37.74 179.52,37.21 177.76,37.21 176.18,38.78 172.17,38.78 172.02,38.62 CR2001.1 v1(170.98,38.62)
  L3 w0.05: v1(158.87,64.68) 158.98,64.57 160.78,64.57 160.89,64.67 163.2,64.67 163.35,64.82 169.2,64.82 169.3,64.92 169.3,65.05 v2(169.14,65.22) ; v1(170.98,38.62) 170.82,38.79 169.5,38.79 169.33,38.96 169.33,39.1 169.14,39.29 v2(169.14,39.31)
  L6 w0.05: v2(169.14,65.22) 169.3,65.05 169.3,39.48 v2(169.14,39.31)
P1_MDI_DP: length 50.7
  TOP w0.062: J2000.8 179.91,38.01 179.94,37.93 179.9,37.85 179.44,37.4 177.83,37.4 176.26,38.97 172.16,38.97 172,39.12 CR2001.2 v1(170.98,39.12)
  L3 w0.05: v1(158.87,64.28) 158.98,64.39 159.14,64.39 arc(159.21,64.36) 159.25,64.28 arc(159.28,64.21) 159.36,64.17 159.39,64.17 arc(159.46,64.21) 159.5,64.28 arc(159.53,64.36) 159.61,64.39 160.86,64.39 160.96,64.5 163.28,64.5 163.43,64.65 169.25,64.65 arc(169.27,64.65) 169.3,64.67 169.42,64.8 arc(169.46,64.85) 169.47,64.92 arc(169.5,65.04) 169.57,65.15 v2(169.64,65.22) ; v1(170.98,39.12) 170.82,38.96 169.57,38.96 169.5,39.03 169.5,39.1 169.64,39.24 v2(169.64,39.31)
  L6 w0.05: v2(169.64,39.31) 169.47,39.48 169.47,65.05 v2(169.64,65.22)
P2_MDI_AN: length 25.5
  TOP w0.062: J2001.3 180.19,67.45 180.11,67.42 180.05,67.31 179.54,66.8 177.91,66.8 176.42,65.31 172.26,65.31 172.1,65.15 CR2002.4 v1(171.1,65.15)
  L3 w0.05: v1(158.87,66.68) 158.98,66.57 171.19,66.57 171.55,66.21 171.55,65.49 171.4,65.34 171.28,65.34 v1(171.1,65.15)
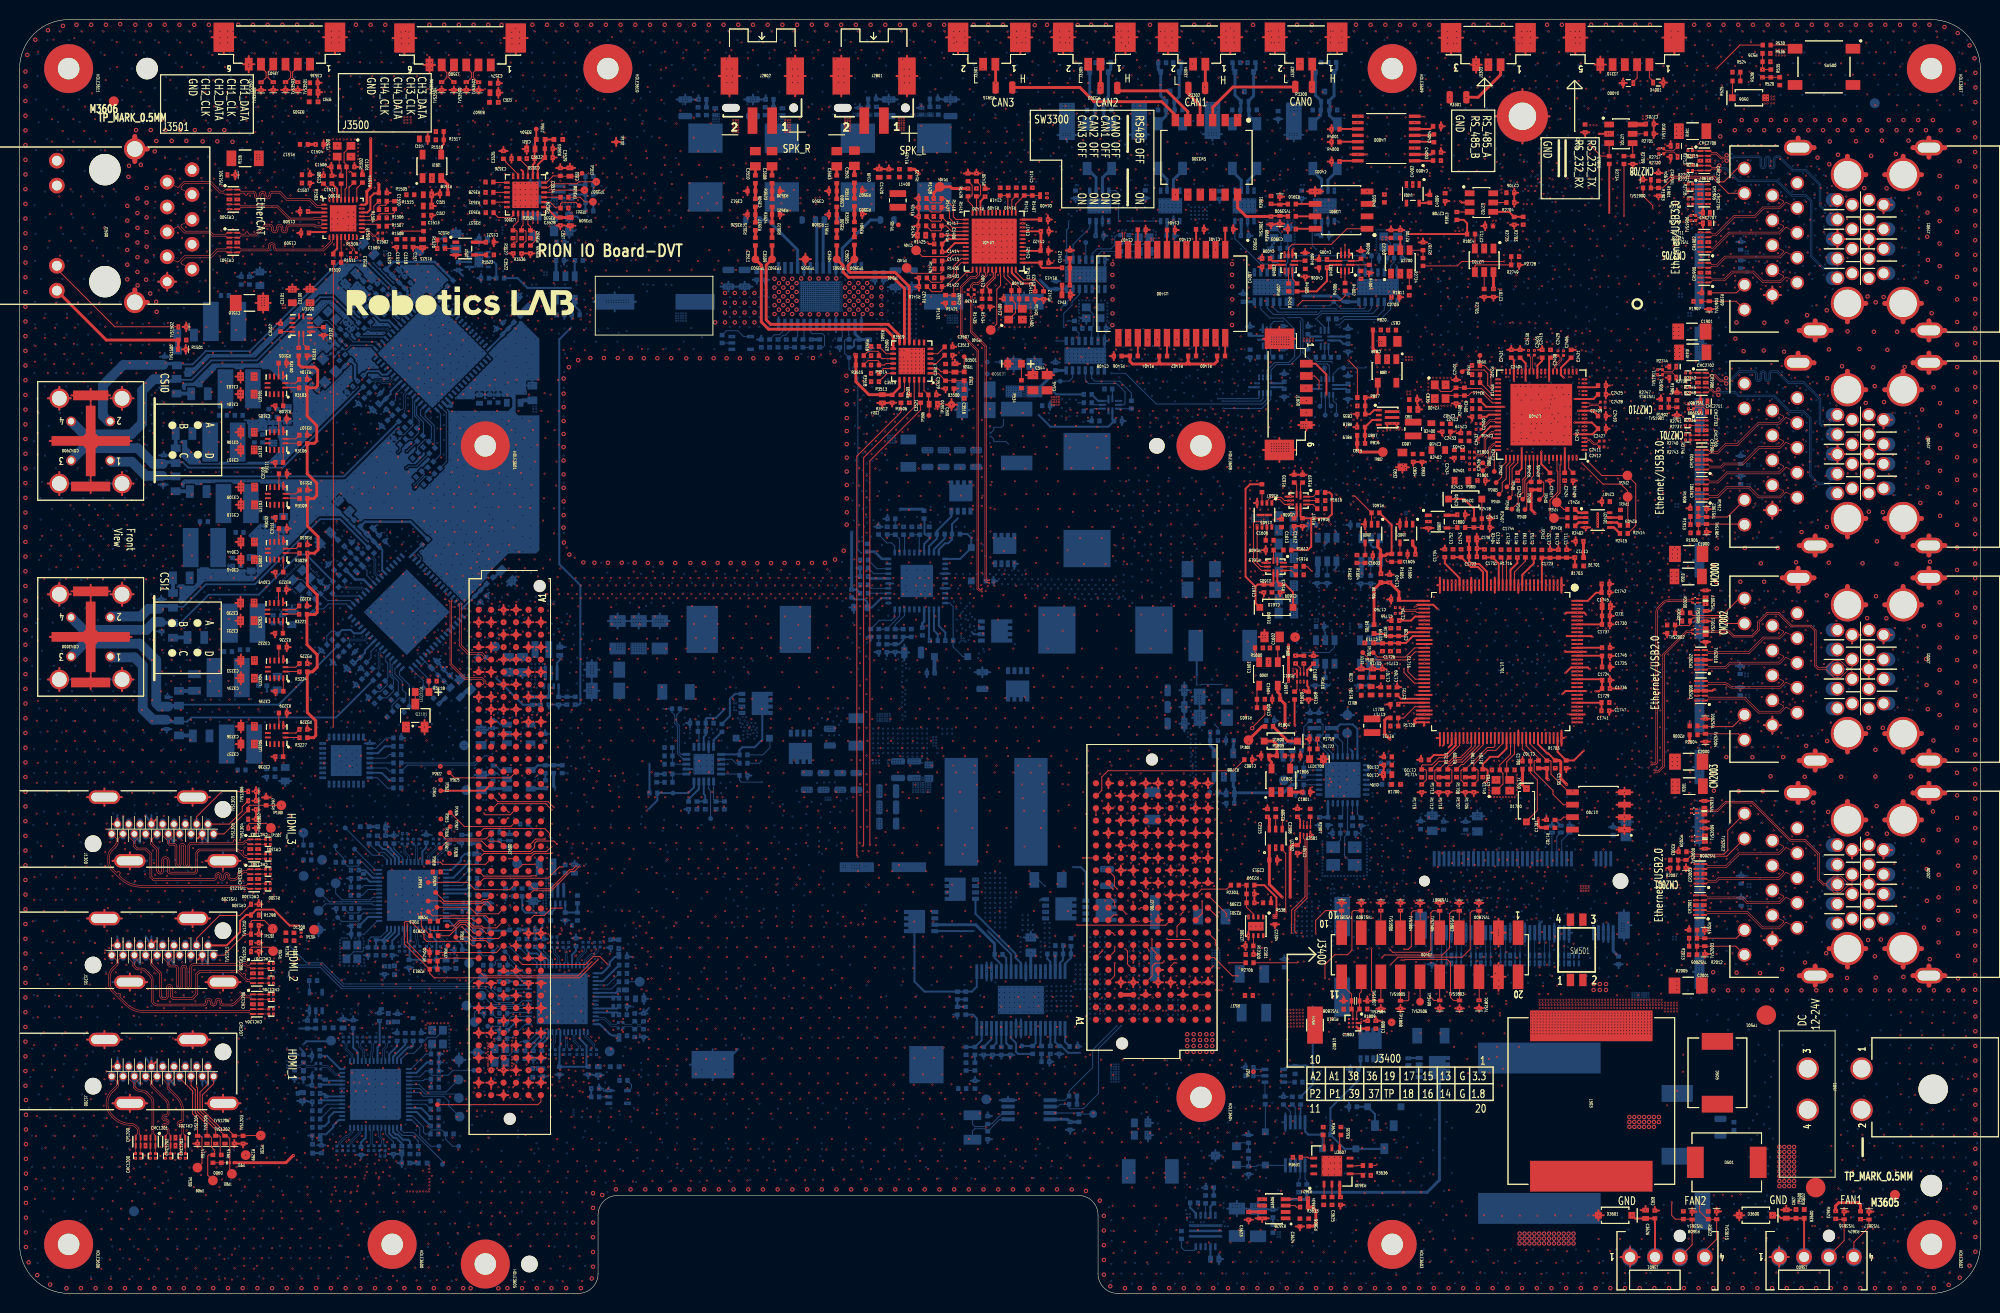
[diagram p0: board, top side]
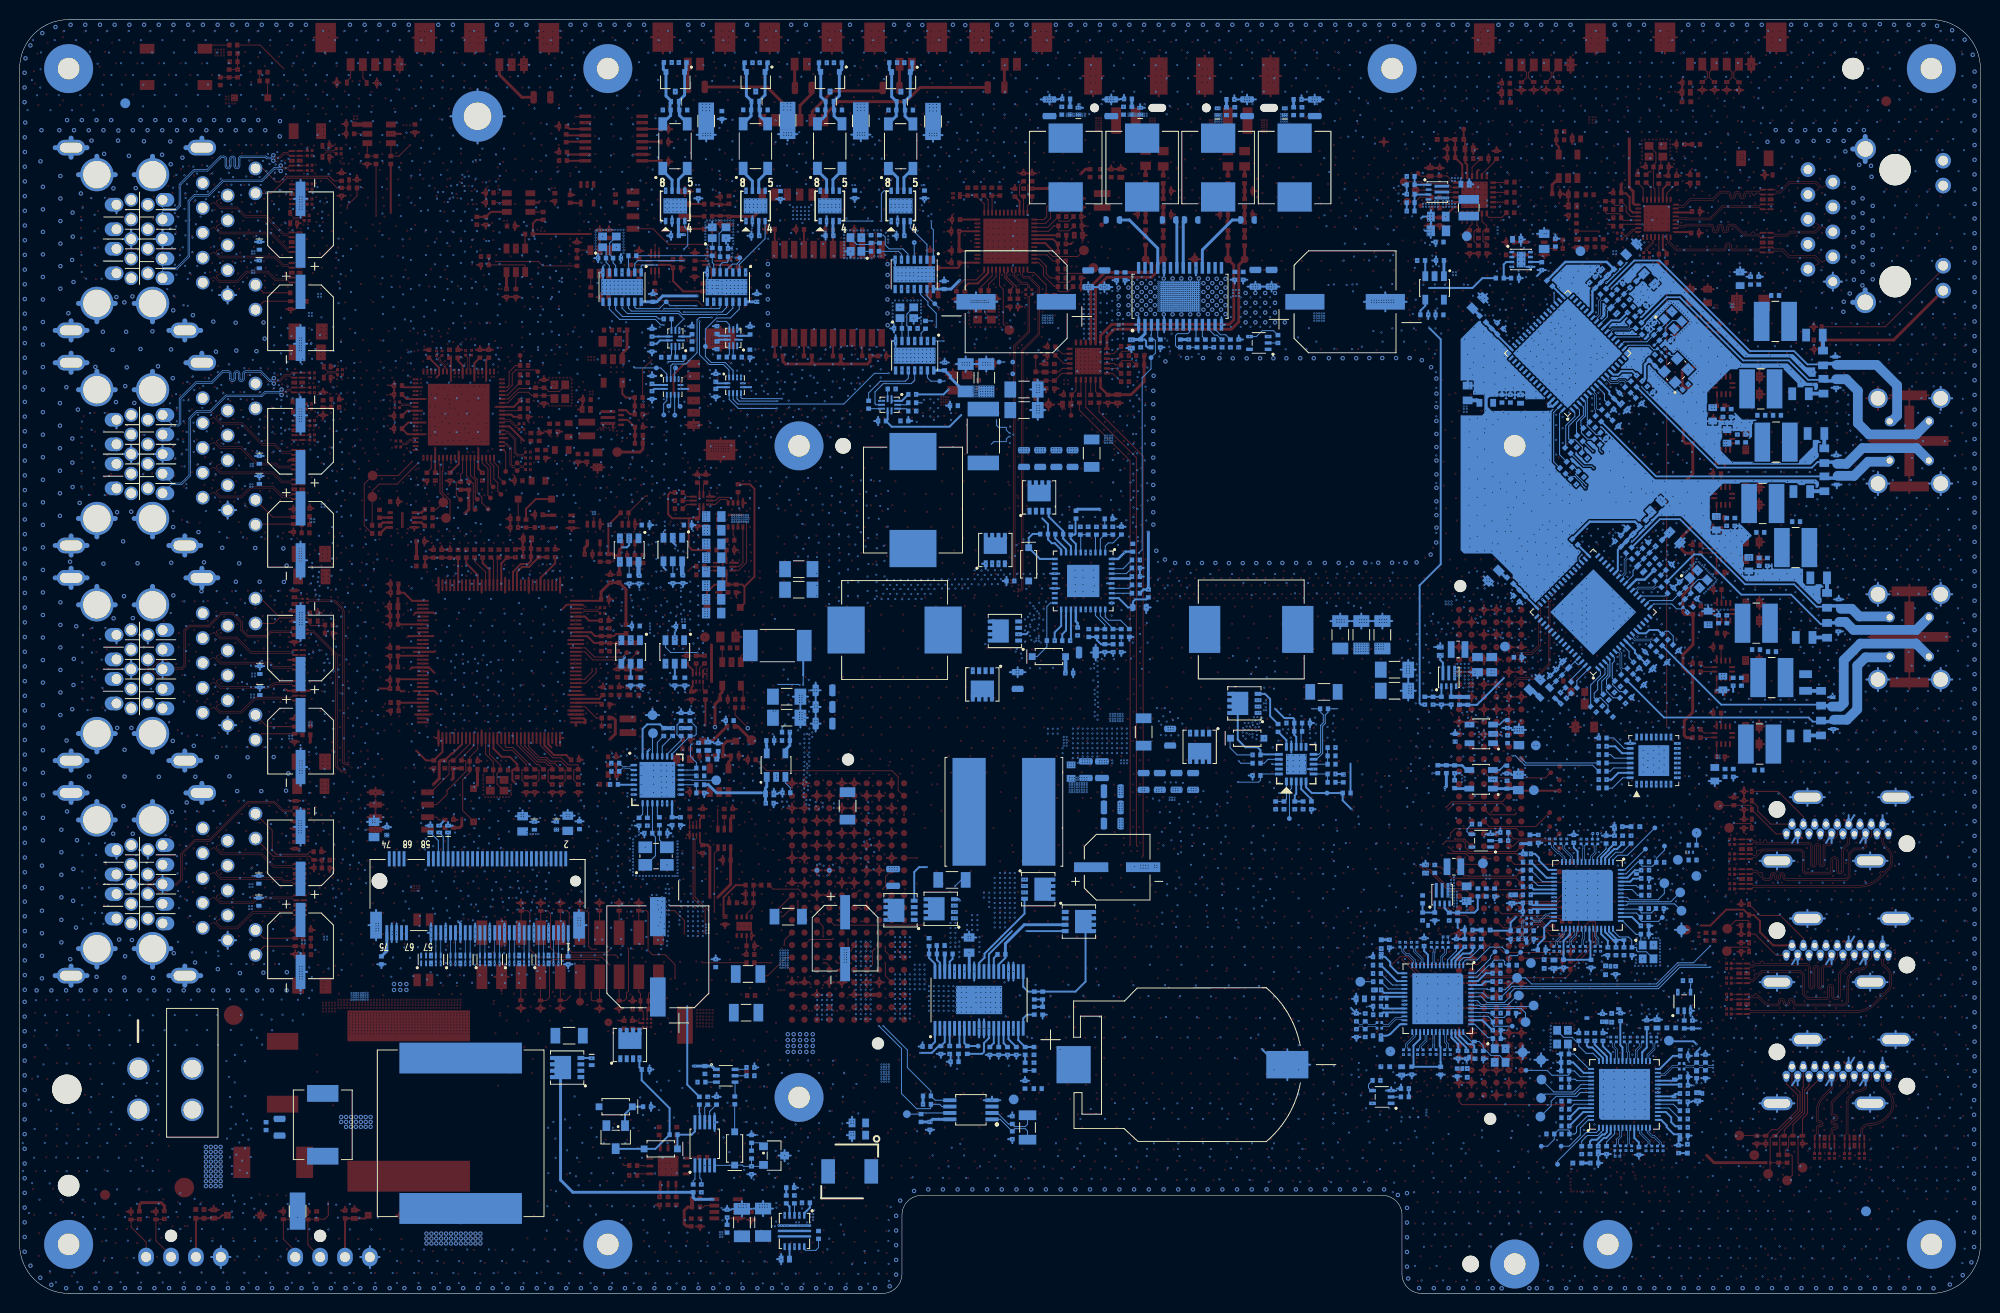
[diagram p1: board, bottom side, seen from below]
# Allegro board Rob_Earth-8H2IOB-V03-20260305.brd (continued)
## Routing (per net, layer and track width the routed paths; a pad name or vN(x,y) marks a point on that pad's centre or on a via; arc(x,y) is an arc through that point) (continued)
P2_MDI_AP: length 25.5
  TOP w0.062: J2001.2 179.91,67.58 179.94,67.5 179.9,67.42 179.46,66.99 177.83,66.99 176.34,65.5 172.27,65.5 172.11,65.65 CR2002.5 v1(171.1,65.65)
  L3 w0.05: v1(158.87,66.28) 158.98,66.39 159.13,66.39 arc(159.22,66.36) 159.26,66.27 159.26,66.21 arc(159.38,66.08) 159.51,66.21 159.51,66.27 arc(159.63,66.39) 159.76,66.27 159.76,66.21 arc(159.88,66.08) 160.01,66.21 160.01,66.27 arc(160.05,66.36) 160.13,66.39 171.12,66.39 171.38,66.13 171.38,65.56 171.33,65.51 171.26,65.51 171.11,65.65 v1(171.1,65.65)
P2_MDI_BN: length 28.5
  TOP w0.062: J2001.5 180.19,64.91 180.11,64.88 180.05,64.77 179.51,64.23 174.5,64.23 174.07,63.81 172.25,63.81 172.1,63.65 CR2002.1 v1(171.1,63.65)
  L3 w0.05: v1(171.1,63.65) 171.24,63.8 171.58,63.8 arc(171.67,63.82) 171.75,63.87 172,64.12 arc(172.18,64.39) 172.24,64.7 172.24,66.27 arc(172.17,66.6) 171.99,66.88 171.12,67.74 arc(171.05,67.79) 170.96,67.81 167.33,67.81 167.13,67.61 160.94,67.61 arc(160.91,67.61) 160.89,67.63 160.78,67.73 arc(160.75,67.76) 160.71,67.77 159.01,67.77 arc(158.99,67.77) 158.97,67.79 v1(158.87,67.88)
P2_MDI_BP: length 28.5
  TOP w0.062: v1(171.1,64.15) CR2002.2 172.11,64.15 172.27,64 174,64 174.42,64.42 179.44,64.42 179.9,64.88 179.94,64.96 179.91,65.04 J2001.4
  L3 w0.05: v1(158.87,67.48) 158.98,67.59 159.13,67.59 arc(159.22,67.56) 159.26,67.47 159.26,67.43 arc(159.38,67.31) 159.51,67.43 159.51,67.47 arc(159.63,67.59) 159.76,67.47 159.76,67.43 arc(159.88,67.31) 160.01,67.43 160.01,67.47 arc(160.05,67.56) 160.13,67.59 160.65,67.59 arc(160.68,67.59) 160.7,67.57 160.77,67.5 160.82,67.45 arc(160.84,67.44) 160.86,67.43 167.2,67.43 167.41,67.64 170.96,67.64 arc(170.98,67.63) 171,67.62 171.86,66.76 arc(172.01,66.53) 172.06,66.27 172.06,64.7 arc(172.02,64.46) 171.88,64.25 171.62,63.99 arc(171.6,63.98) 171.58,63.97 171.23,63.97 171.1,64.11 v1(171.1,64.15)
P2_MDI_CN: length 32.5
  TOP w0.062: J2001.7 180.19,62.37 180.11,62.34 180.05,62.23 179.58,61.76 174.72,61.76 arc(174.46,61.82) 174.25,61.98 arc(174.21,62.02) 174.16,62.05 arc(174.09,62.08) 174.03,62.12 arc(173.97,62.15) 173.9,62.16 172.26,62.16 172.1,62 CR2000.4 v1(171.1,62)
  L3 w0.05: v1(171.1,62) 171.26,62.17 172.04,62.17 arc(172.28,62.21) 172.49,62.35 172.9,62.77 arc(173.08,63.03) 173.14,63.34 173.14,66.73 arc(173.08,67.04) 172.9,67.3 171.22,68.98 arc(171,69.13) 170.74,69.18 167.65,69.18 167.43,68.97 158.98,68.97 v1(158.87,69.08)
P2_MDI_CP: length 32.5
  TOP w0.062: J2001.6 179.91,62.5 179.94,62.42 179.9,62.34 179.51,61.95 174.72,61.95 arc(174.54,61.99) 174.4,62.1 arc(174.32,62.18) 174.23,62.23 arc(174.18,62.25) 174.14,62.27 arc(174.03,62.33) 173.9,62.35 172.27,62.35 172.11,62.5 CR2000.5 v1(171.1,62.5)
  L3 w0.05: v1(158.87,68.68) 158.98,68.79 159.13,68.79 arc(159.22,68.76) 159.26,68.67 159.26,68.61 arc(159.38,68.48) 159.51,68.61 159.51,68.67 arc(159.63,68.79) 159.76,68.67 159.76,68.61 arc(159.88,68.48) 160.01,68.61 160.01,68.67 arc(160.05,68.76) 160.13,68.79 167.51,68.79 167.72,69.01 170.74,69.01 arc(170.93,68.97) 171.1,68.86 172.78,67.18 arc(172.92,66.97) 172.97,66.73 172.97,63.34 arc(172.92,63.1) 172.78,62.89 172.42,62.53 arc(172.21,62.39) 171.97,62.34 171.26,62.34 v1(171.1,62.5)
P2_MDI_DN: length 36.2
  TOP w0.062: J2001.9 180.19,59.83 180.11,59.8 180.05,59.69 179.59,59.23 177.34,59.23 175.91,60.66 172.27,60.66 172.11,60.5 CR2000.1 v1(171.1,60.5)
  L3 w0.05: v1(158.87,70.28) 158.97,70.18 arc(158.99,70.17) 159,70.17 170.96,70.17 arc(171.2,70.12) 171.41,69.98 173.77,67.62 arc(173.96,67.34) 174.02,67 174.02,63.07 arc(173.32,61.37) 171.62,60.67 171.29,60.67 arc(171.26,60.66) 171.24,60.65 v1(171.1,60.5)
P2_MDI_DP: length 36.2
  TOP w0.062: v1(171.1,61) CR2000.2 172.12,61 172.27,60.85 175.99,60.85 177.42,59.41 179.51,59.41 179.9,59.8 179.94,59.88 179.91,59.96 J2001.8
  L3 w0.05: v1(171.1,61) 171.23,60.87 arc(171.26,60.85) 171.29,60.84 171.62,60.84 arc(173.2,61.5) 173.85,63.07 173.85,67 arc(173.8,67.27) 173.64,67.5 171.28,69.86 arc(171.13,69.96) 170.96,69.99 160.15,69.99 arc(160.07,69.96) 160.03,69.87 160.03,69.82 arc(159.9,69.69) 159.78,69.82 159.78,69.87 arc(159.65,69.99) 159.53,69.87 159.53,69.82 arc(159.4,69.69) 159.28,69.82 159.28,69.87 arc(159.24,69.96) 159.15,69.99 159,69.99 arc(158.99,69.99) 158.98,69.99 158.98,69.99 v1(158.87,69.88)
P3_MDI_AN: length 39.9
  TOP w0.062: J1900.3 180.19,89.4 180.11,89.37 180.05,89.26 179.5,88.71 177.42,88.71 175.26,86.55 174.06,86.55 173.24,85.74 172.37,85.74 172.22,85.58 CR1903.4 v1(171.18,85.58)
  L3 w0.05: v1(156.47,72.28) 156.58,72.39 156.58,72.69 156.87,72.98 156.87,73.38 v2(156.71,73.54) ; v2(156.71,84.17) 156.87,84.01 156.87,83.8 157.03,83.65 159.95,83.65 160.78,84.48 166.37,84.48 167.04,85.15 168.96,85.15 arc(169.06,85.16) 169.13,85.22 169.66,85.74 171.02,85.74 v1(171.18,85.58)
  L6 w0.05: v2(156.71,73.54) 156.87,73.7 156.87,84.01 v2(156.71,84.17)
P3_MDI_AP: length 39.9
  TOP w0.062: J1900.2 179.91,89.53 179.94,89.45 179.9,89.37 179.43,88.9 177.34,88.9 175.18,86.74 173.98,86.74 173.16,85.92 172.38,85.92 172.22,86.08 CR1903.5 v1(171.18,86.08)
  L3 w0.05: v2(157.21,73.54) 157.05,73.38 157.05,72.91 156.76,72.62 156.76,72.39 v1(156.87,72.28) ; v1(171.18,86.08) 171.02,85.92 169.62,85.92 arc(169.59,85.91) 169.57,85.9 169.01,85.34 arc(168.99,85.33) 168.96,85.32 166.97,85.32 166.3,84.65 160.71,84.65 159.88,83.83 158,83.83 arc(157.91,83.86) 157.88,83.95 157.88,84.06 arc(157.75,84.19) 157.63,84.06 157.63,83.95 arc(157.59,83.86) 157.5,83.83 157.1,83.83 157.05,83.88 157.05,84.01 v2(157.21,84.17)
  L6 w0.05: v2(157.21,73.54) 157.05,73.7 157.05,84.01 v2(157.21,84.17)
P3_MDI_BN: length 39.9
  TOP w0.062: J1900.5 180.19,86.86 180.11,86.83 180.05,86.72 179.56,86.23 177.45,86.23 175.78,84.56 173.91,84.56 173.6,84.25 172.38,84.25 172.22,84.08 CR1903.1 v1(171.18,84.08)
  L3 w0.05: v1(155.67,72.28) 155.67,72.63 v2(155.61,72.69) ; v1(171.18,84.08) 171.02,84.24 170.49,84.24 arc(170.29,84.33) 170.2,84.53 170.2,84.69 arc(170.08,84.82) 169.95,84.69 169.95,84.54 arc(169.86,84.33) 169.65,84.24 167.47,84.24 166.86,83.64 161.29,83.64 160.42,82.76 156.16,82.76 155.96,82.97 155.96,83.14 v2(155.79,83.3)
  L6 w0.05: v2(155.61,72.69) 155.77,72.86 155.77,73.61 155.96,73.79 155.96,83.14 v2(155.79,83.3)
P3_MDI_BP: length 39.9
  TOP w0.062: J1900.4 179.91,86.99 179.94,86.91 179.9,86.83 179.48,86.42 177.37,86.42 175.7,84.74 173.83,84.74 173.52,84.43 172.37,84.43 172.22,84.58 CR1903.2 v1(171.18,84.58)
  L3 w0.05: v1(156.07,72.28) 156.07,72.65 v2(156.11,72.69) ; v1(171.18,84.58) 171.02,84.42 170.49,84.42 arc(170.41,84.45) 170.38,84.53 170.38,84.69 arc(170.08,84.99) 169.78,84.69 169.78,84.54 arc(169.74,84.46) 169.65,84.42 167.39,84.42 166.78,83.81 161.22,83.81 160.35,82.94 157.51,82.94 arc(157.42,82.97) 157.39,83.06 arc(157.36,83.14) 157.27,83.17 157.26,83.17 arc(157.17,83.14) 157.14,83.06 arc(157.11,82.97) 157.02,82.94 157.01,82.94 arc(156.92,82.97) 156.89,83.06 arc(156.86,83.14) 156.77,83.17 156.76,83.17 arc(156.67,83.14) 156.64,83.06 arc(156.61,82.97) 156.52,82.94 156.23,82.94 156.13,83.04 156.13,83.14 v2(156.29,83.3)
  L6 w0.05: v2(156.29,83.3) 156.13,83.14 156.13,73.72 155.95,73.54 155.95,72.86 v2(156.11,72.69)
P3_MDI_CN: length 39.9
  TOP w0.062: v1(171.18,82.56) CR1901.4 172.19,82.56 172.35,82.72 173.26,82.72 174.19,83.64 179.52,83.64 180.05,84.18 180.11,84.29 180.19,84.32 J1900.7
  L3 w0.05: v2(154.66,73.77) 154.83,73.61 154.83,72.8 154.58,72.55 154.58,72.39 v1(154.47,72.28) ; v1(171.18,82.56) 171.16,82.56 171,82.72 169.95,82.72 arc(169.74,82.81) 169.65,83.02 169.65,83.31 arc(169.53,83.43) 169.4,83.31 169.4,83.02 arc(169.31,82.81) 169.1,82.72 161.69,82.72 160.97,82 155.04,82 154.85,82.19 154.85,82.4 v2(154.69,82.56)
  L6 w0.05: v2(154.69,82.56) 154.82,82.42 154.82,73.93 v2(154.66,73.77)
P3_MDI_CP: length 39.9
  TOP w0.062: v1(171.18,83.06) CR1901.5 172.22,83.06 172.37,82.91 173.19,82.91 174.11,83.83 179.44,83.83 179.9,84.29 179.94,84.37 179.91,84.45 J1900.6
  L3 w0.05: v1(154.87,72.28) 154.75,72.4 154.75,72.48 155,72.73 155,73.61 v2(155.16,73.77) ; v1(171.18,83.06) 171.02,82.9 169.95,82.9 arc(169.86,82.94) 169.83,83.02 169.83,83.31 arc(169.53,83.61) 169.23,83.31 169.23,83.02 arc(169.19,82.94) 169.1,82.9 161.62,82.9 160.9,82.18 155.98,82.18 arc(155.89,82.22) 155.85,82.3 155.85,82.39 arc(155.73,82.51) 155.6,82.39 155.6,82.3 arc(155.57,82.22) 155.48,82.18 155.11,82.18 155.02,82.26 155.02,82.4 v2(155.19,82.56)
  L6 w0.05: v2(155.16,73.77) 155,73.94 155,82.37 v2(155.19,82.56)
P3_MDI_DN: length 39.9
  TOP w0.062: v1(171.18,81.06) CR1901.1 172.21,81.06 172.37,81.22 173.23,81.22 174.19,82.18 176.36,82.18 177.34,81.19 179.6,81.19 180.05,81.64 180.11,81.75 180.19,81.78 J1900.9
  L3 w0.05: v2(153.63,81.64) 153.79,81.48 153.79,81.28 153.98,81.1 161.4,81.1 161.71,81.41 164.31,81.41 164.5,81.23 169.61,81.23 arc(169.83,81.32) 169.91,81.53 169.91,81.64 arc(170.04,81.76) 170.16,81.64 170.16,81.5 arc(170.24,81.31) 170.43,81.23 171.02,81.23 v1(171.18,81.06) ; v2(153.62,72.84) 153.78,72.68 153.78,72.39 v1(153.67,72.28)
  L6 w0.05: v2(153.63,81.64) 153.79,81.48 153.79,73.02 v2(153.62,72.84)
P3_MDI_DP: length 39.9
  TOP w0.062: J1900.8 179.91,81.91 179.94,81.83 179.9,81.75 179.53,81.38 177.42,81.38 176.44,82.36 174.11,82.36 173.16,81.41 172.37,81.41 172.21,81.56 CR1901.2 v1(171.18,81.56)
  L3 w0.05: v2(154.13,81.64) 153.96,81.48 153.96,81.36 154.05,81.27 154.48,81.27 arc(154.57,81.31) 154.61,81.4 154.61,81.5 arc(154.73,81.63) 154.86,81.5 154.86,81.4 arc(154.89,81.31) 154.98,81.27 161.33,81.27 161.62,81.57 arc(161.64,81.58) 161.67,81.59 164.36,81.59 arc(164.38,81.58) 164.41,81.57 164.57,81.4 169.61,81.4 arc(169.7,81.44) 169.74,81.53 169.74,81.64 arc(170.04,81.94) 170.34,81.64 170.34,81.5 arc(170.37,81.43) 170.43,81.4 171.03,81.4 v1(171.18,81.56) ; v1(154.07,72.28) 153.96,72.39 153.96,72.68 v2(154.12,72.84)
  L6 w0.05: v2(154.12,72.84) 153.97,73 153.97,81.48 v2(154.13,81.64)
P4_MDI_AN: length 71.8
  TOP w0.062: J1901.3 180.19,111.35 180.11,111.32 180.05,111.21 179.53,110.69 177.89,110.69 177.03,109.83 174.94,109.83 173.06,107.94 172.63,107.94 172.48,107.79 CR1902.4 v1(171.44,107.79)
  L3 w0.05: v1(148.47,72.28) 148.58,72.39 148.58,73.23 v2(148.42,73.39) ; v1(171.44,107.79) 171.28,107.95 148.49,107.95 148.31,108.14 148.31,108.32 v2(148.14,108.49)
  L6 w0.05: v2(148.14,108.49) 148.31,108.32 148.31,74.8 148.58,74.52 148.58,73.55 v2(148.42,73.39)
P4_MDI_AP: length 71.8
  TOP w0.062: v1(171.44,108.29) CR1902.5 172.48,108.29 172.64,108.13 172.98,108.13 174.87,110.02 176.95,110.02 177.81,110.88 179.46,110.88 179.9,111.32 179.94,111.4 179.91,111.48 J1901.2
  L3 w0.05: v1(171.44,108.29) 171.28,108.13 171.04,108.13 arc(170.95,108.16) 170.92,108.25 170.92,108.37 arc(170.79,108.5) 170.67,108.37 170.67,108.25 arc(170.63,108.16) 170.54,108.13 148.56,108.13 148.48,108.21 148.48,108.32 v2(148.64,108.49) ; v2(148.92,73.39) 148.76,73.23 148.76,72.39 v1(148.87,72.28)
  L6 w0.05: v2(148.64,108.49) 148.48,108.32 148.48,74.87 148.76,74.59 148.76,73.55 v2(148.92,73.39)
P4_MDI_BN: length 71.8
  TOP w0.062: v1(147.27,72.27) 147.27,72.27 U1701.26 ; v1(171.44,106.29) CR1902.1 172.57,106.29 174.41,108.12 176.44,108.12 179.51,108.12 180.05,108.67 180.11,108.78 180.19,108.81 J1901.5
  L3 w0.05: v1(147.27,72.27) 147.27,72.28 147.39,72.39 147.39,72.85 v2(147.22,73.01) ; v1(171.44,106.29) 171.28,106.45 168.63,106.45 arc(168.22,106.59) 167.98,106.94 arc(167.87,107.1) 167.68,107.17 153.47,107.17 arc(153.22,107.12) 153.02,106.98 152.35,106.31 148.2,106.31 arc(147.82,106.38) 147.5,106.6 arc(147.42,106.73) 147.39,106.88 147.39,107.07 v2(147.22,107.24)
  L6 w0.05: v2(147.22,107.24) 147.39,107.07 147.39,73.17 v2(147.22,73.01)
P4_MDI_BP: length 71.8
  TOP w0.062: J1901.4 179.91,108.94 179.94,108.86 179.9,108.78 179.43,108.31 176.71,108.31 174.33,108.31 172.67,106.65 172.58,106.65 172.44,106.79 CR1902.2 v1(171.44,106.79)
  L3 w0.05: v1(147.67,72.28) 147.56,72.39 147.56,72.85 v2(147.72,73.01) ; v1(171.44,106.79) 171.28,106.63 170.76,106.63 arc(170.67,106.66) 170.64,106.75 170.64,106.88 arc(170.51,107.01) 170.39,106.88 170.39,106.75 arc(170.35,106.66) 170.26,106.63 168.63,106.63 arc(168.33,106.73) 168.15,106.99 arc(167.97,107.24) 167.68,107.34 153.47,107.34 arc(153.16,107.28) 152.89,107.1 152.28,106.49 148.2,106.49 arc(147.89,106.55) 147.63,106.72 arc(147.58,106.8) 147.56,106.88 147.56,107.07 v2(147.72,107.24)
  L6 w0.05: v2(147.72,73.01) 147.56,73.17 147.56,107.07 v2(147.72,107.24)
P4_MDI_CN: length 71.5
  TOP w0.062: v1(171.44,104.67) CR1900.4 172.45,104.67 172.61,104.83 173.16,104.83 174,105.67 179.6,105.67 180.05,106.13 180.11,106.24 180.19,106.27 J1901.7
  L3 w0.05: v1(171.44,104.67) 171.27,104.85 170.15,104.85 arc(170.13,104.85) 170.11,104.83 169.45,104.18 arc(169.43,104.17) 169.41,104.16 168.92,104.16 arc(168.73,104.24) 168.65,104.44 168.65,104.59 arc(168.52,104.71) 168.4,104.59 168.4,104.46 arc(168.31,104.25) 168.1,104.16 161.45,104.16 161.26,103.97 154.19,103.97 153.98,104.19 146.82,104.19 146.16,104.84 146.16,105.27 v2(146,105.44) ; v1(146.07,72.58) 146.16,72.67 146.16,73.79 v2(146.01,73.95)
  L6 w0.05: v2(146,105.44) 146.17,105.26 146.17,90.48 146.42,90.23 146.42,74.92 146.17,74.67 146.17,74.11 v2(146.01,73.95)
P4_MDI_CP: length 71.5
  TOP w0.062: v1(171.44,105.17) CR1900.5 172.44,105.17 172.6,105.02 173.08,105.02 173.92,105.86 179.52,105.86 179.9,106.24 179.94,106.32 179.91,106.4 J1901.6
  L3 w0.05: v1(171.44,105.17) 171.29,105.03 170.95,105.03 arc(170.86,105.06) 170.82,105.15 170.82,105.26 arc(170.7,105.39) 170.57,105.26 170.57,105.15 arc(170.53,105.06) 170.45,105.03 170.15,105.03 arc(170.06,105.01) 169.98,104.96 169.36,104.34 168.92,104.34 arc(168.85,104.37) 168.82,104.44 168.82,104.59 arc(168.52,104.89) 168.22,104.59 168.22,104.46 arc(168.18,104.37) 168.1,104.34 161.38,104.34 161.19,104.14 154.27,104.14 154.05,104.36 146.89,104.36 146.34,104.92 146.34,105.27 v2(146.5,105.44) ; v1(146.47,72.58) 146.34,72.71 146.34,73.77 v2(146.51,73.95)
  L6 w0.05: v2(146.51,73.95) 146.35,74.11 146.35,74.6 146.59,74.85 146.59,90.31 146.35,90.55 146.35,105.28 v2(146.5,105.44)
P4_MDI_DN: length 71.8
  TOP w0.062: v1(171.44,103.17) CR1900.1 172.47,103.17 172.63,103.34 173.93,103.34 174.73,104.15 176.8,104.15 177.8,103.15 179.61,103.15 180.05,103.59 180.11,103.7 180.19,103.73 J1901.9
  L3 w0.05: v1(171.44,103.17) 171.28,103.34 170.05,103.34 arc(169.99,103.31) 169.96,103.25 169.96,103.11 arc(169.66,102.81) 169.36,103.11 169.36,103.21 arc(169.32,103.3) 169.24,103.34 169.2,103.34 arc(169.14,103.31) 169.11,103.25 169.11,103.11 arc(168.81,102.81) 168.51,103.11 168.51,103.21 arc(168.47,103.3) 168.39,103.34 162.07,103.34 161.82,103.09 145.68,103.09 arc(145.59,103.1) 145.51,103.16 145.18,103.49 145.18,103.76 v2(145.02,103.92) ; v2(145.02,73.26) 145.19,73.09 145.19,72.77 145.37,72.58 145.37,72.38 v1(145.27,72.28)
  L6 w0.05: v2(145.02,103.92) 145.19,103.75 145.19,103.31 145.25,103.26 145.25,90.24 145.47,90.02 145.47,74.93 145.19,74.65 145.19,73.43 v2(145.02,73.26)
P4_MDI_DP: length 71.8
  TOP w0.062: J1901.8 179.91,103.86 179.94,103.78 179.9,103.7 179.53,103.34 177.87,103.34 176.88,104.33 174.65,104.33 173.85,103.53 172.63,103.53 172.48,103.67 CR1900.2 v1(171.44,103.67)
  L3 w0.05: v1(171.44,103.67) 171.28,103.51 171.06,103.51 arc(170.97,103.55) 170.93,103.64 170.93,103.77 arc(170.81,103.9) 170.68,103.77 170.68,103.64 arc(170.64,103.55) 170.56,103.51 170.05,103.51 arc(169.86,103.44) 169.79,103.25 169.79,103.11 arc(169.66,102.99) 169.54,103.11 169.54,103.21 arc(169.45,103.42) 169.24,103.51 169.2,103.51 arc(169.01,103.44) 168.94,103.25 168.94,103.11 arc(168.81,102.99) 168.69,103.11 168.69,103.21 arc(168.6,103.42) 168.39,103.51 162,103.51 161.74,103.26 145.68,103.26 arc(145.66,103.27) 145.64,103.28 145.36,103.56 145.36,103.76 v2(145.52,103.92) ; v2(145.52,73.26) 145.36,73.1 145.36,72.84 145.55,72.66 145.55,72.4 v1(145.67,72.28)
  L6 w0.05: v2(145.52,73.26) 145.36,73.42 145.36,74.57 145.41,74.62 145.64,74.85 145.64,90.09 145.42,90.31 145.42,103.33 145.37,103.39 145.37,103.77 v2(145.52,103.92)
PCIE1_CLK_REQ_N_3P3: length 31.7
  TOP w0.1: v1(131.34,48.08) 131.31,48.08 131.31,47.6 U2301.6
  L3 w0.1: v1(131.34,48.08) 131.31,48.08 131.31,48.1 131.63,48.42 132.65,48.42 133.02,48.05 136.61,48.05 136.74,48.18 139.83,48.18 140.45,48.81 155.56,48.81 155.82,48.55 156.69,48.55 156.84,48.69 v2(157.17,48.69)
  L6 w0.1: v2(157.17,48.69) 157.17,48.43 157.19,48.41 v3(157.19,47.05)
  BOTTOM w0.1: CN2300.52 156.79,46.63 TVS2302.1
PCIE1_REFCLK_M: length 55.8
  L3 w0.057: v2(157.04,33.06) 157.21,32.89 157.21,32.69 155.57,31.05 146.52,31.05 145.94,31.64 144.25,31.64 141.95,33.94 141.95,39 138.93,42.02 119.58,42.02 118,43.59 115.57,43.59 115.42,43.44 115.42,43.23 115.36,43.17 v1(114.86,43.17)
  L6 w0.057: v3(157.04,33.68) 157.21,33.52 157.21,33.23 v2(157.04,33.06)
  BOTTOM w0.072: CN2300.53 CR2304.6 v3(157.04,33.68)
PCIE1_REFCLK_P: length 55.8
  L3 w0.057: v2(157.54,33.06) 157.37,32.89 157.37,32.62 155.64,30.88 146.45,30.88 145.87,31.47 144.18,31.47 141.78,33.87 141.78,38.93 138.86,41.86 119.51,41.86 117.94,43.43 115.64,43.43 115.58,43.37 115.58,43.23 115.64,43.17 v1(116.13,43.17)
  L6 w0.057: v2(157.54,33.06) 157.38,33.22 157.38,33.52 v3(157.54,33.68)
  BOTTOM w0.072: CN2300.55 CR2304.7 v3(157.54,33.68)
PCIE1_RESET_N_3P3: length 35.3
  TOP w0.1: U2302.4 128.8,47.41 v1(128.8,49.36)
  L3 w0.1: v2(156.31,49.11) 156.16,49.27 136.55,49.27 135.8,48.52 133.88,48.52 133.18,49.22 131.02,49.22 130.55,49.69 129.13,49.69 v1(128.8,49.36)
  L6 w0.1: v3(156.31,47.04) v2(156.31,49.11)
  BOTTOM w0.1: CN2300.50 156.29,47.03 TVS2301.1
PCIE1_RX0_M: length 51.1
  L3 w0.057: v2(154.04,32.96) 154.21,33.13 154.21,33.21 154.2,33.22 154.2,36.24 143.72,46.72 125.45,46.72 122.38,49.79 119.47,49.79 117.96,51.3 117.96,52.01 117.9,52.06 v1(117.4,52.06)
  L6 w0.057: v2(154.04,32.96) 154.21,33.13 154.21,33.52 v3(154.04,33.68)
  BOTTOM w0.072: v3(154.04,33.68) CR2305.6 CN2300.41
PCIE1_RX0_P: length 51.1
  TOP w0.072: v1(118.67,52.07) J2700.H20
  L3 w0.057: v1(118.67,52.07) J2700.H20 118.18,52.06 118.12,52.01 118.12,51.37 119.54,49.96 122.45,49.96 125.52,46.89 143.79,46.89 154.37,36.31 154.37,33.29 154.38,33.28 154.38,33.13 v2(154.54,32.96)
  L6 w0.057: v2(154.54,32.96) 154.38,33.13 154.38,33.52 v3(154.54,33.68)
  BOTTOM w0.072: v3(154.54,33.68) CR2305.7 CN2300.43
PCIE1_RX1_M: length 47.9
  L3 w0.057: v1(117.4,49.52) 117.9,49.52 117.96,49.47 117.96,49.19 118.27,48.88 122.15,48.88 124.97,46.05 143.36,46.05 151.19,38.22 151.19,33.13 v2(151.04,32.98)
  L6 w0.057: v2(151.04,32.98) 151.21,33.14 151.21,33.52 v3(151.04,33.68)
  BOTTOM w0.072: v3(151.04,33.68) CR2300.6 CN2300.29
PCIE1_RX1_P: length 47.9
  L3 w0.057: v2(151.54,32.98) 151.36,33.16 151.36,38.29 143.43,46.22 125.04,46.22 122.22,49.05 118.34,49.05 118.12,49.26 118.12,49.47 118.18,49.52 v1(118.67,49.52)
  L6 w0.057: v3(151.54,33.68) 151.38,33.52 151.38,33.14 v2(151.54,32.98)
  BOTTOM w0.072: CN2300.31 CR2300.7 v3(151.54,33.68)
PCIE1_RX2_M: length 44.8
  L3 w0.057: v1(117.4,46.98) 117.9,46.98 117.96,46.93 117.96,46.66 118.25,46.36 119.53,46.36 120.05,46.88 121.95,46.88 124.09,44.74 142.51,44.74 148.23,39.03 148.23,33.16 v2(148.04,32.98)
  L6 w0.057: v3(148.04,33.68) 148.21,33.52 148.21,33.14 v2(148.04,32.98)
  BOTTOM w0.072: CN2300.17 CR2308.6 v3(148.04,33.68)
PCIE1_RX2_P: length 44.8
  L3 w0.057: v1(118.67,46.98) 118.18,46.98 118.12,46.93 118.12,46.73 118.32,46.53 119.46,46.53 119.98,47.05 122.02,47.05 124.16,44.91 142.58,44.91 148.39,39.1 148.39,33.13 v2(148.54,32.98)
  L6 w0.057: v2(148.54,32.98) 148.38,33.14 148.38,33.52 v3(148.54,33.68)
  BOTTOM w0.072: v3(148.54,33.68) CR2308.7 CN2300.19
PCIE1_RX3_M: length 40.8
  L3 w0.057: v1(117.4,44.44) 117.9,44.44 117.96,44.5 117.96,44.79 118.15,44.98 118.95,44.98 119.29,44.64 119.29,43.24 119.85,42.68 139.23,42.68 142.62,39.3 142.62,34.33 143.93,33.02 144.22,33.02 v2(144.41,33.22)
  L6 w0.057: v3(145.04,33.68) 145.04,33.66 145.21,33.49 145.21,33.12 145.14,33.05 144.58,33.05 v2(144.41,33.22)
  BOTTOM w0.072: CN2300.5 CR2307.6 CR2307.5 v3(145.04,33.68)
PCIE1_RX3_P: length 40.8
  L3 w0.057: v2(144.41,32.72) 144.27,32.85 143.86,32.85 142.45,34.26 142.45,39.23 139.16,42.52 119.78,42.52 119.12,43.17 119.12,44.57 118.88,44.81 118.22,44.81 118.12,44.72 118.12,44.5 118.18,44.44 v1(118.67,44.44)
  L6 w0.057: v3(145.54,33.68) 145.38,33.51 145.38,33.05 145.21,32.88 144.58,32.88 v2(144.41,32.72)
  BOTTOM w0.072: CN2300.7 CR2307.7 v3(145.54,33.68)
PCIE1_TX0_M: length 48.5
  L3 w0.057: v1(119.94,43.17) 120.44,43.17 120.5,43.23 120.5,43.53 120.73,43.76 122.04,43.76 122.32,43.47 139.41,43.47 143.47,39.41 143.47,35.3 147.06,31.71 155.02,31.71 155.71,32.41 155.71,32.97 v2(155.55,33.13)
  L6 w0.057: v2(155.55,33.13) 155.71,33.3 155.71,33.51 v3(155.54,33.68)
  BOTTOM w0.072: v3(155.54,33.68) CR2305.9 CN2300.47
PCIE1_TX0_P: length 48.5
  L3 w0.057: v2(156.05,33.13) 155.88,32.97 155.88,32.34 155.08,31.54 146.99,31.54 143.3,35.23 143.3,39.34 139.34,43.3 122.25,43.3 121.97,43.59 120.8,43.59 120.66,43.46 120.66,43.23 120.72,43.17 v1(121.21,43.17)
  L6 w0.057: v2(156.05,33.13) 155.88,33.3 155.88,33.52 v3(156.04,33.68)
  BOTTOM w0.072: CN2300.49 CR2305.10 v3(156.04,33.68)
PCIE1_TX1_M: length 45.9
  L3 w0.057: v2(152.54,32.98) 152.71,32.81 152.71,32.58 152.48,32.35 147.66,32.35 144.09,35.92 144.09,39.72 139.6,44.21 123.3,44.21 122.02,45.48 122.02,45.9 121.67,46.25 120.64,46.25 120.49,46.1 120.49,45.78 120.42,45.71 v1(119.94,45.71)
  L6 w0.057: v2(152.54,32.98) 152.71,33.14 152.71,33.52 v3(152.54,33.68)
  BOTTOM w0.072: CN2300.35 CR2300.9 v3(152.54,33.68)
PCIE1_TX1_P: length 45.9
  L3 w0.057: v1(121.21,45.71) 120.73,45.71 120.66,45.78 120.66,46.03 120.71,46.08 121.6,46.08 121.86,45.83 121.86,45.42 123.23,44.04 139.53,44.04 143.92,39.65 143.92,35.85 147.59,32.18 152.55,32.18 152.88,32.51 152.88,32.81 v2(153.04,32.98)
  L6 w0.057: v3(153.04,33.68) 152.88,33.52 152.88,33.14 v2(153.04,32.98)
  BOTTOM w0.072: v3(153.04,33.68) CR2300.10 CN2300.37
PCIE1_TX2_M: length 43.6
  L3 w0.057: v2(149.54,32.98) 149.64,33.08 149.64,38.83 143.08,45.39 124.5,45.39 122.27,47.62 120.72,47.62 120.5,47.85 120.5,48.15 120.43,48.22 v1(119.95,48.22)
  L6 w0.057: v2(149.54,32.98) 149.71,33.14 149.71,33.52 v3(149.54,33.68)
  BOTTOM w0.072: CN2300.23 CR2308.9 v3(149.54,33.68)
PCIE1_TX2_P: length 43.7
  L3 w0.057: v1(121.22,48.22) 120.72,48.22 120.66,48.16 120.66,47.92 120.79,47.79 122.34,47.79 124.57,45.56 143.15,45.56 149.81,38.9 149.81,33.21 v2(150.04,32.98)
  L6 w0.057: v2(150.04,32.98) 149.88,33.14 149.88,33.52 v3(150.04,33.68)
  BOTTOM w0.072: CN2300.25 CR2308.10 v3(150.04,33.68)
PCIE1_TX3_M: length 64.6
  L3 w0.057: v1(119.95,50.71) 120.33,50.71 120.49,50.87 120.49,51.14 120.73,51.39 122.06,51.39 125.9,47.54 144.03,47.54 147.6,43.96 147.88,43.96 155.5,36.34 156.18,36.34 158.57,33.95 158.57,32.17 158.37,31.97 158.12,31.97 v2(157.96,31.8)
  L6 w0.057: v2(157.96,31.8) 157.79,31.97 147.52,31.97 146.71,32.78 146.71,33.52 v3(146.54,33.68)
  BOTTOM w0.072: v3(146.54,33.68) CR2307.9 CN2300.11
PCIE1_TX3_P: length 64.6
  L3 w0.057: v2(157.96,32.3) 158.12,32.14 158.3,32.14 158.41,32.24 158.41,33.88 157.72,34.57 arc(157.62,34.61) 157.52,34.57 157.44,34.49 arc(157.24,34.49) 157.24,34.69 157.32,34.77 arc(157.36,34.87) 157.32,34.97 arc(157.22,35.01) 157.12,34.97 157.04,34.89 arc(156.84,34.89) 156.84,35.09 156.92,35.17 arc(156.96,35.27) 156.92,35.37 156.11,36.18 155.43,36.18 147.81,43.8 147.53,43.8 143.96,47.37 125.83,47.37 121.99,51.22 120.8,51.22 120.65,51.07 120.65,50.87 120.82,50.71 v1(121.22,50.71)
  L6 w0.057: v3(147.04,33.68) 146.88,33.52 146.88,32.85 147.59,32.14 157.79,32.14 v2(157.96,32.3)
  BOTTOM w0.072: CN2300.13 CR2307.10 v3(147.04,33.68)
PCIE1_WAKE_N_3P3: length 33.5
  TOP w0.1: v1(130.97,48.2) 130.96,48.2 U2301.7
  L3 w0.1: v2(157.7,49.07) 156.84,49.07 156.52,48.75 155.96,48.75 155.67,49.04 140.39,49.04 139.74,48.38 136.65,48.38 136.52,48.25 133.1,48.25 132.74,48.62 131.53,48.62 131.11,48.2 v1(130.97,48.2)
  L6 w0.1: v3(158.12,47.03) 158.12,47.4 157.7,47.81 v2(157.7,49.07)
  BOTTOM w0.1: v3(158.12,47.03) 157.29,46.21 CN2300.54
PCIE_ETH_LEDG: length 33.7
  TOP w0.1: R1502.2 33.78,114.48 v1(33.63,114.48)
  L3 w0.1: J1500.12 4.55,112.31 10.76,112.31 14.39,115.93 18.92,115.93 20.69,114.16 v1(21.24,114.16) 21.66,114.58 26.36,114.58 27.01,115.22 28.48,115.22 28.99,114.71 33.4,114.71 v1(33.63,114.48)
PCIE_ETH_LEDY: length 50.7
  TOP w0.1: v1(16.19,98.65) 9.71,98.65 3.8,104.56 J1500.13
  TOP w0.3: v1(34.94,114.64) 34.94,114.19 R1514.2
  L3 w0.1: v1(34.94,114.64) 34.33,114.64 34.07,114.91 29.08,114.91 28.56,115.42 26.93,115.42 26.29,114.79 21.16,114.79 v2(21.01,114.64) ; v1(16.19,98.65) 16.44,98.9 20.51,98.9 v2(20.55,98.86)
  L6 w0.1: v2(21.01,114.64) 20.63,114.26 20.63,98.94 v2(20.55,98.86)
PG_VREG_3P3: length 4.1
  BOTTOM w0.2: U500.7 92.26,76.49 92.78,77.01 R515.2 92.39,77.43 92.29,77.53 92.29,79.03 R539.2
PG_VREG_5P0: length 141.1
  L3 w0.2: v2(91.5,104.8) 91.48,104.82 89.33,104.82 87,107.15 61.98,107.15 61.83,107 v2(58.51,107)
  L6 w0.2: v2(91.5,104.8) 91.5,90.9 89.95,89.35 89.95,81.17 90.45,80.67 90.45,74.52 91.2,73.77 91.2,70.67 91.65,70.22 91.65,68.39 v3(92.08,67.95) 91.15,67.02 91.15,65.07 90.75,64.67 90.75,25.25 v8(90.75,25.25)
  L6 w0.3: v3(58.51,114) 58.95,113.56 58.95,107.44 v2(58.51,107)
  L7 w0.2: v7(105.13,25.25) v8(90.75,25.25)
  BOTTOM w0.2: U700.4 v7(105.13,25.25)
  BOTTOM w0.25: v3(92.08,67.95) 92.08,68.4 92.26,68.59 U500.24
PG_VREG_CAM_6P7: length 107
  L3 w0.2: v2(65.05,13.62) 66.45,13.62 66.8,13.97 106.4,13.97 107.65,12.72 120,12.72 v2(120.15,12.57)
  L6 w0.2: v3(64.15,49.42) 64.15,40.17 65.05,39.27 v2(65.05,13.62) ; v2(120.15,12.57) 121.25,11.46 121.25,5.06 v3(120.96,4.77)
  BOTTOM w0.2: U600.5 68.79,51.66 68.19,51.07 TP602.1 R899.2 65.05,50.32 v3(64.15,49.42)
POWER_DISABLE_TO_IOB: length 17.5
  TOP w0.1: R2708.2 123.79,53.34 111.02,53.34 110.38,52.71 110.38,51.33 109.84,50.79 J2700.A19
POWER_EN_1P8: length 8.5
  TOP w0.1: v1(120.62,40.04) 120.62,38.77 J2700.I9 ; v1(126.72,40.02) 126.83,39.91 R538.1
  L3 w0.1: v1(120.62,40.04) 120.78,40.04 126.66,40.04 126.67,40.02 126.72,40.02 v1(126.72,40.02)
PWREN0: length 5.3
  TOP w0.1: TP2400.1 147.33,94.25 149.38,94.25 149.75,93.88 149.75,92.69 150.36,92.08 U2400.42
PWREN1: length 37.3
  TOP w0.1: R2724.2 146.65,104.87 147.1,105.32 v1(151.45,105.32)
  L3 w0.1: v1(151.45,105.32) 159.04,105.32 v2(159.76,106.03) ; v1(159.57,86.48) 159.25,86.48 v2(159.2,86.53)
  L6 w0.1: v2(159.76,106.03) 159.76,105.6 159.83,105.53 159.83,87.67 159.2,87.04 v2(159.2,86.53)
PWREN2: length 38
  TOP w0.1: U2400.76 158.81,85.3 v1(158.81,85.3) ; R2734.2 v1(163.65,109.97)
  L3 w0.1: v2(165.23,85.41) 165.01,85.41 164.9,85.3 v1(158.81,85.3) ; v1(163.65,109.97) 164.86,109.97 v2(164.88,109.95)
  L6 w0.1: v2(164.88,109.95) 164.88,109.7 165.01,109.57 165.01,90.42 165.42,90.01 165.42,89.72 165.08,89.38 165.08,85.56 v2(165.23,85.41)
PWREN3: length 22.5
  TOP w0.1: v1(158.42,93.87) 158.41,93.88 U2400.21
  L3 w0.1: v1(153.36,109.07) 153.65,109.36 159.17,109.36 v2(159.19,109.37) ; v2(159.26,94.16) 159.14,94.16 158.86,93.87 v1(158.42,93.87)
  L6 w0.1: v2(159.19,109.37) 159.19,109.11 159.19,109.1 159.19,108.95 159.21,108.94 159.21,105.59 159.43,105.37 159.43,94.33 v2(159.26,94.16)
PWREN4: length 15.1
  L3 w0.1: v1(152.95,105.82) 152.75,105.62 150.79,105.62 v2(150.73,105.56) ; v1(150.8,93.29) 150.28,93.81 v2(150.28,93.91)
  L6 w0.1: v2(150.28,93.91) 150.28,96.83 150.44,97 150.44,105.42 150.58,105.56 v2(150.73,105.56)
REGOUT: length 14.6
  TOP w0.2: 35.42,111.25 35.28,111.12 U1500.24
  TOP w0.3: R1512.1 v1(30.18,117.27) ; v1(35.81,117.86) 35.81,112.86 35.42,112.46 35.42,111.25
  L3 w0.3: v1(35.81,117.86) 35.41,118.27 30.83,118.27 30.18,117.61 v1(30.18,117.27)
RS232_RX: length 15.9
  TOP w0.1: U4001.4 135.19,107.02 v1(135.2,107.02)
  TOP w0.127: U4000.9 136.5,120.13 v1(136.5,120.11)
  L3 w0.127: v1(135.2,107.02) 135.43,107.02 v2(135.55,106.9) ; v2(135.57,119.79) 135.89,120.11 v1(136.5,120.11)
  L6 w0.127: v2(135.55,106.9) 135.55,107.63 136.1,108.18 136.1,118.54 135.57,119.07 v2(135.57,119.79)
RS232_RX_1P8: length 86.9
  TOP w0.1: v1(118,34.09) 117.59,34.09 J2700.G6 ; R4006.1 135.2,101.82 134.7,101.32 130.85,101.32 v1(130.35,100.82)
  L3 w0.1: v2(130.01,101.16) v1(130.35,100.82) ; v2(129.62,33.5) 129.62,33.49 123.07,33.49 122.8,33.77 118.32,33.77 v1(118,34.09)
  L6 w0.1: v2(130.01,101.16) 130.19,100.97 130.19,94.7 129.89,94.4 129.89,66.36 129.77,66.24 129.77,54.91 129.72,54.87 129.72,49.04 129.4,48.72 129.4,33.72 v2(129.62,33.5)
RS232_RX_RIN: length 25.8
  TOP w0.1: J3310.2 164.98,124.03 164.6,123.64 D4000.1 ; U4000.8 142.35,120.09 v1(143.3,120.09)
  L3 w0.1: v1(164.62,123.52) 164.54,123.44 151.86,123.44 148.55,120.14 143.35,120.14 v1(143.3,120.09)
RS232_TX: length 15.6
  TOP w0.1: U4001.5 v1(134.79,106.65)
  L3 w0.127: v2(135.6,106.4) 135.04,106.4 v1(134.79,106.65) ; v2(136.04,119.49) 136.49,119.49 v1(136.49,119.49)
  L6 w0.127: v2(135.6,106.4) 135.96,106.76 135.96,107.7 136.36,108.1 136.36,118.77 136.04,119.09 v2(136.04,119.49)
RS232_TX_1P8: length 94.9
  TOP w0.1: v1(118,33.74) 117.75,33.74 117.4,33.39 J2700.G5 ; U4001.8 v1(134.79,103.72)
  L3 w0.1: v2(135.15,32.82) 134.8,33.17 132.45,33.17 132.2,33.42 131.65,33.42 131.1,32.87 126.3,32.87 126.07,33.09 121.2,33.09 120.77,33.52 118.22,33.52 v1(118,33.74) ; v1(134.79,103.72) 134.79,103.71 134.79,103.28 v2(135,103.07)
  L6 w0.1: v2(135.15,32.82) 135.15,38.97 136.55,40.37 136.55,41.12 138.05,42.62 138.05,47.92 135.6,50.37 135.6,54.04 134.95,54.69 134.95,70.42 135.7,71.17 135.7,75.77 136.35,76.42 136.35,80.32 136.8,80.77 136.8,98.17 135.6,99.36 135.6,102.71 135.25,103.07 v2(135,103.07)
RS232_TX_DOUT: length 28
  TOP w0.1: J3310.1 166.23,124.09 166.62,123.7 D4001.1
  L3 w0.1: v1(142.3,119.49) 142.62,119.81 148.51,119.81 151.94,123.24 166.35,123.24 v1(166.64,123.54)
RS485_A0: length 40.1
  TOP w0.2: R3910.2 128.59,111.17 TVS3900.2 127.72,111.12 v1(127.64,111.2)
  TOP w0.3: R3301.2 148.76,122.07 151.06,124.37 J3303.1
  L3 w0.25: v1(127.64,111.2) 136.46,111.2 136.6,111.07 148.11,111.07 148.22,111.17 v2(148.78,111.17) ; v1(147.58,122.03) 147.93,122.03 148.25,121.7 v2(148.25,121.66)
  L6 w0.25: v2(148.78,111.17) 148.78,121.14 v2(148.25,121.66)
RS485_A0_R: length 22.4
  L3 w0.3: v1(124.25,120.18) 125.71,121.64 133.2,121.64 133.35,121.79 145.59,121.79 v1(145.87,122.07)
RS485_B0: length 42.4
  TOP w0.2: R3909.2 129.32,109.97 TVS3901.2 127.72,109.97 v1(127.64,109.9)
  TOP w0.3: v1(127.64,109.9) 127.63,109.91 125.11,109.91 124.24,110.78 SW3300.12
  L3 w0.3: v1(127.64,109.9) v2(127.64,110.36) ; v1(149.76,125.47) 147.79,123.5 146.7,123.5 145.4,122.19 133.19,122.19 133.1,122.11 v2(128.03,122.11)
  L6 w0.3: v2(128.03,122.11) 128.01,122.09 128.01,110.73 v2(127.64,110.36)
RS485_RTS_1P8: length 117.8
  TOP w0.1: v1(111.71,35.38) 111.71,34.93 J2700.B6
  L3 w0.1: v2(140.37,34.09) 139.32,34.09 139.22,33.99 135.5,33.99 135.02,34.47 128.7,34.47 128.4,34.17 124.55,34.17 124.01,34.7 119.01,34.7 118.75,34.97 116.56,34.97 116.06,35.47 111.8,35.47 v1(111.71,35.38) ; v2(138.64,113.18) 138.71,113.25 142.04,113.25 v1(142.11,113.18)
  L6 w0.1: v2(138.64,113.18) 138.1,112.64 138.1,105.26 139.93,103.43 139.93,99.13 138.15,97.35 138.15,82.14 138.14,82.14 138.14,81.85 138.15,81.84 138.15,80.85 138.15,80.85 138.15,80.56 138.15,80.55 138.15,74.22 arc(138.14,74.17) 138.11,74.13 138.08,74.09 arc(138.05,74.06) 138.05,74.02 138.05,64.7 138.05,64.7 138.05,56.55 138.88,55.72 139.65,55.72 141.66,53.7 141.66,35.38 v2(140.37,34.09)
RS485_RX: length 9.5
  TOP w0.1: U4002.4 129.43,106.7 129.8,107.07 133.8,107.07 135.38,108.65 U3901.1
RS485_RX_1P8: length 82
  TOP w0.1: J2700.E9 115,37.97 v1(115.45,37.97)
  L3 w0.1: v2(129.75,36.37) 123.1,36.37 122.35,37.12 117.15,37.12 116.3,37.97 v1(115.45,37.97) ; v1(129.67,102.24) v2(130.01,101.91)
  L6 w0.1: v2(130.01,101.91) 130.39,101.52 130.39,94.62 130.09,94.32 130.09,66.18 129.97,66.06 129.97,54.83 129.92,54.79 129.92,48.89 129.75,48.72 v2(129.75,36.37)
RS485_TX: length 15.4
  TOP w0.127: v1(137.46,112.46) 137.46,112.46 U3901.4
  L3 w0.127: v2(133.83,106.19) 133.63,106 v1(129.03,106) ; v2(133.64,112.7) 137.22,112.7 v1(137.46,112.46)
  L6 w0.127: v2(133.64,112.7) 133.64,106.37 v2(133.83,106.19)
RS485_TX_1P8: length 105.6
  L3 w0.1: v1(129.03,104.35) 134.71,104.35 v2(135,104.07) ; v1(111.05,35.55) 111.26,35.76 116.05,35.76 116.65,35.17 119,35.17 119.26,34.9 124.36,34.9 124.85,34.42 128.2,34.42 128.5,34.72 135.29,34.72 v2(135.66,34.34)
  L6 w0.1: v2(135.66,34.34) 135.4,34.6 135.4,38.77 136.8,40.17 136.8,41.02 138.3,42.52 138.3,47.97 135.8,50.47 135.8,54.17 135.15,54.82 135.15,70.24 135.95,71.04 135.95,75.62 136.6,76.27 136.6,80.22 137.05,80.67 137.05,98.37 135.8,99.62 135.8,103.26 v2(135,104.07)
RST_OUT: length 16.7
  TOP w0.1: R2418.2 R2404.2 v1(149.15,78.17) C2413.1 D2400.1 ; U2400.68 v1(155.61,85.27)
  L3 w0.1: v1(155.61,85.27) 153.9,83.56 v2(153.71,83.56) ; v1(149.15,78.17) 149.64,77.67 151.61,77.67 v2(151.61,77.67)
  L6 w0.1: v2(153.71,83.56) 151.61,81.46 v2(151.61,77.67)
RTL8111_ISOLATEB_1P8: length 89.2
  TOP w0.1: J2600.E27 47.6,36.75 47.06,37.29 46.19,37.29 45.61,37.87 44.91,37.87 44.07,37.03 41.99,37.03 v1(41.79,37.23) ; v1(37.45,109.9) 37.45,109.9 R1507.2
  L3 w0.1: v1(37.45,109.9) 39.86,109.9 v2(40.11,109.65) ; v1(41.79,37.23) 41.63,37.23 41.54,37.13 37.97,37.13 37.69,37.41 37.29,37.41 v2(37.28,37.41)
  L6 w0.1: v2(37.28,37.41) 37.28,38.79 37.78,39.29 37.78,50.9 37.59,51.09 37.59,54.45 37.05,54.99 37.05,56.13 37.24,56.32 37.24,58.68 37.23,58.69 37.23,58.89 37.29,58.96 37.29,60.6 37.99,61.3 37.99,75.59 38.34,75.94 38.34,86.28 40.58,88.52 40.58,107 40.26,107.32 40.26,109.5 v2(40.11,109.65)
RTL8111_PWR_EN_1P8: length 157.4
  TOP w0.1: J2700.I7 119.38,36.12 117.09,36.12 v1(117.01,36.2)
  L3 w0.1: v1(117.01,36.2) 115.92,37.29 112.44,37.29 108.75,40.97 76.9,40.97 76.59,41.28 67.71,41.28 67.34,41.65 64.55,41.65 64.14,42.06 57.91,42.06 57.61,42.36 56.99,42.36 56.79,42.16 51.7,42.16 50.98,42.88 50.98,50.22 50.09,51.11 50.09,51.92 47.97,54.04 47.97,54.25 47.5,54.71 46.91,54.71 44.3,57.32 40.77,57.32 v2(40.41,57.69) ; v1(42.45,118.58) 41.61,118.58 v2(41.52,118.48)
  L6 w0.1: v2(40.41,57.69) 40.41,58.94 39.55,59.8 39.55,61.77 38.99,62.32 38.99,75.18 39.34,75.52 39.34,83.76 40.36,84.78 40.36,88.02 40.78,88.44 40.78,107.09 40.48,107.38 40.48,117.45 v2(41.52,118.48)
RTL8111_RSTN: length 144.4
  TOP w0.1: R1508.2 37.63,109.1 v1(37.99,109.1) ; v1(114.2,39.22) 114.34,39.36 J2700.E10
  L3 w0.1: v2(36.94,59.56) 37.47,59.03 40.29,59.03 40.6,58.72 44.42,58.72 48.8,54.33 48.8,54.33 51.58,51.55 51.58,44.31 53.13,42.76 56.55,42.76 56.74,42.96 57.86,42.96 58.16,42.66 62.65,42.66 62.95,42.96 63.41,42.96 63.91,42.46 64.31,42.46 64.71,42.05 67.51,42.05 67.84,41.72 76.72,41.72 77.02,41.42 100.17,41.42 100.85,42.1 101.74,42.1 102.43,41.41 108.92,41.41 110.58,39.74 111.89,39.74 112.41,39.22 v1(114.2,39.22) ; v2(38.38,108.92) 38.2,109.1 v1(37.99,109.1)
  L6 w0.1: v2(38.38,108.92) 40.38,106.92 40.38,88.6 38.14,86.37 38.14,76.02 37.79,75.67 37.79,61.38 37.09,60.68 37.09,59.62 37.03,59.56 v2(36.94,59.56)
RTL8111_WAKE_1P8: length 136
  TOP w0.1: v1(42.6,106.64) 42.61,106.65 R1521.2 ; J2700.E11 114.38,41.12 v1(114.2,41.12)
  L3 w0.1: v2(107.85,103.1) 106.75,104.2 103.08,104.2 102.3,104.99 94.17,104.99 92.99,106.17 89.8,106.17 88.12,107.85 53.95,107.85 52.72,106.62 49,106.62 v1(48.36,105.97) 48.16,106.17 42.8,106.17 42.6,106.37 v1(42.6,106.64) ; v1(114.2,41.12) 113.22,41.12 110.15,44.19 110.15,46.75 v2(109.31,47.58)
  L6 w0.1: v2(109.31,47.58) 109.4,47.67 109.4,89.45 108.35,90.5 108.35,95.8 107.72,96.42 107.72,97.28 107.2,97.8 107.2,101.55 107.85,102.2 v2(107.85,103.1)
RTL8211_INT_1P8: length 106.2
  TOP w0.1: v1(54.06,46.61) 54.06,46.95 53.57,47.44 47.34,47.44 46.82,46.92 J2600.F19 ; v1(93.3,105.36) 93.3,105.36 R1405.1
  L3 w0.1: v1(93.3,105.36) 93.06,105.6 v2(91.5,105.6) ; v2(89.86,46.91) 89.73,46.78 87.59,46.78 87.08,47.28 56.87,47.28 56.15,46.56 54.07,46.56 54.06,46.57 v1(54.06,46.61)
  L6 w0.1: v2(91.5,105.6) 91.12,105.22 91.12,90.97 89.68,89.53 89.68,80.94 90.14,80.49 90.14,69.78 89.68,69.32 89.68,47.08 v2(89.86,46.91)
RTL8211_MDC_1P8: length 93.7
  TOP w0.1: J2700.H9 118.05,37.47 v1(118.05,36.42)
  L3 w0.1: v1(118.05,36.42) 118,36.37 117.25,36.37 116.12,37.49 112.52,37.49 108.83,41.18 102.35,41.18 101.63,41.89 101.17,41.89 101.05,41.78 v2(101.05,41.75) ; v2(100.3,112.2) 100.65,112.55 101.37,112.55 v1(101.66,112.84)
  L6 w0.1: v2(100.3,112.2) 100.3,62.94 100.63,62.61 100.63,44.04 101.05,43.61 v2(101.05,41.75)
RTL8211_MDIO_1P8: length 91.4
  TOP w0.1: v1(118.41,38.64) 118.67,38.91 J2700.H10
  L3 w0.1: v1(118.41,38.64) 117.12,38.64 116.54,39.22 114.6,39.22 114.35,39.47 112.5,39.47 112.02,39.94 111.58,39.94 107.96,43.57 100.81,43.57 v2(100.61,43.37) ; v2(99.7,112.2) 100.34,112.84 v1(100.84,112.84)
  L6 w0.1: v2(99.7,112.2) 100.04,111.86 100.04,62.91 100.43,62.53 100.43,43.55 v2(100.61,43.37)
RTL8211_RST_1P8: length 134.7
  TOP w0.1: J2600.F24 46.85,40.56 v1(46.86,40.55) ; Q1400.2 v1(104.79,112.27)
  L3 w0.1: v1(104.79,112.27) v2(106.46,112.27) ; v2(103.19,38.9) 103.04,39.05 102.83,39.05 102.75,39.13 64.24,39.13 63.31,40.06 56.46,40.06 56.45,40.06 47.82,40.06 47.33,40.55 v1(46.86,40.55)
  L6 w0.1: v2(106.46,112.27) 106.46,107.78 107,107.24 107,104.5 106.35,103.85 106.35,102.4 105.5,101.55 105.5,94.2 106.05,93.65 106.05,55.07 105.86,54.88 105.86,45.78 102.79,42.71 102.79,39.3 v2(103.19,38.9)
RTL8367_AVDDH: length 126.6
  TOP w0.2: U1701.90 154.87,56.05 155.82,55.1 155.93,55.1 C1748.1 ; U1701.17 150.87,74.5 150.26,75.11 C1744.1 149.43,75.11 C1751.1 ; v1(149.44,52.14) 149.51,52.14 149.74,52.37 149.74,53.37 149.63,53.48 C1749.1 149.24,54.01 150,54.76 150.82,54.76 151.67,55.62 U1701.82 ; C1750.1 140.84,70.68 U1701.33 ; U1701.116 158.89,65.9 C1746.1 ; v1(161.35,59.46) 161.35,59.47 C1747.1 161.33,60.28 U1701.102 ; U1701.21 149.27,73.62 148.76,74.14 148.04,74.14 C1752.1 C1743.1 ; C1753.1 154.44,74.5 153.27,73.33 U1701.11 ; C1745.1 161.35,71.51 160.78,71.51 159.96,70.68 U1701.128
  TOP w0.3: B1705.1 138.15,71.85 B1706.2 v1(139.75,72.55) 140.69,71.61 C1750.1 ; v1(157.81,51.93) 157.2,52.54 157.2,54.24 157.04,54.39 C1748.1 ; C1742.1 161.36,71.64 161.35,71.63 C1745.1
  L3 w0.2: v1(161.43,65.77) 161.83,65.77 162.09,65.51 v2(163.15,65.51)
  L3 w0.25: v2(163.01,72.45) 163.45,72.89 163.45,74.9 162.68,75.67 154.98,75.67 v1(154.44,75.14) 154.07,75.5 v2(149.74,75.5) v1(149.44,75.2) 149.43,75.18 v1(146.21,75.18)
  L3 w0.3: v1(146.21,75.18) 145.79,75.6 144.5,75.6 142.42,73.53 140.73,73.53 v1(139.75,72.55) ; v1(157.81,51.93) 157.06,51.93 v2(157.01,51.89) ; v2(148.81,52.46) 149.12,52.14 v1(149.44,52.14) ; v2(163.05,59.34) 162.93,59.46 v1(161.35,59.46) ; v2(163.01,72.45) v1(161.41,72.45)
  L5 w0.3: v2(148.81,52.46) 148.92,52.34 152.35,52.34 153.08,53.08 155.83,53.08 v2(157.01,51.89)
  L6 w0.25: v2(148.81,52.46) 148.81,53.94 148.3,54.45 148.3,70.25 149.95,71.9 149.95,75.29 v2(149.74,75.5)
  L6 w0.3: v2(163.01,72.45) 163.15,72.3 v2(163.15,65.51) 163.15,65.35 163.05,65.25 v2(163.05,59.34)
RTL8367_AVDDL: length 98.9
  TOP w0.2: U1701.122 161.4,68.28 C1737.1 161.4,69.13 C1730.1 161.41,70.09 C1731.1 ; v1(159.55,55.4) 158.54,54.39 C1735.1 156.87,55.27 U1701.95 ; U1701.27 146.87,73.01 145.37,74.51 C1734.1 ; v1(160.73,61.45) 161.1,61.45 161.38,61.73 C1729.1 161.41,61.73 C1736.1 161.31,62.68 U1701.108 ; U1701.14 152.07,73.84 152.77,74.53 C1733.1 ; U1701.6 155.27,75.08 C1732.1 156.1,75.08 C1710.1 156.94,75.08 C1711.1 157.79,75.09 C1723.1 158.62,75.09 B1701.1 158.64,75.08 B1703.1
  TOP w0.3: C1733.1 v1(152.76,75.1) ; C1731.1 v1(161.41,70.94)
  L3 w0.2: v1(159.55,55.4) v2(163.9,55.4) ; v1(160.73,61.45) 160.77,61.41 163.09,61.41 163.2,61.3 164.14,61.3 v2(164.2,61.36)
  L3 w0.25: v1(145.36,75.15) 145.37,75.15 145.77,74.75 149.9,74.75 150.25,75.1 v1(152.76,75.1) 153.73,75.1 154.1,74.73 154.94,74.73 155.31,75.11 v1(158.66,75.11)
  L3 w0.3: v2(158.62,74.3) 158.62,75.07 158.62,75.07 v1(158.66,75.11) ; v2(164.2,70.95) 164.19,70.94 v1(161.41,70.94) 158.16,70.94 v2(157.95,70.73) 150.13,62.9 v1(139.15,62.9) v1(138.85,62.9)
  L6 w0.3: v2(164.2,70.95) v2(164.2,61.36) 164.2,55.7 v2(163.9,55.4) ; 157.95,70.73 157.95,70.69 v2(157.95,70.73) 157.95,70.73 ; 157.95,70.73 157.95,72.31 158.62,72.98 v2(158.62,74.3)
RTL8367_DVDDIO: length 256.2
  TOP w0.1: U1600.1 128.34,65.87 C1601.1
  TOP w0.2: U1605.7 128.29,72.63 v1(128.57,72.35) 128.58,72.34 129.11,72.34 129.89,71.56 D1600.1 ; R1612.2 131.39,75.86 131.75,76.22 v1(131.75,77.67) 131.75,79.1 ; 131.75,79.1 C1612.1 130.65,79.31 U1606.7 ; 131.75,79.1 133.44,79.1 133.85,79.52 133.85,81.52 133.62,81.74 R1616.2 ; R1601.1 139.95,78.41 R1605.1 ; U1604.8 131.34,61.98 131.47,61.85 C1608.2
  TOP w0.3: R1704.1 148.33,52.68 R1706.1 ; U1601.5 138.54,76.17 138.82,75.88 138.82,75.3 C1603.2 ; C1412.1 107.13,105.64 R1413.1 v1(107.13,102.9) ; C1603.2 138.83,73.47 v1(138.85,73.45) ; C1603.2 139.3,75.29 139.47,75.46 R1605.1 ; v1(153.7,51.52) 153.68,51.52 153.3,51.9 R1700.1 ; R1709.1 145.66,52.67 R1711.1 ; v1(139.79,56.55) 139.24,57.1 139.24,58.5 139.47,58.73 R1720.1 ; v1(170.38,56.23) 170.35,56.27 R2004.1 ; R1714.1 142.99,52.65 v1(142.99,52.61) ; v1(129.43,62.42) 129.43,66.19 ; C1608.2 131.15,61.42 131.02,61.55 v1(130.95,61.55) ; R1701.1 154.93,53.59 R1703.1 155.78,52.57 v1(155.93,52.42) ; v1(154.9,48.49) 154.9,47.75 155.11,47.53 C1701.1
  L3 w0.2: v1(145.67,56.68) 139.91,56.68 v1(139.79,56.55) ; v1(131.75,77.67) 131.4,78.02 v2(129.45,78.02) 125.6,78.02 124.75,78.87 v2(105.45,78.87)
  L3 w0.3: v1(170.44,77.62) 169.01,77.62 v2(169.01,77.59) ; v2(170.91,56.23) v1(170.38,56.23) 170.38,55.7 170.1,55.42 170.1,54.2 168.27,52.37 155.98,52.37 v1(155.93,52.42) 155.74,52.61 153.44,52.61 v2(153.28,52.44) 153.28,51.92 153.49,51.71 153.51,51.71 v1(153.7,51.52) ; v1(130.13,66.97) 133.5,66.97 134.08,66.39 v1(137.21,66.39) 137.63,66.81 139.16,66.81 139.16,66.81 v2(139.18,66.81) ; v1(129.43,62.42) 130.29,61.57 130.93,61.57 v1(130.95,61.55) ; v2(170.48,33.75) 170.48,34.37 v1(170.28,34.57) ; v2(147.99,52.4) 147.62,52.4 v1(147.47,52.56) 147.28,52.37 144.98,52.37 v1(144.75,52.6) 144.49,52.6 144.48,52.61 v1(142.99,52.61) 142.66,52.61 v2(142.05,52.01) v1(140.87,52.01) ; v1(139.79,56.55) 139.36,56.55 v2(139.3,56.49) ; v2(106,103.5) 106.53,103.5 v1(107.13,102.9) ; v2(142.57,48.38) 142.68,48.49 v1(154.9,48.49) ; v1(128.57,72.35) v2(128.9,72.35) 135.53,72.35 136.11,72.93 v2(138.9,72.93) 138.9,73.21 138.85,73.26 v1(138.85,73.45)
  L5 w0.3: v2(153.28,52.44) 153.11,52.44 152.54,51.87 148.53,51.87 v2(147.99,52.4)
  L6 w0.3: 139.16,66.81 139.16,56.63 v2(139.3,56.49) 139.32,56.49 142.05,53.76 v2(142.05,52.01) 142.05,48.89 v2(142.57,48.38) ; 139.16,66.81 v2(139.18,66.81) ; 139.16,66.81 138.9,67.07 v2(138.9,72.93) ; v2(106,103.5) 106,102.55 105.2,101.75 105.2,92.9 105.65,92.45 105.65,79.07 v2(105.45,78.87) ; v2(128.9,72.35) 128.9,77.47 v2(129.45,78.02) ; v2(169.01,77.59) 169.01,67.88 171.1,65.8 171.1,57.37 170.91,57.18 v2(170.91,56.23) 170.07,55.39 170.07,50.79 170.48,50.38 v2(170.48,33.75)
RTL8367_DVDDIO2: length 18
  TOP w0.2: U1701.59 140.79,60.28 C1717.1 ; U1701.42 142.1,67.08 141.4,66.38 140.68,66.38 C1716.1 139.84,66.36 C1714.1 139.01,66.35 C1715.1 138.15,66.35 v1(138.11,66.39)
  TOP w0.3: C1717.1 140.63,60.19 v1(140.63,60.2)
  L3 w0.3: v2(137.49,65.97) 137.45,65.97 137.87,66.39 v1(138.11,66.39) ; v2(137.5,60.46) 137.47,60.46 137.74,60.2 v1(140.63,60.2)
  L6 w0.3: v2(137.5,60.46) 137.46,60.46 137.46,63.96 137.45,63.97 137.45,64.39 137.45,65.97 v2(137.49,65.97)
RTL8367_DVDDIO_F: length 42.8
  TOP w0.2: R1607.1 125.51,82.58 125.05,82.12 v1(125.05,77.62) 125.05,73.15 126.07,72.13 ; U1606.6 130.25,79.37 v1(129.99,79.1) ; 126.07,72.13 126.07,70.43 D1600.2 ; 126.07,72.13 126.29,72.35 C1611.2 126.91,72.35 C1610.1 127.89,72.5 U1605.6 ; J1600.1 132.2,94.88 133.3,93.78 v1(133.3,91.72)
  L3 w0.2: v1(128.25,77.67) 125.1,77.67 v1(125.05,77.62) ; v1(133.3,91.72) 134.95,90.07 134.95,82.82 133.45,81.32 132.2,81.32 v1(129.99,79.1)
RTL8367_DVDDL: length 45.3
  TOP w0.2: v1(143.75,54.45) 144.24,54.94 145.49,54.94 146.47,55.92 U1701.69 ; C1721.1 140.89,60.68 U1701.58 ; U1701.20 149.67,73.65 148.88,74.44 148.88,74.44 148.16,74.44 147.84,74.76 C1722.1 147.84,76.02 C1719.1 147.84,76.94 147.78,77
  L3 w0.3: v1(139.7,61.05) v2(139.7,60.7) ; v2(141.66,54.94) 143.26,54.94 v1(143.75,54.45) ; v1(147.84,76.96) 147.46,76.58 144.13,76.58 141.99,74.44 v2(139.7,74.44)
  L6 w0.3: v2(139.7,74.44) 139.4,74.14 139.4,67.35 139.65,67.1 139.65,60.75 v2(139.7,60.7) 139.7,56.9 v2(141.66,54.94)
RTL8367_INT: length 29.6
  TOP w0.1: U1601.2 137.89,79.66 R1601.2 136.18,81.38 v1(135.98,81.38)
  L3 w0.1: v2(135.35,71.5) 149.94,71.5 150.07,71.63 v1(150.07,72.27) ; v1(135.98,81.38) v2(135.49,81.38)
  L6 w0.1: v2(135.49,81.38) 135.39,81.28 135.39,71.54 v2(135.35,71.5)
RTL8367_INT_1P8: length 120
  TOP w0.1: v1(136.41,74.55) 137.24,74.55 R1604.2 ; v1(54.81,45.85) 54.5,46.17 52.76,46.17 52.54,45.95 52.54,45.53 52.11,45.1 47.36,45.1 J2600.F20
  L3 w0.1: v1(54.81,45.85) 54.86,45.81 55.97,45.81 57.04,46.88 86.39,46.88 86.84,46.43 99.4,46.43 v2(99.58,46.62) ; v1(136.41,74.55) 135.91,74.05 v2(99.69,74.05)
  L6 w0.1: v2(99.58,46.62) 99.79,46.83 99.79,61.61 99.51,61.89 99.51,62.71 99.69,62.89 v2(99.69,74.05)
RTL8367_PLLVDDL0: length 19.9
  TOP w0.2: v1(161.41,63.93) 161.41,64.42 161.41,64.42 C1725.1 161.39,65.08 U1701.114
  L3 w0.2: v2(163.69,64) 163.66,63.97 163.6,63.97 163.56,63.93 v1(161.41,63.93)
  L3 w0.3: v2(163,74.23) v1(159.65,74.23)
  L6 w0.3: v2(163.69,64) 163.65,64.04 163.65,73.59 v2(163,74.23)
RTL8367_PWR_EN_1P8: length 41.2
  TOP w0.1: R1603.1 127.02,59.04 125.73,57.75 v6(125.73,57.68) ; J2700.E4 115.52,32.4 115.52,33.39 115.84,33.71 116.54,33.71 v1(116.73,33.89)
  L3 w0.1: v1(116.73,33.89) 116.71,33.89 116.73,33.87 117.49,33.87 118.1,33.27 120.67,33.27 121.07,32.87 125.51,32.87 125.66,32.72 v2(125.72,32.72)
  L6 w0.1: v6(125.73,57.68) 125.73,49.96 124.81,49.04 124.81,34.02 125.72,33.11 v2(125.72,32.72)
RTL8367_RST: length 55.2
  TOP w0.1: U1701.86 153.27,55.55 154.09,54.73 C1702.1 154.09,53.93 154.1,53.92 R1700.2 154.1,53.14 154.8,52.43 154.8,49.28 153.7,48.18 D1700.1 ; R1606.2 140.78,74.66 R1605.2 139.5,74.66 139.4,74.76 v1(139.4,74.9)
  L3 w0.1: v2(155.19,60.59) 154.96,60.82 140.58,60.82 v2(140.35,61.05) ; v1(153.69,48.13) 153.74,48.18 155.19,48.18 v2(155.43,48.41) ; v1(139.4,74.9) 139.47,74.97 v2(140.05,74.97)
  L6 w0.1: v2(140.35,61.05) 140.5,61.2 140.5,74.51 v2(140.05,74.97) ; v2(155.43,48.41) 155.43,51.33 155.35,51.4 155.35,60.43 v2(155.19,60.59)
RTL8367_RST_1P8: length 145.7
  TOP w0.1: J2600.F23 47.37,42.37 53.9,42.37 55.05,43.53 v1(55.38,43.53) ; U1602.2 v1(141.45,79.17)
  L3 w0.1: v1(141.45,79.17) 140.9,79.17 139.88,78.15 v2(137.79,78.15) ; v2(140.84,38.59) 138.87,38.59 138.2,39.26 120.94,39.26 120.25,38.57 118.9,38.57 118.57,38.9 117.22,38.9 116.65,39.47 114.7,39.47 114.45,39.72 112.65,39.72 112.22,40.14 111.67,40.14 108.04,43.77 107.29,43.77 105.6,45.45 87.35,45.45 86.74,44.84 85.9,44.84 85.63,45.11 65.48,45.11 65.46,45.1 65.26,45.1 65.24,45.11 59.81,45.11 59.8,45.11 59.6,45.11 59.59,45.11 58.06,45.11 56.81,43.86 56.64,43.86 56.31,43.53 v1(55.38,43.53)
  L6 w0.1: v2(137.79,78.15) 137.79,77.89 137.85,77.83 137.85,56.4 138.78,55.47 139.6,55.47 141.46,53.6 141.46,39.21 v2(140.84,38.59)
RTL8367_SCK: length 49.5
  TOP w0.1: U1700.6 158.39,49.87 157.46,49.87 156.4,50.93 v1(156.4,51.31) 156.4,51.32 154.49,53.24 154.49,54.32 154.56,54.39 R1701.2 154.93,54.62 153.67,55.88 U1701.87
  L3 w0.1: v1(130.99,62.43) 131.12,62.3 136.7,62.3 137.3,61.7 156.52,61.7 v2(156.88,62.06) ; v1(156.4,51.31) 156.48,51.39 v2(157.93,51.39)
  L6 w0.1: v2(156.88,62.06) 156.88,61.81 157.32,61.37 157.32,56.23 158.63,54.92 158.63,52.09 v2(157.93,51.39)
RTL8367_SCK_1P8: length 103.7
  TOP w0.1: v1(54.26,45.6) 53.76,45.11 52.43,45.11 52.22,44.9 47.36,44.9 J2600.F21 ; U1604.2 130.99,64.28 v1(130.99,64.28)
  L3 w0.1: v1(54.26,45.6) 56.04,45.6 57.12,46.68 86.3,46.68 86.75,46.23 99.9,46.23 100.07,46.4 v2(100.07,46.42) ; v2(99.88,62.3) 99.96,62.38 102.19,62.38 103.39,63.58 121.13,63.58 122.17,64.62 130.43,64.62 130.76,64.28 v1(130.99,64.28)
  L6 w0.1: v2(100.07,46.42) 100.09,46.43 100.09,62.06 99.88,62.26 v2(99.88,62.3)
RTL8367_SDA: length 46.7
  TOP w0.1: U1701.88 154.07,56.1 R1703.2 156.12,54.39 156.2,54.31 156.2,52.98 158.04,51.15 U1700.5 158.41,51.16 v1(158.41,51.27)
  L3 w0.1: v1(158.41,51.27) 158.71,51.27 v2(158.87,51.43) ; v2(157.47,61.8) 157.12,61.45 137.1,61.45 136.45,62.1 130.95,62.1 v1(130.63,62.42)
  L6 w0.1: v2(158.87,51.43) 158.87,55.05 157.59,56.33 157.59,61.69 v2(157.47,61.8)
RTL8367_SDA_1P8: length 108.1
  TOP w0.1: v1(52.68,42.62) 52.2,42.62 52.15,42.58 47.34,42.58 J2600.F22 ; U1604.3 130.64,63.79 R1611.2 v1(130.13,64.29)
  L3 w0.1: v2(101.22,61.98) 102.14,61.98 103.54,63.38 121.29,63.38 122.2,64.29 v1(130.13,64.29) ; v1(52.68,42.62) 52.74,42.56 56.63,42.56 56.82,42.76 57.77,42.76 58.07,42.46 62.74,42.46 62.83,42.54 62.83,42.55 63.04,42.76 63.33,42.76 63.83,42.26 64.23,42.26 64.63,41.85 67.42,41.85 67.79,41.48 76.67,41.48 76.94,41.22 101.26,41.22 v2(101.49,41.45)
  L6 w0.1: v2(101.22,61.98) 101.21,61.98 101.21,61.98 100.85,61.62 100.85,44.12 101.42,43.55 101.42,41.52 v2(101.49,41.45)
RTL8367_SVDDH: length 5.4
  TOP w0.2: U1701.41 141.7,67.48 141.31,67.09 140.66,67.09 C1738.1 139.86,67.08 C1739.1 139.84,67.09 139.37,67.09 139.16,67.3 138.08,67.3
RTL8367_SVDDL: length 31.1
  TOP w0.2: 140.73,68.66 141.92,68.66 142.34,69.08 U1701.37
  TOP w0.3: v1(140.72,68.67) 140.73,68.66 ; B1701.2 159.51,75.11 C1712.1
  L3 w0.3: v1(159.52,76.78) 159.52,76.77 158.87,76.12 144.35,76.12 142.19,73.97 v2(140.09,73.97) ; v1(140.72,68.67) 140.12,68.67 v2(140.09,68.65)
  L6 w0.3: v2(140.09,73.97) 139.9,73.77 139.9,68.84 v2(140.09,68.65)
RTL_SPI_CK: length 19.7
  TOP w0.1: U1701.48 v1(143.27,64.67)
  L3 w0.1: v2(133.2,66.47) 134.4,65.27 142.68,65.27 v1(143.27,64.67) ; v2(133.2,72.97) 132.8,73.36 v1(131,73.36)
  L6 w0.1: v2(133.2,66.47) v2(133.2,72.97)
RTL_SPI_CK_S: length 27
  TOP w0.1: U1605.5 126.67,73.77 125.85,74.59 125.85,78.66 125.98,78.8 126.58,78.8 126.73,78.64 126.73,78.22 U1603.6
  L3 w0.1: v1(126.73,78.37) 128.25,78.37 128.65,78.77 128.65,79.72 128.9,79.97 129.9,79.97 131.75,81.82 133.25,81.82 134.55,83.12 134.55,86.94 131.5,89.99 131.5,90.88 v1(131.25,91.13)
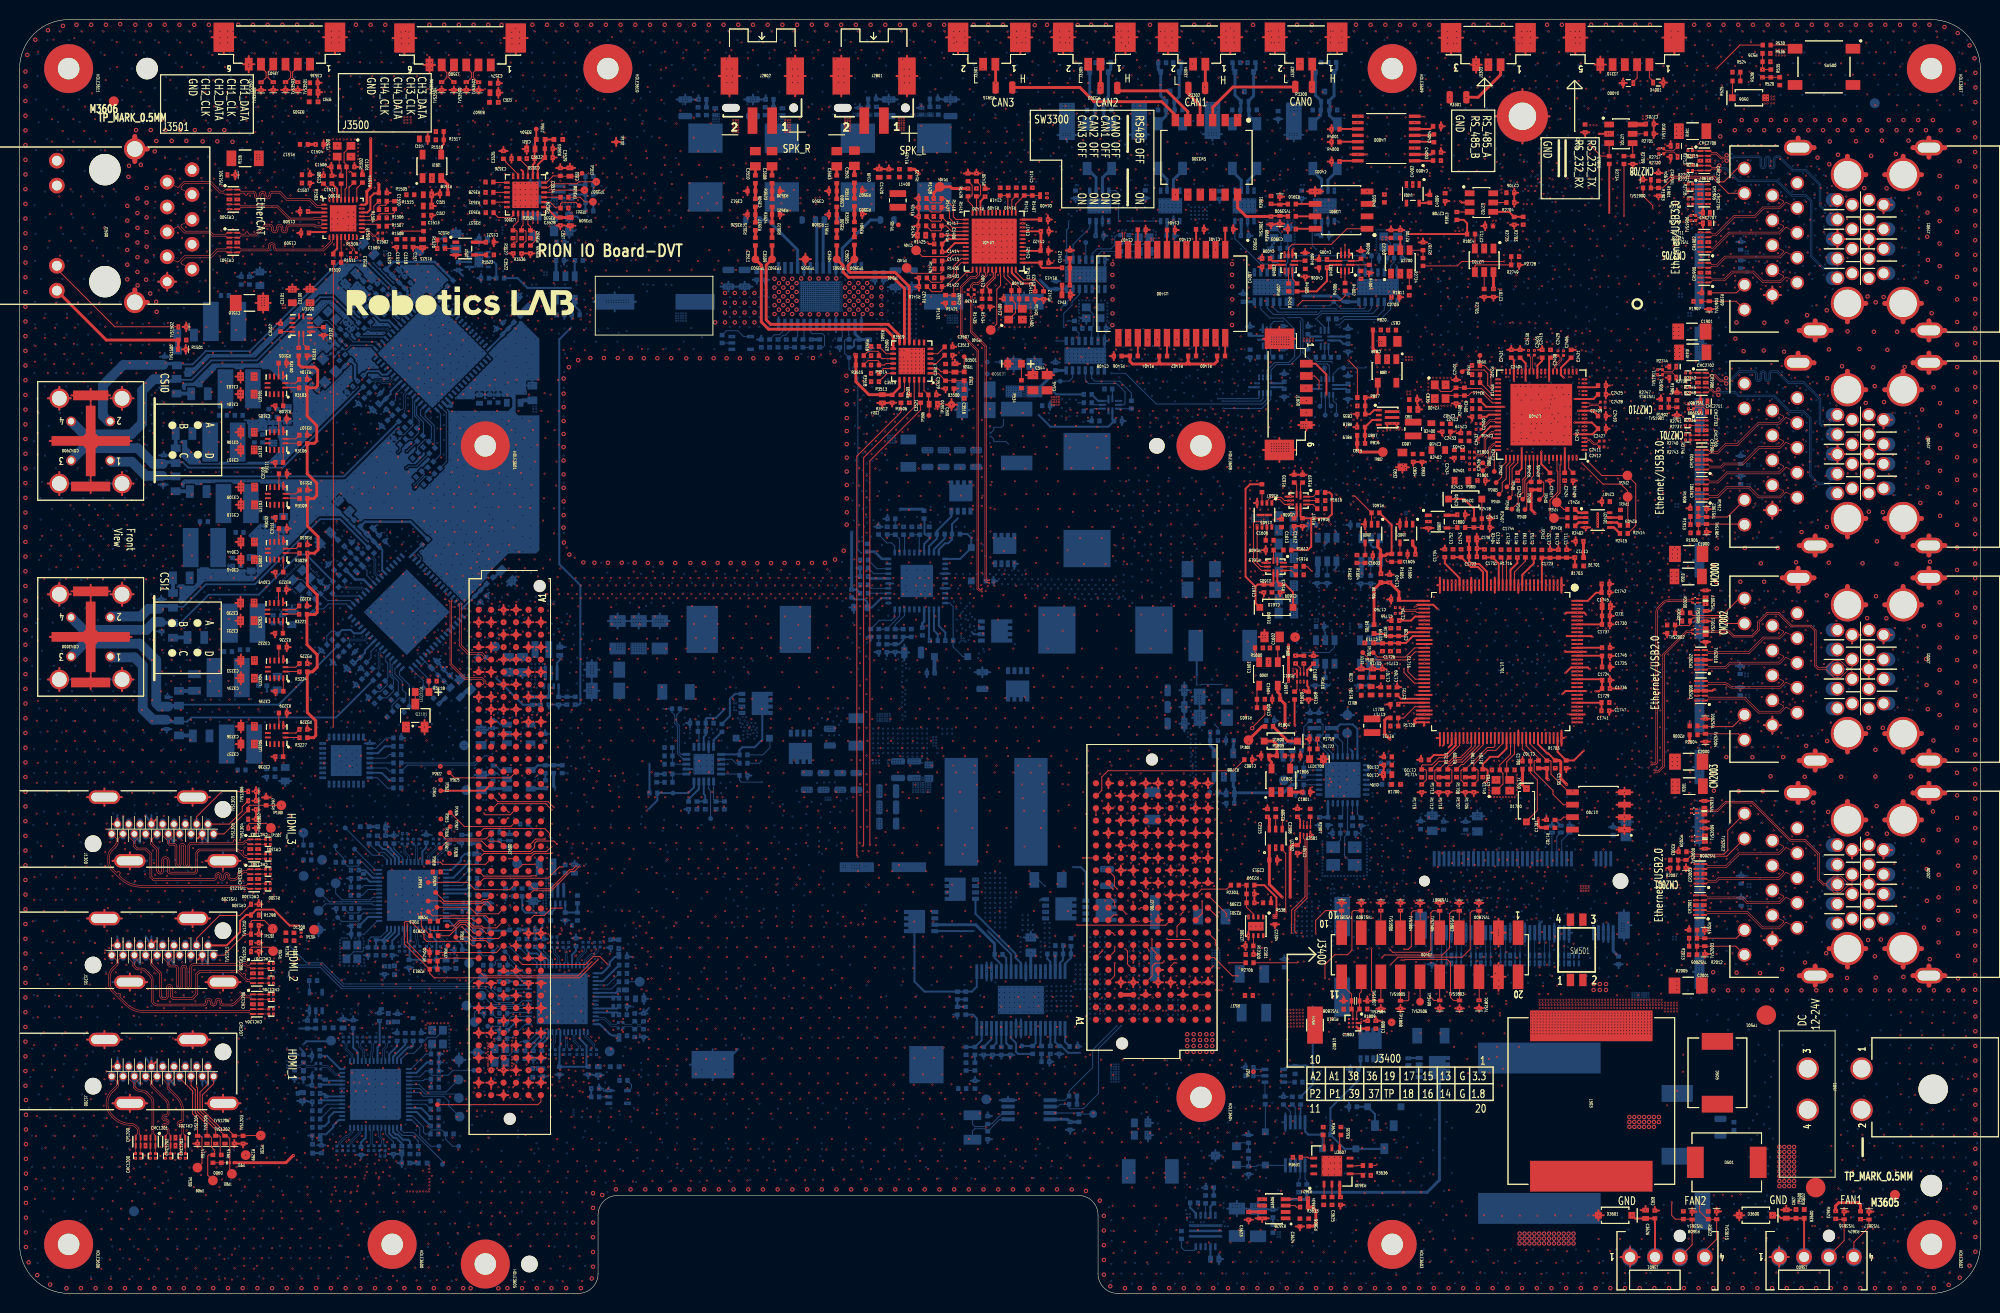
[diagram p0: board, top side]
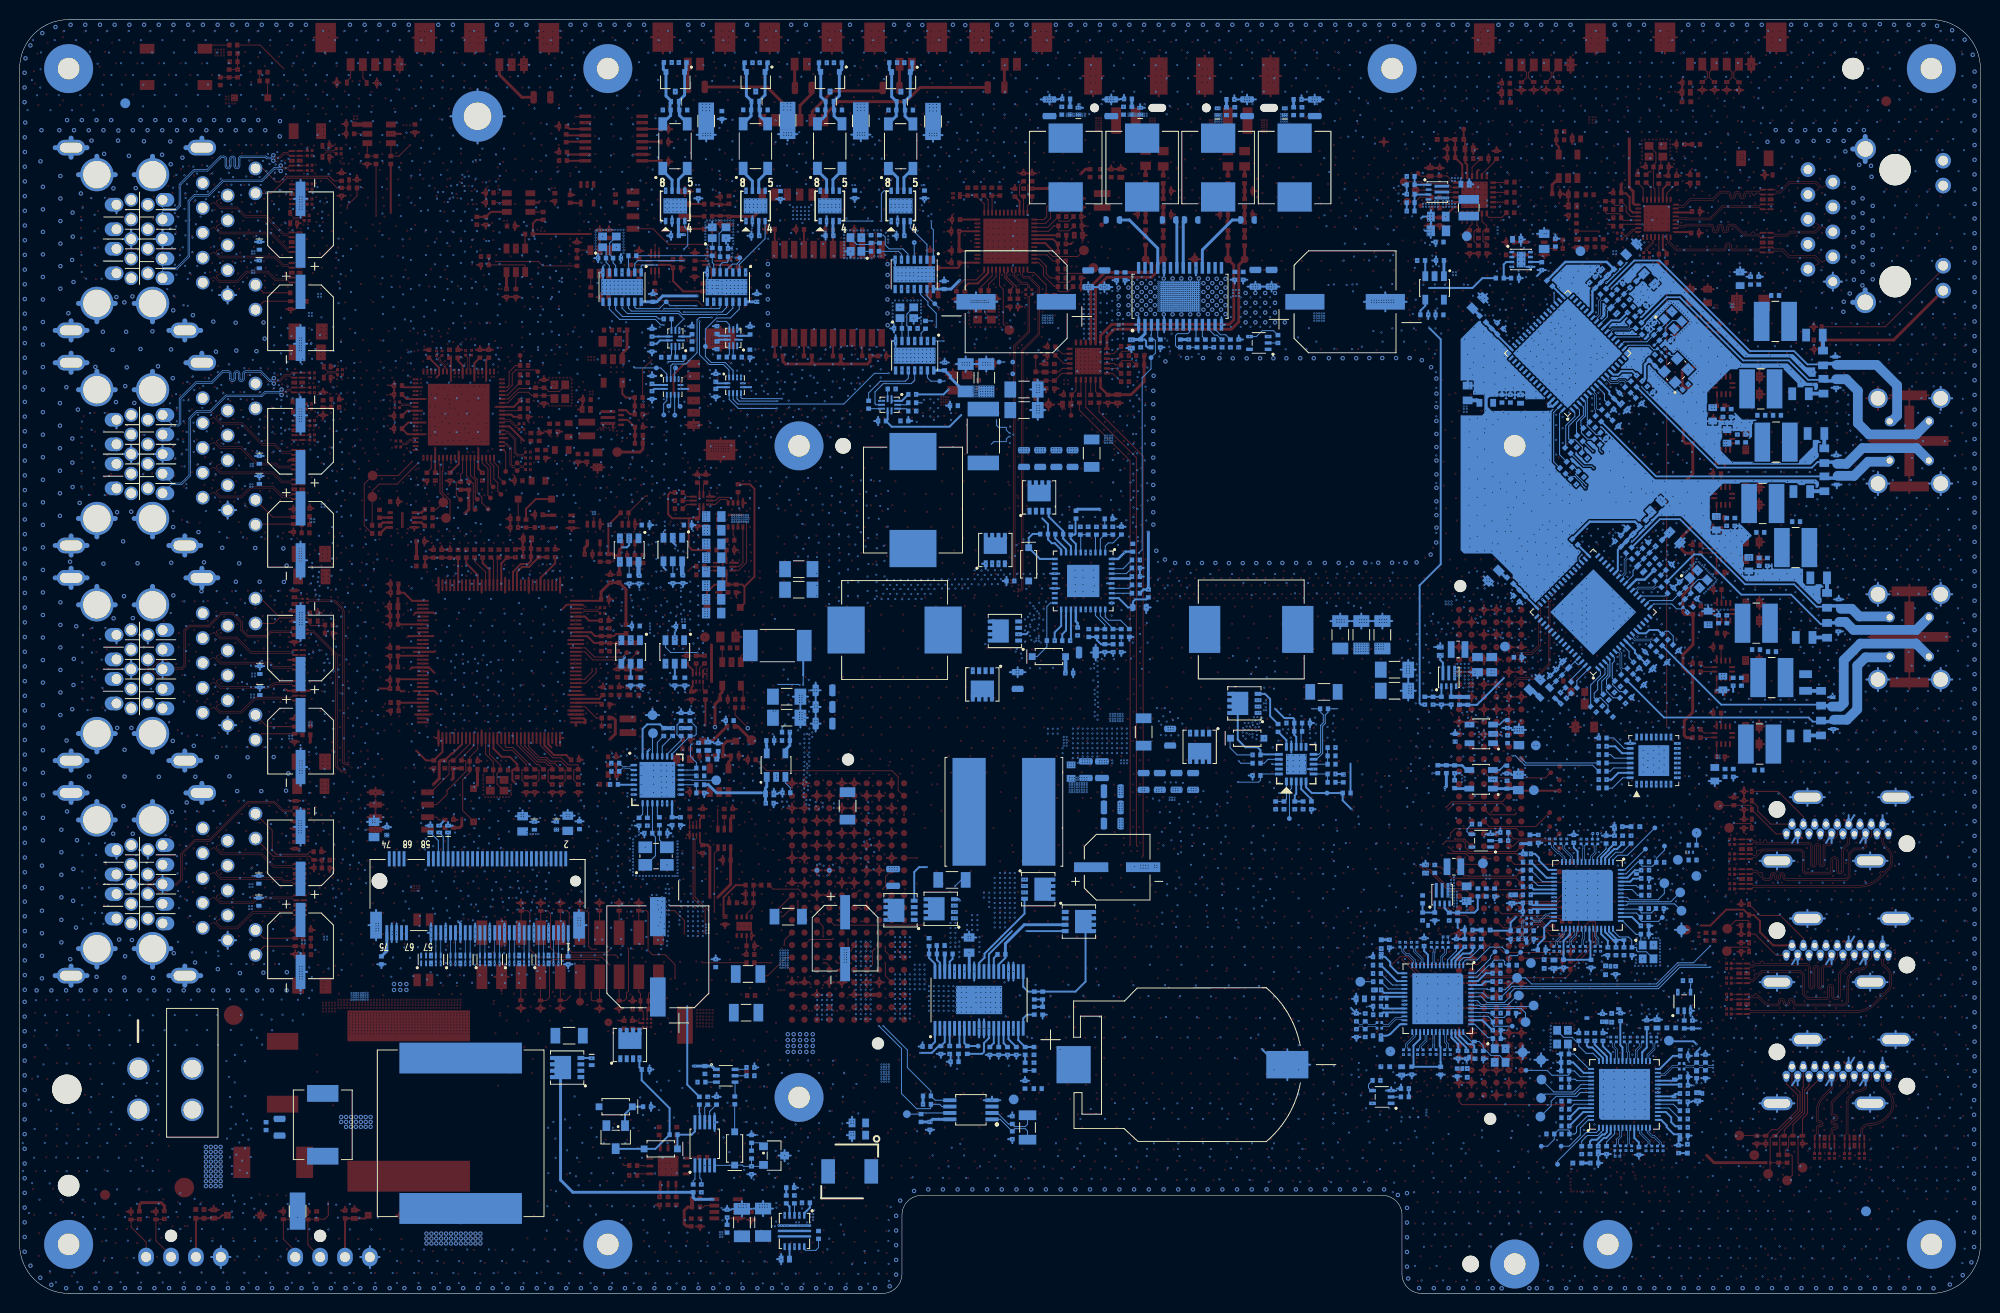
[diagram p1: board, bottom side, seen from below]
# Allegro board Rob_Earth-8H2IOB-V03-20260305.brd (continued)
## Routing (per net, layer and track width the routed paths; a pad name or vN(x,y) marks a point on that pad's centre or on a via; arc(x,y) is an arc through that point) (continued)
RTL_SPI_CZ: length 28.5
  TOP w0.1: v1(141.2,63.75) 141.2,63.35 142.27,62.28 U1701.54
  L3 w0.1: v1(141.2,63.75) 141.2,64.27 140.95,64.52 133.3,64.52 v2(133.2,64.62) ; v1(133.16,80.08) 134.19,80.08 v2(134.2,80.07)
  L6 w0.1: v2(134.2,80.07) 133.8,79.67 133.8,65.22 v2(133.2,64.62)
RTL_SPI_CZ_S: length 21.7
  TOP w0.1: v1(132.55,92.42) 132.55,93.17 132.08,93.63 J1600.2 ; U1606.5 v1(129.63,80.51) 129.04,80.51 128.52,81.03 127.91,81.03 127.73,80.84 U1603.1
  L3 w0.1: v1(129.63,80.51) 131.43,82.32 133.04,82.32 134.05,83.32 134.05,86.73 130.9,89.88 130.9,91.52 131.8,92.42 v1(132.55,92.42)
RTL_SPI_DI: length 22.8
  TOP w0.1: R1614.1 131.31,74.2 v1(131.8,73.72) ; U1701.53 142.37,62.68 141.6,63.45 v1(141.6,63.75)
  L3 w0.1: v1(131.8,73.72) 131.9,73.62 v2(133.2,73.62) ; v1(141.6,63.75) 141.6,64.35 141.19,64.76 133.7,64.76 v2(133.2,65.27)
  L6 w0.1: v2(133.2,73.62) 132.85,73.27 132.85,65.62 v2(133.2,65.27)
RTL_SPI_DI_S: length 23.4
  TOP w0.1: U1603.5 126.23,74.57 126.63,74.17 U1605.4
  L3 w0.1: v1(126.23,78.37) 126.52,78.67 128.15,78.67 128.4,78.92 128.4,79.87 128.75,80.22 129.79,80.22 131.64,82.07 133.14,82.07 134.3,83.22 134.3,86.83 v1(131.24,89.88)
RTL_SPI_DO: length 27.1
  TOP w0.1: R1618.1 v1(133.17,80.91)
  L3 w0.1: v1(133.17,80.91) 134,80.91 v2(134.2,80.72) ; v1(143.29,64.29) 142.56,65.02 134.05,65.02 v2(133.2,65.87)
  L6 w0.1: v2(133.2,65.87) 133.55,66.22 133.55,80.07 v2(134.2,80.72)
RTL_SPI_DO_S: length 18.6
  TOP w0.1: U1603.2 127.23,80.67 127.23,80.85 127.62,81.24 128.69,81.24 129.02,80.91 v1(129.63,80.91)
  L3 w0.1: v1(129.63,80.91) 131.28,82.57 132.94,82.57 133.8,83.43 133.8,86.63 130.65,89.78 130.65,91.8 v1(131.23,92.39)
RTL_XTAL1: length 6
  TOP w0.1: U1500.28 33.2,112.7 33.36,112.86 33.36,114.96 C1501.1 33.35,115.17 33.1,115.42 33.1,116.42 Y1500.1
RTL_XTAL2: length 1.7
  TOP w0.1: U1500.29 R1500.2
RTL_XTALI: length 4.7
  TOP w0.1: U1701.84 152.47,55.04 151.69,54.26 C1700.1 151.69,52.71 Y1700.3
RTL_XTALO: length 6.3
  TOP w0.1: Y1700.1 150.64,51.31 151.31,51.98 151.31,53.07 150.98,53.4 C1703.1 150.98,53.93 152.07,55.02 U1701.83
RTT1: length 2.9
  TOP w0.1: R1718.1 151.67,74.84 U1701.15
RTT2: length 2.9
  TOP w0.1: U1701.16 151.27,74.94 R1717.1
RXCAN0: length 10.4
  L6 w0.1: v3(132.25,105.4) v3(132.25,106.55)
  BOTTOM w0.1: U3400.4 132.15,108.8 131.85,108.5 131.85,106.95 v3(132.25,106.55) ; U3407.2 137.25,105.1 136.95,105.4 v3(132.25,105.4)
RXCAN1: length 6.3
  BOTTOM w0.1: U3409.2 126.6,105 123.96,107.64 U3402.4
RXCAN2: length 19.7
  L6 w0.1: v3(107.4,97.2) 106.95,97.65 106.95,98.75 106.6,99.1 106.6,101.75 107.05,102.2 107.05,103.51 110.75,107.21 110.75,108.6 111.95,109.8 112.65,109.8 v3(113,109.45)
  BOTTOM w0.1: v3(113,109.45) 113.01,109.44 116.39,109.44
RXCAN3: length 4.6
  BOTTOM w0.1: U3413.2 107.45,107.05 109.15,108.75 U3405.4
SAIL_CAN_0_M: length 2.6
  BOTTOM w0.3: U3400.6 132.8,113.68 131.9,114.58 CM3400.2
SAIL_CAN_0_P: length 2.7
  BOTTOM w0.3: U3400.7 133.45,113.63 134.4,114.58 CM3400.1
SAIL_CAN_1_M: length 2.7
  BOTTOM w0.3: U3402.6 124.61,113.62 123.7,114.52 CM3401.2
SAIL_CAN_1_P: length 2.7
  BOTTOM w0.3: CM3401.1 126.2,114.46 125.26,113.52 U3402.7
SAIL_IO_8_1P8: length 7.3
  TOP w0.1: TP2600.1 45.9,39.41 46.57,38.74 48.82,38.74 J2600.D25
SAIL_IO_9_1P8: length 6.6
  TOP w0.1: TP2601.1 44.27,37.51 44.83,38.07 45.69,38.07 46.27,37.49 47.14,37.49 47.28,37.35 47.28,37.35 47.33,37.3 48.65,37.3 J2600.D26
SGMII0_RX_M: length 100.9
  TOP w0.072: v1(47.03,67.23) 47.03,67.23 J2600.F3
  L3 w0.057: v1(140.32,69.99) 140.11,69.77 140.03,69.77 60.07,69.77 arc(59.85,69.68) 59.76,69.46 59.76,69.08 arc(59.62,68.94) 59.47,69.08 59.47,69.46 arc(59.16,69.77) 58.85,69.46 58.85,69.08 arc(58.71,68.94) 58.57,69.08 58.57,69.46 arc(58.26,69.77) 57.95,69.46 57.95,69.08 arc(57.81,68.94) 57.66,69.08 57.66,69.46 arc(57.35,69.77) 57.05,69.46 57.05,69.08 arc(56.9,68.94) 56.76,69.08 56.76,69.46 arc(56.67,69.68) 56.45,69.77 54.58,69.77 54.03,70.32 49.15,70.32 48.63,69.81 48.63,69.36 47.36,68.08 47.36,67.32 47.26,67.23 v1(47.03,67.23)
SGMII0_RX_P: length 100.9
  TOP w0.072: v1(47.9,67.23) 47.9,67.23 48.02,67.23 48.02,67.23 J2600.E3
  L3 w0.057: v1(47.9,67.23) 47.76,67.23 47.76,67.23 47.65,67.23 47.53,67.35 47.53,68.01 48.8,69.29 48.8,69.74 49.22,70.16 53.96,70.16 54.51,69.61 54.64,69.61 56.45,69.61 arc(56.55,69.57) 56.59,69.46 56.59,69.08 arc(56.9,68.77) 57.21,69.08 57.21,69.46 arc(57.35,69.61) 57.5,69.46 57.5,69.08 arc(57.81,68.77) 58.12,69.08 58.12,69.46 arc(58.26,69.61) 58.4,69.46 58.4,69.08 arc(58.71,68.77) 59.02,69.08 59.02,69.46 arc(59.16,69.61) 59.31,69.46 59.31,69.08 arc(59.62,68.77) 59.92,69.08 59.92,69.46 arc(59.97,69.57) 60.07,69.61 139.4,69.61 arc(139.48,69.57) 139.52,69.49 139.52,69.49 arc(139.63,69.38) 139.74,69.49 139.74,69.49 arc(139.78,69.57) 139.86,69.61 140.03,69.61 140.12,69.61 v1(140.32,69.41)
SGMII0_TX_M: length 100.8
  L3 w0.057: v1(143.27,68.28) 143.39,68.4 143.8,68.4 144.18,68.77 144.18,70.14 143.67,70.65 56.32,70.65 55.96,71.01 48.04,71.01 47.37,70.34 47.37,69.89 47.25,69.77 v1(47.02,69.77)
SGMII0_TX_P: length 100.8
  L3 w0.057: v1(143.27,68.68) 143.39,68.56 143.74,68.56 144.01,68.84 144.01,70.07 143.6,70.48 56.25,70.48 55.89,70.84 55.55,70.84 arc(55.47,70.81) 55.44,70.73 55.44,70.44 arc(55.32,70.33) 55.21,70.44 55.21,70.73 arc(55.18,70.81) 55.1,70.84 48.11,70.84 47.54,70.27 47.54,69.89 47.67,69.77 v1(47.9,69.77)
SGMII1_RX_M: length 99.5
  TOP w0.072: v1(43.82,70.7) 43.9,70.62 43.9,64.17 45.41,62.67 47.13,62.67 47.36,62.44 47.36,62.25 47.26,62.15 J2600.F7 ; v1(98.91,72.82) 98.9,72.82 98.9,72.8 98.84,72.74 98.7,72.74 98.63,72.82 98.63,96.69 97.14,98.18 97.14,101.7 97.14,101.7 97.14,101.7 C1400.1
  L3 w0.057: v1(98.91,72.82) 98.9,72.82 98.9,72.8 98.83,72.74 55.97,72.74 54.15,74.56 47.11,74.56 43.89,71.34 43.89,70.77 v1(43.82,70.7)
SGMII1_RX_P: length 99.5
  TOP w0.072: v1(98.9,72.5) 98.9,72.5 98.82,72.58 98.64,72.58 98.47,72.75 98.47,96.62 96.98,98.11 96.98,101.3 96.97,101.72 C1402.1 ; v1(44.13,70.71) 44.07,70.65 44.07,64.24 45.47,62.83 47.2,62.83 47.56,62.47 47.56,62.25 47.66,62.15 J2600.E7
  L3 w0.057: v1(44.13,70.71) 44.06,70.78 44.06,71.28 47.17,74.39 54.08,74.39 55.9,72.57 98.83,72.57 98.9,72.5 v1(98.9,72.5)
SGMII1_TX_M: length 98.5
  TOP w0.072: v1(98.17,71.93) 98.1,71.85 97.93,71.85 97.81,71.97 97.81,96.24 96.12,97.93 96.12,102.69 97.05,103.61 97.56,103.61 97.57,103.62 97.57,103.62 97.91,103.95 97.91,104.19 98.01,104.29 U1401.39 ; J2600.F5 47.2,64.69 47.35,64.83 47.35,64.96 47.1,65.21 45.74,65.21 44.85,66.09 44.85,70.28 v1(44.8,70.33)
  L3 w0.057: v1(98.17,71.93) 98.1,71.85 55.64,71.85 53.87,73.62 47.57,73.62 44.86,70.91 44.86,70.4 v1(44.8,70.33)
SGMII1_TX_P: length 98.5
  TOP w0.072: v1(45.1,70.33) 45.1,70.33 45.05,70.28 45.05,66.18 45.82,65.41 47.19,65.41 47.55,65.04 47.55,64.86 47.73,64.69 J2600.E5 ; U1401.38 97.61,104.25 97.71,104.15 97.71,103.99 97.49,103.78 96.98,103.78 95.96,102.75 95.96,97.86 97.65,96.17 97.65,71.9 97.87,71.69 98.11,71.69 98.17,71.63 v1(98.17,71.62)
  L3 w0.057: v1(45.1,70.33) 45.1,70.33 45.03,70.4 45.03,70.84 47.64,73.45 53.8,73.45 55.57,71.68 98.12,71.68 98.17,71.63 v1(98.17,71.62)
SHDNZ_ADC3: length 61.2
  TOP w0.1: v1(50.35,106.94) 50.35,107.21 50.43,107.29 50.65,107.29 50.74,107.38 50.74,108.4 50.64,108.49 50.36,108.49 ; U3500.14 88.4,95.9 v1(87.65,96.65) ; 50.36,108.49 R3527.1 ; 50.36,108.49 50.36,108.93 50.85,109.43 U3501.14
  L3 w0.1: v1(50.35,106.94) 52.39,106.94 53.9,108.45 v2(90.45,108.45) ; v1(87.65,96.65) v2(90.45,96.65)
  L6 w0.1: v2(90.45,96.65) v2(90.45,108.45)
SMCLK: length 4.9
  TOP w0.1: TP2410.1 155.46,81.45 155.46,82.72 155.36,82.82 R2406.2 155.02,83.56 154.81,83.77 U2400.66
SMDAT: length 5.8
  TOP w0.1: TP2409.1 153.73,80.18 153.73,82.65 153.91,82.82 R2405.2 154.18,83.19 154.41,83.42 U2400.65
SPI_CS: length 6.1
  TOP w0.1: R2417.2 157.49,80.01 TP2414.1 156.78,81.36 157.12,81.7 157.12,84.47 157.21,84.56 U2400.72
SPICLK: length 12.7
  TOP w0.1: U2400.70 v1(156.41,85.08) ; v1(159.4,84.7) 161.51,82.59 163.33,82.59 164.02,81.9 TP2411.1 164.04,81.27 R2414.2
  L3 w0.1: v1(156.41,85.08) 156.69,85.08 156.75,85.14 157.75,85.14 158.08,84.81 159.29,84.81 v1(159.4,84.7)
SPISI: length 16.4
  TOP w0.1: R2415.2 164.85,78.37 164.85,82.62 TP2412.1 161.39,83.47 v1(159.96,84.9) ; v1(156,84.75) 156.01,84.76 U2400.69
  L3 w0.1: v1(156,84.75) 156,84.76 156.09,84.85 156.09,85.19 156.33,85.43 157.83,85.43 158.21,85.05 159.81,85.05 v1(159.96,84.9)
SPISO: length 8.1
  TOP w0.1: U2400.71 156.81,83.95 156.9,83.87 156.9,81.77 156.1,80.97 156.1,79.53 TP2413.1 157.84,79.13 R2416.2
SPK_L_N:
  vias: v1(84.2,119.9) v1(84.2,119.65) v1(84.2,119.4) v1(84.2,119.15) v1(84.2,118.9) v1(84.2,118.65) v1(84.45,119.9) v1(84.45,119.65) v1(84.45,119.4) v1(84.45,119.15) v1(84.45,118.9) v1(84.45,118.65) v1(84.7,119.9) v1(84.7,119.65) v1(84.7,119.4) v1(84.7,119.15) v1(84.7,118.9) v1(84.7,118.65) v2(85.05,119.75) v2(85.05,119.3) v2(85.5,119.75) v2(85.5,119.3) v2(85.95,119.75) v2(85.95,119.3) v3(85.05,120.4) v3(85.05,120.15) v3(85.3,120.4) v3(85.3,120.15) v3(85.55,120.4) v3(85.55,120.15) v3(85.8,120.4) v3(85.8,120.15) v3(86.15,120.4) v3(86.15,120.15) v3(86.4,120.4) v3(86.4,120.15) v3(86.65,120.4) v3(86.65,120.15) v3(86.9,120.4) v3(86.9,120.15)
SPK_L_P:
  vias: v1(89.7,119.95) v1(89.7,119.7) v1(89.7,119.45) v1(89.7,119.2) v1(89.7,118.95) v1(89.7,118.7) v1(89.95,119.95) v1(89.95,119.7) v1(89.95,119.45) v1(89.95,119.2) v1(89.95,118.95) v1(89.95,118.7) v1(90.2,119.95) v1(90.2,119.7) v1(90.2,119.45) v1(90.2,119.2) v1(90.2,118.95) v1(90.2,118.7) v2(91.43,119.83) v2(91.43,119.36) v2(91.88,119.81) v2(91.88,119.35) v2(92.32,119.81) v2(92.31,119.36) v3(91.35,120.4) v3(91.35,120.15) v3(91.6,120.4) v3(91.6,120.15) v3(91.85,120.4) v3(91.85,120.15) v3(92.1,120.4) v3(92.1,120.15) v3(92.45,120.4) v3(92.45,120.15) v3(92.7,120.4) v3(92.7,120.15) v3(92.95,120.4) v3(92.95,120.15) v3(93.2,120.4) v3(93.2,120.15)
SPK_R_N:
  vias: v1(72.8,119.75) v1(72.8,119.5) v1(72.8,119.25) v1(72.8,119) v1(72.8,118.75) v1(72.8,118.5) v1(73.05,119.75) v1(73.05,119.5) v1(73.05,119.25) v1(73.05,119) v1(73.05,118.75) v1(73.05,118.5) v1(73.3,119.75) v1(73.3,119.5) v1(73.3,119.25) v1(73.3,119) v1(73.3,118.75) v1(73.3,118.5) v2(71.9,119.6) v2(71.9,119.15) v2(71.9,118.7) v2(72.35,119.6) v2(72.35,119.15) v2(72.35,118.7) v3(70.7,120.35) v3(70.7,120.1) v3(70.7,119.85) v3(70.7,119.6) v3(70.9,120.35) v3(70.9,120.1) v3(70.9,119.85) v3(70.9,119.6) v3(71.1,120.35) v3(71.1,120.1) v3(71.1,119.85) v3(71.1,119.6) v3(71.35,120.35) v3(71.35,120.1) v3(71.35,119.85) v3(71.35,119.6)
SPK_R_P:
  vias: v1(78.1,119.75) v1(78.1,119.5) v1(78.1,119.25) v1(78.1,119) v1(78.1,118.75) v1(78.1,118.5) v1(78.35,119.75) v1(78.35,119.5) v1(78.35,119.25) v1(78.35,119) v1(78.35,118.75) v1(78.35,118.5) v1(78.6,119.75) v1(78.6,119.5) v1(78.6,119.25) v1(78.6,119) v1(78.6,118.75) v1(78.6,118.5) v2(76.85,119.1) v2(76.85,118.65) v2(77.3,119.1) v2(77.3,118.65) v2(77.75,119.1) v2(77.75,118.65) v3(77.4,120.35) v3(77.4,120.1) v3(77.4,119.85) v3(77.4,119.6) v3(77.65,120.35) v3(77.65,120.1) v3(77.65,119.85) v3(77.65,119.6) v3(77.85,120.35) v3(77.85,120.1) v3(77.85,119.85) v3(77.85,119.6) v3(78.05,120.35) v3(78.05,120.1) v3(78.05,119.85) v3(78.05,119.6)
SSREXT: length 1.9
  TOP w0.1: U2400.47 149.17,90.08 R2408.1
SSRX0+: length 4.3
  TOP w0.072: R1801.2 148.59,85.47 149.25,85.47 149.55,85.77 149.55,87.15 150.2,87.8 150.36,87.8 150.48,87.68 U2400.53
SSRX0-: length 4.4
  TOP w0.072: R1800.2 148.62,85.63 149.18,85.63 149.38,85.83 149.38,87.22 150.13,87.96 150.34,87.96 150.46,88.08 U2400.52
SSTX0+: length 2.2
  TOP w0.072: C2403.1 149.25,88.4 149.42,88.4 150.02,89 150.49,89 150.6,88.88 U2400.50
SSTX0-: length 2.2
  TOP w0.072: C2400.1 149.24,88.56 149.35,88.56 149.95,89.16 150.46,89.16 150.57,89.28 U2400.49
SSTX1+: length 1.8
  TOP w0.072: C2412.1 160.91,86.61 160.53,86.61 160.12,87.03 159.95,87.03 159.8,86.88 U2400.3
SSTX1-: length 1.8
  TOP w0.072: C2411.1 161.13,86.98 160.93,86.78 160.6,86.78 160.19,87.19 159.95,87.19 159.86,87.28 U2400.4
SSTX2+: length 1.8
  TOP w0.072: C2410.1 161.03,90.6 160.17,90.6 160.05,90.48 U2400.12
SSTX2-: length 1.8
  TOP w0.072: C2409.1 161.03,90.76 160.17,90.76 160.05,90.88 U2400.13
SSTX3+: length 2
  TOP w0.072: C2408.1 157.29,95.52 157.29,95.2 156.69,94.61 156.69,94.43 156.81,94.31 U2400.25
SSTX3-: length 2
  TOP w0.072: U2400.26 156.41,94.29 156.53,94.41 156.53,94.54 156.53,94.67 157.12,95.27 157.12,95.51 C2406.1
SSTX4+: length 1.8
  TOP w0.072: U2400.31 154.41,94.29 154.29,94.41 154.29,95.54 C2404.1
SSTX4-: length 1.8
  TOP w0.072: U2400.32 154.01,94.3 154.13,94.42 154.13,95.53 C2405.1
SSXI: length 6.1
  TOP w0.1: U2400.45 150.22,90.88 149.13,91.97 148.1,91.97 147.77,91.64 147.37,91.64 R2400.2 146.52,91.63 C2402.1 145.75,91.63 Y2400.3
SSXO: length 7.4
  TOP w0.1: U2400.44 150.17,91.28 149.11,92.34 147.46,92.34 R2400.1 146.52,92.43 C2401.1 146.41,92.43 146.03,92.05 144.97,92.05 144.35,92.67 Y2400.1
SW1: length 1.8
  BOTTOM w0.3: U700.36 C707.1
SW2: length 10
  BOTTOM w0.2: U700.25 100.13,33.57 99.45,34.25 C708.1
  BOTTOM w0.3: C708.1 99.45,35.7 97.53,37.62 Q702.3
TESTEN: length 1.7
  TOP w0.1: R2409.1 158.01,84.19 U2400.74
TXCAN0: length 7.4
  L6 w0.1: v3(135,104.95) 134.6,105.35 v3(134.6,109.3)
  BOTTOM w0.1: U3407.1 136.6,104.85 136.5,104.95 v3(135,104.95) ; U3400.1 134.46,109.44 v3(134.6,109.3)
TXCAN1: length 5.3
  L6 w0.1: v3(125.95,104.2) 125.91,104.24 v3(125.91,109.43)
TXCAN2: length 25.4
  L6 w0.1: v3(105.75,97.2) 105.75,101.5 106.55,102.3 106.55,103.7 108,105.15 v8(108,110.1)
  L7 w0.1: v8(108,110.1) 117.68,110.1 v7(118.34,109.44)
  BOTTOM w0.1: U3411.1 v3(105.75,97.2)
TXCAN3: length 8.3
  L7 w0.1: v7(111.1,109.43) 110.83,109.7 107.27,109.7 v7(107,109.43)
  BOTTOM w0.1: U3413.1 106.8,108.55 107,108.75 v7(107,109.43)
USB1_HS_D_M: length 65.2
  TOP w0.072: v1(112.32,52.22) 112.32,52.21 J2700.C20
  L3 w0.057: v1(147.91,84.07) 147.91,84.23 147.85,84.28 147.43,84.28 147.16,84.55 143.07,84.55 133.63,75.11 112.19,75.11 112.03,75.28 112.03,75.46 v2(111.86,75.62) ; v2(111.88,53.8) 112.05,53.64 112.05,53.34 112.86,52.53 112.86,52.3 112.79,52.22 v1(112.32,52.22)
  L6 w0.057: v2(111.86,75.62) 112.06,75.42 112.06,53.98 v2(111.88,53.8)
USB1_HS_D_P: length 65.2
  TOP w0.072: v1(113.6,52.21) 113.59,52.21 J2700.D20
  L3 w0.057: v1(147.91,84.67) 147.91,84.51 147.85,84.45 147.5,84.45 147.23,84.72 143,84.72 133.56,75.28 112.26,75.28 112.19,75.34 112.19,75.46 v2(112.36,75.62) ; v1(113.6,52.21) 113.11,52.21 113.03,52.3 113.03,52.6 112.22,53.41 112.22,53.64 v2(112.38,53.8)
  L6 w0.057: v2(112.38,53.8) 112.23,53.96 112.23,74.62 arc(112.27,74.72) 112.36,74.76 arc(112.46,74.8) 112.5,74.9 112.5,74.91 arc(112.46,75.01) 112.36,75.04 arc(112.27,75.08) 112.23,75.18 112.23,75.49 v2(112.36,75.62)
USB1_SS_RX_M: length 71.1
  L3 w0.057: v1(113.59,46.98) 113.37,46.98 v2(113.22,47.13) ; v1(148.56,88.76) 148.35,88.56 144.26,88.56 132.63,76.92 123.92,76.92 123.92,76.93 123.51,76.93 123.5,76.92 114.26,76.92 114.23,76.96 114.23,77.1 v2(114.39,77.26)
  L6 w0.057: v2(114.39,77.26) 114.22,77.1 114.22,76.81 arc(114.26,76.73) 114.35,76.69 arc(114.43,76.65) 114.47,76.56 114.47,76.53 arc(114.43,76.44) 114.35,76.4 arc(114.28,76.39) 114.22,76.34 114.22,76.18 114.19,76.15 114.19,49.09 113.04,47.94 113.04,47.39 113.04,47.31 v2(113.22,47.13)
USB1_SS_RX_P: length 71.1
  TOP w0.072: C2403.2 v1(148.56,88.19)
  L3 w0.057: v1(112.32,46.98) 112.54,46.98 v2(112.68,47.13) ; v1(148.56,88.19) 148.35,88.39 144.33,88.39 132.7,76.76 123.85,76.76 123.85,76.76 123.58,76.76 123.57,76.76 114.2,76.76 114.06,76.89 114.06,77.09 v2(113.89,77.26)
  L6 w0.057: v2(112.68,47.13) 112.87,47.31 112.87,47.46 112.87,48.01 114.02,49.16 114.02,76.22 114.05,76.25 114.05,77.1 v2(113.89,77.26)
USB1_SS_TX_M: length 67.4
  L3 w0.057: v1(113.59,49.52) v2(113.24,49.52) ; v1(147.91,85.87) 147.91,85.71 147.85,85.65 142.66,85.65 133.1,76.08 113.28,76.08 113.16,76.2 113.16,76.41 v2(113.36,76.6)
  L6 w0.057: v2(113.36,76.6) 113.15,76.4 113.15,76.18 arc(113.19,76.08) 113.29,76.04 arc(113.38,76.01) 113.42,75.91 113.42,75.89 arc(113.38,75.8) 113.29,75.76 arc(113.19,75.72) 113.15,75.62 113.15,49.91 113.04,49.8 113.04,49.72 v2(113.24,49.52)
USB1_SS_TX_P: length 67.4
  L3 w0.057: v1(147.91,85.27) 147.91,85.43 147.85,85.48 142.73,85.48 133.17,75.91 113.19,75.91 112.99,76.11 112.99,76.4 v2(112.78,76.61) ; v1(112.32,49.52) v2(112.67,49.52)
  L6 w0.057: v2(112.78,76.61) 112.98,76.41 112.98,49.98 112.87,49.87 112.87,49.72 v2(112.67,49.52)
USB2_EN: length 48.6
  L3 w0.2: v2(121.43,56.75) 128.93,56.75 129.26,57.08 133.19,57.08 133.23,57.12 v2(133.77,57.12)
  L6 w0.2: v2(133.77,57.12) 134.05,57.39 v3(134.05,64.22) v3(134.05,73.82) ; v3(138.3,65) 138.3,73.96 138.74,74.41 v3(138.74,74.67) ; v2(121.43,56.75) v3(121.43,57.37)
  L7 w0.2: v3(138.3,65) 137.56,64.26 134.09,64.26 v3(134.05,64.22)
  BOTTOM w0.2: v3(138.3,65) 138.3,64.85 138.62,64.53 U2504.4 ; U2502.4 134.32,74.09 v3(134.05,73.82)
  BOTTOM w0.3: U2500.4 121.89,55.46 121.44,55.91 121.44,56.42 R2501.1 121.44,56.43 121.44,57.27 R2500.2
USB2_HUB2_DM1: length 52
  TOP w0.072: v1(166.45,53.9) 166.52,53.97 166.88,53.97 167.05,54.14 167.05,69.5 arc(167.1,69.74) 167.24,69.95 167.73,70.44 arc(167.93,70.57) 168.16,70.62 170.52,70.62 CM2000.4
  L3 w0.057: v1(166.45,53.9) 166.38,53.97 138.21,53.97 v2(138.04,53.8)
  L6 w0.057: v3(137.35,52.92) 137.35,52.81 137.29,52.75 137.06,52.75 137,52.82 137,53.25 arc(137.03,53.33) 137.11,53.37 137.23,53.37 arc(137.35,53.48) 137.23,53.59 137.11,53.59 arc(137.03,53.63) 137,53.71 137,53.87 137.1,53.97 137.88,53.97 v2(138.04,53.8)
USB2_HUB2_DM2: length 48.4
  TOP w0.072: v1(166.75,53.14) 166.82,53.21 167.22,53.21 167.76,53.75 167.76,65.16 170.07,67.46 170.52,67.46 CM2002.4
  L3 w0.057: v2(138.3,51.55) 138.46,51.72 138.85,51.72 140.34,53.2 166.68,53.2 v1(166.75,53.14)
  L6 w0.057: v3(137.4,51.42) 137.4,51.31 137.34,51.25 137.11,51.25 137.05,51.32 137.05,51.62 137.15,51.72 137.52,51.72 arc(137.6,51.68) 137.63,51.6 137.63,51.48 arc(137.74,51.36) 137.86,51.48 137.86,51.6 arc(137.89,51.68) 137.97,51.72 138.13,51.72 v2(138.3,51.55)
USB2_HUB2_DM3: length 39.4
  L3 w0.057: v1(170.6,46.22) 170.48,46.33 170.23,46.33 169.97,46.59 169.97,47.46 167.62,49.82 135.18,49.82 arc(135.11,49.79) 135.08,49.72 arc(135.05,49.65) 134.98,49.62 134.95,49.62 arc(134.88,49.65) 134.85,49.72 arc(134.82,49.79) 134.75,49.82 134.38,49.82 134.28,49.72 134.28,49.65 v2(134.45,49.48)
  L6 w0.057: v2(134.45,49.48) v3(134.45,50.02)
USB2_HUB2_DM4: length 38.6
  L3 w0.057: v2(133.39,50.91) 133.55,51.08 137.23,51.08 137.85,50.47 167.94,50.47 169.26,49.14 170.41,49.14 v1(170.52,49.02)
  L6 w0.057: v3(132.8,50.91) v2(133.39,50.91)
USB2_HUB2_DP1: length 52
  TOP w0.072: CM2000.3 170.54,70.78 168.16,70.78 arc(167.87,70.72) 167.62,70.55 167.13,70.06 arc(166.95,69.8) 166.89,69.5 166.89,54.21 166.81,54.13 166.52,54.13 v1(166.45,54.2)
  L3 w0.057: v1(166.45,54.2) 166.38,54.13 138.21,54.13 v2(138.04,54.3)
  L6 w0.057: v2(138.04,54.3) 137.88,54.13 137.03,54.13 136.83,53.94 136.83,52.75 136.99,52.58 137.29,52.58 137.35,52.53 v3(137.35,52.42)
USB2_HUB2_DP2: length 48.4
  TOP w0.072: v1(166.75,53.44) 166.82,53.37 167.16,53.37 167.6,53.81 167.6,65.22 170,67.62 170.53,67.62 170.65,67.74
  L3 w0.057: v2(138.3,52.05) 138.46,51.88 138.78,51.88 140.27,53.37 166.68,53.37 v1(166.75,53.44)
  L6 w0.057: v2(138.3,52.05) 138.13,51.88 137.08,51.88 136.88,51.69 136.88,51.25 137.04,51.08 137.34,51.08 137.4,51.03 v3(137.4,50.92)
USB2_HUB2_DP3: length 39.5
  L3 w0.057: v1(170.6,46.62) 170.48,46.5 170.3,46.5 170.14,46.66 170.14,47.53 167.69,49.98 134.31,49.98 134.11,49.79 134.11,49.65 v2(133.95,49.48)
  L6 w0.057: v2(133.95,49.48) v3(133.95,50.02)
USB2_HUB2_DP4: length 38.6
  L3 w0.057: v1(170.52,49.42) 170.41,49.31 169.33,49.31 168.01,50.63 137.92,50.63 137.3,51.25 133.55,51.25 v2(133.39,51.41)
  L6 w0.057: v3(132.8,51.41) v2(133.39,51.41)
USB2_HUB_DM1: length 43.6
  L3 w0.057: v1(113.59,44.44) 113.15,44.44 113.04,44.33 113.04,43.88 113.28,43.64 arc(113.36,43.61) 113.44,43.64 113.45,43.65 arc(113.61,43.65) 113.61,43.49 113.6,43.48 arc(113.57,43.4) 113.6,43.32 115.74,41.18 138.5,41.18 138.66,41.02 138.66,40.8 v2(138.83,40.64)
  L6 w0.057: v2(138.83,40.64) 138.66,40.8 138.66,41.04 140.75,43.13 140.75,53.43 140.39,53.79 139.84,53.79 v3(139.65,53.98)
USB2_HUB_DM4: length 2.2
  L3 w0.057: v1(118.67,41.9) v2(118.35,41.9)
  L6 w0.057: v3(118.67,43.17) 118.18,43.17 118.12,43.12 118.12,42.13 v2(118.35,41.9)
USB2_HUB_DP1: length 43.6
  L3 w0.057: v1(112.32,44.44) 112.76,44.44 112.87,44.33 112.87,43.81 115.67,41.01 138.43,41.01 138.49,40.95 138.49,40.8 v2(138.33,40.64)
  L6 w0.057: v2(138.33,40.64) 138.49,40.8 138.49,41.11 140.58,43.2 140.58,52.27 arc(140.54,52.36) 140.46,52.39 140.32,52.39 arc(140.2,52.5) 140.32,52.62 140.46,52.62 arc(140.54,52.65) 140.58,52.73 140.58,53.37 140.32,53.62 139.83,53.62 v3(139.64,53.43)
USB2_HUB_DP4: length 2.2
  L3 w0.057: v1(117.4,41.9) v2(117.73,41.9)
  L6 w0.057: v2(117.73,41.9) 117.96,42.13 117.96,43.12 117.9,43.17 v3(117.4,43.17)
USB2_HUB_PGANG: length 4.8
  BOTTOM w0.1: U2503.23 133.95,55.03 132.52,56.46 132.52,56.88 R2517.2 132.81,56.89 132.95,57.03 132.95,58.02 R2519.1
USB2_HUB_PSELF: length 5.2
  BOTTOM w0.1: R2518.1 130.99,57.81 130.99,57.05 131.16,56.89 R2516.2 133.45,55.05 U2503.22
USB2_HUB_RESET: length 2.4
  BOTTOM w0.1: C2522.1 130.97,51.07 R2511.2 130.98,51.91 U2503.17
USB2_HUB_SCL: length 3.6
  BOTTOM w0.1: TP2502.1 131.38,52.37 131.42,52.41 U2503.18
USB2_HUB_SDA: length 2.4
  BOTTOM w0.1: TP2501.1 135.45,57.11 U2503.26
USB2_HUB_V5: length 27.6
  L3 w0.3: v2(135.57,55.19) 135.12,55.64 v2(123.89,55.64)
  L6 w0.3: v3(135.75,55.52) 135.75,55.37 v2(135.57,55.19) ; v3(123.89,50.03) v2(123.89,55.64)
  BOTTOM w0.2: U2503.27 135.95,55.31 v3(135.75,55.52)
  BOTTOM w0.3: v3(123.89,50.03) 123.92,50.06 C2501.2 123.92,51.58 123.79,51.71 U2500.1 ; 124.32,51.09 128.92,51.09 129.74,51.92 R2511.1
USB2_OVCUR1#: length 27.2
  L6 w0.1: v8(138.51,56.93) 138.55,56.97 138.55,73.86 139.12,74.43 139.12,76.72 v3(138.78,77.06)
  L7 w0.1: v7(134.3,56.89) 134.31,56.91 138.55,56.91 138.55,56.93 v8(138.51,56.93)
  BOTTOM w0.1: U2503.25 134.95,56.23 R2515.2 v7(134.3,56.89)
USB2_OVCUR2#: length 25.2
  L6 w0.1: v3(134.15,77.92) 134.3,77.77 134.3,57.05 arc(134.29,57) 134.26,56.96 134.21,56.92 arc(134.01,56.78) 133.77,56.73 133.56,56.73 v3(133.53,56.77)
  BOTTOM w0.1: U2502.3 134.32,77.74 v3(134.15,77.92) ; 133.52,56.77 134.45,55.84 U2503.24 ; 133.52,56.77 R2514.2 ; 133.52,56.77 v3(133.53,56.77)
USB2_OVCUR3#: length 22.5
  L6 w0.1: v8(138.76,56.41) 138.76,66.6 v3(138.81,66.65)
  L7 w0.1: v8(138.76,56.41) 138.46,56.11 v7(131.37,56.11)
  BOTTOM w0.1: v7(131.37,56.11) 131.58,55.9 131.58,54.8 130.97,54.19 R2513.2 131.18,53.41 U2503.20 ; U2504.3 138.77,66.67 138.78,66.65 v3(138.81,66.65)
USB2_OVCUR4#: length 18.5
  L6 w0.1: v3(130.85,65.4) 130.85,65.32 130.77,65.24 130.77,52.9 v3(130.86,52.81)
  BOTTOM w0.1: U2503.19 131.07,52.91 R2512.2 ; U2505.3 134.12,65.94 133.59,65.4 130.85,65.4 v3(130.85,65.4)
USB2_PWR_EN_1P8: length 106.9
  TOP w0.1: v1(52.4,19.77) 52.06,20.1 J2600.B40
  L3 w0.1: v1(52.4,19.77) 61.5,19.77 61.9,19.37 105.9,19.37 106.4,18.87 v2(114.25,18.87)
  L6 w0.1: v3(121.9,58.07) 121.9,56.97 122.75,56.12 122.75,39.65 115.85,32.75 115.85,26.57 114.25,24.97 v2(114.25,18.87)
  BOTTOM w0.1: R2500.1 122.23,57.73 v3(121.9,58.07)
USB2_VBUS1: length 31.4
  L3 w0.3: v2(170.4,57.67) v2(170.4,57.22) 166.76,57.22 165.96,56.42 158.7,56.42 157.75,55.47 146.86,55.47 146.28,56.05 141.81,56.05 v2(141.7,56.17) v2(141.2,56.17)
  BOTTOM w0.1: 190.88,60.19 190.86,60.2 J2001.U1
  vias: v2(176.65,63.22) v2(176.65,62.72) v3(139.7,78.57) v3(139.7,78.32) v3(139.95,78.57) v3(139.95,78.32) v3(170.2,58.27) v3(170.2,57.97) v3(170.5,58.27) v3(170.5,57.97) v3(176,63.27) v3(176,62.97) v3(176.3,63.27) v3(176.3,62.97)
USB2_VBUS2: length 30.3
  L3 w0.3: v2(142.5,55.47) v2(143,55.47) 146.15,55.47 146.6,55.02 158.05,55.02 158.95,55.92 166.56,55.92 167.41,56.77 v2(171.45,56.77) v2(171.9,56.77)
  vias: v3(141.3,79.77) v3(141.3,79.52) v3(141.55,79.77) v3(141.55,79.52) v3(172.2,56.92) v3(172.2,56.62) v3(172.5,56.92) v3(172.5,56.62) v3(176.1,61.12) v3(176.1,60.82) v3(176.4,61.12) v3(176.4,60.82)
USB2_VBUS3: length 73.6
  L5 w0.3: v2(169.05,35.82) v2(168.55,35.82) 167.53,35.82 162.18,30.47 140,30.47 v2(137.65,32.82) v2(137.15,32.82)
  L6 w0.3: v2(137.65,32.82) v2(137.15,32.82) 137.15,40.77 138.6,42.22 138.6,48.12 136.2,50.52 136.2,55.67 135.7,56.17 v3(135.7,67.42) v3(135.7,67.77) v3(135.7,68.07) v3(135.7,68.37)
  BOTTOM w0.1: 190.79,38.23 190.76,38.26 J2000.U1
  vias: v2(177,41.82) v2(177,41.32) v3(168.65,36.42) v3(168.65,36.12) v3(168.95,36.42) v3(168.95,36.12) v3(176.25,41.77) v3(176.25,41.47) v3(176.55,41.77) v3(176.55,41.47)
USB2_VBUS4: length 79.2
  L5 w0.3: v2(171.5,35.37) v2(171,35.37) 167.85,35.37 162.45,29.97 137.7,29.97 v2(135.65,32.02) v2(135.15,32.02)
  L6 w0.3: v2(135.65,32.02) v2(135.15,32.02) 134.25,32.02 132.4,33.87 132.4,34.97 132.1,35.27 132.1,51.92 132.95,52.77 132.95,57.87 132.3,58.52 132.3,68.17 132.45,68.32 v3(132.45,68.57) v3(132.45,68.82)
  vias: v3(132.15,68.82) v3(132.15,68.57) v3(170.9,36.02) v3(170.9,35.72) v3(171.2,36.02) v3(171.2,35.72) v3(176.3,39.52) v3(176.3,39.22) v3(176.6,39.52) v3(176.6,39.22)
USB3_HUB_EN_1P8: length 91.7
  TOP w0.1: R817.1 136.45,94.31 v1(135.55,95.22) ; v1(111.7,33.72) 111.7,32.43 J2700.B4
  L3 w0.1: v2(121.15,32.32) 120.9,32.32 120.45,32.77 117.88,32.77 117.23,33.42 116.1,33.42 115.55,33.97 111.95,33.97 v1(111.7,33.72) ; v1(135.55,95.22) 129.45,95.22 v2(128.7,95.97)
  L6 w0.1: v2(121.15,32.32) 122.82,32.32 123.5,33 123.5,55.77 124.9,57.17 124.9,74.72 128.75,78.57 128.75,95.07 128.85,95.17 128.85,95.82 v2(128.7,95.97)
USB3_PON: length 5.8
  TOP w0.2: U808.4 138.53,91.8 138.16,91.43 R817.2 137.25,91.43 C835.1 137.25,90.58 R818.1 137.74,89.73 138.15,90.14 U807.1
USB3_VBUS1: length 23.5
  L3 w0.2: v1(139.93,101.81) 139.95,101.79 140,101.79 140.04,101.75 v2(140.32,101.75)
  L6 w0.2: v2(140.32,101.75) 140.32,101.44 140.31,101.43 140.31,101.42 140.3,101.4 140.3,96.61 140,96.31 140,90.68 139.26,89.94 139.26,80.12 v2(139.48,79.9)
  BOTTOM w0.1: 190.85,82.11 190.8,82.16 J1900.U1
  vias: v1(139.65,102.24) v1(139.93,101.52) v1(140.08,102.25) v2(139.48,79.47) v2(139.94,79.9) v2(139.94,79.47) v2(140.3,101.26) v2(140.78,101.75) v2(140.77,101.27) v2(169.6,79.27) v2(169.6,78.77) v2(175.9,82.62) v2(175.9,82.12) v3(169.95,79.02) v3(169.95,78.72) v3(170.25,79.02) v3(170.25,78.72) v3(176.25,82.57) v3(176.25,82.32) v3(176.5,82.57) v3(176.5,82.32)
USB3_VBUS2: length 1.1
  TOP w0.1: C2705.1 159.68,119.27 159.71,119.23
  L3 w0.2: 163.3,119.21 163.3,119.12 v2(163.97,118.45)
  vias: v1(159.78,119.22) v1(160.19,119.21) v1(160.53,119.22) v1(160.84,119.22) v2(163.85,80.5) v2(163.85,80) v2(164.01,118.91) v2(164.35,80.5) v2(164.35,80) v2(164.47,118.9) v2(164.47,118.45) v2(169.55,80.52) v2(169.55,80.02) v2(175.85,84.72) v2(175.85,84.22) v3(168.9,80.57) v3(168.9,80.27) v3(169.2,80.57) v3(169.2,80.27) v3(176.2,84.67) v3(176.2,84.42) v3(176.45,84.67) v3(176.45,84.42)
USB3_VBUS3: length 14.2
  L3 w0.2: v2(143.23,112.27) v1(145.38,112.27)
  L6 w0.2: v2(143.23,112.27) v2(143.23,100.9)
  BOTTOM w0.1: 190.82,104.07 190.78,104.11 J1901.U1
  vias: v1(145.38,112.82) v1(145.73,112.81) v1(145.89,112.57) v2(142.78,112.72) v2(142.77,112.26) v2(142.78,101.34) v2(142.78,100.9) v2(143.24,112.72) v2(143.23,101.34) v2(170.25,100.42) v2(170.75,100.42) v2(175.65,104.77) v2(175.65,104.27) v3(170.2,100.07) v3(170.2,99.77) v3(170.5,100.07) v3(170.5,99.77) v3(176.06,104.4) v3(176.06,104.15) v3(176.31,104.4) v3(176.31,104.15)
USB3_VBUS4: length 8
  L6 w0.2: v2(144.47,101.34) 144.34,101.46 144.34,108.84 v2(144.67,109.17)
  vias: v1(150.15,109.06) v1(150.27,109.48) v1(150.42,109.07) v1(150.59,109.47) v2(143.96,101.87) v2(144.01,101.33) v2(144.18,109.17) v2(144.19,108.65) v2(144.45,101.91) v2(144.7,108.65) v2(169.9,101.87) v2(170.4,101.87) v2(175.65,106.32) v2(175.65,105.82) v3(169.25,102.02) v3(169.25,101.72) v3(169.55,102.02) v3(169.55,101.72) v3(176.05,106.37) v3(176.05,106.12) v3(176.3,106.37) v3(176.3,106.12)
USB_3_PORT1_EN: length 2.2
  TOP w0.1: U2700.4 141.78,106.47 R2707.1 R2724.1
USB_3_PORT2_EN: length 2.2
  TOP w0.1: U2701.4 164.53,116.58 164.55,116.57 R2709.1 R2734.1
USB_3_PORT3_EN: length 3.3
  TOP w0.2: U2702.4 151.93,110.38 R2725.1 152.45,109.87 R2703.1
USB_3_PORT4_EN: length 5.2
  TOP w0.1: R2728.1 R2749.1 148.55,104.97 148.44,104.85 U2703.4
USB_HUB_THERM: length 7
  TOP w0.1: RT2400.1 48.62,34.79 49.31,35.48 J2600.D28
USB_RESET_1P8: length 151.8
  TOP w0.1: J2600.C29 51.28,33.57 57.7,33.57 58.5,34.37 59.2,34.37 v1(60,33.57)
  L3 w0.1: v2(141.65,24.47) 141.3,24.12 110,24.12 103.6,30.52 87.28,30.52 84.23,33.57 v1(60,33.57) ; v1(143.7,78.77) v2(144.1,78.77)
  L6 w0.1: v2(144.1,78.77) 144.25,78.62 144.25,60.77 143.65,60.17 143.65,52.62 143.3,52.27 143.3,48.17 142.1,46.97 142.1,35.02 141.65,34.57 v2(141.65,24.47)
USBDP0+: length 4.8
  TOP w0.072: R2412.2 148.61,84.45 148.93,84.45 TP1802.1 149.57,84.45 149.67,84.45 149.83,84.61 149.83,86.27 150.32,86.76 150.48,86.76 150.6,86.88 U2400.55
USBDP0-: length 4.8
  TOP w0.072: R2413.2 148.61,84.28 148.93,84.28 TP1803.1 149.57,84.28 149.73,84.28 150,84.55 150,86.21 150.39,86.6 150.49,86.6 150.61,86.48 U2400.56
USBSUS: length 4.5
  TOP w0.1: TP2408.1 153.53,81.27 153.53,83 154.01,83.48 U2400.64
V_3P3_PER_VCC: length 15.6
  L6 w0.4: v3(98.54,72.71) v8(98.54,64.6)
  L7 w0.4: v7(93.31,63.28) 97.22,63.28 v8(98.54,64.6)
  BOTTOM w0.4: D503.1 93.31,63.33 C505.2
V_3P3_PER_VDDA: length 17.1
  L7 w0.3: v7(86.54,73.17) 86.54,72.69 85.68,71.83 v7(84.86,71.83) ; v7(90.16,78.23) 89.66,77.73 84.93,77.73 v7(84.9,77.7)
  BOTTOM w0.25: U500.36 86.74,72.96 C503.2 v7(86.54,73.17) ; R509.1 85.36,71.83 v7(84.86,71.83) ; R508.1 v7(90.16,78.23)
  BOTTOM w0.3: v7(84.86,71.83) 84.86,77.66 v7(84.9,77.7)
V_5P0_SW1: length 11
  L3 w0.2: v2(101.15,66.27) 101.13,66.25 98.56,66.25 v2(94.34,66.25)
  L6 w0.2: v3(94.42,66.62) 94.42,66.61 94.34,66.53 v2(94.34,66.25) ; v2(101.15,66.27) v3(101.5,66.27)
  BOTTOM w0.2: U500.21 93.76,68.12 94.42,67.46 C508.2 v3(94.42,66.62)
V_SW_CAM_7P0: length 8.9
  BOTTOM w0.2: Q601.8 75.75,56.52 74.97,55.74 73.72,55.74 73.44,55.45 C613.1 73.39,55.01 U600.16
VDCIN_9_30V:
  vias: v6(119.1,26.45) v6(119.1,25.85) v6(119.1,25.25) v6(119.1,24.65) v6(119.75,26.45) v6(119.75,25.85) v6(119.75,25.25) v6(119.75,24.65) v6(120.4,26.45) v6(120.4,25.85) v6(120.4,25.25) v6(120.4,24.65) v6(121.05,26.45) v6(121.05,25.85) v6(121.05,25.25) v6(121.05,24.65) v6(121.65,26.45) v6(121.65,25.85) v6(121.65,25.25) v6(121.65,24.65)
VL_VCC10I: length 4.2
  TOP w0.1: C815.1 136.43,86.75
  TOP w0.3: TP802.1 136.73,85.87 136.43,86.17 R816.1
VL_VCC10I_F: length 18.9
  TOP w0.2: v1(152.41,93.1) U2400.36 152.41,95.24 C2431.1 ; v1(156.01,93.1) U2400.27 156.01,95.36 C2429.1 ; v1(150.25,87.27) 150.26,87.28 U2400.54 ; v1(158.6,87.68) U2400.5 160.43,87.68 C2427.1 160.37,88.88 U2400.8 v1(158.6,88.88) ; C2430.1 153.61,94.94 U2400.33 v1(153.61,93.1) ; v1(158.6,91.28) U2400.14 160.53,91.28 C2428.1 ; U2400.51 150.03,88.48 148.55,87
  vias: v1(148.85,87.08) v1(148.85,86.83)
VL_VCC33I: length 89.7
  TOP w0.1: C2407.1 162.2,80.72 162.21,80.7
  TOP w0.2: R1813.1 147.3,109.57 147.65,109.22 R1814.1 v1(141.75,108.12) ; D2400.2 147.35,81.07 148.35,80.07 R2404.1 ; R1812.1 v1(162.15,110.27)
  TOP w0.3: v1(154.59,79.59) 154.18,80 R2405.1 155.01,82.02 R2406.1
  L3 w0.2: v1(141.75,101.87) v2(142,102.12) 142.2,102.32 142.2,107.67 v1(141.75,108.12) 144.3,110.67 151.55,110.67 152.35,109.87 161.75,109.87 v1(162.15,110.27)
  L3 w0.3: v1(146.38,82.94) v1(146.38,82.67) 146.38,82.15 ; v1(148.16,93.77) 148.16,94.69 v1(148.14,94.71) 144.32,94.71 144.18,94.85 144.02,94.85 144.01,94.86 v2(141.95,94.86) 141.72,94.86 ; v2(158.3,77.98) 158.11,77.98 v1(157.89,78.21) ; 146.77,81.76 146.38,82.15 146.38,82.15 ; 146.38,82.15 145.99,81.76
  L3 w0.5: v1(154.59,79.59) 154.59,79.6 ; 154.59,79.6 155.83,79.6 156.18,79.95 v2(158.27,79.95) 161.48,79.95 v1(162.21,80.67) ; 154.59,79.6 151.84,79.6 149.67,81.76 142.44,81.76 v2(142.35,81.67)
  L6 w0.3: v2(142,102.12) 142,95.13 141.95,95.08 v2(141.95,94.86) ; v2(158.3,77.98) 158.3,79.92 v2(158.27,79.95)
  vias: v1(141.4,95.57) v1(141.4,95.27) v1(141.7,95.57) v1(141.7,95.27) v1(142,95.57) v1(142,95.27)
VL_VCC33I_F: length 31.6
  TOP w0.2: v1(158.98,92.48) U2400.17 160.83,92.48 C2425.1 ; C2422.1 149.59,90.48 U2400.46 151.44,90.48 v1(151.44,90.48) ; C2421.1 157.21,94.46 U2400.24 157.21,93.75 v1(157.49,93.47) ; v1(153.21,86.29) U2400.62 153.21,84.16 v1(152.8,83.75) ; v1(157.61,86.29) U2400.73 157.61,83.76 C2424.1
  L3 w0.25: v1(151.44,90.48) v2(151.77,90.48) ; v1(158.98,92.48) 158.62,92.48 v2(158.53,92.57) 158.39,92.57 v1(157.49,93.47) ; v1(153.21,86.29) v1(157.61,86.29)
  L6 w0.25: v2(152.85,86.28) 152.17,86.96 152.17,90.08 v2(151.77,90.48) 153.86,92.57 v2(158.53,92.57)
  vias: v1(148.7,83.09) v1(148.7,82.79)
VL_VDD: length 31.9
  TOP w0.2: v1(154.81,93.45) U2400.30 154.81,94.7 155.3,95.19 C2415.1 ; v1(148.96,89.47) 148.96,89.46 149.63,89.46 149.85,89.68 U2400.48 ; C2414.2 160.47,90.08 U2400.11 v1(158.98,90.08) ; C2417.1 155.21,84.64 U2400.67 155.21,85.91 v1(155.21,85.91)
  L3 w0.25: 148.55,89.58 148.55,92.1 148.79,92.34 151.19,92.34 152.3,93.45 v1(154.81,93.45) 156.93,93.45 158.98,91.4 v1(158.98,90.08) 158.98,87.08 157.81,85.91 v1(155.21,85.91)
  vias: v1(146.7,89.45) v1(147,89.45)
VREG_1P0: length 8.3
  BOTTOM w0.2: 48.6,62.82 51.34,60.07 C3210.1
  BOTTOM w0.3: R3201.1 52.3,60.08 C3210.1
  BOTTOM w0.4: B3001.2 45.07,60.97 45.09,60.97 45.71,61.58 C3010.1 ; B2902.2 51.35,91.14 C2915.1
  vias: v7(52.4,90.52) v7(52.4,90.27) v7(52.4,89.97) v7(52.7,90.52) v7(52.7,90.27) v7(52.7,89.97) v7(53.95,70.62) v7(53.95,70.32) v7(54.25,70.62) v7(54.25,70.32) v7(54.55,70.62) v7(54.55,70.32)
VREG_1P2: length 2.2
  BOTTOM w0.3: C2924.1 51.07,99.8 B2903.1 ; B3003.1 48.42,73.06 C3024.1
VREG_5P0_EN_9_30V: length 11.4
  TOP w0.1: J2600.A40 53.17,19.56 52.88,19.26 TP2630.1
VREG_AMP_24P0: length 14.7
  BOTTOM w0.2: Q702.8 91.28,31.82 92.3,30.8 R707.1 C710.2 97.13,30.8 97.63,31.3 U700.20
  vias: v2(66.95,100.45) v2(67.4,100.45) v2(67.85,100.45) v2(68.3,100.45) v2(68.3,100) v2(68.75,100.45) v2(68.75,100) v2(69.2,100.45) v2(69.2,100) v2(69.65,100.45) v2(69.65,100) v2(92.57,100.36) v2(92.57,99.94) v2(92.59,99.51) v2(92.59,99.06) v2(93.02,100.36) v2(93.02,99.94) v2(93.04,99.51) v2(93.04,99.06) v2(93.45,100.36) v2(93.45,99.94) v2(93.46,99.51) v2(93.46,99.06) v2(93.88,100.36) v2(93.88,99.94) v2(93.89,99.5) v2(93.89,99.05) v2(94.33,100.36) v2(94.33,99.94) v2(94.34,99.5) v2(94.34,99.05) v3(66.95,100.02) v3(66.95,99.77) v3(66.95,99.52) v3(66.95,99.27) v3(67.2,100.02) v3(67.2,99.77) v3(67.2,99.52) v3(67.2,99.27) v3(67.45,100.02) v3(67.45,99.77) v3(67.45,99.52) v3(67.45,99.27) v3(67.7,100.02) v3(67.7,99.77) v3(67.7,99.52) v3(67.7,99.27) v3(67.95,100.02) v3(67.95,99.77) v3(67.95,99.52) v3(67.95,99.27) v3(91.15,52.65) v3(91.15,52.4) v3(91.15,52.1) v3(91.15,51.9) v3(91.15,51.65) v3(91.15,51.4) v3(91.15,51.15) v3(91.4,52.65) v3(91.4,52.4) v3(91.4,52.1) v3(91.4,51.9) v3(91.4,51.65) v3(91.4,51.4) v3(91.4,51.15) v3(91.65,52.65) v3(91.65,52.4) v3(91.65,52.1) v3(91.65,51.9) v3(91.65,51.65) v3(91.65,51.4) v3(91.65,51.15) v3(91.9,52.65) v3(91.9,52.4) v3(91.9,52.1) v3(91.9,51.9) v3(91.9,51.65) v3(91.9,51.4) v3(91.9,51.15) v3(92.15,52.65) v3(92.15,52.4) v3(92.15,52.1) v3(92.15,51.9) v3(92.15,51.65) v3(92.15,51.4) v3(92.15,51.15) v3(92.4,52.65) v3(92.4,52.4) v3(92.4,52.1) v3(92.4,51.9) v3(92.4,51.65) v3(92.4,51.4) v3(92.4,51.15) v3(92.65,52.65) v3(92.65,52.4) v3(92.65,52.1) v3(92.65,51.9) v3(92.65,51.65) v3(92.65,51.4) v3(92.65,51.15) v3(92.9,52.65) v3(92.9,52.4) v3(92.9,52.1) v3(92.9,51.9) v3(92.9,51.65) v3(92.9,51.4) v3(92.9,51.15) v3(94.65,99.8) v3(94.65,99.55) v3(94.65,99.3) v3(94.65,99.05) v3(94.9,99.8) v3(94.9,99.55) v3(94.9,99.3) v3(94.9,99.05) v3(95.15,99.8) v3(95.15,99.55) v3(95.15,99.3) v3(95.15,99.05) v3(95.4,99.8) v3(95.4,99.55) v3(95.4,99.3) v3(95.4,99.05) v3(95.65,99.8) v3(95.65,99.55) v3(95.65,99.3) v3(95.65,99.05)
VREG_CAM_EN: length 72.2
  L3 w0.1: v2(75.85,40.12) 67.46,40.12 66.93,40.65 64.13,40.65 63.73,41.06 56.95,41.06 56.65,41.36 51.32,41.36 50.18,42.49 50.18,49.88 49.2,50.87 49.2,51.45 44.34,56.3 42.19,56.3 41.69,56.8 34.92,56.8 34.41,57.31 v2(33.06,57.31)
  L6 w0.1: v3(75.72,52.19) 76.1,51.81 76.1,40.37 v2(75.85,40.12) ; v3(33.06,56.79) v2(33.06,57.31)
  BOTTOM w0.1: v3(75.72,52.19) 75.71,52.18 73.62,52.18 73.44,52.36 R600.1 73.29,53.01 U600.20 ; U3104.20 v3(33.06,56.79)
VREG_CAM_POC_6P7: length 3.6
  BOTTOM w0.1: C620.1 61.16,63.65 ; JP601.1 65.55,59.67 ; C619.1 62.77,65.82
  BOTTOM w0.2: R899.1 64.25,54.07
  vias: v1(23.8,93.69) v1(23.8,93.42) v1(23.82,88.08) v1(23.82,87.81) v1(23.82,82.55) v1(23.82,82.29) v1(23.82,76.95) v1(23.82,76.68) v1(23.79,70.74) v1(23.79,70.47) v1(23.82,64.83) v1(23.82,64.56) v1(23.83,58.14) v1(23.83,57.87) v1(24.05,70.74) v1(24.05,70.47) v1(24.06,93.69) v1(24.06,93.42) v1(24.08,88.08) v1(24.08,87.81) v1(24.08,82.55) v1(24.08,82.29) v1(24.08,76.95) v1(24.08,76.68) v1(24.08,64.83) v1(24.08,64.56) v1(24.09,58.14) v1(24.09,57.87) v1(29.47,101.22) v1(29.47,100.96) v1(29.73,101.22) v1(29.73,100.96) v2(27.33,71.17) v2(27.34,70.68) v2(27.35,57.88) v2(27.4,94.46) v2(27.41,93.98) v2(27.38,88.8) v2(27.39,88.32) v2(27.38,82.81) v2(27.36,82.35) v2(27.38,77.73) v2(27.38,77.25) v2(27.37,65.62) v2(27.38,65.13) v2(27.35,57.39) v2(27.82,71.17) v2(27.82,70.68) v2(27.84,57.88) v2(27.84,57.39) v2(27.89,94.47) v2(27.89,93.98) v2(27.88,88.81) v2(27.88,88.32) v2(27.86,82.81) v2(27.85,82.36) v2(27.87,77.74) v2(27.87,77.25) v2(27.86,65.63) v2(27.86,65.13) v2(28.66,98.24) v2(28.66,97.75) v2(29.15,98.25) v2(29.15,97.75) v2(53.15,96.67) v2(53.15,96.17) v2(53.15,95.67) v2(53.65,96.67) v2(53.65,96.17) v2(53.65,95.67) v2(54.15,96.67) v2(54.15,96.17) v2(54.15,95.67) v2(54.65,96.67) v2(54.65,96.17) v2(54.65,95.67) v3(60.9,66.27) v3(60.9,66.02) v3(60.9,65.77) v3(61.15,66.27) v3(61.15,66.02) v3(61.15,65.77) v3(61.4,66.27) v3(61.4,66.02) v3(61.4,65.77) v3(61.65,66.27) v3(61.65,66.02) v3(61.65,65.77) v3(62.45,66.27) v3(62.45,66.02) v3(62.45,65.77) v3(62.45,65.5) v3(62.7,66.27) v3(62.7,66.02) v3(62.7,65.77) v3(62.7,65.5) v3(62.95,66.27) v3(62.95,66.02) v3(62.95,65.77) v3(62.95,65.5) v3(63.2,66.27) v3(63.2,66.02) v3(63.2,65.77) v3(63.2,65.5) v3(63.45,66.27) v3(63.45,66.02) v3(63.45,65.77) v3(63.45,65.5) v3(63.7,66.27) v3(63.7,66.02) v3(63.7,65.77) v3(63.7,65.5) v3(111.35,23.37) v3(111.35,23.12) v3(111.35,22.87) v3(111.35,22.62) v3(111.35,22.37) v3(111.35,22.12) v3(111.35,21.87) v3(111.35,21.62) v3(111.6,23.37) v3(111.6,23.12) v3(111.6,22.87) v3(111.6,22.62) v3(111.6,22.37) v3(111.6,22.12) v3(111.6,21.87) v3(111.6,21.62) v3(111.85,23.37) v3(111.85,23.12) v3(111.85,22.87) v3(111.85,22.62) v3(111.85,22.37) v3(111.85,22.12) v3(111.85,21.87) v3(111.85,21.62) v3(112.1,23.37) v3(112.1,23.12) v3(112.1,22.87) v3(112.1,22.62) v3(112.1,22.37) v3(112.1,22.12) v3(112.1,21.87) v3(112.1,21.62)
VREG_EDP_1P0: length 99
  L3 w0.3: v2(30.63,26.73) 30.58,26.79 v2(29.03,26.79) ; v2(47.8,37.95) 47.8,38 50.43,38 v2(50.43,37.95) ; v2(47,18.86) 46.89,18.97 43.53,18.97 42.78,19.72 42.14,19.72 41.67,19.25 31.46,19.25 31.34,19.12 30.86,19.12 30.49,19.5 28.4,19.5 v2(27.96,19.07)
  L6 w0.1: 30.62,25.37 30.62,25.36
  L6 w0.2: v8(61.13,25.45) 61.13,25.45 JP1005.1 ; 47.63,35.83 47.78,35.68 47.79,35.69 47.79,35.99 ; 47.63,35.83 JP1105.1 ; 47.63,35.83 47.79,35.99 ; 60,30.28 60,30.25 59.57,29.81 59.57,25.5 v8(59.61,25.46) 59.88,25.18 59.88,24.43 v3(61.09,23.22) ; 60,30.28 v8(60,32.44) v8(60,35.17) ; 60,30.28 60.15,30.14 JP1002.1 ; v3(61.12,35.19) 61.11,35.18 JP1004.1 ; 47.79,35.99 47.79,36.02 ; 47.03,40.68 47.03,40.68 46.92,40.57 46.92,40.78 ; 47.03,40.68 46.92,40.78 ; 47.03,40.68 JP1102.1 ; 27.95,19.98 27.93,20 27.93,20.35 ; JP902.1 27.99,20.41 ; 27.99,20.41 27.93,20.48 ; 27.99,20.41 27.99,20.41 27.93,20.35 ; 46.92,40.78 46.92,40.81 ; 27.93,20.48 27.93,21.24 28.05,21.36 ; 27.93,20.48 27.93,20.35 ; 46.9,44.67 46.72,44.85 ; 46.72,44.85 JP1104.1 ; 46.72,44.85 46.9,45.02 ; JP904.1 30.65,15.34 30.52,15.22 v3(29.88,15.22) ; 30.62,25.36 JP905.1
  L6 w0.3: 30.63,26.75 v2(30.63,26.73) 30.62,26.71 ; 30.63,26.75 30.62,26.74 30.62,26.71 ; 30.63,26.75 v3(30.95,27.07) ; 27.95,19.98 27.95,19.08 v2(27.96,19.07) 27.95,19.06 28.77,18.24 28.77,16.33 v3(29.88,15.22) ; 28.05,21.36 28.05,25.8 v2(29.03,26.79) ; 47.78,35.68 47.78,34.08 v8(47.75,34.05) ; 47.79,38.06 47.79,36.02 ; 47.79,38.06 47.8,38.06 v2(47.8,37.95) ; 47.79,38.06 47.79,39.39 46.92,40.26 46.92,40.57 ; v3(46.9,45.89) 46.9,40.83 46.92,40.81 ; 50.33,26.68 50.03,26.39 47.56,26.39 47,25.83 v2(47,18.86) ; 30.62,26.71 30.62,25.37
  L7 w0.2: v8(52.41,31.26) 57.54,31.26 58.72,32.44 v8(60,32.44) ; v8(59.61,25.46) 59.61,25.45 v8(61.13,25.45) ; v3(61.12,35.19) 60.93,35 60.17,35 v8(60,35.17)
  L7 w0.3: v8(51.46,37.78) 51.74,38.07 v7(54.21,38.07) ; v7(44.5,33.17) 45.38,34.05 v8(47.75,34.05)
  BOTTOM w0.1: v3(30.95,27.07) 30.97,27.07 30.99,27.1 31.06,27.1 B900.1
  BOTTOM w0.2: v3(61.12,35.19) B1003.1
  BOTTOM w0.3: R805.1 54.2,38.06 v7(54.21,38.07) ; B1103.1 46.89,45.9 v3(46.9,45.89)
  vias: v3(50.06,42.69) v3(50.06,42.33) v3(50.4,42.68) v3(50.4,42.33) v3(50.7,42.68)
VREG_EDP_3P3: length 174.5
  L3 w0.3: v2(31.35,28.92) 31.47,29.04 v2(37.57,29.04) 37.66,29.13 v2(40.41,29.13) 41.59,27.95 v2(46.15,27.95) ; v2(35.12,49.61) 35.34,49.83 46.88,49.83 46.98,49.93 v2(47.34,49.93)
  L6 w0.2: JP1103.1 35.08,47.29 v3(34.76,47.61) ; v3(45.57,37.02) 45.57,37.69 45.85,37.97 46.9,37.97 v3(47.35,38.42) ; JP903.1 31.26,20.38 31.69,20.81 31.69,27.88 31.76,27.96 31.76,28.5 v2(31.35,28.92) 30.55,28.92 29.85,28.22 29.85,27.02 28.6,25.77 v3(28.6,25.02) 28.4,24.82 28.4,22 v3(28.95,21.45) ; v2(37.57,29.04) 37.61,29 v3(37.61,28.58) ; v8(62.32,30.98) 62.31,30.97 JP1003.1
  L6 w0.3: v3(34.76,47.61) 34.76,49.25 v2(35.12,49.61) ; v3(52.34,22.04) v8(52.34,19.38) ; v3(30.85,30.75) 30.85,29.95 31.35,29.46 v2(31.35,28.92) ; v2(40.41,29.13) 41,28.54 41,24.37 41.05,24.32 41.05,13.83 v3(41.57,13.3) ; v3(38.15,32.53) 38.05,32.53 37.57,32.06 v2(37.57,29.04) ; 49.05,37.36 49.06,37.37 49.06,41.59 49.06,41.59 49.06,41.96 49.06,41.96 49.06,45.5 v8(49.12,45.56) 49.06,45.63 49.06,46.41 48.15,47.32 48.15,49.48 47.7,49.93 v2(47.34,49.93) ; 49.05,37.36 49.05,36.83 ; 49.05,37.36 49.32,37.09 ; v2(46.15,27.95) 46.63,28.42 46.63,30.98 49.05,33.41 49.05,36.83 ; v3(62.04,19.39) 61.8,19.63 61.8,23.7 62.75,24.66 v3(62.75,26.17) 62.41,26.5 62.41,28.23 v3(62.75,28.57) 63.28,29.1 63.28,30.98 ; 63.28,30.98 63.28,37.92 v8(63.3,37.93) ; 63.28,30.98 v8(63.28,30.98) ; v3(49.99,37.09) 49.32,37.09 ; 49.32,37.09 49.31,37.09 49.05,36.83 ; v8(52.12,50.35) 52.11,50.37 v3(52.11,58.06)
  L7 w0.3: v3(47.6,50.36) 47.62,50.35 v8(52.12,50.35) ; v3(49.99,37.09) 51.02,38.12 51.38,38.48 56.71,38.48 56.72,38.49 57.01,38.49 57.38,38.12 63.11,38.12 v8(63.3,37.93) ; v8(52.34,19.38) 62.04,19.38 v3(62.04,19.39) ; v8(63.28,30.98) v8(62.32,30.98) ; v7(51.85,45.56) v8(49.12,45.56)
  BOTTOM w0.2: B1001.1 49.93,37.02 R1133.2 47.92,37.85 v3(47.35,38.42) ; B1102.1 v3(38.15,32.53) ; B902.1 v3(37.61,28.58) ; R932.2 28.95,24.67 v3(28.6,25.02) ; B1002.1 v3(52.34,22.04) ; R933.2 v3(28.95,21.45)
  BOTTOM w0.3: U902.5 30.86,30.74 v3(30.85,30.75) ; U804.4 v3(52.11,58.06) ; U805.1 C824.1 47.15,51.52 47,51.37
  vias: v3(47.31,50.35)
VREG_FAN_12V: length 0.1
  L6 w0.1: v2(128.87,6.21) 128.86,6.19 128.78,6.19
  vias: v1(182.86,6.89) v1(183.1,6.89) v2(128.87,6.71) v3(128.32,6.27) v3(128.32,6.02) v3(128.32,5.77) v3(128.57,6.27) v3(128.57,6.02) v3(128.57,5.77)
VREG_MDPX3_1P8: length 455.2
  TOP w0.1: J2700.I3 J2700.J3
  TOP w0.18: C2307.2 130.61,46.03 U2301.1 ; v1(131.64,49.55) 131.64,49.54 R2307.1
  TOP w0.2: v1(133.35,104.7) 133.35,104.7 C4006.1 ; U4003.5 143.35,111.27 143.39,111.31 C4009.1 ; U4001.7 133.64,104.97 C4006.1 ; U4002.7 127.75,104.97 C4007.1 ; R1609.1 130.05,57.97 v1(130.08,57.93) ; C4006.1 133.35,103.32 132.3,102.27 R4010.2 ; v1(132,64.26) 132,64.27 C1607.2 131.34,63.63 U1604.1
  TOP w0.3: v1(104.81,111.8) 104.79,111.81 Q1400.1 ; U1502.5 47.57,107.28 C1521.2 v1(47.57,107.28) ; v1(128.8,40.42) 127.47,41.74 C2313.2 U2302.1 ; U1602.5 142.1,76.34 142.37,76.07 v1(142.37,75.43) ; v1(130.15,65.09) 130.99,65.09 R1610.1 ; R3631.1 v1(129.87,13.89) ; v1(125.31,8.31) 125.31,8.31 U3606.7 ; v1(127.54,104.77) C4007.1 ; C2307.2 129.81,45.75 129.6,45.54 129.6,40.44 v1(129.58,40.43) ; v1(146.65,79.47) 146.6,79.42 U1800.5 ; R1506.2 v1(37.45,110.62)
  L3 w0.2: v2(131.29,65.09) 132,64.37 v1(132,64.26) ; v1(130.08,57.93) 131.06,57.93 v2(131.2,57.79)
  L3 w0.25: v2(133,104.77) 133.07,104.7 v1(133.35,104.7)
  L3 w0.3: v2(131.27,13.54) 130.34,13.54 130,13.89 v1(129.87,13.89) ; v2(61.32,22.83) 124.9,22.83 125.32,23.25 130.85,23.25 v2(131.2,23.6) ; v2(37.06,110.56) 37.12,110.62 v1(37.45,110.62) ; v2(32.1,20.11) 32.1,20.09 33.17,20.09 33.24,20.16 33.61,20.16 33.68,20.09 41.2,20.09 41.73,20.62 42.45,20.62 43.69,19.37 v2(61.1,19.37) ; v1(128.8,40.42) 129.58,40.42 v1(129.58,40.43) 129.66,40.36 131.14,40.36 v2(131.14,40.36) ; v1(125.31,8.31) v2(131.11,8.31) ; v2(131.62,74.43) 135.49,74.43 v1(136.41,75.35) 136.81,75.75 142.05,75.75 v1(142.37,75.43) 142.37,75.54 146.3,79.47 v1(146.65,79.47) ; v2(131.3,55.19) 123.5,55.19 122.91,55.78 105.92,55.78 105.43,55.29 52.12,55.29 51.94,55.48 v2(51.06,55.48) 50.13,55.48 45.54,60.07 41.66,60.07 40.7,61.02 v2(38.3,61.02) ; v1(128.12,49.43) 128.12,49.66 128.53,50.07 v2(131.46,50.07) 131.64,49.89 v1(131.64,49.55) ; v1(130.15,65.09) v2(131.29,65.09) ; v2(48.11,107.49) 47.91,107.28 v1(47.57,107.28) 44.1,107.28 43.8,107.58 v1(43.41,107.58) ; v1(136.82,103.54) v2(137.69,103.54) ; v1(104.81,111.8) 105.69,111.8 v2(105.69,111.81) ; v2(133,104.77) v1(127.54,104.77)
  L5 w0.3: v2(38.3,61.02) 38.12,61.02 38.12,60.98 38.09,60.98 38.09,60.94 38.02,60.94 38.02,61.01 38.11,61.11 38.11,63.56 37.33,64.34 37.33,64.37 35.94,65.75 35.94,65.77 34.94,66.77 34.94,73.75 34.33,74.36 34.33,103.04 37.2,105.91 37.2,106.58 v2(36.82,106.96)
  L6 w0.2: v2(105.69,111.81) 105.6,111.71 105.6,102.7 104.85,101.95 104.85,92.65 v3(105.25,92.25) ; v3(108.6,91.75) 108.6,90.7 110.1,89.2 v3(110.1,89.05)
  L6 w0.25: v2(133,104.77) 133,104.78 133,113.47 133.21,113.68 v2(133.21,114.11)
  L6 w0.3: v2(61.1,19.37) 61.24,19.52 61.24,21.69 v3(61.2,21.73) 61.32,21.84 v2(61.32,22.83) ; v2(32.1,20.11) 32.1,20.09 32.07,20.13 32.07,27.7 32.21,27.85 32.21,29.3 31.36,30.15 31.36,31.19 30.62,31.93 v3(30.34,31.93) ; v2(48.08,116.58) 48.08,116.13 48.11,116.1 48.11,107.94 48.11,107.94 v2(48.11,107.49) ; v2(137.69,103.54) 137.69,110.81 137.1,111.4 137.1,114.12 v2(137.12,114.13) ; v2(36.82,106.96) 37.06,107.2 v2(37.06,110.56) v2(37.06,116.57) ; v3(38.13,52.44) 38.13,52.73 37.91,52.95 37.91,54.61 38.13,54.83 v3(38.13,55.83) 38.13,58.09 38.19,58.14 38.19,60.24 38.3,60.35 v2(38.3,61.02) ; v3(107,17.5) v3(107.25,17.5) 107.65,17.9 v2(107.7,17.9) 107.85,18.05 v3(107.85,19.3) ; v2(51.06,55.48) 51.08,55.47 v3(51.08,47.9) ; v2(105.69,111.81) v2(105.69,115.65)
  L7 w0.3: v3(131.3,23.2) 129.95,21.85 125.41,21.85 v7(125.05,22.21)
  BOTTOM w0.2: U3104.27 36.54,55.13 37.25,55.84 C3112.1 ; v7(128.99,92.31) 128.82,92.48 U3414.2 ; U3104.31 36.93,53.13 37.62,52.44 C3113.1 ; U3406.7 134.67,97.26 135.01,96.92 v7(135.5,96.92) ; v7(128.86,97.16) 128.69,97.33 U3410.7 ; v3(105.25,92.25) 105.75,91.75 R3413.2 ; U3412.2 135.27,92.31 v7(135.5,92.08)
  BOTTOM w0.3: R1028.1 61.2,21.73 v3(61.2,21.73) ; R2807.1 v3(107.25,17.5) C2808.1 106.88,17.77 U2803.8 ; R1802.2 v3(107.85,19.3) ; C3112.1 v3(38.13,55.83) ; U504.1 129.06,22.86 129.4,23.2 C546.1 v3(131.05,23.2) v3(131.3,23.2) ; R925.1 v3(30.34,31.93)
  vias: v1(122.02,30.94) v1(122.32,30.94) v1(122.6,30.93) v1(143.84,114.32) v1(143.83,114.03) v1(151.63,29.86) v1(151.65,29.55) v2(107.25,17.9) v2(131.25,31.11) v2(131.69,31.11) v2(131.65,20.4) v2(131.65,19.85) v2(131.83,33.02) v2(131.85,32.53) v2(132.78,114.11) v2(151.71,28.89) v2(151.71,28.39) v7(126.22,92.88) v7(131.41,97.15) v7(132.58,92.71) v8(131.71,92.65) v8(131.71,92.37) v8(132.73,97.39) v8(132.73,97.11)
VREG_NVME_3P3: length 21
  TOP w0.18: U2301.8 130.61,48.38 C2308.2
  TOP w0.3: C2308.2 130.34,48.58 v1(130.34,48.58) ; C2315.2 127.47,48.43 U2302.6
  L3 w0.3: v2(125.83,48.63) 125.79,48.63 125.8,48.62 v1(127.29,48.62) 127.54,48.36 129.58,48.36 129.79,48.58 v1(130.34,48.58)
  L6 w0.3: v2(125.83,48.63) 125.79,48.63 125.79,35.77 126.3,35.27 v2(126.35,35.27)
  vias: v1(126.71,35.26) v1(126.99,35.26) v2(125.54,48.96) v2(125.9,35.27) v2(145.42,47.97) v2(145.83,47.96) v2(145.84,47.53) v2(145.84,47.12) v2(147.27,47.92) v2(147.27,47.47) v2(147.69,47.92) v2(147.7,47.47) v2(148.13,47.93) v2(148.14,47.48) v2(148.55,47.93) v2(148.57,47.48) v2(161.71,46.42) v2(161.68,35.91) v2(161.68,35.42) v2(162.12,46.43) v2(162.4,47.2) v2(162.82,47.21) v3(145.14,47.44) v3(145.14,47.21) v3(145.38,47.43) v3(145.37,47.2) v3(147.09,46.88) v3(147.36,46.88) v3(147.63,46.89) v3(147.9,46.89) v3(148.23,47.14) v3(148.23,46.89) v3(162.42,46.89) v3(162.42,46.64) v3(162.67,46.89) v3(162.67,46.64)
VREG_SIP_3P3: length 8.9
  L3 w0.3: v1(116.15,30.31) 117.14,30.31 117.14,30.31 v1(117.4,30.31) 124.89,30.31 v1(124.99,30.4)
VREG_SPX3_1P8: length 1.3
  TOP w0.4: J2700.C3 J2700.D3
VREG_SUB_1P8: length 71.2
  TOP w0.1: 88.05,91.7 88.03,91.7 C3514.1
  TOP w0.2: U3501.19 53.68,110.87 54.74,109.8 C3528.2
  TOP w0.25: C3515.2 89.75,92.45 U3500.19 ; v1(50.33,107.68) 50.33,107.69 R3527.2 ; B3502.1 v1(48.84,121.56)
  TOP w0.3: R3516.1 85.2,95.8 v1(85.2,95.85) 85.3,95.75 R3516.1 ; R3516.1 R3515.1 85.3,93.05 86.62,91.72 C3514.1 ; 88.05,91.7 C3515.2 ; C3527.1 56.15,109.8 C3528.2
  L3 w0.25: v1(50.33,107.68) 51.22,107.68 v1(51.23,107.68) 51.24,107.69 v1(52.1,107.69)
  L3 w0.3: v2(86.05,96.45) 85.45,95.85 v1(85.4,95.85) v1(85.2,95.85) ; v2(48.84,121.17) v1(48.84,121.56) 48.77,121.62 v1(30.43,121.62) ; v2(49.25,107.69) 49.25,107.68 v1(50.33,107.68) ; v1(56.19,109.81) 56.14,109.85 50.99,109.85 50.28,109.14 v2(49.3,109.14)
  L6 w0.3: v3(75.55,96.5) 75.55,96.7 v2(75.7,96.85) 75.8,96.75 v3(75.8,96.5) ; v2(49.25,107.69) 49.25,107.69 v3(49.25,108.17) v3(49.25,108.52) v3(49.25,108.82) 49.25,109.09 v2(49.3,109.14) 49.23,109.2 49.23,120.77 v2(48.84,121.17) ; v3(80.75,97.35) 80.63,97.35 v2(80.36,97.08) ; v3(58.5,110.45) 55.1,110.45 v3(54.55,109.9) ; v3(86.45,97.3) 86.45,97.1 v2(86.55,97) 86.7,97.15 v3(86.7,97.3) ; v3(77.34,96.59) 77.51,96.59 77.91,97 v2(78.22,97) v3(78.22,97.35)
  BOTTOM w0.2: R2818.2 84.95,96.55 85.1,96.7 85.1,97.2 85.25,97.35 C2801.1 ; C807.1 R812.1
  BOTTOM w0.3: C3208.1 U3202.1 ; U2800.2 85.21,97.94 85.65,97.5 C2801.1 86.58,97.35 C2800.1 ; R2800.2 v3(80.75,97.35)
  vias: v2(53.2,98.62) v2(53.2,98.12) v2(53.75,98.62) v2(53.75,98.12) v3(53.5,104.22) v3(53.5,103.92) v3(53.8,104.22) v3(53.8,103.92)
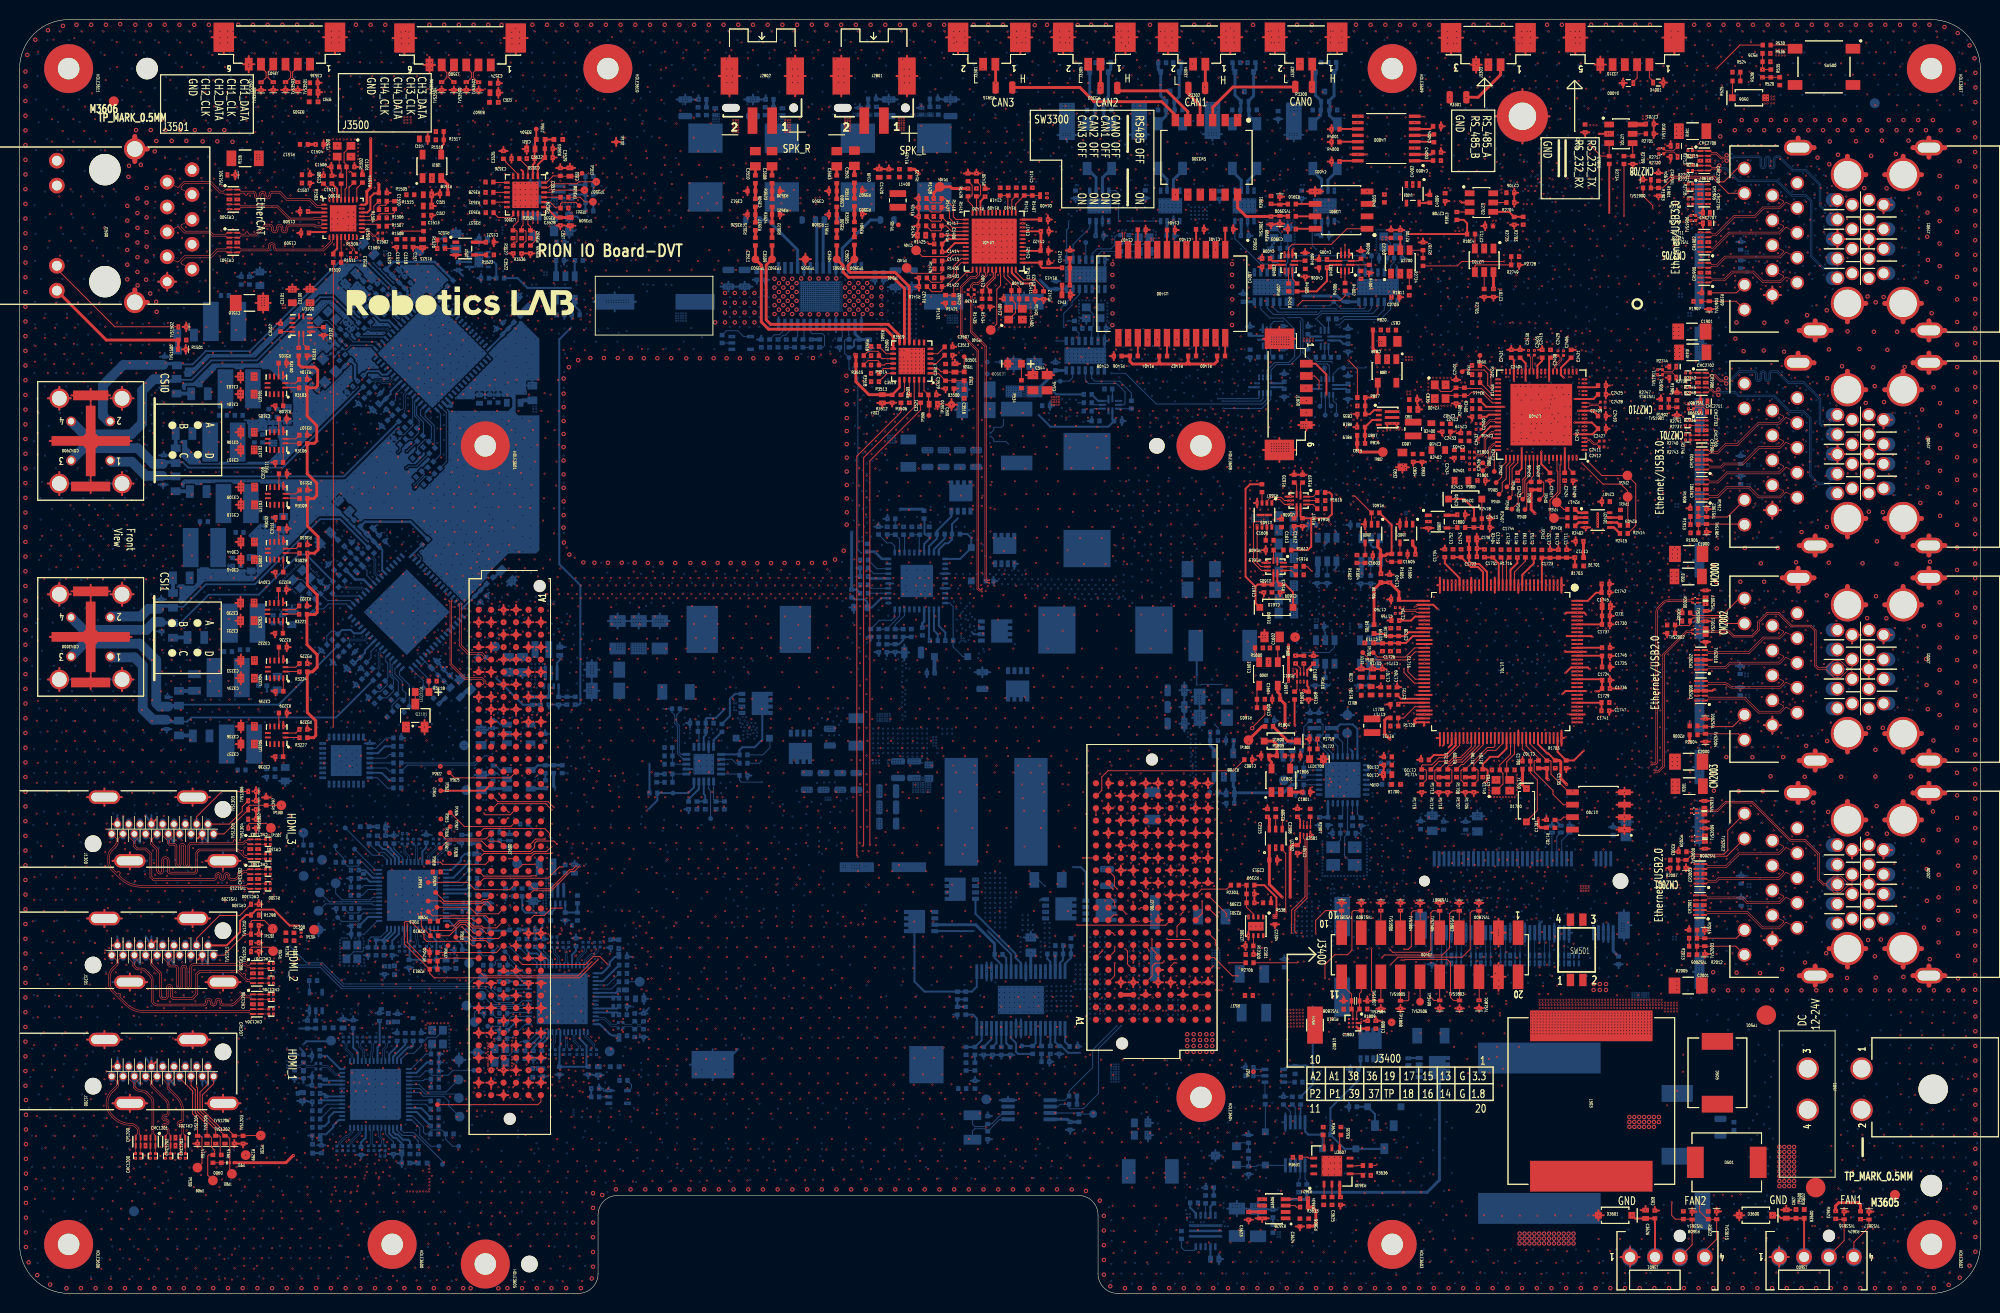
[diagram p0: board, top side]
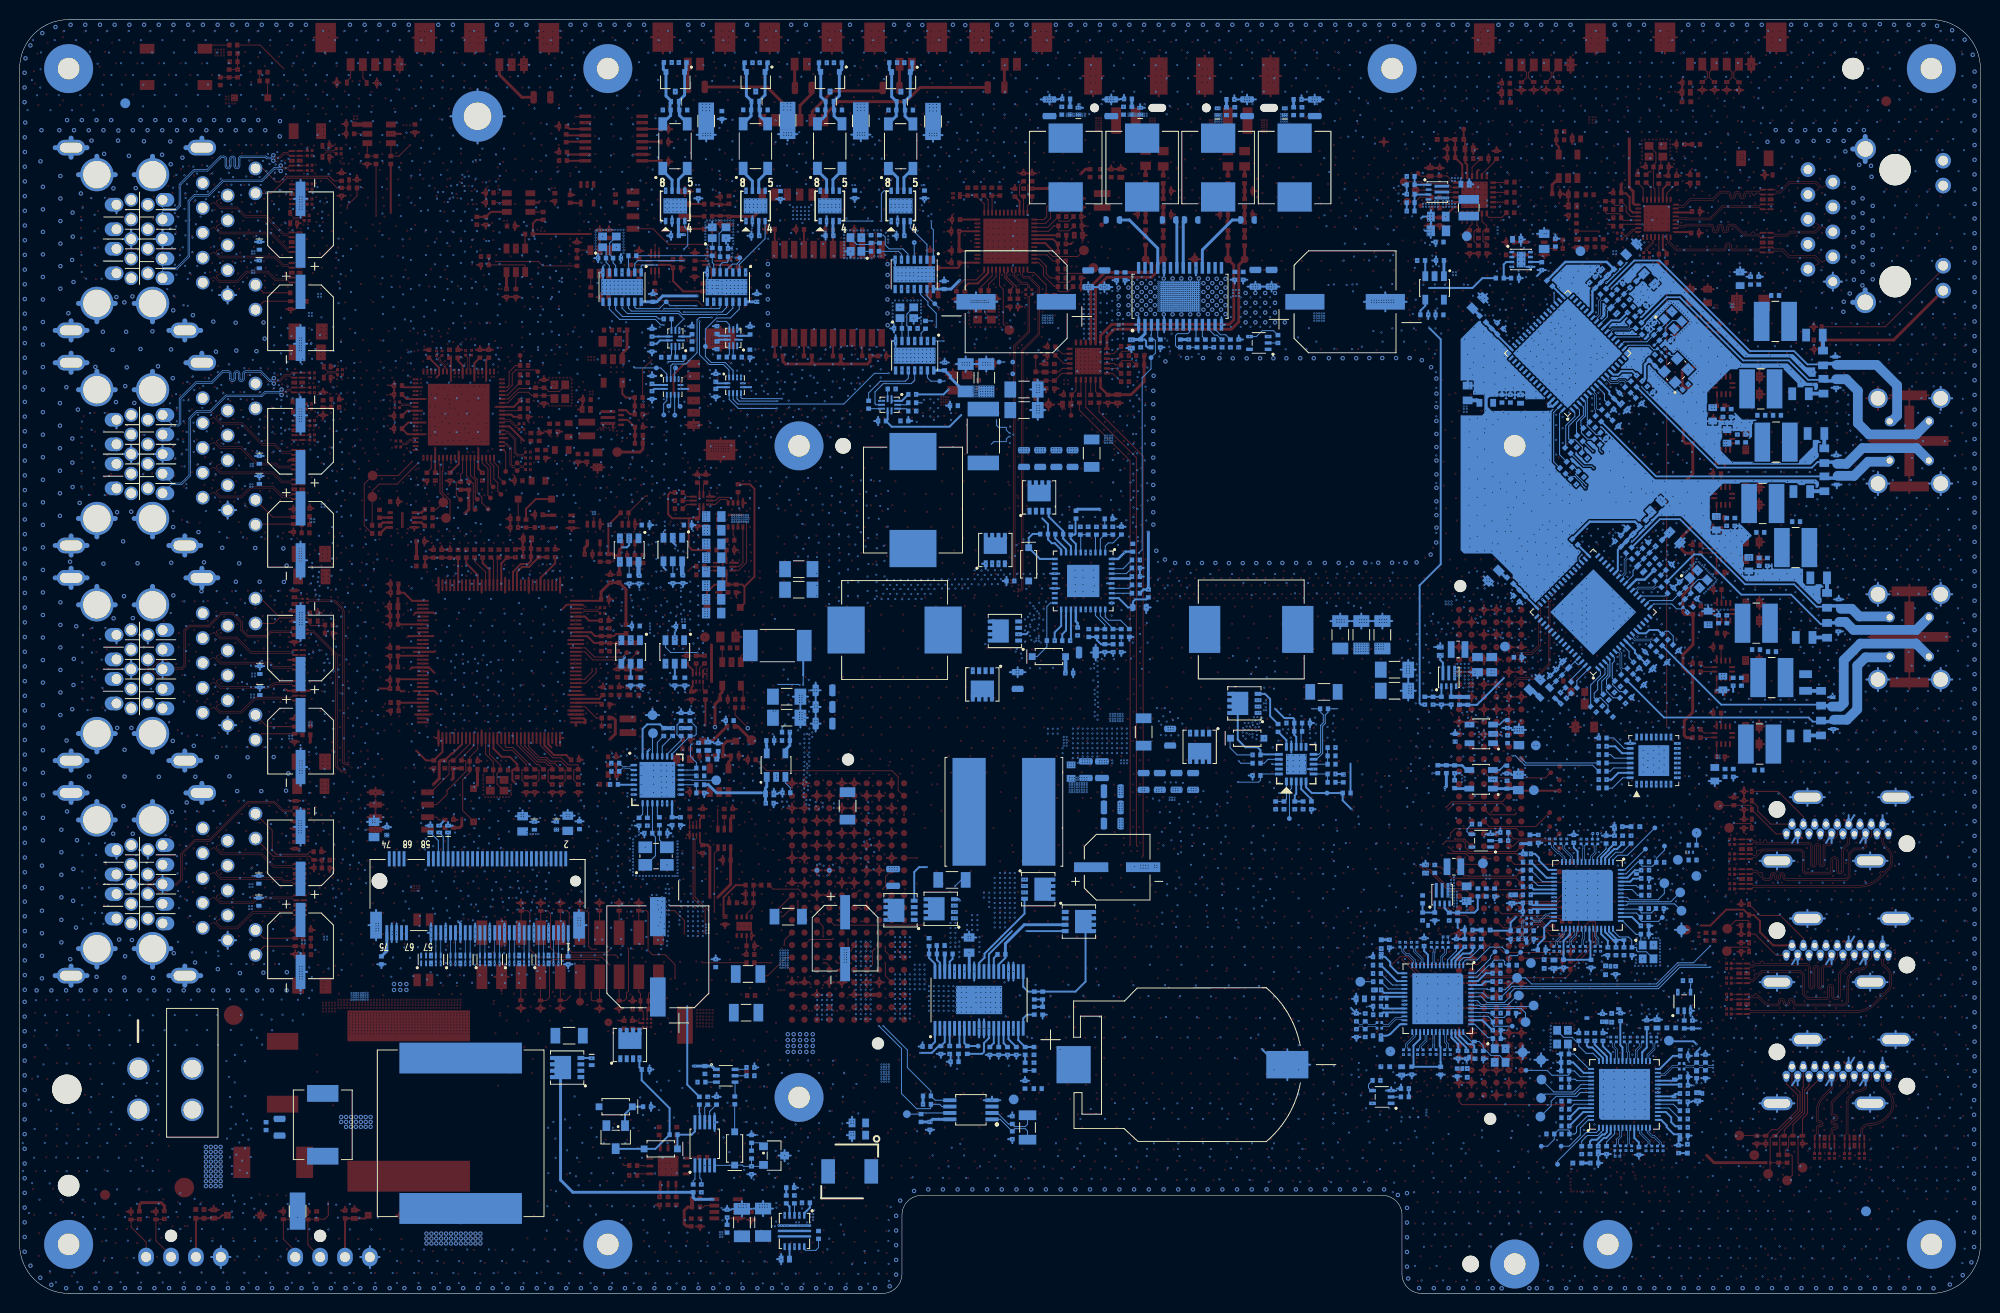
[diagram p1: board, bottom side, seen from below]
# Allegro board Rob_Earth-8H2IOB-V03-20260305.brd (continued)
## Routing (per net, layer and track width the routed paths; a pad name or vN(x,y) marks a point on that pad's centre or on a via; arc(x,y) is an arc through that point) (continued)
VREG_SUB_3P3: length 249.6
  TOP w0.2: C4005.1 133.49,105.37 U4001.6 ; R2399.1 126.95,41.67 128.2,40.42 128.2,38.62 C2304.1 ; 130.2,108.65 U3901.8 ; U4000.16 134.7,115.59 v1(134.62,115.51) ; C4008.1 127.79,105.37 U4002.6 ; v1(55.39,117.77) 55.39,117.77 B3503.1
  TOP w0.25: C1803.1 136.56,27.02 U1802.A3
  TOP w0.3: R3606.1 131.52,6.87 131.99,6.87 132.22,7.1 132.22,8.46 131.87,8.81 R3628.1 ; v6(129.07,57.79) 129.07,60.13 C1600.1 128.56,60.65 128.56,61.14 128.34,61.36 U1600.5 ; R3623.1 185.23,8.42 185.23,8.93 185.56,9.26 187.56,9.26 187.78,9.05 R3624.1 ; R4003.2 v1(139.22,112.15) ; C3625.1 134.65,9.9 U3607.3 ; R3901.2 127.65,112 v1(127.65,111.99) ; v1(130.17,108.62) 130.2,108.65
  TOP w0.4: v1(131.41,9.66) R3628.1 ; R3630.1 v1(137.82,12.03)
  L3 w0.1: v1(127.92,38.36) 127.77,38.21 127.77,38.2 127.52,37.95 v2(127.23,37.95)
  L3 w0.25: v2(93.24,78.23) v2(101.81,78.23) ; v2(91.25,63.3) v2(101.44,63.3)
  L3 w0.3: v1(132.97,16.97) 128.82,16.97 v2(128.78,16.97) ; v2(135.6,105.45) 133.43,105.45 v1(133.37,105.51) 127.67,105.51 v1(127.56,105.62) ; v1(134.72,9.81) 134.57,9.66 v1(131.41,9.66) 131.41,10.59 129.91,12.09 129.21,12.09 128.3,12.99 v2(127.74,12.99) ; v2(43.38,112.06) 43.31,112.13 v1(39.45,112.13) ; v2(128.82,30.36) 128.83,30.37 133.06,30.37 134.42,29.01 v1(135.06,29.01) 135.41,28.67 140.73,28.67 141.07,29.01 150.6,29.01 v1(150.98,28.63) ; v1(138.33,27.02) 136.65,25.35 v2(128.94,25.35) ; v1(130.17,108.62) 134.93,108.62 v2(135.05,108.5) ; v1(127.65,111.99) 134.3,111.99 134.54,112.24 v2(134.68,112.24) 137.1,112.24 137.31,112.04 139.11,112.04 v1(139.22,112.15)
  L3 w0.4: v1(185.23,8.37) 182.35,8.37 181.64,7.66 180.64,7.66 179.91,8.39 v1(172.24,8.39) 172.15,8.48 v1(169.69,8.48) 146.13,8.48 142.58,12.03 v1(137.82,12.03) 135.6,9.81 v1(134.72,9.81) ; 134.62,116.68 134.62,116.68 v1(134.62,115.51)
  L3 w0.5: v1(134.62,115.51) 134.62,114.89 v2(134.65,114.86)
  L6 w0.2: v3(135.5,97.65) 135.06,97.21 135.06,93.27 v2(135.2,93.12) v3(135.5,92.83) ; v2(129.1,92.67) v3(129.1,93.02) 129.1,97.71 v3(128.98,97.82)
  L6 w0.25: v3(92.81,78.23) v2(93.24,78.23) ; v3(92.08,67.15) 91.52,66.59 91.52,63.57 v2(91.25,63.3)
  L6 w0.3: v3(53,113.82) 53,112.87 52.45,112.32 52.45,109.72 47.8,105.07 v3(47.8,104.77) ; v2(135.6,105.45) 135.05,106 v2(135.05,108.5) 135.05,111.87 v2(134.68,112.24) 134.65,112.27 v2(134.65,114.86)
  BOTTOM w0.1: v3(56.42,42.89) 56.5,42.89 C808.1 ; JP505.1 100.14,88.39 100.35,88.6 100.35,89.2 ; 107.81,113.16 107.79,113.16 v3(107.72,113.09) ; v3(53,113.82) 52.99,113.81 C826.1
  BOTTOM w0.2: v3(129.1,93.02) 129.07,93.04 C3439.1 128.83,92.88 U3414.1 ; 55.1,65.02 55.1,64.64 54.83,64.37 U3200.7 ; U3406.6 134.8,97.66 134.8,97.65 C3426.1 ; U3412.1 135.38,92.71 v3(135.5,92.83) ; C3433.1 128.69,97.73 U3410.6 ; U3408.6 111.46,89.21 C3430.1 111.04,88.45 105.15,88.45 103.95,89.65
  BOTTOM w0.25: R515.1 v3(92.81,78.23) ; 53.58,51.52 C823.1
  BOTTOM w0.3: v3(130.9,101.8) 134.4,101.8 135,101.2 C3424.2 U3407.14 ; U3413.14 C3437.2 105,102.5 v3(104.1,103.4) ; v3(54.61,51.62) 54.47,51.76 R898.1 ; v3(55.09,65.01) 55.1,65.02 ; U805.5 53.58,51.52 ; U3409.14 C3431.2 ; C513.1 103.65,92.05 105.05,93.45 105.05,93.6 C3434.2 U3411.14
  vias: v1(39.25,120.04) v1(39.25,119.77) v1(39.26,119.47) v1(39.55,120.04) v1(39.56,119.77) v1(39.56,119.47) v1(39.89,120.06) v1(39.89,119.78) v1(39.9,119.49) v1(96.35,91.35) v1(105.27,91.48) v1(105.27,91.22) v1(105.28,90.95) v1(105.27,90.69) v1(105.52,91.48) v1(105.52,91.22) v1(105.52,90.95) v1(105.52,90.69) v1(105.76,91.49) v1(105.76,91.22) v1(105.76,90.96) v1(105.76,90.7) v1(106.01,91.49) v1(106,91.23) v1(106.01,90.96) v1(106,90.7) v1(125.35,38.42) v1(127.92,38.59) v1(128.16,38.59) v1(128.16,38.36) v1(137.47,29.01) v1(141.55,92.05) v1(141.55,91.75) v1(141.85,92.05) v1(141.85,91.75) v1(150.99,28.36) v2(43.31,118.52) v2(43.74,118.53) v2(53.85,118.37) v2(53.85,117.72) v2(54.45,118.37) v2(54.45,117.72) v2(55.02,63.81) v2(55.27,63.37) v2(101.44,63.8) v2(103.07,93.72) v2(103.07,93.29) v2(103.06,92.83) v2(103.06,92.39) v2(103.08,91.94) v2(103.09,91.49) v2(103.09,91.04) v2(103.07,66.32) v2(103.08,65.86) v2(103.07,65.43) v2(103.53,118.95) v2(103.51,118.5) v2(103.5,93.73) v2(103.5,93.29) v2(103.49,92.83) v2(103.49,92.39) v2(103.51,91.95) v2(103.51,91.49) v2(103.51,91.04) v2(103.52,66.32) v2(103.51,65.86) v2(103.51,65.44) v2(103.73,118.09) v2(103.94,118.51) v2(103.93,93.73) v2(103.93,93.29) v2(103.91,92.83) v2(103.91,92.4) v2(103.93,91.95) v2(103.94,91.49) v2(103.94,91.04) v2(103.96,118.95) v2(103.98,117.7) v2(103.96,66.31) v2(103.96,65.87) v2(103.96,65.44) v2(104.15,118.09) v2(104.34,92.84) v2(104.34,92.4) v2(104.4,118.96) v2(104.39,118.52) v2(104.41,117.7) v2(104.35,93.73) v2(104.35,93.3) v2(104.36,91.95) v2(104.37,91.5) v2(104.37,91.05) v2(104.41,66.31) v2(104.41,65.88) v2(104.41,65.45) v2(104.6,118.1) v2(104.83,118.96) v2(104.82,118.52) v2(104.85,117.71) v2(105.03,118.1) v2(105.28,117.71) v2(107.84,116.65) v2(108.34,116.66) v2(114.91,116.67) v2(115.4,116.68) v2(122.56,116.6) v2(123.06,116.6) v2(126.54,66.42) v2(126.54,65.98) v2(126.54,65.55) v2(126.98,66.42) v2(126.98,65.98) v2(126.98,65.56) v2(127.43,66.43) v2(127.43,65.99) v2(127.43,65.56) v2(127.55,38.41) v2(127.69,37.96) v2(127.88,66.44) v2(127.88,66) v2(127.88,65.57) v2(128.15,37.97) v2(130.83,116.64) v2(131.32,116.65) v3(53.3,113.82) v3(53.6,113.82) v3(53.6,113.52) v3(53.9,113.82) v3(53.9,113.52) v3(54.61,51.35) v3(54.9,65.22) v3(56.74,42.89) v3(100.75,92.55) v3(100.75,92.3) v3(100.75,92.05) v3(100.75,91.8) v3(100.75,91.55) v3(101,92.55) v3(101,92.3) v3(101,92.05) v3(101,91.8) v3(101,91.55) v3(101.25,92.55) v3(101.25,92.3) v3(101.25,92.05) v3(101.25,91.8) v3(101.25,91.55) v3(101.5,92.55) v3(101.5,92.3) v3(101.5,92.05) v3(101.5,91.8) v3(101.5,91.55) v3(101.75,92.55) v3(101.75,92.3) v3(101.75,92.05) v3(101.75,91.8) v3(101.75,91.55) v3(102,92.55) v3(102,92.3) v3(102,92.05) v3(102,91.8) v3(102,91.55) v3(102.35,92.55) v3(102.35,92.3) v3(102.35,92.05) v3(102.35,91.8) v3(102.35,91.55) v3(102.55,92.55) v3(102.55,92.3) v3(102.55,92.05) v3(102.55,91.8) v3(102.55,91.55) v3(102.75,92.55) v3(102.75,92.3) v3(102.75,92.05) v3(102.75,91.8) v3(102.75,91.55) v3(107.99,113.09) v3(114.78,113.1) v3(115.06,113.1) v3(122.44,113.03) v3(122.71,113.03) v3(124.67,101.23) v3(124.95,101.23) v3(130.7,113.13) v3(131.01,113.14)
VREG_SUB_5P0: length 357.9
  TOP w0.1: v1(139.34,107.83) 139.45,107.72 C2700.2
  TOP w0.3: U2703.6 C2707.2 ; R3118.2 42.54,62.42 v1(42.53,62.41) ; U1801.3 v1(130.85,51.17)
  TOP w0.45: v1(165.88,119.34) 165.83,119.29 U2701.6
  L3 w0.1: v2(122.97,68.49) 91.38,68.49 v2(91.23,68.34)
  L3 w0.3: v1(42.53,62.41) 43.05,61.89 44.93,61.89 49.73,57.09 53.36,57.09 v2(53.51,56.94) 53.77,57.2 118.92,57.2 119.2,56.91 120.34,56.91 120.77,57.35 v2(123.19,57.35) ; v1(130.85,51.17) 130.44,50.76 128.06,50.76 v1(127.65,51.17) 126.71,52.1 v2(125.01,52.1) ; v2(92.01,79.09) 92.33,79.42 124.76,79.42 v2(125.15,79.81) ; v2(124.99,18.14) 139.89,18.14 148.11,9.92 171.3,9.92 171.8,9.42 180.31,9.42 v1(181.17,8.56)
  L3 w0.4: v2(136.78,107.72) v2(132.16,107.72) 124.97,107.72 124.78,107.53 v2(124.57,107.53) 124.16,107.53 123.66,108.02 117.54,108.02 v2(117.5,107.98)
  L3 w0.5: v1(165.88,119.34) 164.98,119.34 164.33,119.99 159.14,119.99 156.02,116.86 150.07,116.86 v2(150.05,116.88)
  L6 w0.1: v2(91.23,68.34) 90.94,68.05 v3(90.94,67.81) ; v2(122.97,68.49) v3(122.97,68.85)
  L6 w0.3: v3(91.79,78.24) 91.79,78.27 92.01,78.49 v2(92.01,79.09) ; v2(132.16,107.72) 132.16,108.05 v3(132.17,108.05) ; v2(123.19,57.35) 123.19,57.71 123.12,57.78 123.12,59.16 123.14,59.17 v3(123.14,59.43) ; v3(125.01,56.39) 125.01,52.1 v2(125.01,52.1) 125.01,51.99 124.98,51.96 124.98,49.92 124.31,49.24 124.31,33.81 124.99,33.13 v2(124.99,18.14) ; v2(150.05,116.88) 150.05,112.41 v2(149.89,112.26) 149.88,112.24 v2(149.88,102.5) 149.88,100.52 149.86,100.5 149.86,99.39 149.81,99.35 v2(149.81,98.99)
  L6 w0.4: v2(136.78,107.72) 136.78,107.69 136.84,107.63 136.84,99.79 v2(136.77,99.71) ; v2(117.5,107.98) 117.47,107.95 v3(117.01,107.95) ; v2(124.57,107.53) 124.57,107.92 v3(124.55,107.94)
  L7 w0.4: v7(109.75,107.94) 110.76,108.95 116.01,108.95 v3(117.01,107.95) ; v7(136.8,73.24) 132.37,73.24 v7(132.34,73.28) 128,73.28 v7(127.36,73.92)
  BOTTOM w0.1: JP502.1 122.69,62.15
  BOTTOM w0.3: C3408.2 124.61,107.99 U3402.3 ; v3(132.17,108.05) 132.65,108.05 C3401.2 132.8,108 U3400.3 ; C3415.2 117.04,107.99 U3404.3 ; R502.2 v3(91.79,78.24) ; U2500.5 123.79,55.88 123.84,55.93 C2500.2 ; U3405.3 109.8,107.99 v7(109.75,107.94)
  BOTTOM w0.45: U2502.6 132.42,73.37 C2509.2 ; U2501.6 136.87,73.32 v7(136.8,73.24)
  vias: v1(139,107.82) v1(139,107.54) v1(139.35,107.54) v1(150.27,102.51) v1(150.48,102.51) v1(150.85,102.52) v1(151.13,102.51) v1(151.16,113) v1(151.16,112.67) v1(151.16,112.33) v1(151.6,112.31) v1(165.57,120.14) v1(165.56,119.85) v1(165.89,120.15) v1(165.89,119.84) v2(53.97,56.91) v2(122.76,57.35) v2(125.14,81.09) v2(125.14,80.66) v2(125.15,80.24) v2(125.36,100.18) v2(125.37,99.75) v2(125.37,99.33) v2(125.37,98.9) v2(125.58,81.09) v2(125.58,80.66) v2(125.58,80.24) v2(125.59,79.81) v2(125.8,100.18) v2(125.8,99.75) v2(125.8,99.33) v2(125.81,98.9) v2(126.04,81.08) v2(126.04,80.65) v2(126.04,80.23) v2(126.05,79.8) v2(126.26,100.17) v2(126.26,99.74) v2(126.26,99.32) v2(126.27,98.89) v2(126.47,81.08) v2(126.48,80.65) v2(126.48,80.23) v2(126.48,79.8) v2(126.69,100.17) v2(126.7,99.74) v2(126.7,99.32) v2(126.7,98.89) v2(126.92,81.1) v2(126.93,80.67) v2(126.93,80.24) v2(126.93,79.82) v2(127.14,100.19) v2(127.15,99.76) v2(127.15,99.33) v2(127.15,98.91) v2(127.38,81.1) v2(127.38,80.68) v2(127.38,80.25) v2(127.39,79.82) v2(127.6,100.19) v2(127.6,99.77) v2(127.6,99.34) v2(127.61,98.91) v2(127.82,81.1) v2(127.83,80.68) v2(127.83,80.25) v2(127.83,79.82) v2(128.05,100.19) v2(128.04,99.34) v2(128.05,99.77) v2(128.06,98.91) v2(149.34,98.98) v2(149.34,98.52) v2(149.44,112.79) v2(149.42,112.25) v2(149.44,102.5) v2(149.43,102.04) v2(149.57,116.9) v2(149.6,116.37) v2(149.81,98.53) v2(149.94,112.79) v2(149.89,102.04) v2(150.05,116.37) v3(53.45,56.32) v3(53.71,56.31) v3(122.86,59.44) v3(125.69,79.44) v3(125.68,79.21) v3(125.68,78.98) v3(125.69,78.74) v3(125.92,79.44) v3(125.92,79.21) v3(125.91,78.98) v3(125.92,78.74) v3(126.15,79.2) v3(126.14,78.97) v3(126.15,79.43) v3(126.15,78.73) v3(126.38,79.42) v3(126.38,79.19) v3(126.37,78.97) v3(126.38,78.73) v3(126.64,79.42) v3(126.63,79.19) v3(126.63,78.97) v3(126.63,78.73) v3(126.87,79.42) v3(126.86,79.19) v3(126.86,78.97) v3(126.87,78.73) v3(127.1,79.42) v3(127.09,79.19) v3(127.09,78.96) v3(127.1,78.72) v3(127.33,79.41) v3(127.32,79.18) v3(127.32,78.96) v3(127.33,78.72)
VREG_SW_A_1P8: length 106.4
  TOP w0.3: R3100.2 28.47,94.8 28.73,94.54 30.1,94.54 30.4,94.24 30.4,92.65 30.18,92.42 29.32,92.42 R3103.2 29.32,89.56 30.3,88.57 30.3,87 30.06,86.75 29.35,86.75 R3106.2 29.33,83.66 30.3,82.69 30.3,81.42 30,81.12 29.37,81.12 R3109.2 29.36,78.32 30.45,77.23 30.45,75.91 30.08,75.55 29.35,75.55 v1(29.35,75.54) 29.35,72.29 30.36,71.28 30.36,69.51 30.14,69.29 29.33,69.29 R3221.2 29.31,66.21 30.35,65.18 30.35,63.91 29.87,63.43 29.35,63.43 R3224.2 29.35,59.3 30.21,58.43 30.21,56.94 29.98,56.72 29.35,56.72 R3227.2
  L3 w0.4: v1(29.35,75.54) 32.49,75.54 v2(33.77,76.82)
  L5 w0.4: v2(33.77,76.82) v2(33.77,80.03)
  L5 w0.5: v2(33.77,80.03) 33.83,80.09 33.83,103.71 v2(33.47,104.07) 35.72,106.32 v2(36.7,106.32)
  L6 w0.2: v3(57.45,105.42) 57.2,105.17 52.65,105.17 51.2,103.72 46.8,103.72 v3(44.65,105.87)
  L6 w0.3: v3(31.71,77.66) 31.93,77.66 32.78,76.82 v2(33.77,76.82)
  L6 w0.5: v2(33.47,104.07) 34.11,104.07 v3(34.14,104.1)
  BOTTOM w0.1: v3(34.14,104.1) 34.22,104.1 34.25,104.07 C2903.1
  BOTTOM w0.3: C3003.1 33.61,79.7 v3(33.7,79.62) 33.7,79.33 B3002.2 ; B3000.1 32.48,76.89 C3015.1 ; B2900.1 35.09,103.29 C2903.1
  vias: v3(33.5,79.82) v3(37.15,106.37) v3(37.15,106.07) v3(37.45,106.37) v3(37.45,106.07)
N3044471: length 1.6
  BOTTOM w0.2: R2506.2 138.94,51.91 U2503.5
N3044743: length 1.6
  BOTTOM w0.1: R2509.1 136.45,48.9 U2503.8
N3044747: length 1.5
  BOTTOM w0.1: R2508.1 135.95,48.55 U2503.9
N3044805: length 2.6
  BOTTOM w0.1: R2505.1 134.75,46.99 C2518.1 134.72,46.27 Y2500.3
N22882278: length 20.4
  L5 w0.1: v2(33.88,75.83) 33.99,75.83 33.99,74.05 34.48,73.56 34.48,66.55 35.37,65.66 v2(35.37,65.23)
  L6 w0.1: v3(35.37,64.42) v2(35.37,65.23) ; v2(33.88,75.83) 33.55,75.83 33.14,76.24 v3(33.12,76.24)
  BOTTOM w0.1: C3007.1 35.84,64.87 35.84,65.51 36.55,66.22 U3000.8 ; U3000.24 36.2,72.5 35.44,73.26 35.44,73.76 C3006.1 34.95,74.38 C3005.1 C3004.1 33.74,75.63 v3(33.12,76.24)
N22883057: length 3.4
  BOTTOM w0.2: U3000.48 45.25,69.99 C3026.1
  BOTTOM w0.3: C3026.1 C3025.1 47.03,71.81 B3003.2
N22883763: length 2.3
  BOTTOM w0.1: U3000.63 41.75,62.67 R3019.1
N22883931: length 0.7
  BOTTOM w0.1: C3038.2 R3023.2
N23918883: length 9.7
  BOTTOM w0.2: 131.9,29.3 131.9,21.3 R523.1
N23919030:
  vias: v6(164.2,18) v6(164.2,17.5) v6(164.2,17) v6(164.7,18) v6(164.7,17.5) v6(164.7,17) v6(165.2,18) v6(165.2,17.5) v6(165.2,17) v6(165.7,18) v6(165.7,17.5) v6(165.7,17) v6(166.2,18) v6(166.2,17.5) v6(166.2,17) v6(166.7,18) v6(166.7,17.5) v6(166.7,17) v6(167.2,18) v6(167.2,17.5)
N23963220: length 2.4
  BOTTOM w0.2: CN2300.1 144.04,34.4 R2300.2
N23963553: length 1.1
  TOP w0.1: U2301.5 131.66,48.63 R2307.2
N23964057: length 2.6
  BOTTOM w0.3: R2308.2 162.54,34.95 CN2300.75
N23964138: length 1.2
  TOP w0.1: U2302.5 R2309.1
N25168509: length 3.1
  BOTTOM w0.1: U3000.20 34.78,71.05 34.66,71.17 32.18,71.17 31.9,71.45 R3018.1
N25169488: length 2.5
  BOTTOM w0.1: R3021.1 41.16,62.54 41.16,62.54 U3000.64
N25172249: length 1.4
  BOTTOM w0.4: L3007.1 17.62,56.95 R3022.1
N25173784: length 0.7
  BOTTOM w0.1: C3031.2 R3011.2
N25174288: length 1.5
  BOTTOM w0.4: L3001.1 R3000.1
N25174376: length 0.7
  BOTTOM w0.1: C3009.2 R3002.2
N25174459: length 1.5
  BOTTOM w0.4: R3003.1 15.67,66.94 L3003.1
N25174547: length 0.7
  BOTTOM w0.1: C3023.2 R3006.2
N25176689: length 4.9
  BOTTOM w0.1: 41.35,64.48 42.57,63.26 42.57,63.22 43.18,62.62 43.18,62.58 43.8,61.96 ; 41.35,64.48 41.09,64.21 40.91,64.21 U3000.62 ; 41.35,64.48 U3000.61
N25188010: length 2.8
  BOTTOM w0.2: R3200.2 56.67,60.89 C3229.1 R3202.1 U3200.1
N25188016: length 2.8
  BOTTOM w0.2: R3203.1 U3200.3
  BOTTOM w0.4: R3203.1 53.96,60.88 R3201.2 53.13,60.87 C3210.2
N25188197: length 3.1
  BOTTOM w0.2: U3201.3 48.36,105.27 48.62,105.01 R3204.2 R3205.2
N25190337: length 4.2
  BOTTOM w0.1: R3005.1 30.18,70.85 R3015.2 29.74,71.25 C3033.1 29.53,72.11 28.79,72.86 27.91,72.86 Y3000.3
N25191057: length 1.6
  BOTTOM w0.2: U3202.3 56.62,105.39 R3208.2
N25264603: length 1.6
  BOTTOM w0.4: L2901.1 16.05,97.78 R2900.1
N25264626: length 20.2
  L5 w0.1: v2(37.19,100.82) 37.48,100.53 v2(37.48,91.2)
  L6 w0.1: v3(35.73,102.66) 35.73,102.64 37.19,101.18 v2(37.19,100.82) ; v3(37.99,90.82) 37.85,90.82 v2(37.48,91.2)
  BOTTOM w0.1: U2900.8 39.16,92.63 38.34,91.81 38.34,91.17 C2907.1 37.99,90.82 v3(37.99,90.82) ; U2900.24 38.81,98.91 38.05,99.66 38.05,100.25 C2906.1 36.95,101.35 C2905.1 C2904.1 36.35,102.03 B2900.2
N25264845: length 0.7
  BOTTOM w0.1: C2909.2 R2902.2
N25264985: length 3.1
  BOTTOM w0.1: U2900.61 43.96,90.88 43.7,90.62 43.52,90.62 U2900.62
  BOTTOM w0.25: U2900.62 43.26,90.88 43.62,90.52 44.06,90.52 44.07,90.53 ; U2900.61 43.62,91.23 44.1,90.75
N25265133: length 1.5
  BOTTOM w0.4: L2903.1 17.48,91.83 R2903.1
N25265238: length 3.8
  BOTTOM w0.2: C2922.1 49.22,97.84 49.22,97.76 U2900.48
  BOTTOM w0.3: C2922.1 49.26,97.9 49.82,98.47 C2923.1 49.85,98.5 50.44,99.08 B2903.2
N25265360: length 0.7
  BOTTOM w0.1: C2926.2 R2905.2
N25265700: length 0.7
  BOTTOM w0.1: C2931.2 R2908.2
N25265812: length 1.5
  BOTTOM w0.4: L2907.1 17.33,81.87 R2909.1
N25265948: length 6.8
  BOTTOM w0.1: U2900.63 43.52,89.91 43.52,84.87 R2911.2
N25265950: length 3.1
  BOTTOM w0.1: U2900.20 37.39,97.47 37.25,97.61 34.77,97.61 34.52,97.87 R2912.1
N25265958: length 0.7
  BOTTOM w0.15: C2938.2 R2914.2
N25265985: length 5.8
  BOTTOM w0.1: R2913.2 42.92,85.6 42.92,89.8 U2900.64
N25266143: length 4.3
  BOTTOM w0.1: Y2900.3 30.53,99.28 31.41,99.28 32.14,98.55 C2941.1 R2915.2 32.74,97.26 33.22,96.78 R2920.1
N25532487: length 2.6
  BOTTOM w0.1: U500.6 91.76,77.33 91.81,77.38 R502.1 91.81,77.44 C504.2
N25532654: length 7
  BOTTOM w0.1: D503.2 96.21,64.99 95.22,65.99 95.22,66.22 95.22,66.22 C508.1 95.22,70.1 94.86,70.46 U500.20
N25532696: length 5.5
  BOTTOM w0.2: C506.2 95.92,77.51 96.66,77.51 97.06,77.11 97.06,76.12 D504.2 95.93,74.96 U500.11
N25532700: length 4.5
  BOTTOM w0.2: 95.7,79.11 95.11,78.52 C506.1 95.11,76.95 94.71,76.56 94.41,76.56 93.76,75.91 U500.10
N25532746: length 17.1
  L3 w0.2: v2(100.83,66.98) 100.77,66.98 100.77,66.98 v2(92.79,66.98)
  L6 w0.2: v3(92.79,66.61) v2(92.79,66.98) ; v8(100.75,63.55) 100.74,63.56 100.74,66.9 v2(100.83,66.98)
  L7 w0.2: v7(102.78,63.55) v8(100.75,63.55)
  BOTTOM w0.2: U500.23 92.76,66.63 v3(92.79,66.61)
N25532752: length 3.3
  BOTTOM w0.2: U500.22 93.26,67.66 93.65,67.27 R503.1
N25532754: length 2.3
  BOTTOM w0.2: R505.1 94.35,77.04 93.26,75.95 U500.9
N25532756: length 5.2
  BOTTOM w0.2: U500.8 92.76,76.24 93.55,77.04 R505.2 93.55,77.8 95.03,79.28 95.03,79.83 Q501.4
N25532835: length 3.5
  BOTTOM w0.1: 120.07,63.11 120.07,63.11 JP503.1
  BOTTOM w0.2: 120.07,66.12 120.07,63.11
N25532881: length 1.7
  BOTTOM w0.1: 99.35,86.93 100.62,86.93 100.9,86.65
N25533142: length 37.5
  L3 w0.1: v2(120.03,64.01) 119.85,63.83 102.81,63.83 101.65,64.99 90.42,64.99 v2(90.23,65.18)
  L6 w0.1: v3(90.76,69.72) 90.76,69.54 90.34,69.12 90.34,65.29 v2(90.23,65.18) ; v3(120.08,62.1) 120.15,62.17 120.15,63.9 120.04,64.01 120.04,64.01 v2(120.03,64.01)
  BOTTOM w0.1: U500.27 90.76,69.72 v3(90.76,69.72) ; JP503.2 120.07,62.23 120.08,62.22 v3(120.08,62.1)
N25533144: length 19.9
  L3 w0.1: v2(98.75,87.2) 98.5,87.45 97.75,87.45 97.09,86.79 91.72,86.79 91.15,86.22 v2(90.92,86.22)
  L6 w0.1: v2(90.92,86.22) 90.91,86.22 90.91,75.76 v3(90.76,75.61) ; v3(99,87.45) v2(98.75,87.2)
  BOTTOM w0.1: v3(90.76,75.61) U500.4 ; JP504.2 99.11,87.45 v3(99,87.45)
N25533146: length 37.7
  L3 w0.1: v2(120.46,64.3) 120.35,64.41 119.85,64.41 119.51,64.07 102.88,64.07 101.69,65.26 90.8,65.26 v2(90.71,65.35)
  L6 w0.1: v2(120.46,64.3) 120.46,63.98 120.37,63.89 120.37,62.17 v3(120.44,62.1) ; v3(91.25,69.72) 91.22,69.72 90.55,69.04 90.55,65.51 v2(90.71,65.35)
  BOTTOM w0.1: v3(120.44,62.1) 120.45,62.1 120.5,62.15 JP502.2
N25533148: length 20.3
  L3 w0.1: v2(91.13,86.7) 91.14,86.7 91.14,86.69 91.22,86.69 91.58,87.05 96.95,87.05 97.6,87.7 98.4,87.7 v2(98.75,88.05)
  L6 w0.1: v3(91.25,75.6) 91.11,75.74 91.11,85.88 91.27,86.04 91.27,86.56 91.14,86.69 91.14,86.7 v2(91.13,86.7) ; v3(99,87.8) v2(98.75,88.05)
  BOTTOM w0.1: v3(99,87.8) 99.05,87.8 JP505.2
N25533161: length 2.1
  BOTTOM w0.1: U500.33 R509.2
N25533188: length 2.2
  BOTTOM w0.1: U500.34 86.89,71.96 R510.2
N25533212: length 4.9
  BOTTOM w0.2: U500.32 87.89,70.96 86.94,70.01 C522.2 86.44,70.6 86.21,70.83 85.07,70.83 R511.2
N25533238: length 2.4
  BOTTOM w0.1: U500.38 87.44,73.96 C523.2
N25533248: length 2.3
  BOTTOM w0.1: R513.1 87.12,73.46 U500.37
N25533252: length 0.7
  BOTTOM w0.1: C521.2 87.63,67 R512.2
N25562945: length 4.3
  TOP w0.1: U2300.3 125.85,38.72 125.15,39.42 R2301.2 C2399.2 R2399.2 R2303.2
N25563127: length 1.1
  TOP w0.1: U2300.6 C2301.2
N25637707: length 1.6
  BOTTOM w0.1: U2800.4 83.91,97.61 C2810.1
N25637709: length 7.1
  BOTTOM w0.3: C2811.1 86.8,109.55 83.91,106.66 U2800.25
N25637856: length 4.9
  BOTTOM w0.3: U2800.22 81.96,109.43 C2816.1
N25637860: length 0.8
  BOTTOM w0.3: R2801.2 C2818.2
N25637862: length 0.8
  BOTTOM w0.3: R2802.2 C2819.2
N25637887: length 4.9
  BOTTOM w0.3: C2817.1 81.31,109.42 U2800.21
N25638044: length 2.5
  BOTTOM w0.1: U2800.13 78.06,98.4 77.5,97.84 76.99,97.84 C2829.2
N25640522: length 7
  BOTTOM w0.3: CM3400.4 134.4,119.41 133.59,120.22 C3405.1 133.65,120.83 133.65,121.53 TVS3400.2 133.56,121.7 134.07,122.21 D3400.2 134.34,124.93 134.34,125.57 R3401.1
N25640641: length 6.9
  BOTTOM w0.3: R3402.1 132.03,125.56 132.03,124.86 132.17,124.71 D3400.1 132.17,122.29 132.76,121.7 TVS3400.1 132.76,121.63 132.76,120.83 C3404.1 132.7,120.23 131.9,119.43 CM3400.3
N25640986: length 6.9
  BOTTOM w0.3: R3404.1 126.11,125.54 126.11,124.91 D3401.2 125.87,122.22 125.36,121.71 TVS3401.2 125.36,120.82 C3412.1 125.39,120.17 CM3401.4
N25641163: length 6.9
  BOTTOM w0.3: CM3401.3 124.5,120.16 C3411.1 124.56,120.84 TVS3401.1 124.56,121.71 123.97,122.3 D3401.1 123.97,124.71 123.77,124.91 123.77,125.54 R3405.1
N25641540: length 6.9
  BOTTOM w0.3: R3406.1 118.47,124.84 D3402.2 118.29,122.15 TVS3402.2 117.78,120.82 C3417.1 117.81,120.18 CM3402.4
N25641678: length 6.9
  BOTTOM w0.3: CM3402.3 116.92,120.17 C3416.1 116.98,120.84 TVS3402.1 116.39,122.23 D3402.1 116.14,124.91 R3407.1
N25641706: length 2.7
  BOTTOM w0.3: U3404.7 117.69,113.66 118.62,114.59 CM3402.1
N25641715: length 2.7
  BOTTOM w0.3: U3404.6 117.04,113.67 116.12,114.59 CM3402.2
N25641918: length 6.9
  BOTTOM w0.3: CM3403.4 110.58,120.16 C3422.1 110.54,120.8 TVS3403.2 111.05,122.13 D3403.2 111.29,124.88 R3408.1
N25642005: length 6.9
  BOTTOM w0.3: CM3403.3 109.68,120.15 C3421.1 109.74,120.83 TVS3403.1 109.15,122.21 D3403.1 108.96,124.84 R3409.1
N25650762: length 1.8
  BOTTOM w0.1: U2500.3 121.89,52.11 121.39,51.61 R2502.1
N25684206: length 1.4
  TOP w0.1: U3100.4 R3102.2
N25684210: length 1.2
  TOP w0.1: U3100.12 26.63,98.15 C3102.1
N25684394: length 1.4
  TOP w0.1: R3105.2 26.41,94.94 U3101.4
N25684398: length 1.2
  TOP w0.1: C3105.1 26.86,90.6 U3101.12
N25684585: length 1.4
  TOP w0.1: U3102.4 R3108.2
N25684589: length 1.3
  TOP w0.1: C3108.1 26.88,84.81 U3102.12
N25684764: length 1.4
  TOP w0.1: U3103.4 R3111.2
N25684768: length 1.3
  TOP w0.1: U3103.12 26.91,79.2 C3111.1
N26057362: length 2
  TOP w0.2: U3901.7 R3909.1
N26057367: length 2
  TOP w0.2: U3901.6 130.19,111.19 R3910.1
N26072794: length 1.6
  BOTTOM w0.4: R3009.1 17.83,61.49 L3005.1
N26101223: length 2.1
  BOTTOM w0.1: R601.1 73.05,54.11 72.65,54.51 U600.17
N26101225: length 7.7
  L6 w0.1: v3(75.65,54.32) 78.51,57.18 v3(80.61,57.18)
  BOTTOM w0.1: v3(75.65,54.32) 75.44,54.11 R601.2
N26101344: length 0.1
  BOTTOM w0.1: JP600.1 68.25,59.67
N26101394: length 1.9
  BOTTOM w0.2: U600.15 70.79,56.46 71.64,57.31
N26101396: length 4.3
  BOTTOM w0.2: R606.2 72.45,58.92 72.45,60.67 72.97,61.19 Q601.4
N26222143: length 1.5
  TOP w0.1: U3500.21 R3509.2
N26222279: length 3.6
  TOP w0.1: R3515.2 86.55,95.2 87.55,95.2 87.65,95.1 R3518.2 88.2,94.75 88.35,94.9 U3500.16
N26222312: length 3.7
  TOP w0.1: R3516.2 86.55,96.15 87.55,96.15 87.65,96.05 R3519.2 87.95,95.4 U3500.15
N26222402: length 4.7
  TOP w0.1: U3500.1 93.7,93.9 C3517.2 C3516.1 B3501.1 B3500.2
N26222404: length 5.2
  TOP w0.1: TP3504.1 B3501.2 95.42,94.05 C3518.1 94.47,94.03 C3519.2 94,94.05 93.65,94.4 U3500.2
N26222408: length 3.9
  TOP w0.1: U3500.24 92.25,92.15 C3521.2 92.7,90.83 C3520.1 92.78,89.62 TP3506.1
N26226644: length 1.8
  TOP w0.1: U3500.3 93.5,94.9 C3513.1
N26230034: length 1.4
  TOP w0.1: R3528.1 48.38,113.37 U3501.7
N26230040: length 1.7
  TOP w0.1: R3529.2 54.8,111.87 U3501.21
N26230064: length 4.5
  TOP w0.1: U3501.20 54.13,111.37 54.7,110.79 55.15,110.79 R3530.2 55.17,111.19 55.34,111.35 56.74,111.35 TP3511.1
N26230092: length 1.4
  TOP w0.1: R3531.1 49.25,112.37 U3501.9
N26230149: length 4
  TOP w0.1: U3501.16 51.85,109.12 52.1,108.87 R3532.2 52.46,108.49 52.63,108.32 52.63,107.47 R3535.2
N26230155: length 1.4
  TOP w0.1: R3533.1 49.25,111.37 U3501.11
N26230181: length 3.9
  TOP w0.1: U3501.15 51.35,109.02 51.2,108.87 R3534.2 51.56,108.49 51.66,108.39 51.66,107.4 R3536.2
N26230210: length 2.5
  TOP w0.1: U3501.13 50.35,110.04 50.12,109.81 48.81,109.81 48.35,110.27 R3537.1
N26230251: length 5
  TOP w0.2: B3503.2 B3504.1 53.58,117.74 C3529.1 53.57,116.82 C3530.2 52.85,115.19 U3501.1
N26230253: length 5
  TOP w0.2: U3501.2 52.35,115.19 52.53,115.37 C3532.2 52.53,116.75 52.58,116.8 52.58,117.64 B3504.2 52.7,118.82 TP3512.1
N26230259: length 4.3
  TOP w0.1: U3501.24 53.73,113.37 54.41,114.05 C3534.2 55.18,114.02 C3533.1 57.06,114.02 TP3513.1
N26233322: length 1.3
  TOP w0.1: R3633.2 133.85,9.85 U3607.2
N26233345: length 1.3
  TOP w0.1: U3607.1 133.05,9.87 R3634.2
N26766233: length 2.2
  TOP w0.1: C3526.1 50.97,115.79 51.85,114.92 U3501.3
N26905827: length 1.9
  TOP w0.2: U4000.1 144.15,115.59 C4000.2
N26905839: length 3.2
  L3 w0.25: v1(142.3,116.89) 143.66,116.89 v1(144.95,115.6)
N26905984: length 2
  TOP w0.2: U4000.2 143.95,116.24 C4002.2
N26906021: length 2
  TOP w0.2: C4003.1 144.15,118.19 U4000.5
N26906023: length 2
  TOP w0.2: U4000.4 144.2,117.54 C4003.2
N26906050: length 2
  TOP w0.2: U4000.6 143.9,118.84 C4004.2
N26907248: length 1.3
  TOP w0.1: R4007.2 129.43,103.08 U4002.9
N26907250: length 1.1
  TOP w0.1: U4001.2 136.6,105.37 R4008.1
N26907266: length 1.1
  TOP w0.1: U4002.2 131.1,105.37 R4009.1
N26908132: length 1.9
  TOP w0.2: R4000.2 134.65,117.54 U4000.13
N26908161: length 1.9
  TOP w0.2: R4001.2 134.65,118.84 U4000.11
N26911241: length 1
  BOTTOM w0.1: Y2901.3 31.27,95.73 31.56,95.73 R2924.1
N26968575: length 3.9
  BOTTOM w0.1: TP603.1 70.48,48.47 70.48,51.32 70.29,51.51 U600.2
N26969087: length 0.8
  BOTTOM w0.1: R614.2 C622.1
N27485617: length 1.8
  BOTTOM w0.2: U3202.4 56.62,100.79 57.12,100.29 C3221.1
N27611972: length 1.6
  TOP w0.3: R3502.2 C3500.2 R3503.1
N27612003: length 1.6
  TOP w0.3: R3504.2 R3500.2 R3503.2
N27612020: length 0.9
  TOP w0.3: 85.15,115.08 R3502.1
N27612030: length 0.8
  TOP w0.3: C3502.1 R3504.1
N27612076: length 0.9
  TOP w0.3: C3503.2 R3510.1
N27612078: length 1.6
  TOP w0.3: R3510.2 C3505.1 R3505.1
N27612084: length 1.6
  TOP w0.3: R3511.2 R3508.1 R3505.2
N27612090: length 0.8
  TOP w0.3: C3504.1 R3511.1
N27617228: length 1.6
  TOP w0.3: R3520.2 C3506.2 R3521.1
N27617259: length 1.6
  TOP w0.3: R3522.2 R3517.2 R3521.2
N27617284: length 0.9
  TOP w0.3: C3508.2 R3520.1
N27617294: length 0.8
  TOP w0.3: R3522.1 C3509.1
N27617350: length 0.9
  TOP w0.3: C3510.2 R3523.1
N27617352: length 1.6
  TOP w0.3: R3523.2 C3512.1 R3524.1
N27617358: length 1.6
  TOP w0.3: R3525.2 R3526.1 R3524.2
N27617364: length 0.8
  TOP w0.3: R3525.1 C3511.1
N28164996: length 1.4
  TOP w0.1: R3635.1 134.65,16.06 U3607.7
N28165018: length 1.3
  TOP w0.1: U3607.5 136.35,13 136.4,13.05 R3636.1
N28259089: length 1.4
  TOP w0.1: R3629.2 133.05,16.09 U3607.9
N28338475: length 1.5
  BOTTOM w0.4: L2905.1 15.93,87.75 R2906.1
N28382907: length 1.2
  BOTTOM w0.2: C3205.2 44.77,105.27 U3201.6
N28694641: length 5.5
  BOTTOM w0.2: U802.3 54.65,39.33 54.57,39.25 54.57,39.22 54.2,38.86 R805.2 54.18,38.86 R808.1 51.61,38.86 51.27,39.19 51.27,40.5 C812.2
N28935623: length 2.1
  TOP w0.1: Y1500.3 32.6,115.82 C1500.1 32.8,114.77 R1500.1
N28935651: length 2
  TOP w0.1: U1500.27 33.6,112.87 R1502.1
N28935686: length 2
  TOP w0.1: R1514.1 34.4,112.79 U1500.25
N28935712: length 2.1
  TOP w0.1: R1503.2 32,112.27 U1500.31
N28935736: length 2.3
  TOP w0.1: R1505.2 R1504.2 37.45,111.18 37.31,111.05 36.76,111.05 36.65,110.93 R1506.1
N28935906: length 1.8
  TOP w0.1: R1508.1 36.45,109.12 U1500.19
N28936678: length 2.5
  TOP w0.2: U1501.4 43,117.03 43.25,117.28 R1519.2 R1517.2
N29048756: length 1.6
  BOTTOM w0.15: R810.1 48.59,58.5 49.04,58.05 U804.3
N29049508: length 3.4
  BOTTOM w0.25: U805.4 52.39,53.42 52.86,53.89 53.62,53.89 C840.1 53.63,53.9 R898.2
  BOTTOM w0.3: R821.2 R898.2
N29049512: length 1.6
  BOTTOM w0.15: R811.1 48.58,53.87 49.02,53.42 U805.3
N29090177: length 1.9
  TOP w0.3: U1501.3 43.68,113.15 R1518.1
N29092622: length 30.1
  TOP w0.3: TVS1500.2 16.2,96.4 R1501.1 8.84,97.3 J1500.14
  L3 w0.3: J1500.14 2.24,103.9 2.24,114.18 3.66,115.6 J1500.11
N29156483: length 157.5
  TOP w0.1: R528.1 R535.1 178.63,124.11 R520.2
  L3 w0.1: v2(133.37,120.74) 133.56,120.55 133.56,120.54 136.7,120.54 136.9,120.34 148.47,120.34 152.25,124.11 177.63,124.11 v1(177.71,124.03)
  L6 w0.1: v2(133.37,120.74) 133.56,120.55 133.56,120.54 133.74,120.36 133.74,116.5 131.82,114.57 131.82,108.69 131.41,108.29 131.41,99.56 130.6,98.75 130.6,94.46 130.29,94.14 130.29,65.94 130.17,65.82 130.17,54.75 130.12,54.7 130.12,34.28 129.99,34.15 129.99,23.17 130.1,23.06 130.1,13.56 v3(129.61,13.07)
  BOTTOM w0.1: v3(129.61,13.07) U501.4
N29156485: length 1.7
  TOP w0.1: D506.2 174.72,122.05 R525.2
N29156487: length 1.9
  BOTTOM w0.1: U501.8 130.12,18.99 129.84,19.27 R521.2
N29156489: length 2
  BOTTOM w0.1: R522.2 131.3,11.49 131.12,11.67 U501.1
N29156491: length 1.8
  BOTTOM w0.15: R523.2 130.67,18.42 130.62,18.37 U501.9
N29156499: length 21.1
  L6 w0.2: v3(136.78,23.95) 136.82,24 v3(141.65,24)
  BOTTOM w0.2: 139.2,14.78 139.18,14.75 D508.1 135.15,14.75 R527.1 133.7,18.9 136.55,21.75 C548.1 136.78,23.07 v3(136.78,23.95) ; 142.75,24.02 141.68,24.02 v3(141.65,24)
N29156545: length 4.3
  BOTTOM w0.2: D508.2 R527.2 131.45,16.2 131.12,16.53 U501.10
N29156638: length 166.7
  TOP w0.1: v1(173.08,125.01) 175.46,127.4 R526.2
  L3 w0.1: v1(173.08,125.01) 172.83,124.77 152.05,124.77 148.22,120.94 137.21,120.94 136.65,121.49 133.69,121.49 133.33,121.13 133.03,121.13 v2(132.65,120.75)
  L6 w0.1: v3(125.35,12.97) 125.34,12.97 125.34,33.2 124.61,33.93 124.61,49.13 125.45,49.96 125.45,56.87 125.21,57.1 125.21,74.6 129,78.39 129,91.72 129.45,92.17 129.45,92.97 129.35,93.07 129.35,94.65 129.65,94.95 129.65,102.3 130.3,102.95 130.3,112.05 129.4,112.95 129.4,117.5 v2(132.65,120.75)
  BOTTOM w0.1: v3(125.35,12.97) 124.27,12.97 U506.2 ; v3(125.35,12.97) R713.1 ; v3(125.35,12.97) 126.17,12.97 126.3,13.09 D502.2 127.57,13.09 127.59,13.07 U501.5
N29156646: length 157.9
  TOP w0.1: R530.1 R536.1 177.78,124.91 R528.2 R535.2
  L3 w0.1: v2(133.91,120.89) 134.06,120.74 136.78,120.74 136.99,120.54 148.39,120.54 152.17,124.32 177.19,124.32 v1(177.78,124.91)
  L6 w0.1: v3(130.12,13.06) 130.35,13.29 130.35,23.1 130.19,23.25 130.19,34.06 130.32,34.19 130.32,54.62 130.37,54.66 130.37,65.65 130.49,65.77 130.49,94.06 130.85,94.42 130.85,98.65 131.61,99.41 131.61,108.2 132.02,108.61 132.02,114.45 133.96,116.39 133.96,120.85 v2(133.91,120.89)
N29156650: length 2.1
  BOTTOM w0.1: U501.7 129.62,18.57 C541.2
N29156654: length 3.3
  BOTTOM w0.2: R531.1 D509.2 138.25,18.3 Q507.1
N29299108: length 3.9
  TOP w0.1: R1909.2 175.12,102.11 J1901.D2
N29318380: length 8.9
  TOP w0.1: J2000.D4 174.23,47.25 174.23,45.22 173.83,44.82 170.64,44.82 170.39,45.07 R2009.2
N29318624: length 26.6
  TOP w0.072: v1(171.9,46.75) 171.77,46.62 CM2001.4
  L3 w0.057: v1(171.9,46.75) 172.15,46.5 173.25,46.5 174.5,47.75 179.16,47.75 180.56,46.35 182.09,46.35 182.82,45.61 182.82,42.58 183.57,41.83 184.33,41.83 185.08,42.58 185.76,42.58 186.51,41.84 187.53,41.84 188.28,42.58 188.96,42.58 189.71,41.84 190.04,41.84 190.12,41.92 J2000.U3
  BOTTOM w0.072: 190.67,42.74 190.66,42.76 J2000.U3
N29318627: length 27
  TOP w0.072: v1(171.97,71.05) 171.81,70.89 CM2000.2
  L3 w0.057: v1(171.97,71.05) 171.97,70.84 172.02,70.78 174.37,70.78 175.52,69.63 179.33,69.63 180.66,68.3 182.53,68.3 183.41,67.42 183.41,64.03 183.65,63.78 184.23,63.78 185.04,64.59 185.79,64.59 186.6,63.78 187.41,63.78 188.25,64.62 188.97,64.62 189.82,63.78 190.03,63.78 190.12,63.88 J2001.U3
  BOTTOM w0.072: 190.76,64.67 190.73,64.7 J2001.U3
N29318651: length 26.7
  TOP w0.072: CM2001.3 171.78,46.22 v1(171.9,46.09)
  L3 w0.057: v1(171.9,46.09) 172.15,46.34 173.32,46.34 174.57,47.59 179.09,47.59 180.49,46.18 182.02,46.18 182.66,45.54 182.66,42.51 183.5,41.67 184.34,41.67 185.08,40.93 185.76,40.93 186.51,41.67 187.53,41.67 188.28,40.93 188.96,40.93 189.71,41.67 190.07,41.67 190.12,41.61 J2000.U2
  BOTTOM w0.072: 190.74,40.75 190.74,40.76 J2000.U2
N29318675: length 27.1
  TOP w0.072: v1(171.97,70.35) 171.83,70.49 CM2000.1
  L3 w0.057: v1(171.97,70.35) 171.97,70.56 172.02,70.61 174.3,70.61 175.45,69.47 179.26,69.47 180.59,68.13 182.46,68.13 183.24,67.35 183.24,63.96 183.59,63.62 184.23,63.62 185.06,62.79 185.77,62.79 186.6,63.62 187.42,63.62 188.24,62.8 188.96,62.8 189.78,63.62 190.05,63.62 190.12,63.54 J2001.U2
  BOTTOM w0.072: J2001.U2 190.74,62.7 190.79,62.65
N29318885: length 23.5
  TOP w0.072: J2001.U12 186.92,63.92 186.81,63.81 186.5,63.81 185.72,64.58 184.98,64.58 184.26,63.86 183.48,63.86 183.24,64.09 183.24,67.68 182.73,68.19 180.75,68.19 179.45,69.48 178.22,69.48 177.28,68.54 177.28,67.75 176.69,67.16 174.85,67.16 174.39,67.61 172.39,67.61 172.11,67.89 TVS2011.1 171.9,67.89 171.75,67.74 171.15,67.74
N29318891: length 23.5
  TOP w0.072: J2001.U11 186.92,63.49 186.76,63.65 186.54,63.65 185.77,62.87 185.07,62.87 184.25,63.7 183.41,63.7 183.08,64.02 183.08,67.61 182.66,68.03 180.82,68.03 180.68,68.03 179.39,69.32 178.29,69.32 177.44,68.47 177.44,67.68 176.76,66.99 174.78,66.99 174.33,67.45 172.33,67.45 172.08,67.19 TVS2010.1 171.83,67.34 CM2002.1
N29328245: length 22.9
  TOP w0.072: J2000.U12 186.92,41.91 186.84,41.83 186.52,41.83 185.77,42.59 185.07,42.59 184.32,41.84 184.02,41.84 183.58,42.28 183.58,44.88 182.15,46.31 180.66,46.31 176.76,50.21 173.99,50.21 173.1,49.32 172.2,49.32 171.96,49.57 TVS2013.1 171.7,49.42 CM2003.2
N29328252: length 22.9
  TOP w0.072: CM2003.1 171.69,49.02 TVS2012.1 171.93,48.87 172.23,49.16 173.17,49.16 174.06,50.05 176.69,50.05 180.59,46.15 182.08,46.15 183.42,44.81 183.42,42.21 183.95,41.67 184.32,41.67 185.07,40.92 185.77,40.92 186.52,41.67 186.85,41.67 186.92,41.6 J2000.U11
N29438820: length 2.7
  TOP w0.1: R526.1 180.72,127.4 SW500.2
  vias: v1(159.23,41.59) v1(159.23,41.33) v1(159.24,41.07) v1(159.5,41.59) v1(159.5,41.33) v1(159.51,41.07) v1(159.75,41.33) v1(159.75,41.59) v1(159.76,41.07) v1(160.02,41.59) v1(160.02,41.33) v1(160.03,41.07) v1(179.18,126.94) v1(179.18,126.65) v1(179.17,126.34) v1(179.46,126.94) v1(179.46,126.65) v1(179.45,126.34) v1(179.75,126.33) v1(179.76,126.93) v1(179.76,126.64) v1(180.04,126.94) v1(180.04,126.65) v1(180.03,126.34) v2(159.13,43.01) v2(159.11,42.53) v2(159.11,42.01) v2(159.58,43.01) v2(159.57,42.51) v2(159.56,42.01) v2(160.04,42.53) v2(160.05,42.01) v2(160.07,43.01) v2(160.55,126.38) v2(160.51,43.01) v2(160.5,42.51) v2(160.49,42.01) v2(160.56,126.81) v2(161.01,126.81) v2(161.01,126.36) v2(161.5,126.81) v2(161.48,126.38) v2(161.94,126.81) v2(161.94,126.36)
N29439271: length 2.8
  BOTTOM w0.1: R529.1 127.07,19.28 D502.1
N29439293: length 9.2
  L3 w0.1: v2(126.2,30.4) 126.2,30.4 v1(125.8,30.4)
  L6 w0.1: v2(126.2,30.4) 125.99,30.19 125.99,23.18 v3(125.87,23.06)
  BOTTOM w0.1: 125.86,23.05 v3(125.87,23.06) ; 125.86,23.05 C543.1 125.86,23.05 ; 125.86,23.05 126.05,22.86 U504.6
N29453921: length 2.3
  BOTTOM w0.2: U806.1 C830.1 57.71,113.15 R813.2
N29453925: length 3.2
  BOTTOM w0.2: R812.2 57.71,111.32 C807.2 57.71,111.32 R815.1 57.68,112.15 U806.3
N29475764: length 1.5
  BOTTOM w0.1: R529.2 127.03,20.12 U504.4
N29476525: length 1.1
  BOTTOM w0.1: R501.1 U504.3
N29490921: length 1.4
  BOTTOM w0.1: U2501.5 137.82,73.25 R2503.1
N29491037: length 1.4
  BOTTOM w0.1: R2504.1 133.37,74.71 U2502.5
N29491543: length 1.4
  BOTTOM w0.2: U2504.5 137.67,62.85 R2507.1
N29491659: length 1.4
  BOTTOM w0.2: R2510.1 133.17,62.85 U2505.5
N29503648: length 5.2
  BOTTOM w0.1: U2803.2 100.27,18.42 99.14,17.29 C2806.2 98.48,17.03 97.43,17.03 97.19,17.26 Y2800.1
N29503654: length 5.2
  BOTTOM w0.1: U2803.1 99.97,17.77 C2807.1 98.47,16.81 97.42,16.81 97.19,16.58 Y2800.2
N29503692: length 4.4
  BOTTOM w0.1: U2803.7 107.93,18.42 R2807.2 TP2804.1
N29658683: length 1.7
  TOP w0.1: LED500.1 102.18,94.33 102.19,94.33 R534.1
N29666807: length 1
  BOTTOM w0.1: R910.1 30.21,27.85 U902.2
N29726494: length 1.2
  TOP w0.2: U2700.5 R2700.1
N29726501: length 1.3
  TOP w0.1: U2701.5 R2701.1
N29727370: length 1.3
  TOP w0.1: U2702.5 R2704.1
N29727381: length 1.7
  TOP w0.1: U2703.5 R2705.1
N29750648: length 155.8
  L3 w0.1: v2(134.42,121.09) 134.57,120.94 136.86,120.94 137.07,120.74 148.3,120.74 152.12,124.55 174.64,124.55 v1(174.74,124.65)
  L6 w0.1: v3(130.47,11.13) 130.55,11.21 130.55,23.18 130.39,23.34 130.39,33.98 130.52,34.11 130.52,54.54 130.57,54.58 130.57,65.5 130.69,65.62 130.69,93.98 131.1,94.4 131.1,98.54 131.81,99.25 131.81,108.12 132.22,108.53 132.22,114.28 134.16,116.23 134.16,120.46 134.42,120.71 v2(134.42,121.09)
  BOTTOM w0.1: U501.2 130.62,11.77 130.47,11.62 v3(130.47,11.13)
N29750654: length 0.9
  TOP w0.1: R525.1 175.51,123.74 R524.2
N29949460: length 58.6
  TOP w0.3: R1804.1 126.75,57.87 TP1800.1
  L3 w0.3: v1(125.35,56.27) 105.63,56.27 v2(105.12,55.76)
  L6 w0.3: v3(93.85,24.9) 93.85,26.95 101.35,34.45 101.35,38.87 102.41,39.93 102.41,42.94 105.51,46.04 105.51,55.37 v2(105.12,55.76)
N30025351: length 4.8
  TOP w0.3: D1800.1 127.85,56.37 128.25,55.97 R1805.1 C1802.1 127.45,54.47 127.7,54.22 U1801.5
N30026226: length 3.1
  TOP w0.3: D1800.2 129.35,56.37 R1804.2
N30026266: length 2.2
  TOP w0.1: U1801.4 129.6,54.12 129.85,54.37 R1806.1 R1805.2
N30153252: length 0.8
  BOTTOM w0.1: R540.2 89.31,79.04 C551.2
N30232771: length 0.8
  BOTTOM w0.3: R2803.2 C2830.2
N30232773: length 0.8
  BOTTOM w0.3: R2804.2 C2831.2
N30232946: length 7
  BOTTOM w0.3: U2800.18 79.36,106.49 76.3,109.55 C2820.1
N30298891: length 112.1
  TOP w0.1: R2811.2 40.97,37.43 v1(40.97,38.83)
  L3 w0.1: v1(40.97,38.83) 45.2,38.83 45.72,39.35 52.66,39.35 53.19,38.82 61.94,38.82 62.6,38.16 85.65,38.16 v2(85.77,38.04)
  L6 w0.1: v3(81.96,98.4) 81.96,97.84 82.96,96.84 84.07,96.84 86.1,94.8 86.1,78.59 86.24,78.46 86.24,72.15 85.51,71.43 85.51,49.06 85.97,48.6 85.97,47.47 85.77,47.27 v2(85.77,38.04)
  BOTTOM w0.1: U2800.7 v3(81.96,98.4)
N30298894: length 109.5
  TOP w0.1: v1(41.86,37.97) 41.86,37.98 R2810.2
  L3 w0.1: v1(41.86,37.97) 45.52,37.97 46.25,38.7 52.09,38.7 52.65,38.14 61.61,38.14 62.4,37.35 84.81,37.35 84.99,37.17 85.28,37.17 85.44,37.33 86.32,37.33 v2(86.47,37.48)
  L6 w0.1: v2(86.47,37.48) 86.47,37.74 86.6,37.87 86.6,44.06 86.31,44.35 86.31,47.14 86.46,47.29 86.46,48.96 85.99,49.44 85.99,71.11 86.57,71.7 86.58,71.71 86.58,75.94 86.72,76.08 86.72,95 84.36,97.35 83.65,97.35 v3(82.6,98.4)
N30298956: length 115.4
  TOP w0.1: R2813.2 41.44,33.91 39.55,35.8 v1(39.55,37.7)
  L3 w0.1: v1(39.55,37.7) 40.13,38.28 45.46,38.28 46.08,38.9 52.18,38.9 52.74,38.34 61.69,38.34 62.48,37.55 85.1,37.55 v2(85.13,37.52)
  L6 w0.1: v3(81.3,98.4) 81.3,97.63 82.62,96.31 83.69,96.31 85.55,94.45 85.55,75.35 85.05,74.85 85.05,48.75 85.13,48.66 85.13,48.65 85.45,48.34 85.45,47.6 85.13,47.28 v2(85.13,37.52)
N30299980: length 1.6
  BOTTOM w0.1: R2806.2 80.01,97.46 U2800.10
N30300002: length 1.6
  BOTTOM w0.1: U2800.11 79.36,97.66 R2809.2
N30393381: length 1.2
  TOP w0.1: U1601.4 137.24,75.35 R1604.1
N30393629: length 1.1
  TOP w0.1: R1606.1 140.8,75.48 U1602.4
N30452220: length 1.2
  TOP w0.2: R1522.1 47.57,105.98 U1502.4
N30564062: length 1.9
  TOP w0.1: R1702.1 156.6,48.32 157.2,48.32 157.49,48.61 U1700.7
N30564201: length 2
  TOP w0.18: U1701.66 145.27,56 145.16,55.89 ; 144.85,55.9 144.87,55.93 U1701.65 144.54,56.68 144.53,56.66
N30564853: length 2.6
  TOP w0.072: C1754.1 140.99,69.6 142.42,69.6 142.54,69.48 U1701.36
N30564873: length 2.6
  TOP w0.072: U1701.35 142.54,69.88 142.42,69.76 141.03,69.76 C1755.1
N30636806: length 1.1
  TOP w0.1: R1609.2 130.29,61.66 U1604.5
N30639808: length 2.3
  TOP w0.1: U1600.4 126.21,61.79 C1604.1 126.21,59.79 R1603.2
N30639812: length 1.6
  TOP w0.1: U1600.3 126.44,65.03 126.01,65.45 R1600.1
N30640189: length 1.1
  TOP w0.1: R1607.2 126.73,81.77 U1603.3
N30640191: length 1.4
  TOP w0.1: R1608.2 127.1,77.28 127.23,77.4 U1603.7
N30676977: length 1.4
  TOP w0.1: U1605.8 129.74,73.77 R1613.2
N30676990: length 1.3
  TOP w0.1: 130.17,74.2 130.13,74.17 U1605.9
N30676992: length 1.1
  TOP w0.1: R1615.1 127.9,74.8 U1605.2
N30678249: length 1.4
  TOP w0.1: U1606.1 130.65,82.54 R1619.1
N30678261: length 1.3
  TOP w0.1: R1616.1 131.94,81.31 U1606.10
N30678276: length 1.3
  TOP w0.1: U1606.8 131.93,80.51 R1617.2
N30678289: length 1.1
  TOP w0.1: R1618.2 132.36,80.91 U1606.9
N30678291: length 1.3
  TOP w0.1: R1620.1 130.25,82.51 U1606.2
N30707263: length 1.2
  TOP w0.25: U2401.3 159.02,78.68 R2402.2
N30707265: length 1.1
  TOP w0.25: R2403.2 163.28,79.18 U2401.7
N30707303: length 1.3
  TOP w0.25: U2401.5 162.61,78.18 R2415.1
N30717755: length 6.9
  TOP w0.1: TP1700.1 137.75,64.65 141.52,64.65 142.35,65.48 U1701.46
N30717758: length 5.8
  TOP w0.1: U1701.45 142.29,65.88 141.35,64.94 138.52,64.94 TP1701.1
N30726073: length 9.8
  TOP w0.1: R1901.2 167.17,113.55 167.93,113.55 168.04,113.66 168.05,113.66 168.4,114.01 168.4,114.02 172.9,114.02 173.48,113.44 173.84,113.44 175.21,114.81 J1901.D4
N30726377: length 8.2
  L3 w0.1: J1900.D4 174.03,90.95 173.04,90.95 172.32,91.67 172.26,91.67 172.25,91.68 171.04,91.68 170.8,91.44 169.57,91.44 169.29,91.16 v1(169.03,91.16)
N30729205: length 6.4
  TOP w0.1: J2001.D4 175.38,70.91 173.66,69.19 170.66,69.19 R2000.2
N30751641: length 2.5
  BOTTOM w0.1: U900.19 31.31,19.31 R900.1
N30751669: length 2.7
  BOTTOM w0.1: U900.18 31.76,18.91 R901.1
N30751690: length 2.7
  BOTTOM w0.062: U900.26 32.7,22.11 32.59,22.22 32.2,22.22 31.34,23.08 30.89,23.08 C900.2
N30751718: length 2.7
  BOTTOM w0.062: C901.2 30.91,23.26 31.42,23.26 32.28,22.4 32.59,22.4 32.69,22.51 U900.27
N30751823: length 2.3
  BOTTOM w0.062: U900.29 33.7,23.92 33.81,24.03 33.81,24.29 33.2,24.9 33.2,25.49 R902.2
N30751825: length 2.6
  BOTTOM w0.062: R903.1 32.56,15.23 32.56,15.43 33.24,16.11 33.42,16.11 33.81,16.5 33.81,16.6 33.7,16.71 U900.14
N30751857: length 2.4
  BOTTOM w0.062: U900.30 34.1,23.91 34,24.02 34,24.37 33.39,24.98 33.39,25.47 R904.2
N30751859: length 2.6
  BOTTOM w0.062: U900.13 34.1,16.71 34,16.61 34,16.42 33.5,15.92 33.32,15.92 32.74,15.35 32.75,15.23 R905.1
N30751883: length 2.4
  BOTTOM w0.062: R906.1 33.71,15.23 33.71,15.54 34.61,16.44 34.61,16.6 34.5,16.71 U900.12
N30751915: length 2.3
  BOTTOM w0.062: R907.2 34.6,25.51 34.6,25.16 35.01,24.75 35.01,24.03 34.9,23.92 U900.32
N30751917: length 2.4
  BOTTOM w0.062: U900.11 34.9,16.71 34.8,16.61 34.8,16.36 33.9,15.46 33.9,15.25 R908.1
N30751941: length 2.3
  BOTTOM w0.062: R909.2 34.91,25.59 34.79,25.47 34.79,25.23 35.2,24.83 35.2,24.04 35.3,23.93 U900.33
N30751973: length 2.1
  BOTTOM w0.062: R912.2 35.92,25.48 35.92,24.75 35.81,24.64 35.81,24.03 35.7,23.93 U900.34
N30751975: length 2
  BOTTOM w0.062: R913.1 35.77,15.25 35.77,15.8 35.81,15.84 35.81,16.6 35.7,16.71 U900.9
N30752007: length 2.1
  BOTTOM w0.062: R916.2 36.11,25.47 36.11,24.68 36,24.56 36,24.03 36.1,23.92 U900.35
N30752009: length 2
  BOTTOM w0.062: R917.1 35.96,15.25 35.96,15.72 36,15.76 36,16.6 36.1,16.71 U900.8
N30752033: length 2.1
  BOTTOM w0.062: U900.7 36.5,16.7 36.61,16.59 36.61,15.98 36.91,15.68 36.91,15.47 36.91,15.25 R918.1
N30752065: length 2.2
  BOTTOM w0.062: R919.2 37.32,25.49 37.32,25.22 37.01,24.91 37.01,24.04 36.9,23.94 U900.37
N30752067: length 2.1
  BOTTOM w0.062: U900.6 36.9,16.7 36.8,16.59 36.8,16.06 37.1,15.76 37.1,15.54 37.1,15.54 37.1,15.25 R920.1
N30752096: length 2.2
  BOTTOM w0.062: U900.38 37.3,23.93 37.2,24.04 37.2,24.83 37.51,25.14 37.51,25.48 R921.2
N30752151: length 3.4
  BOTTOM w0.1: U900.2 38.5,16.62 38.66,16.47 38.68,16.47 39.03,16.11 40.08,16.11 40.66,15.53 40.66,15.02 R923.1
N30752212: length 7.5
  BOTTOM w0.1: U900.45 40.82,22.11 41.42,22.71 41.96,22.71 R927.2 41.96,22.35 42.05,22.27 43.7,22.27 44.2,22.77 TP910.1
N30752214: length 3.2
  BOTTOM w0.1: R930.1 41.95,21.44 41.96,21.44 C905.1 41.34,21.87 41.18,21.71 U900.46
N30754322: length 14.1
  L3 w0.2: v2(37.18,28.23) 37.04,28.37 31.41,28.37 v2(31.35,28.32)
  L6 w0.2: JP906.1 37.65,27.72 v3(37.61,27.68) 37.18,28.11 v2(37.18,28.23) 36.9,28.52 JP907.1 ; v2(31.35,28.32) 31.31,28.27 31.31,22.52 31.2,22.42 JP908.1
N30793598: length 2.7
  BOTTOM w0.1: R1000.1 60.39,31.07 U1000.19
N30793622: length 2.9
  BOTTOM w0.1: R1001.1 59.97,31.47 U1000.18
N30793642: length 2.7
  BOTTOM w0.062: C1000.2 60.89,27.47 arc(60.87,27.45) 60.84,27.45 60.39,27.45 59.68,28.17 59.1,28.17 arc(59.07,28.17) 59.05,28.19 58.99,28.25 arc(58.96,28.27) 58.93,28.27 U1000.26
N30793665: length 2.7
  BOTTOM w0.062: C1001.2 60.9,27.24 arc(60.87,27.26) 60.84,27.26 60.32,27.26 59.6,27.98 59.11,27.98 arc(59.08,27.97) 59.06,27.96 59,27.9 arc(58.97,27.88) 58.94,27.87 U1000.27
N30793799: length 2.3
  BOTTOM w0.062: U1000.29 57.95,26.47 57.84,26.37 57.84,26.25 58.65,25.44 58.65,25.05 R1002.2
N30793801: length 2.7
  BOTTOM w0.062: R1004.1 59.01,35.15 59.01,34.89 58.63,34.51 58.37,34.51 57.84,33.97 57.84,33.79 57.95,33.68 U1000.14
N30793832: length 2.3
  BOTTOM w0.062: R1003.2 58.47,25.06 58.47,25.36 57.66,26.17 57.66,26.36 57.55,26.47 U1000.30
N30793834: length 2.6
  BOTTOM w0.062: U1000.13 57.55,33.69 57.65,33.79 57.65,34.05 58.29,34.7 58.55,34.7 58.82,34.97 58.82,35.17 R1005.1
N30793858: length 2.3
  BOTTOM w0.062: R1006.1 57.85,35.16 57.85,34.9 57.04,34.1 57.04,33.78 57.15,33.67 U1000.12
N30793890: length 2.2
  BOTTOM w0.062: R1007.2 57.23,25.03 57.23,25.24 56.64,25.83 56.64,26.36 56.75,26.46 U1000.32
N30793892: length 2.3
  BOTTOM w0.062: R1008.1 57.66,35.16 57.66,34.98 56.86,34.18 56.86,33.78 56.75,33.68 U1000.11
N30793910: length 2.2
  BOTTOM w0.062: U1000.33 56.35,26.46 56.46,26.36 56.46,25.75 57.04,25.16 57.04,25.06 R1009.2
N30793943: length 2
  BOTTOM w0.062: U1000.34 55.95,26.47 55.84,26.36 55.84,25.42 55.84,25.36 55.9,25.3 55.9,25.09 R1010.2
N30793945: length 2
  BOTTOM w0.062: U1000.9 55.95,33.69 55.84,33.8 55.84,34.81 55.81,34.85 55.81,35.14 R1011.1
N30793976: length 2
  BOTTOM w0.062: R1012.2 55.72,25.07 55.72,25.22 55.66,25.28 55.66,25.34 55.66,26.37 55.55,26.48 U1000.35
N30793978: length 2
  BOTTOM w0.062: R1013.1 55.62,35.13 55.62,34.77 55.66,34.73 55.66,33.8 55.55,33.69 U1000.8
N30793996: length 2.1
  BOTTOM w0.062: U1000.7 55.15,33.68 55.04,33.78 55.04,34.38 54.65,34.77 54.65,35.14 R1014.1
N30794028: length 2
  BOTTOM w0.062: U1000.37 54.75,26.48 54.64,26.37 54.64,25.6 54.45,25.41 54.45,25.05 R1015.2
N30794030: length 2.1
  BOTTOM w0.062: U1000.6 54.75,33.69 54.86,33.8 54.86,34.3 54.47,34.69 54.47,35.14 R1016.1
N30794058: length 2
  BOTTOM w0.062: R1017.2 54.26,25.05 54.26,25.49 54.46,25.68 54.46,26.36 54.35,26.47 U1000.38
N30794088: length 3.2
  BOTTOM w0.1: R1019.1 52,34.28 52.71,34.28 53.15,33.84 U1000.2
N30794178: length 4.9
  BOTTOM w0.1: TP1008.1 49.65,27.27 49.73,27.35 R1022.2 49.73,27.8 50.2,28.27 U1000.45
N30794180: length 4.3
  BOTTOM w0.1: C1005.1 48.17,28.57 48.58,28.16 49.55,28.16 49.74,28.36 R1025.1 50.12,28.6 50.18,28.67 U1000.46
N30794558: length 1
  BOTTOM w0.1: U1001.2 59.6,20.05 59.6,20.05 R1026.1
N30794934: length 15.3
  L3 w0.3: v2(52.69,28.81) 52.68,28.81 52.68,28.82 53.05,28.82 53.49,29.27 59.85,29.27 59.86,29.27 v2(59.97,29.27)
  L6 w0.2: JP1007.1 51.84,24.09 51.76,24.02 ; v2(59.97,29.27) 59.87,29.27 59.87,29.28 59.87,29.29 JP1008.1 ; JP1006.1 52.47,22.95 52.47,22.95 v3(52.34,22.95) 51.76,23.53 51.76,24.02 ; 51.76,24.02 51.76,24.41 51.77,24.41 51.77,24.43 51.89,24.55 51.9,24.55 52.05,24.69
  L6 w0.3: v2(52.69,28.81) 52.68,28.81 52.68,28.82 52.18,28.32 52.18,25.32 52.05,25.18 52.05,24.69
N30797093: length 2.7
  BOTTOM w0.1: U1100.19 45.12,41.62 R1100.1
N30797117: length 2.9
  BOTTOM w0.1: U1100.18 44.67,42.02 R1101.1
N30797137: length 2.7
  BOTTOM w0.062: U1100.26 43.91,38.82 44.02,38.71 44.35,38.71 44.97,38.1 45.48,38.1 45.6,38.1 C1100.2
N30797160: length 2.7
  BOTTOM w0.062: C1101.2 45.6,37.91 44.89,37.91 44.27,38.53 44.02,38.53 43.91,38.42 U1100.27
N30797294: length 2.2
  BOTTOM w0.062: U1100.29 42.68,37.02 42.58,36.92 42.58,36.71 43.3,35.99 43.3,35.6 R1102.2
N30797296: length 2.6
  BOTTOM w0.062: U1100.14 42.68,44.22 42.57,44.32 42.57,44.44 43.01,44.88 43.11,44.88 43.75,45.52 43.75,45.71 R1103.1
N30797327: length 2.2
  BOTTOM w0.062: R1104.2 43.12,35.6 43.12,35.91 42.39,36.64 42.39,36.9 42.28,37.01 U1100.30
N30797329: length 2.5
  BOTTOM w0.062: R1105.1 43.56,45.71 43.56,45.6 43.03,45.07 42.93,45.07 42.39,44.52 42.39,44.33 42.28,44.22 U1100.13
N30797353: length 2.3
  BOTTOM w0.062: U1100.12 41.88,44.23 41.77,44.33 41.77,44.53 42.59,45.34 42.59,45.69 R1107.1
N30797385: length 2.2
  BOTTOM w0.062: R1106.2 42.06,35.4 41.88,35.59 41.88,36.12 41.37,36.63 41.37,36.91 41.48,37.01 U1100.32
N30797387: length 2.3
  BOTTOM w0.062: U1100.11 41.48,44.22 41.59,44.33 41.59,44.6 42.4,45.42 42.4,45.69 R1108.1
N30797405: length 2.1
  BOTTOM w0.062: U1100.33 41.08,37.02 41.19,36.91 41.19,36.55 41.69,36.05 41.69,35.59 R1109.2
N30797438: length 2
  BOTTOM w0.062: U1100.34 40.68,36.99 40.59,36.9 40.59,36.21 40.65,36.14 40.65,35.59 R1110.2
N30797440: length 2
  BOTTOM w0.062: R1111.1 40.54,45.69 40.54,45.4 40.57,45.37 40.57,44.32 40.68,44.22 U1100.9
N30797471: length 2
  BOTTOM w0.062: U1100.35 40.28,37.02 40.4,36.9 40.4,36.13 40.47,36.06 40.47,35.6 R1112.2
N30797473: length 2
  BOTTOM w0.062: U1100.8 40.28,44.22 40.39,44.33 40.39,45.3 40.36,45.32 40.36,45.69 40.35,45.69 40.35,45.68 R1113.1
N30797491: length 2.1
  BOTTOM w0.062: U1100.7 39.88,44.22 39.77,44.33 39.77,44.61 39.4,44.98 39.4,45.69 R1116.1
N30797523: length 2
  BOTTOM w0.062: R1117.2 39.11,35.6 39.11,36.17 39.37,36.43 39.37,36.9 39.48,37.01 U1100.37
N30797525: length 2.1
  BOTTOM w0.062: U1100.6 39.48,44.22 39.59,44.33 39.59,44.53 39.21,44.91 39.21,45.69 R1118.1
N30797553: length 2
  BOTTOM w0.062: U1100.38 39.08,37 39.19,36.89 39.19,36.51 38.92,36.25 38.92,35.59 R1119.2
N30797583: length 3.2
  BOTTOM w0.1: U1100.2 37.88,44.33 37.19,45.02 36.54,45.02 R1121.1
N30797673: length 4.9
  BOTTOM w0.1: TP1110.1 32.85,37.97 34.55,37.97 34.64,38.06 R1124.2 35.08,38.82 U1100.45
N30797675: length 4.2
  BOTTOM w0.1: C1105.1 33.55,38.83 34.55,38.83 34.63,38.91 R1127.1 34.69,39.22 U1100.46
N30798053: length 1
  BOTTOM w0.1: U1101.2 49.96,46.21 R1128.1
N30798429: length 14.9
  L3 w0.3: v2(44.24,36.38) 44.2,36.42 38.24,36.42 v2(38.24,36.36)
  L6 w0.2: JP1107.1 37.17,36.33 37.3,36.46 38.14,36.46 v2(38.24,36.36) 38.24,35.45 arc(38.24,35.41) 38.24,35.36 arc(38.24,35.25) 38.2,35.14 arc(38.16,35.03) 38.15,34.91 38.15,34.19 arc(38.15,34.13) 38.18,34.08 arc(38.22,33.98) 38.24,33.88 v3(38.24,33.43) 38.19,33.38 JP1106.1 ; JP1108.1 44.55,39.83
  L6 w0.3: v2(44.24,36.38) 44.24,36.74 44.24,36.74 44.24,39.51 44.55,39.83
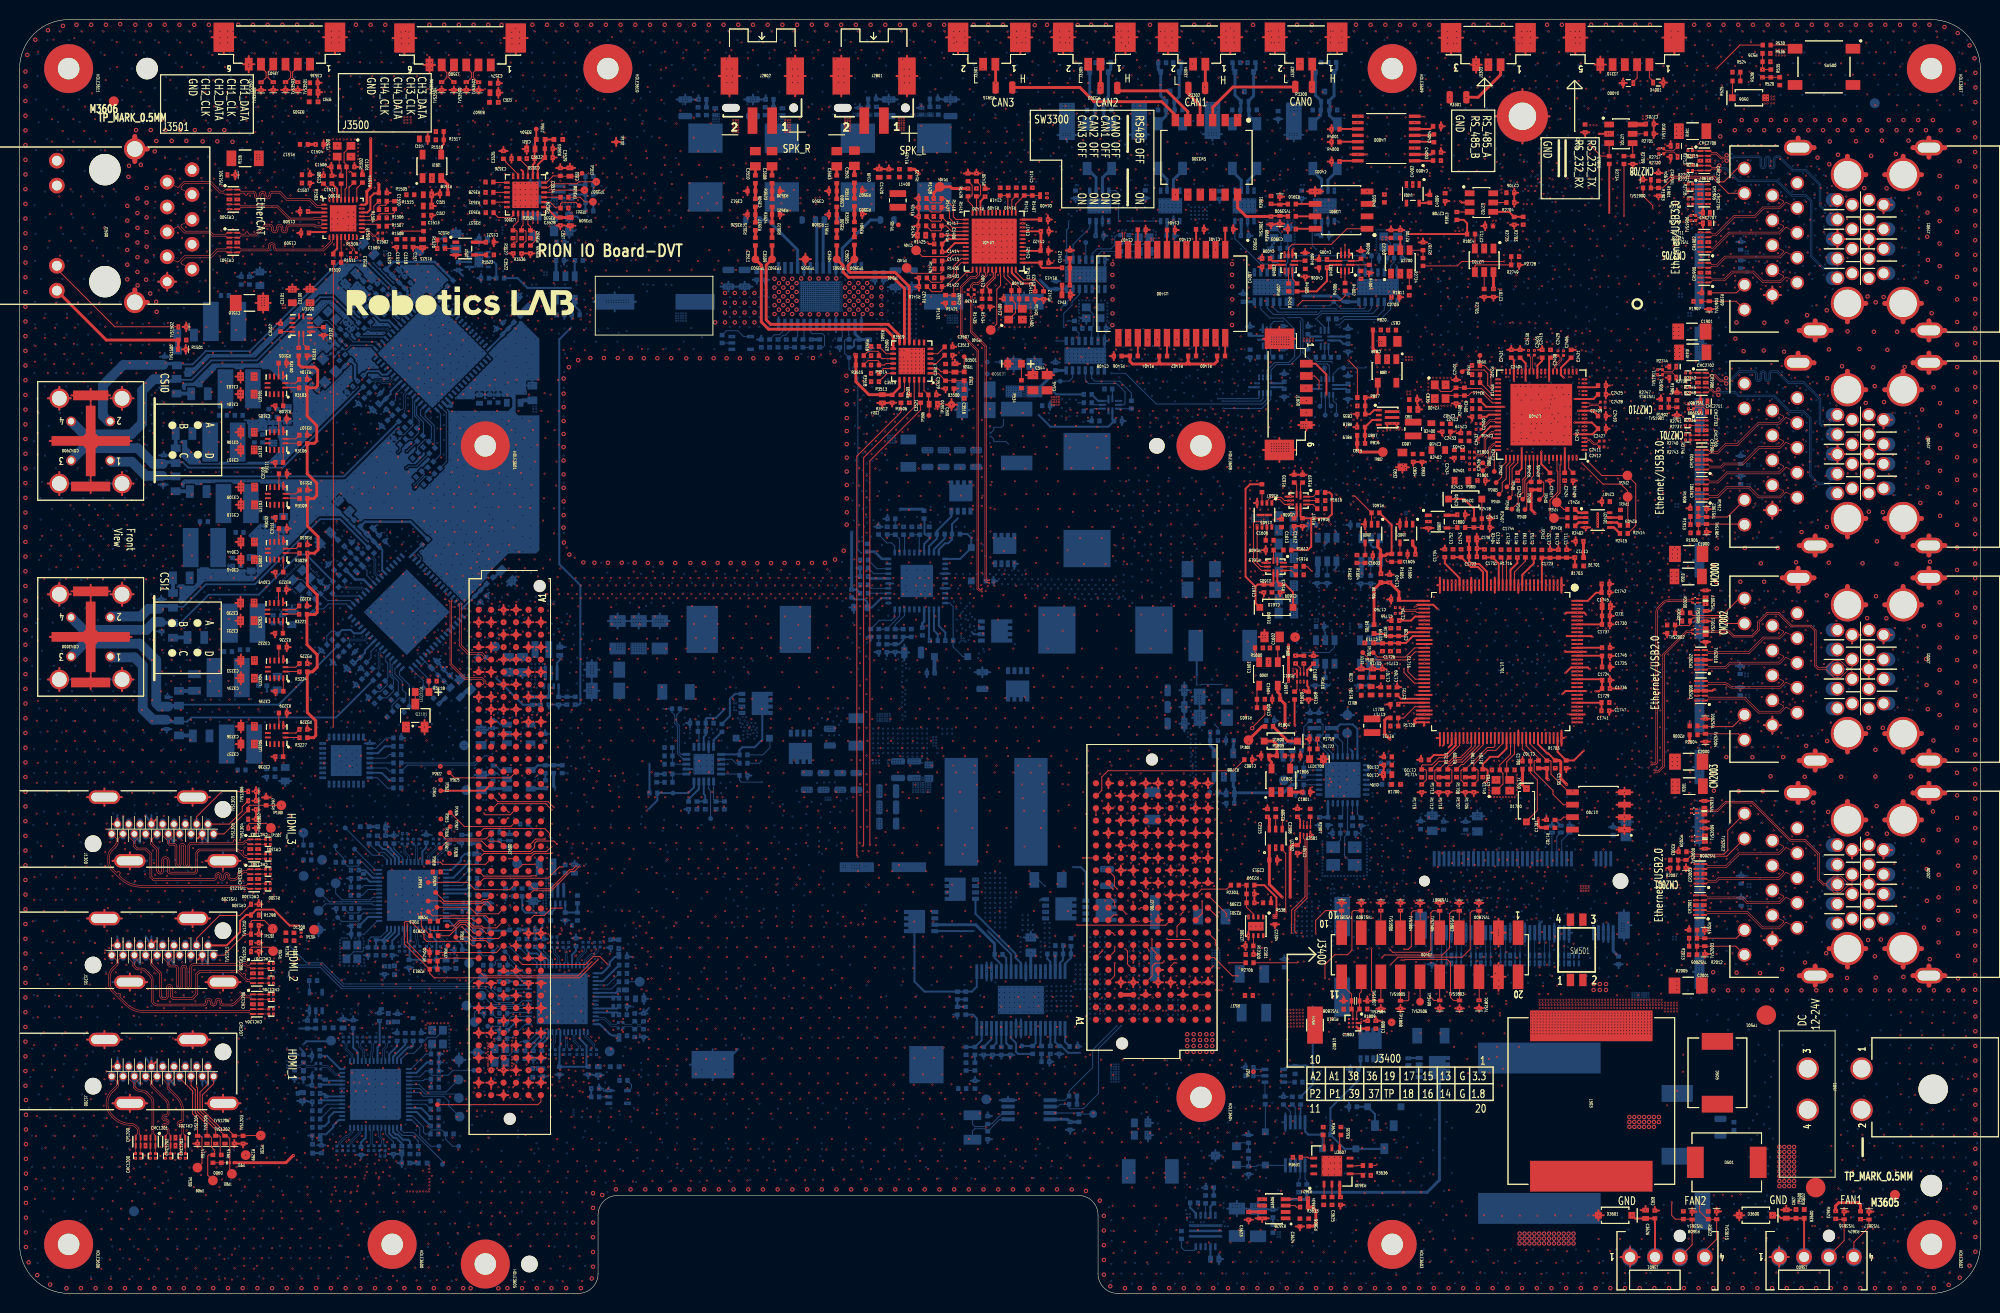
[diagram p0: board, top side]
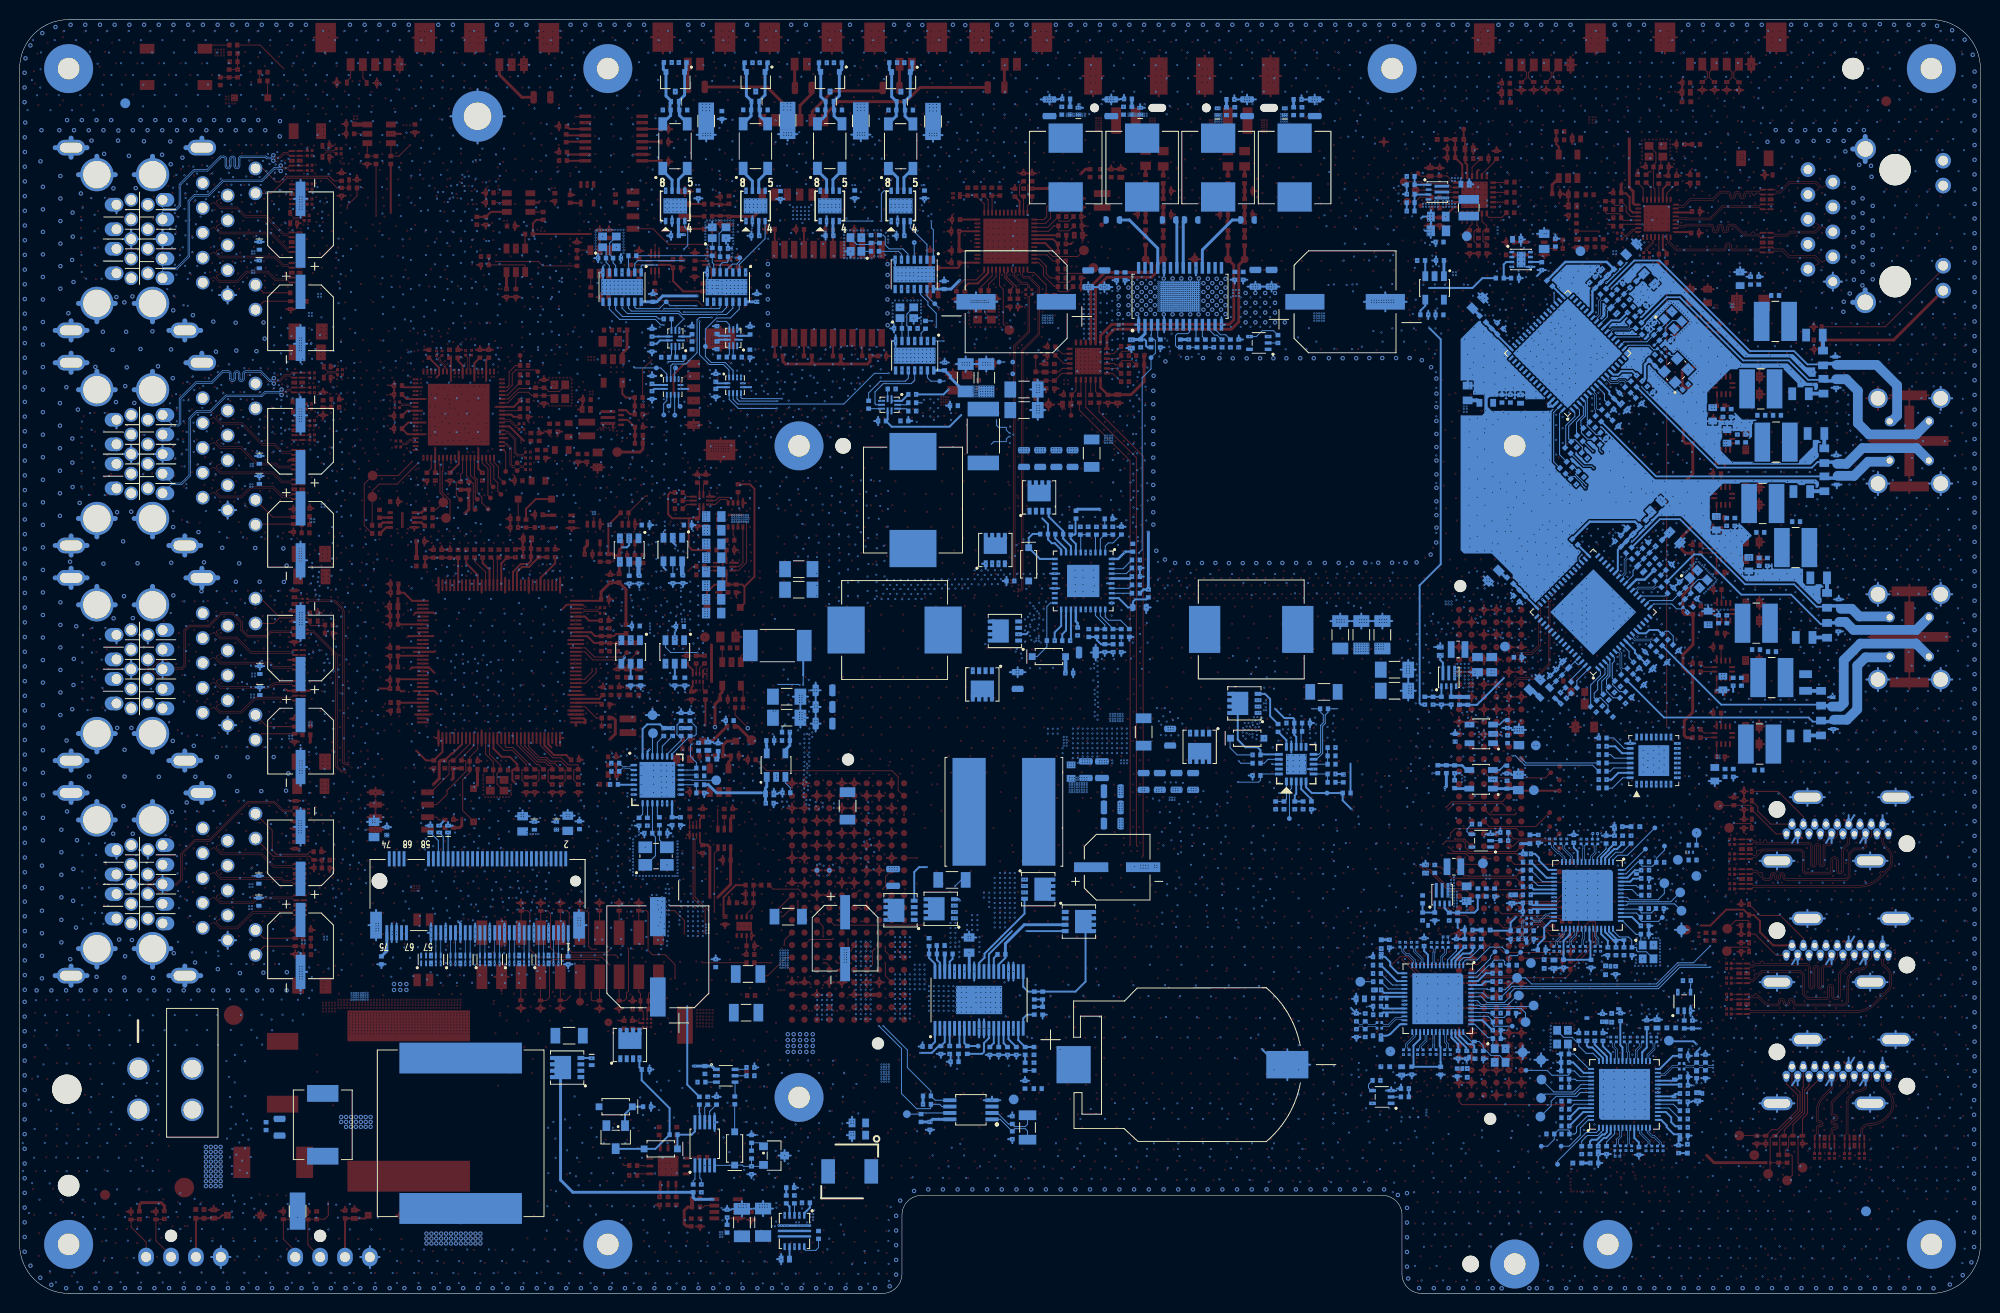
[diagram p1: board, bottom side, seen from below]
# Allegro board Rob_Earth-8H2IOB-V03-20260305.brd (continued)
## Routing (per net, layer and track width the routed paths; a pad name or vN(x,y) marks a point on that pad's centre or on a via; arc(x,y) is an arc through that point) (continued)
N30852150: length 3.1
  TOP w0.072: U1401.41 98.81,104.3 98.68,104.18 98.68,103.87 97.79,102.98 97.31,102.98 97.14,102.81 97.14,102.66 C1400.2
N30852159: length 6.6
  TOP w0.1: U1401.44 100.01,104.07 100.05,104.02 100.05,102.86 99.67,102.48 99.67,98.94 TP1400.1
N30852169: length 3.1
  TOP w0.072: U1401.40 98.41,104.28 98.52,104.17 98.52,103.94 97.73,103.14 97.25,103.14 96.98,102.88 96.98,102.65 C1402.2
N30852210: length 4.1
  TOP w0.1: U1401.48 101.61,104.25 102.42,103.44 103.65,103.44 104.45,102.63 104.45,102.27 R1401.1
N30852304: length 7.7
  TOP w0.1: U1401.34 95.22,105.99 94.6,105.37 R1405.2 94.1,104.97 94.1,104.96 R1403.2 94.1,104.24 93.97,104.1 91.03,104.1 TP1401.1
N30852386: length 5.6
  TOP w0.1: TP1402.1 92.07,105.82 94.61,105.82 95.18,106.39 U1401.33
N30852519: length 2.6
  TOP w0.1: U1401.15 100.81,112.01 R1410.2 R1409.2
N30852521: length 1.9
  TOP w0.1: U1401.14 101.21,111.6 R1411.2
N30857169: length 2.1
  TOP w0.2: C1401.2 122.97,108.6 U1400.1
N30857171: length 1.9
  TOP w0.2: R1400.1 122.97,95.7 U1400.24
N30857173: length 13.5
  TOP w0.3: R1400.2 122.15,95.13 121.88,94.85 119.4,94.85 ; 116.24,95.06 116.24,95.04 116.43,94.85 ; 116.24,95.06 116.03,94.85 ; 116.24,95.06 R1404.2 ; 116.03,94.85 116.43,94.85 ; 116.03,94.85 113.52,94.85 113.25,95.12 R1406.2 113.24,95.66 C1408.1 ; 116.43,94.85 118.99,94.85 ; R1402.2 119.19,95.05 ; 119.19,95.05 118.99,94.85 ; 119.19,95.05 119.2,95.05 119.4,94.85 ; 119.4,94.85 118.99,94.85
N30857225: length 2.1
  TOP w0.2: C1403.2 120,108.58 U1400.4
N30857227: length 1.9
  TOP w0.2: U1400.21 120,95.68 R1402.1
N30857281: length 2
  TOP w0.2: C1404.2 117.03,108.52 U1400.7
N30857283: length 1.9
  TOP w0.2: U1400.18 117.03,95.67 R1404.1
N30857337: length 2
  TOP w0.2: U1400.10 114.06,108.55 C1407.2
N30857339: length 1.9
  TOP w0.2: R1406.1 114.06,95.69 U1400.15
N31095396: length 1.1
  BOTTOM w0.1: R2932.2 31.13,92.98 31.14,92.98
N31099799: length 4.1
  L3 w0.1: v1(139.95,27.67) 139.7,27.42 136.16,27.42 v1(135.99,27.59)
N31105694: length 1.7
  BOTTOM w0.072: U2503.1 137.61,53.91 137.78,53.74 138.13,53.74 138.17,53.78 138.51,53.78 R2520.2
N31105696: length 1.7
  BOTTOM w0.072: R2521.2 138.5,53.62 138.23,53.62 138.19,53.58 137.76,53.58 137.59,53.41 U2503.2
N31106810: length 1.2
  TOP w0.25: R2414.1 162.95,78.68 U2401.6
N31107614: length 1.1
  TOP w0.25: U2401.2 158.69,79.18 R2416.1
N31107623: length 1.2
  TOP w0.25: R2417.1 159.01,79.68 U2401.1
N31159283: length 3
  BOTTOM w0.2: R543.1 89.3,66.25 R544.1 89.7,66.26 90.12,66.68 R542.1 90.13,67 R541.2
N31296332: length 4.2
  BOTTOM w0.1: U3407.5 139.2,104.9 139.47,105.17 C3428.1 139.81,106.01 139.81,107.19 Y3400.3
N31296338: length 2.9
  BOTTOM w0.1: Y3400.1 140.19,106.42 C3427.1 140.19,105.24 139.85,104.9 U3407.6
N31297702: length 1.2
  BOTTOM w0.1: R3425.1 133.51,99.44 U3406.5
N31297725: length 1.2
  BOTTOM w0.2: R3411.1 131.64,97.66 U3406.2
N31298259: length 2.1
  BOTTOM w0.1: U3408.10 110.96,91.09 111.06,91.19 U3408.1
  BOTTOM w0.2: U3408.10 110.01,91.09 R3413.1
N31298276: length 1.3
  BOTTOM w0.1: U3408.5 113.39,90.29 R3426.1
N31298299: length 1
  BOTTOM w0.1: U3408.2 111.46,92.29 R3414.1
N31300246: length 1.1
  BOTTOM w0.2: R3416.1 125.63,97.73 U3410.2
N31358356: length 2.4
  BOTTOM w0.1: U3411.6 110,98.48 C2305.1 110,99.33 Y2300.1
N31395223: length 2.7
  BOTTOM w0.3: U3405.7 110.45,113.87 CM3403.1
N31395227: length 2.6
  BOTTOM w0.3: U3405.6 109.8,113.88 CM3403.2
N31485203: length 1.2
  BOTTOM w0.1: U3406.8 133.51,95.79 R3417.2
N31485229: length 1.1
  BOTTOM w0.1: U3406.9 133.11,95.65 R3418.2
N31485280: length 1.2
  BOTTOM w0.1: U3408.8 109.59,90.29 R3419.2
N31485283: length 1.2
  BOTTOM w0.1: U3408.9 109.56,90.69 R3420.2
N31485344: length 1.3
  BOTTOM w0.1: R3421.2 127.61,95.82 U3410.8
N31485347: length 1.2
  BOTTOM w0.1: R3422.2 127.21,95.61 U3410.9
N31548918: length 1
  TOP w0.1: LED1700.1 131.59,54.54 R1719.1
N31982573: length 1.9
  BOTTOM w0.2: U700.35 105.13,33.85 104.83,34.15 C707.2
N31982835: length 7.7
  L6 w0.2: v3(107.1,36.25) 107.1,39.05 v3(104.6,41.55)
  BOTTOM w0.1: v3(104.6,41.55) 103.95,42.2 R703.2
N31984442: length 1.9
  BOTTOM w0.2: U700.26 100.63,34.22 C708.2
N31997478: length 2.8
  BOTTOM w0.2: U700.37 106.13,33.75 106.43,34.05 C701.1 106.43,35.48 R701.1
N31997490: length 2.8
  BOTTOM w0.2: R702.1 C701.2 107.23,34.25 106.63,33.65 U700.38
N32076436: length 2
  BOTTOM w0.2: U700.1 106.63,25.67 C706.1
N32076870: length 1.8
  BOTTOM w0.2: U700.6 104.13,25.35 R706.1
N32076881: length 0.8
  BOTTOM w0.2: R706.2 C711.1
N32077864: length 3.1
  BOTTOM w0.2: C712.1 C709.1 98.13,25.85 U700.18
N32077889: length 0.8
  BOTTOM w0.2: R708.1 C709.2
N32077903: length 0.9
  BOTTOM w0.1: R2419.1 R708.2
N32079044: length 2.2
  BOTTOM w0.2: C713.1 99.13,25.95 U700.16
N32079330: length 2.1
  BOTTOM w0.2: R709.1 100.63,25.55 U700.13
N32079511: length 1.9
  BOTTOM w0.2: U700.14 R710.1
N32079780: length 2.1
  BOTTOM w0.2: U700.15 99.63,25.55 R711.1
N32084044: length 2.4
  BOTTOM w0.2: R2420.2 R712.1 R707.2 C710.1
N32084048: length 2.3
  BOTTOM w0.2: U700.19 97.63,28.07 97.25,28.45 R2420.1
N32108396: length 3
  BOTTOM w0.2: TP700.1 R705.2 103.63,25.55 U700.7
N32127800: length 3.9
  BOTTOM w0.1: U3411.5 109.35,98.34 C2309.1 109.5,98.78 109.5,99.93 Y2300.3
N32128039: length 1.4
  BOTTOM w0.1: U3411.3 108.05,98 R2302.2
N32228912: length 1.1
  TOP w0.1: R2418.1 146.6,78.12 U1800.4
N32250530: length 2.8
  BOTTOM w0.1: U800.13 119.96,4.54 119.82,4.39 118.79,4.39 118.51,4.68 C800.2
N32250665: length 6.7
  L6 w0.2: v3(127.83,7.75) 122.19,7.75 v3(121.96,7.97)
  BOTTOM w0.2: R800.2 127.84,7.74 v3(127.83,7.75)
N32250673: length 1.3
  BOTTOM w0.2: U800.10 121.46,3.51 C805.2
N32250693: length 1.5
  BOTTOM w0.2: U800.1 119.96,8.18 119.4,8.74 119.4,9.24 R802.1
N32250715: length 1.2
  BOTTOM w0.1: U800.3 120.96,9.18 R804.1
N32250719: length 1.4
  BOTTOM w0.2: R803.1 121.46,8.86 U800.4
N32250721: length 0.8
  BOTTOM w0.2: C806.2 121.8,10.79 R803.2
N32254961: length 3.4
  TOP w0.2: U807.3 137.97,89.14 R819.1 137.23,87.58 R816.2 137.23,86.75 C815.2
N32255823: length 3.2
  TOP w0.3: U808.3 138.53,95.34 138.53,95.94 138.04,96.42 R820.1
N32292952: length 2.6
  BOTTOM w0.1: R3112.2 37.76,53.29 37.42,53.63 U3104.30
N32292976: length 2.4
  BOTTOM w0.1: U3104.29 38.13,54.13 R3113.2
N32293000: length 2.9
  BOTTOM w0.1: U3104.32 36.48,52.63 37.55,51.56 38.13,51.56 R3114.2
N32293024: length 2.6
  BOTTOM w0.1: U3104.28 37.34,54.63 37.7,54.99 R3115.2
N32293045: length 2.8
  BOTTOM w0.1: U3104.26 36.34,55.63 37.4,56.69 R3116.2
N32293152: length 1.1
  TOP w0.1: R3118.1 41.76,62.48 LED3101.1
N32293162: length 1.2
  TOP w0.1: LED3101.2 40.36,61.38 Q3101.3
N32294356: length 1.4
  TOP w0.1: U3002.4 26.45,78.06 R3032.2
N32294360: length 1.3
  TOP w0.1: U3002.12 26.9,73.61 C3049.1
N32294535: length 1.4
  TOP w0.1: U3203.4 R3223.2
N32294539: length 1.3
  TOP w0.1: U3203.12 26.86,67.38 C3232.1
N32294714: length 1.4
  TOP w0.1: U3204.4 26.45,65.96 R3226.2
N32294718: length 1.3
  TOP w0.1: U3204.12 26.9,61.46 C3235.1
N32294893: length 1.4
  TOP w0.1: U3205.4 R3229.2
N32294897: length 1.3
  TOP w0.1: C3238.1 26.9,54.79 U3205.12
N32410234: length 2.2
  BOTTOM w0.1: U506.1 124.47,15.37 R714.1 R713.2
N32517931: length 1.2
  TOP w0.1: U4001.9 135.19,103.13 R4006.2
N32518810: length 1.9
  TOP w0.1: R4004.1 137.64,104.97 U4001.1
N32518952: length 1.5
  TOP w0.1: U4002.10 129.83,103.53 R4010.1
N32565853: length 2.6
  TOP w0.1: J3400.15 TP3499.1
N33124736: length 3.4
  BOTTOM w0.1: R3499.2 C3498.1 128.65,106.75 128.65,108.15 128,108.8 Y3401.3
N33124752: length 1
  BOTTOM w0.1: Y3401.1 R3498.2
N33124868: length 2.2
  BOTTOM w0.1: U3409.5 128.55,104.95 128.3,105.2 127.85,105.2 127.75,105.3 R3499.1
N33124937: length 3.3
  BOTTOM w0.1: Y3402.3 115.25,107.7 114.6,107.05 113.3,107.05 C3499.1 R3497.2
N33124961: length 1
  BOTTOM w0.1: Y3402.1 R3496.2
N33125058: length 4.8
  BOTTOM w0.1: R3497.1 111.9,108 111.7,107.8 111.7,107 111.3,106.6 109.9,106.6 109.4,106.1 U3413.5

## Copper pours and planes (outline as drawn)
GND on BOTTOM (solid shape): 36.63,99.12 36.71,99.07 36.81,99.05 37.56,99.05 37.88,98.72 37.91,98.65 37.88,98.58 37.8,98.5 37.65,98.65 37.59,98.69 37.52,98.7 35.97,98.7 35.96,98.7 35.96,98.79 36.23,99.05 36.27,99.15 36.23,99.26 36,99.48 35.97,99.57 36.03,99.65 36.08,99.67
GND on BOTTOM (solid shape): 36.78,93.59 36.87,93.54 36.96,93.52 37.45,93.52 37.5,93.53 37.55,93.54 37.62,93.54 37.67,93.5 37.76,93.41 37.58,93.23 37.13,93.23 37,93.36 36.94,93.4 36.87,93.41 36.25,93.41 36.18,93.4 36.13,93.36 36.04,93.27 35.99,93.27 35.73,93.53 35.69,93.56 35.63,93.57 35.57,93.6 35.54,93.67 35.53,93.7 35.52,93.73 35.5,93.77 35.6,93.87 36.51,93.87
GND on BOTTOM (solid shape): 36.05,105.25 36.7,104.6 36.74,104.65 36.81,104.67 36.88,104.6 36.87,104.57 36.86,104.49 36.9,104.41 37.25,104.06 37.31,104.02 37.37,104.02 37.44,103.99 37.47,103.92 37.49,103.87 37.52,103.83 38.01,103.33 38.07,103.3 38.14,103.29 38.16,103.3 38.23,103.23 38.23,103.21 38.23,103.15 38.26,103.1 38.26,103.04 38.22,103.01 38.19,103.01 38.14,103 35.93,105.21 35.99,105.26
GND on BOTTOM (solid shape): outline of 115 points within 184.22,106.91 186.12,108.31
GND on BOTTOM (solid shape): outline of 115 points within 184.22,84.95 186.12,86.36
GND on BOTTOM (solid shape): outline of 115 points within 184.22,63.01 186.12,64.41
GND on BOTTOM (solid shape): outline of 115 points within 184.22,41.05 186.12,42.45
GND on BOTTOM (solid shape): outline of 115 points within 189.42,110.41 191.32,111.81
GND on BOTTOM (solid shape): outline of 115 points within 189.42,88.45 191.32,89.86
GND on BOTTOM (solid shape): outline of 115 points within 189.42,66.5 191.32,67.91
GND on BOTTOM (solid shape): outline of 115 points within 189.42,44.55 191.32,45.95
GND on BOTTOM (solid shape): 35.88,96.55 35.88,96.52 35.89,96.46 35.92,96.41 36.35,95.99 36.36,95.97 36.38,95.93 36.36,95.89 36.35,95.88 35.92,95.46 35.88,95.35 35.92,95.24 36.1,95.07 36.14,95.04 36.19,95.03 36.22,95.01 36.24,94.98 36.25,94.93 36.28,94.89 36.46,94.71 36.5,94.69 36.54,94.67 36.57,94.66 36.59,94.63 36.6,94.58 36.65,94.43 36.56,94.37 35.5,94.37 35.4,94.35 35.32,94.29 35.15,94.12 35.11,94.14 35.02,94.16 34.93,94.12 34.66,93.84 34.55,93.82 34.49,93.92 34.49,94.78 34.47,94.89 34.41,94.98 34.22,95.17 34.23,95.2 34.24,95.29 34.2,95.36 33.88,95.68 33.8,95.72 33.72,95.71 33.69,95.7 33.64,95.75 33.65,95.78 33.65,95.85 33.62,95.91 33.41,96.11 33.86,96.57 35.86,96.57
GND on BOTTOM (solid shape): outline of 103 points within 38.6,100.62 43.75,104.99
GND on BOTTOM (solid shape): outline of 159 points within 16.68,93.54 37.72,105.12
GND on BOTTOM (solid shape): outline of 440 points within 36.53,90.37 47.66,101.5
GND on BOTTOM (solid shape): outline of 385 points within 16.28,84.58 34.66,101.37
GND on BOTTOM (solid shape): outline of 792 points within 16,70.38 53.02,99.27
GND on TOP, L2, L3, L4, L5, L6, L7: 0.2,125 1.61,128.39 5,129.8 195,129.8 198.39,128.39 199.8,125 199.8,5 198.39,1.61 195,0.2 112,0.2 110.73,0.73 110.2,2 110.2,8 109.56,9.56 108,10.2 61,10.2 59.44,9.56 58.8,8 58.8,2 58.27,0.73 57,0.2 5,0.2 1.61,1.61 0.2,5
GND_EARTH on TOP: 171.9,120.11 199.8,120.11 199.8,30.61 170.97,30.61 170.85,30.73 170.85,32.71 171.13,32.99 179.17,32.99 180.34,34.16 183.09,34.16 186.02,37.09 193.33,37.09 194.23,37.99 194.23,45.55 193.2,46.58 186.66,46.58 183.4,49.84 180.72,49.84 179.55,51.01 171.2,51.01 171.03,51.19 171.03,54.95 171.15,55.07 179.74,55.07 180.91,56.24 183.66,56.24 186.28,58.87 193.42,58.87 194.25,59.7 194.25,67.39 193.11,68.53 186.52,68.53 183.72,71.32 181.24,71.32 180.2,72.36 171.65,72.36 171.61,72.32 171.41,72.32 171.01,72.72 171.01,76.07 171.34,76.4 179.22,76.4 180.86,78.04 183.52,78.04 186.35,80.87 193.56,80.87 194.32,81.62 194.32,89.49 193.32,90.49 186.59,90.49 183.59,93.49 183.59,93.51 182.93,94.17 181.14,94.17 180.03,95.27 171.8,95.27 171.14,95.94 171.14,99.02 171.45,99.33 179.78,99.33 180.63,100.17 183.56,100.17 186.25,102.86 193.5,102.86 194.36,103.73 194.36,111.04 192.95,112.46 187.6,112.46 187.58,112.44 186.81,112.44 183.58,115.66 181.55,115.66 179.41,117.8 171.61,117.8 171.52,117.9 171.52,119.74
GND_EARTH on BOTTOM: 171.9,120.11 199.8,120.11 199.8,30.61 172.6,30.61 172.4,30.81 172.4,32.99 179.17,32.99 180.34,34.16 183.09,34.16 186.02,37.09 193.33,37.09 194.23,37.99 194.23,45.55 193.2,46.58 186.66,46.58 183.4,49.84 180.72,49.84 179.64,50.93 172.6,50.93 172.25,51.28 172.25,55.07 179.74,55.07 180.91,56.24 183.66,56.24 186.28,58.87 193.42,58.87 194.25,59.7 194.25,67.39 193.11,68.53 186.52,68.53 183.72,71.32 181.24,71.32 180.2,72.36 172.82,72.36 172.41,72.77 172.41,76.04 172.76,76.4 179.22,76.4 180.86,78.04 183.52,78.04 186.35,80.87 193.56,80.87 194.32,81.62 194.32,89.49 193.32,90.49 186.59,90.49 183.59,93.49 183.59,93.51 182.93,94.17 181.14,94.17 179.41,95.89 175.11,95.89 174.64,96.36 174.64,99.12 174.84,99.33 179.78,99.33 180.63,100.17 183.56,100.17 186.25,102.86 193.5,102.86 194.36,103.73 194.36,111.04 192.95,112.46 187.6,112.46 187.58,112.44 186.81,112.44 183.58,115.66 181.55,115.66 179.41,117.8 171.61,117.8 171.52,117.9 171.52,119.74
GND_EARTH on L2: 171.9,120.11 199.8,120.11 199.8,30.61 170.97,30.61 170.85,30.73 170.85,32.71 171.13,32.99 179.17,32.99 180.34,34.16 183.09,34.16 186.02,37.09 193.33,37.09 194.23,37.99 194.23,45.55 193.2,46.58 186.66,46.58 183.4,49.84 180.72,49.84 179.64,50.93 171.28,50.93 171.03,51.19 171.03,54.95 171.15,55.07 179.74,55.07 180.91,56.24 183.66,56.24 186.28,58.87 193.42,58.87 194.25,59.7 194.25,67.39 193.11,68.53 186.52,68.53 183.72,71.32 181.24,71.32 180.2,72.36 172.79,72.36 172.42,72.73 172.42,76.04 172.77,76.4 179.22,76.4 180.86,78.04 183.52,78.04 186.35,80.87 193.56,80.87 194.32,81.62 194.32,89.49 193.32,90.49 186.59,90.49 183.59,93.49 183.59,93.51 182.93,94.17 181.14,94.17 179.92,95.38 179.92,95.38 179.4,95.91 175.09,95.91 174.63,96.36 174.63,99.13 174.83,99.33 179.78,99.33 180.63,100.17 183.56,100.17 186.25,102.86 193.5,102.86 194.36,103.73 194.36,111.04 192.95,112.46 187.6,112.46 187.58,112.44 186.81,112.44 183.58,115.66 181.55,115.66 179.41,117.8 171.61,117.8 171.52,117.9 171.52,119.74
GND_EARTH on L3: outline of 83 points within 170.85,30.61 199.8,120.11
GND_EARTH on L4: 171.9,120.11 199.8,120.11 199.8,30.61 170.97,30.61 170.85,30.73 170.85,32.71 171.13,32.99 179.17,32.99 180.34,34.16 183.09,34.16 186.02,37.09 193.33,37.09 194.23,37.99 194.23,45.55 193.2,46.58 186.66,46.58 183.4,49.84 180.72,49.84 179.64,50.93 171.28,50.93 171.03,51.19 171.03,54.95 171.15,55.07 179.74,55.07 180.91,56.24 183.66,56.24 186.28,58.87 193.42,58.87 194.25,59.7 194.25,67.39 193.11,68.53 186.52,68.53 183.72,71.32 181.24,71.32 180.2,72.36 172.81,72.36 172.4,72.77 172.4,76.02 172.78,76.4 179.22,76.4 180.86,78.04 183.52,78.04 186.35,80.87 193.56,80.87 194.32,81.62 194.32,89.49 193.32,90.49 186.59,90.49 183.59,93.49 183.59,93.51 182.93,94.17 181.14,94.17 180.01,95.29 180.01,95.31 179.41,95.91 179.41,95.91 175.08,95.91 174.63,96.36 174.63,99.13 174.83,99.33 179.78,99.33 180.63,100.17 183.56,100.17 186.25,102.86 193.5,102.86 194.36,103.73 194.36,111.04 192.95,112.46 187.6,112.46 187.58,112.44 186.81,112.44 183.58,115.66 181.55,115.66 179.41,117.8 171.61,117.8 171.52,117.9 171.52,119.74
GND_EARTH on L5: 174.96,120.11 199.8,120.11 199.8,30.61 170.97,30.61 170.85,30.73 170.85,32.71 171.13,32.99 179.17,32.99 180.34,34.16 183.09,34.16 185.24,36.32 192.56,36.32 194.23,37.99 194.23,45.55 193.2,46.58 186.66,46.58 183.4,49.84 180.72,49.84 179.64,50.93 171.28,50.93 171.03,51.19 171.03,54.95 171.15,55.07 179.74,55.07 180.91,56.24 183.66,56.24 186.28,58.87 193.42,58.87 194.25,59.7 194.25,67.39 193.11,68.53 186.52,68.53 183.72,71.32 181.24,71.32 180.2,72.36 172.81,72.36 172.4,72.77 172.4,76.03 172.76,76.4 179.22,76.4 180.86,78.04 183.52,78.04 186.35,80.87 193.56,80.87 194.32,81.62 194.32,89.49 193.32,90.49 186.59,90.49 183.59,93.49 183.59,93.51 182.93,94.17 181.14,94.17 179.97,95.33 179.97,95.34 179.4,95.91 175.09,95.91 174.63,96.36 174.63,99.13 174.83,99.33 179.78,99.33 180.63,100.17 183.56,100.17 186.25,102.86 193.5,102.86 194.36,103.73 194.36,111.04 192.95,112.46 187.6,112.46 187.58,112.44 186.81,112.44 183.58,115.66 181.55,115.66 179.41,117.8 174.99,117.8 174.73,118.06 174.73,119.88
GND_EARTH on L6: 171.9,120.11 199.8,120.11 199.8,30.61 172.6,30.61 172.4,30.81 172.4,32.99 179.17,32.99 180.34,34.16 183.09,34.16 184.79,35.87 187.27,35.87 187.8,36.39 192.63,36.39 194.23,37.99 194.23,45.55 193.2,46.58 186.66,46.58 183.4,49.84 180.72,49.84 179.64,50.93 172.5,50.93 172.25,51.18 172.25,55.07 179.74,55.07 180.91,56.24 183.66,56.24 185.21,57.8 187.62,57.8 188.15,58.33 192.88,58.33 194.25,59.7 194.25,67.39 193.11,68.53 186.52,68.53 183.72,71.32 181.24,71.32 180.2,72.36 172.82,72.36 172.41,72.77 172.41,76.05 172.75,76.4 179.22,76.4 180.86,78.04 183.52,78.04 186.35,80.87 193.56,80.87 194.32,81.62 194.32,89.49 193.32,90.49 186.59,90.49 183.59,93.49 183.59,93.51 182.93,94.17 181.14,94.17 179.4,95.91 175.09,95.91 174.63,96.37 174.63,99.13 174.83,99.33 179.78,99.33 180.63,100.17 183.56,100.17 186.25,102.86 193.5,102.86 194.36,103.73 194.36,111.04 192.95,112.46 187.6,112.46 187.58,112.44 186.81,112.44 183.58,115.66 181.55,115.66 179.41,117.8 171.61,117.8 171.52,117.9 171.52,119.74
GND_EARTH on L7: 171.9,120.11 199.8,120.11 199.8,30.61 172.59,30.61 172.4,30.8 172.4,32.99 179.17,32.99 180.34,34.16 183.09,34.16 186.02,37.09 193.33,37.09 194.23,37.99 194.23,45.55 193.2,46.58 186.66,46.58 183.4,49.84 180.72,49.84 179.64,50.93 172.5,50.93 172.25,51.18 172.25,55.07 179.74,55.07 180.91,56.24 183.66,56.24 186.28,58.87 193.42,58.87 194.25,59.7 194.25,67.39 193.11,68.53 186.52,68.53 183.72,71.32 181.24,71.32 180.2,72.36 172.82,72.36 172.41,72.77 172.41,76.06 172.74,76.4 179.22,76.4 180.86,78.04 183.52,78.04 186.35,80.87 193.56,80.87 194.32,81.62 194.32,89.49 193.32,90.49 186.59,90.49 183.59,93.49 183.59,93.51 182.93,94.17 181.14,94.17 179.4,95.9 175.09,95.9 174.63,96.36 174.63,99.13 174.83,99.33 179.78,99.33 180.63,100.17 183.56,100.17 186.25,102.86 193.5,102.86 194.36,103.73 194.36,111.04 192.95,112.46 187.6,112.46 187.58,112.44 186.81,112.44 183.58,115.66 181.55,115.66 179.41,117.8 171.61,117.8 171.52,117.9 171.52,119.74
GND_EARTH1 on BOTTOM: 105.77,122.31 105.77,120.54 106.03,120.29 108.91,120.29 109.11,120.48 109.11,121.8 108.25,122.67 106.13,122.67
GND_EARTH1 on BOTTOM: 125.97,121.36 125.97,120.6 126.13,120.44 132.01,120.44 132.14,120.57 132.14,121.51 130.92,122.73 127.34,122.73
GND_EARTH1 on BOTTOM: 111.15,121.59 111.15,120.57 111.33,120.4 116.33,120.4 116.4,120.47 116.4,121.43 115.12,122.71 112.27,122.71
GND_EARTH1 on BOTTOM: 118.38,121.44 118.38,120.57 118.53,120.42 123.86,120.42 123.94,120.5 123.94,121.31 122.52,122.73 119.66,122.73
GND_EARTH1 on L6: 105.61,122.88 105.61,120.65 106.04,120.22 130.87,120.22 131.36,120.71 131.36,123.09 131.12,123.32 106.05,123.32
GND_EARTH1 on L7: 135.65,123.34 106.02,123.34 105.61,122.92 105.61,120.65 106.05,120.21 135.47,120.21 135.88,120.62 135.88,123.1
GND_EARTH2 on TOP: 22.29,115.17 22.29,118.1 21.29,119.1 11.59,119.1 10.49,118 10.49,100.47 11.25,99.71 22.04,99.71 22.74,100.4 22.74,101.8 22.62,101.92 14.27,101.92 13.39,102.8 13.39,115.27 14.46,116.34 19.53,116.34 20.89,114.98 22.1,114.98
GND_EARTH2 on BOTTOM: 22.29,115.17 22.29,118.1 21.29,119.1 11.59,119.1 10.49,118 10.49,100.47 11.25,99.71 13.87,99.71 14.31,100.14 14.31,101.92 14.27,101.92 13.39,102.8 13.39,115.27 14.46,116.34 19.53,116.34 20.89,114.98 22.1,114.98
GND_EARTH2 on L2: 22.29,115.17 22.29,118.1 21.29,119.1 11.59,119.1 10.49,118 10.49,100.47 11.25,99.71 13.81,99.71 14.31,100.2 14.31,101.88 13.39,102.8 13.39,115.27 14.46,116.34 19.53,116.34 20.89,114.98 22.1,114.98
GND_EARTH2 on L3: 22.29,115.17 22.29,118.1 21.29,119.1 11.59,119.1 10.49,118 10.49,100.47 11.25,99.71 13.89,99.71 13.89,99.71 14.32,100.14 14.32,101.87 13.39,102.8 13.39,115.27 14.46,116.34 19.53,116.34 20.89,114.98 22.1,114.98
GND_EARTH2 on L4, L5: 22.29,115.17 22.29,118.1 21.29,119.1 11.59,119.1 10.49,118 10.49,100.47 11.25,99.71 13.87,99.71 14.31,100.14 14.31,101.88 13.39,102.8 13.39,115.27 14.46,116.34 19.53,116.34 20.89,114.98 22.1,114.98
GND_EARTH2 on L6: 22.29,115.17 22.29,118.1 21.29,119.1 11.59,119.1 10.49,118 10.49,100.47 11.25,99.71 13.8,99.71 14.31,100.22 14.31,101.88 13.39,102.8 13.39,115.27 14.46,116.34 19.53,116.34 20.89,114.98 22.1,114.98
GND_EARTH2 on L7: 22.29,115.17 22.29,118.1 21.29,119.1 11.59,119.1 10.49,118 10.49,100.47 11.25,99.71 13.87,99.71 14.31,100.14 14.31,101.88 13.39,102.8 13.39,115.27 14.46,116.34 19.53,116.34 20.89,114.98 22.1,114.98
GND_TOP on TOP, L2: 109.23,29.65 109.23,28.79 109.48,28.53 122.36,28.53 124.07,26.82 133.18,26.82 133.35,26.99 133.35,29.57 133.01,29.91 109.48,29.91
GND_TOP on L3: 109.23,29.64 109.23,28.78 110.08,27.93 122.95,27.93 124.07,26.81 132.55,26.81 132.98,27.25 132.98,29.13 132.22,29.9 109.48,29.9
VCC_+6V7_GMSL_1 on TOP: 28.4,101.44 26.86,101.44 26.61,101.19 26.61,99.83 27.54,98.91 28.1,98.91 28.62,99.43 28.62,101.22
VCC_+6V7_GMSL_1 on BOTTOM: 21.12,102.99 21.12,101.53 21.51,101.14 21.72,101.14 21.83,101.04 21.83,97.55 21.99,97.39 22.84,97.39 25.61,100.17 25.61,103.13 25.57,103.18 21.31,103.18
VCC_+6V7_GMSL_1 on L3: 25.54,101.05 25.54,100.22 25.67,100.09 27.27,100.09 27.3,100.12 27.3,101.06 27.24,101.13 25.61,101.13
VCC_+6V7_GMSL_1 on L6: 24.94,100.05 26.56,100.05 26.9,100.4 26.9,101.55 26.74,101.72 25,101.72 24.79,101.51 24.79,100.2
VCC_+6V7_GMSL_2 on TOP: 23.6,92.41 23.6,90.86 23.85,90.62 25.21,90.62 26.13,91.54 26.13,92.11 25.61,92.63 23.82,92.63
VCC_+6V7_GMSL_2 on BOTTOM: 23.37,94.04 23.37,90.53 23.02,90.19 22.68,90.19 22.51,90.01 22.51,89.49 22.66,89.33 24.24,89.33 24.93,90.02 27.67,90.02 27.71,90.06 27.71,91.9 25.45,94.16 23.48,94.16
VCC_+6V7_GMSL_2 on L3: 23.67,90.23 24.5,90.23 24.63,90.36 24.63,91.96 24.59,92 23.65,92 23.59,91.93 23.59,90.31
VCC_+6V7_GMSL_2 on L6: 27.56,90.22 27.56,91.11 27.14,91.54 23.75,91.54 23.55,91.34 23.55,90.2 23.82,89.93 27.26,89.93
VCC_+6V7_GMSL_3 on TOP: 23.61,86.67 23.61,85.12 23.85,84.88 25.22,84.88 26.14,85.8 26.14,86.37 25.62,86.89 23.83,86.89
VCC_+6V7_GMSL_3 on BOTTOM: 20.93,89.81 20.93,89.02 21.19,88.75 21.68,88.75 21.75,88.69 21.75,85.1 21.81,85.04 25.3,85.04 26.36,86.1 26.36,86.93 26.22,87.07 23.43,87.07 23.14,87.37 23.14,88.59 22.57,89.16 21.58,89.16 21.45,89.29 21.45,89.75 21.34,89.86 20.98,89.86
VCC_+6V7_GMSL_3 on L3: 25.56,87.22 24,87.22 23.59,86.81 23.59,85.84 23.74,85.68 25.51,85.68 25.77,85.94 25.77,87.02
VCC_+6V7_GMSL_3 on L6: 26.18,87.37 24.86,87.37 24.6,87.11 24.6,86.23 24.8,86.03 25.98,86.03 26.33,86.38 26.33,87.22
VCC_+6V7_GMSL_4 on TOP: 23.67,81.09 23.67,79.54 23.91,79.3 25.28,79.3 26.2,80.22 26.2,80.79 25.68,81.31 23.89,81.31
VCC_+6V7_GMSL_4 on BOTTOM: 23.11,82.38 23.11,78.7 22.65,78.24 22.65,77.49 22.74,77.4 23.14,77.4 24.64,78.9 27.24,78.9 27.44,79.11 27.44,81.24 26.21,82.48 23.2,82.48
VCC_+6V7_GMSL_4 on L3: 25.45,80.69 23.89,80.69 23.48,80.28 23.48,79.31 23.64,79.16 25.4,79.16 25.66,79.41 25.66,80.49
VCC_+6V7_GMSL_4 on L6: 27.2,80.29 24.34,80.29 24.11,80.06 24.11,79.19 24.35,78.94 26.99,78.94 27.35,79.3 27.35,80.14
VCC_+6V7_GMSL_5 on TOP: 23.6,75.48 23.6,73.98 23.87,73.71 25.23,73.71 26.16,74.63 26.16,75.2 25.64,75.72 23.84,75.72
VCC_+6V7_GMSL_5 on BOTTOM: 18.96,78.95 18.96,78.35 19.32,78 19.69,78 19.76,77.93 19.76,74.59 20.02,74.33 20.86,74.33 21.36,74.83 21.93,74.83 21.94,74.82 23.87,74.82 24.07,75.02 24.07,76.37 23.35,77.08 21.48,77.08 21.16,77.4 21.16,77.93 20.75,78.34 20.08,78.34 19.4,79.02 19.03,79.02
VCC_+6V7_GMSL_5 on L3: 25.44,75.06 23.88,75.06 23.47,74.64 23.47,73.67 23.62,73.52 25.39,73.52 25.65,73.77 25.65,74.85
VCC_+6V7_GMSL_5 on L6: 23.28,75.29 23.28,74.21 23.62,73.87 24.94,73.87 25.22,74.15 25.22,74.85 24.65,75.42 23.41,75.42
VCC_+6V7_GMSL_6 on TOP: 23.61,69.27 23.61,67.72 23.86,67.48 25.22,67.48 26.15,68.4 26.15,68.97 25.63,69.49 23.83,69.49
VCC_+6V7_GMSL_6 on BOTTOM: 23.07,65.43 23.07,65.92 23.81,66.65 23.81,69.85 23.8,69.86 23.8,69.95 24.01,70.17 25.14,70.17 25.36,69.94 25.36,68.81 25.57,68.6 28.02,68.6 28.22,68.41 28.22,65.98 27.54,65.31 23.19,65.31
VCC_+6V7_GMSL_6 on L3: 25.41,69.01 23.73,69.01 23.52,68.8 23.52,67.69 23.74,67.47 25.36,67.47 25.62,67.73 25.62,68.8
VCC_+6V7_GMSL_6 on L6: 27.95,68.63 24.28,68.63 24.12,68.47 24.12,67.5 24.47,67.15 27.61,67.15 28.1,67.64 28.1,68.48
VCC_+6V7_GMSL_7 on TOP: 23.62,63.34 23.62,61.79 23.86,61.55 25.23,61.55 26.15,62.47 26.15,63.04 25.63,63.56 23.84,63.56
VCC_+6V7_GMSL_7 on BOTTOM: 21.42,65.65 21.42,65.05 21.63,64.84 22.01,64.84 22.19,64.66 22.19,61.09 22.26,61.02 23.4,61.02 23.88,61.5 23.88,62.44 24.05,62.62 26.57,62.62 26.73,62.77 26.73,64.26 25.83,65.15 22.28,65.15 21.94,65.49 21.94,65.69 21.87,65.77 21.53,65.77
VCC_+6V7_GMSL_7 on L3: 25.44,63.11 23.76,63.11 23.61,62.96 23.61,61.78 23.82,61.57 25.39,61.57 25.65,61.83 25.65,62.9
VCC_+6V7_GMSL_7 on L6: 26.47,63.29 24.78,63.29 24.44,62.95 24.44,62.02 24.66,61.81 26.2,61.81 26.56,62.16 26.56,63.2
VCC_+6V7_GMSL_8 on TOP: 23.63,56.66 23.63,55.11 23.87,54.87 25.24,54.87 26.16,55.79 26.16,56.35 25.64,56.87 23.85,56.87
VCC_+6V7_GMSL_8 on BOTTOM: 23.43,57.82 23.43,54.24 23.14,53.96 22.95,53.96 22.84,53.85 22.84,53.27 23,53.11 24.61,53.11 24.8,53.3 27.46,53.3 27.6,53.45 27.6,56.76 26.46,57.9 23.51,57.9
VCC_+6V7_GMSL_8 on L3: 25.45,56.4 23.89,56.4 23.61,56.12 23.61,55.02 23.77,54.86 25.39,54.86 25.65,55.12 25.65,56.19
VCC_+6V7_GMSL_8 on L6: 26.73,55.86 24.36,55.86 24.25,55.75 24.25,54.8 24.66,54.38 26.9,54.38 27.05,54.53 27.05,55.54
VDD10 on TOP: 28.71,117.65 27.29,117.65 26.97,117.32 26.97,113.17 27.36,112.77 28.73,112.77 29,113.04 29,117.36
VDD33 on TOP: 41.34,108.6 38.48,108.6 38.16,108.29 38.16,107.48 38.28,107.35 41.43,107.35 41.55,107.48 41.55,108.39
VDD33_USB on BOTTOM: 129.21,55.51 129.21,53.17 129.79,52.58 130.29,52.58 130.41,52.7 130.41,53.86 131.39,54.84 131.39,55.45 131.24,55.6 129.29,55.6
VDDREG_VDD33 on TOP: 41.15,114.4 40.3,114.4 40,114.1 40,109.4 40.39,109.01 41.35,109.01 41.45,109.12 41.45,114.1
VIN+ on TOP: 176.32,22.65 176.32,11.01 177.73,9.6 184.1,9.6 184.56,10.06 184.56,23.11 183.29,24.38 178.05,24.38
VIN+ on BOTTOM: 179.25,10.65 184.85,10.65 185.4,11.2 185.4,24.95 185.3,25.05 179.4,25.05 179.25,24.9
VIN+ on BOTTOM: 146.84,12.55 146.84,7.14 149.28,4.7 161.05,4.7 162.39,6.04 162.39,12.55
VIN+ on L5, L6: 151.91,9.31 151.91,5.04 152.2,4.75 159.15,4.75 161.25,6.85 181.05,6.85 181.25,7.05 181.25,14.9 181,15.15 152.1,15.15 151.91,14.96
VIN- on TOP: 189.68,16.47 187.1,16.47 184.85,18.71 184.85,23.6 183.74,24.71 154.5,24.71 153.69,25.53 153.69,29.07 154.8,30.18 189.78,30.18 191.47,28.49 191.47,18.25
VIN- on L2: 189.68,16.47 187.1,16.47 185.1,18.46 185.1,23.35 183.74,24.71 154.5,24.71 153.69,25.53 153.69,29.56 154.31,30.18 189.78,30.18 191.47,28.49 191.47,18.25
VIN- on L3: 189.68,16.47 187.1,16.47 185.1,18.46 185.1,23.35 183.74,24.71 154.5,24.71 153.69,25.53 153.69,28.9 154.97,30.18 189.78,30.18 191.47,28.49 191.47,18.25
VIN_HV on TOP: 178.28,123.55 179.9,123.55 180.31,123.95 187.85,123.95 188.13,123.67 188.13,121.31 187.46,120.64 177.93,120.64 177.62,120.95 177.62,122.9
VIN_HV on TOP: 157.7,30.46 162.25,30.46 162.67,30.88 162.67,34.46 162.37,34.76 158.32,34.76 157.3,33.73 157.3,30.86
VIN_HV on BOTTOM: 167.01,32.02 158.94,32.02 158.42,31.5 148.8,31.5 148.43,31.88 144.57,31.88 143.75,31.05 143.75,19.1 144.05,18.8 144.9,18.8 144.9,18.8 169.64,18.8 171.18,17.25 175.11,17.25 176.26,18.41 176.26,22.77
VIN_HV on L3: 162.62,120.62 178.68,120.62 179.44,121.37 179.44,122.43 178.85,123.02 162.64,123.02 162.46,122.83 162.44,122.83 162.44,120.8
VIN_HV on L5: 160.86,40.69 160.86,49.43 162.28,50.86 162.28,122.14 162.8,122.66 164.66,122.66 165.49,121.82 165.49,42.41 166.4,41.5 166.4,40.48 166.08,40.16 161.38,40.16
VIN_HV on L6: 163.18,29.82 166.17,29.82 166.8,30.45 166.8,40.82 166.15,41.47 163.62,41.47 162.49,40.34 162.49,30.51
VIN_P5V on BOTTOM: 90,80.6 98.25,80.6 98.35,80.7 98.35,84.7 98.15,84.9 89.8,84.9 89.7,84.8 89.7,80.9
VIN_SUB_9TO30V on BOTTOM: 88.7,61.02 84.62,61.02 84.5,60.9 84.5,58.25 84.58,58.17 88.8,58.17 88.95,58.32 88.95,60.77
VIN_SUB_9TO30V on BOTTOM: 114.6,48.95 114.45,48.8 114.45,44.35 114.6,44.2 118.7,44.2 121.5,41.4 121.5,31.95 122.1,31.35 125.4,31.35 125.55,31.5 125.55,34.1 125.85,34.4 128.15,34.4 128.3,34.55 128.3,48.75 128.1,48.95
VIN_SUB_9TO30V on BOTTOM: 88.4,86.8 88.6,86.6 91.57,86.6 91.63,86.67 91.63,88.05 91.43,88.25 88.5,88.25 88.4,88.15
VIN_SUB_9TO30V on L5: 117.06,32.75 87.44,32.75 87.27,32.58 87.27,29.38 87.6,29.05 117.25,29.05 117.51,29.31 117.51,32.31
VIN_SUB_9TO30V on L6: 89.49,87.71 89.49,31.71 89.09,31.31 87.41,31.31 87.26,31.45 87.26,87.75 87.31,87.8 89.4,87.8
VIN_SUB_9TO30V on L6: 116.18,32.71 116.18,31.15 116.5,30.83 119.59,30.83 119.77,31.02 119.77,32.35 120.47,33.05 122.4,33.05 122.6,33.25 122.6,35.05 122.4,35.25 118.72,35.25
(no net) on BOTTOM: 0.2,125 1.61,128.39 5,129.8 195,129.8 198.39,128.39 199.8,125 199.8,5 198.39,1.61 195,0.2 112,0.2 110.73,0.73 110.2,2 110.2,8 109.56,9.56 108,10.2 61,10.2 59.44,9.56 58.8,8 58.8,2 58.27,0.73 57,0.2 5,0.2 1.61,1.61 0.2,5
5P0_PWM1_L on BOTTOM: 94.11,71.52 94.11,70.89 94.18,70.82 94.94,70.82 95.12,71 97.45,71 97.7,70.75 97.7,68.4 97.75,68.35 98.4,68.35 98.45,68.4 98.45,71.13 98,71.58 94.16,71.58
8211_1_REGOUT on TOP: 88.62,111.1 88.62,107.14 89.21,106.55 90.02,106.55 90.43,106.97 90.43,111.15 90.39,111.19 88.71,111.19
DES0_SIOA on BOTTOM: 15.19,95.16 14.08,95.16 13.96,95.04 13.96,94.26 14.07,94.15 16.63,94.15 16.7,94.23 16.7,94.97 16.64,95.03 15.32,95.03
DES0_SIOB on BOTTOM: 13.94,93.94 13.83,93.82 13.83,93.04 13.93,92.93 15.06,92.93 15.19,93.06 16.56,93.06 16.66,93.15 16.66,93.8 16.52,93.94
DES0_SIOC on BOTTOM: 13.92,85.16 13.8,85.04 13.8,84.26 13.91,84.16 16.51,84.16 16.57,84.22 16.57,85.08 16.49,85.16
DES0_SIOD on BOTTOM: 13.99,83.94 13.87,83.82 13.87,83.04 13.98,82.93 16.41,82.93 16.56,83.09 16.56,83.85 16.47,83.94
DES1_SIOA on BOTTOM: 16.15,70.38 13.25,70.38 13.22,70.35 13.22,69.47 13.32,69.37 16.16,69.37 16.3,69.51 16.3,70.23
DES1_SIOB on BOTTOM: 16.15,69.03 13.55,69.03 13.37,68.85 13.37,68.15 13.49,68.03 16.16,68.03 16.29,68.16 16.29,68.89
DES1_SIOC on BOTTOM: 16.76,60.38 14.38,60.38 14.19,60.2 14.19,59.57 14.38,59.38 16.77,59.38 16.9,59.51 16.9,60.24
DES1_SIOD on BOTTOM: 16.76,59.05 14.24,59.05 14.18,58.99 14.18,58.15 14.28,58.04 16.77,58.04 16.91,58.18 16.91,58.9
HDMI2_5V_CONN on TOP: 26.86,37.07 26.86,36.66 26.94,36.58 28.99,36.58 29,36.59 30.52,36.59 30.77,36.84 30.77,37.37 30.49,37.65 27.45,37.65
HDMI3_5V_CONN on BOTTOM: 29.51,45.98 29.51,43.94 29.72,43.74 31.26,43.74 31.35,43.83 31.35,44.63 31.09,44.89 30.28,44.89 29.99,45.18 29.99,45.98 29.92,46.05 29.59,46.05
HDMI_5V on BOTTOM: 50.29,56.45 44.96,56.45 44.77,56.26 44.77,55.29 44.94,55.11 46.2,55.11 46.43,55.35 50.19,55.35 50.36,55.52 50.36,56.38
HDMI_5V on L3: 46.48,51.05 46.29,50.86 43.54,50.86 43.53,50.87 34.77,50.87 34.52,50.62 29.85,50.62 29.64,50.4 29.64,50.02 29.74,49.92 34.84,49.92 35.18,50.26 46.82,50.26 47.1,50.55 47.1,50.91 46.97,51.05
HDMI_5V on L6: 45.08,55.97 45.08,52.05 46.63,50.51 46.95,50.51 47.18,50.74 47.18,51.41 46.05,52.54 46.05,55.75 45.7,56.1 45.21,56.1
HUB_USB1_DM_CON on BOTTOM (solid shape): outline of 115 points within 189.42,83.95 191.32,85.36
HUB_USB1_DP_CON on BOTTOM (solid shape): outline of 115 points within 189.42,85.95 191.32,87.36
HUB_USB2_RX_M_CON on BOTTOM (solid shape): outline of 115 points within 184.22,88.95 186.12,90.36
HUB_USB2_RX_P_CON on BOTTOM (solid shape): outline of 115 points within 184.22,86.95 186.12,88.36
HUB_USB2_TX_M_CON on BOTTOM (solid shape): outline of 115 points within 184.22,82.95 186.12,84.36
HUB_USB2_TX_P_CON on BOTTOM (solid shape): outline of 115 points within 184.22,80.95 186.12,82.35
HUB_USB3_DM_CON on BOTTOM (solid shape): outline of 115 points within 189.42,105.91 191.32,107.31
HUB_USB3_DP_CON on BOTTOM (solid shape): outline of 115 points within 189.42,107.91 191.32,109.31
HUB_USB4_RX_M_CON on BOTTOM (solid shape): outline of 115 points within 184.22,110.91 186.12,112.31
HUB_USB4_RX_P_CON on BOTTOM (solid shape): outline of 115 points within 184.22,108.91 186.12,110.31
HUB_USB4_TX_M_CON on BOTTOM (solid shape): outline of 115 points within 184.22,104.91 186.12,106.31
HUB_USB4_TX_P_CON on BOTTOM (solid shape): outline of 115 points within 184.22,102.9 186.12,104.3
IT6563_RXAVDD10_1 on BOTTOM: 34.21,27.31 31.77,27.31 31.7,27.24 31.7,26.82 31.04,26.16 31.04,25.42 31.34,25.12 32.16,25.12 32.32,25.28 32.32,26.46 32.63,26.77 34.25,26.77 34.29,26.82 34.29,27.23
IT6563_RXAVDD10_2 on BOTTOM: 57.68,23.44 57.68,22.97 57.74,22.9 60.42,22.9 60.56,23.04 60.56,24.12 60.81,24.37 60.81,25.04 60.5,25.34 59.83,25.34 59.5,25.02 59.5,23.75 59.27,23.51 57.75,23.51
IT6563_RXAVDD10_3 on BOTTOM: 42.32,33.82 44.8,33.82 45.45,33.17 46.25,33.17 46.4,33.32 46.4,33.92 45.95,34.36 42.34,34.36 42.23,34.25 42.23,33.91
LM5177_VIN on BOTTOM: 109.7,41.75 109.9,41.95 119.75,41.95 120.85,40.85 120.85,37.05 120.55,36.75 109.85,36.75 109.7,36.9
LX on TOP: 137,57.46 137,56.07 137.47,55.6 141.57,55.6 143.89,57.92 143.89,58.73 143.84,58.78 142.41,58.78 142.11,58.48 142.11,57.37 141,56.27 139.32,56.27 138.8,56.78 138.8,57.53 138.76,57.58 137.12,57.58
Net_555 on BOTTOM (solid shape): outline of 115 points within 184.22,43.05 186.12,44.45
Net_556 on BOTTOM (solid shape): outline of 115 points within 184.22,45.05 186.12,46.45
Net_557 on BOTTOM (solid shape): outline of 115 points within 184.22,37.05 186.12,38.45
Net_558 on BOTTOM (solid shape): outline of 115 points within 184.22,39.05 186.12,40.45
Net_564 on BOTTOM (solid shape): outline of 115 points within 184.22,65 186.12,66.41
Net_565 on BOTTOM (solid shape): outline of 115 points within 184.22,67 186.12,68.41
Net_566 on BOTTOM (solid shape): outline of 115 points within 184.22,59 186.12,60.4
Net_567 on BOTTOM (solid shape): outline of 115 points within 184.22,61.01 186.12,62.41
RTL8367_AVDDL on TOP: 136.55,61.7 136.55,63.1 136.6,63.15 139.35,63.15 139.4,63.1 139.4,62.6 139.3,62.5 137.35,62.5 137.3,62.45 137.3,61.75 137.25,61.7
RTL8367_AVDDL on TOP: 155.02,75.2 155.02,74.76 155.11,74.67 157.84,74.67 158.17,74.34 158.17,74.15 158.4,73.92 158.86,73.92 158.91,73.98 158.91,75.3 158.83,75.38 155.2,75.38
RTL8367_DVDDIO on TOP: 128.06,67.53 128.06,63.98 128.13,63.91 128.83,63.91 128.95,64.03 128.95,65.73 129.18,65.96 130.32,65.96 130.71,66.36 130.71,67.46 130.7,67.47 130.7,72.46 130.55,72.62 128.35,72.62 128.3,72.57 128.3,72.17 128.35,72.12 129.3,72.12 129.45,71.97 129.45,68.91
RTL8367_DVDDIO on TOP: 159.02,46.98 159.02,47.7 158.96,47.76 155.47,47.76 155.4,47.69 155.4,47.08 155.61,46.87 158.91,46.87
RTL8367_DVDDIO2 on TOP: 140.88,66.7 137.93,66.7 137.86,66.63 137.86,66.22 137.95,66.13 140.93,66.13 141.06,66.26 141.06,66.52
RTL8367_DVDDIO_F on TOP: 127.57,78.34 127.57,77.36 127.69,77.25 127.69,76.64 127.74,76.59 128.25,76.59 129.16,77.49 129.16,77.87 129.56,78.27 129.56,78.79 129.64,78.88 130.15,78.88 130.25,78.97 130.25,78.97 130.25,79.36 130.2,79.42 129.63,79.42 129.17,78.96 129.17,78.59 129.01,78.42 127.65,78.42
RTL8367_DVDDL on TOP: 140.74,61.32 136.67,61.32 136.6,61.25 136.6,58.77 137.09,58.28 138.78,58.28 138.94,58.44 138.94,60.19 139.27,60.52 140.81,60.52 140.87,60.58 140.87,61.19
RTL8367_SVDDH on TOP: 137.82,67.53 137.82,67.02 138.03,66.8 140.88,66.8 140.92,66.85 140.92,67.28 140.88,67.33 139.42,67.33 139.11,67.63 137.91,67.63
SPK_L_N on TOP: 86.6,121.21 85.31,121.21 84.28,120.17 82.75,120.17 82.5,119.92 82.5,116.4 82.8,116.1 83.9,116.1 84.14,116.34 84.14,117.09 84.9,117.84 84.9,117.84 85.31,118.25 86.8,118.25 87,118.45 87,121.1 86.89,121.2 86.61,121.2
SPK_L_N on BOTTOM: 83.95,120.55 89.3,120.55 89.4,120.45 89.4,116.65 89.15,116.4 83.65,116.4 83.6,116.45 83.6,120.2
SPK_L_N on L3: 84.05,118.5 86.2,118.5 86.25,118.55 86.25,119.95 86.2,120 84.05,120 84,119.95 84,118.55
SPK_L_N on L6: 84.9,120.5 87,120.5 87.05,120.45 87.05,118.85 87,118.8 84.95,118.8 84.85,118.9 84.85,120.45
SPK_L_P on TOP: 84.9,117.5 84.6,117.2 84.6,116.2 84.62,116.18 88.65,116.18 90.37,117.9 90.37,120.16 89.28,121.25 87.4,121.25 87.25,121.1 87.25,118.3 86.95,118 85.4,118 84.9,117.5
SPK_L_P on BOTTOM: 91.3,120.5 95.55,120.5 95.65,120.4 95.65,116.6 95.4,116.35 91.35,116.35 91.2,116.5 91.2,120.4
SPK_L_P on L3: 92.78,118.7 92.78,119.92 92.65,120.05 89.55,120.05 89.5,120 89.5,118.65 89.6,118.55 92.63,118.55
SPK_L_P on L6: 93.35,120.5 93.35,119.15 93.3,119.1 91.35,119.1 91.2,119.25 91.2,120.5 91.25,120.55 93.3,120.55
SPK_R_N on TOP: 73.9,121.05 72.67,119.83 72.67,116.64 73.17,116.15 75.58,116.15 75.78,116.35 75.78,120.71 75.75,120.74 75.75,120.95 75.65,121.05
SPK_R_N on BOTTOM: 71.9,116.4 67.25,116.4 67.1,116.55 67.1,120.45 67.15,120.5 71.4,120.5 71.95,119.95 71.95,116.45
SPK_R_N on L3: 73.45,119.8 73.45,118.4 73.4,118.35 71.7,118.35 71.65,118.4 71.65,119.85 71.7,119.9 73.35,119.9
SPK_R_N on L6: 70.45,120.45 70.45,118.35 70.55,118.25 72.45,118.25 72.55,118.35 72.55,119.75 71.8,120.5 70.5,120.5
SPK_R_P on TOP: 78.74,120.34 78.03,121.05 76.25,121.05 76,120.8 76,116.3 76.15,116.15 78.5,116.15 78.74,116.39
SPK_R_P on BOTTOM: 79.55,116.4 79.55,119.35 78.4,120.5 74.1,120.5 74.05,120.45 74.05,116.6 74.25,116.4
SPK_R_P on L3: 78.7,119.92 76.75,119.92 76.6,119.77 76.6,118.45 76.7,118.35 78.7,118.35 78.8,118.45 78.8,119.82
SPK_R_P on L6: 78.3,120.45 78.3,118.5 78.2,118.4 76.65,118.4 76.6,118.45 76.6,120.45 76.65,120.5 78.25,120.5
SW1 on BOTTOM: 109.25,37 108.92,36.67 106.67,36.67 105.95,35.95 105.95,34.45 105.9,34.4 105.5,34.4 105.45,34.45 105.45,42.95 105.6,43.1 107.85,43.1 108,42.95 108,39.85 108.2,39.65 109.2,39.65 109.25,39.6
SW2 on BOTTOM: 97.7,54.65 97.7,43.5 96.83,42.62 96.83,37.42 96.75,37.35 93.05,37.35 92.8,37.6 92.8,39.9 94.2,41.3 94.2,54.65 94.25,54.7 97.65,54.7
USB2_HUB_V5 on BOTTOM: 123.47,53.16 123.47,51.75 123.67,51.55 123.67,49.9 123.77,49.8 124.51,49.8 124.73,50.01 124.73,52.92 124.37,53.28 123.59,53.28
USB2_VBUS1 on BOTTOM (solid shape): outline of 115 points within 189.42,59.51 191.32,60.91
USB2_VBUS1 on BOTTOM: 136.25,76.52 136.25,78.72 136.35,78.82 140.2,78.82 140.25,78.77 140.25,77.92 140.15,77.82 137.35,77.82 137.25,77.72 137.25,76.57 137.15,76.47 136.3,76.47
USB2_VBUS1 on BOTTOM: 176.65,63.42 174,63.42 172.45,64.97 169.35,64.97 169.25,64.87 169.25,57.17 169.5,56.92 170.5,56.92 170.65,57.07 170.65,60.97 170.8,61.12 172.1,61.12 173.35,62.37 176.65,62.37 176.75,62.47 176.75,63.32
USB2_VBUS1 on L3: 191.05,61.22 191.05,59.17 190.35,58.47 184.6,58.47 183.35,57.22 180.3,57.22 178.85,58.67 177.25,58.67 176.05,59.87 176.05,63.37 176.1,63.42 177.3,63.42 177.5,63.22 177.5,60.72 178.3,59.92 179.75,59.92 180.8,58.87 182.05,58.87 184.15,60.97 185.8,60.97 186.2,61.37 190.9,61.37
USB2_VBUS1 on L6: 139.35,78.82 139.35,78.32 140.7,76.97 140.7,56.27 141,55.97 141.8,55.97 141.9,56.07 141.9,77.52 140.55,78.87 139.4,78.87
USB2_VBUS2 on BOTTOM: 131.95,76.57 131.95,80.07 132.25,80.37 141.5,80.37 141.7,80.17 141.7,79.22 141.6,79.12 133.75,79.12 132.85,78.22 132.85,76.57 132.8,76.52 132,76.52
USB2_VBUS2 on BOTTOM: 176.55,61.27 172.65,61.27 172.2,60.82 170.85,60.82 170.8,60.77 170.8,56.57 170.95,56.42 172.55,56.42 172.6,56.47 172.6,57.92 174.8,60.12 176.5,60.12 176.65,60.27 176.65,61.17
USB2_VBUS2 on L6: 140.95,79.92 140.95,78.87 142.15,77.67 142.15,55.07 142.35,54.87 143.25,54.87 143.35,54.97 143.35,78.82 142.15,80.02 141.05,80.02
USB2_VBUS2 on L6: 175.95,61.27 175.95,59.97 177.25,58.67 178.85,58.67 180.3,57.22 183.35,57.22 184.65,58.52 187.65,58.52 187.85,58.72 187.85,61.17 187.65,61.37 186.1,61.37 185.75,61.02 184.25,61.02 181.85,58.62 181.1,58.62 179.8,59.92 178.45,59.92 177,61.37 176.05,61.37
USB2_VBUS3 on BOTTOM (solid shape): outline of 115 points within 189.42,37.55 191.32,38.95
USB2_VBUS3 on BOTTOM: 137.05,66.17 137.05,68.52 136.95,68.62 135.7,68.62 135.6,68.52 135.6,66.27 135.75,66.12 137,66.12
USB2_VBUS3 on BOTTOM: 176.8,42.07 176.8,41.12 176.65,40.97 174.4,40.97 173.6,40.17 170.6,40.17 170.2,39.77 170.2,35.87 170.05,35.72 168.5,35.72 168.3,35.92 168.3,42.32 170.05,44.07 172.65,44.07 174.6,42.12 176.75,42.12
USB2_VBUS3 on L3: 176.75,42.02 176.75,37.42 177.45,36.72 179,36.72 180.4,35.32 182.9,35.32 184.15,36.57 190.6,36.57 191.1,37.07 191.1,39.07 190.85,39.32 186.15,39.32 185.87,39.04 183.87,39.04 182,37.17 180.45,37.17 179.65,37.97 178.4,37.97 178.05,38.32 178.05,41.97 177.95,42.07 176.8,42.07
USB2_VBUS3 on L6: 136.05,68.52 135.4,68.52 135.3,68.42 135.3,56.17 135.45,56.02 136,56.02 136.15,56.17 136.15,68.42
USB2_VBUS4 on BOTTOM: 131.85,66.22 131.9,66.17 132.55,66.17 132.6,66.22 132.6,68.87 132.55,68.92 131.95,68.92 131.85,68.82
USB2_VBUS4 on BOTTOM: 176.8,39.87 170.65,39.87 170.45,39.67 170.45,35.57 170.6,35.42 171.45,35.42 174.55,38.52 176.8,38.52 176.9,38.62 176.9,39.77
USB2_VBUS4 on L6: 132.05,68.97 132.55,68.97 132.6,68.92 132.6,58.12 132.5,58.02 132.15,58.02 132.05,58.12
USB2_VBUS4 on L6: 176.2,39.62 176.25,39.67 177.75,39.67 177.9,39.52 177.9,38.37 178.35,37.92 179.75,37.92 181,36.67 181.5,36.67 183.85,39.02 185.9,39.02 186.35,39.47 187.6,39.47 187.95,39.12 187.95,36.92 187.7,36.67 184.2,36.67 182.8,35.27 180.4,35.27 178.95,36.72 177.5,36.72 176.2,38.02
USB3_VBUS1 on BOTTOM (solid shape): outline of 115 points within 189.42,81.45 191.32,82.86
USB3_VBUS1 on TOP: 138.59,104.35 138.59,101.48 138.83,101.24 140.02,101.24 140.19,101.41 140.19,104.59 139.99,104.79 139.03,104.79
USB3_VBUS1 on BOTTOM: 173.2,82.22 173.8,82.82 176.6,82.82 176.65,82.77 176.65,82.02 176.55,81.92 175.1,81.92 172.4,79.22 172.4,78.37 172.3,78.27 169.9,78.27 169.85,78.32 169.85,82.02 170.05,82.22
USB3_VBUS1 on L3: 139.27,80 139.27,79.34 139.43,79.17 140.33,79.17 141.59,80.43 148.83,80.43 150.96,78.31 150.96,78.3 151.24,78.02 157.48,78.02 157.76,78.29 169.95,78.29 169.95,79.42 169.9,79.47 163.15,79.47 162.99,79.62 151.4,79.62 149.59,81.42 141.31,81.42 140.06,80.17 139.44,80.17
USB3_VBUS1 on L3: 140.95,101.1 141.14,101.29 141.14,102.03 141.14,102.04 141.14,102.61 140.95,102.8 139.52,102.8 139.34,102.62 139.34,101.21 139.45,101.1
USB3_VBUS1 on L4: 178.02,82.24 178.45,81.82 179.6,81.82 180.92,80.49 181.77,80.49 184.17,82.89 185.75,82.89 186.12,83.27 190.7,83.27 191.15,82.82 191.15,80.82 190.87,80.54 184.67,80.54 183.12,78.99 180.47,78.99 178.82,80.64 177.52,80.64 176.25,81.92 175.6,81.92 175.5,82.02 175.5,83.12 175.6,83.22 177.07,83.22 178.02,82.27
USB3_VBUS1 on L6: 140.08,101.79 140.08,97.81 139.17,96.9 139.17,90.78 138.81,90.41 138.81,79.74 139.37,79.18 139.94,79.18 140.14,79.38 140.14,80.19 139.54,80.78 139.54,81.45 139.56,81.47 139.56,90.01 140.22,90.67 140.22,96.3 141.13,97.22 141.13,101.78 140.95,101.96 140.24,101.96
USB3_VBUS2 on TOP: 162.59,119.01 159.49,119.01 159.31,119.19 159.31,120.19 159.44,120.32 162.53,120.32 162.66,120.19 162.66,119.08
USB3_VBUS2 on BOTTOM: 170.9,86.17 172.8,86.17 174.05,84.92 176.55,84.92 176.65,84.82 176.65,84.07 176.55,83.97 173.85,83.97 172.3,82.42 169.95,82.42 169.6,82.07 169.6,79.77 169.5,79.67 168.3,79.67 168.2,79.77 168.2,83.47
USB3_VBUS2 on L3: 178.02,82.24 178.45,81.82 179.6,81.82 180.92,80.49 181.77,80.49 184.17,82.89 185.75,82.89 186.12,83.27 187.8,83.27 188.02,83.04 188.02,80.99 187.57,80.54 184.67,80.54 183.12,78.99 180.47,78.99 178.82,80.64 177.52,80.64 176.25,81.92 176.25,83.22 175.57,83.89 175.57,84.84 175.8,85.07 177.1,85.07 177.7,84.47 177.7,82.59 178.02,82.27
USB3_VBUS2 on L3: 163.65,79.67 169.41,79.67 169.42,79.69 169.82,79.69 169.9,79.77 169.9,80.67 169.82,80.74 163.6,80.74 163.55,80.69 163.55,79.77
USB3_VBUS2 on L3: 159.51,119.24 159.51,118.95 160.32,118.14 164.48,118.14 164.67,118.34 164.67,119.05 164.35,119.36 159.64,119.36
USB3_VBUS2 on L6: 163.7,79.62 164.62,79.62 164.75,79.75 164.75,90.49 164.84,90.58 164.84,109.37 164.51,109.7 164.51,117.85 164.8,118.14 164.8,119.1 164.7,119.21 163.73,119.21 163.38,118.85 163.38,100.21 163.42,100.17 163.42,100.15 163.5,100.07 163.5,79.82
USB3_VBUS3 on BOTTOM (solid shape): outline of 115 points within 189.42,103.41 191.32,104.81
USB3_VBUS3 on TOP: 145.15,112.11 145.15,113.41 145.25,113.51 148.35,113.51 148.55,113.31 148.55,112.12 148.41,111.98 145.29,111.98
USB3_VBUS3 on BOTTOM: 172.55,104.07 173.35,104.87 176.25,104.87 176.45,104.67 176.45,103.92 176.35,103.82 175.1,103.82 172.6,101.32 172.6,99.82 172.35,99.57 170.15,99.57 170,99.72 170,103.92 170.15,104.07
USB3_VBUS3 on L3: 142.41,101.63 142.41,100.16 143.09,99.47 154.91,99.47 155.15,99.71 162.79,99.71 163.47,99.03 170.7,99.03 171.05,99.38 171.05,100.88 170.9,101.03 169.83,101.03 169.33,100.52 165.63,100.52 165.14,101.01 152.33,101.01 151.8,100.48 143.96,100.48 143.57,100.86 143.57,101.5 143.36,101.72 142.49,101.72
USB3_VBUS3 on L3: 145.84,112.95 142.75,112.95 142.55,112.75 142.55,112.15 142.79,111.91 145.83,111.91 146.03,112.11 146.03,112.76
USB3_VBUS3 on L4: 175.35,104.97 177.15,104.97 178.5,103.62 179.65,103.62 180.7,102.57 181.55,102.57 183.95,104.97 185.85,104.97 186.15,105.27 186.15,105.42 187.7,105.42 188.1,105.02 189.2,105.02 189.6,105.42 190.65,105.42 190.9,105.17 190.9,102.87 190.65,102.62 184.45,102.62 182.9,101.07 180.25,101.07 178.6,102.72 177.3,102.72 176.25,103.77 175.25,103.77 175.2,103.82 175.2,104.82
USB3_VBUS3 on L6: 142.32,112.93 142.32,101.01 142.7,100.62 143.24,100.62 143.47,100.85 143.47,112.9 143.35,113.02 142.41,113.02
USB3_VBUS3 on L6: 170.1,99.67 171.05,99.67 171.15,99.77 171.15,100.62 171.05,100.72 170.1,100.72 170.05,100.67 170.05,99.72
USB3_VBUS4 on TOP: 150.04,106.2 150.11,106.13 151.18,106.13 151.43,106.38 151.43,109.42 151.42,109.42 151.42,109.59 151.35,109.66 150.14,109.66 150.04,109.56
USB3_VBUS4 on BOTTOM: 173.05,108.17 174.35,106.87 176.45,106.87 176.5,106.82 176.5,105.92 176.4,105.82 173.4,105.82 172.25,104.67 170.15,104.67 169.8,104.32 169.8,101.57 169.65,101.42 168.45,101.42 168.35,101.52 168.35,107.87 168.65,108.17
USB3_VBUS4 on L3: 150.25,108.76 150.76,108.76 150.89,108.9 150.89,109.68 150.31,110.26 144.47,110.26 143.74,109.54 143.74,108.61 143.92,108.42 144.91,108.42 145.67,109.18 149.83,109.18
USB3_VBUS4 on L3: 177.15,104.97 178.5,103.62 179.65,103.62 180.7,102.57 181.55,102.57 183.95,104.97 185.85,104.97 186.15,105.27 186.15,105.42 187.45,105.42 187.8,105.07 187.8,103.07 187.35,102.62 184.45,102.62 182.9,101.07 180.25,101.07 178.6,102.72 177.3,102.72 175.9,104.12 175.9,104.82 175.35,105.37 175.35,106.52 175.45,106.62 177.05,106.62 177.15,106.52
USB3_VBUS4 on L3: 143.64,102 143.64,101.08 144.13,100.59 151.58,100.59 152.16,101.16 170.49,101.16 170.65,101.32 170.65,102.27 170.59,102.33 170.16,102.33 170.15,102.34 151.92,102.34 151.27,101.68 145.18,101.68 144.67,102.19 143.83,102.19
USB3_VBUS4 on L6: 170.13,102.25 170.12,102.27 169.17,102.27 169.12,102.22 169.12,101.52 169.17,101.47 170.6,101.47 170.75,101.62 170.75,102.17 170.66,102.25
USB3_VBUS4 on L6: 143.81,109.44 143.58,109.21 143.58,101.31 143.89,101 144.58,101 144.76,101.19 144.76,102.02 144.46,102.32 144.46,107.92 144.94,108.4 144.94,109.35 144.86,109.44
V_3P3_PER_VCC on BOTTOM: 94.06,73.01 94.06,72.36 94.16,72.26 98.61,72.26 98.71,72.36 98.71,73.06 98.66,73.11 94.16,73.11
V_5P0_SW1 on BOTTOM: 102.3,63.2 102.35,63.25 102.35,63.75 102.55,63.95 107.45,63.95 107.68,64.18 107.68,70.2 107.48,70.4 99.25,70.4 99.05,70.2 99.05,63.75 99.6,63.2
V_SW_CAM_7P0 on BOTTOM: 77.68,56.68 80.08,56.68 80.23,56.83 80.23,57.77 84.1,61.64 84.11,61.64 84.11,69.31 82.97,70.44 77.52,70.44 77.12,70.05 77.12,68.23 77.22,68.13 77.22,65.42 74.39,62.6 74.39,58.81 74.61,58.6 75.76,58.6
VDCIN_9_30V on TOP: 121.57,28.4 109.45,28.4 109.12,28.06 109.12,25.53 110.5,24.14 121.79,24.14 121.93,24.28 121.93,28.03
VDCIN_9_30V on BOTTOM: 125.25,25.7 125.25,29.7 125.15,29.8 121.25,29.8 118.88,27.43 118.88,24.45 118.97,24.35 123.9,24.35
VL_VCC10I on TOP: 143.29,87.81 143.26,87.84 140.01,87.84 138.55,86.38 138.55,85.52 138.65,85.42 144.35,85.42 144.45,85.52 144.45,87.72 144.35,87.81
VL_VCC10I_F on TOP: 145.08,86.54 145.08,85.75 145.16,85.67 145.78,85.67 145.97,85.86 147.4,85.86 147.98,86.45 148.96,86.45 149.03,86.52 149.03,87.13 148.95,87.21 148.14,87.21 148.1,87.25 145.8,87.25
VL_VCC10I_F on L3: 148.79,86.6 148.7,86.69 148.7,87.45 148.8,87.55 156.45,87.55 157.35,88.45 157.35,91.1 156.4,92.05 152.35,92.05 152.15,92.25 152.15,93.2 152.25,93.3 156.71,93.3 158.8,91.21 158.8,87.3 158.45,86.95 157.9,86.95 157.55,86.6
VL_VCC33I on TOP: 163.44,79.74 162.77,79.74 162.57,79.53 162.02,79.53 161.97,79.59 161.97,80.98 162.11,81.13 162.85,81.13 163.56,80.42 163.56,79.86
VL_VCC33I on TOP: 140.18,94.79 141.88,94.79 142.45,95.36 142.45,98.23 141.94,98.74 140.33,98.74 140.11,98.51 140.11,94.87
VL_VCC33I on TOP: 145.97,83.37 145.97,82.29 145.15,81.47 145.15,80.67 145.25,80.57 146.13,80.57 146.23,80.67 146.23,81.57 146.88,82.22 146.88,83.36 146.81,83.43 146.03,83.43
VL_VCC33I on L3: 141.3,95.72 142.1,95.72 142.15,95.67 142.15,94.62 142.05,94.52 141.35,94.52 141.25,94.62 141.25,95.67
VL_VCC33I on L6: 142.7,81.52 142.7,94.77 142.43,95.03 142.01,95.03 142,95.04 141.75,95.04 141.7,94.99 141.7,81.57 141.85,81.42 142.6,81.42
VL_VCC33I_F on TOP: 147.49,83.5 147.49,82.57 147.55,82.51 148.79,82.51 148.94,82.66 148.94,83.41 148.79,83.56 147.55,83.56
VL_VCC33I_F on L3: 148.54,83.26 148.54,82.61 148.64,82.51 152.96,82.51 153.42,82.97 153.42,86.38 153.33,86.47 152.71,86.47 152.62,86.38 152.62,83.62 152.34,83.34 148.62,83.34
VL_VDD on TOP: 147.17,88.48 147.23,88.54 147.23,89.57 147.14,89.65 143.68,89.65 143.55,89.52 143.55,88.57 143.63,88.48
VL_VDD on L3: 149.9,89.2 149.95,89.25 149.95,89.75 149.85,89.85 146.6,89.85 146.55,89.8 146.55,89.3 146.65,89.2
VREG_1P0 on BOTTOM: 50.75,91.57 52.8,91.57 52.9,91.47 52.9,89.87 52.8,89.77 50.9,89.77 50.75,89.92
VREG_1P0 on BOTTOM: 52.53,64.52 52.88,64.87 52.88,67.5 55.2,69.82 55.2,70.07 54.4,70.87 54.05,70.87 49.75,66.57 47.88,66.57 47.4,66.09 47.4,63.72 44.5,60.82 44.5,60.52 44.9,60.12 46.5,60.12 49.15,62.77 49.15,64.42 49.25,64.52
VREG_1P0 on L7: 52.25,90.67 53.8,90.67 54,90.47 54,74.72 55,73.72 55,70.22 54.9,70.12 53.95,70.12 53.8,70.27 53.8,73.07 52.65,74.22 52.65,89.32 52.2,89.77 52.2,90.62
